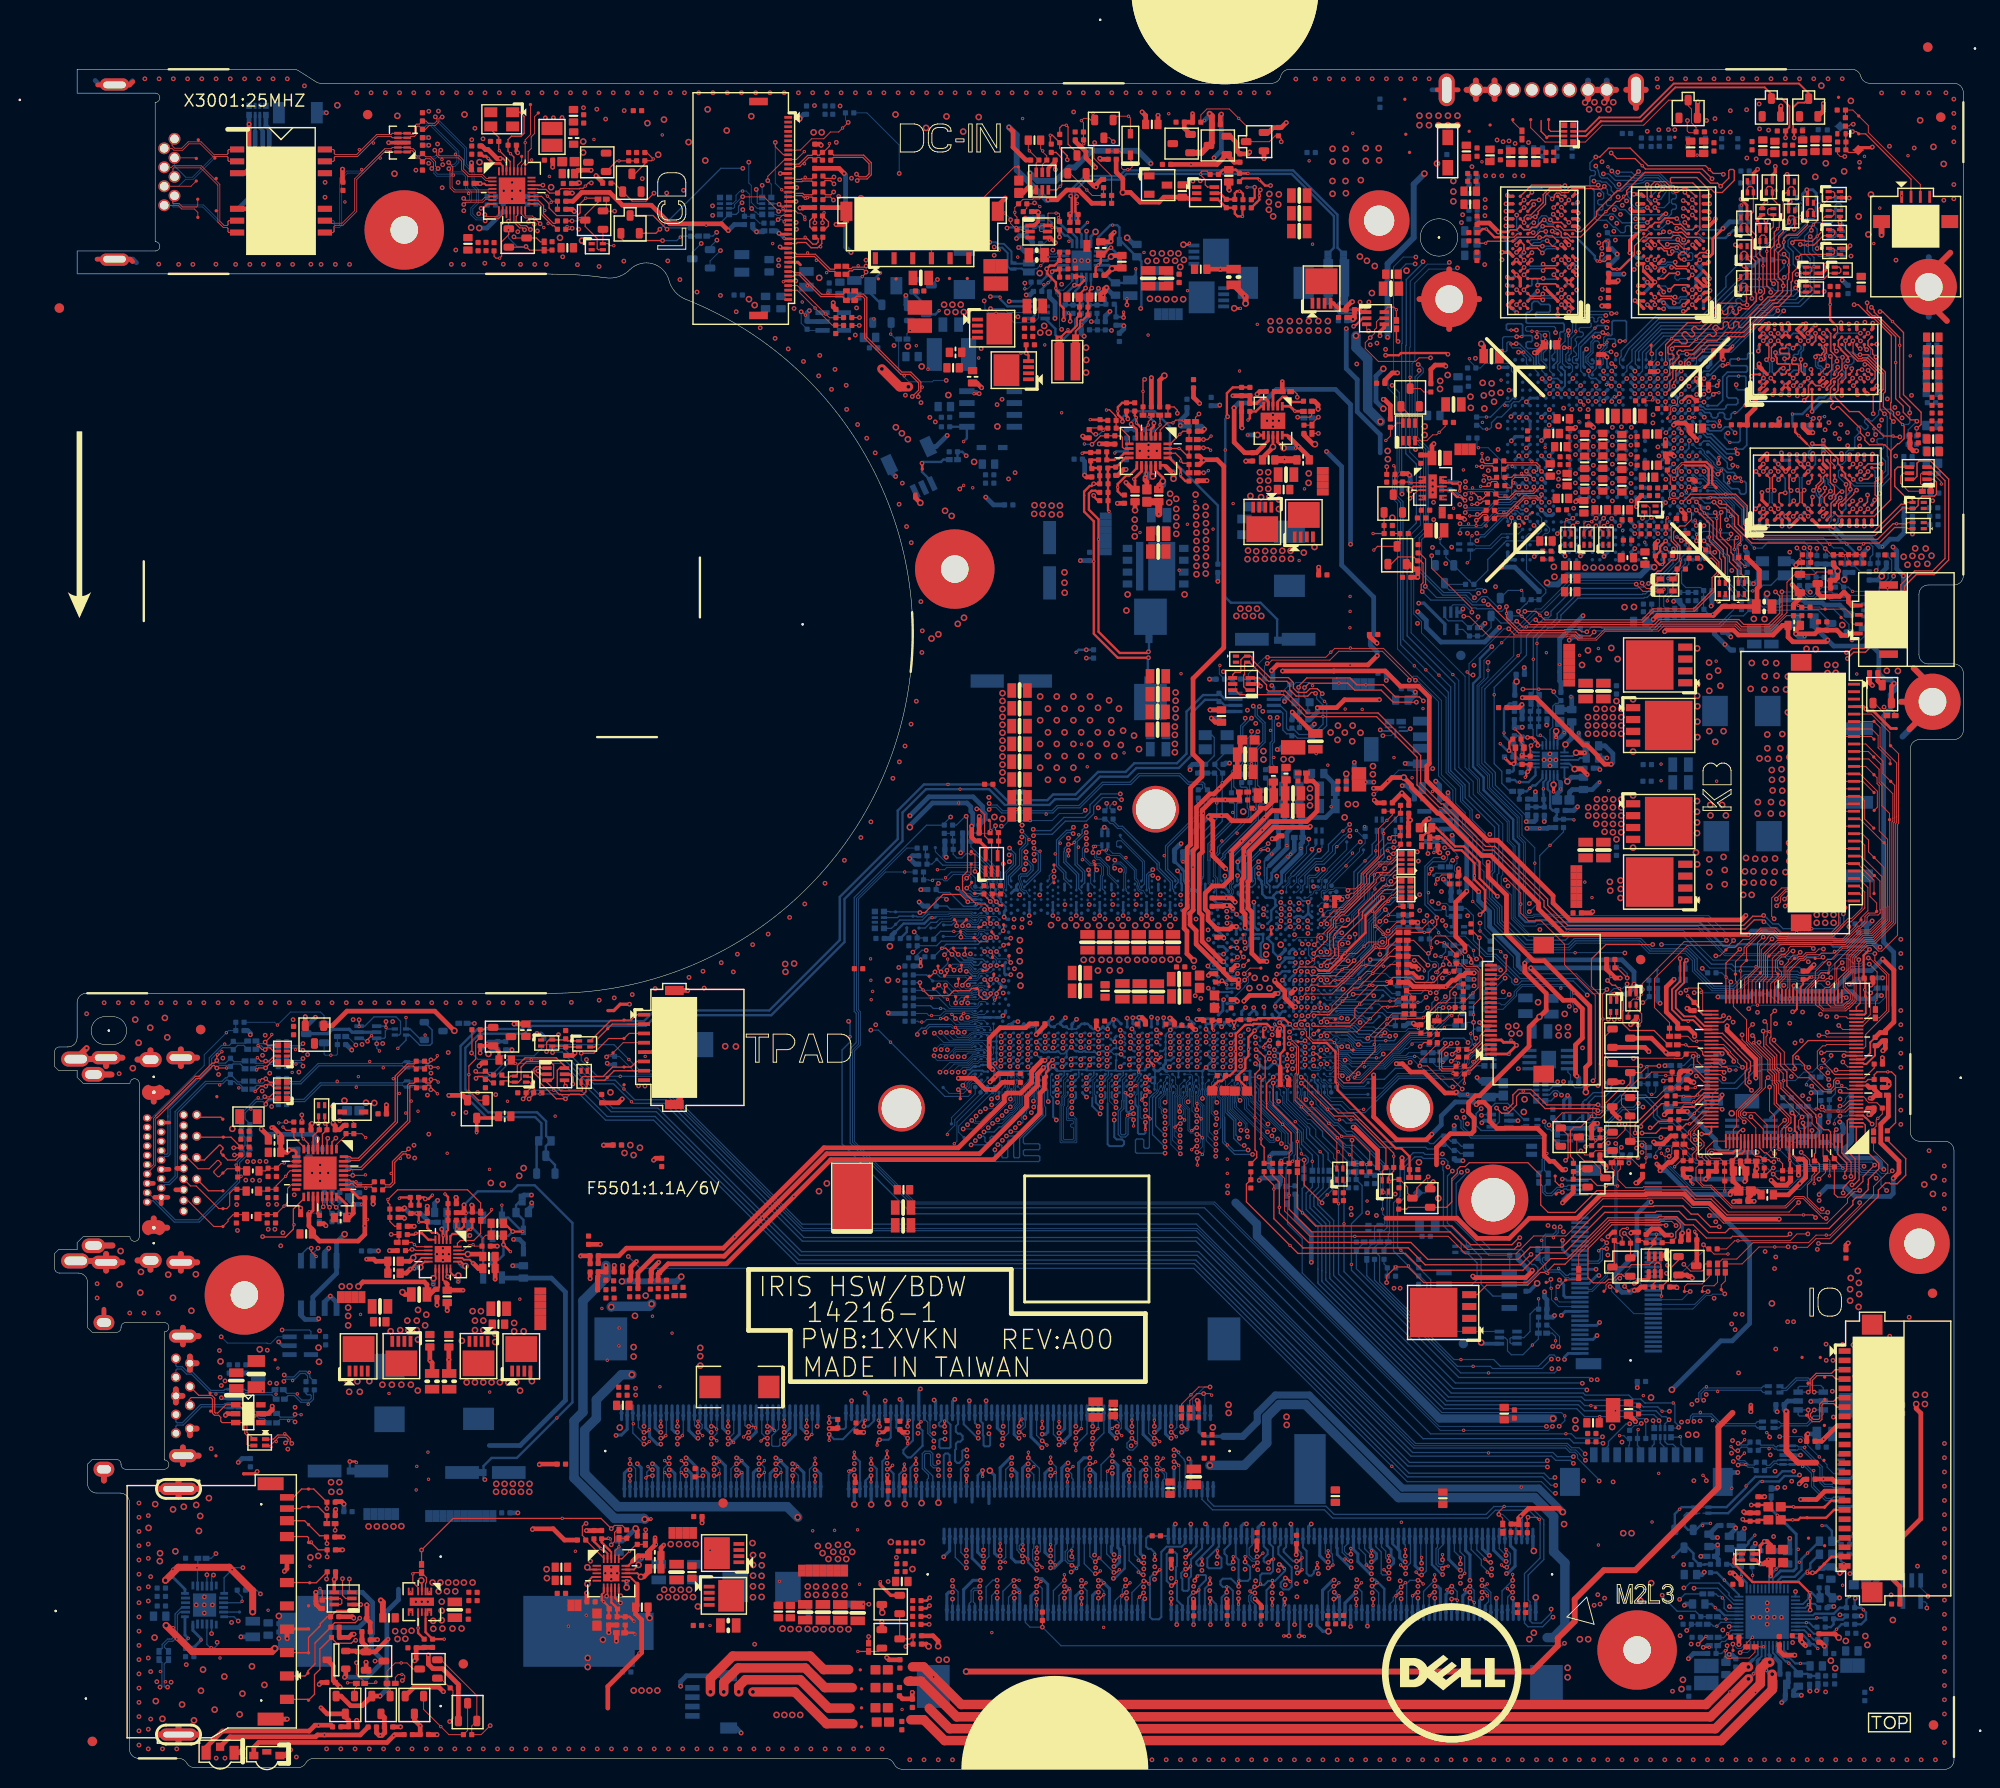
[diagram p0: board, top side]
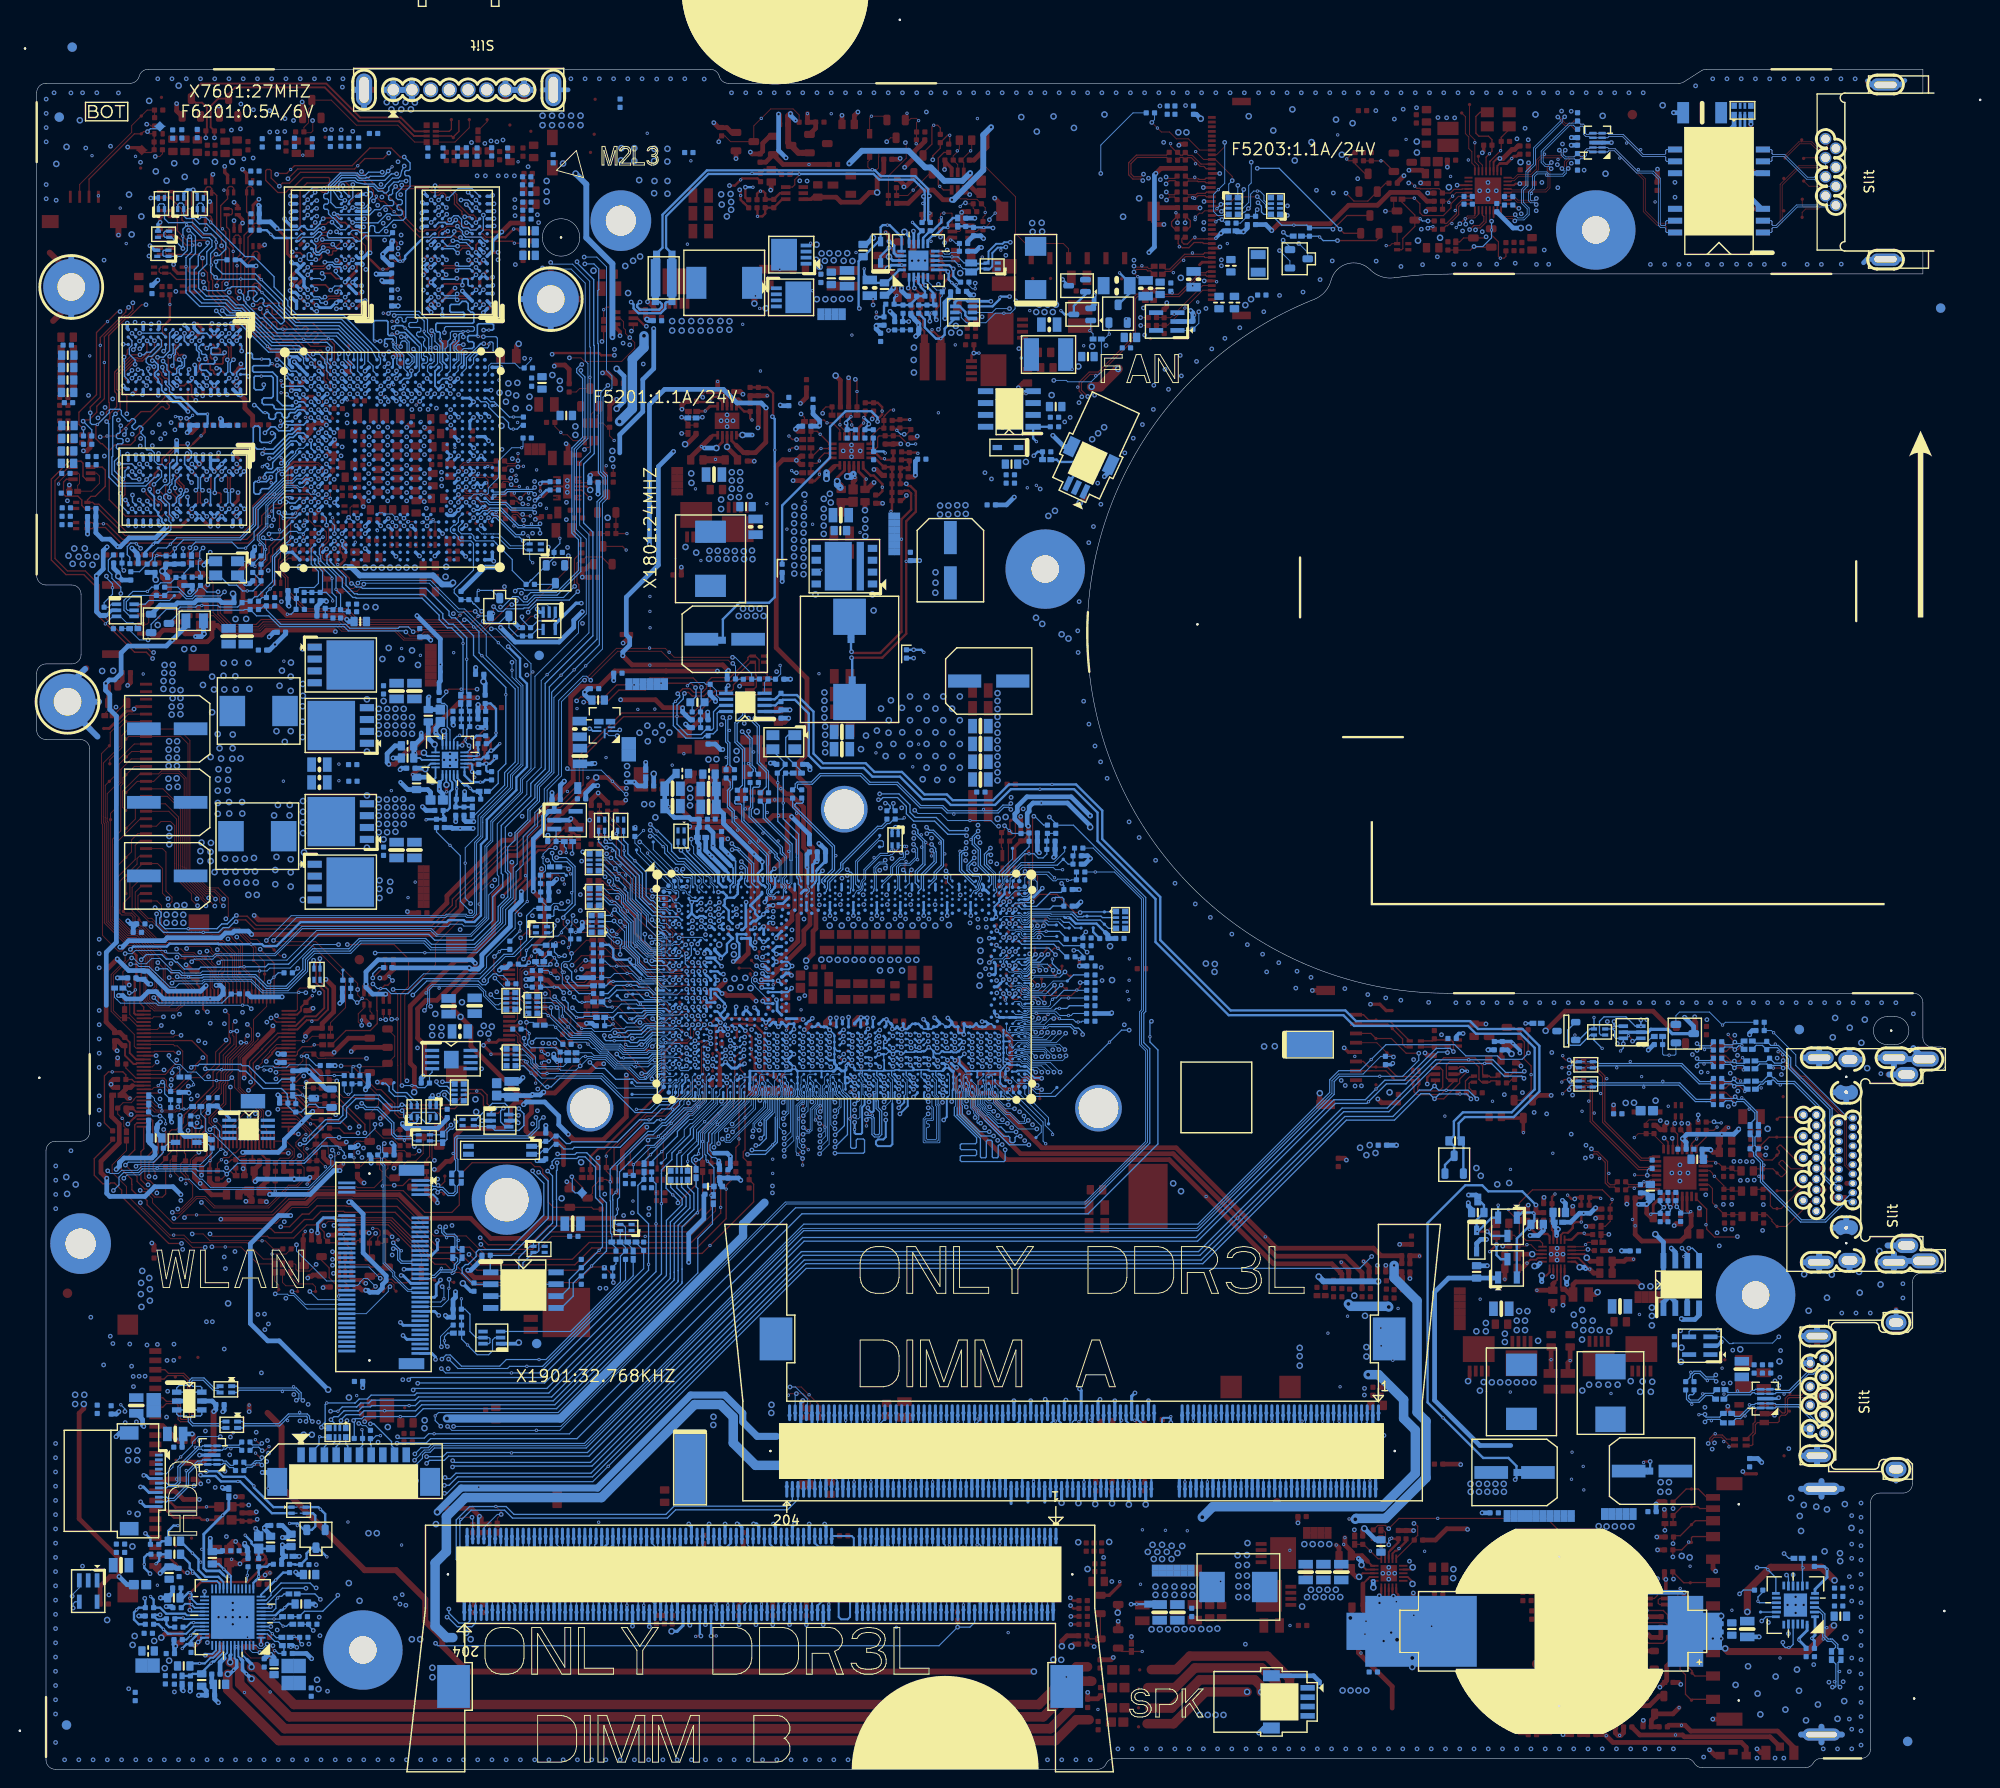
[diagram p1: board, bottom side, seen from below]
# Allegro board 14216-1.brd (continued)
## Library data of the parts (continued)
PR4205 PR4206 R1806 R2419 R2420 R2422 R2423 R5205 R5207 R5215 = R402H16: tolerance: 63.33034.1DL
PR4207 = R603H22: tolerance: 63.24434.15L
PR4208 = R603H22: tolerance: 63.47333.15L
PR4209 PR4403 PR4417 PR4419 PR4428 PR4430 PR4434 PR4438 PR4469 PR4474 PR4534 PR8203 PR8310 PR8311 PR8313 PR8314 R1509 R1715 R1727 R2007 R2412 R2413 R2421 R2426 R2442 R2447 R2711 R2722 R3023 R3607 R5202 R5218 R5219 R5413 R5510 R5607 R6207 R6208 R7605 R7610 R8301 = R402H16: tolerance: 63.10434.1DL
PR4210 PR4418 PR4426 PR4504 PR4506 PR4507 PR4532 PR4621 PR4624 PR4628 PR4819 PR4821 PR4906 PR4907 PR4909 PR5110 PR8207 PR8220 PR8221 PR8257 R404 R1201 R1202 R1205 R1301 R1704 R1706-R1709 R1713 R1728 R1801 R1807-R1812 R1904 R2001 R2002 R2004 R2009 R2016 R2017 R2020 R2022 R2028 R2029 R2101 R2103 R2105 R2112 R2117 R2118 R2401 R2408-R2410 R2416 R2417 R2427 R2428 R2430 R2435 R2440 R2441 R2444 R2606 R2611 R2612 R2701 R2705 R2708 R2712 R2714 R2716 R3005 R3016 R3609-R3611 R3705 R4301 R5201 R5206 R5419 R5605 R5803-R5805 R5807 R6104 R6105 R6202 R6216 R7624 R7652 R7653 = 0R0402-PAD: tolerance: ZZ.R0402.ZZZ
PR4214 = R1206H28: tolerance: 63.33232.11L
PR4217 PR4701 PR4911 PR8210 PR8211 R711 R1102-R1104 R2102 R2108 R2402 R2703 R2901-R2904 R2906 R2907 R2909 R2911 R2923 R3006 R5409 = 0R0603-PAD-U: tolerance: ZZ.R0603.001
PR4401 PR4435 PR4439 PR4473 PR4523 PR4822 PR4903 R2404 R7302 R7508-R7512 R7614 R7618 R7620 = R402H16: tolerance: 64.10025.6DL
PR4402 PR4416 = R3720H40: tolerance: 64.R0105.7FL
PR4404 = R805H24: tolerance: 63.30231.16L
PR4405 = R402H16: tolerance: 63.47434.1DL
PR4406 PR4422 PR4448 PR4452 PR4465 PR4466 PR4468 PR4471 PR4475 PR4476 PR4501 PR4525 PR4530 PR4535 PR4606 PR4706 PR4910 PR8208 R411 R1705 R1710 R1718 R1729 R1813 R2019 R2021 R2027 R2030 R2031 R2123 R2405 R2411 R2424 R2434 R2437 R2438 R2448 R2450 R2451 R2601 R2602 R2605 R2710 R3501 R3704 R3710 R3712 R3802 R5209 R5222 R5418 R5517 R5602 R5806 R5810 R6106 R6204 R6210 R6215 R6217 R6301 R6302 R6501 R6502 R7304 R7305 R7308 R7313 R7519 R7623 R7629 R7630 R7636 R8303 R8312 R8313 R8315 R9602-R9605 = R402H16: tolerance: 63.R0034.1DL
PR4407 PR4429 = R402H16: tolerance: 64.30935.6DL
PR4408 = R805H24: tolerance: 63.10031.16L
PR4410 = R402H16: tolerance: 64.6R805.6DL
PR4411 = R402H16: tolerance: 64.10235.6DL
PR4413 = R402H16: tolerance: 64.16935.6DL
PR4414 = R402H16: tolerance: 63.33534.1DL
PR4420 = R402H16: tolerance: 64.7R505.6DL
PR4421 PR4454 PR4604 R2908 R2910 = R402H14: tolerance: 64.10R05.6DL
PR4423 = R402H16: tolerance: 64.59025.6DL
PR4424 = R402H16: tolerance: 64.84515.6DL
PR4425 PR4529 PR4533 PR4837 PR4912 PR8215 PR8216 = R805H24: tolerance: 64.2R205.16L
PR4427 = R402H16: tolerance: 64.78725.6DL
PR4431 R709 R712 = R402H16: tolerance: 64.47025.6DL
PR4432 PR4436 = R402H16: tolerance: 64.12035.6DL
PR4437 = R402H16: tolerance: 64.16035.6DL
PR4446 PR4904 R2433 R2707 R6214 R7616 = R402H16: tolerance: 64.20025.6DL
PR4464 = R402H16: tolerance: 63.68434.1DL
PR4467 PR8312 R1802 R1901 R7603 R8305 = R402H16: tolerance: 63.10534.1DL
PR4470 PR4472 PR4610 R707 R713 R1725 R2406 R2407 R7306 = R402H16: tolerance: 64.10035.6DL
PR4512 = R402H16: tolerance: 64.68015.6DL
PR4517 = R402H16: tolerance: 64.88725.6DL
PR4524 PR4528 = R603H22: tolerance: 63.1R534.15L
PR4526 = R402H16: tolerance: 64.97615.6DL
PR4527 = R402H16: tolerance: 64.15425.6DL
PR4531 = R402H16: tolerance: 64.11535.6DL
PR4601 R703 R5501 R5513 R5514 = R402H16: tolerance: 64.75R05.6DL
PR4602 = R402H16: tolerance: 64.49905.6DL
PR4603 = R402H16: tolerance: 64.12715.6DL; signal model: R402H16_1K27R2F-L-GP
PR4607 = R402H16: tolerance: 64.12435.6DL
PR4613 = R402H16: tolerance: 64.51015.6DL
PR4614 = R402H16: tolerance: 64.90925.6DL
PR4615 = R402H16: tolerance: 64.38315.6DL
PR4616 PR4618 PR4619 R1908 R1911 R2718-R2720 R3202 R3204 R3205 R3301 R3408-R3411 R5203 R5204 R5216 R5217 R5401-R5408 R5801 R5802 R5808 R5811 = 0R0402-PAD: tolerance: ZZ.R0402.ZZZ; signal model: R402H16_0R2J-2-GP
PR4620 = R402H16: tolerance: 64.54R95.6DL
PR4622 = NTC-402H22-U: tolerance: 69.60037.001
PR4630 R704 = R402H16: tolerance: 64.13005.6DL
PR4702 = R402H16: tolerance: 64.36515.6DL
PR4703 = R402H16: tolerance: 64.44215.6DL
PR4704 = NTC-402H22-U: tolerance: 69.60037.011
PR4705 = R402H16: tolerance: 64.34005.6DL
PR4707 = R402H16: tolerance: 64.10055.6DL
PR4708 = R402H16: tolerance: 64.11025.6DL
PR4817 PR4902 = R402H16: tolerance: 64.13335.6DL
PR4820 PR4905 R2403 = R603H22: tolerance: 64.2R205.55L
PR4823 = R402H16: tolerance: 64.21025.6DL
PR4824 = R402H16: tolerance: 64.47035.6DL
PR4901 = R402H16: tolerance: 64.31625.6DL
PR4908 = R402H16: tolerance: 64.10015.6DL
PR8201 = R402H16: tolerance: 64.49935.6DL
PR8202 = R402H16: tolerance: 64.2R205.6DL
PR8206 = R402H16: tolerance: 64.75015.6DL
PR8209 = R402H16: tolerance: 64.78715.6DL
PR8212 PR8213 R409 R702 R901 = R402H14: tolerance: 64.10005.6DL
PR8222 = R402H16: tolerance: 64.27025.6DL
PR8223 = R603H22: tolerance: 63.2R233.15L
PR8224 = R402H16: tolerance: 64.10725.6DL
PR8256 PR8301 R604 R605 R1702 R1703 R1814 R1815 R1909 R1919 R2006 R2011 R2012 R2014 R2018 R2432 R2449 R2452 R2453 R2502 R2717 R2921 R2922 R3014 R3601 R3603 R3608 R6201 R9601 = R402H16: tolerance: 63.10234.1DL
PR8260 = R402H16: tolerance: 64.13025.6DL
PR8315-PR8317 = R402H14: tolerance: 63.10034.1DL
PT4501 PT4502 = SE361414H178: tolerance: 79.22710.3KL
PT4701 = SE361416H178: tolerance: 77.53371.18L
PT4702 = SE361413H182: tolerance: 79.33612.6CL
PT4803 PT8206-PT8208 = SE361414H178: tolerance: 79.3371V.6CL
PU4201 PU4402 PU4403 = PPAK-8P-2H45: tolerance: 84.07121.037
PU4401 = QFN20G3D5-G2D15H40: tolerance: 74.02224.073
PU4405 PU4406 PU4501 PU4504 PU4505 PU4805 PU4808 PU4902 = PPAK-8P-2H45: tolerance: 84.00412.037
PU4407 = SC70-6H44: tolerance: 74.00199.07P
PU4502 PU4903 = PPAK-8P-2H45: tolerance: 84.00780.037
PU4503 = QFN20-G1D75H32: tolerance: 74.51225.073
PU4601 = QFN20G4030-G275175H40: tolerance: 74.95813.B73
PU4701 = PPAK-8P-G5324H44-COLAY: tolerance: ZZ.00215.037
PU4806 = DFN10G3-G265175H32: tolerance: 74.08237.B73
PU4901 = QFN20-G1D75H32: tolerance: 74.51716.073
PU5101 = SOT-23-5H52: tolerance: 74.01339.B3F
PU8201 = QFN20-G1D75H32: tolerance: 74.08812.073
PU8202 PU8204 PU8206 PU8208 = PPAK-5PH45: tolerance: 84.A14DP.037
PU8203 PU8205 PU8207 PU8209 = PPAK-5PH45: tolerance: 84.SRA12.037
PWR1 = 6916K-Q04M-00L: tolerance: 20.K0465.004
Q2402 Q3004 Q6203 Q8302 = SOT23DGS2D4H48: tolerance: 84.02130.031
Q3602 = SOT23CBE2D4H44: tolerance: 84.02222.V11
Q5402 = SOT-363H44: tolerance: 84.2N702.A3F; signal model: SOT-363H44_2N7002KDW-GP
Q6101 Q6102 Q6104 Q6201 = SOT23CBE2D4H44: tolerance: 84.00144.N11
Q6202 = SOT23DGS2D4H48: tolerance: 84.03404.C31
R401 = R402H16: tolerance: 63.62034.1DL
R402 R406 R1916-R1918 R1920 = R402H16: tolerance: 63.51034.1DL
R403 = R402H16: tolerance: 63.56034.1DL
R407 R7307 = R402H16: tolerance: 64.20005.6DL
R408 = R402H16: tolerance: 64.12105.6DL
R410 R6103 = R402H16: tolerance: 63.47134.1DL
R601 R602 R606 R2003 = R402H16: tolerance: 64.49R95.6DL
R603 R1714 = R402H16: tolerance: 64.82015.6DL
R701 = R402H16: tolerance: 63.43034.1DL; signal model: R402H16_43R2J-GP
R705 R5414-R5417 = R402H16: tolerance: 63.15134.1DL
R801 R3707 R3711 R3715 = R402H16: tolerance: 64.24R95.6DL
R1204 = R402H16: tolerance: 63.20534.1DL
R1206 R1207 R1209 R1210 = R402H16: tolerance: 64.66R55.6DL
R1208 R8314 = R402H16: tolerance: 63.22434.1DL
R1601 R1803 R1906 = R402H16: tolerance: 64.30015.6DL
R1602 = R402H16: tolerance: 64.22R65.6DL
R1720 R1721 R1903 R1913 R2425 R2431 = R402H16: tolerance: 63.33434.1DL
R1804 R1805 R1907 R1912 R3201 R5507 R5511 = R402H16: tolerance: 63.33034.1DL; signal model: R402H16_33R2J-2-GP
R1915 R2504 = R402H16: tolerance: 63.10634.1DL
R2110 = R402H16: tolerance: 64.5R105.6DL
R2114 R5211 R5214 R5229 R5603 R8304 = R805H24: tolerance: 63.R0031.16L
R2429 = R402H16: tolerance: 63.43034.1DL
R2446 = R402H16: tolerance: 64.64925.6DL
R2501 R2912 R2913 R3606 R5502 R5508 R5509 R5512 R5515 R5516 R6209 = R402H16: tolerance: 63.47234.1DL
R2603 = R402H16: tolerance: 64.18725.6DL
R2604 R2607 R4622 = R402H16: tolerance: 64.20015.6DL
R2608 R2609 R7639 = R402H16: tolerance: 64.24925.6DL
R2610 = NTC-603H38: tolerance: 69.60035.041
R2709 R3602 R5410 = R402H16: tolerance: 64.20035.6DL
R3015 = R402H16: tolerance: 63.15334.1DL
R3022 = R402H16: tolerance: 63.20334.1DL
R3032 R7301 = R402H16: tolerance: 64.24915.6DL
R3203 = R402H16: tolerance: 64.62015.6DL
R3701 R3703 R3706 R3709 R3714 R3716 = R402H16: tolerance: 64.18015.6DL
R3702 R3708 R3713 = R402H16: tolerance: 64.2R005.6DL
R5210 R5212 R5213 R6102 R6109 = R402H14: tolerance: 63.10134.1DL
R5411 = R402H16: tolerance: 64.15035.6DL
R5505 = R402H16: tolerance: 64.12025.6DL
R6107 R6108 = R402H16: tolerance: 63.33134.1DL
R6206 = R402H16: tolerance: 63.51334.1DL
R6211 = R603H22: tolerance: 63.10133.15L
R7501 R7503 = R402H16: tolerance: 64.60R45.6DL
R7505 = R402H16: tolerance: 64.40R25.6DL
R7506 = R402H16: tolerance: 64.51R15.6DL
R7507 = R402H16: tolerance: 64.42R25.6DL
R7604 = R402H16: tolerance: 63.13234.1DL
R7607 = R402H16: tolerance: 64.40225.6DL
R7608 R7611 R7640 R7650 = R402H16: tolerance: 64.49915.6DL
R7619 R7647 = R402H16: tolerance: 64.34825.6DL
R7638 R7642 = R402H16: tolerance: 64.30125.6DL
R7646 R7654 R7655 = R402H16: tolerance: 64.45325.6DL
R7806 R7807 R7903 R7904 = R402H16: tolerance: 64.13315.6DL
R7808 R7809 R7912 R7913 R8001 R8002 R8101 R8102 = R402H16: tolerance: 64.24305.6DL
R7810 R7914 = R402H16: tolerance: 64.16205.6DL
RJ45 = C100PF-10809-L: tolerance: 022.10001.0C41
RN401 = ARES8-CN24H22: tolerance: 66.51036.A8L
RN1501 RN1811 RN2008 RN2602 RN2901 RN5401 RN5501 RN6204 RN7603-RN7605 = ARES2H16: tolerance: 66.22236.04L
RN1503 RN1701 RN1703 RN1803 RN1804 RN1810 RN2006 RN2007 RN3001 RN6201 RN7401-RN7404 RN7602 = ARES2H18: tolerance: 66.10336.04L
RN1505 RN1601 RN1801 RN1809 RN1902 RN2002 RN2011 RN2012 = ARES8-CN24-MUH20: tolerance: 66.10336.08L
RN1702 RN9601 = SMD-ARES4H20: tolerance: 66.R0036.04L
RN1806 RN6501 = ARES8-CN24H22: tolerance: 66.R0036.A8L
RN1807 = ARES8-CN24-UH20: tolerance: 66.22236.A8L
RN1901 = SMD-ARES4H20: tolerance: 66.20336.04L
RN2401 RN2501 RN4401 RN7601 = SMD-ARES4H18: tolerance: 66.47236.04L
RN2701 = 0R4P2R-PAD: tolerance: ZZ.0R04P.ZZZ
RN3101 = ARES8-CN24H22: tolerance: 66.75036.08L
RN4301 RN5201 = ARES8-CN24H20: tolerance: 66.10136.A8L
RN5203 = ARES8-CN24H20: tolerance: 66.10436.A8L
RN5402 RN5403 = ARES8-CN24H20: tolerance: 66.47136.08L
RN5404 RN5405 = 0R4P2R-PAD: tolerance: ZZ.0R04P.ZZZ; signal model: SMD-ARES4H20_SRN0J-6-GP
RN6202 RN6203 = SMD-ARES4H18: tolerance: 66.33036.04L
RN7501-RN7522 = SMD-ARES4H18: tolerance: 66.10136.04L
RTC1 = 060003HA002M213ZL-U2: tolerance: 62.70014.001
SPI25 = SOIC8-1H86: tolerance: 72.25Q64.K01
SPK1 = 50224-0040N-001: tolerance: 20.F1639.004
SPR1 = SPR7345H154: tolerance: 34.49U24.001
SPR2 = SPR5230H134: tolerance: 34.45T31.001
SPR3 = SPR7837H229: tolerance: 34.43E24.001
TC1201 = CT7343H83: tolerance: 79.33719.20L
TC3501 = C1206H71: tolerance: 78.10710.52L
THM26 = MSOP8-1H44: tolerance: 74.07718.0B9
TP402 TP403 TP501 TP503 TP601-TP608 TP619 TP620 TP701-TP705 TP801 TP1501 TP1601 TP1602 TP1702-TP1707 TP1801-TP1803 TP1901 TP1902 TP2002 TP2003 TP2101-TP2109 TP2201-TP2208 TP2702 TP3001-TP3003 TP3201 TP5801-TP5804 TP7503 TP7504 TP7601-TP7606 TP9601 TP9602 TP9611-TP9624 TP9626-TP9654 = TPAD14-OP: tolerance: ZZ.PAD14.001
TPAD1 = 50505-0084N-002: tolerance: 20.K0667.008
TR3404-TR3406 = L125100-4P-1H28: tolerance: 68.01012.20B
U701 = SC70-5H44: tolerance: 73.01G07.0HG
U2101 = DFN9J2015H32: tolerance: 74.59147.093
U3201 = QFN24-G2D5H40-U: tolerance: 71.05170.003
U3504 U3505 = SOT-23-5H58: tolerance: 074.22802.0A9F
U3601 U8301 = SON14J3020-G2610H32: tolerance: 074.22966.0093
U3801 = MSOP8-1H44: tolerance: 074.06288.0079
U5201 = SOT-23-5H51: tolerance: 74.09724.09F
U5502 = QFN32-G3D6H40: tolerance: 071.02168.0003
U5504 = SOIC8H69: tolerance: 72.24128.J01
U5601 = MSOP8-1G189157H43: tolerance: 74.02001.079
U7301 = SC70-5-1H44: tolerance: 73.01G08.EHG
USB1 = SKT-USB13-160166-2: tolerance: 22.10339.S21
VRAM1-VRAM8 = BGA96D0914H48: tolerance: 72.41K26.00U
WLAN1 = 2199230-7: tolerance: 62.10043.K51
X1801 = OSC-3225-4P-4H36: tolerance: 82.30004.841
X1901 = SMD49-6914-0403H56: tolerance: 82.30001.841
X3001 = OSC-3225-4P-4H36: tolerance: 82.30020.G71
X7601 = OSC-3225-4P-4H30: tolerance: 82.30034.641
XF3101 XF3102 = XFORM12A127097H91: tolerance: 68.68167.30D; signal model: XFORM12A127097H91_XFORM-12P-48-GP

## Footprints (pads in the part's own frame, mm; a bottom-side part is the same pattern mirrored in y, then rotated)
0R4P2R-PAD
  custom 0.089x0.089 smd: 1(-0.325,-0.599) 2(0.325,-0.599) 3(0.325,0.599) 4(-0.325,0.599)
0R0402-PAD
  custom 0.14x0.14 smd: 1(0,0.445) 2(0,-0.445)
0R0603-PAD-U
  custom 0.254x0.254 smd: 1(0,0.66) 2(0,-0.66)
0R0805-PAD-U
  rect 1.549x1.333 smd: 1(0,0.838) 2(0,-0.838)
132F12-010000-A2-R
  rect 0.305x0.838 smd: 1(-2.75,3.175) 2(-2.25,3.175) 3(-1.75,3.175) 4(-1.25,3.175) 5(-0.75,3.175) 6(-0.25,3.175) 7(0.25,3.175) 8(0.75,3.175) 9(1.25,3.175) 10(1.75,3.175) 11(2.25,3.175) 12(2.75,3.175)
  rect 1.448x2.007 smd: 13(-5.125,0) 14(5.125,0)
3703K-Q03N-11L
  rect 0.61x1.549 smd: 1(-1,3.775) 2(0,3.775) 3(1,3.775)
  rect 1.194x2.007 smd: 4(-2.3,0) 5(2.3,0)
6916K-Q04M-00L
  rect 0.305x1.295 smd: 1(-1.5,2.65) 2(-0.5,2.65) 3(0.5,2.65) 4(1.5,2.65)
  rect 1.803x1.397 smd: 5(-3.65,0) 6(3.65,0)
50224-0040N-001
  rect 0.61x1.549 smd: 1(-1.5,3.875) 2(-0.5,3.875) 3(0.5,3.875) 4(1.5,3.875)
  rect 1.194x1.803 smd: 5(-2.797,0) 6(2.797,0)
50458-00601-W01
  rect 0.559x1.295 smd: 1(5,5.025) 2(3,5.025) 3(1,5.025) 4(-1,5.025) 5(-3,5.025) 6(-5,5.025)
  rect 1.295x2.057 smd: 7(8.1,0) 8(-8.1,0)
50505-0084N-002
  rect 0.406x1.295 smd: 1(3.5,3.25) 2(2.5,3.25) 3(1.5,3.25) 4(0.5,3.25) 5(-0.5,3.25) 6(-1.5,3.25) 7(-2.5,3.25) 8(-3.5,3.25)
  rect 0.991x2.007 smd: 9(6.1,0) 10(-6.1,0)
51519-02001-W03
  rect 0.305x1.295 smd: 1(-4.75,5.65) 2(-4.25,5.65) 3(-3.75,5.65) 4(-3.25,5.65) 5(-2.75,5.65) 6(-2.25,5.65) 7(-1.75,5.65) 8(-1.25,5.65) 9(-0.75,5.65) 10(-0.25,5.65) 11(0.25,5.65) 12(0.75,5.65) 13(1.25,5.65) 14(1.75,5.65) 15(2.25,5.65) 16(2.75,5.65) 17(3.25,5.65) 18(3.75,5.65) 19(4.25,5.65) 20(4.75,5.65)
  rect 1.803x2.21 smd: 21(-6.9,0) 22(6.9,0)
51540-04001-W01
  rect 0.305x0.838 smd: 1(-9.75,3.175) 2(-9.25,3.175) 3(-8.75,3.175) 4(-8.25,3.175) 5(-7.75,3.175) 6(-7.25,3.175) 7(-6.75,3.175) 8(-6.25,3.175) 9(-5.75,3.175) 10(-5.25,3.175) 11(-4.75,3.175) 12(-4.25,3.175) 13(-3.75,3.175) 14(-3.25,3.175) 15(-2.75,3.175) 16(-2.25,3.175) 17(-1.75,3.175) 18(-1.25,3.175) 19(-0.75,3.175) 20(-0.25,3.175) 21(0.25,3.175) 22(0.75,3.175) 23(1.25,3.175) 24(1.75,3.175) 25(2.25,3.175) 26(2.75,3.175) 27(3.25,3.175) 28(3.75,3.175) 29(4.25,3.175) 30(4.75,3.175) 31(5.25,3.175) 32(5.75,3.175) 33(6.25,3.175) 34(6.75,3.175) 35(7.25,3.175) 36(7.75,3.175) 37(8.25,3.175) 38(8.75,3.175) 39(9.25,3.175) 40(9.75,3.175)
  rect 0.813x2.007 smd: 41(-11.45,0) 42(11.45,0)
51575-00401-W01
  rect 0.406x0.838 smd: 1(-1.5,3.175) 2(-0.5,3.175) 3(0.5,3.175) 4(1.5,3.175)
  rect 0.813x2.007 smd: 5(-3.7,0) 6(3.7,0)
060003HA002M213ZL-U2
  round 0.254 hole 1.219 unplated: (0,-8)
  round 0.254 hole 1.321 unplated: (0,8)
  custom 1.454x1.454 smd: 1(14.5,0)
  custom 1.899x1.899 smd: 2(-15.8,0)
80001-1921
  round 0.254 hole 1.118 unplated: (-33.4,0)
  round 0.254 hole 1.6 unplated: (33.4,0)
  custom 0.114x0.114 smd: 1(31.65,4.1) 2(31.35,-4.1) 3(31.05,4.1) 4(30.751,-4.1) 5(30.45,4.1) 6(30.15,-4.1) 7(29.85,4.1) 8(29.55,-4.1) 9(29.251,4.1) 10(28.95,-4.1) 11(28.65,4.1) 12(28.35,-4.1) 13(28.051,4.1) 14(27.751,-4.1) 15(27.45,4.1) 16(27.15,-4.1) 17(26.851,4.1) 18(26.551,-4.1) 19(26.25,4.1) 20(25.95,-4.1) 21(25.65,4.1) 22(25.35,-4.1) 23(25.051,4.1) 24(24.75,-4.1) 25(24.45,4.1) 26(24.15,-4.1) 27(23.851,4.1) 28(23.55,-4.1) 29(23.25,4.1) 30(22.95,-4.1) 31(22.651,4.1) 32(22.351,-4.1) 33(22.05,4.1) 34(21.75,-4.1) 35(21.451,4.1) 36(21.151,-4.1) 37(20.85,4.1) 38(20.55,-4.1) 39(20.25,4.1) 40(19.95,-4.1) 41(19.65,4.1) 42(19.35,-4.1) 43(19.049,4.1) 44(18.749,-4.1) 45(18.45,4.1) 46(18.15,-4.1) 47(17.85,4.1) 48(17.549,-4.1) 49(17.25,4.1) 50(16.95,-4.1) 51(16.65,4.1) 52(16.349,-4.1) 53(16.049,4.1) 54(15.75,-4.1) 55(15.45,4.1) 56(15.15,-4.1) 57(14.849,4.1) 58(14.549,-4.1) 59(14.25,4.1) 60(13.95,-4.1) 61(13.649,4.1) 62(13.349,-4.1) 63(13.05,4.1) 64(12.75,-4.1) 65(12.45,4.1) 66(12.149,-4.1) 67(11.85,4.1) 68(11.55,-4.1) 69(11.25,4.1) 70(10.95,-4.1) 71(10.649,4.1) 72(10.349,-4.1) 73(7.65,4.1) 74(7.35,-4.1) 75(7.049,4.1) 76(6.749,-4.1) 77(6.45,4.1) 78(6.15,-4.1) 79(5.85,4.1) 80(5.549,-4.1) 81(5.25,4.1) 82(4.95,-4.1) 83(4.65,4.1) 84(4.349,-4.1) 85(4.05,4.1) 86(3.75,-4.1) 87(3.45,4.1) 88(3.15,-4.1) 89(2.849,4.1) 90(2.549,-4.1) 91(2.25,4.1) 92(1.95,-4.1) 93(1.649,4.1) 94(1.349,-4.1) 95(1.05,4.1) 96(0.75,-4.1) 97(0.45,4.1) 98(0.149,-4.1) 99(-0.15,4.1) 100(-0.45,-4.1) 101(-0.75,4.1) 102(-1.051,-4.1) 103(-1.351,4.1) 104(-1.65,-4.1) 105(-1.95,4.1) 106(-2.25,-4.1) 107(-2.551,4.1) 108(-2.851,-4.1) 109(-3.15,4.1) 110(-3.45,-4.1) 111(-3.751,4.1) 112(-4.051,-4.1) 113(-4.35,4.1) 114(-4.65,-4.1) 115(-4.95,4.1) 116(-5.251,-4.1) 117(-5.55,4.1) 118(-5.85,-4.1) 119(-6.15,4.1) 120(-6.451,-4.1) 121(-6.751,4.1) 122(-7.051,-4.1) 123(-7.35,4.1) 124(-7.65,-4.1) 125(-7.951,4.1) 126(-8.251,-4.1) 127(-8.55,4.1) 128(-8.85,-4.1) 129(-9.15,4.1) 130(-9.451,-4.1) 131(-9.75,4.1) 132(-10.05,-4.1) 133(-10.35,4.1) 134(-10.651,-4.1) 135(-10.95,4.1) 136(-11.25,-4.1) 137(-11.55,4.1) 138(-11.85,-4.1) 139(-12.151,4.1) 140(-12.451,-4.1) 141(-12.75,4.1) 142(-13.05,-4.1) 143(-13.351,4.1) 144(-13.651,-4.1) 145(-13.95,4.1) 146(-14.25,-4.1) 147(-14.55,4.1) 148(-14.851,-4.1) 149(-15.15,4.1) 150(-15.45,-4.1) 151(-15.75,4.1) 152(-16.051,-4.1) 153(-16.35,4.1) 154(-16.65,-4.1) 155(-16.95,4.1) 156(-17.25,-4.1) 157(-17.551,4.1) 158(-17.851,-4.1) 159(-18.15,4.1) 160(-18.45,-4.1) 161(-18.751,4.1) 162(-19.051,-4.1) 163(-19.35,4.1) 164(-19.65,-4.1) 165(-19.95,4.1) 166(-20.251,-4.1) 167(-20.55,4.1) 168(-20.85,-4.1) 169(-21.15,4.1) 170(-21.451,-4.1) 171(-21.751,4.1) 172(-22.051,-4.1) 173(-22.35,4.1) 174(-22.65,-4.1) 175(-22.951,4.1) 176(-23.251,-4.1) 177(-23.55,4.1) 178(-23.85,-4.1) 179(-24.151,4.1) 180(-24.451,-4.1) 181(-24.75,4.1) 182(-25.05,-4.1) 183(-25.35,4.1) 184(-25.651,-4.1) 185(-25.95,4.1) 186(-26.25,-4.1) 187(-26.55,4.1) 188(-26.851,-4.1) 189(-27.151,4.1) 190(-27.451,-4.1) 191(-27.75,4.1) 192(-28.05,-4.1) 193(-28.351,4.1) 194(-28.651,-4.1) 195(-28.95,4.1) 196(-29.25,-4.1) 197(-29.55,4.1) 198(-29.851,-4.1) 199(-30.15,4.1) 200(-30.45,-4.1) 201(-30.75,4.1) 202(-31.05,-4.1) 203(-31.349,4.1) 204(-31.649,-4.1)
  rect 3.505x4.597 smd: 205(32.8,12) 206(-32.8,12)
196547-24031-3
  rect 0.61x1.295 smd: 1(11.5,2.95) 2(10.5,2.95) 3(9.5,2.95) 4(8.5,2.95) 5(7.5,2.95) 6(6.5,2.95) 7(5.5,2.95) 8(4.5,2.95) 9(3.5,2.95) 10(2.5,2.95) 11(1.5,2.95) 12(0.5,2.95) 13(-0.5,2.95) 14(-1.5,2.95) 15(-2.5,2.95) 16(-3.5,2.95) 17(-4.5,2.95) 18(-5.5,2.95) 19(-6.5,2.95) 20(-7.5,2.95) 21(-8.5,2.95) 22(-9.5,2.95) 23(-10.5,2.95) 24(-11.5,2.95)
  rect 2.159x2.21 smd: 25(14.325,0) 26(-14.325,0)
200277MR008G121ZR-U
  round 1.626 hole 1.219: 1(7,0) 2(5,0) 3(3,0) 4(1,0) 5(-1,0) 6(-3,0) 7(-5,0) 8(-7,0)
  oval 1.727x3.505 hole 1.016x2.794: 9(10.125,0) 10(-10.125,0)
2199230-7
  round 0.254 hole 1.6 unplated: (-10,0)
  round 0.254 hole 1.118 unplated: (10,0)
  rect 0.305x1.854 smd: 1(9.25,-5.423) 2(9,2.423) 3(8.75,-5.423) 4(8.5,2.423) 5(8.25,-5.423) 6(8,2.423) 7(7.75,-5.423) 16(5.5,2.423) 17(5.25,-5.423) 18(5,2.423) 19(4.75,-5.423) 20(4.5,2.423) 21(4.25,-5.423) 22(4,2.423) 23(3.75,-5.423) 24(3.5,2.423) 25(3.25,-5.423) 26(3,2.423) 27(2.75,-5.423) 28(2.5,2.423) 29(2.25,-5.423) 30(2,2.423) 31(1.75,-5.423) 32(1.5,2.423) 33(1.25,-5.423) 34(1,2.423) 35(0.75,-5.423) 36(0.5,2.423) 37(0.25,-5.423) 38(0,2.423) 39(-0.25,-5.423) 40(-0.5,2.423) 41(-0.75,-5.423) 42(-1,2.423) 43(-1.25,-5.423) 44(-1.5,2.423) 45(-1.75,-5.423) 46(-2,2.423) 47(-2.25,-5.423) 48(-2.5,2.423) 49(-2.75,-5.423) 50(-3,2.423) 51(-3.25,-5.423) 52(-3.5,2.423) 53(-3.75,-5.423) 54(-4,2.423) 55(-4.25,-5.423) 56(-4.5,2.423) 57(-4.75,-5.423) 58(-5,2.423) 59(-5.25,-5.423) 60(-5.5,2.423) 61(-5.75,-5.423) 62(-6,2.423) 63(-6.25,-5.423) 64(-6.5,2.423) 65(-6.75,-5.423) 66(-7,2.423) 67(-7.25,-5.423) 68(-7.5,2.423) 69(-7.75,-5.423) 70(-8,2.423) 71(-8.25,-5.423) 72(-8.5,2.423) 73(-8.75,-5.423) 74(-9,2.423) 75(-9.25,-5.423)
  rect 1.194x2.743 smd: 76(10.35,-4.5) 77(-10.35,-4.5)
AFTE14P-75
  round 0.356 smd: 1(0,0)
ARES2H16
  rect 0.356x0.66 smd: 1(-0.325,-0.599) 2(0.325,-0.599) 3(0.325,0.599) 4(-0.325,0.599)
ARES2H18
  rect 0.356x0.66 smd: 1(-0.325,-0.599) 2(0.325,-0.599) 3(0.325,0.599) 4(-0.325,0.599)
ARES8-CN24-MUH20
  rect 0.61x0.66 smd: 1(-0.9,-0.486) 4(0.9,-0.486) 5(0.9,0.486) 8(-0.9,0.486)
  rect 0.305x0.66 smd: 2(-0.25,-0.486) 3(0.25,-0.486) 6(0.25,0.486) 7(-0.25,0.486)
ARES8-CN24-UH20
  rect 0.61x0.66 smd: 1(-0.9,-0.486) 4(0.9,-0.486) 5(0.9,0.486) 8(-0.9,0.486)
  rect 0.305x0.66 smd: 2(-0.25,-0.486) 3(0.25,-0.486) 6(0.25,0.486) 7(-0.25,0.486)
ARES8-CN24H20
  rect 0.61x0.66 smd: 1(-0.9,-0.486) 4(0.9,-0.486) 5(0.9,0.486) 8(-0.9,0.486)
  rect 0.305x0.66 smd: 2(-0.25,-0.486) 3(0.25,-0.486) 6(0.25,0.486) 7(-0.25,0.486)
ARES8-CN24H22
  rect 0.61x0.66 smd: 1(-0.9,-0.486) 4(0.9,-0.486) 5(0.9,0.486) 8(-0.9,0.486)
  rect 0.305x0.66 smd: 2(-0.25,-0.486) 3(0.25,-0.486) 6(0.25,0.486) 7(-0.25,0.486)
AS0A621-J4SB-7H
  round 0.254 hole 1.6 unplated: (-33.4,0)
  round 0.254 hole 1.118 unplated: (33.4,0)
  custom 0.114x0.114 smd: 1(-31.65,-4.1) 2(-31.35,4.1) 3(-31.05,-4.1) 4(-30.75,4.1) 5(-30.45,-4.1) 6(-30.15,4.1) 7(-29.85,-4.1) 8(-29.55,4.1) 9(-29.25,-4.1) 10(-28.95,4.1) 11(-28.65,-4.1) 12(-28.35,4.1) 13(-28.05,-4.1) 14(-27.75,4.1) 15(-27.45,-4.1) 16(-27.15,4.1) 17(-26.85,-4.1) 18(-26.55,4.1) 19(-26.25,-4.1) 20(-25.95,4.1) 21(-25.65,-4.1) 22(-25.35,4.1) 23(-25.05,-4.1) 24(-24.75,4.1) 25(-24.45,-4.1) 26(-24.15,4.1) 27(-23.85,-4.1) 28(-23.55,4.1) 29(-23.25,-4.1) 30(-22.95,4.1) 31(-22.65,-4.1) 32(-22.35,4.1) 33(-22.05,-4.1) 34(-21.75,4.1) 35(-21.45,-4.1) 36(-21.15,4.1) 37(-20.85,-4.1) 38(-20.55,4.1) 39(-20.25,-4.1) 40(-19.95,4.1) 41(-19.65,-4.1) 42(-19.35,4.1) 43(-19.05,-4.1) 44(-18.75,4.1) 45(-18.45,-4.1) 46(-18.15,4.1) 47(-17.85,-4.1) 48(-17.55,4.1) 49(-17.25,-4.1) 50(-16.95,4.1) 51(-16.65,-4.1) 52(-16.35,4.1) 53(-16.05,-4.1) 54(-15.75,4.1) 55(-15.45,-4.1) 56(-15.15,4.1) 57(-14.85,-4.1) 58(-14.55,4.1) 59(-14.25,-4.1) 60(-13.95,4.1) 61(-13.65,-4.1) 62(-13.35,4.1) 63(-13.05,-4.1) 64(-12.75,4.1) 65(-12.45,-4.1) 66(-12.15,4.1) 67(-11.85,-4.1) 68(-11.55,4.1) 69(-11.25,-4.1) 70(-10.95,4.1) 71(-10.65,-4.1) 72(-10.35,4.1) 73(-7.65,-4.1) 74(-7.35,4.1) 75(-7.05,-4.1) 76(-6.75,4.1) 77(-6.45,-4.1) 78(-6.15,4.1) 79(-5.85,-4.1) 80(-5.55,4.1) 81(-5.25,-4.1) 82(-4.95,4.1) 83(-4.65,-4.1) 84(-4.35,4.1) 85(-4.05,-4.1) 86(-3.75,4.1) 87(-3.45,-4.1) 88(-3.15,4.1) 89(-2.85,-4.1) 90(-2.55,4.1) 91(-2.25,-4.1) 92(-1.95,4.1) 93(-1.65,-4.1) 94(-1.35,4.1) 95(-1.05,-4.1) 96(-0.75,4.1) 97(-0.45,-4.1) 98(-0.15,4.1) 99(0.15,-4.1) 100(0.45,4.1) 101(0.75,-4.1) 102(1.05,4.1) 103(1.35,-4.1) 104(1.65,4.1) 105(1.95,-4.1) 106(2.25,4.1) 107(2.55,-4.1) 108(2.85,4.1) 109(3.15,-4.1) 110(3.45,4.1) 111(3.75,-4.1) 112(4.05,4.1) 113(4.35,-4.1) 114(4.65,4.1) 115(4.95,-4.1) 116(5.25,4.1) 117(5.55,-4.1) 118(5.85,4.1) 119(6.15,-4.1) 120(6.45,4.1) 121(6.75,-4.1) 122(7.05,4.1) 123(7.35,-4.1) 124(7.65,4.1) 125(7.95,-4.1) 126(8.25,4.1) 127(8.55,-4.1) 128(8.85,4.1) 129(9.15,-4.1) 130(9.45,4.1) 131(9.75,-4.1) 132(10.05,4.1) 133(10.35,-4.1) 134(10.65,4.1) 135(10.95,-4.1) 136(11.25,4.1) 137(11.55,-4.1) 138(11.85,4.1) 139(12.15,-4.1) 140(12.45,4.1) 141(12.75,-4.1) 142(13.05,4.1) 143(13.35,-4.1) 144(13.65,4.1) 145(13.95,-4.1) 146(14.25,4.1) 147(14.55,-4.1) 148(14.85,4.1) 149(15.15,-4.1) 150(15.45,4.1) 151(15.75,-4.1) 152(16.05,4.1) 153(16.35,-4.1) 154(16.65,4.1) 155(16.95,-4.1) 156(17.25,4.1) 157(17.55,-4.1) 158(17.85,4.1) 159(18.15,-4.1) 160(18.45,4.1) 161(18.75,-4.1) 162(19.05,4.1) 163(19.35,-4.1) 164(19.65,4.1) 165(19.95,-4.1) 166(20.25,4.1) 167(20.55,-4.1) 168(20.85,4.1) 169(21.15,-4.1) 170(21.45,4.1) 171(21.75,-4.1) 172(22.05,4.1) 173(22.35,-4.1) 174(22.65,4.1) 175(22.95,-4.1) 176(23.25,4.1) 177(23.55,-4.1) 178(23.85,4.1) 179(24.15,-4.1) 180(24.45,4.1) 181(24.75,-4.1) 182(25.05,4.1) 183(25.35,-4.1) 184(25.65,4.1) 185(25.95,-4.1) 186(26.25,4.1) 187(26.55,-4.1) 188(26.85,4.1) 189(27.15,-4.1) 190(27.45,4.1) 191(27.75,-4.1) 192(28.05,4.1) 193(28.35,-4.1) 194(28.65,4.1) 195(28.95,-4.1) 196(29.25,4.1) 197(29.55,-4.1) 198(29.85,4.1) 199(30.15,-4.1) 200(30.45,4.1) 201(30.75,-4.1) 202(31.05,4.1) 203(31.35,-4.1) 204(31.65,4.1)
  rect 3.505x4.597 smd: 205(-32.8,12) 206(32.8,12)
BGA96D0914H48
  round 0.356 smd: A1(-3.2,6) A2(-2.4,6) A3(-1.6,6) A7(1.6,6) A8(2.4,6) A9(3.2,6) B1(-3.2,5.2) B2(-2.4,5.2) B3(-1.6,5.2) B7(1.6,5.2) B8(2.4,5.2) B9(3.2,5.2) C1(-3.2,4.4) C2(-2.4,4.4) C3(-1.6,4.4) C7(1.6,4.4) C8(2.4,4.4) C9(3.2,4.4) D1(-3.2,3.6) D2(-2.4,3.6) D3(-1.6,3.6) D7(1.6,3.6) D8(2.4,3.6) D9(3.2,3.6) E1(-3.2,2.8) E2(-2.4,2.8) E3(-1.6,2.8) E7(1.6,2.8) E8(2.4,2.8) E9(3.2,2.8) F1(-3.2,2) F2(-2.4,2) F3(-1.6,2) F7(1.6,2) F8(2.4,2) F9(3.2,2) G1(-3.2,1.2) G2(-2.4,1.2) G3(-1.6,1.2) G7(1.6,1.2) G8(2.4,1.2) G9(3.2,1.2) H1(-3.2,0.4) H2(-2.4,0.4) H3(-1.6,0.4) H7(1.6,0.4) H8(2.4,0.4) H9(3.2,0.4) J1(-3.2,-0.4) J2(-2.4,-0.4) J3(-1.6,-0.4) J7(1.6,-0.4) J8(2.4,-0.4) J9(3.2,-0.4) K1(-3.2,-1.2) K2(-2.4,-1.2) K3(-1.6,-1.2) K7(1.6,-1.2) K8(2.4,-1.2) K9(3.2,-1.2) L1(-3.2,-2) L2(-2.4,-2) L3(-1.6,-2) L7(1.6,-2) L8(2.4,-2) L9(3.2,-2) M1(-3.2,-2.8) M2(-2.4,-2.8) M3(-1.6,-2.8) M7(1.6,-2.8) M8(2.4,-2.8) M9(3.2,-2.8) N1(-3.2,-3.6) N2(-2.4,-3.6) N3(-1.6,-3.6) N7(1.6,-3.6) N8(2.4,-3.6) N9(3.2,-3.6) P1(-3.2,-4.4) P2(-2.4,-4.4) P3(-1.6,-4.4) P7(1.6,-4.4) P8(2.4,-4.4) P9(3.2,-4.4) R1(-3.2,-5.2) R2(-2.4,-5.2) R3(-1.6,-5.2) R7(1.6,-5.2) R8(2.4,-5.2) R9(3.2,-5.2) T1(-3.2,-6) T2(-2.4,-6) T3(-1.6,-6) T7(1.6,-6) T8(2.4,-6) T9(3.2,-6)
BGA595M23H83
  round 0.432 smd: A2(-9.9,10.7) A3(-9.1,10.7) A25(9.1,10.7) A26(9.9,10.7) AE1(-10.7,-9.1) AE2(-9.9,-9.1) AE3(-9.1,-9.1) AE25(9.1,-9.1) AE26(9.9,-9.1) AE27(10.7,-9.1) AF1(-10.7,-9.9) AF2(-9.9,-9.9) AF3(-9.1,-9.9) AF25(9.1,-9.9) AF26(9.9,-9.9) AF27(10.7,-9.9) AG2(-9.9,-10.7) AG3(-9.1,-10.7) AG25(9.1,-10.7) AG26(9.9,-10.7) B1(-10.7,9.9) B2(-9.9,9.9) B3(-9.1,9.9) B25(9.1,9.9) B26(9.9,9.9) B27(10.7,9.9) C1(-10.7,9.1) C2(-9.9,9.1) C3(-9.1,9.1) C25(9.1,9.1) C26(9.9,9.1) C27(10.7,9.1)
  round 0.381 smd: A4(-8.3,10.7) A6(-6.6,10.7) A7(-5.8,10.7) A9(-4.12,10.7) A10(-3.32,10.7) A12(-1.64,10.7) A13(-0.84,10.7) A15(0.84,10.7) A16(1.64,10.7) A18(3.32,10.7) A19(4.12,10.7) A21(5.8,10.7) A22(6.6,10.7) A24(8.3,10.7) AA1(-10.7,-5.8) AA2(-9.9,-5.8) AA3(-9.1,-5.8) AA4(-8.3,-5.8) AA5(-7.5,-5.8) AA6(-6.66,-5.8) AA7(-5.8,-5.8) AA8(-4.96,-5.8) AA9(-4.12,-5.86) AA10(-3.32,-5.86) AA12(-1.64,-5.86) AA13(-0.84,-5.86) AA14(0,-5.86) AA15(0.84,-5.86) AA16(1.64,-5.86) AA18(3.32,-5.86) AA19(4.12,-5.86) AA20(4.96,-5.8) AA21(5.8,-5.8) AA22(6.66,-5.8) AA23(7.5,-5.8) AA24(8.3,-5.8) AA25(9.1,-5.8) AA26(9.9,-5.8) AA27(10.7,-5.8) AB1(-10.7,-6.6) AB2(-9.9,-6.6) AB3(-9.1,-6.6) AB4(-8.3,-6.6) AB5(-7.5,-6.6) AB6(-6.6,-6.6) AB7(-5.8,-6.66) AB8(-4.96,-6.66) AB9(-4.12,-6.66) AB10(-3.32,-6.66) AB11(-2.48,-6.66) AB12(-1.64,-6.66) AB13(-0.84,-6.66) AB14(0,-6.66) AB15(0.84,-6.66) AB16(1.64,-6.66) AB17(2.48,-6.66) AB18(3.32,-6.66) AB19(4.12,-6.66) AB20(4.96,-6.66) AB21(5.8,-6.66) AB22(6.6,-6.6) AB23(7.5,-6.6) AB24(8.3,-6.6) AB25(9.1,-6.6) AB26(9.9,-6.6) AB27(10.7,-6.6) AC2(-9.9,-7.45) AC3(-9.1,-7.45) AC4(-8.3,-7.45) AC5(-7.45,-7.45) AC6(-6.6,-7.5) AC7(-5.8,-7.5) AC8(-4.96,-7.5) AC9(-4.12,-7.5) AC10(-3.32,-7.5) AC11(-2.48,-7.5) AC12(-1.64,-7.5) AC13(-0.84,-7.5) AC14(0,-7.5) AC15(0.84,-7.5) AC16(1.64,-7.5) AC17(2.48,-7.5) AC18(3.32,-7.5) AC19(4.12,-7.5) AC20(4.96,-7.5) AC21(5.8,-7.5) AC22(6.6,-7.5) AC23(7.45,-7.45) AC24(8.3,-7.45) AC25(9.1,-7.45) AC26(9.9,-7.45) AD1(-10.7,-8.3) AD2(-9.9,-8.3) AD3(-9.1,-8.3) AD4(-8.3,-8.3) AD5(-7.45,-8.3) AD6(-6.6,-8.3) AD7(-5.8,-8.3) AD8(-4.96,-8.3) AD9(-4.12,-8.3) AD10(-3.32,-8.3) AD11(-2.48,-8.3) AD12(-1.64,-8.3) AD13(-0.84,-8.3) AD14(0,-8.3) AD15(0.84,-8.3) AD16(1.64,-8.3) AD17(2.48,-8.3) AD18(3.32,-8.3) AD19(4.12,-8.3) AD20(4.96,-8.3) AD21(5.8,-8.3) AD22(6.6,-8.3) AD23(7.45,-8.3) AD24(8.3,-8.3) AD25(9.1,-8.3) AD26(9.9,-8.3) AD27(10.7,-8.3) AE4(-8.3,-9.1) AE5(-7.45,-9.1) AE6(-6.6,-9.1) AE7(-5.8,-9.1) AE8(-4.96,-9.1) AE9(-4.12,-9.1) AE10(-3.32,-9.1) AE11(-2.48,-9.1) AE12(-1.64,-9.1) AE13(-0.84,-9.1) AE14(0,-9.1) AE15(0.84,-9.1) AE16(1.64,-9.1) AE17(2.48,-9.1) AE18(3.32,-9.1) AE19(4.12,-9.1) AE20(4.96,-9.1) AE21(5.8,-9.1) AE22(6.6,-9.1) AE23(7.45,-9.1) AE24(8.3,-9.1) AF4(-8.3,-9.9) AF5(-7.45,-9.9) AF6(-6.6,-9.9) AF7(-5.8,-9.9) AF8(-4.96,-9.9) AF9(-4.12,-9.9) AF10(-3.32,-9.9) AF11(-2.48,-9.9) AF12(-1.64,-9.9) AF13(-0.84,-9.9) AF14(0,-9.9) AF15(0.84,-9.9) AF16(1.64,-9.9) AF17(2.48,-9.9) AF18(3.32,-9.9) AF19(4.12,-9.9) AF20(4.96,-9.9) AF21(5.8,-9.9) AF22(6.6,-9.9) AF23(7.45,-9.9) AF24(8.3,-9.9) AG4(-8.3,-10.7) AG6(-6.6,-10.7) AG7(-5.8,-10.7) AG9(-4.12,-10.7) AG10(-3.32,-10.7) AG12(-1.64,-10.7) AG13(-0.84,-10.7) AG15(0.84,-10.7) AG16(1.64,-10.7) AG18(3.32,-10.7) AG19(4.12,-10.7) AG21(5.8,-10.7) AG22(6.6,-10.7) AG24(8.3,-10.7) B4(-8.3,9.9) B5(-7.45,9.9) B6(-6.6,9.9) B7(-5.8,9.9) B8(-4.96,9.9) B9(-4.12,9.9) B10(-3.32,9.9) B11(-2.48,9.9) B12(-1.64,9.9) B13(-0.84,9.9) B14(0,9.9) B15(0.84,9.9) B16(1.64,9.9) B17(2.48,9.9) B18(3.32,9.9) B19(4.12,9.9) B20(4.96,9.9) B21(5.8,9.9) B22(6.6,9.9) B23(7.45,9.9) B24(8.3,9.9) C4(-8.3,9.1) C5(-7.45,9.1) C6(-6.6,9.1) C7(-5.8,9.1) C8(-4.96,9.1) C9(-4.12,9.1) C10(-3.32,9.1) C11(-2.48,9.1) C12(-1.64,9.1) C13(-0.84,9.1) C14(0,9.1) C15(0.84,9.1) C16(1.64,9.1) C17(2.48,9.1) C18(3.32,9.1) C19(4.12,9.1) C20(4.96,9.1) C21(5.8,9.1) C22(6.6,9.1) C23(7.45,9.1) C24(8.3,9.1) D1(-10.7,8.3) D2(-9.9,8.3) D3(-9.1,8.3) D4(-8.3,8.3) D5(-7.45,8.3) D6(-6.6,8.3) D7(-5.8,8.3) D8(-4.96,8.3) D9(-4.12,8.3) D10(-3.32,8.3) D11(-2.48,8.3) D12(-1.64,8.3) D13(-0.84,8.3) D14(0,8.3) D15(0.84,8.3) D16(1.64,8.3) D17(2.48,8.3) D18(3.32,8.3) D19(4.12,8.3) D20(4.96,8.3) D21(5.8,8.3) D22(6.6,8.3) D23(7.45,8.3) D24(8.3,8.3) D25(9.1,8.3) D26(9.9,8.3) D27(10.7,8.3) E2(-9.9,7.45) E3(-9.1,7.45) E4(-8.3,7.45) E5(-7.45,7.45) E6(-6.6,7.5) E7(-5.8,7.5) E8(-4.96,7.5) E9(-4.12,7.5) E10(-3.32,7.5) E11(-2.48,7.5) E12(-1.64,7.5) E13(-0.84,7.5) E14(0,7.5) E15(0.84,7.5) E16(1.64,7.5) E17(2.48,7.5) E18(3.32,7.5) E19(4.12,7.5) E20(4.96,7.5) E21(5.8,7.5) E22(6.6,7.5) E23(7.45,7.45) E24(8.3,7.45) E25(9.1,7.45) E26(9.9,7.45) F1(-10.7,6.6) F2(-9.9,6.6) F3(-9.1,6.6) F4(-8.3,6.6) F5(-7.5,6.6) F6(-6.6,6.6) F7(-5.8,6.66) F8(-4.96,6.66) F9(-4.12,6.66) F10(-3.32,6.66) F11(-2.48,6.66) F12(-1.64,6.66) F13(-0.84,6.66) F14(0,6.66) F15(0.84,6.66) F16(1.64,6.66) F17(2.48,6.66) F18(3.32,6.66) F19(4.12,6.66) F20(4.96,6.66) F21(5.8,6.66) F22(6.6,6.6) F23(7.5,6.6) F24(8.3,6.6) F25(9.1,6.6) F26(9.9,6.6) F27(10.7,6.6) G1(-10.7,5.8) G2(-9.9,5.8) G3(-9.1,5.8) G4(-8.3,5.8) G5(-7.5,5.8) G6(-6.66,5.8) G7(-5.8,5.8) G8(-4.96,5.8) G9(-4.12,5.86) G10(-3.32,5.86) G12(-1.64,5.86) G13(-0.84,5.86) G14(0,5.86) G15(0.84,5.86) G16(1.64,5.86) G18(3.32,5.86) G19(4.12,5.86) G20(4.96,5.8) G21(5.8,5.8) G22(6.66,5.8) G23(7.5,5.8) G24(8.3,5.8) G25(9.1,5.8) G26(9.9,5.8) G27(10.7,5.8) H2(-9.9,4.96) H3(-9.1,4.96) H4(-8.3,4.96) H5(-7.5,4.96) H6(-6.66,4.96) H22(6.66,4.96) H23(7.5,4.96) H24(8.3,4.96) H25(9.1,4.96) H26(9.9,4.96) J1(-10.7,4.12) J2(-9.9,4.12) J3(-9.1,4.12) J4(-8.3,4.12) J5(-7.5,4.12) J6(-6.66,4.12) J7(-5.86,4.12) J21(5.86,4.12) J22(6.66,4.12) J23(7.5,4.12) J24(8.3,4.12) J25(9.1,4.12) J26(9.9,4.12) J27(10.7,4.12) K1(-10.7,3.32) K2(-9.9,3.32) K3(-9.1,3.32) K4(-8.3,3.32) K5(-7.5,3.32) K6(-6.66,3.32) K7(-5.86,3.32) K21(5.86,3.32) K22(6.66,3.32) K23(7.5,3.32) K24(8.3,3.32) K25(9.1,3.32) K26(9.9,3.32) K27(10.7,3.32) L2(-9.9,2.48) L3(-9.1,2.48) L4(-8.3,2.48) L5(-7.5,2.48) L6(-6.66,2.48) L22(6.66,2.48) L23(7.5,2.48) L24(8.3,2.48) L25(9.1,2.48) L26(9.9,2.48) M1(-10.7,1.64) M2(-9.9,1.64) M3(-9.1,1.64) M4(-8.3,1.64) M5(-7.5,1.64) M6(-6.66,1.64) M7(-5.86,1.64) M21(5.86,1.64) M22(6.66,1.64) M23(7.5,1.64) M24(8.3,1.64) M25(9.1,1.64) M26(9.9,1.64) M27(10.7,1.64) N1(-10.7,0.84) N2(-9.9,0.84) N3(-9.1,0.84) N4(-8.3,0.84) N5(-7.5,0.84) N6(-6.66,0.84) N7(-5.86,0.84) N21(5.86,0.84) N22(6.66,0.84) N23(7.5,0.84) N24(8.3,0.84) N25(9.1,0.84) N26(9.9,0.84) N27(10.7,0.84) P2(-9.9,0) P3(-9.1,0) P4(-8.3,0) P5(-7.5,0) P6(-6.66,0) P22(6.66,0) P23(7.5,0) P24(8.3,0) P25(9.1,0) P26(9.9,0) R1(-10.7,-0.84) R2(-9.9,-0.84) R3(-9.1,-0.84) R4(-8.3,-0.84) R5(-7.5,-0.84) R6(-6.66,-0.84) R7(-5.86,-0.84) R21(5.86,-0.84) R22(6.66,-0.84) R23(7.5,-0.84) R24(8.3,-0.84) R25(9.1,-0.84) R26(9.9,-0.84) R27(10.7,-0.84) T1(-10.7,-1.64) T2(-9.9,-1.64) T3(-9.1,-1.64) T4(-8.3,-1.64) T5(-7.5,-1.64) T6(-6.66,-1.64) T7(-5.86,-1.64) T21(5.86,-1.64) T22(6.66,-1.64) T23(7.5,-1.64) T24(8.3,-1.64) T25(9.1,-1.64) T26(9.9,-1.64) T27(10.7,-1.64) U2(-9.9,-2.48) U3(-9.1,-2.48) U4(-8.3,-2.48) U5(-7.5,-2.48) U6(-6.66,-2.48) U22(6.66,-2.48) U23(7.5,-2.48) U24(8.3,-2.48) U25(9.1,-2.48) U26(9.9,-2.48) V1(-10.7,-3.32) V2(-9.9,-3.32) V3(-9.1,-3.32) V4(-8.3,-3.32) V5(-7.5,-3.32) V6(-6.66,-3.32) V7(-5.86,-3.32) V21(5.86,-3.32) V22(6.66,-3.32) V23(7.5,-3.32) V24(8.3,-3.32) V25(9.1,-3.32) V26(9.9,-3.32) V27(10.7,-3.32) W1(-10.7,-4.12) W2(-9.9,-4.12) W3(-9.1,-4.12) W4(-8.3,-4.12) W5(-7.5,-4.12) W6(-6.66,-4.12) W7(-5.86,-4.12) W21(5.86,-4.12) W22(6.66,-4.12) W23(7.5,-4.12) W24(8.3,-4.12) W25(9.1,-4.12) W26(9.9,-4.12) W27(10.7,-4.12) Y2(-9.9,-4.96) Y3(-9.1,-4.96) Y4(-8.3,-4.96) Y5(-7.5,-4.96) Y6(-6.66,-4.96) Y22(6.66,-4.96) Y23(7.5,-4.96) Y24(8.3,-4.96) Y25(9.1,-4.96) Y26(9.9,-4.96)
  round 0.457 smd: K10(-4,4) K11(-3,4) K12(-2,4) K13(-1,4) K14(0,4) K15(1,4) K16(2,4) K17(3,4) K18(4,4) L10(-4,3) L11(-3,3) L12(-2,3) L13(-1,3) L14(0,3) L15(1,3) L16(2,3) L17(3,3) L18(4,3) M10(-4,2) M11(-3,2) M12(-2,2) M13(-1,2) M14(0,2) M15(1,2) M16(2,2) M17(3,2) M18(4,2) N10(-4,1) N11(-3,1) N12(-2,1) N13(-1,1) N14(0,1) N15(1,1) N16(2,1) N17(3,1) N18(4,1) P10(-4,0) P11(-3,0) P12(-2,0) P13(-1,0) P14(0,0) P15(1,0) P16(2,0) P17(3,0) P18(4,0) R10(-4,-1) R11(-3,-1) R12(-2,-1) R13(-1,-1) R14(0,-1) R15(1,-1) R16(2,-1) R17(3,-1) R18(4,-1) T10(-4,-2) T11(-3,-2) T12(-2,-2) T13(-1,-2) T14(0,-2) T15(1,-2) T16(2,-2) T17(3,-2) T18(4,-2) U10(-4,-3) U11(-3,-3) U12(-2,-3) U13(-1,-3) U14(0,-3) U15(1,-3) U16(2,-3) U17(3,-3) U18(4,-3) V10(-4,-4) V11(-3,-4) V12(-2,-4) V13(-1,-4) V14(0,-4) V15(1,-4) V16(2,-4) V17(3,-4) V18(4,-4)
BGA1168M4024H64
  round 0.508 smd: A3(18.177,-11.314) A62(-18.722,-11.314) AW1(19.314,10.727) AW63(-19.314,10.743) AY2(18.771,11.314) AY62(-18.748,11.314) B2(18.806,-10.806) B63(-19.314,-10.722) C1(19.314,-10.177)
  custom 0.089x0.089 smd: A4(17.421,-11.314) A5(16.76,-11.314) A6(15.564,-11.314) A59(-16.586,-11.314) A60(-17.412,-11.314) A61(-18.072,-11.314) AT1(19.314,8.683) AT63(-19.314,8.533) AU1(19.314,9.343) AU63(-19.314,9.359) AV1(19.314,10.004) AV2(18.654,9.993) AV62(-18.664,10.004) AV63(-19.314,10.019) AW3(17.993,10.654) AY3(18.047,11.314) AY4(17.387,11.314) AY5(16.726,11.314) AY59(-16.774,11.314) AY60(-17.434,11.314) AY61(-18.095,11.314) B61(-18.001,-10.654) C62(-18.664,-9.93) C63(-19.314,-9.998) D1(19.314,-9.453) D63(-19.314,-9.338) E1(19.314,-8.792) E63(-19.314,-8.667) F1(19.314,-7.878)
  custom 0.07x0.07 smd: A8(14.776,-11.314) A11(12.948,-11.314) A12(12.198,-11.314) A14(11.284,-11.314) A17(9.62,-11.314) A18(8.706,-11.314) A23(6.128,-11.314) A24(5.291,-10.989) A25(4.6,-11.314) A27(3.474,-11.314) A28(2.783,-10.989) A29(2.093,-11.314) A31(0.966,-11.314) A32(0.276,-10.989) A33(-0.415,-11.314) A35(-1.541,-11.314) A36(-2.232,-10.989) A37(-2.922,-11.314) A39(-4.049,-11.314) A40(-4.739,-10.989) A41(-5.43,-11.314) A43(-6.556,-11.314) A44(-7.247,-10.989) A45(-7.937,-11.314) A47(-9.064,-11.314) A48(-9.754,-10.989) A49(-10.444,-11.314) A51(-11.571,-11.314) A52(-12.262,-10.989) A53(-12.952,-11.314) A55(-14.079,-11.314) A56(-14.769,-10.989) A57(-15.459,-11.314) AA1(19.314,0.402) AA2(18.664,0.402) AA3(18.014,0.364) AA61(-18.014,0.324) AA62(-18.664,0.362) AA63(-19.314,0.362) AC1(19.314,1.152) AC2(18.664,1.152) AC3(18.014,1.19) AC61(-18.014,1.15) AC62(-18.664,1.112) AC63(-19.314,1.112) AD1(19.314,1.901) AD2(18.664,1.901) AD3(18.014,1.863) AD61(-18.014,1.823) AD62(-18.664,1.861) AD63(-19.314,1.861) AE61(-18.014,2.648) AE62(-18.664,2.61) AE63(-19.314,2.61) AF1(19.314,2.65) AF2(18.664,2.65) AF3(18.014,2.688) AG1(19.314,3.4) AG2(18.664,3.4) AG3(18.014,3.361) AG62(-18.339,3.288) AG63(-18.989,3.288) AH1(19.314,4.149) AH2(18.664,4.149) AH3(18.014,4.187) AH61(-18.014,3.964) AH62(-18.664,3.964) AH63(-19.314,3.964) AJ62(-18.339,4.64) AJ63(-18.989,4.64) AK1(19.314,4.898) AK2(18.664,4.898) AK3(18.014,4.86) AK61(-18.014,5.209) AK62(-18.664,5.315) AL1(19.314,5.647) AL2(18.664,5.647) AL3(18.014,5.686) AM1(19.314,6.397) AM2(18.664,6.397) AM3(18.014,6.359) AM61(-18.014,6.501) AM62(-18.664,6.395) AN1(19.314,7.146) AN2(18.664,7.146) AN3(18.014,7.184) AN62(-18.339,7.07) AN63(-18.989,7.07) AP1(19.314,7.895) AP2(18.664,7.895) AP3(18.014,7.857) AP61(-18.014,7.746) AP62(-18.664,7.746) AP63(-19.314,7.746) AV6(15.977,10.014) AV7(15.151,10.014) AV8(14.478,10.014) AV10(13.653,10.014) AV11(12.98,10.014) AV12(12.154,10.014) AV14(11.481,10.014) AV15(10.656,10.014) AV17(9.454,10.014) AV19(8.21,10.014) AV21(6.917,10.014) AV23(5.672,10.014) AV25(4.321,10.014) AV27(3.076,10.014) AV29(1.783,10.014) AV31(0.539,10.014) AV34(-0.71,10.014) AV35(-1.535,10.014) AV36(-2.284,10.014) AV37(-3.11,10.014) AV39(-3.859,10.014) AV40(-4.685,10.014) AV41(-5.434,10.014) AV42(-6.26,10.014) AV43(-7.009,10.014) AV44(-7.834,10.014) AV46(-8.584,10.014) AV47(-9.409,10.014) AV49(-10.158,10.014) AV50(-10.984,10.014) AV52(-12.342,10.014) AV54(-13.586,10.014) AV56(-14.879,10.014) AV58(-16.124,10.014) AW5(16.688,10.664) AW6(15.939,10.664) AW7(15.189,10.664) AW8(14.44,10.664) AW10(13.691,10.664) AW11(12.942,10.664) AW12(12.192,10.664) AW14(11.443,10.664) AW15(10.694,10.664) AW16(10.092,10.339) AW17(9.454,10.664) AW18(8.778,10.339) AW19(8.103,10.664) AW21(7.023,10.664) AW22(6.348,10.339) AW23(5.672,10.664) AW24(4.996,10.339) AW25(4.321,10.664) AW26(3.645,10.339) AW27(2.97,10.664) AW29(1.89,10.664) AW30(1.214,10.339) AW31(0.539,10.664) AW33(-0.137,10.339) AW34(-0.71,10.664) AW35(-1.535,10.664) AW36(-2.284,10.664) AW37(-3.11,10.664) AW39(-3.859,10.664) AW40(-4.685,10.664) AW41(-5.434,10.664) AW42(-6.26,10.664) AW43(-7.009,10.664) AW44(-7.834,10.664) AW46(-8.584,10.664) AW47(-9.409,10.664) AW49(-10.158,10.664) AW50(-10.984,10.664) AW51(-11.666,10.339) AW52(-12.342,10.664) AW53(-13.017,10.339) AW54(-13.693,10.664) AW56(-14.772,10.664) AW57(-15.448,10.339) AW58(-16.124,10.664) AY6(15.939,11.314) AY7(15.189,11.314) AY8(14.44,11.314) AY10(13.691,11.314) AY11(12.942,11.314) AY12(12.192,11.314) AY14(11.443,11.314) AY15(10.694,11.314) AY16(10.13,10.989) AY17(9.454,11.314) AY18(8.778,10.989) AY22(6.348,10.989) AY23(5.672,11.314) AY24(4.996,10.989) AY25(4.321,11.314) AY26(3.645,10.989) AY30(1.214,10.989) AY31(0.539,11.314) AY33(-0.137,10.989) AY34(-0.71,11.314) AY35(-1.535,11.314) AY36(-2.284,11.314) AY37(-3.11,11.314) AY39(-3.859,11.314) AY40(-4.685,11.314) AY41(-5.434,11.314) AY42(-6.26,11.314) AY43(-7.009,11.314) AY44(-7.834,11.314) AY46(-8.584,11.314) AY47(-9.409,11.314) AY49(-10.158,11.314) AY50(-10.984,11.314) AY51(-11.666,10.989) AY52(-12.342,11.314) AY53(-13.017,10.989) AY57(-15.448,10.989) AY58(-16.124,11.314) B6(15.196,-10.672) B8(14.423,-10.672) B9(13.598,-10.672) B11(12.617,-10.672) B12(11.845,-10.672) B14(11.02,-10.672) B15(10.039,-10.672) B17(9.267,-10.672) B18(8.442,-10.672) B21(7.042,-10.118) B22(6.689,-10.672) B23(5.864,-10.672) B24(5.291,-10.339) B25(4.6,-10.664) B26(4.037,-10.339) B27(3.474,-10.664) B28(2.783,-10.339) B29(2.093,-10.664) B30(1.53,-10.339) B31(0.966,-10.664) B32(0.276,-10.339) B33(-0.415,-10.664) B34(-0.978,-10.339) B35(-1.541,-10.664) B36(-2.232,-10.339) B37(-2.922,-10.664) B38(-3.485,-10.339) B39(-4.049,-10.664) B40(-4.739,-10.339) B41(-5.43,-10.664) B42(-5.993,-10.339) B43(-6.556,-10.664) B44(-7.247,-10.339) B45(-7.937,-10.664) B46(-8.5,-10.339) B47(-9.064,-10.664) B48(-9.754,-10.339) B49(-10.444,-10.664) B50(-11.008,-10.339) B51(-11.571,-10.664) B52(-12.262,-10.339) B53(-12.952,-10.664) B54(-13.515,-10.339) B55(-14.079,-10.664) B56(-14.769,-10.339) B57(-15.459,-10.664) C8(14.776,-10.118) C9(13.964,-10.118) C11(12.96,-10.118) C12(12.198,-10.118) C14(11.386,-10.118) C15(10.382,-10.118) C17(9.62,-10.118) C18(8.807,-10.118) C23(6.229,-10.118) D20(8.306,-9.529) F61(-18.014,-7.842) F62(-18.664,-7.88) F63(-19.314,-7.88) G1(19.314,-7.091) G2(18.664,-7.091) G3(18.014,-7.129) H61(-18.014,-7.169) H62(-18.664,-7.131) H63(-19.314,-7.131) J1(19.314,-6.341) J2(18.664,-6.341) J3(18.014,-6.303) J61(-18.014,-6.343) J62(-18.664,-6.381) J63(-19.314,-6.381) K1(19.314,-5.592) K2(18.664,-5.592) K3(18.014,-5.63) K61(-18.014,-5.67) K62(-18.664,-5.632) K63(-19.314,-5.632) L1(19.314,-4.843) L2(18.664,-4.843) L3(18.014,-4.805) L61(-18.014,-4.845) L62(-18.664,-4.883) L63(-19.314,-4.883) N1(19.314,-4.093) N2(18.664,-4.093) N3(18.014,-4.132) N61(-18.014,-4.172) N62(-18.664,-4.134) N63(-19.314,-4.134) P1(19.314,-3.344) P2(18.664,-3.344) P3(18.014,-3.306) P61(-18.014,-3.346) P62(-18.664,-3.384) P63(-19.314,-3.384) T1(19.314,-2.595) T2(18.664,-2.595) T3(18.014,-2.633) T61(-18.014,-2.673) T62(-18.664,-2.635) T63(-19.314,-2.635) U1(19.314,-1.846) U2(18.664,-1.846) U3(18.014,-1.807) U61(-18.014,-1.848) U62(-18.664,-1.886) U63(-19.314,-1.886) V1(19.314,-1.096) V2(18.664,-1.096) V3(18.014,-1.134) V61(-18.014,-1.174) V62(-18.664,-1.136) V63(-19.314,-1.136) Y1(19.314,-0.347) Y2(18.664,-0.347) Y3(18.014,-0.309) Y61(-18.014,-0.349) Y62(-18.664,-0.387) Y63(-19.314,-0.387)
  custom 0.064x0.064 smd: A9(13.862,-11.314) A15(10.37,-11.314) A21(7.042,-11.314) AK63(-19.314,5.315) AM63(-19.314,6.395) AY19(8.103,11.314) AY21(7.023,11.314) AY27(2.97,11.314) AY29(1.89,11.314) AY54(-13.693,11.314) AY56(-14.772,11.314)
  round 0.305 smd: A20(7.791,-11.314) AA4(17.363,0.364) AA59(-16.713,0.324) AA60(-17.363,0.324) AB5(16.678,0.738) AB6(16.027,0.738) AB7(15.377,0.738) AB8(14.727,0.738) AC4(17.363,1.19) AC59(-16.713,1.15) AC60(-17.363,1.15) AD4(17.363,1.863) AD5(16.678,1.691) AD6(16.027,1.691) AD7(15.377,1.691) AD8(14.727,1.691) AD59(-16.713,1.823) AD60(-17.363,1.823) AE5(16.678,2.643) AE6(16.027,2.643) AE7(15.377,2.643) AE8(14.727,2.643) AE59(-16.713,2.648) AE60(-17.363,2.648) AF4(17.363,2.688) AG4(17.363,3.361) AG5(16.678,3.596) AG6(16.027,3.596) AG7(15.377,3.596) AG8(14.727,3.596) AG21(7.359,3.807) AG60(-17.038,3.288) AG61(-17.689,3.288) AH4(17.363,4.187) AH10(13.662,4.162) AH11(12.849,4.162) AH13(12.036,4.162) AH14(11.223,4.162) AH16(10.41,4.162) AH17(9.598,4.162) AH19(8.785,4.162) AH20(7.972,4.162) AH60(-17.363,3.964) AJ5(16.678,4.548) AJ6(16.027,4.548) AJ7(15.377,4.548) AJ8(14.727,4.548) AJ10(13.662,4.812) AJ11(12.849,4.812) AJ13(12.036,4.812) AJ14(11.223,4.812) AJ60(-17.038,4.64) AJ61(-17.689,4.64) AK4(17.363,4.86) AK8(15.011,5.137) AK18(9.466,4.952) AK20(8.513,4.952) AK21(7.561,4.952) AK60(-17.363,5.209) AL4(17.363,5.686) AL5(16.413,5.462) AL7(15.575,5.462) AL8(15.011,5.787) AL10(13.657,5.462) AL11(13.093,5.787) AL13(11.738,5.462) AL15(11.174,5.787) AL17(10.092,5.268) AL18(9.466,5.602) AL20(8.513,5.602) AL21(7.561,5.602) AL22(6.608,5.602) AL23(5.786,5.602) AL25(4.81,5.602) AL26(3.858,5.602) AL28(2.905,5.602) AL29(1.953,5.602) AL31(1.054,5.277) AL32(0.49,5.602) AL33(-0.412,5.602) AL35(-1.415,5.602) AL36(-2.266,5.602) AL38(-3.32,5.602) AL39(-4.228,5.277) AL40(-4.817,5.602) AL42(-5.63,5.602) AL43(-6.582,5.602) AL45(-7.56,5.602) AL46(-8.487,5.602) AL48(-9.542,5.602) AL49(-10.443,5.602) AL51(-11.447,5.602) AL52(-12.269,5.602) AL54(-13.295,5.602) AL55(-14.248,5.602) AL57(-15.195,5.602) AL58(-16.094,5.602) AL60(-17.038,5.855) AL61(-17.689,5.855) AM4(17.363,6.359) AM5(16.413,6.112) AM7(15.575,6.112) AM8(15.011,6.437) AM10(13.657,6.112) AM11(13.093,6.437) AM13(11.738,6.112) AM15(11.174,6.437) AM17(10.092,5.919) AM18(9.466,6.252) AM20(8.513,6.252) AM21(7.561,6.252) AM22(6.608,6.252) AM23(5.786,6.252) AM25(4.81,6.252) AM26(3.858,6.252) AM28(2.905,6.252) AM29(1.953,6.252) AM31(1.054,5.927) AM32(0.49,6.252) AM33(-0.412,6.252) AM35(-1.415,6.252) AM36(-2.266,6.252) AM38(-3.32,6.252) AM40(-4.817,6.252) AM42(-5.63,6.252) AM43(-6.582,6.252) AM45(-7.56,6.252) AM46(-8.487,6.252) AM48(-9.542,6.252) AM49(-10.443,6.252) AM51(-11.447,6.252) AM52(-12.269,6.252) AM54(-13.295,6.252) AM55(-14.248,6.252) AM57(-15.195,6.252) AM58(-16.094,6.252) AM60(-17.363,6.501) AN4(17.363,7.184) AN5(16.413,6.762) AN7(15.575,6.762) AN8(15.011,7.088) AN10(13.657,6.762) AN11(13.093,7.088) AN13(11.738,6.762) AN15(11.174,7.088) AN17(10.092,6.569) AN18(9.466,6.903) AN20(8.513,6.903) AN21(7.561,6.903) AN22(6.608,6.903) AN23(5.786,6.903) AN25(4.81,6.903) AN26(3.858,6.903) AN28(2.905,6.903) AN29(1.953,6.903) AN31(1.054,6.578) AN32(0.49,6.903) AN33(-0.412,6.903) AN35(-1.415,6.903) AN36(-2.266,6.903) AN38(-3.32,6.903) AN39(-4.228,6.578) AN40(-4.817,6.903) AN42(-5.63,6.903) AN43(-6.582,6.903) AN45(-7.56,6.903) AN46(-8.487,6.903) AN48(-9.542,6.903) AN49(-10.443,6.903) AN51(-11.447,6.903) AN52(-12.269,6.903) AN54(-13.295,6.903) AN55(-14.248,6.903) AN57(-15.195,6.903) AN58(-16.094,6.903) AN60(-17.038,7.07) AN61(-17.689,7.07) AP4(17.363,7.857) AP5(16.413,7.413) AP7(15.575,7.413) AP8(15.011,7.738) AP10(13.657,7.413) AP11(13.093,7.738) AP13(11.738,7.413) AP15(11.174,7.738) AP17(10.092,7.219) AP18(9.466,7.553) AP20(8.513,7.553) AP21(7.561,7.553) AP22(6.608,7.553) AP23(5.786,7.553) AP25(4.81,7.553) AP26(3.858,7.553) AP28(2.905,7.553) AP29(1.953,7.553) AP31(1.054,7.228) AP32(0.49,7.553) AP33(-0.412,7.553) AP35(-1.415,7.553) AP36(-2.266,7.553) AP38(-3.32,7.553) AP39(-4.228,7.228) AP40(-4.817,7.553) AP42(-5.63,7.553) AP43(-6.582,7.553) AP45(-7.56,7.553) AP46(-8.487,7.553) AP48(-9.542,7.553) AP49(-10.443,7.553) AP51(-11.447,7.553) AP52(-12.269,7.553) AP54(-13.295,7.553) AP55(-14.248,7.553) AP57(-15.195,7.553) AP58(-16.094,7.553) AP60(-17.363,7.746) AR5(16.413,8.063) AR7(15.575,8.063) AR8(15.011,8.388) AR10(13.657,8.063) AR11(13.093,8.388) AR13(11.738,8.063) AR15(11.174,8.388) AR17(10.092,7.869) AR18(9.466,8.203) AR20(8.513,8.203) AR21(7.561,8.203) AR22(6.608,8.203) AR23(5.786,8.203) AR25(4.81,8.203) AR26(3.858,8.203) AR28(2.905,8.203) AR29(1.953,8.203) AR31(1.054,7.878) AR32(0.49,8.203) AR33(-0.412,8.203) AR35(-1.415,8.203) AR36(-2.266,8.203) AR38(-3.32,8.203) AR39(-4.228,7.878) AR40(-4.817,8.203) AR42(-5.63,8.203) AR43(-6.582,8.203) AR45(-7.56,8.203) AR46(-8.487,8.203) AR48(-9.542,8.203) AR49(-10.443,8.203) AR51(-11.447,8.203) AR52(-12.269,8.203) AR54(-13.295,8.203) AR55(-14.248,8.203) AR57(-15.195,8.203) AR58(-16.094,8.203) AT2(18.664,8.645) AT3(18.014,8.683) AT4(17.363,8.683) AT5(16.413,8.713) AT7(15.575,8.713) AT10(13.657,8.713) AT13(11.738,8.713) AT35(-1.122,8.905) AT37(-2.697,8.905) AT40(-4.272,8.905) AT42(-5.847,8.905) AT43(-7.422,8.905) AT46(-8.996,8.905) AT49(-10.597,8.933) AT61(-17.689,8.32) AT62(-18.498,8.376) AU2(18.659,9.333) AU3(17.999,9.333) AU4(17.338,9.333) AU6(15.977,9.363) AU7(15.151,9.363) AU8(14.478,9.363) AU10(13.653,9.363) AU11(12.98,9.363) AU12(12.154,9.363) AU14(11.481,9.363) AU15(10.656,9.363) AU16(10.092,9.038) AU17(9.454,9.363) AU18(8.778,9.038) AU19(8.21,9.363) AU20(7.563,9.038) AU21(6.917,9.363) AU22(6.348,9.038) AU23(5.672,9.363) AU24(4.996,9.038) AU25(4.321,9.363) AU26(3.645,9.038) AU27(3.076,9.363) AU28(2.43,9.038) AU29(1.783,9.363) AU30(1.214,9.038) AU31(0.539,9.363) AU33(-0.058,9.016) AU34(-0.66,9.363) AU35(-1.585,9.363) AU36(-2.235,9.363) AU37(-3.16,9.363) AU39(-3.81,9.363) AU40(-4.734,9.363) AU41(-5.385,9.363) AU42(-6.309,9.363) AU43(-6.959,9.363) AU44(-7.884,9.363) AU46(-8.534,9.363) AU47(-9.459,9.363) AU49(-10.109,9.363) AU50(-11.086,9.363) AU51(-11.666,9.038) AU52(-12.342,9.363) AU53(-13.017,9.038) AU54(-13.586,9.363) AU55(-14.233,9.038) AU56(-14.879,9.363) AU57(-15.448,9.038) AU58(-16.124,9.363) AU59(-16.688,9.038) AU60(-17.251,9.363) AU61(-17.963,9.087) AU62(-18.664,9.349) AV3(17.993,9.993) AV4(17.338,9.993) AV5(16.65,10.014) AV16(10.092,9.689) AV18(8.778,9.689) AV20(7.563,9.689) AV22(6.348,9.689) AV24(4.996,9.689) AV26(3.645,9.689) AV28(2.43,9.689) AV30(1.214,9.689) AV33(-0.086,9.689) AV51(-11.666,9.689) AV53(-13.017,9.689) AV55(-14.233,9.689) AV57(-15.448,9.689) AV59(-16.688,9.689) AV60(-17.251,10.014) AV61(-17.988,9.737) AW4(17.338,10.654) AW59(-16.688,10.339) AW60(-17.251,10.664) B4(17.393,-10.664) B5(16.176,-10.672) B20(7.461,-10.672) B58(-16.023,-10.339) B59(-16.586,-10.664) B60(-17.351,-10.654) C3(18.012,-10.012) C4(17.196,-10.042) C5(16.542,-10.118) C6(15.538,-10.118) C20(7.804,-10.118) C21(7.423,-9.529) C22(6.636,-9.529) C24(5.263,-9.282) C25(4.6,-10.014) C26(4.037,-9.689) C27(3.474,-10.014) C28(2.756,-9.282) C29(2.093,-10.014) C30(1.53,-9.689) C31(0.966,-10.014) C32(0.248,-9.282) C33(-0.415,-10.014) C34(-0.978,-9.689) C35(-1.541,-10.014) C36(-2.259,-9.282) C37(-2.922,-10.014) C38(-3.485,-9.689) C39(-4.049,-10.014) C40(-4.767,-9.282) C41(-5.43,-10.014) C42(-5.993,-9.689) C43(-6.556,-10.014) C44(-7.274,-9.282) C45(-7.937,-10.014) C46(-8.5,-9.689) C47(-9.064,-10.014) C48(-9.756,-9.282) C49(-10.444,-10.014) C50(-11.008,-9.689) C51(-11.571,-10.014) C52(-12.264,-9.323) C53(-12.952,-10.014) C54(-13.515,-9.689) C55(-14.079,-10.014) C56(-14.771,-9.323) C57(-15.459,-10.014) C58(-16.023,-9.689) C59(-16.586,-10.014) C61(-17.689,-10.077) D2(18.664,-9.24) D3(18.014,-9.278) D5(16.636,-9.472) D6(15.945,-9.529) D8(15.157,-9.529) D9(14.37,-9.529) D11(13.462,-9.529) D12(12.579,-9.529) D14(11.792,-9.529) D15(10.884,-9.529) D17(10.001,-9.529) D18(9.214,-9.529) D21(7.079,-8.891) D23(5.937,-9.529) D25(4.6,-9.363) D26(4.037,-9.038) D27(3.474,-9.363) D29(2.093,-9.363) D30(1.53,-9.038) D31(0.966,-9.363) D33(-0.415,-9.363) D34(-0.978,-9.038) D35(-1.541,-9.363) D37(-2.922,-9.363) D38(-3.485,-9.038) D39(-4.049,-9.363) D41(-5.43,-9.363) D42(-5.993,-9.038) D43(-6.556,-9.363) D45(-7.937,-9.363) D46(-8.5,-9.038) D47(-9.064,-9.363) D49(-10.444,-9.363) D50(-11.008,-9.038) D51(-11.571,-9.363) D53(-12.952,-9.363) D54(-13.515,-9.038) D55(-14.079,-9.363) D57(-15.459,-9.363) D58(-16.023,-9.038) D59(-16.586,-9.363) D60(-17.363,-9.513) D61(-18.014,-9.513) D62(-18.664,-9.28) E2(18.664,-8.589) E3(18.014,-8.627) E4(17.363,-8.627) E5(16.712,-8.695) E6(15.76,-8.695) E8(14.807,-8.695) E10(13.855,-8.695) E11(12.902,-8.695) E13(11.95,-8.695) E15(10.997,-8.695) E17(10.045,-8.695) E18(9.092,-8.695) E20(8.14,-8.695) E59(-16.713,-8.667) E60(-17.363,-8.667) E61(-18.014,-8.667) E62(-18.664,-8.629) F2(18.664,-7.84) F3(18.014,-7.802) F4(17.363,-7.802) F5(16.712,-8.045) F6(15.76,-8.045) F8(14.807,-8.045) F10(13.855,-8.045) F11(12.902,-8.045) F13(11.95,-8.045) F15(10.997,-8.045) F17(10.045,-8.045) F18(9.092,-8.045) F20(8.14,-8.045) F59(-16.713,-7.842) F60(-17.363,-7.842) G4(17.363,-7.129) G5(16.712,-7.395) G6(15.76,-7.395) G8(14.807,-7.395) G10(13.855,-7.395) G11(12.902,-7.395) G13(11.95,-7.395) G15(10.997,-7.395) G17(10.045,-7.395) G18(9.092,-7.395) G20(8.14,-7.395) H5(16.712,-6.745) H6(15.76,-6.745) H8(14.807,-6.745) H10(13.855,-6.745) H11(12.902,-6.745) H13(11.95,-6.745) H15(10.997,-6.745) H17(10.045,-6.745) H18(9.092,-6.745) H20(8.14,-6.745) H59(-16.713,-7.169) H60(-17.363,-7.169) J4(17.363,-6.303) J5(16.687,-6.094) J6(15.747,-6.094) J8(14.807,-6.094) J10(13.855,-6.094) J11(12.902,-6.094) J13(11.95,-6.094) J15(10.997,-6.094) J17(10.045,-6.094) J18(9.092,-6.094) J20(8.14,-6.094) J21(7.219,-6.328) J59(-16.713,-6.343) J60(-17.363,-6.343) K4(17.363,-5.63) K59(-16.713,-5.67) K60(-17.363,-5.67) L4(17.363,-4.805) L5(16.678,-4.977) L6(16.027,-4.977) L7(15.377,-4.977) L8(14.727,-4.977) L59(-16.713,-4.845) L60(-17.363,-4.845) N4(17.363,-4.132) N5(16.678,-4.024) N6(16.027,-4.024) N7(15.377,-4.024) N8(14.727,-4.024) N59(-16.713,-4.172) N60(-17.363,-4.172) P4(17.363,-3.306) P59(-16.713,-3.346) P60(-17.363,-3.346) R5(16.678,-3.072) R6(16.027,-3.072) R7(15.377,-3.072) R8(14.727,-3.072) T4(17.363,-2.633) T59(-16.713,-2.673) T60(-17.363,-2.673) U4(17.363,-1.807) U5(16.678,-2.119) U6(16.027,-2.119) U7(15.377,-2.119) U8(14.727,-2.119) U59(-16.713,-1.848) U60(-17.363,-1.848) V4(17.363,-1.134) V5(16.678,-1.167) V6(16.027,-1.167) V7(15.377,-1.167) V8(14.727,-1.167) V59(-16.713,-1.174) V60(-17.363,-1.174) Y4(17.363,-0.309) Y5(16.678,-0.214) Y6(16.027,-0.214) Y7(15.377,-0.214) Y8(14.727,-0.214) Y59(-16.713,-0.349) Y60(-17.363,-0.349)
  round 0.381 smd: AA9(14.282,0.262) AA21(7.627,0.175) AA23(6.199,0.175) AA58(-16.063,0.015) AB10(13.838,0.738) AB20(8.135,0.582) AB21(7.627,0.988) AB22(6.707,0.582) AB23(6.199,0.988) AB57(-15.743,0.666) AC9(14.282,1.215) AC20(8.135,1.394) AC22(6.707,1.394) AC58(-16.063,1.316) AD10(13.838,1.691) AD21(7.627,1.801) AD23(6.199,1.801) AD57(-15.743,1.966) AE9(14.282,2.167) AE10(13.838,2.643) AE20(8.135,2.207) AE21(7.627,2.614) AE22(6.707,2.207) AE23(6.199,2.614) AE58(-16.063,2.616) AF9(14.282,3.12) AF11(13.255,2.968) AF12(12.442,2.968) AF14(11.63,2.968) AF15(10.817,2.968) AF17(10.004,2.968) AF18(9.191,2.968) AF20(8.378,2.968) AF22(6.707,3.02) AG10(13.662,3.476) AG11(12.849,3.476) AG13(12.036,3.476) AG14(11.223,3.476) AG16(10.41,3.476) AG17(9.598,3.476) AG19(8.785,3.476) AG20(7.972,3.476) AG23(6.199,3.426) AG57(-15.743,3.267) AG58(-16.377,3.695) AH22(6.707,3.833) AH24(5.394,3.975) AH26(4.094,3.975) AH28(2.793,3.975) AH30(1.493,3.975) AH32(0.192,3.975) AH34(-1.108,3.975) AH36(-2.409,3.975) AH38(-3.709,3.975) AH40(-5.01,3.975) AH42(-6.31,3.975) AH44(-7.611,3.975) AH46(-8.911,3.975) AH49(-10.212,3.975) AH51(-11.512,3.975) AH53(-12.813,3.975) AH55(-14.113,3.975) AH57(-15.413,3.975) AJ23(6.199,4.239) AJ25(4.744,4.3) AJ27(3.443,4.3) AJ29(2.143,4.3) AJ31(0.843,4.3) AJ33(-0.458,4.3) AJ35(-1.758,4.3) AJ37(-3.059,4.3) AJ39(-4.359,4.3) AJ41(-5.66,4.3) AJ43(-6.96,4.3) AJ45(-8.261,4.3) AJ47(-9.561,4.3) AJ50(-10.862,4.3) AJ52(-12.162,4.3) AJ54(-13.463,4.3) AJ56(-14.763,4.3) AJ58(-16.064,4.3) AW2(18.654,10.654) AW61(-18.014,10.664) AW62(-18.664,10.664) B3(18.056,-10.664) B62(-18.664,-10.59) C2(18.664,-10.056) E23(5.981,-8.713) E25(4.6,-8.713) E27(3.474,-8.713) E29(2.093,-8.713) E31(0.966,-8.713) E33(-0.415,-8.713) E35(-1.541,-8.713) E37(-2.922,-8.713) E39(-4.049,-8.713) E41(-5.43,-8.713) E43(-6.556,-8.713) E45(-7.937,-8.713) E47(-9.064,-8.713) E49(-10.444,-8.713) E51(-11.571,-8.713) E53(-12.952,-8.713) E55(-14.079,-8.713) E57(-15.459,-8.713) F22(6.597,-8.256) F24(5.291,-8.188) F26(4.037,-8.188) F28(2.783,-8.188) F30(1.53,-8.188) F32(0.276,-8.188) F34(-0.978,-8.188) F36(-2.232,-8.188) F38(-3.485,-8.188) F40(-4.739,-8.188) F42(-5.993,-8.188) F44(-7.247,-8.188) F46(-8.5,-8.188) F48(-9.754,-8.188) F50(-11.008,-8.188) F52(-12.262,-8.188) F54(-13.515,-8.188) F56(-14.769,-8.188) F58(-16.063,-8.188) G22(6.707,-7.546) G23(5.981,-7.863) G25(4.6,-7.863) G27(3.474,-7.863) G29(2.093,-7.863) G31(0.966,-7.863) G33(-0.415,-7.863) G35(-1.541,-7.863) G37(-2.922,-7.863) G39(-4.049,-7.863) G41(-5.43,-7.863) G43(-6.556,-7.863) G45(-7.937,-7.863) G47(-9.064,-7.863) G49(-10.444,-7.863) G51(-11.571,-7.863) G53(-12.952,-7.863) G55(-14.079,-7.863) G57(-15.459,-7.863) H22(6.707,-6.734) H23(6.199,-7.14) H57(-15.743,-7.213) J22(6.707,-5.921) J23(6.199,-6.327) J58(-16.063,-6.487) K9(14.282,-5.453) K10(13.379,-5.614) K12(12.426,-5.614) K14(11.474,-5.614) K16(10.521,-5.614) K18(9.569,-5.614) K19(8.616,-5.614) K21(7.664,-5.614) K23(6.199,-5.514) K57(-15.743,-5.837) L10(13.838,-4.977) L11(12.902,-5.17) L13(11.95,-5.17) L15(10.997,-5.17) L17(10.045,-5.17) L18(9.092,-5.17) L20(8.135,-5.108) L22(6.707,-5.108) L58(-16.063,-5.186) M9(14.282,-4.5) M20(8.135,-4.295) M21(7.627,-4.702) M22(6.707,-4.295) M23(6.199,-4.702) M57(-15.743,-4.536) N10(13.838,-4.024) N21(7.627,-3.889) N23(6.199,-3.889) N58(-16.063,-3.886) P9(14.282,-3.548) P20(8.135,-3.482) P22(6.707,-3.482) P57(-15.743,-3.236) R10(13.838,-3.072) R20(8.135,-2.67) R21(7.627,-3.076) R22(6.707,-2.67) R23(6.199,-3.076) T9(14.282,-2.595) T21(7.627,-2.263) T23(6.199,-2.263) T58(-16.063,-2.585) U9(14.282,-1.643) U10(13.838,-2.119) U20(8.135,-1.857) U22(6.707,-1.857) U57(-15.743,-1.935) V10(13.838,-1.167) V21(7.627,-1.45) V23(6.199,-1.45) V58(-16.063,-1.285) W9(14.282,-0.69) W20(8.135,-1.044) W21(7.627,-0.638) W22(6.707,-1.044) W23(6.199,-0.638) W57(-15.743,-0.635) Y10(13.838,-0.214) Y20(8.135,-0.231) Y22(6.707,-0.231)
  round 0.33 smd: AK22(6.659,4.952) AK23(5.786,4.952) AK25(4.81,4.952) AK26(3.858,4.952) AK28(2.905,4.952) AK29(2.004,4.952) AK32(0.49,4.952) AK33(-0.412,4.952) AK35(-1.415,4.952) AK36(-2.266,4.952) AK38(-3.295,4.952) AK40(-4.792,4.952) AK42(-5.63,4.952) AK43(-6.582,4.952) AK45(-7.56,4.952) AK46(-8.462,4.952) AK48(-9.516,4.952) AK49(-10.418,4.952) AK51(-11.421,4.952) AK52(-12.269,4.952) AK54(-13.295,4.952) AK55(-14.248,4.952) AK57(-15.195,4.952) AK58(-16.094,4.952)
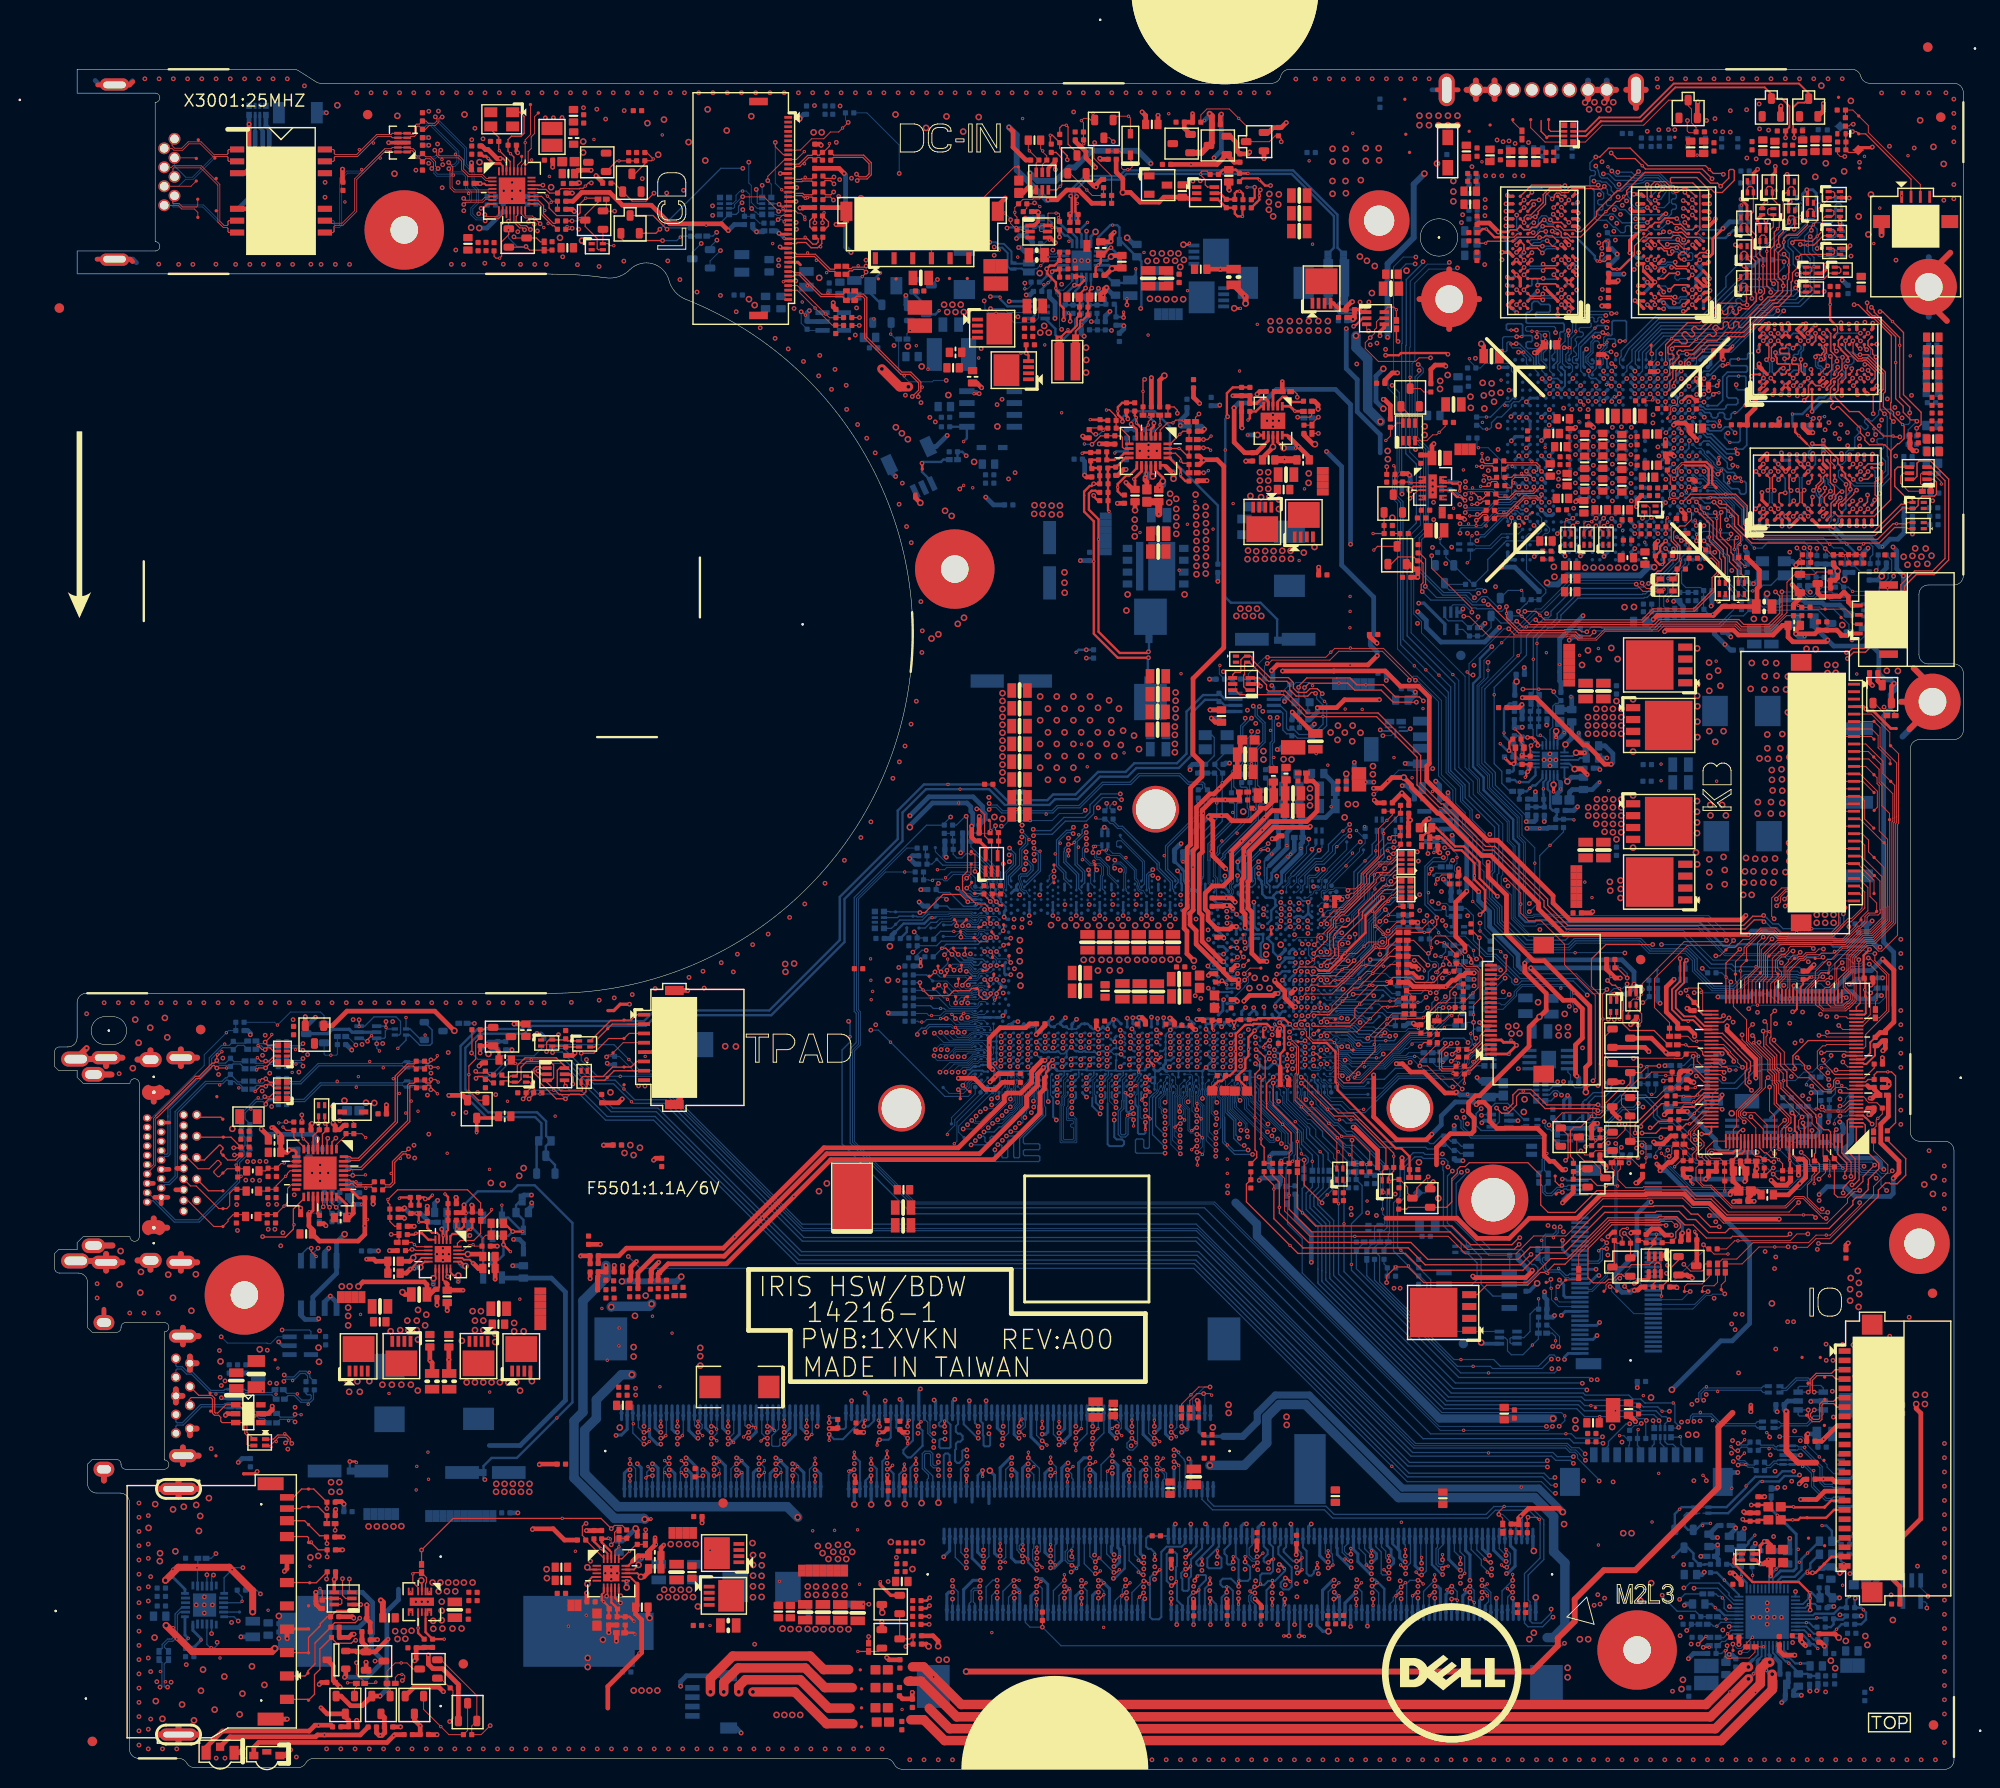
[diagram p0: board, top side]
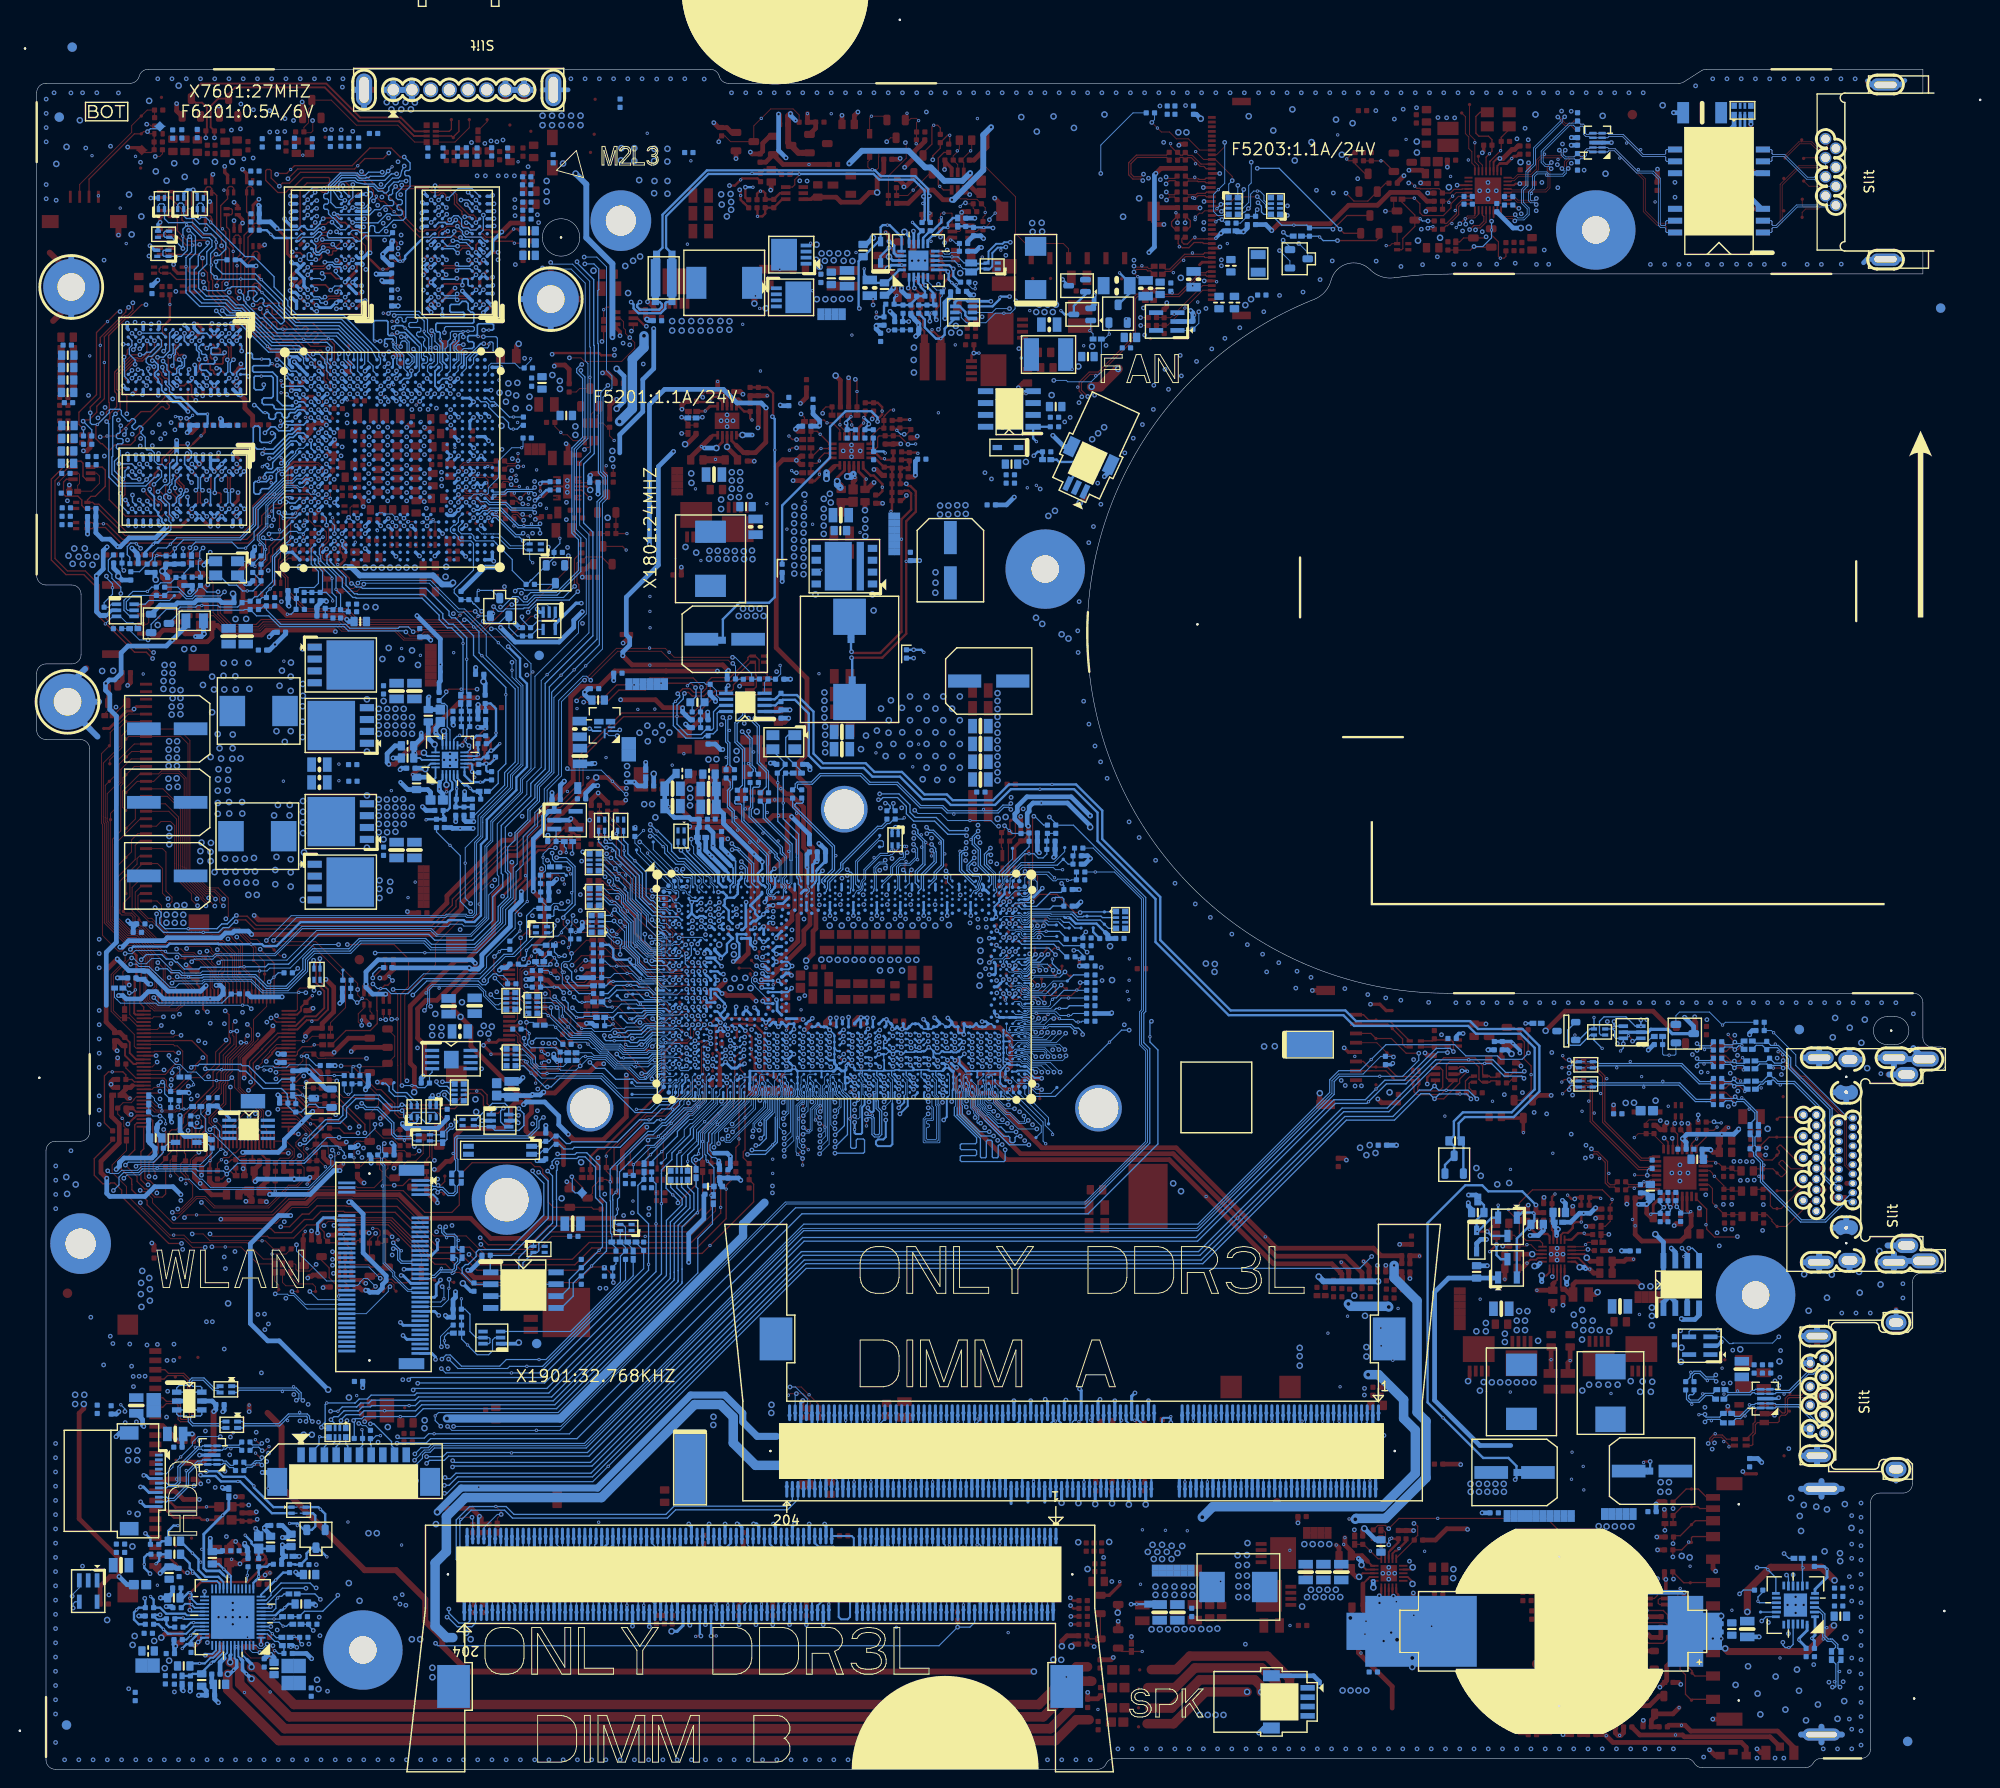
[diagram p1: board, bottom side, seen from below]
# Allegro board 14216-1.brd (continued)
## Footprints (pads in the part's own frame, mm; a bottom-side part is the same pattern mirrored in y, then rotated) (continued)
C100PF-10809-L
  round 1.27 hole 0.914: 1(-3.556,5.32) 2(-2.54,6.42) 3(-1.524,5.32) 4(-0.508,6.42) 5(0.508,5.32) 6(1.524,6.42) 7(2.54,5.32) 8(3.556,6.42)
  oval 1.321x3.124 hole 0.711x2.413: 9(-9.325,0) 10(9.325,0)
C402-TO0D2H23
  custom 0.152x0.152 smd: 1(0,0.457) 2(0,-0.457)
C402H22
  custom 0.14x0.14 smd: 1(0,0.445) 2(0,-0.445)
C603
  custom 0.197x0.197 smd: 1(0,0.66) 2(0,-0.66)
C603H36
  custom 0.197x0.197 smd: 1(0,0.66) 2(0,-0.66)
C603H38
  custom 0.197x0.197 smd: 1(0,0.66) 2(0,-0.66)
C603H40
  custom 0.197x0.197 smd: 1(0,0.66) 2(0,-0.66)
C805H54
  rect 1.549x0.94 smd: 1(0,0.838) 2(0,-0.838)
C805H56
  rect 1.549x0.94 smd: 1(0,0.838) 2(0,-0.838)
C805H58
  rect 1.549x0.94 smd: 1(0,0.838) 2(0,-0.838)
C1206H71
  rect 1.854x1.27 smd: 1(0,1.397) 2(0,-1.397)
C1808H56
  rect 2.286x1.27 smd: 1(0,2.032) 2(0,-2.032)
CON2O-U
  custom 0.159x0.159 smd: 1(0,0.254) 2(0,-0.254)
CS1S-461HN
  round 0.254 hole 1.168 unplated: (-11.5,0)
  round 0.254 hole 1.651 unplated: (9.5,0)
  rect 0.991x1.499 smd: 1(6.88,2.75) 2(4.38,2.75) 3(1.88,2.75) 4(-0.62,2.75) 5(-3.12,2.75) 6(-5.62,2.75) 7(-8.04,2.75) 8(-9.74,2.75) 9(9.38,2.75)
  rect 0.711x1.499 smd: 10(-11.04,2.75) 11(-12.24,2.75)
  rect 1.397x2.794 smd: 12(11.5,1) 13(-13.7,1)
  oval 1.321x4.013 hole 0.61x3.302: 14(13.15,-8.85) 15(-13.15,-8.85)
CT7343H83
  rect 2.413x2.286 smd: 1(0,3.15) 2(0,-3.15)
D5436AKH97
  rect 2.286x2.032 smd: A(0,2.438) K(0,-2.438)
DFN9J2015H32
  rect 0.203x0.787 smd: 1(0.6,0.737) 2(0.2,0.737) 7(0.2,-0.737) 8(0.6,-0.737)
  rect 0.61x1.016 smd: 3(-0.4,0.623) 6(-0.4,-0.623)
  rect 0.025x0.025 smd: 4(-0.6,0.737) 5(-0.6,-0.737)
  rect 1.041x0.203 smd: 9(0.86,0)
DFN10G3-G265175H32
  rect 0.305x0.914 smd: 1(1,1.549) 2(0.5,1.549) 3(0,1.549) 4(-0.5,1.549) 5(-1,1.549) 6(-1,-1.549) 7(-0.5,-1.549) 8(0,-1.549) 9(0.5,-1.549) 10(1,-1.549)
  rect 2.642x1.753 smd: 11(0,0)
DFN10G2510H26
  rect 0.305x0.787 smd: 1(1,0.494) 5(-1,0.494) 6(-1,-0.494) 10(1,-0.494)
  rect 0.254x0.787 smd: 2(0.521,0.494) 4(-0.521,0.494) 7(-0.521,-0.494) 9(0.521,-0.494)
  rect 0.025x0.025 smd: 3(0,0.494)
  rect 0.406x1.753 smd: 8(0,-0.494)
FL4S030HT6R300-DT
  rect 0.305x1.295 smd: 1(-11.6,5.65) 2(-10.8,5.65) 3(-10,5.65) 4(-9.2,5.65) 5(-8.4,5.65) 6(-7.6,5.65) 7(-6.8,5.65) 8(-6,5.65) 9(-5.2,5.65) 10(-4.4,5.65) 11(-3.6,5.65) 12(-2.8,5.65) 13(-2,5.65) 14(-1.2,5.65) 15(-0.4,5.65) 16(0.4,5.65) 17(1.2,5.65) 18(2,5.65) 19(2.8,5.65) 20(3.6,5.65) 21(4.4,5.65) 22(5.2,5.65) 23(6,5.65) 24(6.8,5.65) 25(7.6,5.65) 26(8.4,5.65) 27(9.2,5.65) 28(10,5.65) 29(10.8,5.65) 30(11.6,5.65)
  rect 1.803x2.21 smd: 31(-13.94,0) 32(13.94,0)
GAP-CLOSE-PWR
  rect 0.66x0.762 smd: 1(-0.305,0) 2(0.305,0)
GAP-CLOSE-PWR-3
  rect 0.66x0.762 smd: 1(-0.305,0) 2(0.305,0)
HOLE197R166
  round 5.004 hole 4.216: 1(0,0)
HOLE256R126
  round 6.502 hole 3.2: 1(0,0)
HOLE296R182
  round 7.518 hole 4.623: 1(0,0)
HOLE335R115
  round 8.509 hole 2.921: 1(0,0)
L603H38
  custom 0.197x0.197 smd: 1(0,0.66) 2(0,-0.66)
L603H40
  custom 0.197x0.197 smd: 1(0,0.66) 2(0,-0.66)
L1608-UH38
  custom 0.197x0.197 smd: 1(0,0.66) 2(0,-0.66)
L2520-D820H41
  rect 2.261x1.422 smd: 1(0,0.907) 2(0,-0.907)
L115100-275300H158
  rect 3.505x3.886 smd: 1(0,4.562) 2(0,-4.562)
L125100-4P-1H28
  rect 0.762x0.432 smd: 1(0.625,0.341) 2(-0.625,0.341) 3(-0.625,-0.341) 4(0.625,-0.341)
L686647H119
  rect 2.159x3.429 smd: 1(-3.111,0) 2(3.111,0)
L736630-MH119
  rect 3.302x2.388 smd: 1(0,2.894) 2(0,-2.894)
L736630H119
  rect 3.251x2.743 smd: 1(0,2.819) 2(0,-2.819)
LED3015-1A2K-3PH44
  rect 0.813x0.991 smd: 1A(0,1.4) 2K(0,-1.4)
  rect 0.61x0.991 smd: 3(0.4,0)
LED3020-3P-6H44
  rect 0.991x1.499 smd: 1(1.495,0) 3(-1.495,0)
  rect 0.889x0.889 smd: 2(0,-0.65)
LQFP128H63
  rect 0.203x1.524 smd: 1(6.2,7.747) 2(5.8,7.747) 3(5.4,7.747) 4(5,7.747) 5(4.6,7.747) 6(4.2,7.747) 7(3.8,7.747) 8(3.4,7.747) 9(3,7.747) 10(2.6,7.747) 11(2.2,7.747) 12(1.8,7.747) 13(1.4,7.747) 14(0.999,7.747) 15(0.599,7.747) 16(0.199,7.747) 17(-0.199,7.747) 18(-0.599,7.747) 19(-0.999,7.747) 20(-1.4,7.747) 21(-1.8,7.747) 22(-2.2,7.747) 23(-2.6,7.747) 24(-3,7.747) 25(-3.4,7.747) 26(-3.8,7.747) 27(-4.2,7.747) 28(-4.6,7.747) 29(-5,7.747) 30(-5.4,7.747) 31(-5.8,7.747) 32(-6.2,7.747) 65(-6.2,-7.747) 66(-5.8,-7.747) 67(-5.4,-7.747) 68(-5,-7.747) 69(-4.6,-7.747) 70(-4.2,-7.747) 71(-3.8,-7.747) 72(-3.4,-7.747) 73(-3,-7.747) 74(-2.6,-7.747) 75(-2.2,-7.747) 76(-1.8,-7.747) 77(-1.4,-7.747) 78(-0.999,-7.747) 79(-0.599,-7.747) 80(-0.199,-7.747) 81(0.199,-7.747) 82(0.599,-7.747) 83(0.999,-7.747) 84(1.4,-7.747) 85(1.8,-7.747) 86(2.2,-7.747) 87(2.6,-7.747) 88(3,-7.747) 89(3.4,-7.747) 90(3.8,-7.747) 91(4.2,-7.747) 92(4.6,-7.747) 93(5,-7.747) 94(5.4,-7.747) 95(5.8,-7.747) 96(6.2,-7.747)
  rect 1.524x0.203 smd: 33(-7.747,6.2) 34(-7.747,5.8) 35(-7.747,5.4) 36(-7.747,5) 37(-7.747,4.6) 38(-7.747,4.2) 39(-7.747,3.8) 40(-7.747,3.4) 41(-7.747,3) 42(-7.747,2.6) 43(-7.747,2.2) 44(-7.747,1.8) 45(-7.747,1.4) 46(-7.747,0.999) 47(-7.747,0.599) 48(-7.747,0.199) 49(-7.747,-0.199) 50(-7.747,-0.599) 51(-7.747,-0.999) 52(-7.747,-1.4) 53(-7.747,-1.8) 54(-7.747,-2.2) 55(-7.747,-2.6) 56(-7.747,-3) 57(-7.747,-3.4) 58(-7.747,-3.8) 59(-7.747,-4.2) 60(-7.747,-4.6) 61(-7.747,-5) 62(-7.747,-5.4) 63(-7.747,-5.8) 64(-7.747,-6.2) 97(7.747,-6.2) 98(7.747,-5.8) 99(7.747,-5.4) 100(7.747,-5) 101(7.747,-4.6) 102(7.747,-4.2) 103(7.747,-3.8) 104(7.747,-3.4) 105(7.747,-3) 106(7.747,-2.6) 107(7.747,-2.2) 108(7.747,-1.8) 109(7.747,-1.4) 110(7.747,-0.999) 111(7.747,-0.599) 112(7.747,-0.199) 113(7.747,0.199) 114(7.747,0.599) 115(7.747,0.999) 116(7.747,1.4) 117(7.747,1.8) 118(7.747,2.2) 119(7.747,2.6) 120(7.747,3) 121(7.747,3.4) 122(7.747,3.8) 123(7.747,4.2) 124(7.747,4.6) 125(7.747,5) 126(7.747,5.4) 127(7.747,5.8) 128(7.747,6.2)
MSOP8-1G189157H43
  rect 0.356x1.524 smd: 1(-0.975,-2.059) 2(-0.325,-2.059) 3(0.325,-2.059) 4(0.975,-2.059) 5(0.975,2.059) 6(0.325,2.059) 7(-0.325,2.059) 8(-0.975,2.059)
  rect 1.88x1.575 smd: 9(0,0)
MSOP8-1H44
  rect 0.356x1.524 smd: 1(-0.975,-2.055) 2(-0.325,-2.055) 3(0.325,-2.055) 4(0.975,-2.055) 5(0.975,2.055) 6(0.325,2.055) 7(-0.325,2.055) 8(-0.975,2.055)
NTC-402H22-U
  custom 0.14x0.14 smd: 1(0,0.445) 2(0,-0.445)
NTC-603H38
  custom 0.216x0.216 smd: 1(0,0.762) 2(0,-0.762)
OSC-3225-4P-4H30
  rect 1.397x1.067 smd: 1(-1.171,-0.756) 2(1.171,-0.756) 3(1.171,0.756) 4(-1.171,0.756)
OSC-3225-4P-4H36
  rect 1.397x1.067 smd: 1(-1.171,-0.756) 2(1.171,-0.756) 3(1.171,0.756) 4(-1.171,0.756)
PAD-10P-177042
  rect 0.813x1.6 smd: 1(-5.625,2.899) 2(-4.375,2.899) 3(-3.125,2.899) 4(-1.875,2.899) 5(-0.625,2.899) 6(0.625,2.899) 7(1.875,2.899) 8(3.125,2.899) 9(4.375,2.899) 10(5.625,2.899)
  rect 2.134x2.997 smd: 11(-8.175,0) 12(8.175,0)
PAD-D-SUB-HDMI-COLAY-U
  round 0.254 hole 1.422 unplated: (-8.9,6.45) (8.9,6.45)
  round 0.914 hole 0.61: 1(-4.33,9.65) 2(-2.04,9.65) 3(0.25,9.65) 4(2.54,9.65) 5(4.83,9.65) 6(-5.475,9.65) 7(-3.185,9.65) 8(-0.895,9.65) 9(1.395,9.65) 10(3.685,9.65)
  round 0.965 hole 0.61: 11(-4.33,11.05) 12(-2.04,11.05) 13(0.25,11.05) 14(2.54,11.05) 15(4.83,11.05)
  oval 0.762x0.914 hole 0.508: HP1(-4.5,5.75) HP2(-4,7.25) HP3(-3.5,5.75) HP4(-3,7.25) HP5(-2.5,5.75) HP6(-2,7.25) HP7(-1.5,5.75) HP8(-1,7.25) HP9(-0.5,5.75) HP10(0,7.25) HP11(0.5,5.75) HP12(1,7.25) HP13(1.5,5.75) HP14(2,7.25) HP15(2.5,5.75) HP16(3,7.25) HP17(3.5,5.75) HP18(4,7.25) HP19(4.5,5.75)
  oval 1.422x3.124 hole 0.711x2.413: PTH1(10.95,9.35) PTH4(10.95,1.35) PTH7(-10.95,9.35) PTH10(-10.95,1.35)
  oval 1.626x2.413 hole 0.914x1.702: PTH2(10.75,6.1) PTH9(-10.75,6.1)
  custom 0.404x0.404 hole 0.914x1.803: PTH3(7.25,6.45) PTH8(-7.25,6.45)
  oval 1.575x2.515 hole 0.914x1.803: PTH5(9.15,0) PTH11(-9.15,0)
  oval 1.626x2.997 hole 0.914x2.413: PTH6(10.8,-1.9) PTH12(-10.8,-1.9)
POLYSW-2114H30
  rect 1.6x0.965 smd: 1(0,0.94) 2(0,-0.94)
POLYSW-2114H50
  rect 1.6x0.965 smd: 1(0,0.94) 2(0,-0.94)
POLYSW-4633-UH63
  rect 3.505x1.626 smd: 1(0,1.834) 2(0,-1.834)
PPAK-5PH45
  rect 0.762x1.524 smd: 1(-1.905,-3.81) 2(-0.635,-3.81) 3(0.635,-3.81) 4(1.905,-3.81)
  rect 5.283x5.08 smd: 5(0,0)
  rect 0.025x0.025 smd: 6(0.635,2.032) 7(-0.635,2.032) 8(-1.905,2.032)
PPAK-8P-2H45
  rect 0.406x1.168 smd: 1(-0.975,-2.351) 2(-0.325,-2.351) 3(0.325,-2.351) 4(0.975,-2.351)
  rect 3.404x2.769 smd: 5(0,0)
  rect 0.025x0.025 smd: 6(1.029,0.902) 7(0.013,0.902) 8(-0.991,0.902)
PPAK-8P-G5324H44-COLAY
  rect 0.762x1.016 smd: 1(-1.905,-3.01) 2(-0.635,-3.01) 3(0.635,-3.01) 4(1.905,-3.01) 5(1.905,3.01) 6(0.635,3.01) 7(-0.635,3.01) 8(-1.905,3.01)
  rect 5.207x2.896 smd: 9(0,0.65)
  rect 5.207x0.787 smd: 10(0,-1.7)
QFN20-G1D75H32
  rect 0.203x0.914 smd: 1(0.8,1.551) 2(0.4,1.551) 3(0,1.551) 4(-0.4,1.551) 5(-0.8,1.551) 11(-0.8,-1.551) 12(-0.4,-1.551) 13(0,-1.551) 14(0.4,-1.551) 15(0.8,-1.551)
  rect 0.914x0.203 smd: 6(-1.551,0.8) 7(-1.551,0.4) 8(-1.551,0) 9(-1.551,-0.4) 10(-1.551,-0.8) 16(1.551,-0.8) 17(1.551,-0.4) 18(1.551,0) 19(1.551,0.4) 20(1.551,0.8)
  rect 1.753x1.753 smd: 21(0,0)
QFN20G3D5-G2D15H40
  rect 0.305x0.914 smd: 1(1,1.801) 5(-1,1.801) 11(-1,-1.801) 15(1,-1.801)
  rect 0.305x0.965 smd: 2(0.5,1.775) 3(0,1.775) 4(-0.5,1.775) 12(-0.5,-1.775) 13(0,-1.775) 14(0.5,-1.775)
  rect 0.914x0.305 smd: 6(-1.801,1) 10(-1.801,-1) 16(1.801,-1) 20(1.801,1)
  rect 0.965x0.305 smd: 7(-1.775,0.5) 8(-1.775,0) 9(-1.775,-0.5) 17(1.775,-0.5) 18(1.775,0) 19(1.775,0.5)
  rect 2.159x2.159 smd: 21(0,0)
QFN20G4030-G275175H40
  rect 0.305x0.914 smd: 1(1.25,1.551) 2(0.75,1.551) 3(0.25,1.551) 4(-0.25,1.551) 5(-0.75,1.551) 6(-1.25,1.551) 11(-1.25,-1.551) 12(-0.75,-1.551) 13(-0.25,-1.551) 14(0.25,-1.551) 15(0.75,-1.551) 16(1.25,-1.551)
  rect 0.914x0.305 smd: 7(-2.051,0.75) 8(-2.051,0.25) 9(-2.051,-0.25) 10(-2.051,-0.75) 17(2.051,-0.75) 18(2.051,-0.25) 19(2.051,0.25) 20(2.051,0.75)
  rect 2.743x1.753 smd: 21(0,0)
QFN24-G2D5H40-U
  rect 0.305x0.838 smd: 1(1.25,2.095) 6(-1.25,2.095) 13(-1.25,-2.095) 18(1.25,-2.095)
  rect 0.305x0.965 smd: 2(0.751,2.032) 3(0.25,2.032) 4(-0.25,2.032) 5(-0.751,2.032) 14(-0.751,-2.032) 15(-0.25,-2.032) 16(0.25,-2.032) 17(0.751,-2.032)
  rect 0.838x0.305 smd: 7(-2.095,1.25) 12(-2.095,-1.25) 19(2.095,-1.25) 24(2.095,1.25)
  rect 0.965x0.305 smd: 8(-2.032,0.751) 9(-2.032,0.25) 10(-2.032,-0.25) 11(-2.032,-0.751) 20(2.032,-0.751) 21(2.032,-0.25) 22(2.032,0.25) 23(2.032,0.751)
  rect 2.489x2.489 smd: 25(0,0)
QFN32-G3D6H40
  rect 0.305x0.914 smd: 1(1.75,2.559) 8(-1.75,2.559) 17(-1.75,-2.559) 24(1.75,-2.559)
  rect 0.305x1.016 smd: 2(1.25,2.508) 3(0.75,2.508) 4(0.25,2.508) 5(-0.25,2.508) 6(-0.75,2.508) 7(-1.25,2.508) 18(-1.25,-2.508) 19(-0.75,-2.508) 20(-0.25,-2.508) 21(0.25,-2.508) 22(0.75,-2.508) 23(1.25,-2.508)
  rect 0.914x0.305 smd: 9(-2.559,1.75) 16(-2.559,-1.75) 25(2.559,-1.75) 32(2.559,1.75)
  rect 1.016x0.305 smd: 10(-2.508,1.25) 11(-2.508,0.75) 12(-2.508,0.25) 13(-2.508,-0.25) 14(-2.508,-0.75) 15(-2.508,-1.25) 26(2.508,-1.25) 27(2.508,-0.75) 28(2.508,-0.25) 29(2.508,0.25) 30(2.508,0.75) 31(2.508,1.25)
  rect 3.556x3.556 smd: 33(0,0)
QFN32J4-G2D85H36
  rect 0.203x0.864 smd: 1(1.4,2.085) 2(1,2.085) 3(0.6,2.085) 4(0.2,2.085) 5(-0.2,2.085) 6(-0.6,2.085) 7(-1,2.085) 8(-1.4,2.085) 17(-1.4,-2.085) 18(-1,-2.085) 19(-0.6,-2.085) 20(-0.2,-2.085) 21(0.2,-2.085) 22(0.6,-2.085) 23(1,-2.085) 24(1.4,-2.085)
  rect 0.864x0.203 smd: 9(-2.085,1.4) 10(-2.085,1) 11(-2.085,0.6) 12(-2.085,0.2) 13(-2.085,-0.2) 14(-2.085,-0.6) 15(-2.085,-1) 16(-2.085,-1.4) 25(2.085,-1.4) 26(2.085,-1) 27(2.085,-0.6) 28(2.085,-0.2) 29(2.085,0.2) 30(2.085,0.6) 31(2.085,1) 32(2.085,1.4)
  rect 2.845x2.845 smd: 33(0,0)
QFN48J6-G465H40
  rect 0.203x0.965 smd: 1(2.2,3.025) 2(1.8,3.025) 3(1.4,3.025) 4(1,3.025) 5(0.6,3.025) 6(0.2,3.025) 7(-0.2,3.025) 8(-0.6,3.025) 9(-1,3.025) 10(-1.4,3.025) 11(-1.8,3.025) 12(-2.2,3.025) 25(-2.2,-3.025) 26(-1.8,-3.025) 27(-1.4,-3.025) 28(-1,-3.025) 29(-0.6,-3.025) 30(-0.2,-3.025) 31(0.2,-3.025) 32(0.6,-3.025) 33(1,-3.025) 34(1.4,-3.025) 35(1.8,-3.025) 36(2.2,-3.025)
  rect 0.965x0.203 smd: 13(-3.025,2.2) 14(-3.025,1.8) 15(-3.025,1.4) 16(-3.025,1) 17(-3.025,0.6) 18(-3.025,0.2) 19(-3.025,-0.2) 20(-3.025,-0.6) 21(-3.025,-1) 22(-3.025,-1.4) 23(-3.025,-1.8) 24(-3.025,-2.2) 37(3.025,-2.2) 38(3.025,-1.8) 39(3.025,-1.4) 40(3.025,-1) 41(3.025,-0.6) 42(3.025,-0.2) 43(3.025,0.2) 44(3.025,0.6) 45(3.025,1) 46(3.025,1.4) 47(3.025,1.8) 48(3.025,2.2)
  rect 4.648x4.648 smd: 49(0,0)
R402H14
  custom 0.14x0.14 smd: 1(0,0.445) 2(0,-0.445)
R402H16
  custom 0.14x0.14 smd: 1(0,0.445) 2(0,-0.445)
R603H22
  custom 0.197x0.197 smd: 1(0,0.66) 2(0,-0.66)
R805H24
  rect 1.549x0.94 smd: 1(0,0.838) 2(0,-0.838)
R1206H28
  rect 1.854x1.27 smd: 1(0,1.397) 2(0,-1.397)
R3720H40
  rect 4.013x1.041 smd: 1(0,0.867) 2(0,-0.867)
SC70-5-1H44
  rect 0.356x1.219 smd: 1(-0.65,-0.922) 2(0,-0.922) 3(0.65,-0.922) 4(0.65,0.921) 5(-0.65,0.921)
SC70-5H44
  rect 0.406x1.219 smd: 1(0.65,0.826) 2(0,0.826) 3(-0.65,0.826) 4(-0.65,-0.826) 5(0.65,-0.826)
SC70-6H44
  rect 0.406x1.016 smd: 1(-0.65,-0.94) 2(0,-0.94) 3(0.65,-0.94) 4(0.65,0.94) 5(0,0.94) 6(-0.65,0.94)
SE361413H182
  rect 1.372x3.556 smd: 1(0,2.424) 2(0,-2.424)
SE361414H178
  rect 1.372x3.607 smd: 1(0,2.499) 2(0,-2.499)
SE361416H178
  rect 1.422x3.556 smd: 1(0,2.574) 2(0,-2.574)
SKT-USB13-160166-2
  round 1.067 hole 0.711: 1(3.5,9.2) 2(1,9.2) 3(-1,9.2) 4(-3.5,9.2) 5(-4,7.7) 6(-2,7.7) 7(0,7.7) 8(2,7.7) 9(4,7.7)
  oval 1.422x2.997 hole 0.711x2.286: 10(6.4,8.45) 11(-6.4,8.45)
  oval 1.626x2.235 hole 0.914x1.524: 12(7.85,0) 13(-7.85,0)
SMD49-6914-0403H56
  rect 1.168x0.559 smd: 1(-3.38,-0.427) 2(3.38,-0.427) 3(3.38,0.427) 4(-3.38,0.427)
SMD-ARES4H18
  rect 0.356x0.66 smd: 1(-0.325,-0.599) 2(0.325,-0.599) 3(0.325,0.599) 4(-0.325,0.599)
SMD-ARES4H20
  rect 0.356x0.66 smd: 1(-0.325,-0.599) 2(0.325,-0.599) 3(0.325,0.599) 4(-0.325,0.599)
SOD123FLAKH40
  rect 1.143x1.651 smd: A(0,1.622) K(0,-1.622)
SOD323AKH38
  rect 0.559x1.016 smd: A(0,1.143) K(0,-1.143)
SOD323AKH40
  rect 0.559x1.016 smd: A(0,1.143) K(0,-1.143)
SOD323AKH42
  rect 0.559x1.016 smd: A(0,1.143) K(0,-1.143)
SOD723AKH27
  rect 0.559x0.813 smd: A(0,0.686) K(0,-0.686)
SOD882-10D6-1H20
  custom 0.114x0.114 smd: 1(0,0.445) 2(0,-0.445)
SOIC8-1H86
  rect 0.635x1.651 smd: 1(-1.905,-3.493) 2(-0.635,-3.493) 3(0.635,-3.493) 4(1.905,-3.493) 5(1.905,3.493) 6(0.635,3.493) 7(-0.635,3.493) 8(-1.905,3.493)
SOIC8H69
  rect 0.635x1.651 smd: 1(-1.905,-2.54) 2(-0.635,-2.54) 3(0.635,-2.54) 4(1.905,-2.54) 5(1.905,2.54) 6(0.635,2.54) 7(-0.635,2.54) 8(-1.905,2.54)
SON14J3020-G2610H32
  rect 0.025x0.025 smd: 1(1.2,1.105) 6(-0.8,1.105) 9(-0.8,-1.105) 14(1.2,-1.105)
  custom 0.151x0.151 smd: 2(0.8,1.105) 7(-1.2,1.105) 8(-1.2,-1.105) 13(0.8,-1.105)
  rect 0.203x0.813 smd: 3(0.4,1.105) 4(0,1.105) 5(-0.4,1.105) 10(-0.4,-1.105) 11(0,-1.105) 12(0.4,-1.105)
  rect 2.591x0.889 smd: 15(0,0)
SOT23-2D4-312H44
  custom 0.191x0.191 smd: 1(-0.984,-0.953) 2(0.984,-0.953) 3(0,0.953)
SOT23-2D4-312H48
  custom 0.191x0.191 smd: 1(-0.984,-0.953) 2(0.984,-0.953) 3(0,0.953)
SOT23CBE2D4H44
  custom 0.191x0.191 smd: B(-0.984,-0.953) C(0,0.953) E(0.984,-0.953)
SOT23DGS2D4H44
  custom 0.191x0.191 smd: D(0,0.953) G(-0.984,-0.953) S(0.984,-0.953)
SOT23DGS2D4H48
  custom 0.191x0.191 smd: D(0,0.953) G(-0.984,-0.953) S(0.984,-0.953)
SOT323CBE2D2H44
  custom 0.152x0.152 smd: B(-0.65,-0.902) C(0,0.902) E(0.65,-0.902)
SOT-6H58
  rect 0.584x1.016 smd: 1(-0.953,-1.346) 2(0,-1.346) 3(0.953,-1.346) 4(0.953,1.346) 5(0,1.346) 6(-0.953,1.346)
SOT-23-5H51
  rect 0.508x1.524 smd: 1(-0.95,-1.143) 2(0,-1.143) 3(0.95,-1.143) 4(0.95,1.143) 5(-0.95,1.143)
SOT-23-5H52
  rect 0.508x1.524 smd: 1(-0.95,-1.143) 2(0,-1.143) 3(0.95,-1.143) 4(0.95,1.143) 5(-0.95,1.143)
SOT-23-5H58
  rect 0.508x1.524 smd: 1(-0.95,-1.143) 2(0,-1.143) 3(0.95,-1.143) 4(0.95,1.143) 5(-0.95,1.143)
SOT-23-9H44
  custom 0.178x0.178 smd: 1(-0.95,-0.999) 2(0.95,-0.999) 3(0,0.999)
SOT-23-10H44
  rect 0.762x1.143 smd: 1(-0.984,-0.953) 2(0.984,-0.953) 3(0,0.953)
SOT-23-13H51
  rect 0.66x1.321 smd: 1(-0.999,-0.978) 2(0.999,-0.978) 3(0,0.978)
SOT-363H44
  rect 0.406x1.016 smd: 1(-0.65,-0.94) 2(0,-0.94) 3(0.65,-0.94) 4(0.65,0.94) 5(0,0.94) 6(-0.65,0.94)
SPR5230H134
  rect 4.902x2.692 smd: 1(-1.499,0)
SPR7345H154
  rect 6.985x4.191 smd: 1(-1.6,0)
SPR7837H229
  rect 7.493x3.353 smd: 1(-2.095,0)
STF237R117H81
  round 6.02 hole 2.972: 1(0,0)
TPAD14-OP
  round 0.356 smd: 1(0,0)
TVS10D6-D3D5-1H13
  custom 0.152x0.152 smd: 1(0,0.445) 2(0,-0.445)
unnamed
  round 0.254 hole 4.013 unplated: (0,0)
XFORM12A127097H91
  rect 0.635x1.524 smd: 1(-4.445,-4.699) 2(-3.175,-4.699) 3(-1.905,-4.699) 4(1.905,-4.699) 5(3.175,-4.699) 6(4.445,-4.699) 7(4.445,4.699) 8(3.175,4.699) 9(1.905,4.699) 10(-1.905,4.699) 11(-3.175,4.699) 12(-4.445,4.699)

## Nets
3V3_AON_S0: C7315.1 C7316.1 C7324.1 C7704.1 C7735.1 C7736.1 C8307.1 C8308.1 GPU1.AA8 GPU1.AA9 GPU1.AB8 GPU1.G10 GPU1.G12 PG8312.2 PR8203.1 PR8258.1 Q7301.G Q7602.2 Q7606.G R7303.2 R7312.1 R7605.1 R7606.1 R7612.2 R7615.1 R7617.1 R7624.2 R7625.1 R7631.1 R7633.1 R7634.1 R7635.1 R7643.2 R7645.1 R7646.1 R7649.2 R8304.1 R8315.1 RN7601.3(B) RN7601.4(B) RN7603.1(A) RN7603.2(A) RN7604.1(A) RN7604.2(A) RN7605.1(A) RN7605.2(A) U7301.5
3V5V_CT1: C3602.1 U3601.12
3V5V_CT2: C3601.1 U3601.10
3V5V_S0_ON: R3609.2 U3601.3 U3601.5
3V_5V_EN: D3602.1 PR4506.1 PR4507.1 R3602.1 R3603.1
3V_5V_POK: PR4534.2 PU4503.7 R1728.2
3V_5V_POK#: Q1701.5 Q1701.6 R1726.1
3V_5V_POK_C: Q1701.2 R1727.2 R1728.1 R1729.1
3V_FEEDBACK: PG4535.2 PR4512.1 PR4535.1
5V_HDD_S0: AFTP5601.1 C5605.1 C5606.1 HDD1.1 HDD1.2 HDD1.3 R5601.2
5V_HDMI_CRT_S0: D5501.K F5501.2 R5409.2 RN5501.3(B) RN5501.4(B)
5V_HDMI_CRT_S0_R: AFTP5504.1 C5401.1 C5519.1 F5501.1 HDMI1.9 HDMI1.HP18
5V_PWR: PC4515.1 PC4518.1 PD4503.1 PG4519.2 PG4523.2 PG4527.2 PG4532.1 PG4533.2 PG4537.2 PG4538.2 PG4540.2 PG4541.2 PG4544.2 PG4545.2 PL4501.2 PT4501.1
5V_PWR_2: PC4524.1 PU4503.13
5V_S0: C2605.1 C2611.1 C3603.1 C5601.1 C5604.1 C5609.1 D5401.3 D5501.A EC9718.1 EC9719.1 EC9720.1 EC9721.1 EC9722.1 EC9723.1 EC9724.1 F6201.1 FAN261.2 PC4604.1 PR8223.1 PU4601.12 Q5403.G Q6104.E Q6201.E R2702.1 R2703.2 R2704.1 R5230.1 R5409.1 R5413.1 R5601.1 R5603.1 R6205.1 R6216.1 U3601.13 U3601.14 U5601.2 U5601.3 U8301.4
5V_S5: C3504.1 C3510.1 EC9732.1 EC9733.1 EC9734.1 PC4815.1 PC4901.1 PG4519.1 PG4523.1 PG4527.1 PG4533.1 PG4537.1 PG4538.1 PG4540.1 PG4541.1 PG4544.1 PG4545.1 PR4203.1 PU4806.7 PU4901.12 Q6101.E Q6102.E R1208.1 U2101.1 U3504.5 U3505.5 U3601.1 U3601.2 U3601.4
15V_PWR: PC4533.1 PD4501.K PD4502.2 PG4530.2
15V_S5: PG4530.1 PR4471.2 PR8310.2
+3V_1D5V_AVDD: C2715.1 HDA27.40 R2705.2 R2710.2
+3V_AVDD: C2701.1 C2716.1 C2717.1 C2719.1 HDA27.1 HDA27.9 HDA27.36 R2701.2 R2722.1
+5V_AVDD: C2710.1 C2711.1 HDA27.26 R2703.1
+5V_KB_BL: AFTP6248.1 C6202.1 EC6208.1 F6201.2 KB_BL1.1 R6205.2
+5V_PVDD: C2706.1 C2707.1 C2708.1 C2709.1 HDA27.41 HDA27.46 R2702.2 R2704.2
+V1.05A_AOSCSUS: CPU1.AB8 TP2109.1
+V1.05A_SUS_PCH: CPU1.AD8 CPU1.AD10 TP2106.1
+V1.05A_USB2SUS: CPU1.AH13 TP2108.1
+V1.05A_VCCUSB3SUS: CPU1.J13 TP2107.1
+V1.05DX_MODPHY_PCH: C1101.1 C1102.1 CPU1.K9 CPU1.L10 CPU1.M9 R1101.2
+V1.05S_AIDLE: C2105.1 CPU1.N8 CPU1.P9 R2105.2
+V1.05S_APLLOPI: C1109.1 C1110.1 C1124.1 CPU1.AA21 CPU1.W21 R1102.2
+V1.05S_ASATA3PLL: C1105.1 C1106.1 C1107.1 CPU1.B11 L1102.2 R1904.2 R1906.2
+V1.05S_AUSB3PLL: C1103.1 C1104.1 C1123.1 CPU1.B18 CPU1.B27 L1101.2 R1601.1
+V1.05S_AXCK_DCB: C1111.1 C1112.1 C1125.1 CPU1.J18 CPU1.K19 L1103.2
+V1.05S_AXCK_LCPLL: C1113.1 C1114.1 CPU1.A20 L1104.2 R1803.2
+V1.05S_CORE_PCH: C1117.1 C1118.1 C1119.1 CPU1.AE8 CPU1.AF22 CPU1.H11 CPU1.H15 CPU1.J11 R1105.2
+V1.05S_SSCF100: C2137.1 CPU1.J17 R2117.2
+V1.05S_SSCFF: C2138.1 CPU1.R21 CPU1.T21 R2118.2
+V3.3A_1.5A_HDA: C2116.1 CPU1.AH14 R2108.2
+V3.3A_DSW_P: C2101.1 C2136.1 CPU1.AH10 R2101.2
+V3.3A_PSUS: C1108.1 CPU1.AA9 CPU1.AC9 CPU1.AE20 CPU1.AE21 R1103.2
+V3.3S_1.8S_LPSS_SDIO: C2104.1 CPU1.T9 CPU1.U8 R2103.1
+V3.3S_PCORE: C2123.1 CPU1.V8 CPU1.W9 R2112.2
+VCCIOA_OUT: CPU1.E20 R801.1
+VCCRTCEXT: C2110.1 CPU1.AE7
AVCC33: C5517.1 C5523.2 R5504.2 U5502.24
GND: AFTP2501.1 AFTP2803.1 AFTP3301.1 AFTP3906.1 AFTP3909.1 AFTP3910.1 AFTP6102.1 AFTP6201.1 AFTP6217.1 AFTP6235.1 AFTP6245.1 AFTP6314.1 BATT1.7 BATT1.8 BATT1.9 BATT1.10 C701.2 C702.2 C703.2 C1001.2 C1002.2 C1003.2 C1004.2 C1005.2 C1006.2 C1017.2 C1018.2 C1019.2 C1020.2 C1101.2 C1102.2 C1103.2 C1104.2 C1105.2 C1106.2 C1107.2 C1108.2 C1109.2 C1110.2 C1111.2 C1112.2 C1113.2 C1114.2 C1115.2 C1116.2 C1117.2 C1118.2 C1119.2 C1120.2 C1121.2 C1122.2 C1123.2 C1124.2 C1125.2 C1201.2 C1202.2 C1203.2 C1204.2 C1205.2 C1206.2 C1207.2 C1208.2 C1209.2 C1210.2 C1211.2 C1212.2 C1213.2 C1214.2 C1215.2 C1216.2 C1217.2 C1218.2 C1220.2 C1221.2 C1222.2 C1301.2 C1302.2 C1303.2 C1304.2 C1305.2 C1306.2 C1307.2 C1308.2 C1309.2 C1310.2 C1311.2 C1312.2 C1313.2 C1314.2 C1315.2 C1316.2 C1317.2 C1318.2 C1319.2 C1320.2 C1321.2 C1701.2 C1801.1 C1802.1 C1901.2 C1902.2 C1903.1 C1904.1 C2104.2 C2105.2 C2109.2 C2110.2 C2114.2 C2116.2 C2123.2 C2128.2 C2135.2 C2136.2 C2137.2 C2138.2 C2141.2 C2142.2 C2147.2 C2401.2 C2406.2 C2407.2 C2408.2 C2409.2 C2410.2 C2411.2 C2412.2 C2413.2 C2415.1 C2416.2 C2418.2 C2421.2 C2422.2 C2501.2 C2502.2 C2503.2 C2601.2 C2602.2 C2603.2 C2604.2 C2605.2 C2608.2 C2609.2 C2610.2 C2611.2 C2701.2 C2704.1 C2706.2 C2707.2 C2708.2 C2709.2 C2716.2 C2717.2 C2718.2 C2719.2 C2723.1 C3001.2 C3002.2 C3003.2 C3004.2 C3005.2 C3007.2 C3008.2 C3009.2 C3010.2 C3011.2 C3012.2 C3013.2 C3017.2 C3018.2 C3019.2 C3021.2 C3022.2 C3023.2 C3024.2 C3025.2 C3101.2 C3106.2 C3201.1 C3202.2 C3203.2 C3204.2 C3205.2 C3206.2 C3301.2 C3302.2 C3303.2 C3405.2 C3406.2 C3504.2 C3507.2 C3508.2 C3510.2 C3512.2 C3513.2 C3515.2 C3517.2 C3518.2 C3601.2 C3602.2 C3603.2 C3604.2 C3605.2 C3801.2 C3802.2 C5201.2 C5202.2 C5204.2 C5205.1 C5206.1 C5207.2 C5208.2 C5214.2 C5401.2 C5501.2 C5502.2 C5503.2 C5504.2 C5506.2 C5507.2 C5509.2 C5510.2 C5511.2 C5512.2 C5513.2 C5514.2 C5516.2 C5517.2 C5518.2 C5519.2 C5520.2 C5521.1 C5522.2 C5523.1 C5524.2 C5601.2 C5604.2 C5605.2 C5606.2 C5609.2 C5610.2 C5801.2 C5802.2 C5803.2 C5804.2 C5805.2 C5806.2 C6201.2 C6202.2 C6203.2 C7310.2 C7312.2 C7315.2 C7316.2 C7317.2 C7318.2 C7319.2 C7323.2 C7324.2 C7326.2 C7501.2 C7502.2 C7505.2 C7506.2 C7507.2 C7508.2 C7509.2 C7510.2 C7512.2 C7513.2 C7514.2 C7517.1 C7518.2 C7520.2 C7522.2 C7523.2 C7524.2 C7525.2 C7529.2 C7532.2 C7533.2 C7534.2 C7601.2 C7602.2 C7603.2 C7604.2 C7605.2 C7606.2 C7607.1 C7608.1 C7609.2 C7610.2 C7701.2 C7702.2 C7703.2 C7704.2 C7708.2 C7709.2 C7710.2 C7711.2 C7712.2 C7713.2 C7714.2 C7717.2 C7719.2 C7720.2 C7721.2 C7722.2 C7723.2 C7724.2 C7725.2 C7726.2 C7728.2 C7729.2 C7730.2 C7731.2 C7732.2 C7734.2 C7735.2 C7736.2 C7803.2 C7804.2 C7805.2 C7810.2 C7811.2 C7812.2 C7814.2 C7816.2 C7817.2 C7820.2 C7821.2 C7822.2 C7827.2 C7829.2 C7830.2 C7831.2 C7832.2 C7833.2 C7834.2 C7835.2 C7836.2 C7902.2 C7906.2 C7909.2 C7910.2 C7911.2 C7912.2 C7913.2 C7915.2 C7916.2 C7917.2 C7919.2 C7921.2 C7922.2 C7923.2 C7924.2 C7925.2 C7926.2 C7927.2 C7928.2 C7929.2 C7930.2 C8001.2 C8002.2 C8003.2 C8004.2 C8005.2 C8006.2 C8007.2 C8008.2 C8009.2 C8010.2 C8011.2 C8012.2 C8013.2 C8014.2 C8015.2 C8016.2 C8017.2 C8018.2 C8019.2 C8020.2 C8101.2 C8102.2 C8103.2 C8104.2 C8105.2 C8106.2 C8107.2 C8108.2 C8109.2 C8110.2 C8111.2 C8112.2 C8113.2 C8114.2 C8115.2 C8116.2 C8117.2 C8118.2 C8119.2 C8120.2 C8302.2 C8303.2 C8304.2 C8305.2 C8306.1 C8307.2 C8308.2 C8309.1 C8310.2 C8311.2 C8316.2 C9602.2 CARD1.3 CARD1.6 CARD1.12 CARD1.13 CARD1.14 CARD1.15 CN6301.1 CN6301.2 CN6301.5 CN6301.8 CN6301.25 CN6301.26 CPU1.A11 CPU1.A14 CPU1.A18 CPU1.A24 CPU1.A28 CPU1.A32 CPU1.A36 CPU1.A40 CPU1.A44 CPU1.A48 CPU1.A52 CPU1.A56 CPU1.AA1 CPU1.AA58 CPU1.AB7 CPU1.AB10 CPU1.AB20 CPU1.AB22 CPU1.AC61 CPU1.AD3 CPU1.AD21 CPU1.AD63 CPU1.AE5 CPU1.AE10 CPU1.AE58 CPU1.AF11 CPU1.AF12 CPU1.AF14 CPU1.AF15 CPU1.AF17 CPU1.AF18 CPU1.AG1 CPU1.AG11 CPU1.AG21 CPU1.AG23 CPU1.AG60 CPU1.AG61 CPU1.AG62 CPU1.AG63 CPU1.AH16 CPU1.AH17 CPU1.AH19 CPU1.AH20 CPU1.AH22 CPU1.AH24 CPU1.AH28 CPU1.AH30 CPU1.AH32 CPU1.AH34 CPU1.AH36 CPU1.AH38 CPU1.AH40 CPU1.AH42 CPU1.AH44 CPU1.AH46 CPU1.AH49 CPU1.AH51 CPU1.AH53 CPU1.AH55 CPU1.AH57 CPU1.AJ13 CPU1.AJ14 CPU1.AJ23 CPU1.AJ25 CPU1.AJ27 CPU1.AJ29 CPU1.AJ35 CPU1.AJ39 CPU1.AJ41 CPU1.AJ43 CPU1.AJ45 CPU1.AJ47 CPU1.AJ50 CPU1.AJ52 CPU1.AJ54 CPU1.AJ56 CPU1.AJ58 CPU1.AJ60 CPU1.AJ63 CPU1.AK3 CPU1.AK23 CPU1.AK52 CPU1.AL10 CPU1.AL13 CPU1.AL17 CPU1.AL20 CPU1.AL22 CPU1.AL23 CPU1.AL26 CPU1.AL29 CPU1.AL31 CPU1.AL33 CPU1.AL36 CPU1.AL39 CPU1.AL40 CPU1.AL45 CPU1.AL46 CPU1.AL51 CPU1.AL52 CPU1.AL54 CPU1.AL57 CPU1.AL60 CPU1.AL61 CPU1.AM1 CPU1.AM17 CPU1.AM23 CPU1.AM31 CPU1.AM52 CPU1.AN7 CPU1.AN17 CPU1.AN23 CPU1.AN31 CPU1.AN32 CPU1.AN35 CPU1.AN36 CPU1.AN39 CPU1.AN40 CPU1.AN42 CPU1.AN43 CPU1.AN45 CPU1.AN46 CPU1.AN48 CPU1.AN49 CPU1.AN51 CPU1.AN52 CPU1.AN60 CPU1.AN63 CPU1.AP3 CPU1.AP10 CPU1.AP17 CPU1.AP20 CPU1.AP22 CPU1.AP23 CPU1.AP26 CPU1.AP29 CPU1.AP31 CPU1.AP38 CPU1.AP39 CPU1.AP48 CPU1.AP52 CPU1.AP54 CPU1.AP57 CPU1.AR5 CPU1.AR11 CPU1.AR15 CPU1.AR17 CPU1.AR23 CPU1.AR31 CPU1.AR33 CPU1.AR39 CPU1.AR43 CPU1.AR49 CPU1.AR52 CPU1.AT13 CPU1.AT35 CPU1.AT37 CPU1.AT40 CPU1.AT42 CPU1.AT43 CPU1.AT46 CPU1.AT49 CPU1.AT61 CPU1.AT62 CPU1.AT63 CPU1.AU1 CPU1.AU16 CPU1.AU18 CPU1.AU20 CPU1.AU22 CPU1.AU24 CPU1.AU26 CPU1.AU28 CPU1.AU30 CPU1.AU33 CPU1.AU51 CPU1.AU53 CPU1.AU55 CPU1.AU57 CPU1.AU59 CPU1.AV8 CPU1.AV14 CPU1.AV16 CPU1.AV20 CPU1.AV24 CPU1.AV28 CPU1.AV33 CPU1.AV34 CPU1.AV36 CPU1.AV39 CPU1.AV41 CPU1.AV43 CPU1.AV46 CPU1.AV49 CPU1.AV51 CPU1.AV55 CPU1.AV59 CPU1.AW4 CPU1.AW16 CPU1.AW24 CPU1.AW33 CPU1.AW35 CPU1.AW37 CPU1.AW40 CPU1.AW42 CPU1.AW44 CPU1.AW47 CPU1.AW50 CPU1.AW51 CPU1.AW59 CPU1.AW60 CPU1.AY4 CPU1.AY6 CPU1.AY11 CPU1.AY16 CPU1.AY18 CPU1.AY22 CPU1.AY24 CPU1.AY26 CPU1.AY30 CPU1.AY33 CPU1.AY51 CPU1.AY53 CPU1.AY57 CPU1.AY59 CPU1.B4 CPU1.B20 CPU1.B24 CPU1.B26 CPU1.B28 CPU1.B32 CPU1.B36 CPU1.B40 CPU1.B44 CPU1.B48 CPU1.B52 CPU1.B56 CPU1.B60 CPU1.C11 CPU1.C14 CPU1.C18 CPU1.C20 CPU1.C25 CPU1.C27 CPU1.C38 CPU1.C39 CPU1.C57 CPU1.D2 CPU1.D5 CPU1.D8 CPU1.D12 CPU1.D14 CPU1.D18 CPU1.D21 CPU1.D23 CPU1.D25 CPU1.D26 CPU1.D27 CPU1.D29 CPU1.D30 CPU1.D31 CPU1.D33 CPU1.D34 CPU1.D35 CPU1.D37 CPU1.D38 CPU1.D39 CPU1.D41 CPU1.D42 CPU1.D43 CPU1.D45 CPU1.D46 CPU1.D47 CPU1.D49 CPU1.D50 CPU1.D51 CPU1.D53 CPU1.D54 CPU1.D55 CPU1.D57 CPU1.D59 CPU1.D62 CPU1.D63 CPU1.E11 CPU1.E17 CPU1.F20 CPU1.F26 CPU1.F30 CPU1.F34 CPU1.F38 CPU1.F42 CPU1.F46 CPU1.F50 CPU1.F54 CPU1.F58 CPU1.F61 CPU1.G3 CPU1.G5 CPU1.G6 CPU1.G8 CPU1.G18 CPU1.G22 CPU1.H13 CPU1.H17 CPU1.H57 CPU1.J10 CPU1.J22 CPU1.J59 CPU1.J63 CPU1.K1 CPU1.K12 CPU1.L7 CPU1.L13 CPU1.L15 CPU1.L17 CPU1.L18 CPU1.L20 CPU1.L58 CPU1.L61 CPU1.M22 CPU1.N3 CPU1.N10 CPU1.N21 CPU1.P22 CPU1.P59 CPU1.P62 CPU1.P63 CPU1.R8 CPU1.R10 CPU1.R22 CPU1.T1 CPU1.T58 CPU1.U9 CPU1.U20 CPU1.U22 CPU1.U61 CPU1.V3 CPU1.V7 CPU1.V10 CPU1.V23 CPU1.V58 CPU1.W20 CPU1.W22 CPU1.Y10 CPU1.Y59 CPU1.Y63 D2601.A D4301.1 D4302.1 D4303.1 DB1.8 DB1.10 DB1.11 DB1.12 DCIN1.7 DCIN1.8 DM1.2 DM1.3 DM1.8 DM1.9 DM1.11 DM1.13 DM1.14 DM1.19 DM1.20 DM1.25 DM1.26 DM1.28 DM1.31 DM1.32 DM1.37 DM1.38 DM1.43 DM1.44 DM1.46 DM1.48 DM1.49 DM1.54 DM1.55 DM1.60 DM1.61 DM1.63 DM1.65 DM1.66 DM1.71 DM1.72 DM1.127 DM1.128 DM1.133 DM1.134 DM1.136 DM1.138 DM1.139 DM1.144 DM1.145 DM1.150 DM1.151 DM1.153 DM1.155 DM1.156 DM1.161 DM1.162 DM1.167 DM1.168 DM1.170 DM1.172 DM1.173 DM1.178 DM1.179 DM1.184 DM1.185 DM1.187 DM1.189 DM1.190 DM1.195 DM1.196 DM1.205 DM1.206 DM2.2 DM2.3 DM2.8 DM2.9 DM2.11 DM2.13 DM2.14 DM2.19 DM2.20 DM2.25 DM2.26 DM2.28 DM2.31 DM2.32 DM2.37 DM2.38 DM2.43 DM2.44 DM2.46 DM2.48 DM2.49 DM2.54 DM2.55 DM2.60 DM2.61 DM2.63 DM2.65 DM2.66 DM2.71 DM2.72 DM2.127 DM2.128 DM2.133 DM2.134 DM2.136 DM2.138 DM2.139 DM2.144 DM2.145 DM2.150 DM2.151 DM2.153 DM2.155 DM2.156 DM2.161 DM2.162 DM2.167 DM2.168 DM2.170 DM2.172 DM2.173 DM2.178 DM2.179 DM2.184 DM2.185 DM2.187 DM2.189 DM2.190 DM2.195 DM2.196 DM2.205 DM2.206 EC401.2 EC402.2 EC701.2 EC702.2 EC1501.2 EC1502.2 EC1701.1 EC1702.2 EC1703.2 EC1704.2 EC1705.2 EC1706.2 EC1707.2 EC1801.2 EC1901.1 EC1902.2 EC1903.2 EC2501.2 EC2502.2 EC2503.2 EC2601.2 EC2602.2 EC2701.2 EC2703.2 EC2704.2 EC2705.2 EC2706.2 EC2707.2 EC2708.2 EC2709.2 EC2901.2 EC2902.2 EC2903.2 EC2904.2 EC3101.1 EC3102.1 EC3103.1 EC3104.1 EC3105.1 EC3106.1 EC3107.1 EC3108.1 EC3201.2 EC3301.2 EC3302.2 EC3303.2 EC3304.2 EC3305.2 EC3306.2 EC3307.2 EC4301.2 EC4302.2 EC4303.2 EC4304.2 EC4305.1 EC4401.2 EC4402.2 EC4601.2 EC4701.2 EC5205.2 EC5206.2 EC5210.2 EC5801.2 EC5802.2 EC6101.2 EC6102.2 EC6103.2 EC6104.2 EC6105.2 EC6201.2 EC6202.2 EC6203.2 EC6204.2 EC6205.2 EC6206.2 EC6207.2 EC6208.2 EC9701.2 EC9702.2 EC9703.2 EC9704.2 EC9705.2 EC9706.2 EC9707.2 EC9708.2 EC9709.2 EC9710.2 EC9711.2 EC9712.2 EC9713.2 EC9714.2 EC9715.2 EC9716.2 EC9717.2 EC9718.2 EC9719.2 EC9720.2 EC9721.2 EC9722.2 EC9723.2 EC9724.2 EC9725.2 EC9726.2 EC9727.2 EC9728.2 EC9729.2 EC9730.2 EC9731.2 EC9732.2 EC9733.2 EC9734.2 EC9735.2 EC9736.2 EC9737.2 EC9738.2 EC9739.2 EC9740.2 EC9741.2 EC9742.2 EC9743.2 EC9744.2 EC9745.2 EC9746.2 EC9747.2 EC9748.2 EC9749.1 EC9750.2 EC9751.2 EC9752.2 EC9753.2 EC9754.2 EC9755.2 EC9756.2 EC9757.2 EC9758.2 EC9759.2 EC9760.2 EC9761.2 ED6101.2 EL4203.2 EL4204.2 EU401.2 EU3101.3 EU3101.8 EU3102.3 EU3102.8 EU3403.2 EU3404.2 EU5602.3 EU5602.8 FAN1.2 FAN1.4 FAN1.5 FAN261.5 FAN261.6 FAN261.7 FAN261.8 G1901.1 G6101.1 G6102.1 GPU1.A2 GPU1.A26 GPU1.AA7 GPU1.AB7 GPU1.AB11 GPU1.AB14 GPU1.AB17 GPU1.AB20 GPU1.AB24 GPU1.AC2 GPU1.AC5 GPU1.AC8 GPU1.AC22 GPU1.AC26 GPU1.AD12 GPU1.AD13 GPU1.AD15 GPU1.AD16 GPU1.AD18 GPU1.AD19 GPU1.AD21 GPU1.AD22 GPU1.AE11 GPU1.AE14 GPU1.AE17 GPU1.AE20 GPU1.AF1 GPU1.AF5 GPU1.AF8 GPU1.AF11 GPU1.AF14 GPU1.AF17 GPU1.AF20 GPU1.AF23 GPU1.AG2 GPU1.AG26 GPU1.B1 GPU1.B5 GPU1.B8 GPU1.B11 GPU1.B14 GPU1.B17 GPU1.B20 GPU1.B23 GPU1.B27 GPU1.E2 GPU1.E5 GPU1.E8 GPU1.E11 GPU1.E14 GPU1.E17 GPU1.E20 GPU1.E22 GPU1.E25 GPU1.H2 GPU1.H5 GPU1.H23 GPU1.H25 GPU1.K11 GPU1.K13 GPU1.K15 GPU1.K17 GPU1.L2 GPU1.L5 GPU1.L10 GPU1.L12 GPU1.L14 GPU1.L16 GPU1.L18 GPU1.L23 GPU1.L25 GPU1.M11 GPU1.M13 GPU1.M15 GPU1.M17 GPU1.N10 GPU1.N12 GPU1.N14 GPU1.N16 GPU1.N18 GPU1.P2 GPU1.P5 GPU1.P11 GPU1.P13 GPU1.P15 GPU1.P17 GPU1.P23 GPU1.P26 GPU1.R10 GPU1.R12 GPU1.R14 GPU1.R16 GPU1.R18 GPU1.T11 GPU1.T13 GPU1.T15 GPU1.T17 GPU1.U2 GPU1.U5 GPU1.U10 GPU1.U12 GPU1.U14 GPU1.U16 GPU1.U18 GPU1.U23 GPU1.U26 GPU1.V11 GPU1.V13 GPU1.V15 GPU1.V17 GPU1.Y2 GPU1.Y5 GPU1.Y23 GPU1.Y26 H1.1 H2.1 H3.1 H4.1 H5.1 H6.1 H7.1 HCPU1.1 HCPU2.1 HCPU3.1 HDA27.4 HDA27.49 HDD1.6 HDD1.9 HDD1.12 HDD1.13 HDD1.14 HDLED1.2K HDMI1.5 HDMI1.6 HDMI1.7 HDMI1.8 HDMI1.10 HDMI1.HP2 HDMI1.HP5 HDMI1.HP8 HDMI1.HP11 HDMI1.HP17 HDMI1.PTH1 HDMI1.PTH2 HDMI1.PTH3 HDMI1.PTH4 HDMI1.PTH5 HDMI1.PTH6 HDMI1.PTH7 HDMI1.PTH8 HDMI1.PTH9 HDMI1.PTH10 HDMI1.PTH11 HDMI1.PTH12 HGPU1.1 HGPU2.1 HGPU3.1 KB1.1 KB1.31 KB1.32 KB_BL1.5 KB_BL1.6 KBC24.5 KBC24.18 KBC24.45 KBC24.78 KBC24.89 KBC24.116 LCD1.13 LCD1.16 LCD1.19 LCD1.23 LCD1.24 LCD1.25 LCD1.29 LCD1.36 LCD1.41 LCD1.42 LED1.3 LOM30.33 ODD1.1 ODD1.4 ODD1.7 ODD1.18 ODD1.19 ODD1.20 ODD1.21 ODD1.22 PC4202.2 PC4203.2 PC4204.2 PC4205.2 PC4206.2 PC4401.2 PC4406.2 PC4407.2 PC4408.2 PC4409.2 PC4415.2 PC4416.2 PC4417.2 PC4418.2 PC4419.2 PC4425.2 PC4426.2 PC4427.2 PC4431.2 PC4509.2 PC4515.2 PC4517.2 PC4518.2 PC4519.2 PC4520.2 PC4521.2 PC4524.2 PC4525.2 PC4526.2 PC4527.2 PC4528.2 PC4529.2 PC4530.2 PC4531.2 PC4533.2 PC4534.2 PC4536.2 PC4604.2 PC4606.2 PC4609.1 PC4610.2 PC4611.2 PC4612.2 PC4613.1 PC4701.2 PC4702.2 PC4703.2 PC4704.2 PC4710.2 PC4717.2 PC4718.2 PC4719.2 PC4720.2 PC4721.2 PC4722.2 PC4723.2 PC4724.2 PC4725.2 PC4726.2 PC4727.2 PC4728.2 PC4729.2 PC4730.2 PC4731.2 PC4732.2 PC4733.2 PC4734.2 PC4735.2 PC4736.2 PC4737.2 PC4739.2 PC4740.2 PC4741.2 PC4742.2 PC4744.2 PC4814.2 PC4815.2 PC4821.2 PC4824.2 PC4825.2 PC4826.2 PC4838.2 PC4901.2 PC4902.2 PC4903.2 PC4904.2 PC4906.2 PC4909.2 PC4911.2 PC4912.2 PC4913.1 PC4914.2 PC4915.2 PC4916.2 PC4917.2 PC4918.2 PC4920.2 PC4921.2 PC4922.2 PC4923.2 PC4924.2 PC4925.2 PC4926.2 PC4927.2 PC4928.2 PC5102.2 PC5119.2 PC5120.2 PC8202.1 PC8203.1 PC8205.2 PC8206.2 PC8207.2 PC8208.2 PC8209.2 PC8210.2 PC8212.2 PC8213.2 PC8214.2 PC8215.2 PC8217.2 PC8218.2 PC8220.1 PC8221.1 PC8222.2 PC8224.2 PC8225.1 PC8226.1 PC8302.2 PC8303.2 PC8307.2 PD4201.A PD4203.1 PD4204.3 PD4302.A PD4501.A PG4411.2 PQ4202.E PQ4204.E PQ4206.S PQ4402.1 PQ4402.4 PQ4408.1 PQ4408.4 PQ4410.1 PQ4410.4 PQ4414.S PQ8304.1 PQ8304.4 PQ8305.1 PQ8305.4 PQ8306.S PQ8307.S PR4202.2 PR4208.2 PR4405.2 PR4432.2 PR4436.2 PR4464.2 PR4467.2 PR4470.1 PR4474.2 PR4517.2 PR4523.2 PR4526.2 PR4530.2 PR4531.2 PR4604.2 PR4607.1 PR4610.1 PR4614.1 PR4617.2 PR4622.2 PR4707.2 PR4817.1 PR4823.2 PR4824.2 PR4902.2 PR4906.2 PR4908.1 PR8213.2 PR8224.2 PR8259.2 PT4501.2 PT4502.2 PT4701.2 PT4702.2 PT4803.2 PT8206.2 PT8207.2 PT8208.2 PU4401.14 PU4406.1 PU4406.2 PU4406.3 PU4407.1 PU4407.2 PU4502.1 PU4502.2 PU4502.3 PU4503.21 PU4505.1 PU4505.2 PU4505.3 PU4601.21 PU4701.5 PU4701.6 PU4701.7 PU4805.1 PU4805.2 PU4805.3 PU4806.11 PU4901.4 PU4901.7 PU4901.10 PU4901.21 PU4903.1 PU4903.2 PU4903.3 PU5101.2 PU8201.21 PU8203.1 PU8203.2 PU8203.3 PU8205.1 PU8205.2 PU8205.3 PU8207.1 PU8207.2 PU8207.3 PU8209.1 PU8209.2 PU8209.3 PWR1.4 PWR1.5 PWR1.6 Q1701.1 Q1701.4 Q1901.S Q2401.S Q2403.S Q2404.C Q2505.S Q3001.S Q3601.1 Q3601.4 Q5403.S Q6202.S Q6205.S Q8301.S R402.2 R405.2 R406.2 R407.1 R408.1 R409.1 R601.1 R602.2 R603.1 R604.2 R605.2 R606.2 R709.2 R712.2 R901.2 R1201.2 R1202.2 R1204.2 R1301.2 R1509.1 R1511.2 R1514.2 R1515.2 R1602.2 R1715.2 R1717.2 R1721.2 R1725.1 R1902.2 R1913.1 R1920.1 R2003.2 R2008.2 R2024.2 R2026.2 R2034.2 R2035.1 R2435.1 R2442.2 R2447.2 R2449.1 R2504.2 R2605.1 R2611.2 R2706.2 R2717.2 R3015.2 R3023.2 R3032.1 R3203.2 R3602.2 R3605.2 R3703.2 R3707.2 R3709.2 R3711.2 R3714.2 R3715.2 R4301.1 R5201.2 R5202.1 R5209.2 R5218.2 R5410.2 R5412.2 R5413.2 R5418.1 R5501.2 R5505.2 R5508.1 R5510.2 R5512.1 R5513.2 R5514.2 R5516.1 R5604.2 R6207.2 R6208.2 R6209.2 R6301.1 R6302.1 R6305.2 R7301.2 R7302.2 R7306.2 R7506.2 R7507.1 R7508.2 R7509.2 R7510.2 R7511.2 R7512.2 R7518.2 R7601.2 R7602.2 R7607.1 R7609.2 R7610.2 R7614.2 R7618.2 R7620.2 R7621.2 R7622.2 R7627.2 R7628.1 R7632.2 R7637.2 R7642.2 R7647.2 R7650.2 R7654.2 R7655.2 R7807.2 R7808.1 R7809.1 R7904.2 R7912.1 R7913.1 R8001.1 R8002.1 R8101.1 R8102.1 R8301.2 R8305.2 RJ45.9 RJ45.10 RN1503.1(A) RN1503.2(A) RN1703.1(A) RN1703.2(A) RN1803.1(A) RN1803.2(A) RN1804.1(A) RN1804.2(A) RN5203.1(A) RN5203.2(A) RN5203.3(A) RN7401.1(A) RN7401.2(A) RN7402.1(A) RN7402.2(A) RN7403.1(A) RN7403.2(A) RN7404.1(A) RN7404.2(A) RN7501.4(B) RN7502.3(B) RN7503.3(B) RN7504.3(B) RN7505.4(B) RN7506.3(B) RN7507.4(B) RN7508.3(B) RN7509.3(B) RN7510.3(B) RN7511.4(B) RN7512.3(B) RN7513.4(B) RN7514.3(B) RN7515.4(B) RN7516.3(B) RN7517.4(B) RN7518.4(B) RN7519.3(B) RN7520.4(B) RN7521.4(B) RN7522.4(B) RN7602.1(A) RN7602.2(A) RTC1.2 SPI25.4 SPK1.5 SPK1.6 SPR1.1 SPR2.1 SPR3.1 TC1201.2 TC3501.2 THM26.5 TPAD1.5 TPAD1.9 TPAD1.10 U701.3 U2101.8 U3201.25 U3402.3 U3402.8 U3504.2 U3505.2 U3601.11 U3601.15 U3801.1 U5201.2 U5502.11 U5502.13 U5502.14 U5502.16 U5502.33 U5504.1 U5504.2 U5504.4 U5504.7 U5601.1 U5601.9 U7301.3 U8301.11 U8301.15 USB1.4 USB1.7 USB1.10 USB1.11 USB1.12 USB1.13 VRAM1.A9 VRAM1.B1 VRAM1.B3 VRAM1.B9 VRAM1.D1 VRAM1.D8 VRAM1.E1 VRAM1.E2 VRAM1.E8 VRAM1.F9 VRAM1.G1 VRAM1.G8 VRAM1.G9 VRAM1.J2 VRAM1.J8 VRAM1.M1 VRAM1.M9 VRAM1.P1 VRAM1.P9 VRAM1.T1 VRAM1.T9 VRAM2.A9 VRAM2.B1 VRAM2.B3 VRAM2.B9 VRAM2.D1 VRAM2.D8 VRAM2.E1 VRAM2.E2 VRAM2.E8 VRAM2.F9 VRAM2.G1 VRAM2.G8 VRAM2.G9 VRAM2.J2 VRAM2.J8 VRAM2.M1 VRAM2.M9 VRAM2.P1 VRAM2.P9 VRAM2.T1 VRAM2.T9 VRAM3.A9 VRAM3.B1 VRAM3.B3 VRAM3.B9 VRAM3.D1 VRAM3.D8 VRAM3.E1 VRAM3.E2 VRAM3.E8 VRAM3.F9 VRAM3.G1 VRAM3.G8 VRAM3.G9 VRAM3.J2 VRAM3.J8 VRAM3.M1 VRAM3.M9 VRAM3.P1 VRAM3.P9 VRAM3.T1 VRAM3.T9 VRAM4.A9 VRAM4.B1 VRAM4.B3 VRAM4.B9 VRAM4.D1 VRAM4.D8 VRAM4.E1 VRAM4.E2 VRAM4.E8 VRAM4.F9 VRAM4.G1 VRAM4.G8 VRAM4.G9 VRAM4.J2 VRAM4.J8 VRAM4.M1 VRAM4.M9 VRAM4.P1 VRAM4.P9 VRAM4.T1 VRAM4.T9 VRAM5.A9 VRAM5.B1 VRAM5.B3 VRAM5.B9 VRAM5.D1 VRAM5.D8 VRAM5.E1 VRAM5.E2 VRAM5.E8 VRAM5.F9 VRAM5.G1 VRAM5.G8 VRAM5.G9 VRAM5.J2 VRAM5.J8 VRAM5.M1 VRAM5.M9 VRAM5.P1 VRAM5.P9 VRAM5.T1 VRAM5.T9 VRAM6.A9 VRAM6.B1 VRAM6.B3 VRAM6.B9 VRAM6.D1 VRAM6.D8 VRAM6.E1 VRAM6.E2 VRAM6.E8 VRAM6.F9 VRAM6.G1 VRAM6.G8 VRAM6.G9 VRAM6.J2 VRAM6.J8 VRAM6.M1 VRAM6.M9 VRAM6.P1 VRAM6.P9 VRAM6.T1 VRAM6.T9 VRAM7.A9 VRAM7.B1 VRAM7.B3 VRAM7.B9 VRAM7.D1 VRAM7.D8 VRAM7.E1 VRAM7.E2 VRAM7.E8 VRAM7.F9 VRAM7.G1 VRAM7.G8 VRAM7.G9 VRAM7.J2 VRAM7.J8 VRAM7.M1 VRAM7.M9 VRAM7.P1 VRAM7.P9 VRAM7.T1 VRAM7.T9 VRAM8.A9 VRAM8.B1 VRAM8.B3 VRAM8.B9 VRAM8.D1 VRAM8.D8 VRAM8.E1 VRAM8.E2 VRAM8.E8 VRAM8.F9 VRAM8.G1 VRAM8.G8 VRAM8.G9 VRAM8.J2 VRAM8.J8 VRAM8.M1 VRAM8.M9 VRAM8.P1 VRAM8.P9 VRAM8.T1 VRAM8.T9 WLAN1.1 WLAN1.7 WLAN1.18 WLAN1.33 WLAN1.39 WLAN1.45 WLAN1.51 WLAN1.57 WLAN1.63 WLAN1.69 WLAN1.75 X7601.2 X7601.4
GND_R1: CN6301.9 R6301.2
GND_R2: CN6301.15 R6302.2
V3D3_STB: HDA27.20 R2712.1
V18: C3201.2 U3201.24
VBAT: C2404.1 C2405.1 KBC24.102 R2402.1 R2404.1 R2446.1
VCC1R05VIDEO_PEX_PLLVDD: C7317.1 C7318.1 C7319.1 GPU1.AA14 GPU1.AA15 L7301.1
VCC_CORE: CPU1.AB57 CPU1.AD57 CPU1.AG57 CPU1.C24 CPU1.C28 CPU1.C32 CPU1.C36 CPU1.C40 CPU1.C44 CPU1.C48 CPU1.C52 CPU1.C56 CPU1.E23 CPU1.E25 CPU1.E27 CPU1.E29 CPU1.E31 CPU1.E33 CPU1.E35 CPU1.E37 CPU1.E39 CPU1.E41 CPU1.E43 CPU1.E45 CPU1.E47 CPU1.E49 CPU1.E51 CPU1.E53 CPU1.E55 CPU1.E57 CPU1.F24 CPU1.F28 CPU1.F32 CPU1.F36 CPU1.F40 CPU1.F44 CPU1.F48 CPU1.F52 CPU1.F56 CPU1.F59 CPU1.G23 CPU1.G25 CPU1.G27 CPU1.G29 CPU1.G31 CPU1.G33 CPU1.G35 CPU1.G37 CPU1.G39 CPU1.G41 CPU1.G43 CPU1.G45 CPU1.G47 CPU1.G49 CPU1.G51 CPU1.G53 CPU1.G55 CPU1.G57 CPU1.H23 CPU1.J23 CPU1.K23 CPU1.K57 CPU1.L22 CPU1.M23 CPU1.M57 CPU1.P57 CPU1.U57 CPU1.W57 EC4701.1 PC4717.1 PC4718.1 PC4719.1 PC4720.1 PC4721.1 PC4722.1 PC4723.1 PC4724.1 PC4725.1 PC4726.1 PC4727.1 PC4728.1 PC4729.1 PC4730.1 PC4731.1 PC4732.1 PC4733.1 PC4734.1 PC4735.1 PC4736.1 PC4737.1 PC4739.1 PC4740.1 PC4741.1 PC4742.1 PC4744.1 PG4702.2 PL4701.2 PT4701.1 R702.1
VCC_SENSE: CPU1.E63 PC4601.2 PC4613.2 PR4603.2 R702.2
VCCK_12: C5501.1 C5503.1 C5504.1 U5502.19 U5502.25
VCCST_PWRGD_XDP: R9601.2 TP9648.1
VDD10: C3012.1 C3018.1 C3019.1 C3021.1 C3022.1 C3023.1 C3024.1 C3025.1 L3001.2 LOM30.3 LOM30.8 LOM30.22 LOM30.30 R3001.2
VDD_DAC_33: C5502.1 C5521.2 C5524.1 R5503.2 U5502.9
VDDREG: C3009.1 C3010.1 LOM30.23 R3006.2
VSS_SENSE: CPU1.E62 PC4612.1 PR4604.1 PU4601.8 R901.1
0D675V_S0: C1214.1 C1215.1 C1216.1 C1303.1 C1304.1 C1307.1 DM1.203 DM1.204 DM2.203 DM2.204 PG4901.1 PG4902.1
1D05S_VCCST: C701.1 C703.1 CPU1.AC22 CPU1.AE22 CPU1.AE23 PC4606.1 PR4601.1 PR4620.2 PR4630.2 R401.1 R703.1 R704.1 R705.1 R706.1 R711.2 R1916.2 R1917.2 R1918.2 R1919.2 R2018.1 RN401.5(B) RN401.7(B) RN401.8(B)
1D05V_HSIO: C2142.1 L1101.1 L1102.1 R1101.1 R2114.2 R2122.2
1D05V_PWR: PC4824.1 PG4824.2 PG4825.2 PG4826.2 PG4828.2 PG4830.2 PG4831.2 PG4832.2 PL4801.2 PT4803.1
1D5V_PWR: PC5120.1 PG5105.1 PU5101.5
1D05V_S0: C2135.1 C2141.1 C8302.1 CPU1.AG13 CPU1.AG14 CPU1.AG16 CPU1.AG17 L1103.1 L1104.1 PG4824.1 PG4825.1 PG4826.1 PG4828.1 PG4830.1 PG4831.1 PR4602.1 R711.1 R1102.1 R1104.1 R1105.1 R2105.1 R2117.1 R2118.1 R2122.1 R2401.1 R3608.1 U2101.2 U2101.3 U2101.4 U8301.1 U8301.2
1D5V_S0: CPU1.J15 PG5105.2 R2705.1
1D05V_VGA_EN: C8309.2 PR8301.2 R8313.2 U8301.3
1D05V_VGA_OUT2: C8310.1 PG8313.1 PG8314.1 PG8315.1 U8301.13 U8301.14
1D05V_VGA_S0: C7310.1 C7312.1 C7323.1 C7326.1 C8306.2 GPU1.AA10 GPU1.AA12 GPU1.AA13 GPU1.AA16 GPU1.AA18 GPU1.AA19 GPU1.AA20 GPU1.AA21 GPU1.AA22 GPU1.AB22 GPU1.AB23 GPU1.AC23 GPU1.AC24 GPU1.AD24 GPU1.AD25 GPU1.AE25 GPU1.AE26 GPU1.AE27 GPU1.AF26 GPU1.AF27 L7301.2 L7501.2 L7601.1 L7602.1 PG8313.2 PG8314.2 PG8315.2 PR8316.1
1D05V_VGA_S0_DISCHG: PQ8305.3 PR8316.2
1D05V_VTT_PWRGD: PR4821.2 R707.1 R3611.1 U701.2
1D35V_ENABLE: PQ8304.3 PR8310.1 PR8312.1 R8314.2
1D35V_ENABLE_RC: PC8302.1 PQ8308.4 R8314.1
1D35V_PWR: EC4601.1 PC4904.1 PC4920.1 PC4921.1 PC4923.1 PC4924.1 PC4925.1 PC4926.1 PC4927.1 PC4928.1 PG4907.2 PG4908.2 PG4909.2 PG4910.2 PG4911.2 PG4912.2 PG4913.2 PG4914.2 PG4915.2 PG4916.2 PG4917.2 PG4918.2 PG4919.2 PG4920.2 PL4902.2 PU4901.2
1D35V_S3: C1001.1 C1002.1 C1003.1 C1004.1 C1005.1 C1006.1 C1017.1 C1018.1 C1019.1 C1020.1 C1207.1 C1208.1 C1209.1 C1210.1 C1211.1 C1212.1 C1213.1 C1220.1 C1221.1 C1222.1 C1312.1 C1313.1 C1314.1 C1315.1 C1316.1 C1317.1 C1318.1 C1319.1 C1320.1 C1321.1 CPU1.AH26 CPU1.AJ31 CPU1.AJ33 CPU1.AJ37 CPU1.AN33 CPU1.AP43 CPU1.AR48 CPU1.AY35 CPU1.AY40 CPU1.AY44 CPU1.AY50 DM1.75 DM1.76 DM1.81 DM1.82 DM1.87 DM1.88 DM1.93 DM1.94 DM1.99 DM1.100 DM1.105 DM1.106 DM1.111 DM1.112 DM1.117 DM1.118 DM1.123 DM1.124 DM2.75 DM2.76 DM2.81 DM2.82 DM2.87 DM2.88 DM2.93 DM2.94 DM2.99 DM2.100 DM2.105 DM2.106 DM2.111 DM2.112 DM2.117 DM2.118 DM2.123 DM2.124 PC8303.1 PG4908.1 PG4909.1 PG4910.1 PG4911.1 PG4912.1 PG4913.1 PG4914.1 PG4915.1 PG4916.1 PG4917.1 PG4918.1 PG4919.1 PG4920.1 PQ8308.5 PQ8308.6 PQ8308.7 PQ8308.8 Q1201.G Q1202.D R410.1 R3701.1 R3706.1 R3716.1 TC1201.1
1D35V_VGA_EN: D8301.3 PQ8304.2 R8305.1 R8312.2
1D35V_VGA_EN#: PQ8304.5 PQ8304.6 PQ8306.G PR8311.2 PR8314.2
1D35V_VGA_S0: C7501.1 C7502.1 C7507.1 C7508.1 C7509.1 C7510.1 C7512.1 C7513.1 C7514.1 C7517.2 C7520.1 C7522.1 C7523.1 C7524.1 C7525.1 C7529.1 C7532.1 C7533.1 C7534.1 C7804.1 C7805.1 C7810.1 C7811.1 C7812.1 C7814.1 C7816.1 C7817.1 C7820.1 C7821.1 C7822.1 C7827.1 C7829.1 C7830.1 C7831.1 C7832.1 C7833.1 C7834.1 C7835.1 C7836.1 C7906.1 C7909.1 C7910.1 C7911.1 C7912.1 C7913.1 C7915.1 C7916.1 C7917.1 C7919.1 C7921.1 C7922.1 C7923.1 C7924.1 C7925.1 C7926.1 C7927.1 C7928.1 C7929.1 C7930.1 C8001.1 C8002.1 C8003.1 C8004.1 C8005.1 C8006.1 C8007.1 C8008.1 C8009.1 C8010.1 C8011.1 C8012.1 C8013.1 C8014.1 C8015.1 C8016.1 C8017.1 C8018.1 C8019.1 C8020.1 C8101.1 C8102.1 C8103.1 C8104.1 C8105.1 C8106.1 C8107.1 C8108.1 C8109.1 C8110.1 C8111.1 C8112.1 C8113.1 C8114.1 C8115.1 C8116.1 C8117.1 C8118.1 C8119.1 C8120.1 EC9725.1 EC9726.1 EC9727.1 EC9728.1 EC9729.1 EC9730.1 EC9731.1 EC9746.1 EC9750.1 EC9751.1 EC9752.1 EC9753.1 EC9754.1 GPU1.B26 GPU1.C25 GPU1.E23 GPU1.E26 GPU1.F14 GPU1.F21 GPU1.G13 GPU1.G14 GPU1.G15 GPU1.G16 GPU1.G18 GPU1.G19 GPU1.G20 GPU1.G21 GPU1.H24 GPU1.H26 GPU1.J21 GPU1.K21 GPU1.L22 GPU1.L24 GPU1.L26 GPU1.M21 GPU1.N21 GPU1.R21 GPU1.T21 GPU1.V21 GPU1.W21 PC8307.1 PQ8308.1 PQ8308.2 PQ8308.3 PR8315.1 R7501.2 R7503.2 R7505.2 R7806.1 R7903.1 RN7501.3(B) RN7502.4(B) RN7503.4(B) RN7504.4(B) RN7505.3(B) RN7506.4(B) RN7507.3(B) RN7508.4(B) RN7509.4(B) RN7510.4(B) RN7511.3(B) RN7512.4(B) RN7513.3(B) RN7514.4(B) RN7515.3(B) RN7516.4(B) RN7517.3(B) RN7518.3(B) RN7519.4(B) RN7520.3(B) RN7521.3(B) RN7522.3(B) VRAM1.A1 VRAM1.A8 VRAM1.B2 VRAM1.C1 VRAM1.C9 VRAM1.D2 VRAM1.D9 VRAM1.E9 VRAM1.F1 VRAM1.G7 VRAM1.H2 VRAM1.H9 VRAM1.K2 VRAM1.K8 VRAM1.N1 VRAM1.N9 VRAM1.R1 VRAM1.R9 VRAM2.A1 VRAM2.A8 VRAM2.B2 VRAM2.C1 VRAM2.C9 VRAM2.D2 VRAM2.D9 VRAM2.E9 VRAM2.F1 VRAM2.G7 VRAM2.H2 VRAM2.H9 VRAM2.K2 VRAM2.K8 VRAM2.N1 VRAM2.N9 VRAM2.R1 VRAM2.R9 VRAM3.A1 VRAM3.A8 VRAM3.B2 VRAM3.C1 VRAM3.C9 VRAM3.D2 VRAM3.D9 VRAM3.E9 VRAM3.F1 VRAM3.G7 VRAM3.H2 VRAM3.H9 VRAM3.K2 VRAM3.K8 VRAM3.N1 VRAM3.N9 VRAM3.R1 VRAM3.R9 VRAM4.A1 VRAM4.A8 VRAM4.B2 VRAM4.C1 VRAM4.C9 VRAM4.D2 VRAM4.D9 VRAM4.E9 VRAM4.F1 VRAM4.G7 VRAM4.H2 VRAM4.H9 VRAM4.K2 VRAM4.K8 VRAM4.N1 VRAM4.N9 VRAM4.R1 VRAM4.R9 VRAM5.A1 VRAM5.A8 VRAM5.B2 VRAM5.C1 VRAM5.C9 VRAM5.D2 VRAM5.D9 VRAM5.E9 VRAM5.F1 VRAM5.G7 VRAM5.H2 VRAM5.H9 VRAM5.K2 VRAM5.K8 VRAM5.N1 VRAM5.N9 VRAM5.R1 VRAM5.R9 VRAM6.A1 VRAM6.A8 VRAM6.B2 VRAM6.C1 VRAM6.C9 VRAM6.D2 VRAM6.D9 VRAM6.E9 VRAM6.F1 VRAM6.G7 VRAM6.H2 VRAM6.H9 VRAM6.K2 VRAM6.K8 VRAM6.N1 VRAM6.N9 VRAM6.R1 VRAM6.R9 VRAM7.A1 VRAM7.A8 VRAM7.B2 VRAM7.C1 VRAM7.C9 VRAM7.D2 VRAM7.D9 VRAM7.E9 VRAM7.F1 VRAM7.G7 VRAM7.H2 VRAM7.H9 VRAM7.K2 VRAM7.K8 VRAM7.N1 VRAM7.N9 VRAM7.R1 VRAM7.R9 VRAM8.A1 VRAM8.A8 VRAM8.B2 VRAM8.C1 VRAM8.C9 VRAM8.D2 VRAM8.D9 VRAM8.E9 VRAM8.F1 VRAM8.G7 VRAM8.H2 VRAM8.H9 VRAM8.K2 VRAM8.K8 VRAM8.N1 VRAM8.N9 VRAM8.R1 VRAM8.R9
1D35V_VTT_PWRGD: PR4904.2 PU4901.20 R3610.1
3D3V_AUX_KBC: D4301.2 D4302.2 D4303.2 PR4439.1 PR8314.1 Q2402.D R2402.2 R2403.2 R2413.2 R2414.2 R2418.2 R2434.1 R2436.1 R2453.2 R2607.1 R2608.1 RN2401.1(A) RN2401.2(A) RN4401.1(A) RN4401.2(A)
3D3V_AUX_KBC_VCC: C2406.1 C2407.1 C2408.1 C2409.1 C2410.1 C2411.1 KBC24.19 KBC24.46 KBC24.76 KBC24.88 KBC24.115 R2403.1
3D3V_AUX_S5: C2417.2 D2501.1 KBC24.75 PR4417.1 PR4419.1 PR4434.1 PR4435.1 PR4438.2 PR4501.1 PR4532.2 PR8311.1 PR8313.1 Q2402.S R1726.2 R1727.1 R2425.2 R2431.2 R2434.2 R2439.1 R2609.1 R3607.1
3D3V_CAMERA_S0: C5207.1 EC5210.1 LCD1.32 R5229.2
3D3V_CARD_S0: AFTP3310.1 C3202.1 C3204.1 C3301.1 C3302.1 C3303.1 CARD1.4 U3201.5
3D3V_LAN_S5: C3003.1 C3004.1 C3005.1 C3007.1 C3008.1 C3017.1 LOM30.11 LOM30.32 Q3004.D R3003.1 R3004.1 R3006.1 RN3001.1(A) RN3001.2(A)
3D3V_PWR: PC4517.1 PG4517.1 PG4522.1 PG4526.1 PG4528.1 PG4529.1 PG4535.1 PL4502.1 PT4502.1
3D3V_PWR_2: PC4526.1 PR4532.1 PU4503.3
3D3V_S0: C1203.1 C1311.1 C2128.1 C2412.1 C2413.1 C2601.1 C2602.1 C3203.1 C3205.1 C3605.1 C5204.1 C5520.1 C5522.1 C5801.1 C5802.1 C5805.1 C8301.1 C8304.1 C8311.1 CPU1.K14 CPU1.K16 DB1.1 DM1.199 DM2.199 EC9735.1 EC9736.1 EC9737.1 EC9738.1 KBC24.4 PR4904.1 Q1801.2 Q1801.5 Q2601.2 Q2601.5 Q5401.C Q5402.2 Q5402.5 Q6103.G Q8302.S R1302.1 R1510.1 R1512.1 R1513.1 R1701.1 R1714.2 R1905.1 R2005.1 R2006.1 R2007.2 R2011.1 R2012.1 R2023.1 R2025.1 R2033.1 R2103.2 R2112.1 R2415.2 R2443.2 R2603.1 R2604.1 R2701.1 R2710.1 R3014.1 R3601.1 R4622.1 R5208.1 R5219.2 R5229.1 R5231.1 R5502.2 R5503.1 R5504.1 R5509.2 R5515.2 R5607.1 R5809.1 R6110.1 R6212.1 R6217.1 R7648.2 R8302.1 RN1501.1(A) RN1501.2(A) RN1505.1(A) RN1505.2(A) RN1505.3(A) RN1505.4(A) RN1801.1(A) RN1801.2(A) RN1801.3(A) RN1801.4(A) RN1810.1(A) RN1810.2(A) RN1902.5(B) RN1902.6(B) RN1902.7(B) RN1902.8(B) RN2002.1(A) RN2002.2(A) RN2002.3(A) RN2002.4(A) RN2007.3(B) RN2007.4(B) RN2008.3(B) RN2008.4(B) RN2011.1(A) RN2011.2(A) RN2011.3(A) RN2011.4(A) RN2602.1(A) RN2602.2(A) THM26.1 U3201.4 U3601.8 U3601.9 U5201.4 U5201.5 U5502.5 U5502.20 U5504.3 U5504.8 U8301.6 U8301.7
3D3V_S5: AFTP6103.1 C702.1 C2147.1 C2501.1 C2502.1 C3013.1 C3015.1 C3801.1 CPU1.Y8 PC5119.1 PD4203.2 PG4517.2 PG4522.2 PG4526.2 PG4528.2 PG4529.2 PR4204.1 PR4472.1 PR4473.2 PR4534.1 PU5101.1 PWR1.1 Q3004.S R1703.1 R1814.2 R1815.2 R2101.1 R2412.2 R2421.2 R2452.2 R2501.2 R2712.2 R3021.1 R3033.2 R3801.1 R5810.1 R6215.1 RN1701.1(A) RN1701.2(A) RN2006.1(A) RN2006.2(A) RN2501.3(B) RN2501.4(B) SPI25.8 U701.5 U3601.6 U3601.7 U3801.2 U3801.3
3D3V_S5_PCH: C3802.1 R1103.1 R1724.1 R2010.1 R2013.2 R2014.1 R2015.1 R2032.2 R2102.2 R2108.1 R3801.2 RN1601.1(A) RN1601.2(A) RN1601.3(A) RN1601.4(A) RN1807.1(A) RN1807.2(A) RN1807.3(A) RN1807.4(A) RN1809.1(A) RN1809.2(A) RN1809.3(A) RN1809.4(A) RN1811.1(A) RN1811.2(A) RN2012.1(A) RN2012.2(A) RN2012.3(A) RN2012.4(A) U3801.6 U3801.7 U3801.8
3D3V_VGA_OUT1: PG8312.1 U8301.8 U8301.9
3D3V_VGA_S0: C7703.1 C7728.1 C7729.1 C7734.1 C8303.1 GPU1.G8 GPU1.G9 PR8256.1 PR8301.1 Q8302.D R7608.1 R7611.1 R7616.1 R7619.1 R7626.2 R7638.1 R7639.1 R7640.1 R8304.2
3D3V_WLAN_S0: AFTP5801.1 C5803.1 C5804.1 C5806.1 R5809.2 R5810.2 WLAN1.2 WLAN1.4 WLAN1.72 WLAN1.74
27MHZ_IN: C7607.2 GPU1.C11 R7603.1 X7601.1
27MHZ_OUT: GPU1.B10 R7603.2 R7604.2
27MHZ_OUT_R: C7608.2 R7604.1 X7601.3
28W_DET: R2022.1 R2032.1 R2035.2
+0D675V_DDR_P: PC4915.1 PC4916.1 PC4917.1 PG4901.2 PG4902.2 PU4901.1 PU4901.3
+1.05M_ASW: C1115.1 C1116.1 CPU1.AE9 CPU1.AF9 CPU1.AG8 R1104.2
+3.3A_DSW_PRTCSUS: C2109.1 CPU1.AH11 R2102.1
+DC_IN: EL4201.2 EL4202.2 PC4201.1 PC4202.1 PD4201.K PQ4205.E PR4207.1 PR4214.1 PU4201.1 PU4201.2 PU4201.3
+DC_IN_C: AFTP3801.1 AFTP3805.1 DCIN1.1 DCIN1.2 EC4201.1 EC4202.1 EL4201.1 EL4202.1
+PCH_VCCDSW: C2101.2 CPU1.AG19 CPU1.AG20 R2110.1
+PWR_SRC_1D35V: PC4909.1 PC4911.1 PC4912.1 PC4913.2 PC4914.1 PG4903.1 PG4904.1 PG4905.1 PG4906.1 PU4902.5 PU4902.6 PU4902.7 PU4902.8
+RTC_VCC: AFTP2502.1 R2502.2 RTC1.1
+V_SM_VREF_CNT: C3701.1 CPU1.AP49 R3708.2
+V_VREF_PATH1: C3702.2 R3711.1
+V_VREF_PATH2: C3703.2 R3715.1
+V_VREF_PATH3: C3701.2 R3707.1
+VCHGR_R: PG4405.1 PR4454.1
AC_IN#: PQ4408.5 PR4434.2 PU4401.5 R2413.1 R2430.1
AC_PRESENT: CPU1.AJ8 D7601.K EC1707.1 KBC24.112 RN1701.3(B)
AD+: PC4203.1 PC4204.1 PC4205.1 PC4206.1 PR4404.1 PR4405.1 PR4407.1 PR4408.1 PR4469.1 PU4201.5 PU4201.6 PU4201.7 PU4201.8 PU4402.5 PU4402.6 PU4402.7 PU4402.8 PU4403.4
AD+_G_1: PQ4402.5 PQ4402.6 PR4401.1
AD+_G_2: PR4401.2 PR4403.2 PU4402.4
AD+_TO_SYS: PG4402.1 PR4402.1 PR4403.1 PU4402.1 PU4402.2 PU4402.3
AD_IA: C2414.2 KBC24.97 PR4422.2
AD_IA_HW: KBC24.105 PQ4401.2
AD_IA_HW2: KBC24.25 PQ4401.5
AD_OFF_L: PQ4204.C PQ4205.B
AD_OFF_R: PC4201.2 PQ4205.C PR4207.2 PR4208.1 PU4201.4
ALERT#: R2603.2 THM26.6
ALL_SYS_PWRGD: KBC24.10 R3601.2 R3610.2 R3611.2
AMBER_LED_BAT: EC6102.1 Q6101.C R6103.2
AMP_MUTE#: KBC24.30 R2708.1
AUD_AGND: AFTP6313.1 C2702.1 C2705.1 C2710.2 C2711.2 C2712.1 C2713.2 C2715.2 C2901.2 CN6301.16 CN6301.24 EC2703.1 EC2704.1 EC2705.1 EC2706.1 EC2707.1 EC2905.2 EC2906.2 EC2907.2 EC2908.2 EC9739.1 EC9743.1 EC9744.1 EC9745.1 HDA27.25 HDA27.38 R2706.1 R2707.2 R2711.1 R2919.2 R2920.2 R6305.1
AUD_HP1_JACK_L: HDA27.32 R2908.1
AUD_HP1_JACK_L1: EC2907.1 R2907.2 R2908.2 R2912.2 R2919.1 R2922.2
AUD_HP1_JACK_R: HDA27.33 R2910.1
AUD_HP1_JACK_R1: EC2908.1 R2909.2 R2910.2 R2913.2 R2920.1 R2921.2
AUD_PC_BEEP: C2720.2 HDA27.12
AUD_PC_BEEP_C: C2720.1 D2701.3 R2717.1
AUD_PORTA_L_R_B: AFTP6306.1 CN6301.17 R2907.1
AUD_PORTA_R_R_B: AFTP6309.1 CN6301.18 R2909.1
AUD_SENSE: C2901.1 R2709.2 R2923.2
AUD_SENSE_A: HDA27.13 R2709.1 R2722.2
AUD_SPK_L+: EC2902.1 HDA27.42 R2902.2
AUD_SPK_L+_C: AFTP2902.1 R2902.1 SPK1.3
AUD_SPK_L-: EC2901.1 HDA27.43 R2901.2
AUD_SPK_L-_C: AFTP2901.1 R2901.1 SPK1.4
AUD_SPK_R+: EC2904.1 HDA27.45 R2904.2
AUD_SPK_R+_C: AFTP2904.1 R2904.1 SPK1.1
AUD_SPK_R-: EC2903.1 HDA27.44 R2903.2
AUD_SPK_R-_C: AFTP2903.1 R2903.1 SPK1.2
AUD_VREF: C2705.2 HDA27.28
BAT_AMBER: LED1.1 R6103.1
BAT_IN#: D4302.3 EC4305.2 KBC24.80 PC4433.1 PR4472.2 R2414.1 RN4301.1(A)
BAT_SCL: D4301.3 EC4301.1 KBC24.70 PG4407.2 RN2401.3(B) RN4301.3(A) RN4401.3(B)
BAT_SDA: D4303.3 EC4302.1 KBC24.69 PG4408.2 RN2401.4(B) RN4301.2(A) RN4401.4(B)
BAT_WHITE: LED1.2 R6107.1
BATLOW#: CPU1.AN4 RN2006.4(B)
BATT_WHITE_LED#: KBC24.62 R6104.1
BATT_WHITE_LED_R#: Q6102.B Q6105.D R6104.2
BKLT_CTRL: D5202.3 R5222.1 RN5201.7(B) RN5203.8(B)
BLON_OUT: KBC24.27 RN5201.6(B)
BLON_OUT_C: LCD1.21 RN5201.3(A) RN5203.7(B)
BLUETOOTH_EN: CPU1.J4 R5804.1 RN2011.5(B)
BLUETOOTH_EN_NGFF: AFTP5804.1 R5804.2 WLAN1.54
BMON: KBC24.96 PR4452.1
BOARD_ID2: CPU1.Y3 R2005.2 R2008.1
BOARD_ID3: CPU1.P3 R2025.2 R2026.1
BOOST_10V: PC4534.1 PD4502.1 PD4503.2
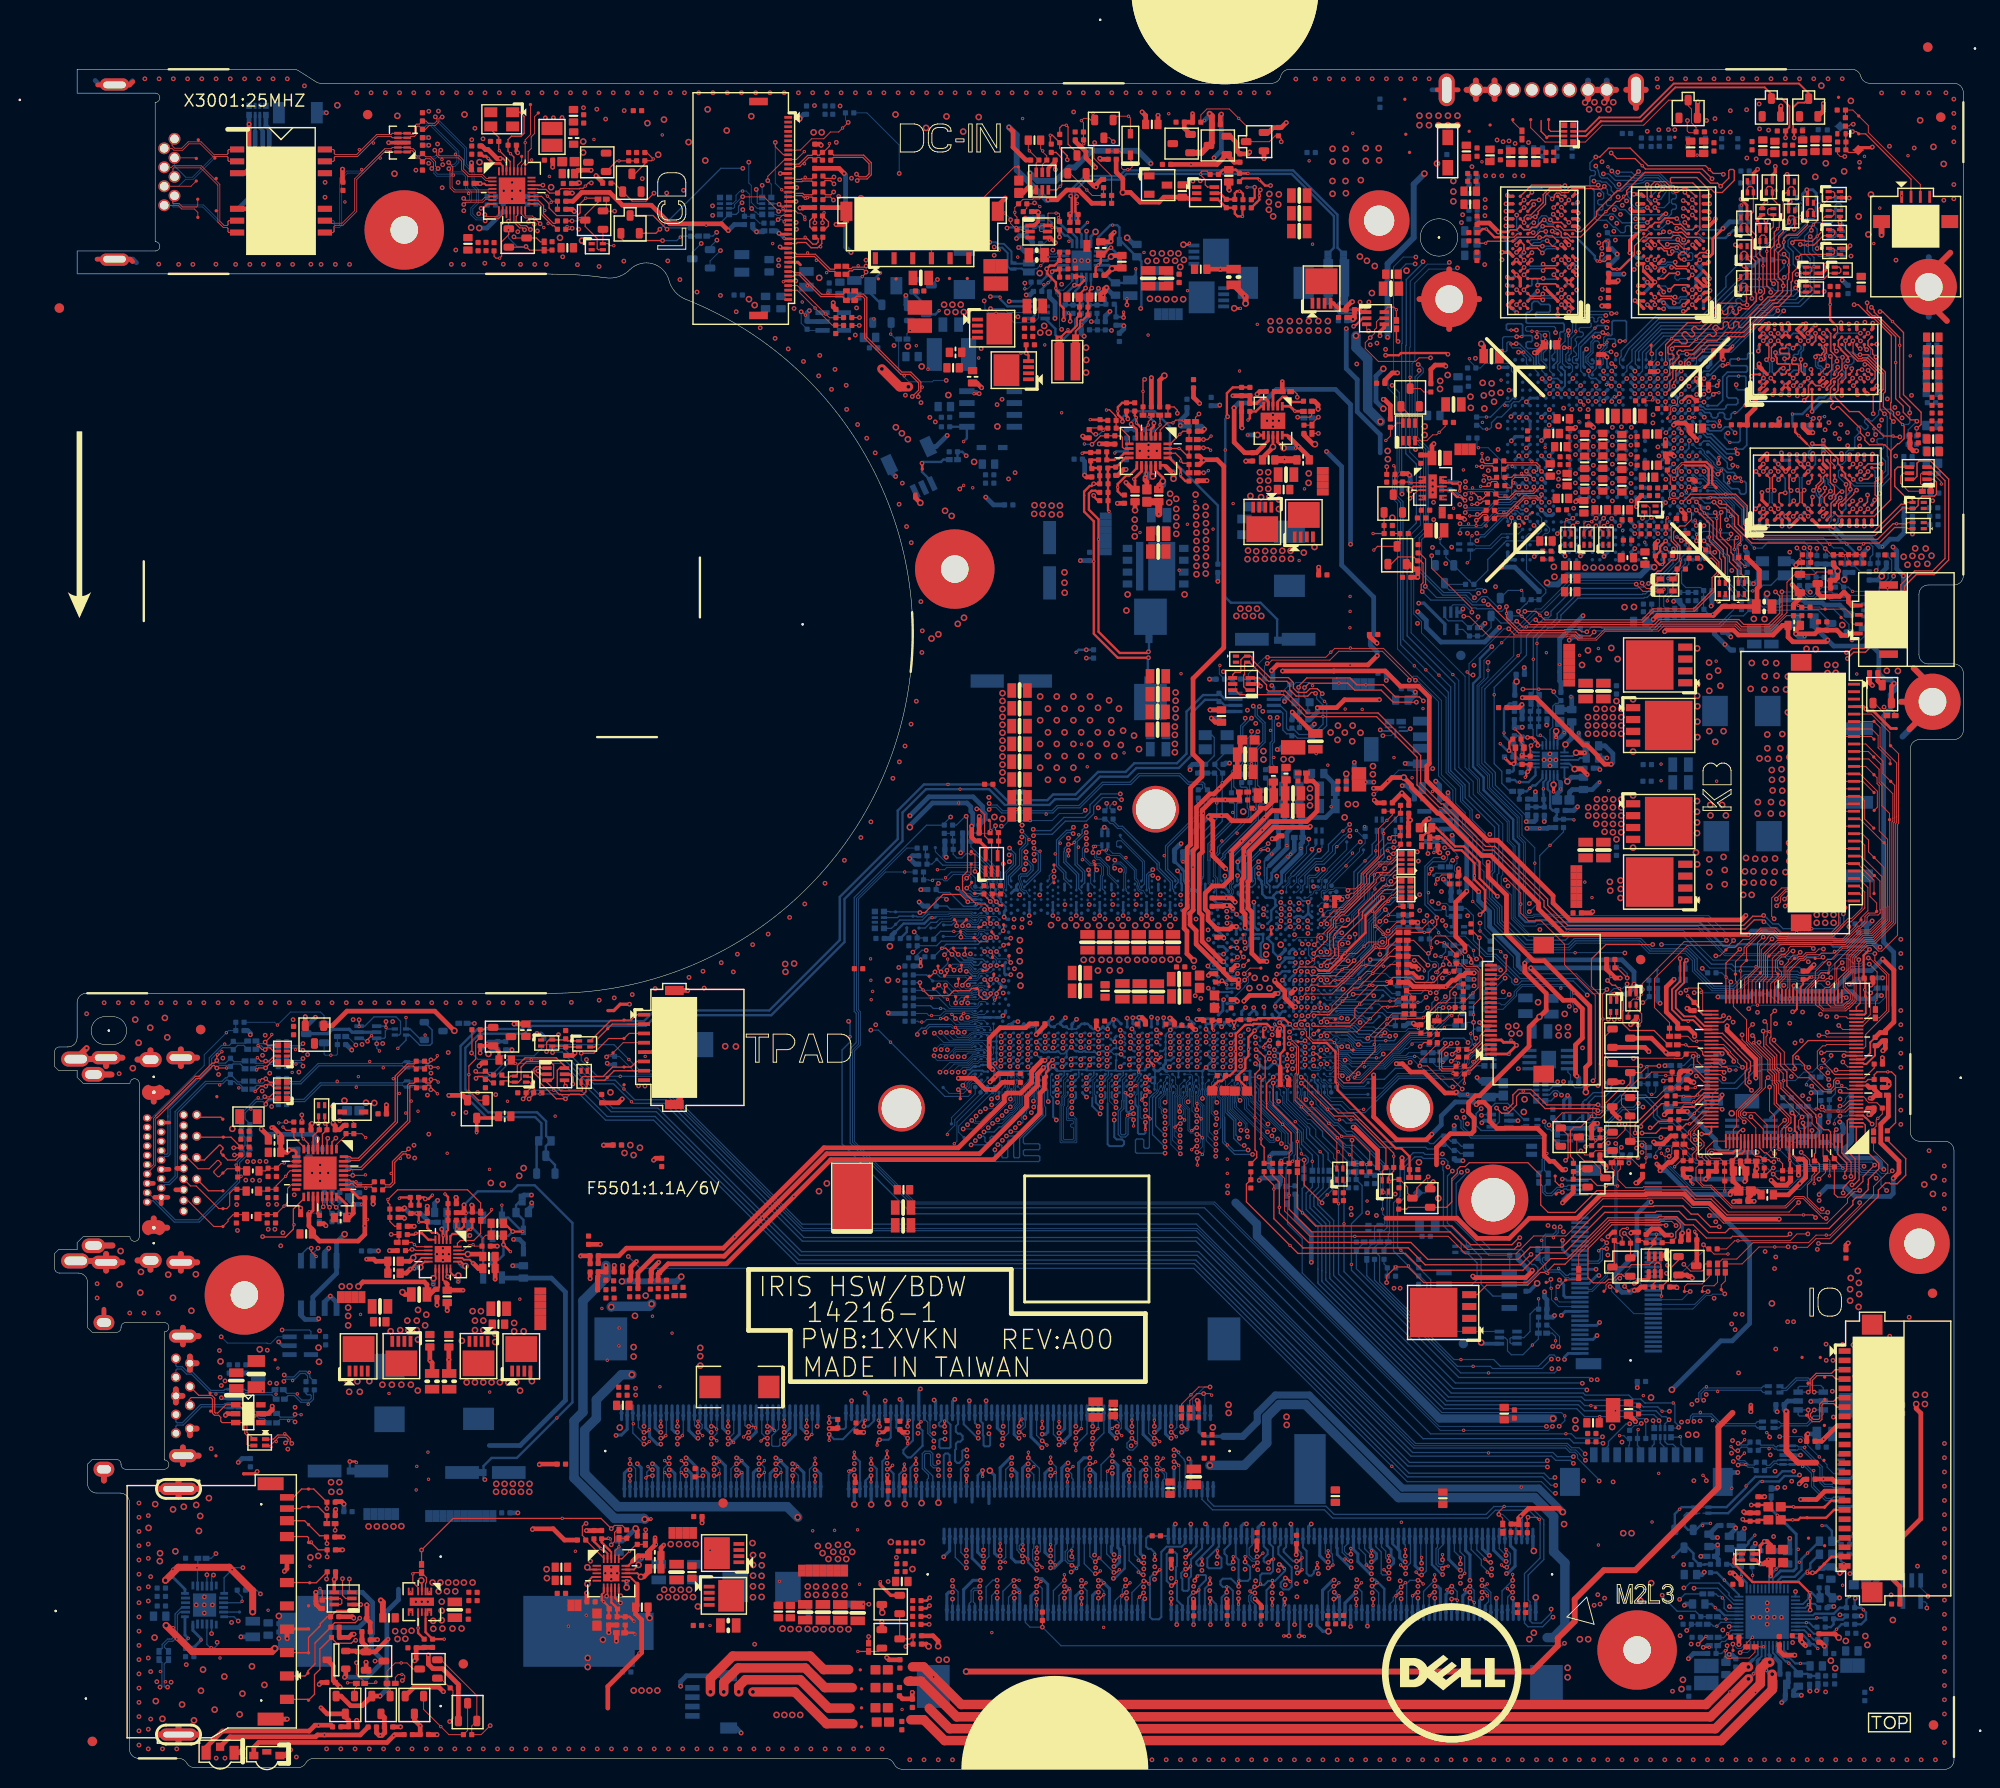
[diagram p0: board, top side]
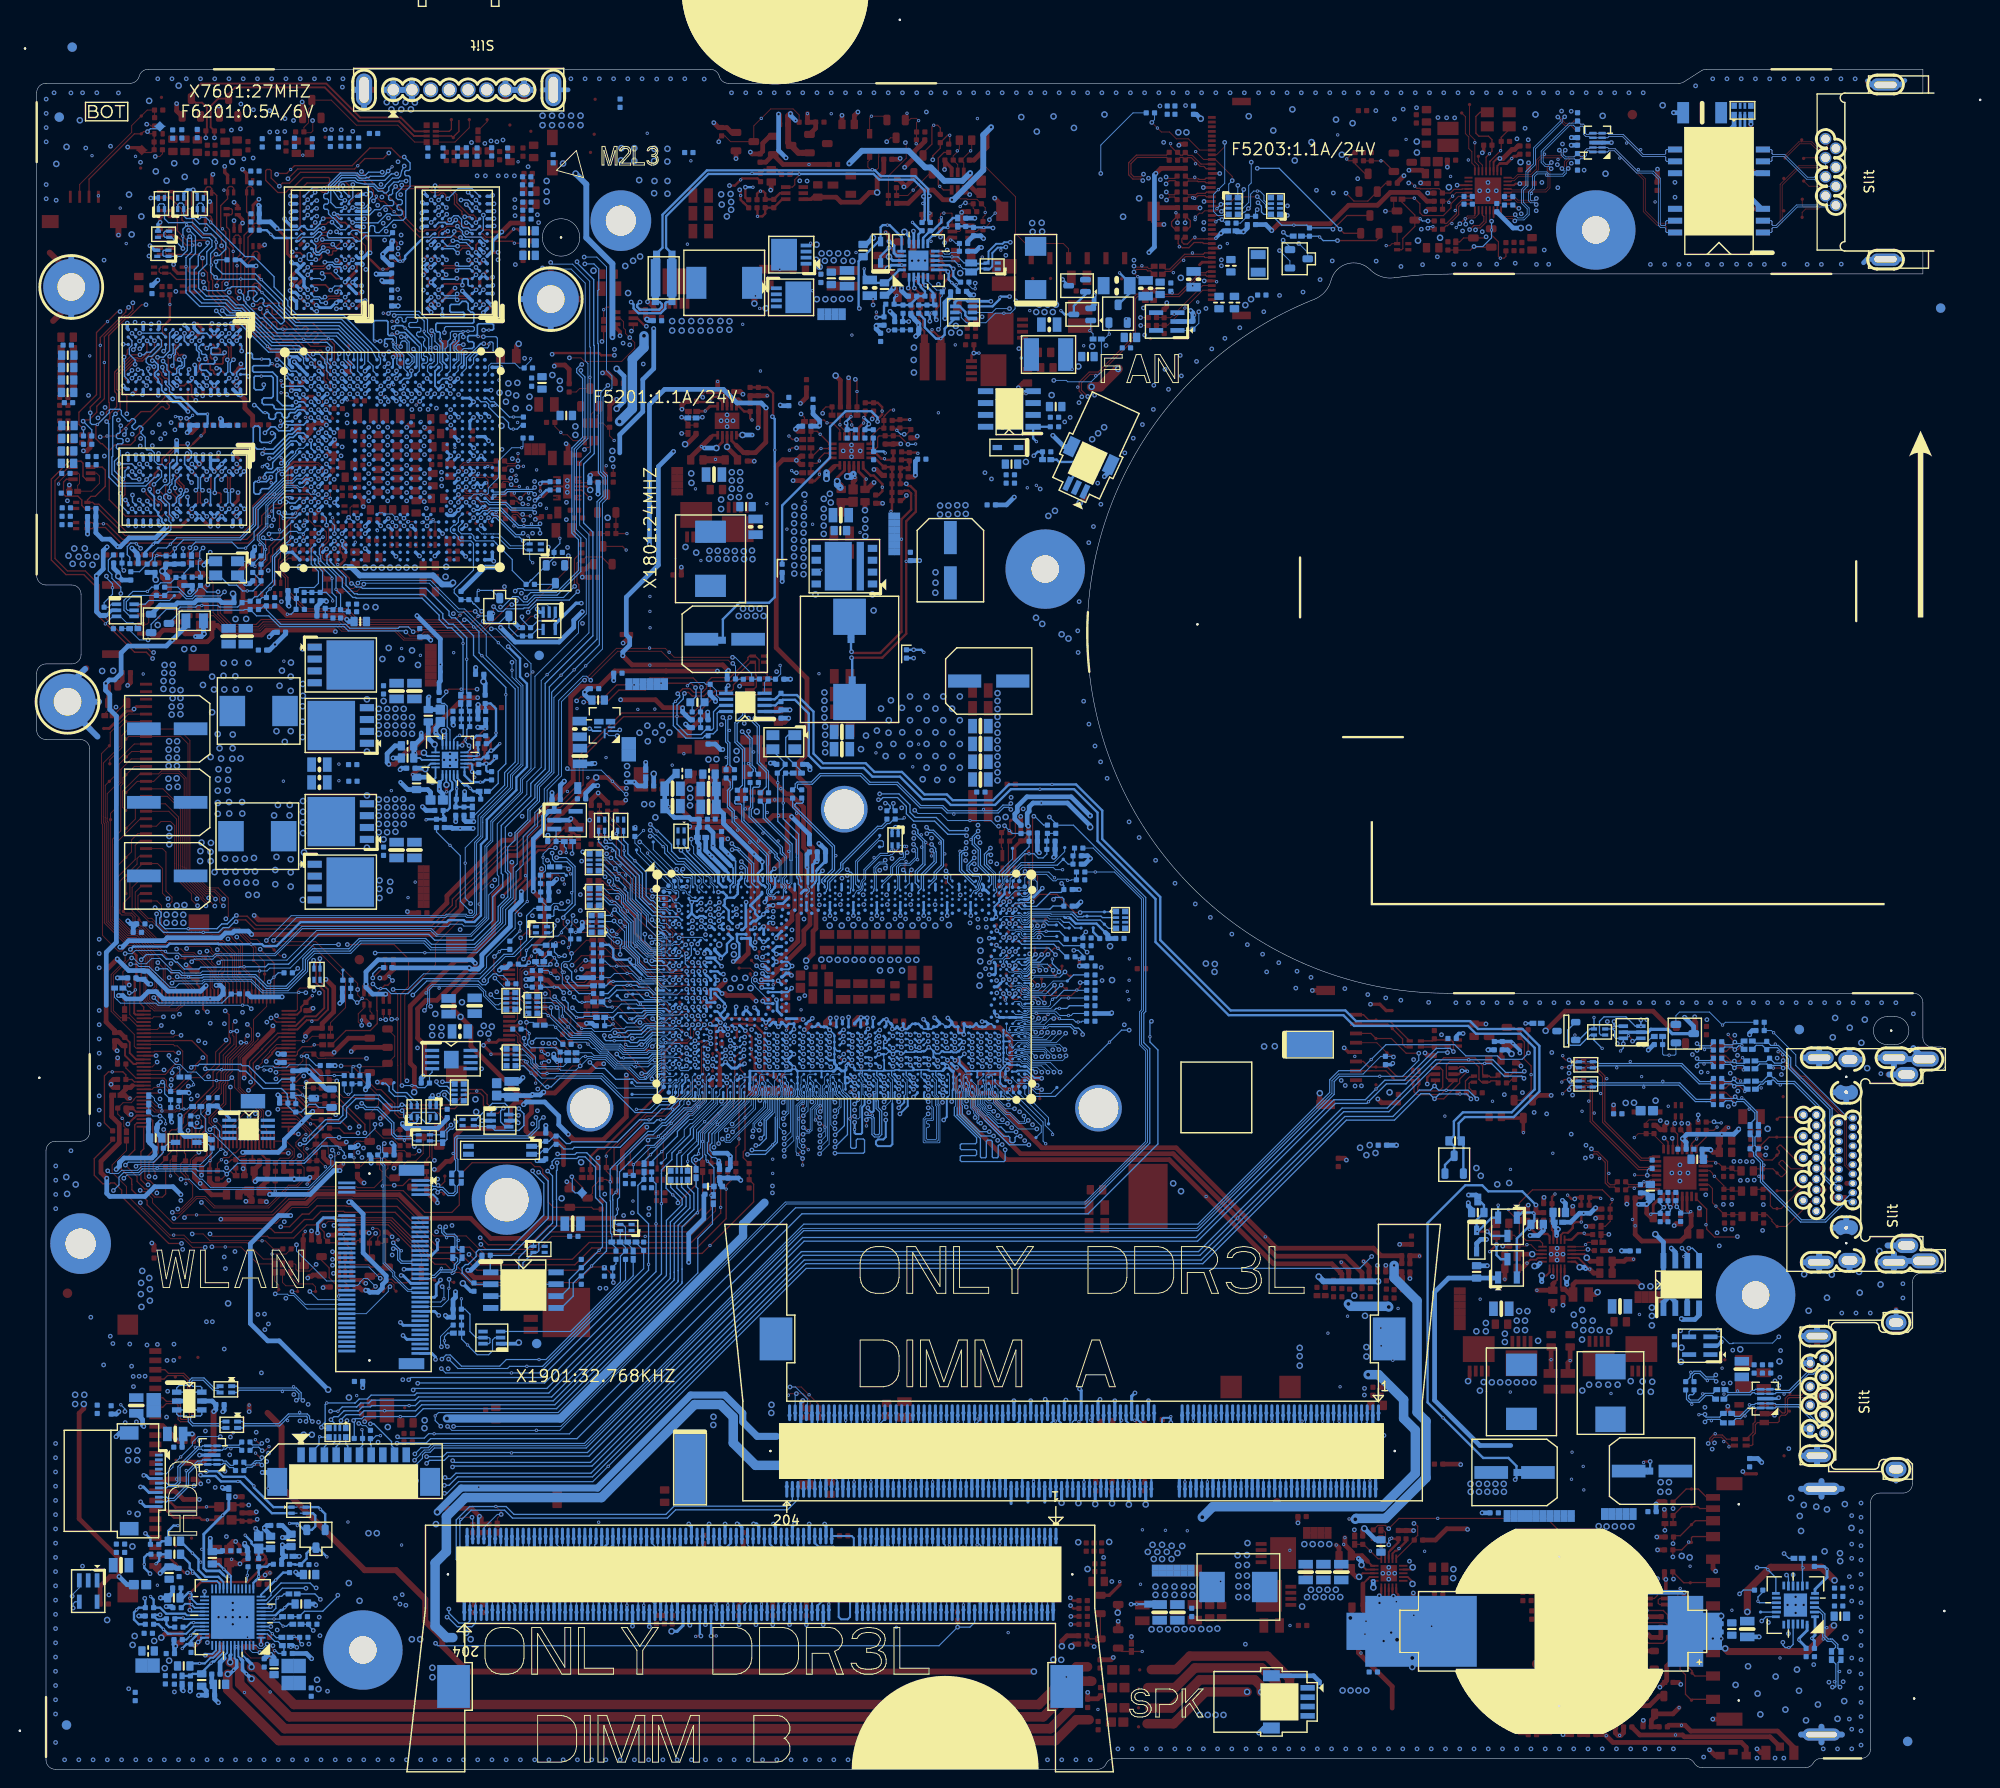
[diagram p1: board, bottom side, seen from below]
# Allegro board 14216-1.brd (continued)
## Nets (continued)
BOOST_MODE#: KBC24.20 PR4418.1 PR4435.2 PR4439.2
BOOST_MON_1: PC4427.1 PR4446.1 PR4452.2
BP_PWRGD_RST#: R9603.2 TP9645.1
BST15V_1: PC4514.2 PD4503.3
BST15V_2: PC4532.2 PD4502.3
BT+: AFTP3905.1 AFTP3907.1 AFTP3908.1 BATT1.1 BATT1.2 EC4303.1 EC4304.1 EC9758.1 EC9759.1 EC9760.1 EC9761.1 PC4415.1 PC4416.1 PC4417.1 PC4418.1 PC4419.1 PD4302.K PG4405.2 PG4410.2 PR4416.2 PU4403.5 PU4403.6 PU4403.7 PU4403.8
BT+_R: PG4404.2 PG4409.2 PL4401.2 PR4416.1
BUFRST#: GPU1.D11 R7628.2
CAMERA_PWR_EN: CPU1.AM4 TP2002.1
CAP_LED: AFTP6243.1 KB1.4 R6201.2
CAP_LED#: KBC24.109 R6202.1
CAP_LED_Q: Q6201.C R6201.1
CAP_LED_R#: Q6201.B R6202.2
CARD_PWR_EN: CPU1.AL2 RN1809.8(B)
CBN: C2703.1 HDA27.35
CBP: C2703.2 HDA27.37
CFG0: CPU1.AC60 TP9626.1
CFG1: CPU1.AC62 TP9627.1
CFG2: CPU1.AC63 TP9620.1
CFG3: CPU1.AA63 R604.1 TP9622.1
CFG4: CPU1.AA60 R605.1 TP9630.1
CFG5: CPU1.Y62 TP9631.1
CFG6: CPU1.Y61 TP9629.1
CFG7: CPU1.Y60 TP9628.1
CFG8: CPU1.V62 TP9633.1
CFG9: CPU1.V61 TP9632.1
CFG10: CPU1.V60 TP9637.1
CFG11: CPU1.U60 TP9639.1
CFG12: CPU1.T63 TP9640.1
CFG13: CPU1.T62 TP9643.1
CFG14: CPU1.T61 TP9642.1
CFG15: CPU1.T60 TP9641.1
CFG16: CPU1.AA62 TP9635.1
CFG17: CPU1.AA61 TP9634.1
CFG18: CPU1.U63 TP9636.1
CFG19: CPU1.U62 TP9638.1
CFG_RCOMP: CPU1.V63 R601.2
CHARGER_SRC: EC4401.1 EC4402.1 PC4406.1 PC4408.1 PC4409.1 PC4426.1 PG4412.2 PG4413.2 PG4414.2 PG4415.2 PU4405.5 PU4405.6 PU4405.7 PU4405.8
CHG_AGND: PC4010.2 PC4403.2 PC4404.2 PC4412.2 PC4420.2 PC4422.2 PC4423.2 PG4411.1 PQ4401.1 PQ4401.4 PR4413.2 PR4423.2 PR4424.2 PR4431.2 PU4401.21
CHG_AMBER_LED#: KBC24.16 R6105.1
CHG_AMBER_LED_R#: Q6101.B R6105.2
CLK_DP2VGA: R1813.2 U5502.17
CLK_LAN_REQ4#_R: LOM30.12 Q3002.E R3004.2 R3005.2
CLK_LAN_REQ#_EN: Q3002.B R3003.2
CLK_PCI_KBC: EC1801.1 KBC24.2 R1805.2
CLK_PCI_KBC_R: CPU1.AP15 R1805.1
CLK_PCI_LPC: DB1.9 R1804.2
CLK_PCI_LPC_R: CPU1.AN15 R1804.1 R1813.1
CLK_PCIE_LAN_N4: CPU1.B38 LOM30.16
CLK_PCIE_LAN_P4: CPU1.C37 LOM30.15
CLK_PCIE_LAN_REQ4#: CPU1.N1 Q3002.C R3005.1 RN1505.6(B)
CLK_PCIE_REQ#: CPU1.T2 CPU1.U2 CPU1.Y5 RN1801.6(B)
CLK_PCIE_VGA: CPU1.B39 GPU1.AE8
CLK_PCIE_VGA#: CPU1.A39 GPU1.AD8
CLK_PCIE_WLAN_N3: CPU1.C41 EC5801.1 WLAN1.49
CLK_PCIE_WLAN_P3: CPU1.B42 EC5802.1 WLAN1.47
CLK_PCIE_WLAN_REQ3#: CPU1.AD1 R5803.2 RN2002.8(B)
CLK_PCIE_WLAN_REQ#: AFTP5802.1 R5803.1 WLAN1.53
CODEC_BITCLK_R: HDA27.6 R2720.2
CODEC_SDOUT_R: HDA27.5 R2719.2
COLOR_ENGINE: CPU1.E3 TP2003.1
COMBO-GPI: HDA27.48 TP2702.1
CPU_ID: CPU1.L4 R1512.2 R1515.1
CPU_RXN_C_DGPU_TXN0: C7302.1 CPU1.F10
CPU_RXN_C_DGPU_TXN1: C7304.1 CPU1.F8
CPU_RXN_C_DGPU_TXN2: C7306.1 CPU1.H10
CPU_RXN_C_DGPU_TXN3: C7308.1 CPU1.E6
CPU_RXP_C_DGPU_TXP0: C7301.1 CPU1.E10
CPU_RXP_C_DGPU_TXP1: C7303.1 CPU1.E8
CPU_RXP_C_DGPU_TXP2: C7305.1 CPU1.G10
CPU_RXP_C_DGPU_TXP3: C7307.1 CPU1.F6
CPVEE: C2704.2 HDA27.34
CR_GPIO0: TP3201.1 U3201.17
CRT_B: AFTP5503.1 C5518.1 HDMI1.3 L5502.2
CRT_DDCCLK_CON: AFTP5506.1 C5511.1 HDMI1.15 RN5501.2(A) U5502.4
CRT_DDCDATA_CON: AFTP5505.1 C5516.1 HDMI1.12 RN5501.1(A) U5502.6
CRT_G: AFTP5502.1 C5510.1 HDMI1.2 L5501.2
CRT_HSYNC_CON: AFTP5508.1 C5513.1 HDMI1.13 R5511.2
CRT_PCH_HPD: R5510.1 R5517.1 U5502.1
CRT_R: AFTP5501.1 C5514.1 HDMI1.1 L5503.2
CRT_VSYNC_CON: AFTP5507.1 C5507.1 HDMI1.14 R5507.2
DBC_EN: CPU1.K3 R5213.2 RN1505.7(B)
DBC_EN_R: LCD1.8 R5213.1
DC_IN_D: PQ4402.3 PR4404.2
DC_TEST_A3_B3: CPU1.A3 CPU1.B3
DC_TEST_A61_B61: CPU1.A61 CPU1.B61
DC_TEST_AY2_AW2: CPU1.AW2 CPU1.AY2
DC_TEST_AY3_AW3: CPU1.AW3 CPU1.AY3
DC_TEST_AY61_AW61: CPU1.AW61 CPU1.AY61
DC_TEST_AY62_AW62: CPU1.AW62 CPU1.AY62
DC_TEST_B62_B63: CPU1.B62 CPU1.B63
DC_TEST_C1_C2: CPU1.C1 CPU1.C2
DCBATOUT: EC9701.1 EC9702.1 EC9703.1 EC9704.1 EC9705.1 EC9706.1 EC9707.1 EC9708.1 EC9709.1 EC9710.1 EC9711.1 EC9712.1 EC9713.1 EC9714.1 EC9715.1 EC9716.1 EC9717.1 EC9740.1 EC9741.1 EC9742.1 EC9747.1 EC9748.1 EC9749.2 F5201.1 PC4431.1 PC4519.1 PC4531.1 PG4403.1 PG4412.1 PG4413.1 PG4414.1 PG4415.1 PG4518.2 PG4520.2 PG4521.2 PG4524.2 PG4525.2 PG4531.2 PG4534.2 PG4536.2 PG4542.2 PG4543.2 PG4703.1 PG4704.1 PG4705.1 PG4706.1 PG4707.1 PG4708.1 PG4827.2 PG4834.2 PG4837.2 PG4838.2 PG4903.2 PG4904.2 PG4905.2 PG4906.2 PG8201.1 PG8202.1 PG8203.1 PG8204.1 PG8205.1 PG8206.1 PG8207.1 PG8208.1 PG8209.1 PG8210.1 PG8211.1 PG8212.1 PR4402.2 PR4468.1 PR8202.1 PR8312.2 PT4702.1 PU4403.1 PU4403.2 PU4403.3 PU4407.3 PU4503.12 R5214.1
DCBATOUT_LCD: C5202.1 C5205.2 F5201.2 LCD1.1 LCD1.2 R5214.2
DCBATOUT_R: PG4404.1 PR4448.1
DDC_CLK_HDMI: HDMI1.HP15 Q5402.3 RN5401.1(A)
DDC_CLK_PH1: D5401.2 RN5401.4(B)
DDC_DATA_HDMI: HDMI1.HP16 Q5402.6 RN5401.2(A)
DDC_DATA_PH2: D5401.1 RN5401.3(B)
DDR3_DRAMRST#: C1217.1 C1301.1 DM1.30 DM2.30 R404.2
DDR_PG_CTRL: CPU1.AV61 R1205.1
DDR_PG_CTRL_R: Q1201.S R1205.2
DDR_VREF_S3: PR4911.2 R3704.1 R3710.1 R3712.1
DDR_VTT_PG_CTRL: PR4909.2 Q1201.D Q1202.G R1204.1 R1208.2
DDR_VTT_PG_CTRL_R: PR4909.1 PR4910.1 PU4901.17
DDR_WR_VREF01: C3702.1 CPU1.AR51 R3702.1
DDR_WR_VREF02: C3703.1 CPU1.AP51 R3713.1
DGPU_HOLD_RST#: CPU1.L3 EC1502.1 R7304.1 RN1503.4(B) U7301.1
DGPU_PWR_EN: CPU1.L1 PQ8305.2 PR8260.1 RN1503.3(B) U8301.5
DGPU_PWR_EN#: PQ8305.5 PQ8305.6 PQ8307.G PR8313.2
DGPU_PWROK: CPU1.R5 D8301.2 EC1501.1 PR8203.2 PU8201.13 R1509.2 R2437.1 R8312.1 R8313.1
DGPU_PWROK_KBC: KBC24.63 R2437.2
DGPU_RXN_C_CPU_TXN0: C1606.1 GPU1.AG7
DGPU_RXN_C_CPU_TXN1: C1608.1 GPU1.AE7
DGPU_RXN_C_CPU_TXN2: C1610.1 GPU1.AF9
DGPU_RXN_C_CPU_TXN3: C1612.1 GPU1.AG10
DGPU_RXN_CPU_TXN0: C1606.2 CPU1.C23
DGPU_RXN_CPU_TXN1: C1608.2 CPU1.B23
DGPU_RXN_CPU_TXN2: C1610.2 CPU1.B21
DGPU_RXN_CPU_TXN3: C1612.2 CPU1.B22
DGPU_RXP_C_CPU_TXP0: C1605.1 GPU1.AG6
DGPU_RXP_C_CPU_TXP1: C1607.1 GPU1.AF7
DGPU_RXP_C_CPU_TXP2: C1609.1 GPU1.AE9
DGPU_RXP_C_CPU_TXP3: C1611.1 GPU1.AG9
DGPU_RXP_CPU_TXP0: C1605.2 CPU1.C22
DGPU_RXP_CPU_TXP1: C1607.2 CPU1.A23
DGPU_RXP_CPU_TXP2: C1609.2 CPU1.C21
DGPU_RXP_CPU_TXP3: C1611.2 CPU1.A21
DGPU_TXN_CPU_RXN0: C7302.2 GPU1.AB9
DGPU_TXN_CPU_RXN1: C7304.2 GPU1.AC10
DGPU_TXN_CPU_RXN2: C7306.2 GPU1.AC11
DGPU_TXN_CPU_RXN3: C7308.2 GPU1.AB12
DGPU_TXP_CPU_RXP0: C7301.2 GPU1.AC9
DGPU_TXP_CPU_RXP1: C7303.2 GPU1.AB10
DGPU_TXP_CPU_RXP2: C7305.2 GPU1.AD11
DGPU_TXP_CPU_RXP3: C7307.2 GPU1.AC12
DIS_1D35V_VGA_S0: PQ8306.D PR8315.2
DMIC_CLK: C2723.2 EC5206.1 R2716.1 R5207.2
DMIC_CLK_EDP: LCD1.27 R5207.1
DMIC_CLK_R: HDA27.3 R2716.2
DMIC_DATA: EC5205.1 R2714.1 R5215.2
DMIC_DATA_EDP: LCD1.28 R5215.1
DMIC_DATA_R: EC2701.1 HDA27.2 R2714.2
DP_CRT_B: C5509.1 L5502.1 R5501.1 U5502.10
DP_CRT_G: C5512.1 L5501.1 R5513.1 U5502.12
DP_CRT_HSYNC_CON: R5511.1 U5502.8
DP_CRT_R: C5506.1 L5503.1 R5514.1 U5502.15
DP_CRT_VSYNC_CON: R5507.1 U5502.7
DS3_PWRCTL: R3802.2 U3801.4
DSWODVREN: CPU1.AW7 R1720.1 R1721.1
E51_RX1: TP5802.1 WLAN1.46
E51_RX2: TP5803.1 WLAN1.58
E51_TX1: R5806.2 WLAN1.44
E51_TX2: TP5804.1 WLAN1.38
E51_TXD: KBC24.111 R5806.1
EAPD#: HDA27.47 R2708.2
EC_AGND: C2402.1 C2403.1 C2404.2 C2405.2 C2414.1 KBC24.103 R2406.2 R2407.2 R2435.2
EC_BRIGHTNESS: D5202.2 KBC24.32
EC_SCI#: CPU1.AM2 R2408.2 RN1809.6(B)
EC_SMI#: CPU1.V1 R2409.2 RN1902.3(A)
EC_SPI_CLK_C: KBC24.92 R2420.2
EC_SPI_CS#_C: KBC24.90 R2419.2
EC_SPI_DI_C: KBC24.87 R2422.2
EC_SPI_DO_C: KBC24.86 R2423.2
EC_SWI#: CPU1.AM3 R2410.2 RN2012.8(B)
EC_VBKUP: KBC24.114 R2428.1
EC_VTT: C2401.1 KBC24.12 R2401.2
ECRST#: C2418.1 KBC24.85 Q2404.E R2418.1 R2424.2
ECSCI#_KBC: KBC24.29 R2408.1
ECSMI#_KBC: KBC24.6 R2409.1
ECSWI#_KBC: KBC24.123 R2410.1
EDP_AUX: C5212.2 LCD1.11 R5218.1
EDP_AUX#: C5209.2 LCD1.12 R5219.1
EDP_AUX_DN: C5209.1 CPU1.A45
EDP_AUX_DP: C5212.1 CPU1.B45
EDP_BKLT_CTRL: D5202.1 R5206.2 R5222.2
EDP_BRIGHTNESS: CPU1.A43 TP801.1
EDP_COMP: CPU1.D20 R801.2
EDP_HPD: CPU1.D6 RN5201.5(B) RN5203.6(B)
EDP_HPD_CONN: LCD1.9 RN5201.4(A)
EDP_SPARE: CPU1.B43 TP605.1
EDP_TX0: C5210.2 LCD1.15
EDP_TX0#: C5203.2 LCD1.14
EDP_TX0_DN: C5203.1 CPU1.C45
EDP_TX0_DP: C5210.1 CPU1.B46
EDP_TX1: C5213.2 LCD1.18
EDP_TX1#: C5211.2 LCD1.17
EDP_TX1_DN: C5211.1 CPU1.A47
EDP_TX1_DP: C5213.1 CPU1.B47
EDP_VDD_EN: CPU1.C6 D5201.1
FAN1_DAC_1: FAN261.4 KBC24.101
FAN_TACH1: EC2602.1 KBC24.31 R2415.1 R2606.1
FAN_TACH1_C: AFTP2802.1 FAN1.3 R2606.2
FAN_VCC1: AFTP2801.1 C2603.1 C2604.1 D2601.K EC2601.1 FAN1.1 FAN261.3
FB_CAL_PD_VDDQ: GPU1.D22 R7505.1
FB_CAL_PU_GND: GPU1.C24 R7507.2
FB_CAL_TERM_GND: GPU1.B25 R7506.1
FB_CLAM: GPU1.F3 R7518.1 R7519.1
FB_VREF: GPU1.D23 TP7503.1
FBA_CLK0N: GPU1.D25 R7810.1 VRAM1.K7 VRAM2.K7 VRAM5.K7 VRAM6.K7
FBA_CLK0P: GPU1.D24 R7810.2 VRAM1.J7 VRAM2.J7 VRAM5.J7 VRAM6.J7
FBA_CLK1N: GPU1.M22 R7914.1 VRAM3.K7 VRAM4.K7 VRAM7.K7 VRAM8.K7
FBA_CLK1P: GPU1.N22 R7914.2 VRAM3.J7 VRAM4.J7 VRAM7.J7 VRAM8.J7
FBA_CMD0: GPU1.C27 R7512.1 VRAM1.K1 VRAM2.K1 VRAM5.K1 VRAM6.K1
FBA_CMD1: GPU1.C26 VRAM5.L2 VRAM6.L2
FBA_CMD2: GPU1.E24 VRAM1.L2 VRAM2.L2
FBA_CMD3: GPU1.F24 R7510.1 VRAM1.K9 VRAM2.K9 VRAM5.K9 VRAM6.K9
FBA_CMD4: GPU1.D27 RN7510.1(A) RN7510.2(A) VRAM1.R3 VRAM2.R3 VRAM3.R3 VRAM4.R3 VRAM5.R7 VRAM6.R7 VRAM7.R7 VRAM8.R7
FBA_CMD5: GPU1.D26 RN7519.1(A) RN7519.2(A) VRAM1.R8 VRAM2.R8 VRAM3.R8 VRAM4.R8 VRAM5.R2 VRAM6.R2 VRAM7.R2 VRAM8.R2
FBA_CMD6: GPU1.F25 RN7506.1(A) RN7506.2(A) VRAM1.N2 VRAM2.N2 VRAM3.N2 VRAM4.N2 VRAM5.N8 VRAM6.N8 VRAM7.N8 VRAM8.N8
FBA_CMD7: GPU1.F26 RN7517.1(A) RN7517.2(A) VRAM1.N3 VRAM2.N3 VRAM3.N3 VRAM4.N3 VRAM5.N7 VRAM6.N7 VRAM7.N7 VRAM8.N7
FBA_CMD8: GPU1.F23 RN7518.1(A) RN7518.2(A) VRAM1.T8 VRAM2.T8 VRAM3.T8 VRAM4.T8 VRAM5.T8 VRAM6.T8 VRAM7.T8 VRAM8.T8
FBA_CMD9: GPU1.G22 RN7522.1(A) RN7522.2(A) VRAM1.N7 VRAM2.N7 VRAM3.N7 VRAM4.N7 VRAM5.N3 VRAM6.N3 VRAM7.N3 VRAM8.N3
FBA_CMD10: GPU1.G23 RN7507.1(A) RN7507.2(A) VRAM1.P7 VRAM2.P7 VRAM3.P7 VRAM4.P7 VRAM5.P3 VRAM6.P3 VRAM7.P3 VRAM8.P3
FBA_CMD11: GPU1.G24 RN7503.1(A) RN7503.2(A) VRAM1.J3 VRAM2.J3 VRAM3.J3 VRAM4.J3 VRAM5.J3 VRAM6.J3 VRAM7.J3 VRAM8.J3
FBA_CMD12: GPU1.F27 RN7509.1(A) RN7509.2(A) VRAM1.T3 VRAM2.T3 VRAM3.T3 VRAM4.T3 VRAM5.T7 VRAM6.T7 VRAM7.T7 VRAM8.T7
FBA_CMD13: GPU1.G25 RN7512.1(A) RN7512.2(A) VRAM1.N8 VRAM2.N8 VRAM3.N8 VRAM4.N8 VRAM5.N2 VRAM6.N2 VRAM7.N2 VRAM8.N2
FBA_CMD14: GPU1.G27 RN7514.1(A) RN7514.2(A) VRAM1.T7 VRAM2.T7 VRAM3.T7 VRAM4.T7 VRAM5.T3 VRAM6.T3 VRAM7.T3 VRAM8.T3
FBA_CMD15: GPU1.G26 RN7504.1(A) RN7504.2(A) VRAM1.K3 VRAM2.K3 VRAM3.K3 VRAM4.K3 VRAM5.K3 VRAM6.K3 VRAM7.K3 VRAM8.K3
FBA_CMD16: GPU1.M24 R7511.1 VRAM3.K1 VRAM4.K1 VRAM7.K1 VRAM8.K1
FBA_CMD17: GPU1.M23 VRAM7.L2 VRAM8.L2
FBA_CMD18: GPU1.K24 VRAM3.L2 VRAM4.L2
FBA_CMD19: GPU1.K23 R7509.1 VRAM3.K9 VRAM4.K9 VRAM7.K9 VRAM8.K9
FBA_CMD20: GPU1.M27 R7508.1 VRAM1.T2 VRAM2.T2 VRAM3.T2 VRAM4.T2 VRAM5.T2 VRAM6.T2 VRAM7.T2 VRAM8.T2
FBA_CMD21: GPU1.M26 RN7520.1(A) RN7520.2(A) VRAM1.R2 VRAM2.R2 VRAM3.R2 VRAM4.R2 VRAM5.R8 VRAM6.R8 VRAM7.R8 VRAM8.R8
FBA_CMD22: GPU1.M25 RN7501.1(A) RN7501.2(A) VRAM1.P8 VRAM2.P8 VRAM3.P8 VRAM4.P8 VRAM5.P2 VRAM6.P2 VRAM7.P2 VRAM8.P2
FBA_CMD23: GPU1.K26 RN7513.1(A) RN7513.2(A) VRAM1.R7 VRAM2.R7 VRAM3.R7 VRAM4.R7 VRAM5.R3 VRAM6.R3 VRAM7.R3 VRAM8.R3
FBA_CMD24: GPU1.K22 RN7505.1(A) RN7505.2(A) VRAM1.P3 VRAM2.P3 VRAM3.P3 VRAM4.P3 VRAM5.P7 VRAM6.P7 VRAM7.P7 VRAM8.P7
FBA_CMD25: GPU1.J23 RN7511.1(A) RN7511.2(A) VRAM1.L7 VRAM2.L7 VRAM3.L7 VRAM4.L7 VRAM5.L3 VRAM6.L3 VRAM7.L3 VRAM8.L3
FBA_CMD26: GPU1.J25 RN7508.1(A) RN7508.2(A) VRAM1.P2 VRAM2.P2 VRAM3.P2 VRAM4.P2 VRAM5.P8 VRAM6.P8 VRAM7.P8 VRAM8.P8
FBA_CMD27: GPU1.J24 RN7521.1(A) RN7521.2(A) VRAM1.M3 VRAM2.M3 VRAM3.M3 VRAM4.M3
FBA_CMD28: GPU1.K27 RN7515.1(A) RN7515.2(A) VRAM1.L3 VRAM2.L3 VRAM3.L3 VRAM4.L3 VRAM5.L7 VRAM6.L7 VRAM7.L7 VRAM8.L7
FBA_CMD29: GPU1.K25 RN7516.1(A) RN7516.2(A) VRAM1.M2 VRAM2.M2 VRAM3.M2 VRAM4.M2 VRAM5.M2 VRAM6.M2 VRAM7.M2 VRAM8.M2
FBA_CMD30: GPU1.J27 RN7502.1(A) RN7502.2(A) VRAM5.M3 VRAM6.M3 VRAM7.M3 VRAM8.M3
FBA_CMD31: GPU1.J26 TP7504.1
FBA_D0: GPU1.E18 VRAM2.F8 VRAM6.F2
FBA_D1: GPU1.F18 VRAM2.F7 VRAM6.E3
FBA_D2: GPU1.E16 VRAM2.H7 VRAM6.H3
FBA_D3: GPU1.F17 VRAM2.H8 VRAM6.G2
FBA_D4: GPU1.D20 VRAM2.H3 VRAM6.H7
FBA_D5: GPU1.D21 VRAM2.E3 VRAM6.F7
FBA_D6: GPU1.F20 VRAM2.G2 VRAM6.H8
FBA_D7: GPU1.E21 VRAM2.F2 VRAM6.F8
FBA_D8: GPU1.E15 VRAM1.F2 VRAM5.F8
FBA_D9: GPU1.D15 VRAM1.G2 VRAM5.H8
FBA_D10: GPU1.F15 VRAM1.H3 VRAM5.H7
FBA_D11: GPU1.F13 VRAM1.E3 VRAM5.F7
FBA_D12: GPU1.C13 VRAM1.H7 VRAM5.H3
FBA_D13: GPU1.B13 VRAM1.F7 VRAM5.E3
FBA_D14: GPU1.E13 VRAM1.H8 VRAM5.G2
FBA_D15: GPU1.D13 VRAM1.F8 VRAM5.F2
FBA_D16: GPU1.B15 VRAM1.C8 VRAM5.C2
FBA_D17: GPU1.C16 VRAM1.D7 VRAM5.C3
FBA_D18: GPU1.A13 VRAM1.B8 VRAM5.A2
FBA_D19: GPU1.A15 VRAM1.A7 VRAM5.A3
FBA_D20: GPU1.B18 VRAM1.A3 VRAM5.A7
FBA_D21: GPU1.A18 VRAM1.A2 VRAM5.B8
FBA_D22: GPU1.A19 VRAM1.C3 VRAM5.D7
FBA_D23: GPU1.C19 VRAM1.C2 VRAM5.C8
FBA_D24: GPU1.B24 VRAM2.C2 VRAM6.C8
FBA_D25: GPU1.C23 VRAM2.C3 VRAM6.D7
FBA_D26: GPU1.A25 VRAM2.A3 VRAM6.A7
FBA_D27: GPU1.A24 VRAM2.A2 VRAM6.B8
FBA_D28: GPU1.A21 VRAM2.B8 VRAM6.A2
FBA_D29: GPU1.B21 VRAM2.A7 VRAM6.A3
FBA_D30: GPU1.C20 VRAM2.C8 VRAM6.C2
FBA_D31: GPU1.C21 VRAM2.D7 VRAM6.C3
FBA_D32: GPU1.R22 VRAM3.H3 VRAM7.H7
FBA_D33: GPU1.R24 VRAM3.G2 VRAM7.H8
FBA_D34: GPU1.T22 VRAM3.E3 VRAM7.F7
FBA_D35: GPU1.R23 VRAM3.F2 VRAM7.F8
FBA_D36: GPU1.N25 VRAM3.H8 VRAM7.G2
FBA_D37: GPU1.N26 VRAM3.H7 VRAM7.H3
FBA_D38: GPU1.N23 VRAM3.F7 VRAM7.E3
FBA_D39: GPU1.N24 VRAM3.F8 VRAM7.F2
FBA_D40: GPU1.V23 VRAM4.F8 VRAM8.F2
FBA_D41: GPU1.V22 VRAM4.H7 VRAM8.H3
FBA_D42: GPU1.T23 VRAM4.H8 VRAM8.G2
FBA_D43: GPU1.U22 VRAM4.F7 VRAM8.E3
FBA_D44: GPU1.Y24 VRAM4.E3 VRAM8.F7
FBA_D45: GPU1.AA24 VRAM4.F2 VRAM8.F8
FBA_D46: GPU1.Y22 VRAM4.G2 VRAM8.H8
FBA_D47: GPU1.AA23 VRAM4.H3 VRAM8.H7
FBA_D48: GPU1.AD27 VRAM4.A2 VRAM8.B8
FBA_D49: GPU1.AB25 VRAM4.A3 VRAM8.A7
FBA_D50: GPU1.AD26 VRAM4.C3 VRAM8.D7
FBA_D51: GPU1.AC25 VRAM4.C2 VRAM8.C8
FBA_D52: GPU1.AA27 VRAM4.D7 VRAM8.C3
FBA_D53: GPU1.AA26 VRAM4.A7 VRAM8.A3
FBA_D54: GPU1.W26 VRAM4.B8 VRAM8.A2
FBA_D55: GPU1.Y25 VRAM4.C8 VRAM8.C2
FBA_D56: GPU1.R26 VRAM3.B8 VRAM7.A2
FBA_D57: GPU1.T25 VRAM3.A7 VRAM7.A3
FBA_D58: GPU1.N27 VRAM3.C8 VRAM7.C2
FBA_D59: GPU1.R27 VRAM3.D7 VRAM7.C3
FBA_D60: GPU1.V26 VRAM3.A2 VRAM7.B8
FBA_D61: GPU1.V27 VRAM3.A3 VRAM7.A7
FBA_D62: GPU1.W27 VRAM3.C3 VRAM7.D7
FBA_D63: GPU1.W25 VRAM3.C2 VRAM7.C8
FBA_DEBUG0: GPU1.F22 R7501.1
FBA_DEBUG1: GPU1.J22 R7503.1
FBA_DQM0: GPU1.D19 VRAM2.E7 VRAM6.E7
FBA_DQM1: GPU1.D14 VRAM1.E7 VRAM5.E7
FBA_DQM2: GPU1.C17 VRAM1.D3 VRAM5.D3
FBA_DQM3: GPU1.C22 VRAM2.D3 VRAM6.D3
FBA_DQM4: GPU1.P24 VRAM3.E7 VRAM7.E7
FBA_DQM5: GPU1.W24 VRAM4.E7 VRAM8.E7
FBA_DQM6: GPU1.AA25 VRAM4.D3 VRAM8.D3
FBA_DQM7: GPU1.U25 VRAM3.D3 VRAM7.D3
FBA_DQS_RN0: GPU1.F19 VRAM2.G3 VRAM6.G3
FBA_DQS_RN1: GPU1.C14 VRAM1.G3 VRAM5.G3
FBA_DQS_RN2: GPU1.A16 VRAM1.B7 VRAM5.B7
FBA_DQS_RN3: GPU1.A22 VRAM2.B7 VRAM6.B7
FBA_DQS_RN4: GPU1.P25 VRAM3.G3 VRAM7.G3
FBA_DQS_RN5: GPU1.W22 VRAM4.G3 VRAM8.G3
FBA_DQS_RN6: GPU1.AB27 VRAM4.B7 VRAM8.B7
FBA_DQS_RN7: GPU1.T27 VRAM3.B7 VRAM7.B7
FBA_EDC0: GPU1.E19 VRAM2.F3 VRAM6.F3
FBA_EDC1: GPU1.C15 VRAM1.F3 VRAM5.F3
FBA_EDC2: GPU1.B16 VRAM1.C7 VRAM5.C7
FBA_EDC3: GPU1.B22 VRAM2.C7 VRAM6.C7
FBA_EDC4: GPU1.R25 VRAM3.F3 VRAM7.F3
FBA_EDC5: GPU1.W23 VRAM4.F3 VRAM8.F3
FBA_EDC6: GPU1.AB26 VRAM4.C7 VRAM8.C7
FBA_EDC7: GPU1.T26 VRAM3.C7 VRAM7.C7
FBA_PLL_AVDD: C7505.1 C7506.1 C7518.1 GPU1.F16 GPU1.H22 GPU1.P22 L7501.1
FBA_VREF_0: C7803.1 R7806.2 R7807.1 VRAM1.H1 VRAM1.M8 VRAM2.H1 VRAM2.M8 VRAM5.H1 VRAM5.M8 VRAM6.H1 VRAM6.M8
FBA_VREF_1: C7902.1 R7903.2 R7904.1 VRAM3.H1 VRAM3.M8 VRAM4.H1 VRAM4.M8 VRAM7.H1 VRAM7.M8 VRAM8.H1 VRAM8.M8
FBA_ZQ0: R7808.2 VRAM1.L8
FBA_ZQ1: R7809.2 VRAM2.L8
FBA_ZQ2: R7912.2 VRAM3.L8
FBA_ZQ3: R7913.2 VRAM4.L8
FBA_ZQ5: R8002.2 VRAM5.L8
FBA_ZQ6: R8001.2 VRAM6.L8
FBA_ZQ7: R8102.2 VRAM7.L8
FBA_ZQ8: R8101.2 VRAM8.L8
FON#: FAN261.1 R2605.2
GC6_FB_EN: D8301.1 R2028.1 R2451.1 R7519.2 R7623.1
GC6_FB_EN_GPU: GPU1.C6 R7623.2 R7627.1
GC6_FB_EN_KBC: KBC24.106 R2451.2
GC6_FB_EN_MCP: CPU1.AG5 R2028.2
GPIO5_GC6_PWR_EN: Q8301.G R7636.2 R8301.1 R8315.2
GPIO5_GC6_PWR_EN#: Q8301.D R8302.2 R8303.1
GPIO5_GC6_PWR_EN_GPU: GPU1.A3 R7633.2 R7636.1
GPIO5_GC6_PWR_EN_R#: C8301.2 Q8302.G R8303.2
GPIO9_ALERT: GPU1.F8 Q7602.1 R7612.1
GPIO10_FBVREF: GPU1.C5 R7610.1
GPU_CLKREQ#: GPU1.AC6 Q7301.S R7303.1 R7305.2
GPU_EVENT#: Q7606.D R2029.1 R7644.1 R7648.1
GPU_EVENT_GPU#: GPU1.A4 Q7606.S R7644.2 R7649.1
GPU_EVENT_MCP#: CPU1.AB6 R2029.2
GPU_PEX_RST#: GPU1.AC7 Q7602.5 R7308.1 R7312.2 R7313.2 R7613.1
GPU_PEX_RST_D#: D7301.3 R7308.2
GPU_PEX_RST_HOLD: D7301.1 R7630.2 R7631.2
GPU_PEX_RST_HOLD_GPU#: GPU1.C4 R7630.1
GPU_PLL_VDD: C7605.1 C7606.1 GPU1.L6 L7601.2
H_CATERR#: CPU1.K61 TP402.1
H_CPU_SVIDALRT#: CPU1.L62 R701.2
H_CPU_SVIDCLK: CPU1.N63 PR4616.2
H_CPU_SVIDDAT: CPU1.L63 PR4619.2 R704.2
H_CPUPWRGD: CPU1.C61 EC401.1 R405.1 R411.2 TP403.1
H_PECI: CPU1.N62 R2429.2
H_PROCHOT#: C2421.1 PR4426.2 PR4465.1 PR4466.2 PR4602.2 PR4624.2 R401.2 R403.1 R2440.2
H_PROCHOT#_EC: Q2401.D R2438.2 R2440.1
H_PROCHOT#_R: CPU1.K63 R403.2
H_RCIN#: CPU1.V4 KBC24.122 RN2002.7(B)
H_THERMTRIP#: Q3602.E R2027.2 R3608.2
H_THERMTRIP_EN: C3604.1 Q3602.B R411.1 R3605.1 R3606.2
H_VCCST_PWRGD: CPU1.B59 EC701.1 R706.2 R707.2 R709.1 R9601.1 U701.4
H_VR_ENABLE: CPU1.F60 PR4621.2 R710.1
HDA_BITCLK: CPU1.AW8 R1907.2
HDA_CODEC_BITCLK: EC1901.2 EC2709.1 R1907.1 R2720.1
HDA_CODEC_RST#: EC1902.1 HDA27.11 R1911.1
HDA_CODEC_SDIN0: HDA27.8 R2718.2
HDA_CODEC_SDOUT: EC2708.1 R1912.1 R2719.1
HDA_CODEC_SYNC: HDA27.10 R1908.1
HDA_RST#: CPU1.AU8 R1911.2
HDA_SDIN0: CPU1.AY10 R2718.1
HDA_SDOUT: CPU1.AU11 R1909.2 R1912.2
HDA_SPKR: CPU1.V2 R2006.2 RN2701.2
HDA_SPKR_R: D2701.2 RN2701.3
HDA_SYNC: CPU1.AV11 R1908.2
HDD_DEVSLP: CPU1.P2 R5605.1
HDD_DEVSLP_R: HDD1.5 R5605.2
HDMI_CLK: C5403.1 CPU1.B57
HDMI_CLK#: C5402.1 CPU1.A57
HDMI_CLK#_R: C5402.2 R5401.1 RN5403.5(B)
HDMI_CLK#_R_C: HDMI1.HP12 R5401.2 R5414.1
HDMI_CLK_R: C5403.2 R5402.1 RN5403.6(B)
HDMI_CLK_R_C: HDMI1.HP10 R5402.2 R5414.2
HDMI_CRT_DET: CPU1.C8 R5419.1 R5517.2
HDMI_CRT_N0: C5526.1 CPU1.C54 RN5405.1
HDMI_CRT_N1: C5525.1 CPU1.B58 RN5404.1
HDMI_CRT_P0: C5529.1 CPU1.C55 RN5405.2
HDMI_CRT_P1: C5530.1 CPU1.C58 RN5404.2
HDMI_DATA0: C5405.1 CPU1.A55
HDMI_DATA0#: C5404.1 CPU1.B55
HDMI_DATA0#_R: C5404.2 R5403.1 RN5403.7(B)
HDMI_DATA0#_R_C: HDMI1.HP9 R5403.2 R5416.1
HDMI_DATA0_R: C5405.2 R5404.1 RN5403.8(B)
HDMI_DATA0_R_C: HDMI1.HP7 R5404.2 R5416.2
HDMI_DATA1: C5406.1 RN5404.3
HDMI_DATA1#: C5409.1 RN5404.4
HDMI_DATA1#_R: C5409.2 R5407.1 RN5402.5(B)
HDMI_DATA1#_R_C: HDMI1.HP6 R5407.2 R5417.1
HDMI_DATA1_R: C5406.2 R5408.1 RN5402.6(B)
HDMI_DATA1_R_C: HDMI1.HP4 R5408.2 R5417.2
HDMI_DATA2: C5408.1 RN5405.3
HDMI_DATA2#: C5407.1 RN5405.4
HDMI_DATA2#_R: C5407.2 R5405.1 RN5402.7(B)
HDMI_DATA2#_R_C: HDMI1.HP3 R5405.2 R5415.1
HDMI_DATA2_R: C5408.2 R5406.1 RN5402.8(B)
HDMI_DATA2_R_C: HDMI1.HP1 R5406.2 R5415.2
HDMI_HPD_B: Q5401.B R5411.2
HDMI_HPD_E: Q5401.E R5412.1 R5419.2
HDMI_PLL_GND: Q5403.D R5418.2 RN5402.1(A) RN5402.2(A) RN5402.3(A) RN5402.4(A) RN5403.1(A) RN5403.2(A) RN5403.3(A) RN5403.4(A)
HPD_HDMI_CON: HDMI1.HP19 R5410.1 R5411.1
HSIO_OUT: R2114.1 U2101.5 U2101.6 U2101.7
HSIOPC: CPU1.Y2 R2007.1 R2123.1
HSIOPC_R: R2123.2 U2101.9
HVM_CLK: CPU1.R20 TP620.1
HVM_CLK#: CPU1.P20 TP619.1
I2C0_SCL: CPU1.F3 RN2007.2(A)
I2C0_SDA: CPU1.F2 RN2007.1(A)
I2C1_SCL: CPU1.F1 EC6203.1 Q6204.1 RN2008.2(A) RN6203.2(A)
I2C1_SCL_R: AFTP6237.1 Q6204.6 R6204.2 RN6203.3(B) RN6204.3(B) TPAD1.6
I2C1_SDA: CPU1.G4 EC6204.1 Q6204.4 RN2008.1(A) RN6203.1(A)
I2C1_SDA_R: AFTP6240.1 Q6204.3 R6210.2 RN6203.4(B) RN6204.4(B) TPAD1.7
I2CA_SCL: GPU1.B7 RN7603.3(B)
I2CA_SDA: GPU1.A7 RN7603.4(B)
I2CB_SCL: GPU1.C9 RN7605.3(B)
I2CB_SDA: GPU1.C8 RN7605.4(B)
I2CC_SCL: GPU1.A9 RN7604.3(B)
I2CC_SDA: GPU1.B9 RN7604.4(B)
IFPAB_IOVDD: GPU1.W6 GPU1.Y6 RN7402.3(B)
IFPAB_PLLVDD: GPU1.V7 GPU1.W7 RN7402.4(B)
IFPC_IOVDD: GPU1.R6 RN7401.3(B)
IFPC_PLLVDD: GPU1.R7 GPU1.T7 RN7401.4(B)
IFPD_IOVDD: GPU1.P6 RN7404.3(B)
IFPD_PLLVDD: GPU1.M7 GPU1.N7 RN7404.4(B)
IFPEF_IOVDD: GPU1.H6 GPU1.J6 RN7403.3(B)
IFPEF_PLLVDD: GPU1.J7 GPU1.K7 RN7403.4(B)
IMVP_PWRGD: KBC24.107 PR4628.2 R713.1 R4622.2
IMVP_PWRGD_R: CPU1.C59 EC702.1 R710.2 R712.1 R713.2
INT_SERIRQ: CPU1.T4 KBC24.125 RN2002.5(B)
INT_TP#: AFTP6241.1 D2001.K R2021.1 R2448.1 R6203.1 TPAD1.4
INT_TP#_C: D2001.A R2019.2 R2021.2 R2030.2 R2031.2
ISOLATE#: LOM30.20 R3014.2 R3015.1
ISUM_R_C: PC4707.2 PC4708.2 PC4709.1 PC4710.1 PG4702.1 PR4704.2 PR4705.1 PR4708.2
ISUM_R_R: PC4709.2 PR4706.1
JACK_PLUG: AFTP6307.1 CN6301.23 R2923.1
JDREF: HDA27.15 R2707.1
JGND: AFTP3803.1 AFTP3806.1 DCIN1.5 DCIN1.6 EC4201.2 EC4202.2 EL4203.1 EL4204.1
KB_BL_CTRL: KBC24.22 Q6202.G R6208.1
KB_BL_CTRL#: AFTP6247.1 EC6207.1 KB_BL1.4 Q6202.D
KB_DET#: AFTP6202.1 CPU1.K2 KB1.30 RN1505.8(B)
KB_LED_BL_DET: CPU1.J1 R6206.1 R6207.1
KB_LED_DET_C: AFTP6246.1 C6203.1 KB_BL1.2 R6206.2
KBC_BEEP: KBC24.118 RN2701.1
KBC_BEEP_R: D2701.1 RN2701.4
KBC_DPWROK: EC1705.1 KBC24.81 R1718.2 R1725.2
KBC_ON#_GATE: C2417.1 Q2402.G Q2403.G R2433.2
KBC_ON#_GATE_L: R2431.1 R2432.2 R2433.1
KBC_PWRBTN#: R2427.1 R6102.1
KBC_PWRBTN#_C: AFTP6101.1 EC6101.1 ED6101.1 G6101.2 G6102.2 PWR1.2 R6102.2
KBC_VCORF: C2416.1 KBC24.44
KCOL0: AFTP6207.1 KB1.13 KBC24.53
KCOL1: AFTP6206.1 KB1.15 KBC24.52
KCOL2: AFTP6226.1 KB1.14 KBC24.51
KCOL3: AFTP6208.1 KB1.16 KBC24.50
KCOL4: AFTP6224.1 KB1.20 KBC24.49
KCOL5: AFTP6215.1 KB1.21 KBC24.48
KCOL6: AFTP6223.1 KB1.18 KBC24.47
KCOL7: AFTP6213.1 KB1.19 KBC24.43
KCOL8: AFTP6231.1 KB1.17 KBC24.42
KCOL9: AFTP6219.1 KB1.7 KBC24.41
KCOL10: AFTP6232.1 KB1.5 KBC24.40
KCOL11: AFTP6220.1 KB1.6 KBC24.39
KCOL12: AFTP6233.1 KB1.12 KBC24.38
KCOL13: AFTP6203.1 KB1.9 KBC24.37
KCOL14: AFTP6216.1 KB1.8 KBC24.36
KCOL15: AFTP6229.1 KB1.10 KBC24.35
KCOL16: AFTP6225.1 KB1.11 KBC24.34
KROW0: AFTP6228.1 KB1.22 KBC24.54
KROW1: AFTP6227.1 KB1.24 KBC24.55
KROW2: AFTP6218.1 KB1.26 KBC24.56
KROW3: AFTP6234.1 KB1.23 KBC24.57
KROW4: AFTP6230.1 KB1.27 KBC24.58
KROW5: AFTP6214.1 KB1.25 KBC24.59
KROW6: AFTP6222.1 KB1.28 KBC24.60
KROW7: AFTP6221.1 KB1.29 KBC24.61
L_BKLT_CTRL: CPU1.B8 R5206.1
L_BKLT_EN: CPU1.A9 R2444.1
L_BKLT_EN_EC: KBC24.9 R2444.2 R2447.1
LAN_ENABLE_R_C: Q3001.D R3021.2 R3022.1
LAN_MDI0N: EC3102.2 EU3101.2 EU3101.9 LOM30.2 XF3101.11
LAN_MDI0P: EC3101.2 EU3101.1 EU3101.10 LOM30.1 XF3101.12
LAN_MDI1N: EC3104.2 EU3101.5 EU3101.6 LOM30.5 XF3101.7
LAN_MDI1P: EC3103.2 EU3101.4 EU3101.7 LOM30.4 XF3101.8
LAN_MDI2N: EC3106.2 EU3102.2 EU3102.9 LOM30.7 XF3102.8
LAN_MDI2P: EC3105.2 EU3102.1 EU3102.10 LOM30.6 XF3102.7
LAN_MDI3N: EC3108.2 EU3102.5 EU3102.6 LOM30.10 XF3102.12
LAN_MDI3P: EC3107.2 EU3102.4 EU3102.7 LOM30.9 XF3102.11
LAN_TXN_C_PCH_RXN4: C3016.1 LOM30.18
LAN_TXP_C_PCH_RXP4: C3014.1 LOM30.17
LANXIN: C3001.1 LOM30.28 X3001.1
LANXOUT: C3011.1 LOM30.29 X3001.3
LCD_BRIGHTNESS: LCD1.20 RN5201.2(A)
LCD_TST: R2417.1 RN5201.8(B)
LCD_TST_C: LCD1.10 RN5201.1(A)
LCD_TST_EN: D5201.2 KBC24.28 R2417.2
LCDVDD: R5211.2 U5201.3
LCDVDD_EN: D5201.3 R5202.2 U5201.1
LCDVDD_LCD: C5201.1 C5206.2 LCD1.4 LCD1.5 LCD1.6 LCD1.7 R5211.1
LDO1_CAP: C2702.2 HDA27.27 R2711.2
LDO2_CAP: C2712.2 HDA27.39
LDO3_CAP: C2718.1 HDA27.7
LDO_EN: R5502.1 R5512.2 U5502.21
LED0: LOM30.27 TP3003.1
LED1: LOM30.26 TP3002.1
LED2: LOM30.25 TP3001.1
LID_CLOSE#: D2401.K KBC24.17 R2421.1 R6109.1
LID_CLOSE#_C: AFTP6104.1 EC6105.1 PWR1.3 R6109.2
LINE1-L_C: C2907.2 R2922.1
LINE1-L_R: C2908.2 R2921.1
LINE1_L: C2907.1 HDA27.22
LINE1_R: C2908.1 HDA27.21
LINE1_VREFO_L: HDA27.31 R2912.1
LINE1_VREFO_R: HDA27.30 R2913.1
LOM_TCT: C3106.1 XF3101.9 XF3101.10 XF3102.9 XF3102.10
LPC_AD0: KBC24.126 RN1806.5(B) RN6501.4(A)
LPC_AD1: KBC24.127 RN1806.7(B) RN6501.3(A)
LPC_AD2: KBC24.128 RN1806.8(B) RN6501.2(A)
LPC_AD3: KBC24.1 RN1806.6(B) RN6501.1(A)
LPC_FRAME#: KBC24.3 R1801.1 R6501.1
LPC_FRAME#_DEBUG: DB1.6 R6501.2
LPC_LAD0_PCH: CPU1.AU14 RN1806.4(A)
LPC_LAD0_R: DB1.2 RN6501.5(B)
LPC_LAD1_PCH: CPU1.AW12 RN1806.2(A)
LPC_LAD1_R: DB1.3 RN6501.6(B)
LPC_LAD2_PCH: CPU1.AY12 RN1806.1(A)
LPC_LAD2_R: DB1.4 RN6501.7(B)
LPC_LAD3_PCH: CPU1.AW11 RN1806.3(A)
LPC_LAD3_R: DB1.5 RN6501.8(B)
LPC_LFRAME#_PCH: CPU1.AV12 R1801.2
LPSS_GSPI0_MOSI_BBS0_R: CPU1.L8 R2012.2
LPSS_SDIO_D0_CMNHDR: CPU1.D3 R2011.2
M_A_A0: CPU1.AU36 DM1.98
M_A_A1: CPU1.AY37 DM1.97
M_A_A2: CPU1.AR38 DM1.96
M_A_A3: CPU1.AP36 DM1.95
M_A_A4: CPU1.AU39 DM1.92
M_A_A5: CPU1.AR36 DM1.91
M_A_A6: CPU1.AV40 DM1.90
M_A_A7: CPU1.AW39 DM1.86
M_A_A8: CPU1.AY39 DM1.89
M_A_A9: CPU1.AU40 DM1.85
M_A_A10: CPU1.AP35 DM1.107
M_A_A11: CPU1.AW41 DM1.84
M_A_A12: CPU1.AU41 DM1.83
M_A_A13: CPU1.AR35 DM1.119
M_A_A14: CPU1.AV42 DM1.80
M_A_A15: CPU1.AU42 DM1.78
M_A_B_DIMM_ODT: Q1202.S R1206.1 R1207.1 R1209.1 R1210.1
M_A_BS0: CPU1.AU35 DM1.109
M_A_BS1: CPU1.AV35 DM1.108
M_A_BS2: CPU1.AY41 DM1.79
M_A_CAS#: CPU1.AU34 DM1.115
M_A_DIMA_CKE0: CPU1.AU43 DM1.73
M_A_DIMA_CKE1: CPU1.AW43 DM1.74
M_A_DIMA_CLK_DDR0: CPU1.AV37 DM1.101
M_A_DIMA_CLK_DDR1: CPU1.AY36 DM1.102
M_A_DIMA_CLK_DDR#0: CPU1.AU37 DM1.103
M_A_DIMA_CLK_DDR#1: CPU1.AW36 DM1.104
M_A_DIMA_CS#0: CPU1.AP33 DM1.114
M_A_DIMA_CS#1: CPU1.AR32 DM1.121
M_A_DIMA_ODT0: DM1.116 R1206.2
M_A_DIMA_ODT1: DM1.120 R1207.2
M_A_DQ0: CPU1.AH63 DM1.129
M_A_DQ1: CPU1.AH62 DM1.131
M_A_DQ2: CPU1.AK63 DM1.141
M_A_DQ3: CPU1.AK62 DM1.140
M_A_DQ4: CPU1.AH61 DM1.132
M_A_DQ5: CPU1.AH60 DM1.130
M_A_DQ6: CPU1.AK61 DM1.143
M_A_DQ7: CPU1.AK60 DM1.142
M_A_DQ8: CPU1.AM63 DM1.7
M_A_DQ9: CPU1.AM62 DM1.4
M_A_DQ10: CPU1.AP63 DM1.17
M_A_DQ11: CPU1.AP62 DM1.18
M_A_DQ12: CPU1.AM61 DM1.6
M_A_DQ13: CPU1.AM60 DM1.5
M_A_DQ14: CPU1.AP61 DM1.15
M_A_DQ15: CPU1.AP60 DM1.16
M_A_DQ16: CPU1.AP58 DM1.159
M_A_DQ17: CPU1.AR58 DM1.157
M_A_DQ18: CPU1.AM57 DM1.146
M_A_DQ19: CPU1.AK57 DM1.148
M_A_DQ20: CPU1.AL58 DM1.149
M_A_DQ21: CPU1.AK58 DM1.147
M_A_DQ22: CPU1.AR57 DM1.158
M_A_DQ23: CPU1.AN57 DM1.160
M_A_DQ24: CPU1.AP55 DM1.24
M_A_DQ25: CPU1.AR55 DM1.22
M_A_DQ26: CPU1.AM54 DM1.36
M_A_DQ27: CPU1.AK54 DM1.34
M_A_DQ28: CPU1.AL55 DM1.23
M_A_DQ29: CPU1.AK55 DM1.21
M_A_DQ30: CPU1.AR54 DM1.33
M_A_DQ31: CPU1.AN54 DM1.35
M_A_DQ32: CPU1.AY58 DM1.166
M_A_DQ33: CPU1.AW58 DM1.165
M_A_DQ34: CPU1.AY56 DM1.175
M_A_DQ35: CPU1.AW56 DM1.174
M_A_DQ36: CPU1.AV58 DM1.163
M_A_DQ37: CPU1.AU58 DM1.164
M_A_DQ38: CPU1.AV56 DM1.177
M_A_DQ39: CPU1.AU56 DM1.176
M_A_DQ40: CPU1.AY54 DM1.42
M_A_DQ41: CPU1.AW54 DM1.41
M_A_DQ42: CPU1.AY52 DM1.50
M_A_DQ43: CPU1.AW52 DM1.51
M_A_DQ44: CPU1.AV54 DM1.39
M_A_DQ45: CPU1.AU54 DM1.40
M_A_DQ46: CPU1.AV52 DM1.52
M_A_DQ47: CPU1.AU52 DM1.53
M_A_DQ48: CPU1.AK40 DM1.69
M_A_DQ49: CPU1.AK42 DM1.67
M_A_DQ50: CPU1.AM43 DM1.59
M_A_DQ51: CPU1.AM45 DM1.57
M_A_DQ52: CPU1.AK45 DM1.56
M_A_DQ53: CPU1.AK43 DM1.58
M_A_DQ54: CPU1.AM40 DM1.68
M_A_DQ55: CPU1.AM42 DM1.70
M_A_DQ56: CPU1.AM46 DM1.192
M_A_DQ57: CPU1.AK46 DM1.194
M_A_DQ58: CPU1.AM49 DM1.183
M_A_DQ59: CPU1.AK49 DM1.182
M_A_DQ60: CPU1.AM48 DM1.191
M_A_DQ61: CPU1.AK48 DM1.193
M_A_DQ62: CPU1.AM51 DM1.181
M_A_DQ63: CPU1.AK51 DM1.180
M_A_DQS0: CPU1.AJ62 DM1.137
M_A_DQS1: CPU1.AN61 DM1.12
M_A_DQS2: CPU1.AN58 DM1.154
M_A_DQS3: CPU1.AN55 DM1.29
M_A_DQS4: CPU1.AW57 DM1.171
M_A_DQS5: CPU1.AW53 DM1.47
M_A_DQS6: CPU1.AL42 DM1.64
M_A_DQS7: CPU1.AL49 DM1.188
M_A_DQS#0: CPU1.AJ61 DM1.135
M_A_DQS#1: CPU1.AN62 DM1.10
M_A_DQS#2: CPU1.AM58 DM1.152
M_A_DQS#3: CPU1.AM55 DM1.27
M_A_DQS#4: CPU1.AV57 DM1.169
M_A_DQS#5: CPU1.AV53 DM1.45
M_A_DQS#6: CPU1.AL43 DM1.62
M_A_DQS#7: CPU1.AL48 DM1.186
M_A_RAS#: CPU1.AY34 DM1.110
M_A_WE#: CPU1.AW34 DM1.113
M_B_A0: CPU1.AP40 DM2.98
M_B_A1: CPU1.AR40 DM2.97
M_B_A2: CPU1.AP42 DM2.96
M_B_A3: CPU1.AR42 DM2.95
M_B_A4: CPU1.AR45 DM2.92
M_B_A5: CPU1.AP45 DM2.91
M_B_A6: CPU1.AW46 DM2.90
M_B_A7: CPU1.AY46 DM2.86
M_B_A8: CPU1.AY47 DM2.89
M_B_A9: CPU1.AU46 DM2.85
M_B_A10: CPU1.AK36 DM2.107
M_B_A11: CPU1.AV47 DM2.84
M_B_A12: CPU1.AU47 DM2.83
M_B_A13: CPU1.AK33 DM2.119
M_B_A14: CPU1.AR46 DM2.80
M_B_A15: CPU1.AP46 DM2.78
M_B_BS0: CPU1.AL35 DM2.109
M_B_BS1: CPU1.AM36 DM2.108
M_B_BS2: CPU1.AU49 DM2.79
M_B_CAS#: CPU1.AM33 DM2.115
M_B_DIMB_CKE0: CPU1.AY49 DM2.73
M_B_DIMB_CKE1: CPU1.AU50 DM2.74
M_B_DIMB_CLK_DDR0: CPU1.AN38 DM2.101
M_B_DIMB_CLK_DDR1: CPU1.AL38 DM2.102
M_B_DIMB_CLK_DDR#0: CPU1.AM38 DM2.103
M_B_DIMB_CLK_DDR#1: CPU1.AK38 DM2.104
M_B_DIMB_CS#0: CPU1.AM32 DM2.114
M_B_DIMB_CS#1: CPU1.AK32 DM2.121
M_B_DIMB_ODT0: DM2.116 R1209.2
M_B_DIMB_ODT1: DM2.120 R1210.2
M_B_DQ0: CPU1.AY31 DM2.132
M_B_DQ1: CPU1.AW31 DM2.131
M_B_DQ2: CPU1.AY29 DM2.140
M_B_DQ3: CPU1.AW29 DM2.141
M_B_DQ4: CPU1.AV31 DM2.129
M_B_DQ5: CPU1.AU31 DM2.130
M_B_DQ6: CPU1.AV29 DM2.142
M_B_DQ7: CPU1.AU29 DM2.143
M_B_DQ8: CPU1.AY27 DM2.5
M_B_DQ9: CPU1.AW27 DM2.6
M_B_DQ10: CPU1.AY25 DM2.15
M_B_DQ11: CPU1.AW25 DM2.17
M_B_DQ12: CPU1.AV27 DM2.4
M_B_DQ13: CPU1.AU27 DM2.16
M_B_DQ14: CPU1.AV25 DM2.7
M_B_DQ15: CPU1.AU25 DM2.18
M_B_DQ16: CPU1.AM29 DM2.165
M_B_DQ17: CPU1.AK29 DM2.163
M_B_DQ18: CPU1.AL28 DM2.175
M_B_DQ19: CPU1.AK28 DM2.177
M_B_DQ20: CPU1.AR29 DM2.164
M_B_DQ21: CPU1.AN29 DM2.166
M_B_DQ22: CPU1.AR28 DM2.176
M_B_DQ23: CPU1.AP28 DM2.174
M_B_DQ24: CPU1.AN26 DM2.24
M_B_DQ25: CPU1.AR26 DM2.22
M_B_DQ26: CPU1.AR25 DM2.33
M_B_DQ27: CPU1.AP25 DM2.35
M_B_DQ28: CPU1.AK26 DM2.21
M_B_DQ29: CPU1.AM26 DM2.23
M_B_DQ30: CPU1.AK25 DM2.34
M_B_DQ31: CPU1.AL25 DM2.36
M_B_DQ32: CPU1.AY23 DM2.147
M_B_DQ33: CPU1.AW23 DM2.146
M_B_DQ34: CPU1.AY21 DM2.159
M_B_DQ35: CPU1.AW21 DM2.160
M_B_DQ36: CPU1.AV23 DM2.148
M_B_DQ37: CPU1.AU23 DM2.149
M_B_DQ38: CPU1.AV21 DM2.157
M_B_DQ39: CPU1.AU21 DM2.158
M_B_DQ40: CPU1.AY19 DM2.39
M_B_DQ41: CPU1.AW19 DM2.41
M_B_DQ42: CPU1.AY17 DM2.53
M_B_DQ43: CPU1.AW17 DM2.52
M_B_DQ44: CPU1.AV19 DM2.42
M_B_DQ45: CPU1.AU19 DM2.40
M_B_DQ46: CPU1.AV17 DM2.51
M_B_DQ47: CPU1.AU17 DM2.50
M_B_DQ48: CPU1.AR21 DM2.191
M_B_DQ49: CPU1.AR22 DM2.183
M_B_DQ50: CPU1.AL21 DM2.194
M_B_DQ51: CPU1.AM22 DM2.180
M_B_DQ52: CPU1.AN22 DM2.181
M_B_DQ53: CPU1.AP21 DM2.193
M_B_DQ54: CPU1.AK21 DM2.192
M_B_DQ55: CPU1.AK22 DM2.182
M_B_DQ56: CPU1.AN20 DM2.57
M_B_DQ57: CPU1.AR20 DM2.59
M_B_DQ58: CPU1.AK18 DM2.69
M_B_DQ59: CPU1.AL18 DM2.67
M_B_DQ60: CPU1.AK20 DM2.58
M_B_DQ61: CPU1.AM20 DM2.56
M_B_DQ62: CPU1.AR18 DM2.70
M_B_DQ63: CPU1.AP18 DM2.68
M_B_DQS0: CPU1.AV30 DM2.137
M_B_DQS1: CPU1.AW26 DM2.12
M_B_DQS2: CPU1.AM28 DM2.171
M_B_DQS3: CPU1.AM25 DM2.29
M_B_DQS4: CPU1.AV22 DM2.154
M_B_DQS5: CPU1.AW18 DM2.47
M_B_DQS6: CPU1.AM21 DM2.188
M_B_DQS7: CPU1.AM18 DM2.64
M_B_DQS#0: CPU1.AW30 DM2.135
M_B_DQS#1: CPU1.AV26 DM2.10
M_B_DQS#2: CPU1.AN28 DM2.169
M_B_DQS#3: CPU1.AN25 DM2.27
M_B_DQS#4: CPU1.AW22 DM2.152
M_B_DQS#5: CPU1.AV18 DM2.45
M_B_DQS#6: CPU1.AN21 DM2.186
M_B_DQS#7: CPU1.AN18 DM2.62
M_B_RAS#: CPU1.AM35 DM2.110
M_B_WE#: CPU1.AK35 DM2.113
M_VREF_CA_DIMMA: C1201.1 C1202.1 C1218.1 DM1.126 R3703.1 R3704.2 R3705.1 R3706.2 R3708.1
M_VREF_CA_DIMMB: C1306.1 C1308.1 C1309.1 DM2.126 R3705.2
M_VREF_DQ_DIMMA: C1204.1 C1205.1 C1206.1 DM1.1 R3701.2 R3702.2 R3709.1 R3710.2
M_VREF_DQ_DIMMB: C1302.1 C1305.1 C1310.1 DM2.1 R3712.2 R3713.2 R3714.1 R3716.2
MCP_GPIO8: CPU1.AU2 R2015.2 R2031.1
MCP_GPIO11: CPU1.AN2 RN1809.5(B)
MCP_GPIO12: CPU1.AM7 RN1701.4(B)
MCP_GPIO13: CPU1.AT3 R2020.2
MCP_GPIO14: CPU1.AH4 R2016.2
MCP_GPIO15: CPU1.AD6 R2014.2
MCP_GPIO26: CPU1.AN3 R2009.2
MCP_GPIO27: CPU1.AN5 RN2006.3(B)
MCP_GPIO28: CPU1.AD7 R2017.2
MCP_GPIO36: CPU1.V6 RN1902.1(A)
MCP_GPIO44: CPU1.AK4 R2002.2
MCP_GPIO46: CPU1.AG3 R2010.2 R2030.1
MCP_GPIO55: CPU1.U7 R2019.1 RN1902.2(A)
MCP_GPIO56: CPU1.AG6 R2004.2
MCP_GPIO57: CPU1.AP1 R2022.2
MCP_GPIO58: CPU1.AL4 R2001.2
MCP_GPIO73: CPU1.AU4 RN1601.6(B)
MCP_GPIO76: CPU1.P1 RN1801.8(B)
MCP_R: R2001.1 R2002.1 R2004.1 R2009.1 R2013.1 R2016.1 R2017.1 R2020.1
MCP_TESTLOW1: CPU1.C35 RN1803.4(B)
MCP_TESTLOW2: CPU1.C34 RN1803.3(B)
MCP_TESTLOW3: CPU1.AK8 RN1804.3(B)
MCP_TESTLOW4: CPU1.AL8 RN1804.4(B)
MCT: C3101.1 RN3101.5(B) RN3101.6(B) RN3101.7(B) RN3101.8(B)
MCT0: RN3101.4(A) XF3102.3
MCT1: RN3101.1(A) XF3102.4
MCT2: RN3101.3(A) XF3101.4
MCT3: RN3101.2(A) XF3101.3
MDO0+: AFTP3107.1 RJ45.1 XF3101.1
MDO0-: AFTP3102.1 RJ45.2 XF3101.2
MDO1+: AFTP3101.1 RJ45.3 XF3101.5
MDO1-: AFTP3106.1 RJ45.6 XF3101.6
MDO2+: AFTP3103.1 RJ45.4 XF3102.6
MDO2-: AFTP3104.1 RJ45.5 XF3102.5
MDO3+: AFTP3105.1 RJ45.7 XF3102.2
MDO3-: AFTP3108.1 RJ45.8 XF3102.1
ME_UNLOCK: KBC24.23 R1909.1
MIC2_VREFO: HDA27.29 RN2901.1(A) RN2901.2(A)
MIC_CAP: C2713.1 HDA27.19
MIC_GND: LCD1.26 R5201.1
MODEL_ID_DET: C2403.2 KBC24.94 R2407.1 R2446.2
MPWROK: CPU1.AB5 R1707.2
N12P_JTAG_TCK: GPU1.AE5 RN7602.3(B)
N12P_JTAG_TDI: GPU1.AE6 TP7605.1
N12P_JTAG_TDO: GPU1.AF6 TP7601.1
N12P_JTAG_TMS: GPU1.AD6 TP7602.1
N12P_JTAG_TRST: GPU1.AG4 RN7602.4(B)
N12P_XTAL_OUTBUFF: GPU1.C10 R7602.1 R7617.2
NCT7718_DXN: C2606.2 C2607.2 Q2603.E THM26.3
NCT7718_DXP: C2606.1 C2607.1 Q2603.B Q2603.C THM26.2
ODD_PWR_5V: C5610.1 ODD1.10 ODD1.11 ODD1.12 ODD1.13 ODD1.14 ODD1.15 R5603.2 U5601.6 U5601.7 U5601.8
OVER_CURRENT_P8#: D7602.K KBC24.65
OVERT#: C7609.1 Q7602.4 R7613.2 R7645.2 R7652.1
OVERT_GPU#: GPU1.A6 R7652.2
P2800_VGA_DXN: GPU1.E12 TP7603.1
P2800_VGA_DXP: GPU1.F12 TP7604.1
P_H_S#: Q7602.3 R7653.1
PANEL_SIZE_ID: CPU1.J2 R5208.2 R5209.1 R5210.2
PANEL_SIZE_ID_CONN: LCD1.22 R5210.1
PBAT_PRES1#: AFTP3902.1 BATT1.5 RN4301.8(B)
PBAT_SMBCLK1: AFTP3904.1 BATT1.3 RN4301.6(B)
PBAT_SMBDAT1: AFTP3903.1 BATT1.4 RN4301.7(B)
PCB_VER_AD: C2402.2 KBC24.98 R2404.2 R2406.1
PCH_DPB_AUXN: C5528.1 CPU1.C5
PCH_DPB_AUXP: C5527.1 CPU1.B5
PCH_DPC_AUXN_U: C5528.2 U5502.27
PCH_DPC_AUXP_U: C5527.2 U5502.26
PCH_DPC_N0_U: C5526.2 U5502.30
PCH_DPC_N1_U: C5525.2 U5502.32
PCH_DPC_P0_U: C5529.2 U5502.29
PCH_DPC_P1_U: C5530.2 U5502.31
PCH_DPWROK: CPU1.AV5 R1704.1 R1718.1
PCH_HDMI_CLK: CPU1.B9 Q5402.4 RN1501.4(B)
PCH_HDMI_DATA: CPU1.C9 Q5402.1 RN1501.3(B)
PCH_INTVRMEN: CPU1.AV7 R1903.2 R1913.2
PCH_JTAG_TCK: CPU1.AE62 R1920.2
PCH_JTAG_TDI: CPU1.AD61 R1916.1
PCH_JTAG_TDO: CPU1.AE61 R1917.1
PCH_JTAG_TMS: CPU1.AD62 R1918.1
PCH_JTAG_TRST#: CPU1.AU62 TP1901.1
PCH_OPIRCOMP: CPU1.AW15 R2003.1
PCH_PWROK: EC1704.1 KBC24.100 Q2602.G Q3601.3 R1706.1
PCH_SLP_S0#: CPU1.AF3 TP1706.1
PCH_SLP_WLAN#: CPU1.AM5 TP1705.1
PCH_SMBCLK: DM1.202 DM2.202 EC6206.1 Q1801.4 R6204.1 RN1810.3(B) RN9601.2(A) U5502.2
PCH_SMBDATA: DM1.200 DM2.200 EC6205.1 Q1801.1 R6210.1 RN1810.4(B) RN9601.1(A) U5502.3
PCH_SPI_CLK: CPU1.AA3 R1806.2
PCH_SPI_CS0#: CPU1.Y7 R1807.2
PCH_SPI_DQ2: CPU1.Y6 R1811.2 R1815.1
PCH_SPI_DQ3: CPU1.AF1 R1812.2 R1814.1
PCH_SPI_SI: CPU1.AA2 R1808.2
PCH_SPI_SO: CPU1.AA4 R1809.2
PCH_THERMTRIP: CPU1.D60 R2018.2 R2027.1
PCH_VCCDSW_R: C2114.1 R2110.2
PCH_WAKE#: CPU1.AJ5 R1703.2 R1705.1
PCI_PLTRST#: CPU1.AG7 R1713.2
PCI_PME#: CPU1.AD4 TP1501.1
PCIE_CLK_XDP_N: CPU1.B35 TP9651.1
PCIE_CLK_XDP_P: CPU1.A35 TP9652.1
PCIE_PRX_LANTX_N4: C3016.2 CPU1.F13
PCIE_PRX_LANTX_P4: C3014.2 CPU1.G13
PCIE_PRX_WLANTX_N3: CPU1.G11 R5808.2
PCIE_PRX_WLANTX_N3_R: R5808.1 WLAN1.43
PCIE_PRX_WLANTX_P3: CPU1.F11 R5811.2
PCIE_PRX_WLANTX_P3_R: R5811.1 WLAN1.41
PCIE_PTX_LANRX_N4: C1603.2 CPU1.B29
PCIE_PTX_LANRX_N4_C: C1603.1 LOM30.14
PCIE_PTX_LANRX_P4: C1604.2 CPU1.A29
PCIE_PTX_LANRX_P4_C: C1604.1 LOM30.13
PCIE_PTX_WLANRX_N3: C1601.2 CPU1.C29
PCIE_PTX_WLANRX_N3_C: C1601.1 WLAN1.37
PCIE_PTX_WLANRX_P3: C1602.2 CPU1.B30
PCIE_PTX_WLANRX_P3_C: C1602.1 WLAN1.35
PCIE_RCOMP: CPU1.A27 R1601.2
PCIE_WAKE#: KBC24.113 LOM30.21 R1705.2 R3033.1
PD4403_A: PD4404.A PQ4409.B
PD4403_K: PD4404.K PR4468.2 PR4471.1
PECI: C2422.1 KBC24.13 R2429.1
PEG_CLKREQ#: CPU1.U5 Q7301.D R7305.1 RN2011.7(B)
PEX_TERMP: GPU1.AF25 R7301.1
PEXTSTCLK_OUT: GPU1.AF22 R7307.1
PEXTSTCLK_OUT#: GPU1.AE22 R7307.2
PHASE1G: PG4701.1 PR4702.1
PHASE_R_R: PR4703.2 PR4704.1
PIRQA#: CPU1.U6 RN2011.8(B)
PIRQB#: CPU1.P4 RN1801.7(B)
PIRQC#: CPU1.N4 RN2011.6(B)
PIRQD#: CPU1.N2 RN1505.5(B)
PLT_RST#: C1701.1 EC1703.1 Q3003.E R1713.1 R1715.1 R2416.2 R3016.1 R3606.1 R5212.2 R5807.1 R6502.1 R9602.2 U7301.2
PLT_RST#_DEBUG: DB1.7 R6502.2
PLT_RST#_EC: C2415.2 KBC24.7 R2416.1
PLT_RST#_LAN: LOM30.19 Q3003.C R3016.2 RN3001.3(B)
PLT_RST_NGFF#: AFTP5805.1 R5807.2 WLAN1.52
PM_CLKRUN#: CPU1.V5 R1709.1 R1714.1
PM_CLKRUN#_EC: KBC24.8 R1709.2
PM_LAN_ENABLE: KBC24.119 Q3001.G R3023.1
PM_LAN_ENABLE_R: C3015.2 Q3004.G R3022.2
PM_PCH_PWROK: CPU1.AY7 R1706.2 R1707.1 RN1703.3(B)
PM_PWRBTN#: CPU1.AL7 KBC24.117 R9603.1
PM_RSMRST#: CPU1.AW6 Q1701.3 R1702.1 R1704.2 RN1703.4(B)
PM_SLP_A#: CPU1.AL5 TP1704.1
PM_SLP_LAN#: CPU1.AJ7 TP1707.1
PM_SLP_S3#: CPU1.AT4 KBC24.64 PR4819.1 PR4910.2 PR5110.1 Q3601.2 R3609.1
PM_SLP_S4#: CPU1.AJ6 KBC24.21 PR4907.1
PM_SLP_S5#: CPU1.AP5 TP1703.1
PM_SLP_SUS#: CPU1.AP4 KBC24.108 R1729.2 R3802.1
PM_SUS_STAT#: CPU1.AG4 R1724.2 TP1702.1
PM_SUSACK#: KBC24.91 RN1702.2(A)
PM_SUSACK#_R: CPU1.AK2 R1708.2 RN1702.3(B)
PM_SUSWARN#: KBC24.79 RN1702.1(A)
PM_SUSWARN#_R: CPU1.AV4 R1708.1 RN1601.5(B) RN1702.4(B)
POL1_SDA: R5508.2 R5509.1 U5502.22 U5504.5
POL2_SCL: R5515.1 R5516.2 U5502.23 U5504.6
PQ3802_1: PQ4202.B PR4202.1 PR4209.2
PQ3809_D: PQ4206.D PR4214.2
PQ4008_2: PC4425.1 PQ4408.2 PR4437.2
PQ4008_6: PQ4408.6 PR4426.1
PQ4405_2: PQ4410.2 PR4475.2 PR4476.2
PQ4405_3: PQ4410.3 PR4466.1
PQ4405_5: PC4434.1 PQ4410.5 PR4470.2
PQ4405_6: PC4434.2 PQ4410.6 PR4473.1
PQ4406_D: PQ4414.D PR4465.2
PQ4406_G: PC4433.2 PQ4414.G PR4474.1
PQ4408_C: PQ4409.C PR4464.1 PR4475.1
PQ4408_E: PQ4409.E PR4467.1 PR4469.2
PR4601_1: PR4901.2 PR4906.1
PR4605_2: PC4919.1 PR4905.2
PROC_OPI_COMP: CPU1.AY15 R602.1
PROC_OPI_COMP3: CPU1.Y22 R606.1
PROCHOT_EC: KBC24.24 Q2401.G R2438.1 R2442.1
PROJECT_ID1: CPU1.AC1 R1510.2 R1511.1
PROJECT_ID2: CPU1.L2 R1513.2 R1514.1
PS_ID: PQ4201.S PR4205.1 PR4206.2
PS_ID_R: AFTP3802.1 DCIN1.4 PR4217.1
PS_ID_R2: PD4204.1 PD4204.2 PQ4201.D PR4206.1 PR4209.1 PR4217.2
PS_S3CNTRL: Q3601.5 Q3601.6 R3607.2
PSID_DISABLE#_R_C: PQ4201.G PQ4202.C PR4203.2
PSID_EC: KBC24.99 PD4203.3 PR4204.2 PR4205.2
PSL_IN1#: KBC24.73 R2430.2
PSL_IN2#: KBC24.93 R2425.1 R2427.2
PSL_OUT#: KBC24.74 R2432.1
PU4401_4: PC4424.2 PR4410.2 PR4454.2 PU4407.4
PU4401_5: PC4424.1 PR4410.1 PR4448.2 PU4407.5
PU4401_6: PR4446.2 PU4407.6
PURE_HW_SHUTDOWN#: C2610.1 C7610.1 D3602.3 Q2404.B Q2602.D Q3602.C R2424.1 R2439.2 R2612.1 R7653.2
PWR_1D05V_BOOT: PR4820.1 PU4806.10
PWR_1D05V_BOOT_R: PC4822.2 PR4820.2
PWR_1D05V_CCM: PR4824.1 PU4806.5
PWR_1D05V_EN: PC4821.1 PR4819.2 PU4806.3
PWR_1D5V_EN: PC5102.1 PR5110.2 PU5101.3
PWR_1D05V_FB: PC4823.2 PR4822.2 PR4823.1 PU4806.4
PWR_1D05V_LGATE: PU4805.4 PU4806.6
PWR_1D05V_PHASE: PC4822.1 PL4801.1 PR4837.1 PU4805.5 PU4805.6 PU4805.7 PU4805.8 PU4806.8 PU4808.1 PU4808.2 PU4808.3
PWR_1D05V_PWR: PC4823.1 PG4832.1 PR4822.1
PWR_1D05V_PWRGD: PR4821.1 PU4806.1
PWR_1D05V_SNUB: PC4838.1 PR4837.2
PWR_1D05V_TRIP: PR4817.2 PU4806.2
PWR_1D05V_UGATE: PU4806.9 PU4808.4
PWR_1D35V_DRVH: PU4901.14 PU4902.4
PWR_1D35V_DRVL: PU4901.11 PU4903.4
PWR_1D35V_EN: PC4906.1 PR4907.2 PU4901.16
PWR_1D35V_MODE: PR4908.2 PU4901.19
PWR_1D35V_REFIN: PC4902.1 PR4901.1 PR4903.2 PU4901.8
PWR_1D35V_SW: PC4919.2 PL4902.1 PR4912.1 PU4901.13 PU4902.1 PU4902.2 PU4902.3 PU4903.5 PU4903.6 PU4903.7 PU4903.8
PWR_1D35V_TRIP: PR4902.1 PU4901.18
PWR_1D35V_VBST: PR4905.1 PU4901.15
PWR_1D35V_VDDQS: PG4907.1 PU4901.9
PWR_1D35V_VREF: PC4903.1 PR4903.1 PU4901.6
PWR_1D35V_VTTREF: PC4918.1 PR4911.1 PU4901.5
PWR_3D3V_CS2: PR4517.1 PU4503.5
PWR_3D3V_DRVH2: PU4503.10 PU4504.4
PWR_3D3V_DRVL2: PU4503.11 PU4505.4
PWR_3D3V_EN2: PR4506.2 PU4503.6
PWR_3D3V_FB2: PC4523.2 PR4512.2 PR4523.1 PU4503.4
PWR_3D3V_FB2_R: PC4523.1 PR4535.2
PWR_3D3V_LL2: PC4535.2 PL4502.2 PR4533.1 PU4503.8 PU4504.1 PU4504.2 PU4504.3 PU4505.5 PU4505.6 PU4505.7 PU4505.8
PWR_3D3V_SNUB: PC4520.1 PR4533.2
PWR_3D3V_VBST2: PR4528.2 PU4503.9
PWR_3D3V_VBST2_1: PC4535.1 PR4528.1
PWR_5V_CS1: PR4531.1 PU4503.1
PWR_5V_DRVH1: PU4501.4 PU4503.16
PWR_5V_DRVL1: PU4502.4 PU4503.15
PWR_5V_EN1: PR4504.2 PU4503.20
PWR_5V_EN1_R: PR4501.2 PR4504.1 PR4507.2 PR4530.1
PWR_5V_FB1: PC4522.2 PR4526.1 PR4527.2 PU4503.2
PWR_5V_FB1_R: PC4522.1 PR4525.2
PWR_5V_LL1: PC4516.2 PL4501.1 PR4529.1 PU4501.1 PU4501.2 PU4501.3 PU4502.5 PU4502.6 PU4502.7 PU4502.8 PU4503.18
PWR_5V_SNUB: PC4536.1 PR4529.2
PWR_5V_VBST1: PR4524.1 PU4503.17
PWR_5V_VBST1_1: PC4516.1 PR4524.2
PWR_5V_VCLK: PC4514.1 PC4521.1 PC4532.1 PU4503.19
PWR_5V_VO1: PG4532.2 PR4525.1 PR4527.1 PU4503.14
PWR_CHG_ACDET: PC4412.1 PR4407.2 PR4431.1 PU4401.6
PWR_CHG_ACN: PC4402.2 PC4403.1 PG4403.2 PR4406.1 PU4401.1
PWR_CHG_ACOK: PQ4402.2 PQ4408.3 PR4419.2 PR4428.2 PR4436.1 PR4476.1
PWR_CHG_ACP: PC4402.1 PC4404.1 PG4402.2 PR4406.2 PU4401.2
PWR_CHG_AD_OFF: KBC24.11 PQ4206.G PR4210.1
PWR_CHG_AD_OFF_R: PQ4204.B PR4210.2
PWR_CHG_BAT_SCL: PG4407.1 PU4401.9
PWR_CHG_BAT_SDA: PG4408.1 PU4401.8
PWR_CHG_BTST: PR4409.1 PU4401.17
PWR_CHG_BTST_R: PC4411.1 PD4401.K PR4409.2
PWR_CHG_CMPIN: PR4411.2 PR4413.1 PR4414.2 PR4427.2 PR4429.1 PU4401.4
PWR_CHG_CMPIN_R: PQ4401.6 PR4429.2
PWR_CHG_CMPIN_RR: PQ4401.3 PR4427.1
PWR_CHG_CMPOUT: PR4414.1 PR4430.2 PR4432.1 PR4437.1 PR4438.1 PU4401.3
PWR_CHG_CSON_1: PC4421.2 PC4423.1 PG4410.1 PR4420.2
PWR_CHG_CSOP_1: PC4420.1 PC4421.1 PG4409.1 PR4421.2
PWR_CHG_HIDRV: PC4413.2 PU4401.18 PU4405.4
PWR_CHG_IFAULT: PR4418.2 PU4401.11
PWR_CHG_ILIM: PR4417.2 PR4423.1 PU4401.10
PWR_CHG_IOUT: PC4422.1 PR4411.1 PR4422.1 PR4424.1 PU4401.7
PWR_CHG_LODRV: PU4401.15 PU4406.4
PWR_CHG_PHASE: PC4411.2 PC4413.1 PL4401.1 PR4425.1 PU4401.19 PU4405.1 PU4405.2 PU4405.3 PU4406.5 PU4406.6 PU4406.7 PU4406.8
PWR_CHG_REGN: PC4407.1 PD4401.A PR4428.1 PR4430.1 PU4401.16
PWR_CHG_SNUB: PC4401.1 PR4425.2
PWR_CHG_SRN: PR4420.1 PU4401.12
PWR_CHG_SRP: PR4421.1 PU4401.13
PWR_CHG_VCC: PC4010.1 PR4408.2 PU4401.20
PWR_DCBATOUT_1D05V: PC4814.1 PC4825.1 PC4826.1 PG4827.1 PG4834.1 PG4837.1 PG4838.1 PU4808.5 PU4808.6 PU4808.7 PU4808.8
PWR_DCBATOUT_3D3V: PC4509.1 PC4525.1 PC4528.1 PG4521.1 PG4524.1 PG4525.1 PG4531.1 PU4504.5 PU4504.6 PU4504.7 PU4504.8
PWR_DCBATOUT_5V: PC4527.1 PC4529.1 PC4530.1 PG4518.1 PG4520.1 PG4534.1 PG4536.1 PG4542.1 PG4543.1 PU4501.5 PU4501.6 PU4501.7 PU4501.8
PWR_DCBATOUT_VCCCORE: PC4701.1 PC4702.1 PC4703.1 PC4704.1 PG4703.2 PG4704.2 PG4705.2 PG4706.2 PG4707.2 PG4708.2 PU4701.2 PU4701.3 PU4701.4 PU4701.10
PWR_DCBATOUT_VGA_CORE1: PC8208.1 PC8209.1 PC8210.1 PC8214.1 PC8220.2 PG8207.2 PG8208.2 PG8209.2 PG8210.2 PG8211.2 PG8212.2 PU8202.5 PU8202.6 PU8202.7 PU8202.8 PU8204.5 PU8204.6 PU8204.7 PU8204.8
PWR_DCBATOUT_VGA_CORE2: PC8212.1 PC8213.1 PC8215.1 PC8221.2 PC8224.1 PG8201.2 PG8202.2 PG8203.2 PG8204.2 PG8205.2 PG8206.2 PU8206.5 PU8206.6 PU8206.7 PU8206.8 PU8208.5 PU8208.6 PU8208.7 PU8208.8
PWR_DEBUG: CPU1.H59 R705.2 R9604.1
PWR_LEVEL: D7601.A D7602.A GPU1.D7 R7605.2
PWR_VCC_ALERT#: PR4601.2 PR4618.1 PU4601.19
PWR_VCC_BOOT: PR4701.1 PU4601.13
PWR_VCC_BOOT_RC: PC4706.1 PR4701.2
PWR_VCC_COMP: PC4610.1 PR4613.1 PU4601.6
PWR_VCC_COMP_RC: PC4611.1 PR4613.2
PWR_VCC_EN: PR4621.1 PU4601.1
PWR_VCC_FB: PR4603.1 PR4606.1 PU4601.7
PWR_VCC_FB_RC: PC4601.1 PR4606.2
PWR_VCC_IMON: PC4609.2 PR4610.2 PU4601.3
PWR_VCC_ISUMN: PR4705.2 PR4706.2 PU4601.9
PWR_VCC_ISUMP: PC4707.1 PC4708.1 PR4702.2 PR4703.1 PR4707.1 PR4708.1 PU4601.10
PWR_VCC_LG: PU4601.16 PU4701.8
PWR_VCC_NTC: PR4615.2 PU4601.5
PWR_VCC_NTC_R: PR4615.1 PR4617.1 PR4622.1
PWR_VCC_PHASE: PC4706.2 PG4701.2 PL4701.1 PU4601.15 PU4701.9
PWR_VCC_POK: PR4628.1 PU4601.2
PWR_VCC_PRGM1: PR4614.2 PU4601.17
PWR_VCC_PRGM2: PR4607.2 PU4601.11
PWR_VCC_SCLK: PR4616.1 PR4620.1 PU4601.20
PWR_VCC_SDA: PR4619.1 PR4630.1 PU4601.18
PWR_VCC_UG: PU4601.14 PU4701.1
PWR_VCC_VRHOT#: PR4624.1 PU4601.4
PWR_VGA_CORE_BOOT1: PR8210.1 PU8201.1
PWR_VGA_CORE_BOOT1_1: PC8211.1 PR8210.2
PWR_VGA_CORE_BOOT2: PR8211.1 PU8201.15
PWR_VGA_CORE_BOOT2_1: PC8216.1 PR8211.2
PWR_VGA_CORE_EN: PC8225.2 PR8256.2 PR8260.2 PU8201.3
PWR_VGA_CORE_LGATE1: PR8224.1 PU8201.19 PU8203.4 PU8205.4
PWR_VGA_CORE_LGATE2: PU8201.17 PU8207.4 PU8209.4
PWR_VGA_CORE_PHASE1: PC8211.2 PL8201.1 PR8216.1 PU8201.20 PU8202.1 PU8202.2 PU8202.3 PU8203.5 PU8203.6 PU8203.7 PU8203.8 PU8204.1 PU8204.2 PU8204.3 PU8205.5 PU8205.6 PU8205.7 PU8205.8
PWR_VGA_CORE_PHASE2: PC8216.2 PL8202.1 PR8215.1 PU8201.16 PU8206.1 PU8206.2 PU8206.3 PU8207.5 PU8207.6 PU8207.7 PU8207.8 PU8208.1 PU8208.2 PU8208.3 PU8209.5 PU8209.6 PU8209.7 PU8209.8
PWR_VGA_CORE_PSI: PC8226.2 PR8257.2 PR8258.2 PR8259.1 PU8201.4
PWR_VGA_CORE_REFADJ: PR8222.1 PU8201.6
PWR_VGA_CORE_REFIN: PC8204.1 PR8208.1 PR8209.1 PU8201.7
PWR_VGA_CORE_RGND: PC8201.1 PC8204.2 PC8217.1 PC8219.2 PC8223.2 PR8209.2 PR8213.1 PR8220.1 PU8201.10
PWR_VGA_CORE_SS: PC8205.1 PU8201.11
PWR_VGA_CORE_TON: PR8201.2 PU8201.9
PWR_VGA_CORE_TON_1: PC8202.2 PR8201.1 PR8202.2
PWR_VGA_CORE_UGATE1: PU8201.2 PU8202.4 PU8204.4
PWR_VGA_CORE_UGATE2: PU8201.14 PU8206.4 PU8208.4
PWR_VGA_CORE_VID: PC8203.2 PR8207.2 PU8201.5
PWR_VGA_CORE_VREF: PC8201.2 PR8206.1 PU8201.8
PWR_VGA_CORE_VSNS: PC8219.1 PC8222.1 PR8212.2 PR8221.1 PU8201.12
PWR_VGA_SNUB1: PC8206.1 PR8216.2
PWR_VGA_SNUB2: PC8218.1 PR8215.2
Q402_1: Q3003.B RN3001.4(B)
Q6204_G: Q6204.2 Q6204.5 R6216.2
Q6205_Q: Q6205.D R6211.2
Q7601_G: Q7601.2 Q7601.5 R7624.1
REFIN_VREF: PC8223.1 PR8206.2 PR8208.2 PR8222.2
REGOUT: C3002.1 L3001.1 LOM30.24 R3001.1
RING2: EC2905.1 HDA27.17 R2906.2 RN2901.3(B)
RING2_R: AFTP6305.1 CN6301.21 CN6301.22 R2906.1
ROM_CS#: GPU1.D12 R7626.1
ROM_SCLK: GPU1.C12 R7608.2 R7614.1
ROM_SI: GPU1.B12 R7616.2 R7618.1 R7619.2 R7638.2 R7639.2 R7640.2 R7642.1 R7655.1
ROM_SO: GPU1.A12 R7611.2 R7620.1
RREF: R3203.1 U3201.1
RRX: R5505.1 U5502.28
RSET: LOM30.31 R3032.2
RSMRST#_KBC: KBC24.15 R1702.2
RSVDA51: CPU1.A51 TP606.1
RSVDAU63: CPU1.AU63 TP602.1
RSVDAV63: CPU1.AV63 TP601.1
RSVDB51: CPU1.B51 TP607.1
RSVDC62: CPU1.C62 TP604.1
RSVDC63: CPU1.C63 TP603.1
RSVDL60: CPU1.L60 TP608.1
RSVDN59: CPU1.N59 TP704.1
RSVDN61: CPU1.N61 TP705.1
RSVDP60: CPU1.P60 TP702.1
RSVDP61: CPU1.P61 TP703.1
RT8812_PVCC: PC8207.1 PR8223.2 PU8201.18
RTC_AUX_S5: C1120.1 C1121.1 C1122.1 C2503.1 CPU1.AG10 D2501.3 R1720.2 R1901.1 R1903.1 R2428.2 RN1901.1(A) RN1901.2(A)
RTC_DET#: CPU1.AD5 Q2505.D RN2012.5(B)
RTC_PWR: D2501.2 Q2505.G R2502.1 R2504.1
RTC_RST#: C1901.1 CPU1.AU7 EC1903.1 G1901.2 Q1901.D RN1901.3(B)
RTC_X1: C1903.2 CPU1.AW5 R1915.1 X1901.1
RTC_X2: C1904.2 CPU1.AY5 R1915.2 X1901.4
RTCRST_ON: KBC24.120 Q1901.G R1902.1
S5_ENABLE: KBC24.14 Q2403.D R2436.2 R3603.2
SA0_DIMA: DM1.197 R1201.1
SA0_DIMB: DM2.197 R1301.1
SA1_DIMA: DM1.201 R1202.1
SA1_DIMB: DM2.201 R1302.2
SATA3_PRX_HDDTX_N0: C5616.1 CPU1.J5
SATA3_PRX_HDDTX_P0: C5615.1 CPU1.H5
SATA3_PTX_HDDRX_N0: C5603.2 CPU1.B15
SATA3_PTX_HDDRX_P0: C5602.2 CPU1.A15
SATA_IREF: CPU1.A12 R1904.1
SATA_LED: EC6104.1 Q6104.C R6108.1
SATA_LED#: CPU1.U3 Q6103.S Q6105.S R1905.2 R2405.1 R6106.1
SATA_LED#_B: Q6103.D Q6104.B R6106.2
SATA_LED#_R: KBC24.95 Q6105.G R2405.2 R6110.2
SATA_LED_R: HDLED1.1A R6108.2
SATA_ODD_DA#: CPU1.T3 R5602.2 RN2002.6(B)
SATA_ODD_DA#_C: ODD1.17 R5602.1
SATA_ODD_PRSNT#: CPU1.U1 ODD1.8 R5604.1 RN1902.4(A)
SATA_ODD_PWRGT: CPU1.N6 R5607.2 U5601.4
SATA_PRX_ODDTX_N1: C5607.2 CPU1.J8
SATA_PRX_ODDTX_P1: C5608.2 CPU1.H8
SATA_PTX_ODDRX_N1: C5611.2 CPU1.A17
SATA_PTX_ODDRX_P1: C5612.2 CPU1.B17
SATA_RCOMP: CPU1.C12 R1906.1
SATA_RXN0_R: C5616.2 EU5602.4 EU5602.7 HDD1.8
SATA_RXN2_R: C5607.1 ODD1.5
SATA_RXP0_R: C5615.2 EU5602.5 EU5602.6 HDD1.7
SATA_RXP2_R: C5608.1 ODD1.6
SATA_TXN0_R: C5603.1 EU5602.2 EU5602.9 HDD1.10
SATA_TXN2_R: C5611.1 ODD1.3
SATA_TXP0_R: C5602.1 EU5602.1 EU5602.10 HDD1.11
SATA_TXP2_R: C5612.1 ODD1.2
SD_CD#: R3301.1 U3201.13
SD_CD_R#: AFTP3304.1 CARD1.10 EC3305.1 R3301.2
SD_CLK: AFTP3303.1 CARD1.5 EC3201.1 R3201.2
SD_CLK_5170: R3201.1 U3201.15
SD_CMD: AFTP3302.1 CARD1.2 EC3304.1 U3201.18
SD_D0: AFTP3306.1 CARD1.7 EC3306.1 U3201.11
SD_D1: AFTP3307.1 CARD1.8 EC3301.1 U3201.10
SD_D2: AFTP3308.1 CARD1.9 EC3302.1 U3201.21
SD_D3: AFTP3309.1 CARD1.1 EC3303.1 U3201.20
SD_WP: AFTP3305.1 CARD1.11 EC3307.1 R3202.1
SD_WP_5170: R3202.2 U3201.8
SDREFG: C3206.1 U3201.6
SLEEVE: EC2906.1 HDA27.18 R2911.2 RN2901.4(B)
SLEEVE_R: AFTP6310.1 CN6301.19 CN6301.20 R2911.1
SM_DRAMRST#: CPU1.AV15 EU401.1 R404.1 R410.2
SM_INTRUDER#: CPU1.AU6 R1901.2
SM_RCOMP_0: CPU1.AU60 R407.2
SM_RCOMP_1: CPU1.AV60 R408.2
SM_RCOMP_2: CPU1.AU61 R409.2
SMB_CLK: CPU1.AP2 Q1801.3 RN1811.3(B)
SMB_DATA: CPU1.AH1 Q1801.6 RN1811.4(B)
SMBC_THERM_NV: GPU1.D9 Q7601.1 RN7601.2(A)
SMBD_THERM_NV: GPU1.D8 Q7601.4 RN7601.1(A)
SML0_CLK: CPU1.AN1 RN1807.5(B)
SML0_DATA: CPU1.AK1 RN1807.6(B)
SML1_CLK: CPU1.AU3 KBC24.67 Q2601.3 Q7601.6 RN1807.8(B)
SML1_DATA: CPU1.AH3 KBC24.68 Q2601.6 Q7601.3 RN1807.7(B)
SP_PLLVDD: C7601.1 C7602.1 C7603.1 C7604.1 GPU1.M6 GPU1.N6 L7602.2
SPI_CLK_R: EC2503.1 R1806.1 R2420.1 SPI25.6
SPI_CS0#_R: R1807.1 R2419.1 R2501.1 SPI25.1
SPI_HOLD#: R1812.1 RN2501.2(A) SPI25.7
SPI_SI_R: EC2501.1 R1808.1 R2422.1 SPI25.5
SPI_SO_R: EC2502.1 R1809.1 R2423.1 SPI25.2
SPI_WP#: R1811.1 RN2501.1(A) SPI25.3
SRTC_RST#: C1902.1 CPU1.AV6 RN1901.4(B)
STRAP0: GPU1.D1 R7621.1 R7625.2 R7646.2
STRAP1: GPU1.D2 R7622.1 R7635.2 R7647.1
STRAP2: GPU1.E4 R7606.2 R7637.1
STRAP3: GPU1.E3 R7609.1 R7615.2 R7650.1
STRAP4: GPU1.D3 R7632.1 R7634.2 R7654.1
STRAP_REF0_GND_N9: GPU1.F6 R7607.2
SUS_CLK: R1710.2 R2441.2
SUS_CLK_PCH: CPU1.AE6 EC1701.2 R1710.1
SUSCLK_KBC: KBC24.77 R2441.1
SYS_PEX_RST_MON#: D7301.2 R7304.2 R7306.1 R7313.1 R7629.2 U7301.4
SYS_PEX_RST_MON_GPU#: GPU1.E9 R7629.1 R7643.1
SYS_PRES1#: AFTP3901.1 BATT1.6 R4301.2
SYS_PWROK: CPU1.AG2 EC1702.1 KBC24.84 R1717.1 R9605.1
T_CRIT#: R2601.1 R2604.2 THM26.4
TD_IREF: CPU1.B12 R603.2
TESTMODE: GPU1.AD9 R7302.1
THERM_SYS_SHDN#: Q2602.S R2601.2 R2602.1
THM_SML1_CLK: C2608.1 Q2601.4 RN2602.4(B) THM26.8
THM_SML1_DATA: C2609.1 Q2601.1 RN2602.3(B) THM26.7
TOUCH_PANEL_INTR#: D2401.A R2411.1 R2443.1 R5205.2
TOUCH_PANEL_INTR_KBC#: KBC24.124 R2411.2
TP_CL_CLK: CPU1.AF2 TP1801.1
TP_CL_DATA: CPU1.AD2 TP1802.1
TP_CL_RST#: CPU1.AF4 TP1803.1
TP_DC_TEST_A4: CPU1.A4 TP2202.1
TP_DC_TEST_A60: CPU1.A60 TP2203.1
TP_DC_TEST_A62: CPU1.A62 TP2205.1
TP_DC_TEST_AV1: CPU1.AV1 TP2206.1
TP_DC_TEST_AW1: CPU1.AW1 TP2207.1
TP_DC_TEST_AW63: CPU1.AW63 TP2208.1
TP_DC_TEST_AY60: CPU1.AY60 TP2201.1
TP_DC_TEST_B2: CPU1.B2 TP2204.1
TP_HDA_DOCK_EN#: CPU1.AW10 TP1902.1
TP_LOCK#: AFTP6242.1 R2450.1 TPAD1.3
TP_LOCK#_C: KBC24.26 R2426.1 R2450.2
TP_M_A_DIMA_ODT0: CPU1.AP32 TP501.1
TP_M_B_DIMB_ODT0: CPU1.AL32 TP503.1
TP_ON#: KBC24.33 R2452.1 R2453.1 R6214.1
TP_ON#_GATE: C6204.2 Q6203.G Q6205.G R6214.2
TP_ON#_S: C6204.1 Q6203.S R6213.1 R6215.2 R6217.2
TP_RESET: C5214.1 LCD1.38 R5212.1
TP_RS: C5208.1 LCD1.37 R5205.1
TP_V1.05S_APLLOPI: CPU1.AC20 TP2105.1
TP_V1.05S_AXCK_DCB: CPU1.M20 TP2104.1
TP_V1.05S_SSCF100: CPU1.K18 TP2103.1
TP_V1.05S_SSCFF: CPU1.V21 TP2101.1
TP_VCCAPLLOPI_VAL: CPU1.Y20 TP2102.1
TP_VCCIO_OUT: CPU1.A59 TP701.1
TP_VDD: AFTP6239.1 C6201.1 Q6203.D R2426.2 R6203.2 R6209.1 R6211.1 R6212.2 R6213.2 RN6201.1(A) RN6201.2(A) RN6204.1(A) RN6204.2(A) TPAD1.8
TP_WAKE_KBC#: KBC24.121 R2448.2
TPAN_VDD: F5203.2 LCD1.40 R5232.1
TPAN_VDD_F: F5203.1 R5230.2 R5231.2 R5232.2
TPCLK: EC6201.1 KBC24.72 RN6201.4(B) RN6202.1(A)
TPCLK_C: AFTP6238.1 RN6202.4(B) TPAD1.1
TPDATA: EC6202.1 KBC24.71 RN6201.3(B) RN6202.2(A)
TPDATA_C: AFTP6236.1 RN6202.3(B) TPAD1.2
TPS51216_PHS_SET: PC4922.1 PR4912.2
USB3_PRX_CTX_N0: CPU1.G20 R3411.2
USB3_PRX_CTX_N0_C: R3411.1 U3402.1 U3402.10 USB1.5
USB3_PRX_CTX_P0: CPU1.H20 R3410.2
USB3_PRX_CTX_P0_C: R3410.1 U3402.2 U3402.9 USB1.6
USB3_PTX_CRX_N0: C3403.1 CPU1.C33
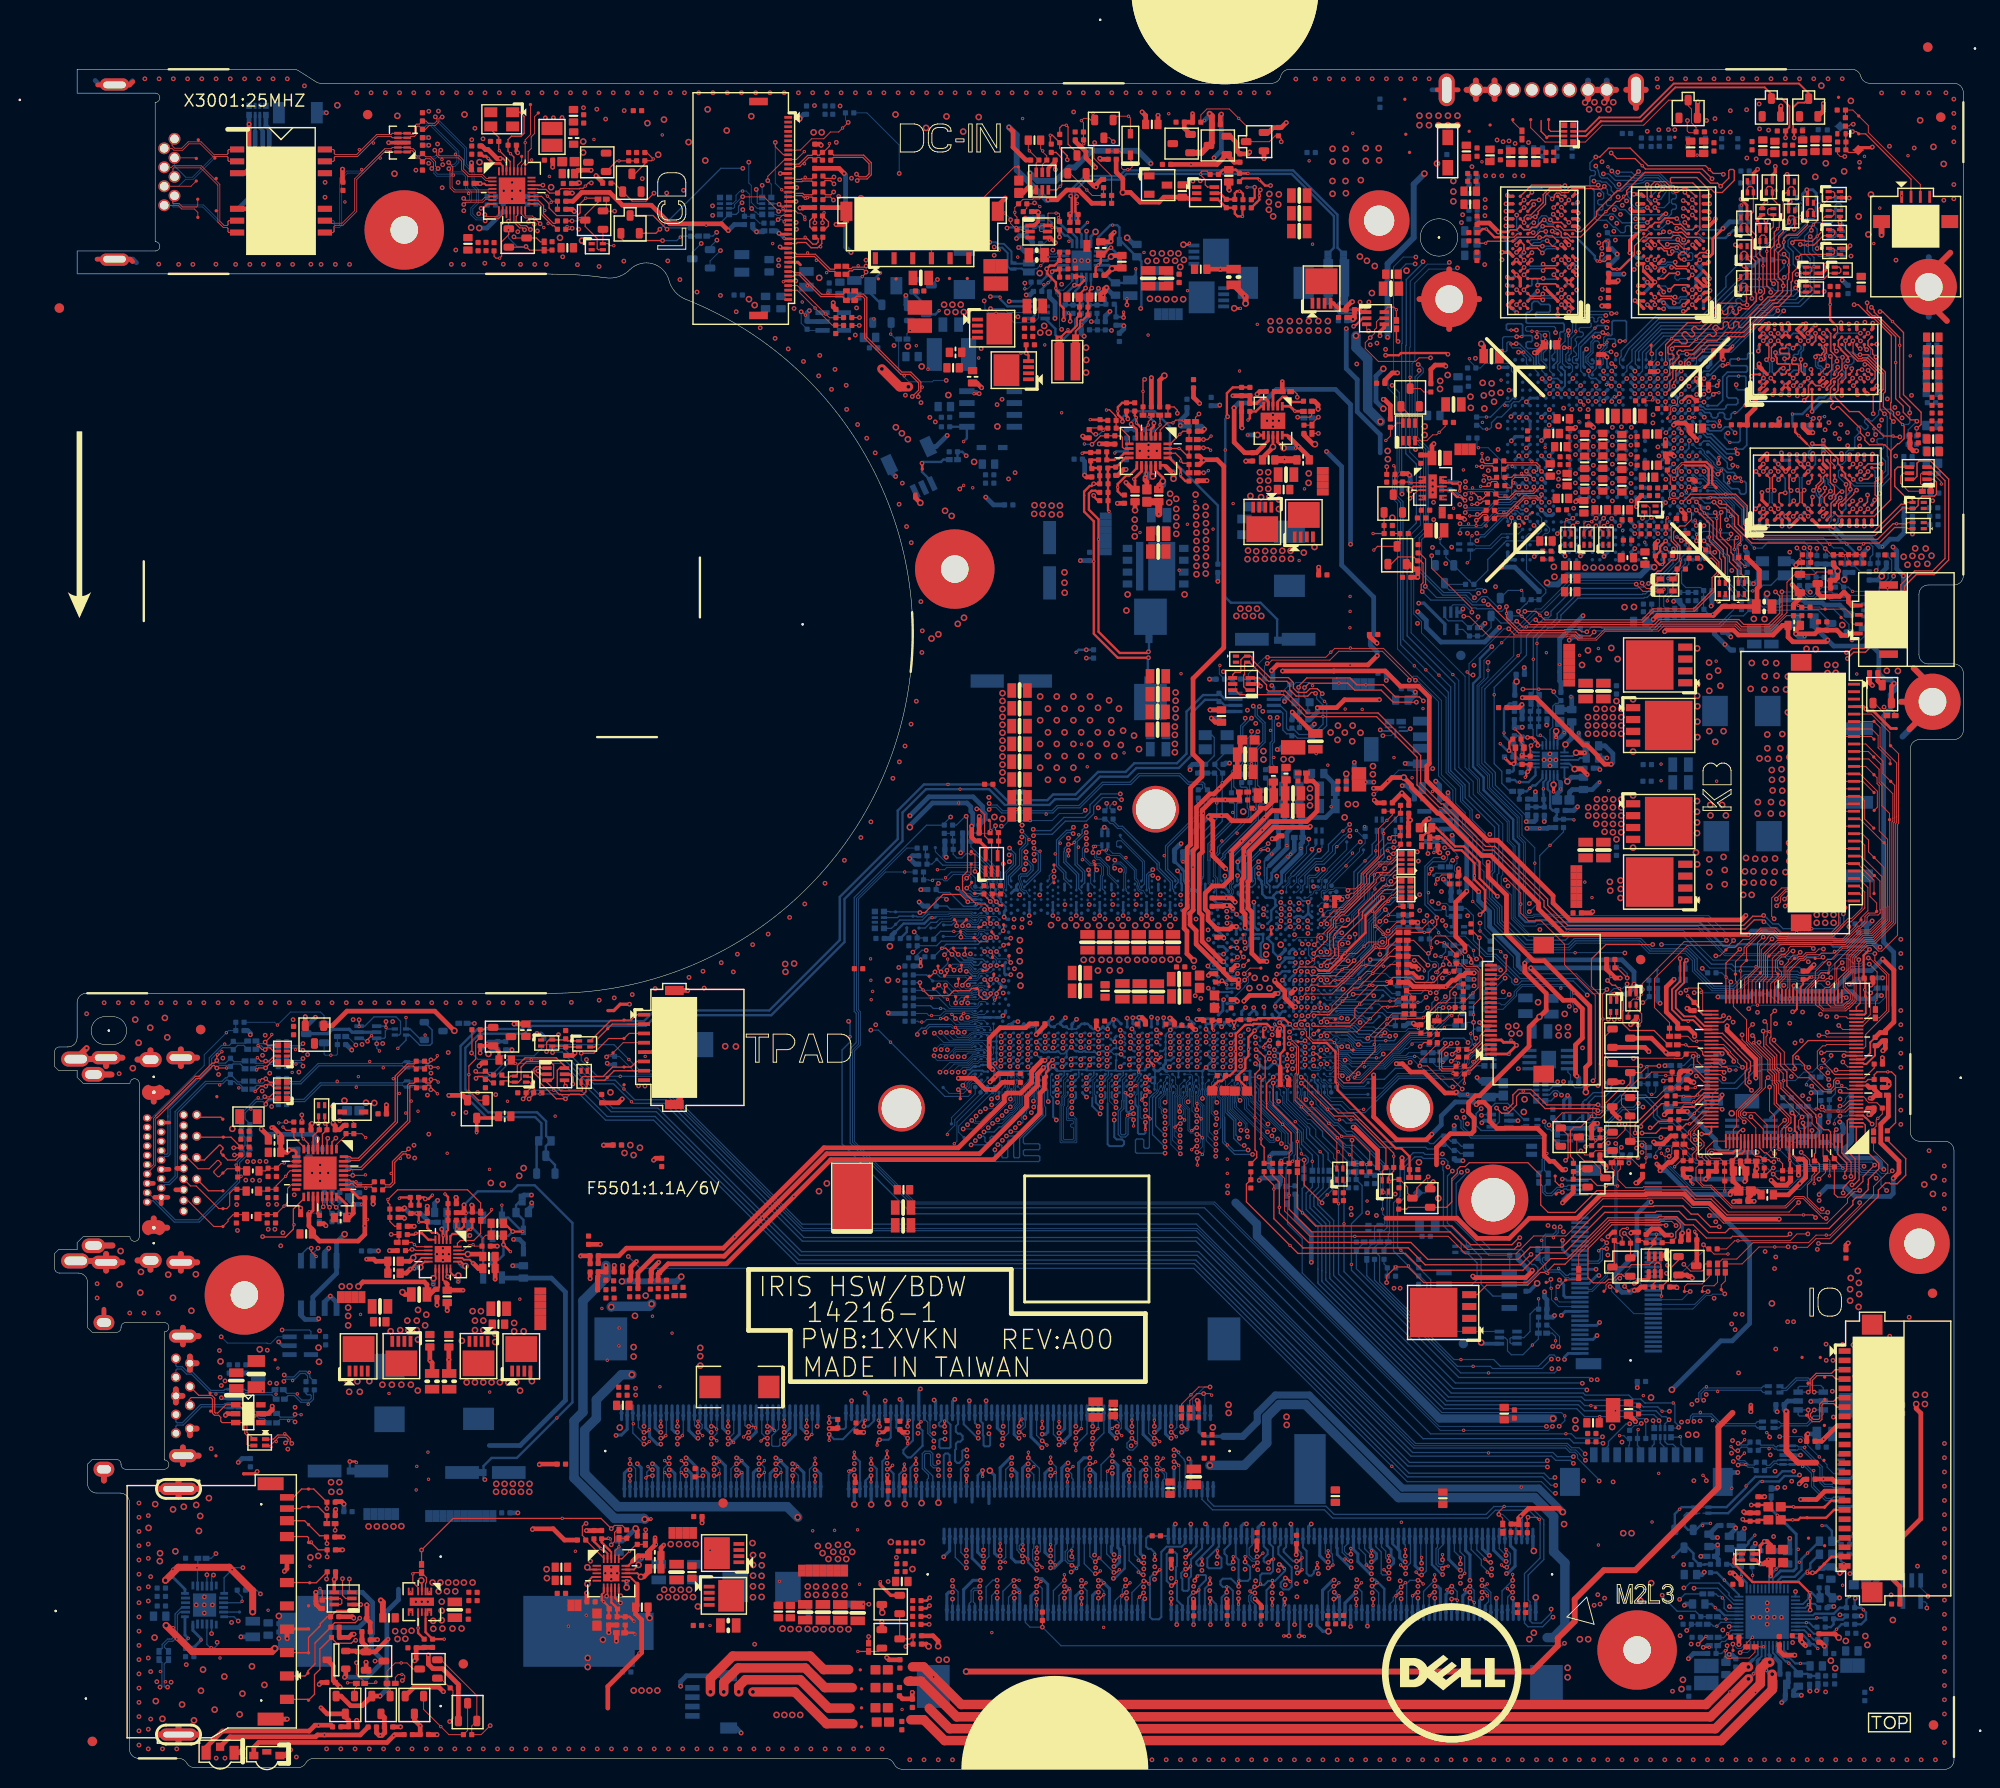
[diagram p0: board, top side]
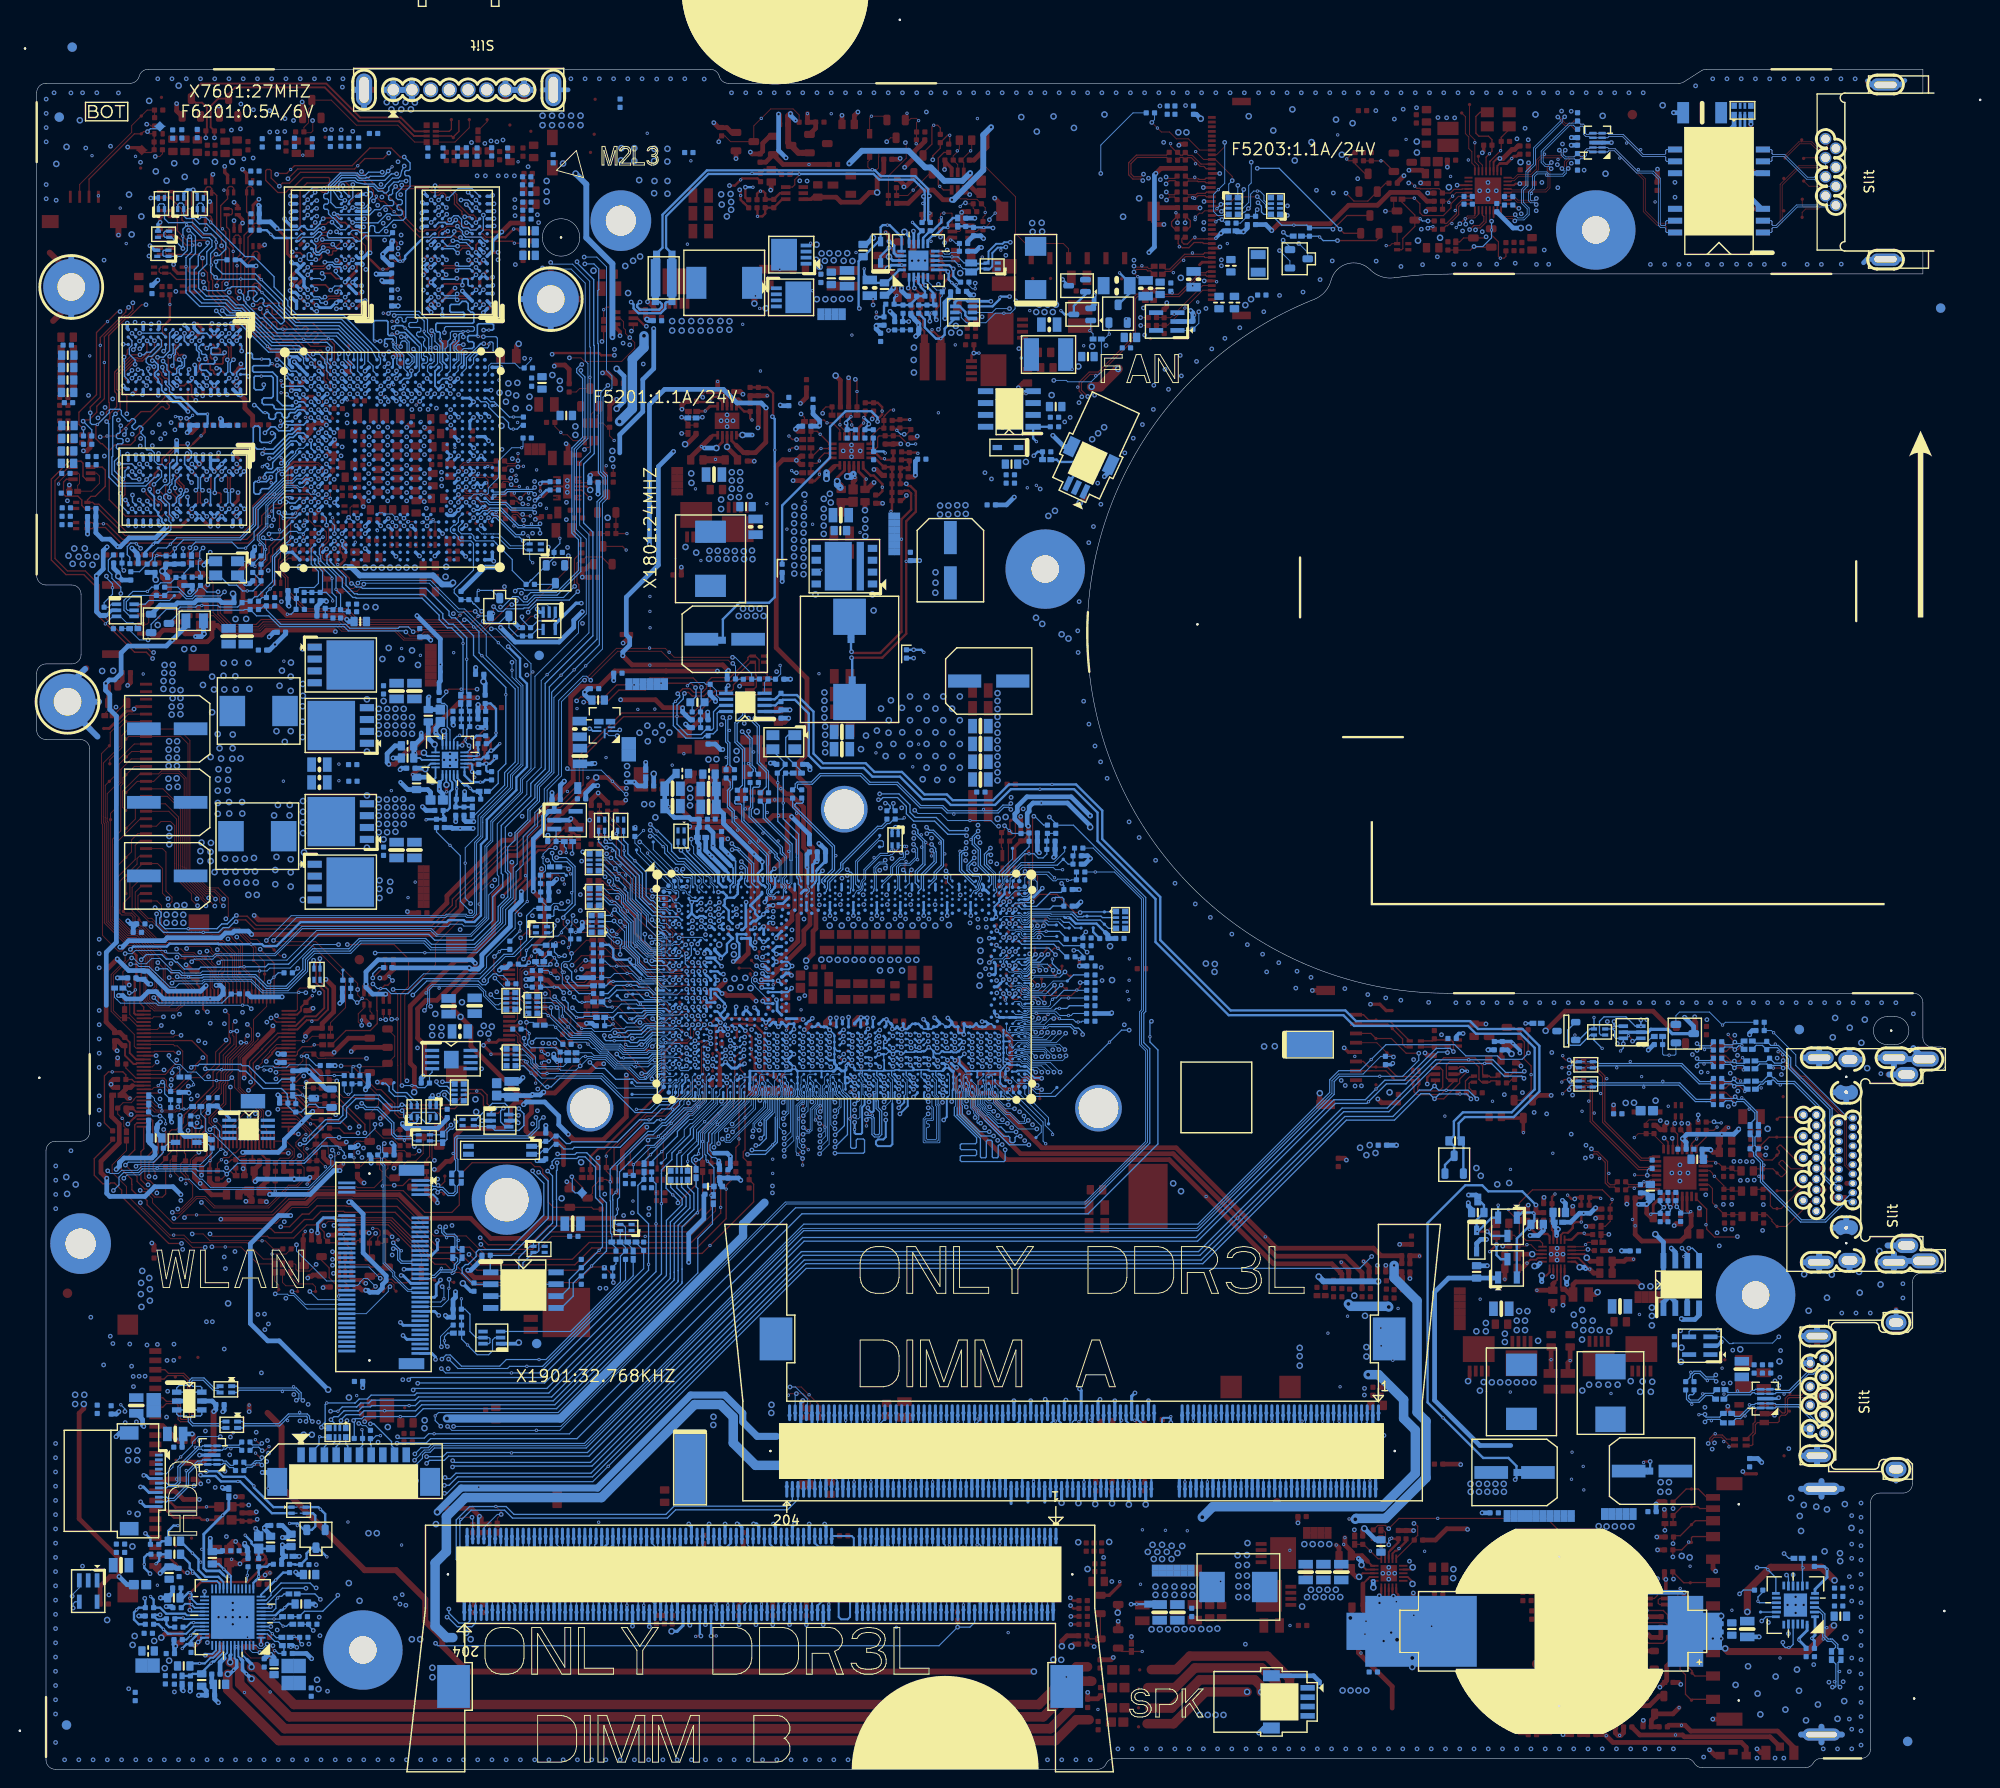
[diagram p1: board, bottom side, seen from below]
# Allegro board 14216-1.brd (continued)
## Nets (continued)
USB3_PTX_CRX_N0_C: R3409.1 U3402.4 U3402.7 USB1.8
USB3_PTX_CRX_N0_R: C3403.2 R3409.2
USB3_PTX_CRX_P0: C3404.1 CPU1.B34
USB3_PTX_CRX_P0_C: R3408.1 U3402.5 U3402.6 USB1.9
USB3_PTX_CRX_P0_R: C3404.2 R3408.2
USB20_VCCA: AFTP6311.1 C3406.1 C3515.1 C3517.1 C3518.1 CN6301.10 CN6301.11 CN6301.12 CN6301.13 CN6301.14 EU3404.5 U3505.1
USB30_VCCC: AFTP3401.1 C3405.1 C3507.1 C3508.1 C3512.1 C3513.1 EU3403.5 TC3501.1 U3504.1 USB1.1
USB_CAMERA_EDP: LCD1.31 R5217.1
USB_CAMERA_EDP#: LCD1.30 R5216.1
USB_COMP: CPU1.AJ10 CPU1.AJ11 R1602.1
USB_OC#0_1: CPU1.AL3 R3501.2 RN1809.7(B) U3504.3
USB_OC#2_3: CPU1.AT1 R3501.1 RN1601.8(B) U3505.3
USB_OC#4_5: CPU1.AH2 RN2012.6(B)
USB_OC#6_7: CPU1.AV3 RN1601.7(B)
USB_PN0: CPU1.AN8 TR3404.1
USB_PN0_C: AFTP3402.1 EU3403.1 TR3404.2 USB1.2
USB_PN1: CPU1.AR7 TR3405.4
USB_PN1_C: AFTP6301.1 CN6301.3 EU3404.6 TR3405.3
USB_PN2: CPU1.AR8 TR3406.1
USB_PN2_C: AFTP6303.1 CN6301.7 EU3404.4 TR3406.2
USB_PN3: CPU1.AR10 TP1601.1
USB_PN4: CPU1.AM15 R5216.2
USB_PN5: CPU1.AM13 R5801.2
USB_PN5_R: AFTP5806.1 R5801.1 WLAN1.5
USB_PN6: CPU1.AP11 R5203.2
USB_PN6_TPNL: LCD1.34 R5203.1
USB_PN7: CPU1.AR13 R3204.1
USB_PN7_R: R3204.2 U3201.2
USB_PP0: CPU1.AM8 TR3404.4
USB_PP0_C: AFTP3403.1 EU3403.3 TR3404.3 USB1.3
USB_PP1: CPU1.AT7 TR3405.1
USB_PP1_C: AFTP6302.1 CN6301.4 EU3404.1 TR3405.2
USB_PP2: CPU1.AP8 TR3406.4
USB_PP2_C: AFTP6304.1 CN6301.6 EU3404.3 TR3406.3
USB_PP3: CPU1.AT10 TP1602.1
USB_PP4: CPU1.AL15 R5217.2
USB_PP5: CPU1.AN13 R5802.2
USB_PP5_R: AFTP5807.1 R5802.1 WLAN1.3
USB_PP6: CPU1.AN11 R5204.2
USB_PP6_TPNL: LCD1.35 R5204.1
USB_PP7: CPU1.AP13 R3205.1
USB_PP7_R: R3205.2 U3201.3
USB_PWR_EN#: KBC24.83 R2412.1 U3504.4 U3505.4
VD1_EN#: KBC24.66 R2449.2
VD_IN1: C2612.1 C2613.1 KBC24.104 R2608.2 R2609.2 R2610.1
VD_IN1_C: C2612.2 C2613.2 R2610.2 R2611.1
VD_OUT1#: KBC24.110 R2602.2 R2607.2 R2612.2
VGA_CORE: C7701.1 C7702.1 C7708.1 C7709.1 C7710.1 C7711.1 C7712.1 C7713.1 C7714.1 C7717.1 C7719.1 C7720.1 C7721.1 C7722.1 C7723.1 C7724.1 C7725.1 C7726.1 C7730.1 C7731.1 C7732.1 EC9755.1 EC9756.1 EC9757.1 GPU1.K10 GPU1.K12 GPU1.K14 GPU1.K16 GPU1.K18 GPU1.L11 GPU1.L13 GPU1.L15 GPU1.L17 GPU1.M10 GPU1.M12 GPU1.M14 GPU1.M16 GPU1.M18 GPU1.N11 GPU1.N13 GPU1.N15 GPU1.N17 GPU1.P10 GPU1.P12 GPU1.P14 GPU1.P16 GPU1.P18 GPU1.R11 GPU1.R13 GPU1.R15 GPU1.R17 GPU1.T10 GPU1.T12 GPU1.T14 GPU1.T16 GPU1.T18 GPU1.U11 GPU1.U13 GPU1.U15 GPU1.U17 GPU1.V10 GPU1.V12 GPU1.V14 GPU1.V16 GPU1.V18 PL8201.2 PL8202.2 PR8212.1 PR8317.1 PT8206.1 PT8207.1 PT8208.1
VGA_CORE_DISCHG: PQ8307.D PR8317.2
VGA_CORE_PSI: GPU1.B4 PR8257.1
VGA_CORE_VID: GPU1.E7 PR8207.1
VGACORE_GND_SENSE_1: GPU1.F1 PR8220.2
VGACORE_VDD_SENSE_1: GPU1.F2 PR8221.2
VIDEO_CLK_XTAL_SS: GPU1.A10 R7601.1
VIDEO_THERM_OVERT#: Q7602.6 TP7606.1
VR_SVID_ALERT#: PR4618.2 R701.1 R703.2
VRAM_ID1: CPU1.E4 R2023.2 R2024.1
VRAM_ID2: CPU1.C3 R2033.2 R2034.1
VTT_CT_3VC_1: C8305.1 U8301.10
VTT_CT_105VC_2: C8316.1 U8301.12
WHITE_LED_BAT: EC6103.1 Q6102.C R6107.2
WIFI_RF_EN: KBC24.82 R5805.1
WLAN_DISABLE#1: AFTP5803.1 R5805.2 WLAN1.56
WLAN_PLT_RST#: CPU1.AT5 RN2012.7(B)
WLAN_WAKE: TP5801.1 WLAN1.55
XCLK_BIASREF: CPU1.C26 R1803.1
XDP_BPM0: CPU1.J60 TP9612.1
XDP_BPM1: CPU1.H60 TP9613.1
XDP_BPM2: CPU1.H61 TP9614.1
XDP_BPM3: CPU1.H62 TP9615.1
XDP_BPM4: CPU1.K59 TP9616.1
XDP_BPM5: CPU1.H63 TP9617.1
XDP_BPM6: CPU1.K60 TP9618.1
XDP_BPM7: CPU1.J61 TP9619.1
XDP_DBRESET#: C9602.1 CPU1.AC3 EC1706.1 R1701.2 TP9653.1
XDP_PRDY#: CPU1.J62 TP9602.1
XDP_PREQ#: CPU1.K62 TP9601.1
XDP_PWR_DEBUG: R9604.2 TP9647.1
XDP_RST: R9602.1 TP9654.1
XDP_SMBCLK: RN9601.3(B) TP9649.1
XDP_SMBDAT: RN9601.4(B) TP9646.1
XDP_SYS_PWROK: R9605.2 TP9644.1
XDP_TCK_JTAGX: CPU1.AE63 R1919.1
XDP_TCLK: CPU1.E60 R406.1 TP9650.1
XDP_TDI: CPU1.F63 RN401.2(A) TP9623.1
XDP_TDO: CPU1.F62 RN401.4(A) TP9624.1
XDP_TMS: CPU1.E61 RN401.1(A) TP9611.1
XDP_TRST#: CPU1.E59 EC402.1 R402.1 TP9621.1
XTAL24_IN: CPU1.A25 R1802.1 R1810.1
XTAL24_IN_R: C1801.2 R1810.2 X1801.1
XTAL24_OUT: C1802.2 CPU1.B25 R1802.2 X1801.3

Pads without a net: CPU1 A5 A6 A8 A31 A33 A37 A41 A49 A53 AA23 AA59 AB21 AB23 AC2 AC4 AC58 AC59 AD23 AD59 AD60 AE59 AE60 AF20 AG58 AL1 AL11 AM10 AM11 AN10 AP7 AT2 AU10 AU12 AU15 AU44 AV2 AV10 AV44 AV50 AV62 AW14 AW49 AY8 AY14 AY42 AY43 B6 B14 B31 B33 B37 B41 B49 B50 B53 B54 C4 C15 C17 C30 C31 C42 C43 C46 C47 C49 C50 C51 C53 D1 D9 D11 D15 D17 D58 D61 E1 E2 E5 E13 E15 E18 F4 F5 F15 F17 F18 F22 G1 G2 G15 G17 H6 H18 H22 J3 J6 J20 J21 J58 K4 K10 K21 L5 L6 L11 L59 M21 N5 N7 N23 N58 N60 R6 R7 R23 T23 T59 U4 U10 U59 V59 W23 Y1 Y4; D3602 2; DCIN1 3; DM1 77 122 125 198; DM2 77 122 125 198; EU3403 4 6; GPU1 AA1 AA2 AA3 AA4 AA5 AA6 AB1 AB2 AB3 AB4 AB5 AB6 AB13 AB15 AB16 AB18 AB19 AB21 AC3 AC4 AC13 AC14 AC15 AC16 AC17 AC18 AC19 AC20 AC21 AD1 AD2 AD3 AD4 AD5 AD7 AD10 AD14 AD17 AD20 AD23 AE1 AE2 AE3 AE4 AE10 AE12 AE13 AE15 AE16 AE18 AE19 AE21 AE23 AE24 AF2 AF3 AF4 AF10 AF12 AF13 AF15 AF16 AF18 AF19 AF21 AF24 AG3 AG12 AG13 AG15 AG16 AG18 AG19 AG21 AG22 AG24 AG25 B2 B3 B6 B19 C1 C2 C3 C7 C18 D4 D5 D6 D10 D16 D17 D18 E6 E10 F4 F5 F7 F9 F10 F11 G1 G2 G3 G4 G5 G6 G7 H3 H4 J1 J2 J3 J4 J5 K1 K2 K3 K4 K5 K6 L3 L4 M1 M2 M3 M4 M5 N1 N2 N3 N4 N5 P3 P4 R1 R2 R3 R4 R5 T1 T2 T3 T4 T5 T6 T24 U3 U4 U6 U24 V1 V2 V3 V4 V5 V6 V24 V25 W1 W2 W3 W4 W5 Y3 Y4; HDA27 14 16 23 24; HDD1 4; HDLED1 3; HDMI1 4 11 HP13 HP14; KB1 2 3; KB_BL1 3; LCD1 3 33 39; ODD1 9 16; PU5101 4; RN401 3 6; RN1801 5; RN4301 4 5; RN5203 4 5; U701 1; U3201 7 9 12 14 16 19 22 23; U3801 5; U5502 18; U5601 5; VRAM1 J1 J9 L1 L9 M7; VRAM2 J1 J9 L1 L9 M7; VRAM3 J1 J9 L1 L9 M7; VRAM4 J1 J9 L1 L9 M7; VRAM5 J1 J9 L1 L9 M7; VRAM6 J1 J9 L1 L9 M7; VRAM7 J1 J9 L1 L9 M7; VRAM8 J1 J9 L1 L9 M7; WLAN1 6 16 17 19 20 21 22 23 24 25 26 27 28 29 30 31 32 34 36 40 42 48 50 59 60 61 62 64 65 66 67 68 70 71 73 76 77; X1801 2 4; X1901 2 3; X3001 2 4

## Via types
v1: diameter 0.356, hole 0.178, TOP to BOTTOM, 1329 vias
v2: diameter 0.508, hole 0.254, TOP to BOTTOM, 3964 vias
v3: diameter 0.711, hole 0.406, TOP to BOTTOM, 982 vias

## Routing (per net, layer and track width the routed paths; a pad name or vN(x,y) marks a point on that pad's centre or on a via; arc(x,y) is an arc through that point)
3V3_AON_S0: length 113.3
  TOP w0.508: R7624.2 v2(200.71,137.47)
  L3 w0.508: v2(148.83,129.06) 148.75,129.06 147.78,128.09 147.2,128.09 145.68,126.56 145.68,125.07 v2(145.93,124.82) ; v2(157.44,101.45) 154.73,104.15 154.73,110.32 155.63,111.23 155.63,117.22 155.86,117.45 155.86,121.42 157.06,122.61 157.06,122.7 158.21,123.85 159.47,123.85 v2(159.62,123.7)
  L4 w0.508: v2(197.79,127.74) 196.84,126.78 192.52,126.78 191.74,125.99 187.82,125.99 v2(187.82,126) 185.8,126 185.11,126.68 183.85,126.68 183.2,126.03 v3(183.2,125.84) 181.91,125.84 v2(179.43,128.32) 178.18,129.57 177.4,129.57 176.13,130.84 173.84,130.84 173.07,131.62 173.07,132.43 171.74,133.76 171.74,137.44 v2(172.37,138.08) ; v2(200.91,135.78) 200.74,135.96 200.74,137.44 v2(200.71,137.47)
  BOTTOM w0.356: v2(145.93,124.82) 146.49,124.82 148.72,122.59 U7301.5 ; Q7602.2 196.17,124.06 196.72,123.5 R7612.2
  BOTTOM w0.508: R7612.2 197.38,123.5 197.79,123.92 v2(197.79,127.74) 197.82,127.74 197.08,128.48 197.08,130.43 v2(196.67,130.84) ; PR8203.1 161.14,116.36 161.01,116.5 161.01,117.48 161.01,117.48 v1(161.01,118.27) 161.01,120.98 v2(163.51,123.48) ; v2(157.44,101.45) 158.29,101.45 158.48,101.63 PR8258.1 ; v2(187.82,126) 187.56,126.26 R7643.2 R7645.1 ; Q7606.G 190.98,124.62 189.36,124.62 189.13,124.85 187.35,124.85 187.05,125.16 184.66,125.16 184.39,124.88 R7649.2 183.1,124.89 183.1,125.74 v3(183.2,125.84) ; R7312.1 156.2,128.68 v2(154.79,128.68)
  vias: v2(147.41,130.79) v2(159.9,135.62) v2(159.93,134.74) v2(178.02,124.99) v3(176.04,128.69)
3V5V_CT1: length 4.5
  TOP w0.203: U3601.12 39.68,16.11
  TOP w0.254: 39.68,16.11 39.68,14.68 C3602.1 v1(41.68,13.94)
3V5V_CT2: length 3.2
  TOP w0.203: U3601.10 38.88,16.03
  TOP w0.254: 38.88,16.03 v1(38.88,15.12) 38.88,14.59 C3601.1
3V5V_S0_ON: length 5.4
  TOP w0.127: U3601.5 38.88,19.45 38.32,20.02 v1(38.32,20.92) 38.44,21.05 R3609.2 39.77,20.53 39.77,20 39.68,19.91 U3601.3
3V_5V_EN: length 264.6
  TOP w0.127: D3602.1 163.34,64.29 163.02,63.97 R3603.1 162.49,63.63 162.47,63.61 R3602.1 164.36,63.16 165.03,62.49 165.92,62.49 v2(165.95,62.51) 167.14,62.51 v1(167.22,62.44) ; v2(36,57.26) 36.02,57.24 PR4507.1 36.84,56.6 PR4506.1
  L3 w0.127: v2(160.18,42.88) 159.68,43.37 159.68,48.6 160.64,49.55 163.21,49.55 169.82,49.55 172.45,52.18 v2(172.45,53.09) ; v2(165.33,17.68) 165.33,17.56 163.45,15.68 161.04,15.68 154.22,8.86 100.06,8.86 100.06,8.85 93.34,8.85 93.32,8.87 93.31,8.86 91.93,10.23 64.29,10.23 63.94,9.89 55.17,9.89 55.02,10.03 49.83,15.23 49.83,17.5 45.87,21.45 40.02,21.45 39.82,21.66 34.45,21.66 32.42,19.63 28.1,19.63 25.41,22.32 25.41,28.7 23.6,30.51 23.6,36.77 24.64,37.8 24.64,39.34 25.64,40.34 25.64,47.78 35.11,57.26 v2(36,57.26)
  L4 w0.127: v2(165.33,17.68) 164.01,19.01 164.01,31.08 162.93,32.15 162.93,34.86 161.88,35.91 161.88,39.46 160.18,41.17 v2(160.18,42.88) ; v2(172.45,53.09) 172.42,53.12 171.57,53.12 165.45,59.23 165.45,62.02 v2(165.95,62.51)
3V_5V_POK: length 228.7
  TOP w0.127: PR4534.2 37.85,55.52 37.98,55.65 v2(38.23,55.65) 38.49,55.65 38.6,55.54 PU4503.7
  L3 w0.127: v2(164.7,17.56) 163.13,15.98 160.98,15.98 154.11,9.11 99.95,9.11 99.95,9.11 93.44,9.11 92.06,10.49 64.14,10.49 63.79,10.14 55.27,10.14 50.08,15.33 50.08,17.65 46.02,21.71 40.14,21.71 39.94,21.91 34.31,21.91 32.28,19.88 28.21,19.88 25.66,22.43 25.66,28.81 23.86,30.61 23.86,36.66 24.89,37.7 24.89,39.23 25.89,40.24 25.89,47.67 33.08,54.87 36.08,54.87 36.85,55.65 v2(38.23,55.65)
  L4 w0.127: v2(164.7,17.56) 163.2,19.06 163.2,30.61 162.94,30.87 162.94,31.07 161.47,32.53 161.47,39.09 159.69,40.88 159.69,44.68 v2(160.26,45.26)
  BOTTOM w0.127: v2(160.26,45.26) 160.57,45.57 160.57,45.87 ; 160.57,45.87 160.57,45.87 160.57,46.33 160.21,46.69 R1728.2 ; 160.57,45.87 v1(160.57,45.87)
3V_5V_POK#: length 7.8
  BOTTOM w0.127: Q1701.6 155.82,45.56 155.7,45.68 155.7,46.09 155.81,46.21 Q1701.5 157.19,46.21 157.84,46.86 157.84,48.72 158.38,49.25 R1726.1 158.76,50.35 v1(158.75,50.36)
3V_5V_POK_C: length 8.7
  BOTTOM w0.127: R1727.2 R1729.1 158.75,46.7 R1728.1 158.73,46.05 v1(158.1,45.42) 158.09,45.42 157.89,45.22 157.89,45.19 157.08,44.38 155.84,44.38 155.43,44.78 155.43,45.95 155.18,46.21 Q1701.2
3V_FEEDBACK: length 38.6
  TOP w0.254: PR4512.1 38.93,60.45 PR4535.1 39.49,61.21 v2(39.65,61.05) 40.01,61.05 v1(40.41,61.46) ; v1(32.29,32.84) 32.18,32.95 v2(31.58,32.95)
  L4 w0.254: v2(39.65,61.05) 38.85,60.25 38.85,59.69 37.63,58.48 36.5,58.48 28.99,50.96 28.99,35.54 v2(31.58,32.95)
  BOTTOM w0.254: PG4535.2 v2(31.58,32.95)
5V_HDD_S0:
  vias: v2(190.3,37.71)
5V_HDMI_CRT_S0:
  vias: v1(29.64,70.97) v3(31,71.57)
5V_HDMI_CRT_S0_R: length 6.9
  TOP w0.381: HDMI1.HP18 12.27,69.22
  L3 w0.762: HDMI1.9 17.06,66.62 v3(19.01,68.56)
  vias: v1(19.7,72.94)
5V_PWR: length 29.2
  BOTTOM w0.508: PD4503.1 47.91,52.58 PC4515.1 53.14,52.58 54.64,51.08 54.64,39.5 49.8,34.66 46.5,34.66
  vias: v1(39.94,33.95) v1(40,31.05)
5V_PWR_2: length 4.2
  TOP w0.203: PU4503.13 41.54,52.4 41.84,52.09
  TOP w0.508: 41.84,52.09 41.99,51.94 PC4524.1 v1(43.69,51.28)
5V_S0: length 231.4
  TOP w0.203: v3(144.98,136.95) 145.35,137.32 U8301.4
  TOP w0.305: PU4601.12 116.28,138.93 v1(115.45,138.11) 115.58,137.98 PC4604.1
  TOP w0.508: v2(172.24,121.78) 172.4,121.94 179.61,121.94 180.13,121.42 183.82,121.42 184.84,122.44 185.33,122.44 185.34,122.44 R6205.1 185.45,121.19 185.95,120.69 189.5,120.69 v2(189.69,120.88) ; EC9719.1 197.41,19.58 196.34,20.65 195.4,20.65 ; PC4604.1 115.35,137 v2(114.62,137.74) ; Q6201.E 196.51,115.93 v2(196.81,116.24) ; 195.4,20.65 v2(195.38,20.63) ; 195.4,20.65 195.4,22.57 199.66,26.82 199.66,38.11 199.16,38.61 v3(199.16,39.1) ; v2(157.02,114.71) 158.48,114.71 163.56,109.63 163.94,109.63 165.12,108.46 165.12,108.3 165.84,107.58 v2(166.52,107.58) ; v3(42.76,79.05) 40.66,81.15 31.27,81.15 29.71,79.6 Q5403.G ; Q6104.E 38.45,8.79 41.11,8.79 v2(41.59,8.31)
  TOP w1.016: v3(88.5,149.9) 90.41,147.98 v3(91.34,147.98)
  L3 w0.508: v2(172.24,121.78) 171.94,122.08 165.96,122.08 163.93,124.12 163.25,124.12 158.34,119.21 158.34,115.98 157.07,114.71 v2(157.02,114.71) ; v3(142.15,149.92) 140.75,148.52 121.94,148.52 121.15,147.73 112.68,147.73 111.11,146.16 105.04,146.16 102.62,143.74 v3(100.86,143.74) ; v3(142.15,145.64) 142.77,145.02 142.77,143.32 141.19,141.74 141.19,138.7 142.69,137.2 143.16,137.2 144.73,137.2 v3(144.98,136.95)
  L3 w1.016: v3(91.34,147.98) 93.52,147.98 94.41,147.1 v3(95.61,147.1)
  BOTTOM w0.508: v3(142.15,149.92) 141.36,149.13 141.36,146.42 v3(142.15,145.64) ; R2703.2 194.52,19.77 v2(195.38,20.63) ; PR8223.1 165.87,109.55 166.71,108.72 166.71,107.76 v2(166.52,107.58) ; 196.75,81.77 196.75,87.45 195.67,88.53 195.67,112.74 196.37,113.44 196.37,115.04 196.83,115.5 196.83,116.21 v2(196.81,116.24) 196.44,116.61 195.86,116.61 195.16,117.3 195.16,119.5 194.43,120.24 190.33,120.24 v2(189.69,120.88) 188.24,122.33 F6201.1 ; v2(19.64,32.85) 20.06,33.27 EC9718.1
  vias: v3(33.31,71.35) v3(34.2,71.33) v3(40.49,15.89) v3(40.51,15.05) v3(41.4,16.98) v3(41.41,15.96) v3(41.48,15.07) v3(42.56,15.07) v3(43.53,15.08) v3(74.28,157.36) v3(74.89,156.73) v3(93.81,121.04) v3(94.55,121.49) v3(160.89,79.4) v3(160.91,78.56) v3(161.55,80.86) v3(161.9,79.45) v3(161.89,78.58) v3(174.05,8.59) v3(174.2,9.58) v3(199.11,40.09) v3(200.02,62.6) v3(200.09,40.09) v3(200.09,39.1) v3(200.95,61.59) v3(201.03,63.39)
5V_S5: length 408.4
  TOP w0.203: v3(39.22,20.22) 39.28,20.17 U3601.4 ; 62.31,19.84 61.78,20.37 61.78,20.38 61.58,20.58 PU4901.12
  TOP w0.305: PU4806.7 129.84,142.21 129.36,141.73
  TOP w0.508: 59.18,6.55 59.18,8.87 62.8,12.48 62.8,15.99 62.16,16.63 PC4901.1 62.31,17.51 62.31,19.84 ; Q6101.E 30.63,7.84 31.66,6.81 32.89,6.81 Q6102.E v2(34.81,7.84) ; v2(126.17,145.72) 126.19,145.72 126.19,142.05 127.31,140.93 PC4815.1 128.56,140.93 129.36,141.73 ; PR4203.1 124.71,177.06 v2(124.82,177.17) ; v3(94.52,13.17) 94.52,13.75 93.97,14.29 R1208.1
  L3 w0.508: v2(124.04,172.5) 125.28,173.74 129.12,173.74 133.74,169.13 133.74,161.11 136.03,158.82 141.17,158.82 144.36,155.63 144.36,151.08 141.13,147.86 128.3,147.86 v2(126.17,145.72)
  L4 w0.508: v3(196.66,15.98) 195.74,16.9 195.74,19.12 196.98,20.36 196.98,39.73 196.25,40.47 196.25,43.79 197.7,45.23 197.7,47.05 197.11,47.64 197.11,54.57 196.81,54.87 196.81,60.25 198.1,61.54 198.1,65.32 196.87,66.55 196.87,73.06 196.88,73.06 196.88,73.59 196.87,73.6 196.87,114.65 194.9,116.61 194.9,119.92 195.34,120.36 195.34,124.34 199.18,128.18 202.12,128.18 202.85,128.92 202.85,165.58 200.37,168.07 198.27,168.07 186.62,179.72 174.66,179.72 173.2,178.26 170.34,178.26 169.7,177.63 168.33,177.63 167.46,176.76 154.17,176.76 152.28,174.86 145.11,174.86 142.8,177.17 v2(124.82,177.17) ; v2(141.82,111.26) 141.82,112.1 138.02,115.89 138.02,123.35 138.65,123.98 138.65,131.11 v2(138.64,131.13)
  BOTTOM w0.203: v2(141.82,111.26) 141.93,111.14 U2101.1
  BOTTOM w0.508: v2(138.64,131.13) 138.64,146.08 137.02,147.71 130.72,147.71 129.27,146.25 126.68,146.25 126.17,145.74 v2(126.17,145.72) ; 36.78,19.28 36.78,18.15 35.54,16.91 35.54,8.57 v2(34.81,7.84) ; v2(124.82,177.17) 124.82,173.28 v2(124.04,172.5)
  vias: v1(27.31,21.74) v1(27.46,24.33) v1(62.52,12.45) v3(27.35,22.68) v3(28.23,45.14) v3(28.2,22.84) v3(28.28,43.62) v3(40.43,19.99) v3(41.08,19.05) v3(41.27,20) v3(41.97,19.05) v3(42.11,19.99) v3(42.94,19.99) v3(42.86,19.05) v3(43.78,19.99) v3(44.71,19.99) v3(61.95,8.44) v3(62.78,8.44) v3(63.63,8.44) v3(64.48,8.44) v3(77.23,5.82) v3(78.07,5.82) v3(78.91,5.82) v3(79.76,5.82)
15V_PWR: length 8
  BOTTOM w0.254: PG4530.2 49.65,60.69 49.36,60.39 PC4533.1 50.15,58.81 PD4501.K 49.89,57.69 48.53,59.05 PD4502.2 47.84,60.38 v1(47.84,60.38)
15V_S5: length 435.4
  TOP w0.508: v2(178.92,79.58) 178.92,79.1 180.67,77.35 180.67,77.32 182,75.99 v2(182,74) ; PR4471.2 111.92,172.34 v2(111.82,172.43) ; v2(172.98,57.18) 172.27,57.18 171.61,57.84 170.86,57.84 PR8310.2 ; v2(180.93,91.39) 180.45,90.92 162.12,90.92 160.31,92.73 160.31,93.5 154.36,99.44 153.28,99.44 148.82,103.9 148.73,103.9 146.79,105.84 146.79,107.38 147.07,107.65 147.07,114.78 145.91,115.94 143.98,115.94 142.35,117.57 136.86,117.57 136.85,117.56 v2(131.37,117.56) ; v2(181.47,38.29) v1(181.47,38.99)
  L3 w0.508: v2(111.82,172.43) 112.7,172.43 114.41,174.15 123.63,174.15 124.49,175.01 131.33,175.01 135.01,171.33 135.01,162.15 137.07,160.09 142.09,160.09 147.84,154.34 147.84,149.8 143.4,145.36 143.4,143.06 141.82,141.48 141.82,139.07 143.07,137.83 145.14,137.83 145.72,137.25 145.72,135.08 140.95,130.31 140.95,124.95 135.22,119.23 133.04,119.23 v2(131.37,117.56) ; v2(172.98,57.18) 173.51,56.65 175.1,56.65 175.87,57.42 177.09,57.42 177.69,56.82 178.77,56.82 180.57,58.63 180.57,62.12 180.15,62.54 180.15,66.12 182.74,68.72 182.74,72.37 182,73.11 v2(182,74) ; v2(51.01,61.47) 51.21,61.27 51.3,61.27 51.67,60.9 51.67,60.81 56.42,56.06 56.42,29.6 54.75,27.93 54.75,16.46 59.24,11.97 88.12,11.97 88.76,12.61 89.28,12.61 89.92,11.97 92.69,11.97 93.99,10.67 96.48,10.67 97.17,11.36 98.9,11.36 100.34,9.93 151.98,9.93 159.46,17.41 159.47,17.41 161.61,19.56 164.93,19.56 176,30.63 176,31.49 177.31,32.79 177.31,36.23 179.1,38.03 181.21,38.03 v2(181.47,38.29)
  L4 w0.508: v2(172.98,57.18) 173.01,57.15 173.01,56.7 176.01,53.69 176.01,50.72 178.43,48.31 178.43,47.37 180.8,44.99 180.8,43.61 181.02,43.39 181.02,38.74 v2(181.47,38.29) ; v2(178.92,79.58) 178.75,79.58 178.3,80.04 178.28,80.04 177.91,80.41 177.91,81.22 181.01,84.33 181.01,88.26 180.37,88.9 180.37,89.54 180.93,90.1 v2(180.93,91.39)
  BOTTOM w0.508: v2(51.01,61.47) 50.2,61.47 PG4530.1
+3V_1D5V_AVDD: length 6.3
  BOTTOM w0.203: 185.2,11.54 184.22,12.52 HDA27.40
  BOTTOM w0.254: R2705.2 187.76,10 R2710.2 187.53,10.22 C2715.1 186.54,10.35 v1(185.53,11.36) 185.36,11.54 185.2,11.54
+3V_AVDD: length 30.9
  TOP w0.508: C2719.1 v2(180.19,13.36) ; v1(187.32,13.22) 187.14,13.4 187.14,13.4 v2(186.93,13.62) 186.79,13.76 C2717.1
  L3 w0.508: v2(177.91,24.02) 177.9,24.01 176.4,24.01 175.47,23.08 175.47,22.11 v2(176.49,21.1) 179.18,18.41 v2(179.18,17.43) 179.18,16.31 180.19,15.3 v2(180.19,13.36) 182.84,13.36 183.85,14.38 186.16,14.38 v2(186.93,13.62)
  BOTTOM w0.203: HDA27.1 180.19,13.37 v2(180.19,13.36) ; v2(186.93,13.62) 186.46,14.09 HDA27.36 ; v2(179.18,17.43) 179.32,17.29 HDA27.9
  BOTTOM w0.508: R2722.1 177.99,22.48 R2701.2 177.91,23.04 v2(177.91,24.02) 177.74,23.85 C2716.1 ; v2(176.49,21.1) 176.23,20.84 C2701.1
+5V_AVDD:
  vias: v1(191.28,19.7)
+5V_KB_BL: length 10.9
  TOP w0.406: KB_BL1.1 192.03,121.57
  TOP w0.508: 192.03,121.57 191.83,121.37 AFTP6248.1 191.12,121.48 190.66,121.94 C6202.1 EC6208.1 188.31,121.54 v2(186.28,121.54) 186.28,121.95 R6205.2
  BOTTOM w0.508: F6201.2 186.36,121.62 v2(186.28,121.54) 186.57,121.25 v1(187.21,121.25)
+5V_PVDD: length 3.4
  BOTTOM w0.203: 184.12,11.9 184.12,12.17 183.82,12.48 HDA27.41
  BOTTOM w0.508: C2709.1 184.58,11.45 184.12,11.9
  vias: v1(179.22,8.28) v1(181.97,8.22)
+V1.05A_AOSCSUS: length 1.2
  TOP w0.508: v2(132.71,83.51) 132.29,83.09 TP2109.1
  BOTTOM w0.254: CPU1.AB8 132.53,83.33 v2(132.71,83.51)
+V1.05A_SUS_PCH: length 2
  TOP w0.254: v2(132.72,82.55) 132.72,82.43 TP2106.1
  BOTTOM w0.254: v2(132.72,82.55) 132.72,82.55 132.53,82.36 CPU1.AD8 CPU1.AD10
+V1.05A_USB2SUS: length 1.5
  TOP w0.254: TP2108.1 129.3,79.14 v2(129.44,79.28)
  BOTTOM w0.254: v2(129.44,79.28) 129.77,79.61 CPU1.AH13
+V1.05A_VCCUSB3SUS: length 1.3
  TOP w0.254: TP2107.1 130.15,90.05 v2(130.2,90.11)
  BOTTOM w0.254: CPU1.J13 129.96,89.86 v2(130.2,90.11)
+V1.05DX_MODPHY_PCH:
  vias: v1(138.17,96.71) v1(140.14,100.91) v2(132.65,89.34) v2(134.08,89.47) v3(131.17,88.27) v3(138.36,103.31) v3(139.2,103.31)
+V1.05S_AIDLE: length 33.5
  L3 w0.508: v2(132.77,87.32) 132.63,87.46 130.94,87.46 130.36,88.04 130.36,88.41 129.59,89.18 129.14,89.18 129.14,89.21 127.62,90.74 127.62,93.75 129.45,95.58 129.45,96.94 137.97,105.47 137.98,105.47 138.23,105.72 141.08,105.72 v2(141.13,105.67)
  BOTTOM w0.305: v2(132.77,87.32) 132.77,87.55 CPU1.N8 132.4,87.79 132.08,87.48 CPU1.P9
  BOTTOM w0.508: R2105.2 139.04,105.31 C2105.1 139.87,105.27 v1(140.27,105.67) v2(141.13,105.67)
+V1.05S_APLLOPI: length 34.4
  TOP w0.508: R1102.2 126.84,109.97 126.84,108.93 C1110.1 C1124.1 126.38,106.76 v1(124.58,104.96) 124.02,104.4 123.58,104.4 122.16,102.98 122.16,98.71 121.8,98.35 121.8,91.96 121.47,91.63 121.47,90.42 122.12,89.77 122.12,88.33 124.87,85.59 C1109.1 125.02,85.38 125.89,84.51 v2(126.68,84.51) 126.63,84.46 v2(126.63,83.7)
  BOTTOM w0.203: v2(126.68,84.51) 126.57,84.41 CPU1.W21 ; CPU1.AA21 126.52,83.59 v2(126.63,83.7)
+V1.05S_ASATA3PLL: length 17.2
  BOTTOM w0.305: CPU1.B11 130.78,94.44 131.27,94.93 131.27,96 131.29,96.02
  BOTTOM w0.508: L1102.2 137.01,105.36 C1106.1 C1107.1 137.01,102.92 135.97,101.88 134.39,101.88 134.2,101.69 C1105.1 R1906.2 133.51,100.66 R1904.2 133.51,99.24 133.33,99.06 v1(133.33,98.58) 133.33,98.06 131.29,96.02
+V1.05S_AUSB3PLL: length 27.3
  L4 w0.508: v2(120.51,99.09) 120.52,99.08 124.63,99.08 v2(126.57,97.13)
  BOTTOM w0.203: CPU1.B27 121.27,94.5 120.93,94.85 120.93,94.95 120.85,95.02 120.85,95.09 120.78,95.15 120.78,96.18
  BOTTOM w0.254: CPU1.B18 126.44,94.64 126.6,94.64 127.03,95.07 127.03,95.91 126.57,96.37 v2(126.57,97.13)
  BOTTOM w0.305: 120.78,96.18 120.63,96.34 120.63,96.38 119.96,97.05 119.92,97.05 119.81,97.16
  BOTTOM w0.508: v2(120.51,99.09) 120.34,98.92 120.29,98.92 119.81,98.43 R1601.1 119.81,97.16 ; L1101.2 131.61,105.06 C1104.1 C1123.1 130.71,102.26 C1103.1 130.71,101.24 130.08,100.6 v1(127.45,97.97) 126.89,97.41 126.85,97.41 v2(126.57,97.13)
+V1.05S_AXCK_DCB: length 25.2
  TOP w0.508: v2(126.42,90.2) 126.42,90.19 125.94,90.19 125.68,89.94 124.36,89.94 C1111.1 123.4,90.9 123.4,91.75 123.1,92.05 123.1,93.78 123.87,94.56 125.02,94.56 125.92,95.45 125.92,98.3 v1(126.98,99.36) 130.24,102.62 C1125.1 131.65,102.64 C1112.1 131.65,105.82 L1103.2
  BOTTOM w0.305: CPU1.K19 126.42,90.19 v2(126.42,90.2) 126.56,90.2 CPU1.J18
+V1.05S_AXCK_LCPLL: length 21.8
  TOP w0.508: v2(125.28,96.4) 123.91,97.77 123.91,101.48 v2(123.43,101.96) 123.55,102.09 v1(124.83,102.09) 125.41,102.09 125.95,101.54 127.88,101.54 129,102.66 C1113.1 129.59,102.87 130.42,103.7 C1114.1 130.42,105.64 L1104.2
  BOTTOM w0.229: v2(125.28,96.4) 125.66,96.02 125.66,95.43 125.59,95.36 CPU1.A20
  BOTTOM w0.508: R1803.2 121.52,100.06 v2(123.43,101.96)
+V1.05S_CORE_PCH: length 9
  TOP w0.508: v2(130.54,84.48) 130.54,84.33 130.94,83.93 130.97,83.93 131.61,83.28 131.61,82.56 132.56,81.61 v2(132.75,81.61)
  L4 w0.254: 130.53,89.36 131.1,89.93 v2(131.1,90.18)
  BOTTOM w0.254: CPU1.H15 128.92,90.51 v2(129.23,90.21)
  BOTTOM w0.305: v2(125.06,82.38) 124.98,82.3 124.98,81.22 CPU1.AF22 ; CPU1.H11 130.77,90.51 v2(131.1,90.18) 130.78,89.86 CPU1.J11 ; CPU1.AE8 132.53,81.39 v2(132.75,81.61)
  vias: v1(132.23,97.94) v1(136.21,107.48) v1(136.56,103.03) v3(129.62,88.11) v3(129.61,87.23)
+V1.05S_SSCF100: length 23.7
  TOP w0.508: v2(127.36,90.07) 127.36,91.53 127.02,91.87 127.02,95.24 127.21,95.42 127.21,98.56 v1(129.19,100.54) 130.11,101.45 133.94,101.45 135.06,102.57 135.06,105.29 135.05,105.3 135.05,105.35 134.61,105.79 C2137.1 133.91,106.61 R2117.2
  BOTTOM w0.305: v2(127.36,90.07) 127.57,89.86 CPU1.J17
+V1.05S_SSCFF: length 23.9
  TOP w0.508: R2118.2 C2138.1 v1(125.23,103.76) 123.86,103.76 122.79,102.7 122.79,98.22 122.46,97.89 122.46,91.71 122.76,91.41 122.76,88.62 124.94,86.44 v2(125.06,86.44)
  BOTTOM w0.254: CPU1.R21 125.43,86.81 v2(125.06,86.44) 125.07,86.44 125.43,86.08 CPU1.T21
+V3.3A_1.5A_HDA: length 8.5
  TOP w0.254: v2(128.38,79.06) 128.38,79.03 127.72,78.37 v1(127.72,77.07) 127.72,76.35 127.38,76.01 127.38,75.03 127.09,74.73 127.05,74.73 126.54,74.22 C2116.1 127.58,72.93 R2108.2
  BOTTOM w0.254: CPU1.AH14 128.93,79.61 v2(128.38,79.06)
+V3.3A_DSW_P: length 28.9
  TOP w0.102: v2(132.13,79.76) 132.13,79.71 132.6,79.24 133.67,79.24 133.92,78.98 133.92,78.46 134.62,77.75
  TOP w0.254: C2101.1 128.58,80.24 128.74,80.4 131.5,80.4 v2(132.13,79.76) ; 134.62,77.75 136.08,77.75 137.03,76.8 137.03,73.58 v1(137.25,73.36) 137.25,72.71 143.49,66.47 144.07,66.47 144.95,65.59 C2136.1 R2101.2
  BOTTOM w0.254: v2(132.13,79.76) 131.98,79.61 CPU1.AH10
+V3.3A_PSUS: length 19.4
  TOP w0.508: v2(143.54,75.52) 144.2,75.52 145.09,74.64 146.52,74.64 148.76,72.39 149.87,72.39 v2(149.95,72.48) ; v2(130.87,83.04) 130.56,83.04 130.36,82.83 127.83,82.83 v2(127.23,82.23)
  BOTTOM w0.254: CPU1.AC9 CPU1.AA9
  BOTTOM w0.305: CPU1.AA9 131.34,83.51 v2(130.87,83.04)
  BOTTOM w0.508: v2(149.95,72.48) 150.03,72.48 150.33,72.18 151.11,72.18 v1(151.16,72.24) 151.29,72.12 153.23,72.12 C1108.1 153.96,71.96 154.13,72.12 R1103.2
+V3.3S_1.8S_LPSS_SDIO: length 35.9
  TOP w0.254: R2103.1 147.98,99.74 C2104.1 148.34,99.73 149.69,98.38 150.52,98.38 151.9,97 v1(151.9,95.66) 151.9,95.24 153.04,94.1 153.04,92.03 v2(152.48,91.48)
  L3 w0.102: v2(132.74,86.35) 133.18,86.79 134.26,86.79 134.37,86.68 136.36,86.68 137.49,87.81
  L3 w0.254: 137.49,87.81 138.39,87.81 138.52,87.94 139.61,87.94 140.72,89.05 142.26,89.05 142.33,88.98 143,88.98 143.83,89.81 149.04,89.81 149.33,90.1 149.33,90.37 150.84,91.88 152.08,91.88 v2(152.48,91.48)
  BOTTOM w0.254: CPU1.U8 132.73,86.09 132.73,86.34 v2(132.74,86.35) 132.71,86.35 132.69,86.37 132.09,86.37 CPU1.T9
+V3.3S_PCORE: length 41.8
  TOP w0.127: 135.21,85.55 134.88,85.88 133.17,85.88 v2(132.7,85.41)
  TOP w0.254: 135.21,85.55 135.22,85.55 135.28,85.49 135.88,85.49 135.88,85.48 136.32,85.48 137.65,86.81 137.65,86.81 137.68,86.84 137.68,86.99 v1(138.06,87.37) 140.24,89.55 140.24,91.39 142.07,93.22 v2(142.07,93.3) ; R2112.2 146.76,100.26 147.01,100.26 147.33,100.57 C2123.1 147.79,100.79 148.47,100.11 148.5,100.11 149.82,98.79 150.78,98.79 152.44,97.12 152.44,95.36 v2(154.35,93.45)
  L3 w0.254: v2(142.07,93.3) 142.88,94.11 145.86,94.11 146.21,94.46 148.62,94.46 149.13,94.98 152.83,94.98 v2(154.35,93.45)
  BOTTOM w0.254: CPU1.W9 132.08,84.57 132.45,84.94 CPU1.V8 132.7,85.11 v2(132.7,85.41)
+VCCIOA_OUT: length 3
  TOP w0.508: v1(126.06,92.12) 125.7,92.49 v2(125.42,92.49) 125.41,92.48 125.13,92.48 125.02,92.38 R801.1
  BOTTOM w0.305: v2(125.42,92.49) 125.5,92.49 125.52,92.47 CPU1.E20
+VCCRTCEXT: length 23
  TOP w0.254: v2(151.55,86.36) 151.55,86.77 v1(151.26,87.05)
  L3 w0.102: 140.09,83.16 139.43,82.5 135.27,82.5 134.92,82.15 133.94,82.15 v2(133.39,81.59)
  L3 w0.254: 140.09,83.16 140.91,83.98 145.52,83.98 145.52,83.98 145.7,83.8 148.7,83.8 151.26,86.36 v2(151.55,86.36)
  BOTTOM w0.254: v2(151.55,86.36) 151.89,86.02 152.5,86.02 C2110.1 ; v2(133.39,81.59) 133.39,81.58 133.36,81.55 133.36,81.31 CPU1.AE7
AVCC33: length 7.7
  TOP w0.305: R5504.2 31.25,60.44 30.42,61.27 U5502.24
  TOP w0.508: v2(31.95,60.5) 31.95,59.54 31.47,59.06 R5504.2
  BOTTOM w0.508: v1(32.82,60.47) 31.98,60.47 v2(31.95,60.5) 31.57,60.88 C5523.2 31.99,61.7 C5517.1
GND: length 1812.3
  TOP w0.178: U8301.11 148.51,137.32
  TOP w0.2: 169.94,161.11 VRAM7.G9 169.94,161.11 ; 169.94,161.11 169.94,160.43 VRAM7.F9
  TOP w0.203: PU4901.10 60.35,18.79 v2(60.56,18.57) ; PU4901.4 57.51,20.58 57,20.08 v3(57,19.84) ; v2(178.39,72.18) 178.39,71.92 178.06,71.59 KBC24.89 ; 148.51,137.32 v2(147.43,137.32) ; v2(185.88,70.26) 186.17,69.97 186.17,68.36 186.4,68.14 KBC24.116 ; KBC24.5 193.58,70.39 193.97,70.78 ; KBC24.78 178.32,75.98 178.55,75.76 178.55,75.76 v2(178.58,75.74) ; C2406.2 194.75,77.43 194.75,76.41 193.83,75.49 193.58,75.49 193.49,75.58 KBC24.18 ; PU4901.7 59.14,18.63 v2(59.05,18.54) ; KBC24.45 186.4,81.37 186.1,81.08 v2(185.94,81.08)
  TOP w0.305: v2(180.42,168.06) 181.05,167.43 RN7503.3 ; CARD1.3 24.9,15.04 AFTP2501.1 ; v2(77.61,162.95) 77.74,162.82 LCD1.29 ; v2(152.44,79.94) 152.81,79.57 ODD1.7 ; VRAM8.T1 162.8,168.77 v2(162.82,168.77) ; ODD1.4 154.75,78.07 155,77.82 156.08,77.82 v2(156.4,77.5) 155.47,76.57 ODD1.1 ; LCD1.16 v2(79.38,169.32) ; U5502.11 25,64.58 ; LCD1.13 v2(77.63,170.82) ; v2(114.81,144.54) 114.81,144.73 114.66,144.87 PR4617.2 ; LCD1.36 v2(79.29,159.32) ; LCD1.19 v2(79.31,167.82) ; VRAM5.T9 194.4,140.7 v2(194.48,140.78)
  TOP w0.356: VRAM8.G1 162.04,160.81 v2(162.04,160.77) ; v2(174.3,156.73) 174.36,156.73 VRAM7.B3 ; v2(187.45,169.07) 187.52,169.01 RN7507.4 ; VRAM6.P9 v2(192.8,154.79) ; VRAM6.D8 v2(185.2,153.71) VRAM6.E8 ; v2(191.16,140.85) 191.16,140.78 191.2,140.74 VRAM5.M9 ; 169.14,157.21 169.16,157.21 VRAM7.A9 ; 169.14,157.21 v2(169.06,157.21) ; 169.14,157.21 169.18,157.17 VRAM7.B9 ; v2(187.06,147.17) 187.06,147.2 187.2,147.35 VRAM6.G1 ; v2(182.39,147.11) 182.6,147.11 VRAM6.B1 ; v2(187.19,140.73) 187.2,140.72 VRAM5.G9 ; v2(194.95,148.08) 194.58,147.71 VRAM6.T1 ; VRAM5.G1 v2(186.8,134.12) ; v2(189.19,138.92) 189.19,138.93 VRAM5.J8 ; v2(170.4,163.17) 170.8,162.78 VRAM7.J8 ; v2(169.23,165.1) 169.3,165.17 VRAM7.M9 ; RN7511.4 182.43,165.24 v2(182.17,165.51) 182.17,165.89 RN7522.4 ; 171.2,159.17 171.2,159.17 170.8,158.77 v2(170.4,159.18) ; 171.2,159.17 v2(171.2,159.19) ; 171.2,159.17 VRAM7.E8 VRAM7.F9 ; v2(162,157.57) 162,157.57 VRAM8.B1 ; v2(191.06,133.16) 191.2,133.3 VRAM5.M1 ; v2(191.11,154.84) 191.14,154.82 191.14,154.17 VRAM6.M9 ; VRAM5.P9 192.8,140.6 v2(192.93,140.73) ; v2(162.99,166.59) 162.81,166.77 VRAM8.P1 ; RN7518.4 191.8,162.8 v2(192.08,163.08) ; RN7514.3 189.11,160.14 189.55,160.58 v2(189.55,161.07) ; VRAM6.M1 191.2,147.08 v2(191.19,147.07) ; VRAM8.G9 156.01,161.17 v2(156.39,161.56) 156.78,161.17 VRAM8.G8 ; G6101.1 194.4,173.58 v2(194.46,173.65) ; RN7509.3 191.95,168.23 v2(191.99,168.19) ; VRAM5.E1 v2(185.2,134.12) VRAM5.E2 ; v2(156.4,162.37) 156.8,162.77 VRAM8.J8 ; AFTP3301.1 21.42,31.63 v2(21.66,31.88) ; RN7516.3 181.74,170.82 v2(182.19,171.27) ; VRAM5.T1 v2(194.4,133.16) ; v2(161.2,163.17) 161.22,163.15 VRAM8.J2 ; v2(185.34,170.73) 185.48,170.59 RN7517.4 ; v2(162,159.17) VRAM8.D1 ; v2(162,159.17) VRAM8.E2 ; v2(162,159.17) VRAM8.E1 ; VRAM5.G8 v2(186.8,139.72) VRAM5.F9 ; VRAM6.B9 183.38,154.29 v2(183.38,154.74) 183.03,154.74 VRAM6.A9 ; v2(171.21,160.76) 170.81,161.17 VRAM7.G8 ; VRAM7.G1 176.78,161.17 v2(176.94,161.33) ; VRAM7.E2 VRAM7.D1 176.79,158.77 v2(176.94,158.91) 176.82,159.03 176.81,159.03 176.45,159.4 176.45,159.52 VRAM7.E1 ; v2(155.25,165.2) 155.29,165.17 VRAM8.M9 ; v2(183.27,133.09) 183.2,133.15 VRAM5.B1 ; VRAM5.J2 v2(189.2,134.92) ; VRAM5.D8 v2(185.2,138.92) 185.44,139.16 185.44,139.16 VRAM5.E8 ; v2(182.66,136.67) 182.66,135.86 VRAM5.B3 ; v2(175.23,163.17) 175.23,163.14 VRAM7.J2 ; VRAM7.P9 168.84,166.77 v2(168.62,166.99) ; v2(155.43,168.49) 155.55,168.37 VRAM8.T9 ; RN7512.3 183.77,170.63 183.78,170.63 184.08,170.93 v2(184.08,171.58) ; VRAM5.P1 v2(192.8,133.12) ; VRAM8.B9 155.92,157.17 v2(155.5,156.76) 155.89,156.37 VRAM8.A9 ; v2(189.2,148.91) 189.2,148.91 VRAM6.J2 ; v2(61.5,81.89) 60.5,81.89 59.82,81.22 AFTP6235.1 ; v2(185.69,167.81) 185.5,167.62 RN7505.4 ; VRAM5.D1 v2(184.8,133.09) ; v2(185.2,148.11) VRAM6.E1 ; v2(185.2,148.11) VRAM6.E2 ; v2(185.2,148.11) VRAM6.D1 ; VRAM6.T9 194.51,154.22 v2(194.51,154.8) ; VRAM8.P9 155.28,166.77 v2(155.27,166.77) ; VRAM8.D8 VRAM8.E8 v2(156.4,159.97) VRAM8.F9 ; RN7521.4 191.02,165.56 v2(191,165.59) 191,165.59 191,166.2 RN7508.3 ; VRAM7.T9 169.78,168.59 v2(168.96,168.59) ; v2(192.88,147.15) 192.88,147.16 192.8,147.24 VRAM6.P1 ; VRAM8.B3 160.8,157.19 v2(159.44,158.55) ; v2(180.73,160.92) 181.03,160.62 RN7504.3 ; RN7515.4 179.96,163.03 v2(179.81,163.18) ; v2(64.32,77.22) 63.86,76.77 TPAD1.5 ; v2(183.19,140.8) 183.08,140.8 VRAM5.A9 ; v2(189.21,152.91) 189.18,152.94 189.17,152.94 VRAM6.J8 ; VRAM7.B1 176.5,157.17 176.8,157.46 v2(176.99,157.46) ; 182.62,149.89 VRAM6.B3 ; VRAM6.G9 187.35,154.26 v2(187.35,154.73) 187.02,154.73 VRAM6.F9 VRAM6.G8 ; v2(169.38,161.07) 169.47,161.17 VRAM7.G9
  TOP w0.381: v2(35.73,174.12) EU3102.8 EU3102.3 ; 107.03,172.12 106.31,171.4 PQ4410.4 ; 107.03,172.12 107.03,171.28 v2(107.07,171.24) ; 107.03,172.12 PR4470.1 ; v2(49.54,173.03) 49.39,173.18 C3001.2 ; v2(104.38,168.56) 104.43,168.56 104.93,169.07 104.93,169.06 PQ4410.1 ; v2(166.17,57) 166.67,57.5 R8305.2 ; v2(146.29,84.74) 145.83,84.74 145.63,84.94 145.63,84.94 145.32,85.25 144.91,85.25 144.86,85.3 R1511.2 ; v2(29.9,20.32) 29.9,18.96 Q3601.4 ; Q3601.1 v2(32.74,17.64)
  TOP w0.4: 170.8,158.77 VRAM7.D8 ; v2(177.01,166.66) 176.91,166.77 VRAM7.P1 ; v2(177.03,168.43) 177.02,168.43 176.96,168.37 VRAM7.T1 ; VRAM5.B9 183.2,140.78 v2(183.19,140.8) ; v2(177.67,165.96) 177.67,165.86 176.98,165.17 VRAM7.M1 ; VRAM8.M1 162.86,165.17 163,165.03 v2(163,165.03)
  TOP w0.406: C8308.2 150.33,133.94 150.69,133.94 v2(150.85,133.79) ; v2(89.08,31.49) 89.08,30.8 C1220.2 ; PQ4408.1 139.84,155.98 139.58,156.24 PR4405.2 ; PQ4402.1 104.8,165.25 105.23,165.68 105.23,166.64 ; PQ4408.4 142.25,154.33 141.79,153.88 v2(141.79,153.45) ; v2(172.55,55.4) 172.32,55.17 172.31,55.17 172.05,54.92 PQ8304.1 ; v2(85.56,31.45) 85.65,31.37 C1210.2 ; v2(88.23,36.07) 88.71,36.07 C1213.2 ; v2(132.82,22.97) 132.85,22.99 C1313.2 ; v2(168.99,52.02) 169.04,52.07 169.15,52.07 169.46,52.38 170.32,52.38 170.53,52.58 170.53,53.19 PQ8304.4 ; v2(128.43,18.24) 129.1,17.58 C1316.2 ; v2(107.07,163.4) 106.52,163.95 PQ4402.4
  TOP w0.508: v2(60.09,13.73) 60.1,13.73 PR4906.2 ; R2504.2 33.79,13.87 v2(34.53,13.87) ; R6302.1 187.13,31.04 v2(186.65,30.56) ; v2(165.05,69.14) 164.73,69.14 164.38,68.8 C3604.2 R3605.2 ; PR4817.1 134.78,146.45 135.16,146.06 135.16,145.6 v2(135.17,145.59) ; C7501.2 171.48,149.6 v2(171.53,149.66) ; v2(58.73,66.81) 58.74,66.81 59.71,66.81 EC9735.2 ; v2(137.73,93.12) 137.65,93.12 137.48,93.3 C1101.2 136.93,92.46 C1102.2 ; Q5403.S v2(26.81,80.55) ; EC6104.2 40.01,3.71 v2(40.9,3.71) ; v2(122.49,146.21) 121.84,146.85 EC9708.2 ; EC2903.2 90.38,7.85 90.69,7.55 91.72,7.55 EC2902.2 91.76,8.23 v2(91.75,8.23) ; C2418.2 173.74,73.86 173.8,73.92 173.8,74.49 C2610.2 174.06,74.75 174.91,74.75 v2(175.03,74.63) ; v2(174.15,57.41) 174.02,57.28 174.02,56.58 PC8302.2 ; 182.62,149.89 182.35,150.16 v2(182.35,150.43) ; v2(125.67,169.04) 125.61,169.1 PC4427.2 ; R7614.2 186.57,129.19 v2(186.29,128.91) ; 150.15,179.77 BATT1.10 147.91,179.77 ; R7518.2 171.25,131.2 v2(171.52,131.46) ; C9602.2 EC1706.2 166.03,85.63 166.97,84.7 v2(167.49,84.7) ; PR4531.2 44.69,60.32 v2(44.62,60.39) ; PC4918.2 56.94,18.85 v2(56.92,18.88) ; C2104.2 147.98,98.28 148.14,98.12 v2(148.19,98.12) ; EC2904.2 89.26,11.73 v2(89.02,11.97) ; R6209.2 60.31,71.35 v2(60.72,71.75) ; PR4405.2 139.06,155.34 138.95,155.22 v2(138.89,155.22) 138.72,155.4 EC9704.2 ; v3(152.63,152.58) 152.88,152.33 C7517.1 ; R7628.1 175.31,138.08 v2(174.84,138.08) ; C1017.2 119.78,80 119.38,80.4 v2(119.29,80.4) ; EC9712.2 142.32,148.68 143.1,149.47 v2(143.66,149.47) ; EC3305.2 30.02,27.75 30.06,27.8 v2(30.06,27.82) ; C2416.2 187.54,85.44 v2(188.22,86.11) ; R3023.2 58.63,169.87 v2(57.92,170.58) ; v3(63.65,16.2) 63.48,16.37 PC4901.2 ; EC6103.2 v2(37,4.54) ; v2(131.85,74.09) 132.01,73.93 C1121.2 ; PC4613.1 110.18,142.51 v2(109.99,142.7) ; v2(57.39,171.16) 55.98,171.16 C3010.2 ; DCIN1.8 100.9,167.37 v2(101.71,168.18) ; v2(147.48,62.89) 147.1,62.51 147.1,62.32 147.11,62.32 Q1901.S ; R1514.2 145.81,90.68 v2(145.84,90.65) ; R6207.2 186.01,124.67 186.72,125.37 Q6202.S 186.72,125.97 v2(185.89,126.8) ; v2(161.32,60.63) 162.47,61.78 R3602.2 ; v3(66.92,72.38) 66.96,72.34 66.96,71.83 TPAD1.10 ; C3602.2 C3601.2 39.5,13.01 EC9737.2 38.68,11.78 v2(38.51,11.61) ; 8.36,180.64 8.02,180.3 RJ45.10 4.6,180.3 ; R407.1 105.95,79.59 v2(105.01,78.65) ; Q8301.S 144.93,129 145.47,128.45 145.83,128.45 ; v2(28.3,9.09) 28.51,9.3 C2503.2 ; v2(175.66,142.24) 175.66,142.34 174.96,143.05 C7507.2 174.43,144.09 173.41,144.09 v2(173.21,143.9) ; v2(121.83,18.23) 121.86,18.2 C1319.2 ; R6301.1 187.45,35.78 v2(187.56,35.89) ; R2449.1 174.98,81.21 174.78,81.41 174.69,81.41 v2(174.64,81.46) ; v2(164.62,143.64) 164.35,143.91 C7505.2 ; C8104.2 166.22,156.64 v2(165.52,156.64) ; EC9724.2 35.49,71.11 v2(35.49,71.11) ; PR4707.2 113.74,138.5 114.37,139.13 v2(114.62,139.13) ; 145.83,128.45 R8301.2 ; 145.83,128.45 v2(145.83,127.61) 145.8,127.59 EC9749.1 ; v2(29.79,69.23) 29.79,69.11 30.02,68.88 C5511.2 30.48,68.46 30.95,68.93 R5510.2 ; v2(169.11,37.22) 169.11,37.27 168.76,37.62 168.67,37.62 C5806.2 ; v2(195.59,76.92) 195.86,77.18 C2411.2 195.53,77.98 195.01,77.45 C2406.2 ; HDMI1.7 12.96,62.03 ; EC6207.2 189.97,126.47 R6208.2 190.48,127.27 190.76,127.55 v3(190.76,128.26) 190.76,128.41 190.3,128.86 R7618.2 ; v2(127.43,140.02) 127.45,140.04 PC4815.2 ; v2(167.75,73.56) 166.71,73.56 Q2403.S ; R3711.2 v2(60.75,53.94) ; C1222.2 90.89,31.38 v2(90.94,31.43) ; EC9741.2 164.41,91.68 v2(164.54,91.81) ; v2(33.31,11.46) 33.32,11.45 Q2505.S ; C2422.2 195.98,73.84 196.24,73.58 v2(196.24,73.33) 196.24,73.23 196.01,72.99 C2401.2 ; R2034.2 141.47,103.45 v2(141.18,103.74) ; v2(188.09,143.08) 187.64,143.08 187.1,143.62 R8002.1 ; C1116.2 126.37,82.39 126.52,82.24 v2(126.52,82.22) ; C2407.2 172.56,70.41 172.22,70.07 v2(172.2,70.07) ; HDMI1.HP5 10.56,62.72 ; Q2404.C 166.64,70.39 167.25,69.79 167.33,69.79 v2(167.44,69.67) ; v2(177.14,151.11) 177.5,151.47 R7506.2 ; EC9705.2 v2(58.38,56.19) ; PR4517.2 v2(38.46,58.12) ; v2(55.66,76.68) 55.39,76.41 EC6202.2 ; EC3301.2 v2(30.87,24.87) ; v2(128.64,147.19) 128.93,147.47 PC4821.2 ; v2(166.06,151.15) 165.78,151.44 C7502.2 ; EC9706.2 51.9,32.67 v2(51.85,32.62) ; PR4523.2 39.86,60.27 v2(39.86,60.27) ; PC4902.2 PC4903.2 59.27,14.66 v2(59.29,14.63) ; C1109.2 126.38,86.06 v2(126.55,86.06) ; v2(91.24,36.07) 90.71,36.07 C1211.2 ; 111.42,169.48 111.17,169.48 110.35,170.29 PQ4414.S ; 111.42,169.48 v2(111.42,169.38) ; 111.42,169.48 111.42,169.61 111.99,170.18 PR4474.2 ; v2(56.14,169.81) 56.13,169.8 55.98,169.8 55.92,169.75 C3009.2 ; R2435.1 182.04,64.37 v2(182.11,64.3) 181.97,64.16 R2611.2 ; v2(82.86,36.48) 83.7,36.48 C1221.2 ; Q6205.S 43.64,72.14 v2(42.17,72.14) ; v2(127.04,143.59) 126.97,143.65 PR4824.2 PR4823.2 ; EC9717.2 156.66,113.64 v2(156.97,113.96) ; v3(37.21,51.08) 37.46,50.82 PC4519.2 ; CARD1.3 24.85,14.02 v2(24.87,14) ; v2(83.6,165.36) 84.39,165.36 84.7,165.67 DCIN1.7 84.31,167.16 EC5205.2 ; v2(173.26,140.58) 173.06,140.78 C7506.2 172.32,140.49 172.53,140.28 R7602.2 ; 10.7,61.22 HDMI1.HP2 ; HDMI1.HP2 11.4,60.54 ; HDMI1.HP2 12.11,61.22 ; v2(123.74,112.51) 124.17,112.08 C2601.2 ; PQ8306.S 174.65,52.91 174.78,52.78 175.02,52.78 v2(175.2,52.6) ; C7804.2 184.5,143.9 C7820.2 184.5,144.53 v2(184.54,144.57) ; v2(25.23,2.09) 24.61,1.47 HDLED1.2K ; PC4906.2 62.33,25.61 v3(62.16,25.78) ; v2(191.88,56.33) 191.64,56.09 EC9726.2 ; C2128.2 130.96,99.92 130.64,99.6 v2(130.26,99.6) ; v3(93.5,13.16) 93.25,13.4 R1204.2 ; PC4521.2 v2(47.35,56) ; PD4203.1 v2(129.38,172.41) ; C5503.2 v2(26.31,60.07) ; v2(123.44,84.98) 123.62,85.16 R606.2 ; 138.17,106.46 138.18,106.47 v3(138.18,106.56) ; C3106.2 30.79,169.94 v2(30.79,171.28) ; v2(67.72,83.37) 67.72,83.37 TPAD1.9 ; EC5206.2 80.1,167.17 80.06,167.13 v2(79.74,167.13) ; EU3403.2 18.44,38.07 v2(18.27,37.9) ; v2(174.02,134.8) 174.02,134.73 174.42,134.34 C7728.2 ; PC4524.2 41.99,49.12 v2(41.99,49.12) ; R3715.2 v2(57.28,52.53) ; PR4526.2 42.97,61.17 42.93,61.2 v2(42.93,61.22) ; C1111.2 124.99,89.07 v2(125.08,88.98) ; PQ4202.E 125.77,174.8 126.52,174.05 126.52,173.19 PR4202.2 127.66,172.92 v2(127.85,173.11) ; C5516.2 27.42,69.04 27.44,69.04 v2(27.54,69.14) ; R3015.2 55.35,166.98 v2(55.58,166.76) ; v2(167.27,159.36) 167.1,159.2 C8111.2 166.26,159.24 R8102.1 ; v2(24.88,5.37) 24.69,5.37 24.69,5.37 CARD1.12 ; C5208.2 83.57,156.27 83.29,156.55 v2(83.29,156.98) ; PR4464.2 105.15,166.73 105.23,166.65 105.23,166.64 v2(105.24,166.65) ; LED1.3 19.73,1.77 v2(20.15,2.19) ; v2(147.05,101.76) 146.97,101.68 146.84,101.68 146.55,101.4 146.55,101.34 C2123.2 ; EC3201.2 30.05,20.47 v2(29.9,20.32) ; C1119.2 134.69,110.88 v2(132.41,113.16) ; v2(86.55,36.07) 85.85,36.07 C1212.2 ; C8309.1 144.79,138.68 v2(144.96,138.51) ; v2(30.95,28.39) 30.68,28.66 30.08,28.66 EC3307.2 ; v2(32.02,14.46) 31.82,14.46 31.48,14.12 EC3302.2 30.44,14.18 EC3303.2 ; v2(162.71,143.64) 162.58,143.52 C7713.2 ; PC4202.2 v2(118.04,177.04) ; PC4710.2 110.38,138.33 v2(110.19,138.52) ; v2(199.19,141.13) 198.83,141.13 198.49,141.47 C7830.2 198.47,142.01 C7833.2 ; v2(45.41,75.29) 45.74,75.62 EC6206.2 ; v2(182.39,147.11) 181.92,146.63 181.92,145.69 181.09,144.86 C7829.2 181.07,143.91 C7827.2 ; v2(125.38,18.23) 125.44,18.17 C1320.2 ; v2(34.07,60.5) 34.07,60.55 34.07,60.55 C5501.2 ; v2(186.56,63.6) C2408.2 ; EC9715.2 140.66,121.25 v2(141.46,120.55) ; PR4607.1 v2(113.7,135.51) ; v2(29.01,58.2) 28.81,58.4 C5522.2 ; R2026.2 150.2,95.68 v2(150.2,96.4) ; C1018.2 111.44,79.4 v2(111.61,79.24) ; R7507.1 176.93,147.6 v2(176.96,147.58) ; C7525.2 159.16,152.26 159.16,152.25 158.54,151.63 v2(158.32,151.63) ; C1902.2 141.54,66.22 139.02,68.74 v2(138.92,68.74) ; v2(32.32,5.24) 32.32,4.93 32.34,4.91 EC6102.2 ; C8302.2 147.04,140.68 C8310.2 147.35,141.69 v2(147.56,141.89) ; C1019.2 116.7,80.11 116.34,80.47 v2(116.01,80.47) ; v2(128.58,23.45) 128.62,23.49 C1317.2 ; v2(99.17,147.88) 98.66,148.39 PR4208.2 ; EC9739.2 188.94,13.61 189.34,13.21 v2(189.34,13.19) ; EC3306.2 v2(30.79,23.49) ; CARD1.6 24.85,21.48 v2(24.57,21.2) ; C702.2 v2(98.92,102) ; PR4902.2 58.51,25.56 PR4908.1 v2(56.9,25.56) ; v2(64.08,65.21) 64.28,65.41 EC9703.2 ; v2(119.47,21.51) 119.46,21.52 C1314.2 ; v2(82,173.84) 81.88,173.96 R5218.2 ; C2114.2 122.8,80.27 v2(122.21,80.27) ; v2(168.6,79.7) 168.79,79.88 168.79,79.9 169.22,80.33 EC1707.2 ; PC4531.2 v2(40.9,49.68) ; v2(111.75,141.88) 112.53,141.88 PR4604.2 113.42,141.85 PC4612.2 ; v2(194.09,70.09) 194.28,70.09 194.64,70.45 R2447.2 193.97,70.78 ; PC4604.2 v3(115.58,134.78) ; C1901.2 v2(144.15,65.45) ; C1020.2 121.95,79.17 v2(122.08,79.17) ; PR4614.1 122.3,137.94 v2(123.27,137.94) ; C3002.2 v2(53.28,171.5) ; R7637.2 v2(174.02,132.3) ; EC3304.2 31.85,16.34 v2(31.99,16.19) ; USB1.12 5.27,49.24 ; PR4530.2 37.33,59.08 v2(37.42,58.98) ; 12.23,64.22 HDMI1.HP8 ; HDMI1.8 13.06,64.32 ; C3008.2 v2(44.59,171.96) ; R1509.1 EC1501.2 144.84,101.4 v2(145.04,101.61) 144.87,101.78 R2024.2 ; R3714.2 v2(59.86,53.94) ; EC9716.2 v2(135.23,128.67) ; EC9713.2 v2(69.26,26.38) ; 8.34,161.39 8.08,161.64 RJ45.9 4.54,161.64
  TOP w0.635: v2(34.89,18.09) 35.11,17.87 C3605.2 ; 11.07,3.72 CARD1.14 ; CARD1.14 15.43,3.72 ; CARD1.14 13.25,4.56 ; CARD1.14 13.25,2.88 ; 168.13,179.77 BATT1.9 ; BATT1.9 169.17,177.84 ; BATT1.9 170.22,179.77 ; HDMI1.PTH7 13.5,55.16 ; HDMI1.PTH7 15.24,54.27 ; HDMI1.PTH7 13.5,53.38 ; 5.5,53.38 HDMI1.PTH10 ; HDMI1.PTH10 5.35,54.42 HDMI1.PTH12 ; HDMI1.PTH10 5.5,55.16 ; HDMI1.PTH10 7.24,54.27 ; 13.72,32.68 USB1.11 ; USB1.11 15.4,33.57 ; USB1.11 13.72,34.46 ; 6.09,74.37 HDMI1.PTH5 ; 13.72,45.48 USB1.10 ; USB1.10 13.72,47.26 ; USB1.10 15.4,46.37 ; 146.01,157.37 HGPU1.1 ; HGPU1.1 149.2,154.18 ; HGPU1.1 149.2,160.56 ; HGPU1.1 152.39,157.37 ; 13.25,29.18 CARD1.15 ; CARD1.15 15.43,30.02 ; CARD1.15 13.25,30.86 ; CARD1.15 11.07,30.02 ; 153.06,179.77 BATT1.7 ; BATT1.7 154.05,178.78 ; BATT1.7 154.05,180.76 ; v2(3.42,77.2) 2.25,76.03 HDMI1.PTH6 5.35,76.02 HDMI1.PTH4 ; HDMI1.PTH11 6.18,56.07 ; PWR1.5 v2(195.45,164.23) ; 14.47,35.76 USB1.4 15.18,36.47 ; 198.43,111.33 200.9,113.8 HGPU2.1 ; USB1.13 5.27,30.91 ; 10.25,76.96 HDMI1.PTH2 8.87,75.97 ; HDMI1.PTH1 15.24,76.17 ; HDMI1.PTH1 13.5,77.06 ; HDMI1.PTH1 13.5,75.28 ; HDMI1.PTH4 7.24,76.17 ; HDMI1.PTH4 5.5,75.28 ; 12.04,57.97 HDMI1.PTH8 10.6,58.96 ; 12.97,39.26 USB1.7 ; USB1.7 13.68,39.97 ; USB1.7 12.97,40.68 ; 202.44,155.04 200.5,156.98 HGPU3.1 200.5,160.03 202.8,162.34 ; 151.06,179.77 BATT1.8 ; BATT1.8 152.05,180.76 ; BATT1.8 152.05,178.78 ; BATT1.8 153.04,179.77 ; HGPU2.1 197.53,114.27 ; HGPU2.1 200.9,115.85 198.89,117.86 ; 12.04,72.47 HDMI1.PTH3 10.6,71.48 ; 10.25,53.48 HDMI1.PTH9 8.87,54.47
  L3 w0.102: v2(115.98,76.54) 116.42,76.98 116.42,77.38 v2(116.95,77.91)
  L3 w0.508: 12.32,64.22 HDMI1.HP8 10.63,64.22 ; HDMI1.7 12.94,62.03 ; HDMI1.8 12.92,64.32 ; 5.27,49.09 USB1.12 ; 8.24,161.64 RJ45.9 4.53,161.64 ; 8.26,180.73 7.83,180.3 RJ45.10 4.92,180.3 4.49,180.73 ; USB1.13 5.27,30.91 5.26,30.9 ; 10.59,65.72 HDMI1.HP11 ; 12.31,61.22 HDMI1.HP2 ; HDMI1.HP2 11.4,60.34 ; HDMI1.HP2 10.64,61.22 ; HDMI1.10 12.8,68.9 ; 10.56,62.72 HDMI1.HP5
  L3 w0.635: 13.5,53.38 HDMI1.PTH7 ; HDMI1.PTH7 15.24,54.27 ; HDMI1.PTH7 13.5,55.16 ; 8.87,75.97 HDMI1.PTH2 10.25,76.96 ; 12.97,39.26 USB1.7 ; USB1.7 13.68,39.97 ; USB1.7 12.97,40.68 ; 11.07,3.72 CARD1.14 ; CARD1.14 13.25,2.88 ; CARD1.14 13.25,4.56 ; CARD1.14 15.43,3.72 ; BATT1.8 152.05,180.76 ; BATT1.8 151.06,179.77 ; BATT1.8 153.04,179.77 ; 10.6,71.48 HDMI1.PTH3 12.04,72.47 ; 5.5,53.38 HDMI1.PTH10 ; HDMI1.PTH10 5.35,54.42 HDMI1.PTH12 ; HDMI1.PTH10 7.24,54.27 ; HDMI1.PTH10 5.5,55.16 ; 169.17,177.84 BATT1.9 170.22,179.77 ; v2(3.42,77.2) 2.25,76.03 HDMI1.PTH6 5.35,76.02 HDMI1.PTH4 ; 10.25,53.48 HDMI1.PTH9 8.87,54.47 ; 10.6,58.96 HDMI1.PTH8 12.04,57.97 ; 5.5,75.28 HDMI1.PTH4 ; HDMI1.PTH4 7.24,76.17 ; 153.06,179.77 BATT1.7 154.05,180.76 ; HDMI1.PTH1 15.24,76.17 ; HDMI1.PTH1 13.5,75.28 ; HDMI1.PTH1 13.5,77.06 ; CARD1.15 13.25,30.86 ; CARD1.15 15.43,30.02 ; CARD1.15 11.07,30.02 ; CARD1.15 13.25,29.18 ; 14.47,35.76 USB1.4 ; USB1.4 14.47,37.18 ; USB1.4 15.18,36.47 ; HDMI1.PTH5 6.16,74.37 ; 13.8,57.76 HDMI1.6 12.35,59.74 ; USB1.11 13.72,34.46 ; USB1.11 13.72,32.68 ; USB1.11 15.4,33.57 ; USB1.10 15.4,46.37 ; USB1.10 13.72,45.48 ; USB1.10 13.72,47.26 ; 149.97,179.77 BATT1.10 147.88,179.77 ; HDMI1.5 13.8,70.67 ; HDMI1.PTH11 6.22,56.07
  L4 w0.102: v2(171.53,149.66) 171.94,149.25 171.94,148.65 171.51,148.22 v2(171.51,148.06) ; 172.85,145.11 172.85,145.11 172.85,144.25 v2(173.21,143.9) ; 172.85,145.11 172.77,145.2 172.77,146.8 173.12,147.16 v2(173.12,147.22) ; 172.85,145.11 173.63,145.11 v2(174.05,145.53) ; v2(125.85,75.86) 125.4,76.3 125.4,77.32 v2(125.85,77.76)
  L4 w0.33: v2(108.76,77.29) 109.07,77.29 109.68,77.9 v2(109.77,77.9)
  L4 w0.508: 10.69,61.22 HDMI1.HP2 ; HDMI1.HP2 11.4,60.38 ; HDMI1.HP2 12.25,61.22 ; 10.69,64.22 HDMI1.HP8 12.2,64.22 ; HDMI1.5 12.99,70.05 ; HDMI1.HP5 10.56,62.72 ; 8.24,161.64 RJ45.9 4.51,161.64 ; HDMI1.7 12.95,62.03 ; 5.27,30.78 USB1.13 ; 4.38,180.3 RJ45.10 8,180.3 8.53,180.82 ; 5.27,49.2 USB1.12 ; HDMI1.HP11 10.55,65.72 ; HDMI1.8 12.91,64.32 ; HDMI1.10 12.99,68.9
  L4 w0.635: USB1.4 14.47,37.18 ; USB1.4 14.47,35.76 ; USB1.4 15.18,36.47 ; 11.07,30.02 CARD1.15 ; CARD1.15 13.25,30.86 ; CARD1.15 13.25,29.18 ; CARD1.15 15.43,30.02 ; 12.97,39.26 USB1.7 ; USB1.7 13.68,39.97 ; USB1.7 12.97,40.68 ; HDMI1.PTH3 12.04,72.47 ; 147.88,179.77 BATT1.10 149.97,179.77 ; HDMI1.PTH5 6.06,74.37 ; HDMI1.PTH1 13.5,77.06 ; HDMI1.PTH1 13.5,75.28 ; HDMI1.PTH1 15.24,76.17 ; 12.04,57.97 HDMI1.PTH8 10.6,58.96 ; 8.87,75.97 HDMI1.PTH2 10.25,76.96 ; HDMI1.PTH11 6.08,56.07 ; HDMI1.PTH10 5.35,54.42 HDMI1.PTH12 ; HDMI1.PTH10 5.5,53.38 ; HDMI1.PTH10 7.24,54.27 ; HDMI1.PTH10 5.5,55.16 ; CARD1.14 15.43,3.72 ; CARD1.14 11.07,3.72 ; CARD1.14 13.25,2.88 ; CARD1.14 13.25,4.56 ; USB1.11 15.4,33.57 ; USB1.11 13.72,34.46 ; USB1.11 13.72,32.68 ; 13.5,53.38 HDMI1.PTH7 ; HDMI1.PTH7 13.5,55.16 ; HDMI1.PTH7 15.24,54.27 ; USB1.10 15.4,46.37 ; USB1.10 13.72,45.48 ; USB1.10 13.72,47.26 ; BATT1.8 152.05,180.76 ; BATT1.8 151.06,179.77 ; BATT1.8 153.04,179.77 ; 13.8,57.98 HDMI1.6 12.39,59.74 ; v2(3.42,77.2) 2.25,76.03 HDMI1.PTH6 5.35,76.02 HDMI1.PTH4 ; 5.5,75.28 HDMI1.PTH4 ; HDMI1.PTH4 7.24,76.17 ; BATT1.9 170.78,179.77 ; 10.25,53.48 HDMI1.PTH9 8.87,54.47 ; 154.05,180.76 BATT1.7 153.06,179.77 ; HGPU2.1 200.9,111.97 ; HGPU2.1 198.3,114.27 ; HGPU2.1 200.9,116.57
  BOTTOM w0.102: CPU1.D2 136.58,92.89 137.5,92.89 v2(137.73,93.12) ; v2(97.31,76.27) 97.71,76.67 98.78,76.67 CPU1.AN63 ; v2(97.32,78.9) 97.55,79.13 CPU1.AJ63
  BOTTOM w0.127: 112.76,74.79 112.73,74.76 112.73,74.26 112.42,73.95 112.42,73.81 CPU1.AV41 ; CPU1.AV49 107.64,73.91 108.01,74.27 108.01,74.72 107.98,74.75 ; CPU1.AN40 113.3,76.55 113.57,76.55 CPU1.AP39 CPU1.AR39 ; 111.18,74.8 111.18,74.55 111.17,74.54 111.17,74.29 110.79,73.91 CPU1.AV43 ; 109.57,74.87 109.57,74.56 109.58,74.54 109.58,74.12 CPU1.AV46 ; 114.33,74.78 114.33,74.55 114.32,74.54 114.32,74.29 113.94,73.91 CPU1.AV39 ; CPU1.AH49 107.26,79.8 CPU1.AJ50 ; v2(102.25,71.74) 102.35,71.84 CPU1.AY57 ; CPU1.AV36 115.64,73.88 115.64,73.99 115.88,74.24 115.88,74.8 115.88,74.8 ; v2(122.8,71.81) CPU1.AY24 ; CPU1.AY26 121.45,71.63 v2(121.26,71.44) ; CPU1.AY18 126.58,71.84 v2(126.82,71.6) ; v2(128.87,74.11) 128.85,74.09 127.9,74.09 CPU1.AV16 ; v2(118.79,71.4) 119.01,71.62 CPU1.AY30 ; CPU1.AY22 124.15,72.78 124.15,71.57 v2(124.34,71.38)
  BOTTOM w0.152: CPU1.AY53 104.78,71.6 v2(104.71,71.53) ; CPU1.AG63 97.68,80.48 v2(97.67,80.5)
  BOTTOM w0.178: CPU1.AU28 119.74,74.73 119.73,74.75 119.44,74.75 119.42,74.73 CPU1.AU30 ; CPU1.AU28 120.25,74.75 121.43,74.75 CPU1.AU26 121.46,74.75 122.78,74.75 CPU1.AU24 CPU1.AV24 CPU1.AW24 CPU1.AY24 ; CPU1.AU28 CPU1.AV28 ; v2(105.01,78.65) 105.17,78.82 CPU1.AK52 105.64,78.92 CPU1.AJ52 ; CPU1.AU20 125.37,74.74 125.85,74.74 125.86,74.75 126.56,74.75 CPU1.AU18 126.6,74.75 127.87,74.75 CPU1.AU16 ; CPU1.AU20 CPU1.AV20 ; CPU1.AU20 124.88,74.73 124.86,74.75 124.57,74.75 124.56,74.73 CPU1.AU22 ; v2(104.95,76.58) 105.32,76.22 CPU1.AP52 105.45,76.14 105.45,75.66 105.53,75.59 CPU1.AR52 ; CPU1.AN49 107.62,76.61 108,76.61 CPU1.AN48 108.68,77.29 v2(108.76,77.29) ; v2(119.36,79.14) 118.85,78.64 CPU1.AL31 CPU1.AM31 CPU1.AN31 ; CPU1.AP48 108.15,76.22 v2(107.81,75.87) ; v2(97.31,74.62) 97.59,74.9 97.94,74.9 98.28,75.24 CPU1.AT63 98.94,75.24 99.09,75.39 CPU1.AT62 100.06,75.39 CPU1.AT61 ; CPU1.AN31 118.53,76.87 CPU1.AN32 ; CPU1.AN31 CPU1.AP31 CPU1.AR31 ; v2(115.06,77.19) 115.08,77.19 115.39,76.87 CPU1.AN36 ; CPU1.AU59 101.13,74.75 102.33,74.75 CPU1.AU57 102.37,74.75 103.55,74.75 CPU1.AU55 ; CPU1.AU59 100.78,75.06 100.78,75.1 100.62,75.27 v2(100.62,75.55) 100.78,75.71 100.78,76.17 100.76,76.18 CPU1.AN60 100.76,77.11 100.78,77.13 100.78,77.41 100.76,77.43 CPU1.AL60 ; CPU1.AU59 CPU1.AV59 CPU1.AW59 100.79,73.11 100.79,73.11 ; CPU1.AL61 CPU1.AL60 ; CPU1.AL60 100.76,78.4 100.78,78.42 100.78,78.7 100.76,78.72 CPU1.AJ60 ; v2(97.74,83.94) 97.96,84.16 98.48,84.16 CPU1.Y63 ; v2(106.3,71.48) 106.22,71.56 106.22,72.69 CPU1.AY51 CPU1.AW51 CPU1.AV51 CPU1.AU51 ; CPU1.P59 101.09,87.23 v2(100.76,87.55) ; CPU1.AU55 CPU1.AV55 ; CPU1.AU55 104.05,74.73 104.07,74.75 104.36,74.75 104.37,74.73 CPU1.AU53 ; v2(112.57,76.55) 112.26,76.87 CPU1.AN42 111.97,76.87 v2(111.72,76.62) 111.47,76.62 CPU1.AN43 111.12,76.77 110.34,76.77 CPU1.AN45 ; v2(105.01,77.84) 105.34,78.17 CPU1.AL52 ; v2(97.68,82.03) 97.74,81.97 98.42,81.97 CPU1.AD63 ; CPU1.AJ58 101.74,79.47 102.06,79.8 CPU1.AH57 ; CPU1.AW47 108.4,73.11 108.46,73.11 v2(108.81,73.45) ; CPU1.AV36 115.2,73.44 v2(115.12,73.44) ; CPU1.AT49 107.29,74.75 108.69,74.75 CPU1.AT46 108.81,74.87 109.97,74.87 109.97,74.86 CPU1.AT43 110.44,74.8 111.89,74.8 CPU1.AT42 112.34,74.86 112.42,74.79 113.45,74.79 CPU1.AT40 ; CPU1.AT40 113.53,75.85 CPU1.AR39 ; CPU1.AT40 113.64,74.75 114.3,74.75 114.33,74.78 115.02,74.78 CPU1.AT37 115.17,74.8 116.61,74.8 CPU1.AT35 ; v2(134.68,74.21) 134.79,74.1 134.79,73.57 135.14,73.22 CPU1.AW4 ; v2(111.96,73.45) 111.61,73.11 CPU1.AW42 ; v2(113.52,73.46) 113.53,73.46 113.64,73.46 CPU1.AV39 ; CPU1.AV34 117.42,73.43 CPU1.AW33 CPU1.AY33 ; 108.24,79.47 108.48,79.24 109.31,79.24 CPU1.AJ45 ; 108.24,79.47 CPU1.AJ47 ; 108.24,79.47 108.24,79.47 ; v2(115.06,78.56) 115.45,78.17 CPU1.AL36 ; v2(116.95,77.91) 117.21,78.17 CPU1.AL33 ; CPU1.AV33 117.71,74.73 CPU1.AU33 ; 113.39,77.85 v2(113.42,77.88) 113.57,77.72 CPU1.AN39
  BOTTOM w0.18: 186.89,153.79 186.81,153.71 186,153.71 VRAM6.E8
  BOTTOM w0.203: v2(171.52,131.46) 171.5,131.45 171.5,130.91 171.11,130.51 GPU1.H2 ; CPU1.AN45 110.04,76.87 109.96,76.79 109.58,76.79 109.51,76.87 CPU1.AN46 109.19,76.87 v2(108.76,77.29) ; v2(105.12,77.21) 105.16,77.16 105.24,77.16 CPU1.AN52 105.64,76.87 105.77,76.74 106.15,76.74 106.28,76.87 CPU1.AN51 106.37,76.87 106.47,76.76 107.11,76.76 107.21,76.87 CPU1.AN49 ; v2(137.77,74.24) 137.58,74.43 CPU1.AU1 ; v2(145.04,111.38) 144.95,111.38 144.7,111.14 U2101.8 ; CPU1.AR43 110.91,75.57 v2(110.72,75.38) 110.38,75.03 CPU1.AT43 ; WLAN1.1 161.81,63.02 161.65,63.17 v2(161.3,63.17) ; CPU1.AL46 109.58,77.9 v2(109.77,77.9) 109.97,77.9 CPU1.AL45 ; CPU1.V3 135.81,84.79 v2(136.12,84.49) ; CPU1.U22 123.73,85.63 v2(123.38,85.98) 123.83,86.44 CPU1.R22 ; CPU1.AW60 100.55,73.11 100.79,73.11 ; v2(104.11,77.84) 104.44,78.17 CPU1.AL54 ; v2(114.08,76.54) 114.09,76.54 114.41,76.22 CPU1.AP38 ; v2(102.14,75.89) 102.14,75.89 102.21,75.89 102.53,76.22 CPU1.AP57 ; CPU1.AY59 101.03,72.03 v2(100.87,71.88) ; CPU1.AP3 136.12,75.61 v2(136.12,75.5) ; CPU1.AK3 135.81,78.8 v2(136.11,78.5) ; 101.21,93.14 CPU1.D59 101.21,92.87 101.74,92.35 CPU1.F58 ; CPU1.J63 97.93,90.15 97.77,90.31 v2(97.76,90.31) ; CPU1.AW4 135.14,72.5 CPU1.AY4 ; CPU1.T1 137.29,86.54 v2(138.39,86.54) ; v2(105.01,77.84) 105.21,77.84 CPU1.AM52 ; CPU1.D5 134.44,93.13 v2(134.12,92.81) 134,92.93 133.56,92.93 133.19,93.3 CPU1.D8 ; CPU1.AN48 CPU1.AP48 ; v2(112.57,76.55) 112.6,76.55 112.92,76.87 CPU1.AN40 113.31,77.19 CPU1.AN39 ; CPU1.D62 99.08,93.11 CPU1.D63 ; v2(163.89,152.02) 163.55,151.68 163.55,150.19 GPU1.U26 ; v2(126.52,82.22) 126.27,81.97 125.53,81.97 125.53,81.97 CPU1.AD21 ; v2(105.96,77.84) 106.29,78.17 CPU1.AL51 ; GPU1.B11 175.81,137.69 175.41,138.08 175.09,138.08 175.09,138.08 v2(174.84,138.08) ; HDA27.4 v2(179.14,15.29) ; v2(161.32,60.63) 161.32,61.07 161.78,61.52 WLAN1.7 ; CPU1.AL57 102.53,78.17 v2(102.21,77.84) ; GPU1.AF8 156.49,135.21 156.91,134.79 v2(157.45,134.79) ; GPU1.Y23 161.58,148.06 161.58,149.65 161.19,150.05 GPU1.Y26 ; CPU1.AL40 113.3,77.85 113.39,77.85 ; v2(134.78,81.53) 134.48,81.23 CPU1.AE5 ; v2(158.32,151.63) 158.5,151.44 158.5,150.27 GPU1.AC26 ; CPU1.AP54 104.44,76.22 104.13,75.91 v2(104.09,75.91) ; v2(166.06,151.15) 166.07,151.15 166.07,150.15 GPU1.P26
  BOTTOM w0.229: CPU1.AB20 CPU1.AB22 123.83,83.19 123.59,83.43 123.59,83.45 v2(123.42,83.62) ; CPU1.A28 120.48,94.86 120.48,95.81 v2(120.12,96.17)
  BOTTOM w0.254: CPU1.AH22 124.41,79.94 CPU1.AJ23 123.73,79.8 CPU1.AH24 123.17,79.77 v2(123.17,79.21) 123.19,79.21 CPU1.AK23 ; CPU1.A40 CPU1.B40 ; CPU1.AF11 130.58,81.28 v2(130.58,81.66) 130.58,81.97 CPU1.AB10 ; CPU1.AF11 131.06,80.7 CPU1.AG11 130.24,80.7 CPU1.AF12 ; CPU1.AF11 131.38,81.13 CPU1.AE10 ; CPU1.AU22 124.12,74.76 123.79,74.76 123.76,74.79 123.53,74.79 v2(123.19,75.13) ; v2(113.27,20.44) 113.41,20.44 114.48,21.51 114.48,23.88 114.35,24.01 DM2.65 ; CPU1.N21 125.43,87.63 v2(125.05,87.26) 125.05,87.25 CPU1.P22 ; v2(109.33,80.28) 108.89,79.84 CPU1.AH46 ; v2(109.29,91.38) 109.3,91.38 CPU1.F46 CPU1.D46 109.3,92.81 ; 121.84,92.81 CPU1.D26 CPU1.F26 ; v2(108.81,73.45) 108.81,73.46 108.92,73.46 CPU1.AV46 ; CPU1.E17 127.34,91.96 127.34,91.61 CPU1.G18 126.8,91.16 v2(126.45,91.52) 126.45,91.55 126.18,91.82 CPU1.F20 ; v2(113.29,80.27) 113.29,79.62 CPU1.AJ39 ; v2(113.29,80.27) 113.62,80.27 CPU1.AH38 ; v2(113.29,80.27) 113.26,80.27 CPU1.AH40 112.65,79.66 v2(112.65,79.25) 112.36,79.25 CPU1.AJ41 111.91,79.24 v2(111.61,79.24) ; CPU1.AN35 116.35,76.87 116.03,76.54 v2(115.98,76.54) ; 105.53,94.76 CPU1.A52 105.49,94.71 105.49,94.15 CPU1.B52 ; CPU1.AP20 125.96,75.86 v2(125.85,75.86) ; 119.33,92.81 CPU1.D30 CPU1.F30 119.33,91.38 v2(119.32,91.38) ; CPU1.AW37 115.02,73.44 v2(115.12,73.44) ; CPU1.AP29 119.72,76.22 119.39,75.89 CPU1.AR31 ; CPU1.AL20 125.91,77.76 v2(125.85,77.76) ; v2(140.94,20.29) 141.29,20.29 142.25,19.33 DM2.150 ; CPU1.AM1 137.67,77.37 v2(137.7,77.35) ; v2(137.83,83.51) 137.69,83.37 CPU1.AA1 ; v2(123.19,75.13) 122.8,74.74 CPU1.AU24 ; v2(123.19,75.13) 123.19,75.17 CPU1.AR23 123.91,75.89 v2(123.98,75.89) ; CPU1.G8 132.7,91.16 132.87,91.34 133.27,91.34 133.45,91.16 CPU1.G6 133.65,91.16 134.12,91.63 v2(134.12,92.81) ; CPU1.AG60 CPU1.AG61 ; v2(103.05,80.04) 102.63,80.04 CPU1.AH57 102.71,79.47 CPU1.AJ56 103.04,79.47 103.37,79.47 CPU1.AH55 104.01,79.47 104.33,79.47 ; DM2.49 109.55,21.84 108.83,21.12 v2(108.75,21.12) ; CPU1.AL29 119.43,77.84 v2(119.36,77.84) ; CPU1.AH30 v2(119.29,80.4) ; DM2.153 143.15,24.11 143.75,23.51 ; CPU1.AY6 133.74,71.82 133.87,71.69 v2(133.87,71.68) ; CPU1.AH42 111.49,79.35 v2(111.61,79.24) ; CPU1.AJ50 106.93,79.47 106.61,79.47 CPU1.AH51 105.97,79.47 105.64,79.47 CPU1.AJ52 ; DM2.167 147.35,21.91 148.41,20.85 v2(148.49,20.85) ; 106.79,92.81 CPU1.D50 CPU1.F50 106.79,91.38 v2(106.79,91.38) ; CPU1.AH49 107.91,79.47 108.24,79.47 108.24,79.47 ; DM2.168 147.65,18.32 v2(147.65,18.32) ; v2(111.61,79.24) 111.07,79.24 CPU1.AJ43 110.51,79.8 CPU1.AH44 109.86,79.8 CPU1.AJ45 ; v2(121.19,75.89) 121.33,75.89 CPU1.AP26 ; v2(130.94,71.5) 130.74,71.71 CPU1.AY11 ; v2(121.27,77.84) 121.59,78.17 CPU1.AL26 ; CPU1.L61 99.49,88.91 v2(99.49,89.03) ; v2(105.01,78.65) 104.99,78.67 CPU1.AH53 104.67,79.47 104.33,79.47 ; CPU1.AR52 104.78,74.82 CPU1.AU53 ; v2(130.92,85.96) 131.64,86.68 CPU1.R10 ; CPU1.A18 126.51,95.62 v2(126.55,95.66) ; 114.31,92.81 CPU1.D38 CPU1.F38 114.31,91.38 v2(114.31,91.38) ; v2(125.19,95.63) 125.2,95.62 125.2,94.51 CPU1.B20 125.26,94.34 125.6,93.99 CPU1.C20 ; CPU1.AG63 CPU1.AG62 ; CPU1.AP22 124.08,75.89 v2(123.98,75.89) ; v2(131.02,86.82) 130.35,87.48 130.35,88.34 CPU1.L13 ; CPU1.V10 131.64,84.76 v2(131.35,84.46) 131.64,84.17 CPU1.Y10 ; CPU1.AR33 117.38,75.57 117.1,75.29 v2(116.96,75.29) 116.68,75 CPU1.AT35 ; DM2.156 v2(144.05,18.26) ; v2(123.98,75.89) 123.78,76.09 123.72,76.09 CPU1.AP23 123.25,76.55 v2(123.19,76.55) 123.2,76.56 123.2,76.57 123.5,76.87 CPU1.AN23 ; v2(129.37,81.61) 129.43,81.55 CPU1.AF14 ; 111.81,92.81 CPU1.D42 CPU1.F42 111.81,91.38 v2(111.8,91.38) ; CPU1.B60 100.65,94.22 100.65,93.7 101.21,93.14 ; CPU1.J59 101.09,90.23 v2(100.78,90.53) ; DM2.162 v2(145.85,18.32) ; v2(133.48,88.33) 133.48,88.45 CPU1.L7 ; CPU1.AV49 107.57,73.76 107.44,73.63 107.41,73.63 v2(107.23,73.45) 106.89,73.11 CPU1.AW50 ; CPU1.W20 126.19,84.81 v2(126.56,85.18) ; CPU1.B28 CPU1.A28 ; v2(137.67,80.42) 137.62,80.37 CPU1.AG1 ; CPU1.AV41 112.07,73.46 111.97,73.46 v2(111.96,73.45) ; v2(116.82,91.38) 116.82,91.38 CPU1.F34 CPU1.D34 116.82,92.81 ; CPU1.L20 126.25,88.57 v2(126.43,88.57) 126.52,88.57 CPU1.L18 ; v2(133.36,83.51) 133.18,83.33 CPU1.AB7 ; v2(131.26,93.9) 131.25,93.89 CPU1.C11 130.38,93.51 CPU1.D12 ; CPU1.AP39 114.08,76.54 v2(114.08,76.54) ; 104.33,79.47 CPU1.AJ54 ; CPU1.AR5 134.37,75.71 134.64,75.97 v2(134.65,75.97) ; v2(136.12,90.49) 136.11,90.49 136.11,90.6 CPU1.G3 ; v2(104.26,91.38) 104.28,91.41 CPU1.F54 CPU1.D54 104.28,92.81 ; v2(100.79,84.53) 100.79,84.42 CPU1.Y59 ; DM2.31 104.15,24.97 104.15,22.16 105,21.31 v2(105.08,21.31) ; CPU1.A11 v2(130.75,95.61) ; CPU1.L58 101.74,88.96 v2(102.28,88.96) ; CPU1.D12 130.6,93.08 130.6,92.57 CPU1.E11 130.16,91.92 130.16,90.93 CPU1.H13 ; CPU1.D12 CPU1.D14 129.19,93.7 CPU1.C14 129.19,94.18 129.19,94.18 129.19,94.7 129.11,94.78 129.11,95.06 CPU1.A14 ; v2(102.28,85.06) 101.74,85.06 CPU1.V58 101.61,85.19 101.61,86.22 CPU1.T58 ; v2(119.36,79.14) 119.69,79.47 CPU1.AJ29 120.27,79.47 CPU1.AH28 120.92,79.47 CPU1.AJ27 ; CPU1.K1 137.28,89.53 137.41,89.53 137.42,89.54 v2(137.7,89.54) ; v2(130.5,75.71) 130.83,75.38 CPU1.AR11 ; v2(130.73,85.12) 131.04,85.12 131.34,85.41 CPU1.U9 ; v2(113.52,73.46) 113.46,73.46 CPU1.AW40 ; CPU1.AW44 110.02,73.11 110.19,73.27 110.23,73.27 v2(110.38,73.43) 110.46,73.43 CPU1.AV43 ; GPU1.B23 176.1,147.67 176.87,147.67 v2(176.96,147.58) ; v2(113.42,77.88) 113.42,78.31 113.57,78.47 CPU1.AL39 ; CPU1.AW35 116.61,73.46 v2(116.68,73.46) 116.7,73.48 116.81,73.48 CPU1.AV34 117.42,74.08 CPU1.AV33 117.71,73.48 CPU1.AW33 ; v2(133.37,85.41) 133.35,85.39 133.35,85.11 CPU1.V7
  BOTTOM w0.279: CPU1.A44 CPU1.B44 ; CPU1.A32 CPU1.B32 ; CPU1.B48 CPU1.A48 ; CPU1.B24 CPU1.A24 ; CPU1.B56 102.88,94.26 102.88,94.6 CPU1.A56
  BOTTOM w0.3: v2(191.06,133.16) 191.2,133.3 VRAM5.M1
  BOTTOM w0.305: GPU1.AE20 157.05,145.1 v2(156.67,144.73) ; CPU1.F61 99.79,91.63 99.48,91.93 v2(99.48,92.03) ; GPU1.AC8 v2(159.07,134.79) GPU1.AB7 ; v2(131.85,74.09) 132.18,73.76 CPU1.AV8 ; CPU1.AG62 CPU1.AG61 ; v2(155.8,144.79) 156.14,145.13 GPU1.AF20 ; v2(165.21,52.86) 165.01,52.86 164.16,52.02 WLAN1.45 ; 118.62,75.01 118.62,75.33 118.85,75.56 CPU1.AR31 ; 118.62,75.01 118.9,74.73 CPU1.AU30 ; 118.62,75.01 118.37,75.01 118.11,74.75 CPU1.AU33 117.61,74.89 117.61,75.35 CPU1.AR33 ; v2(192.74,31.46) 192.5,31.46 192.16,31.13 HDD1.6 ; 127.84,88.91 127.84,88.73 127.85,88.73 127.85,88.31 127.4,87.86 v2(127.36,87.86) ; v2(106.8,75.27) 106.26,74.73 CPU1.AU51 ; v2(106.8,75.27) 106.93,75.4 106.97,75.4 107.13,75.57 CPU1.AR49 ; v2(106.8,75.27) 107.2,74.86 CPU1.AT49 ; CPU1.C25 122.08,94.11 CPU1.B26 ; WLAN1.18 172.11,58.77 172.37,59.03 173.53,59.03 174.15,58.42 v2(174.15,57.41) ; v2(157.46,144.71) 157.85,144.32 GPU1.AD19 GPU1.AD18 ; CPU1.H17 127.56,90.8 127.26,90.8 CPU1.G18 ; 157.48,138.95 157.48,138.96 GPU1.AD13 ; 157.48,138.95 v2(157.46,138.95) ; 157.48,138.95 157.48,138.9 GPU1.AD12 ; v2(99.37,21.56) 99.19,21.56 98.15,22.6 DM2.11 ; GPU1.AC22 GPU1.AD22 v2(157.45,146.37) GPU1.AD21 ; U3801.1 183.58,69.7 C2147.2 ; v2(123.44,84.98) 123.49,84.98 123.73,85.22 CPU1.V23 124.41,84.81 CPU1.W22 ; v2(132.21,90.19) 131.98,90.19 CPU1.J10 ; v2(157.45,141.43) 157.82,141.81 GPU1.AD16 ; CPU1.K12 130.19,89.38 CPU1.L13 ; CPU1.AC61 99.49,82.92 v2(99.49,83.04) ; DM2.38 106.25,19.8 105.64,20.41 v2(105.01,20.41) ; U3402.8 U3402.3 17.93,39.68 v2(17.83,39.78) ; GPU1.L5 168.65,132.67 v2(169.05,132.27) ; CPU1.AD3 135.81,81.9 136.13,81.58 v2(136.13,81.49) ; CPU1.AE58 101.74,80.96 v2(101.45,80.67) 101.39,80.67 101.2,80.48 CPU1.AG60 ; v2(127.41,81.54) 126.99,81.12 CPU1.AF18 ; GPU1.H5 171.13,132.67 v2(171.53,132.27) ; v2(142.75,21.66) 142.85,21.66 143.26,22.08 143.26,22.52 142.98,22.8 142.98,23.53 142.55,23.96 DM2.151 ; CPU1.AH34 116.69,79.85 116.07,80.47 v2(116.01,80.47) ; CPU1.AV14 129.22,73.76 v2(128.87,74.11) ; GPU1.AC5 158.69,132.72 v2(158.26,133.14) ; v2(154.25,18.32) 154.25,18.31 DM2.190 ; v2(194.48,140.78) 194.4,140.7 VRAM5.T9 ; v2(161.19,48.59) 161.62,49.02 WLAN1.57 ; CPU1.L15 CPU1.L17 ; CPU1.AH32 v2(117.99,80.37) ; v2(157.45,140.59) 157.85,140.99 GPU1.AD15 ; v2(161.53,43.87) 161.53,44.13 161.92,44.52 WLAN1.75 ; v2(103.17,35.44) 103.05,35.44 102.64,35.85 102.64,38.16 DM1.133 ; CPU1.AH22 124.51,79.82 v2(124.85,79.48) 125.16,79.79 CPU1.AG21 125.42,79.96 CPU1.AH20 ; CPU1.F58 101.59,91.81 101.59,91.23 ; v2(130.21,116.01) 130.43,115.79 THM26.5 ; CPU1.D63 98.16,93.11 97.9,93.37 97.53,93.37 96.61,94.28 v2(96.61,94.31) ; GPU1.AE11 157.05,137.67 ; 157.05,137.67 v2(157.45,137.27) ; 157.05,137.67 v2(156.65,137.27) 156.25,137.67 GPU1.AF11 ; RN1803.2 112.68,100.6 112.44,100.84 v2(112.3,100.84) 112.25,100.84 112.03,100.63 RN1803.1 ; v2(164.9,53.52) 164.9,53.52 WLAN1.39 ; v2(176.45,133.12) 176.05,132.73 GPU1.B5 ; CPU1.J22 125.08,89.12 v2(125.08,88.98) ; v2(174.02,132.3) 173.6,132.72 GPU1.E5 ; CPU1.U61 99.78,85.62 99.49,85.9 v2(99.49,86.03) ; v2(165.29,47.83) 164.97,47.52 WLAN1.63 ; CPU1.AH46 108.82,79.73 108.82,79.24 ; HDD1.12 192.59,28.13 193.07,28.61 v2(193.07,28.63) ; v2(173.19,130.63) 173.24,130.63 GPU1.E2 ; GPU1.AF23 156.25,147.62 v2(155.59,147.62) ; 101.59,91.23 v2(101.57,91.23) ; 101.59,91.23 101.6,91.23 101.85,90.98 CPU1.H57 ; CPU1.N3 135.97,87.74 135.97,87.64 v2(136.11,87.49) ; DM2.133 137.15,23.74 137.21,23.67 137.21,23 138.61,21.6 138.69,21.6 v2(138.71,21.57) ; WLAN1.69 164.59,46.02 v2(165.01,46.44) ; CPU1.M22 125.02,88.07 CPU1.N21 ; PU4401.14 110.36,164.44 110.4,164.47 v2(110.4,164.65) ; v2(160.77,132.27) 161.17,132.67 GPU1.Y5 ; v2(134.69,94.49) 135.13,94.49 CPU1.B4 ; v2(116.01,80.47) 116.04,80.44 CPU1.AJ35 ; v2(116.01,80.47) 115.98,80.45 v2(115.35,80.45) 115.35,79.84 CPU1.AH36 ; 134.12,91.63 134.51,91.24 CPU1.G5 ; v2(166.56,133.06) 166.37,132.87 166.35,132.87 GPU1.P5 ; v2(128.81,95.86) 128.81,95.36 CPU1.A14 ; v2(100.62,75.55) 100.21,75.55 CPU1.AT61 ; GPU1.B1 GPU1.A2 v2(177.61,130.27) ; v2(165.76,129.83) 165.76,129.85 166.15,130.24 GPU1.P2 ; v2(156.65,133.14) 156.25,132.74 GPU1.AF5 ; v2(133.78,76.68) 133.7,76.68 CPU1.AN7 ; v2(159.07,144.73) 159.47,145.13 GPU1.AB20 ; v2(193.1,30.22) 192.78,30.22 192.18,29.63 HDD1.9 ; CPU1.B56 102.67,94.11 CPU1.C57 ; v2(128.28,81.51) 128.28,81.31 ; 128.28,81.31 128.62,80.97 CPU1.AF15 ; 128.28,81.31 128.28,81.28 CPU1.AF17 ; GPU1.AE14 157.05,140.19 v2(156.65,140.59) 156.25,140.19 GPU1.AF14 ; CPU1.AG23 122.85,80.34 ; v2(169.05,130.67) 168.65,130.27 GPU1.L2 ; v2(159.07,140.59) GPU1.AB14 ; v2(126.55,86.06) 126.4,85.91 126.22,85.91 125.94,85.63 CPU1.U20 ; CPU1.AA58 101.45,83.75 CPU1.Y59 ; v2(172.13,156.97) 172.22,156.97 172.74,156.45 173.91,156.45 174.18,156.73 v2(174.3,156.73) ; GPU1.L23 v2(169.05,147.25) ; RN7506.3 188.46,168.7 188.09,169.07 v2(187.45,169.07) 187.02,168.64 RN7520.4 ; DM2.9 97.55,23.48 v2(97.54,23.47) ; CPU1.AU16 CPU1.AV16 CPU1.AW16 127.93,73.39 CPU1.AY16 ; v2(99.04,18.32) 99.05,18.31 DM2.14 ; CPU1.D23 124.37,92.66 CPU1.D21 ; v2(114.69,18.3) 114.65,18.26 DM2.66 ; CPU1.C18 126.61,93.7 CPU1.D18 127.01,93.3 CPU1.E17 ; v2(128.47,75.53) 128.61,75.38 CPU1.AR15 129.3,75.06 129.53,75.06 CPU1.AT13 129.84,75.06 v2(130.5,75.71) ; v2(160.99,52.38) 160.99,52.33 161.45,51.87 161.45,50.71 161.64,50.52 WLAN1.51 ; v2(123.99,77.85) 124.09,77.85 CPU1.AL22 ; v2(161.32,56.62) 161.32,55.63 161.93,55.02 WLAN1.33 ; DM2.196 156.05,18.26 ; v2(189.2,148.91) 188.8,148.51
  BOTTOM w0.33: DM2.46 108.65,19.15 108.2,19.59 v2(108.03,19.59) ; DM2.54 111.05,18.62 111.39,18.96 v2(111.66,18.96) ; DM1.173 114.65,36.54 115.02,36.16 115.16,36.16 v2(115.25,36.07) ; v2(99.04,20.23) 98.24,20.23 97.25,19.23 DM2.8 ; v2(136.9,18.96) 137.45,18.41 DM2.134 ; DM1.138 v2(104.15,31.43) ; DM1.63 79.25,35.87 78.19,34.8 v2(78.05,34.8) ; DM2.178 150.65,18.57 151.04,18.96 v2(151.41,18.96) ; v2(155.29,22.26) 155.14,22.26 153.95,23.45 DM2.189 ; v2(67.55,32.07) 67.69,32.07 68.15,31.6 DM1.26 ; DM1.19 66.05,36.4 66.38,36.07 v2(66.63,36.07) ; v2(139.2,18.94) 139.18,18.94 138.05,17.8 DM2.136 ; v2(105.65,35.87) 106.02,35.87 106.25,36.1 DM1.145 ; DM2.3 95.75,23.39 v2(95.11,22.75) ; v2(74.25,35.44) 74.38,35.44 75.05,36.11 DM1.49 ; DM1.179 116.45,35.86 117.5,34.8 v2(117.65,34.8) ; v2(106.55,21.56) 106.95,21.56 107.75,22.36 DM2.43 ; DM1.20 66.35,31.66 65.94,32.07 v2(65.75,32.07) ; v2(117.65,36.07) 117.79,36.07 118.25,36.54 DM1.185 ; v2(120.57,36.07) 120.71,36.07 121.25,36.61 DM1.195 ; v2(140.87,22.2) 140.96,22.28 141.1,22.28 141.42,22.6 141.42,23.06 140.75,23.72 DM2.145 ; DM1.3 61.25,36.4 60.63,35.79 60.1,35.79 v2(60.06,35.74) ; v2(105.05,18.96) 104.86,18.96 104.45,18.54 DM2.32 ; v2(63.95,32.7) 64.09,32.7 64.55,32.24 DM1.14 ; v2(72.95,33.34) 73.13,33.34 74.15,32.31 DM1.46 ; v2(67.55,33.34) 67.69,33.34 68.75,32.27 DM1.28 ; v2(107.45,36) 107.59,36 108.05,36.46 DM1.151 ; DM1.44 73.55,31.65 73.14,32.07 v2(72.95,32.07) ; DM1.55 76.85,36.54 76.39,36.07 v2(76.25,36.07) ; v2(81.57,36.71) 81.65,36.79 DM1.71 ; v2(107.45,34.73) 107.59,34.73 108.65,35.79 DM1.153 ; DM1.178 116.15,31.8 116.41,32.07 v2(116.75,32.07) ; v2(116.52,22.72) 116.15,23.09 DM2.71 ; DM1.150 107.75,32.26 108.2,32.7 108.32,32.7 v2(108.41,32.8) ; v2(152.71,18.32) 152.45,18.07 DM2.184 ; v2(102.4,33.36) 102.38,33.34 102.21,33.34 101.15,32.27 DM1.128 ; DM1.162 111.35,31.6 110.89,32.07 v2(110.75,32.07) ; DM1.172 114.35,31.63 114.79,32.07 v2(114.95,32.07) ; v2(105.62,34.42) 105.55,34.5 105.54,34.5 104.45,35.59 DM1.139 ; DM2.20 100.85,18.31 v2(100.84,18.32) ; CPU1.AH49 107.59,79.9 v2(108.14,80.45) ; v2(75.35,32.07) 75.07,32.07 74.75,31.75 DM1.48 ; DM2.37 105.95,23.22 106.34,22.83 v2(106.55,22.83) ; DM1.167 112.85,36.13 113.45,35.53 113.5,35.53 v2(113.58,35.45) ; DM1.161 v2(111.05,36.71) ; DM1.156 109.55,32.78 110.1,33.34 v2(110.75,33.34) ; v2(70.55,33.34) 70.9,33.34 71.75,32.49 DM1.38 ; DM1.190 v2(119.75,32.29) ; DM1.60 78.35,32.28 77.29,33.34 v2(77.15,33.34) ; v2(108.03,18.32) 108.05,18.3 DM2.44 ; DM1.8 62.75,32.28 62.34,32.69 v2(62.34,32.71) ; v2(72.05,34.8) 72.14,34.89 72.29,34.89 73.25,35.86 DM1.43 ; v2(70.25,36.07) 70.11,36.07 69.65,36.54 DM1.31 ; DM1.184 117.95,31.42 v2(117.94,31.43) ; v2(109.85,18.96) 109.66,18.96 109.25,18.55 DM2.48 ; v2(144.5,22.2) 144.41,22.28 144.27,22.28 143.9,22.65 143.9,23.36 143.75,23.51 DM2.155 ; DM2.195 155.75,23.93 156.24,23.44 156.24,21.75 155.44,20.95 v2(155.32,20.95) ; v2(146.24,21.43) 146.22,21.45 145.89,21.45 145.55,21.79 DM2.161 ; DM2.139 138.95,23.52 139.42,23.05 139.42,22.24 140.73,20.93 v2(140.87,20.93) ; v2(102.67,19.59) 102.77,19.59 103.25,19.12 103.25,17.72 103.25,17.71 DM2.28 ; DM2.170 148.25,19.31 147.97,19.6 v2(147.65,19.6) ; v2(78.05,36.07) 78.19,36.07 78.65,36.54 DM1.61 ; DM1.72 81.95,31.6 81.58,31.98 81.44,31.98 v2(81.35,32.07) ; v2(111.25,22.93) 111.35,23.03 DM2.55 ; DM1.196 121.55,33.04 v2(121.34,33.24) ; DM1.37 71.45,36.54 71.91,36.07 v2(72.05,36.07) ; DM2.187 153.35,23.05 v2(153.5,22.9) 153.45,22.9 152.75,23.6 DM2.185 ; v2(103.58,22.2) 102.81,22.2 102.35,22.66 DM2.25 ; v2(80.45,36.07) 80.31,36.07 79.85,36.54 DM1.65 ; v2(151.41,20.23) 151.41,22.94 150.95,23.41 DM2.179 ; DM2.19 100.55,23.14 100.86,22.83 v2(101.15,22.83) ; v2(61.55,32.07) 61.32,32.07 60.95,31.7 DM1.2 ; v2(119.45,35.44) 119.31,35.44 118.85,35.9 DM1.187 ; DM1.66 80.15,29.97 80.15,31.76 79.21,32.7 v2(78.95,32.7) ; v2(116.63,18.27) 116.45,18.09 DM2.72 ; DM1.9 v2(63.05,36.71) ; v2(150.4,21.32) 150.29,21.32 149.15,22.46 DM2.173 ; DM2.26 102.65,17.94 102.67,17.96 v2(102.67,18.32) ; DM1.155 v2(109.25,36.71) ; DM1.13 64.25,36.54 64.71,36.07 v2(64.85,36.07) ; DM2.63 113.75,23.71 113.93,23.53 113.93,22.16 113.48,21.7 v2(113.32,21.7) ; DM2.2 95.45,18.75 95.66,18.96 v2(96.05,18.96) ; DM2.60 112.85,19.35 111.97,20.23 v2(111.66,20.23) ; v2(102.4,32.09) 102.56,32.09 102.95,31.7 DM1.134 ; v2(113.15,32.95) 113.33,32.95 113.75,32.53 DM1.170 ; v2(136.89,20.26) 136.74,20.26 135.64,19.16 135.64,16.77 DM2.128 ; v2(149.47,18.96) 149.08,18.96 148.85,18.73 DM2.172 ; DM2.61 113.15,23.96 113.05,23.86 113.05,23.27 v2(113.34,22.98) ; DM1.168 v2(113.15,31.68) ; DM1.144 105.95,31.69 106.33,32.07 106.52,32.07 v2(106.56,32.11) ; v2(136.25,22.2) 136.02,22.2 135.35,22.87 DM2.127 ; v2(64.85,34.8) 64.47,34.8 63.65,35.63 DM1.11 ; DM2.13 98.75,23.24 99.15,22.83 v2(99.37,22.83) ; v2(69.35,32.07) 69.49,32.07 69.95,31.61 DM1.32 ; DM1.54 76.55,31.66 76.95,32.07 v2(77.15,32.07) ; CPU1.AH51 106.3,79.8 106.3,79.99 v2(106.72,80.41) ; 156.05,18.26 v2(155.98,18.32) ; DM1.127 100.85,36.53 101.36,36.02 v2(101.42,36.02) ; DM1.25 67.85,36.28 68.69,35.44 v2(68.82,35.44) ; DM1.136 103.55,32.24 104.01,32.7 v2(104.15,32.7) ; DM1.189 v2(119.45,36.71)
  BOTTOM w0.356: v2(187.19,140.73) 187.2,140.72 VRAM5.G9 v2(186.8,139.72) ; VRAM3.A9 VRAM7.B1 176.54,157.17 176.83,157.46 v2(176.99,157.46) ; VRAM1.B3 183.2,138.53 v2(183.6,138.93) ; VRAM3.B3 171.93,157.17 v2(172.13,156.97) ; VRAM5.E2 v2(185.2,134.12) VRAM1.D8 ; VRAM6.M1 191.2,147.08 v2(191.19,147.07) ; VRAM5.J2 v2(189.2,134.92) ; VRAM4.G8 162,160.77 v2(162.04,160.77) ; VRAM6.P9 v2(192.8,154.79) ; GPU1.E8 174.02,134.84 v2(174.02,134.8) ; VRAM5.T1 v2(194.4,133.16) ; VRAM7.J8 170.8,162.78 v2(170.4,163.17) ; GPU1.AA7 160.19,134.21 159.65,134.21 GPU1.AB7 ; v2(168.96,168.59) 169.48,168.59 169.7,168.37 VRAM7.T9 ; v2(191,165.59) 191.22,165.36 RN7502.3 ; v2(169.06,157.21) 169.09,157.21 169.13,157.17 VRAM7.B9 ; v2(169.03,148.87) 169.03,148.87 GPU1.L25 ; v2(191.99,168.19) 191.98,168.2 RN7501.4 ; VRAM3.D1 170,158.78 v2(170.4,159.18) 170,159.57 VRAM3.E1 ; GPU1.AE17 GPU1.AF17 156.25,142.6 v2(155.84,142.2) ; v2(176.94,161.33) 176.78,161.17 VRAM7.G1 176.01,160.78 176.01,160.76 ; v2(176.89,135.03) 176.28,135.03 176.1,135.21 GPU1.B8 ; VRAM6.P1 192.8,147.24 192.88,147.16 v2(192.88,147.15) ; v2(183.38,154.74) 183.2,154.56 VRAM6.B9 ; VRAM8.B9 155.59,156.76 v2(155.5,156.76) ; VRAM1.E1 v2(185.6,140.73) ; VRAM1.E1 VRAM5.E8 185.6,139.32 v2(185.2,138.92) ; VRAM1.E1 VRAM1.D1 ; v2(176.49,144.73) 176.45,144.73 GPU1.B20 ; VRAM1.G8 v2(186.8,134.12) ; v2(186.8,134.12) VRAM5.G1 ; v2(186.8,134.12) VRAM1.F9 ; v2(164.1,133.07) 163.7,132.67 GPU1.U5 ; VRAM7.M1 176.95,165.17 177.67,165.9 v2(177.67,165.96) ; v2(131.02,86.82) 131.02,87.03 131.64,87.65 CPU1.N10 ; VRAM3.G8 176.01,160.76 176.01,160.76 ; v2(163.24,129.87) 163.35,129.98 163.38,129.98 GPU1.U2 ; v2(174.01,149.68) 174.01,149.68 GPU1.E25 ; v2(191.11,154.84) 191.11,154.2 VRAM6.M9 ; VRAM2.E1 v2(185.2,153.71) VRAM2.D1 ; VRAM6.E2 v2(185.2,148.11) VRAM2.D8 ; v2(171.2,159.19) 171.18,159.19 170.81,159.57 VRAM7.E8 ; v2(175.2,158.37) 175.21,158.38 175.21,158.38 VRAM3.D8 VRAM7.E2 VRAM3.F9 176.4,160.37 176.01,160.76 ; VRAM6.T9 194.51,154.22 v2(194.51,154.8) ; v2(155.27,166.77) 155.28,166.77 VRAM8.P9 ; VRAM7.J2 175.23,163.14 v2(175.23,163.17) ; v2(159.08,138.11) 159.49,137.7 GPU1.AB11 ; v2(158.3,129.82) 158.3,129.83 158.7,130.23 GPU1.AC2 ; VRAM6.T1 194.58,147.71 v2(194.95,148.08) ; GPU1.AF1 155.45,129.47 ; 155.45,129.47 GPU1.AG2 ; 155.45,129.47 v2(155.3,129.32) ; EU5602.8 v2(186.78,33.63) ; GPU1.E17 173.62,142.65 v2(173.24,142.27) ; VRAM8.T1 162.8,168.77 v2(162.82,168.77) ; 169.43,161.17 VRAM7.G9 ; VRAM5.J8 188.8,139.32 v2(189.19,138.92) ; v2(162.99,166.59) 162.81,166.77 VRAM8.P1 ; v2(183.19,140.8) 183.2,140.78 VRAM5.B9 ; VRAM7.M9 169.73,165.17 169.66,165.1 v2(169.23,165.1) ; v2(175.66,142.24) 176.05,142.63 GPU1.B17 ; VRAM4.D8 v2(162,159.17) VRAM8.E2 ; v2(174.05,145.53) 173.86,145.34 173.86,145.34 GPU1.E20 ; CPU1.R8 CPU1.R10 ; VRAM5.P9 192.8,140.6 v2(192.93,140.73) ; v2(161.59,129.87) GPU1.Y2 ; v2(192.08,163.08) 191.59,162.6 RN7510.3 ; v2(171.53,149.66) 171.5,149.66 GPU1.H25 ; GPU1.E22 173.2,147.22 v2(173.12,147.22) ; VRAM8.G9 156.01,161.17 v2(156.39,161.56) ; 188.8,148.51 VRAM6.J2 ; DM2.144 140.45,15.33 v2(140.45,15.33) ; v2(159.14,148.85) 159.52,148.47 GPU1.AB24 ; v2(174.05,137.29) GPU1.E11 ; v2(163.25,147.25) GPU1.U23 ; v2(165.74,147.26) GPU1.P23 ; GPU1.A26 177.17,150.39 177.17,151.07 v2(177.14,151.11) 177.06,151.19 176.37,151.19 GPU1.B27 ; v2(156.4,162.37) 156.8,162.77 VRAM8.J8 ; v2(154.52,150.07) 154.57,150.07 154.57,150.07 GPU1.AG26 ; v2(160.76,148.06) 160.8,148.06 GPU1.Y23 ; v2(155.4,158.85) 155.48,158.77 VRAM4.D1 ; v2(162,157.57) 162.4,157.17 VRAM8.B1 ; VRAM8.E8 v2(156.4,159.97) VRAM4.E1 ; VRAM7.P9 169.99,166.76 168.85,166.76 v2(168.62,166.99) ; v2(187.35,154.73) 187.35,154.26 VRAM6.G9 187.2,154.1 186.89,153.79 ; VRAM8.G1 162.45,161.17 v2(162.83,160.79) 162.41,160.37 VRAM4.F9 ; 127.84,88.91 CPU1.L17 ; v2(183.6,152.91) 183.2,152.51 VRAM2.B3 ; DM2.138 v2(138.65,15.28) ; VRAM4.A9 162.4,156.37 v2(162,155.97) ; v2(180.73,160.92) 181.73,160.92 182.38,161.58 R7508.2 ; v2(187.06,147.17) 187.06,147.2 187.2,147.35 VRAM6.G1 ; VRAM2.G8 v2(186.8,148.11) VRAM2.F9 ; v2(159.07,142.23) GPU1.AB17 ; v2(182.27,133.06) 182.4,133.19 VRAM1.A9 ; VRAM5.M9 191.2,140.74 191.16,140.78 v2(191.16,140.85) ; v2(171.51,148.06) 171.5,148.06 171.11,147.67 GPU1.H23 ; VRAM8.M9 155.29,165.17 v2(155.25,165.2) ; VRAM8.T9 155.55,168.37 v2(155.43,168.49) ; v2(163,165.03) 163,165.03 162.86,165.17 VRAM8.M1 ; v2(183.27,133.09) 183.2,133.15 VRAM5.B1 ; v2(161.2,163.17) VRAM8.J2 ; U7301.3 150.4,123.86 150.65,124.11 v2(150.65,124.21) ; U3504.2 24.37,45.34 v2(23.97,45.75) ; VRAM5.P1 v2(192.8,133.12)
  BOTTOM w0.381: v2(35.73,174.12) EU3102.8 EU3102.3
  BOTTOM w0.4: v2(158.65,158.23) 158.65,158.22 VRAM4.B3 ; VRAM7.T1 176.96,168.37 177.02,168.43 v2(177.03,168.43) ; VRAM2.A9 182.4,147.11 v2(182.39,147.11) 182.6,147.11 VRAM6.B1 ; v2(189.21,152.91) 189.18,152.94 189.17,152.94 VRAM6.J8 ; VRAM7.P1 176.91,166.77 v2(177.01,166.66)
  BOTTOM w0.406: EC2502.2 157.75,51.17 v3(158.6,52.02) ; v3(152.61,45.68) 152.74,45.56 Q1701.1
  BOTTOM w0.508: v2(169.32,40.85) C5803.2 ; PC5102.2 149.52,99.96 v2(149.5,99.98) ; v2(166.22,67.04) 165.96,66.77 EC5802.2 ; EC702.2 R712.2 95.24,97.78 v2(95.39,97.63) ; v2(165.05,69.14) 165.05,69 164.66,68.61 161.3,68.61 160.28,69.63 C3802.2 ; v2(186.29,128.91) 185.9,129.31 X7601.2 ; EC9711.2 100.44,135.34 v2(99.61,136.17) ; v2(184.28,38.28) 184.14,38.42 C3406.2 ; R7647.2 174.21,124.27 R7622.2 174.22,124.47 173.86,124.83 R7621.2 173.27,125.09 v2(173.2,125.02) ; C1802.1 125.15,107.57 125.29,107.71 v2(125.7,107.71) ; C2147.2 185.78,71.01 C3801.2 185.8,70.35 v2(185.88,70.26) ; C5604.2 195.66,38.03 v2(195.41,38.28) ; v2(144.96,138.51) 145.02,138.45 C8303.2 ; v2(40.01,174.66) 39.99,174.66 39.99,174.65 EC3107.1 ; v2(20.93,78.63) 20.93,78.79 20.65,79.07 R5410.2 ; v2(152.18,74.05) 152.59,73.63 C1108.2 ; EC9742.2 157.25,117.9 v2(157.22,117.93) ; v2(158.41,104.64) PC8226.1 158.4,103.85 PC8203.1 ; PU5101.2 147.21,101.59 v2(147.05,101.76) ; v2(44.42,57.14) 43.55,57.14 43.01,57.68 PC4534.2 ; v2(184.77,7.14) 185.15,7.52 185.15,7.94 EC2703.2 185.16,8.96 C2706.2 185.47,9.26 C2709.2 ; PC8202.1 PC8205.2 156.98,111.52 v2(157.01,111.55) ; C1903.1 149.73,68.9 v2(149.72,68.91) ; EC9747.2 121.14,145.08 120.43,144.37 v2(120.43,143.84) 120.51,143.77 PC4606.2 ; R7601.2 193.34,129.85 R7808.1 193.47,130.17 v2(194.01,130.71) ; v2(187.56,35.89) C5605.2 188.64,35.79 C5606.2 ; R7627.2 195.96,128.58 195.48,128.09 v3(195.48,127.72) 195.06,127.3 R7620.2 ; PC5119.2 148.18,105.33 147.76,105.74 v2(147.76,105.77) ; v2(130.8,109.16) 131.02,109.16 131.6,109.74 C2608.2 ; EC9755.2 177.57,121.52 v2(178.7,120.4) 179.3,119.8 EC9756.2 ; v2(168.42,64.89) 168.42,65.58 EC5801.2 ; PR4622.2 v2(124.44,127.16) ; v2(156.97,113.96) 156.99,113.94 PR8213.2 PC8217.2 ; v2(92.49,92.84) 92.94,92.39 R901.2 ; v2(150.66,65.15) 149.94,65.15 C1904.1 ; FAN1.5 94.29,141.59 v2(95.49,142.78) ; C7609.2 190.19,127.69 v3(190.76,128.26) 190.4,128.62 190.4,129 R7642.2 R7655.2 189.44,129.02 R7610.2 ; PC4904.2 60.94,24.57 v3(62.16,25.78) ; v2(112.9,156.05) 112.4,155.56 PR4436.2 ; v2(51.04,60.63) 51.04,60.3 50.68,59.95 PC4533.2 ; v2(59.29,14.63) 59.16,14.77 RTC1.2 ; EU3404.2 187.93,39.42 v2(187.88,39.37) ; C2409.2 178.49,75.65 v2(178.58,75.74) ; R7809.1 187.81,143.86 C8019.2 187.82,143.36 v2(188.09,143.08) ; C7607.1 181.08,130.24 180.88,130.45 v2(180.88,130.84) ; v2(138.89,155.22) 138.95,155.22 138.95,155.21 138.86,155.12 138.72,155.12 138.65,155.06 EC9714.2 ; C7803.2 R7807.2 198.76,132.23 v2(198.75,132.23) ; C2105.2 138.19,106.45 138.18,106.46 v3(138.18,106.56) ; EC2704.2 189.45,13.07 v2(189.34,13.19) 189.51,13.35 C2704.1 ; R1920.1 89.25,80.9 v2(89.19,80.97) ; C2415.1 187.97,72.47 v2(187.91,72.4) ; R7306.2 152.56,122.2 v2(153.02,122.66) ; v2(28.24,48.23) 28.22,48.21 28.15,48.21 28.09,48.15 26.79,48.15 26.35,48.59 U5504.4 ; C2602.2 v2(123.74,112.51) ; v2(195.7,35.6) 195.3,36.01 HDD1.13 ; v2(111.67,158.53) 111.67,158.25 111.11,157.69 PR4432.2 ; EC1702.2 R1717.2 171.49,82.27 v2(171.76,82) ; R1515.2 145.82,90.1 145.82,90.63 v2(145.84,90.65) ; C7524.2 166.24,161.04 166.39,161.04 167.16,161.81 v2(167.16,162.18) 166.57,162.78 R7913.1 166.22,163.49 R7511.2 ; v2(148.87,76.56) 148.87,76.19 148.57,75.89 R2035.1 ; v2(80.74,156.13) 80.5,155.89 R5202.1 80.56,154.97 U5201.2 ; v2(191.99,84.05) 192.22,84.05 C2410.2 193.41,84.56 EC9751.2 ; v2(132.41,113.16) 132.41,112.38 C2609.2 ; U5504.1 30.16,49.99 v2(29.5,50.65) 28.89,50.04 U5504.2 ; EC701.2 R709.2 97.13,98.31 v2(96.93,98.11) ; v2(144.48,107.67) 144.76,107.67 144.81,107.62 C2142.2 ; v2(169.38,161.07) 169.38,161.12 169.43,161.17 ; EC1701.1 151.24,84.55 v2(151.86,84.55) ; PR8224.2 165.16,107.16 v2(165.31,107.01) ; C2135.2 145.2,115.67 v2(145.57,115.3) 145.57,115.03 144.99,114.45 C2141.2 ; PC4824.2 v2(142.46,116.55) ; EC1703.2 R1715.2 149.42,93.93 C1701.2 149.03,94.82 v2(148.57,95.28) ; v2(146.29,84.74) 146.28,84.74 R2008.2 ; v2(162.04,120.86) 162.38,121.21 EC9757.2 ; v2(121.47,106.99) 121.47,107.29 121.75,107.57 C1801.1 ; C2707.2 179.71,11.98 179.71,11.99 179.46,12.25 179.2,12.25 v2(179.15,12.3) 178.8,11.95 C2708.2 ; v2(91.07,157.76) 91.07,156.75 PQ4204.E ; FAN1.4 89.29,139.07 v2(89.97,138.39) ; v2(154.69,85.55) 154.44,85.81 153.93,85.81 153.55,86.19 C2110.2 ; PC4517.2 30.95,27.6 v2(30.95,28.39) ; v2(159.61,111.77) 159.66,111.82 PC8222.2 ; v2(128.87,63.05) 129.11,63.29 R602.2 131.11,63.29 R2003.2 131.14,62.91 131.07,62.85 131.07,62.6 EU401.2 ; v3(114.74,163.94) 115.45,163.22 PC4407.2 ; v2(174.78,11.84) 175.34,12.4 EC2701.2 ; PC4526.2 40.65,60.57 v2(40.97,60.9) ; v2(162.92,103.03) 162.53,102.63 PC8225.1 ; 5.27,49.11 USB1.12 ; PC5120.2 145.46,104.48 144.65,105.29 v2(144.17,105.29) ; EC9709.2 34.62,55.49 v2(34.64,55.5) ; PC4425.2 114.32,154.58 v2(114.38,154.51) 114.38,154.18 113.92,153.72 EC9702.2 ; v2(73.44,3.89) 72.91,4.42 SPK1.6 ; EC9710.2 124.58,145.96 v2(124.65,146.03) ; EC401.2 92.44,97.79 91.78,97.79 v2(91.47,97.49) 92.07,96.89 R405.2 ; v2(167.27,159.36) 167.13,159.22 C7929.2 ; v2(66.96,8.89) 66.96,9.39 67.59,10.02 SPK1.5 ; R5209.2 74.68,164.98 v2(75.09,164.57) 75.79,164.57 R5201.2 ; PD4501.A 50.15,56.29 49.71,56.72 v2(49.09,56.72) ; U5504.7 28.89,55.35 v2(29.32,55.78) ; 8.32,180.74 7.88,180.3 RJ45.10 4.81,180.3 4.33,180.77 ; R7654.2 177.31,125.34 R7632.2 177.3,124.61 v2(177.21,124.52) ; v2(31.78,76.99) 31.2,77.58 R5412.2 ; C2718.2 174.49,17.7 v2(174.35,17.56) ; PC8207.2 v2(166.07,108.25) ; EC9736.2 58.72,66.8 v2(58.73,66.81) ; v2(190.97,69.29) 191.28,68.99 191.28,68.71 C2412.2 191.35,68.12 C2413.2 ; C2421.2 175.97,74.77 175.89,74.85 175.26,74.85 v2(175.03,74.63) 173.22,72.82 Q2401.S ; v2(169.81,66.81) 169.81,66.81 169.95,66.66 170.08,66.66 170.17,66.58 C5804.2 ; v2(177.9,24.81) 177.35,24.81 C2716.2 177.92,26.1 EC9743.2 ; C8017.2 184.37,143.86 C8001.2 184.41,143.89 184.41,144.44 v2(184.54,144.57) ; C7608.1 181.4,126.9 v2(181.75,126.9) 181.85,126.9 182.71,127.76 X7601.4 ; PR8259.2 v2(159.37,101.45) ; 147.35,179.77 BATT1.10 150.07,179.77 ; v2(29.06,177.32) 29.06,177.32 29.06,177.32 C3101.2 ; EC9740.2 110.19,140 v2(110.19,138.52) ; PC4518.2 v2(49.55,27.45) ; 4.57,161.64 RJ45.9 8.37,161.64 8.75,161.26 ; DB1.11 179.48,31.78 v2(180.07,31.78) ; R2442.2 178.21,72 v2(178.39,72.18) ; C3303.2 v2(19.92,14.18) ; v2(191.24,159.41) 191.8,158.85 C7831.2 ; EC9707.2 v2(109.74,129.38) ; EC3106.1 v2(40.03,173.84) ; C5601.2 192.87,37.43 192.87,36.83 v2(192.74,36.71) ; v2(165.52,156.64) 165.53,156.63 C8104.2 ; 5.27,30.85 USB1.13 ; PC4515.2 v2(49,53.9)
  BOTTOM w0.635: 10.25,76.96 HDMI1.PTH2 8.87,75.97 ; 5.5,75.28 HDMI1.PTH4 ; HDMI1.PTH4 5.35,76.02 HDMI1.PTH6 2.25,76.03 v2(3.42,77.2) ; HDMI1.PTH4 7.24,76.17 ; 13.25,2.88 CARD1.14 ; CARD1.14 13.25,4.56 ; CARD1.14 11.07,3.72 ; CARD1.14 15.43,3.72 ; 152.39,157.37 HGPU1.1 149.2,154.18 ; CARD1.15 15.43,30.02 ; CARD1.15 13.25,30.86 ; CARD1.15 11.07,30.02 ; CARD1.15 13.25,29.18 ; BATT1.8 152.05,180.76 ; BATT1.8 153.04,179.77 ; BATT1.8 151.06,179.77 ; HDMI1.PTH1 13.5,77.06 ; HDMI1.PTH1 13.5,75.28 ; HDMI1.PTH1 15.24,76.17 ; 199.02,117.78 200.9,115.9 HGPU2.1 ; HDMI1.PTH7 15.24,54.27 ; HDMI1.PTH7 13.5,53.38 ; HDMI1.PTH7 13.5,55.16 ; 200.5,161.86 HGPU3.1 200.5,155.48 ; HDMI1.PTH12 5.35,54.42 HDMI1.PTH10 ; 13.72,47.26 USB1.10 15.4,46.37 ; 154.05,180.76 BATT1.7 153.06,179.77 ; 10.6,71.48 HDMI1.PTH3 12.04,72.47 ; 10.6,58.96 HDMI1.PTH8 12.04,57.97 ; 13.72,32.68 USB1.11 ; USB1.11 13.72,34.46 ; USB1.11 15.4,33.57 ; HDMI1.PTH10 7.24,54.27 ; HDMI1.PTH10 5.5,53.38 ; HDMI1.PTH10 5.5,55.16 ; HDMI1.PTH5 6,74.37 ; HDMI1.PTH11 6.18,56.07 ; 8.87,54.47 HDMI1.PTH9 10.25,53.48 ; HGPU2.1 200.9,113.75 197.7,110.55 ; HGPU2.1 197.53,114.27 ; 169.17,177.84 BATT1.9 170.22,179.77 ; 14.47,35.76 USB1.4 15.18,36.47
  vias: v1(17.69,11.92) v1(23.15,34.52) v1(23.68,40.16) v1(32.49,74.15) v1(38.87,70.44) v1(39.63,78.59) v1(41.99,65.94) v1(48.45,71.51) v1(61.91,36.99) v1(63.18,76.31) v1(64.75,40.95) v1(87.51,83.27) v1(100.26,14.63) v1(103.55,176.7) v1(105.82,158.91) v1(110.1,174) v1(111.09,177.26) v1(112.22,15.19) v1(116.54,162.36) v1(120.3,128.35) v1(120.5,117.28) v1(121.19,133.27) v1(121.99,135.69) v1(123.93,132.74) v1(144.08,26.45) v1(153.4,33.86) v1(156.9,30.21) v1(165.16,24.01) v1(166.25,104.76) v1(170.9,26.47) v1(171.61,31.68) v1(176.31,26.09) v1(179.43,30.08) v1(192.8,117.24) v1(198.28,172.72) v2(3.42,80.87) v2(4.54,51.98) v2(4.54,50.45) v2(5.29,82.05) v2(6.82,82.05) v2(6.9,74.46) v2(8.03,48.84) v2(8.34,82.05) v2(9.02,28.5) v2(9.02,26.98) v2(9.02,25.45) v2(9.02,23.93) v2(9.02,22.41) v2(9.02,20.88) v2(9.02,19.36) v2(9.02,17.83) v2(9.02,16.31) v2(9.02,14.79) v2(9.02,13.26) v2(9.02,11.74) v2(9.02,10.21) v2(9.02,8.69) v2(9.02,7.17) v2(9.02,5.64) v2(9.02,4.12) v2(9.02,2.59) v2(9.65,180.95) v2(9.55,48.84) v2(9.86,82.05) v2(10.02,27.16) v2(10.02,24.11) v2(10.02,22.58) v2(10.02,19.54) v2(10.02,18.01) v2(10.02,11.92) v2(10.02,4.3) v2(10.01,2.19) v2(10.27,20.62) v2(10.27,10.46) v2(10.27,5.38) v2(10.93,9.38) v2(11.13,161.11) v2(11.08,48.84) v2(11.17,180.95) v2(11.39,82.05) v2(11.53,2.19) v2(12.45,9.33) v2(12.7,180.95) v2(12.91,82.05) v2(13.06,2.19) v2(13.26,161.09) v2(14.08,11.21) v2(14.22,180.95) v2(14.44,82.05) v2(14.79,161.09) v2(15.15,17.6) v2(15.74,180.95) v2(15.96,82.05) v2(16.01,18.46) v2(16.01,17.6) v2(16.01,16.74) v2(16.75,34.32) v2(16.88,17.6) v2(17.25,161.1) v2(17.27,180.95) v2(17.28,1.2) v2(17.48,82.05) v2(17.53,74.38) v2(17.7,41.96) v2(17.82,41.08) v2(17.99,76.13) v2(18.23,41.58) v2(18.22,1.2) v2(18.79,180.95) v2(18.92,15.72) v2(19.01,82.05) v2(19.36,161.09) v2(19.47,60.45) v2(19.55,57.68) v2(20.15,1.2) v2(20.32,180.95) v2(20.44,63.07) v2(20.53,82.05) v2(20.63,65.05) v2(20.88,161.09) v2(21.17,63.06) v2(21.27,65.06) v2(21.84,180.95) v2(21.95,65.08) v2(21.92,63.04) v2(22.06,82.05) v2(22.24,76.43) v2(22.2,72.6) v2(22.33,161.1) v2(22.52,78.58) v2(22.62,65.07) v2(22.84,57.81) v2(22.86,60.47) v2(23.01,74.52) v2(23.02,41.36) v2(23.22,70.94) v2(23.36,180.95) v2(23.58,82.05) v2(23.56,57.81) v2(23.74,60.47) v2(23.74,41.3) v2(23.93,161.09) v2(23.98,14) v2(24.18,56.03) v2(24.89,180.95) v2(24.94,34.28) v2(25.1,82.05) v2(25.45,161.09) v2(25.51,80.24) v2(25.64,61.5) v2(25.72,38.75) v2(25.86,1.31) v2(26.12,74.63) v2(26.63,82.05) v2(26.72,180.19) v2(27.06,76.51) v2(27.41,161.1) v2(27.53,63.84) v2(28.15,82.05) v2(28.33,46.94) v2(28.4,64.7) v2(28.4,63.84) v2(28.4,62.97) v2(28.5,161.09) v2(29.09,2.19) v2(29.26,63.84) v2(29.68,82.05) v2(30.03,161.09) v2(30.61,2.19) v2(31.2,82.05) v2(31.55,161.09) v2(31.93,80.25) v2(32.14,2.19) v2(32.33,179.45) v2(32.72,82.05) v2(32.89,77.59) v2(33.66,2.19) v2(33.85,179.45) v2(34.25,82.05) v2(35.09,77.69) v2(35.19,2.19) v2(35.37,179.45) v2(35.77,82.05) v2(36.16,80.04) v2(36.71,2.19) v2(36.9,179.45) v2(37.3,82.05) v2(38.23,2.19) v2(38.42,179.45) v2(38.44,66.8) v2(38.51,65.43) v2(38.64,171.17) v2(38.65,17.94) v2(38.82,82.05) v2(39.28,17.94) v2(39.76,2.19) v2(39.95,179.45) v2(39.88,72.17) v2(39.92,17.94) v2(40.02,177.48) v2(40.01,171.91) v2(40.03,67.99) v2(40.34,82.05) v2(40.26,74.52) v2(40.9,55.14) v2(40.96,173.97) v2(41.06,177.5) v2(41.28,2.19) v2(41.47,179.45) v2(41.51,171.76) v2(41.46,169.3) v2(41.54,55.78) v2(41.54,55.14) v2(41.54,54.51) v2(41.87,82.05) v2(42.1,76.73) v2(42.17,55.14) v2(42.43,161.1) v2(42.65,70.16) v2(42.81,2.19) v2(42.91,162.63) v2(42.99,179.45) v2(43.16,169.85) v2(43.39,82.05) v2(43.74,161.09) v2(43.77,166.83) v2(43.99,70.31) v2(44.33,2.19) v2(44.52,179.45) v2(44.62,174.43) v2(44.92,82.05) v2(44.96,175.66) v2(45.24,72.44) v2(45.37,166.5) v2(45.83,174.53) v2(45.85,2.19) v2(46.04,179.45) v2(46.02,161.21) v2(46.44,82.05) v2(47.18,72.22) v2(47.38,2.19) v2(47.57,179.45) v2(48.04,168.97) v2(48,161.11) v2(47.96,82.05) v2(48.93,169.86) v2(48.93,168.97) v2(48.93,168.08) v2(48.9,2.19) v2(49.09,179.45) v2(49.54,164.58) v2(49.49,82.05) v2(49.82,168.97) v2(49.84,161.09) v2(50.43,2.19) v2(50.61,179.45) v2(50.68,165.63) v2(51.01,82.05) v2(51.36,161.09) v2(51.64,164.67) v2(51.95,2.19) v2(52.14,179.45) v2(52.36,82.05) v2(52.59,161.1) v2(53.47,2.19) v2(53.66,179.45) v2(53.9,78.63) v2(54.35,161.9) v2(55,2.19) v2(55.19,179.45) v2(55.28,82.09) v2(55.93,161.05) v2(56.06,164.85) v2(56.52,2.19) v2(56.57,177.85) v2(56.71,179.45) v2(58,177.7) v2(58.05,2.19) v2(58.23,179.45) v2(58.24,160.86) v2(58.25,82.33) v2(58.95,176.64) v2(58.91,20.98) v2(59.54,21.62) v2(59.54,20.98) v2(59.54,20.35) v2(59.57,2.19) v2(59.76,179.45) v2(59.87,82.57) v2(60.18,20.98) v2(60.93,177.54) v2(60.89,161.44) v2(61.09,2.19) v2(61.28,179.45) v2(61.79,82.93) v2(62.14,40.78) v2(62.15,40.06) v2(62.47,73.16) v2(62.62,2.19) v2(62.81,179.45) v2(62.87,170.26) v2(63.05,35.44) v2(64.14,2.19) v2(64.24,83.57) v2(64.33,179.45) v2(64.63,73.73) v2(65.48,168.73) v2(65.59,161.46) v2(65.75,33.34) v2(65.67,2.19) v2(65.85,179.45) v2(66.63,34.8) v2(66.89,159.46) v2(67.19,2.19) v2(67.28,169.02) v2(67.38,179.45) v2(67.86,84.77) v2(68.72,158.12) v2(68.71,2.19) v2(68.9,179.45) v2(69.36,85.43) v2(69.49,83.62) v2(70.24,2.19) v2(70.25,34.8) v2(70.43,179.45) v2(70.38,167.35) v2(70.39,166.33) v2(70.55,32.07) v2(71.23,157.76) v2(71.31,86.34) v2(71.76,2.19) v2(71.95,179.45) v2(72.61,85.35) v2(72.92,156.02) v2(73.05,87.25) v2(73.29,2.19) v2(73.47,179.45) v2(74.67,88.27) v2(74.81,2.19) v2(75,179.45) v2(75.35,33.34) v2(75.48,154.3) v2(76.33,89.4) v2(76.25,34.8) v2(76.33,2.19) v2(76.52,179.45) v2(77.08,153.17) v2(77.86,2.19) v2(78.05,179.45) v2(78.48,152.04) v2(78.63,91.19) v2(79.33,165.58) v2(79.36,164.85) v2(79.38,2.19) v2(79.57,179.45) v2(80.11,150.7) v2(80.25,92.63) v2(80.91,2.19) v2(81.09,179.45) v2(81.29,178.08) v2(81.74,149.15) v2(81.86,151.34) v2(82.42,94.84) v2(82.43,2.19) v2(82.62,179.45) v2(83.11,147.71) v2(83.48,149.85) v2(83.88,168.36) v2(84.03,178.04) v2(83.98,170.16) v2(83.95,2.19) v2(84.14,179.45) v2(84.49,97.3) v2(84.68,148.14) v2(84.73,145.56) v2(85.25,170.31) v2(85.48,2.19) v2(85.55,32.72) v2(85.67,179.45) v2(85.66,153.52) v2(85.9,143.94) v2(86.25,99.74) v2(86.81,161.54) v2(86.88,142.48) v2(87,2.19) v2(87.19,179.45) v2(87.33,101.41) v2(87.33,32.08) v2(87.78,140.91) v2(87.84,79.69) v2(88.53,2.19) v2(88.71,179.45) v2(89.06,32.76) v2(89.17,20.1) v2(89.68,106.07) v2(89.8,152.4) v2(90.05,22.68) v2(90.24,179.45) v2(90.22,84.43) v2(90.35,135.41) v2(90.31,85.83) v2(90.37,107.83) v2(90.69,137.67) v2(91.02,147.09) v2(90.97,109.53) v2(91.14,133.02) v2(91.48,1.02) v2(91.64,131.3) v2(91.62,111.87) v2(91.76,179.45) v2(92.19,114.33) v2(92.16,32.07) v2(92.36,35.97) v2(92.68,146.29) v2(92.67,124.99) v2(92.82,121.86) v2(92.78,119.54) v2(93.01,1.02) v2(93.29,179.45) v2(93.63,144.71) v2(94.04,34.45) v2(94.1,36.71) v2(94.22,144.23) v2(94.55,33.56) v2(94.53,1.02) v2(94.57,31.43) v2(94.72,76.33) v2(94.81,179.45) v2(95.26,36.08) v2(95.5,77.02) v2(95.77,32.07) v2(96.05,20.23) v2(96.06,1.02) v2(96.33,179.45) v2(97.54,22.2) v2(97.59,33.51) v2(97.57,32.08) v2(97.58,1.02) v2(97.66,69) v2(97.86,179.45) v2(97.97,87.28) v2(98.5,67.3) v2(98.81,36.07) v2(99.04,70.38) v2(99.1,1.02) v2(99.38,179.45) v2(99.95,104.04) v2(99.88,68.68) v2(99.98,36.66) v2(100.63,1.02) v2(100.83,146.08) v2(100.84,19.59) v2(100.91,179.45) v2(101.15,21.56) v2(101.36,146.65) v2(101.36,69.98) v2(101.39,67.33) v2(101.35,34.7) v2(101.48,96.92) v2(102.05,138.12) v2(102.13,97.15) v2(102.15,1.02) v2(102.43,179.45) v2(102.75,138.79) v2(102.77,68.68) v2(103.24,93.61) v2(103.28,99.19) v2(103.5,101.06) v2(103.73,96.3) v2(103.68,1.02) v2(103.92,98.19) v2(103.95,179.45) v2(104.49,70.3) v2(104.75,99.22) v2(104.81,97.28) v2(105.08,22.58) v2(105.2,1.02) v2(105.39,93.59) v2(105.48,179.45) v2(106.72,1.02) v2(107,179.45) v2(107.29,71.4) v2(107.73,158.96) v2(108.25,1.02) v2(108.53,179.45) v2(108.47,99.67) v2(109.01,177.4) v2(109.25,35.44) v2(109.85,20.23) v2(109.77,1.02) v2(110.05,179.45) v2(110.36,99.64) v2(110.76,93.61) v2(111.05,35.44) v2(111.3,1.02) v2(111.37,21.58) v2(111.57,179.45) v2(111.66,102.92) v2(111.94,72.11) v2(112.69,97.49) v2(112.82,1.02) v2(113.1,179.45) v2(113.26,93.61) v2(113.37,70.13) v2(113.93,102.89) v2(114,96.23) v2(114.34,1.02) v2(114.62,179.45) v2(114.56,20.31) v2(114.95,33.34) v2(115.15,71.43) v2(115.17,34.63) v2(115.77,93.61) v2(115.87,1.02) v2(116.15,179.45) v2(116.09,141.13) v2(116.52,21.45) v2(116.49,19.52) v2(116.69,70.56) v2(116.75,33.34) v2(117.03,141.76) v2(117.03,141.13) v2(117.03,140.49) v2(117.39,1.02) v2(117.67,179.45) v2(117.69,21.68) v2(117.67,20.33) v2(117.91,141.13) v2(117.94,33.34) v2(118.05,95.39) v2(118.28,93.61) v2(118.79,69.2) v2(118.78,67.24) v2(118.92,1.02) v2(119.19,179.45) v2(119.44,18.93) v2(119.46,20.45) v2(119.76,33.56) v2(120.42,68.48) v2(120.44,1.02) v2(120.47,93.59) v2(120.72,179.45) v2(121.01,23.45) v2(120.99,22.07) v2(121.01,20.8) v2(121.77,170.01) v2(121.85,19.59) v2(121.96,1.02) v2(122.24,179.45) v2(122.18,69.32) v2(122.2,67.34) v2(122.56,170.03) v2(122.74,21.29) v2(123.17,78.49) v2(123.18,77.84) v2(123.49,1.02) v2(123.58,19.13) v2(123.77,179.45) v2(124.21,68.99) v2(124.21,65.62) v2(124.34,22.03) v2(125.01,1.02) v2(125.29,179.45) v2(125.39,91.85) v2(126.09,21.47) v2(126.54,1.02) v2(126.65,18.93) v2(126.81,179.45) v2(127.36,21.42) v2(127.61,113.37) v2(127.62,67.71) v2(127.71,79.18) v2(128.06,1.02) v2(128.34,179.45) v2(128.5,111.96) v2(128.49,20.17) v2(128.71,21.37) v2(129.25,113.24) v2(129.58,1.02) v2(129.7,144.35) v2(129.86,179.45) v2(129.85,21.47) v2(130.34,144.98) v2(130.34,144.35) v2(130.34,143.71) v2(130.26,78.62) v2(130.26,18.9) v2(130.94,111.83) v2(130.92,21.28) v2(130.97,144.35) v2(131.11,1.02) v2(131.23,18.81) v2(131.66,19.74) v2(132.63,1.02) v2(132.78,180.93) v2(132.85,21.64) v2(132.87,19.87) v2(132.9,18.47) v2(133.87,20.1) v2(134.16,1.02) v2(134.86,180.95) v2(135.2,20.94) v2(135.68,1.02) v2(136.38,180.95) v2(137.2,1.02) v2(137.86,180.93) v2(138.69,60.05) v2(138.72,59.36) v2(138.73,1.02) v2(139.31,20.28) v2(139.43,180.95) v2(140.25,1.02) v2(140.95,180.95) v2(140.95,18.91) v2(141.41,59.28) v2(141.78,1.02) v2(142.48,180.95) v2(142.75,20.39) v2(143.29,51.49) v2(143.3,1.02) v2(143.42,61.57) v2(143.95,51.5) v2(143.95,20.17) v2(144,180.95) v2(144.53,20.93) v2(144.82,1.02) v2(145.53,180.95) v2(145.85,19.59) v2(146.35,1.02) v2(147.05,180.95) v2(147.43,137.95) v2(147.43,136.68) v2(147.52,135.62) v2(147.53,133.77) v2(147.87,1.02) v2(149.4,1.02) v2(149.46,130.82) v2(150.05,77.74) v2(150.33,135.38) v2(150.4,19.92) v2(150.5,165.56) v2(150.63,166.4) v2(150.93,137.85) v2(150.92,1.02) v2(151.15,132.31) v2(151.14,69.09) v2(151.16,91.37) v2(151.52,136.02) v2(152.44,1.02) v2(152.71,20.28) v2(152.89,137.94) v2(153.31,140.29) v2(153.37,139.02) v2(153.74,21.45) v2(153.97,1.02) v2(154.31,174.4) v2(154.84,161.58) v2(154.97,83.23) v2(155.49,1.02) v2(155.98,19.59) v2(156.25,174.03) v2(156.6,74.99) v2(157.02,1.02) v2(157.68,174.13) v2(158.54,1.02) v2(158.9,89.88) v2(159.34,108.05) v2(159.77,58.21) v2(159.98,108.68) v2(159.98,108.05) v2(159.98,107.41) v2(160.06,1.02) v2(160.61,108.05) v2(161.41,57.54) v2(161.59,1.02) v2(162.51,134.98) v2(162.7,137.69) v2(162.76,141.66) v2(163.11,1.02) v2(163.46,77.22) v2(163.56,30.89) v2(164.62,141.61) v2(164.62,139.58) v2(164.62,137.68) v2(164.62,135.77) v2(164.64,1.02) v2(165.03,41.71) v2(166.17,55.05) v2(166.16,1.02) v2(166.65,143.64) v2(166.65,141.74) v2(166.65,139.71) v2(166.65,137.68) v2(166.65,135.77) v2(166.73,30.76) v2(167.68,35.02) v2(167.68,1.02) v2(168.63,141.74) v2(168.63,139.71) v2(168.64,137.65) v2(168.68,143.64) v2(168.68,135.77) v2(169.21,1.02) v2(170.38,175.33) v2(170.73,1.02) v2(171.43,180.95) v2(171.49,180.06) v2(171.62,175.49) v2(172.26,1.02) v2(172.65,175.51) v2(172.96,180.95) v2(173.08,8.36) v2(173.33,175.51) v2(173.78,1.02) v2(173.9,14.3) v2(174.05,37.16) v2(173.97,16.29) v2(174.28,21.91) v2(174.48,180.95) v2(175.08,13.41) v2(175.16,39.06) v2(175.3,1.02) v2(176.01,180.95) v2(176.03,37.29) v2(176.72,176.49) v2(176.69,40.12) v2(176.83,1.02) v2(177.53,180.95) v2(177.63,176.69) v2(177.66,175.31) v2(177.71,58.61) v2(178.35,1.02) v2(178.46,175.27) v2(178.47,14.91) v2(179.05,180.95) v2(179.27,177.54) v2(179.26,175.25) v2(179.39,33.84) v2(179.51,35.19) v2(179.59,32.95) v2(179.88,1.02) v2(180.58,180.95) v2(181.01,177.64) v2(181.4,1.02) v2(181.69,16.29) v2(182.1,180.95) v2(182.36,178.26) v2(182.4,175.59) v2(182.46,16.29) v2(182.92,1.02) v2(183.22,17.81) v2(183.22,17.05) v2(183.22,16.29) v2(183.22,15.52) v2(183.36,175.46) v2(183.63,180.95) v2(183.98,16.29) v2(184.45,1.02) v2(184.74,16.29) v2(185.15,180.95) v2(185.94,13.57) v2(185.97,1.02) v2(186.67,180.95) v2(187.5,1.02) v2(188.2,180.95) v2(189.02,1.02) v2(189.31,158.2) v2(189.53,43.78) v2(189.47,8.28) v2(189.72,180.95) v2(190.19,40.47) v2(190.25,43.77) v2(190.54,1.02) v2(191.25,180.95) v2(191.96,90.2) v2(192.07,1.02) v2(193.59,1.02) v2(194.24,45.52) v2(194.29,27.46) v2(194.35,8.62) v2(195.12,1.02) v2(195.46,179.44) v2(196.3,173.73) v2(196.47,18.67) v2(196.64,1.02) v2(196.99,161.54) v2(196.96,140.57) v2(197.04,43.29) v2(197.51,88.85) v2(197.51,87.32) v2(197.51,85.8) v2(197.51,81.23) v2(197.51,79.7) v2(197.51,78.18) v2(197.51,76.65) v2(197.51,75.13) v2(197.51,72.08) v2(197.51,70.56) v2(197.51,69.03) v2(197.77,179.45) v2(198.16,1.02) v2(198.95,173.54) v2(199.29,179.45) v2(199.3,21.75) v2(199.69,1.02) v2(200.54,179.44) v2(200.53,66.21) v2(201.21,1.02) v2(202.11,167.95) v2(202.16,64.58) v2(202.16,63.06) v2(202.16,61.54) v2(202.16,60.01) v2(202.18,34.88) v2(202.18,33.35) v2(202.18,31.83) v2(202.18,30.3) v2(202.18,28.78) v2(202.18,27.26) v2(202.18,25.73) v2(202.18,24.21) v2(202.18,22.68) v2(202.18,21.16) v2(202.18,19.64) v2(202.18,18.11) v2(202.18,16.59) v2(202.18,15.06) v2(202.18,13.54) v2(202.18,12.02) v2(202.18,10.49) v2(202.18,8.97) v2(202.18,7.44) v2(202.18,5.92) v2(202.18,2.87) v2(202.34,179.45) v2(203.18,178.78) v2(203.18,177.25) v2(203.18,175.73) v2(203.18,174.2) v2(203.18,169.63) v2(203.18,168.11) v3(6.93,51.89) v3(7.05,55.48) v3(8.36,75.05) v3(8.62,80.25) v3(8.98,77.77) v3(9.23,53.24) v3(9.16,51.02) v3(10.04,25.84) v3(10.23,79.38) v3(10.69,14.1) v3(10.75,28.39) v3(10.82,7.3) v3(11.25,22.28) v3(11.27,23.13) v3(11.53,5.4) v3(11.79,80.43) v3(12.04,78.35) v3(12.15,52.95) v3(12.66,50.47) v3(12.66,27.82) v3(12.92,23.33) v3(13.63,6.94) v3(13.81,28.11) v3(14.63,49.09) v3(14.9,5.24) v3(15.1,52.99) v3(15.14,28.3) v3(15.44,25.51) v3(15.57,27.12) v3(15.65,8.41) v3(15.87,10.68) v3(16.5,29.03) v3(17.11,6.39) v3(18.15,9.93) v3(19.79,5.88) v3(20.09,8.1) v3(21.11,11.02) v3(22.44,9.03) v3(29.57,30.73) v3(29.6,29.7) v3(30.24,178.12) v3(30.46,30.73) v3(30.49,29.7) v3(36.35,170.79) v3(36.66,176.98) v3(36.96,47.01) v3(37.73,48.03) v3(37.85,47.01) v3(38.74,48.03) v3(38.74,47.01) v3(38.87,49.17) v3(38.87,46) v3(39.63,47.52) v3(39.76,48.66) v3(41.41,17.95) v3(43.85,177.13) v3(44.71,49.04) v3(44.97,48.03) v3(44.97,47.01) v3(45.6,49.04) v3(45.85,48.03) v3(45.85,47.01) v3(47.12,46.63) v3(47.12,45.74) v3(47.24,30.55) v3(47.22,29.7) v3(48.13,30.55) v3(48.11,29.7) v3(49.02,30.55) v3(49,29.7) v3(49.91,30.55) v3(49.89,29.7) v3(50.8,30.55) v3(50.78,29.7) v3(52.63,21.42) v3(52.66,20.46) v3(61.94,45.2) v3(61.94,44.18) v3(63.23,50.7) v3(64.57,172.83) v3(64.73,18.43) v3(65.19,176.58) v3(65.21,19.22) v3(65.62,18.43) v3(66.1,19.22) v3(66.51,18.43) v3(66.99,19.22) v3(67.4,18.43) v3(67.82,174.18) v3(67.88,19.22) v3(68.29,18.43) v3(69.07,45.11) v3(69.07,44.23) v3(69.07,43.21) v3(69.6,172.21) v3(69.86,177.68) v3(71.74,77.4) v3(71.9,175.42) v3(72.88,77.37) v3(74.53,176.95) v3(77.88,15.06) v3(78.72,15.02) v3(79.61,15.02) v3(80.55,15.02) v3(81.39,15) v3(81.77,61.88) v3(82.26,14.99) v3(82.61,62.72) v3(83.15,14.99) v3(84.03,14.99) v3(84.92,14.99) v3(86.26,168.16) v3(87.97,166.19) v3(89.96,177.13) v3(91.28,152.31) v3(93.23,175.7) v3(94.59,11.72) v3(95.41,176.93) v3(95.43,11.74) v3(96.63,164.6) v3(96.68,165.54) v3(97.2,175.3) v3(97.64,164.57) v3(97.7,165.51) v3(98.86,176.86) v3(100.53,101.94) v3(101.4,115.19) v3(101.4,114.36) v3(101.4,113.49) v3(101.4,112.65) v3(101.4,111.82) v3(101.4,110.95) v3(101.4,110.11) v3(101.4,109.28) v3(101.4,108.41) v3(101.4,107.55) v3(101.4,106.71) v3(101.4,105.85) v3(101.39,101.74) v3(105.39,160.15) v3(105.44,153.78) v3(105.87,154.5) v3(106.36,153.78) v3(108.04,128.13) v3(108.04,127.01) v3(108.06,125.94) v3(110.09,86.64) v3(110.98,86.64) v3(111.61,85.5) v3(112,86.64) v3(112.88,86.64) v3(112.87,85.53) v3(113.9,86.64) v3(113.97,85.51) v3(114.79,86.64) v3(115.81,86.64) v3(116.69,86.64) v3(116.92,161.45) v3(117.48,162.29) v3(117.61,86.64) v3(117.86,161.47) v3(118.45,162.26) v3(118.5,86.64) v3(118.93,161.52) v3(119.24,135.59) v3(119.34,136.53) v3(119.39,162.29) v3(119.39,86.69) v3(119.84,111.61) v3(119.84,110.72) v3(119.84,109.76) v3(119.84,108.87) v3(119.87,161.47) v3(119.92,115.27) v3(119.92,114.38) v3(119.92,113.49) v3(119.92,112.6) v3(119.99,135.99) v3(120,134.9) v3(120,134.01) v3(120,133.13) v3(120,132.24) v3(120.23,162.26) v3(120.25,86.67) v3(120.43,160.81) v3(120.81,161.57) v3(122.06,136.45) v3(122.12,135.02) v3(122.12,134.13) v3(122.12,133.24) v3(122.16,132.36) v3(122.16,131.47) v3(122.16,130.59) v3(122.16,129.7) v3(122.16,128.81) v3(122.16,127.92) v3(123.13,135.16) v3(123.13,134.27) v3(123.15,128.88) v3(123.15,128) v3(123.17,133.38) v3(123.17,132.49) v3(123.17,131.6) v3(123.17,130.71) v3(123.17,129.82) v3(125.58,39.02) v3(125.6,38.15) v3(126.43,123.45) v3(126.85,124.24) v3(127.16,102.51) v3(127.32,123.45) v3(127.74,124.24) v3(128.2,123.45) v3(128.63,124.24) v3(128.94,138.84) v3(128.94,137.95) v3(128.94,137.06) v3(129.07,136.17) v3(129.09,123.45) v3(129.32,108.99) v3(129.32,108.08) v3(129.83,138.84) v3(129.83,137.95) v3(129.83,137.06) v3(129.9,167.77) v3(129.9,166.93) v3(129.96,168.62) v3(129.96,136.17) v3(130.36,166.22) v3(130.91,167.49) v3(130.97,168.58) v3(130.97,135.92) v3(130.97,134.9) v3(131.79,37.73) v3(131.81,36.86) v3(134.3,104.98) v3(134.28,104.02) v3(134.3,103.17) v3(144.63,160.41) v3(145.96,64.98) v3(146.57,143.74) v3(146.56,142.83) v3(147.89,171.89) v3(148.23,148.61) v3(148.21,147.75) v3(149.03,149.24) v3(149.64,170.01) v3(149.64,168.88) v3(149.64,167.83) v3(157.18,70.37) v3(158.7,82.11) v3(160.39,128.72) v3(160.45,127.65) v3(161.86,10.87) v3(161.86,9.85) v3(162.69,37.36) v3(162.71,36.52) v3(164.04,112.62) v3(164.04,111.73) v3(164.04,110.84) v3(164.07,102.97) v3(164.07,102.08) v3(164.93,113.51) v3(164.93,112.62) v3(164.93,111.73) v3(164.93,110.84) v3(164.93,102.97) v3(164.93,102.08) v3(164.93,101.19) v3(165.01,103.83) v3(165.82,113.51) v3(165.82,112.62) v3(165.82,111.73) v3(165.82,110.84) v3(165.84,103.83) v3(165.82,102.97) v3(165.82,102.08) v3(165.82,101.19) v3(165.82,100.35) v3(166.71,113.51) v3(166.71,112.62) v3(166.71,111.73) v3(166.71,110.84) v3(166.73,103.81) v3(166.71,102.97) v3(166.71,102.08) v3(166.71,101.19) v3(166.71,100.3) v3(167.09,114.35) v3(167.09,99.54) v3(167.6,113.51) v3(167.6,112.62) v3(167.6,111.73) v3(167.6,110.84) v3(167.6,103.81) v3(167.6,102.97) v3(167.6,102.08) v3(167.6,101.19) v3(167.6,100.3) v3(167.81,25.28) v3(168.7,25.28) v3(168.96,124.42) v3(169.65,18.04) v3(170.8,19.93) v3(181.79,123.14) v3(182.93,123.12) v3(187.42,119.93) v3(188.4,119.9) v3(188.39,92.52) v3(188.52,91.47) v3(188.51,90.61) v3(188.81,115.52) v3(188.82,114.67) v3(188.82,113.79) v3(188.82,112.93) v3(189.01,180.22) v3(189.12,105.17) v3(189.17,110.04) v3(189.2,109.15) v3(189.2,108.29) v3(189.2,107.4) v3(189.22,106.07) v3(189.22,92.46) v3(189.4,91.49) v3(189.42,90.61) v3(189.64,118.22) v3(189.66,117.34) v3(189.69,116.47) v3(189.67,115.53) v3(189.66,114.66) v3(189.76,113.75) v3(189.75,112.9) v3(190.03,110.04) v3(190.05,105.13) v3(190.01,100.76) v3(190.01,99.9) v3(190.01,99.01) v3(190.08,109.15) v3(190.08,108.29) v3(190.08,107.4) v3(190.11,106.03) v3(190.31,91.47) v3(190.32,90.61) v3(190.51,118.21) v3(190.55,117.37) v3(190.63,116.5) v3(190.64,115.64) v3(191.25,122.49) v3(192.17,178.59) v3(193.4,27.32) v3(193.72,14.27) v3(193.94,13.31) v3(193.96,23.86) v3(196.02,117.59) v3(197.2,117.56) v3(199.58,176.51) v3(201,173.66) v3(202.1,171.84)
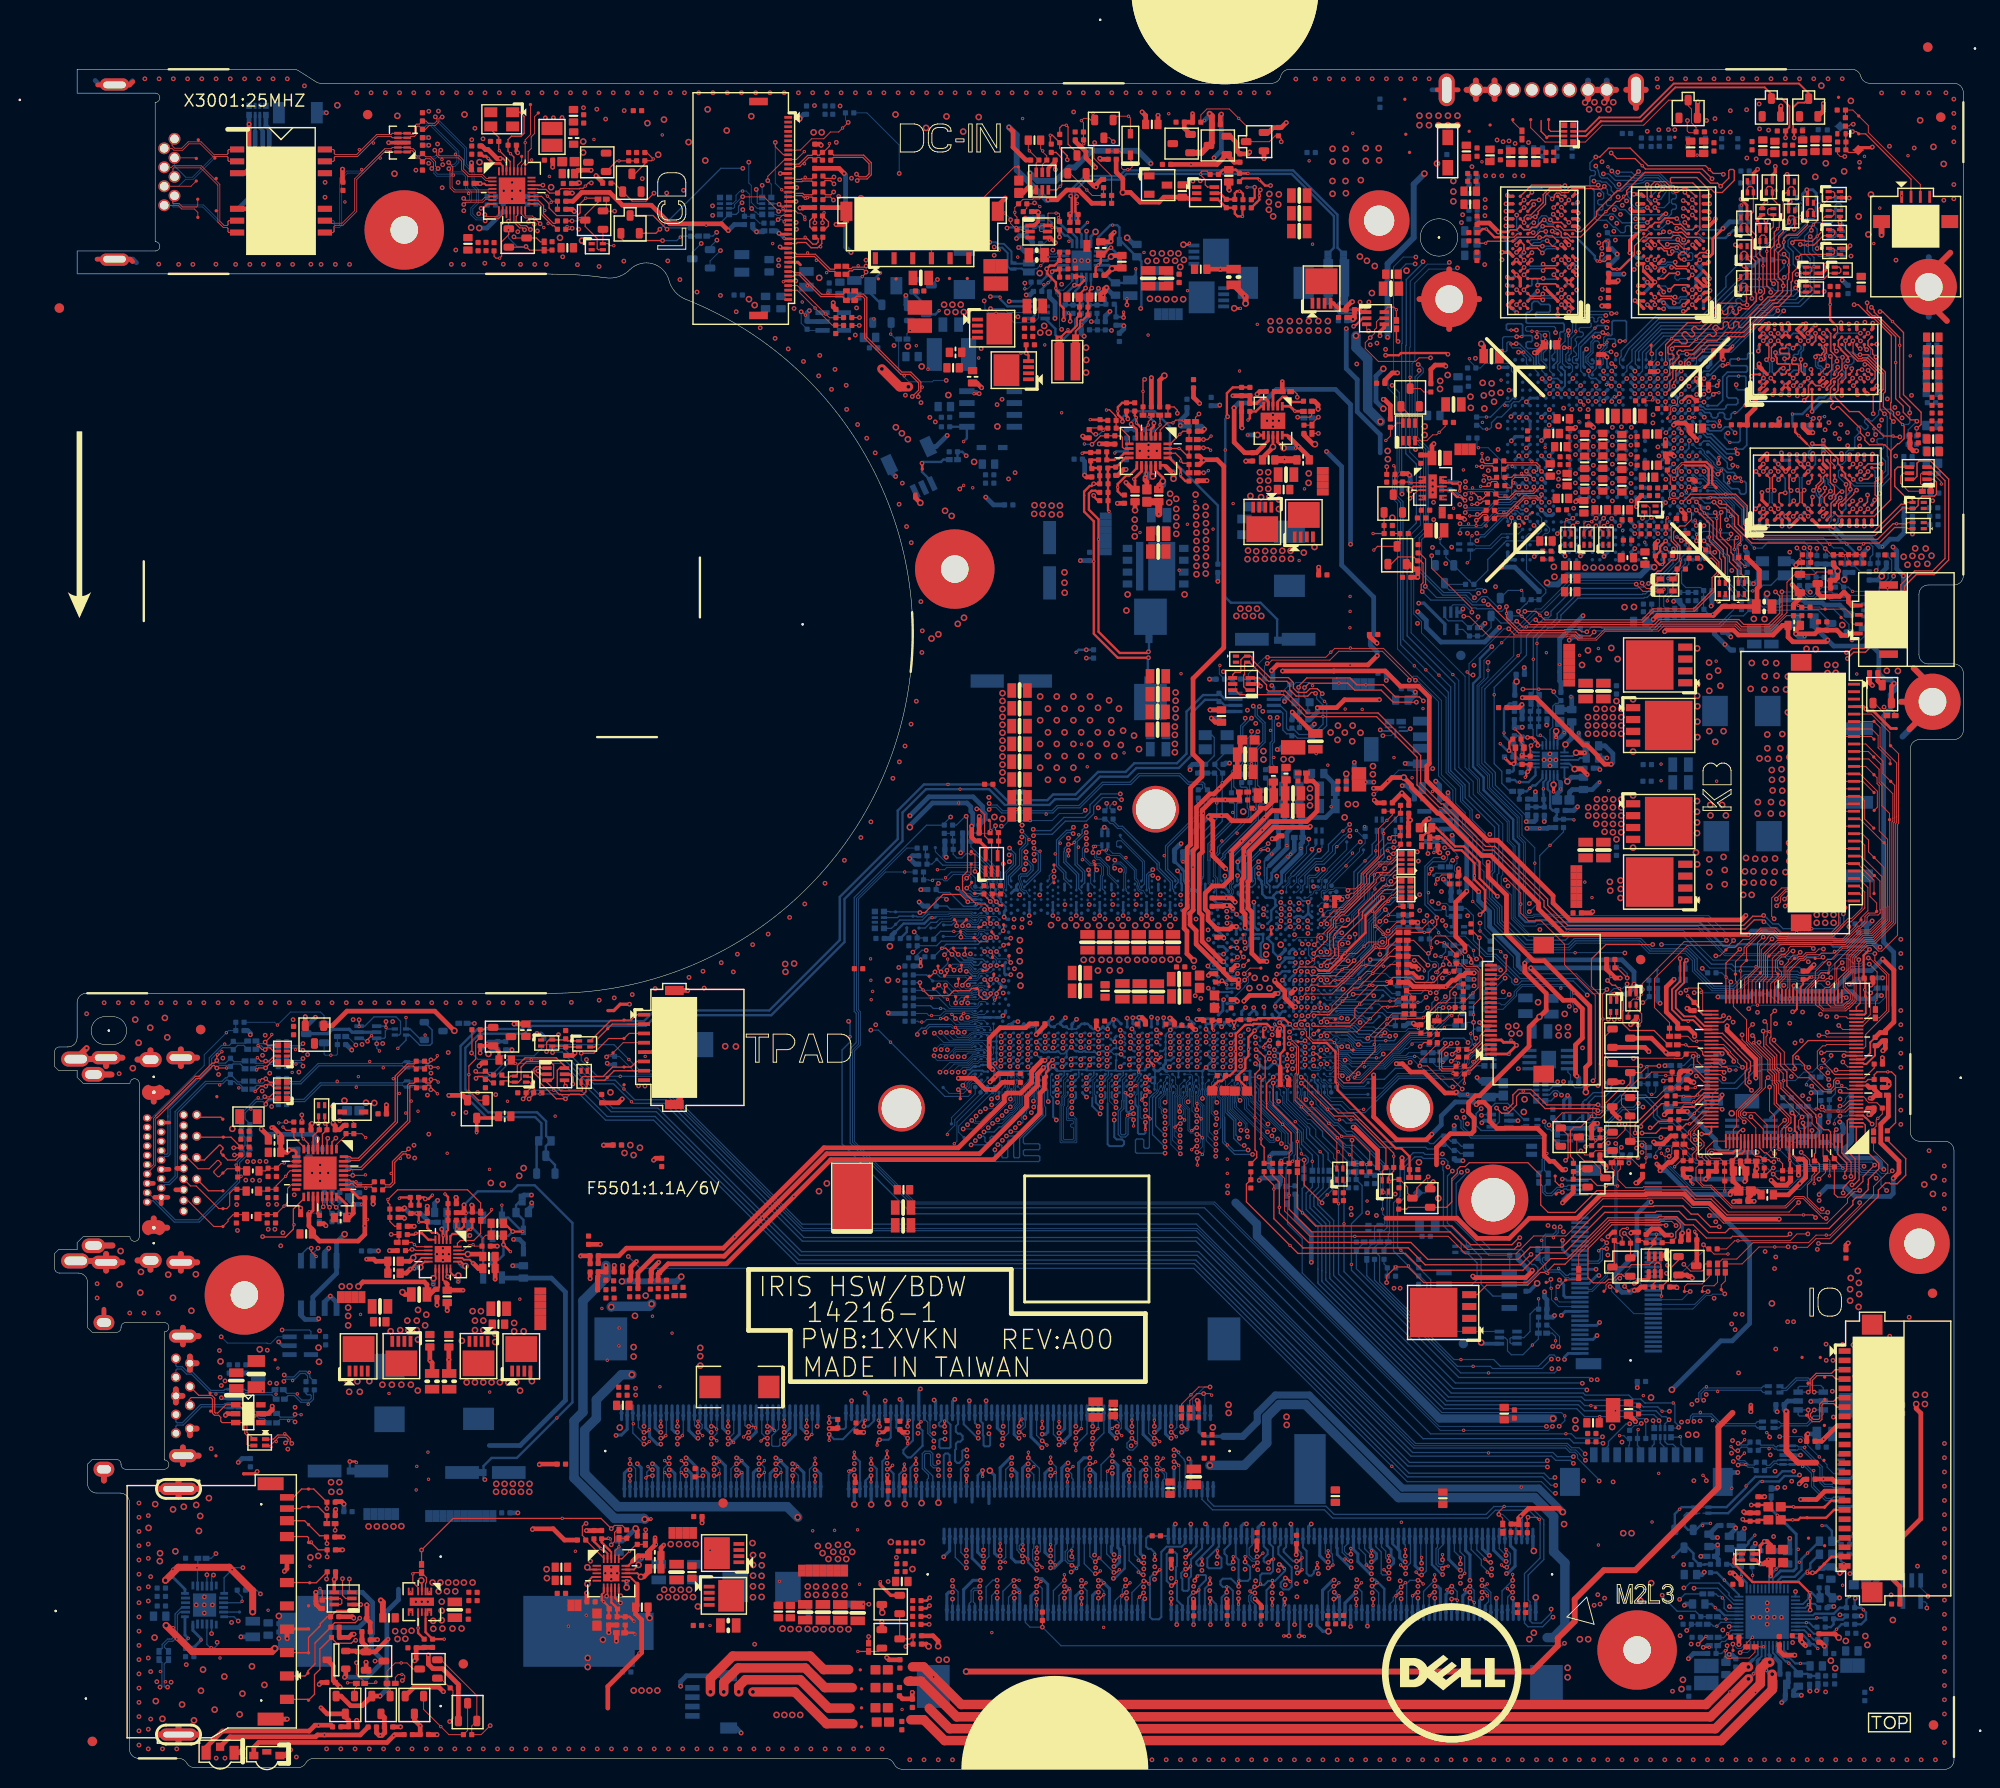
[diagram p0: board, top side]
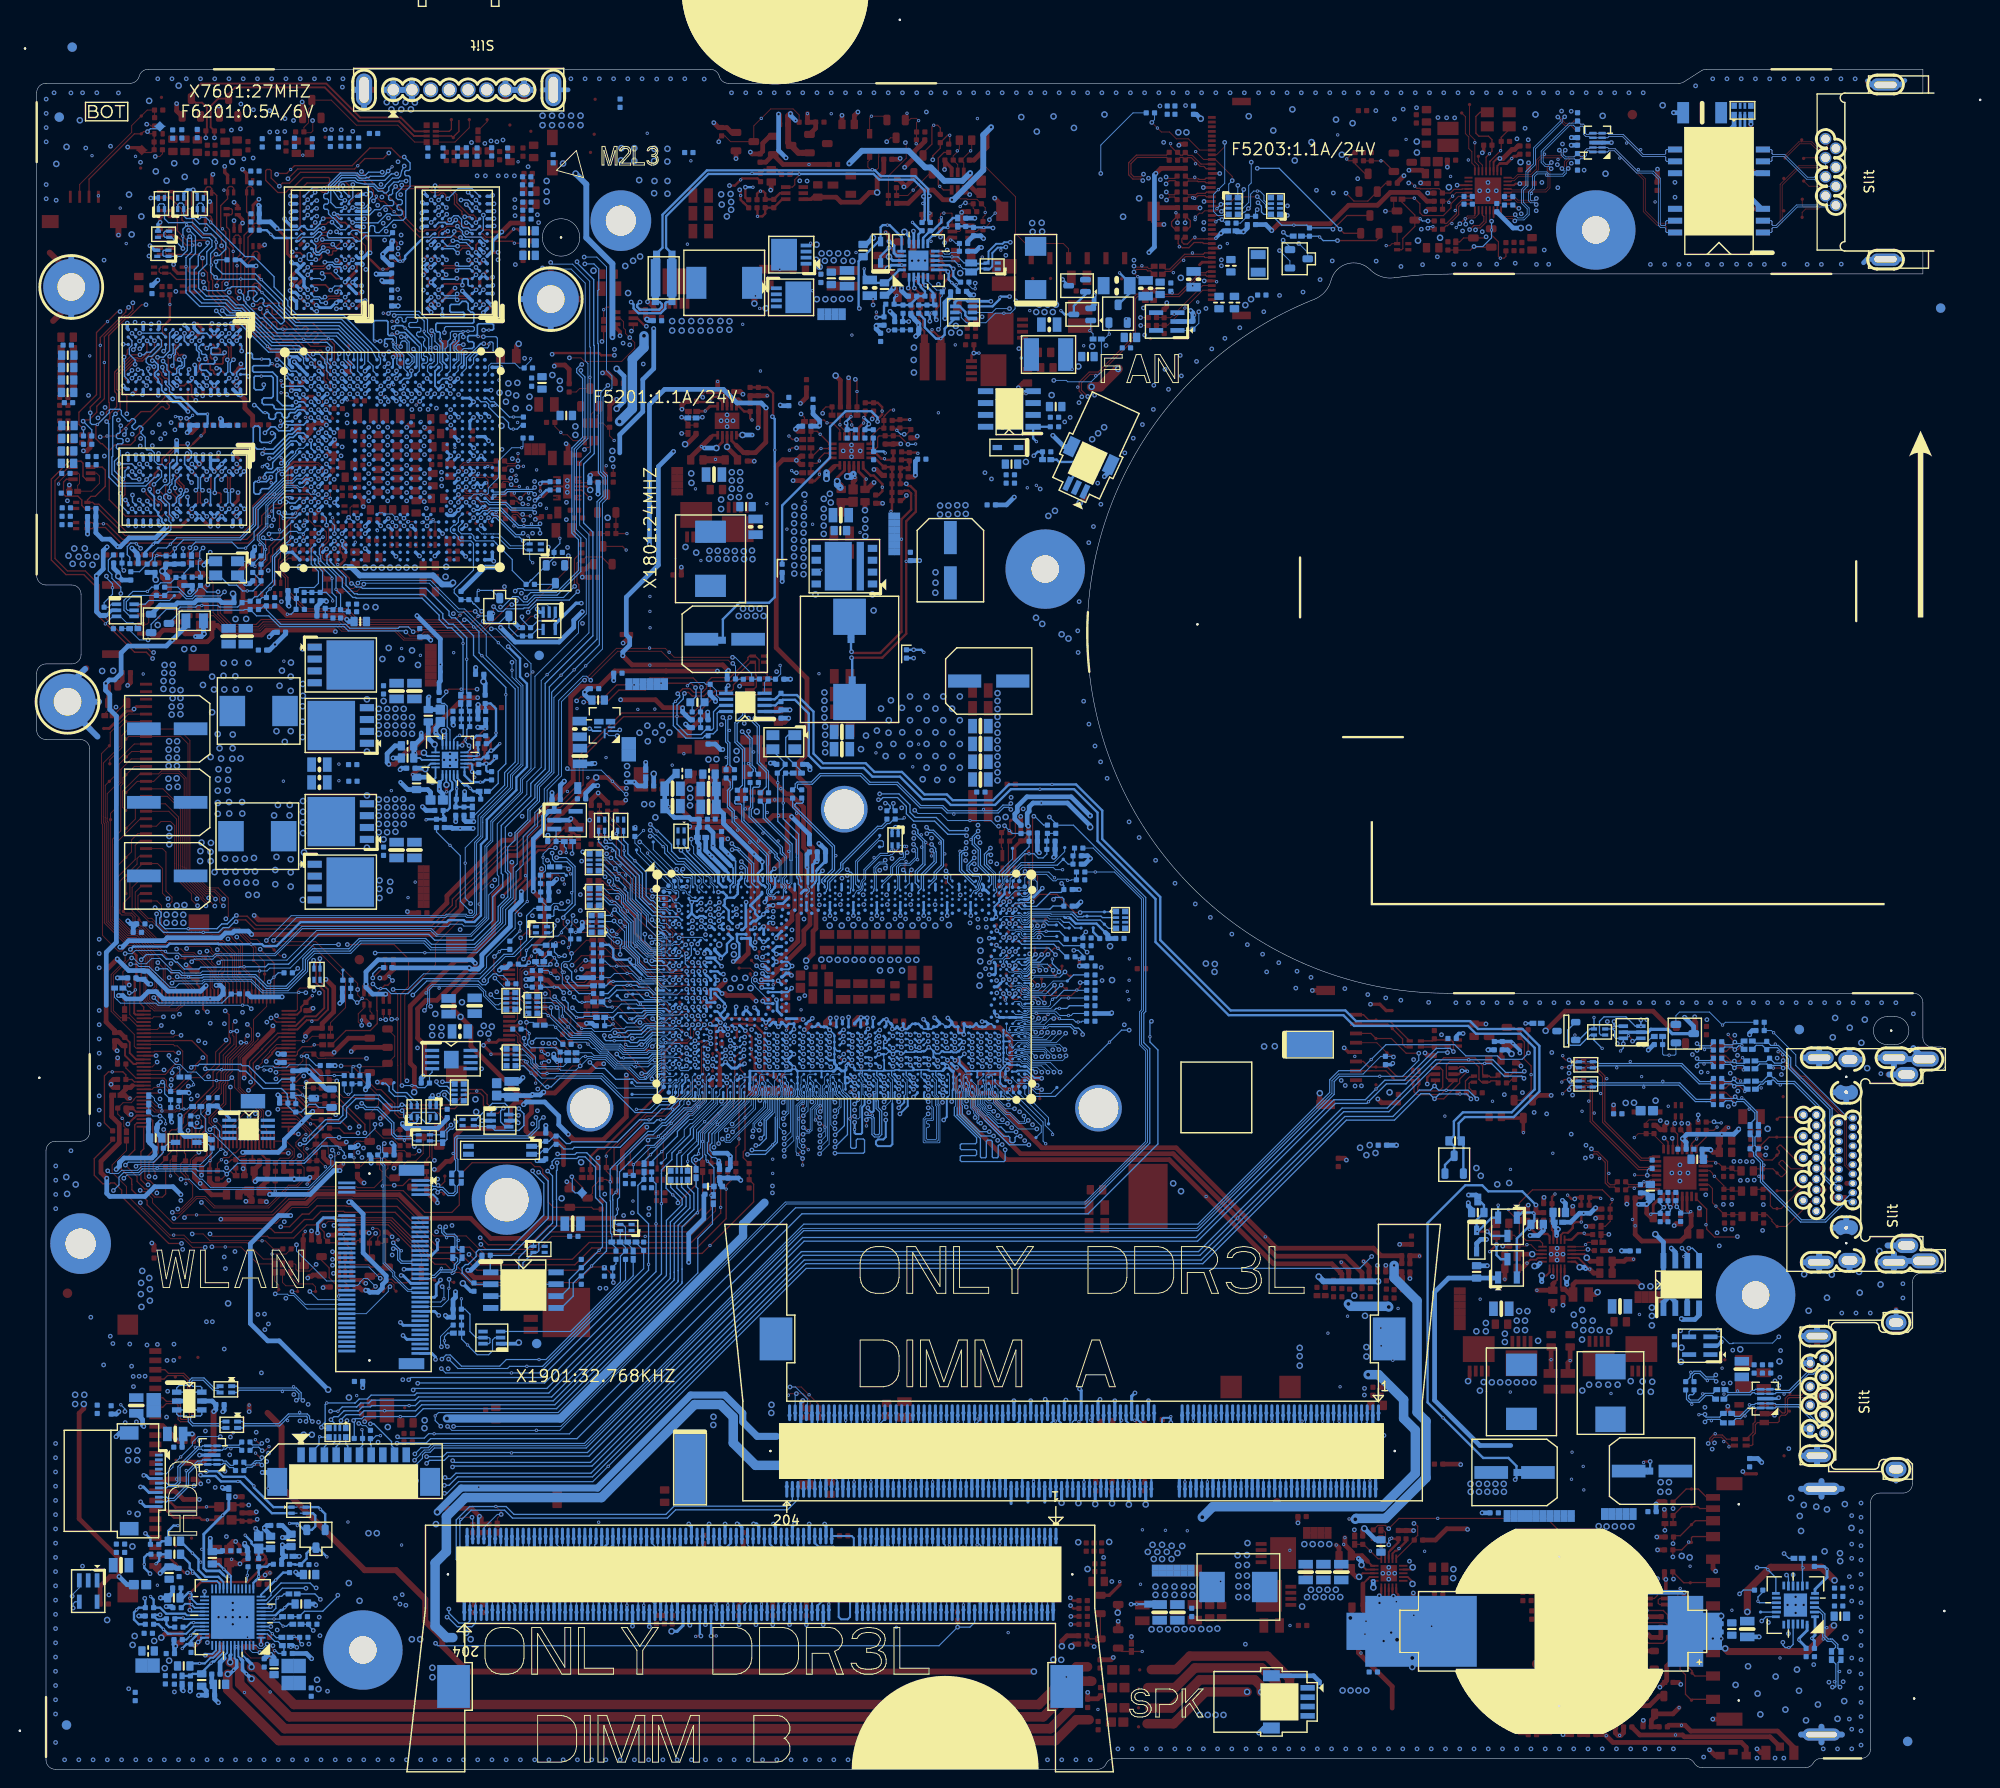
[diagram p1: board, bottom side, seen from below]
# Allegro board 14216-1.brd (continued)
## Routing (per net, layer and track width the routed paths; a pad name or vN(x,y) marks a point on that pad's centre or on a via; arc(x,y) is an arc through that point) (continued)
GND_R1: length 3.9
  TOP w0.508: R6301.2 189.03,35.11 v1(189.26,35.34) 190.7,36.77 CN6301.9
GND_R2: length 3.3
  TOP w0.508: CN6301.15 190.48,30.77 190.18,31.07 v1(189.24,31.07) 188.36,31.07 R6302.2
V3D3_STB: length 12.8
  BOTTOM w0.203: HDA27.20 183.82,20.42 184.19,20.79
  BOTTOM w0.305: 184.19,20.79 184.64,21.24 186.04,21.24 186.32,21.52 186.32,25.17 v1(184.3,27.19) 183.64,27.85 R2712.1
V18: length 3.2
  BOTTOM w0.305: C3201.2 14.89,13.06 15.65,13.82 v1(15.65,13.85) 15.65,14 14.79,14.87 U3201.24
VBAT: length 19.8
  TOP w0.203: C2404.1 179.46,65.14 179.92,65.6 180.22,65.9 180.53,65.9 180.8,66.16 KBC24.102
  TOP w0.508: v1(171.4,64.8) 171.76,64.44 v2(171.76,64.09) 172.65,64.98 172.99,64.98 173.5,65.49 R2446.1 ; C2404.1 179.46,64.19 C2405.1 179.56,64 R2404.1 180.14,62.4 R2402.1 179.46,61.9 179.27,61.71 v2(179.27,61.53)
  BOTTOM w0.508: v2(171.76,64.09) 172.4,64.09 174.96,61.53 v2(179.27,61.53)
VCC1R05VIDEO_PEX_PLLVDD: length 1.2
  BOTTOM w0.305: GPU1.AA14 159.89,140.57 v2(159.89,140.59) 159.89,140.61 GPU1.AA15
  vias: v1(159.46,141.48)
VCC_CORE: length 1.3
  BOTTOM w0.254: CPU1.F59 101.09,91.73 100.79,92.03 v2(100.79,92.03)
  BOTTOM w0.508: v2(92.67,94.16) 92.68,94.17 R702.1
  vias: v1(109.85,109.73) v1(110.47,107.31) v1(114.41,108.8) v2(101.5,84.43) v2(101.48,83.1) v2(102.64,91) v2(102.6,90.13) v2(102.68,85.69) v2(103.51,91) v2(103.47,90.12) v2(104.34,90.6) v2(107.36,91.03) v2(108.08,92.55) v2(108.74,91.03) v2(109.86,91.03) v2(110.69,92.56) v2(111.24,91.03) v2(112.37,91.03) v2(113.2,92.56) v2(113.75,91.03) v2(114.88,91.03) v2(115.7,92.56) v2(116.26,91.03) v2(117.39,91.03) v2(118.21,92.56) v2(118.77,91.03) v2(119.89,91.03) v2(120.45,92.54) v2(122.11,91.01) v2(123.39,89.85) v2(123.45,88.83) v3(103.22,87.62) v3(103.27,88.75) v3(103.25,86.49) v3(103.27,84.98) v3(103.33,83.88) v3(105.43,114.83) v3(105.43,112.29) v3(105.43,109.75) v3(105.43,107.21) v3(106.26,113.54) v3(106.26,111) v3(106.26,108.46) v3(106.26,105.92) v3(106.6,90.36) v3(107.21,114.83) v3(107.21,112.29) v3(107.21,109.75) v3(107.21,107.21) v3(107.86,105.9) v3(108.04,113.54) v3(108.04,111) v3(108.04,108.46) v3(108.06,90.3) v3(108.99,114.83) v3(108.99,112.29) v3(108.99,109.75) v3(108.99,107.21) v3(109.29,90.33) v3(109.41,105.97) v3(109.82,113.54) v3(109.82,111) v3(109.82,108.46) v3(110.5,90.31) v3(110.77,114.83) v3(110.77,112.29) v3(110.77,109.75) v3(111.62,113.62) v3(111.6,111) v3(111.6,108.46) v3(111.74,90.31) v3(112.55,109.75) v3(112.81,114.42) v3(113.03,112.29) v3(113.05,90.31) v3(113.06,110.95) v3(113.38,108.46) v3(113.86,113.54) v3(114.07,109.64) v3(114.31,111.18) v3(114.27,90.31) v3(115.48,110.65) v3(115.6,90.32) v3(116.01,109.2) v3(116.82,90.35) v3(118.07,90.31) v3(119.36,90.31)
VCC_SENSE: length 68.3
  TOP w0.14: PR4603.2 111.87,143.55 PC4601.2 110.85,143.58 PC4613.2 110.68,143.36 111.13,142.9 v2(111.39,142.9)
  L3 w0.127: v2(111.39,142.9) 110.68,142.19 108.63,142.19 102.59,136.15 102.59,133.67 103.07,133.18 103.07,121.54 102.64,121.12 100.96,119.43 96.91,115.38 96.91,106.01 94.43,103.53 94.43,97.09 94.86,96.66 94.86,96.33 94.73,96.2 94.01,96.2 93.89,96.08 93.89,95.7 94.01,95.57 94.73,95.57 94.86,95.44 94.86,95.14 v2(94.55,94.83)
  BOTTOM w0.14: v1(112.18,143.32) 111.77,142.9 v2(111.39,142.9) ; CPU1.E63 98.42,92.38 97.22,92.38 95.74,93.86 94.61,93.86 R702.2 94.3,94.59 v2(94.55,94.83)
VCCK_12: length 17.1
  TOP w0.305: C5503.1 27.64,59.82 U5502.19 ; C5501.1 32.54,61.16 31.62,62.08 U5502.25
  TOP w0.508: C5503.1 27.2,58.17 27.57,57.8 C5504.1 28.33,56.54 32.47,56.54 33.18,57.26 v1(33.18,58.17) C5501.1
VCCST_PWRGD_XDP: length 1.4
  TOP w0.14: R9601.2 100.08,101.48 TP9648.1
VDD10: length 9.2
  TOP w0.203: v2(45.52,169.73) 45.98,169.73 46.14,169.57 LOM30.3 ; LOM30.8 46.31,167.57 45.83,167.09 v2(45.63,167.09) ; v2(47.66,172.42) 47.96,172.42 48.33,172.05 LOM30.30 ; v2(52.23,169.57) LOM30.22
  TOP w0.508: v2(47.66,172.42) 47.32,172.42 46.36,173.38 46.08,173.38 45.7,173.77 C3022.1 ; C3021.1 45.49,169.76 v2(45.52,169.73)
  vias: v1(53.12,167.73) v2(52.49,176.77) v2(53.36,176.78) v2(54.28,176.8) v3(53.11,169.35)
VDD_DAC_33: length 7.6
  TOP w0.305: U5502.9 25.84,66.07 25.64,66.27 25.1,66.27 v2(25.1,66.28)
  TOP w0.508: v2(25.1,66.28) 24.86,66.05 C5521.2 R5503.2 24.18,67.9 23.39,68.68 v1(23.21,68.68)
  BOTTOM w0.508: v2(25.1,66.28) 25.18,66.37 C5524.1 26.02,65.44 C5502.1
VDDREG:
  vias: v1(52.93,170.5)
VSS_SENSE: length 70.8
  TOP w0.14: v2(110.98,141.82) 111.88,142.73 112.54,142.73 PR4604.1 112.56,142.74 PC4612.1 113.44,142.73 114.07,142.73 114.23,142.57 114.23,141.53 114.38,141.38 PU4601.8
  L3 w0.127: v2(110.98,141.82) 108.87,141.82 103.02,135.97 103.02,133.84 103.5,133.36 103.5,121.36 102.82,120.69 101.13,119 97.34,115.2 97.34,105.83 94.86,103.35 94.86,97.08 95.15,96.78 95.15,93.38 v2(95.41,93.12)
  BOTTOM w0.14: v1(110.17,141.86) 110.17,141.85 110.19,141.82 v2(110.98,141.82) ; v2(95.41,93.12) 95.2,93.33 94.49,93.33 94.3,93.15 R901.1 94.59,92.39 94.59,92.41 95.46,92.41 95.79,92.08 98.82,92.08 CPU1.E62
0D675V_S0: length 64
  BOTTOM w0.356: v3(158.45,18.39) 158.45,18.39 DM2.204 ; v3(158.25,23.37) 158.15,23.47 DM2.203
  BOTTOM w1.016: 159.67,14.1 160.36,14.1 161.57,15.31 161.57,22.09 160.37,23.29 160.37,27.06 158.33,29.09 143.77,29.09 133.81,39.04 131.02,39.04 129.67,37.7 129.67,34.93 127.28,32.54 v3(123.6,32.54)
  vias: v1(54.96,15.32) v3(57.03,11.92) v3(57.03,10.95) v3(123.91,36.61) v3(157.77,13.92) v3(158.25,14.61)
1D05S_VCCST: length 126.8
  TOP w0.508: PR4601.1 122.47,140.56 v2(122.92,140.11) ; PR4630.2 122.48,139.67 v2(122.92,140.11) ; PR4620.2 122.77,143.23 v2(123,143.45) ; v2(122.92,140.11) 122.99,140.18 124.37,140.18 125.08,139.47 125.08,120.05 121.79,116.76 121.79,108.66 122.75,107.7 122.75,106.28 121.52,105.05 121.52,98.97 121.17,98.62 121.17,92.23 120.84,91.9 120.84,90.01 121.14,89.7 121.14,87.3 v3(121.88,86.57)
  L3 w0.508: v2(91.5,102.08) 90.57,101.15 90.57,99.29 89.04,97.76 89.04,88.42 v3(89.36,88.11) ; 121.75,84.95 119.76,82.96 102.98,82.96 102.19,83.75 99.37,83.75 98.5,84.62 93.65,84.62 93.21,85.07 89.74,85.07 v3(89.15,84.48)
  L4 w0.508: v2(123,143.45) 123.54,142.92 123.54,140.73 v2(122.92,140.11)
  BOTTOM w0.508: R706.1 99.55,101.72 99.55,102.26 99.29,102.52 99.29,103.07 98.26,104.09 93.52,104.09 91.47,102.04 91.47,102.08 v2(91.5,102.08) ; PC4606.1 122.69,143.77 v2(123,143.45)
  vias: v1(87.29,86.75) v1(87.32,84.46) v1(87.36,82.38) v2(121.87,85.83)
1D05V_HSIO:
  vias: v1(134.96,108.71) v1(143.29,108.29) v3(141.04,107.38) v3(141.03,106.51)
1D5V_PWR:
  vias: v1(147.42,104.67)
1D05V_PWR:
  vias: v1(138.59,125.54) v1(138.59,123.94) v1(138.57,122.2) v1(138.63,120.02) v1(138.59,118.19)
1D05V_S0: length 132.3
  TOP w0.508: v2(152.1,71.15) 152.36,71.4 152.92,71.4 153.52,70.79 153.52,69.37 154.29,68.61 158.63,68.61 159.37,67.87 159.37,65.66 159.95,65.08 160.38,65.08 161.3,64.16 161.6,64.16 v2(161.65,64.22) ; v2(141.12,74.32) 141.12,69.85 143.58,67.39 146.74,67.39 v2(147.33,67.97) ; v2(117.34,148.95) 117.33,148.93 PR4602.1 ; R3608.1 165.32,65.22 165.97,64.57 v2(165.97,64.34) ; v2(196.7,63.26) 196.82,63.38 196.83,63.38 197.32,63.87 197.32,65.09 195.37,67.04 195.37,69.07 196.18,69.89 196.18,72.05 R2401.1
  L3 w0.508: v2(161.65,64.22) 161.83,64.04 164.09,64.04 164.4,64.34 v2(165.97,64.34) 165.97,64.27 166.76,63.48 166.76,62.38 167.52,61.62 167.52,61.27 172.4,56.39 172.85,56.39 173.24,56.01 175.36,56.01 176.14,56.78 176.83,56.78 177.43,56.19 182.22,56.19 182.81,56.78 183.61,56.78 188.35,61.52 v2(188.77,61.52)
  L4 w0.508: v2(138.18,154.21) 138.18,154.22 135.08,151.11 119.39,151.11 117.34,149.05 v2(117.34,148.95)
  BOTTOM w0.508: v2(188.77,61.52) 189.61,62.36 191.57,62.36 192.62,61.32 196.37,61.32 196.7,61.65 v2(196.7,63.26) ; 141.82,140.91 141.82,142.86 139.35,145.32 139.35,148.76 138.18,149.93 v2(138.18,154.21) ; v2(152.1,71.15) 151.82,71.43 149.84,71.43 148.34,69.93 148.34,68.99 v2(147.33,67.97) ; R2105.1 v2(139.04,107.78)
  vias: v1(138.07,113.49) v1(139.89,113.45) v3(127.82,83.62) v3(128.38,84.72) v3(128.91,83.72) v3(129.54,84.64) v3(129.97,83.6) v3(131.47,108.12) v3(132.33,108.09) v3(136.51,110.98) v3(137.24,110.19) v3(137.29,111.71) v3(138.03,110.98) v3(138.82,110.04) v3(138.87,111.71) v3(139.71,110.95) v3(142.61,141.12) v3(142.63,140.24)
1D5V_S0: length 174.4
  TOP w0.508: v2(181.21,89.37) 181.21,89.37 181.12,89.37 181.11,89.36 161.48,89.36 158.76,92.09 158.76,92.71 153.66,97.81 152.67,97.81 148.14,102.34 147.96,102.34 145.14,105.15 145.14,105.36 v3(144.34,106.16) 143.08,106.16 141.92,105.01 v2(141.1,105.01)
  L3 w0.508: v2(141.1,105.01) 138.49,105.01 134.98,101.5 134.98,100.68 134.59,100.28 133.69,100.28 130.08,96.68 130.08,95.31 128.3,93.53 v2(128.3,92.82)
  L4 w0.508: v2(188.52,8.41) 189.07,8.95 192.04,8.95 195.1,12.02 195.1,19.38 196.35,20.63 196.35,39.45 195.61,40.19 195.61,44.07 195.97,44.43 195.99,44.43 197.06,45.5 197.06,46.79 196.48,47.38 196.48,54.31 196.14,54.65 196.14,60.61 197.47,61.94 197.47,65.06 196.11,66.41 196.11,72.31 195.61,72.81 195.61,73.64 196.23,74.25 196.23,87.07 v2(195.29,88.01)
  BOTTOM w0.305: v2(128.3,92.82) 128.33,92.78 128.33,90.2 128.66,89.86 CPU1.J15
  BOTTOM w0.508: R2705.1 188.64,8.53 v2(188.52,8.41) ; v2(195.29,88.01) 195.04,88.01 194.35,88.7 190.54,88.7 190.24,89.01 184.51,89.01 184,89.52 183.25,89.52 183.05,89.72 181.56,89.72 v2(181.21,89.37)
  vias: v1(145.23,106.14)
1D05V_VGA_EN: length 4.8
  TOP w0.127: U8301.3 145.03,137.72 144.95,137.79 C8309.2 144.21,137.78 PR8301.2 143.4,137.78 R8313.2 143.4,139.4 v1(143.26,139.53)
1D05V_VGA_OUT2:
  vias: v1(150.71,139.09)
1D05V_VGA_S0: length 12.3
  BOTTOM w0.635: v3(171.13,128.68) 170.52,128.68 169.63,127.79 161.78,127.79 160.82,126.83 159.84,126.83 v3(159.66,127.01)
  vias: v1(152.75,144.17) v1(154.75,148.7) v1(155.14,146.01) v2(159.06,147.16) v2(159.91,145.54) v2(159.92,144.73) v2(159.89,143.89) v2(160.89,138.84) v2(160.89,138.1) v2(160.87,137.37) v3(151.47,146.93) v3(151.51,145.73) v3(152.77,148.4) v3(152.89,147.06) v3(152.96,145.66) v3(153.73,148.35) v3(153.74,147.3) v3(153.99,146.39) v3(154.47,143.8) v3(154.68,147.36)
1D05V_VGA_S0_DISCHG: length 4.3
  TOP w0.102: PR8316.2 148.76,143.75 v1(148.12,143.1) 147.86,142.84 147.43,142.84 146.81,142.22 PQ8305.3
1D05V_VTT_PWRGD: length 90.8
  TOP w0.127: v2(96.84,137.05) 97.22,137.43 v1(97.25,137.43) ; v2(98.65,102.8) 98.91,102.8 99.49,102.22 99.49,99.9 100.04,99.36 R707.1 100.24,99.22 U701.2 ; PR4821.2 134.48,144.92 134.29,144.73 v2(132.98,144.73)
  L3 w0.127: v2(96.84,137.05) 97.64,137.05 105.72,145.12 111.24,145.12 113.29,147.17 121.22,147.17 121.68,147.63 123.67,147.63 125.09,146.21 125.09,145.99 125.92,145.17 129.88,145.17 130.16,145.44 132.27,145.44 v2(132.98,144.73)
  L4 w0.127: v2(98.65,102.8) 97.44,104.02 97.44,115.38 99.24,117.18 99.25,117.18 100.95,118.87 100.95,129.76 96.83,133.88 96.83,137.04 v2(96.84,137.05)
  BOTTOM w0.127: v2(132.98,144.73) 133.06,144.65 R3611.1
1D35V_ENABLE: length 4.5
  TOP w0.127: R8314.2 171.09,56.22 170.54,55.67 PQ8304.3 ; R8314.2 171.09,56.71 171.36,56.97 v1(171.36,57.28) ; R8314.2 170.7,56.37 170.68,56.35 PR8310.1 170.14,56.35 169.88,56.61 PR8312.1
1D35V_ENABLE_RC: length 29.5
  TOP w0.127: PQ8308.4 152.18,50.8 153.19,51.82 157.59,51.82 158.96,53.19 v1(159.57,53.19) 160.45,54.07 161.59,54.07 166.3,58.78 171.64,58.78 171.75,58.89 173.39,58.89 173.92,58.37 173.92,57.99 173.44,57.51 173.44,56.89 PC8302.1 172.92,56.37 R8314.1
1D35V_PWR: length 1.1
  TOP w0.203: v3(56.99,21.62) 57.22,21.39 PU4901.2
  vias: v1(77.54,20.11) v1(86.11,19.81) v2(57.33,22.28) v3(80.57,19.56) v3(80.57,18.67) v3(81.45,19.56) v3(81.45,18.67) v3(82.47,19.56) v3(82.47,18.67) v3(83.49,19.56) v3(83.49,18.67) v3(84.5,19.56) v3(84.5,18.67)
1D35V_S3: length 78.3
  TOP w0.508: Q1201.G v2(88.49,15.85) ; v3(88.54,16.77) 88.49,16.82 Q1202.D
  BOTTOM w0.203: v2(110.75,76.01) 110.95,76.22 CPU1.AP43 ; v2(116.69,71.2) 116.23,71.66 116.23,72.3 116.26,72.33 CPU1.AY35 ; CPU1.AN33 117.26,76.87 v2(116.96,76.57) ; CPU1.AY40 113.08,72.42 113.08,71.92 v2(113.54,71.45)
  BOTTOM w0.254: CPU1.AH26 121.59,80.1 121.5,80.1 v2(121.22,80.38) ; CPU1.AR48 107.93,75.24 107.81,75.24 v2(107.78,75.21) ; CPU1.AY44 109.97,72.38 110.38,71.96 v2(110.39,71.96) ; v2(114.69,80.42) 114.74,80.37 CPU1.AJ37 ; v2(107.24,72.77) 107.2,72.77 106.88,72.46 CPU1.AY50 ; CPU1.AJ33 v2(117.34,80.51) ; v2(118.64,80.45) CPU1.AJ31
  BOTTOM w0.305: v2(134.31,15.42) 134.45,15.56 DM2.124
  BOTTOM w0.33: v2(125.38,26.25) 125.15,26.02 DM2.93 ; v2(127.25,15.49) 127.25,15.49 DM2.100 ; v2(119.9,26.25) 119.75,26.11 DM2.75 ; v2(129.05,15.49) 129.05,15.49 DM2.106 ; v2(132.65,15.49) 132.65,15.49 DM2.118 ; v2(134.44,26.26) 134.15,25.98 DM2.123 ; DM2.81 121.55,26.25 v2(121.55,26.25) ; v3(94.55,28.53) DM1.106 ; v2(132.26,26.26) 132.35,26.17 DM2.117 ; v2(130.55,26.25) 130.55,26.25 DM2.111 ; v2(121.85,15.49) 121.85,15.49 DM2.82 ; DM1.93 90.65,39.38 v2(90.43,39.6) ; DM1.123 99.65,39.45 v2(99.65,39.45) ; v2(120.05,15.49) 120.05,15.49 DM2.76 ; v3(89.15,28.47) DM1.88 ; DM1.105 94.25,39.37 v2(94.09,39.53) ; v2(86.7,40.29) 87.05,39.94 DM1.81 ; v2(96.3,39.6) 96.05,39.36 DM1.111 ; v3(92.75,28.5) DM1.100 ; v2(97.85,39.45) 97.85,39.45 DM1.117 ; DM2.94 125.45,15.49 v2(125.45,15.49) ; DM1.99 92.45,40.54 v2(92.62,40.72) ; DM2.105 128.75,25.9 129.12,26.28 v2(129.26,26.28) ; DM2.99 126.95,26.03 127.19,26.27 v2(127.51,26.27) ; v2(123.65,15.49) 123.65,15.49 DM2.88 ; v3(90.95,28.39) DM1.94 ; v2(123.11,26.27) 123.35,26.03 DM2.87 ; 99.95,28.45 DM1.124 ; v2(85.25,39.45) 85.25,39.45 DM1.75 ; v3(87.35,28.34) DM1.82 ; 98.15,28.61 DM1.118 ; 96.35,28.6 DM1.112 ; v3(85.55,28.35) DM1.76 ; v2(130.85,15.49) 130.85,15.49 DM2.112 ; v2(88.85,39.45) 88.85,38.17 DM1.87
  BOTTOM w0.508: R410.1 132.82,61.44 132.82,58.94 134.44,57.32 v2(134.44,54.27)
  BOTTOM w0.635: v3(60.69,52.23) 66.53,52.23 v3(67.04,52.73)
  vias: v1(81.1,25.53) v1(83.44,25.58) v1(85.9,25.64) v3(81.64,23.91) v3(82.15,23.14) v3(82.77,23.93) v3(82.79,22.51) v3(83.29,23.27) v3(83.8,24.03) v3(83.8,22.51) v3(84.31,23.27) v3(84.69,22.51) v3(84.82,24.03) v3(85.33,23.27)
1D35V_VGA_EN: length 11.4
  TOP w0.127: PQ8304.2 171.19,54.59 170.61,54.01 168.68,54.01 168.43,53.76 D8301.3 166.86,53.97 R8305.1 167.15,56.32 R8312.2 167.7,56.94 167.45,57.19 167.45,57.63 167.72,57.89 v1(168.24,57.89)
1D35V_VGA_EN#: length 10.6
  TOP w0.127: PQ8304.5 171.19,54.03 171.39,54.22 171.62,54.22 171.84,54 PQ8304.6 171.84,52.39 171.67,52.22 171.29,52.22 171.02,51.94 PR8311.2 PR8314.2 ; v1(171.9,50.65) 171.91,50.65 PR8314.2 ; PR8314.2 172.91,52.62 172.91,53.68 173.72,54.49 PQ8306.G
1D35V_VGA_S0: length 99
  TOP w0.178: VRAM8.K8 157.2,163.17 v2(157.2,162.37) ; v2(187.17,146.54) 187.63,147 187.63,148.14 VRAM6.H2 188.4,148.11 v2(189.2,148.11) ; v2(176.86,162.42) 176.79,162.35 176.02,162.35 175.64,161.97 VRAM7.H2
  TOP w0.18: v2(189.22,140.84) 189.2,140.82 189.2,139.72
  TOP w0.305: RN7511.3 v2(183.08,165.77)
  TOP w0.356: v2(172.11,161.53) 171.96,161.53 VRAM7.G7 ; v2(155.42,159.72) 155.58,159.57 VRAM8.E9 ; VRAM7.C1 176.52,158.09 176.89,158.09 v2(177.09,158.29) ; VRAM5.K2 v2(189.2,134.12) ; VRAM8.H2 162,161.57 v2(162,161.57) ; VRAM8.B2 v2(162,156.77) VRAM8.A1 ; VRAM7.C9 169.57,157.97 v2(169.4,158.14) ; v2(156.4,163.18) 156.79,163.57 VRAM8.K8 ; VRAM8.F1 162.43,160.37 v2(162.83,159.97) ; v2(185.6,133.07) 185.75,133.07 VRAM5.F1 ; VRAM5.D9 184.8,140.85 v2(184.74,140.91) ; VRAM6.D9 184.8,154.58 v2(184.71,154.67) ; VRAM6.H9 187.97,154.11 v2(187.57,153.71) ; VRAM6.E9 185.6,154.6 v2(185.44,154.76) ; VRAM7.D9 169.96,158.81 v2(169.44,158.81) ; 176,163.17 176,163.17 VRAM7.K2 ; VRAM5.H2 v2(187.6,134.92) ; v2(192.05,140.71) 192,140.66 VRAM5.N9 ; v2(155.28,165.99) 155.3,165.97 VRAM8.N9 ; v2(182.8,153.67) 182.76,153.67 VRAM6.A8 ; v2(193.93,147.22) 193.93,147.24 193.6,147.57 VRAM6.R1 ; VRAM8.C9 v2(155.44,157.97) ; v2(187.6,138.92) 187.6,138.92 VRAM5.G7 ; VRAM7.K8 171.2,163.17 v2(171.2,163.17) ; VRAM5.B2 v2(182.8,134.12) VRAM5.A1 ; v2(177.04,159.57) 176.93,159.67 176.93,159.84 VRAM7.F1 ; VRAM5.C1 v2(184.4,134.12) VRAM5.D2 ; RN7522.3 182.68,167.34 v2(183.08,167.74) ; VRAM6.F1 186.4,147.06 v2(186.44,147.02) ; VRAM8.N1 162.88,165.97 v2(162.97,165.87) ; VRAM5.A8 182.4,139.32 v2(182.8,139.72) ; VRAM5.R1 v2(193.6,133.08) ; VRAM8.R9 v2(155.28,167.57) ; VRAM7.R9 169.36,167.57 v2(169.33,167.53) ; v2(189.2,148.11) 189.6,148.51 VRAM6.K2 ; VRAM7.B2 175.61,157.17 v2(176,157.57) ; v2(154.84,162.38) 155.59,162.38 VRAM8.H9 ; v2(188.09,140.84) 188,140.75 VRAM5.H9 ; VRAM8.G7 157.61,161.17 v2(157.99,161.56) ; VRAM7.D2 175.61,158.77 v2(176,158.38) ; v2(170.4,156.77) 170.8,156.37 VRAM7.A8 ; VRAM6.C1 184,147.33 v2(183.81,147.15) ; VRAM8.K2 161.98,163.19 161.99,163.19 v2(162,163.17) ; VRAM6.A1 182.4,147.71 v2(182.8,148.11) 182.8,148.11 VRAM6.B2 ; VRAM5.N1 v2(192,133.13)
  TOP w0.4: VRAM7.R1 v2(177.04,167.57) ; VRAM5.K8 189.2,139.72 ; VRAM7.N1 v2(176.99,165.97)
  TOP w0.508: PR8315.1 v2(174.8,57.62)
  L4 w0.254: v2(187.17,146.54) 187.54,146.9 187.54,148.23 187.12,148.65 187.12,149.75 187.3,149.93 v2(187.3,150.32)
  L4 w0.508: v2(177.54,50.42) 177.53,53.58 174.8,56.31 v2(174.8,57.62)
  BOTTOM w0.18: v2(189.22,140.84) 189.2,140.82 189.2,139.77 ; VRAM1.H2 188.37,139.69 188.37,140.56 v2(188.09,140.84)
  BOTTOM w0.305: v2(187.6,134.92) VRAM1.G7
  BOTTOM w0.356: v2(192.05,140.71) 192,140.66 VRAM5.N9 ; v2(171.53,148.87) 171.51,148.85 171.49,148.85 GPU1.H24 ; v2(177.09,158.29) 176.89,158.09 176.52,158.09 VRAM7.C1 176.4,157.96 v2(176,157.57) ; VRAM6.C1 184,147.33 v2(183.81,147.15) ; v2(162.97,165.87) 162.88,165.97 VRAM8.N1 ; VRAM3.D9 176.39,158.77 v2(176,158.38) ; VRAM8.R1 162.79,167.57 v2(162.94,167.72) ; VRAM2.B2 182.84,153.67 v2(182.8,153.67) 182.8,153.71 VRAM2.A1 ; v2(187.3,150.32) 187.2,150.22 VRAM2.G7 ; GPU1.C25 GPU1.B26 176.63,150.65 v2(176.64,150.65) ; v2(156.42,155.92) 156,156.33 VRAM4.A1 ; VRAM3.E9 177.03,159.57 v2(177.04,159.57) ; v2(189.2,148.11) 189.45,148.36 189.45,148.36 VRAM6.K2 ; VRAM3.D2 VRAM7.C9 ; VRAM2.H2 187.96,153.31 v2(187.57,153.71) ; VRAM8.K2 161.6,163.57 v2(162,163.17) ; GPU1.L24 169.01,148.09 169.04,148.09 v2(169.07,148.06) ; v2(185.56,147.12) 185.56,147.67 VRAM2.E9 ; VRAM2.D2 184.79,153.31 184.4,153.7 v2(184.38,153.7) ; 189.2,139.77 189.6,139.37 VRAM5.K8 ; VRAM2.A8 182.41,148.51 v2(182.8,148.11) ; v2(171.51,150.47) 171.11,150.08 GPU1.H26 ; VRAM2.D9 184.8,147.27 v2(184.68,147.15) ; VRAM6.K8 189.6,153.35 v2(189.23,153.72) ; VRAM4.A8 v2(162,156.77) ; VRAM1.H2 187.6,138.92 v2(187.6,138.92) ; GPU1.E23 v2(174.03,148.04) ; VRAM8.K8 156.79,163.57 v2(156.4,163.18) ; v2(155.28,165.99) 155.3,165.97 VRAM8.N9 ; VRAM1.D9 v2(184.4,134.12) VRAM5.C1 ; v2(184.4,139.72) 184,140.12 VRAM5.C9 ; v2(169.33,167.53) 169.47,167.53 169.51,167.57 VRAM7.R9 ; VRAM5.R9 193.6,140.69 v2(193.6,140.69) ; v2(157.2,162.37) 156.8,161.97 VRAM4.H2 ; v2(155.44,157.97) VRAM8.C9 ; v2(173.95,150.55) 173.95,150.42 GPU1.E26 ; VRAM5.N1 v2(192,133.13) ; VRAM5.K2 v2(189.2,134.12) ; GPU1.L26 168.66,150.07 v2(169.07,149.66) ; VRAM1.E9 v2(185.6,133.07) ; VRAM7.N9 169.14,165.97 v2(169.14,165.97) ; VRAM8.R9 v2(155.28,167.57) ; v2(193.6,133.08) VRAM5.R1 ; VRAM1.A8 v2(182.8,134.12) ; v2(186.4,140.73) VRAM1.F1
  BOTTOM w0.4: v2(184.4,139.72) 184.8,139.32 VRAM1.D2 ; VRAM7.N1 v2(176.99,165.97) ; VRAM7.R1 v2(177.04,167.57)
  BOTTOM w0.508: EC9751.1 v2(195.56,84.71) ; C7524.1 166.35,160.04 167.86,160.04 v2(167.88,160.06) ; v2(194.44,90.81) 194.13,90.5 EC9752.1 193.87,90.12 EC9753.1 ; v2(189.22,140.84) v2(189.22,142.24)
  vias: v1(152.7,172.07) v1(175.72,172.77) v1(184.17,169.03) v1(193.62,172.65) v1(194.62,163.32) v1(195.26,167.11) v1(197.59,168.43) v1(198.52,151.29) v2(153.04,168.03) v2(153.04,167.16) v2(153.02,166.3) v2(152.99,161.07) v2(153.09,170.57) v2(153.96,170.57) v2(154.82,170.57) v2(156.19,170.57) v2(157.08,170.57) v2(161.44,145.7) v2(162.32,145.57) v2(162.83,158.34) v2(163.19,145.58) v2(164.06,145.55) v2(165.39,157.46) v2(165.58,158.4) v2(168.99,160.54) v2(169.46,162.35) v2(171.01,144.99) v2(170.99,144.12) v2(171.52,141.55) v2(171.64,140.59) v2(181.04,172.47) v2(182.04,172.38) v2(184.02,154.66) v2(191.95,154.7) v2(192.18,161.98) v2(193.67,154.89) v3(183.27,172.07) v3(185.12,172.06) v3(187.15,172.1) v3(188.36,170.45) v3(189.49,171.91) v3(190.3,170.04) v3(191.45,171.04) v3(192.08,51.39) v3(192.08,50.17) v3(192.15,52.59) v3(192.91,53.35) v3(193,166.22) v3(193.03,52.06) v3(192.99,49.5) v3(193.05,50.87) v3(194.04,164.29) v3(194.32,168.56) v3(197.81,129.79) v3(198.22,128.93) v3(198.75,129.88) v3(199.05,130.69) v3(199.26,129.01) v3(199.71,129.8) v3(200.17,130.68) v3(200.35,129.04) v3(200.8,129.91)
1D35V_VTT_PWRGD: length 346.3
  TOP w0.127: R3610.1 v2(135.19,142.99) ; v2(56.85,26.32) 56.75,26.32 56.45,26.02 56.45,25.04 56.81,24.68 PR4904.2 56.81,24.53 58.74,22.6 PU4901.20
  L3 w0.127: v2(135.19,142.99) 138.64,146.44 141.07,146.44 141.28,146.44 142.3,147.46 142.3,147.46 142.52,147.68 143.92,147.68 v2(145.98,149.74) ; v2(193.84,40.97) 193.31,41.5 183.51,41.5 181.98,39.97 179.34,39.97 175.75,36.39 174.15,36.39 173.67,35.91 172.53,35.91 166.17,29.54 v2(160.56,29.54) ; v2(188.92,80.82) 188.29,81.46 188.29,83.66 186.12,85.83 184.44,85.83 183.11,87.16 182.78,87.16 179.07,90.87 164.85,90.87 153.65,102.07 153.65,110.77 154.53,111.65 154.53,117.65 154.78,117.9 154.78,120.45 154.12,121.12 154.12,123.95 v2(154.58,124.4) ; v2(56.85,26.32) 56.85,27.43 57.39,27.96 57.39,50.07 60.81,53.5 60.94,53.5 61.37,53.94 v2(61.37,54.89)
  L4 w0.127: v2(193.84,40.97) 193.05,40.97 191.5,42.52 191.5,44.61 190.81,45.29 190.81,45.6 190.81,45.6 190.81,46.39 188.72,48.49 188.72,53.61 190.8,55.7 190.8,56.78 191.31,57.29 191.31,58.73 190.5,59.54 190.5,60.91 190.24,61.16 190.24,62.16 190.44,62.37 190.44,64.32 189.77,65 189.77,68.66 190.28,69.17 190.28,70.31 190.02,70.56 190.02,72.38 187.85,74.55 187.62,74.55 187.22,74.95 187.22,77.28 188.31,78.38 188.31,79.67 188.81,80.17 188.81,80.62 188.92,80.74 v2(188.92,80.82)
  BOTTOM w0.127: v2(154.58,124.4) 154.57,124.41 154.36,124.41 153.25,125.52 152.68,125.52 152.12,124.96 151.72,124.96 150.99,125.68 148.52,125.68 145.99,128.22 145.99,131.8 146.69,132.51 146.69,141.32 145.54,142.47 145.54,149.04 145.98,149.48 v2(145.98,149.74) ; v2(61.37,54.89) 62.64,53.62 121.87,53.62 125.63,49.86 125.64,49.86 v1(143.05,32.44) 144.7,30.79 159.06,30.79 160.31,29.54 v2(160.56,29.54)
3D3V_AUX_KBC: length 376.5
  TOP w0.508: R2403.2 182.15,61.9 181.46,61.9 181.46,61.42 181.16,61.11 R2434.1 v2(181.82,60.8) ; D4303.2 184.65,177.88 184.68,177.91 v2(184.68,178.04) ; D4302.2 175.74,178.43 v2(175.79,178.48) ; v2(141.49,119.2) 140.5,118.22 130.8,118.22 v2(130.19,117.61) ; v2(175.44,78.45) 175.44,78.69 174.8,79.33 R2413.2 173.65,79.84 172.42,81.07 172.42,83.73 v2(173.25,84.56) ; v2(189.23,178.3) 189.23,177.52 D4301.2 ; Q2402.D 170.85,78.26 v2(172.37,76.74) 172.55,76.56 R2414.2 ; v2(195.54,76.15) 195.55,76.14 R2436.1 ; R2418.2 174.82,73.81 175.05,73.58 175.31,73.58 v2(175.37,73.52) ; v2(173.56,51.56) 173.49,51.62 PR8314.1
  L3 w0.508: v2(172.37,76.74) 174.08,78.45 v2(175.44,78.45) 179.69,78.45 181.22,76.92 185.35,76.92 v2(186.19,77.75) 187.05,76.89 187.05,75.9 187,75.85 187,74.35 183.38,70.73 183.38,68.32 181.48,66.42 181.48,61.14 v2(181.82,60.8) ; v2(100.52,162.06) 100.59,162.06 101.15,162.62 101.15,163.05 103.41,165.31 103.42,165.31 103.83,165.71 v2(103.83,166.03) 102.32,167.54 101.45,167.54 101.07,167.91 101.07,170.57 104.57,174.07 108.49,174.07 109.89,175.47 121.85,175.47 122.49,176.1 125.1,176.1 126.5,177.5 141.69,177.5 146.29,172.9 156.11,172.9 157.01,173.8 157.01,175.01 158.93,176.93 168.39,176.93 173.94,176.93 175.49,178.48 v2(175.79,178.48) 180.78,178.48 181.46,179.16 183.4,179.16 184.53,178.04 v2(184.68,178.04) 188.97,178.04 v2(189.23,178.3) ; v2(182.99,55.43) 182.65,55.09 174.36,55.09 173.56,54.29 173.56,51.56 v2(173.56,51.56)
  L4 w0.508: v2(130.19,117.61) 130.41,117.61 131.48,116.53 131.48,116.48 133.3,114.67 133.3,113.35 v2(134.77,111.88) ; v2(173.25,84.56) 173.21,84.56 169.23,88.55 163.43,88.55 152.19,99.78 152.19,100.35 148.43,104.11 148.43,105.22 148.62,105.41 148.62,114.43 143.85,119.2 v2(141.49,119.2) ; v2(181.82,60.8) 181.82,59.27 183.01,58.08 183.01,55.45 v2(182.99,55.43) ; v2(185,83.93) 184.97,83.93 184.97,83.89 187.17,81.69 187.27,81.69 187.64,81.32 187.64,80.55 187.23,80.14 187.23,79.25 186.24,78.26 186.24,77.8 v2(186.19,77.75) ; v2(172.37,76.74) 172.4,76.74 173.21,75.92 173.21,75.87 174.4,74.69 174.4,74.05 174.93,73.52 v2(175.37,73.52) ; v2(195.44,82.82) 195.44,81.55 194.96,81.07 194.96,76.48 195.23,76.2 195.49,76.2 v2(195.54,76.15) ; v2(100.52,162.06) 100.52,162.06 100.52,160.44 97.92,157.84 97.92,156.37 97.95,156.34 98,156.29 98,152.29 104.21,146.08 120.34,146.08 120.51,146.08 121.37,146.08 122.13,146.84 127.47,146.84 128.09,146.22 135.43,146.22 136.11,145.54 136.11,141.1 v2(136.07,141.06)
  BOTTOM w0.508: v2(134.77,111.88) 134.39,111.5 R2608.1 ; PR4439.1 v2(103.83,166.03) ; v2(185,83.93) 184.55,83.93 184.26,83.64 R2453.2 184.77,82.48 v1(185.65,82.48) 186.19,82.48 186.19,82.47 190.64,82.47 191.42,83.24 192.26,83.24 193.04,82.46 194.62,82.46 194.98,82.82 v2(195.44,82.82) ; R2607.1 130.32,117.48 v2(130.19,117.61) ; v2(141.49,119.2) 141.49,119.6 140.76,120.33 140.76,121.07 141.12,121.43 141.12,125.47 137.68,128.9 137.68,139.44 v2(136.07,141.06)
3D3V_AUX_KBC_VCC: length 89.6
  TOP w0.203: C2406.1 194.24,77.81 194.24,76.67 193.56,75.98 KBC24.19 ; v2(178.4,76.62) 178.35,76.62 178.19,76.78 KBC24.76 ; C2407.1 174.24,70.9 175.39,70.9 176.48,71.99 KBC24.88 ; KBC24.46 186,83.79 v2(186.08,83.88) ; KBC24.115 186,65.74 186.32,65.42 186.46,65.42 C2408.1
  TOP w0.508: C2406.1 195.3,78.87 C2411.1 195.86,79.08 196.77,80 196.77,85.53 v2(195.57,86.74) ; C2408.1 187.06,65.32 187.33,65.05 187.33,63.34 v2(186.71,62.72) 185.48,61.49 R2403.1 ; v2(174.67,70.41) C2407.1
  L3 w0.508: v2(174.67,70.41) 177.52,73.26 177.52,75.75 v2(178.4,76.62) ; v2(186.88,77.98) 187.89,76.96 187.89,75.8 188.3,75.4 188.3,74.73 184.01,70.45 184.01,67.91 v2(182.15,66.04) 182.15,65.16 182.75,64.56 182.75,63.05 183.38,62.42 186.41,62.42 v2(186.71,62.72)
  L4 w0.508: v2(186.08,83.88) 188.27,81.68 188.27,80.27 187.87,79.86 187.87,78.97 v2(186.88,77.98)
  BOTTOM w0.508: C2409.1 178.32,76.54 v2(178.4,76.62) ; v2(195.57,86.74) 195.57,86.72 194.35,85.5 192.78,85.5 C2410.1 192.31,85.45 190.16,83.29 186.66,83.29 v2(186.08,83.88) ; v2(182.15,66.04) 178.35,66.04 177.7,66.7 177.7,67.39 176.83,68.26 176.83,68.26 176.46,68.63 176.45,68.63 v1(175.86,69.22) 175.86,69.23 v2(174.67,70.41)
3D3V_AUX_S5: length 555.7
  TOP w0.203: KBC24.75 178.54,77.19 179,76.72 179,76.6 179.64,75.96 v2(179.64,75.77)
  TOP w0.508: v2(37.42,60.09) 37.3,59.97 PR4501.1 ; PR8313.1 142.9,145.98 142.24,146.64 v2(142.15,146.64) ; R3607.1 28.41,17.21 27.97,17.65 27.97,17.95 27.94,17.98 v2(27.94,18.95) ; v2(168.99,51.27) 169.02,51.31 169.39,51.31 169.71,51.62 PR8311.1 ; v2(179.62,60.75) 179.67,60.8 R2434.2 ; v2(135.09,113.61) 135.09,113.64 137.16,113.64 138,114.49 v2(141.73,114.49) ; v2(169.17,62.77) 169.32,62.77 169.88,63.33 R2439.1 ; R2425.2 172.9,67.8 172.48,67.37 172.48,67.37 172.1,67 172.1,67 172.06,66.95 171.26,66.95 v2(171.07,67.14) ; D2501.1 31.14,9.98 v2(31.02,9.86) ; v2(170.55,76.82) 170.55,76.85 170.12,77.28 Q2402.S
  L3 w0.508: v2(142.15,146.64) 143.78,146.64 146.62,149.47 146.62,150.68 144.99,152.31 144.99,156.29 141.83,159.45 136.29,159.45 134.37,161.37 134.37,169.8 129.79,174.38 124.9,174.38 124.04,173.51 114.82,173.51 111.72,170.41 109.38,170.41 107.07,168.1 107.07,167.31 105.65,165.9 104.94,165.9 v2(102.9,163.86) 101.94,162.89 101.94,158.48 101.35,157.89 101.35,155.86 102.64,154.57 104.23,154.57 105.02,155.36 106.97,155.36 107.02,155.31 v2(107.02,155.3) ; v2(165.82,18.32) 165.97,18.17 165.97,16.9 164.3,15.23 161.62,15.23 154.78,8.4 93.13,8.4 91.74,9.79 65.85,9.79 65.5,9.44 54.98,9.44 49.38,15.04 49.38,17.21 45.6,20.99 45.51,20.99 45.15,20.99 45.15,20.99 39.86,20.99 39.64,21.21 34.63,21.21 32.37,18.95 v2(27.94,18.95) 27.94,18.95 24.96,21.92 24.96,28.52 23.16,30.32 23.16,36.95 24.19,37.99 24.19,39.52 25.19,40.53 25.19,47.96 35.52,58.29 35.62,58.29 v2(37.42,60.09) ; v2(169.17,62.77) 169.17,62.34 v2(170.8,60.71) 179.58,60.71 v2(179.62,60.75) ; v2(169.01,72.73) 170.57,74.28 170.57,76.8 v2(170.55,76.82) ; v2(159.39,51.11) 159.49,51.01 168.73,51.01 v2(168.99,51.27) ; v2(171.07,67.14) 171.22,67 173.74,67 175.7,65.04 178.13,65.04 182.11,69.01 182.11,70.99 179.9,73.2 179.9,75.51 v2(179.64,75.77)
  L4 w0.508: v2(110.14,153.4) 107.55,153.4 107.14,152.99 105.19,152.99 104.71,153.47 104.71,154.97 105.14,155.4 106.92,155.4 v2(107.02,155.3) ; v2(160.47,48.57) 160.47,47.04 162.62,44.89 162.62,41.59 162.59,41.55 162.59,38.51 163.81,37.28 163.81,34.58 164.38,34.02 164.38,33.56 166,31.94 166,18.5 v2(165.82,18.32) ; v2(142.15,146.64) 141.99,146.64 140.34,145 140.34,123.37 139.64,122.67 139.64,116.57 v2(141.73,114.49) 143.72,112.49 143.72,107.06 143.49,106.83 143.49,102.26 146.3,99.45 146.39,99.45 147.56,98.29 147.56,97.71 148.31,96.96 148.33,96.96 149.88,95.41 150.68,95.41 151.71,94.38 151.71,93.68 152.09,93.3 152.19,93.3 153.73,91.76 153.73,91.23 157.16,87.8 157.93,87.8 161.45,84.28 164.53,84.28 165.38,83.43 165.38,82.69 167.6,80.47 167.6,79 168.84,77.75 169.55,77.75 170.48,76.82 v2(170.55,76.82) ; v2(169.01,72.73) 169.01,72.69 171.04,70.67 171.04,69.64 171.33,69.35 171.33,68.4 170.95,68.02 170.95,67.26 v2(171.07,67.14) 171.07,66.98 170.87,66.78 170.87,66.42 170.65,66.2 170.65,64.92 170.8,64.77 v2(170.8,60.71)
  BOTTOM w0.508: R2609.1 134.26,112.34 134.76,112.84 134.76,112.84 135.09,113.17 v2(135.09,113.61) ; v2(31.02,9.86) 33.44,9.86 34.91,11.32 34.91,11.85 33.89,12.87 33.89,14.45 34.02,14.57 34.02,17.85 32.92,18.95 v2(27.94,18.95) ; v2(37.42,60.09) 37.99,59.52 v1(38.69,59.52) 39.13,59.52 40.1,58.56 PR4532.2 ; v2(107.02,155.3) 107.03,155.31 107.03,156.99 106.42,157.6 PR4434.1 ; v2(110.14,153.4) 110.13,153.4 109.82,153.7 PR4419.1 109.81,154.08 109.81,154.72 110.27,155.17 110.27,155.23 110.64,155.6 110.68,155.6 PR4438.2 ; C2417.2 168.72,74.25 R2431.2 168.72,73.15 169.01,72.86 v2(169.01,72.73) ; v2(168.99,51.27) 168.78,51.27 168.56,51.06 167.69,51.06 167.22,51.53 167.22,51.89 166.81,52.29 166.81,52.82 169.27,55.28 169.27,59.44 170.56,60.73 170.8,60.73 v2(170.8,60.71) ; v2(159.39,51.11) 159.39,50.53 159.65,50.27 R1726.2 159.64,49.24 R1727.1 160.29,48.4 v2(160.47,48.57) ; v2(102.9,163.86) 103.19,164.15 PR4435.1 104.59,163.53 PR4417.1
3D3V_CAMERA_S0: length 1.4
  TOP w0.305: 79.79,161.04 79.51,161.32 LCD1.32
  vias: v1(82.59,160.2) v3(81.8,159.64)
3D3V_CARD_S0: length 13.2
  TOP w0.762: v3(21.18,16.85) 21.18,19.11 18.67,21.62 13.25,21.62 v3(11.85,20.23)
  vias: v1(22.84,17.03) v3(23.98,16.41)
3D3V_LAN_S5: length 4
  TOP w0.203: 48.33,166.13 LOM30.11
  BOTTOM w0.508: v3(45.42,164.98) 46.25,164.98 C3017.1
  vias: v1(57.69,174.46) v3(44.56,165.02) v3(45.45,172.03) v3(54.06,163.94) v3(56.42,163.63) v3(56.54,174.23) v3(56.54,173.06)
3D3V_PWR:
  vias: v1(38.74,32.43) v1(38.68,29.91)
3D3V_PWR_2: length 4.1
  TOP w0.203: PU4503.3 41.54,57.74 41.41,57.86 v2(41.41,57.81)
  BOTTOM w0.508: v1(41.59,57.14) 41.59,57.63 v2(41.41,57.81) 41.46,57.81 41.54,57.9 41.57,57.9 41.84,58.16 PR4532.1 41.97,58.69 PC4526.1
3D3V_S0: length 653.7
  TOP w0.203: KBC24.4 193.49,69.99 193.76,69.72 193.79,69.72 v2(194.44,69.07)
  TOP w0.305: U5502.20 28.14,59.47 C5522.1 ; v2(28.12,67.51) 28.14,67.48 U5502.5
  TOP w0.406: Q2601.2 128.78,116.17 v2(129,115.94)
  TOP w0.508: C2601.1 123.62,113.4 v2(123.61,113.4) ; v3(134.83,141.84) 134.64,141.84 133.66,142.82 133.66,142.99 R3601.1 ; R2033.1 143.11,103.49 v2(144.13,104.51) 144.87,103.76 R2023.1 ; v2(162.85,74.2) 162.71,74.33 162.71,77.54 163.44,78.27 163.44,81.41 162.53,82.32 161.38,82.32 v2(157.92,85.78) ; C1203.1 122.33,39.38 v2(122.23,39.48) ; R3014.1 55.46,167.85 56.4,168.79 59.38,168.79 60.75,167.42 63.84,167.42 65.82,165.43 71.34,165.43 v2(72.07,164.71) ; v2(134.32,100.92) 134.22,100.82 131.31,100.82 C2128.1 131.29,100.82 130.4,100.82 127.85,98.26 127.85,95.16 127.66,94.98 127.66,92.18 128.07,91.77 128.07,87.35 128.93,86.49 129.65,86.49 v2(129.68,86.47) ; R5503.1 22.86,67.78 v2(22.11,68.53) ; v3(161.35,27.54) 160.95,27.93 157.68,27.93 v2(156.83,27.08) 156.64,26.89 R1302.1 156.57,26.26 C1311.1 ; R1510.1 144.99,86.16 145.19,85.96 145.6,85.96 v2(145.9,85.65) ; v2(194.29,83.95) 194.55,84.2 194.55,84.61 R2415.2 ; R4622.1 118.22,148.68 v3(118.72,149.18) ; R6212.1 v2(49.15,79.78) ; R5219.2 83.92,171.37 v2(84.46,170.82) ; 150.94,95.35 v2(152.35,93.94) ; PR4904.1 54.55,24.54 53.34,25.75 51.19,25.75 v2(51.12,25.68) ; Q6103.G 43.19,8.7 R6110.1 43.2,9.08 41.5,10.77 40.46,10.77 39.98,11.26 v2(39.98,12.24)
  TOP w0.762: v3(11.92,15.4) 14.71,12.61 23.23,12.61 v3(23.55,12.93)
  L3 w0.508: v2(85.79,156.43) 85.79,157.94 85.17,158.55 85.17,160.91 85.18,160.92 85.18,162.34 v2(85.2,162.36) ; v2(129,115.94) 124.3,115.94 v2(123.55,116.69) 123.55,117.21 126,119.66 131.96,119.66 132.29,119.99 135.09,119.99 140.27,125.18 140.27,131.13 v3(143.11,133.96) ; v3(141.84,144.26) 139.21,144.26 136.8,141.84 v3(134.83,141.84) ; v2(196.32,46.36) 196.27,46.41 187.44,46.41 186.65,45.62 182.73,45.62 181.98,44.87 174.38,44.87 169.72,40.22 169.21,40.22 166.63,37.64 v3(166.63,36.64) ; v2(152.68,69.2) 156.32,69.2 v2(156.55,69.43) 156.37,69.61 156.37,72.09 156.89,72.61 158.23,72.61 159.67,71.17 161.11,71.17 161.84,71.9 161.84,72.11 v2(161.86,72.13) 162.25,72.13 162.85,72.72 v2(162.85,74.2)
  L3 w0.762: 36.35,12.93 v3(23.55,12.93) 23.06,13.43 23.06,16.5 19.19,20.37 19.19,25.53 18.79,25.92 18.79,36.1 17.51,37.38 17.51,38.22 18.99,39.7 18.99,46.42 17.96,47.45 17.96,51.74 21.58,55.36 22.34,55.36 v2(24.42,57.43) 24.87,57.89 24.87,63.27 28.12,66.52 v2(28.12,67.51) ; v2(27.9,80.5) 27.9,74.32 v2(22.11,68.53)
  L3 w1.016: v3(143.11,133.96) 143.11,135.46 140.3,138.27 140.3,142.11 140.71,142.52 140.71,142.52 141.84,143.66 v3(141.84,144.26)
  L4 w0.508: v2(187.79,8.37) 187.59,8.56 179.74,8.56 177.22,11.09 174.64,11.09 174.15,11.58 174.15,13.45 176.54,15.85 176.54,19.62 175.85,20.31 175.85,22.54 v2(176.11,22.8) 176.11,27.58 174.73,28.96 174.73,31.47 175.63,32.37 v3(175.63,35.82) ; v2(79.1,156.37) 72.07,163.4 v2(72.07,164.71) ; v2(196.32,46.36) 195.84,46.84 195.84,54.05 195.34,54.55 195.34,62.48 195.76,62.9 195.76,63.64 195.69,63.72 195.69,64.21 v2(195.69,64.21) 195.69,65.01 194.44,66.26 v2(194.44,69.07) 194.72,69.35 194.72,71.5 194.07,72.15 194.07,75.61 193.83,75.85 193.83,81.96 193.34,82.45 193.34,83.06 194.02,83.74 194.08,83.74 v2(194.29,83.95) ; v2(125.03,117.49) 125.73,116.8 130.32,116.8 130.85,116.27 130.85,115.03 v2(131.58,114.3) 131.65,114.23 131.65,112.25 136.61,107.29 136.61,103.29 v3(138.01,101.9)
  L4 w1.016: v3(118.72,149.18) 119.76,150.22 136,150.22 v3(139.22,153.45)
  L4 w3.048: 45.17,24.06 49.5,24.06 v2(51.12,25.68) 53.98,28.55 53.98,36.25 57.39,39.65 57.39,49.74 55.38,51.74 55.38,56.06 60.81,61.5 60.81,63.02
  BOTTOM w0.254: v2(129.68,86.47) 129.54,86.47 129.02,86.99 129.02,88.38 129.27,88.63 CPU1.K14 CPU1.K16
  BOTTOM w0.305: v2(156.83,27.08) 156.95,26.96 DM2.199
  BOTTOM w0.33: v2(122.23,39.48) 122.45,39.26 122.45,38.72
  BOTTOM w0.356: RN1810.2 162.1,71.89 v2(161.86,72.13) 161.86,72.03 161.45,71.61 RN1810.1 ; Q5401.C 29.22,78.74 29.68,79.21 31.51,79.21 31.82,78.9 Q5402.2 Q5402.5 ; C2602.1 124.74,113.23 THM26.1 ; 122.45,38.72 DM1.199 122.45,36.13 122.94,35.64 125.05,35.64
  BOTTOM w0.406: Q1801.2 155.58,69.43 v2(156.55,69.43) ; Q1801.5 152.91,69.43 v2(152.68,69.2)
  BOTTOM w0.508: v2(27.9,80.5) 26.92,79.52 Q5401.C ; v2(187.79,8.37) 187.75,8.41 R2710.1 ; R1701.1 166.16,85.78 v2(157.92,85.78) 157.8,85.66 156.95,85.66 156.57,86.04 156.57,87.17 153.52,90.22 153.52,91.8 152.35,92.98 v2(152.35,93.94) ; v2(48.93,77.01) 48.85,77.01 48.85,77.01 R6217.1 ; v2(162.85,74.2) 163.06,73.98 R5607.1 ; R2604.1 124.26,116.68 123.56,116.68 v2(123.55,116.69) ; R5208.1 72.7,165.35 v2(72.07,164.71) ; C2602.1 v2(123.61,113.4) ; U5504.3 27.62,50.55 30.16,53.09 U5504.8 30.16,56.42 v3(31.02,57.28) 31.1,57.21 ; v2(195.69,64.21) 195.34,64.57 195.34,64.94 195.25,65.03 194.85,65.43 191.87,65.43 191.54,65.76 R2443.2 192.12,67.06 C2413.1 192.24,67.69 C2412.1 192.22,68.65 R1714.2 ; v2(85.2,162.36) 84.61,162.95 84.61,170.67 v2(84.46,170.82) ; R2701.1 v2(176.11,22.8) ; v2(131.58,114.3) 131.58,114.46 132.15,115.03 R2603.1 ; v2(22.11,68.53) 22.11,68.48 22.61,67.97 v1(23.92,67.97) 27.65,67.97 v2(28.12,67.51) 27.73,67.11 C5520.1
  BOTTOM w0.762: v3(161.35,27.54) 158.78,30.1 144.19,30.1 134.24,40.06 130.6,40.06 128.66,38.12 128.66,37.19 127.11,35.64 125.05,35.64
  BOTTOM w1.016: v3(139.22,153.45) 139.22,152.18 140.47,150.93 140.47,145.63 v3(141.84,144.26)
  vias: v1(25.61,58.3) v2(145.78,98.21) v2(145.9,97.21) v2(146.03,93.63) v2(146.04,91.92) v3(36.43,14.79) v3(36.68,13.95) v3(37.35,14.79) v3(37.52,13.96) v3(38.18,14.84) v3(60.96,65.97) v3(61.59,66.82) v3(61.94,65.75) v3(62.62,66.54) v3(78.16,86.2) v3(78.19,85.36) v3(79.11,86.25) v3(90,143.65) v3(90.64,143.01) v3(91.28,142.37) v3(98.37,139.95) v3(161.48,26.25) v3(163.17,13.92) v3(164.06,13.92) v3(174.76,35.82)
3D3V_S5: length 661.9
  TOP w0.356: RN1701.1 169.19,83.83 v2(168.97,84.05) 168.97,84.02 168.54,83.59 RN1701.2 ; U701.5 99.59,98.7 C702.1 ; RN2006.1 167.11,82.8 166.93,82.98 v2(166.86,82.98) 166.63,82.98 166.46,82.8 RN2006.2
  TOP w0.508: PR4472.1 110.96,167.62 109.54,169.04 108.27,169.04 107.23,168 v2(106.28,168) ; v2(150.88,87.56) 150.88,88.16 149.89,89.15 149.89,92.81 v2(151.07,93.99) ; PR4534.1 v2(35.82,55.52) ; v2(145.37,79.86) 145.54,79.7 R1703.1 ; v2(102.09,175.77) 102.53,175.33 102.53,173.63 103.91,172.25 PR4473.2 ; v2(157.28,86.29) 157.28,85.33 159.57,83.04 159.57,81.26 v3(158.86,80.54) 157.74,79.43 157.74,77.4 152.43,72.09 152,72.09 151.26,71.35 151.26,70.29 151.85,69.7 151.85,68.34 151.54,68.03 149.32,68.03 147.84,66.55 147.84,64.7 ; v2(158.07,53.42) 158.07,53.32 157.39,52.63 151.87,52.63 v2(151.72,52.79) ; PD4203.2 129.85,175.21 130.36,175.72 130.91,175.72 PR4204.1 131.24,175.73 v2(131.76,176.26) ; C702.1 98.5,99.37 98.11,99.76 v2(98.11,100.96) ; R3033.2 v2(55.38,168.72)
  TOP w0.635: v3(97.51,10.47) 158.05,10.47 160.81,13.23 160.81,14.03 162.62,15.84 162.62,18.2 165.74,21.31 169.1,21.31 178,30.21 178,36.65 179.5,38.15
  L3 w0.508: v3(158.86,80.54) 158.66,80.34 153.23,80.34 152.95,80.62 151.28,80.62 150.04,79.38 145.83,79.38 145.37,79.84 ; v2(172.27,75.32) 174.02,77.07 177.35,77.07 177.54,77.26 179.62,77.26 181.1,75.78 184.17,75.78 v2(185.8,74.15) ; v2(168.97,84.05) 169.35,84.43 171.18,84.43 173.15,82.46 175.65,82.46 175.89,82.69 177.93,82.69 v2(177.94,82.68) ; 145.37,79.84 v2(145.37,79.86) ; 145.37,79.84 144.48,80.73 141.16,80.73 140.38,79.94 v2(139.66,79.94) ; v2(150.88,87.56) 151.4,87.56 151.76,87.92 153.38,87.92 155,86.29 v2(157.28,86.29) ; v2(55.38,168.72) 55.38,170.51 61.07,176.2 v3(63.42,176.2) ; v3(46.41,76.58) 46.41,76.01 48.24,74.18 48.24,62.92 v3(47.94,62.62) ; v2(35.82,55.52) 35.82,56.16 37.45,57.79 37.45,58.07 38.21,58.83 38.21,61.12 38.95,61.85 45.75,61.85 v3(46.66,62.76)
  L3 w0.635: v3(97.51,10.47) 97.01,9.96 93.69,9.96 92.4,11.25 58.93,11.25 48.98,21.21 48.98,25.2
  L3 w1.524: 48.6,26 49.63,26 49.94,26.31 50.03,26.31 50.61,26.89 50.64,26.89 55.23,31.48 55.23,54.89 50.63,59.49 50.56,59.49 49.89,60.16 49.89,60.23 48.65,61.47
  L4 w0.508: v2(166.86,82.98) 166.86,82.35 168.92,80.29 169.66,80.29 170.93,79.03 170.93,77.37 171.2,77.09 171.2,76.64 172.27,75.57 v2(172.27,75.32) 172.5,75.32 173.54,74.28 173.54,74.01 173.54,73.66 176.27,70.92 176.27,69.76 176.33,69.7 176.33,69.57 177.47,68.43 177.47,66.66 177.91,66.22 177.91,65.69 177.27,65.05 177.27,62.91 177.22,62.86 177.22,59.46 v2(177.03,59.27) ; v2(142.6,153.29) 142.6,152.68 143.02,152.26 143.02,149.19 143.97,148.24 143.97,139.67 142.37,138.07 142.37,121.7 149.26,114.82 149.26,104.73 v2(149.07,104.54) ; v3(146.54,170.8) 146.3,171.05 146.3,172.65 142.69,176.26 v2(131.76,176.26) 131.6,176.41 122.38,176.41 120.76,178.03 104.35,178.03 v2(102.09,175.77) ; v2(188.87,69.99) 188.87,70.24 188.6,70.51 188.6,70.51 187.67,71.45 v2(187.67,71.74) ; v2(187.01,72.1) 187.01,72.51 185.8,73.72 v2(185.8,74.15)
  L4 w0.635: v3(146.54,170.8) 147.97,170.8 151.33,174.16 152.66,174.16 154.55,176.05 167.61,176.05 167.62,176.06 167.75,176.06 168.61,176.92 169.98,176.92 170.46,177.39 176.27,177.39 177.91,179.02 186.26,179.02 193.09,172.19 v2(193.09,172.02)
  BOTTOM w0.305: CPU1.Y8 132.53,84.28 v2(132.71,84.46)
  BOTTOM w0.508: v2(188.87,69.99) 188.86,69.97 188.86,68.25 188.35,67.75 187.74,67.75 187.72,67.77 186.18,67.77 185.95,67.54 185.86,67.54 185.71,67.39 R2421.2 ; R2501.2 156.56,54.61 157.75,53.42 v2(158.07,53.42) ; v2(149.07,104.54) PC5119.1 149.07,103.44 148.82,103.2 PU5101.1 149.43,102.54 149.97,102.01 149.97,100.67 151.07,99.56 v2(151.07,93.99) ; v2(150.88,87.56) 150.83,87.61 150.49,87.61 R1815.2 ; R2412.2 172.29,75.33 v2(172.27,75.32) ; v3(173.02,40.63) 178.25,45.86 179.48,45.86 181.34,47.72 181.34,56.25 178.32,59.27 v2(177.03,59.27) ; R6215.1 46.84,77.01 v3(46.41,76.58) ; R1814.2 144.52,79.59 144.79,79.86 v2(145.37,79.86) ; v3(91.49,100.84) 91.53,100.84 91.53,101.05 93.92,103.43 v1(96.72,103.43) 97.6,103.43 98.02,103.02 98.02,102.54 98.22,102.33 98.22,101.08 v2(98.11,100.96) ; v2(184.34,30.18) 184.22,30.06 R2712.2 ; R2452.2 181.29,82.68 v2(177.94,82.68) ; v2(166.86,82.98) 168.25,82.98 168.97,83.7 v2(168.97,84.05) 168.97,85.36 167.68,86.64 157.63,86.64 v2(157.28,86.29)
  BOTTOM w0.635: v2(142.6,153.29) 142.6,161.16 145.4,163.95 145.4,169.66 v3(146.54,170.8) ; v2(102.09,175.77) 102.93,174.93 102.93,171.18 106.11,168 v2(106.28,168)
  vias: v1(65.01,174.95) v3(33.58,26) v3(34.47,26) v3(35.36,26) v3(36.25,26) v3(37.09,26.03) v3(95.26,134.71) v3(95.96,134.16) v3(96.62,122.61) v3(97.29,123.26) v3(148.04,61.12)
3D3V_S5_PCH: length 131.1
  TOP w0.508: v2(151.86,85.24) 150.97,85.24 R2015.1 150.33,84.96 149.85,84.47 149.53,84.47 148.84,83.79 145.33,83.79 144.88,84.24 R2013.2 144.63,84.24 R2010.1
  L3 w0.889: v3(183.72,49.87) 183.65,49.94 179.32,49.94 179.31,49.93 179.25,49.93 178.34,49.03 172.16,49.03 170.61,47.48 167.56,47.48 167.53,47.44 167.48,47.44 163.6,43.56 163.23,43.56 160.31,40.65 v3(160.31,37.55)
  L3 w1.016: v3(179.42,70.22) 178.22,69.02 172.4,69.02 172.23,69.18 171.83,69.18 171.06,69.95 169.91,69.95 169.87,70 169.21,70 167.18,72.02 164.75,72.02 164.22,71.49 162.92,71.49 161.7,70.28 159.2,70.28 157.77,71.72 v3(157.26,71.72)
  L4 w1.016: v3(183.72,49.87) 183.72,52.55 182.03,54.24 182.03,57.51 180.59,58.95 180.59,61.89 179.93,62.55 179.93,64.48 180.17,64.72 180.17,67.16 179.74,67.59 179.74,69.9 v3(179.42,70.22)
  BOTTOM w0.889: 126.33,60.65 128.61,58.37 128.62,58.37 128.62,57.08 148.15,37.55 v3(160.31,37.55)
  vias: v1(125.46,66.83) v1(125.46,65.31) v1(125.46,63.78) v1(157.11,72.6) v2(125.48,62.44) v2(125.48,61.7)
3D3V_VGA_OUT1:
  vias: v1(149.66,134.98)
3D3V_VGA_S0: length 117
  TOP w0.508: R7626.2 182.38,128.33 182.38,126.64 182.13,126.38 182.13,124.55 R8304.2 178.41,124.47 177.46,123.52 171.46,123.52 v2(171.02,123.09)
  L3 w0.508: v2(171.02,123.09) 170.71,122.78 166.38,122.78 164.19,124.97 156.71,124.97 155.96,124.22 155.96,123.63 v2(154.57,122.23) 154.57,121.3 155.23,120.64 155.23,117.72 154.97,117.46 154.97,111.47 154.09,110.59 154.09,103.89 157.27,100.72 v2(157.51,100.72)
  L4 w0.508: v2(145.83,123.91) 145.19,124.54 145.19,134.94 144.15,135.98 v2(144.15,136.5) ; v2(172.35,135.59) 172.35,135.09 173.55,133.9 174,133.9 175.47,132.42 176.87,132.42 179.65,129.65 181.39,129.65 182.02,130.28 v2(185.63,130.28) 185.63,130.23 186.24,129.62 190.44,129.62 191.49,128.57 191.49,127.36 v3(191.46,127.33)
  BOTTOM w0.305: GPU1.G9 172.01,135.93 v2(172.35,135.59) 171.97,135.21 GPU1.G8
  BOTTOM w0.508: C8303.1 144.12,136.54 v2(144.15,136.5) ; v3(191.46,127.33) 191.46,127.41 191.55,127.49 R7619.1 R7611.1 ; PR8256.1 159.81,100.8 159.72,100.72 v1(158.89,100.72) v2(157.51,100.72) ; v2(154.57,122.23) 153,120.66 148.31,120.66 146.74,122.23 146.74,122.99 v2(145.83,123.91) ; C7703.1 170.8,122.86 v2(171.02,123.09)
3D3V_WLAN_S0:
  vias: v1(169.96,40) v3(170.79,39.8)
27MHZ_IN: length 15
  BOTTOM w0.102: 180.21,131.2 179.94,130.93 179.94,129.99 180.04,129.89 R7603.1 C7607.2 181.4,129 181.71,129.31 X7601.1 ; 180.21,131.2 v1(180.32,131.09) ; 180.21,131.2 180.6,131.59 180.6,132.12 179.67,133.04 179.67,133.27 179.67,133.35 179.67,135.34 177.58,137.43 176.32,137.43 176.1,137.22 175.72,137.22 GPU1.C11
27MHZ_OUT: length 12.6
  BOTTOM w0.102: v1(179.31,134.12) 179.47,134.12 ; 179.47,134.12 179.47,133.35 179.47,132.96 180.4,132.03 180.4,131.68 179.74,131.02 179.74,129.52 180.19,129.06 R7603.2 R7604.2 ; 179.47,134.12 179.47,135.25 177.49,137.23 176.4,137.23 176.05,136.88 GPU1.B10
27MHZ_OUT_R: length 7.4
  BOTTOM w0.14: X7601.3 184.67,127.8 183.62,126.75 182.79,126.75 182.17,126.13 v1(181.67,126.13) 181.05,126.13 180.19,126.99 R7604.1 C7608.2
28W_DET: length 7
  BOTTOM w0.127: R2022.1 148.11,76.7 R2035.2 148.65,77.24 151.31,77.24 151.66,77.58 151.66,78.03 151.51,78.18 v1(151.51,78.74) 151.51,78.87 151.87,79.24 R2032.1
+0D675V_DDR_P:
  vias: v1(55.71,23.34)
+1.05M_ASW:
  vias: v1(122.42,81.3) v2(122.02,82.81) v2(122.62,82.51) v2(131.22,81.66) v2(132.8,80.67)
+3.3A_DSW_PRTCSUS: length 12.7
  TOP w0.254: v2(130.24,79.26) 130.22,79.26 129.69,79.79 128.29,79.79 128.18,79.68 127.92,79.68 127.92,79.69 127.35,79.69 126.36,78.69 v1(126.36,76.83) 126.36,74.89 125.74,74.26 C2109.1 125.27,74.08 124.86,73.66 124.49,73.66 123.85,73.02 R2102.1
  BOTTOM w0.254: CPU1.AH11 130.32,79.28 130.25,79.28 v2(130.24,79.26)
+DC_IN: length 39.1
  TOP w0.508: v2(116.34,177.4) 116.72,177.01 PC4202.1
  L3 w0.508: v2(116.34,177.4) 115.44,178.29 103.24,178.29 101.96,177.02 101.96,176.99 98.56,173.59 98.56,163.48 96.93,161.85 v3(96.93,156.77)
  vias: v1(93.42,149.86) v1(97.95,156.14) v3(95.16,156.77) v3(95.49,155.99) v3(96.04,156.77) v3(96.37,155.99) v3(97.26,155.99)
+DC_IN_C:
  vias: v1(87.64,155.25)
+PCH_VCCDSW: length 3.4
  TOP w0.254: v2(126.18,79.93) 126.49,80.24 C2101.2 ; v2(126.18,79.93) 125.97,80.14 R2110.1 ; v2(126.18,79.93) v1(126.18,79.29)
  BOTTOM w0.254: CPU1.AG19 126.54,80.29 v2(126.18,79.93) 126.14,79.93 CPU1.AG20
+PWR_SRC_1D35V:
  vias: v1(64.37,24.07) v3(65.91,24.1) v3(66.8,24.1) v3(67.69,24.1) v3(68.58,24.1)
+RTC_VCC: length 11.8
  TOP w0.508: v2(33.38,17.59) 33.43,17.59 33.43,16.28 33.31,16.16 AFTP2502.1 33.76,15.7 R2502.2
  BOTTOM w0.508: v2(33.38,17.59) 33.38,16.03 32.52,15.17 28.52,15.17 28.12,14.77 RTC1.1
+V_SM_VREF_CNT: length 55.7
  TOP w0.229: v2(106.76,75.91) 106.73,75.91 106.29,75.48 106.29,74.81 106.05,74.58 106.05,74.15
  TOP w0.508: 106.05,74.15 105.89,73.98 105.89,72.82 105.43,72.36 105.43,70.23 100.45,65.26 83.03,65.26 v1(79.08,61.31) 71.88,54.11 65.63,54.11 C3701.1 64.56,53.04 R3708.2
  BOTTOM w0.127: v2(106.76,75.91) 106.76,75.91 106.76,75.94 107.03,76.22 CPU1.AP49
+V_VREF_PATH1: length 2.3
  TOP w0.508: C3702.2 61.64,52.48 R3711.1 61.64,53.77 v1(62.25,54.38)
+V_VREF_PATH2: length 1.9
  TOP w0.508: R3715.1 57.28,54.96 C3703.2 56.29,54.97 v1(56.25,54.93)
+V_VREF_PATH3: length 2.4
  TOP w0.508: R3707.1 63.82,52.38 C3701.2 63.82,53.48 v1(64.63,54.28)
+VCHGR_R: length 28.8
  TOP w0.254: v2(128.99,169.07) 128.89,168.97 v1(128.89,168.46) 128.89,168 128.55,167.67 128.54,167.67 PR4454.1
  L3 w0.254: v2(128.99,169.07) 128.99,169.5 129.78,170.29 131.3,170.29 132.72,168.86 132.72,160.86 135.9,157.69 139.48,157.69 139.65,157.51 v2(139.65,157.06)
  BOTTOM w0.254: PG4405.1 137.52,157.05 137.32,156.85 137.32,156.52 137.6,156.24 139.65,156.24 139.96,156.55 139.96,156.75 v2(139.65,157.06)
AC_IN#: length 158.3
  TOP w0.102: PQ4408.5 141.79,155.33 141.41,154.94 141.41,154.28 141.21,154.08 141.21,153.7 v2(140.75,153.24) 140.22,152.71 140.22,152.1 141.61,150.7 145.6,150.7 145.98,151.08 v2(147.2,151.08) ; R2430.1 R2413.1 172.77,79.92 171.15,81.53 171.15,84.64 174.72,88.21 179.12,88.21 v2(179.63,88.72)
  L3 w0.102: v2(107.73,154.13) 108.41,154.13 109.04,154.76 110.49,154.76 112.64,152.61 139.76,152.61 140.39,153.24 v2(140.75,153.24)
  L4 w0.102: v2(153.35,118.5) 148.98,122.86 148.98,128.3 148.39,128.88 148.39,131.42 148.47,131.5 148.47,143.69 147.21,144.95 147.21,151.07 v2(147.2,151.08)
  BOTTOM w0.102: v2(107.73,154.13) 107.78,154.13 107.49,154.42 107.49,157.53 107.31,157.71 PR4434.2 107.49,158.33 107.91,158.33 108.86,159.28 PU4401.5 ; v2(179.63,88.72) 176.97,91.37 160.54,91.37 160.38,91.53 158.25,91.53 158.09,91.37 157.59,91.37 157.34,91.63 157.34,99.22 156.68,99.88 156.68,101.92 153.51,105.08 153.51,106.43 152.38,107.56 152.38,115.95 153.35,116.91 v1(153.35,117.64) v2(153.35,118.5)
AC_PRESENT: length 163.1
  TOP w0.102: EC1707.1 168.33,80.94 168.54,81.15 RN1701.3 168.54,82.11 168.88,82.45 169.41,82.45 169.86,82.9 v2(169.86,83.47) 169.86,84.11 174.33,88.59 178.74,88.59 v2(178.86,88.72) ; v2(181.66,79.74) 181.21,79.29 181.21,78.01 181.52,77.7 181.52,77.66 183.28,75.9 183.28,74.69 183.75,74.22 183.75,73.36 183.96,73.15 183.96,71.21 185.51,69.66 185.51,69.3 184.8,68.58 KBC24.112 ; v2(169.84,126.98) 169.84,126.85 170.3,126.39 170.74,126.39 D7601.K
  L3 w0.102: v2(132.11,78.93) 132.6,78.93 132.88,79.21 135.91,79.21 137.24,80.55 137.24,80.6 137.49,80.86 140.3,80.86 140.99,81.55 144.78,81.55 146.26,80.07 149.76,80.07 151,81.31 153.23,81.31 153.51,81.03 158.23,81.03 158.53,81.33 159.55,81.33 161.41,83.19 162.92,83.19 164.53,81.58 167.97,81.58 v2(169.86,83.47) 171,83.47 173.57,80.9 175.07,80.9 175.98,81.81 179.41,81.81 181.48,79.74 v2(181.66,79.74)
  BOTTOM w0.102: v2(178.86,88.72) 176.41,91.17 160.46,91.17 160.3,91.33 158.33,91.33 158.18,91.17 157.51,91.17 157.13,91.54 157.13,99.14 156.47,99.8 156.47,101.38 156.47,101.83 153.31,105 153.31,106.35 152.18,107.48 152.18,116.03 152.92,116.77 152.92,118.7 v1(154.81,120.59) 158.42,124.2 159.02,124.2 162.08,127.27 169.54,127.27 v2(169.84,126.98) ; CPU1.AJ8 132.4,79.22 v2(132.11,78.93)
AD+: length 78.9
  TOP w0.254: v1(114.71,157.41) 114.71,157.41 v2(114.71,156.75)
  TOP w0.406: PR4405.1 138.12,156.19 137.55,156.19 137.15,156.58 137.13,156.58 136.79,156.92 PU4403.4
  TOP w0.508: v2(138.84,157.08) 138.74,157.08 138.17,156.51 PR4405.1 ; v2(111.34,171.47) 110.32,172.5 110.32,173.16 109.73,173.75 109.69,173.75 109.19,174.25 PR4469.1
  L3 w0.762: v2(114.71,156.75) 114.65,156.81 112.58,156.81 112.01,156.25 104.59,156.25 104.15,155.81 103.39,155.81 v2(103.06,155.48)
  L4 w0.635: v2(103.06,155.48) 103.95,156.37 103.95,157.81 v2(103.94,157.81) 103.94,157.83 104.05,157.93 104.13,157.93 104.85,158.65 104.85,159.52 104.59,159.78 104.59,160.48 105.07,160.96 105.14,160.96 v2(106.79,162.62) 106.34,163.06 106.34,165.86 107.04,166.55 107.04,169.37 108.41,170.74 109.46,170.74 110.19,171.47 v2(111.34,171.47) 116.69,171.47 116.97,171.19 122.39,171.19 123.35,170.24 131.2,170.24 132.32,169.12 132.32,165.64 136.06,161.9 136.06,159.86 v2(138.84,157.08)
  BOTTOM w0.508: v2(103.94,157.81) 104.34,157.81 PR4407.1
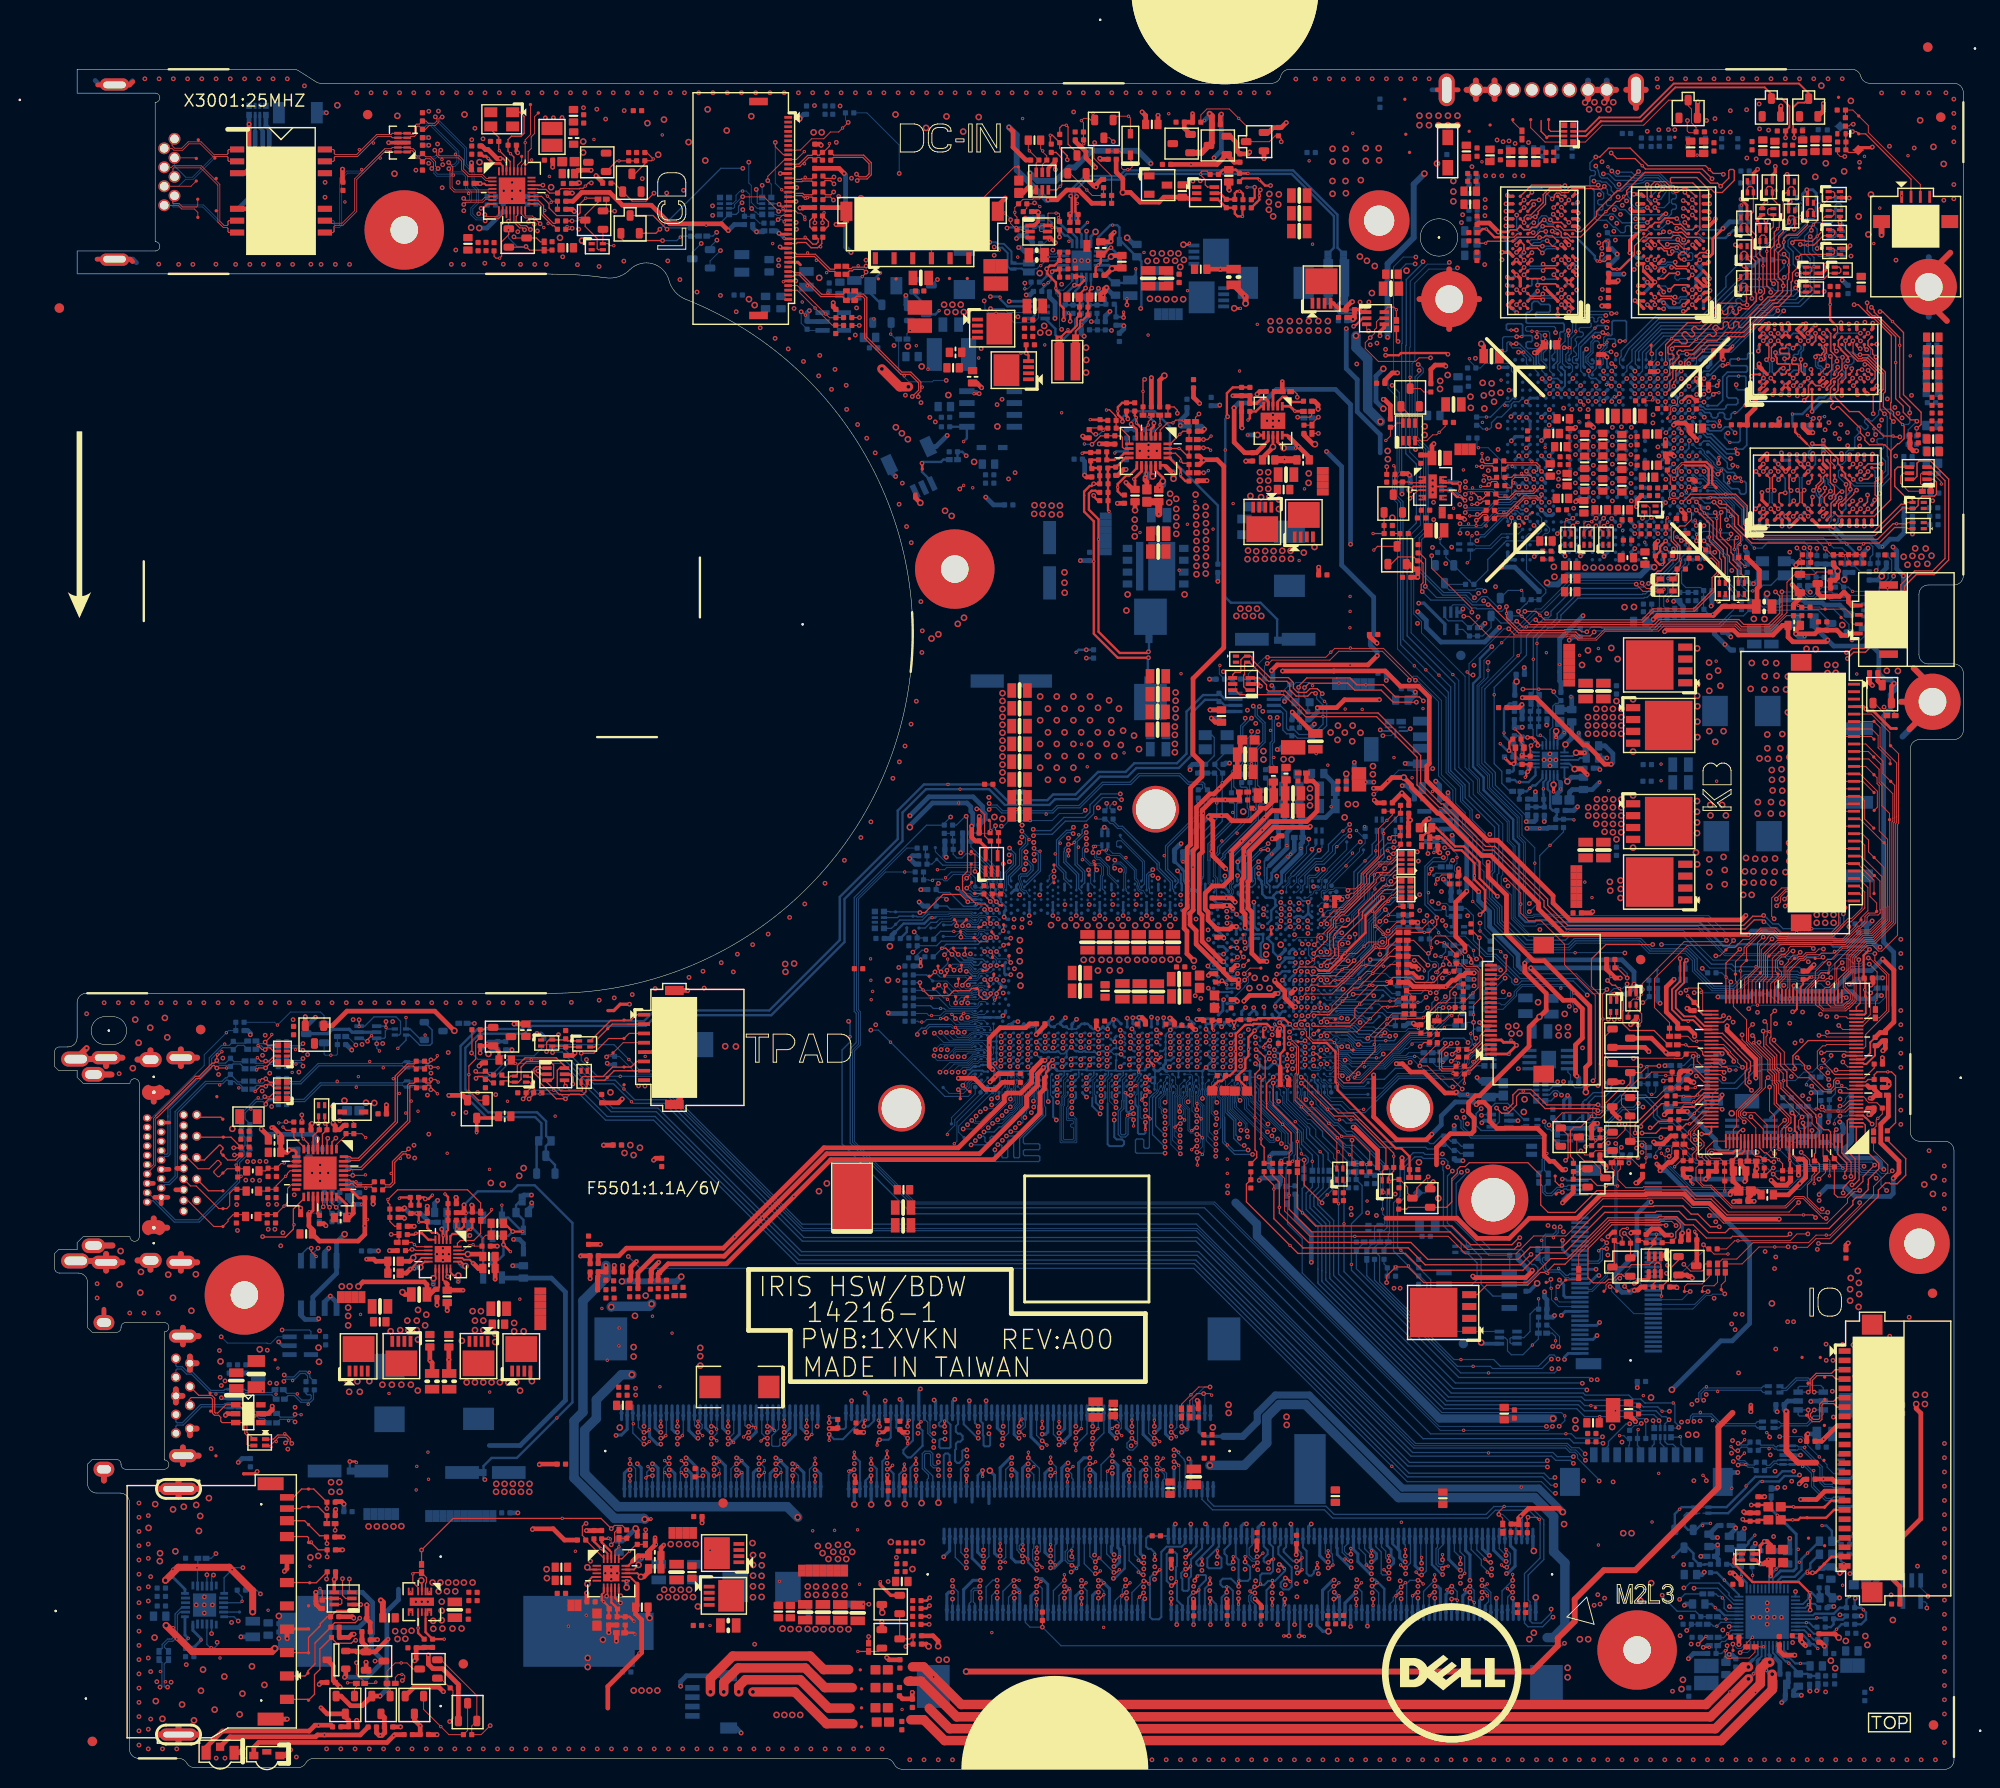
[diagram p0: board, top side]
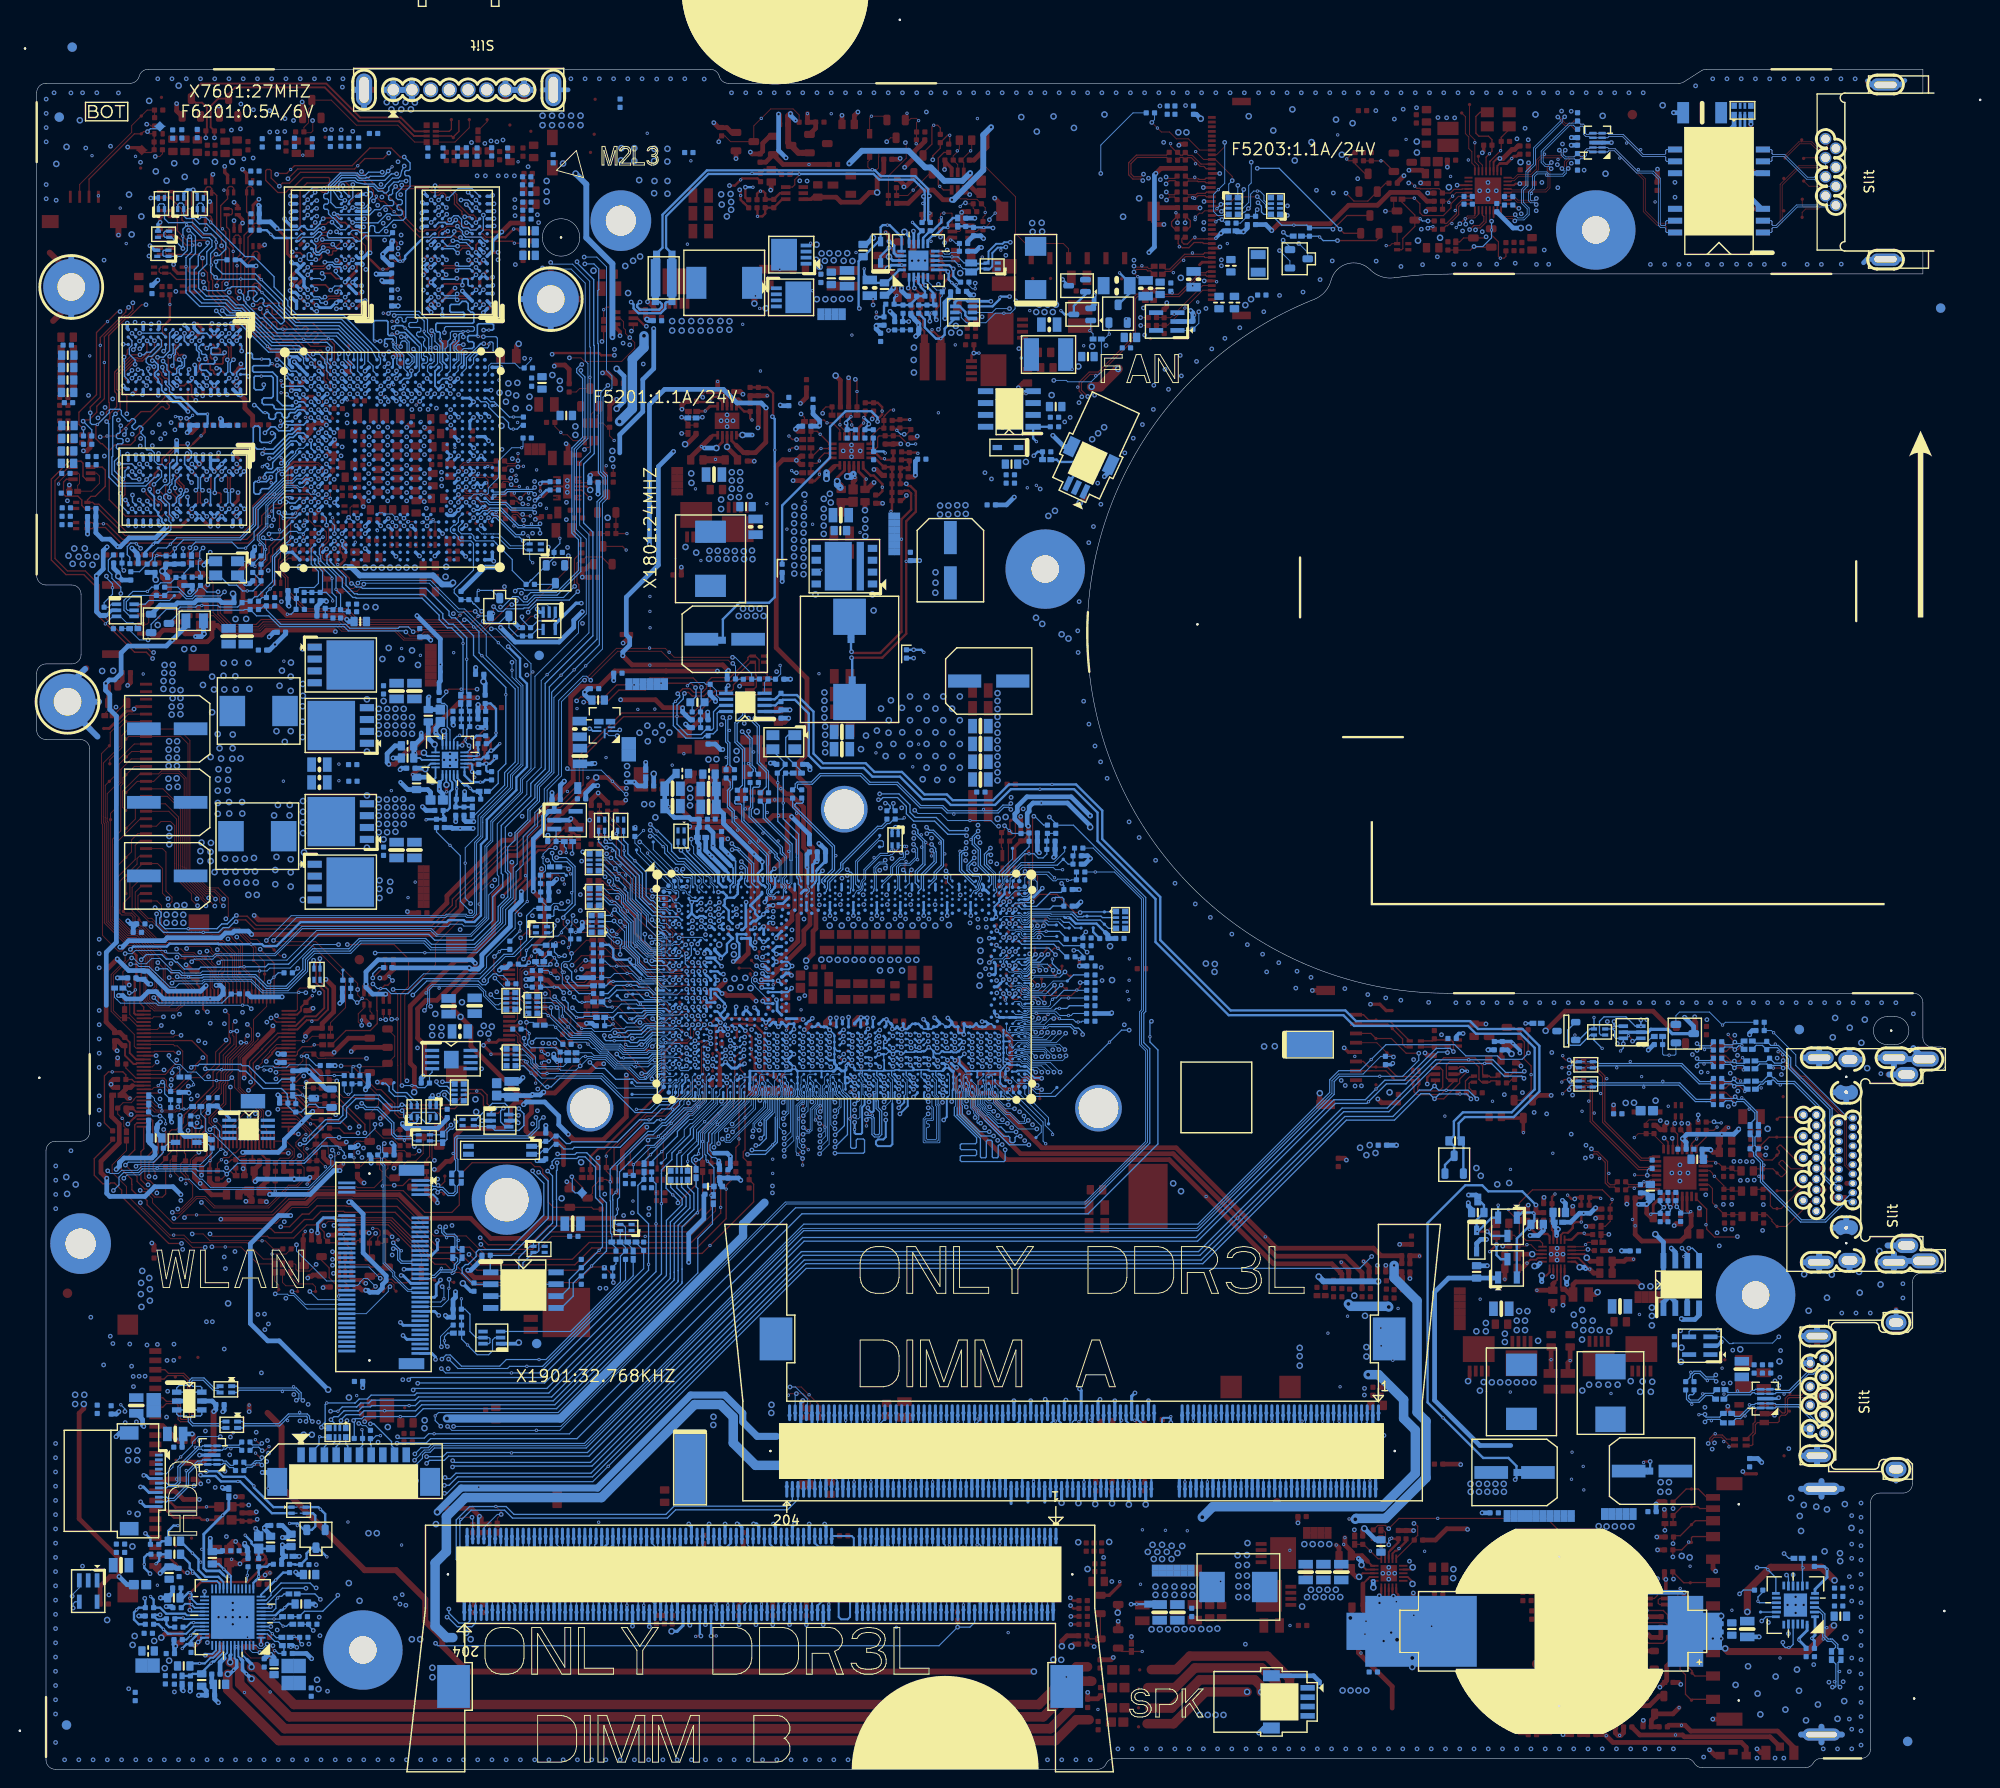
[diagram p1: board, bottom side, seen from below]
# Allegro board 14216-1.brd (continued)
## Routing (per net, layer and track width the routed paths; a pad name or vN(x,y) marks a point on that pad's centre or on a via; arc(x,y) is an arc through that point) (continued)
AD+_G_1: length 5.6
  TOP w0.102: PR4401.1 107.5,166.48 107.4,166.57 v1(107.14,166.57) 106.33,166.57 106.27,166.51 106.27,165.29 PQ4402.6 105.56,165.25 105.35,165.04 105.35,164.72 105.46,164.6 PQ4402.5
AD+_G_2: length 17.2
  TOP w0.254: PR4403.2 103.93,151.6 v2(103.94,151.59) 104.19,151.35 PU4402.4 ; PR4401.2 v2(107.5,164.01)
  L4 w0.254: v2(103.94,151.59) 104.2,151.85 104.2,155.56 107.22,158.58 107.22,159.17 107.6,159.55 107.6,163.91 v2(107.5,164.01)
  BOTTOM w0.254: v1(103.39,151.59) v2(103.94,151.59)
AD+_TO_SYS:
  vias: v1(105.92,152.47)
AD_IA: length 155.5
  TOP w0.102: v2(176.08,65.69) 176.08,65.66 176.85,64.89 C2414.2 176.94,65.25 176.64,65.55 176.64,66.4 177.48,67.24 KBC24.97
  L4 w0.102: v2(103.79,159.08) 103.79,158.94 102.86,158.01 102.86,157.74 102.86,156.7 102.05,155.9 102.05,152.54 106.25,148.34 120.43,148.34 121.39,149.31 135.41,149.31 135.57,149.31 139.09,145.79 139.09,123.8 138.45,123.17 138.45,116.07 142.53,111.99 142.53,107.55 142.3,107.32 142.3,101.45 144.93,98.82 144.93,97.03 147.5,94.45 148.69,94.45 151.67,91.47 151.67,89.81 152.05,89.44 153.44,89.44 155.95,86.93 155.95,86.61 157.78,84.78 158.37,84.78 160.26,82.88 163.12,82.88 164.16,81.84 164.16,80.65 168.26,76.56 169.06,76.56 170.19,75.43 170.19,74.98 174.2,70.97 174.2,69.34 176.45,67.09 176.45,66.17 176.08,65.79 v2(176.08,65.69)
  BOTTOM w0.102: v2(103.79,159.08) v1(103.79,158.48) 104.1,158.48 104.46,158.84 PR4422.2
AD_IA_HW: length 178.6
  TOP w0.102: v2(183.32,74.05) 183.02,73.75 183.02,72.98 181.09,71.05 181.07,71.05 180.36,70.35 180.36,69.99 180.62,69.73 180.93,69.73 182,68.66 KBC24.105
  L3 w0.102: v2(148.47,90.86) 148.8,90.86 150.45,92.51 153.12,92.51 153.71,91.93 156.57,91.93 156.88,92.24 158.72,92.24 163.15,87.81 169.46,87.81 170.26,87 172.32,87 172.97,86.35 173.95,86.35 174.12,86.17 175.56,86.17 175.93,86.54 176.61,86.54 177.41,85.74 179.7,85.74 180.85,84.58 181.88,84.58 184.69,81.76 184.69,79.9 185.46,79.14 187.56,79.14 188.56,78.13 188.79,78.13 189.89,77.04 189.89,76.57 v2(190.05,76.41)
  L4 w0.102: v2(100.12,156.35) 100.13,156.34 100.13,153.29 105.9,147.53 120.77,147.53 121.73,148.49 135.24,148.49 137.57,146.16 137.57,124.43 136.96,123.82 136.96,115.3 140.44,111.82 140.44,108.16 140.11,107.83 140.11,106.08 140.29,105.9 140.29,103.48 140.5,103.27 140.5,100.36 141.08,99.78 141.08,95.66 142.01,94.72 142.67,94.72 143.17,94.23 144.35,94.23 146.75,91.83 147.82,91.83 148.47,91.17 v2(148.47,90.86)
  BOTTOM w0.102: v2(183.32,74.05) 183.64,73.72 v1(184.96,73.72) 186.22,73.72 187.13,74.63 188.04,74.63 188.87,75.46 189.35,75.46 190.05,76.15 v2(190.05,76.41) ; PQ4401.2 101.98,155.94 101.57,156.35 v2(100.12,156.35)
AD_IA_HW2: length 169.7
  TOP w0.102: KBC24.25 189.58,78.39 189.4,78.57 v2(188.75,78.57)
  L3 w0.102: v2(188.75,78.57) 188.5,78.82 188.2,78.82 187.66,79.35 185.53,79.35 184.9,79.98 184.9,81.85 181.96,84.78 180.94,84.78 179.78,85.94 177.5,85.94 176.21,87.23 170.34,87.23 169.55,88.02 163.38,88.02 158.28,93.11 157.46,93.11 156.48,92.13 153.79,92.13 153.21,92.71 150.3,92.71 148.97,91.39 148.28,91.39 148.08,91.59 147.63,91.59 146.83,90.8 v2(146.5,90.8)
  L4 w0.102: v2(99.45,157.18) 99.45,153.67 105.79,147.33 120.85,147.33 121.82,148.29 135.15,148.29 137.37,146.07 137.37,124.51 136.76,123.9 136.76,115.2 140.24,111.72 140.24,108.26 139.91,107.93 139.91,105.99 140.09,105.82 140.09,103.39 140.3,103.18 140.3,100.27 140.88,99.7 140.88,95.58 141.93,94.52 142.59,94.52 143.08,94.03 143.86,94.03 145.61,92.28 145.61,91.69 v2(146.5,90.8)
  BOTTOM w0.102: v2(99.45,157.18) 99.52,157.1 99.52,156.34 100,155.86 v1(100.72,155.86) 101.63,155.86 102.65,154.84 104.73,154.84 105.28,155.39 105.28,155.82 105.4,155.94 PQ4401.5
AD_OFF_L: length 4.5
  BOTTOM w0.254: v1(94.62,156.14) 94.22,155.73 PQ4204.C 93.24,156.63 91.99,157.88 PQ4205.B
AD_OFF_R: length 10.7
  L3 w0.254: v2(94.44,159.47) 94.44,155.96 98.33,152.07 v2(99.12,152.07)
  BOTTOM w0.254: v2(94.44,159.47) 93.8,158.82 PQ4205.C
  vias: v1(98.86,151.07)
ALERT#: length 5.3
  BOTTOM w0.102: v1(134.58,115.99) 134.23,116.34 132.8,116.34 132.6,116.14 R2603.2 131.47,115.46 131.47,114.97 131.03,114.53 THM26.6
ALL_SYS_PWRGD: length 131.1
  TOP w0.127: KBC24.10 191.21,72.39 v2(191.01,72.59) ; R3601.2 R3610.2 134.51,144.05 v2(135.2,144.73)
  L3 w0.127: v2(143.09,148.14) 142.62,148.14 141.17,146.69 137.16,146.69 v2(135.2,144.73)
  L4 w0.127: v2(189.17,84.83) 189.17,81.62 190.09,80.71 190.09,78.4 188.54,76.85 188.54,75.47 189.01,74.99 189.89,74.99 190.15,74.73 190.15,74.66 190.53,74.28 190.65,74.28 191.19,73.75 191.19,72.76 v2(191.01,72.59)
  BOTTOM w0.127: v2(143.09,148.14) 143.85,147.37 143.85,138.86 143.36,138.37 143.36,136.21 144,135.57 144,120.39 v1(146.7,117.69) 149.1,115.28 149.1,106.78 150.64,105.24 150.64,103.72 151.66,102.71 151.66,101.63 153.03,100.26 153.03,99.47 153.81,98.69 153.81,96.2 153.49,95.88 153.49,93.33 154.57,92.24 154.57,90.71 154.67,90.62 157.34,87.95 161.96,87.95 162.68,88.68 169.59,88.68 170.69,87.58 174.54,87.58 175.45,86.68 175.45,85.54 177.41,83.58 179.64,83.58 180.88,84.82 186.39,84.82 186.49,84.71 189.05,84.71 v2(189.17,84.83) ; v2(135.2,144.73) 135.12,144.65 R3611.2
AMBER_LED_BAT: length 5.2
  TOP w0.508: R6103.2 30.64,4.56 EC6102.1 31.45,5.26 31.1,5.62 Q6101.C 29.15,5.94 v1(28.48,6.6)
AMP_MUTE#: length 94.7
  TOP w0.102: v1(182.83,13.11) R2708.1 181.91,12.54 181.29,11.92 179.41,11.92 179.36,11.87 178.95,11.87 178.72,12.09 178.72,12.5 178.95,12.73 178.95,13.21 v2(178.92,13.24) ; v2(190.63,80.55) 191.67,80.55 191.83,80.39 KBC24.30
  L3 w0.102: v2(185.1,30.17) 184.62,30.65 182.01,30.65 173.85,22.49 173.85,19.17 174.39,18.63 175.32,18.63 177.66,16.29 177.66,14.25 178.67,13.24 v2(178.92,13.24)
  L4 w0.102: v2(190.63,80.55) 190.44,80.35 190.44,79.43 190.56,79.3 190.56,75.85 191.26,75.15 191.26,75.14 192.42,73.98 192.42,65.09 193.79,63.72 193.79,62.93 194.66,62.06 194.66,54.26 195.16,53.76 195.16,39.96 195.87,39.25 195.87,38.05 195.31,37.49 195.31,36.96 193.76,35.41 193.07,35.41 187.59,29.93 185.35,29.93 v2(185.1,30.17)
AUD_AGND: length 31.7
  TOP w0.508: v2(182.93,29.18) 182.93,29.18 R2919.2 ; EC9739.1 190.46,14.5 v3(190.87,14.09) ; CN6301.24 191.5,21.5 v2(190.99,20.98) ; v2(180.7,27.56) 180.82,27.45 EC2908.2 R2920.2 ; v1(179.25,21.02) 179.25,21.02 179.54,21.02 v2(179.76,20.8) 180.43,20.12 EC9744.1 ; v2(186.8,28.88) AFTP6313.1 188.49,28.88 189.38,29.77 CN6301.16 ; v2(186.16,12.22) 185,12.22 184.51,12.71 EC9745.1
  BOTTOM w0.203: HDA27.38 185.02,12.73 185.4,12.35 186.04,12.35 v2(186.16,12.22) ; HDA27.25 v2(186.24,19.03)
  BOTTOM w0.508: v2(186.87,7.92) 186.85,7.94 EC2703.1 186.05,8.4 C2715.2 ; v2(190.96,18.35) 190.9,18.35 C2702.1 189.65,18.88 R2711.1 ; v2(185.63,24.72) 185.63,23.52 C2713.2 184.42,23.3 EC2906.2 ; C2901.2 179.18,25.08 179.84,25.74 v2(179.84,25.84) 179.58,26.1 EC9743.1 ; v2(181.94,24.19) 181.94,24 181.66,23.71 EC2905.2 181.59,23.33 R2707.2 ; v2(190.99,20.98) 190.3,21.67 C2711.2 189.44,21.67 189.29,21.52 C2710.2 ; v2(190.35,17.43) 189.76,17.43 C2705.1 ; EC2907.2 v2(193.28,16.41)
  vias: v2(183.9,24.91) v3(190.03,11.63) v3(190.49,10.83) v3(191.63,13.74)
AUD_HP1_JACK_L: length 2.5
  BOTTOM w0.203: HDA27.32 187.39,15.69 v1(187.41,15.7) 187.7,15.7 188.19,15.22 R2908.1
AUD_HP1_JACK_L1: length 27.9
  TOP w0.254: R2907.2 183.15,28.29 R2919.1 v2(181.51,28.29)
  L3 w0.254: v2(192.07,20.94) 192.07,22.25 186.06,28.26 181.54,28.26 v2(181.51,28.29)
  L4 w0.254: v2(192.07,20.94) 191.53,20.4 191.53,17.08 v2(190.99,16.54)
  BOTTOM w0.254: v2(190.99,16.54) 191.56,16.54 EC2907.1 191.31,16.03 190.74,16.03 190.66,16.11 R2912.2 190.32,15.51 190.02,15.22 R2908.2 ; R2922.2 192.35,23.03 192.69,22.68 v1(192.69,21.94) 192.69,21.57 v2(192.07,20.94)
AUD_HP1_JACK_R: length 6.2
  BOTTOM w0.203: 189.85,14.51 188.2,14.51 187.42,15.29 HDA27.33
  BOTTOM w0.254: R2910.1 191.17,15.52 v1(190.63,14.99) 190.15,14.51 189.85,14.51
AUD_HP1_JACK_R1: length 28.6
  TOP w0.254: R2909.2 182.37,26.7 R2920.1 EC2908.1 180.81,26.56 v2(180.6,26.76)
  L4 w0.254: v2(192.64,18.3) 192.74,18.4 192.74,21.37 192.51,21.6 192.51,25.2 v2(192.56,25.25) 192.45,25.25 190.94,26.76 v2(180.6,26.76)
  BOTTOM w0.254: R2910.2 193.28,15.52 193.78,16.03 193.78,16.79 v1(193.5,17.07) 193.28,17.3 R2913.2 192.58,18.24 v2(192.64,18.3) ; R2921.2 192.03,24.7 192.56,25.24 v2(192.56,25.25)
AUD_PC_BEEP: length 4.2
  BOTTOM w0.203: 179.67,19.22 180.19,18.69 HDA27.12
  BOTTOM w0.254: C2720.2 177.83,21.06 v1(178.63,20.25) 179.67,19.22
AUD_PC_BEEP_C: length 5.5
  BOTTOM w0.254: v1(173.15,22.74) 174.13,23.72 D2701.3 174.72,23.72 175.33,23.11 175.33,22.54 R2717.1 176.53,21.91 176.56,21.94 C2720.1
AUD_PORTA_L_R_B: length 7.2
  TOP w0.254: R2907.1 v1(186.03,28.1) 186.08,28.04 189.33,28.04 AFTP6306.1 190.06,28.77 CN6301.17
AUD_PORTA_R_R_B: length 7.3
  TOP w0.254: CN6301.18 190.36,27.77 189.52,26.93 AFTP6309.1 186.76,26.93 186.54,26.7 v1(185.94,26.7) R2909.1
AUD_SENSE: length 4.5
  BOTTOM w0.254: C2901.1 R2923.2 ; R2923.2 R2709.2 ; R2923.2 180.67,23.63 181.21,24.17 181.21,24.36 181.89,25.04 v1(181.89,25.06)
AUD_SENSE_A: length 4.3
  BOTTOM w0.203: HDA27.13 181.02,19.96
  BOTTOM w0.254: 181.02,19.96 180.74,20.24 180.74,20.24 180.44,20.54 v1(180.44,20.65) 180.44,21.05 180.45,21.06 R2709.1 179.56,21.68 179.3,21.95 R2722.2
AUD_SPK_L+: length 96.5
  TOP w1.016: v3(183.5,11.46) 183.22,11.46 182.48,10.72 182.48,9.16 177.67,4.35 95.75,4.35 93.57,6.53
  BOTTOM w0.203: 183.42,12.26 HDA27.42
  BOTTOM w0.381: v3(183.5,11.46) 183.5,12.18 183.42,12.26
  vias: v1(90.66,6.41)
AUD_SPK_L+_C: length 14
  TOP w1.016: v3(73.19,8.28) 73.19,8.88 73.89,9.58 79.76,9.58 82.79,6.56 85.1,6.56
AUD_SPK_L-: length 100.7
  TOP w1.016: v3(183.75,10.19) 183.75,8.53 178.3,3.07 95.21,3.07 92.98,5.3 91.59,5.3
  BOTTOM w0.203: 182.8,11.65 183.02,11.87 HDA27.43
  BOTTOM w0.381: 182.8,11.65 182.8,10.94 v1(183.13,10.6) 183.55,10.19 v3(183.75,10.19)
AUD_SPK_L-_C: length 12.1
  TOP w1.016: v3(74.7,8.28) 79.18,8.28 82.58,4.88 85.4,4.88
AUD_SPK_R+: length 95.5
  TOP w1.016: 91.77,10.97 92.95,10.97 v1(94.04,9.89) 96.99,6.94 176.67,6.94 180.68,10.95 v3(181.21,10.95)
  BOTTOM w0.203: 181.69,11.74 182.22,12.26 HDA27.45
  BOTTOM w0.381: v3(181.21,10.95) 181.21,11.26 181.69,11.74
AUD_SPK_R+_C: length 17.8
  TOP w1.016: 84.94,10.67 82.27,10.67 80.82,12.12 72.54,12.12 70.16,9.74 v3(70.16,8.28)
AUD_SPK_R-: length 97.3
  TOP w1.016: v3(181.21,9.68) 177.15,5.62 96.51,5.62 92.69,9.44 91.54,9.44 91.53,9.43 91.31,9.43
  BOTTOM w0.203: HDA27.44 182.62,12.08 182.33,11.79
  BOTTOM w0.381: 182.33,11.79 182.18,11.64 182.18,10.64 v1(181.76,10.23) 181.53,9.99 181.52,9.99 v3(181.21,9.68)
AUD_SPK_R-_C: length 16.3
  TOP w1.016: v3(71.58,8.28) 71.58,9.31 73.13,10.85 80.3,10.85 82.4,8.74 85.33,8.74
AUD_VREF: length 2.8
  BOTTOM w0.203: C2705.2 188.31,17.72 187.72,17.72 v1(187.63,17.63) 187.29,17.29 HDA27.28
BAT_AMBER: length 15.2
  TOP w0.508: LED1.1 16.2,2.35 17.95,4.09 27.23,4.09 27.85,4.72 v1(28.23,4.72) 29.56,4.72 R6103.1
BAT_IN#: length 220.2
  TOP w0.102: KBC24.80 176.36,75.18 175.72,75.82 175.72,76.59 175.55,76.76 174.75,76.76 R2414.1 174.08,76.1 173.31,76.1 173.29,76.12 168.94,76.12 v2(168.91,76.09) ; PR4472.2 PC4433.1 113.08,170.54 111.17,172.45 111.17,174.03 v2(111.26,174.12) ; v2(164.58,73.7) 164.82,73.93 164.82,82.84 161.54,86.12 161.54,88.32 159.03,90.83 157.66,90.83 156.85,91.64 v1(156.85,92.61) 156.85,93.8 155.44,95.2 v2(155.19,95.2) ; RN4301.1 163.76,174.18 165.56,175.98 170,175.98 172.68,178.67 D4302.3 174.76,178.07 175.11,177.71 175.11,176.24 175.61,175.75 EC4305.2 175.51,175.18 174.85,175.18 174.66,175.37 174.66,176.46 v2(174.68,176.48)
  L3 w0.102: v2(111.26,174.12) 112.1,174.96 122.16,174.96 122.84,175.65 125.38,175.65 126.8,177.07 141.51,177.07 146.11,172.47 149.62,172.47 150.55,171.54 v2(151.63,171.54) 152.56,172.47 156.63,172.47 160.66,176.5 174.34,176.5 174.36,176.48 v2(174.68,176.48) ; v2(152.88,125.08) 152.9,125.1 153.55,125.1 153.81,124.85 153.81,124.41 153.63,124.23 153.63,120.91 154.29,120.25 154.29,118.11 154.03,117.85 154.03,111.86 152.85,110.67 152.85,100.54 152.73,100.42 152.63,100.32 152.63,98.81 155.19,96.25 v2(155.19,95.2) ; v2(164.58,73.7) 166.98,76.09 v2(168.91,76.09)
  L4 w0.102: v2(152.88,125.08) 152.88,125.2 153.74,126.06 153.74,130.69 154.85,131.8 154.85,142.14 152.12,144.86 152.12,146.59 152.01,146.71 152.01,150.24 151.57,150.68 151.57,152.7 152.52,153.65 152.52,169.54 151.63,170.43 v2(151.63,171.54)
BAT_SCL: length 264.6
  TOP w0.203: RN4301.3 163.76,175.33 165.22,176.8 165.25,176.8 165.27,176.81 169.59,176.81 173.21,180.44 186.62,180.44 187.65,179.41 D4301.3 187.22,178.4 186.5,178.4 185.99,177.89 185.99,175.49 EC4301.1 v2(186.1,174.62) ; v2(173.9,86.78) 173.92,86.76 173.92,84.37 173.03,83.48 173.03,81.32 174.16,80.19 174.76,80.19 ; 174.76,80.19 175.3,80.19 176.31,79.19 KBC24.70 ; 174.76,80.19 v1(174.76,80.07)
  L3 w0.203: v2(154.96,174.22) 154.96,174.03 154.85,173.92 146.71,173.92 142.11,178.52 123.25,178.52 121.22,176.48 103.9,176.48 99.78,172.36 99.78,164.28 100.03,164.02 v2(100.03,163.45)
  L4 w0.203: v2(186.1,174.62) 185.57,175.15 184.73,175.15 184.42,174.84 181.77,174.84 180.41,176.2 177.12,176.2 176.92,176 174.18,176 173.46,176.72 170.78,176.72 170.31,176.24 168.89,176.24 167.69,175.04 155.6,175.04 154.96,174.4 v2(154.96,174.22) 155.1,174.09 155.1,173.84 154.74,173.49 151.64,173.49 150.53,172.37 150.53,170.18 151.71,169 151.71,153.99 150.15,152.43 150.15,148.57 149.39,147.81 149.39,144.95 153.96,140.37 153.96,132.42 151.01,129.47 151.01,125.03 151.53,124.52 151.85,124.52 153.5,122.86 153.5,122.03 155.16,120.37 155.16,116.84 154.11,115.79 154.11,103.97 155.65,102.43 155.65,99.67 160.64,94.69 160.64,93.86 164.17,90.32 171.77,90.32 174.05,88.04 174.05,86.93 v2(173.9,86.78)
  BOTTOM w0.203: v2(100.03,163.45) 100.69,163.45 100.85,163.29 101.55,163.29 102.37,162.47 102.37,161.44 RN4401.3 102.64,161.17 103.85,161.17 PG4407.2 ; v2(173.9,86.78) 173.88,86.77 RN2401.3
BAT_SDA: length 259
  TOP w0.203: v2(174.57,86.6) 174.33,86.35 174.33,84.2 173.44,83.31 173.44,81.49 174.33,80.6 175.47,80.6 176.48,79.59 KBC24.69 ; RN4301.2 163.83,174.83 165.39,176.39 165.42,176.39 165.44,176.41 169.75,176.41 173.38,180.03 182.95,180.03 183.66,179.32 D4303.3 184.78,178.83 185.59,178.03 185.59,175.77 EC4302.1 v2(185.18,174.63)
  L3 w0.203: v2(100.52,162.95) 100.52,164.11 100.18,164.44 100.18,172.19 104.07,176.08 121.38,176.08 123.42,178.11 141.95,178.11 146.54,173.51 155.02,173.51 155.59,174.08 v2(155.59,174.3)
  L4 w0.203: v2(185.18,174.63) 185.13,174.68 184.83,174.68 184.58,174.44 181.6,174.44 180.24,175.8 177.29,175.8 177.09,175.59 173.97,175.59 173.26,176.31 170.95,176.31 170.47,175.84 169.06,175.84 167.85,174.63 155.8,174.63 155.59,174.42 v2(155.59,174.3) 155.5,174.21 155.5,173.67 154.91,173.08 151.81,173.08 150.94,172.2 150.94,170.34 152.11,169.17 152.11,168.83 152.11,153.82 150.56,152.26 150.56,148.4 149.8,147.64 149.8,145.11 154.37,140.54 154.37,132.25 151.42,129.3 151.42,125.2 151.7,124.92 152.01,124.92 153.91,123.03 153.91,122.2 155.57,120.54 155.57,117.01 155.57,116.67 154.52,115.62 154.52,104.14 156.06,102.6 156.06,99.84 161.04,94.85 161.04,94.03 164.34,90.73 171.93,90.73 174.45,88.21 174.45,86.72 v2(174.57,86.6)
  BOTTOM w0.203: RN2401.4 174.53,86.56 v2(174.57,86.6) ; PG4408.2 103.83,160.28 103.47,160.64 102.63,160.64 RN4401.4 102.25,160.58 101.96,160.87 101.96,162.3 101.38,162.88 101.05,162.88 ; v1(101.05,162.61) 101.05,162.88 ; 101.05,162.88 100.58,162.88 v2(100.52,162.95)
BAT_WHITE: length 16.7
  TOP w0.508: R6107.1 32.69,3.68 v1(28.86,3.68) 28.12,3.68 27.92,3.48 18.76,3.48 LED1.2
BATLOW#: length 41.1
  TOP w0.102: v2(166.85,80.24) 167.11,80.5 RN2006.4
  L3 w0.102: v2(135.47,77) 135.54,77 135.95,77.4 136.54,77.4 138.03,78.9 140.81,78.9 141.6,79.68 143.7,79.68 145.15,78.23 147.05,78.23 147.05,78.24 150.37,78.24 151.03,78.9 152.74,78.9 155.15,76.48 158.4,76.48 160.17,78.25 160.17,80.39 161.87,82.09 162.47,82.09 164.71,79.85 166.4,79.85 166.79,80.24 v2(166.85,80.24)
  BOTTOM w0.102: v2(166.85,80.24) 167.39,80.24 v1(167.42,80.27) ; v2(135.47,77) 135.47,76.89 CPU1.AN4
BATT_WHITE_LED#: length 230.3
  TOP w0.102: v2(180.76,69.29) 180.76,69.31 180.16,69.9 180.16,70.43 180.98,71.25 181,71.25 182.64,72.89 182.64,76.25 181.31,77.59 181.31,77.62 181.01,77.92 181.01,80.24 179.6,81.65 KBC24.62 ; R6104.1 36.44,9.84 36.76,10.15 v1(37.15,10.15) 37.3,10.15 37.46,10 37.46,9.77 v2(37.19,9.5)
  L3 w0.102: v2(37.19,9.5) 37.54,9.85 45.85,9.85 51.12,4.58 71.42,4.58 71.74,4.9 76.34,4.9 76.67,4.58 162.79,4.58 165.97,7.76 165.97,15 167.27,16.3 167.27,19.53 178.83,31.1 178.83,35.38 179.22,35.77 180.1,35.77 181.47,34.4 185.99,34.4 v2(186.76,35.17)
  L4 w0.102: v2(180.76,69.29) 181.11,68.94 181.11,63.79 182.53,62.37 182.53,59.53 183.7,58.36 183.7,54.66 184.44,53.93 184.44,49.36 183.62,48.54 183.62,45.11 183.7,45.04 183.7,44.51 183.91,44.3 183.91,40.82 186.39,38.34 186.39,36.58 186.58,36.39 186.58,35.36 v2(186.76,35.17)
BATT_WHITE_LED_R#: length 6.9
  TOP w0.102: Q6102.B 35.89,8.49 35.55,8.83 R6104.2 35.55,10.51 36.43,11.39 v1(37.07,11.39) 37.68,11.39 38.33,10.74 Q6105.D
BKLT_CTRL: length 18.4
  TOP w0.14: v2(65.51,164.85) 65.51,164.83 64.02,166.32 D5202.3
  L4 w0.127: v2(75.06,169.11) 75.06,169 73.75,167.69 v2(73.54,167.69)
  BOTTOM w0.14: RN5201.7 75.25,167.59 75.17,167.68 75.17,169 75.06,169.11 v2(75.06,169.11) ; v2(73.54,167.69) 73.17,167.32 73.17,166.69 72.92,166.44 RN5203.8 70.99,165.28 v1(69.7,165.28) 68.32,165.28 R5222.1 65.65,164.99 v2(65.51,164.85)
BLON_OUT: length 217.9
  TOP w0.102: KBC24.27 191.3,79.19 v2(190.87,79.62)
  L4 w0.102: v2(145.63,161.87) 145.25,162.24 145.25,172.22 142.32,175.15 141.91,175.15 128.78,175.15 128.59,175.34 115.67,175.34 114.26,176.75 109.59,176.75 109.37,176.53 108.66,176.53 108.44,176.75 106.2,176.75 103.77,174.32 84.07,174.32 83.8,174.58 76.81,174.58 v2(74.26,172.03) ; v2(189.72,84.16) 189.72,81.72 190.46,80.98 190.84,80.98 191.07,80.75 191.07,79.82 v2(190.87,79.62)
  BOTTOM w0.102: v2(145.63,161.87) 144.28,161.87 143.24,160.83 143.24,149.73 142.65,149.15 142.65,147.83 143.61,146.87 143.61,138.96 143.12,138.47 143.12,136.05 143.67,135.5 143.67,119.91 v1(145.47,118.12) 148.86,114.72 148.86,106.68 150.4,105.14 150.4,103.62 151.41,102.61 151.41,101.53 152.79,100.16 152.79,96.92 153.22,96.49 153.22,93.26 154.33,92.14 154.33,90.61 154.47,90.47 157.24,87.71 162.06,87.71 162.78,88.43 169.49,88.43 170.59,87.34 174.44,87.34 175.21,86.58 175.21,85.44 177.31,83.34 180.01,83.34 181.23,84.56 186.3,84.56 186.48,84.38 189.49,84.38 v2(189.72,84.16) ; v2(74.26,172.03) 74.26,169.8 74.53,169.53 74.53,167.72 75.15,167.09 RN5201.6
BLON_OUT_C: length 10.7
  TOP w0.102: v1(80.24,166.15) 79.82,166.57 79.51,166.57 79.26,166.82 LCD1.21 77.52,166.82 v2(77.45,166.76) 75.9,168.31 73.63,168.31 v2(73.61,168.33)
  BOTTOM w0.102: v2(73.61,168.33) 73.57,168.33 72.74,167.5 72.74,167.2 72.63,167.09 RN5203.7 ; RN5201.3 77.12,167.09 v2(77.45,166.76)
BLUETOOTH_EN: length 117.5
  TOP w0.102: RN2011.5 143.86,98.02 142.97,97.13 142.56,97.13 142.55,97.13 141.64,97.13 140.36,95.85 140.36,94.86 137.73,92.23 137.5,92.23 137.14,91.88 136.89,91.88 v2(135.48,90.47) ; R5804.1 178.43,54.62 179.96,54.62 181.71,56.37 187.64,56.37 188.45,57.18 v1(189.54,57.18) 189.95,57.18 193.11,60.34 v2(193.11,60.66)
  L3 w0.102: v2(191,71.75) 190.58,72.18 190.58,72.79 191.17,73.38 191.17,75.1 190.88,75.39 190.88,75.92 190.96,76 190.96,77.65 190.15,78.47 190.15,79 189.82,79.33 188.28,79.33 187.57,80.04 186.37,80.04 185.51,80.9 185.51,82.1 182.21,85.39 181.38,85.39 179.23,87.54 177.2,87.54 175.63,89.11 163.88,89.11 158.79,94.2 156.91,94.2 156.11,93.4 155.04,93.4 153.16,95.28 149.65,95.28 149.22,95.71 146.74,95.71 145.65,94.62 142.42,94.62 141.41,93.61 141.41,93.37 138.46,90.43 136.78,90.43 136.41,90.05 135.9,90.05 v2(135.48,90.47)
  L4 w0.102: v2(191,71.75) 191.73,71.02 191.73,64.81 193.11,63.43 193.11,62.64 193.97,61.78 193.97,61.43 193.2,60.66 v2(193.11,60.66)
  BOTTOM w0.102: CPU1.J4 135.16,90.15 v2(135.48,90.47)
BLUETOOTH_EN_NGFF: length 10.4
  TOP w0.102: v2(176.89,51.14) AFTP5804.1 176.28,51.57 176.46,51.76 177.54,51.76 177.9,52.12 R5804.2
  BOTTOM w0.102: WLAN1.54 175.47,49.77 176.62,50.92 176.66,50.92 v2(176.89,51.14)
BMON: length 133.3
  TOP w0.203: v2(176.2,68) 177,68 177.25,68.25 KBC24.96
  TOP w0.254: v2(130.08,169.52) 129.5,169.52 v1(128.89,170.13) 128.73,170.29 127.08,170.29 126.75,169.96 PR4452.1
  L4 w0.254: v2(176.2,68) 176.2,68.32 175.33,69.18 175.33,70.48 172.65,73.16 172.65,73.85 172.23,74.27 171.4,74.27 170.49,75.18 170.49,75.56 169.18,76.86 168.39,76.86 164.47,80.78 164.47,83.09 164.17,83.39 161.04,83.39 157.63,86.8 156.86,86.8 153.92,89.74 152.24,89.74 151.98,90.01 151.98,91.6 148.81,94.76 147.63,94.76 145.24,97.15 145.24,98.94 142.6,101.58 142.6,107.19 142.83,107.43 142.83,112.12 138.75,116.2 138.75,123.04 139.39,123.68 139.39,149.55 138.73,150.21 138.73,151.86 139.99,153.12 139.99,154.85 135.36,159.47 135.36,161.61 131.6,165.36 131.6,168.84 130.92,169.52 v2(130.08,169.52)
BOARD_ID2: length 9.7
  BOTTOM w0.089: CPU1.Y3 136.06,83.83 137.3,83.83 137.57,84.1
  BOTTOM w0.102: 137.57,84.1 137.75,84.28 139.62,84.28 140.54,85.19 v1(141.03,85.19) 142.38,85.19 142.83,84.74 R2008.1 R2005.2
BOARD_ID3: length 20
  TOP w0.102: R2025.2 149.24,94.78 R2026.1 149.11,95.74 148.39,95.74 v2(147.94,95.28) 147.75,95.09 v1(147.75,94.75)
  L3 w0.102: v2(147.94,95.28) 146.6,95.28 145.74,94.42 142.5,94.42 141.61,93.53 141.61,93.21 140.22,91.83 140.19,91.83 139.89,91.52 139.89,91.5 138.62,90.23 137.23,90.23 136.57,89.57 136.57,88.59 v2(135.47,87.49)
  BOTTOM w0.102: v2(135.47,87.49) 135.81,87.15 CPU1.P3
BOOST_10V: length 9.8
  BOTTOM w0.254: PD4502.1 45.3,59.59 44.1,59.59 v1(44.02,59.52) 43.97,59.46 43.97,58.69 PC4534.1 45.85,56.81 PD4503.2
BOOST_MODE#: length 172
  TOP w0.203: KBC24.20 v2(191.42,76.38)
  L3 w0.254: v2(191.42,76.38) 191.42,77.63 190.53,78.52 190.53,79.07 189.97,79.63 188.41,79.63 187.64,80.4 186.94,80.4 186.49,80.85 186.49,81.65 184.49,83.65 184.49,83.72 182.51,85.7 181.65,85.7 179.48,87.86 177.35,87.86 175.8,89.41 164.01,89.41 158.91,94.51 156.78,94.51 155.98,93.71 155.16,93.71 153.28,95.58 149.79,95.58 148.71,96.67 147.7,96.67 147.5,96.87 146.55,96.87 145.31,95.62 143.48,95.62 v2(143.39,95.53)
  L4 w0.254: v2(143.39,95.53) 143.11,95.81 142.19,95.81 141.43,96.57 141.43,99.93 140.81,100.56 140.81,103.39 140.6,103.6 140.6,106.03 140.42,106.2 140.42,107.7 140.75,108.03 140.75,111.97 137.27,115.45 137.27,123.64 137.88,124.25 137.88,146.28 135.36,148.8 121.6,148.8 120.64,147.84 106.04,147.84 103.43,150.45 103.41,150.45 102.8,151.06 102.8,151.08 101.28,152.6 101.28,152.85 101.28,152.85 101.28,157.66 101.45,157.84 101.47,157.84 102.45,158.81 102.45,163.46 102.34,163.56 102.34,163.94 101.89,164.4 v2(101.89,164.98)
  BOTTOM w0.254: v2(101.89,164.98) 101.95,165.04 v1(102.87,165.04) PR4435.2 104.07,165.14 PR4439.2 104.83,165.16 PR4418.1
BOOST_MON_1: length 3.5
  TOP w0.254: v1(127.67,170.83) 127.53,170.83 127.53,170.83 PR4452.2 126.36,171.23 PC4427.1 125,171.23 124.69,170.91 124.69,170.9 PR4446.1
BP_PWRGD_RST#: length 1.5
  BOTTOM w0.14: TP9645.1 186.69,68.61 187.27,68.61 R9603.2
BST15V_1: length 4.5
  TOP w0.254: v1(48.76,55.41) v2(48.01,56.16) PC4514.2
  BOTTOM w0.254: PD4503.3 47.57,54.6 48.01,55.05 v2(48.01,56.16)
BST15V_2: length 4.8
  TOP w0.254: PC4532.2 48.12,58.44 v2(49,57.56) v1(50.08,57.56)
  BOTTOM w0.254: PD4502.3 48.53,57.09 v2(49,57.56)
BT+: length 18.8
  TOP w0.635: 164.05,178.78 BATT1.2 165.04,179.77 ; BATT1.1 167.04,179.77 ; BATT1.1 165.06,179.77 ; BATT1.1 166.05,178.78
  L4 w0.635: 164.05,178.78 BATT1.2 ; BATT1.2 164.05,180.76 ; BATT1.2 165.04,179.77 ; 165.06,179.77 BATT1.1 ; BATT1.1 167.04,179.77 ; BATT1.1 166.05,178.78 ; BATT1.1 166.05,180.76
  BOTTOM w0.635: BATT1.2 164.05,180.76 ; BATT1.2 164.05,178.78 ; BATT1.2 165.04,179.77 ; BATT1.1 166.05,180.76 ; BATT1.1 167.04,179.77 ; BATT1.1 166.05,178.78 ; BATT1.1 165.06,179.77
  vias: v1(134.21,172.17) v1(138.88,175.12) v3(136.72,173.46) v3(136.73,172.09) v3(136.71,170.01) v3(136.72,168.65) v3(138.11,173.46) v3(138.15,172.15) v3(138.1,170.01) v3(138.14,168.7) v3(139.64,161.93) v3(139.74,170.11) v3(140.25,173.53) v3(140.26,172.16) v3(140.39,161.47) v3(140.93,158.02) v3(141.23,160.91) v3(141.65,173.53) v3(141.69,172.22) v3(146.01,177) v3(146.01,175.99) v3(147.03,177) v3(147.03,175.99) v3(148.05,177) v3(148.05,175.99) v3(149.06,177) v3(149.06,175.99) v3(150.08,177) v3(150.08,175.99) v3(163.74,178.41) v3(164.16,177.68) v3(164.74,178.45) v3(165.19,177.67) v3(165.79,178.44) v3(166.25,177.67) v3(166.75,178.44)
BT+_R:
  vias: v1(134.58,163.25)
BUFRST#: length 2
  TOP w0.102: v1(174.58,136.71) 174.58,137.01 v2(174.84,137.27) 175.11,137.01 R7628.2
  BOTTOM w0.102: GPU1.D11 174.45,137.66 v2(174.84,137.27)
CAMERA_PWR_EN: length 4.2
  TOP w0.102: v2(138.33,77.38) 138.72,76.99 TP2002.1
  BOTTOM w0.089: CPU1.AM4 135.45,77.7 135.94,77.7 135.98,77.66 137.42,77.66 137.51,77.75 137.96,77.75 v2(138.33,77.38)
CAP_LED: length 9.8
  TOP w0.305: KB1.4 193.52,113.75 v2(193.78,113.49) 193.99,113.28 194.56,113.28 196.43,111.41 AFTP6243.1
  TOP w0.508: v2(194.47,116.02) 194.17,116.32 R6201.2
  L4 w0.305: v2(194.47,116.02) 193.84,115.39 193.84,113.55 v2(193.78,113.49)
CAP_LED#: length 69.3
  TOP w0.102: v2(184,65.9) 183.6,66.3 KBC24.109 ; v2(195.72,113.7) 196.06,113.36 196.56,113.36 196.91,113 R6202.1
  L4 w0.102: v2(196.6,64.06) 196.6,65.07 195.43,66.24 195.43,71.78 194.77,72.45 194.77,75.88 194.52,76.13 194.52,81.26 194.53,81.26 194.53,82.07 195,82.54 195,86.87 195.16,87.04 195.16,87.53 194.01,88.68 194.01,112 v2(195.72,113.7)
  BOTTOM w0.102: v2(196.6,64.06) 196.6,64.05 196.33,63.78 195.44,63.78 195.11,64.11 193.4,64.11 192.99,64.52 186.34,64.52 v1(184.49,66.37) 184.23,66.37 184,66.14 v2(184,65.9)
CAP_LED_Q: length 1.5
  TOP w0.508: Q6201.C 195.06,116.5 R6201.1
CAP_LED_R#: length 2
  TOP w0.102: Q6201.B 194.68,114.13 195.28,113.53 195.28,113.52 195.54,113.27 195.54,113.27 R6202.2
CARD_PWR_EN: length 17.8
  BOTTOM w0.089: CPU1.AL2 136.6,78.12 136.89,78.41 137.29,78.41 137.52,78.18 138.08,78.18
  BOTTOM w0.102: 138.08,78.18 138.41,78.18 138.93,77.66 138.93,77.5 139.29,77.14 141.24,77.14 141.72,77.62 143.48,77.62 144.81,78.94 146.27,78.94 v1(147.95,80.62) 147.95,81.57 148.66,82.28 148.96,82.28 149.24,82.56 150.47,82.56 RN1809.8
CBN: length 3.2
  BOTTOM w0.203: 187.13,14.3 186.95,14.49 HDA27.35
  BOTTOM w0.254: v1(188.63,12.93) 188.16,13.4 C2703.1 187.69,13.75 187.13,14.3
CFG0: length 2.2
  TOP w0.14: v1(100.57,82.34) 100.77,82.54 v2(100.77,83.02) 100.77,83.19 101.22,83.64 TP9626.1
  BOTTOM w0.14: v2(100.77,83.02) 100.77,82.96 CPU1.AC60
CFG1: length 3.5
  TOP w0.14: TP9627.1 97.44,82.69 97.3,82.55 97.3,82.32 v2(97.03,82.04)
  BOTTOM w0.089: v2(97.03,82.04) 97.42,82.43 98.18,82.43 98.24,82.37 98.71,82.37 99,82.66 CPU1.AC62
CFG2: length 3
  TOP w0.14: TP9620.1 96.4,82.08 96.38,82.07 v2(96.38,82.03)
  BOTTOM w0.102: v2(96.38,82.03) 97,82.64 98.27,82.64 98.28,82.64 98.3,82.66 CPU1.AC63
CFG3: length 7.5
  BOTTOM w0.089: CPU1.AA63 98.28,83.41 98.06,83.18 98.05,83.18 96.64,83.18 95.44,84.38 93.93,84.38 TP9622.1
  BOTTOM w0.14: R604.1 91.86,85.03 93.28,85.03 TP9622.1
CFG4: length 11.1
  TOP w0.14: v2(92.56,84.21) 92.56,83.77 v1(92.91,83.42) 93.51,82.82 95.66,82.82 96.18,83.33 97.88,83.33 98.12,83.58 TP9630.1 98.88,83.38 98.88,82.86 99.32,82.41 99.72,82.41 100.14,82.83 v2(100.14,83.04)
  BOTTOM w0.14: v2(100.14,83.04) 100.44,83.34 CPU1.AA60 ; R605.1 v2(92.56,84.21)
CFG5: length 3.7
  TOP w0.14: TP9631.1 97.88,84.73 97.11,83.96 v2(97.11,83.92)
  BOTTOM w0.089: CPU1.Y62 98.91,84.16 98.62,83.87 98.24,83.87 97.91,83.54 97.9,83.54 97.49,83.54 v2(97.11,83.92)
CFG6: length 1.5
  TOP w0.14: TP9629.1 99.95,84.07 v2(99.49,84.53)
  BOTTOM w0.102: v2(99.49,84.53) 99.49,84.53 99.79,84.24 CPU1.Y61
CFG7: length 5.3
  TOP w0.14: TP9628.1 96.69,84.15 v2(96.47,83.94)
  BOTTOM w0.089: CPU1.Y60 100.15,83.83 99.49,83.83 99.45,83.87 98.87,83.87 98.69,83.69 98.32,83.69 97.98,83.36 97.97,83.36 97.05,83.36 v2(96.47,83.94)
CFG8: length 6.3
  TOP w0.14: TP9633.1 93.73,84.9 v2(94.18,85.36)
  BOTTOM w0.089: 94.67,84.87 94.74,84.8 97.46,84.8 97.82,84.44 98.55,84.44 98.69,84.44 98.98,84.73 98.98,84.75 CPU1.V62
  BOTTOM w0.14: v2(94.18,85.36) 94.18,85.35 94.67,84.87
CFG9: length 8.1
  TOP w0.14: v2(94.83,85.36) 94.51,85.68 TP9632.1
  BOTTOM w0.089: v2(94.83,85.36) 95.2,84.98 97.71,84.98 98.07,84.62 98.62,84.62 98.8,84.8 98.8,84.99 99,85.19 99.54,85.19 CPU1.V61
  BOTTOM w0.14: v2(94.83,85.36) 94.83,85.55 95.54,86.26 v1(95.54,86.73)
CFG10: length 1.3
  TOP w0.14: TP9637.1 100.47,84.87 v2(100.14,84.53)
  BOTTOM w0.102: CPU1.V60 100.44,84.84 v2(100.14,84.53)
CFG11: length 4.8
  TOP w0.14: TP9639.1 97.01,85.65 v2(96.88,85.53)
  BOTTOM w0.089: v2(96.88,85.53) 97.16,85.81 97.74,85.81 97.94,85.61 97.94,85.53 98.28,85.19 98.7,85.19 98.88,85.37 99.62,85.37 99.66,85.33 100.15,85.33 CPU1.U60
CFG12: length 3
  TOP w0.14: v2(96.67,87.22) 96.14,87.75 TP9640.1
  BOTTOM w0.14: v2(96.67,87.22) 97.28,86.62 98.15,86.62 98.36,86.4 CPU1.T63
CFG13: length 5.2
  TOP w0.14: TP9643.1 95.34,87.89 v2(96,87.23)
  BOTTOM w0.14: v2(96,87.23) 96.84,86.39 98.03,86.39 98.35,86.07 98.8,86.07 CPU1.T62
CFG14: length 3.5
  TOP w0.14: TP9642.1 97.41,87.31 v2(97.33,87.23)
  BOTTOM w0.14: v2(97.33,87.23) 97.71,86.85 98.24,86.85 98.36,86.73 99.29,86.73 99.58,86.44 CPU1.T61
CFG15: length 1.7
  TOP w0.14: v2(100.13,86.03) 100.13,85.89 99.73,85.49 TP9641.1
  BOTTOM w0.14: v2(100.13,86.03) 100.44,86.34 CPU1.T60
CFG16: length 6
  TOP w0.14: v2(94.59,83.95) 94.2,83.56 TP9635.1
  BOTTOM w0.089: CPU1.AA62 99.14,83.29 98.79,82.94 98.32,82.94 98.2,82.83 98.2,82.83 95.72,82.83 95.6,82.94
  BOTTOM w0.14: v2(94.59,83.95) 95.6,82.94
CFG17: length 6.2
  TOP w0.14: TP9634.1 95.21,83.8 95.31,83.89 v2(95.31,83.94)
  BOTTOM w0.089: CPU1.AA61 99.51,83.45 99.51,83.45 99.27,83.69 99,83.69 98.8,83.49 98.8,83.3 98.62,83.12 98.25,83.12 98.13,83.01 98.12,83 96.23,83 96.04,83.2
  BOTTOM w0.14: v2(95.31,83.94) 95.31,83.93 96.04,83.2
CFG18: length 4.2
  TOP w0.14: TP9636.1 95.46,85.18 v2(95.46,85.53)
  BOTTOM w0.114: CPU1.U63 98.41,85.66 97.89,86.18 96.07,86.18 95.46,85.56 v2(95.46,85.53)
CFG19: length 4.2
  TOP w0.14: TP9638.1 95.76,86 v2(96.22,85.54)
  BOTTOM w0.089: v2(96.22,85.54) 96.66,85.99 97.81,85.99 98.11,85.69 98.11,85.61 98.35,85.37 98.62,85.37 98.91,85.66 CPU1.U62
CFG_RCOMP: length 8.2
  TOP w0.356: v2(92.64,85.99) v1(92.64,86.69)
  L4 w0.508: v2(92.64,85.99) 92.64,85.99 93.94,85.99 94.24,86.28 97.02,86.28 97.54,85.77 v2(97.54,85.41)
  BOTTOM w0.178: CPU1.V63 98.23,84.91 97.73,85.41 v2(97.54,85.41)
  BOTTOM w0.508: R601.2 v2(92.64,85.99)
CHARGER_SRC:
  vias: v1(121.2,158.28) v3(117.18,157.41) v3(118.04,157.38) v3(118.93,157.36) v3(119.82,157.36) v3(120.73,157.36)
CHG_AGND: length 11.3
  TOP w0.635: PC4403.2 112.03,157.9 112.36,158.24 112.36,158.42 v2(112.53,158.59)
  BOTTOM w0.254: PQ4401.1 104.51,155.29 104.85,155.63 104.85,156 105.44,156.59 PQ4401.4
  BOTTOM w0.305: PQ4401.4 105.96,157.04 105.72,157.28 104.74,157.28 104.59,157.13 v2(102.11,157.13)
  BOTTOM w0.508: PC4010.2 113.27,157.79 112.53,158.52 v2(112.53,158.59) ; PR4423.2 103.74,162.49 103.33,162.89 v2(103.13,162.89)
  vias: v1(108.51,163.56) v2(109.15,161.5) v2(109.86,161.5) v2(110.55,161.47)
CHG_AMBER_LED#: length 235.4
  TOP w0.102: KBC24.16 190.66,74.79 190.58,74.86 v2(190.58,74.86) ; v2(32.29,11.41) 32.28,11.39 32.28,10.23 33.17,9.34 R6105.1 34.22,9.2 v1(34.36,9.33)
  L3 w0.102: v2(194.72,37.11) 194.72,36.63 193.56,35.46 187.38,35.46 187.03,35.81 186.38,35.81 185.71,35.13 182.57,35.13 181.19,36.51 179.39,36.51 178.42,35.54 178.42,31.27 166.86,19.7 166.86,16.47 165.57,15.17 165.57,7.93 162.62,4.99 76.84,4.99 76.51,5.31 71.57,5.31 71.25,4.99 51.31,4.99 45.9,10.4 37.76,10.4 37.14,11.03 32.67,11.03 v2(32.29,11.41)
  L4 w0.102: v2(190.58,74.86) 191.94,73.5 191.94,65.29 191.94,64.89 193.31,63.52 193.31,62.73 194.17,61.86 194.17,53.99 194.67,53.49 194.67,41.18 193.58,40.09 193.58,38.26 v2(194.72,37.11)
CHG_AMBER_LED_R#: length 2.4
  TOP w0.102: Q6101.B 32.08,8.64 32.28,8.84 R6105.2 32.22,9.26 v1(31.34,9.26)
CLK_DP2VGA: length 325.5
  TOP w0.14: v2(178.09,58.07) 177.15,58.07 175.79,59.43 175.07,59.43 174.19,60.31 171.11,60.31 171.05,60.25 165.64,60.25 161.27,55.88 157.87,55.88 156.57,54.59 146.9,54.59 145.09,56.39 134.15,56.39 131.02,59.53 v1(131.02,60.15) 131.02,62.83 130.28,63.57 R1813.2 ; v2(22.25,57.02) 22.29,56.98 24.69,56.98 25.54,57.82 25.54,59.97 26.64,61.08 U5502.17
  L3 w0.127: v2(22.25,57.02) 21.61,57.02 16.23,51.64 16.23,36.43 17.44,35.22 17.44,24.77 17.91,24.3 17.91,19.74 20.06,17.6 20.06,16.26 21.32,14.99 21.32,12.7 23.05,10.98 30.62,10.98 32.65,8.95 45.82,8.95 50.75,4.02 71.65,4.02 71.97,4.35 76.11,4.35 76.44,4.02 163.19,4.02 166.55,7.38 166.55,14.74 167.8,15.99 167.8,16.04 167.82,16.07 167.82,18.81 182.81,33.8 183.4,33.8 183.55,33.65 v2(183.55,33.66)
  L4 w0.127: v2(183.55,33.66) 183.99,34.11 183.99,35.84 182.53,37.3 182.53,38.62 181.98,39.17 181.98,43.5 181.56,43.92 181.56,48.27 181.31,48.52 181.31,51.58 179.64,53.25 179.64,56.52 v2(178.09,58.07)
CLK_LAN_REQ4#_R: length 10.1
  TOP w0.127: Q3002.E 50.36,162.93 v2(50.43,163) 50.82,162.61 R3005.2 52.38,162.62 R3004.2 ; v2(48.55,165.71) 48.73,165.9 LOM30.12
  BOTTOM w0.127: v2(48.55,165.71) v1(48.55,164.77) 48.55,163.93 49.48,163 v2(50.43,163)
CLK_LAN_REQ#_EN: length 4.8
  TOP w0.127: Q3002.B 48.59,164.28 47.81,163.5 47.81,161.95 v1(47.61,161.75) 47.21,161.75 47.01,161.95 R3003.2
CLK_PCI_KBC: length 87.7
  TOP w0.14: R1805.2 EC1801.1 127.5,62.63 127.5,60.74 v1(132.17,56.07) 133.01,55.22 144.51,55.22 146.31,53.42 157.08,53.42 158.94,55.27 161.5,55.27 165.84,59.62 171.25,59.62 171.36,59.73 173.79,59.73 174.67,58.85 175.55,58.85 176.95,57.45 178.73,57.45 179.17,57.89 189.85,57.89 192.39,60.43 192.39,60.86 192.77,61.24 193.23,61.24 194.01,62.03 194.01,62.62 194.04,62.64 194.04,63.15 195.16,64.27 195.16,64.86 193.71,66.31 193.71,68.97 193.49,69.19 KBC24.2
CLK_PCI_KBC_R: length 12.8
  TOP w0.14: v2(128.54,76.34) 128.54,76.11 128.92,75.73 128.92,74.91 128.42,74.41 v1(128.42,69.75) 128.42,66.29 128.6,66.1 128.6,65.47 R1805.1
  BOTTOM w0.14: v2(128.54,76.34) 128.84,76.03 CPU1.AP15
CLK_PCI_LPC: length 63.2
  TOP w0.14: v2(157.94,55.12) 156.83,54 146.64,54 146.62,54.03 146.59,54.03 144.81,55.81 133.57,55.81 130.44,58.94 v1(130.44,62.11) 130.44,62.51 129.39,63.55 R1804.2
  L4 w0.127: v2(168.5,36.98) 168.49,36.99 168.49,37.35 167.09,38.75 167.09,46.86 161.45,52.5 161.45,52.56 161.17,52.84 161.12,52.84 161.12,52.86 158.86,55.12 v2(157.94,55.12)
  BOTTOM w0.14: DB1.9 165.91,34.34 166.23,34.66 166.23,35.09 168.12,36.98 v2(168.5,36.98)
CLK_PCI_LPC_R: length 14.5
  TOP w0.14: v2(128.53,77.04) 128.67,77.04 129.5,76.21 129.5,75.84 129.51,75.83 129.51,74.11 129.06,73.67 v1(129.06,67.48) 129.06,66.9 129.39,66.57 R1804.1 R1813.1
  BOTTOM w0.14: v2(128.53,77.04) 128.88,76.68 CPU1.AN15
CLK_PCIE_LAN_N4: length 119.3
  TOP w0.102: v2(51.94,165.44) 51.11,166.26 50.42,166.26 50.33,166.35 LOM30.16
  L4 w0.102: v2(51.94,165.44) 51.8,165.44 51.73,165.51 51.73,165.85 51.89,166.02 52.97,166.02 54.8,164.19 65.93,164.19 69.8,160.31 72.21,160.31 78.09,154.43 81.61,154.43 98.15,137.89 98.15,134.37 102.46,130.06 102.46,118.04 100.43,116.01 100.43,105.64 106.25,99.82 106.25,98.81 106.25,97.95 107.49,96.71 112.82,96.71 113,96.88 113.36,96.88 113.47,96.77 113.47,96.52 v2(113.4,96.45)
  BOTTOM w0.102: v2(113.4,96.45) 113.34,96.45 113.22,96.57 113.22,96.83 113.3,96.91 113.98,96.91 114.43,96.46 114.43,96.04 114.37,95.99 114.37,94.17 CPU1.B38 ; v2(51.94,165.44) 52.33,165.04 v1(52.33,165.03)
CLK_PCIE_LAN_P4: length 119.4
  TOP w0.102: LOM30.15 49.93,166.46 50.33,166.06 51.03,166.06 51.31,165.78 v2(51.31,165.39)
  L4 w0.102: v2(51.31,165.39) 51.5,165.58 51.5,165.95 51.8,166.25 53.06,166.25 54.89,164.42 66.02,164.42 69.9,160.54 72.3,160.54 78.19,154.66 81.7,154.66 98.38,137.99 98.38,134.47 102.68,130.16 102.68,117.94 100.66,115.91 100.66,105.73 106.48,99.91 106.48,98.71 106.47,98.71 106.47,98.05 107.59,96.94 112.72,96.94 112.9,97.11 113.22,97.11 v2(113.42,97.32)
  BOTTOM w0.102: v2(113.42,97.32) 113.62,97.11 114.06,97.11 114.63,96.55 114.63,95.96 114.58,95.91 114.58,94.27 114.63,94.22 114.63,94.03 114.88,93.78 CPU1.C37 ; v2(51.31,165.39) 51.37,165.45 v1(51.37,165.97)
CLK_PCIE_LAN_REQ4#: length 197.8
  TOP w0.127: R3005.1 51.96,163.5 51.54,163.91 Q3002.C 49.25,163.91 v2(49.13,164.04)
  L3 w0.127: v2(151.85,118.17) 152.19,117.83 152.19,112.59 150.29,110.68 150.29,103.34 144.98,98.03 144.98,97.89 143.39,96.3 143.18,96.3 143.1,96.22 143.09,96.22 142.7,95.84 142.7,95.83 142.38,95.51 142.3,95.51 v2(142.07,95.28)
  L4 w0.127: v2(151.85,118.17) 151.85,118.75 148.48,122.12 148.48,128.08 146.73,129.83 146.73,131.08 146.81,131.16 146.81,138.11 147.11,138.42 147.11,141.7 147.11,141.7 147.11,142.07 147.11,142.08 147.11,143.97 146.44,144.65 146.44,150.45 145.69,151.2 145.69,155.65 141.83,159.51 140.49,159.51 139.89,159.51 138.35,161.05 138.35,162.84 134.71,166.48 134.71,170.3 132.22,172.79 130.66,172.79 129.7,173.74 128.45,173.74 128.21,173.98 114.83,173.98 113.67,175.14 110.52,175.14 109.25,173.87 105.06,173.87 104.01,172.81 77.11,172.81 74.35,170.06 72.12,170.06 68.34,166.28 53.85,166.28 53.36,166.77 51.1,166.77 49.1,164.77 49.1,164.07 v2(49.13,164.04)
  BOTTOM w0.127: CPU1.N1 137.2,87.78 137.41,87.78 137.47,87.72 138.5,87.72 139.55,88.77 139.55,91.57 140.95,92.97 140.95,93.83 141.25,94.13 v1(141.25,94.24) 141.25,94.46 v2(142.07,95.28) 142.31,95.52 142.31,95.63 142.88,96.2 142.88,96.2 143.51,96.83 RN1505.6
CLK_PCIE_REQ#: length 18.6
  TOP w0.127: v2(139.02,86.57) 138.83,86.38 138.83,86.36 138.3,85.82 137.95,85.82 v1(137.74,85.61) 137.07,84.94 135.65,84.94 135.65,84.94 135.28,84.94 134.8,84.46 v2(134.66,84.46)
  BOTTOM w0.127: v2(134.66,84.46) 134.48,84.28 CPU1.Y5 ; 136.79,86.04 CPU1.T2 ; 136.79,86.04 136.46,85.71 CPU1.U2 ; 136.79,86.04 138.49,86.04 v2(139.02,86.57) 140.62,88.16 140.62,90.64 141.84,91.86 141.84,92.12 142.27,92.54 142.9,92.54 143.51,93.15 RN1801.6
CLK_PCIE_VGA: length 83.4
  TOP w0.102: v1(111.35,98.79) 111.07,98.51 v2(111.07,98.13)
  L3 w0.102: v2(157.45,135.63) 157.25,135.42 157.03,135.42 156.18,136.27 156.18,138.37 153.62,140.92 149.35,140.92 146.6,138.17 146.6,134.96 141.66,130.02 141.66,124.66 135.52,118.52 133.33,118.52 130.03,115.21 127.87,115.21 126.51,113.85 126.51,106.8 118.75,99.04 111.64,99.04 111.26,98.67 111.26,98.32 v2(111.07,98.13)
  BOTTOM w0.102: CPU1.B39 113.75,94.64 112.63,95.77 112.63,96.53 111.79,97.37 111.75,97.37 111.48,97.37 111.27,97.59 111.27,97.94 v2(111.07,98.13) ; v2(157.45,135.63) 157.45,135.61 GPU1.AE8
CLK_PCIE_VGA#: length 83.5
  TOP w0.102: v1(112.51,98.39) 111.97,98.39 v2(111.71,98.13)
  L3 w0.102: v2(158.25,135.63) 157.82,135.2 156.93,135.2 155.95,136.18 155.95,138.27 153.53,140.7 149.45,140.7 146.83,138.07 146.83,134.86 141.89,129.92 141.89,124.56 136.16,118.84 135.61,118.29 133.43,118.29 130.12,114.98 127.97,114.98 126.74,113.76 126.74,106.71 118.85,98.81 111.73,98.81 111.49,98.57 111.49,98.35 v2(111.71,98.13)
  BOTTOM w0.102: GPU1.AD8 158.25,135.61 v2(158.25,135.63) ; CPU1.A39 113.75,95.08 113.6,95.08 112.83,95.85 112.83,96.62 111.87,97.57 111.57,97.57 111.47,97.67 111.47,98.02 111.58,98.13 v2(111.71,98.13)
CLK_PCIE_WLAN_N3: length 114.3
  L4 w0.102: v2(110.39,98.37) 110.74,98.72 111.12,99.11 111.12,103.75 114.82,107.45 124.04,107.45 124.99,106.5 129.43,106.5 133.52,102.41 134.64,102.41 139.73,97.32 139.73,95.64 141.59,93.78 142.22,93.78 142.73,93.28 143.02,93.28 144.69,91.6 144.69,85.4 145.83,84.26 145.83,82.49 146.38,81.94 147.15,81.94 148.7,80.39 150.43,80.39 151.8,79.02 152.76,79.02 153.17,78.61 153.17,77.78 155.4,75.54 157.5,75.54 158.93,74.11 161.64,74.11 163.04,72.71 163.04,70.92 163.46,70.5 163.46,69.71 165.14,68.02 165.14,66.82 165.82,66.15 166.97,66.15 167.41,66.58 v2(167.61,66.58)
  BOTTOM w0.102: 111.19,96.98 110.82,96.98 110.15,97.64 110.15,98.14 v2(110.39,98.37) ; 111.19,96.98 111.85,96.98 112.2,96.63 112.2,95.7 112.08,95.57 112.08,94.26 112.37,93.97 CPU1.C41 ; 111.19,96.98 v1(111.19,97.18) ; WLAN1.49 163.95,51.02 164.1,51.17 164.52,51.17 166.1,52.74 166.1,53.11 167.14,54.16 167.14,64.57 167.39,64.83 167.39,65.45 EC5801.1 167.65,65.77 167.39,66.02 167.39,66.34 167.61,66.56 v2(167.61,66.58)
CLK_PCIE_WLAN_P3: length 114.3
  L4 w0.102: v2(110.39,99.01) 110.7,99.01 110.89,99.21 110.89,103.85 114.72,107.68 124.14,107.68 125.08,106.73 129.53,106.73 133.62,102.64 134.73,102.64 139.96,97.41 139.96,95.74 141.68,94.01 142.31,94.01 142.82,93.5 143.11,93.5 144.92,91.7 144.92,85.49 146.06,84.36 146.06,82.59 146.47,82.17 147.24,82.17 148.79,80.62 150.52,80.62 151.9,79.25 152.86,79.25 153.4,78.71 153.4,77.87 155.49,75.77 157.59,75.77 159.03,74.34 161.73,74.34 163.27,72.8 163.27,71.01 163.68,70.6 163.68,69.8 165.37,68.12 165.37,66.92 165.91,66.37 166.88,66.37 167.18,66.68 167.18,66.82 v2(167.01,66.99)
  BOTTOM w0.102: WLAN1.47 163.95,51.52 164.1,51.37 164.44,51.37 165.89,52.83 165.89,53.2 166.94,54.24 166.94,64.66 167.19,64.91 167.19,65.42 EC5802.1 167.18,66.09 167.18,66.82 v2(167.01,66.99) ; v2(110.39,99.01) 109.95,98.57 109.95,97.56 110.05,97.46 ; CPU1.B42 111.87,94.17 111.87,95.66 112,95.78 112,96.54 111.77,96.77 110.73,96.77 110.05,97.46 ; 110.05,97.46 v1(109.95,97.37)
CLK_PCIE_WLAN_REQ3#: length 95.4
  TOP w0.102: R5803.2 163.05,55.15 166.43,58.53 171.74,58.53 171.86,58.65 173.01,58.65 v2(173.46,58.2) ; v2(147.38,90.73) 147.05,90.73 146.36,90.04 143.54,90.04 143.15,89.66 143.15,89.62 142.84,89.31 142.48,89.31 141.34,90.45 141.34,91.6 143.04,93.3 RN2002.8
  L3 w0.102: v2(156.34,84.43) 156.15,84.24 153.88,84.24 152.44,85.68 151.67,85.68 149.85,83.86 149.32,83.86 148.35,82.89 148.35,82.42 147.45,81.51 v2(146.88,81.51)
  L4 w0.102: v2(173.46,58.2) 173.46,64.27 172.14,65.59 172.14,66.49 172.84,67.18 172.84,70.45 169.47,73.82 169.1,73.82 162.87,80.05 161.51,80.05 157.92,83.65 157.13,83.65 v2(156.34,84.43)
  BOTTOM w0.102: v2(147.38,90.73) 147.38,90.43 148.06,89.75 v1(148.06,89.55) 148.43,89.18 150.89,89.18 153.07,87 154.06,87 154.67,86.39 156.34,84.71 v2(156.34,84.43) ; CPU1.AD1 137.54,81.87 137.67,81.75 139.85,81.75 140.02,81.92 141.66,81.92 142.57,81.01 146.37,81.01 v2(146.88,81.51)
CLK_PCIE_WLAN_REQ#: length 6.7
  TOP w0.102: R5803.1 162.81,52.38 AFTP5802.1 160.94,51.67 v2(160.81,51.67)
  BOTTOM w0.102: v2(160.81,51.67) 160.63,51.48 v1(160.63,50.38) 160.99,50.02 WLAN1.53
CODEC_BITCLK_R: length 2.4
  BOTTOM w0.14: R2720.2 178.15,16.09 v1(178.8,16.09) HDA27.6
CODEC_SDOUT_R: length 3.7
  BOTTOM w0.14: HDA27.5 179.38,15.69 179.33,15.74 178.25,15.74 v1(177.83,15.32) 177.45,15.32 177.25,15.52 R2719.2
COLOR_ENGINE: length 1.2
  TOP w0.102: v2(135.49,91.96) 135.7,91.75 TP2003.1
  BOTTOM w0.102: CPU1.E3 135.81,92.29 v2(135.49,91.96)
COMBO-GPI: length 2.5
  TOP w0.102: TP2702.1 179.54,12.74 v2(179.54,13.41)
  BOTTOM w0.102: HDA27.48 180.73,13.26 180.4,12.93 180.02,12.93 179.54,13.4 v2(179.54,13.41)
CPU_ID: length 17.4
  L3 w0.102: v2(139.13,89.4) 139.9,90.17 142.7,90.17 143.1,90.58 143.8,90.58 144.5,91.28 146.71,91.28 v2(146.82,91.39)
  BOTTOM w0.089: 138.11,87.92 137.59,87.92 137.54,87.97 137.54,87.97 137.36,88.15 136.16,88.15 136.02,88.29 135.45,88.29 CPU1.L4
  BOTTOM w0.102: v1(147.3,87.96) 147.07,88.2 R1512.2 147.07,89.73 R1515.1 147.03,90.3 146.94,90.4 146.94,91.28 v2(146.82,91.39) ; 138.11,87.92 138.41,87.92 139.13,88.64 v2(139.13,89.4)
CPU_RXN_C_DGPU_TXN0: length 55.8
  TOP w0.127: v1(151.39,134.17) 152.05,134.17 v2(152.21,134.33) 152.5,134.33 152.73,134.56 152.95,134.56 C7302.1
  L3 w0.114: v2(131.22,92.13) 131.64,92.55 131.64,93.24 134.08,95.68 136.03,95.68 138.88,98.53 138.88,99.12 139.81,100.05 139.81,100.63 143.18,104.01 143.18,107.04 145.8,109.67 145.8,112.46 147.15,113.81 147.15,125.65 152.22,130.73 152.43,130.73 153.03,131.32 153.16,131.46 153.16,133.9 152.9,134.16 152.37,134.16 v2(152.21,134.33)
  BOTTOM w0.127: v2(131.22,92.13) 131.53,91.82 CPU1.F10
CPU_RXN_C_DGPU_TXN1: length 58.2
  TOP w0.127: C7304.1 152.78,135.99 152.49,135.99 v2(152.43,136.05) 152.03,136.45 151.87,136.61 v1(151.57,136.61)
  L3 w0.114: v2(132.13,92.11) 132.6,92.58 132.6,93.11 134.42,94.93 136.34,94.93 140.56,99.16 140.56,100.33 144.08,103.84 144.4,103.84 145.27,104.71 145.27,107.69 146.55,108.98 146.55,111.96 147.9,113.3 147.9,125.34 152.38,129.82 152.71,129.82 153.91,131.03 153.91,135.05 153.17,135.8 152.68,135.8 v2(152.43,136.05)
  BOTTOM w0.127: v2(132.13,92.11) 132.32,92.11 CPU1.F8
CPU_RXN_C_DGPU_TXN2: length 62.1
  TOP w0.127: C7306.1 154.06,138.09 153.59,138.09 v2(153.49,138.2) 153.17,138.51 v1(152.92,138.51)
  L3 w0.114: v2(132.13,90.82) 132.36,91.05 132.65,91.05 132.89,91.3 134.2,91.3 136.06,93.15 136.75,93.15 142.19,98.58 142.19,99.83 144.7,102.34 145.02,102.34 147.3,104.62 147.3,104.81 147.3,106.04 148.03,106.77 148.16,106.9 148.16,111.07 149.4,112.31 149.4,124.72 152.98,128.3 153.49,128.3 155.37,130.17 155.37,136.74 154.11,138 153.68,138 v2(153.49,138.2)
  BOTTOM w0.127: CPU1.H10 131.82,90.51 v2(132.13,90.82)
CPU_RXN_C_DGPU_TXN3: length 62
  TOP w0.127: v1(152.71,140.84) v2(152.71,140.08) 153.03,139.76 153.85,139.76 C7308.1
  L3 w0.114: v2(152.71,140.08) 152.19,139.56 152.19,137.47 154.43,135.23 154.43,130.5 153.21,129.28 152.57,129.28 148.42,125.12 148.42,112.71 147.18,111.47 147.18,108.49 146.14,107.46 146.14,104.85 144.62,103.32 144.29,103.32 141.15,100.18 141.15,99.01 136.29,94.15 135.19,94.15 134.74,93.7 133.94,93.7 133.34,93.1 133.34,92.94 v2(133.12,92.72)
  BOTTOM w0.127: CPU1.E6 133.3,92.72 v2(133.12,92.72)
CPU_RXP_C_DGPU_TXP0: length 55.5
  TOP w0.127: v1(152.08,133.13) 152.08,133.68 v2(152.1,133.7) 152.28,133.88 152.39,133.88 152.48,133.97 152.48,133.97 152.83,134.31 153.19,134.31 153.32,134.19 153.32,134 153.19,133.87 C7301.1
  L3 w0.114: v2(131.17,92.79) 131.32,92.79 131.41,92.89 131.41,93.34 133.98,95.91 135.93,95.91 138.65,98.62 138.65,99.21 139.58,100.15 139.58,100.43 139.58,100.43 139.58,100.73 142.95,104.1 142.95,107.14 145.58,109.76 145.58,112.56 145.71,112.69 146.92,113.9 146.92,125.75 147.05,125.88 152.13,130.95 152.34,130.95 152.94,131.55 152.94,133.81 152.81,133.93 152.44,133.93 152.2,133.7 v2(152.1,133.7)
  BOTTOM w0.127: v2(131.17,92.79) 131.5,92.47 CPU1.E10
CPU_RXP_C_DGPU_TXP1: length 56.8
  TOP w0.127: C7303.1 153.17,135.75 152.82,135.75 152.58,135.51 152.25,135.51 152.2,135.46 v2(152.19,135.46) 152.12,135.39 v1(151.62,135.39)
  L3 w0.114: v2(132.16,92.79) 132.16,92.99 134.33,95.16 136.24,95.16 140.34,99.25 140.34,100.42 143.98,104.07 144.31,104.07 145.04,104.8 145.04,107.79 146.33,109.07 146.33,112.05 147.67,113.4 147.67,125.44 152.29,130.05 152.61,130.05 153.68,131.13 153.68,134.96 153.08,135.57 152.3,135.57 v2(152.19,135.46)
  BOTTOM w0.127: CPU1.E8 132.28,92.79 v2(132.16,92.79)
CPU_RXP_C_DGPU_TXP2: length 62.3
  TOP w0.127: C7305.1 154.36,137.51 154.36,137.75 154.26,137.85 153.77,137.85 v2(153.43,137.51) 153.24,137.32 v1(152.56,137.32)
  L3 w0.114: v2(153.43,137.51) 153.43,137.64 153.56,137.77 154.02,137.77 155.14,136.65 155.14,130.27 153.4,128.53 152.88,128.53 149.17,124.81 149.17,112.4 147.93,111.17 147.93,106.99 147.07,106.13 147.07,105.94 147.07,104.72 144.93,102.57 144.61,102.57 141.96,99.93 141.96,98.68 136.66,93.38 135.96,93.38 134.11,91.52 132.8,91.52 132.56,91.28 132.32,91.28 v2(132.13,91.47)
  BOTTOM w0.127: v2(132.13,91.47) 131.83,91.16 CPU1.G10
CPU_RXP_C_DGPU_TXP3: length 61.8
  TOP w0.127: v1(152.13,139.48) 152.65,139.48 v2(152.71,139.42) 152.81,139.52 153.79,139.52 C7307.1
  L3 w0.114: v2(152.71,139.42) 152.42,139.13 152.42,137.56 154.66,135.32 154.66,130.41 153.3,129.05 152.67,129.05 148.65,125.03 148.65,112.62 147.41,111.38 147.41,108.4 146.37,107.36 146.37,104.75 144.71,103.09 144.39,103.09 141.38,100.09 141.38,98.91 141.25,98.78 136.39,93.92 135.28,93.92 134.83,93.47 134.03,93.47 133.57,93 133.57,92.52 v2(133.08,92.03)
  BOTTOM w0.127: CPU1.F6 133.34,92.03 v2(133.08,92.03)
CPVEE: length 2.8
  BOTTOM w0.203: HDA27.34 187.18,14.89 v1(187.73,14.34) 188.18,13.89 C2704.2
CR_GPIO0: length 1.7
  BOTTOM w0.14: TP3201.1 19.77,16.83 U3201.17
CRT_B: length 10.5
  TOP w0.114: L5502.2 20.31,64.28 C5518.1 18.45,64.28 AFTP5503.1 17.61,63.43 17.46,63.43 17.03,63.87 17.03,64.01 17.8,64.78 17.8,64.92 17.55,65.17 17.4,65.17 16.51,64.28 15.35,64.28 14.16,65.47 HDMI1.3
CRT_DDCCLK_CON: length 28.4
  TOP w0.14: U5502.4 28.64,67.97 C5511.1 29.13,68.95 v2(28.94,69.14) 28.88,69.2 RN5501.2 ; AFTP5506.1 17.78,69.8 15.45,69.8 HDMI1.15
  L4 w0.127: HDMI1.15 15.45,70.05 16.72,68.78 16.72,66.7 17.06,66.36 18,66.36 19.95,64.41 23.19,64.41 24.16,65.37 24.16,67.07 27.33,70.24 28.54,70.24 28.9,69.88 28.9,69.18 v2(28.94,69.14)
CRT_DDCDATA_CON: length 28.2
  TOP w0.14: AFTP5505.1 16.45,61.93 HDMI1.12 ; RN5501.1 28.23,69.17 v2(28.2,69.14) 28.31,69.03 C5516.1 27.64,67.78 U5502.6
  L4 w0.127: v2(28.2,69.14) 28.35,69.14 28.52,69.31 28.52,69.72 28.38,69.86 27.49,69.86 24.54,66.91 24.54,65.22 23.35,64.03 19.79,64.03 17.84,65.98 16.87,65.98 16.73,65.84 16.73,63.42 16.5,63.18 HDMI1.12
CRT_G: length 9.7
  TOP w0.114: HDMI1.2 14.54,62.44 15.14,62.44 17.57,60.02 AFTP5502.1 18.41,60.02 18.72,60.32 18.72,61.66 19.15,62.09 C5510.1 20.3,62.09 L5501.2
CRT_HSYNC_CON: length 16.4
  TOP w0.14: R5511.2 24.79,69.28 v2(24.75,69.32) ; HDMI1.13 15.45,65.22 16.01,65.22 17.59,66.8 17.73,66.8 18,66.53 18,66.39 17.77,66.16 17.77,65.96 17.99,65.74 AFTP5508.1 18.09,65.66 18.09,65.64 18.51,65.22 19.36,65.22 C5513.1 19.25,65.77 v2(19.23,65.76)
  L4 w0.127: v2(24.75,69.32) 24.51,69.32 21.08,65.89 19.36,65.89 v2(19.23,65.76)
  BOTTOM w0.14: v2(24.75,69.32) 24.63,69.19 v1(23.98,69.19)
CRT_PCH_HPD: length 4.4
  TOP w0.102: v1(33.28,67.62) 32.86,68.04 R5517.1 32,68.05 R5510.1 31.17,67.89 30.14,66.87 U5502.1
CRT_R: length 8.5
  TOP w0.114: HDMI1.1 14.24,60.89 17.02,58.1 AFTP5501.1 18.55,58.66 18.55,58.83 19.09,59.37 C5514.1 20.24,59.37 L5503.2
CRT_VSYNC_CON: length 16.1
  TOP w0.14: R5507.2 26.45,70.04 v2(26.44,70.04) ; HDMI1.14 15.3,67.66 AFTP5507.1 18.86,67.66 19.91,66.61 C5507.1 19.83,66.52 v2(19.15,66.52)
  L4 w0.127: v2(19.15,66.52) 19.21,66.46 20.84,66.46 24.43,70.04 v2(26.44,70.04)
  BOTTOM w0.14: v1(26.44,69.48) 26.44,69.48 26.44,69.51 26.44,69.51 v2(26.44,70.04)
DBC_EN: length 143.1
  L4 w0.102: v2(142.3,96.42) 142.3,97.03 141.89,97.44 141.89,108.27 141.38,108.77 141.38,111.89 137.57,115.7 137.57,123.51 138.18,124.12 138.18,146.41 135.49,149.1 121.48,149.1 120.52,148.14 106.17,148.14 101.58,152.73 101.58,157.52 101.6,157.54 101.61,157.54 103.56,159.49 103.56,163.91 101.46,166.02 100.12,166.02 97.98,168.17 93.01,168.17 v2(90.36,170.82)
  BOTTOM w0.089: 137.58,89.13 137.31,89.13 137.25,89.08 136.15,89.08 136.14,89.07 CPU1.K3
  BOTTOM w0.102: v2(90.36,170.82) 90.36,173.85 86.9,177.31 R5213.2 ; 137.58,89.13 137.87,89.13 138.97,90.23 138.97,91.34 140.7,93.07 140.7,94.7 v1(141.89,95.9) 142.12,96.12 142.12,96.24 v2(142.3,96.42) 143.21,97.33 RN1505.7
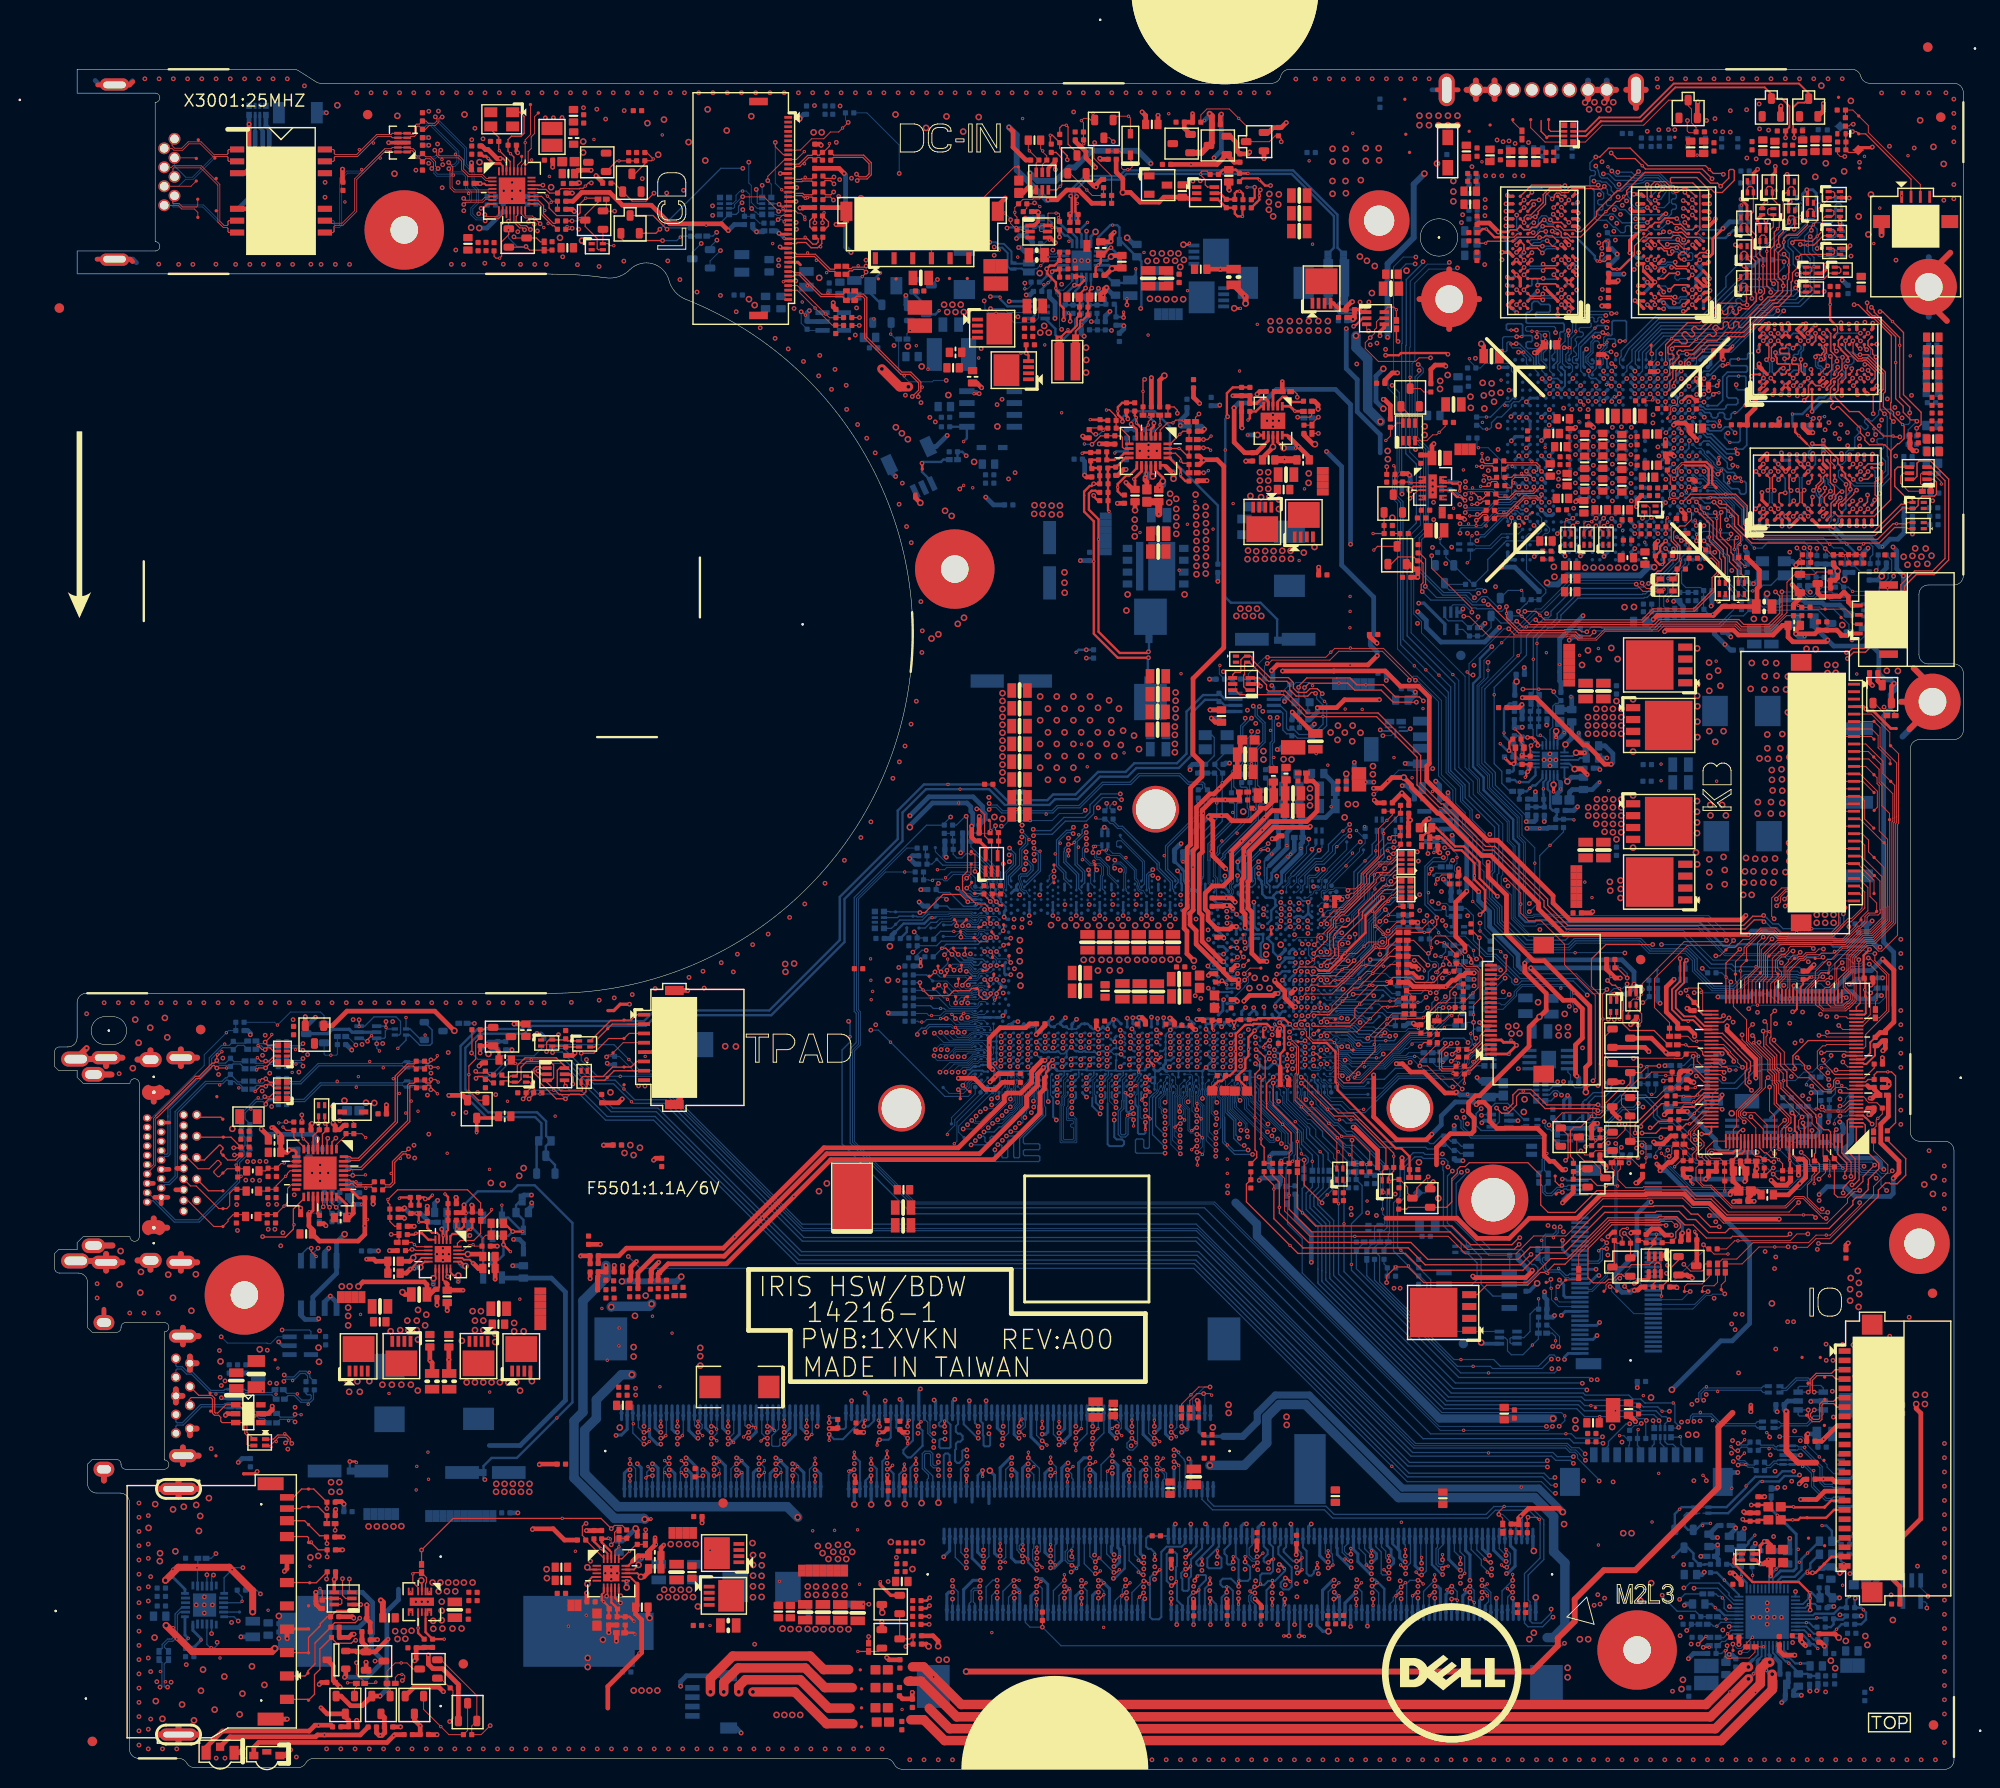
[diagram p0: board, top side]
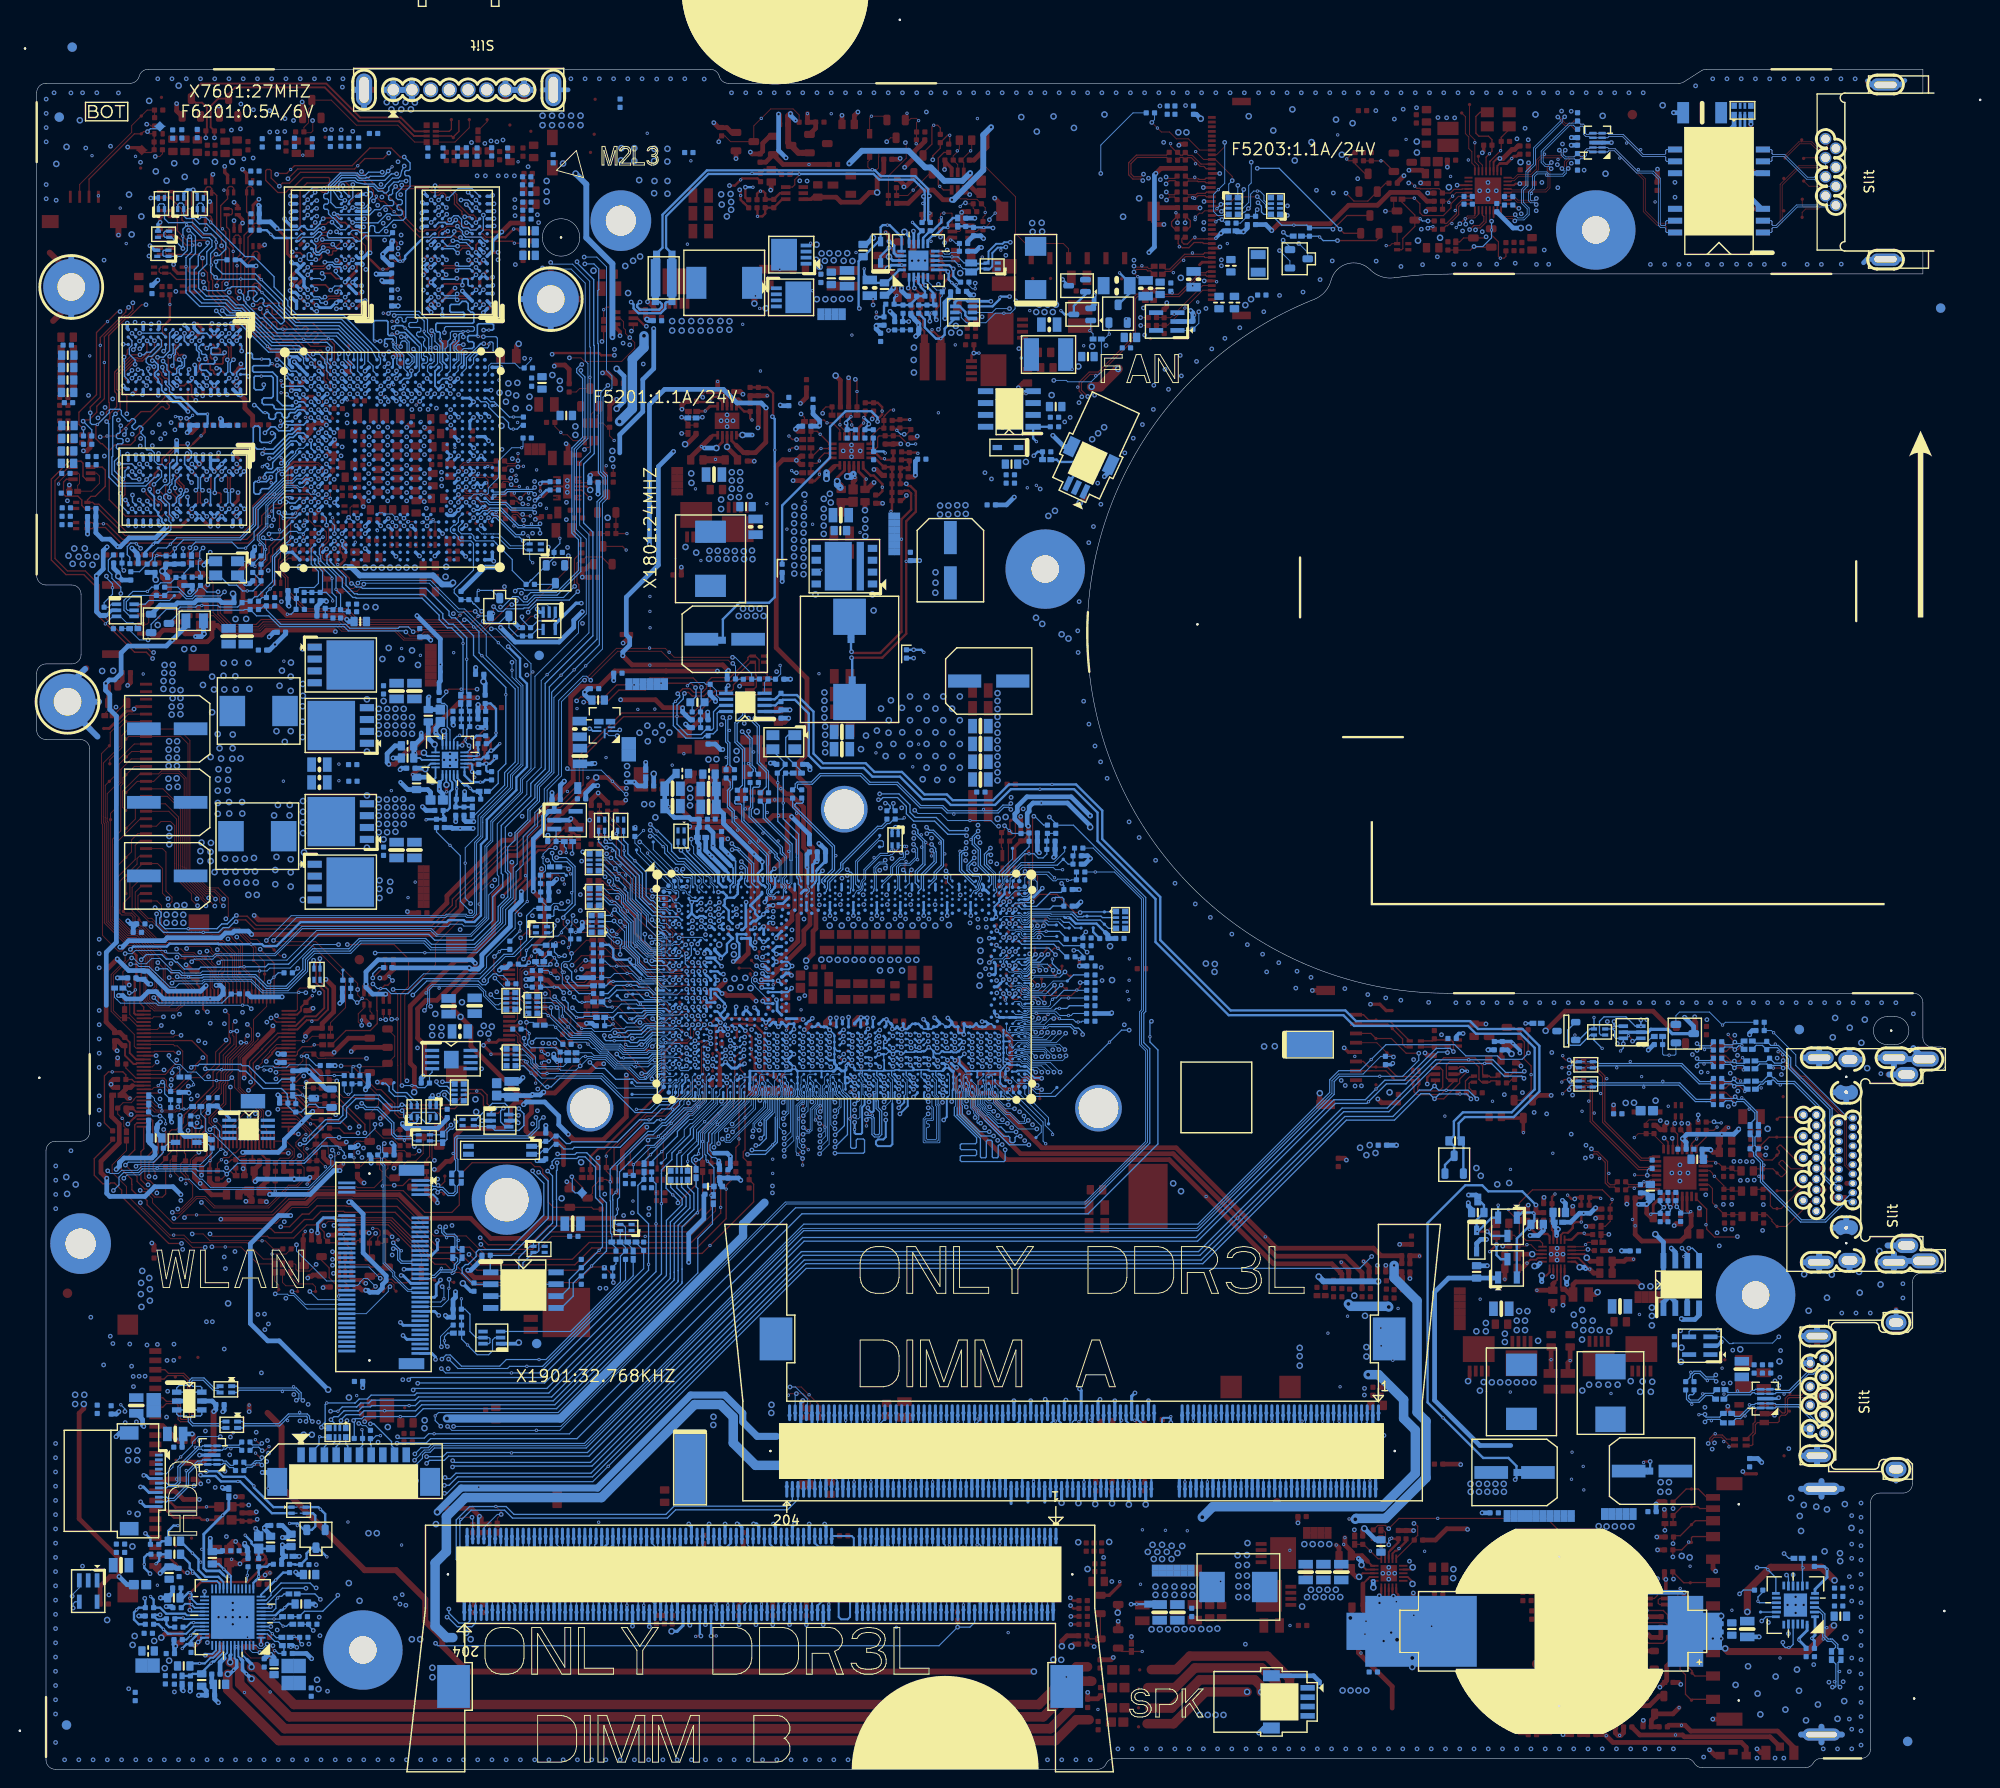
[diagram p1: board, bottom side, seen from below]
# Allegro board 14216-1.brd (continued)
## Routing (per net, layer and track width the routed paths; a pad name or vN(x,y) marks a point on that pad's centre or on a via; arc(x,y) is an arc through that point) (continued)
DBC_EN_R: length 8.8
  TOP w0.102: v2(84.89,176.28) v1(84.3,175.68) 83.87,175.26 83,175.26 82.27,174.53 80.98,174.53 79.77,173.32 LCD1.8
  BOTTOM w0.102: R5213.1 84.6,176.57 v2(84.89,176.28)
DC_IN_D:
  vias: v1(103.04,161.87)
DC_TEST_A3_B3: length 4.9
  BOTTOM w0.102: v1(138.84,98.07) 138.84,97.97 135.98,95.11 CPU1.A3 135.98,94.56 CPU1.B3
DC_TEST_A61_B61: length 6.9
  BOTTOM w0.102: CPU1.B61 99.8,95.01 CPU1.A61 99.73,95.15 99.45,95.43 99.45,95.81 98.74,96.52 95.44,96.52 95.21,96.3 v1(94.44,96.3)
DC_TEST_AY2_AW2: length 0.7
  BOTTOM w0.102: CPU1.AW2 136.57,73 CPU1.AY2
DC_TEST_AY3_AW3: length 5.8
  BOTTOM w0.089: CPU1.AW3 135.85,73.06 CPU1.AY3
  BOTTOM w0.102: CPU1.AY3 135.85,72.22 136.58,71.48 137.78,71.48 138.62,70.64 v1(140.04,70.64)
DC_TEST_AY61_AW61: length 7.6
  BOTTOM w0.102: v1(96.25,66.96) 96.53,67.24 96.53,69.27 99.71,72.45 CPU1.AY61 99.79,72.54 CPU1.AW61
DC_TEST_AY62_AW62: length 6.7
  BOTTOM w0.102: v1(95.51,67.95) 95.51,68.15 96.3,68.94 96.3,69.55 99.05,72.3 CPU1.AY62 99.14,72.54 CPU1.AW62
DC_TEST_B62_B63: length 5.3
  BOTTOM w0.102: CPU1.B62 98.62,94.36 CPU1.B63 98.49,95.43 97.87,96.04 95.92,96.04 v1(95.31,95.43)
DC_TEST_C1_C2: length 0.7
  BOTTOM w0.102: CPU1.C2 136.58,93.95 CPU1.C1
DCBATOUT: length 112
  TOP w0.203: PC4531.1 41.14,51.63 PU4503.12
  TOP w0.381: PC4431.1 121.11,168.28 121.33,168.06 PU4407.3
  TOP w0.508: v2(153.36,97.1) 153.36,95.54 155.32,93.58 155.32,89.45 158.22,86.55 159.38,86.55 164.24,81.69 164.24,75.58 163.8,75.14 163.8,72.68 163.81,72.66 v3(163.81,72.48) ; PC4431.1 118.68,168.28 118.14,167.75 116.13,167.75 115.09,168.78 v3(114.28,168.78) 114.28,170.25 113.57,170.96 PR4468.1 ; v2(168.64,57.41) 168.71,57.48 169.43,57.48 PR8312.2 ; v3(32.49,51.69) 32.97,52.17 39.55,52.17 39.83,51.89 PC4519.1 40.13,50.82 40.71,51.39 PC4531.1
  L3 w0.508: v2(152.25,102.01) 152.25,101.27 152.07,101.09 152.07,98.39 v2(153.36,97.1)
  L4 w0.508: v2(168.64,57.41) 168.64,60.69 167.18,62.14 167.18,65.25 168.25,66.31 168.25,66.84 167.42,67.67 166.96,67.67 165.8,68.84 165.8,69.3 165.27,69.82 164.89,69.82 164.46,70.25 164.46,71.84 v3(163.81,72.48)
  L4 w0.762: v3(114.28,168.78) 114.31,168.81 124.8,168.81 125.28,168.33 125.3,168.33 125.35,168.28 127.01,168.28 129.05,166.24 129.05,166.22 129.55,165.71 129.57,165.71 134.6,160.68 134.6,159.01 136.2,157.41 136.2,155.03 v3(136.21,155.02)
  BOTTOM w0.508: EC9742.1 156.36,116.48 v3(156.4,116.43) 156.22,116.25 PR8202.1
  vias: v1(33.47,58.85) v1(46.52,64.22) v1(107.73,145.2) v1(116.98,153.52) v1(126.77,149.67) v1(128.66,154.67) v3(30.72,51.69) v3(31.55,51.69) v3(49.7,63.53) v3(50.17,64.36) v3(104.83,135.31) v3(104.79,134.38) v3(105.72,135.31) v3(105.68,134.38) v3(106.66,135.27) v3(106.67,134.32) v3(107.55,135.27) v3(107.56,134.32) v3(110.34,152.18) v3(110.34,149.51) v3(110.37,150.86) v3(130.08,155.01) v3(130.1,154.09) v3(131.05,155.03) v3(131.12,154.09) v3(132.14,155.02) v3(132.14,154) v3(133.16,155.02) v3(133.16,154) v3(134.17,155.02) v3(134.17,154) v3(135.19,155.02) v3(135.19,154) v3(136.21,154)
DCBATOUT_LCD: length 34.8
  L3 w1.016: v3(79.66,176.68) 82.89,176.68 92.76,166.82 v3(92.76,150.16)
  BOTTOM w0.508: C5202.1 80.13,177.15 v3(79.66,176.68)
  vias: v1(92.18,152.38)
DCBATOUT_R: length 31.5
  TOP w0.254: v2(128.38,169.35) 128.38,168.23 128.16,168.01 PR4448.1
  L3 w0.254: v2(140.6,157.06) 140.6,157.18 139.71,158.07 136.06,158.07 133.13,161 133.13,169.02 131.48,170.67 129.62,170.67 128.38,169.43 v2(128.38,169.35)
  BOTTOM w0.254: PG4404.1 136.81,157.05 136.94,156.93 136.94,156.36 137.44,155.86 139.81,155.86 140.34,156.39 140.34,156.8 v2(140.6,157.06) ; v2(128.38,169.35) v1(127.57,169.35)
DDC_CLK_HDMI: length 38.8
  TOP w0.14: v2(32.57,80.23) v1(32.57,79.51)
  L4 w0.102: 10.56,70.34 10.55,70.33 10.55,69.54 10.55,69.54 10.55,67.81 10.46,67.72 HDMI1.HP15
  L4 w0.127: v2(32.57,80.23) 32.57,80.07 32.09,79.6 19.82,79.6 16.29,76.07 16.29,74.41 13.23,71.35 12.05,71.35 11.58,71.35 10.56,70.34
  BOTTOM w0.14: RN5401.1 36.85,78.6 37,78.75 37,80.06 36.52,80.54 34.17,80.54 33.17,79.55 Q5402.3 32.57,80.14 32.57,80.14 v2(32.57,80.23)
DDC_CLK_PH1: length 7.7
  BOTTOM w0.14: v1(36.71,77.17) 37.59,78.04 RN5401.4 37.98,78.6 39.08,77.5 40.14,77.5 40.38,77.74 40.38,79.14 D5401.2
DDC_DATA_HDMI: length 35.7
  L4 w0.102: HDMI1.HP16 10.91,68.22 10.75,68.38 10.75,69.46 10.75,69.46 10.75,69.99 10.93,70.17
  L4 w0.127: v2(34.45,77.66) 33.2,78.91 32.56,78.91 32.25,79.21 19.98,79.21 16.67,75.91 16.67,74.26 13.39,70.97 11.89,70.97 11.73,70.97 10.93,70.17
  BOTTOM w0.14: RN5401.2 35.59,79.25 35.38,79.03 35.38,78.36 35.26,78.25 Q5402.6 34.45,77.76 v2(34.45,77.66) 34.45,77.19 v1(34.75,76.89)
DDC_DATA_PH2: length 3.7
  BOTTOM w0.14: v1(37.59,80.48) RN5401.3 38.02,79.25 39.19,78.07 D5401.1
DDR3_DRAMRST#: length 176.3
  TOP w0.127: C1217.1 69.22,31.3 v2(69.35,31.43) ; C1301.1 v2(105.67,15.22)
  L3 w0.127: v2(105.67,15.22) 105.6,15.15 96.82,15.15 94.89,17.08 91.91,17.08 89.88,19.11 89.88,21.3 89,22.18 89,23.01 82.01,30 70.78,30 v2(69.35,31.43)
  L4 w0.127: v2(161.53,13.49) 162.95,14.91 162.95,30.5 162.55,30.9 162.55,31.09 160.98,32.66 160.98,36.7 v2(160.96,36.72)
  BOTTOM w0.127: v2(160.96,36.72) 161.56,37.32 v1(161.56,37.83) 161.21,38.19 148.42,38.19 133.47,53.13 133.47,56.81 131.9,58.38 131.9,60.46 R404.2 ; DM1.30 v2(69.35,31.43) ; DM2.30 103.85,15.72 104.35,15.22 v2(105.67,15.22) 107.67,13.23 161.26,13.23 v2(161.53,13.49)
DDR_PG_CTRL: length 120.3
  TOP w0.127: R1205.1 87.08,13.98 87.08,13.98 v2(87.08,14.21)
  L3 w0.127: v2(87.08,14.21) 87.57,14.69 87.57,18.11 87.4,18.28 87.4,22.48 83.79,26.09 79.29,26.09 76.03,29.35 58.9,29.35 57.64,30.61 57.64,49.97 60.91,53.24 61.44,53.24 v2(87.32,79.12)
  BOTTOM w0.089: CPU1.AV61 99.81,73.96 99.3,73.44 99,73.44 98.98,73.43 98.22,73.43 98.05,73.26
  BOTTOM w0.102: 97.75,72.03 98.05,72.33 98.05,73.26
  BOTTOM w0.127: 97.75,72.03 95.23,72.03 v1(89.42,77.83) 88.14,79.12 v2(87.32,79.12)
DDR_PG_CTRL_R: length 2.7
  TOP w0.127: Q1201.S 88.13,12.62 R1205.2 v1(85.93,12.62)
DDR_VREF_S3: length 44.5
  L4 w1.016: v3(58.66,13.87) 57.31,15.22 57.31,16.9 55.68,18.52 55.68,22.08 58.02,24.41 58.02,27.54 56.14,29.41 56.14,35.36 59.54,38.76 v3(59.54,49.48)
  BOTTOM w1.016: v3(63.86,49.81) 63.61,49.56 59.62,49.56 v3(59.54,49.48)
  vias: v1(58.55,49.33)
DDR_VTT_PG_CTRL: length 52.2
  TOP w0.127: PR4909.2 60.16,25.61 59.9,25.36 59.9,24.39 v2(59.54,24.03) ; v2(91.07,13.14) 91.33,13.4 R1204.1 R1208.2 91.5,13.96 Q1201.D Q1202.G
  L3 w0.127: v2(91.07,13.14) 90.51,13.7 88,13.7 87.56,13.26 86.69,13.26 86.49,13.45 77.21,13.45 76.82,13.85 74.58,13.85 73.69,12.96 62.69,12.96 57.72,17.93 57.72,21.55 59.54,23.37 v2(59.54,24.03)
  BOTTOM w0.127: v1(59.24,24.74) 59.54,24.44 v2(59.54,24.03)
DDR_VTT_PG_CTRL_R: length 3.2
  TOP w0.127: PR4910.1 61.19,24.72 PR4909.1 60.38,23.82 v1(60.37,23.81) 59.95,23.39 PU4901.17
DDR_WR_VREF01: length 56.3
  TOP w0.508: R3702.1 C3702.1 62.4,53.15 64.17,54.92 71.63,54.92 v1(75.71,59.01) 82.6,65.89 98.95,65.89 103.98,70.93 103.98,72.02 105.15,73.19 105.15,74.42 105.79,75.06 v2(105.79,75.13)
  BOTTOM w0.305: CPU1.AR51 105.95,75.16 105.82,75.16 v2(105.79,75.13)
DDR_WR_VREF02: length 58.9
  TOP w0.508: R3713.1 58.15,54.96 C3703.1 60.36,54.97 61.17,55.78 71.55,55.78 v1(72.76,56.99) 82.29,66.53 96.66,66.53 101.6,71.47 101.6,72.07 101.92,72.39 103.35,72.39 104.52,73.55 104.52,74.69 104.76,74.93 104.76,75 105.65,75.89 v2(105.95,75.89)
  BOTTOM w0.254: CPU1.AP51 106.27,76.22 v2(105.95,75.89)
DGPU_HOLD_RST#: length 60.3
  L3 w0.127: v2(149.05,98.07) 150.04,99.06 150.04,101.16 151.28,102.39 151.28,110.08 153.35,112.15 153.35,117.87 153.79,118.31 153.79,118.68 152.28,120.19 v2(152.28,123.37) ; v2(148.63,92.23) 148.61,92.24 147.22,92.24 146.86,92.6 144.87,92.6 143.58,91.31 140.41,91.31 140.1,91 140.1,91 138.84,89.74 138.56,89.74 137.76,88.94 v2(137.76,88.32)
  BOTTOM w0.089: CPU1.L3 135.99,88.57 136.24,88.33 137.75,88.33 v2(137.76,88.32)
  BOTTOM w0.127: RN1503.4 149.59,91.13 EC1502.1 148.95,91.3 148.87,91.39 148.87,91.96 148.65,92.18 148.65,92.21 v2(148.63,92.23) 148.59,92.23 148.33,91.97 147.77,91.97 147.76,91.98 147.64,91.98 146.91,92.71 146.91,93.77 v1(146.97,93.83) 146.85,93.96 146.85,96.54 147.45,97.15 148.76,97.15 149.02,97.41 149.02,98.04 v2(149.05,98.07) ; v2(152.28,123.37) 152.28,123.07 151.41,122.2 R7304.1 151.31,122.2 150.58,122.93 149.09,122.93 148.72,123.31 U7301.1
DGPU_PWR_EN: length 107.4
  TOP w0.127: v2(145.59,141.27) 145.37,141.49 145.11,141.49 144.89,141.71 PQ8305.2 ; v2(145.01,136.06) 145.87,136.92 U8301.5
  L3 w0.127: v2(157.77,91.81) 156.81,91.81 156.68,91.67 153.62,91.67 153.02,92.27 150.78,92.27 v2(148.83,90.32) 147.59,90.32 147.45,90.17 143.75,90.17 142.87,89.29 142.47,89.29 142.39,89.37 140.59,89.37 139.69,88.47 v2(138.37,88.47) ; v2(145.59,141.27) 145.76,141.44 154.26,141.44 v2(154.42,141.28) ; v2(155.48,94.55) 155.64,94.71 155.64,96.15 152.87,98.91 152.87,100.22 152.97,100.32 153.27,100.62 153.27,110.75 154.28,111.76 154.28,117.75 154.53,118.01 154.53,120.35 153.87,121.01 153.87,124.13 154.05,124.31 154.05,124.95 153.33,125.67 152.56,125.67 v2(152.34,125.89)
  L4 w0.127: v2(154.42,141.28) 154.64,141.06 154.64,131.89 152.34,129.6 v2(152.34,125.89) ; v2(157.77,91.81) 157.63,91.81 156.68,92.76 156.68,93.52 155.65,94.55 v2(155.48,94.55) ; v2(145.01,136.06) 145.64,136.69 145.64,138.69 145.97,139.02 145.97,140.89 v2(145.59,141.27)
  BOTTOM w0.127: v2(138.37,88.47) 138.1,88.74 137.45,88.74 137.32,88.61 CPU1.L1 ; RN1503.3 149.19,89.54 148.83,89.91 v2(148.83,90.32) ; v2(157.77,91.81) 158.88,92.91 158.88,97.8 v1(159.98,98.9) 161.42,100.34 PR8260.1
DGPU_PWR_EN#: length 7.2
  TOP w0.102: v1(142.42,142.24) 142.9,142.72 PR8313.2 143.16,143.65 143.61,144.1 PQ8305.6 144.24,144.94 144.03,145.14 PQ8307.G 144.89,145.03 PQ8305.5
DGPU_PWROK: length 227.8
  TOP w0.127: v2(142.51,139.43) 142.51,139.43 R8313.1 ; EC1501.1 R1509.2 143.09,99.94 v2(142.8,99.65) ; v2(157.08,115.62) v1(158.78,115.62) 160.11,115.62 v2(160.38,115.34) ; v2(167.94,57.37) 168.59,56.72 R8312.1 168.59,54.78 D8301.2
  L3 w0.127: v2(134.13,88.33) 134.13,88.54 134.55,88.96 134.55,90.88 135.17,91.5 136.74,91.5 138.2,92.97 138.49,92.97 138.82,93.3 138.82,94.39 142.07,97.64 142.07,97.69 142.73,98.35 142.73,99.58 v2(142.8,99.65) 142.93,99.78 143.85,99.78 148.3,104.23 148.3,105.6 149.31,106.61 149.31,110.81 149.96,111.46 149.96,124.5 152.05,126.59 v2(154.15,126.59) ; v2(152,151.03) 151.99,151.02 148.86,151.02 148.34,150.5 148.34,149.67 143.86,145.19 143.86,140.65 142.64,139.43 v2(142.51,139.43) ; v2(188.77,60.89) 188.77,60.88 188.34,60.88 183.8,56.34 183.8,56.32 183.14,56.32 182.38,55.55 173.06,55.55 172.68,55.94 169.37,55.94 v2(167.94,57.37)
  L4 w0.127: v2(188.77,60.89) 189.22,61.33 189.22,62.62 189.45,62.86 189.45,63.8 188.78,64.47 188.78,67.58 188.45,67.9 188.45,68.56 188,69.01 188,70.13 186.72,71.41 186.72,71.41 186.31,71.81 186.31,72.08 184.89,73.49 184.89,79.66 184.3,80.25 183.77,80.25 183.14,79.62 182.77,79.62 182.2,80.18 181.12,80.18 180.22,79.29 179.61,79.29 179.46,79.14 178.55,79.14 177.1,80.59 177.1,84.91 v2(176.27,85.73) 176.26,85.73 175.6,86.39 175.6,87.68 172.12,91.15 164.53,91.15 161.51,94.17 161.51,94.98 156.47,100.02 156.47,102.78 155.14,104.11 155.14,108.86 155.14,113.67 v2(157.08,115.62) 157.66,116.2 157.66,120.61 154.13,124.14 154.13,124.84 154.15,124.87 v2(154.15,126.59) 154.15,130.8 155.07,131.71 155.07,142.31 152.37,145.02 152.37,146.69 152.25,146.81 152.25,150.78 v2(152,151.03)
  BOTTOM w0.127: PU8201.13 159.98,111.27 160.28,111.57 160.28,113.8 160.57,114.1 160.85,114.1 PR8203.2 160.38,115.15 v2(160.38,115.34) ; v2(176.27,85.73) 176.75,85.26 R2437.1 ; v2(134.13,88.33) 134.16,88.3 134.16,87.16 CPU1.R5
DGPU_PWROK_KBC: length 3.6
  TOP w0.127: v2(179.33,84.28) 179.2,84.14 KBC24.63
  BOTTOM w0.127: v2(179.33,84.28) v1(178.82,84.79) 178.35,85.26 R2437.2
DGPU_RXN_C_CPU_TXN0: length 48.1
  L3 w0.114: v2(128.05,111.1) 128.46,111.52 129.29,111.52 130.28,110.53 132.07,110.53 134.7,113.16 138.13,113.16 144.69,119.72 144.69,127.62 146.1,129.04 146.29,129.04 147.23,129.04 147.79,129.59 147.79,130.09 149.56,131.87 151.34,131.87 151.58,132.12 151.96,132.12 v2(152.15,132.31)
  BOTTOM w0.127: 127.66,108.89 127.66,110.35 128.05,110.74 v2(128.05,111.1) ; 127.66,108.89 127.66,107.49 127.3,107.13 127.3,106.82 C1606.1 ; 127.66,108.89 v1(127.49,108.89) ; v2(152.15,132.31) 152.31,132.15 152.9,132.15 154.96,134.21 155.29,134.21 GPU1.AG7
DGPU_RXN_C_CPU_TXN1: length 54.4
  L3 w0.114: v2(127.37,112.51) 127.82,112.96 128.91,112.96 130.59,111.28 131.71,111.28 134.89,114.46 138.36,114.46 143.94,120.04 143.94,128.28 148.77,133.12 150.14,133.12 v2(150.35,133.33)
  BOTTOM w0.127: v2(150.35,133.33) 150.54,133.14 151.26,133.14 ; GPU1.AE7 156.8,134.37 156.44,134.73 155.98,134.73 155.71,135 154.47,135 152.61,133.14 151.26,133.14 ; v1(151.26,133.3) 151.26,133.14 ; v2(127.37,112.51) 127.37,112.18 126.87,111.68 126.87,107.8 125.9,106.83 C1608.1
DGPU_RXN_C_CPU_TXN2: length 45.1
  L3 w0.114: v2(150.93,135.17) 150.51,134.75 149.34,134.75 143.15,128.57 143.15,123.66 135.42,115.93 134.48,115.93 132.58,114.03 132.23,114.03 131.74,113.54 131.09,113.54 130.15,112.6 v2(130.03,112.6)
  BOTTOM w0.127: v2(150.93,135.17) 151.08,135.02 153.36,135.02 153.96,135.61 155.69,135.61 156.13,136.05 GPU1.AF9 ; v2(130.03,112.6) 130.25,112.38 130.25,111.21 ; 130.25,111.21 130.25,110.08 130.03,109.86 130.03,107.49 C1610.1 ; 130.25,111.21 v1(130.08,111.21)
DGPU_RXN_C_CPU_TXN3: length 50.4
  L3 w0.114: v2(128.23,113.81) 128.89,114.47 130.68,114.47 132.89,116.68 134.91,116.68 142.4,124.17 142.4,129.7 149.66,136.96 150.67,136.96 v2(150.92,137.21)
  BOTTOM w0.127: v2(150.92,137.21) 151.13,137 151.7,137 ; 151.7,137 v1(151.7,137.16) ; 151.7,137 153.91,137 154.2,136.72 155.32,136.72 GPU1.AG10 ; v2(128.23,113.81) 128.42,113.61 128.42,112.75 128.98,112.19 128.99,112.19 129.26,111.93 129.26,110.04 128.45,109.24 128.45,104.9 C1612.1
DGPU_RXN_CPU_TXN0: length 14.5
  BOTTOM w0.089: CPU1.C23 124.14,94 124.14,94.11 123.97,94.29 123.97,94.61 124.21,94.86 124.21,95.31 123.96,95.56 123.96,97.69 124.27,98 124.27,98.04 124.29,98.05
  BOTTOM w0.127: 124.98,99.27 127.74,102.03 127.74,102.75 127.59,102.9 127.59,105.01 127.48,105.12 126.95,105.12 126.84,105.23 126.84,105.48 C1606.2 ; 124.98,99.27 124.41,98.7 124.41,98.18 124.29,98.05 ; 124.98,99.27 v1(124.87,99.37)
DGPU_RXN_CPU_TXN1: length 10.8
  BOTTOM w0.089: CPU1.B23 123.66,94.57 123.4,94.83 123.4,97.28 123.37,97.31 123.37,97.33
  BOTTOM w0.127: 126.23,102.42 126.23,101.89 123.37,99.04 123.37,97.33 ; 126.23,102.42 126.23,103.31 C1608.2 ; 126.23,102.42 v1(126.04,102.42)
DGPU_RXN_CPU_TXN2: length 15.9
  BOTTOM w0.089: CPU1.B21 125.05,93.89 125.35,93.59 125.68,93.59 125.7,93.6 125.79,93.65 125.86,93.72 125.91,93.83 125.91,94.06 125.7,94.27 125.7,94.7 125.93,94.92 125.93,96.76 125.89,96.79 125.89,96.81
  BOTTOM w0.127: 129.56,101.88 129.56,101.49 125.89,97.82 125.89,96.81 ; 129.56,101.88 v1(129.39,101.88) ; 129.56,101.88 129.56,102.59 130.06,103.09 130.06,104.69 129.75,104.99 129.75,105.91 C1610.2
DGPU_RXN_CPU_TXN3: length 11.4
  BOTTOM w0.089: 124.79,97.5 124.77,97.49 124.77,97.45 124.57,97.25 124.57,94.52 CPU1.B22
  BOTTOM w0.127: 124.79,97.5 124.98,97.7 124.98,98.01 128.53,101.56 128.53,102.8 ; C1612.2 128.53,103.76 128.53,102.8 ; 128.53,102.8 v1(128.38,102.8)
DGPU_RXP_C_CPU_TXP0: length 48.1
  L3 w0.114: v2(128.73,111.08) 128.94,111.29 129.2,111.29 130.18,110.3 132.16,110.3 134.79,112.93 138.22,112.93 144.92,119.63 144.92,127.53 146.2,128.81 147.33,128.81 148.01,129.49 148.01,130 149.66,131.64 151.43,131.64 151.68,131.89 152.03,131.89 152.16,131.77 v2(152.16,131.51)
  BOTTOM w0.127: v2(152.16,131.51) 152.56,131.91 153,131.91 155.06,133.97 155.32,133.97 155.45,133.84 GPU1.AG6 ; C1605.1 127.54,106.86 127.54,107.03 127.9,107.39 127.9,107.65 ; v2(128.73,111.08) 127.9,110.25 127.9,107.65 ; v1(128.05,107.65) 127.9,107.65
DGPU_RXP_C_CPU_TXP1: length 54.4
  L3 w0.114: v2(128.05,112.51) 128.27,112.73 128.81,112.73 130.49,111.05 131.8,111.05 134.98,114.23 138.46,114.23 144.17,119.94 144.17,128.19 148.87,132.89 150.51,132.89 150.6,132.8 150.6,132.56 v2(150.35,132.31)
  BOTTOM w0.127: v2(150.35,132.31) 150.35,132.78 150.47,132.9 152.71,132.9 153.03,133.21 ; 153.03,133.21 154.57,134.75 155.6,134.75 155.99,134.37 GPU1.AF7 ; 153.03,133.21 v1(153.14,133.1) ; C1607.1 126.14,105.17 126.14,106.73 127.12,107.7 127.12,111.58 v2(128.05,112.51)
DGPU_RXP_C_CPU_TXP2: length 45.1
  L3 w0.114: v2(150.91,134.52) 149.43,134.52 143.38,128.47 143.38,123.56 135.52,115.7 134.58,115.7 132.67,113.8 132.32,113.8 131.84,113.31 131.19,113.31 130.79,112.92 v2(130.79,112.6)
  BOTTOM w0.127: 130.27,108.31 130.27,109.76 130.49,109.98 130.49,112.3 v2(130.79,112.6) ; 130.27,108.31 130.27,107.57 130.44,107.41 C1609.1 ; 130.27,108.31 v1(130.44,108.31) ; v2(150.91,134.52) 151.16,134.77 153.46,134.77 154.06,135.37 155.79,135.37 156.11,135.69 156.69,135.69 GPU1.AE9
DGPU_RXP_C_CPU_TXP3: length 50.4
  L3 w0.114: v2(128.89,113.77) 128.89,114.15 128.99,114.24 130.77,114.24 132.98,116.45 135,116.45 142.63,124.07 142.63,129.6 149.76,136.73 150.67,136.73 v2(150.92,136.48)
  BOTTOM w0.127: 153.09,136.76 153.81,136.76 154.1,136.48 155.34,136.48 155.45,136.38 GPU1.AG9 ; 153.09,136.76 v1(153.09,136.61) ; 153.09,136.76 151.21,136.76 v2(150.92,136.48) ; v2(128.89,113.77) 128.67,113.54 128.67,112.85 129.08,112.43 129.09,112.43 129.5,112.03 129.5,109.94 128.7,109.14 128.7,105.34 C1611.1
DGPU_RXP_CPU_TXP0: length 14.5
  BOTTOM w0.089: 124.46,97.88 124.44,97.87 124.4,97.87 124.15,97.61 124.15,95.64 124.39,95.4 124.39,94.78 124.15,94.54 124.15,94.36 124.32,94.19 124.32,93.41 CPU1.C22
  BOTTOM w0.127: 124.46,97.88 124.65,98.08 124.65,98.6 126.38,100.33 ; C1605.2 127.83,105.58 127.83,103 127.99,102.85 127.99,101.93 126.38,100.33 ; 126.38,100.33 v1(126.5,100.21)
DGPU_RXP_CPU_TXP1: length 10.7
  BOTTOM w0.089: 123.62,97.33 123.62,97.31 123.59,97.28 123.59,94.91 123.67,94.83 123.83,94.83 123.93,94.92 CPU1.A23
  BOTTOM w0.127: 123.62,98.26 v1(123.74,98.26) ; 123.62,98.26 123.62,98.94 126.47,101.79 126.47,103.31 C1607.2 ; 123.62,98.26 123.62,97.33
DGPU_RXP_CPU_TXP2: length 15.8
  BOTTOM w0.089: 126.14,96.81 126.14,96.79 126.1,96.76 126.1,94.85 125.88,94.63 125.88,94.34 126.09,94.14 126.09,93.79 126.02,93.64 126.01,93.61 125.95,93.56 125.9,93.51 125.78,93.44 125.72,93.41 125.3,93.41 125.22,93.33 CPU1.C21
  BOTTOM w0.127: v1(127.9,99.24) 127.77,99.36 ; 127.77,99.36 126.14,97.72 126.14,96.81 ; 127.77,99.36 129.8,101.39 129.8,102.49 130.3,102.99 130.3,104.79 129.99,105.09 129.99,105.67 C1609.2
DGPU_RXP_CPU_TXP3: length 11.5
  BOTTOM w0.089: 124.96,97.33 124.94,97.32 124.91,97.32 124.76,97.17 124.76,95.17 CPU1.A21
  BOTTOM w0.127: 125.61,98.3 128.77,101.46 128.77,103.22 128.89,103.33 129.41,103.33 129.51,103.43 129.51,103.64 C1611.2 ; 125.61,98.3 125.22,97.91 125.22,97.6 124.96,97.33 ; 125.61,98.3 v1(125.74,98.18)
DGPU_TXN_CPU_RXN0: length 7.1
  TOP w0.127: 155.05,134.4 155.26,134.4 157.18,136.32 158.55,136.32 158.77,136.1 159,136.1 159.07,136.16 v2(159.07,136.45) ; 155.05,134.4 v1(155.05,134.55) ; 155.05,134.4 154.4,134.4 C7302.2
  BOTTOM w0.127: v2(159.07,136.45) 159.47,136.05 GPU1.AB9
DGPU_TXN_CPU_RXN1: length 5.6
  TOP w0.127: 155.18,136.16 155.62,136.16 156.27,136.82 158.14,136.82 158.25,136.93 v2(158.25,137.27) ; 155.18,136.16 154.53,136.16 C7304.2 ; 155.18,136.16 v1(155.18,136.3)
  BOTTOM w0.127: GPU1.AC10 158.25,137.25 v2(158.25,137.27)
DGPU_TXN_CPU_RXN2: length 4.1
  TOP w0.127: v2(158.24,138.11) 157.82,138.53 156.93,138.53 ; 156.93,138.53 156.11,138.53 155.87,138.29 C7306.2 ; 156.93,138.53 v1(156.93,138.71)
  BOTTOM w0.127: GPU1.AC11 158.24,138.1 v2(158.24,138.11)
DGPU_TXN_CPU_RXN3: length 5.5
  TOP w0.127: 158.05,139.85 155.23,139.85 C7308.2 ; 158.05,139.85 v1(158.05,140.01) ; 158.05,139.85 158.56,139.85 158.9,139.51 158.9,139.1 v2(159.07,138.93)
  BOTTOM w0.127: GPU1.AB12 159.09,138.93 v2(159.07,138.93)
DGPU_TXP_CPU_RXP0: length 7.1
  TOP w0.127: 156.37,135.16 157.28,136.08 158.45,136.08 158.67,135.86 159,135.86 159.08,135.78 v2(159.08,135.62) ; 156.37,135.16 v1(156.47,135.06) ; 156.37,135.16 155.36,134.15 154.32,134.15 C7301.2
  BOTTOM w0.127: v2(159.08,135.62) 159.08,135.81 158.84,136.05 GPU1.AC9
DGPU_TXP_CPU_RXP1: length 6.3
  TOP w0.127: 156.65,136.58 156.37,136.58 155.72,135.92 154.49,135.92 C7303.2 ; 156.65,136.58 v1(156.65,136.43) ; 156.65,136.58 158.24,136.58 158.93,137.27 v2(159.08,137.27)
  BOTTOM w0.127: v2(159.08,137.27) 159.08,137.26 GPU1.AB10
DGPU_TXP_CPU_RXP2: length 4.1
  TOP w0.127: C7305.2 155.39,137.16 155.81,137.16 155.91,137.27 155.91,137.7 ; 155.91,137.7 v1(156.06,137.7) ; 155.91,137.7 155.91,137.99 156.21,138.29 157.27,138.29 v2(157.45,138.11)
  BOTTOM w0.127: GPU1.AD11 157.45,138.09 v2(157.45,138.11)
DGPU_TXP_CPU_RXP3: length 5.5
  TOP w0.127: v2(158.25,138.93) 158.56,138.93 158.66,139.03 158.66,139.41 158.46,139.61 155.94,139.61 ; 155.94,139.61 155.48,139.61 C7307.2 ; 155.94,139.61 v1(155.94,139.45)
  BOTTOM w0.127: v2(158.25,138.93) GPU1.AC12
DIS_1D35V_VGA_S0: length 3.8
  TOP w0.254: v1(175.47,57.59) 175.47,57.44 175.69,57.22 PR8315.2
  TOP w0.508: PR8315.2 175.69,53.95 PQ8306.D
DMIC_CLK: length 254.3
  TOP w0.14: v1(176.66,14.23) 175.83,13.39 v2(175.83,13.39) ; v2(81.33,165.54) 81.29,165.58 EC5206.1 80.78,165.77 80.78,165.12 81.02,164.88 R5207.2
  L3 w0.127: v2(81.33,165.54) 81.52,165.73 81.52,166.15 81.85,166.48 81.85,167.11 82.2,167.47 85.83,167.47 90.58,162.71 90.58,152.81 90.63,152.76 90.63,150.66 91.96,149.33 94.03,149.33 95.81,151.11 106.38,151.11 109.58,154.31 110.42,154.31 112.5,152.23 140.49,152.23 v2(140.75,152.48)
  L4 w0.127: v2(140.75,152.48) 140.93,152.3 140.93,151.65 140.75,151.47 140.75,148.77 142.76,146.76 142.76,143.72 141.04,142 141.04,123.26 140.21,122.44 140.21,117.49 145.69,112.01 145.69,109.25 145.1,108.67 145.1,102.53 147.38,100.25 147.71,100.25 153.37,94.59 153.37,93.25 154.67,91.96 154.67,91.57 157.57,88.67 157.58,88.67 157.61,88.64 158.29,88.64 161.78,85.15 166.14,85.15 166.66,84.63 166.66,84.35 167.16,83.85 167.16,83.85 168.49,82.53 170.09,82.53 170.37,82.25 170.37,81.36 172.17,79.56 172.17,78.74 174.04,76.87 174.04,76.42 175,75.45 175.38,75.45 176.16,74.67 176.16,72.98 177.07,72.06 177.07,70.1 178.28,68.89 178.28,66.99 178.71,66.55 178.71,65.36 178.07,64.72 178.07,62.58 178.02,62.53 178.02,59.45 180.57,56.91 180.57,53.64 182.24,51.97 182.24,48.9 182.49,48.66 182.49,44.31 182.91,43.88 182.91,39.56 183.46,39.01 183.46,37.93 185,36.4 185,34.11 184.08,33.2 182.49,33.2 177.06,27.77 177.06,22.24 177.49,21.81 177.49,15.05 v2(175.83,13.39)
  BOTTOM w0.14: v2(175.83,13.39) 176.07,13.63 C2723.2 R2716.1
DMIC_CLK_EDP: length 4.5
  TOP w0.14: R5207.1 81.5,163.99 81.68,163.81 81.68,163.47 81.47,163.26 81.09,163.26 80.53,163.82 80.29,163.82 ; 80.29,163.82 v1(80.29,163.99) ; 80.29,163.82 79.3,163.82 79.3,163.82 LCD1.27
DMIC_CLK_R: length 2.6
  BOTTOM w0.14: R2716.2 178.01,14.09 178.56,14.09 v1(178.99,14.52) 179.35,14.88 179.42,14.88 179.43,14.89 HDA27.3
DMIC_DATA: length 253.6
  TOP w0.14: R5215.2 82.44,164.88 82.78,165.22 82.78,165.64 EC5205.1 v2(82.15,165.54) ; v2(176.37,13.06) v1(177.01,13.06)
  L3 w0.127: v2(82.15,165.54) 81.9,165.79 81.9,165.99 82.23,166.32 82.23,166.95 82.36,167.09 85.67,167.09 90.2,162.55 90.2,152.63 90.25,152.58 90.25,150.5 91.8,148.95 94.19,148.95 95.97,150.73 106.54,150.73 109.74,153.93 110.26,153.93 112.34,151.85 140.75,151.85 141.46,152.56 v2(141.46,152.66)
  L4 w0.127: v2(176.37,13.06) 176.37,13.39 177.87,14.89 177.87,21.97 177.44,22.4 177.44,27.61 182.65,32.82 184.24,32.82 185.38,33.96 185.38,36.55 183.84,38.09 183.84,39.17 183.29,39.71 183.29,44.04 182.87,44.46 182.87,48.81 182.62,49.06 182.62,52.12 180.95,53.79 180.95,57.06 178.4,59.61 178.4,62.37 178.46,62.42 178.46,64.56 179.09,65.2 179.09,66.71 178.66,67.14 178.66,69.05 177.45,70.25 177.45,72.22 176.54,73.14 176.54,74.83 175.53,75.84 175.16,75.84 174.42,76.58 174.42,77.03 172.55,78.9 172.55,79.72 170.75,81.52 170.75,82.41 170.24,82.91 168.64,82.91 167.32,84.23 167.32,84.23 167.04,84.51 167.04,84.79 166.3,85.53 161.94,85.53 158.45,89.02 157.77,89.02 157.74,89.05 157.73,89.05 155.05,91.73 155.05,92.11 153.75,93.41 153.75,94.75 147.87,100.63 147.54,100.63 145.49,102.69 145.49,108.51 146.07,109.09 146.07,112.17 140.59,117.64 140.59,122.28 141.42,123.11 141.42,141.84 143.15,143.57 143.15,146.92 141.14,148.93 141.14,151.31 141.31,151.49 141.31,152.51 v2(141.46,152.66)
  BOTTOM w0.14: R2714.1 176.92,13.35 176.67,13.35 v2(176.37,13.06)
DMIC_DATA_EDP: length 4.9
  TOP w0.14: R5215.1 82.07,163.88 82.07,163.31 81.84,163.08 ; 81.84,163.08 v1(81.95,162.97) ; 81.84,163.08 81.63,162.87 80.93,162.87 80.37,163.43 79.69,163.43 79.69,163.43 79.46,163.43 79.36,163.32 LCD1.28
DMIC_DATA_R: length 4.8
  BOTTOM w0.14: v1(178.75,12.7) 178.65,12.7 178.34,12.4 EC2701.1 177.74,13.06 R2714.2 178.37,13.69 178.72,13.69 179.51,14.49 HDA27.2
DP_CRT_B: length 4.5
  TOP w0.114: U5502.10 24.74,65.08 v1(24.56,64.9) 24.51,64.84 24.22,64.84 R5501.1 C5509.1 22.54,64.05 L5502.1
DP_CRT_G: length 5.3
  TOP w0.114: U5502.12 25.19,64.08 24.9,63.79 24.9,63.67 v1(24.71,63.47) 23.69,62.46 R5513.1 C5512.1 22.61,61.9 L5501.1
DP_CRT_HSYNC_CON: length 3.8
  TOP w0.14: v1(24.42,68.75) 24.78,68.39 R5511.1 25.59,67.67 26.64,66.61 U5502.8
DP_CRT_R: length 6.4
  TOP w0.114: U5502.15 25.32,62.58 24.91,62.17 24.91,60.65 v1(24.54,60.28) R5514.1 C5506.1 21.94,59.37 L5503.1
DP_CRT_VSYNC_CON: length 2.4
  TOP w0.14: U5502.7 27.14,66.97 26.63,67.48 v1(26.61,67.48) 26.61,67.51 26.45,67.67 R5507.1
DS3_PWRCTL: length 61.6
  L3 w0.127: v2(151.21,77.8) 151.21,76.62 152,75.82 161.22,75.82 164.45,79.05 170.7,79.05 172.1,80.46 175.25,80.46 176.16,81.37 179.18,81.37 180.99,79.56 180.99,79.46 181.4,79.05 181.77,79.05 182.1,78.72 182.1,78.36 181.87,78.13 181.87,77.6 182.11,77.36 183.87,77.36 184.94,78.43 187.06,78.43 188.34,77.15 188.34,75.99 188.74,75.59 188.74,74.52 186.51,72.29 186.51,69.32 v2(185.67,68.48)
  BOTTOM w0.127: U3801.4 184.42,67.52 184.63,67.73 184.63,68.3 v1(185.13,68.8) 185.35,68.8 v2(185.67,68.48) ; R3802.2 148.57,78.27 150.77,78.27 151.21,77.83 v2(151.21,77.8)
DSWODVREN: length 12.5
  TOP w0.102: R1720.1 R1721.1 138.79,65.01 v2(138.79,67.34)
  BOTTOM w0.089: CPU1.AW7 133.28,72.82 133.28,72.23 133.21,72.16 133.21,71.53 133.63,71.1 133.65,71.1 134.15,70.6 134.18,70.6
  BOTTOM w0.102: 134.18,70.6 134.2,70.58 134.81,70.58 137.4,68 137.44,68 v1(137.68,67.75) 137.88,67.56 138.57,67.56 v2(138.79,67.34)
E51_RX1: length 4.5
  TOP w0.102: TP5802.1 168.41,51.24 v2(167.95,51.69)
  BOTTOM w0.102: WLAN1.46 171.02,51.8 169.87,51.8 169.62,52.04 169.62,52.14 169.22,52.53 168.79,52.53 v2(167.95,51.69)
E51_RX2: length 7
  TOP w0.102: TP5803.1 166.64,51.67 v2(166.4,51.67)
  BOTTOM w0.102: WLAN1.58 168.95,48.77 166.58,51.14 166.58,51.49 v2(166.4,51.67)
E51_TX1: length 10.4
  TOP w0.102: v1(179.02,55.16) 177.52,55.16 R5806.2 176.84,55.7 v2(176.4,56.15)
  BOTTOM w0.102: WLAN1.44 173.18,52.27 176.4,55.49 v2(176.4,56.15)
E51_TX2: length 6.6
  TOP w0.102: TP5804.1 165.97,51.39 165.97,51.85 166.22,52.1 166.76,52.1 167.21,52.56 v2(167.44,52.56)
  BOTTOM w0.102: WLAN1.38 168.66,53.77 167.6,52.71 167.6,52.71 v2(167.44,52.56)
E51_TXD: length 26.1
  TOP w0.102: R5806.1 178.87,55.7 179.73,56.57 v1(180.08,56.57) 180.09,56.58 185.66,56.58 186.39,57.31 v2(187.56,57.31) ; KBC24.111 184.4,68.79 v2(185.08,69.48)
  L4 w0.102: v2(185.08,69.48) 185.08,67.69 185.38,67.39 185.63,67.14 185.63,67.14 186.06,66.71 186.06,60.33 186.94,59.45 186.94,58.29 187.56,57.66 v2(187.56,57.31)
EAPD#: length 3.9
  TOP w0.102: v1(181.65,14.13) 181.64,14.13 181.02,13.51 R2708.2 180.93,13.11 v2(180.32,12.5)
  BOTTOM w0.102: v2(180.32,12.5) 181.11,12.5 181.42,12.81 HDA27.47
EC_AGND: length 16.5
  TOP w0.203: KBC24.103 181.2,66.24 181.11,66.16 181.11,65.14 R2435.2
  TOP w0.254: v2(174.98,63.35) 174.98,62.93 v1(175.27,62.64)
  TOP w0.508: v2(174.98,63.35) 174.48,63.35 174.23,63.61 R2407.2 C2403.1 ; C2404.2 180.35,64.75 180.93,64.17 C2405.2 180.93,63.04 v2(180.82,62.93) ; R2406.2 C2402.1 176.93,64.01 C2414.1 176.94,63.48 v2(176.64,63.17)
  BOTTOM w0.508: v2(174.98,63.35) 175.15,63.18 176.63,63.18 v2(176.64,63.17) 176.64,63.18 180.56,63.18 180.81,62.93 v2(180.82,62.93)
EC_BRIGHTNESS: length 226.7
  TOP w0.14: v2(193.01,86.66) 193.02,86.65 193.02,84.5 193.12,84.41 193.12,84.33 193.16,84.29 193.16,82.01 192.74,81.59 KBC24.32 ; v2(64.75,164.85) 64.32,164.42 D5202.2
  L4 w0.127: v2(146.39,161.37) 146.07,161.69 146.07,162.2 145.67,162.59 145.67,172.39 145.47,172.6 142.47,175.59 128.94,175.59 128.76,175.77 115.83,175.77 114.43,177.17 109.41,177.17 109.2,176.95 108.83,176.95 108.61,177.17 106.03,177.17 103.59,174.74 84.84,174.74 83.81,175.77 80.97,175.77 80.34,175.14 76.74,175.14 73.62,172.02 v2(73.62,171.37)
  BOTTOM w0.14: v2(64.75,164.85) 71.27,171.37 v2(73.62,171.37) ; v2(146.39,161.37) 146.39,161.25 144.6,159.46 144.6,152.44 144.54,152.38 144.54,140.84 145.68,139.7 145.68,133.42 144.69,132.42 144.69,121.33 149.79,116.23 149.79,107.07 151.33,105.53 151.33,104.18 154.5,101.02 154.5,95.92 154.34,95.75 154.34,94.45 155.41,93.38 155.41,90.87 157.53,88.75 161.62,88.75 162.24,89.37 174.07,89.37 177.25,86.19 179.42,86.19 179.71,85.9 v1(182.01,85.9) 182.46,85.9 182.51,85.86 186.65,85.86 186.84,85.66 188.4,85.66 189.14,86.4 189.35,86.4 189.67,86.73 190.34,86.73 190.82,87.21 192.46,87.21 v2(193.01,86.66)
EC_SCI#: length 72.1
  L3 w0.102: v2(149.18,81.54) 149.35,81.71 149.35,83.2 149.6,83.45 149.96,83.45 150.67,82.75 153.81,82.75 154.09,82.47 156.62,82.47 157.99,83.83 160.05,83.83 160.82,84.61 164.17,84.61 165.74,83.04 166.25,83.04 166.76,83.56 166.76,84.86 167.23,85.34 169.2,85.34 169.46,85.07 171.44,85.07 172.87,83.64 174.18,83.64 174.35,83.81 177.5,83.81 178.66,82.65 180,82.65 v2(181.24,81.41)
  BOTTOM w0.089: CPU1.AM2 136.75,77.09 137.39,77.09 137.53,76.95 138.72,76.95
  BOTTOM w0.102: 138.72,76.95 138.94,76.73 141.41,76.73 141.89,77.21 143.65,77.21 144.98,78.54 146.91,78.54 149.12,80.75 149.12,81.48 v2(149.18,81.54) 149.21,81.57 RN1809.6 ; v2(181.24,81.41) 181.62,81.79 v1(182.17,81.79) 182.18,81.78 191.21,81.78 191.43,82.01 195.23,82.01 195.61,82.39 195.62,82.39 195.87,82.64 195.87,83.62 R2408.2
EC_SMI#: length 73.5
  L3 w0.102: v2(142.43,90.81) 142.69,91.06 143.7,91.06 144.99,92.35 146.76,92.35 147.12,92 148.24,92 148.45,91.8 148.81,91.8 150.13,93.12 153.37,93.12 153.96,92.54 156.31,92.54 157.29,93.52 158.5,93.52 163.6,88.42 169.83,88.42 170.61,87.65 176.37,87.65 177.67,86.35 179.95,86.35 181.11,85.19 182.13,85.19 185.3,82.02 185.3,80.82 186.34,79.79 187.53,79.79 188.21,79.11 188.82,79.11 189.19,78.75 189.19,78.31 190.48,77.02 190.48,76.2 189.89,75.61 189.89,74.73 v2(189.71,74.55)
  BOTTOM w0.102: CPU1.V1 138.82,84.87 140.12,86.17 140.12,86.68 141.32,87.87 141.32,89.69 v2(142.43,90.81) 142.5,90.74 RN1902.3 ; R2409.2 188.88,74.96 v1(189.02,75.1) 189.54,75.1 189.71,74.94 v2(189.71,74.55)
EC_SPI_CLK_C: length 4.2
  TOP w0.14: KBC24.92 177.25,70.39 176.31,70.39 175.01,69.09 v1(174.9,69.09) 174.55,69.09 174.09,68.64 R2420.2
EC_SPI_CS#_C: length 4.2
  TOP w0.14: KBC24.90 176.34,71.19 175.42,70.26 v1(175.42,70.21) 174.73,69.52 R2419.2
EC_SPI_DI_C: length 4.3
  TOP w0.14: R2422.2 173.47,71.35 175.26,71.35 v1(175.37,71.45) 175.52,71.45 176.45,72.39 KBC24.87
EC_SPI_DO_C: length 4.2
  TOP w0.14: R2423.2 174.16,72.08 174.23,72.01 v1(174.28,72.01) 175.46,72.01 176.23,72.79 KBC24.86
EC_SWI#: length 88.3
  TOP w0.102: R2410.2 189.46,63.88 v2(188.75,63.17)
  L3 w0.102: v2(162.04,81.66) 162.25,81.46 162.25,80.99 162.43,80.81 162.43,78.37 160.34,76.28 154.8,76.28 152.39,78.7 151.12,78.7 150.57,78.15 150.57,77.46 150.38,77.27 148.6,77.27 147.84,78.02 145.07,78.02 143.61,79.48 141.68,79.48 140.89,78.69 138.15,78.69 136.45,77 v2(136.12,77)
  L4 w0.102: v2(162.04,81.66) 162.04,81.17 169.19,74.03 169.55,74.03 173.04,70.54 173.04,66.74 v2(172.57,66.27)
  BOTTOM w0.102: v2(136.12,77) 135.81,77.3 CPU1.AM3 ; v2(162.04,81.66) 162.16,81.78 162.16,83.46 161.8,83.81 161.14,83.81 ; v1(161.14,83.61) 161.14,83.81 ; 161.14,83.81 157.01,83.81 156.39,83.19 156.39,82.8 155.22,81.63 155.22,81.63 154.94,81.35 RN2012.8 ; v2(188.75,63.17) 187.87,63.17 186.76,62.06 175.04,62.06 172.58,64.52 172.58,64.52 172.3,64.8 172.3,65.99 v2(172.57,66.27)
EC_VBKUP: length 3.2
  TOP w0.203: 185.6,65.88 KBC24.114
  TOP w0.254: 185.6,65.88 185.6,65.21 v1(185.65,65.15) 185.65,64.12 R2428.1
EC_VTT: length 4.1
  TOP w0.203: 193.95,73.19 KBC24.12
  TOP w0.508: v1(194.22,71.83) 194.44,71.83 194.77,72.16 R2401.2 195.18,72.28 194.66,72.8 C2401.1 194.15,72.99 193.95,73.19
ECRST#: length 9.2
  TOP w0.102: KBC24.85 175.73,73.19 v1(175.52,72.98) 175.46,72.92 R2418.1 C2418.1 R2424.2 172.39,72.92 171.38,71.91 Q2404.E
ECSCI#_KBC: length 5.9
  TOP w0.102: v2(194.28,83.1) 194.24,83.06 194.24,80.78 193.45,79.99 KBC24.29
  BOTTOM w0.102: v1(193.64,83.43) 193.97,83.1 v2(194.28,83.1) 194.81,83.62 R2408.1
ECSMI#_KBC: length 8.8
  TOP w0.102: KBC24.6 192.02,70.79 191.6,70.36 191.19,70.36 189.36,70.36 189.25,70.46 188.93,70.46 188.59,70.8 188.59,72.5 v2(187.97,73.12)
  BOTTOM w0.102: R2409.1 187.42,73.53 v1(187.42,73.28) 187.57,73.12 v2(187.97,73.12)
ECSWI#_KBC: length 4.2
  TOP w0.102: v1(189.88,63.52) 189.92,63.56 189.92,64.13 189.92,64.14 189.92,65.16 189.69,65.38 189.46,65.38 R2410.1 189.2,65.63 KBC24.123
EDP_AUX: length 5.7
  TOP w0.127: v1(82.89,174.02) 82.89,173.74 82.25,173.11 82.16,173.11 C5212.2 81.83,172.78 81.6,172.78 R5218.1 81,172.75 80.56,172.75 79.63,171.82 LCD1.11
EDP_AUX#: length 4.7
  TOP w0.127: 80.11,171.97 v1(80.22,171.86) ; 80.11,171.97 79.73,171.58 79.34,171.58 79.08,171.32 LCD1.12 ; 80.11,171.97 80.66,172.51 81.06,172.51 R5219.1 81.59,172.53 81.85,172.53 C5209.2
EDP_AUX_DN: length 96.1
  TOP w0.127: v2(85.78,170.74) 86.06,170.46 86.82,170.46 87.13,170.77 87.13,171.86 86.45,172.54 83.32,172.54 C5209.1
  L4 w0.114: v2(110.34,100.97) 110.1,100.73 109.84,100.73 109.73,100.83 109.73,101.49 108.95,102.27 108.4,102.27 104.48,106.2 104.48,115.32 105.87,116.72 105.87,131.2 101.78,135.3 101.78,137.29 101.49,137.58 101.49,140.03 94.89,146.62 94.89,150.91 89.69,156.11 89.69,166.55 86.3,169.94 86.3,170.24 86.04,170.5 86.03,170.5 v2(85.78,170.74)
  BOTTOM w0.127: 109.66,99.92 109.16,99.42 109.16,96.83 109.97,96.02 109.97,95.19 CPU1.A45 ; 109.66,99.92 v1(109.56,100.03) ; 109.66,99.92 109.92,100.18 109.92,100.55 v2(110.34,100.97)
EDP_AUX_DP: length 96.4
  TOP w0.127: C5212.1 83.33,172.78 86.55,172.78 87.37,171.96 87.37,170.67 86.92,170.22 86.02,170.22 v2(85.86,170.06)
  L4 w0.114: v2(85.86,170.06) 89.47,166.45 89.47,156.02 94.67,150.82 94.67,146.72 94.67,146.72 94.67,146.53 101.26,139.94 101.26,137.48 101.55,137.19 101.55,135.2 101.68,135.07 105.65,131.11 105.65,116.81 104.25,115.42 104.25,106.1 108.31,102.05 108.85,102.05 109.5,101.4 109.5,100.93 109.5,100.93 109.5,100.74 109.74,100.5 110.14,100.5 v2(110.36,100.28)
  BOTTOM w0.127: 109.4,98.71 109.4,99.32 v2(110.36,100.28) ; 109.4,98.71 v1(109.53,98.71) ; 109.4,98.71 109.4,96.93 110.21,96.12 110.21,94.89 109.86,94.54 CPU1.B45
EDP_BKLT_CTRL: length 9.1
  TOP w0.14: v2(65.03,163.63) 60.87,163.63 60.58,163.92 D5202.1
  BOTTOM w0.14: v2(65.03,163.63) 66.56,163.63 v1(66.93,164.01) 67.03,164.1 R5222.2 68.04,164.11 R5206.2
EDP_BRIGHTNESS: length 1.9
  TOP w0.14: TP801.1 111.31,96.45 v2(111.49,96.27)
  BOTTOM w0.14: CPU1.A43 111.24,96.03 v2(111.49,96.27)
EDP_COMP: length 3.2
  TOP w0.508: v2(126.3,92.83) 125.86,93.27 v1(125.35,93.27) R801.2
  BOTTOM w0.305: v2(126.3,92.83) 126.11,93.02 CPU1.D20
EDP_HPD: length 150
  L4 w0.102: v2(139.68,99.27) 139.89,99.47 139.89,103.39 137.65,105.63 137.65,107.73 135.97,109.4 135.97,111.2 136.21,111.43 136.23,111.43 136.51,111.71 136.51,123.94 137.17,124.6 137.17,145.99 135.07,148.09 121.9,148.09 120.94,147.12 120.77,147.12 120.77,147.13 105.69,147.13 99.25,153.57 99.24,153.59 99.24,153.76 99.25,153.76 99.25,156.54 99.02,156.77 99.02,157.38 102.14,160.51 102.14,162.69 101.25,163.57 101.25,164.05 97.34,167.96 91.54,167.96 87.82,171.68 79.19,171.68 v2(74.57,167.06)
  BOTTOM w0.089: 135.49,94.59 135.49,94.31 135.29,94.11 134.87,94.11 134.7,93.94 134.7,93.82 134.47,93.59 134.35,93.59 134.06,93.3 CPU1.D6
  BOTTOM w0.102: 135.49,94.59 135.57,94.67 135.57,95.27 139.57,99.27 v2(139.68,99.27) ; RN5203.6 72.54,167.59 72.9,167.94 72.9,168.49 73.34,168.93 v1(73.6,168.93) 73.99,168.93 74.32,168.6 74.32,167.31 v2(74.57,167.06) 74.95,166.68 75.04,166.68 75.28,166.44 RN5201.5
EDP_HPD_CONN: length 11.9
  TOP w0.102: LCD1.9 77.97,172.82 77.1,173.69 v2(77.1,174.15)
  BOTTOM w0.102: RN5201.4 77.16,166.44 77.27,166.32 77.87,166.32 78.29,166.74 78.29,168.58 v1(77.78,169.08) 77.1,169.77 v2(77.1,174.15)
EDP_SPARE: length 2.7
  TOP w0.102: TP605.1 110.65,96.25 110.61,96.29 v2(110.61,96.28)
  BOTTOM w0.102: v2(110.61,96.28) 110.61,96.29 110.84,96.06 110.84,94.84 CPU1.B43
EDP_TX0: length 3
  TOP w0.127: C5210.2 81,170 80,170 79.94,169.94 79.22,169.94 79.1,169.82 LCD1.15
EDP_TX0#: length 3.2
  TOP w0.127: LCD1.14 79.1,170.32 79.23,170.18 79.84,170.18 79.9,170.24 80.3,170.24 ; 80.3,170.24 81,170.24 C5203.2 ; 80.3,170.24 v1(80.3,170.41)
EDP_TX0_DN: length 93.6
  TOP w0.127: C5203.1 82.44,170.29 83.22,170.29 v2(83.37,170.44) ; v1(108.47,97.77) 108.47,98.36 v2(108.46,98.37)
  L4 w0.114: v2(108.46,98.37) 108.3,98.52 107.99,98.52 107.74,98.77 107.74,100.49 102.75,105.48 102.75,116.1 104.12,117.47 104.12,130.51 100.05,134.58 100.05,136.57 99.71,136.91 99.71,139.37 93.16,145.92 93.16,147.04 87.86,152.34 87.86,161.76 83.8,165.82 82.98,165.82 81.62,167.18 81.62,169.57 82.45,170.4 83.34,170.4 v2(83.37,170.44)
  BOTTOM w0.127: v2(108.46,98.37) 108.2,98.1 108.2,97.18 109.56,95.81 109.56,94.29 109.86,93.98 CPU1.C45
EDP_TX0_DP: length 93.7
  TOP w0.127: v2(83.37,169.7) 83.02,170.05 82.43,170.05 82.19,169.81 C5210.1 ; v2(108.46,99) 108.86,99 v1(109.07,99.22)
  L4 w0.114: v2(83.37,169.7) 83.37,169.81 83.01,170.18 82.55,170.18 81.85,169.47 81.85,167.28 83.08,166.05 83.89,166.05 88.09,161.85 88.09,152.43 93.38,147.13 93.38,146.01 99.94,139.46 99.94,137.01 100.28,136.66 100.28,134.68 104.35,130.61 104.35,117.37 102.98,116.01 102.98,105.57 107.97,100.59 107.97,98.87 108.08,98.75 108.21,98.75 v2(108.46,99)
  BOTTOM w0.127: CPU1.B46 109.32,94.13 109.32,95.71 107.95,97.08 107.95,98.2 108.01,98.26 108.01,98.56 v2(108.46,99)
EDP_TX1: length 3.2
  TOP w0.127: LCD1.18 79.05,168.32 79.18,168.45 79.94,168.45 80.09,168.29 80.32,168.29 ; C5213.2 81.02,168.29 80.32,168.29 ; 80.32,168.29 v1(80.32,168.15)
EDP_TX1#: length 3.1
  TOP w0.127: C5211.2 81,168.54 80.19,168.54 80.04,168.69 79.18,168.69 79.05,168.82 LCD1.17
EDP_TX1_DN: length 90.5
  TOP w0.127: v2(83.34,168.84) 83.04,168.53 82.49,168.53 C5211.1
  L4 w0.114: v2(108.97,100.16) 108.56,100.57 108.56,100.73 108.49,100.8 103.5,105.79 103.5,115.75 104.9,117.15 104.9,130.8 101.37,134.32 100.8,134.89 100.8,136.88 100.51,137.17 100.51,139.63 93.91,146.23 93.91,150.51 88.63,155.79 88.63,162.11 84.17,166.57 83.29,166.57 82.37,167.49 82.37,168.27 82.6,168.5 83.01,168.5 v2(83.34,168.84)
  BOTTOM w0.127: 107.42,99.14 107.42,96.78 108.19,96.01 108.19,95.41 108.54,95.07 108.72,95.07 CPU1.A47 ; 107.42,99.14 107.42,99.35 108.35,100.28 108.84,100.28 v2(108.97,100.16) ; 107.42,99.14 v1(107.58,99.14)
EDP_TX1_DP: length 90.5
  TOP w0.127: v2(83.32,167.97) 83,168.29 82.47,168.29 C5213.1
  L4 w0.114: v2(109,100.84) 108.78,100.84 108.72,100.9 103.73,105.89 103.73,115.66 105.12,117.05 105.12,130.89 101.47,134.55 101.03,134.99 101.03,136.97 100.74,137.27 100.74,137.28 100.74,139.72 94.13,146.32 94.13,150.61 88.86,155.88 88.86,162.2 84.26,166.8 83.39,166.8 82.6,167.59 82.6,168.17 82.69,168.27 83.02,168.27 v2(83.32,167.97)
  BOTTOM w0.127: 107.18,97.99 107.18,99.45 108.25,100.52 108.68,100.52 v2(109,100.84) ; 107.18,97.99 v1(107.04,97.99) ; 107.18,97.99 107.18,96.68 107.95,95.91 107.95,95.31 108.74,94.52 CPU1.B47
EDP_VDD_EN: length 161
  L3 w0.127: v2(138.56,99.88) 139.05,100.36 139.05,100.94 142.13,104.03 142.13,109.1 143.34,110.31 143.34,117.17 145.8,119.64 v2(145.8,122.66)
  L4 w0.127: v2(145.8,122.66) 147.09,123.94 147.09,128.16 145.84,129.41 145.84,131.51 145.89,131.56 145.89,138.59 146.23,138.92 146.23,141.35 145.3,142.27 145.3,148.82 144.8,149.32 144.8,155.28 141.51,158.56 140.11,158.56 139.58,158.56 137.46,160.68 137.46,162.47 133.78,166.16 133.78,169.81 131.85,171.73 127.74,171.73 126.5,172.98 112.71,172.98 112.24,173.45 110.19,173.45 109.6,172.86 105.43,172.86 104.5,171.92 78.11,171.92 76.89,170.71 76.89,170.02 74.06,167.19 74.06,166.77 73.8,166.51 72.07,166.51 70.38,164.81 70.38,164.15 v2(70.85,163.68)
  BOTTOM w0.127: CPU1.C6 133.54,94.08 133.54,94.57 133.76,94.8 133.76,95.67 134.98,96.88 135.82,96.88 137.01,98.08 137.01,98.6 v1(137.18,98.76) 138.28,99.87 138.28,99.88 v2(138.56,99.88) ; D5201.1 70.12,162.95 v2(70.85,163.68)
FAN1_DAC_1: length 153.5
  TOP w0.203: KBC24.101 180.4,66.42 180.21,66.23 179.81,66.23
  TOP w0.254: 179.81,66.23 179.54,65.96 v2(177.28,65.96) ; v1(98.36,147.25) v2(98.91,147.25)
  L3 w0.254: v2(98.91,147.25) 99.59,147.25 101.8,149.46 108.11,149.46 110.12,151.46 110.8,151.46 111.23,151.03 138.77,151.03 139.3,150.51 v2(139.3,150.42)
  L4 w0.254: v2(139.3,150.42) 139.77,149.95 139.77,123.52 139.13,122.88 139.13,116.36 143.21,112.28 143.21,107.27 142.98,107.04 142.98,101.81 146.29,98.51 146.29,97.94 146.76,97.46 147.08,97.46 148.1,96.45 148.12,96.45 149.99,94.58 149.99,94.12 151.46,92.65 152.12,92.65 153.19,91.58 153.19,91 157.02,87.18 157.81,87.18 161.22,83.77 164.32,83.77 164.87,83.22 164.87,80.91 168.54,77.24 169.34,77.24 170.87,75.71 170.87,75.33 171.51,74.7 172.34,74.7 173.03,74.01 173.03,73.4 175.72,70.71 175.72,69.34 176.76,68.3 176.76,66.51 177.28,65.99 v2(177.28,65.96)
  BOTTOM w0.254: FAN261.4 98.62,147.51 98.91,147.22 v2(98.91,147.25)
FAN_TACH1: length 174
  TOP w0.203: KBC24.31 193.63,80.79 193.76,80.92 193.76,82.71
  TOP w0.254: v2(142.39,151.36) 143.79,151.36 144.03,151.59 148.93,151.59 v2(149.05,151.46) ; 193.76,82.71 193.71,82.77 193.71,84.56 R2415.1 193.58,84.68 193.53,84.73 193.53,87.12 v2(194.17,87.76)
  L3 w0.254: v2(142.39,151.36) 141.58,151.36 140.14,149.92 138.72,149.92 138.17,150.47 111.65,150.47 111.31,150.12 110.09,150.12 108.85,148.87 102.5,148.87 97.52,143.9 v2(97.52,140.6)
  L4 w0.254: v2(149.05,151.46) 149.64,150.88 149.64,148.74 148.85,147.95 148.85,144.77 149.64,143.98 149.64,131.68 150.2,131.12 150.2,124.47 150.15,124.42 150.15,123.31 153.29,120.17 v2(153.75,120.17)
  BOTTOM w0.254: R2606.1 EC2602.1 97.1,141.03 v2(97.52,140.6) ; v2(194.17,87.76) 193.86,88.07 190.28,88.07 189.97,88.37 184.78,88.37 184.73,88.32 v1(181.26,88.32) 180.1,88.32 179.9,88.12 178.53,88.12 175.97,90.68 160.33,90.68 160.12,90.9 158.51,90.9 158.31,90.69 157.37,90.69 156.67,91.39 156.67,98.99 156.04,99.62 156.04,101.66 152.88,104.82 152.88,106.17 151.75,107.3 151.75,116.21 152.48,116.95 152.48,118.9 v2(153.75,120.17)
FAN_TACH1_C: length 6.3
  TOP w0.254: v2(92.79,139.81) 92.82,139.78 AFTP2802.1
  BOTTOM w0.254: FAN1.3 93.87,137.8 92.79,138.87 v2(92.79,139.81) 92.93,139.94 94.83,139.94 95.07,140.19 R2606.2
FAN_VCC1: length 1.1
  TOP w0.508: v3(92.62,135.56) 92.08,136.1 AFTP2801.1
  vias: v1(98.22,137.17)
FB_CAL_PD_VDDQ: length 2.6
  TOP w0.305: v2(174.04,146.37) 174.65,146.98 175.07,146.98 175.55,146.5 R7505.1
  BOTTOM w0.356: v2(174.04,146.37) 174.44,146.77 GPU1.D22
FB_CAL_PU_GND: length 1.3
  TOP w0.508: v2(175.65,148.86) 175.65,148.63 R7507.2
  BOTTOM w0.356: v2(175.65,148.86) 175.26,148.47 GPU1.C24
FB_CAL_TERM_GND: length 5.4
  TOP w0.356: R7506.1 179.03,151.84 v1(179.51,152.32)
  TOP w0.508: R7506.1 178.39,151.02 v2(178.5,150.9)
  BOTTOM w0.152: v2(178.5,150.9) 178.25,150.9 177.01,149.66 176.44,149.66 GPU1.B25
FB_CLAM: length 5.1
  TOP w0.254: R7519.1 172.19,129.17 v1(171.99,128.97) 171.71,128.97 171.25,129.42 R7518.1 171.76,130.39 171.76,130.89 v2(172.35,131.48)
  BOTTOM w0.254: v2(172.35,131.48) 172.39,131.43 172.39,131.43 GPU1.F3
FB_VREF: length 4
  TOP w0.102: v2(174.03,147.2) 174.03,147.15 173.62,146.74 173.62,146.18 173.41,145.98 173.11,145.98 172.85,145.72 172.85,145.06 172.55,144.76 TP7503.1
  BOTTOM w0.102: v2(174.03,147.2) 174.45,147.62 GPU1.D23
FBA_CLK0N: length 71.4
  TOP w0.152: VRAM6.K7 189.4,152.51 189.32,152.43 189.32,152.25 189.54,152.03 189.54,151.63 189.32,151.41 189.32,151.2 189.41,151.11 189.41,150.93 189.29,150.8 189.06,150.8 v2(188.95,150.9) ; VRAM5.K7 189.41,138.52 189.23,138.34 189.23,137.8 188.71,137.28 188.71,137 v2(188.8,136.92) ; v2(188.79,144.62) 188.81,144.6 R7810.1
  L3 w0.127: v2(174.85,148.86) 174.85,148.85 175.09,148.62 175.28,148.62 175.61,148.29 175.61,147.73 175.24,147.36 175.24,146.92 177.53,144.63 180.73,144.63 182.27,143.1 184.76,143.1 185.02,142.84 185.02,141.6 185.18,141.44 185.4,141.44 185.55,141.6 185.55,142.84 185.81,143.1 186.28,143.1 186.54,142.84 186.54,141.63 186.7,141.47 186.92,141.47 187.08,141.63 187.08,142.34 187.38,142.64 188.37,142.64 188.58,142.85 188.58,143.37 188.33,143.63 183,143.63 182.74,143.89 182.74,144.62 183,144.88 183.89,144.88 184.1,145.1 184.1,146.35 184.37,146.61 184.83,146.61 185.1,146.35 185.1,144.93 185.22,144.8 185.5,144.8 185.63,144.93 185.63,146.32 185.89,146.58 186.36,146.58 186.62,146.32 186.62,144.92 186.75,144.79 187.24,144.79 187.37,144.92 187.37,145.82 187.6,146.05 188.33,146.05 188.79,145.59 v2(188.79,144.62)
  L4 w0.127: v2(188.95,150.9) 188.75,150.9 188.59,150.74 188.59,150.6 189.63,149.55 189.63,149.46 189.85,149.23 189.85,147.84 189.33,147.32 189.33,145.66 188.55,144.88 188.55,144.75 188.69,144.62 v2(188.79,144.62) 188.62,144.44 188.62,143.98 188.75,143.85 188.75,138.33 188.49,138.07 188.49,137.22 v2(188.8,136.92)
  BOTTOM w0.152: v1(189.35,144.8) 188.97,144.8 v2(188.79,144.62) ; v2(174.85,148.86) 174.45,149.26 GPU1.D25 ; v2(188.8,136.92) 188.75,136.87 188.75,136.5 188.87,136.38 188.96,136.38 189.23,136.1 189.23,135.65 189.57,135.32 VRAM1.K7 ; v2(188.95,150.9) 188.65,150.6 188.65,150.3 188.74,150.22 188.95,150.22 189.22,149.95 189.22,149.46 189.33,149.34 189.57,149.34 VRAM2.K7
FBA_CLK0P: length 71.1
  TOP w0.152: VRAM5.J7 188.97,138.35 188.97,137.91 188.44,137.39 188.44,137.18 v2(188.16,136.89) ; R7810.2 187.92,144.37 v2(188.16,144.6) ; VRAM6.J7 188.96,152.51 189.05,152.41 189.05,152.14 189.27,151.92 189.27,151.74 189.05,151.52 189.05,151.43 188.96,151.34 188.83,151.34 188.73,151.44 188.52,151.44 188.39,151.3 v2(188.39,151.19)
  L3 w0.127: v2(174.85,148.04) 174.85,148.29 174.95,148.39 175.19,148.39 175.38,148.19 175.38,147.82 175.01,147.45 175.01,146.83 177.43,144.41 180.64,144.41 182.17,142.87 184.66,142.87 184.79,142.74 184.79,141.5 185.08,141.21 185.49,141.21 185.78,141.5 185.78,142.74 185.91,142.87 186.19,142.87 186.32,142.74 186.32,141.53 186.61,141.24 187.02,141.24 187.31,141.53 187.31,142.25 187.47,142.41 188.47,142.41 188.81,142.75 188.81,143.47 188.42,143.86 183.1,143.86 182.97,143.99 182.97,144.53 183.1,144.66 183.99,144.66 184.33,145 184.33,146.26 184.46,146.38 184.74,146.38 184.87,146.26 184.87,144.84 185.13,144.58 185.6,144.58 185.86,144.84 185.86,146.23 185.98,146.36 186.26,146.36 186.39,146.23 186.39,144.83 186.65,144.57 187.33,144.57 187.59,144.83 187.59,145.72 187.7,145.82 188.24,145.82 188.56,145.49 188.56,145.01 v2(188.16,144.6)
  L4 w0.127: v2(188.39,151.19) 188.36,151.16 188.36,150.5 189.4,149.46 189.4,149.36 189.62,149.14 189.62,147.93 189.1,147.42 189.1,145.75 188.32,144.97 188.32,144.77 v2(188.16,144.6) 188.39,144.37 188.39,143.88 188.52,143.75 188.52,138.42 188.27,138.17 188.27,137 v2(188.16,136.89)
  BOTTOM w0.152: VRAM2.J7 188.95,149.46 188.95,149.84 188.84,149.95 188.63,149.95 188.39,150.19 v2(188.39,151.19) ; VRAM1.J7 188.97,135.49 188.97,135.99 188.85,136.11 188.76,136.11 188.48,136.39 188.48,136.57 v2(188.16,136.89) ; v1(187.52,144.93) 187.84,144.6 v2(188.16,144.6) ; v2(174.85,148.04) 174.45,148.44 GPU1.D24
FBA_CLK1N: length 76.8
  TOP w0.152: v2(159.17,163.04) 159.11,163.09 158.08,163.09 VRAM8.K7 ; R7914.1 166.25,163.53 v1(166.18,163.6) 165.83,163.6 165.64,163.41 165.64,162.94 v2(165.52,162.82) ; v2(173.53,162.89) 173.5,162.93 172.9,162.93 172.77,162.8 172.3,162.8 171.6,163.5 VRAM7.K7
  L3 w0.127: v2(167.38,146.41) 167.19,146.41 167.08,146.53 167.08,146.85 165.05,148.87 163.76,148.87 163.55,149.07 163.55,150.4 163.76,150.6 165.18,150.6 165.47,150.89 165.47,151.3 165.18,151.59 162.55,151.59 162.38,151.76 162.38,152.01 162.55,152.18 163.43,152.18 163.69,152.44 163.69,152.91 163.43,153.17 162.6,153.17 162.47,153.29 162.47,153.57 162.6,153.7 164.91,153.7 165.17,153.96 165.17,154.43 164.91,154.69 163.26,154.69 163.13,154.82 163.13,155.1 163.26,155.23 165.08,155.23 165.37,155.52 165.37,155.93 165.08,156.22 163.29,156.22 163.13,156.37 163.13,156.59 163.29,156.75 164.65,156.75 164.91,157.01 164.91,157.48 164.65,157.74 163.66,157.74 163.53,157.87 163.53,158.15 163.66,158.27 164.9,158.27 165.16,158.54 165.16,159 164.9,159.27 163.66,159.27 163.53,159.39 163.53,159.67 163.66,159.8 166.15,159.8 166.41,160.06 166.41,160.53 166.15,160.79 163.61,160.79 163.49,160.92 163.49,161.21 163.61,161.34 166.44,161.34 166.7,161.6 166.7,162.53 166.44,162.79 165.55,162.79 v2(165.52,162.82)
  L4 w0.127: v2(159.17,163.04) 159.47,162.73 159.95,162.73 160.38,163.17 160.38,163.64 160.68,163.94 163.02,163.94 163.32,163.64 163.32,162.47 163.49,162.31 164.3,162.31 164.61,162.61 165.32,162.61 v2(165.52,162.82) 165.54,162.84 167.75,162.84 167.92,163 169.96,163 170.37,162.6 172.55,162.6 172.9,162.95 173.47,162.95 v2(173.53,162.89)
  BOTTOM w0.152: v2(159.17,163.04) 160.27,163.04 VRAM4.K7 ; VRAM3.K7 174.33,163.1 174.33,162.52 174.18,162.37 174.05,162.37 v2(173.53,162.89) ; v2(167.38,146.41) 167.79,146.82 GPU1.M22
FBA_CLK1P: length 76.5
  TOP w0.152: v2(173.06,162.46) 173.06,162.2 172.94,162.08 172.66,162.08 172.54,162.19 172.54,162.46 172.48,162.53 172.19,162.53 171.84,162.88 171.71,162.88 VRAM7.J7 ; R7914.2 165.85,161.4 v1(165.32,161.4) 165.32,161.95 v2(165.55,162.18) ; VRAM8.J7 157.66,162.83 158.64,162.83 v2(159.16,162.31)
  L3 w0.127: v2(165.55,162.18) 165.59,162.15 165.8,162.15 165.92,162.27 165.92,162.46 166.02,162.56 166.35,162.56 166.47,162.43 166.47,161.7 166.35,161.57 163.52,161.57 163.26,161.31 163.26,160.82 163.52,160.56 166.06,160.56 166.18,160.43 166.18,160.15 166.06,160.03 163.56,160.03 163.3,159.77 163.3,159.3 163.56,159.04 164.8,159.04 164.93,158.91 164.93,158.63 164.8,158.5 163.56,158.5 163.3,158.24 163.3,157.77 163.56,157.51 164.56,157.51 164.68,157.39 164.68,157.11 164.56,156.98 163.19,156.98 162.9,156.69 162.9,156.28 163.19,155.99 164.98,155.99 165.14,155.83 165.14,155.61 164.98,155.45 163.17,155.45 162.9,155.19 162.9,154.72 163.17,154.46 164.81,154.46 164.94,154.34 164.94,154.06 164.81,153.93 162.51,153.93 162.24,153.67 162.24,153.2 162.51,152.94 163.34,152.94 163.46,152.81 163.46,152.53 163.34,152.41 162.45,152.41 162.15,152.1 162.15,151.67 162.45,151.36 165.09,151.36 165.24,151.21 165.24,150.99 165.09,150.83 163.66,150.83 163.33,150.49 163.33,148.98 163.66,148.64 164.96,148.64 166.85,146.75 166.85,146.53 166.73,146.41 v2(166.59,146.41)
  L4 w0.127: v2(159.16,162.31) 159.36,162.51 160.06,162.51 160.61,163.05 160.61,163.54 160.78,163.71 162.9,163.71 163.09,163.52 163.09,162.37 163.39,162.08 164.4,162.08 164.71,162.38 165.35,162.38 v2(165.55,162.18) 165.77,161.96 165.91,161.96 166.04,162.09 166.04,162.53 166.12,162.61 167.85,162.61 168.01,162.78 169.87,162.78 170.27,162.37 172.65,162.37 172.73,162.46 v2(173.06,162.46)
  BOTTOM w0.152: v2(173.06,162.46) 173.35,162.46 173.35,162.46 173.59,162.46 173.94,162.1 174.3,162.1 174.6,162.41 174.6,162.69 174.68,162.77 VRAM3.J7 ; VRAM4.J7 159.62,162.77 v2(159.16,162.31) ; v2(166.59,146.41) 166.53,146.47 166.53,146.68 166.68,146.83 GPU1.N22
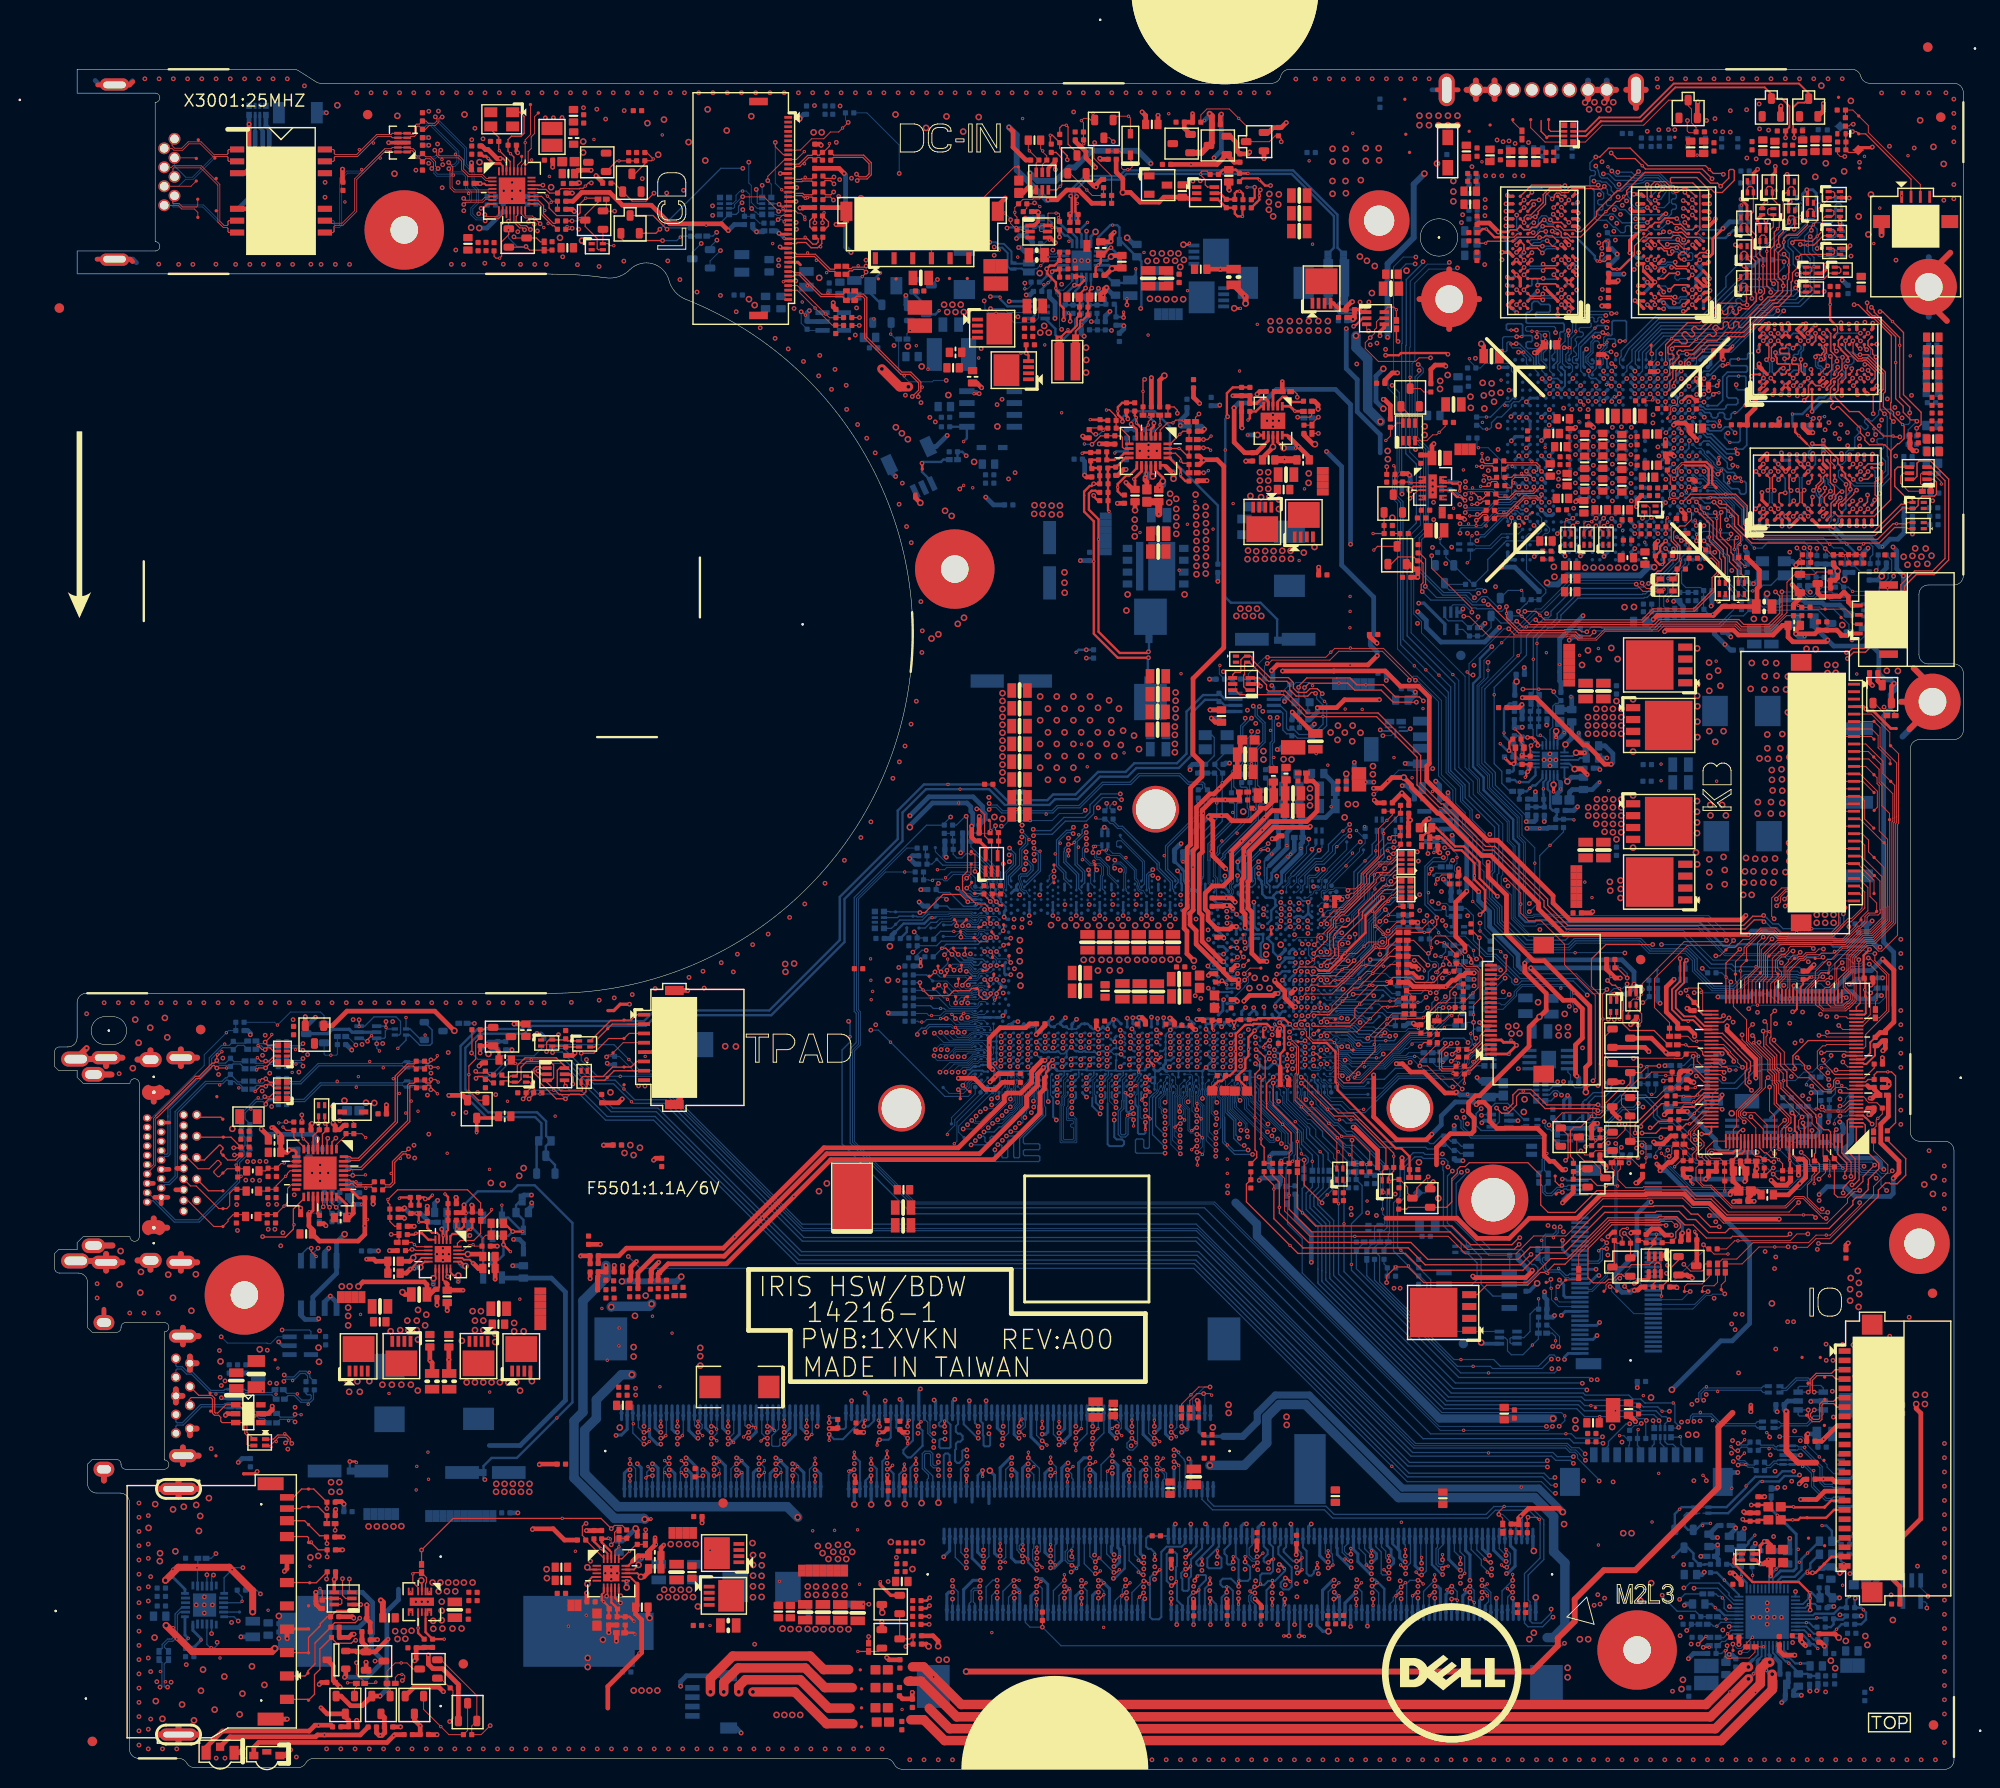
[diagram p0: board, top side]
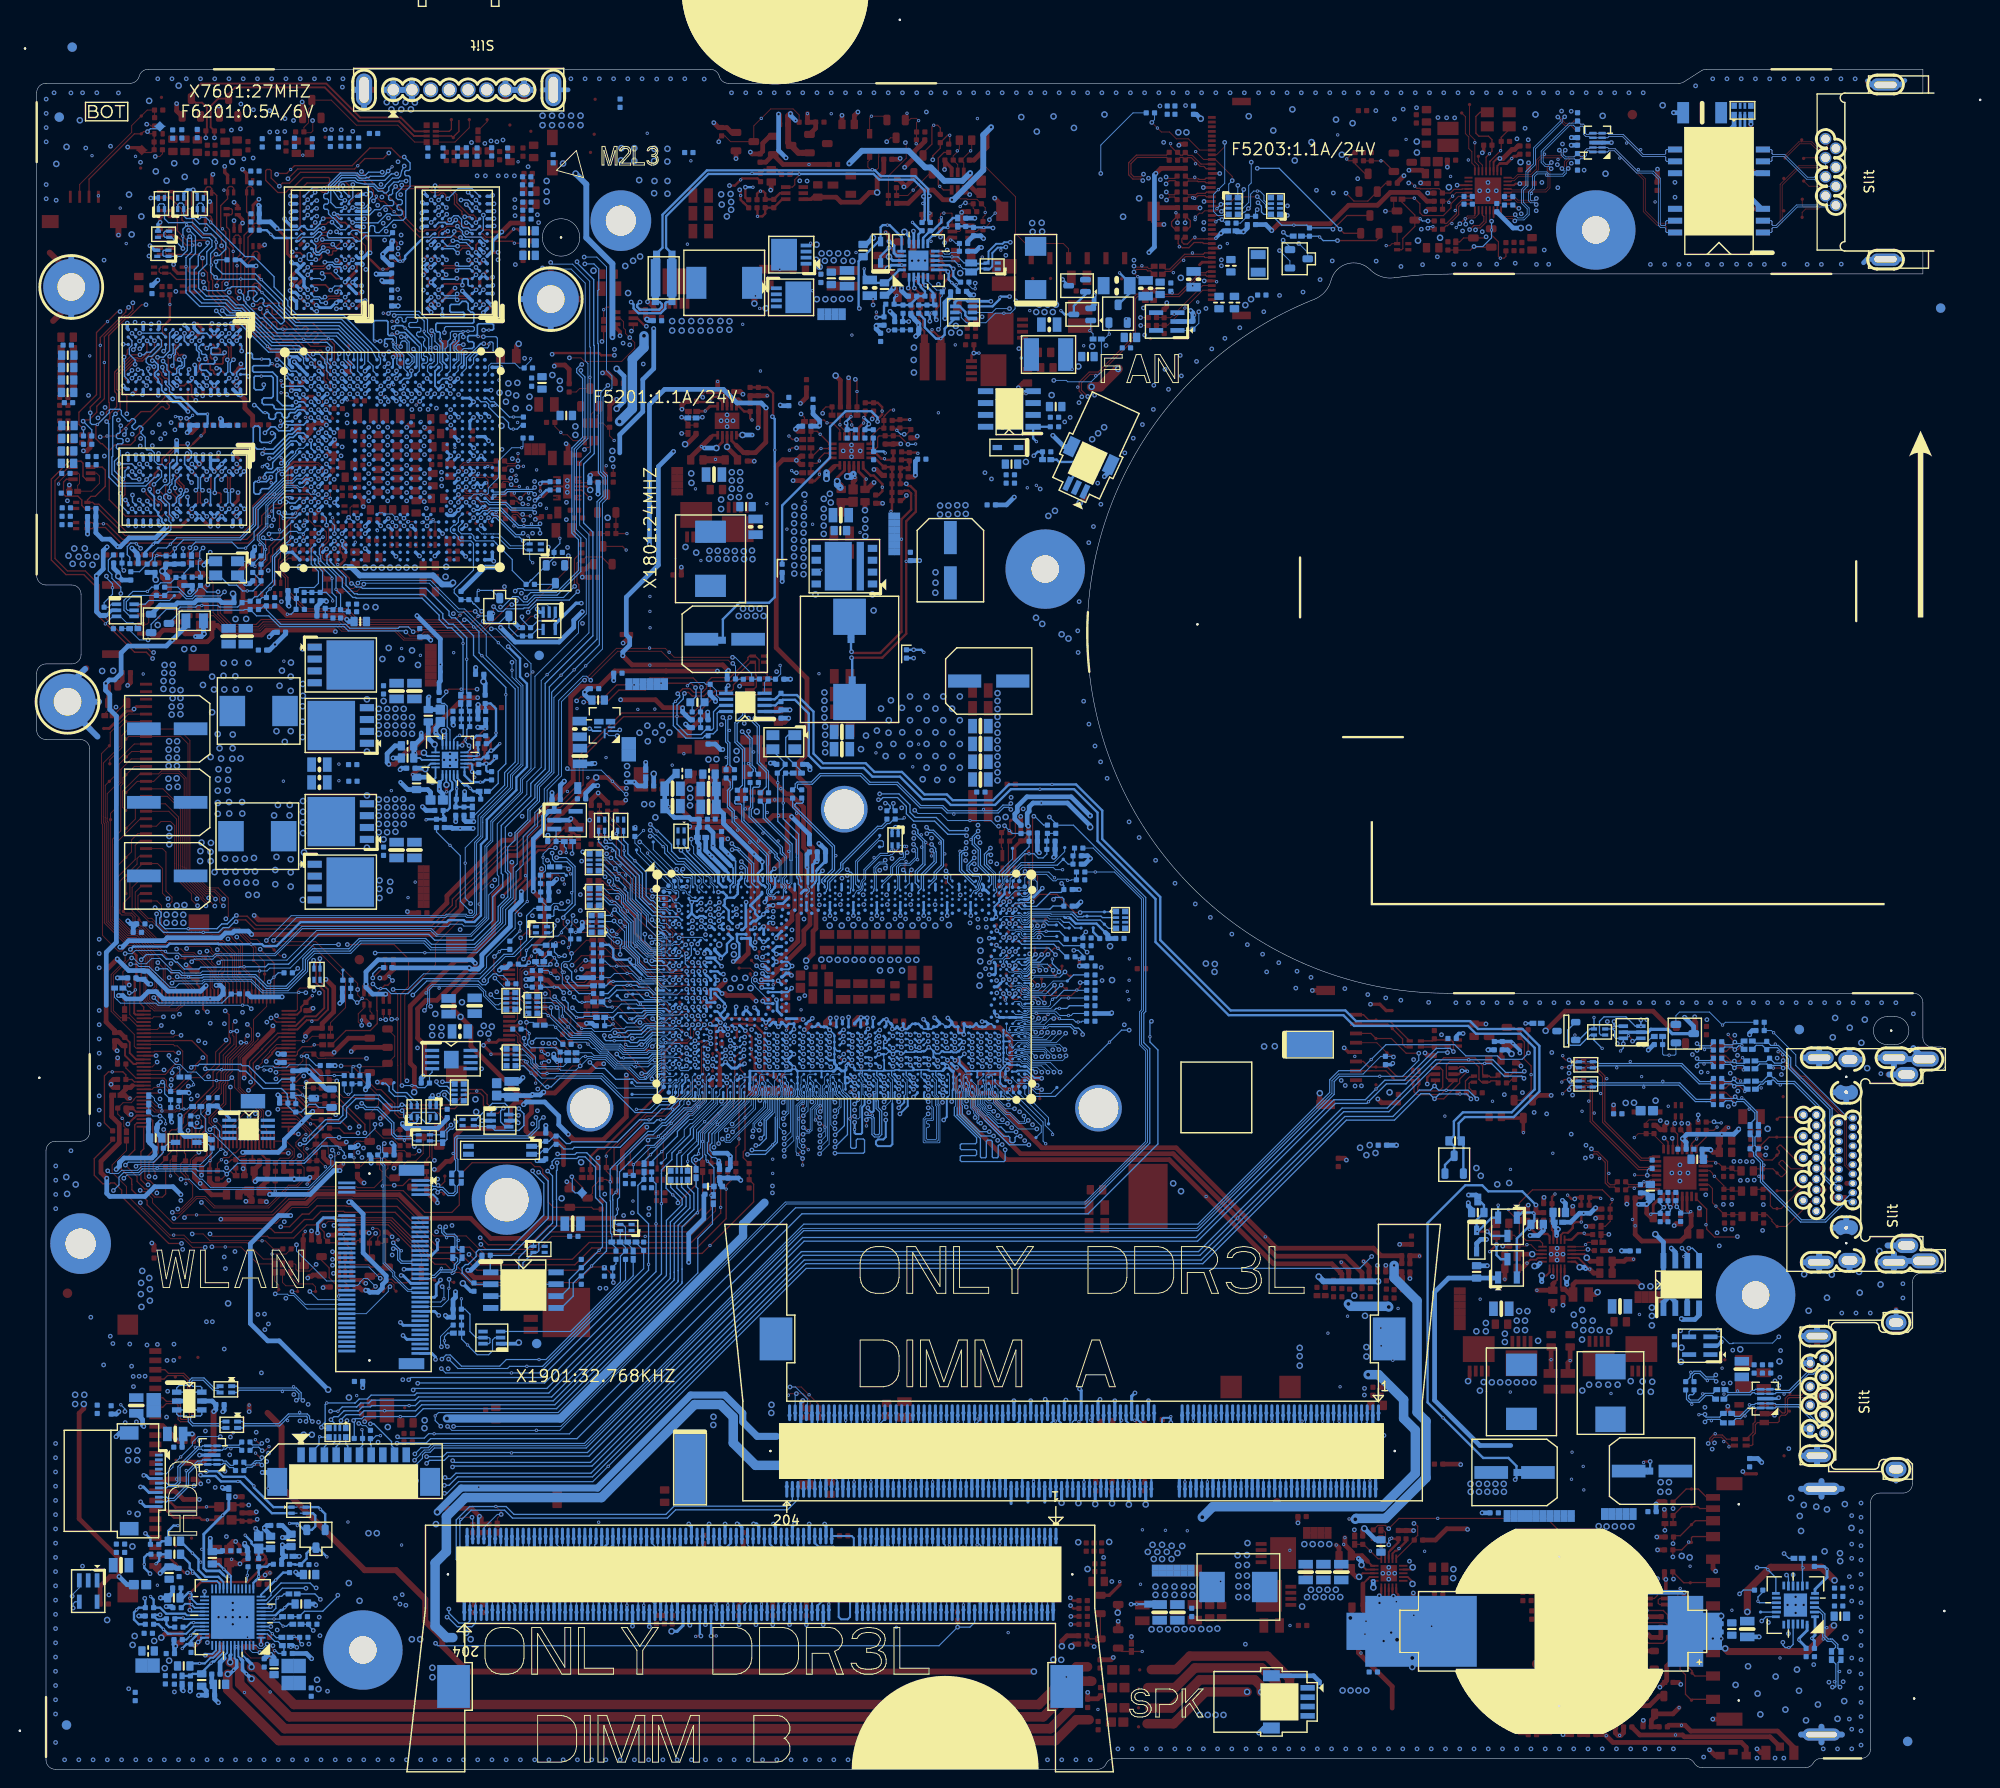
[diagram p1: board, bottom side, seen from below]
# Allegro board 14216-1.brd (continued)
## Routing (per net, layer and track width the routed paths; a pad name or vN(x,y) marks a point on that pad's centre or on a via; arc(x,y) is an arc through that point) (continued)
FBA_CMD0: length 94.7
  TOP w0.14: v2(191.27,151.14) 191.22,151.09 191.22,149.85 190.83,149.45 190.83,149.22 190.49,148.89 190.27,148.89 190.01,148.63 190.01,148.32 189.6,147.92 VRAM6.K1 ; v2(191.23,136.76) 190.98,136.76 190.49,136.27 190.49,135.97 190.05,135.53 190.05,134.17 VRAM5.K1 ; v2(193.91,156.97) 193.91,156.17 194.5,155.58 194.72,155.58 196.96,153.35 v1(196.96,150.59) 196.96,146.71 197.77,145.9 197.77,145.26 198.59,144.44 199.09,144.44 v2(199.23,144.3)
  L4 w0.127: v2(184.35,156.14) 185.4,157.19 192.24,157.19 192.32,157.27 193.01,157.27 193.25,157.02 193.86,157.02 v2(193.91,156.97) ; v2(191.23,136.76) 191.49,136.49 193,136.49 193.62,137.11 195.24,137.11 195.39,137.26 195.68,137.26 196.36,136.58 196.54,136.58 196.72,136.76 196.72,136.94 195.98,137.68 195.98,137.86 196.16,138.04 196.34,138.04 197.08,137.3 197.26,137.3 197.44,137.48 197.44,137.66 196.7,138.39 196.7,138.57 196.88,138.75 197.06,138.75 197.79,138.03 197.97,138.03 198.15,138.21 198.15,138.39 197.42,139.11 197.42,139.29 197.86,139.73 197.86,142.93 v2(199.23,144.3) 199.77,144.84 199.77,151.28 197.04,154.01 194.92,154.01 194.78,154.14 192.85,154.14 192.17,153.46 191.53,153.46 191.15,153.08 191.15,152.27 191.27,152.15 191.27,151.14 v2(191.27,151.14)
  BOTTOM w0.14: v2(199.23,144.3) 198.3,143.37 R7512.1 ; GPU1.C27 175.39,151.01 175.39,151.3 176.12,152.02 179.19,152.02 182.81,155.64 183.86,155.64 v2(184.35,156.14) ; VRAM2.K1 189.97,153.74 189.97,151.85 190.4,151.42 190.4,151.39 190.62,151.16 191.25,151.16 v2(191.27,151.14) ; v2(191.23,136.76) 190.49,137.49 190.21,137.49 189.97,137.73 189.97,139.75 VRAM1.K1
FBA_CMD1: length 75.2
  TOP w0.14: 196.44,141.14 197.2,141.9 197.33,141.9 197.86,142.43 197.86,143.79 v1(197.7,143.95) 196.74,144.91 196.74,145.27 196.43,145.59 196.43,146.26 196.49,146.33 196.49,153.47 194.62,155.34 194.4,155.34 192.97,156.77 v2(192.51,156.77) ; 196.44,141.14 195.8,141.77 194.15,141.77 193.66,142.26 193.66,142.56 193.19,143.03 193.19,143.52 190.86,145.85 190.66,145.85 190.4,145.59 190.21,145.59 190.01,145.78 190.01,145.98 190.27,146.24 190.27,146.44 189.98,146.73 189.98,147.79 190.4,148.21 VRAM6.L2 ; 196.44,141.14 196.44,135.9 194.68,134.14 190.78,134.14 VRAM5.L2
  L4 w0.127: v2(192.51,156.77) 192.46,156.82 192.02,156.82 191.89,156.69 191.89,156.47 191.77,156.34 191.49,156.34 191.36,156.47 191.36,156.69 191.23,156.82 190.96,156.82 190.83,156.69 190.83,155.93 190.7,155.81 185.85,155.81 185.72,155.93 185.72,156.19 185.85,156.31 190.2,156.31 190.32,156.44 190.32,156.69 190.2,156.82 185.7,156.82 v2(184.98,156.11)
  BOTTOM w0.14: v2(184.98,156.11) 184.23,155.36 183.06,155.36 179.39,151.69 176.26,151.69 175.65,151.08 175.65,150.47 GPU1.C26
FBA_CMD2: length 75.4
  TOP w0.14: v2(198.47,145.2) 198.47,145.81 197.39,146.89 v1(197.39,152.42) 197.39,153.25 194.67,155.98 194.67,156.19 v2(194.37,156.49)
  L4 w0.127: v2(193.19,153.72) 193.95,152.96 195.27,152.96 198.05,150.18 198.05,145.62 v2(198.47,145.2) ; v2(174.03,148.86) 174.03,149.06 174.78,149.81 175.56,149.81 175.68,149.94 175.68,150.8 175.81,150.93 176.07,150.93 176.19,150.8 176.19,149.94 176.32,149.81 177.85,149.81 178.01,149.98 178.01,150.51 177.88,150.64 177.71,150.64 177.58,150.76 177.58,151.2 177.71,151.32 178.88,151.32 179.17,151.03 179.35,151.03 179.53,151.21 179.53,151.39 179.24,151.68 179.24,151.86 179.41,152.04 179.59,152.04 179.88,151.75 180.06,151.75 180.24,151.93 180.24,152.11 179.95,152.4 179.95,152.58 180.13,152.76 180.31,152.76 180.6,152.47 180.78,152.47 180.96,152.65 180.96,152.83 180.67,153.12 180.67,153.3 182.94,155.57 191.04,155.57 191.18,155.71 191.18,155.91 191.32,156.04 192.85,156.04 192.98,156.17 192.98,156.47 193.11,156.59 193.36,156.59 193.49,156.47 193.49,156.17 193.62,156.04 194.26,156.04 194.37,156.14 v2(194.37,156.49)
  BOTTOM w0.14: VRAM2.L2 190.81,153.72 v2(193.19,153.72) ; v2(198.47,145.2) 198.47,144.12 198.29,143.95 197.7,143.95 196.43,145.21 196.43,145.47 196.33,145.58 195.3,145.58 195.14,145.42 195.14,145 194.47,144.33 194.27,144.33 194.03,144.57 193.83,144.57 193.63,144.38 193.63,144.18 194,143.81 194,143.63 193.79,143.41 193.61,143.41 193.24,143.78 193.04,143.78 192.84,143.59 192.84,143.39 193.04,143.19 193.04,143.03 192.59,142.57 192.59,141.42 192.4,141.23 191.92,141.23 191.61,140.91 191.61,140.04 191.25,139.68 190.76,139.68 VRAM1.L2 ; GPU1.E24 173.64,148.47 v2(174.03,148.86)
FBA_CMD3: length 103.2
  TOP w0.14: VRAM5.K9 189.6,140.03 189.97,139.66 189.97,137.74 190.41,137.3 190.41,136.56 v2(190,136.14) ; v2(195.28,156.03) 195.55,156.03 v1(196.62,154.97) 197.8,153.79 197.8,147.14 199.68,145.26 199.68,143.95 199.28,143.55 v2(199.2,143.55) ; VRAM6.K9 190.03,153.68 190.03,151.78 190.68,151.14 v2(190.68,150.73)
  L4 w0.102: v2(172.35,148.05) 172.39,148.05 172.79,148.46 174.2,148.46 174.45,148.7 174.45,149.03 174.67,149.25
  L4 w0.127: v2(190,136.14) 190,134.58 190.12,134.46 190.54,134.46 190.66,134.58 190.66,135.54 190.79,135.66 191.04,135.66 191.17,135.54 191.17,134.58 191.3,134.46 194.62,134.46 196.1,135.94 196.43,135.94 198.69,138.2 198.69,138.92 198.57,139.04 198.34,139.04 198.21,139.17 198.21,139.42 198.34,139.55 198.57,139.55 198.69,139.68 198.69,139.93 198.57,140.06 198.34,140.06 198.21,140.19 198.21,140.44 198.34,140.57 198.57,140.57 198.69,140.69 198.69,140.95 198.57,141.07 198.34,141.07 198.21,141.2 198.21,141.46 198.34,141.58 198.57,141.58 198.69,141.71 198.69,141.96 198.57,142.09 198.34,142.09 198.21,142.22 198.21,142.47 198.34,142.6 198.57,142.6 198.69,142.73 198.69,143.04 v2(199.2,143.55) 199.28,143.55 200.16,144.43 200.16,151.4 197.2,154.37 192.5,154.37 192.01,153.89 191.48,153.89 190.78,153.19 190.78,152.24 191.05,151.97 191.05,151.5 190.68,151.14 v2(190.68,150.73) ; 174.67,149.25 174.86,149.44 178.26,149.44 181.57,152.74 181.57,153.84 183.07,155.34 191.14,155.34 191.61,155.81 195.06,155.81 v2(195.28,156.03)
  BOTTOM w0.14: v2(199.2,143.55) 199.19,143.54 R7510.1 ; VRAM2.K9 189.6,147.84 190.04,148.28 190.04,149.58 190.26,149.8 190.26,150.31 190.26,150.31 v2(190.68,150.73) ; v2(190,136.14) 190,136.23 190.27,136.5 190.45,136.5 190.61,136.33 190.61,136.04 189.99,135.42 189.99,134.34 189.6,133.95 VRAM1.K9 ; GPU1.F24 172.35,148.07 v2(172.35,148.05)
FBA_CMD4: length 121.8
  TOP w0.14: v2(193.86,151.96) 193.6,152.21 VRAM6.R7 ; VRAM5.R7 v2(194,138.92) ; VRAM7.R7 171.6,167.57 171.23,167.94 171.23,167.95 v2(171.23,167.95) ; VRAM8.R7 158.01,167.98 v2(158.8,167.98)
  L3 w0.127: v2(165.69,170.78) 165.69,170.85 166.72,171.88 179.13,171.88 180,171.66 186.75,164.91 v2(187.82,164.06) 187.86,164.03 188.45,164.03 192.11,160.37 192.31,160.37 195.01,157.67 196.04,157.67 197.42,156.28 197.42,156.05 197.3,155.93 196.84,155.93 196.71,155.8 196.71,155.55 196.84,155.42 197.3,155.42 197.42,155.29 197.42,145.26 197.3,145.14 v2(197.21,145.14)
  L4 w0.127: v2(194,138.92) 194,139.38 195.3,140.68 195.3,140.94 195.19,141.05 195.19,141.27 195.4,141.48 195.62,141.48 195.76,141.34 195.94,141.34 196.12,141.52 196.12,141.7 195.93,141.89 195.93,142.03 196.25,142.35 196.25,143.1 197.17,144.03 197.17,144.41 196.76,144.81 196.76,145.05 196.85,145.14 v2(197.21,145.14) 197.37,145.3 197.37,146.27 197.29,146.36 197.29,149.96 195.21,152.04 193.94,152.04 v2(193.86,151.96) ; v2(165.69,170.78) 164.96,170.46 163.62,170.46 163.35,170.19 161.24,170.19 159.03,167.98 v2(158.8,167.98)
  BOTTOM w0.14: v2(158.8,167.98) 158.01,167.98 VRAM8.R7 ; v2(193.86,151.96) 193.86,151.99 193.6,152.25 VRAM6.R7 ; v2(165.69,170.78) 166.26,170.78 166.96,170.08 169.81,170.08 170.09,170.36 171.54,170.36 172.49,169.41 172.49,169.01 171.84,168.05 v2(171.23,167.95) 171.6,167.58 VRAM7.R7 ; VRAM5.R7 v2(194,138.92) ; RN7510.2 190.59,162.6 190.69,162.49 190.69,162.07 190.58,161.95 RN7510.1 188.72,161.95 188.08,162.58 188.08,163.8 v2(187.82,164.06) 187.62,163.86 187.62,162.43 188.22,161.83 188.22,161.82 188.22,161.82 v1(188.22,160.86) 188.22,158.31 188.22,158.31 188.22,158.25 188.22,158.04 186.77,156.58 184.2,156.58 183.52,155.91 182.59,155.91 179.08,152.39 176.12,152.39 174.6,150.87 GPU1.D27
FBA_CMD5: length 106.6
  TOP w0.14: RN7519.1 190.91,160.8 191.09,160.61 191.09,160.3 190.93,160.15 RN7519.2 189.9,160.15 189.23,159.48 186.64,159.48 v2(186.35,159.19) ; v2(175.21,168.01) 175.21,167.96 VRAM7.R2 ; v2(161.99,167.97) 161.6,167.58 161.6,167.57 VRAM8.R2 ; v2(193.19,148.91) 193.59,148.51 VRAM6.R2 ; v2(194,134.92) VRAM5.R2
  L3 w0.127: v2(161.99,167.97) 161.99,168.56 162.37,168.93 162.37,168.94 162.61,169.19 163.01,169.19 164.4,167.79 167.52,167.79 167.6,167.88 v2(168.17,167.88) 168.25,167.95 169.5,167.95 169.74,167.71 169.74,167.22 170.24,166.72 171.52,166.72 172.16,167.37 173.87,167.37 174,167.5 174.7,167.5 174.79,167.59 175.37,167.59 176.09,166.87 176.09,166.29 177.07,165.3 177.46,165.3 178.49,164.27 179.45,164.27 182.83,160.9 184.18,160.9 184.56,160.52 185.37,160.52 185.96,159.92 185.96,159.83 186.35,159.43 v2(186.35,159.19) 186.79,158.76 186.79,158.42 188.55,156.66 188.55,156.42 190.93,154.04 192.09,154.04 192.22,153.91 192.22,153.56 192.09,153.43 191.3,153.43 191.15,153.28 191.15,152.76 193.09,150.82 193.88,150.82 194.42,150.27 194.42,148.63 193.99,148.19 193.99,147.87 193.51,147.39 193.51,147.02 193.68,146.85 193.68,144.2 194.4,143.48 194.4,142.37 v2(194.48,142.28) 195.85,140.91 195.85,138.28 194.45,136.88 194.45,136.21 194.29,136.05 194.29,135.7 194.3,135.69 194.3,135.22 v2(194,134.92)
  L4 w0.127: v2(193.19,148.91) 194.58,147.53 194.58,146.8 193.36,145.58 193.36,142.86 193.94,142.28 v2(194.48,142.28) ; v2(168.17,167.88) 168.47,168.18 169.13,168.18 169.41,168.45 170.76,168.45 170.91,168.6 171.5,168.6 171.75,168.35 174.44,168.35 174.79,168.01 v2(175.21,168.01) ; v2(174.82,150.47) 175.99,151.64 178.6,151.64 185.54,158.58 185.54,158.88 185.85,159.19 v2(186.35,159.19)
  BOTTOM w0.14: v2(174.82,150.47) 174.45,150.1 GPU1.D26 ; v2(175.21,168.01) 175.21,167.96 VRAM7.R2 ; v1(167.85,168.38) 167.85,168.2 v2(168.17,167.88) ; v2(161.99,167.97) 161.99,167.96 VRAM8.R2 ; VRAM6.R2 193.59,148.51 v2(193.19,148.91) ; VRAM5.R2 v2(194,134.92)
FBA_CMD6: length 126
  TOP w0.14: v2(165.14,169.57) 165.05,169.49 162.19,169.49 161.74,169.04 161.31,169.04 161.11,169.24 159.93,169.24 159.25,168.55 159.25,167.69 157.93,166.37 157.47,166.37 157.21,166.11 v2(157.21,165.55) 156.8,165.96 VRAM8.N8 ; v2(185.02,162.17) 185.02,162.15 185.52,161.66 v1(185.52,161.02) 185.52,159.51 185.38,159.37 185.38,158.98 185.38,158.04 184.27,156.93 183.82,156.93 180.69,153.8 178.73,153.8 177.84,152.91 176.81,152.91 175.38,151.49 v2(174.62,151.49) ; VRAM6.N8 191.6,152.91 v2(191.59,152.91) 191.59,152.03 192.87,150.75 193.43,150.75 193.52,150.84 193.86,150.84 195.38,149.32 195.38,147.8 194.56,146.98 v2(194.56,145.1) ; VRAM5.N8 v2(192.4,139.72) ; VRAM7.N8 170.41,165.58 170.41,165.58 v2(170.4,165.57)
  L3 w0.127: v2(194.56,145.1) 195.04,145.58 195.04,146.96 195.6,147.52 195.6,153.03 194.23,154.41 193.55,154.41 193.25,154.71 193.25,154.93 192.91,155.27 192.52,155.27 192.38,155.41 191.72,155.41 191.18,155.95 190.46,155.95 189.75,156.65 189.75,157.05 188.69,158.11 188.69,158.29 188.9,158.49 188.9,158.67 188.72,158.85 188.54,158.85 188.33,158.64 188.15,158.64 187.89,158.91 187.89,159.68 185.4,162.17 v2(185.02,162.17) 183.15,162.17 179.16,166.16 179.16,166.81 177.45,168.52 177.45,168.6 177.2,168.85 176.48,168.85 175.67,169.65 173.16,169.65 172.21,168.7 171.86,168.7 171.7,168.86 170.12,168.86 169.5,169.47 167.89,169.47 167.64,169.23 166.66,169.23 166.42,168.99 165.66,168.99 165.14,169.5 v2(165.14,169.57)
  L4 w0.127: v2(194.56,145.1) 194.56,143.81 195.29,143.08 195.29,142.73 195.09,142.53 195.09,142.28 194.63,141.82 194.48,141.82 193.83,141.18 192.66,141.18 192.5,141.01 192.5,140.49 191.8,139.79 191.8,139.26 191.93,139.13 192.27,139.13 192.4,139.26 v2(192.4,139.72)
  BOTTOM w0.14: RN7506.1 189.11,167.47 188.94,167.65 188.64,167.65 188.46,167.47 RN7506.2 188.46,166.28 188.18,166 187.82,166 187.36,166 186.79,165.43 186.02,165.43 183.97,163.38 183.97,162.71 184.65,162.03 184.88,162.03 v2(185.02,162.17) ; VRAM6.N8 191.6,152.91 v2(191.59,152.91) ; v2(174.62,151.49) 173.96,151.49 173.38,150.9 173.38,150.52 173.2,150.34 173.2,149.74 172.75,149.29 GPU1.F25 ; VRAM8.N8 156.8,165.96 v2(157.21,165.55) ; v2(192.4,139.72) VRAM5.N8 ; v2(165.14,169.57) 165.14,169.28 165.72,168.7 165.72,168.2 165.55,168.03 165.22,168.03 165.08,167.89 165.08,167.61 165.22,167.47 165.51,167.47 165.64,167.34 165.64,167.04 165.51,166.91 165.22,166.91 165.08,166.77 165.08,166.49 165.22,166.35 166.23,166.35 166.37,166.5 166.72,166.5 167.69,165.53 169.35,165.53 169.38,165.57 v2(170.4,165.57) 170.41,165.58 170.41,165.58 VRAM7.N8
FBA_CMD7: length 125.8
  TOP w0.14: v2(165.8,169.44) 165.5,169.14 164.68,169.14 164.63,169.19 162.33,169.19 161.91,168.78 161.23,168.78 161.04,168.96 160,168.96 159.5,168.47 159.5,167.54 158.71,166.74 158.71,166.48 v2(158.4,166.18) 158.09,166.18 157.88,165.97 VRAM8.N7 ; VRAM6.N7 192.38,152.89 v2(192.38,152.91) 192.4,152.89 192.4,151.56 192.97,150.99 193.33,150.99 193.42,151.08 193.96,151.08 195.62,149.42 195.62,147.69 195.27,147.34 195.27,145.58 v2(195.76,145.09) ; VRAM7.N7 172.13,166.5 v2(172.37,166.5) ; v2(173.05,152.05) 173.32,152.32 174.87,152.32 v1(175.63,153.07) 177.91,155.35 181.06,155.35 183.3,157.6 183.73,157.6 184.37,158.24 184.37,159.17 183.99,159.55 183.99,162.56 184.37,162.95 184.37,163.04 v2(184.42,163.08) 184.44,163.1 184.44,164.08 184.94,164.58 184.94,168.46 185.23,168.75 RN7517.1 185.48,169.21 185.65,169.38 185.95,169.38 186.13,169.21 RN7517.2 ; VRAM5.N7 192.43,138.08 v2(192.43,138.06)
  L3 w0.127: v2(195.76,145.09) 195.76,146.15 195.65,146.27 195.65,146.88 196.06,147.3 196.06,153.3 195.32,154.04 195.32,154.96 194.72,155.56 193.74,155.56 193.29,156.01 192.14,156.01 191.5,156.65 191.5,157.36 186.6,162.26 186.43,162.26 185.61,163.08 v2(184.42,163.08) 184.3,162.97 183.51,162.97 183.32,163.16 183.32,163.34 183.65,163.68 183.65,163.86 183.43,164.08 183.25,164.08 182.83,163.67 182.66,163.67 182.44,163.88 182.44,164.05 182.81,164.42 182.81,164.6 182.63,164.78 182.45,164.78 182.09,164.42 181.91,164.42 181.28,165.04 181.28,165.8 180.48,166.6 180.48,166.8 178.86,168.43 178.54,168.43 177.48,169.49 176.69,169.49 175.86,170.33 170.01,170.33 169.84,170.15 167.28,170.15 166.76,169.63 165.98,169.63 v2(165.8,169.44)
  BOTTOM w0.14: v2(173.05,152.05) 173.05,151.62 173.11,151.55 173.11,150.62 172.75,150.26 GPU1.F26 ; v2(165.8,169.44) 165.8,169.4 166.13,169.07 166.13,168.68 166.28,168.53 166.42,168.53 166.55,168.4 166.55,168.07 166.42,167.94 166.14,167.94 166.02,167.82 166.02,167.5 166.14,167.37 167.03,167.37 167.46,166.94 168.02,166.94 168.57,166.39 171.84,166.39 171.95,166.5 v2(172.37,166.5) 171.84,165.97 VRAM7.N7 ; v2(195.76,145.09) 196.06,144.79 196.06,140.55 196.15,140.46 196.15,138.63 195.18,137.66 192.84,137.66 v2(192.43,138.06) 192.43,138.08 VRAM5.N7 ; v2(158.4,166.18) 157.81,166.18 VRAM8.N7 ; VRAM6.N7 192.38,152.89 v2(192.38,152.91)
FBA_CMD8: length 129.6
  TOP w0.14: v2(195.25,136.57) 195.25,137.51 195.52,137.77 195.52,138.97 195.17,139.32 VRAM5.T8 ; v2(173.47,169.23) 173.21,169.5 172.79,169.5 172.34,169.94 171.2,169.94 170.8,169.54 VRAM7.T8 ; v2(161.58,169.51) 161.15,169.51 161.09,169.57 158,169.57 VRAM8.T8 ; RN7518.1 190.28,162.8 190.41,162.67 190.41,162.26 190.3,162.15 RN7518.2 186.84,162.15 v2(186.45,161.77) 186.45,160.72 185.92,160.19 185.92,159.34 185.78,159.2 185.78,159.15 185.78,158.44 185.78,158.44 185.78,157.87 185.55,157.63 184.48,156.56 184.17,156.56 184.17,156.56 183.97,156.56 180.76,153.34 179,153.34 178.11,152.45 176.98,152.45 v1(176.4,151.87) 175.59,151.06 174.81,151.06 174.39,150.64 174.39,150.21 174.29,150.11 173.84,150.11 173.45,149.73 173.45,148.72 173.22,148.49 v2(173.22,148.05) ; v2(194.85,151.16) 194.49,151.52 194.49,151.92 194.05,152.37 194.05,152.38 194,152.44 194,152.91 VRAM6.T8
  L3 w0.127: v2(195.25,136.57) 196.49,137.8 196.49,140.66 196.49,140.67 196.49,141.14 196.49,141.42 196.49,141.86 195.66,142.69 195.66,144.22 v2(195.46,144.43) 195.34,144.54 195.34,146.92 195.83,147.41 195.83,153.18 194.98,154.03 194.98,154.97 194.62,155.33 193.42,155.33 193.08,155.67 191.98,155.67 191.12,156.53 190.94,156.53 190.85,156.44 190.67,156.44 190.49,156.62 190.49,156.8 190.58,156.89 190.58,157.07 190.26,157.39 190.26,157.98 186.47,161.77 v2(186.45,161.77) 186.31,161.77 185.45,162.63 183.19,162.63 179.51,166.31 179.51,166.95 177.24,169.23 176.53,169.23 175.71,170.05 170.2,170.05 169.98,169.82 167.64,169.82 167.46,169.65 v2(167.36,169.65)
  L4 w0.127: v2(173.47,169.23) 172.58,169.23 171.87,169.94 170.94,169.94 170.83,169.82 170.83,169.49 170.55,169.21 170.2,169.21 169.77,169.65 v2(167.36,169.65) 167.26,169.65 165.92,168.98 164.53,168.98 164.25,168.71 163.97,168.71 163.85,168.83 163.85,169.47 163.72,169.6 163.47,169.6 163.34,169.47 163.34,169.35 163.21,169.23 162.96,169.23 162.67,169.51 v2(161.58,169.51) ; v2(194.85,151.16) 194.85,150.07 195.83,149.09 195.83,147.21 195.6,146.98 195.6,145.76 195.29,145.46 195.29,144.59 v2(195.46,144.43)
  BOTTOM w0.14: v2(195.25,136.57) 195.25,135.37 VRAM1.T8 ; VRAM3.T8 174.67,169.3 173.68,169.3 173.61,169.23 v2(173.47,169.23) ; v2(194.85,151.16) 194.85,150.74 194.81,150.7 194.81,149.12 194.4,148.71 VRAM2.T8 ; v2(173.22,148.05) 172.85,147.67 GPU1.F23 ; VRAM4.T8 161.58,168.39 v2(161.58,169.51)
FBA_CMD9: length 116.6
  TOP w0.14: VRAM6.N3 192.27,149.58 v2(192.27,149.93) ; RN7522.2 183.4,167.05 183.27,166.92 183.27,166.53 183.39,166.4 RN7522.1 183.88,165.1 183.57,164.8 183.57,164.59 183.56,164.58 183.56,163.44 183.56,163.44 183.56,163.28 183.17,162.89 v1(183.17,162.48) 183.17,158.8 183.59,158.38 v2(183.59,158.1) ; VRAM7.N3 174.53,166.24 v2(174.23,166.24) ; v2(160.33,166.45) 160.8,165.97 VRAM8.N3 ; v2(192.36,135.75) 192.36,135.68 VRAM5.N3
  L3 w0.127: v2(192.36,135.75) 191.94,135.75 191.83,135.64 190.85,135.64 190.62,135.87 190.62,136.31 190.81,136.5 190.81,137.63 190.97,137.8 190.97,138.33 190.31,138.99 190.31,141.2 191.8,142.69 v2(191.8,143.09) 191.54,143.35 191.54,145.42 189.95,147.02 189.95,149.08 188.3,150.72 188.23,150.72 187.91,151.04 187.91,152.37 188.8,153.27 188.8,153.92 188.56,154.17 187.33,154.17 186.93,154.56 186.93,155.71 185.58,157.06 185.56,157.06 184.52,158.1 v2(183.59,158.1) 182.78,158.91 180.68,158.91 177.91,161.68 177.91,162.11 177.18,162.84 176.59,162.84 176.26,162.51 175.53,162.51 175.32,162.71 175.07,162.71 174.94,162.58 174.94,162.41 174.82,162.28 174.56,162.28 174.43,162.41 174.43,162.58 173.7,163.32 173.17,163.32 172.82,163.67 169.8,163.67 169.63,163.84 168.97,163.84 167.46,165.35 167.27,165.35 v2(167.12,165.5) 166.42,165.5 166.15,165.76 165.62,165.76 164.45,164.59 162.18,164.59 v2(160.33,166.45)
  L4 w0.102: 173.06,149.01 172.52,148.48 172.19,148.48 171.93,148.21 171.93,147.65 v2(171.53,147.25)
  L4 w0.127: v2(167.12,165.5) 168.08,165.5 168.9,164.68 169.4,164.68 169.86,165.13 170.86,165.13 171.75,166.02 172.56,166.02 172.96,166.42 173.71,166.42 173.89,166.24 v2(174.23,166.24) ; v2(191.8,143.09) 191.8,143.42 191.55,143.67 191.55,143.95 191.66,144.06 191.77,144.06 191.89,144.19 191.89,144.4 191.77,144.53 191.44,144.53 191.32,144.65 191.32,144.91 191.44,145.04 191.81,145.04 191.94,145.16 191.94,145.42 191.81,145.54 191.44,145.54 191.32,145.67 191.32,145.92 191.44,146.05 191.65,146.05 191.9,146.3 191.9,146.8 192.14,147.04 192.14,147.31 192.01,147.44 191.91,147.44 191.79,147.56 191.79,149.45 v2(192.27,149.93) ; v2(183.59,158.1) 183.75,158.1 184.21,158.56 184.39,158.56 184.61,158.35 184.61,158.17 184.1,157.66 184.1,157.66 179.54,153.1 179.2,153.1 178.82,153.48 178.32,153.48 177.78,152.95 177.78,152.77 178.02,152.53 178.2,152.53 178.51,152.83 178.68,152.83 178.89,152.63 178.89,152.45 178.45,152.01 175.84,152.01 174.86,151.02 173.82,151.02 173.45,150.65 173.45,149.41 173.06,149.01
  BOTTOM w0.14: VRAM7.N3 174.53,166.24 v2(174.23,166.24) ; v2(171.53,147.25) 171.95,146.83 GPU1.G22 ; VRAM5.N3 192.02,135.32 192.36,135.66 v2(192.36,135.75) ; v2(160.33,166.45) 160.8,165.97 VRAM8.N3 ; v2(192.27,149.93) 192.27,149.58 VRAM6.N3
FBA_CMD10: length 115.5
  TOP w0.14: VRAM6.P3 192.8,149.69 192.93,149.82 v2(193.36,149.82) ; VRAM5.P3 192.8,135.4 193.21,135.81 193.21,135.85 v2(193.22,135.87) ; VRAM7.P3 174.74,166.77 174.46,167.06 174.28,167.06 v2(174.26,167.08) ; VRAM8.P3 160.8,166.77 v2(161.2,166.37) ; RN7507.2 188.17,166.88 188.02,167.03 187.69,167.03 187.52,166.86 RN7507.1 187.52,165.31 186.43,164.21 185.3,164.21 184.96,163.87 v1(184.96,163.41) 184.96,162.91 184.39,162.34 184.39,159.72 184.93,159.19 v2(184.93,158.79) 184.87,158.74 184.87,158.17 183.95,157.24 183.51,157.24 180.59,154.33 180.29,154.33 180.19,154.43 180.19,154.82 180.06,154.94 179.76,154.94 179.63,154.82 179.63,154.39 179.5,154.26 179.2,154.26 179.07,154.39 179.07,154.81 178.94,154.94 178.64,154.94 178.51,154.81 178.51,154.35 178.36,154.2 178.17,154.2 177.81,154.57 177.63,154.57 177.41,154.35 177.41,154.17 177.77,153.81 177.77,153.63 177.51,153.37 177.33,153.37 177.11,153.59 176.9,153.59 175.23,151.91 174.42,151.91 174.3,151.79 174.07,151.79 173.97,151.9 173.77,151.9 173.57,151.7 173.57,151.5 173.77,151.3 173.77,151.11 173.12,150.46 173.12,148.9 172.79,148.57 172.79,147.72 v2(172.32,147.25)
  L3 w0.127: v2(161.2,166.37) 161.55,166.01 162.04,166.01 162.13,166.1 162.13,166.66 162.5,167.03 163.31,167.03 163.44,166.9 166.13,166.9 166.53,166.5 167.45,166.5 v2(167.51,166.43) 168.81,165.13 168.81,164.92 169.17,164.56 169.89,164.56 170.31,164.14 173.09,164.14 173.42,164.46 176.76,164.46 179.62,161.6 179.86,161.6 180.21,161.25 180.21,160.62 181.14,159.69 183.66,159.69 183.91,159.45 184.28,159.45 v2(184.93,158.79) 184.93,158.73 188.25,155.41 188.54,155.41 190.11,153.85 190.11,151.7 190.39,151.41 190.39,151.04 190.26,150.91 190.26,150.57 190.33,150.5 190.33,149.71 190.64,149.4 190.64,148.58 190.77,148.45 191.02,148.45 191.15,148.33 191.15,148.07 191.02,147.94 190.77,147.94 190.64,147.82 190.64,147.02 192.27,145.39 192.27,144.03 193.07,143.23 v2(193.07,142.45) 192.77,142.15 192.77,142.02 191.88,141.12 191.83,141.12 191.58,140.88 191.58,140.87 191.58,140.86 191.58,140.41 191.95,140.04 191.95,137.95 192.26,137.65 193.08,137.65 193.21,137.52 193.21,136.3 193.22,136.28 v2(193.22,135.87)
  L4 w0.127: v2(193.36,149.82) 192.78,149.23 192.78,148.74 193.26,148.25 193.5,148.25 194.35,147.39 194.35,146.98 192.99,145.61 192.99,142.53 v2(193.07,142.45) ; v2(174.26,167.08) 173.84,167.08 173.69,167.23 172.18,167.23 171.4,166.44 169.01,166.44 168.71,166.14 168.05,166.14 167.76,166.43 v2(167.51,166.43)
  BOTTOM w0.14: GPU1.G23 171.95,147.62 v2(172.32,147.25) ; VRAM7.P3 174.49,167.08 v2(174.26,167.08) ; v2(193.36,149.82) 192.93,149.82 192.8,149.69 VRAM6.P3 ; v2(193.22,135.87) 193.21,135.85 193.21,135.73 VRAM5.P3 ; v2(161.2,166.37) 161.2,166.37 VRAM8.P3
FBA_CMD11: length 115.9
  TOP w0.14: v2(172.53,163.24) 172.6,163.31 173.71,163.31 174.25,162.77 VRAM7.J3 ; VRAM5.J3 188.8,136.14 189.39,136.72 v2(189.39,137.15) ; v2(189.68,150.23) 189.38,149.93 189.38,149.89 VRAM6.J3 ; RN7503.1 180.4,165.3 180.59,165.48 180.88,165.48 181.05,165.31 RN7503.2 181.05,164.52 181.59,163.99 181.59,161.8 181.95,161.43 181.95,158.15 181.95,158.09 182.04,158 182.04,157.14 181.23,156.32 180.87,156.32 180.85,156.35 v2(180.26,156.35) 180.13,156.21 180.13,155.86 179.99,155.73 179.71,155.73 179.57,155.86 v1(179.57,156.15) 179.57,156.4 179.44,156.53 179.13,156.53 179.01,156.4 179.01,155.86 178.87,155.73 178.59,155.73 178.45,155.86 178.45,156.11 178.34,156.22 178.14,156.22 176.05,154.12 175.85,154.12 175.55,154.42 175.36,154.42 175.16,154.22 175.16,154.02 175.45,153.73 175.45,153.53 175.25,153.33 175.06,153.33 174.93,153.46 174.51,153.88 174.33,153.88 174.12,153.66 174.12,153.48 174.66,152.94 174.66,152.74 174.51,152.59 174.08,152.59 173.71,152.97 173.36,152.97 172.59,152.2 172.59,151.63 172.73,151.49 173.1,151.49 173.24,151.35 173.24,151.07 173.1,150.93 172.93,150.93 172.79,150.79 172.79,149.32 v2(172.35,148.88) ; VRAM8.J3 160.55,163.02 160.27,163.02 v2(159.67,163.62)
  L3 w0.127: v2(159.67,163.62) 159.73,163.56 159.73,162.84 159.91,162.66 160.36,162.66 160.49,162.79 160.49,163.27 160.95,163.73 164.66,163.73 165,163.38 v2(165.2,163.38) 165.27,163.32 166.72,163.32 167.88,162.16 167.88,162.05 168.32,161.62 168.32,160.28 168.71,159.89 171.14,159.89 172.02,159 172.54,159 172.68,158.86 175.66,158.86 176.79,159.99 177.21,159.99 177.46,159.74 177.46,159.16 v2(180.26,156.35) 180.74,155.87 181.59,155.87 181.81,155.66 181.81,155.48 181.63,155.31 181.63,155.13 181.81,154.95 181.99,154.95 182.16,155.12 182.34,155.12 183.33,154.13 185.37,154.13 185.64,153.86 185.64,153.56 184.54,152.45 184.54,150.81 184.83,150.51 185.08,150.51 188.08,147.51 188.08,146.89 189.29,145.69 189.29,144.01 189.41,143.88 v2(189.41,143.38)
  L4 w0.127: v2(189.68,150.23) 189.62,150.16 189.62,149.92 190.47,149.07 190.47,147.99 189.62,147.14 189.62,144.58 189.35,144.32 189.35,143.63 189.41,143.58 v2(189.41,143.38) 189.41,142.77 189.68,142.49 189.68,137.45 v2(189.39,137.15) ; v2(172.53,163.24) 172.17,163.59 170.21,163.59 170.02,163.4 167.65,163.4 167.5,163.25 166.82,163.25 166.69,163.38 v2(165.2,163.38)
  BOTTOM w0.14: VRAM3.J3 172.06,162.77 v2(172.53,163.24) ; VRAM4.J3 158.25,163.42 158.95,163.42 159.15,163.62 v2(159.67,163.62) ; v2(189.39,137.15) 189.39,137.93 VRAM1.J3 ; v2(189.68,150.23) 189.53,150.39 189.53,151.32 189.36,151.48 189.36,151.95 VRAM2.J3 ; v2(172.35,148.88) 171.95,148.48 GPU1.G24
FBA_CMD12: length 125.9
  TOP w0.14: v2(193.23,138.09) 193.97,138.09 VRAM5.T7 ; VRAM6.T7 194.92,152.51 v2(194.95,152.54) ; v2(172.03,169.12) 171.6,168.69 VRAM7.T7 ; VRAM8.T7 157.61,168.37 v2(158.04,168.8) ; RN7509.1 190.28,168.88 190.44,168.72 190.44,168.4 190.27,168.23 RN7509.2 189.8,168.13 188.66,166.99 188.66,165.84 v1(188.16,165.34) 187.94,165.12 v2(187.94,164.73)
  L3 w0.127: v2(164.88,171.61) 165.97,171.61 166.59,172.24 179.18,172.24 179.67,172.11 180.18,171.98 186.96,165.2 v2(187.94,164.73) 188.18,164.49 188.48,164.49 192.21,160.77 192.45,160.77 195.18,158.03 196.28,158.03 197.81,156.51 197.81,146.66 197.93,146.54 198.07,146.54 198.19,146.41 198.19,146.16 198.07,146.03 197.93,146.03 197.81,145.9 197.81,144.82 v2(197.64,144.65)
  L4 w0.127: v2(158.04,168.8) 160.85,171.61 v2(164.88,171.61) ; v2(193.23,138.09) 194.22,138.53 194.41,138.72 195.03,139.96 196.36,141.3 196.64,142.99 197.51,143.86 197.64,144.38 v2(197.64,144.65) 197.64,149.99 195.09,152.54 v2(194.95,152.54)
  BOTTOM w0.14: VRAM8.T7 157.61,168.37 v2(158.04,168.8) ; v2(187.94,164.73) 187.85,164.73 187.21,164.09 187.21,162.26 187.81,161.66 187.81,158.22 186.54,156.95 184.03,156.95 183.23,156.15 183.05,156.15 182.4,156.15 178.99,152.74 173.14,152.74 172.62,152.22 172.62,151 GPU1.F27 ; v2(194.95,152.54) 194.94,152.54 194.9,152.51 VRAM6.T7 ; v2(164.88,171.61) 165.15,171.11 165.27,170.56 165.36,170.47 165.36,170.46 165.5,170.33 166.13,170.33 166.9,169.55 166.9,169.44 167.12,169.22 167.62,169.22 168.08,169.68 169.1,169.68 169.99,169.85 170.2,170.06 170.57,170.06 171.63,169.92 171.85,169.71 v2(172.03,169.12) 171.6,168.69 VRAM7.T7 ; VRAM5.T7 193.97,138.09 v2(193.23,138.09)
FBA_CMD13: length 112.6
  TOP w0.14: v2(162,165.58) 161.61,165.97 VRAM8.N2 ; RN7512.1 183.12,169.24 183.3,169.42 183.6,169.42 183.77,169.24 RN7512.2 183.77,168.11 184.51,167.37 184.51,165.08 v1(184.32,164.89) 183.98,164.55 183.98,164.42 183.97,164.41 183.97,163.27 183.97,163.27 183.97,163.11 183.58,162.72 183.58,159.32 v2(183.9,159) ; VRAM5.N2 192,134.53 v2(192.39,134.92) ; v2(192.36,148.91) 192.36,148.87 VRAM6.N2 ; VRAM7.N2 175.6,165.97 v2(175.2,166.37)
  L3 w0.127: v2(162,165.58) 162.29,165.28 162.45,165.28 162.62,165.45 163.29,165.45 163.53,165.21 164.68,165.21 164.81,165.34 164.81,165.66 164.68,165.79 163.82,165.79 163.51,166.09 163.51,166.37 163.69,166.55 165.9,166.55 166.41,166.04 v2(166.56,166.04) 166.66,165.94 167.34,165.94 168.95,164.33 169.74,164.33 170.16,163.91 173.19,163.91 173.47,164.19 174.77,164.19 174.89,164.06 174.89,163.78 175.02,163.65 175.27,163.65 175.4,163.78 175.4,163.99 175.53,164.12 176.41,164.12 176.62,163.91 176.62,163.73 176.47,163.58 176.47,163.4 176.65,163.22 176.82,163.22 176.98,163.37 177.16,163.37 178.29,162.23 178.29,161.81 180.78,159.32 183.38,159.32 183.7,159 v2(183.9,159) 184.09,159 188.04,155.05 188.58,155.05 189.66,153.98 189.66,152.11 189.53,151.98 189.53,150.98 190.1,150.4 190.1,149.41 190.27,149.25 190.27,147.08 191.91,145.44 191.91,143.84 192.22,143.52 192.22,142.44 191.83,142.04 v2(191.83,141.68) 191.33,141.68 190.67,141.02 190.67,138.97 191.2,138.44 191.2,137.38 191.65,136.93 191.65,136.74 191.89,136.5 192.4,136.5 192.8,136.1 192.8,135.57 v2(192.39,134.92)
  L4 w0.127: v2(183.9,159) 183.84,159.06 183.29,159.06 183.13,158.89 183.13,157.21 179.88,153.95 178.28,153.95 176.71,152.38 175.56,152.38 175.11,151.93 174.31,151.93 173.15,150.77 173.15,150.44 v2(172.36,149.66) ; v2(192.36,148.91) 192.02,148.57 192.02,147.94 192.08,147.88 192.08,147.88 192.42,147.53 192.42,147 192.73,146.7 192.73,146.49 192.27,146.03 192.27,142.13 v2(191.83,141.68) ; v2(175.2,166.37) 174.91,166.66 173.88,166.66 173.61,166.92 172.2,166.92 171.3,166.02 170.08,166.02 169.6,165.54 168.78,165.54 168.47,165.86 167.35,165.86 167.16,166.04 v2(166.56,166.04)
  BOTTOM w0.14: VRAM5.N2 192,134.54 192.38,134.92 v2(192.39,134.92) ; v2(162,165.58) 161.61,165.97 VRAM8.N2 ; GPU1.G25 171.97,149.27 v2(172.36,149.66) ; VRAM6.N2 192,148.51 192.36,148.86 v2(192.36,148.91) ; VRAM7.N2 175.21,166.36 175.21,166.36 v2(175.2,166.37)
FBA_CMD14: length 105.7
  TOP w0.14: v2(161.2,167.97) 160.8,168.37 VRAM8.T3 ; VRAM7.T3 174.45,168.72 174.45,168.77 v2(174.41,168.81) ; RN7514.1 187.88,160.79 187.99,160.68 187.99,160.39 187.75,160.14 RN7514.2 186.54,160.14 v2(186.41,160.01) ; VRAM5.T3 194.71,135.63 v2(194.71,135.87) ; v2(194,149.75) 194,149.71 VRAM6.T3
  L3 w0.127: v2(194.71,135.87) 194.71,136.68 196.15,138.12 196.15,140.81 196.15,141.53 v2(194.81,142.86) 194.77,142.91 194.77,143.69 193.91,144.55 193.91,146.58 194.4,147.07 194.4,148.13 194.65,148.38 194.65,150.66 194.43,150.88 194.43,152.25 194.25,152.42 194.25,152.6 194.55,152.9 194.55,153.08 194.37,153.26 194.19,153.26 193.89,152.96 193.71,152.96 193.37,153.3 193.02,153.3 192.77,153.55 192.77,153.9 192.4,154.27 191.09,154.27 188.9,156.46 188.9,156.83 187.17,158.57 187.17,159.25 v2(186.41,160.01) 185.55,160.87 184.81,160.87 184.38,161.3 182.97,161.3 177.12,167.15 176.87,167.15 175.59,168.43 175.03,168.43 174.94,168.34 174.06,168.34 173.96,168.24 171.67,168.24 171.51,168.4 169.84,168.4 169.22,169.01 168.24,169.01 167.53,168.3 v2(167.27,168.3) 167.09,168.12 164.77,168.12 163.4,169.49 162.52,169.49 161.2,168.17 v2(161.2,167.97)
  L4 w0.127: v2(186.41,160.01) 185.89,160.53 185.56,160.53 185.39,160.37 183.17,160.37 175.92,153.12 175.23,153.12 174.79,152.68 174.14,152.68 173.54,152.08 173.54,151.94 173.12,151.53 v2(171.84,151.53) ; v2(167.27,168.3) 168.07,168.3 168.78,169.01 169.13,169.01 169.43,168.72 170.7,168.72 170.81,168.83 171.62,168.83 171.75,168.7 172.21,168.7 172.31,168.8 173.96,168.8 173.97,168.81 v2(174.41,168.81) ; v2(194,149.75) 195.37,148.38 195.37,147.67 195.04,147.33 195.04,146.32 194.14,145.42 194.14,143.54 v2(194.81,142.86)
  BOTTOM w0.14: VRAM5.T3 194.4,135.56 v2(194.71,135.87) ; v2(161.2,167.97) 161.2,167.97 VRAM8.T3 ; v2(174.41,168.81) 174.45,168.77 174.45,168.72 VRAM7.T3 ; v2(171.84,151.53) 171.95,151.41 GPU1.G27 ; VRAM6.T3 194,149.71 v2(194,149.75) ; v1(194.64,143.49) 194.64,143.03 v2(194.81,142.86)
FBA_CMD15: length 99.5
  TOP w0.14: v2(173.64,163.75) 173.64,163.74 174.1,163.27 174.5,163.27 VRAM7.K3 ; VRAM5.K3 189.35,135.57 189.35,136.18 v2(189.99,136.82) ; v2(158.87,163.96) 159.29,163.96 159.47,164.13 160.24,164.13 VRAM8.K3 ; VRAM6.K3 190.13,149.84 190.13,151.08 v2(189.97,151.24) ; RN7504.1 180.38,158.9 180.54,159.06 180.88,159.06 181.03,158.91 RN7504.2 181,158.5 181,156.8 v2(181.05,156.75) 181.05,156.75 181.05,156.76 180.52,156.76 180.35,156.93 178.07,156.93 175.98,154.84 174.68,154.84 v1(172.98,153.13) 172.35,152.5 172.35,150.48 v2(172.36,150.47)
  L3 w0.127: v2(158.87,163.96) 159.26,163.96 159.34,164.04 164.75,164.04 164.98,163.81 165.47,163.81 165.56,163.71 166.95,163.71 v2(166.97,163.69) 168.11,162.55 168.11,162.15 168.56,161.7 168.56,160.36 168.81,160.12 171.23,160.12 172.07,159.28 172.69,159.28 172.88,159.09 175.56,159.09 176.69,160.22 177.34,160.22 180.47,157.09 180.71,157.09 v2(181.05,156.75) 181.59,156.21 181.87,156.21 182.88,155.2 185.69,155.2 186.02,154.88 186.02,153.6 185.06,152.63 185.06,151.67 185.49,151.24 185.49,150.43 188.31,147.61 188.31,147.16 189.74,145.72 189.74,144.23 v2(189.82,144.15)
  L4 w0.127: v2(189.99,136.82) 189.99,137.28 189.91,137.35 189.91,141.76 190.12,141.97 190.12,142.74 189.86,143 189.86,143.81 189.82,143.85 v2(189.82,144.15) 189.88,144.22 189.88,147.05 190.69,147.86 190.69,149.19 190.11,149.77 190.11,150.39 190.03,150.47 190.03,151.18 v2(189.97,151.24) ; v2(166.97,163.69) 167.11,163.55 167.41,163.55 167.55,163.69 169.95,163.69 170.15,163.88 173.04,163.88 173.17,163.75 v2(173.64,163.75)
  BOTTOM w0.14: v2(189.99,136.82) 189.99,137.34 189.73,137.59 189.73,138.04 189.6,138.17 VRAM1.K3 ; v2(189.97,151.24) 189.94,151.27 189.91,151.27 189.6,151.58 VRAM2.K3 ; VRAM4.K3 157.8,163.57 157.96,163.73 158.64,163.73 158.86,163.96 v2(158.87,163.96) ; VRAM3.K3 171.71,163.68 173.56,163.68 v2(173.64,163.75) ; GPU1.G26 171.96,150.07 v2(172.36,150.47)
FBA_CMD16: length 100.6
  TOP w0.14: v2(159.19,165.17) 160.31,165.17 160.66,164.82 160.87,164.82 161.18,164.52 161.18,164.11 161.37,163.92 161.88,163.92 162.23,163.57 VRAM8.K1 ; VRAM7.K1 175.99,163.98 174.65,163.98 174.12,164.51 173.25,164.51 173.2,164.56 v2(172.78,164.56) ; v2(177.32,170.25) 176.27,171.3 170.19,171.3 v1(169.84,171.64) 169.07,172.41 167.12,172.41 v2(166.52,173.01)
  L4 w0.127: v2(168.19,148.86) 168.19,149.79 169.28,150.87 169.28,152.57 170.28,153.57 170.52,153.81 171.55,153.81 172.59,154.85 173.61,154.85 174.49,155.72 174.86,155.72 175.68,156.54 176.03,156.54 176.52,157.03 176.52,159.71 177.36,160.55 177.36,162.52 177.19,162.69 177.19,164.79 178.12,165.72 178.12,166.23 177.55,166.8 177.55,169.18 177.42,169.3 176.96,169.3 176.84,169.43 176.84,170.13 176.96,170.25 v2(177.32,170.25) ; v2(159.19,165.17) 158.89,165.47 158.89,166.34 158.64,166.6 157.66,166.6 156.92,165.86 156.23,165.86 155.99,166.09 155.99,168.12 160.95,173.08 166.45,173.08 v2(166.52,173.01) 167.06,172.48 169.25,172.48 169.38,172.35 169.38,171.91 169.51,171.78 169.76,171.78 169.89,171.91 169.89,172.35 170.02,172.48 170.27,172.48 170.4,172.35 170.4,171.91 170.52,171.78 170.78,171.78 170.9,171.91 170.9,172.35 171.03,172.48 171.82,172.48 175.98,168.32 175.98,166.19 174.05,164.26 173.07,164.26 v2(172.78,164.56)
  BOTTOM w0.14: v2(168.19,148.86) 167.8,148.47 GPU1.M24 ; v2(172.78,164.56) 172.96,164.56 173.09,164.43 173.09,164.07 172.96,163.95 170.38,163.95 VRAM3.K1 169.58,163.57 169.01,164.14 166.46,164.14 R7511.1 ; v2(159.19,165.17) 158.64,164.62 158.64,164.34 158.51,164.21 158.51,164.2 158.32,164.01 156.65,164.01 156.22,163.57 VRAM4.K1
FBA_CMD17: length 88.1
  TOP w0.14: VRAM7.L2 176.02,164.79 176.02,169.05 175.27,169.8 172.99,169.8 172.86,169.93 172.86,170.28 172.96,170.38 175.68,170.38 176.94,169.13 177.23,169.13 177.57,168.78 178.4,168.78 179.69,170.08 179.69,171.12 179.57,171.25 179.23,171.25 179.11,171.12 179.11,170.33 v2(178.24,169.46) 177.91,169.79 177.14,169.79 175.99,170.94 170.14,170.94 168.18,168.98 168.18,168.6 167.4,167.83 167.06,167.83 v1(165.96,166.73) 163.25,164.02 162.18,164.02 161.83,164.37 VRAM8.L2
  L4 w0.127: v2(178.24,169.46) 178.49,169.21 178.49,168.77 178.36,168.64 178.06,168.64 177.93,168.52 177.93,168.19 178.06,168.06 178.36,168.06 178.49,167.93 178.49,167.58 178.36,167.45 178.06,167.45 177.93,167.32 177.93,167.03 178.06,166.9 178.36,166.9 178.49,166.78 178.49,165.56 177.99,165.05 177.99,164.79 177.85,164.65 177.59,164.65 177.47,164.54 177.47,164.2 177.6,164.07 178.65,164.07 178.75,163.97 178.75,160.78 178.65,160.68 178.37,160.68 178.24,160.81 178.24,163.45 178.12,163.58 177.86,163.58 177.74,163.45 177.74,160.36 177.86,160.24 178.44,160.24 178.56,160.11 178.56,159.83 178.44,159.7 177.65,159.7 177.52,159.57 177.52,159.32 177.65,159.19 178.41,159.19 178.54,159.07 178.54,158.79 178.41,158.66 177.65,158.66 177.52,158.53 177.52,157.38 176.35,156.21 175.82,156.21 174.97,155.37 174.65,155.37 173.76,154.48 172.75,154.48 171.69,153.42 170.65,153.42 169.56,152.33 169.56,150.8 168.58,149.82 168.58,149.29 168.61,149.26 168.61,148.28 168.58,148.25 168.58,146.85 168.68,146.75 169.29,146.75 169.42,146.62 169.42,146.29 169.29,146.16 168.07,146.16 167.95,146.29 167.95,147.91 167.78,148.08 v2(167.38,148.08)
  BOTTOM w0.14: GPU1.M23 167.79,147.67 v2(167.38,148.08)
FBA_CMD18: length 75.3
  TOP w0.14: v2(164.88,172.58) 165.3,172.58 166.26,173.54 168.56,173.54 170.45,171.65 176.62,171.65 v1(177.03,171.25) 177.44,170.83 178.42,170.83 v2(178.52,170.73)
  L4 w0.127: v2(164.88,172.58) 160.96,172.58 156.41,168.04 v2(156.41,166.36) ; v2(178.52,170.73) 179.37,169.87 179.37,167.76 179.5,167.64 179.78,167.64 179.91,167.51 179.91,167.25 179.78,167.13 179.5,167.13 179.37,167 179.37,166.75 179.5,166.62 179.78,166.62 179.91,166.49 179.91,166.24 179.78,166.11 179.5,166.11 179.37,165.98 179.37,158.21 175.85,154.68 175.01,154.68 174.07,153.75 173.05,153.75 171.96,152.65 170.93,152.65 170.02,151.74 170.02,149.78 169.85,149.61 v2(169.85,148.87)
  BOTTOM w0.14: v2(169.85,148.87) 169.47,148.49 GPU1.K24 ; v2(156.41,166.36) 156.41,164.76 VRAM4.L2 ; VRAM3.L2 170.45,164.72 169.86,164.72 169.63,164.49 168.73,164.49 168.59,164.63 168.59,165.11 168.47,165.23 168.16,165.23 168.03,165.11 168.03,164.63 167.89,164.49 167.56,164.49 166.98,165.06 166.77,165.06 166.03,165.81 165,165.81 164.71,166.1 164.71,168.94 164.25,169.41 164.25,170.43 164.39,170.57 164.7,170.57 164.83,170.7 164.83,171.01 164.7,171.13 164.39,171.13 164.25,171.27 164.25,171.95 v2(164.88,172.58)
FBA_CMD19: length 102.9
  TOP w0.14: v2(174.28,163.7) 174.28,163.74 173.84,164.18 173.18,164.18 172.93,163.93 170.57,163.93 170.21,163.57 VRAM7.K9 ; v2(159.53,164.62) 158.92,164.62 158.29,163.98 156.43,163.98 156.21,163.76 156.19,163.76 VRAM8.K9 153.31,163.57 v1(153.09,163.35) 152.44,163.35 R7509.1
  L4 w0.102: v2(169.88,148.07) 169.44,148.51 169.44,149.04 169.53,149.13 169.53,149.66
  L4 w0.127: 167.24,173.09 167.53,173.38 172.4,173.38 173.41,172.37 175.92,172.37 179.05,169.24 179.05,158.4 175.7,155.05 174.85,155.05 173.92,154.11 172.9,154.11 171.81,153.02 170.77,153.02 169.79,152.03 169.79,150.16 169.53,149.91 169.53,149.66 ; 167.24,173.09 167.46,172.86 172,172.86 173.25,171.62 173.56,171.62 173.75,171.81 173.93,171.81 174.11,171.63 174.11,171.45 173.85,171.19 173.85,171.01 174.03,170.83 174.21,170.83 174.49,171.11 174.67,171.11 174.85,170.93 174.85,170.75 174.57,170.47 174.57,170.29 174.75,170.11 174.93,170.11 175.21,170.39 175.39,170.39 175.57,170.21 175.57,170.03 175.29,169.75 175.29,169.57 175.47,169.39 175.65,169.39 176,169.75 176.18,169.75 176.36,169.57 176.36,169.39 176.01,169.03 176.01,168.85 176.34,168.52 176.34,166.18 174.28,164.12 v2(174.28,163.7) ; 167.24,173.09 166.79,173.53 160.86,173.53 155.86,168.53 155.86,168.31 155.77,168.22 155.77,165.92 156.63,165.05 158.72,165.05 159.02,164.75 159.39,164.75 v2(159.53,164.62)
  BOTTOM w0.14: v2(159.53,164.62) 159.53,164.36 159.91,163.98 161.82,163.98 162.23,163.57 VRAM4.K9 ; VRAM3.K9 176.17,163.57 175.75,163.99 174.62,163.99 174.04,164.57 173.86,164.57 173.7,164.42 173.7,164.32 174.28,163.75 v2(174.28,163.7) ; v2(169.88,148.07) 169.48,147.67 GPU1.K23
FBA_CMD20: length 125.7
  TOP w0.14: VRAM7.T2 174.56,169.24 174.28,169.24 173.62,168.81 173.32,168.81 172.27,169.55 171.46,169.55 v2(171.44,169.52) ; VRAM5.T2 195.16,135.28 195.16,136.02 194.76,136.43 194.76,137.82 194.99,138.05 v2(194.99,138.09) ; VRAM6.T2 194.75,148.86 194.75,149.6 193.97,150.38 v2(193.67,150.38) ; v2(160.21,168.1) 160.26,168.1 160.44,168.3 160.44,168.51 160.66,168.72 160.94,168.72 161.19,168.48 161.49,168.48 VRAM8.T2
  L3 w0.127: v2(195.2,143.82) 194.14,144.88 194.14,145.46 194.81,147.09 195.37,147.66 195.37,152.94 194.16,154.16 192.84,154.16 192.37,154.63 192.37,154.87 192.1,155.14 191.49,155.14 190.19,155.68 189.36,156.51 189.36,156.89 187.5,158.76 187.5,159.57 186.58,160.49 186.5,160.49 185.74,161.25 185.14,161.25 v2(185.02,161.36) 184.67,161.71 183.1,161.71 178.56,166.25 178.56,166.43 178.62,166.49 178.62,166.67 178.44,166.85 178.26,166.85 178.2,166.79 178.02,166.79 177.56,167.26 177.56,167.74 177.29,168.01 176.68,168.01 175.38,169.3 174.29,169.3 173.45,168.47 171.77,168.47 171.61,168.63 169.96,168.63 169.35,169.24 168.09,169.24 167.76,168.91 167.13,168.91 166.78,168.55 v2(165.25,168.55)
  L4 w0.127: v2(171.44,169.52) 170.76,169.1 170.65,168.98 170.11,168.98 169.25,169.24 168.22,169.24 166.1,168.65 v2(165.25,168.55) 164.67,167.97 163.85,167.97 163.18,167.3 162.72,167.3 162.47,167.54 162.47,168.09 162.17,168.39 160.8,168.39 160.5,168.1 v2(160.21,168.1) ; v2(195.2,143.82) 195.04,143.98 195.04,145.66 195.3,145.92 195.3,147.09 195.6,147.39 195.6,148.75 193.97,150.38 v2(193.67,150.38)
  BOTTOM w0.14: v2(171.44,169.52) 171.44,169.01 VRAM3.T2 ; v2(195.2,143.82) 195.28,143.74 195.28,143.12 195.41,142.99 195.53,142.99 195.67,142.85 195.67,142.57 195.53,142.43 195.09,142.43 194.96,142.31 194.96,142 195.09,141.88 195.53,141.88 195.67,141.74 195.67,141.46 195.53,141.32 195.41,141.32 195.27,141.18 195.27,140.62 195.88,140.01 195.88,138.98 v2(194.99,138.09) 194.75,138.32 194.75,138.97 VRAM1.T2 ; R7508.1 184.81,161.58 v2(185.02,161.36) 185.02,160.8 184.29,160.07 180.79,160.07 v1(180.17,159.46) 177.83,157.12 177.83,156.69 176.36,155.23 171.58,155.23 168.41,152.06 GPU1.M27 ; v2(193.67,150.38) 193.67,150.86 194.28,151.48 194.28,152.13 194.01,152.41 194.01,152.92 VRAM2.T2 ; VRAM4.T2 157.66,169.23 159.08,169.23 v2(160.21,168.1)
FBA_CMD21: length 127.4
  TOP w0.14: VRAM8.R8 156.8,167.57 v2(157.21,167.97) ; VRAM5.R8 194.02,139.74 v2(195.4,139.74) ; v2(194,153.71) VRAM6.R8 ; VRAM7.R8 170.38,167.99 v2(170.38,169.63)
  L3 w0.127: v2(165.54,172.07) 166.03,172.57 180.24,172.57 185.73,167.07 185.91,167.07 185.97,167.14 186.15,167.14 186.33,166.96 186.33,166.78 186.27,166.71 186.27,166.54 186.67,166.13 v2(186.82,166.13) 188.51,164.97 191.99,161.49 192.24,161.49 195.3,158.42 196.49,158.42 198.16,156.75 198.16,148.35 v2(198.66,147.07)
  L4 w0.127: v2(170.38,169.63) 170.38,170.64 170.25,170.76 169.99,170.76 169.86,170.64 169.86,170.19 169.74,170.06 169.48,170.06 169.35,170.19 169.35,170.42 169.23,170.55 168.4,170.55 168.19,170.76 167.83,170.76 167.7,170.89 167.7,171.17 167.83,171.3 168.11,171.3 168.24,171.42 168.24,171.69 168.11,171.81 166.53,171.81 166.27,172.07 v2(165.54,172.07) 165.54,171.98 165.3,171.45 165.15,171.3 165.1,171.26 164.94,171.17 163.54,171.17 161.01,170.63 158.6,168.72 158.28,168.4 v2(157.21,167.97) ; v2(195.4,139.74) 196.94,141.63 196.94,142.78 198.93,144.76 198.93,145.67 v2(198.66,147.07) 198.41,147.32 198.41,150.32 195.02,153.71 v2(194,153.71)
  BOTTOM w0.14: v2(157.21,167.97) 156.8,167.57 VRAM8.R8 ; v2(194,153.71) VRAM6.R8 ; VRAM7.R8 170.8,167.84 170.38,168.26 v2(170.38,169.63) ; GPU1.M26 167.42,150.44 167.42,151.04 167.6,151.22 167.6,151.85 171.35,155.61 176.28,155.61 177.32,156.66 177.32,157.2 178.8,158.67 178.8,159.77 180.95,161.92 181.89,161.92 v1(185.59,165.61) 186.11,166.13 v2(186.82,166.13) 186.87,166.18 186.87,166.19 186.96,166.29 186.96,166.95 RN7520.1 187.02,167.46 186.84,167.64 186.54,167.64 186.37,167.46 RN7520.2 ; v2(195.4,139.74) 194.02,139.74 VRAM5.R8
FBA_CMD22: length 120.1
  TOP w0.14: VRAM5.P2 193.2,134.92 v2(193.2,134.93) ; VRAM8.P2 161.58,166.77 161.2,167.15 v2(161.2,167.21) ; v2(192.43,148.11) 192.8,148.48 VRAM6.P2 ; v2(175.19,167.17) 175.59,166.77 VRAM7.P2
  L3 w0.127: v2(193.2,134.93) 193.66,135.39 193.66,136.02 193.51,136.16 193.51,136.68 193.73,136.9 193.73,137.87 194.43,138.57 194.43,139.61 194.04,140 194.04,140.92 193.3,141.66 v2(193.12,141.66) 193.49,142.03 193.49,143.34 192.63,144.2 192.63,145.36 192.42,145.57 192.42,145.9 191.74,146.58 191.74,148.88 192.37,149.51 192.44,149.51 192.69,149.76 192.69,150.54 190.44,152.78 190.44,153.84 187.73,156.55 187.58,156.55 185.48,158.66 185.48,159.27 v2(185.05,159.7) 184.95,159.8 184.14,159.8 183.83,160.11 182.56,160.11 180.4,162.28 179.45,162.28 177.01,164.72 174.36,164.72 173.71,165.36 173.08,165.36 172.87,165.15 171.21,165.15 171.09,165.02 171.09,164.74 170.96,164.62 170.71,164.62 170.58,164.74 170.58,165.02 170.45,165.15 170.22,165.15 169.86,165.51 169.86,165.87 169.18,166.56 168.34,166.56 168.03,166.87 166.93,166.87 v2(166.86,166.94)
  L4 w0.127: v2(193.12,141.66) 192.62,142.15 192.62,145.88 193.44,146.69 193.44,146.89 193.33,147 193.33,147.64 192.85,148.11 v2(192.43,148.11) ; v2(161.2,167.21) 161.62,167.21 161.81,167.02 163.47,167.02 163.57,166.92 164.07,166.92 164.2,166.79 164.2,166.04 164.33,165.91 164.63,165.91 164.76,166.04 164.76,166.79 164.89,166.92 165.14,166.92 165.27,166.79 165.27,166 165.4,165.87 165.66,165.87 165.78,165.99 165.78,166.81 165.9,166.94 v2(166.86,166.94) 167.68,166.94 168.2,166.42 168.64,166.42 168.9,166.67 171.3,166.67 172.13,167.5 174.43,167.5 174.47,167.46 174.9,167.46 v2(175.19,167.17)
  BOTTOM w0.14: GPU1.M25 168.2,149.68 168.2,150.19 168.75,150.74 168.75,151.93 171.69,154.87 176.48,154.87 178.29,156.68 178.29,156.98 180.8,159.5 184.85,159.5 v2(185.05,159.7) 185.59,160.24 185.59,162.24 185.02,162.82 v1(185.02,163.51) 185.02,163.81 185.56,164.36 186.31,164.36 187.54,165.59 188.39,165.59 188.43,165.55 190.1,165.55 190.52,165.98 RN7501.2 190.52,167.45 190.64,167.57 191.03,167.57 191.18,167.43 RN7501.1 ; v2(175.19,167.17) 175.59,166.77 VRAM7.P2 ; v2(161.2,167.21) 161.2,167.17 VRAM8.P2 ; v2(192.43,148.11) 192.43,148.14 VRAM6.P2 ; VRAM5.P2 192.8,134.53 v2(193.2,134.93)
FBA_CMD23: length 107.3
  TOP w0.14: v2(193.95,136.4) 193.95,135.98 193.95,135.97 193.95,135.67 VRAM5.R3 ; v2(160.37,167.17) 160.77,167.57 VRAM8.R3 ; v2(186.25,158.57) 186.69,158.12 RN7513.2 187.81,158.12 188,158.32 188,158.6 187.84,158.77 RN7513.1 ; VRAM7.R3 174.58,167.79 174.36,167.79 v2(174.23,167.92) ; v2(194,148.91) 194,148.91 194,148.91 VRAM6.R3
  L3 w0.127: v2(193.95,136.4) 193.95,136.79 193.96,136.81 193.96,137.76 194.94,138.74 194.94,140.92 193.98,141.88 v2(193.98,142.92) 193.98,143.37 193.03,144.32 193.03,144.74 193.14,144.85 193.32,144.85 193.45,144.97 193.45,145.28 193.32,145.4 193.04,145.4 192.9,145.54 192.9,145.97 193.03,146.09 193.18,146.09 193.31,146.22 193.31,146.5 193.18,146.62 192.6,146.62 192.27,146.95 192.09,146.95 191.96,147.08 191.96,147.51 192.12,147.66 192.7,147.66 192.93,147.89 193.54,147.89 193.67,148.02 193.67,148.31 193.54,148.44 192.99,148.44 192.78,148.66 192.78,149.21 192.92,149.35 192.92,150.63 190.8,152.75 190.8,153.84 186.25,158.39 v2(186.25,158.57) 185.89,158.92 185.89,159.36 185.5,159.76 185.5,159.89 185.22,160.16 184.4,160.16 184.06,160.5 182.72,160.5 180.54,162.68 179.56,162.68 177.17,165.07 176.98,165.07 176.54,165.51 175.22,165.51 174.74,165.99 174.74,166.33 174.4,166.66 172.86,166.66 172.59,166.93 172.21,166.93 171.68,166.4 169.82,166.4 168.8,167.42 v2(167.72,167.42) 167.34,167.42 167.3,167.37 163.55,167.37 163.46,167.28 161.88,167.28 161.39,166.79 160.75,166.79 v2(160.37,167.17)
  L4 w0.127: v2(194,148.91) 194.53,148.38 194.53,147.91 194.81,147.63 194.81,146.6 193.73,145.52 193.73,143.17 v2(193.98,142.92) ; v2(167.72,167.42) 167.76,167.46 168.49,167.46 168.98,167.95 169.22,167.95 169.23,167.95 169.36,167.95 169.58,168.17 169.94,168.17 170.07,168.05 170.07,167.7 170.17,167.6 170.48,167.6 170.65,167.77 170.65,167.97 171.05,168.37 171.4,168.37 171.85,167.92 v2(174.23,167.92)
  BOTTOM w0.14: VRAM5.R3 193.95,135.67 193.95,135.97 193.95,135.98 v2(193.95,136.4) ; v2(160.37,167.17) 160.77,167.57 VRAM8.R3 ; VRAM7.R3 174.45,167.92 v2(174.23,167.92) ; GPU1.K26 169.11,150.43 169.11,151.77 171.86,154.52 176.54,154.52 v1(180.09,158.08) 180.71,158.69 183.36,158.69 183.51,158.55 183.78,158.55 184.05,158.28 185.96,158.28 v2(186.25,158.57) ; VRAM6.R3 194,148.91 194,148.91 v2(194,148.91)
FBA_CMD24: length 122.9
  TOP w0.14: VRAM5.P7 v2(193.2,138.92) ; v2(186.1,164.85) 186.15,164.9 RN7505.2 186.15,166.12 185.98,166.29 185.64,166.29 185.5,166.15 RN7505.1 ; v2(193.17,152.06) 193.07,152.06 192.8,152.33 VRAM6.P7 ; v2(171.2,167.17) 171.21,167.17 171.6,166.78 VRAM7.P7 ; VRAM8.P7 158.24,167.41 v2(158.24,167.5)
  L3 w0.127: v2(196.88,145.77) 197.07,146.42 197.07,153.68 196.48,155.36 196.48,156.59 195.9,157.18 194.83,157.35 193.74,158.43 193.28,158.56 189.15,162.69 189.08,162.89 188.37,163.6 187.55,163.6 186.3,164.85 v2(186.1,164.85) 183.95,167 183.15,167 181.88,168.27 181.88,168.7 181.34,169.24 181.34,169.42 181.41,169.5 181.41,169.68 181.23,169.86 181.06,169.86 180.98,169.78 180.8,169.78 180.62,169.96 180.62,170.14 180.71,170.23 180.71,170.41 180.53,170.59 180.35,170.59 180.26,170.5 180.08,170.5 179.9,170.68 179.9,170.86 180.01,170.97 180.01,171.15 179.83,171.33 179.65,171.33 179.54,171.22 179.36,171.22 179.05,171.53 167.04,171.53 v2(166.59,171.08)
  L4 w0.102: 170.3,149.48 170.27,149.45 170.27,148.71 170.29,148.7 170.29,147.65 v2(169.88,147.23)
  L4 w0.127: 170.3,149.48 170.3,151.57 171.06,152.33 172.13,152.33 173.22,153.42 174.24,153.42 175.18,154.36 176.02,154.36 181.53,159.86 181.53,160.96 184.77,164.2 185.45,164.2 v2(186.1,164.85) ; v2(193.2,138.92) 193.22,138.92 194.94,140.64 194.94,141.38 195.96,142.4 195.96,143.42 196.27,143.74 196.27,144.58 196.46,144.76 196.46,145.35 v2(196.88,145.77) 196.88,150.05 195.12,151.81 194.46,151.81 194.19,151.54 193.67,151.54 193.17,152.04 v2(193.17,152.06) ; v2(158.24,167.5) 158.39,168.18 158.72,168.52 159.25,168.52 161.15,170.42 163.16,170.42 163.55,170.81 165.09,170.81 165.51,171.24 166.28,171.24 v2(166.59,171.08)
  BOTTOM w0.14: v1(166.18,171.54) 166.18,171.5 v2(166.59,171.08) 166.81,170.87 166.81,170.78 167.07,170.52 168.52,170.52 168.66,170.38 168.94,170.38 169,170.32 169.68,170.32 169.99,170.62 171.62,170.62 172.73,169.51 172.73,167.71 172.19,167.17 171.21,167.17 ; VRAM7.P7 171.53,166.85 171.21,167.17 ; VRAM6.P7 192.8,152.33 193.07,152.06 v2(193.17,152.06) ; 171.21,167.17 v2(171.2,167.17) ; VRAM8.P7 157.85,167.02 157.85,167.11 v2(158.24,167.5) ; VRAM5.P7 v2(193.2,138.92) ; v2(169.88,147.23) 169.47,146.83 GPU1.K22
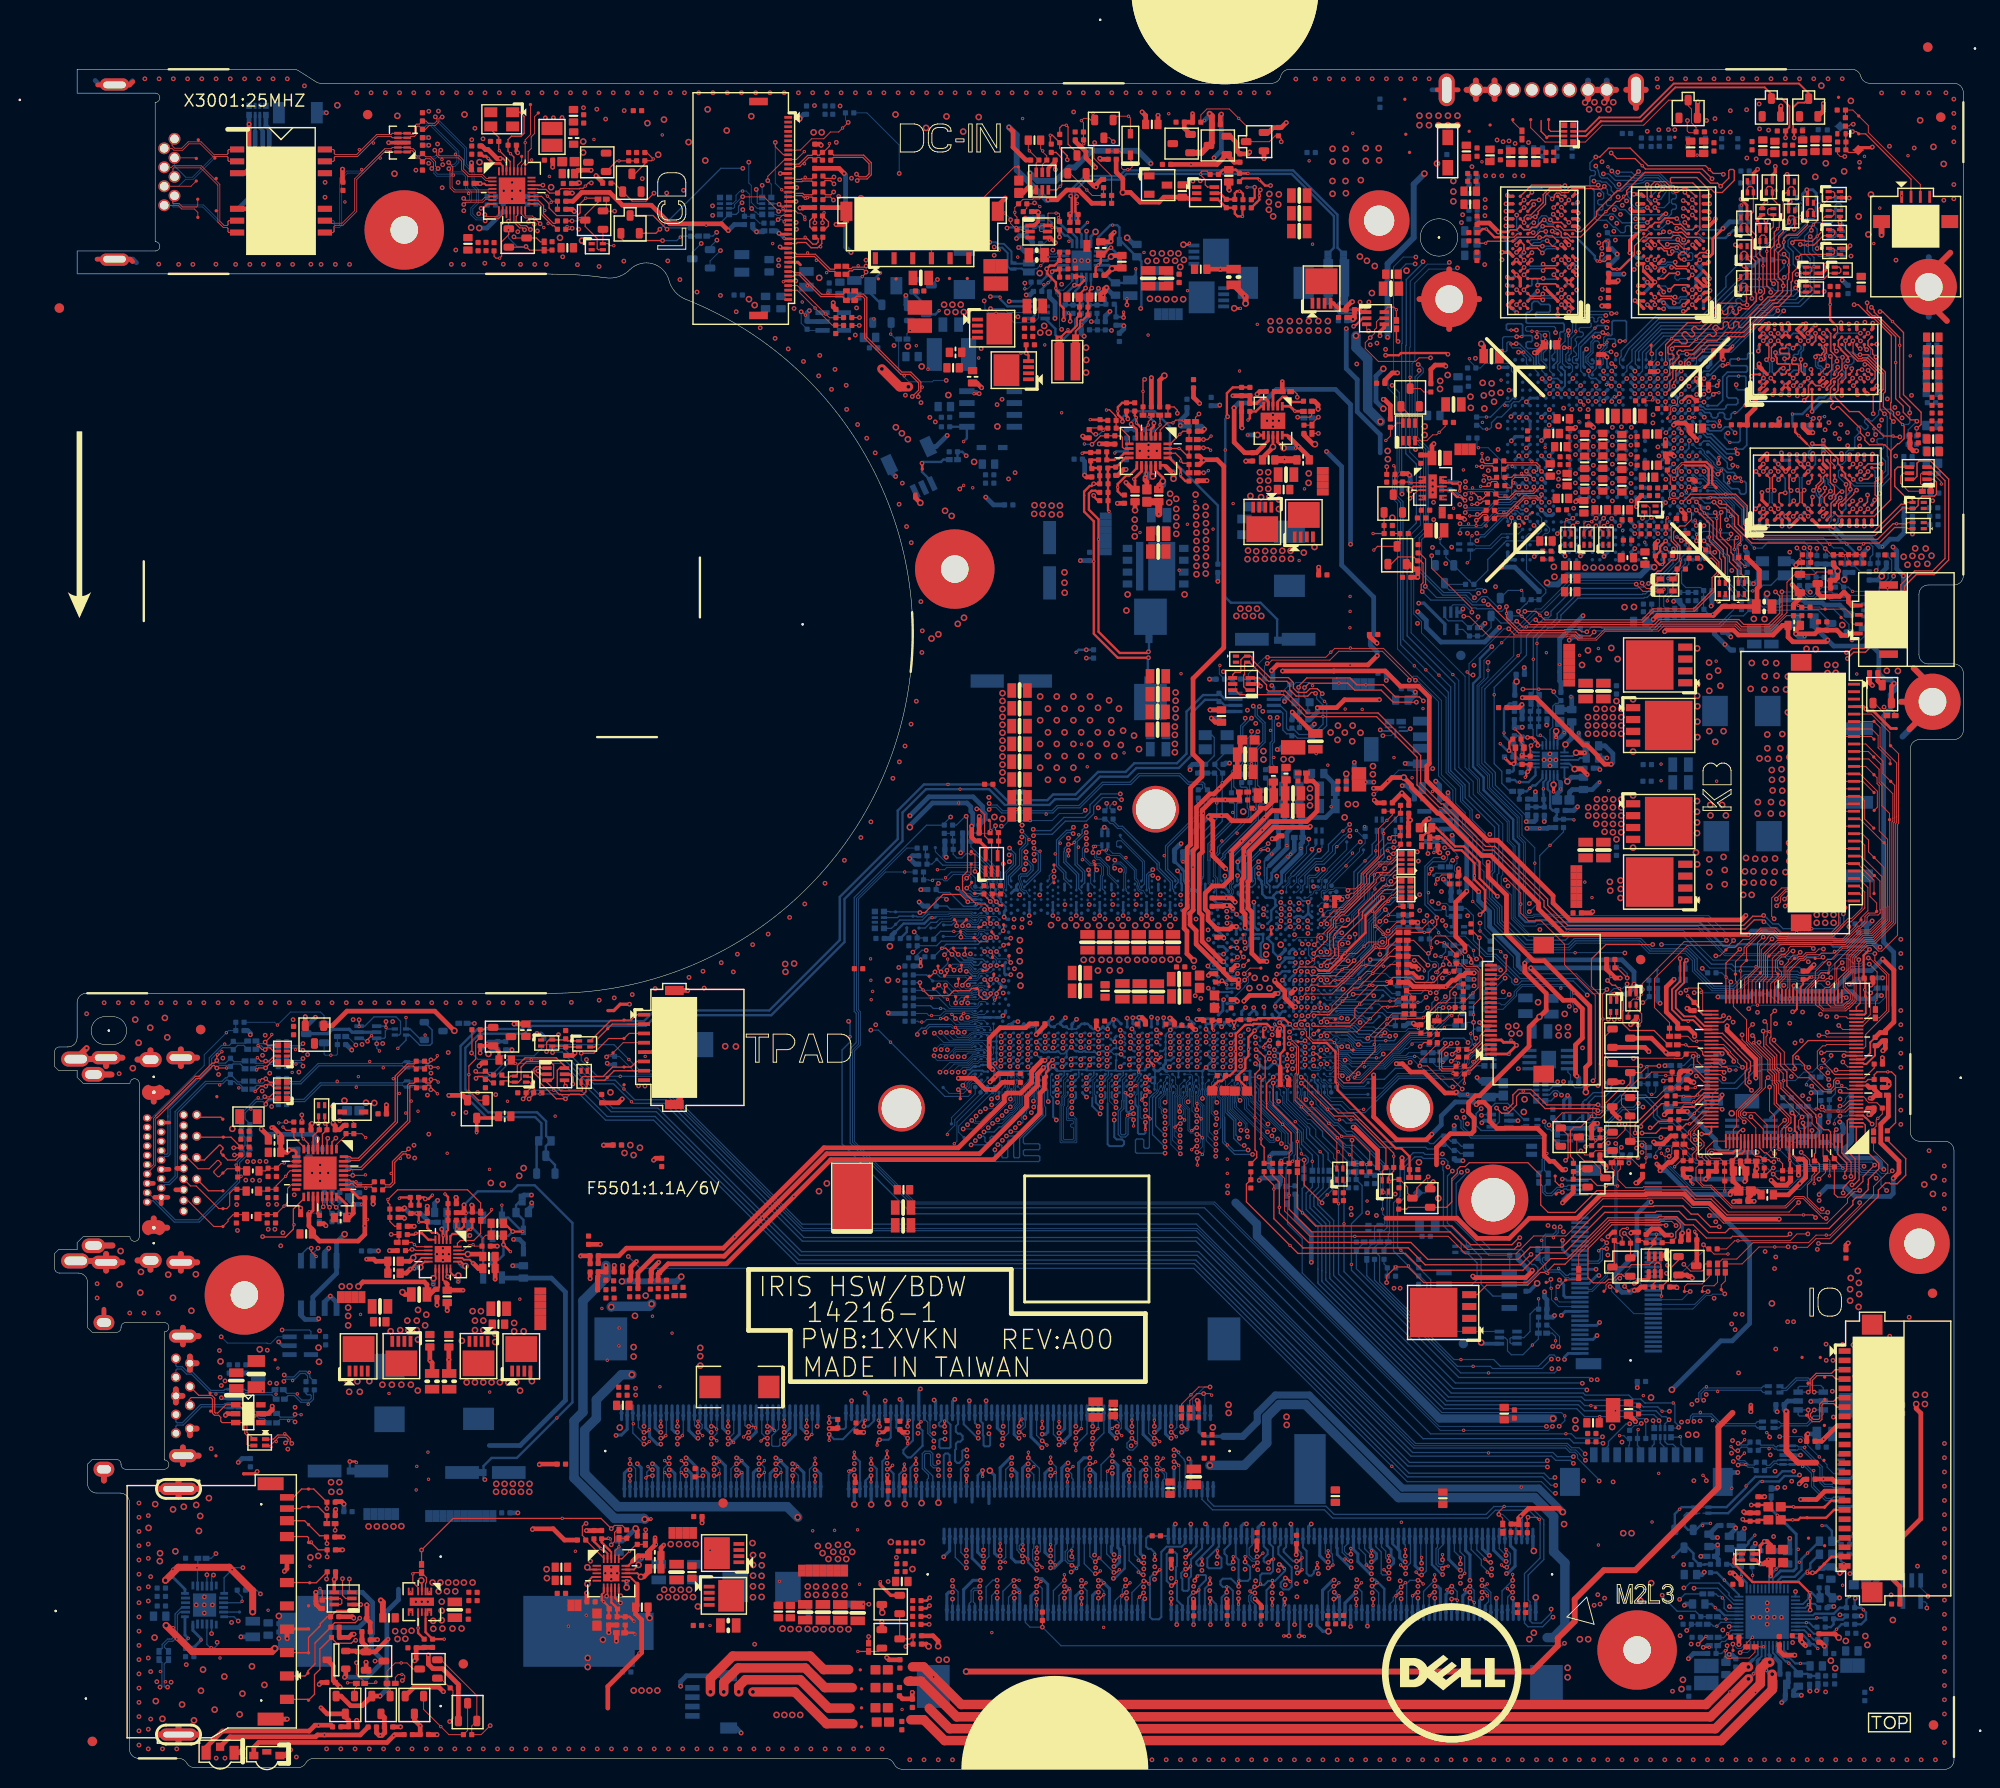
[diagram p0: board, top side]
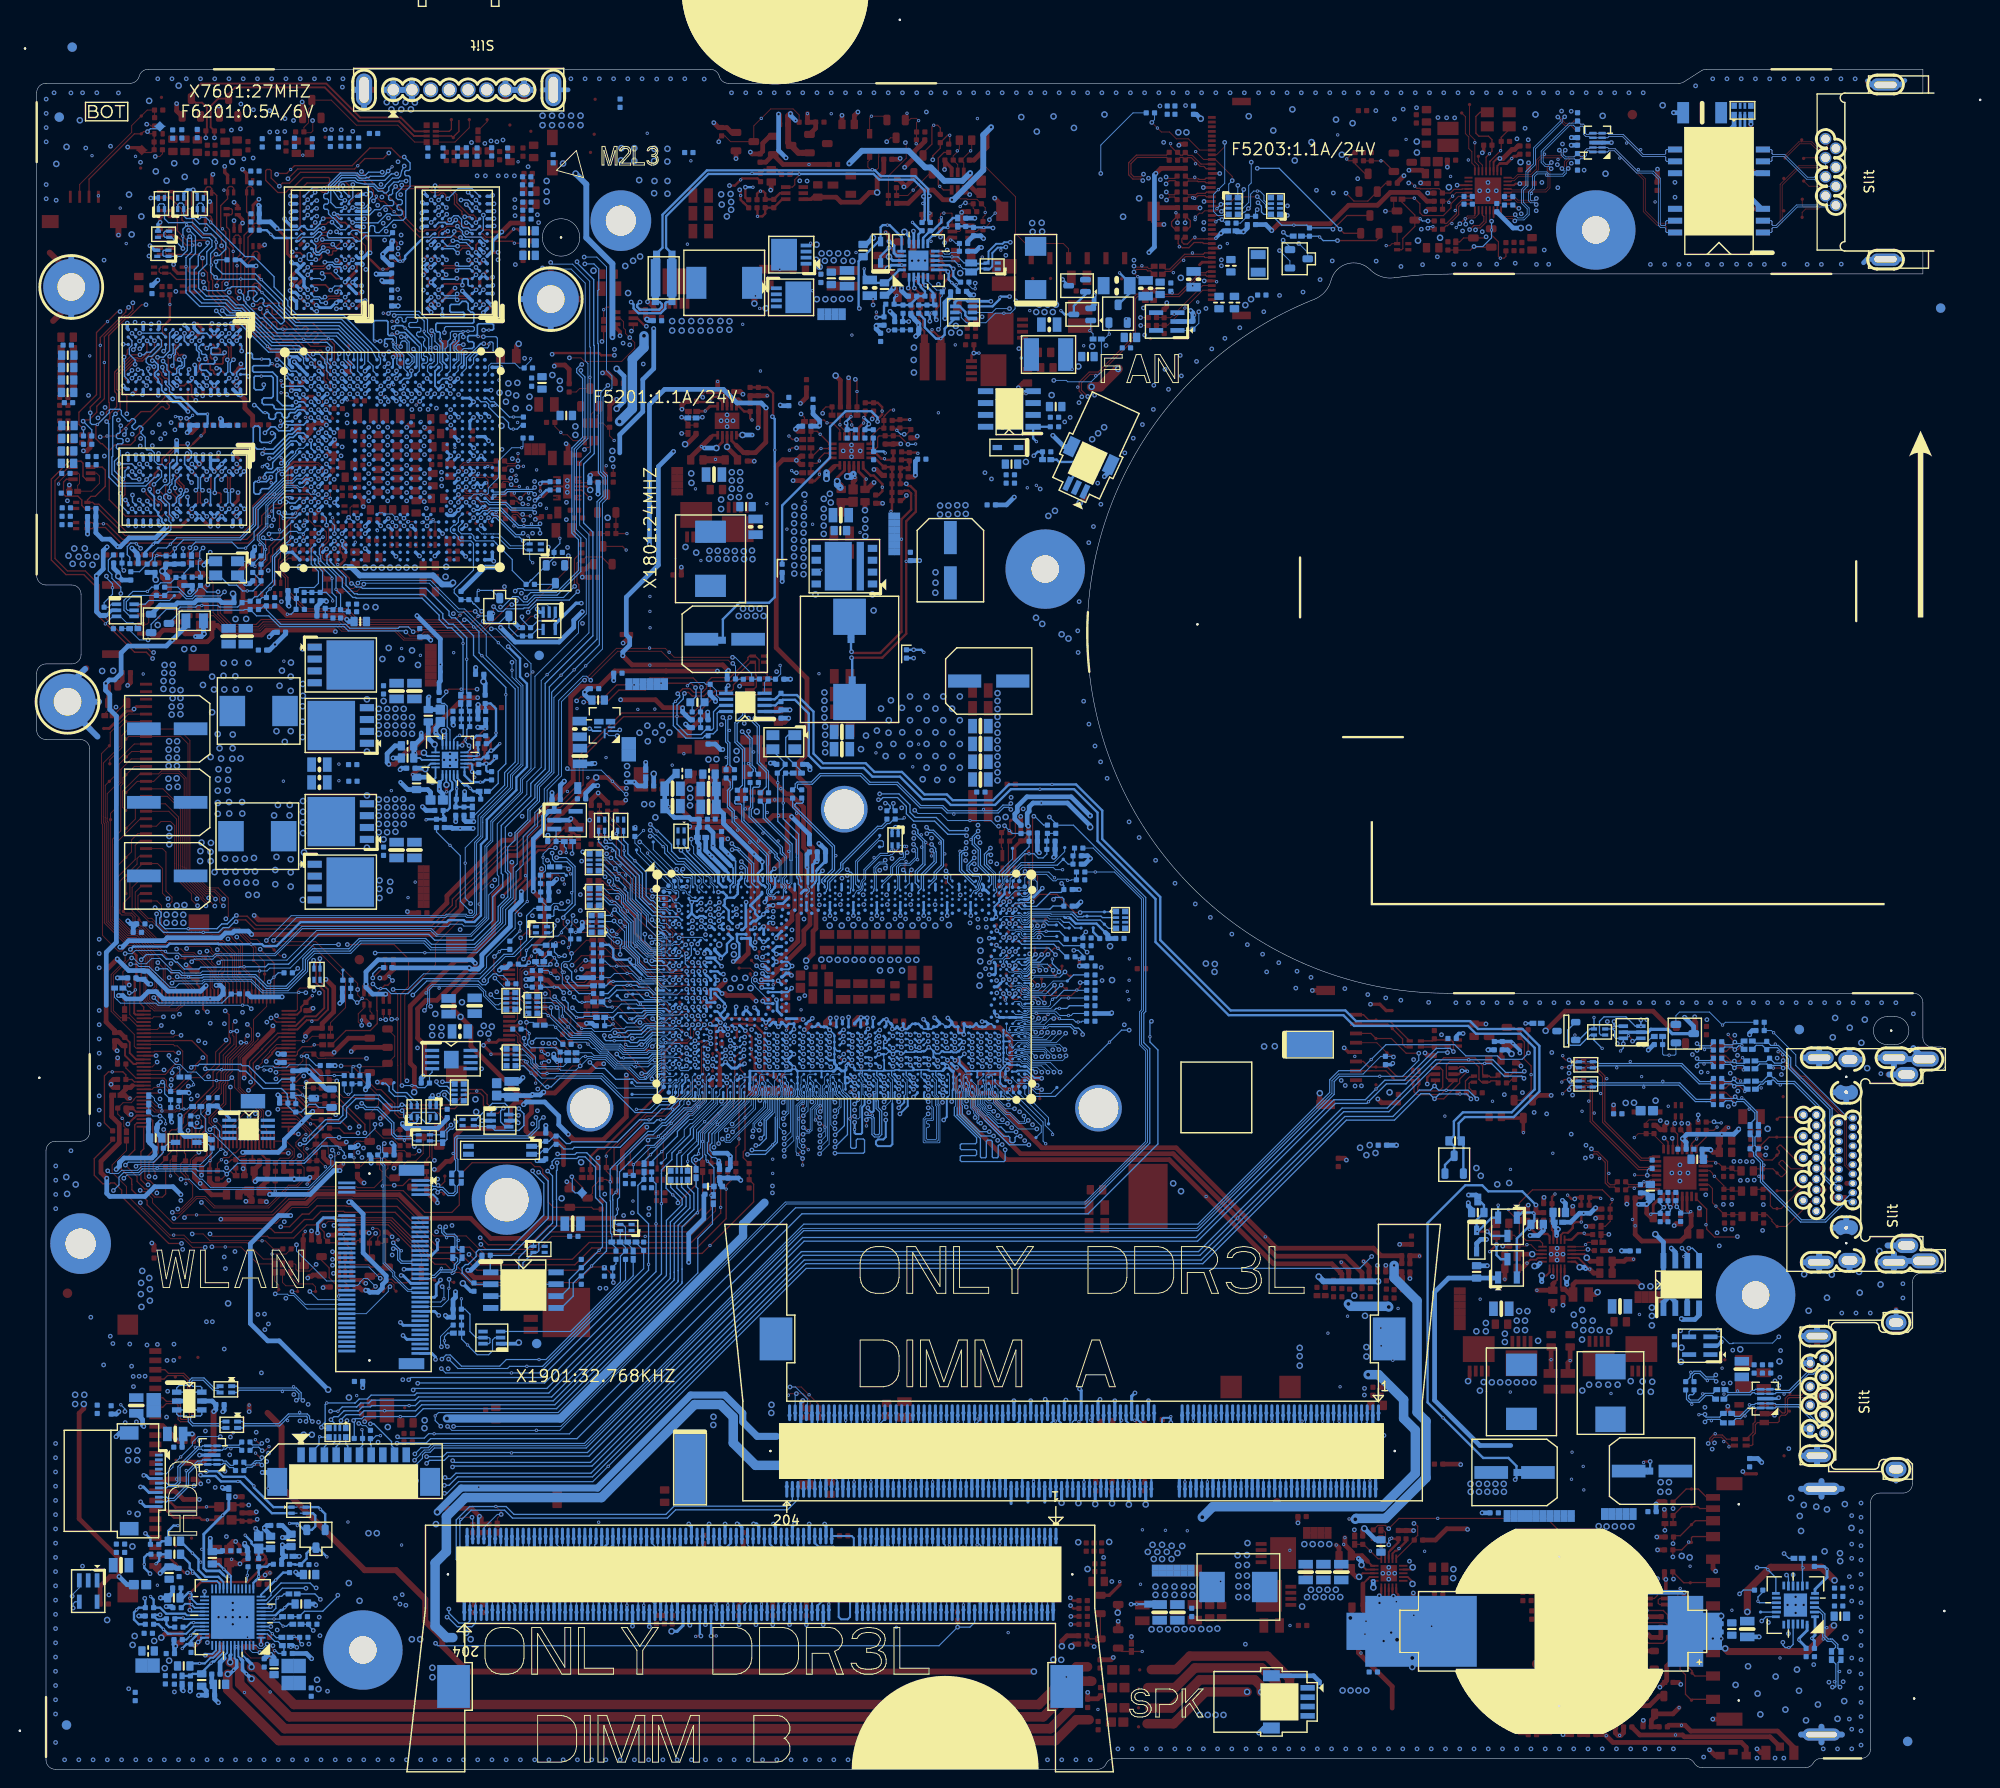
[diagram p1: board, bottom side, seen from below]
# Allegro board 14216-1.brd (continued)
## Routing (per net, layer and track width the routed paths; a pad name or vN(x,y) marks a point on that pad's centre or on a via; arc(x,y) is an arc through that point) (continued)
FBA_CMD25: length 112.4
  TOP w0.14: VRAM8.L3 160.49,164.37 v2(160.21,164.64) ; RN7511.2 183.08,164.04 182.91,164.22 182.61,164.22 182.43,164.04 RN7511.1 182.43,162.1 182.77,161.77 v1(182.77,160.94) 182.77,158.63 182.93,158.47 182.93,158.02 182.55,157.64 v2(182.55,157.47) ; v2(190.76,150.09) 190.76,149.95 190.4,149.6 VRAM6.L3 ; v2(173.54,164.94) 174.03,164.94 174.6,164.37 VRAM7.L3 ; v2(191.04,136.1) 190.61,135.67 190.61,135.53 VRAM5.L3
  L3 w0.127: v2(166.81,164.64) 166.93,164.52 167.24,164.52 168.53,163.23 169.24,163.23 170.47,162 172.23,162 172.55,161.69 172.55,160.6 172.8,160.35 172.8,160.05 173.31,159.55 175.37,159.55 176.71,160.88 177.71,160.88 180.51,158.08 181.94,158.08 v2(182.55,157.47) 182.95,157.06 184.64,157.06 186.48,155.22 186.48,153.41 185.57,152.5 185.57,151.95 186,151.52 186.82,151.52 187.29,151.05 187.29,150.99 188.02,150.27 188.07,150.27 188.76,149.57 188.76,147.46 190.63,145.59 190.63,143.71 190.94,143.41 v2(190.94,142.42)
  L4 w0.127: v2(190.76,150.09) 191.33,149.51 191.33,147.82 190.64,147.13 190.64,143.53 190.97,143.19 190.97,142.46 v2(190.94,142.42) 190.94,142.01 191.01,141.94 191.01,141.42 190.91,141.32 190.53,141.32 190.4,141.19 190.4,140.54 190.53,140.41 191.11,140.41 191.24,140.29 191.24,137.84 190.67,137.26 190.67,136.47 v2(191.04,136.1) ; v2(170.71,148.07) 171.1,148.46 171.1,149.46 171.05,149.51 171.05,150.66 171.31,150.92 172.9,150.92 174.28,152.3 174.93,152.3 175.38,152.75 176.56,152.75 178.13,154.32 179.59,154.32 180.16,154.89 180.16,155.07 179.92,155.31 179.74,155.31 179.28,154.85 179.1,154.85 178.89,155.07 178.89,155.25 179.71,156.07 179.89,156.07 180.59,155.38 180.78,155.38 181.68,156.29 181.68,156.75 181.68,156.75 181.12,157.3 181.12,157.63 181.42,157.93 182.09,157.93 v2(182.55,157.47) ; v2(173.54,164.94) 173.12,164.94 173.04,165.02 171.85,165.02 171.31,164.48 169.98,164.48 169.72,164.22 168.25,164.22 167.83,164.64 v2(166.81,164.64) 166.74,164.7 163.27,164.7 163.18,164.61 161.59,164.61 161.46,164.74 161.46,165.08 161.31,165.23 161.1,165.23 160.95,165.08 160.95,164.74 160.83,164.61 160.25,164.61 v2(160.21,164.64)
  BOTTOM w0.14: v2(170.71,148.07) 170.31,147.67 GPU1.J23 ; v2(160.21,164.64) 160.53,164.64 VRAM8.L3 ; v2(191.04,136.1) 191.04,135.96 VRAM5.L3 ; v2(190.76,150.09) 190.76,149.99 190.67,149.9 190.67,149.58 VRAM6.L3 ; VRAM7.L3 174.58,164.37 174.01,164.94 v2(173.54,164.94)
FBA_CMD26: length 125.6
  TOP w0.14: RN7508.1 190.23,166.86 190.36,166.73 190.36,166.42 190.14,166.21 RN7508.2 189.4,166.21 189.14,165.95 189.14,164.68 v1(188.57,164.11) 188.03,163.57 187.32,163.57 187.21,163.67 186.18,163.67 v2(185.91,163.4) ; VRAM5.P8 v2(193.2,139.72) ; VRAM6.P8 192.8,153.28 v2(193.2,152.88) ; VRAM8.P8 156.8,166.77 v2(157.2,167.17) ; VRAM7.P8 170.79,166.77 v2(170.39,167.17)
  L3 w0.127: v2(164.68,170.01) 164.68,170 166.73,170 167.11,170.38 169.74,170.38 169.94,170.59 176.14,170.59 176.92,169.8 177.38,169.8 177.38,169.8 177.71,169.8 177.81,169.9 178.39,169.9 178.67,169.62 178.67,169.11 180.63,167.16 182.63,165.75 182.71,165.4 v2(185.91,163.4) 186.7,162.61 186.75,162.61 187.04,162.32 187.22,162.32 187.44,162.54 187.62,162.54 187.8,162.36 187.8,162.18 187.58,161.96 187.58,161.78 187.76,161.6 187.94,161.6 188.16,161.82 188.34,161.82 188.52,161.64 188.52,161.46 188.3,161.25 188.3,161.07 191.32,158.04 191.5,158.04 191.61,158.16 191.79,158.16 191.97,157.98 191.97,157.8 191.86,157.68 191.86,157.5 191.97,157.4 191.97,156.69 192.32,156.33 193.54,156.33 194.08,155.79 194.81,155.79 195.67,154.93 195.67,154.01 196.29,153.4 196.29,146.91 v2(196.07,146.69)
  L4 w0.127: v2(164.68,170.01) 164.63,169.96 161.34,169.96 160.7,169.32 160.7,169.19 158.54,167.03 157.77,167.03 157.62,167.17 v2(157.2,167.17) ; v2(193.2,139.72) 193.58,139.72 194.06,140.2 194.06,141.07 194.51,141.52 194.68,141.52 195.58,142.42 195.58,143.57 195.88,143.87 195.88,144.56 196.19,144.87 196.19,145.89 196.55,146.24 196.55,146.56 196.43,146.69 v2(196.07,146.69) 196.07,149.43 195.48,150.01 195.48,151.12 195.02,151.58 194.67,151.58 194.06,150.97 193,150.97 192.7,151.27 192.7,152.39 v2(193.2,152.88)
  BOTTOM w0.14: v2(193.2,152.88) 192.8,153.28 VRAM6.P8 ; GPU1.J25 170.63,149.63 170.63,150.24 171.32,150.92 171.32,151.89 172.51,153.07 178.92,153.07 182.24,156.39 182.65,156.39 182.95,156.39 183.88,157.32 186.26,157.32 187.34,158.4 187.34,160.52 186.91,160.95 186.91,161.99 186.81,162.09 186.81,162.2 185.91,163.1 v2(185.91,163.4) ; VRAM5.P8 v2(193.2,139.72) ; v2(157.2,167.17) 156.8,166.77 VRAM8.P8 ; VRAM7.P8 170.8,166.77 170.42,167.16 170.4,167.16 v2(170.39,167.17) 169.91,167.17 169.84,167.11 169.13,167.11 168.6,167.63 168.6,168.06 168.29,168.37 168.29,168.73 168.41,168.86 168.62,168.86 168.8,169.04 168.8,169.31 168.67,169.44 168.18,169.44 167.66,168.92 167.21,168.92 167.02,168.73 166.8,168.73 166.53,169 166.53,169.34 165.98,169.89 165.5,169.89 165.38,170.01 164.68,170.01 v2(164.68,170.01)
FBA_CMD27: length 128.9
  TOP w0.14: v2(193.15,151.41) 194,151.41 195.86,149.55 195.86,147.47 195.64,147.25 195.64,145.85 196.37,145.12 196.37,144.61 v2(196.72,144.26) ; RN7521.1 190.3,164.82 190.44,164.68 190.44,164.33 190.28,164.17 RN7521.2 189.23,164.17 188.22,163.15 v1(187.52,163.15) 186.82,163.15 v2(186.75,163.22)
  L3 w0.127: v2(158.24,165.55) 158.41,165.55 159.69,166.83 159.69,168.19 159.77,168.26 159.77,168.27 160.01,168.52 160.02,168.52 160.36,168.86 161.53,168.86 162.75,170.08 163.97,170.08 164.37,170.47 165.36,170.47 165.5,170.33 166.61,170.33 v2(167.23,170.96) 168.42,170.96 168.77,170.61 169.63,170.61 169.91,170.89 177.43,170.89 178.04,170.28 179.23,170.28 179.64,169.87 179.64,169.69 179.21,169.26 179.21,169.08 179.39,168.9 179.57,168.9 180,169.33 180.18,169.33 180.99,168.52 180.99,167.96 182.7,166.25 183.43,166.25 185.69,163.98 185.99,163.98 v2(186.75,163.22) 187.04,162.93 187.73,162.93 189.1,161.57 189.1,160.87 191.12,158.85 191.61,158.85 192.79,157.67 192.79,157.48 194.19,156.07 194.63,156.07 195.01,156.45 195.45,156.45 195.9,156.01 195.9,154.15 196.52,153.53 196.52,146.48 196.23,146.19 196.23,144.73 196.7,144.26 v2(196.72,144.26)
  L4 w0.127: v2(186.75,163.22) 186.38,162.84 185.05,162.84 176.19,153.99 175.33,153.99 174.39,153.05 173.45,153.05 172.36,151.96 171.67,151.96 171.29,151.58 171.29,151.35 170.68,150.73 v2(170.68,148.88)
  BOTTOM w0.14: v2(196.72,144.26) 196.48,144.02 196.48,138.33 195.52,137.37 192.53,137.37 191.62,138.27 191.45,138.27 VRAM1.M3 ; VRAM2.M3 192.02,151.69 192.45,151.69 192.72,151.41 v2(193.15,151.41) ; VRAM4.M3 157.98,165.55 v2(158.24,165.55) ; VRAM3.M3 172.05,165.62 172.05,165.65 172.48,166.08 172.55,166.08 172.97,166.5 172.97,166.85 173.11,166.99 173.35,166.99 173.49,167.12 173.49,167.4 173.35,167.54 173.11,167.54 172.97,167.68 172.97,167.96 173.11,168.1 173.35,168.1 173.49,168.24 173.49,168.52 173.35,168.66 173.11,168.66 172.97,168.8 172.97,169.61 171.72,170.87 169.89,170.87 169.63,170.6 169.06,170.6 168.7,170.96 v2(167.23,170.96) ; GPU1.J24 170.27,148.47 v2(170.68,148.88)
FBA_CMD28: length 110.3
  TOP w0.14: v2(181.59,157.44) 181.55,157.48 181.55,161.26 181.06,161.75 RN7515.2 181.06,162.28 180.87,162.47 180.6,162.47 180.41,162.28 RN7515.1 ; VRAM7.L7 171.91,164.37 v2(172.12,164.58) ; VRAM8.L7 157.72,164.49 v2(158.18,164.49) ; VRAM5.L7 190.4,138.02 v2(190.48,137.94) ; v2(190.63,151.8) 190.4,152.03 VRAM6.L7
  L3 w0.127: v2(165.21,164.23) 165.33,164.11 167.17,164.11 168.39,162.89 168.9,162.89 169,162.79 169,162.13 169.86,161.27 169.86,160.71 170.23,160.35 171.03,160.35 171.04,160.34 171.33,160.34 171.85,159.82 172.6,159.82 173.1,159.32 175.47,159.32 176.6,160.45 177.64,160.45 180.65,157.44 v2(181.59,157.44) 181.91,157.44 182.95,156.4 183.13,156.4 183.23,156.5 183.41,156.5 183.59,156.32 183.59,156.14 183.49,156.04 183.49,155.86 183.81,155.53 185.68,155.53 186.25,154.97 186.25,153.5 185.28,152.54 185.28,151.83 185.72,151.4 185.72,150.79 187.17,149.33 187.77,149.33 188.54,148.57 188.54,147.28 190.14,145.68 190.14,144.54 190.29,144.39 190.29,143.58 190.48,143.4 v2(190.48,142.98)
  L4 w0.127: v2(190.63,151.8) 190.39,151.57 190.39,151.04 190.26,150.91 190.26,150.57 190.34,150.49 190.34,149.88 191.1,149.11 191.1,147.93 190.27,147.11 190.27,143.18 v2(190.48,142.98) 190.48,142.2 190.71,141.97 190.71,141.7 190.57,141.56 190.34,141.56 190.14,141.36 190.14,140.21 190.27,140.08 190.89,140.08 191.01,139.96 191.01,139.7 190.89,139.57 190.27,139.57 190.14,139.45 190.14,139.19 190.27,139.07 190.87,139.07 191,138.94 191,138.68 190.87,138.56 190.27,138.56 190.14,138.43 190.14,138.1 190.31,137.94 v2(190.48,137.94) ; v2(172.12,164.58) 171.72,164.18 170.07,164.18 169.88,163.99 168.04,163.99 167.71,164.31 167.08,164.31 166.98,164.21 166.66,164.21 166.64,164.23 v2(165.21,164.23) 164.79,164.23 164.77,164.21 159.71,164.21 159.7,164.2 159.35,164.2 159.04,164.51 158.62,164.51 158.6,164.49 v2(158.18,164.49)
  BOTTOM w0.14: v2(172.12,164.58) 171.91,164.37 VRAM7.L7 ; VRAM8.L7 157.74,164.51 158.16,164.51 v2(158.18,164.49) ; v2(190.63,151.8) 190.4,152.03 VRAM6.L7 ; v2(190.48,137.94) 190.48,138.44 VRAM5.L7 ; v2(181.59,157.44) 181.59,158.16 181.48,158.27 180.86,158.27 180.64,158.04 180.64,157.9 181.04,157.5 181.04,157.32 180.82,157.11 180.64,157.11 180.28,157.47 180.06,157.47 179.86,157.26 179.86,157.1 179.97,156.99 179.97,156.79 179.77,156.59 179.58,156.59 179.45,156.71 179.25,156.71 177.7,155.16 177.7,154.98 177.96,154.73 178.14,154.73 179.42,156.01 179.6,156.01 179.85,155.76 179.85,155.58 178.43,154.15 v1(177.86,154.15) 176.69,154.15 171.89,154.15 169.47,151.74 GPU1.K27
FBA_CMD29: length 122.8
  TOP w0.14: VRAM8.M2 161.18,165.59 160.28,165.59 v2(160.01,165.85) ; v2(172.6,165.6) 173.03,165.6 173.26,165.37 173.98,165.37 174.53,164.82 175.25,164.82 VRAM7.M2 ; VRAM5.M2 190.85,134.87 190.85,135.46 191.06,135.67 191.21,135.67 191.65,136.11 v2(191.65,137.53) ; v2(182.47,158.2) 182.36,158.32 v1(182.36,159.53) 182.36,161.6 182.01,161.95 182.01,164.21 181.55,164.67 181.55,166.54 181.74,166.73 RN7516.2 181.74,169.25 181.56,169.42 181.27,169.42 181.09,169.25 RN7516.1 ; v2(191.65,150.14) 191.63,150.12 191.63,148.94 VRAM6.M2
  L3 w0.127: v2(191.09,143.94) 190.97,144.07 190.97,145.59 189.67,146.89 189.67,149.04 188.21,150.49 188.14,150.49 187.57,151.06 187.57,151.27 186.93,151.91 186.53,151.91 186.41,152.03 186.41,152.34 186.53,152.47 187.06,152.47 187.19,152.59 187.19,153.08 186.7,153.57 186.7,155.4 184.51,157.6 183.35,157.6 182.75,158.2 v2(182.47,158.2) 182.19,158.49 180.61,158.49 177.22,161.87 176.59,161.87 176.42,162.05 173.55,162.05 173.25,161.75 172.84,161.75 172.3,162.28 170.52,162.28 169.26,163.54 168.71,163.54 167.35,164.91 167.13,164.91 166.96,165.08 166.05,165.08 v2(165.94,165.19) 165.43,165.19 164.55,164.31 161.56,164.31 v2(160.01,165.85)
  L4 w0.127: v2(191.65,150.14) 191.56,150.05 191.56,147.29 191.62,147.23 191.62,146.88 191.09,146.35 v2(191.09,143.94) 191.09,143.56 191.36,143.3 191.36,142.67 191.38,142.64 191.38,142.27 191.38,141.36 191.58,141.16 191.58,140.68 191.57,140.67 191.57,137.61 v2(191.65,137.53) ; v2(172.6,165.6) 171.81,165.6 171.01,164.81 169.94,164.81 169.58,164.45 168.6,164.45 167.98,165.07 166.84,165.07 166.72,165.19 v2(165.94,165.19)
  BOTTOM w0.14: v2(182.47,158.2) 182.06,157.79 182.06,157.33 182.06,157.32 182.06,157.3 181.82,157.06 181.82,156.9 180.26,155.34 180.07,155.34 178.48,153.75 171.96,153.75 169.87,151.66 169.87,149.67 GPU1.K25 ; v2(160.01,165.85) 159.58,166.29 159.12,166.29 158.74,165.91 158.74,165.17 158.56,165 158.03,165 157.8,164.77 157.2,164.77 VRAM4.M2 ; v2(191.65,137.53) 190.84,138.34 190.84,138.96 VRAM1.M2 ; VRAM2.M2 190.85,152.96 190.85,152.29 191.91,151.24 192.22,151.24 192.49,150.97 192.49,150.63 192.22,150.36 192.01,150.36 191.79,150.14 v2(191.65,150.14) ; VRAM3.M2 171.18,164.79 171.7,164.79 171.73,164.82 171.74,164.82 171.93,165 172,165 v2(172.6,165.6)
FBA_CMD30: length 129.3
  TOP w0.14: VRAM6.M3 191.2,149.12 190.8,148.71 190.8,147.59 190.49,147.28 190.49,146.85 192.01,145.33 193.03,145.33 195.64,142.72 v1(196.68,142.72) 196.77,142.62 v2(197.4,142.62) ; VRAM5.M3 191.29,135.32 192.48,136.51 192.48,136.62 v2(192.78,136.92) ; v2(174.39,165.58) 174.39,165.58 VRAM7.M3 ; VRAM8.M3 161.06,165.17 161.46,164.77 162.63,164.77 162.79,164.6 163.3,164.6 164.94,166.25 164.94,166.75 166.79,168.59 166.79,168.61 167.19,169 167.42,169 v2(169.45,171.03)
  L3 w0.127: v2(197.4,142.62) 197.4,144.18 196.46,145.12 196.46,145.99 196.75,146.27 196.75,153.63 196.13,154.24 196.13,156.44 195.76,156.81 194.86,156.81 193.67,158 192.92,158 191.72,159.21 191.72,159.62 188.95,162.4 v2(188.55,162.79) 188.07,163.27 187.35,163.27 186.29,164.34 185.94,164.34 183.66,166.62 182.91,166.62 181.52,168.01 181.52,168.55 178.92,171.15 169.57,171.15 v2(169.45,171.03)
  L4 w0.127: v2(169.45,171.03) 169.73,171.31 172.58,171.31 175.65,168.24 175.65,166.19 175.04,165.58 v2(174.39,165.58) ; v2(192.78,136.92) 193.25,137.39 194.99,137.39 197.4,139.81 v2(197.4,142.62)
  BOTTOM w0.14: GPU1.J27 170.27,151.56 172.12,153.42 178.79,153.42 182.13,156.76 182.86,156.76 183.8,157.69 186.04,157.69 186.88,158.53 186.88,160.24 186,161.12 186,162.43 185.45,162.99 185.45,163.66 185.73,163.94 186.47,163.94 187.71,165.18 188.23,165.18 188.55,164.86 v2(188.55,162.79) 189.75,163.99 RN7502.1 190.46,163.99 190.59,164.13 190.59,164.48 190.44,164.64 RN7502.2
FBA_CMD31: length 2.6
  TOP w0.14: TP7504.1 170.8,151.6 v2(170.87,151.52)
  BOTTOM w0.14: GPU1.J26 170.27,150.3 170.87,150.9 v2(170.87,151.52)
FBA_D0: length 23.1
  TOP w0.178: v1(173.79,143.56) 174.06,143.29 v2(174.06,143.06) ; VRAM6.F2 186.4,148.5 v2(186,148.11)
  L4 w0.165: v2(186,148.11) 186.23,148.11 186.36,147.97 186.36,147.68 186,147.32 186,146.83 185.52,146.36 183.86,146.36 183.69,146.19 183.69,145.8 183.82,145.67 184.96,145.67 185.08,145.54 185.08,144.22 184.96,144.09 181.67,144.09 181.51,143.92 181.51,143.58 181.34,143.41 181.01,143.41 180.85,143.58 180.85,143.92 180.68,144.09 179.58,144.09 179.45,144.22 177.21,144.22 177.01,144.02 177.01,143.54 176.88,143.41 176.6,143.41 176.32,143.69 175.84,143.69 175.63,143.48 174.23,143.48 174.06,143.31 v2(174.06,143.06)
  BOTTOM w0.178: v2(186,148.11) 186.4,148.5 VRAM6.F2 ; v2(174.06,143.06) 174.06,143.08 GPU1.E18
FBA_D1: length 22.9
  TOP w0.178: v2(186,148.91) 185.6,149.31 VRAM6.E3
  L4 w0.102: 173.56,143.46 172.77,143.46 v2(172.38,143.07)
  L4 w0.165: v2(186,148.91) 186,149.07 185.86,149.2 185.58,149.2 184.75,148.37 184.75,147.94 184.76,147.94 184.76,147.93 185.02,147.67 185.03,147.67 185.12,147.58 185.12,146.85 184.98,146.71 183.59,146.71 182.71,145.82 182.71,145.37 182.85,145.23 183.93,145.23 184.05,145.1 184.05,144.57 183.93,144.45 179.79,144.45 179.6,144.63 177.08,144.63 176.64,144.19 175.86,144.19 175.42,143.75 173.84,143.75 173.56,143.46
  BOTTOM w0.178: v2(186,148.91) VRAM2.F7 ; v2(172.38,143.07) 172.39,143.07 GPU1.F18
FBA_D2: length 24.4
  TOP w0.178: v2(187.9,149.85) 188,149.74 VRAM6.H3
  L4 w0.165: v2(187.9,149.85) 187.9,149.67 188.38,149.19 188.38,146.34 187.08,145.03 186.13,145.03 185.98,144.88 185.98,143.98 185.29,143.3 185.11,143.3 184.95,143.13 184.95,142.76 184.78,142.6 184.45,142.6 184.29,142.76 184.29,143.13 184.12,143.3 183.79,143.3 183.63,143.13 183.63,142.76 183.46,142.6 183.13,142.6 182.97,142.76 182.97,143.13 182.8,143.3 182.34,143.3 181.54,142.51 178.74,142.51 178.61,142.64 176.48,142.64 176.15,142.97 175.01,142.97 174.27,142.23 v2(174.06,142.23)
  BOTTOM w0.178: v2(174.06,142.23) 174.06,142.22 GPU1.E16 ; VRAM6.H3 188,149.74 v2(187.9,149.85)
FBA_D3: length 23.8
  TOP w0.178: VRAM6.G2 v2(187.6,148.91)
  L4 w0.102: v2(173.24,143.06) 173.64,142.65 174.24,142.65 174.8,143.21 176.4,143.21 176.61,143
  L4 w0.165: 176.61,143 176.66,142.95 177.95,142.95 178.68,143.68 180.09,143.68 180.69,143.09 181.6,143.09 182.18,143.67 185.1,143.67 185.49,144.06 185.49,145.85 185.62,145.97 186.12,145.97 186.24,145.85 186.24,145.65 186.41,145.48 186.74,145.48 186.9,145.65 186.9,145.92 187.07,146.09 187.4,146.09 188.12,146.81 188.12,147.6 187.88,147.84 187.88,148.16 188.12,148.4 188.12,148.79 188,148.91 v2(187.6,148.91)
  BOTTOM w0.178: v2(173.24,143.06) 173.22,143.06 GPU1.F17 ; VRAM2.H8 187.74,148.51 187.6,148.65 v2(187.6,148.91)
FBA_D4: length 22
  TOP w0.178: VRAM6.H7 188.4,152.91 188.4,153.7 v2(188.39,153.71)
  L4 w0.102: 178.04,146.22 177.17,146.22 176.87,145.93 175.43,145.93 175.03,145.52 v2(174.87,145.52)
  L4 w0.165: 178.04,146.22 179.23,146.22 180.37,147.36 180.37,148.76 181.6,149.99 183.53,149.99 184.41,150.87 184.41,150.98 184.9,151.46 185.54,151.46 185.59,151.41 187.5,151.41 188.4,152.31 188.4,153.71 188.4,153.71 v2(188.39,153.71)
  BOTTOM w0.178: v2(188.39,153.71) 188.4,153.7 188.4,152.91 VRAM6.H7 ; GPU1.D20 174.84,145.52 v2(174.87,145.52)
FBA_D5: length 18.6
  TOP w0.178: VRAM6.F7 186.37,152.51 v2(185.99,152.12)
  L4 w0.102: 177.69,147.63 177.55,147.63 177.18,148 175.93,148 175.26,147.33 175.26,146.8 v2(174.84,146.38)
  L4 w0.165: v2(185.99,152.12) 186.01,152.15 186.01,153.1 185.88,153.23 185.47,153.23 185.34,153.1 185.34,152.15 185.21,152.02 184.81,152.02 184.42,152.4 182.18,152.4 181.82,152.04 181.82,151.36 178.09,147.63 177.69,147.63
  BOTTOM w0.178: VRAM2.E3 185.98,152.12 v2(185.99,152.12) ; v2(174.84,146.38) 174.84,146.36 GPU1.D21
FBA_D6: length 22.4
  TOP w0.178: VRAM6.H8 188,153.3 187.61,152.91 v2(187.61,152.88)
  L4 w0.102: 176.81,146.75 175.83,146.75 175.02,145.95 173.38,145.95 173.27,145.85 v2(173.27,145.54)
  L4 w0.165: 176.81,146.75 177.09,146.75 177.14,146.71 177.75,146.71 178.36,147.32 178.59,147.32 179.07,146.84 179.25,146.84 179.54,147.13 179.54,147.31 179.06,147.79 179.06,148.02 182.44,151.41 183.3,151.41 183.49,151.59 183.49,152.01 183.61,152.14 184.31,152.14 184.72,151.73 185.65,151.73 185.7,151.68 187.39,151.68 187.88,152.17 187.88,152.61 v2(187.61,152.88)
  BOTTOM w0.178: GPU1.F20 173.22,145.54 v2(173.27,145.54) ; VRAM2.G2 187.2,153.31 187.61,152.9 v2(187.61,152.88)
FBA_D7: length 21.7
  TOP w0.178: v2(186.77,152.91) 186.77,152.94 VRAM6.F8
  L4 w0.102: v2(173.17,146.41) 173.45,146.41 173.58,146.53 173.58,147.49 173.71,147.62 174.39,147.62
  L4 w0.165: 174.39,147.62 174.44,147.58 175.07,147.58 175.33,147.83 175.33,148 175.72,148.39 177.5,148.39 177.66,148.56 178.44,148.56 181.51,151.62 181.51,152.11 182.21,152.81 182.21,153.76 182.65,154.2 185.48,154.2 185.76,153.93 185.99,153.93 186.25,154.19 186.43,154.19 186.72,153.9 186.72,153.72 186.46,153.46 186.46,153.22 v2(186.77,152.91)
  BOTTOM w0.178: GPU1.E21 173.21,146.41 v2(173.17,146.41) ; VRAM6.F8 186.77,152.94 v2(186.77,152.91)
FBA_D8: length 19.5
  TOP w0.178: v2(186,138.92) 186.4,139.31 VRAM5.F8
  L4 w0.165: v2(174.06,141.41) 174.11,141.45 177.9,141.45 178.06,141.29 180.48,141.29 180.64,141.12 180.64,140.58 180.77,140.45 181.17,140.45 181.3,140.58 181.3,141.12 181.47,141.29 181.8,141.29 181.96,141.12 181.96,140.58 182.09,140.46 182.5,140.46 182.62,140.58 182.62,141.12 182.79,141.29 183.54,141.29 183.66,141.16 183.66,140.31 183.79,140.18 184.72,140.18 184.84,140.06 184.84,139.5 184.97,139.37 185.33,139.37 185.45,139.5 185.45,139.83 185.58,139.96 185.94,139.96 186.06,139.83 186.06,138.98 v2(186,138.92)
  BOTTOM w0.178: GPU1.E15 174.04,141.4 174.05,141.4 v2(174.06,141.41) ; v2(186,138.92) 186.01,138.92 186.01,138.93 186.4,139.32 VRAM5.F8
FBA_D9: length 20.1
  TOP w0.178: v2(187.6,139.72) 187.6,139.7 187.97,139.32 VRAM5.H8
  L4 w0.165: v2(187.6,139.72) 187.65,139.78 187.65,141.02 187.41,141.26 186.93,141.26 186.77,141.43 186.77,142.58 186.64,142.71 186.23,142.71 186.11,142.58 186.11,141.43 185.94,141.26 185.19,141.26 184.35,142.1 178.57,142.1 178.4,142.27 176.33,142.27 175.89,142.71 175.38,142.71 v2(174.89,142.22)
  BOTTOM w0.178: v2(174.89,142.22) 174.84,142.17 174.84,141.4 GPU1.D15 ; VRAM1.G2 187.2,139.33 v2(187.6,139.72)
FBA_D10: length 21.4
  TOP w0.178: VRAM5.H7 188,138.11 v2(187.62,137.73)
  L4 w0.102: 175.04,141.78 174.31,141.78 174.28,141.82 173.63,141.82 v2(173.23,141.42)
  L4 w0.165: 175.04,141.78 176.06,141.78 176.14,141.85 178.27,141.85 178.44,141.69 184.07,141.69 184.2,141.57 184.2,140.61 184.34,140.47 185.07,140.47 185.25,140.29 186.08,140.29 186.33,140.04 186.33,139.4 186.46,139.27 186.99,139.27 187.12,139.14 187.12,138.71 186.99,138.58 186.69,138.58 186.56,138.46 186.56,138 186.69,137.87 187.48,137.87 v2(187.62,137.73)
  BOTTOM w0.178: VRAM5.H7 188,138.11 v2(187.62,137.73) ; v2(173.23,141.42) 172.82,141.01 GPU1.F15
FBA_D11: length 23.8
  TOP w0.178: VRAM5.F7 186.4,138.41 v2(186.02,138.03)
  L4 w0.102: v2(173.2,139.72) 172.84,140.09 172.84,140.75 173.07,140.99 174.46,140.99 174.52,141.05 174.88,141.05
  L4 w0.165: v2(186.02,138.03) 186.02,138.32 185.86,138.48 184.62,138.48 183.65,138.48 183.48,138.31 183.48,138.01 183.32,137.84 182.99,137.84 182.82,138.01 182.82,138.31 182.66,138.48 182.33,138.48 182.16,138.31 182.16,138.01 182,137.84 181.67,137.84 181.5,138.01 181.5,138.31 181.34,138.48 181.05,138.48 180.87,138.66 180.87,139.25 180.99,139.37 182.17,139.37 182.3,139.5 182.3,139.93 182.17,140.05 180.18,140.05 179.48,140.75 178.96,140.75 178.79,140.59 178.79,140.32 178.63,140.16 178.3,140.16 178.13,140.32 178.13,140.59 177.97,140.75 177.49,140.75 177.2,141.05 174.88,141.05
  BOTTOM w0.178: v2(173.2,139.72) 173.2,139.72 GPU1.F13 ; VRAM1.E3 185.6,138.45 v2(186.02,138.03)
FBA_D12: length 20.9
  TOP w0.178: VRAM5.H3 188,136.12 v2(188.07,136.18)
  L4 w0.165: v2(188.07,136.18) 189.36,136.18 189.49,136.06 189.49,135.54 189.36,135.41 187.47,135.41 187.16,135.1 187.16,134.83 186.95,134.62 184.98,134.62 184.85,134.75 184.85,135.24 184.72,135.37 180.71,135.37 179.05,137.03 177.32,137.03 175.67,138.68 v2(175.67,138.92)
  BOTTOM w0.178: v2(188.07,136.18) 188,136.12 VRAM5.H3 ; v2(175.67,138.92) 175.26,139.33 GPU1.C13
FBA_D13: length 19.2
  TOP w0.178: VRAM5.E3 185.63,135.32 186.06,135.75 v2(186.06,135.78)
  L4 w0.165: v2(176.46,138.93) 176.46,138.51 177.57,137.4 179.29,137.4 180.29,136.4 180.48,136.4 180.65,136.24 180.65,135.86 180.81,135.69 181.14,135.69 181.31,135.86 181.31,136.24 181.47,136.4 181.8,136.4 181.97,136.24 181.97,135.86 182.14,135.69 184.3,135.69 184.43,135.82 184.43,136.05 184.57,136.19 185,136.19 185.14,136.05 185.14,135.02 185.27,134.89 186.68,134.89 186.82,135.03 186.82,136.3 186.7,136.42 186.19,136.42 186.06,136.29 v2(186.06,135.78)
  BOTTOM w0.178: VRAM1.F7 186.39,135.32 186.06,135.65 v2(186.06,135.78) ; v2(176.46,138.93) 176.06,139.33 GPU1.B13
FBA_D14: length 21.5
  TOP w0.178: v2(187.6,134.13) 187.21,134.52 VRAM5.G2
  L4 w0.102: v2(174.06,138.93) 174.5,138.49 175.01,138.49 175.25,138.25 175.25,137.79
  L4 w0.165: 175.25,137.79 175.25,137.55 175.67,137.13 175.67,136.88 177.41,135.13 178.52,135.13 181.04,132.62 188.33,132.62 188.46,132.74 188.46,134 188.33,134.13 v2(187.6,134.13)
  BOTTOM w0.178: VRAM1.H8 187.61,134.13 v2(187.6,134.13) ; GPU1.E13 173.66,139.33 v2(174.06,138.93)
FBA_D15: length 21.6
  TOP w0.178: VRAM5.F2 186.4,134.52 v2(186,134.11)
  L4 w0.165: v2(186,134.11) 186,133.89 185.75,133.65 184.52,133.65 184.36,133.5 184.36,133.15 184.26,133.04 183.81,133.04 183.7,133.15 183.7,133.5 183.55,133.65 181.81,133.65 181.59,133.86 181.36,133.86 180.98,133.49 180.75,133.49 180.51,133.72 180.51,133.95 181.07,134.51 181.07,134.69 180.79,134.98 180.61,134.98 180.05,134.42 179.81,134.42 179.58,134.65 179.58,134.89 179.96,135.26 179.96,135.5 179.72,135.73 179.49,135.73 179.11,135.35 178.88,135.35 178.65,135.59 178.65,135.82 179.02,136.2 179.02,136.43 178.86,136.59 177.27,136.59 177,136.87 176.77,136.87 176.58,136.68 176.35,136.68 176.11,136.91 176.11,137.15 176.3,137.33 176.3,137.57 174.95,138.91 v2(174.86,138.91)
  BOTTOM w0.178: VRAM5.F2 186.4,134.52 v2(186,134.11) ; v2(174.86,138.91) 174.45,139.32 GPU1.D13
FBA_D16: length 24.6
  TOP w0.178: v1(179.11,137.72) 179.14,137.75 v2(179.14,138.31) ; VRAM5.C2 v2(183.6,134.92)
  L3 w0.165: v2(179.14,138.31) 178.93,138.31 178.09,137.47 178.09,137.23 178.36,136.95 178.36,136.72 178.13,136.49 177.9,136.49 177.62,136.77 177.39,136.77 177.03,136.41 177.03,135.51 177.48,135.07 178.64,135.07 178.99,134.71 180.83,134.71 181.49,135.37 183.15,135.37 v2(183.6,134.92)
  BOTTOM w0.127: 178.56,138.68 178.18,139.05 177.86,139.05 177.21,139.7 177.21,139.84 176.75,140.3 176.73,140.3 176.05,140.98 GPU1.B15
  BOTTOM w0.178: v2(183.6,134.92) VRAM5.C2 ; v2(179.14,138.31) 179.62,137.83 180.45,137.83 v1(180.46,137.85) 180.8,137.85 180.97,137.69 180.97,136.68 180.79,136.5 180.43,136.5 180.25,136.68 180.25,136.9 180.08,137.08 179.38,137.08 178.56,137.91 178.56,138.68
FBA_D17: length 21.3
  TOP w0.178: v2(184.4,134.91) 184.4,134.92 VRAM5.C3 ; v2(179.8,138.28) 180.28,138.28 v1(180.36,138.21)
  L3 w0.165: v2(179.8,138.28) 180.13,138.28 180.26,138.15 180.26,137.33 179.8,136.87 179.03,136.87 178.75,136.59 178.75,135.46 179.14,135.07 180.81,135.07 181.39,135.65 182.24,135.65 182.41,135.82 182.41,136.04 182.58,136.2 182.91,136.2 183.07,136.04 183.07,135.82 183.24,135.66 183.57,135.66 183.73,135.82 183.73,136.32 183.86,136.45 184.27,136.45 184.39,136.32 184.39,134.92 v2(184.4,134.91)
  BOTTOM w0.127: GPU1.C16 175.66,141.4 176.16,141.4 176.49,141.07 176.49,140.86 176.83,140.53 176.84,140.53 177.49,139.88 177.49,139.74 177.91,139.32 178.43,139.32
  BOTTOM w0.178: v2(179.8,138.28) 179.8,138.64 179.62,138.82 178.93,138.82 178.43,139.32 ; VRAM1.D7 184.41,134.93 v2(184.4,134.91)
FBA_D18: length 22.8
  TOP w0.178: VRAM5.A2 v2(182.8,134.92) ; v2(177.95,138.63) 178.32,139.01 v1(178.32,139.06)
  L3 w0.165: v2(182.8,134.92) 183.35,134.37 183.35,134.13 183.24,134.02 183.24,133.79 183.48,133.55 183.71,133.55 183.82,133.67 184.05,133.67 184.3,133.42 184.3,132.3 184.15,132.15 183.2,132.15 183.04,132.32 183.04,132.5 182.87,132.67 182.54,132.67 182.38,132.5 182.38,132.32 182.21,132.15 180.55,132.15 179.88,132.82 179.39,132.82 179.22,132.65 178.79,132.65 178.17,133.26 177.48,133.26 177.09,133.66 176.56,133.66 176.09,134.12 176.09,138.01 176.49,138.41 177.72,138.41 v2(177.95,138.63)
  BOTTOM w0.178: v2(177.95,138.63) 177.95,138.64 177.8,138.64 177.1,139.33 GPU1.A13 ; v2(182.8,134.92) VRAM1.B8
FBA_D19: length 23.3
  TOP w0.178: v2(178.02,139.8) 178.05,139.83 v1(178.05,140.42) ; VRAM5.A3 181.99,134.91 v2(181.97,134.91)
  L3 w0.165: v2(181.97,134.91) 181.76,134.91 181.56,134.71 181.56,134.42 181.73,134.25 182.14,134.25 182.31,134.09 182.31,133.76 182.14,133.59 181.73,133.59 181.56,133.43 181.56,132.67 181.43,132.55 181.03,132.55 180.9,132.67 180.9,134.08 180.73,134.24 180.4,134.24 180.24,134.08 180.24,133.3 180.11,133.17 179.71,133.17 179.58,133.3 179.58,134.08 179.41,134.24 178.7,134.24 178.42,133.96 176.82,133.96 176.45,134.33 176.45,137.83 176.63,138 178.05,138 178.5,138.46 178.5,139.32 v2(178.02,139.8)
  BOTTOM w0.178: VRAM5.A3 181.99,134.91 v2(181.97,134.91) ; v2(178.02,139.8) 177.82,140.01 177.82,140.17 176.98,141.01 GPU1.A15
FBA_D20: length 23.3
  TOP w0.178: v2(182.02,138.93) 182.02,138.9 VRAM5.A7
  L3 w0.165: v2(179.01,143.03) 179.01,142.91 177.55,141.44 177.55,140.82 178.07,140.3 178.65,140.3 179.63,141.28 180.41,141.28 181.81,139.88 181.81,139.14 v2(182.02,138.93)
  BOTTOM w0.178: GPU1.B18 176.28,143.49 176.85,142.92 177.28,142.92 178.89,141.31 180.61,141.31 181.03,141.73 181.03,143.6 180.85,143.78 180.49,143.78 180.32,143.6 180.32,142.21 180.14,142.03 v1(179.22,142.03) 179.19,142.03 178.67,142.55 178.67,142.94 178.76,143.03 v2(179.01,143.03) ; VRAM5.A7 182.02,138.9 v2(182.02,138.93)
FBA_D21: length 19.4
  TOP w0.178: v2(182.8,138.92) VRAM5.B8
  L3 w0.165: v2(182.8,138.92) 183.26,139.38 183.81,139.38 183.93,139.51 183.93,140.11 183.81,140.24 182.84,140.24 182.64,140.44 182.4,140.44 182.15,140.18 181.97,140.18 181.68,140.47 181.68,140.65 181.94,140.91 181.94,141.14 181.7,141.38 181.47,141.38 181.19,141.1 181.01,141.1 180.72,141.38 180.72,141.56 181,141.84 181,142.08 180.56,142.52 180.3,142.52 178.43,140.65 178.25,140.65 177.9,141 177.9,141.18 v2(179.78,143.05)
  BOTTOM w0.178: v2(182.8,138.92) VRAM1.A2 ; v2(179.78,143.05) 179.14,143.69 178.71,143.69 178.3,143.28 177.06,143.28 GPU1.A18
FBA_D22: length 20.5
  TOP w0.178: v1(178.11,144.34) 178.11,144.34 178.11,144.24 178.11,144.24 178.11,143.8 v2(178.13,143.79) ; v2(184.43,138.04) 184.43,138.15 VRAM5.D7
  L3 w0.165: v2(178.13,143.79) 178.3,143.96 180.29,143.96 182.53,141.72 183.61,141.72 184.25,141.08 184.25,140.77 184.56,140.45 185.08,140.45 185.27,140.26 187.93,140.26 188.06,140.13 188.06,138.59 187.93,138.47 184.86,138.47 v2(184.43,138.04)
  BOTTOM w0.178: v2(178.13,143.79) 177.62,144.29 GPU1.A19 ; v2(184.43,138.04) 184.43,138.09 VRAM1.C3
FBA_D23: length 20.9
  TOP w0.178: VRAM5.C8 v2(184.4,138.92)
  L3 w0.165: v2(184.4,138.92) 184.98,139.5 184.98,139.98 184.8,140.16 184.45,140.16 183.35,141.26 182.39,141.26 180.09,143.56 178.88,143.56 176.4,141.07 175.48,141.07 175.36,141.2 175.36,141.64 175.48,141.77 176.11,141.77 177.48,143.14 v2(177.48,143.78)
  BOTTOM w0.178: VRAM5.C8 v2(184.4,138.92) ; GPU1.C19 175.64,143.9 177.36,143.9 v2(177.48,143.78)
FBA_D24: length 14.4
  TOP w0.178: VRAM6.C8 184,153.31 v2(183.6,153.71)
  L3 w0.165: v2(176.45,148.86) 176.45,149.12 176.62,149.28 176.87,149.28 177,149.41 177,149.82 176.87,149.94 176.35,149.94 176.19,150.1 176.19,150.97 177.17,151.96 177.17,152.85 178.67,154.35 181.89,154.35 182.13,154.11 182.98,154.11 183.39,153.71 v2(183.6,153.71)
  BOTTOM w0.178: v2(176.45,148.86) 176.07,148.47 GPU1.B24 ; VRAM6.C8 184,153.31 v2(183.6,153.71)
FBA_D25: length 16.5
  TOP w0.178: VRAM6.D7 184.79,152.51 v2(184.39,152.91) ; v1(178.05,148.64) 178.05,148.29 v2(177.85,148.09)
  L3 w0.165: v2(184.39,152.91) 183.93,152.45 183.56,152.45 182.47,151.36 181.83,151.36 181.66,151.52 181.66,151.97 181.49,152.14 181.16,152.14 181,151.97 181,151.52 180.83,151.36 180.5,151.36 180.34,151.52 180.34,151.97 180.17,152.14 179.84,152.14 179.68,151.97 179.68,151.52 179.33,151.18 179.33,150.48 178.43,149.58 178.43,148.44 178.08,148.09 v2(177.85,148.09)
  BOTTOM w0.178: v2(177.85,148.09) 177.81,148.05 175.68,148.05 GPU1.C23 ; VRAM2.C3 184.39,152.9 v2(184.39,152.91)
FBA_D26: length 14.3
  TOP w0.178: v2(182.26,151.81) 182.4,151.95 VRAM6.A7 ; v2(178.46,150.27) 178.81,150.27 v1(179.01,150.47)
  L3 w0.165: v2(182.26,151.81) 182.26,152.16 181.91,152.51 181.91,153.33 181.75,153.49 181.42,153.49 181.25,153.33 181.25,152.82 181.09,152.66 180.76,152.66 180.59,152.82 180.59,153.33 180.43,153.49 180.1,153.49 179.93,153.33 179.93,152.65 179.81,152.52 179.44,152.52 179.2,152.28 179.2,151.68 179.07,151.55 178.12,151.55 177.99,151.43 177.99,150.4 178.12,150.27 v2(178.46,150.27)
  BOTTOM w0.178: v2(182.26,151.81) 182.26,152.37 VRAM6.A7 ; v2(178.46,150.27) 178.16,150.27 177.16,149.27 GPU1.A25
FBA_D27: length 14.1
  TOP w0.178: VRAM6.B8 183.2,153.31 v2(182.79,152.91)
  L3 w0.165: v2(182.79,152.91) 181.81,153.89 179.95,153.89 179.67,153.61 179.43,153.61 179.05,153.99 178.82,153.99 178.58,153.76 178.58,153.52 179.02,153.08 179.02,152.85 178.79,152.62 178.55,152.62 178.12,153.06 177.88,153.06 177.65,152.82 177.65,152.59 178.09,152.15 178.09,151.92 177.6,151.43 177.6,149.08 v2(177.52,149)
  BOTTOM w0.178: v2(177.52,149) 177.4,149 176.87,148.47 GPU1.A24 ; v2(182.79,152.91) 182.4,153.3 VRAM2.A2
FBA_D28: length 17.7
  TOP w0.178: VRAM6.A2 182.81,148.92 v2(182.82,148.92)
  BOTTOM w0.178: VRAM2.B8 183.18,148.51 182.82,148.88 v2(182.82,148.92) 182.81,148.93 182.81,149.5 182.39,149.91 181.94,149.91 181.81,150.04 181.81,151.46 181.68,151.59 181.25,151.59 181.12,151.46 181.12,151.08 181,150.95 v1(180.13,150.95) 179.35,150.95 179.22,150.83 179.22,150.37 179.35,150.24 180.97,150.24 181.1,150.12 181.1,149.68 180.97,149.56 178.96,149.56 178.46,149.05 178.46,146.53 177.89,145.97 GPU1.A21
FBA_D29: length 17.9
  TOP w0.178: v2(181.54,149.1) 181.75,149.31 VRAM6.A3
  L3 w0.165: v2(181.54,149.1) 181.83,148.8 181.83,148.38 181.66,148.21 v2(179.9,148.21)
  BOTTOM w0.178: v2(179.9,148.21) 179.9,147.84 180.08,147.66 180.76,147.66 180.94,147.84 180.94,149 180.81,149.13 v1(180.16,149.13) 179.07,149.13 178.9,148.95 178.9,146.96 179.07,146.78 179.9,146.78 180.08,146.61 180.08,146.25 179.9,146.07 178.97,146.07 178.8,145.9 178.8,145.75 178.62,145.58 176.63,145.58 176.36,145.85 176.17,145.85 GPU1.B21 ; VRAM6.A3 181.75,149.31 v2(181.54,149.1)
FBA_D30: length 18.8
  TOP w0.178: v2(183.6,148.9) 183.99,148.51 VRAM6.C2
  L3 w0.165: v2(180.92,146.02) 179.16,146.02 179.03,146.15 179.03,146.73 179.16,146.86 179.98,146.86 180.15,147.02 180.15,147.53 180.31,147.69 180.64,147.69 180.81,147.53 180.81,147.02 180.97,146.86 181.45,146.86 182.26,147.67 183,147.67 183.6,148.27 v2(183.6,148.9)
  BOTTOM w0.178: VRAM6.C2 183.99,148.51 v2(183.6,148.9) ; v2(180.92,146.02) 180.79,146.02 179.99,145.22 v1(179.76,145.22) 179.54,145.22 179.36,145.04 179.36,144.69 179.18,144.51 178.83,144.51 178.65,144.69 178.65,145.04 178.47,145.22 178.12,145.22 177.94,145.04 177.94,144.84 177.76,144.67 177.41,144.67 177.23,144.84 177.23,145.04 177.05,145.22 176.55,145.22 176.24,145.52 175.64,145.52 GPU1.C20
FBA_D31: length 17
  TOP w0.178: v2(184.94,149.97) 184.66,149.97 VRAM6.C3
  L3 w0.165: v2(184.94,149.97) 184.89,150.02 184.5,150.02 184.37,149.9 184.37,149.46 184.5,149.33 185.21,149.33 185.34,149.2 185.34,148.74 185.21,148.62 184.63,148.62 181.57,145.56 178.16,145.56 177.86,145.86 176.94,145.86 v2(176.45,146.35)
  BOTTOM w0.178: VRAM2.D7 184.46,149.65 184.46,149.85 184.59,149.97 v2(184.94,149.97) ; GPU1.C21 175.26,145.97 175.66,146.37 176.43,146.37 v2(176.45,146.35)
FBA_D32: length 25.5
  TOP w0.178: v2(171.2,161.57) 171.2,161.57 VRAM7.H7
  L4 w0.102: v2(164.9,146.43) 164.51,146.81 164.51,147.45 163.9,148.06 163.9,149.31 163.63,149.58 163.63,150.19
  L4 w0.165: 163.63,150.19 163.63,151.02 163.01,151.64 163.01,155.73 163.5,156.22 164.15,156.22 164.27,156.35 164.27,156.79 164.11,156.95 163.56,156.95 163.39,157.12 163.39,157.45 163.56,157.61 164.11,157.61 164.27,157.78 164.27,158.41 165.19,159.32 166.4,159.32 168.98,161.89 169.77,161.89 169.94,162.05 170.72,162.05 v2(171.2,161.57)
  BOTTOM w0.127: v2(171.2,161.57) 171.2,161.57 VRAM7.H7
  BOTTOM w0.178: GPU1.R22 165.27,146.79 165.27,146.53 165.17,146.43 v2(164.9,146.43)
FBA_D33: length 20.5
  TOP w0.178: v2(170.4,161.57) VRAM7.H8
  L4 w0.165: v2(170.4,161.57) 169.19,161.57 168.42,160.8 168.42,159.9 167.41,158.88 165.31,158.88 164.62,158.19 164.62,156.14 164.34,155.86 163.71,155.86 163.41,155.57 163.41,151.83 164,151.25 164,149.81 v2(164.11,149.69)
  BOTTOM w0.127: VRAM3.G2 170.8,161.18 v2(170.4,161.57)
  BOTTOM w0.178: GPU1.R24 164.9,148.88 164.35,148.88 164.11,149.12 v2(164.11,149.69)
FBA_D34: length 20.8
  TOP w0.178: VRAM7.F7 171.6,160.44 171.85,160.69 172.07,160.69 172.2,160.57 v2(172.2,160.37)
  L4 w0.165: v2(164.93,147.25) 165.34,147.66 165.34,148.27 164.84,148.77 164.84,150.34 164.75,150.42 164.75,153.53 165.24,154.02 165.24,154.76 165.19,154.81 165.19,155.28 165.47,155.56 165.47,155.97 166.18,156.68 166.18,156.89 169.11,159.81 169.55,159.81 170.06,160.31 172.13,160.31 v2(172.2,160.37)
  BOTTOM w0.127: VRAM3.E3 172.2,160.17 v2(172.2,160.37)
  BOTTOM w0.178: v2(164.93,147.25) 164.93,147.25 164.51,146.83 GPU1.T22
FBA_D35: length 23.1
  TOP w0.178: VRAM7.F8 v2(170.4,160.77)
  L4 w0.165: v2(164.91,148.09) 164.91,147.88 164.78,147.75 164.54,147.75 164.18,148.11 164.18,148.82 164.56,149.2 164.56,150.09 164.36,150.29 164.36,153.88 164.56,154.08 164.76,154.08 164.89,154.2 164.89,154.71 164.8,154.79 163.99,154.79 163.86,154.92 163.86,155.32 163.99,155.45 164.98,155.45 165.2,155.67 165.2,156.22 164.94,156.48 164.94,157.63 165.21,157.9 165.9,157.9 166.03,158.03 166.03,158.33 166.17,158.47 167.39,158.47 169.01,160.09 169.47,160.09 169.84,160.47 169.84,161.01 169.96,161.14 170.27,161.14 170.4,161.01 v2(170.4,160.77)
  BOTTOM w0.127: VRAM7.F8 170.8,160.61 170.64,160.77 v2(170.4,160.77)
  BOTTOM w0.178: v2(164.91,148.09) 164.91,147.79 165,147.69 165.29,147.69 GPU1.R23
FBA_D36: length 25.6
  TOP w0.178: v2(176.01,161.57) 175.61,161.17 VRAM7.G2
  L4 w0.102: v2(166.58,149.68) 166.8,149.9 166.97,149.9 168.42,151.34 168.42,153.11
  L4 w0.165: v2(176.01,161.57) 176.28,161.57 176.41,161.7 176.41,163.9 176.28,164.03 175.84,164.03 175.72,163.9 175.72,162.89 175.37,162.54 175.37,161.61 174.4,160.64 174.4,159.62 173.63,158.85 172.25,158.85 171.66,158.27 171.66,156.49 171.5,156.33 168.9,156.33 168.66,156.09 168.66,153.63 168.41,153.38 168.41,153.12 168.42,153.11
  BOTTOM w0.127: VRAM3.H8 175.61,161.97 v2(176.01,161.57)
  BOTTOM w0.178: v2(166.58,149.68) 166.58,149.68 GPU1.N25
FBA_D37: length 26.6
  TOP w0.178: v2(174.34,161.6) 173.96,161.6 173.73,161.83 173.73,162.08 174.08,162.44 174.33,162.44 VRAM7.H3 ; v1(167.01,150.13) 166.66,150.47 v2(166.57,150.47)
  L4 w0.102: v2(166.57,150.47) 166.72,150.33 166.92,150.33 167.19,150.61 167.32,150.61 168.21,151.5 168.21,152.74 168.12,152.83 168.12,153.39
  L4 w0.165: 168.12,153.39 168.12,153.63 168.32,153.82 168.32,156.33 168.66,156.67 169.2,156.67 169.91,157.38 170.14,157.38 170.28,157.24 170.46,157.24 170.75,157.53 170.75,157.71 170.61,157.85 170.61,158.08 170.83,158.31 171.33,158.31 172.16,159.15 173.47,159.15 174.12,159.8 174.12,160.38 173.81,160.69 173.81,162.53 173.94,162.65 174.88,162.65 175.01,162.53 175.01,161.72 174.88,161.6 v2(174.34,161.6)
  BOTTOM w0.127: v2(174.34,161.6) 174.42,161.51 175.13,161.51 175.25,161.64 175.25,162.21 175.13,162.34 174.93,162.34 174.8,162.21 VRAM7.H3
  BOTTOM w0.178: v2(166.57,150.47) 166.59,150.47 GPU1.N26
FBA_D38: length 26.5
  TOP w0.178: VRAM7.E3 174.8,159.57 v2(175.2,159.97) ; v1(166.87,146.91) 167.07,146.91 v2(167.39,147.24)
  L4 w0.102: 166.97,148.47 166.97,147.78 167,147.75 167,147.35 167.11,147.24 v2(167.39,147.24)
  L4 w0.165: 166.97,148.47 167.1,148.61 167.57,148.61 167.74,148.77 167.74,149.43 167.92,149.61 167.92,149.92 168.95,150.95 168.95,152.94 169.35,153.35 169.35,154.06 169.54,154.25 171.43,154.25 172.41,155.24 173.53,155.24 173.73,155.44 173.73,157.09 173.84,157.2 174.62,157.2 174.76,157.34 174.76,159.13 174.91,159.29 175.43,159.29 175.56,159.16 175.56,159.01 175.69,158.88 176.11,158.88 176.23,159.01 176.23,159.79 176.92,160.48 176.92,160.66 176.49,161.09 176.33,161.09 v2(175.2,159.97)
  BOTTOM w0.127: VRAM3.F7 174.8,160.37 v2(175.2,159.97)
  BOTTOM w0.178: GPU1.N23 166.99,147.65 v2(167.39,147.24)
FBA_D39: length 25.4
  TOP w0.178: v2(175.2,160.77) VRAM7.F2
  L4 w0.165: v2(175.2,160.77) 174.68,160.26 174.68,159.47 173.8,158.59 173.49,158.59 173.25,158.35 173.25,158.12 173.02,157.88 172.71,157.88 172.58,157.76 172.58,156.6 172.71,156.47 173.25,156.47 173.37,156.34 173.37,155.94 173.25,155.81 171.81,155.81 171.68,155.68 171.68,154.94 171.52,154.77 171.19,154.77 171.02,154.94 171.02,155.82 170.9,155.94 170.49,155.94 170.36,155.82 170.36,154.69 170.24,154.56 169.83,154.56 169.7,154.69 169.7,155.83 169.58,155.96 169.14,155.96 169.01,155.83 169.01,153.49 168.68,153.16 168.68,151.23 167.61,150.15 167.61,149.91 v2(166.56,148.86)
  BOTTOM w0.127: v2(175.2,160.77) VRAM7.F2
  BOTTOM w0.178: GPU1.N24 166.6,148.86 v2(166.56,148.86)
FBA_D40: length 22.2
  TOP w0.178: v2(161.2,159.96) 161.6,160.37 VRAM8.F2
  L4 w0.102: v2(163.25,148.12) 163.25,149.35 163.09,149.51 163.09,149.91
  L4 w0.152: 160.75,156.36 160.75,158.86 160.88,158.98 161.54,158.98 161.67,158.86 161.67,158.65 161.8,158.52 162.3,158.52 162.43,158.65 162.43,159.35 161.82,159.96 v2(161.2,159.96)
  L4 w0.165: 160.75,156.36 160.88,156.24 161.34,156.24 161.46,156.11 161.46,155.57 161.67,155.37 162.11,155.37 162.24,155.24 162.24,154.73 162.11,154.6 161.19,154.6 161.06,154.47 161.06,153.49 161.19,153.36 162.03,153.36 162.15,153.24 162.15,152.82 162.03,152.69 161.15,152.69 160.94,152.48 160.94,151.92 161.28,151.58 161.91,151.58 163.09,150.4 163.09,149.91
  BOTTOM w0.178: VRAM8.F2 161.21,159.98 161.21,159.97 v2(161.2,159.96) ; v2(163.25,148.12) 163.25,148.1 162.83,147.67 GPU1.V23
FBA_D41: length 24.2
  TOP w0.178: v1(163.6,146.03) 163.6,146.04 v2(163.22,146.43) ; VRAM8.H3 160.75,161.97 v2(160.36,161.58)
  L4 w0.102: v2(163.22,146.43) 163.27,146.38 163.27,146.11 163.15,145.98 162.76,145.98 162.63,146.11 162.63,146.76 162.81,146.94 162.81,147.65 162.64,147.82 162.64,148.5 162.84,148.69 162.84,149.05 162.47,149.41 162.47,149.46
  L4 w0.165: 162.47,149.46 162.47,150.07 162.1,150.44 161.47,150.44 160.45,151.46 159.38,151.46 159.14,151.7 159.14,152.22 159.22,152.3 159.62,152.3 159.75,152.42 159.75,152.84 159.62,152.97 159.17,152.97 159,153.13 159,153.92 159.17,154.09 159.58,154.09 159.71,154.22 159.71,156.04 160.18,156.51 160.18,159.09 159.69,159.59 159.69,161.3 159.96,161.58 v2(160.36,161.58)
  BOTTOM w0.178: v2(163.22,146.43) 163.22,146.44 GPU1.V22 ; VRAM8.H3 160.75,161.97 v2(160.36,161.58)
FBA_D42: length 22.9
  TOP w0.178: VRAM8.G2 v2(161.2,161.57)
  L4 w0.102: 163.36,150.24 163.36,149.56 163.7,149.22 163.7,148.97 163.47,148.74 163.47,148.49 163.7,148.26 163.7,147.97 163.7,147.78 163.83,147.65 164.01,147.65 164.14,147.53 164.14,147.28 v2(164.08,147.22)
  L4 w0.165: 163.36,150.24 163.36,150.71 162.6,151.47 162.6,157.36 164.7,159.46 164.7,160.66 164.57,160.78 163.99,160.78 163.86,160.66 163.86,159.89 163.35,159.38 162.78,159.38 161.61,160.55 161.61,161.16 v2(161.2,161.57)
  BOTTOM w0.178: v2(161.2,161.57) 161.59,161.97 VRAM4.H8 ; GPU1.T23 164.51,147.63 164.1,147.22 v2(164.08,147.22)
FBA_D43: length 23.1
  TOP w0.178: v2(160.39,159.98) 160.39,159.98 VRAM8.E3
  L4 w0.102: 162.79,149.43 163.04,149.18 163.04,148.48 162.85,148.29 162.85,147.95 163.13,147.66 163.42,147.66 163.66,147.42 163.66,146.2 163.63,146.16 163.63,145.26 163.75,145.13 164.34,145.13 164.47,145.26 164.47,146.33 164.34,146.46 v2(164.08,146.46)
  L4 w0.165: 162.79,149.43 162.79,150.13 161.78,151.14 161.16,151.14 160.5,151.8 160.21,151.8 160.09,151.92 160.09,152.41 160.25,152.58 160.49,152.58 160.65,152.74 160.65,153.07 160.49,153.24 160.25,153.24 160.09,153.4 160.09,154.33 160.25,154.49 160.57,154.49 160.73,154.66 160.73,154.99 160.57,155.15 160.25,155.15 160.09,155.32 160.09,155.78 160.46,156.15 160.46,159.91 v2(160.39,159.98)
  BOTTOM w0.178: v2(164.08,146.46) 164.04,146.46 GPU1.U22 ; v2(160.39,159.98) 160.77,160.37 VRAM4.F7
FBA_D44: length 22.8
  TOP w0.178: v2(157.19,159.97) 157.2,159.97 VRAM8.F7
  L4 w0.165: v2(157.19,159.97) 156.74,160.42 156.74,160.68 156.61,160.81 156.06,160.81 155.93,160.68 155.93,159.7 156.12,159.51 156.57,159.51 156.74,159.35 156.74,159.02 156.57,158.85 156.12,158.85 155.95,158.69 155.95,158.05 156.12,157.88 156.59,157.88 156.72,157.76 156.72,157.35 156.59,157.22 156.12,157.22 155.95,157.05 155.95,156.44 155.5,155.99 155.5,151.54 157.6,149.44 157.88,149.44 158.01,149.32 158.01,148.95 158.14,148.82 158.44,148.82 158.57,148.95 158.57,149.32 158.69,149.44 159.73,149.44 159.94,149.23 v2(159.94,148.87)
  BOTTOM w0.178: GPU1.Y24 160.79,148.87 v2(159.94,148.87) ; v2(157.19,159.97) 157.59,159.57 VRAM4.E3
FBA_D45: length 20.7
  TOP w0.178: v2(157.2,160.77) 156.8,160.37 VRAM8.F8
  L4 w0.165: v2(157.2,160.77) 157.2,160.88 156.99,161.09 155.55,161.09 154.73,160.27 154.73,152.98 154.89,152.82 155.06,152.82 155.23,152.65 155.23,152.32 155.06,152.15 154.89,152.15 154.73,151.99 154.73,151.62 157.83,148.52 158.52,148.52 158.96,148.08 v2(159.95,148.08)
  BOTTOM w0.178: VRAM8.F8 156.8,160.37 v2(157.2,160.77) ; v2(159.95,148.08) 159.95,148.09 160.33,148.47 GPU1.AA24
FBA_D46: length 20.9
  TOP w0.178: VRAM8.H8 156.8,161.95 v2(157.21,161.54)
  L4 w0.102: 160.54,148.61 160.36,148.42 160.36,147.33 160.48,147.21 160.76,147.21 v2(160.78,147.24)
  L4 w0.165: 160.54,148.61 160.54,149.13 159.83,149.85 157.77,149.85 155.9,151.71 155.9,155.15 156.13,155.38 156.66,155.38 157.68,156.4 157.68,161.07 v2(157.21,161.54)
  BOTTOM w0.178: v2(160.78,147.24) 160.78,147.24 GPU1.Y22 ; VRAM4.G2 156.83,161.17 v2(157.21,161.54)
FBA_D47: length 22.6
  TOP w0.178: VRAM8.H7 157.97,162.34 v2(158.04,162.34)
  L4 w0.102: v2(158.04,162.34) 157.66,161.96 156.22,161.96 156.22,161.96 156.13,161.96 ; v2(159.94,147.25) 159.51,147.67 158.1,147.67 157.4,148.37
  L4 w0.165: 157.4,148.37 154.37,151.4 154.37,160.49 155.84,161.96 156.13,161.96
  BOTTOM w0.178: v2(159.94,147.25) 160.35,147.66 GPU1.AA23 ; VRAM8.H7 157.67,161.97 v2(158.04,162.34)
FBA_D48: length 17.2
  TOP w0.178: v1(156.97,153.36) 156.43,153.36 v2(156.41,153.34) ; v2(156.4,156.78) 156.41,156.78 VRAM8.B8
  L3 w0.165: v2(156.41,153.34) 156.41,153.24 156.28,153.11 155.76,153.11 155.63,153.24 155.63,154.05 155.48,154.2 154.37,154.2 154.14,154.43 154.14,155.88 154.56,156.31 156.09,156.31 156.4,156.62 v2(156.4,156.78)
  BOTTOM w0.127: v2(156.41,153.34) 155.06,153.34 154.91,153.19 154.91,151.89 155.06,151.74 155.24,151.74 155.37,151.87 155.37,152.66 155.49,152.78 155.72,152.78 155.85,152.66 155.85,152.28 155.98,152.15 156.77,152.15 157.85,151.07 GPU1.AD27
  BOTTOM w0.178: v2(156.4,156.78) 156.41,156.77 156.41,156.76 VRAM4.A2
FBA_D49: length 21.8
  TOP w0.178: v2(156.38,154.05) 155.89,154.05 155.89,154.05 v1(155.82,154.05) ; v2(157.2,156.78) 157.6,156.38 VRAM8.A7
  L3 w0.165: v2(157.2,156.78) 157.19,156.77 157.19,154.95 157.07,154.82 156.6,154.82 156.47,154.95 156.47,155.15 156.35,155.28 155.95,155.28 155.79,155.44 155.79,155.81 155.62,155.98 155.29,155.98 155.13,155.81 155.13,155.44 154.96,155.28 154.65,155.28 154.52,155.15 154.52,154.61 154.65,154.49 155.95,154.49 v2(156.38,154.05)
  BOTTOM w0.127: 158.01,152.08 158.53,152.08 158.78,151.83 158.78,151.48 158.77,151.48 158.77,150.5 159.11,150.16 159.11,149.71 GPU1.AB25
  BOTTOM w0.178: v2(156.38,154.05) 155.44,154.05 155.32,154.18 155.32,154.6 155.44,154.73 156.92,154.73 157.05,154.6 157.05,153.6 157.18,153.47 157.97,153.47 158.09,153.34 158.09,152.94 157.97,152.81 157.58,152.81 157.42,152.66 157.42,152.27 157.61,152.08 158.01,152.08 ; v2(157.2,156.78) 157.6,156.38 VRAM8.A7
FBA_D50: length 17.1
  TOP w0.178: v2(157.18,158.36) 157.59,158.77 VRAM8.D7 ; v2(156.61,151.69) 157.17,151.69 v1(157.17,151.7)
  L3 w0.165: v2(156.61,151.69) 156.04,151.69 155.91,151.56 155.91,150.59 156.04,150.46 157.75,150.46 157.88,150.59 157.88,152.05 157.76,152.16 157,152.16 156.87,152.29 156.87,154.09 157.52,154.74 157.52,155.82 157.7,156 157.7,158.16 157.5,158.36 v2(157.18,158.36)
  BOTTOM w0.127: GPU1.AD26 157.46,150.46 157.46,151.04 157.18,151.32
  BOTTOM w0.178: v2(156.61,151.69) 156.81,151.69 157.18,151.32 ; v2(157.18,158.36) 157.43,158.1 157.47,158.1 VRAM4.C3
FBA_D51: length 19.8
  TOP w0.178: VRAM8.C8 156.8,157.98 v2(156.41,158.37) ; v1(155.81,152.56) 156.33,152.56 v2(156.37,152.6)
  L3 w0.165: v2(156.41,158.37) 156.41,157.53 156.28,157.4 154.38,157.4 153.61,156.63 153.61,152.68 153.74,152.55 154.37,152.55 154.5,152.68 154.5,153.62 154.66,153.78 155.22,153.78 155.35,153.66 155.35,152.3 155.47,152.17 156.24,152.17 156.37,152.3 v2(156.37,152.6)
  BOTTOM w0.127: GPU1.AC25 158.7,149.48 158.23,149.96 158.23,151.07 156.92,152.38
  BOTTOM w0.178: v2(156.37,152.6) 156.7,152.6 156.92,152.38 ; v2(156.41,158.37) 156.8,157.98 VRAM8.C8
FBA_D52: length 18.5
  TOP w0.178: v2(161.2,158.36) 160.81,157.97 VRAM8.C3
  L3 w0.165: v2(160.57,153.79) 161,153.79 161.16,153.94 161.16,154.94 161.04,155.07 160.3,155.07 160.17,155.2 160.17,156.47 160.3,156.6 160.52,156.6 160.69,156.77 160.69,157.1 160.52,157.26 160.35,157.26 160.18,157.43 160.18,157.8 160.74,158.36 v2(161.2,158.36)
  BOTTOM w0.127: GPU1.AA27 160.35,150.87 160.19,151.02 160.19,151.34 160.5,151.64 160.5,152.05 160.21,152.33 160.21,152.86 159.94,153.13 159.94,153.77 159.79,153.93 v1(158.05,153.93) 157.5,153.93 157.38,154.05 157.38,154.31 157.5,154.43 160.42,154.43 160.57,154.28 v2(160.57,153.79)
  BOTTOM w0.178: VRAM4.D7 161.2,158.37 v2(161.2,158.36)
FBA_D53: length 20.4
  TOP w0.178: v2(160.82,155.71) 160.8,155.72 VRAM8.A3
  BOTTOM w0.178: VRAM8.A3 160.8,155.72 v2(160.82,155.71) 160.82,155.62 160.65,155.45 158.57,155.45 158.44,155.58 158.44,155.83 158.57,155.96 159.86,155.96 159.99,156.09 159.99,156.67 159.86,156.8 159,156.8 158.67,157.13 158.26,157.13 158.03,156.9 158.03,156.25 157.75,155.96 157.56,155.96 157.43,155.84 157.43,154.92 157.56,154.79 161.36,154.79 161.5,154.66 161.5,154 161.37,153.88 161.15,153.88 161.03,153.75 v1(161.03,153.09) 161.03,152.89 160.77,152.63 160.77,150.7 160.35,150.28 GPU1.AA26
FBA_D54: length 19.5
  TOP w0.178: v1(162.07,152.17) 161.94,152.17 161.94,152.17 v2(161.51,152.17) ; v2(161.2,156.77) VRAM8.A2
  L3 w0.165: v2(161.2,156.77) 161.48,156.49 161.48,155.68 161.64,155.51 161.9,155.51 162.03,155.38 162.03,154.98 161.9,154.85 161.64,154.85 161.48,154.68 161.48,153.16 161.35,153.03 159.81,153.03 159.04,152.26 159.04,149.46 159.17,149.33 159.73,149.33 159.85,149.46 159.85,151.84 160.18,152.17 161.51,152.17 v2(161.51,152.17)
  BOTTOM w0.127: GPU1.W26 162,150.1 161.68,150.1 161.32,150.47 161.32,151.98 v2(161.51,152.17)
  BOTTOM w0.178: v2(161.2,156.77) VRAM4.B8
FBA_D55: length 20.5
  TOP w0.178: v1(161.96,153.44) 161.94,153.46 v2(161.94,154) ; v2(161.21,157.57) 161.24,157.57 161.6,157.92 VRAM8.C2
  L3 w0.165: v2(161.94,154) 162.45,154.51 162.45,157.05 162.56,157.16 162.71,157.16 162.84,157.29 162.84,157.69 162.71,157.81 162.43,157.81 162.28,157.96 162.28,158.7 162.4,158.83 162.76,158.83 162.89,158.96 162.89,159.31 162.76,159.43 162.51,159.43 162.39,159.56 162.39,160.17 162.26,160.3 161.77,160.3 161.64,160.17 161.64,159.72 161.45,159.52 160.68,159.52 160.55,159.4 160.55,158.95 160.68,158.82 161.44,158.82 161.67,158.59 161.67,157.91 161.33,157.57 v2(161.21,157.57)
  BOTTOM w0.127: v2(161.94,154) 161.81,153.87 161.81,153.87 161.59,153.65 161.59,152.86 161.07,152.34 161.07,150.62 160.81,150.36 160.81,149.81 161.19,149.43 GPU1.Y25
  BOTTOM w0.178: v2(161.21,157.57) 161.24,157.57 161.6,157.93 VRAM8.C2
FBA_D56: length 20.2
  TOP w0.178: v2(175.2,156.77) VRAM7.A2
  L3 w0.165: v2(175.2,156.77) 175.2,155.56 175.34,155.41 176.11,155.41 176.24,155.28 176.24,154.8 176.11,154.67 175.34,154.67 175.22,154.55 175.22,154.28 175.38,154.12 176.08,154.12 176.24,153.95 176.24,153.62 176.08,153.46 175.38,153.46 175.22,153.29 175.22,152.87 174.96,152.61 170.26,152.61 169.63,151.97 166.75,151.97 v2(166.51,151.73)
  BOTTOM w0.127: v2(175.2,156.77) 175.59,157.17 VRAM3.B8 ; GPU1.R26 165.31,150.08 165.67,150.44 165.67,151.01 165.63,151.04 165.63,151.42 165.94,151.73 166.12,151.73
  BOTTOM w0.178: v2(166.51,151.73) 166.12,151.73
FBA_D57: length 21.9
  TOP w0.178: VRAM7.A3 174.5,156.07 v2(174.24,156.07) ; v1(168.01,152.88) 167.9,152.88 167.89,152.87 v2(167.45,152.87)
  L3 w0.165: v2(167.45,152.87) 169.37,152.87 169.99,153.49 172.78,153.49 173.68,154.38 173.68,155.51 v2(174.24,156.07)
  BOTTOM w0.127: VRAM7.A3 174.5,156.07 v2(174.24,156.07) ; 166.18,153.47 165.93,153.47 165.72,153.26 165.72,152.16 164.92,151.37 164.92,149.94 164.51,149.53 GPU1.T25
  BOTTOM w0.178: 166.18,153.47 166.49,153.47 166.62,153.6 166.62,154.94 166.75,155.07 168.03,155.07 168.16,154.94 168.16,153 168.03,152.87 v2(167.45,152.87)
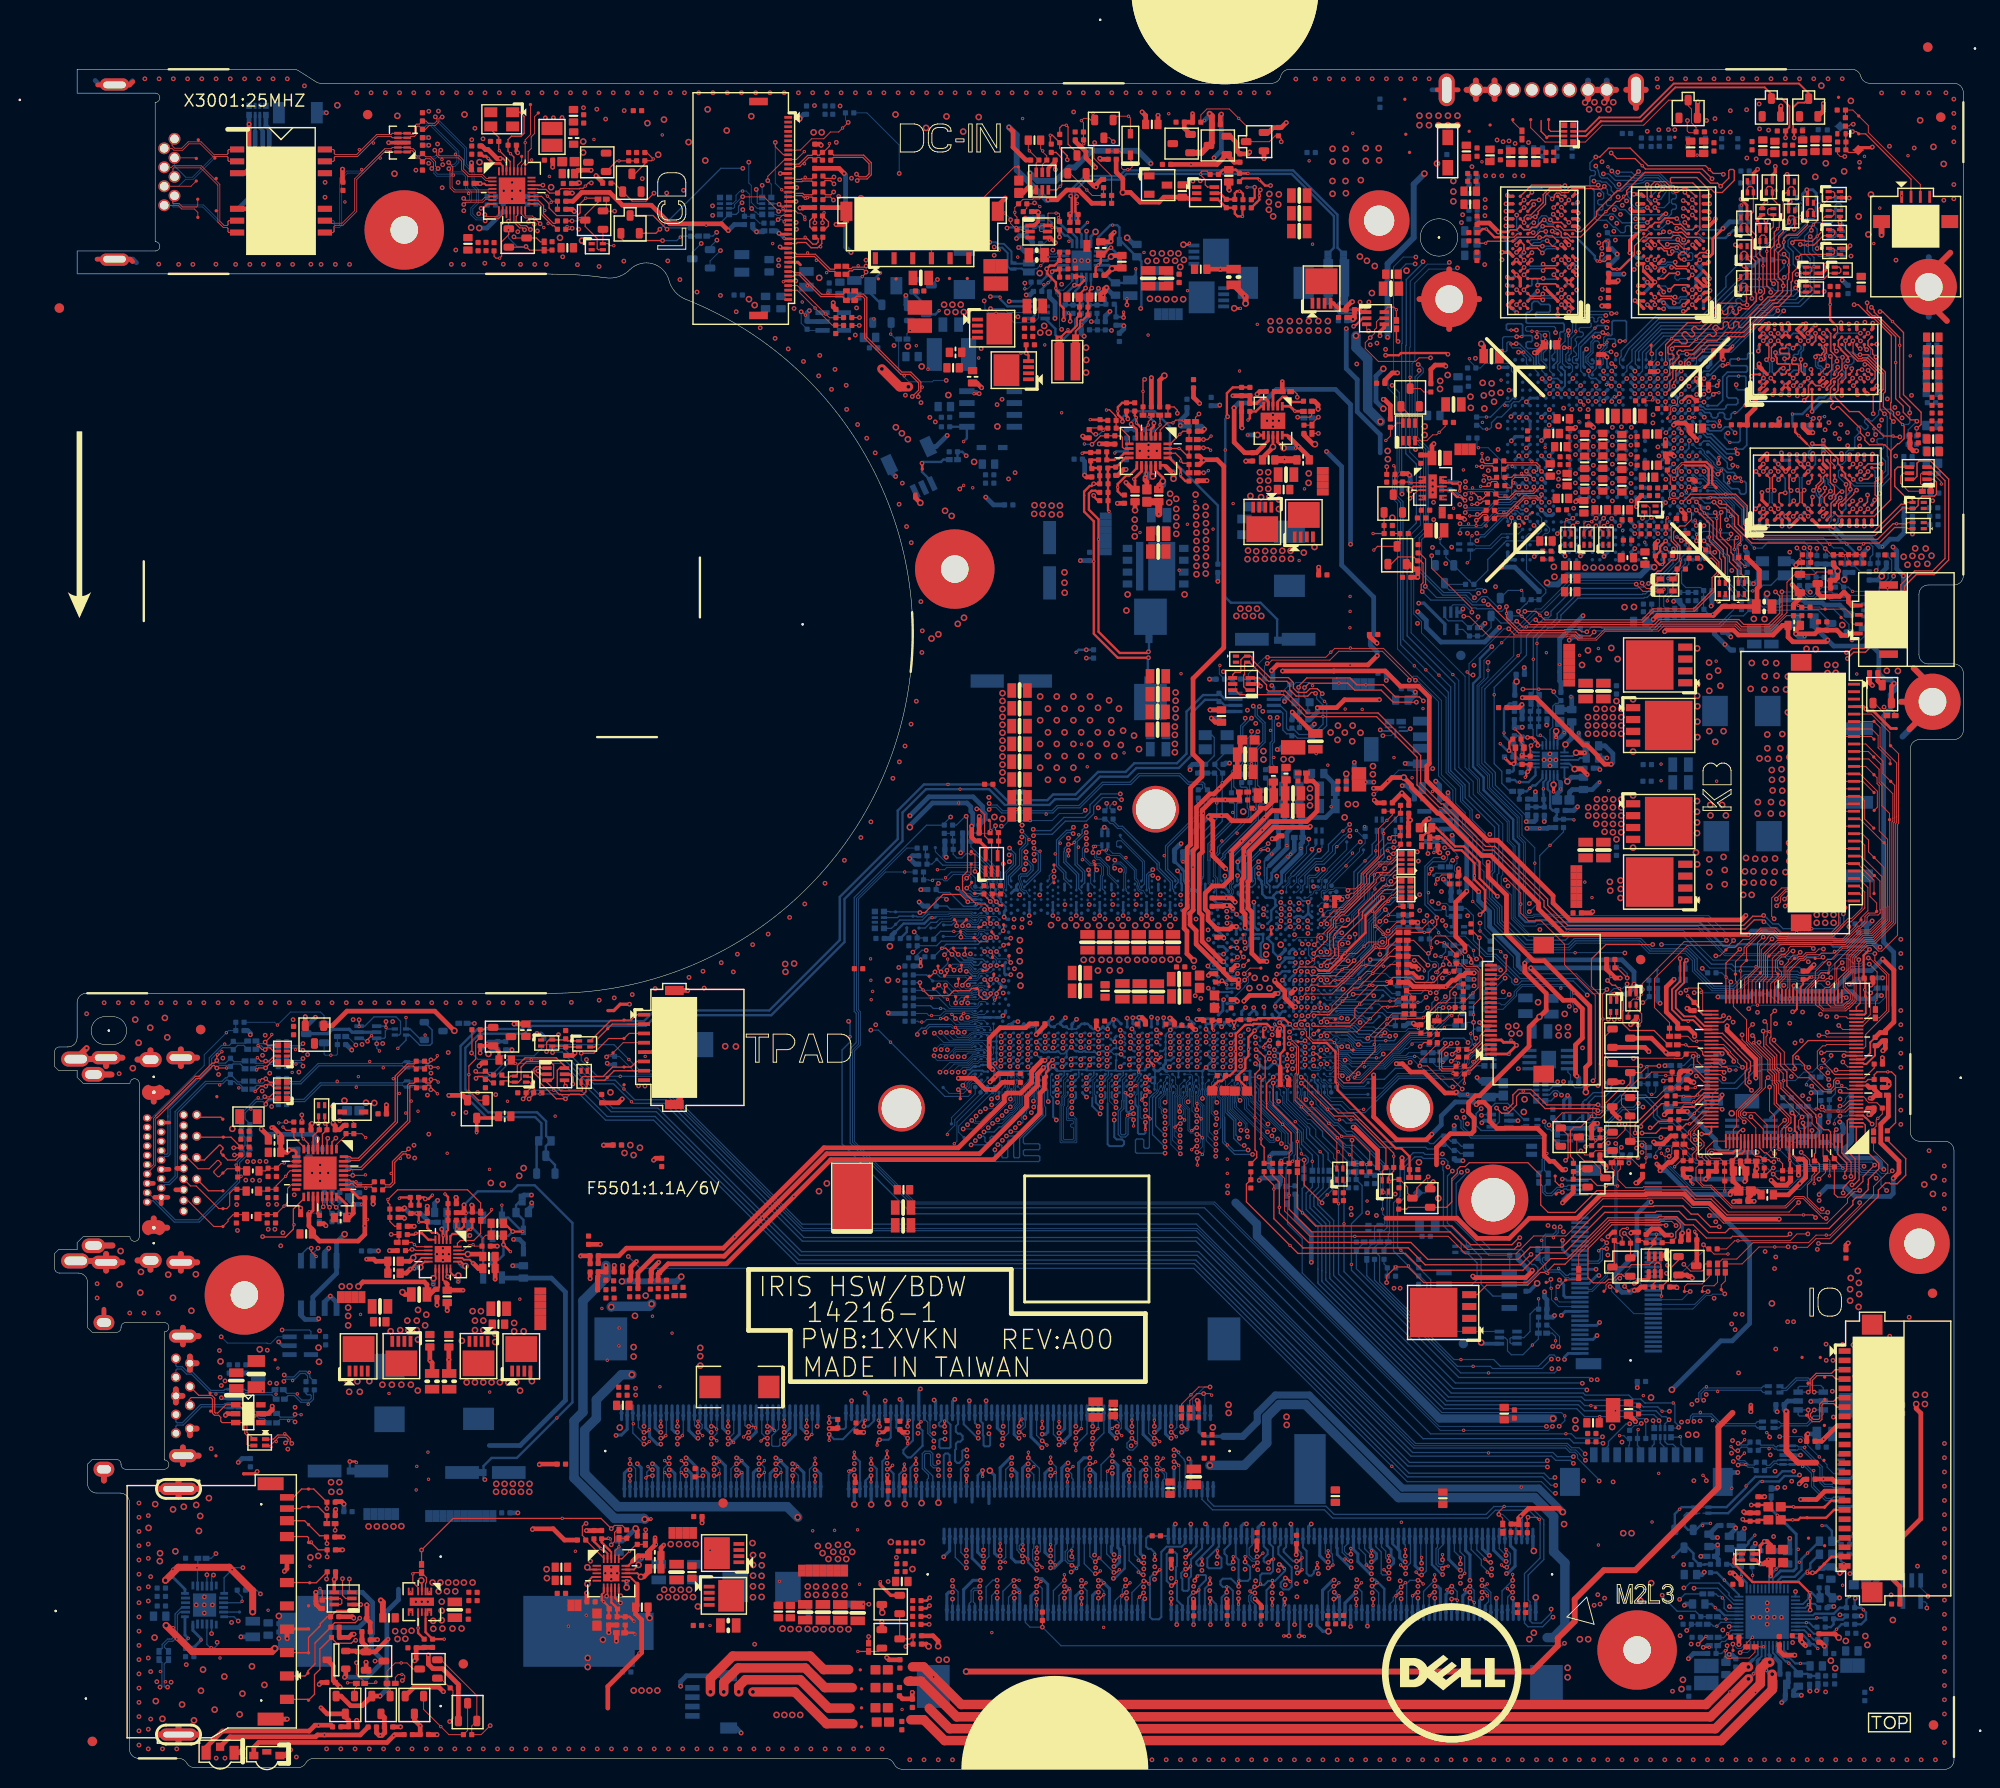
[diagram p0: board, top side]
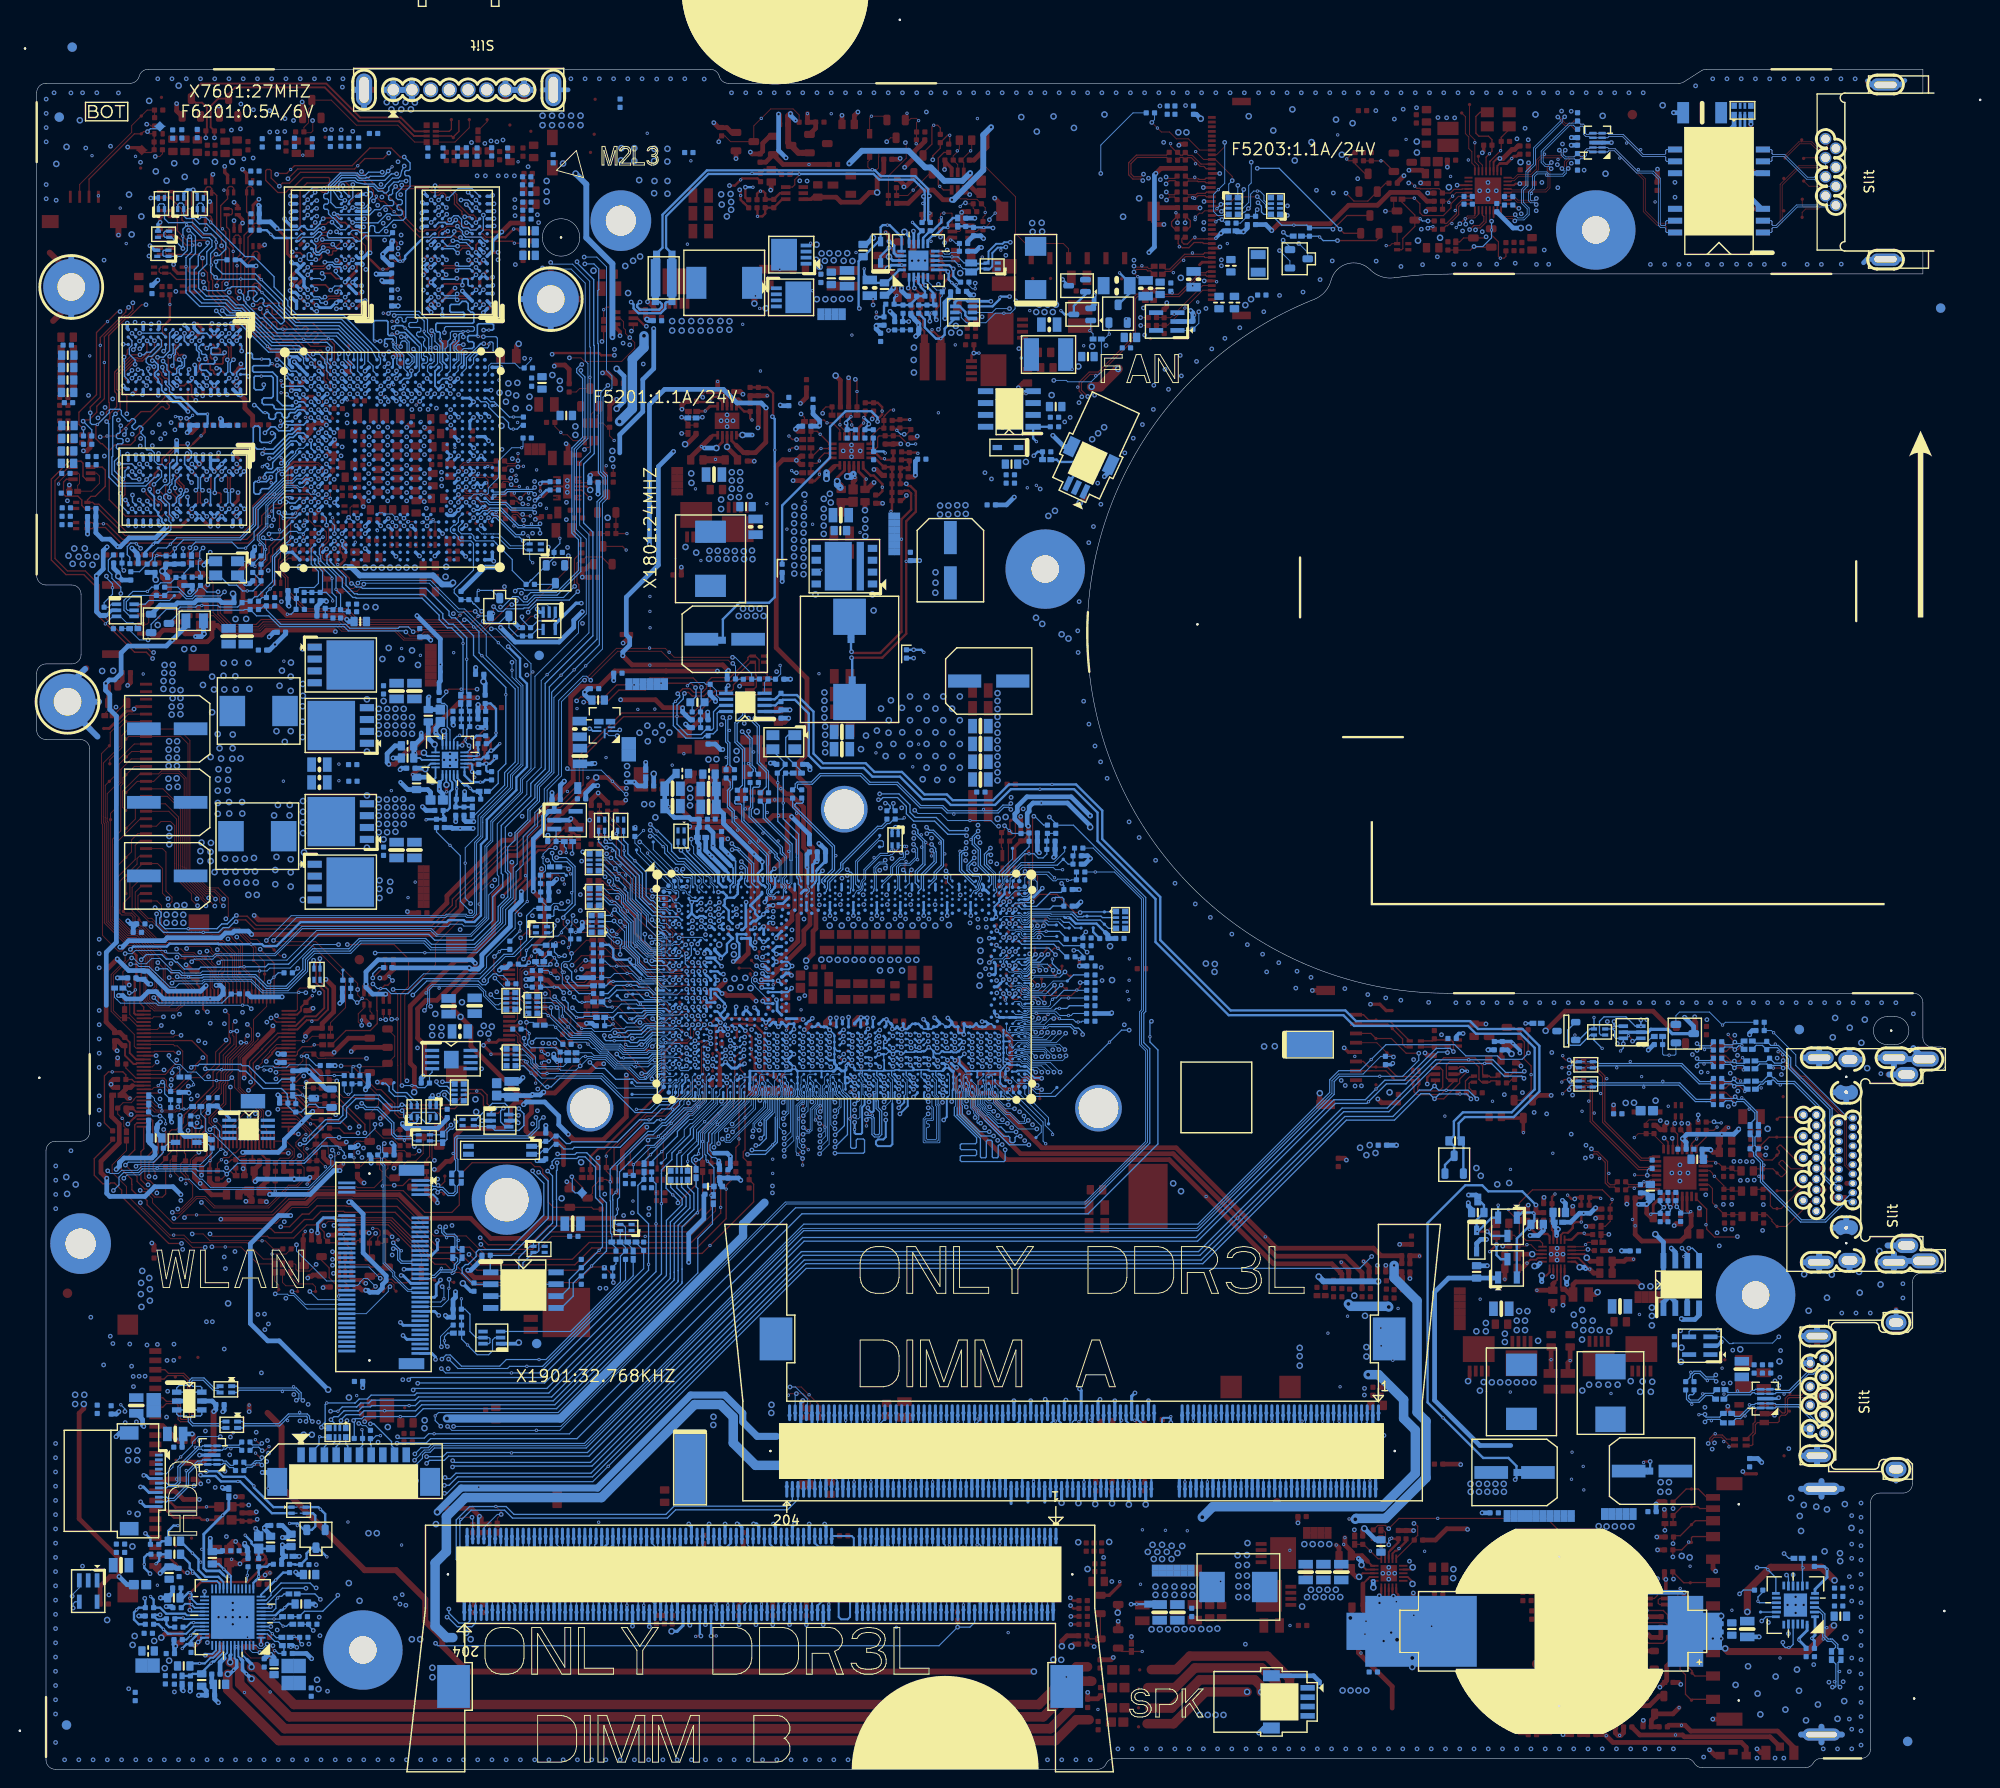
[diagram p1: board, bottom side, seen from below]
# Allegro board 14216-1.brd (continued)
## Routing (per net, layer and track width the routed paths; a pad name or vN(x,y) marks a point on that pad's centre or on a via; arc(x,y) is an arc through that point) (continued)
FBA_D58: length 18.7
  TOP w0.178: v2(175.2,157.58) 175.21,157.58 VRAM7.C2
  L3 w0.165: v2(175.2,157.58) 175.2,157.45 175.57,157.08 176.47,157.08 176.67,156.88 176.67,152.31 176.38,152.01 174.25,152.01 173.76,151.53 172.66,151.53 171.99,152.2 170.43,152.2 169.67,151.44 v2(167.08,151.44)
  BOTTOM w0.127: VRAM7.C2 175.21,157.58 v2(175.2,157.58)
  BOTTOM w0.178: v2(167.08,151.44) 166.99,151.35 GPU1.N27
FBA_D59: length 19.4
  TOP w0.178: VRAM7.C3 174.34,158.43 v2(174.31,158.43)
  L3 w0.165: v2(174.31,158.43) 174.31,157.73 174.75,157.28 174.75,155.87 174.09,155.21 174.09,154.93 174.25,154.77 174.56,154.77 174.72,154.6 174.72,154.27 174.56,154.11 174.25,154.11 174.09,153.94 174.09,153.42 173.75,153.08 170.16,153.08 169.46,152.38 166.9,152.38 v2(166.84,152.43)
  BOTTOM w0.127: VRAM3.D7 174.65,158.77 v2(174.31,158.43) ; GPU1.R27 165.31,151.43 166.07,152.19 166.07,152.47
  BOTTOM w0.178: 166.07,152.47 v1(166.07,152.75) 166.07,153.01 166.17,153.11 166.87,153.11 166.97,153.01 166.97,152.56 v2(166.84,152.43)
FBA_D60: length 21
  TOP w0.178: VRAM7.B8 170.83,157.14 171.09,157.14 171.2,157.03 v2(171.2,156.77) ; v1(166.19,154.99) 166.06,154.99 166.06,154.99 v2(165.63,154.99)
  L3 w0.165: v2(171.2,156.77) 170.76,157.21 170.18,157.21 169.27,156.3 167.86,156.3 166.55,154.99 v2(165.63,154.99)
  BOTTOM w0.127: GPU1.V26 162.84,150.07 162.99,150.22 162.99,150.4 162.87,150.51 162.54,150.51 162.39,150.67 162.39,151.1 162.51,151.23 162.68,151.23 162.81,151.35 162.81,151.54 162.5,151.84 162.5,152.1 162.81,152.4 162.81,152.79 162.68,152.92 162.68,153.11 162.9,153.32 163.34,153.32 163.55,153.54 163.55,153.72 163.42,153.85 163.22,153.85 163.1,153.97 163.1,154.21 163.22,154.33 164.26,154.33 164.38,154.46 164.38,154.74 164.26,154.87 163.57,154.87 163.44,154.99 163.44,155.22 163.65,155.42 164.56,155.42 164.69,155.3 164.69,155.02 164.79,154.92 164.97,154.92 165.1,155.04 165.1,155.3 165.22,155.42 165.48,155.42 165.63,155.27 v2(165.63,154.99) ; v2(171.2,156.77) 170.81,156.37 VRAM3.A2
FBA_D61: length 18.8
  TOP w0.178: v2(172.14,156.33) 171.64,156.33 VRAM7.A7
  L3 w0.165: v2(166.06,154.31) 166.24,154.31 166.43,154.5 167.27,154.5 167.43,154.67 167.43,155.15 167.56,155.28 167.97,155.28 168.09,155.15 168.09,154.67 168.26,154.5 168.52,154.5 168.68,154.65 168.68,155.7 168.83,155.85 169.12,155.85 169.28,155.7 169.28,155.28 169.43,155.13 169.65,155.13 169.76,155.13 169.91,155.28 169.91,156.12 170.04,156.25 170.43,156.25 170.56,156.12 170.56,155.25 170.68,155.13 170.95,155.13 171.27,155.44 171.27,156.23 171.41,156.37 172.1,156.37 v2(172.14,156.33)
  BOTTOM w0.127: GPU1.V27 163.04,151.08 163.04,152.52 163.25,152.73 ; v2(172.14,156.33) 172.1,156.37 VRAM7.A7
  BOTTOM w0.178: v2(166.06,154.31) 165.83,154.54 165.06,154.54 v1(164.78,154.26) 163.25,152.73
FBA_D62: length 18.9
  TOP w0.178: v2(172.14,158.12) 172.11,158.15 172.11,158.26 VRAM7.D7
  L3 w0.165: v2(172.14,158.12) 170.24,158.12 169.95,158.41 169.95,159.13 169.79,159.28 168.83,159.28 166.52,156.97 166.52,156.47 165.95,155.91 v2(165.95,155.62)
  BOTTOM w0.127: v2(172.14,158.12) 172.14,158.21 172.01,158.34 171.73,158.34 171.6,158.21 VRAM3.C3 ; GPU1.W27 162.03,151.34 162.25,151.56 162.25,153.18 162.74,153.67 v1(162.74,153.93) 162.74,155.02 163.43,155.71 165.87,155.71 v2(165.95,155.62)
FBA_D63: length 18.5
  TOP w0.178: v1(167.12,155.86) 167.09,155.83 v2(166.56,155.83) ; VRAM7.C8 170.8,157.97 v2(171.2,157.58)
  L3 w0.165: v2(166.56,155.83) 166.73,155.83 168.56,157.66 171.11,157.66 v2(171.2,157.58)
  BOTTOM w0.127: GPU1.W25 162.39,149.63 162.39,150.22 162.14,150.46 161.94,150.46 161.67,150.72 161.67,151.44 161.93,151.7 161.93,153.36 162.39,153.82 162.39,155.17 163.28,156.06 166.33,156.06 v2(166.56,155.83) ; v2(171.2,157.58) 171.18,157.58 170.8,157.95 VRAM7.C8
FBA_DEBUG0: length 1.3
  TOP w0.102: R7501.1 172.38,146.33 v2(172.33,146.38)
  BOTTOM w0.102: v2(172.33,146.38) 172.36,146.38 GPU1.F22
FBA_DEBUG1: length 2.3
  TOP w0.102: v2(170.7,147.23) 170.97,146.95 v1(170.97,146.59) 170.87,146.49 R7503.1
  BOTTOM w0.102: v2(170.7,147.23) 170.3,146.83 GPU1.J22
FBA_DQM0: length 27.1
  TOP w0.178: VRAM6.E7 185.32,152.51 185.2,152.38 185.2,152.18 185.09,152.08 184.65,152.08 184.55,151.98 184.55,151.66 184.65,151.56 185.5,151.56 185.6,151.46 185.6,151.13 185.46,150.99 v2(185.07,150.99) ; v2(174.87,144.68) 174.9,144.71 v1(175.46,144.71)
  L4 w0.165: v2(174.87,144.68) 174.87,144.88 175.66,145.67 177.1,145.67 177.19,145.58 177.83,145.58 178.11,145.86 180.07,145.86 180.74,146.54 181.38,146.54 181.61,146.76 181.61,147.13 180.74,148 180.74,148.18 181.03,148.46 181.21,148.46 181.82,147.85 182.06,147.85 182.33,148.12 182.33,148.46 182.12,148.67 182.12,149.33 182.29,149.5 183.89,149.5 184.07,149.33 184.25,149.33 184.53,149.62 184.53,149.8 184.36,149.97 184.36,150.21 184.62,150.46 185.34,150.46 185.47,150.59 185.47,150.88 185.36,150.99 v2(185.07,150.99)
  BOTTOM w0.178: VRAM2.E7 186.04,149.75 186.57,149.75 186.75,149.93 186.75,150.26 186.57,150.43 185.28,150.43 185.15,150.57 185.15,150.91 v2(185.07,150.99) ; v2(174.87,144.68) 174.84,144.68 GPU1.D19
FBA_DQM1: length 19.2
  TOP w0.178: VRAM5.E7 185.56,138.48 185.56,137.09 v2(185.77,136.87)
  L4 w0.165: v2(174.03,140.58) 174.32,140.29 174.32,140.06 174.07,139.81 174.07,139.57 174.3,139.34 174.53,139.34 174.79,139.59 175.02,139.59 175.17,139.44 176.57,139.44 177.49,138.52 177.49,138.39 178.11,137.77 179.64,137.77 180.53,136.88 181.79,136.88 182.62,136.05 183.92,136.05 184.96,137.08 185.42,137.08 185.63,136.87 v2(185.77,136.87)
  BOTTOM w0.178: GPU1.D14 174.45,140.18 174.05,140.58 v2(174.03,140.58) ; v2(185.77,136.87) 185.6,136.7 VRAM1.E7
FBA_DQM2: length 28.4
  TOP w0.178: v1(179.85,141.35) 179.85,141 v2(180.03,140.82) ; VRAM5.D3 184.48,135.64 184.48,136.5 184.61,136.63 v2(185.15,136.63)
  L3 w0.165: v2(185.15,136.63) 185.01,136.63 184.86,136.48 184.86,135.03 184.98,134.9 185.49,134.9 185.61,135.03 185.61,136.01 186.03,136.43 186.61,136.43 186.74,136.3 186.74,135.61 186.86,135.49 187.49,135.49 187.62,135.61 187.62,137.12 187.36,137.38 184.46,137.38 183.55,138.29 181.93,138.29 181.42,138.8 181.42,139.8 180.39,140.82 v2(180.03,140.82)
  BOTTOM w0.178: GPU1.C17 175.64,143.04 176.28,143.04 176.76,142.57 177.13,142.57 178.88,140.82 v2(180.03,140.82) ; v2(185.15,136.63) 185.15,138.17 VRAM1.D3
FBA_DQM3: length 23.4
  TOP w0.178: v2(184.1,151.65) 184.1,151.23 184.26,151.07 184.26,150.53 184.36,150.43 185.53,150.43 185.63,150.33 185.63,149.86 185.53,149.76 185.38,149.76 185.26,149.63 185.26,149.46 185.1,149.31 VRAM6.D3
  L3 w0.165: v2(184.1,151.65) 184.1,151.92 183.94,152.08 183.64,152.08 182.56,151.01 181.91,151.01 181.75,150.84 181.75,150.31 181.58,150.14 181.25,150.14 181.09,150.31 181.09,150.84 180.92,151.01 180.31,151.01 179.69,150.38 179.69,150.15 179.86,149.97 179.86,149.74 179.63,149.51 179.4,149.51 179.22,149.68 178.99,149.68 178.77,149.47 178.77,147.98 178.43,147.63 177.52,147.63 177.36,147.79 177.36,148.37 177.26,148.47 176.66,148.47 176.53,148.34 176.53,147.76 176.4,147.63 175.9,147.63 175.67,147.39 v2(175.67,147.16)
  BOTTOM w0.178: VRAM2.D3 184.8,152.3 184.93,152.17 185.42,152.17 185.55,152.05 185.55,151.56 185.42,151.44 184.23,151.44 184.1,151.56 v2(184.1,151.65) ; v2(175.67,147.16) 175.67,147.02 175.42,146.77 GPU1.C22
FBA_DQM4: length 24.8
  TOP w0.178: v2(173.66,160.13) 172.72,160.13 172.16,159.57 VRAM7.E7 ; v1(166.02,148.21) 166.4,148.21 v2(166.55,148.05)
  L4 w0.102: v2(166.55,148.05) 166.19,147.69 166.01,147.69 165.66,148.04 165.66,148.22 166.14,148.7 166.14,150.65 166.15,150.67 166.15,150.67 166.26,150.78 166.27,150.78 166.49,151 166.62,151
  L4 w0.165: v2(173.66,160.13) 173.66,159.86 173.21,159.41 172.05,159.41 171.36,158.72 170.63,158.72 169.6,157.69 168.32,157.69 167.98,157.35 167.98,154.19 167.77,153.98 167.77,153.23 167.89,153.11 167.89,151.61 167.27,151 166.62,151
  BOTTOM w0.127: VRAM3.E7 173.88,159.57 173.73,159.41 173.55,159.41 173.33,159.62 173.33,159.8 v2(173.66,160.13)
  BOTTOM w0.178: v2(166.55,148.05) 166.15,148.46 GPU1.P24
FBA_DQM5: length 23.6
  TOP w0.178: VRAM8.E7 159.23,159.57 v2(159.25,159.58)
  L4 w0.165: v2(162.43,148.88) 162.43,148.62 162.41,148.6 162.41,148.06 162.28,147.93 162,147.93 161.87,148.06 161.87,149.23 162.17,149.53 162.17,149.96 162,150.14 161.29,150.14 160.27,151.16 158.15,151.16 157.79,151.51 157.79,153.67 157.92,153.8 158.39,153.8 158.51,153.93 158.51,154.33 158.39,154.46 157.93,154.46 157.81,154.59 157.81,155.06 157.93,155.18 159.1,155.18 159.23,155.31 159.23,156.6 159.36,156.72 159.75,156.72 159.88,156.85 159.88,158.95 v2(159.25,159.58)
  BOTTOM w0.178: GPU1.W24 162.03,148.48 v2(162.43,148.88) ; VRAM4.E7 160.73,159.5 159.33,159.5 v2(159.25,159.58)
FBA_DQM6: length 21.3
  TOP w0.178: VRAM8.D3 160.57,159 158.78,159 v2(158.65,158.87)
  L3 w0.165: v2(158.65,158.87) 158.65,158.87 158.65,161.46 158.78,161.59 159.05,161.59 159.79,161.59 159.92,161.47 159.92,158.07 159.74,157.88 159.74,153.78 v2(159.44,153.49)
  BOTTOM w0.127: GPU1.AA25 160.35,149.29 159.95,149.69 159.95,151.72
  BOTTOM w0.178: v2(158.65,158.87) 158.65,159.42 158.53,159.55 158.17,159.55 158.04,159.42 158.04,158.9 157.92,158.77 VRAM4.D3 ; 159.95,151.72 159.95,152.49 v1(159.53,152.91) 159.44,152.99 v2(159.44,153.49)
FBA_DQM7: length 20.7
  TOP w0.178: VRAM7.D3 174.68,158.89 173.3,158.89 v2(172.75,158.33) ; v2(165.62,153.79) 165.78,153.64 v1(166.18,153.64)
  L3 w0.165: v2(172.75,158.33) 172.58,158.16 172.58,156.14 171.16,154.72 169.48,154.72 168.86,154.1 166.92,154.1 166.49,153.67 165.74,153.67 v2(165.62,153.79)
  BOTTOM w0.127: v2(172.75,158.33) 172.31,158.77 VRAM3.D3 ; 163.7,152.68 163.27,152.24 163.27,149.67 GPU1.U25
  BOTTOM w0.178: v2(165.62,153.79) 164.82,153.79 163.7,152.68
FBA_DQS_RN0: length 21.6
  TOP w0.152: v2(186.83,150.91) 186.78,150.87 186.78,150.43 186.86,150.36 186.86,149.65 VRAM6.G3
  L4 w0.127: v2(186.83,150.91) 186.83,150.29 186.18,149.63 185.63,149.63 183.22,147.23 183.22,146.96 181.27,145.01 177.02,145.01 176.84,145.18 176.31,145.18 175.12,144 173.97,144 v2(173.26,144.7)
  BOTTOM w0.152: v2(173.26,144.7) 172.85,144.29 GPU1.F19 ; VRAM2.G3 187.1,152.41 187.1,151.93 186.83,151.66 v2(186.83,150.91)
FBA_DQS_RN1: length 18.8
  TOP w0.152: VRAM5.G3 186.96,135.56 186.96,136.71 v2(187.17,136.92)
  L4 w0.127: v2(187.17,136.92) 186.49,137.6 180.85,137.6 180.47,137.98 180.47,138.71 180.11,139.06 178.44,139.06 178.17,139.34 177.61,139.34 177.51,139.44 177.51,140.08 177.01,140.58 176.31,140.58 175.87,140.13 175.61,140.13 175.52,140.23 175.52,140.46 v2(175.65,140.59)
  BOTTOM w0.152: v2(187.17,136.92) 186.94,137.15 186.94,138.26 VRAM1.G3 ; GPU1.C14 175.25,140.19 v2(175.65,140.59)
FBA_DQS_RN2: length 22.2
  TOP w0.152: VRAM5.B7 183.5,138.22 183.5,137.11 v2(183.29,136.9)
  L3 w0.127: v2(179.53,139.6) 179.53,139.82 179.8,140.09 180.36,140.09 180.75,139.69 180.75,137.45 179.83,136.53 179.29,136.53 179.06,136.29 179.06,135.62 179.29,135.38 180.34,135.38 181.05,136.1 181.52,136.1 181.94,136.51 181.94,137.41 182.19,137.67 183.32,137.67 183.54,137.45 183.54,137.15 v2(183.29,136.9)
  BOTTOM w0.152: VRAM1.B7 183.47,135.59 183.47,136.71 v2(183.29,136.9) ; v1(180.06,139.42) 179.88,139.6 v2(179.53,139.6) 179.53,139.32 179.4,139.19 179.08,139.19 178.95,139.32 178.95,139.87 177.02,141.81 GPU1.A16
FBA_DQS_RN3: length 15.2
  TOP w0.152: VRAM6.B7 183.4,152.31 183.4,151.13 v2(183.14,150.88) ; v2(177.45,147.17) 177.63,147.35 v1(178.05,147.35)
  L3 w0.127: v2(177.45,147.17) 177.12,147.17 177.05,147.1 177.05,146.9 177.29,146.67 177.91,146.67 179.18,147.94 179.18,148.71 180.26,149.79 183.25,149.79 183.57,150.11 183.57,150.5 183.19,150.88 v2(183.14,150.88)
  BOTTOM w0.152: v2(183.14,150.88) 183.48,150.54 183.48,149.59 VRAM2.B7 ; v2(177.45,147.17) 177.05,146.77 GPU1.A22
FBA_DQS_RN4: length 23.3
  TOP w0.152: v2(173.37,161.32) 173.37,161.06 173.55,160.89 174.68,160.89 174.8,161.01 VRAM7.G3
  L4 w0.127: v2(165.71,149.68) 165.5,149.68 165.38,149.8 165.38,151.2 166.09,151.91 166.09,153.27 166.31,153.49 166.49,153.49 166.7,153.28 167.07,153.28 167.4,153.61 167.4,153.98 167.19,154.19 167.19,154.37 167.61,154.79 167.61,155.99 167.35,156.25 167.1,156.25 166.98,156.37 166.98,156.65 167.1,156.78 167.35,156.78 167.61,157.04 167.61,157.59 169.31,159.3 169.74,159.3 170.13,159.69 172.61,159.69 173.41,160.49 173.41,161.29 v2(173.37,161.32)
  BOTTOM w0.152: VRAM3.G3 171.68,161.09 172.29,161.09 172.52,161.32 v2(173.37,161.32) ; v2(165.71,149.68) 165.65,149.63 165.65,149.48 165.84,149.29 166.13,149.29 GPU1.P25
FBA_DQS_RN5: length 23.2
  TOP w0.152: VRAM8.G3 160.8,161.04 160.71,160.95 159.41,160.95 v2(159.24,161.11)
  L4 w0.127: v2(161.61,147.24) 161.61,147.46 161.28,147.8 161.28,149.03 159.98,150.33 158.04,150.33 157.15,151.22 157.15,155.24 157.77,155.86 158.23,155.86 158.49,156.12 158.49,156.72 158.39,156.82 158.2,156.82 157.98,157.04 157.98,160.61 158.25,160.88 159.01,160.88 v2(159.24,161.11)
  BOTTOM w0.152: GPU1.W22 161.62,147.24 v2(161.61,147.24) ; v2(159.24,161.11) 159.02,160.89 157.88,160.89 VRAM4.G3
FBA_DQS_RN6: length 18.9
  TOP w0.152: VRAM8.B7 157.6,157.2 157.83,157.43 159.07,157.43 v2(159.21,157.29) ; v2(158.55,153.32) 158.55,153.85 v1(158.58,153.88)
  L3 w0.127: v2(159.21,157.29) 159,157.5 158.49,157.5 158.35,157.36 158.35,156.59 158.48,156.47 159.18,156.47 159.44,156.21 159.44,155.74 159.18,155.48 158.48,155.48 158.35,155.35 158.35,155.07 158.48,154.94 159.18,154.94 159.44,154.68 159.44,154.21 159.18,153.95 157.73,153.95 157.6,153.82 157.6,153.07 157.73,152.95 158.18,152.95 v2(158.55,153.32)
  BOTTOM w0.127: GPU1.AB27 159.32,150.87 159.26,150.93 159.26,151.61 159.55,151.91 159.55,152.38 159.02,152.91 159.02,153.57 158.9,153.7 158.68,153.7 158.55,153.57 v2(158.55,153.32)
  BOTTOM w0.152: VRAM4.B7 160.5,157.47 159.4,157.47 v2(159.21,157.29)
FBA_DQS_RN7: length 20.4
  TOP w0.152: v2(173.27,156.96) 173.27,157.04 172.89,157.42 171.85,157.42 VRAM7.B7 ; v2(165.25,152.29) 165.44,152.48 v1(165.77,152.48)
  L3 w0.127: v2(165.25,152.29) 165.7,152.74 166.47,152.74 167.08,153.35 169.16,153.35 169.84,154.03 172.42,154.03 173.07,154.68 173.07,156.76 v2(173.27,156.96)
  BOTTOM w0.127: GPU1.T27 164.59,150.87 164.69,150.76 164.69,150.53 164.59,150.43 164.33,150.43 164.04,150.72 164.04,151.11 164.58,151.64 164.58,152.67 164.79,152.88 165.1,152.88 165.26,152.72 165.26,152.3 v2(165.25,152.29)
  BOTTOM w0.152: v2(173.27,156.96) 173.79,156.96 173.91,157.09 173.91,157.22 174.04,157.35 174.62,157.35 VRAM3.B7
FBA_EDC0: length 22.4
  TOP w0.152: v2(186.14,150.96) 185.96,150.96 185.86,150.86 185.86,150.5 185.96,150.4 186.44,150.4 186.59,150.25 186.59,149.5 VRAM6.F3
  L4 w0.127: v2(186.14,150.96) 186.19,150.96 186.6,150.54 186.6,150.38 186.08,149.86 185.53,149.86 182.99,147.32 182.99,147.05 181.17,145.24 177.11,145.24 176.94,145.41 176.21,145.41 175.03,144.22 174.06,144.22 173.91,144.38 173.91,144.57 v2(174.06,144.72)
  BOTTOM w0.152: GPU1.E19 174.06,144.7 v2(174.06,144.72) ; v2(186.14,150.96) 186.01,151.08 186.01,151.33 186.14,151.45 186.46,151.45 186.56,151.55 186.56,151.77 186.84,152.04 186.84,152.26 186.59,152.51 VRAM2.F3
FBA_EDC1: length 18.9
  TOP w0.152: v2(186.45,136.91) 186.69,136.67 186.69,135.61 VRAM5.F3
  L4 w0.127: v2(186.45,136.91) 186.57,137.02 186.57,137.2 186.4,137.37 180.76,137.37 180.24,137.89 180.24,138.62 180.02,138.84 178.35,138.84 178.07,139.11 177.52,139.11 177.28,139.35 177.28,139.98 176.92,140.35 176.4,140.35 175.96,139.91 175.52,139.91 175.29,140.13 v2(174.85,140.57)
  BOTTOM w0.152: VRAM1.F3 186.67,138.25 186.67,137.13 v2(186.45,136.91) ; GPU1.C15 174.85,140.61 v2(174.85,140.57)
FBA_EDC2: length 21.6
  TOP w0.152: v2(183.98,136.9) 183.76,137.11 183.76,138.28 VRAM5.C7
  L3 w0.127: v2(183.98,136.9) 183.77,137.1 183.77,137.54 183.41,137.9 182.1,137.9 181.71,137.51 181.71,136.6 181.43,136.32 180.96,136.32 180.25,135.61 179.39,135.61 179.29,135.71 179.29,136.2 179.39,136.3 179.92,136.3 180.98,137.36 180.98,139.79 180.46,140.31 v2(179.29,140.31)
  BOTTOM w0.152: GPU1.B16 176.42,142.18 177.02,142.18 178.89,140.31 v2(179.29,140.31) ; VRAM1.C7 183.74,135.58 183.74,136.66 v2(183.98,136.9)
FBA_EDC3: length 14.6
  TOP w0.152: VRAM6.C7 183.67,152.18 183.67,151.01 v2(183.8,150.88)
  L3 w0.127: v2(176.44,147.19) 177.19,146.44 178,146.44 179.41,147.84 179.41,148.61 180.36,149.56 183.34,149.56 183.8,150.02 v2(183.8,150.88)
  BOTTOM w0.152: v2(183.8,150.88) 183.75,150.83 183.75,149.56 VRAM2.C7 ; v2(176.44,147.19) 176.44,147.15 176.06,146.77 GPU1.B22
FBA_EDC4: length 23.4
  TOP w0.152: VRAM7.F3 174.55,160.62 173.44,160.62 173.29,160.77 172.99,160.77 v2(172.98,160.77)
  L4 w0.127: v2(165.73,148.87) 165.73,149.05 165.15,149.62 165.15,151.3 165.86,152 165.86,153.37 166.21,153.72 166.58,153.72 166.79,153.51 166.97,153.51 167.17,153.71 167.17,153.89 166.96,154.1 166.96,154.47 167.38,154.89 167.38,155.89 167.25,156.02 167.01,156.02 166.75,156.28 166.75,156.75 167.01,157.01 167.25,157.01 167.38,157.14 167.38,157.69 169.22,159.52 169.64,159.52 170.04,159.92 172.52,159.92 172.98,160.39 v2(172.98,160.77)
  BOTTOM w0.152: v2(165.73,148.87) 165.71,148.87 GPU1.R25 ; v2(172.98,160.77) 172.98,160.96 172.89,161.06 172.63,161.06 172.4,160.82 171.76,160.82 171.65,160.71 171.65,160.42 VRAM3.F3
FBA_EDC5: length 23.3
  TOP w0.152: v2(159.24,160.42) 159.5,160.68 160.51,160.68 160.8,160.39 VRAM8.F3
  L4 w0.127: v2(159.24,160.42) 159.01,160.65 158.35,160.65 158.21,160.52 158.21,157.13 158.3,157.05 158.48,157.05 158.72,156.81 158.72,156.03 158.33,155.63 157.87,155.63 157.38,155.14 157.38,151.31 158.13,150.55 160.08,150.55 161.51,149.12 161.51,147.89 161.76,147.64 162.26,147.64 162.4,147.49 v2(162.4,147.25)
  BOTTOM w0.152: GPU1.W23 162.03,147.62 v2(162.4,147.25) ; v2(159.24,160.42) 159.04,160.63 157.86,160.63 VRAM4.F3
FBA_EDC6: length 18.3
  TOP w0.152: VRAM8.C7 157.87,157.7 158.98,157.7 v2(159.21,157.92)
  L3 w0.127: v2(159.21,157.92) 159.01,157.73 158.39,157.73 158.12,157.45 158.12,156.5 158.38,156.24 159.08,156.24 159.21,156.11 159.21,155.83 159.08,155.7 158.38,155.7 158.12,155.44 158.12,154.97 158.38,154.71 159.08,154.71 159.21,154.59 159.21,154.31 159.08,154.18 157.63,154.18 157.37,153.92 157.37,152.98 157.63,152.72 158.33,152.72 v2(158.55,152.5)
  BOTTOM w0.127: GPU1.AB26 159.55,150.32 159.03,150.84 159.03,151.71 159.33,152 159.33,152.29 159.11,152.5 v2(158.55,152.5)
  BOTTOM w0.152: VRAM4.C7 160.57,157.74 159.4,157.74 v2(159.21,157.92)
FBA_EDC7: length 20.3
  TOP w0.152: VRAM7.C7 171.88,157.69 173,157.69 173.1,157.59 v2(173.36,157.59) ; v1(164.63,153.33) v2(165.19,153.33)
  L3 w0.127: v2(173.36,157.59) 173.26,157.59 172.84,157.16 172.84,154.77 172.32,154.26 169.75,154.26 169.07,153.58 166.98,153.58 166.37,152.96 165.55,152.96 v2(165.19,153.33)
  BOTTOM w0.127: GPU1.T26 164.37,150.07 163.81,150.62 163.81,151.2 164.35,151.74 164.35,152.76 164.91,153.33 v2(165.19,153.33)
  BOTTOM w0.152: v2(173.36,157.59) 173.53,157.42 173.73,157.42 173.93,157.62 174.54,157.62 174.8,157.88 VRAM3.C7
FBA_PLL_AVDD: length 13.7
  TOP w0.508: v2(172.33,142.34) 172.32,142.33 C7506.1
  L4 w0.508: v2(172.33,142.34) 172.24,142.34 171.66,142.93 171.66,146.28 v2(171.53,146.41) 170.69,146.41 169.95,145.67 166.16,145.67 165.72,146.12 v2(165.72,146.46)
  BOTTOM w0.356: v2(172.33,142.34) 172.33,142.29 172.81,141.82 GPU1.F16 ; v2(165.72,146.46) 166.09,146.83 GPU1.P22 ; v2(171.53,146.41) 171.11,146.83 GPU1.H22
  vias: v1(163.08,144.28)
FBA_VREF_0: length 58.4
  TOP w0.18: VRAM6.M8 190.83,152.94 190.83,152.32 191.08,152.07 191.08,151.97 191.9,151.15 191.9,150.85 v2(191.83,150.78) ; VRAM5.M8 191.2,139.34 190.78,139.76 190.78,140.26 189.29,141.75 188.19,141.75 v2(188.04,141.9)
  TOP w0.203: v2(192.11,137.02) 192.11,137.72 191.58,138.25 191.58,138.68 191.2,139.06 VRAM5.M8
  TOP w0.254: VRAM6.H1 188.02,147.69 v2(188.02,145.34)
  TOP w0.356: VRAM5.H1 188.08,133.72 188.45,133.35 188.79,133.01 v2(190.28,133.01)
  L4 w0.2: 189.36,152.2 188.81,151.65 188.17,151.65 187.9,151.39 187.9,150.49 188.7,149.69 188.7,146.03 v2(188.02,145.34)
  L4 w0.3: v2(188.04,141.9) 187.5,142.44 187.5,144.83 v2(188.02,145.34) ; 189.36,152.2 189.81,152.65 189.81,154.29 189.5,154.59 v2(188.38,154.59)
  BOTTOM w0.18: v2(191.83,150.78) 191.65,150.78 191.2,150.33 191.2,149.83 191.57,149.46 191.57,149.16 191.2,148.79 VRAM2.M8 190.83,148.14 190.83,147.62 190.38,147.16 190.36,147.16 ; VRAM1.H1 187.96,140.12 187.65,140.43 187.65,141.03 188.04,141.43 v2(188.04,141.9)
  BOTTOM w0.203: v2(190.28,133.01) 190.61,133.34 190.61,133.35 190.82,133.56 190.82,133.88 191.2,134.26 VRAM1.M8 191.62,134.94 191.62,136.24 192.11,136.73 v2(192.11,137.02)
  BOTTOM w0.35: 190.36,147.16 189.61,146.41 189.08,146.41 v2(188.02,145.34)
  BOTTOM w0.356: v2(188.38,154.59) 188,154.21 VRAM2.H1
  BOTTOM w0.508: R7806.2 197.87,134.95 C7803.1 R7807.1 197.87,132.36 197.18,131.68 196.35,131.68 195.54,130.87 v1(195.54,130.86) 195.25,130.86 194.31,131.81 191.48,131.81 v2(190.28,133.01)
FBA_VREF_1: length 55
  TOP w0.18: v2(173.54,165.99) 173.48,166.05 172.28,166.05 171.79,165.57 171.2,165.57 VRAM7.M8 170.67,165.17 170.27,164.77 169.67,164.77 169.35,164.46 169.19,164.29 ; v2(159.36,165.84) 159.23,165.84 158.45,165.07 158.06,165.07 157.79,164.8 157.17,164.8 VRAM8.M8 156.41,164.78 155.75,164.78 155.54,164.56
  TOP w0.3: 155.54,164.56 v2(154.44,164.56) ; VRAM7.H1 176.46,161.91 177.07,161.91 177.39,162.23 177.39,163.83 v2(178.49,164.93)
  TOP w0.356: VRAM8.H1 162.8,161.57 v2(162.8,161.57)
  TOP w0.4: 169.19,164.29 168.53,163.64 v2(168.53,162.32)
  TOP w0.508: R7903.2 152.32,165.51 153.49,165.51 v2(154.44,164.56)
  L4 w0.3: v2(168.53,162.32) 167.27,161.07 164.86,161.07 164.65,161.28 163.1,161.28 v2(162.8,161.57) 162.29,162.08 159.72,162.08 159.44,161.8 158.92,161.8 158.62,162.1 158.62,162.88 157.82,163.68 155.32,163.68 v2(154.44,164.56)
  BOTTOM w0.18: VRAM4.M8 161.2,165.57 160.5,165.57 160.34,165.41 159.8,165.41 v2(159.36,165.84) ; VRAM3.M8 175.23,164.8 174.54,164.8 173.87,165.47 173.87,165.66 v2(173.54,165.99)
  BOTTOM w0.203: v2(178.49,164.93) 178.48,164.93 178.34,164.79 176.24,164.79 175.86,165.17 VRAM3.M8
  BOTTOM w0.356: VRAM4.H1 155.42,162.55 155.42,163.59 v2(154.44,164.56) ; v2(168.53,162.32) 168.73,162.32 169.29,161.76 169.79,161.76 VRAM3.H1
  BOTTOM w0.508: v2(178.49,164.93) 179.2,165.64 R7904.1 C7902.1 180.39,167.34 v1(180.46,167.42)
FBA_ZQ0: length 6.1
  BOTTOM w0.127: VRAM1.L8 190.4,134.29 190.06,133.95 190.06,133.63 189.84,133.42 189.84,132.7 190.09,132.46
  BOTTOM w0.254: 190.09,132.46 191.22,131.32 191.55,131.32 v1(191.73,131.14) 192.58,130.29 R7808.2
FBA_ZQ1: length 7.5
  BOTTOM w0.127: 189.75,147.28 190,147.53 190,147.87 190.4,148.27 VRAM2.L8
  BOTTOM w0.254: R7809.2 185.91,144.05 v1(185.91,145.07) 186.98,145.07 188.76,146.84 189.31,146.84 189.75,147.28
FBA_ZQ2: length 5.3
  BOTTOM w0.127: 176.84,163.91 176.33,163.91 175.88,164.37 VRAM3.L8
  BOTTOM w0.254: R7912.2 179.59,164.75 v1(179.14,164.3) 178.75,163.91 176.84,163.91
FBA_ZQ3: length 6.2
  BOTTOM w0.127: VRAM4.L8 161.79,164.37 162.16,163.99 162.77,163.99 163.1,163.67
  BOTTOM w0.254: R7913.2 165.96,161.89 165.51,161.45 v1(165.03,161.45) 164.78,161.7 164.78,161.99 163.1,163.67
FBA_ZQ5: length 7.1
  TOP w0.127: VRAM5.L8 190.4,139.57 190,139.97 190,140.65 189.19,141.47 187.88,141.47 187.46,141.89
  TOP w0.254: 187.46,141.89 v1(186.61,142.73) 186.21,143.14 R8002.2
FBA_ZQ6: length 5
  TOP w0.127: VRAM6.L8 190.4,153.52 190.74,153.86 190.74,154.37 190.43,154.69
  TOP w0.254: 190.43,154.69 189.95,155.17 v1(189.95,156.79) R8001.2
FBA_ZQ7: length 6.8
  TOP w0.127: VRAM7.L8 170.56,164.37 170.21,164.02 169.96,164.02 169.01,163.07 169.01,162.12 168.48,161.59
  TOP w0.254: R8102.2 166.68,160.57 v1(167.15,160.57) 167.46,160.57 168.48,161.59
FBA_ZQ8: length 5.3
  TOP w0.127: 155.6,163.99 156.11,163.99 156.49,164.37 VRAM8.L8
  TOP w0.254: R8101.2 152.38,164.49 152.76,164.88 v1(153.17,164.88) 154.05,163.99 155.6,163.99
FON#: length 3.6
  BOTTOM w0.254: v1(97.24,142.12) 97.59,142.47 FAN261.1 R2605.2
GC6_FB_EN: length 196.9
  TOP w0.127: v2(183.86,63.71) 184.38,63.19 R2451.1 ; v2(146.92,86.08) 146.92,86.09 145.93,87.09 144.77,87.09 R2028.1 ; D8301.1 167.86,52.78 167.63,53 167.26,53 166.71,52.46 166.23,52.46 165.84,52.07 164.6,52.07 164.04,52.63 164.04,55.73 166.59,58.28 172.33,58.28 v2(172.4,58.22) ; v2(172.35,130.67) 173.08,129.94 R7519.2
  L4 w0.127: v2(195.99,61.96) 196.22,62.18 196.22,63.81 196.15,63.89 196.15,65.18 195.17,66.16 195.17,69.13 195.18,69.14 195.18,71.68 194.52,72.34 194.52,75.79 194.28,76.03 194.28,82.46 194.74,82.91 194.74,84.34 192.86,86.21 192.83,86.21 192.57,86.48 192.57,86.51 192.56,86.51 192.56,89.1 193.33,89.86 193.33,116.51 194.28,117.46 194.28,120.31 194.75,120.78 194.75,124.64 195.21,125.1 195.21,125.85 v2(195.2,125.85) 194.75,125.85 192.57,125.85 192.21,125.49 183.84,125.49 183.64,125.29 181.8,125.29 178.04,129.06 177.15,129.06 175.87,130.34 173.57,130.34 173.42,130.19 172.73,130.19 172.37,130.55 172.37,130.62 172.35,130.64 v2(172.35,130.67) ; 171.28,65.54 171.28,65.2 172.21,64.27 172.21,58.41 v2(172.4,58.22) ; 171.28,65.54 v2(171.29,65.54) ; 171.28,65.54 171.28,66.23 171.48,66.43 171.48,66.76 171.52,66.79 171.52,67.33 171.4,67.45 171.4,67.84 171.77,68.22 171.77,69.53 171.48,69.82 171.48,70.89 169.2,73.17 168.8,73.17 163.93,78.05 162.88,78.05 162.42,77.58 160.5,77.58 159.52,78.56 159.52,80.65 159.08,81.09 157.9,81.09 157.33,81.65 155.85,81.65 153.28,84.23 153.28,86.39 152.33,87.35 151.68,87.35 150.95,86.62 147.46,86.62 v2(146.92,86.08)
  BOTTOM w0.127: v2(195.2,125.85) 195.2,126.54 196.15,127.49 196.15,127.9 196.53,128.28 196.53,129.44 R7623.1 ; v2(171.29,65.54) 171.29,66.03 v1(171.75,66.49) 171.98,66.72 173.7,66.72 175.55,64.87 182.7,64.87 v2(183.86,63.71) 184.2,64.05 186.95,64.05 187.18,64.27 192.89,64.27 193.3,63.87 194.9,63.87 195.39,63.39 195.39,62.56 v2(195.99,61.96)
GC6_FB_EN_GPU: length 25.1
  TOP w0.127: v2(175.63,133.13) 175.63,133.59 v1(175.51,133.71)
  L4 w0.127: v2(175.63,133.13) 176.04,133.54 176.62,133.54 179.05,131.11 179.05,131.02 179.92,130.15 181.21,130.15 181.76,130.7 185.81,130.7 186.08,130.43 186.08,130.41 186.41,130.08 190.61,130.08 191.35,129.34 193.85,129.34 v2(194.87,128.32)
  BOTTOM w0.127: R7623.2 195.09,129.15 R7627.1 195.07,128.52 v2(194.87,128.32) ; GPU1.C6 175.25,133.51 v2(175.63,133.13)
GC6_FB_EN_KBC: length 4.6
  TOP w0.127: R2451.2 184.86,64.82 v1(184.43,65.25) 184.21,65.48 183.64,65.48 183.13,65.99 182.92,65.99 182.4,66.51 KBC24.106
GC6_FB_EN_MCP: length 12.5
  TOP w0.127: v2(134.73,80.67) 134.83,80.77 136.35,80.77 v1(137.81,82.22) 138.32,82.74 138.32,82.99 138.96,83.63 139.44,83.63 142.84,87.02 R2028.2
  BOTTOM w0.127: v2(134.73,80.67) 134.73,80.42 CPU1.AG5
GPIO5_GC6_PWR_EN: length 46.3
  TOP w0.127: Q8301.G 142.97,129 143.75,129.77 145.41,129.77 R8301.1 146.15,129.35 146.4,129.1 146.4,127.01 146.2,126.81 146.2,126.18 v2(146.31,126.06) ; v2(155.32,124.46) v1(155.32,123.72) 155.32,123.3 156.72,121.91 161.48,121.91 161.57,121.99 163.12,121.99 163.36,121.76 v2(163.92,121.76)
  BOTTOM w0.127: v2(163.92,121.76) 164.44,122.28 165.39,122.28 165.53,122.14 170.7,122.14 171.13,122.56 178.06,122.56 179.62,124.12 R8315.2 179.9,124.54 180.3,124.14 R7636.2 ; v2(146.31,126.06) 147.22,125.16 150.7,125.16 151.54,124.31 152.05,124.31 152.14,124.22 154.02,124.22 154.28,123.96 154.82,123.96 v2(155.32,124.46)
GPIO5_GC6_PWR_EN#: length 4.9
  TOP w0.127: v1(141.13,130.51) 141.52,130.9 Q8301.D 143.93,131.21 R8302.2 143.92,132.28 R8303.1
GPIO5_GC6_PWR_EN_GPU: length 8.1
  BOTTOM w0.127: GPU1.A3 177.4,131.07 178.74,129.73 178.74,126.83 v1(179.22,126.35) 179.62,125.95 R7633.2 180.07,125.43 R7636.1
GPIO5_GC6_PWR_EN_R#: length 3.5
  TOP w0.127: Q8302.G 142.22,134.53 C8301.2 142.24,133.12 R8303.2 v1(141.05,132.28)
GPIO9_ALERT: length 33.1
  L4 w0.127: v2(196.74,127.72) 194.33,130.12 191.18,130.12 189.37,131.92 180.66,131.92 179.83,132.76 179.33,132.76 179.25,132.69 178.52,132.69 177.05,134.16 176.42,134.16 176.08,134.5 176.08,134.95 175.81,135.22 173.78,135.22 173.36,135.64 v2(173.24,135.64)
  BOTTOM w0.127: v2(196.74,127.72) 196.74,127.55 196.09,126.9 v1(196.09,126.47) 196.09,125.77 196.99,124.88 R7612.1 196.51,124.39 196.19,124.71 Q7602.1 ; v2(173.24,135.64) 173.21,135.62 173.21,135.61 GPU1.F8
GPIO10_FBVREF: length 16.6
  TOP w0.127: v2(179.97,131.83) 179.7,131.56 v1(179.7,130.58)
  L4 w0.127: v2(188.53,130.69) 187.53,131.68 180.11,131.68 v2(179.97,131.83)
  BOTTOM w0.127: R7610.1 v2(188.53,130.69) ; v2(179.97,131.83) 179.76,131.62 178.02,131.62 177.81,131.83 177.81,131.83 177.13,132.5 176.37,132.5 176.21,132.34 175.65,132.34 175.27,132.72 GPU1.C5
GPU_CLKREQ#: length 18.2
  BOTTOM w0.127: GPU1.AC6 158.65,133.4 159.08,132.97 159.08,132.56 158.77,132.25 157.69,132.25 157.43,131.99 157.43,131.71 157.21,131.49 155.29,131.49 155.04,131.24 155.04,131.22 153.32,129.5 153.32,128.32 R7305.2 151.72,126.84 151.43,127.13 151.43,127.19 151.32,127.31 151.25,127.31 Q7301.S 148.85,129.71 R7303.1 148.85,130.58 148.22,131.21 v1(148.22,131.76)
GPU_EVENT#: length 94.8
  TOP w0.127: v2(146.64,126.62) 146.63,126.62 146.67,126.66 146.67,129.54 146.01,130.2 R7648.1 ; v2(147.86,91.16) 147.86,90.39 147.06,89.59 v1(146.53,89.59) R2029.1 ; v2(153.37,124.67) 153.6,124.67 156.61,121.65 161.59,121.65 161.67,121.74 162.75,121.74 163.17,121.32 164.27,121.32 v2(164.7,121.75)
  L3 w0.127: v2(153.37,124.67) 153.37,123.78 152.57,122.98 152.57,120.26 154.05,118.79 154.05,118.21 153.7,117.86 153.7,111.87 151.62,109.78 151.62,101.91 151.06,101.35 151.06,99.45 149.2,97.59 v2(148.57,97.59)
  BOTTOM w0.127: v2(153.37,124.67) 153.34,124.64 151.65,124.64 150.86,125.43 147.84,125.43 v2(146.64,126.62) ; v2(147.86,91.16) 147.86,91.18 147.71,91.33 147.71,91.43 146.59,92.54 146.59,96.65 147.54,97.59 v2(148.57,97.59) ; v2(164.7,121.75) 164.81,121.86 170.86,121.86 171.3,122.31 178.2,122.31 179.36,123.47 180.68,123.47 R7644.1 181.99,124.14 182.05,124.07 188.67,124.07 190.05,122.7 Q7606.D
GPU_EVENT_GPU#: length 21.6
  BOTTOM w0.127: GPU1.A4 177.42,131.3 177.49,131.3 178.97,129.82 178.97,127.12 180.58,125.52 180.87,125.52 R7644.2 182.07,125.03 R7649.1 182.69,124.41 184.65,124.41 184.82,124.58 186.53,124.58 v1(186.54,124.58) 186.54,124.58 186.99,124.58 187.17,124.41 188.84,124.41 189.07,124.18 190.32,124.18 191.42,123.07 191.44,123.07 191.96,122.55 Q7606.S
GPU_EVENT_MCP#: length 13.4
  TOP w0.127: v2(134.01,83.51) 134.45,83.95 135.07,83.95 135.21,83.82 137.15,83.82 137.74,84.41 137.82,84.41 141.38,87.97 v1(141.38,87.99) 141.54,87.99 141.67,87.87 142.13,87.87 142.33,87.87 142.72,88.26 142.72,88.82 143.49,89.59 R2029.2
  BOTTOM w0.127: v2(134.01,83.51) 133.83,83.33 CPU1.AB6
GPU_PEX_RST#: length 60.9
  TOP w0.127: v2(156.6,123.96) 156.6,123.79 156.98,123.41 v1(156.98,123.4) 157.1,123.28 157.12,123.28 157.86,122.53 171.14,122.53 171.69,123.07 180.18,123.07 180.71,122.55 183.35,122.55 184.56,123.75 184.56,125.58 v2(184.1,126.03)
  BOTTOM w0.127: GPU1.AC7 159.08,133.94 159.08,133.5 159.39,133.19 159.57,133.19 159.93,132.83 159.93,132.51 159.71,132.29 159.43,132.29 159.08,131.94 159.08,131.71 158.86,131.49 157.73,131.49 157.47,131.23 157.47,128.35 159.53,126.3 159.53,125.92 R7312.2 158.8,125.2 R7308.1 157.84,125.2 157.56,124.92 157.56,124.84 157.45,124.73 157.37,124.73 v2(156.6,123.96) ; v2(184.1,126.03) 184.53,125.6 187.23,125.6 187.53,125.3 188.21,125.3 188.94,126.03 190.13,126.03 R7313.2 R7613.1 193.94,125.65 194.61,124.98 194.61,124.21 194.46,124.06 Q7602.5
GPU_PEX_RST_D#: length 3.7
  BOTTOM w0.127: R7308.2 157.08,126.04 v1(156.93,126.19) 155.49,126.19 D7301.3
GPU_PEX_RST_HOLD: length 29.3
  TOP w0.127: v2(157.29,123.95) 158.5,123.95 158.78,123.66 v1(158.91,123.54) 159.41,123.04 169.8,123.04 170.98,124.22 175.34,124.22 177.31,126.2 177.31,127.56 177.83,128.08 177.83,129.08 177.28,129.63 R7630.2 R7631.2
  BOTTOM w0.127: v2(157.29,123.95) 156.8,123.46 D7301.1
GPU_PEX_RST_HOLD_GPU#: length 2.6
  TOP w0.127: v1(175.67,132.18) 175.67,132.18 175.65,132.16 v2(175.65,131.5) 176.62,130.52 R7630.1
  BOTTOM w0.127: GPU1.C4 175.28,131.87 175.64,131.52 175.64,131.5 v2(175.65,131.5)
GPU_PLL_VDD: length 0.6
  BOTTOM w0.356: v2(169.04,133.05) 169.02,133.08 169.02,133.15 168.65,133.51 GPU1.L6
  vias: v1(170.11,131.35)
H_CATERR#: length 5.5
  BOTTOM w0.089: 98.1,89.12 98.11,89.12 98.62,89.12 98.82,89.32 98.82,89.51 99,89.69 99.4,89.69 99.65,89.44 CPU1.K61
  BOTTOM w0.102: TP402.1 96.36,89.15 96.69,89.49 97.14,89.49 97.5,89.12 98.1,89.12
H_CPU_SVIDALRT#: length 5.8
  BOTTOM w0.14: R701.2 94.04,86.97 v1(94.94,87.87) 95.38,88.31 98.79,88.31 CPU1.L62
H_CPU_SVIDCLK: length 91.4
  TOP w0.14: v1(123.72,142.71) 123.34,142.34 v2(122.9,142.34) PR4616.2
  L3 w0.127: v2(122.9,142.34) 123.44,142.88 123.44,144.68 122.4,145.72 113.89,145.72 111.84,143.68 106.32,143.68 101.6,138.96 101.6,133.62 102.34,132.88 102.34,121.84 101.19,120.69 96.18,115.68 96.18,106.31 93.7,103.83 93.7,96.84 93.58,96.72 91.54,94.67 91.54,92.1 93.71,89.93 93.71,87.87 94.39,87.19 v2(95.2,87.19)
  BOTTOM w0.14: CPU1.N63 95.91,87.9 v2(95.2,87.19)
H_CPU_SVIDDAT: length 101.6
  TOP w0.14: PR4619.2 v2(122.92,138.78)
  L3 w0.127: v2(91.82,87.47) 92.4,88.05 92.4,89.87 90.45,91.83 90.45,94.95 92.74,97.24 92.74,104.23 93.73,105.22 95.22,106.71 95.22,115.28 95.22,116.08 100.79,121.65 100.79,121.65 101.38,122.24 101.38,132.48 100.64,133.22 100.64,139.36 105.92,144.64 111.44,144.64 113.49,146.69 121.42,146.69 121.88,147.15 123.2,147.15 123.98,146.36 123.98,145.5 124.41,145.08 124.41,140.27 v2(122.92,138.78)
  BOTTOM w0.14: CPU1.L63 94.85,88.65 94.36,88.16 R704.2 92.28,87.93 v2(91.82,87.47) ; v1(123.43,139.02) 123.19,138.78 v2(122.92,138.78)
H_CPUPWRGD: length 11.3
  BOTTOM w0.102: CPU1.C61 100.13,93.86 100.13,94.69 100.06,94.76 100.06,95.33 99.93,95.45
  BOTTOM w0.127: R411.2 93.16,97.95 EC401.1 R405.1 93.84,96.89 TP403.1 95,96.78 98.86,96.78 99.8,95.85 99.8,95.59 99.93,95.45
H_PECI: length 183.6
  TOP w0.14: R2429.2 196.07,67.34 198.03,65.38 198.03,65.34 198.03,65.33 198.03,63.59 197.12,62.67 196.38,62.67 196.29,62.76 195.87,62.76 195.1,62 195.1,61.32 190.08,56.29 v2(188.7,56.29)
  L3 w0.127: v2(165.65,34.9) 165.56,34.9 165.15,35.31 165.15,37.31 173.41,45.57 181.13,45.57 182.11,46.54 185.94,46.54 189,49.61 189,55.45 189.08,55.53 189.08,55.91 v2(188.7,56.29)
  L4 w0.127: v2(84.94,80.07) 87.79,82.93 90.47,82.93 92.38,84.84 96.76,84.84 97.14,84.46 97.93,84.46 98.49,85.01 98.49,86.54 v2(99.49,87.53)
  BOTTOM w0.14: v2(165.65,34.9) 165.61,34.94 162.52,34.94 162.06,35.39 146.4,35.39 122.33,59.46 91.71,59.46 84.24,66.94 84.24,77 85.1,77.85 v1(85.1,78.42) 85.1,79.91 v2(84.94,80.07) ; CPU1.N62 99.14,87.88 v2(99.49,87.53)
H_PROCHOT#: length 293.5
  TOP w0.14: PR4426.2 143.54,153.01 v2(143.72,152.84) ; PR4624.2 PR4602.2 v1(116.44,147.48) 116.44,148.61 v2(116.61,148.78) ; v2(108.33,172.28) 108.33,172.7 108.32,172.71 108.32,172.71 107.53,173.51 PR4465.1 107.53,174.12 106.74,174.91 v1(106.51,174.91) 106.51,174.07 PR4466.2
  L3 w0.127: v2(153.54,100.08) 158.09,95.53 159.15,95.53 164.38,90.3 178.83,90.3 182.55,86.59 182.88,86.59 184.21,85.26 185.58,85.26 187.72,83.12 187.72,81.22 188.56,80.38 189.4,80.38 v2(189.59,80.57) ; v2(91.96,89.64) 91.83,89.64 89.88,91.59 89.88,97.48 92.17,99.77 92.17,104.47 94.65,106.95 94.65,116.32 100.81,122.48 100.81,132.25 96.39,136.66 96.39,137.23 97.29,138.13 97.91,138.13 99.77,139.99 99.77,143.79 100.52,144.53 101.79,144.53 104.27,147.02 110.83,147.02 112.53,148.72 116.55,148.72 v2(116.61,148.78) 116.9,148.49 120.84,148.49 121.62,149.28 140.42,149.28 141.71,150.57 142.65,150.57 143.48,151.4 143.48,152.6 v2(143.72,152.84)
  L4 w0.127: v2(187.66,75.14) 187.97,75.44 187.97,77.14 189.2,78.38 189.2,79.33 189.38,79.52 189.38,80.36 v2(189.59,80.57) ; v2(108.33,172.28) 108.41,172.21 109.76,172.21 110.43,172.88 112,172.88 112.47,172.41 122.77,172.41 124.1,171.07 131.68,171.07 133.15,169.6 133.15,165.97 136.89,162.24 136.89,160.45 136.89,160.44 136.89,160.43 139.33,157.99 139.35,157.99 140.1,157.24 140.1,156.89 140.14,156.89 143.72,153.31 v2(143.72,152.84) 144.18,152.38 144.18,149.13 144.73,148.58 144.73,139.35 143.39,138.01 143.39,135.66 143.69,135.36 143.69,121.46 150.92,114.24 150.92,104.18 153.54,101.56 v2(153.54,100.08)
  BOTTOM w0.14: R2440.2 176.81,73.86 C2421.1 178,73.88 178.42,73.46 179.71,73.46 181.57,75.32 182.2,75.32 182.35,75.47 186.8,75.47 186.95,75.32 187.48,75.32 v2(187.66,75.14) ; v2(91.96,89.64) 92.27,89.32 R401.2 93.03,88.99 R403.1
H_PROCHOT#_EC: length 3.4
  BOTTOM w0.14: Q2401.D 175.42,71.83 v1(175.77,72.18) 175.8,72.15 R2440.1 176.48,71.82 R2438.2
H_PROCHOT#_R: length 5
  BOTTOM w0.089: CPU1.K63 97.54,89.4 97.27,89.67 96.23,89.67 v1(96.2,89.7)
  BOTTOM w0.14: R403.2 94.05,88.98 94.77,89.7 v1(96.2,89.7)
H_RCIN#: length 87.7
  TOP w0.102: v2(135.47,84.5) 135.9,84.06 136.37,84.06 136.76,84.46 v1(136.98,84.46) 137.44,84.46 137.64,84.65 137.72,84.65 141.02,87.96 141.02,88.14 141.23,88.35 141.53,88.35 141.77,88.11 142.23,88.11 142.48,88.36 142.48,89.02 141.14,90.36 141.14,91.68 143.03,93.58 143.22,93.58 143.59,93.95 RN2002.7 ; v2(182.95,80.06) 183.22,79.8 183.22,78.54 183.09,78.41 183.09,77.6 184.25,76.45 184.25,75.16 184.92,74.48 184.92,72.98 188.02,69.89 188.02,69.12 188.8,68.34 KBC24.122
  L3 w0.102: v2(135.47,84.5) 135.5,84.5 135.94,84.06 136.62,84.06 137.3,84.74 139.58,84.74 140.32,85.48 143.74,85.48 145.28,87.02 145.78,87.02 146.28,86.52 147.87,86.52 148.24,86.9 148.89,86.9 151.25,89.26 151.9,89.26 152.08,89.44 153.07,89.44 153.5,89.01 157.03,89.01 159.8,86.24 166.57,86.24 166.99,85.82 169.4,85.82 169.66,85.55 171.64,85.55 173.07,84.12 173.98,84.12 174.15,84.29 177.7,84.29 178.86,83.13 180.68,83.13 182.61,81.21 182.61,80.64 182.95,80.29 v2(182.95,80.06)
  BOTTOM w0.102: CPU1.V4 135.16,84.8 v2(135.47,84.5)
H_THERMTRIP#: length 171.6
  TOP w0.102: v2(163.28,66.2) 163.71,65.77 R3608.2 164.43,65.8 164.85,66.22 166.66,66.22 Q3602.E
  L3 w0.102: v2(159.6,36.71) 159.24,37.07 159.24,48.62 159.24,48.62 159.24,48.79 160.45,50 169.24,50 171.36,52.12 171.36,53.66 172.19,54.49 172.45,54.49 v2(172.55,54.59) ; v2(163.28,66.2) 163.34,66.13 166.2,66.13 166.67,65.66 168,65.66 168.05,65.71 169.17,65.71 v2(169.39,65.49)
  L4 w0.102: v2(169.39,65.49) 169.45,65.49 170.26,64.67 170.26,61.78 170.27,61.77 170.27,56.87 v2(172.55,54.59)
  BOTTOM w0.102: v2(159.6,36.71) 159.6,36.71 148.12,36.71 124.11,60.72 92.05,60.72 85.56,67.21 85.56,76.89 86.2,77.53 86.2,81.09 85.99,81.31 85.99,93.14 88.9,96.05 v1(90.94,96.05) R2027.2
H_THERMTRIP_EN: length 175.9
  TOP w0.102: Q3602.B 165.95,68.2 165.67,68.48 C3604.1 R3605.1 R3606.2 164.04,66.76 163.94,66.65 v2(163.79,66.65)
  L3 w0.102: v2(172.55,53.95) 172.3,53.95 171.57,53.22 171.57,52.03 169.33,49.8 163.47,49.8 160.54,49.8 159.44,48.7 159.44,37.51 v2(160.24,36.71) ; v2(163.79,66.65) 164.1,66.34 166.28,66.34 166.75,65.87 167.9,65.87 168.71,66.68 169.06,66.68 169.24,66.5 v2(169.24,66.5)
  L4 w0.102: v2(172.55,53.95) 170.06,56.44 170.06,64.21 168.96,65.31 168.96,65.79 169.24,66.06 v2(169.24,66.5)
  BOTTOM w0.102: v2(160.24,36.71) 160.21,36.71 159.78,36.28 150.75,36.28 v1(150.74,36.29) 150.72,36.28 148.24,36.28 124,60.51 91.96,60.51 85.35,67.13 85.35,76.98 86,77.62 86,81.01 85.78,81.22 85.78,93.22 91.17,98.61 R411.1
H_VCCST_PWRGD: length 13.5
  TOP w0.127: U701.4 100.89,98.62 100.99,98.72 R707.2 100.97,99.38 R9601.1 100.65,100.58 v2(100.65,101)
  BOTTOM w0.089: CPU1.B59 101.21,94.5 100.89,94.82 100.89,95.5
  BOTTOM w0.127: v2(100.65,101) v1(100.14,100.49) 99.82,100.17 R706.2 98.83,100.22 EC701.1 R709.1 98.02,98.75 98.47,98.29 98.49,98.29 100.89,95.9 100.89,95.5
H_VR_ENABLE: length 75.3
  TOP w0.127: v2(122.42,145.07) 122.05,144.71 PR4621.2 ; v2(100.12,92.01) 99.93,92.21 99.93,92.21 99.52,92.61 v1(98.65,92.61) 98.59,92.61 97.13,94.08 97.13,95.6 97.66,96.13 97.66,101.88 v2(97.52,102.01)
  L3 w0.127: v2(97.52,102.01) 97.49,102.04 97.49,104.6 98.33,105.44 98.33,114.81 104.48,120.96 104.48,133.77 104.25,134 104.25,135.5 109.42,140.67 111.62,140.67 112.81,141.86 112.81,143.47 114.33,144.99 119.52,144.99 119.87,144.64 121.99,144.64 v2(122.42,145.07)
  BOTTOM w0.102: CPU1.F60 100.44,91.7 v2(100.12,92.01)
  BOTTOM w0.127: R710.1 96.48,101.07 97.42,102.01 v2(97.52,102.01)
HDA_BITCLK: length 11.3
  BOTTOM w0.089: CPU1.AW8 131.95,72.82 131.95,71.64 134.06,69.54 134.38,69.54 134.55,69.37
  BOTTOM w0.14: 134.55,69.37 135.65,68.27 135.65,67.79 v1(137.33,66.11) 138.4,65.04 R1907.2
HDA_CODEC_BITCLK: length 73.7
  L4 w0.127: v2(163.43,41.32) 163.35,41.24 163.35,38.83 164.93,37.25 164.93,34.73 165.65,34.01 165.65,33.84 165.65,33.37 171.97,27.05 171.97,18.95 171.98,18.94 v2(171.98,18.64)
  BOTTOM w0.14: v2(163.43,41.32) 163.4,41.35 149.86,41.35 137.94,53.27 v1(137.94,58.39) 137.94,61.76 137.94,62.66 EC1901.2 138.4,63.15 R1907.1 ; R2720.1 EC2709.1 175.54,16.92 173.59,16.92 171.98,18.53 v2(171.98,18.64)
HDA_CODEC_RST#: length 75.2
  L4 w0.127: v2(174.3,19.42) 174.25,19.42 173.03,20.65 173.03,27.48 166.75,33.76 166.75,34.16 166.75,34.16 166.75,35.75 166.07,36.43 166.07,37.6 164.4,39.26 164.4,41.69 v2(164.4,41.7)
  BOTTOM w0.14: HDA27.11 179.66,18.09 179.13,18.62 179.13,18.86 178.06,19.94 174.93,19.94 174.41,19.42 v2(174.3,19.42) ; v2(164.4,41.7) 164.16,41.94 150.22,41.94 138.73,53.43 v1(138.73,54.05) 138.73,58.39 139.87,59.53 139.87,62.5 EC1902.1 139.22,63.16 R1911.1
HDA_CODEC_SDIN0: length 4.3
  BOTTOM w0.14: R2718.2 177.73,18.77 177.98,18.52 178.24,18.52 v1(178.42,18.34) 178.61,18.15 178.61,17.24 178.96,16.89 HDA27.8
HDA_CODEC_SDOUT: length 82.7
  TOP w0.14: v2(156.67,56.19) 156.14,55.65 151.16,55.65 149.29,57.52 134.5,57.52 132.06,59.96 v1(132.06,61.45) R1912.1
  L4 w0.127: v2(156.67,56.19) 156.88,55.99 156.88,54.69 157.51,54.06 158.27,54.06 159.63,52.7 159.63,51.53 160.21,50.96 160.21,50.2 166.04,44.36 166.04,38.31 167.43,36.92 167.43,35.41 167.23,35.21 167.23,33.96 173.51,27.68 173.51,20.85 174.78,19.57 174.78,18.75 175.87,17.67 175.87,16.12 v2(174.61,14.86)
  BOTTOM w0.14: v2(174.61,14.86) 175.1,15.36 EC2708.1 175.91,15.53 R2719.1
HDA_CODEC_SYNC: length 81.3
  TOP w0.14: R1908.1 132.95,60.11 133.48,59.58 133.48,59.58 v1(133.5,59.56) 133.51,59.55 134.9,58.16 149.47,58.16 151.48,56.15 155.9,56.15 156.65,56.9 v2(156.75,56.9)
  L4 w0.127: v2(175.39,19.38) 175.39,19.69 174.73,20.36 174.73,24.65 173.99,25.39 173.99,27.88 168.17,33.71 168.17,36.28 167.92,36.52 167.92,37.11 166.52,38.51 166.52,45.83 163.66,48.69 163.16,48.69 160.37,51.48 160.37,51.86 160.52,52.01 160.52,52.65 158.63,54.54 157.72,54.54 157.36,54.89 157.36,56.29 v2(156.75,56.9)
  BOTTOM w0.14: HDA27.10 179.61,17.69 177.91,19.38 175.39,19.38 v2(175.39,19.38)
HDA_RST#: length 12.7
  BOTTOM w0.089: CPU1.AU8 132.56,74.12 132.56,73.62 132.53,73.58 132.53,71.46 134.03,69.96 134.36,69.96
  BOTTOM w0.14: R1911.2 139.22,65.1 v1(138.54,65.78) 138.35,65.97 138.35,65.97 134.36,69.96
HDA_SDIN0: length 82.8
  L4 w0.127: v2(163.92,40.61) 163.92,39.06 165.58,37.4 165.58,36.23 166.22,35.59 166.22,33.6 172.54,27.28 172.54,19.49 v2(173.84,18.19)
  BOTTOM w0.089: 134.01,68.83 131.52,71.32 131.52,72.43 CPU1.AY10
  BOTTOM w0.14: R2718.1 174.43,18.77 v2(173.84,18.19) ; v2(163.92,40.61) 163.76,40.77 149.61,40.77 137.36,53.03 v1(137.36,60.55) 137.36,62 137.36,62 137.36,63.77 137.36,63.77 137.36,64.15 136.24,65.27 136.24,65.97 134.27,67.94 134.27,68.57 134.01,68.83
HDA_SDOUT: length 12.1
  TOP w0.14: R1909.2 R1912.2 132.06,65.97 132.28,66.19 132.28,68.13 v1(131.38,69.03) 129.66,70.75 129.66,73.4 v2(130.37,74.11)
  BOTTOM w0.14: CPU1.AU11 130.67,74.41 v2(130.37,74.11)
HDA_SPKR: length 124.3
  L3 w0.254: v2(184.12,79.81) 184.12,80.12 183.39,80.84 183.39,81.32 180.95,83.77 179.12,83.77 177.96,84.93 174.2,84.93 173.59,85.53 173.31,85.53 173.31,85.53 172.63,85.53 171.98,86.19 169.93,86.19 169.66,86.45 167.32,86.45 166.87,86.9 160.46,86.9 157.72,89.64 153.8,89.64 153.37,90.07 151.77,90.07 151.59,89.9 150.98,89.9 149.05,87.96 147.66,87.96 147.4,88.22 144.79,88.22 143.24,86.68 140.75,86.68 v2(140.74,86.66)
  L4 w0.254: v2(184.12,79.81) 184.12,78.68 184.45,78.35 184.45,73.31 185.86,71.9 185.86,71.63 186.53,70.96 186.53,70.96 187.55,69.94 187.55,68.99 187.49,68.93 187.49,67.87 188.08,67.29 188.08,62.08 187.88,61.88 187.88,58.69 188.58,57.99 188.58,56.89 188.28,56.59 187.95,56.26 187.95,55.14 187.05,54.24 187.05,45.54 189.33,43.26 189.33,33.65 187.18,31.5 v2(186.67,31.5)
  BOTTOM w0.089: CPU1.V2 136.75,84.58 137.34,84.58 137.42,84.66 139.02,84.66 139.43,85.07
  BOTTOM w0.254: 139.43,85.07 140.74,86.38 v2(140.74,86.66) 142.25,86.66 142.51,86.93 142.51,87.79 142.98,88.26 R2006.2 ; v2(186.67,31.5) 186.57,31.39 185.07,31.39 184.48,30.81 v1(182.67,30.81) 182.43,30.81 179.03,27.41 RN2701.2
HDA_SPKR_R: length 5.7
  BOTTOM w0.254: v1(177.15,26.32) 176.29,26.32 175.6,25.63 D2701.2 174.76,25.63 174.39,26 174.39,27.17 174.63,27.41 RN2701.3
HDA_SYNC: length 10.2
  TOP w0.14: R1908.2 v1(132.95,67.2) 132.95,68.49 130.37,71.07 v2(130.37,73.46)
  BOTTOM w0.14: CPU1.AV11 130.48,73.46 v2(130.37,73.46)
HDD_DEVSLP: length 18.7
  TOP w0.102: v2(147.29,96.36) 147.29,96.06 v1(147.08,95.84)
  L3 w0.102: v2(147.29,96.36) 146.57,96.36 145.32,95.11 143.6,95.11 143.59,95.1 143.19,95.1 143.18,95.11 143.01,95.11 142.96,95.06 v2(142.96,95.05)
  BOTTOM w0.089: 138.82,87.47 138.69,87.34 137.31,87.34 137.25,87.4 136.75,87.4 CPU1.P2
  BOTTOM w0.102: v2(142.96,95.05) 142.93,95.03 142.93,94.63 142.37,94.06 141.93,94.06 141.43,93.56 141.43,92.83 139.97,91.36 139.97,88.62 138.82,87.47 ; R5605.1 147.53,96.6 v2(147.29,96.36)
HDD_DEVSLP_R: length 90
  L4 w0.102: v2(184.55,35.61) 184.55,36.32 183.09,37.78 183.09,38.86 182.54,39.4 182.54,43.73 182.12,44.15 182.12,48.5 181.87,48.75 181.87,51.81 180.2,53.48 180.2,56.75 177.65,59.3 177.65,62.68 177.71,62.73 177.71,64.87 178.34,65.51 178.34,66.4 177.91,66.83 177.91,68.74 176.7,69.94 176.7,71.11 173.97,73.85 173.97,74.48 172.7,75.75 172.7,75.77 171.64,76.84 171.64,77.3 171.39,77.54 171.39,79.24 169.91,80.73 169.12,80.73 167.32,82.53 167.32,83.16 166.56,83.93 165.87,83.93 165.08,84.71 161.65,84.71 158.1,88.27 157.45,88.27 157.42,88.3 157.42,88.3 154.19,91.53 154.19,91.92 153,93.1 153,93.93 151.07,95.86 150.12,95.86 149.57,96.42 v2(149.57,97.3)
  BOTTOM w0.102: v2(149.57,97.3) 149.43,97.3 149.22,97.09 R5605.2 ; HDD1.5 190.34,31.63 189.62,32.35 189.62,32.61 v1(188.79,33.44) 187.54,34.69 187.54,35 186.94,35.61 v2(184.55,35.61)
HDMI_CLK: length 96
  L4 w0.114: v2(103.47,99.79) 103.21,100.05 101.59,100.05 101.35,99.82 95.49,99.82 95.46,99.79 95.45,99.79 75.16,79.49 50.44,79.49 49.21,78.26 37.35,78.26 35.31,76.22 31.4,76.22 30.63,77 26.6,77 v2(26.56,76.96)
  BOTTOM w0.127: v1(25.76,77.04) 25.76,77.2 ; 25.76,77.2 26.32,77.2 v2(26.56,76.96) ; 25.76,77.2 25.02,77.2 C5403.1 ; v2(103.47,99.79) 103.48,99.79 103.48,99.81 103.57,99.91 103.66,99.91 103.87,99.69 103.87,99.12 103.23,98.48 103.23,96.79 102.02,95.58 102.02,94.75 CPU1.B57
HDMI_CLK#: length 96
  L4 w0.114: v2(26.56,77.68) 27.01,77.23 30.72,77.23 31.5,76.45 35.21,76.45 37.25,78.49 49.11,78.49 50.34,79.72 75.06,79.72 95.36,100.01 95.36,100.01 95.39,100.05 101.26,100.05 101.49,100.28 103.33,100.28 v2(103.48,100.43)
  BOTTOM w0.127: v2(26.56,77.68) 26.33,77.44 25.12,77.44 24.81,77.75 C5402.1 ; 104.11,99.52 104.11,99.02 103.47,98.38 103.47,96.69 102.27,95.49 102.27,95.16 CPU1.A57 ; 104.11,99.52 104.11,99.79 v2(103.48,100.43) ; 104.11,99.52 v1(104.25,99.52)
HDMI_CLK#_R: length 5.5
  TOP w0.127: RN5403.5 23.19,77.51 23.14,77.47 23.14,77.47 22.78,77.47 22.52,77.73 v2(22.52,77.84) 23.23,78.55 v1(23.23,78.66)
  BOTTOM w0.127: R5401.1 21.81,77.68 22.36,77.68 v2(22.52,77.84) 22.8,77.56 23.6,77.56 C5402.2
HDMI_CLK#_R_C: length 18.1
  BOTTOM w0.127: 18.19,77.49 17.87,77.49 16.54,76.16 16.54,75.15 12.11,70.71 12.11,69.93 12.11,69.83 12.11,65.94 12.01,65.84 11.78,65.84 HDMI1.HP12 ; 18.19,77.49 v1(18.19,77.63) ; 18.19,77.49 18.68,77.49 R5414.1 19.3,77.73 20.42,77.73 R5401.2
HDMI_CLK_R: length 5.5
  TOP w0.127: v1(21.76,77.47) 22.2,77.03 v2(22.52,77.03) 22.71,77.23 23.04,77.23 23.41,76.86 RN5403.6
  BOTTOM w0.127: R5402.1 21.9,77.44 22.12,77.44 v2(22.52,77.03) 22.8,77.32 23.6,77.32 C5403.2
HDMI_CLK_R_C: length 18.2
  BOTTOM w0.127: HDMI1.HP10 11.78,65.6 12.11,65.6 12.35,65.84 12.35,70.61 16.78,75.05 16.78,76.06 17.3,76.59 ; R5402.2 20.22,77.49 19.57,77.49 R5414.2 18.89,77.25 17.97,77.25 17.3,76.59 ; 17.3,76.59 v1(17.41,76.48)
HDMI_CRT_DET: length 147.3
  TOP w0.102: R5517.2 32.01,69.21 31.7,69.52 30.56,69.52 v2(30.49,69.44)
  L3 w0.102: v2(32.22,77.53) 32.22,77.53 32.22,74.13 30.46,72.37 30.46,69.46 v2(30.49,69.44)
  L4 w0.102: v2(101.29,100.95) 100.89,100.56 99.7,100.56 98.87,101.39 96.01,101.39 75.27,80.65 38.69,80.65 35,76.97 32.79,76.97 v2(32.22,77.53) ; v2(138.56,100.51) 137.94,100.51 134.96,103.49 134.96,105.07 132.65,107.38 128.81,107.38 128.01,108.18 114.51,108.18 110.26,103.94 v2(110.26,102.66)
  BOTTOM w0.089: CPU1.C8 132.87,93.89 133.33,94.35 133.33,94.59 133.04,94.88 133.04,95.26 133.15,95.37
  BOTTOM w0.102: v2(32.22,77.53) 31.31,78.44 R5419.1 ; v2(110.26,102.66) 109.92,102.31 107.48,102.31 106.72,101.55 v1(104.35,101.55) 102.11,101.55 101.51,100.95 v2(101.29,100.95) ; 133.15,95.37 134.95,97.16 135.61,97.16 136.71,98.27 136.71,98.81 137.9,100 138.06,100 v2(138.56,100.51)
HDMI_CRT_N0: length 83.8
  TOP w0.127: C5526.1 39.59,73.6 39.72,73.47 40.18,73.47 40.25,73.54 v2(40.25,73.83) 40.76,73.83 v1(41.03,73.56)
  L4 w0.114: v2(40.25,73.83) 40.47,73.62 43.52,73.62 43.82,73.32 45.69,73.32 46.47,74.1 58.78,74.1 60.63,75.95 74.57,75.95 92.28,93.67 94.71,93.67 97.9,96.85 99.83,96.85 100.25,96.44 102.41,96.44 103.32,97.34 103.67,97.34 v2(103.89,97.56)
  BOTTOM w0.089: CPU1.C54 103.93,94.04 103.58,94.15 103.48,94.23 103.42,94.39 103.42,94.49 103.5,94.66 103.51,94.7 103.51,94.84 103.32,95.3 103.31,95.34 103.31,95.47 103.35,95.5
  BOTTOM w0.127: v2(40.25,73.83) 40.25,73.56 40.16,73.46 39.74,73.46 39.52,73.68 RN5405.1 ; 103.35,95.5 103.44,95.6 104.06,95.6 104.67,96.22 104.67,96.78 v2(103.89,97.56)
HDMI_CRT_N1: length 81.3
  TOP w0.127: v1(40.93,76.39) 40.93,76.25 40.62,75.93 v2(40.24,75.93) 40.24,75.78 40,75.54 39.82,75.54 C5525.1
  L4 w0.114: v2(40.24,75.93) 40.24,75.77 40.49,75.53 43.81,75.53 44.27,75.98 54,75.98 55.91,77.89 70.2,77.89 71.31,76.78 74.26,76.78 94.29,96.81 95.25,96.81 96.08,97.64 98.55,97.64 99.26,98.35 101.96,98.35 102.15,98.54 v2(102.15,98.61)
  BOTTOM w0.089: 102.3,96.31 102.29,96.3 102.25,96.3 101.81,95.85 101.81,94.14 CPU1.B58
  BOTTOM w0.127: v2(40.24,75.93) 40.24,75.88 39.98,75.62 39.61,75.62 39.49,75.74 RN5404.1 ; v2(102.15,98.61) 102.81,97.95 102.81,96.82 102.3,96.31
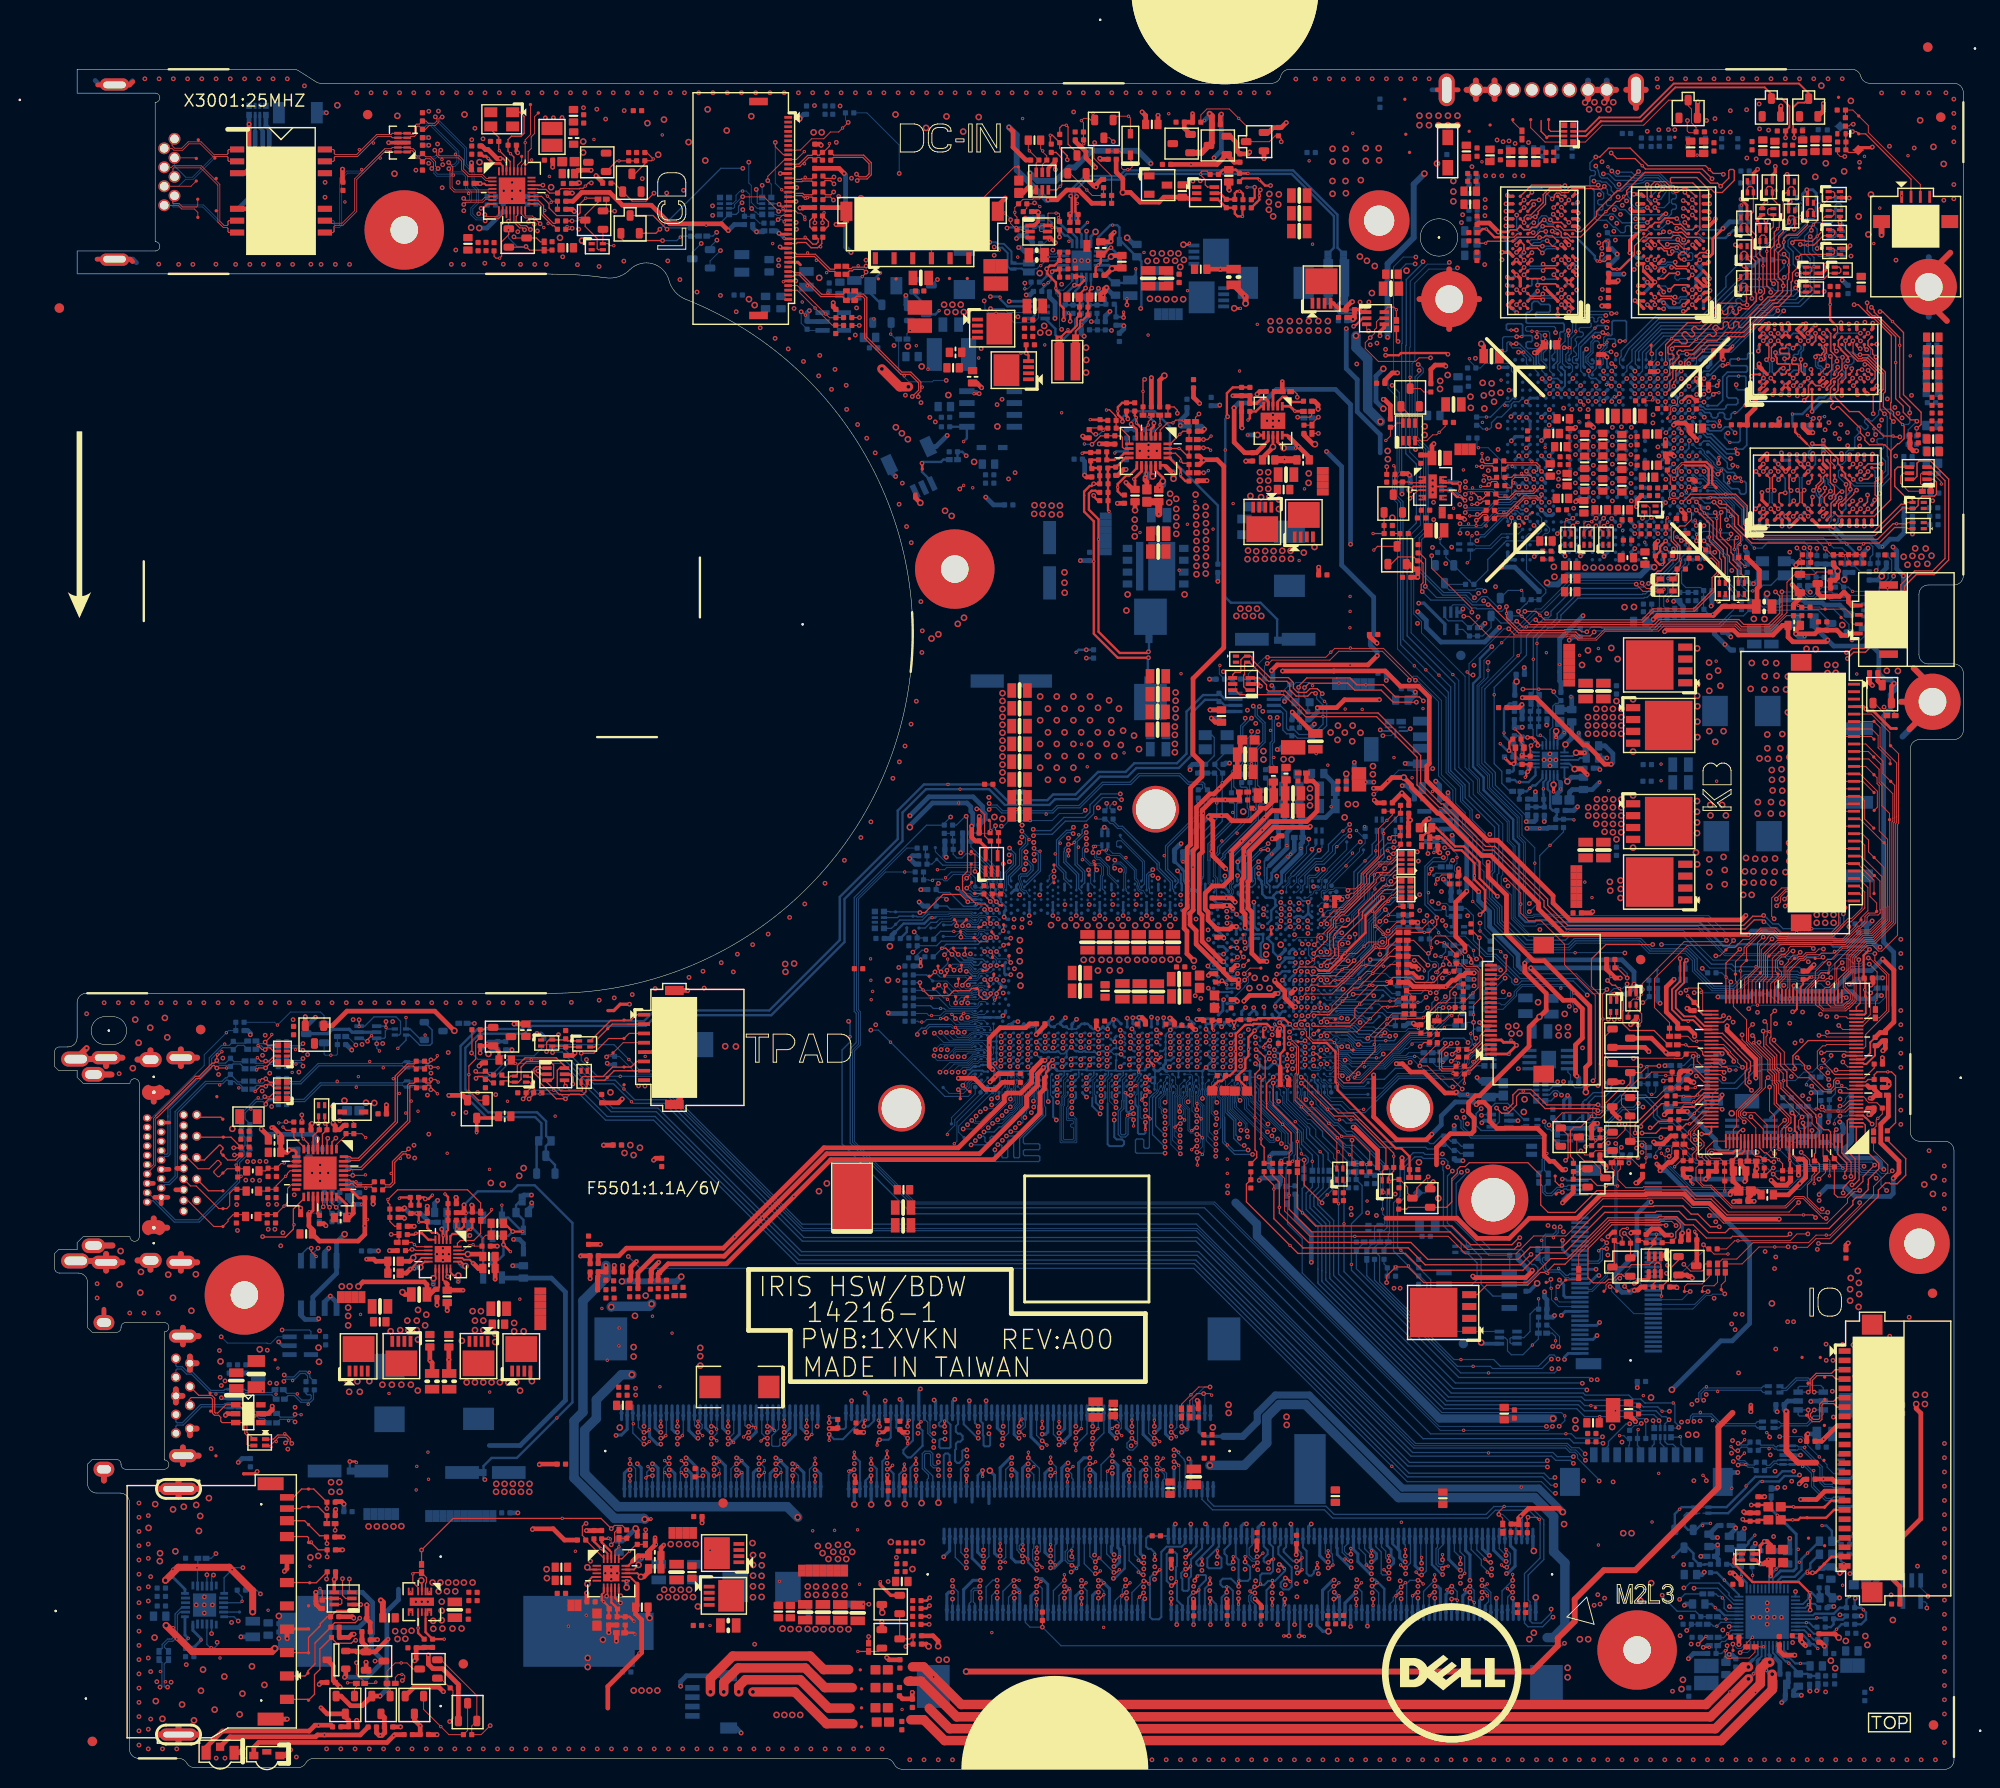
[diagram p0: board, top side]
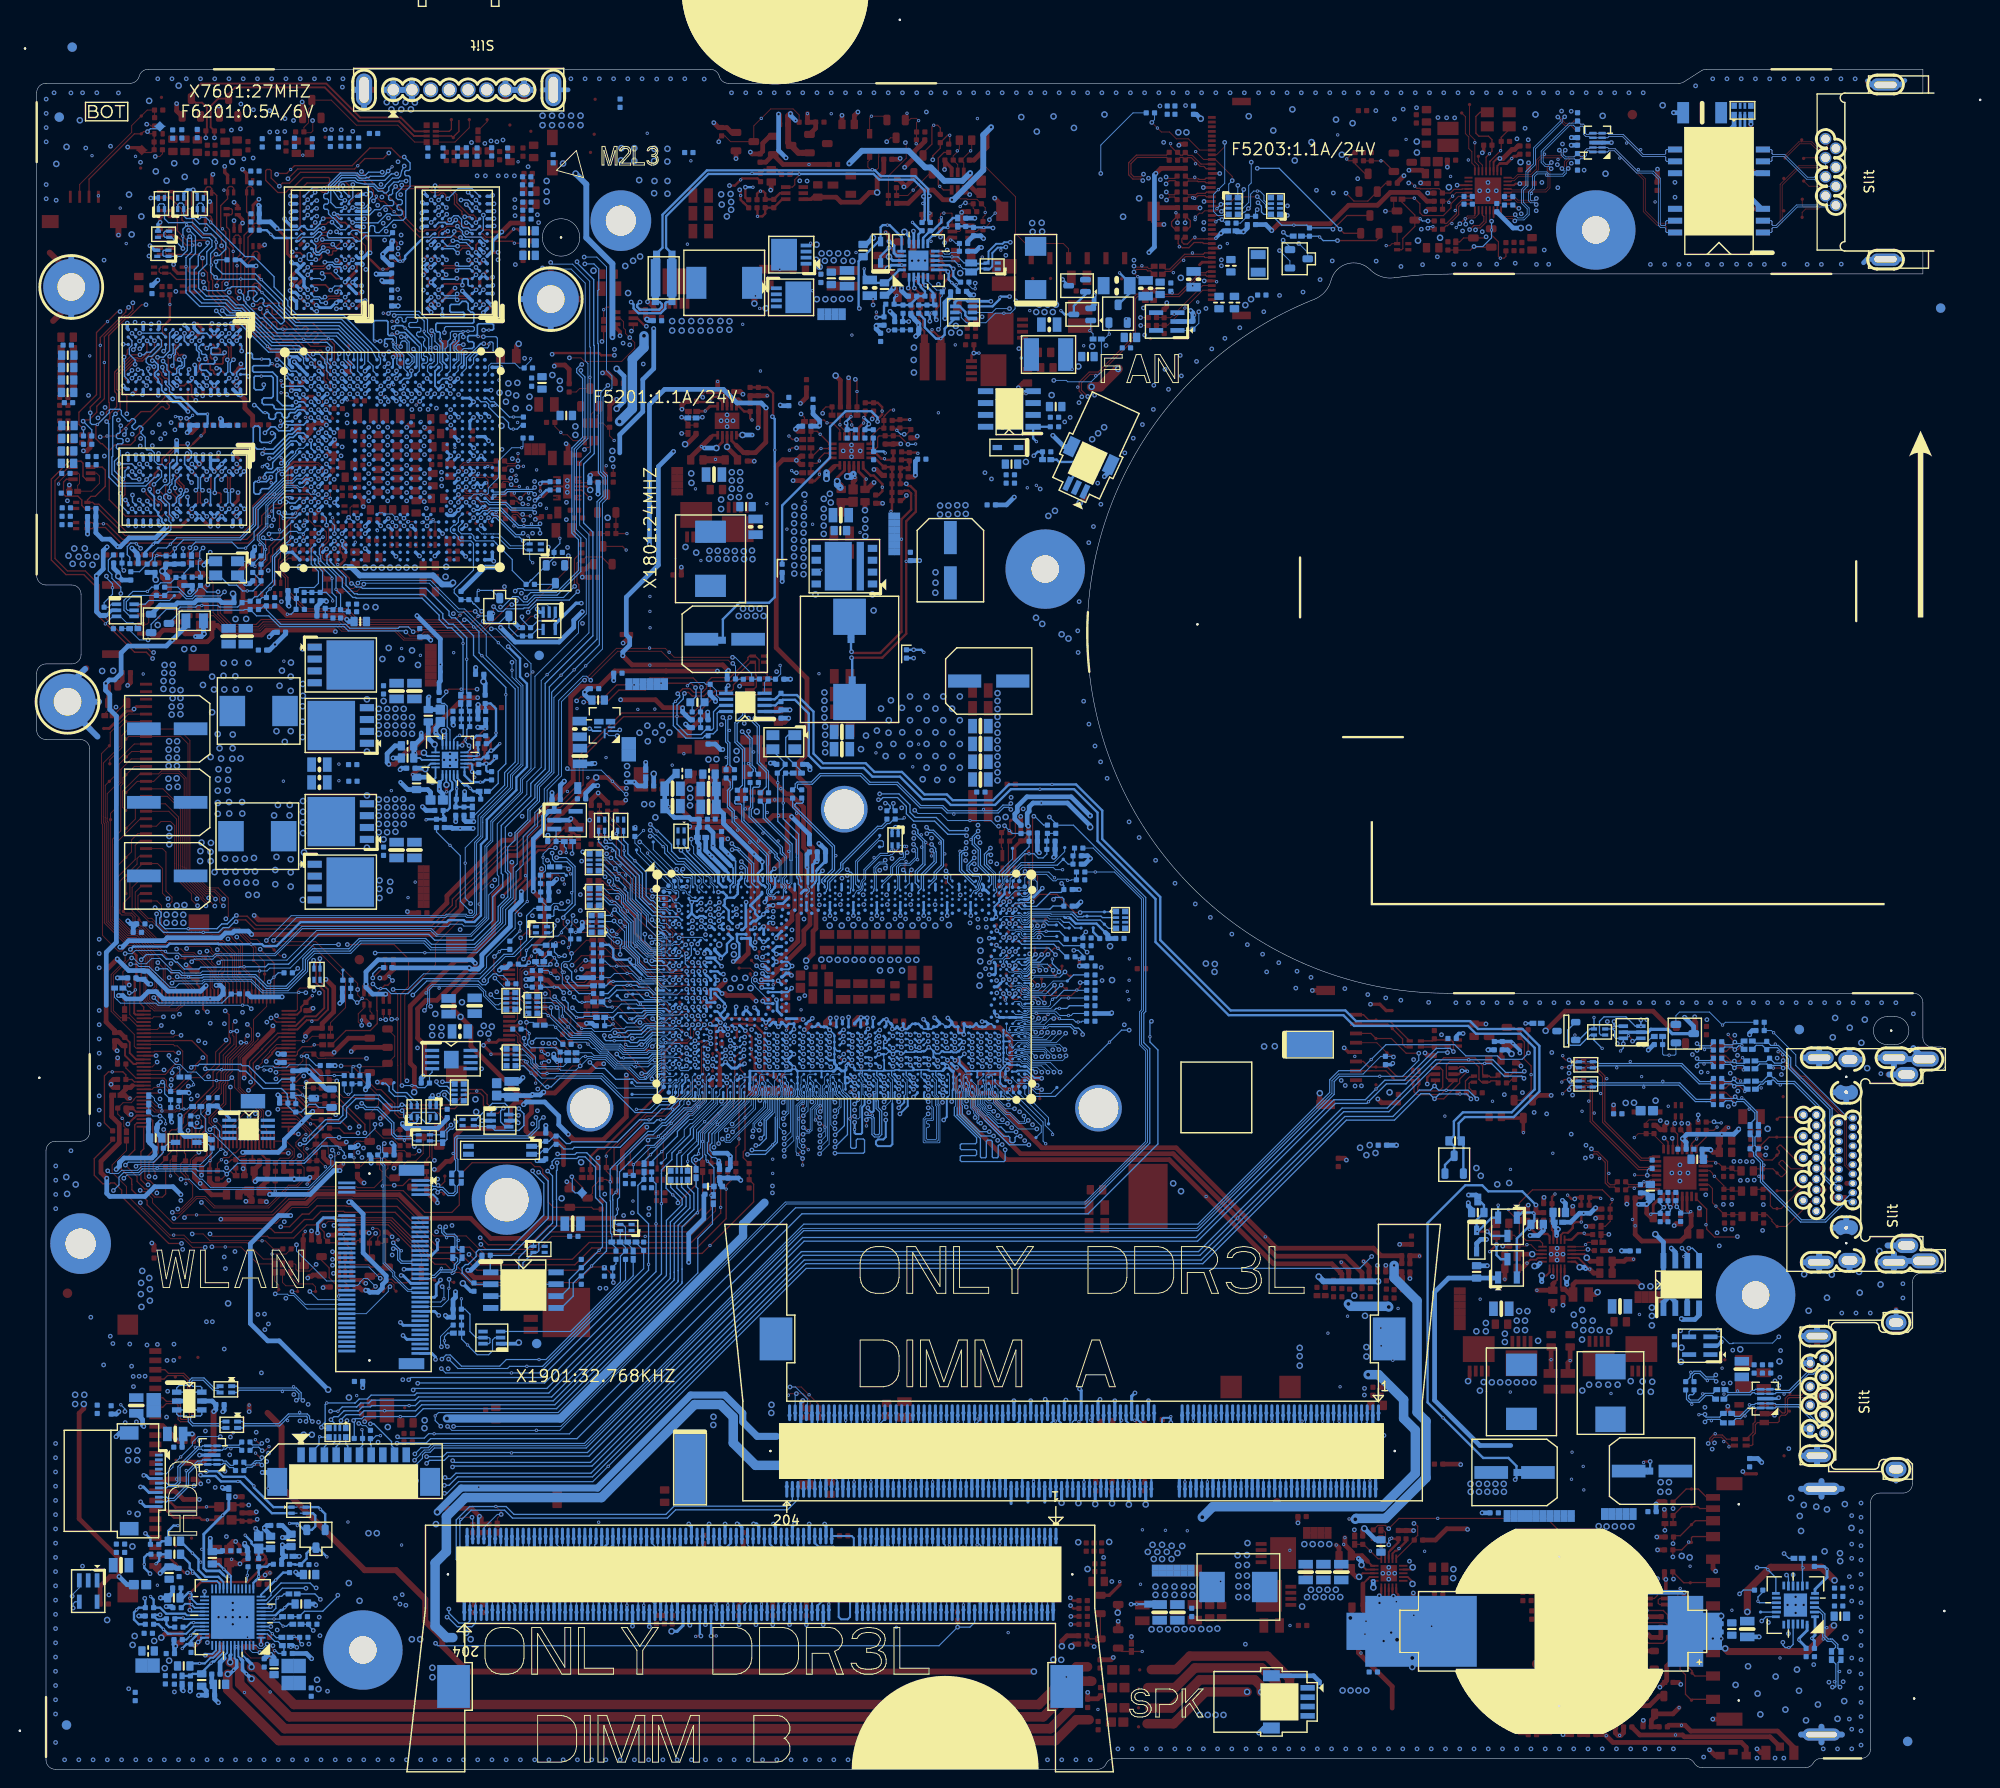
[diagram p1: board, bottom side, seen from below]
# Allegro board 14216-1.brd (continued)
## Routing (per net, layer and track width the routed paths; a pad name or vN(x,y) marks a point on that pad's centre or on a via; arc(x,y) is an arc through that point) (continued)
HDMI_CRT_P0: length 83.8
  TOP w0.127: v1(40.95,72.31) 40.52,72.75 v2(40.24,72.75) 40.24,73.16 40.17,73.23 39.88,73.23 C5529.1
  L4 w0.114: v2(40.24,72.75) 39.98,72.75 39.85,72.87 39.85,73.26 39.98,73.39 43.43,73.39 43.73,73.09 43.92,73.09 45.79,73.09 46.57,73.87 58.88,73.87 60.73,75.72 74.66,75.72 92.38,93.44 94.8,93.44 97.99,96.63 99.73,96.63 100.15,96.21 102.51,96.21 103.41,97.11 103.71,97.11 v2(103.89,96.92)
  BOTTOM w0.089: 103.13,95.63 103.12,95.62 103.12,95.3 103.13,95.27 103.32,94.8 103.32,94.7 103.25,94.53 103.25,94.35 103.34,94.13 103.62,93.88 CPU1.C55
  BOTTOM w0.127: v2(40.24,72.75) 40.24,73 40.03,73.22 39.68,73.22 39.5,73.03 RN5405.2 ; v2(103.89,96.92) 104.19,96.92 104.43,96.68 104.43,96.32 103.96,95.84 103.34,95.84 103.13,95.63
HDMI_CRT_P1: length 81.1
  TOP w0.127: v1(41.02,75.09) 40.96,75.15 v2(40.24,75.15) 40.09,75.3 39.74,75.3 39.57,75.13 C5530.1
  L4 w0.114: v2(102.11,97.88) 101.87,98.12 99.36,98.12 98.65,97.41 96.17,97.41 95.34,96.59 94.38,96.59 74.35,76.56 71.21,76.56 70.11,77.66 56,77.66 54.09,75.75 44.36,75.75 43.91,75.3 40.38,75.3 v2(40.24,75.15)
  BOTTOM w0.089: 102.13,96.48 102.12,96.47 102.12,96.43 101.62,95.93 101.62,94.39 101.48,94.25 101.48,93.93 101.78,93.63 CPU1.C58
  BOTTOM w0.127: v2(40.24,75.15) 40.01,75.38 39.72,75.38 39.54,75.2 39.43,75.09 RN5404.2 ; v2(102.11,97.88) 102.28,98.04 102.38,98.04 102.57,97.85 102.57,96.92 102.22,96.57 102.13,96.48
HDMI_DATA0: length 95.9
  L4 w0.114: v2(26.56,75.27) 26.46,75.37 26.46,75.51 26.59,75.64 30.04,75.64 30.2,75.47 35.62,75.47 37.66,77.51 54.32,77.51 55.33,78.52 75.25,78.52 95.8,99.07 102.46,99.07 103.01,98.52 103.56,98.52 103.67,98.63 104.1,98.63 104.54,98.19 v2(104.78,97.95)
  BOTTOM w0.127: CPU1.A55 103.83,94.98 103.94,94.98 105.23,96.27 105.23,97.93 105.06,98.1 104.92,98.1 v2(104.78,97.95) ; C5405.1 24.81,75.49 24.95,75.62 25.81,75.62 ; 25.81,75.62 26.4,75.62 26.56,75.47 v2(26.56,75.27) ; 25.81,75.62 v1(25.81,75.49)
HDMI_DATA0#: length 95.9
  L4 w0.114: v2(104.78,98.59) 104.47,98.59 104.19,98.86 103.58,98.86 103.46,98.75 103.1,98.75 102.55,99.3 95.7,99.3 75.15,78.75 55.23,78.75 54.23,77.74 37.56,77.74 35.53,75.7 35.25,75.7 35.24,75.7 30.3,75.7 30.13,75.87 26.77,75.87 v2(26.56,76.08)
  BOTTOM w0.127: C5404.1 25.05,75.87 26.35,75.87 v2(26.56,76.08) ; 105.32,98.18 105.16,98.34 105.02,98.34 v2(104.78,98.59) ; 105.32,98.18 105.47,98.03 105.47,97.83 105.47,97.83 105.47,96.17 104.11,94.8 104.04,94.73 104.02,94.73 CPU1.B55 ; 105.32,98.18 v1(105.42,98.28)
HDMI_DATA0#_R: length 5.7
  TOP w0.127: v1(21.69,76.18) 21.69,76.17 22.05,75.81 v2(22.57,75.81) 22.93,75.81 23.22,76.1 23.23,76.1 23.48,76.36 RN5403.7
  BOTTOM w0.127: C5404.2 23.52,75.7 22.68,75.7 v2(22.57,75.81) 22.33,75.57 21.5,75.57 R5403.1
HDMI_DATA0#_R_C: length 20
  TOP w0.089: HDMI1.HP9 9.9,64.6 10.02,64.48 10.32,64.48 10.57,64.74 10.57,69.66 10.81,69.91 10.81,69.95 10.82,69.96
  TOP w0.127: 10.82,69.96 15.05,74.19 15.45,74.19 16.86,75.59 17.06,75.59 v2(17.35,75.87) 17.35,76.27 v1(17.89,76.81)
  BOTTOM w0.127: v2(17.35,75.87) 17.35,75.76 17.52,75.59 18.28,75.59 R5416.1 19.18,75.74 20.28,75.74 R5403.2
HDMI_DATA0_R: length 5.9
  TOP w0.127: RN5403.8 23.73,75.86 23.32,75.86 22.57,75.11 v2(22.57,75.08) 21.82,75.08 v1(21.61,74.87)
  BOTTOM w0.127: C5405.2 23.68,75.46 22.95,75.46 v2(22.57,75.08) 22.31,75.33 21.6,75.33 R5404.1
HDMI_DATA0_R_C: length 19.9
  TOP w0.089: 10.94,69.74 10.91,69.74 10.76,69.59 10.76,64.66 9.9,63.8 HDMI1.HP7
  TOP w0.127: v1(18.4,75.06) v2(17.35,75.06) 17.06,75.35 16.96,75.35 15.55,73.94 15.15,73.94 10.94,69.74
  BOTTOM w0.127: R5404.2 19.85,75.5 19.07,75.5 R5416.2 18.68,75.35 17.63,75.35 v2(17.35,75.06)
HDMI_DATA1: length 14.3
  BOTTOM w0.127: 35.16,75.31 37.2,75.31 37.42,75.09 RN5404.3 ; 35.16,75.31 28.28,75.31 26.34,73.37 25.13,73.37 C5406.1 ; 35.16,75.31 v1(35.16,75.09)
HDMI_DATA1#: length 14.3
  BOTTOM w0.127: v1(33.71,75.76) 33.71,75.55 ; 33.71,75.55 28.18,75.55 26.24,73.61 25.14,73.61 C5409.1 ; 33.71,75.55 37.17,75.55 37.37,75.74 RN5404.4
HDMI_DATA1#_R: length 5.6
  TOP w0.127: v1(21.9,73.68) 22.14,73.92 v2(22.58,73.92) 23,73.51 23.81,73.51 RN5402.5
  BOTTOM w0.127: R5407.1 21.42,73.45 22.27,73.45 22.58,73.76 v2(22.58,73.92) 22.88,73.62 23.6,73.62 C5409.2
HDMI_DATA1#_R_C: length 18.3
  BOTTOM w0.127: R5407.2 20.23,73.58 19.61,73.58 18.8,74.39 R5417.1 18.43,74.01 18.27,74.01 17.89,73.64 16.13,73.64 12.89,70.39 12.89,63.52 12.2,62.83 11.67,62.83 11.4,63.1 HDMI1.HP6
HDMI_DATA1_R: length 6
  TOP w0.127: RN5402.6 23.48,72.92 23.15,73.25 23.15,73.26 22.73,73.26 v2(22.58,73.11) 22.02,73.11 v1(21.45,72.55)
  BOTTOM w0.127: R5408.1 21.61,73.21 22.49,73.21 v2(22.58,73.11) 22.85,73.38 23.6,73.38 C5406.2
HDMI_DATA1_R_C: length 18.4
  BOTTOM w0.127: HDMI1.HP4 11.77,62.59 12.3,62.59 13.13,63.42 13.13,70.29 16.23,73.4 17.66,73.4 ; 17.66,73.4 17.99,73.4 18.37,73.77 18.53,73.77 R5417.2 18.94,73.63 19.22,73.63 19.51,73.34 19.78,73.34 R5408.2 ; 17.66,73.4 v1(17.66,73.26)
HDMI_DATA2: length 14.2
  BOTTOM w0.127: C5408.1 25.13,71.47 25.59,71.47 26.75,71.47 28.51,73.23 32.27,73.23 ; RN5405.3 37.41,73.03 37.21,73.23 32.27,73.23 ; 32.27,73.23 v1(32.27,73.02)
HDMI_DATA2#: length 14.2
  BOTTOM w0.127: v1(30.22,73.65) 30.22,73.48 ; 30.22,73.48 28.41,73.48 26.65,71.72 25.13,71.72 C5407.1 ; 30.22,73.48 37.24,73.48 37.45,73.68 RN5405.4
HDMI_DATA2#_R: length 7.9
  TOP w0.127: RN5402.7 23.45,72.42 23,71.97 22.5,71.97 v2(22.48,72)
  BOTTOM w0.127: C5407.2 23.69,71.81 22.67,71.81 v2(22.48,72) 22.2,71.72 21.78,71.72 ; v1(21.78,71.89) 21.78,71.72 ; 21.78,71.72 21.49,71.72 20.14,70.37 20.14,69.06 R5405.1
HDMI_DATA2#_R_C: length 18.4
  BOTTOM w0.127: 19.54,64.67 19.54,62.98 15.38,58.82 12.9,58.82 10,61.72 HDMI1.HP3 ; 19.54,64.67 v1(19.41,64.67) ; 19.54,64.67 19.54,65.04 20.26,65.76 20.26,66.16 R5415.1 20.37,66.77 20.37,67.66 R5405.2
HDMI_DATA2_R: length 7.9
  TOP w0.127: RN5402.8 23.84,71.73 22.88,71.73 22.59,71.44 v2(22.59,71.19)
  BOTTOM w0.127: C5408.2 23.5,71.57 22.88,71.57 22.59,71.27 v2(22.59,71.19) 22.3,71.48 21.59,71.48 20.88,70.77 ; 20.88,70.77 20.38,70.27 20.38,69.6 20.89,69.1 R5406.1 ; 20.88,70.77 v1(20.99,70.67)
HDMI_DATA2_R_C: length 18.7
  BOTTOM w0.127: R5406.2 20.61,67.75 20.61,66.71 R5415.2 20.51,66.02 20.51,65.66 19.78,64.94 19.78,63.48 ; 19.78,63.48 19.78,62.88 15.48,58.58 12.8,58.58 10.52,60.85 10.03,60.85 HDMI1.HP1 ; 19.78,63.48 v1(19.95,63.48)
HDMI_HPD_B: length 10.4
  BOTTOM w0.102: Q5401.B 28.82,80.67 28.44,81.06 25.23,81.06 v1(23.84,79.66) 23.53,79.96 R5411.2
HDMI_HPD_E: length 4.6
  BOTTOM w0.102: Q5401.E 28.82,76.57 28.95,76.44 v1(29.55,76.44) 30.12,76.44 30.25,76.57 R5412.1 R5419.2
HDMI_PLL_GND:
  vias: v1(25.41,74.59)
HPD_HDMI_CON: length 14.9
  BOTTOM w0.102: R5411.1 R5410.1 18.6,79.07 v1(18.37,78.85) 16,76.47 16,75.34 10.38,69.72 HDMI1.HP19
HSIO_OUT:
  vias: v1(146.39,113.54)
HSIOPC: length 9.2
  BOTTOM w0.089: 137.44,84.4 136.75,84.4 CPU1.Y2
  BOTTOM w0.102: 137.44,84.4 137.51,84.47 139.47,84.47 140.96,85.97 v1(142.15,85.97) 142.83,85.97 143.38,86.52 R2123.1 R2007.1
HSIOPC_R: length 33.9
  TOP w0.102: v1(146.53,85.46) 146.53,85.67 145.61,86.59 v2(145.46,86.59)
  L4 w0.102: v2(142.1,110.64) 142.09,110.64 142.09,97.54 144.15,95.48 144.15,94.9 147.02,92.03 147.9,92.03 148.64,91.29 148.65,91.29 149.3,90.65 149.3,89.89 148.98,89.58 147.64,89.58 147.02,88.96 147.02,88.16 v2(145.46,86.59)
  BOTTOM w0.102: v2(145.46,86.59) 145.39,86.52 R2123.2 ; U2101.9 143.22,110.88 142.98,110.64 v2(142.1,110.64)
HVM_CLK: length 2.1
  TOP w0.102: v2(127.19,86.95) 126.91,87.23 TP620.1
  BOTTOM w0.102: CPU1.R20 125.99,86.49 126.73,86.49 v2(127.19,86.95)
HVM_CLK#: length 1.5
  TOP w0.102: v2(126.54,86.94) 126.22,86.62 TP619.1
  BOTTOM w0.102: v2(126.54,86.94) 126.23,87.25 CPU1.P20
I2C0_SCL: length 11.9
  BOTTOM w0.102: 137.65,92.38 137.49,92.22 136.79,92.22 136.52,91.95 136.19,91.95 CPU1.F3
  BOTTOM w0.14: RN2007.2 141.4,99.45 140.95,99 140.95,98 v1(140.19,97.24) 139,96.05 139,93.51 138.49,92.99 138.26,92.99 137.65,92.38
I2C0_SDA: length 11.9
  BOTTOM w0.102: CPU1.F2 136.87,92.02 137.84,92.02 137.93,92.11
  BOTTOM w0.14: RN2007.1 142.05,99.54 141.35,98.84 v1(141.35,98.32) 141.35,97.84 139.39,95.88 139.39,93.34 138.65,92.6 138.42,92.6 137.93,92.11
I2C1_SCL: length 252
  TOP w0.14: v2(54.65,71.77) 53.66,71.77 51.97,73.47 51.97,73.86 51.26,74.57 51.26,74.94 51.53,75.21 51.9,75.21 51.93,75.21 52.09,75.06 Q6204.1 ; v2(50.75,71.76) 51.24,72.24 EC6203.1 51.24,72.66 51.34,72.77 51.34,73.67 50.91,74.1 50.53,74.1 RN6203.2
  L3 w0.127: v2(160.58,30.4) 160.84,30.66 161.26,30.66 161.96,31.36 161.96,34.38 163.66,36.08 163.66,38.68 165.87,40.88 165.87,43.09 168.35,45.57 171.46,45.57 172.97,47.08 179.77,47.08 v2(179.78,47.07)
  L4 w0.127: v2(179.78,47.07) 179.85,47.13 179.85,47.95 179.38,48.43 179.38,50.41 179.52,50.55 179.52,51.76 178.5,52.78 178.5,55.91 174.37,60.04 174.37,66.29 173.82,66.85 173.82,70.83 169.87,74.77 169.5,74.77 163.79,80.48 163.79,81.69 163,82.49 160.13,82.49 158.22,84.41 157.62,84.41 156.7,85.32 156.09,85.32 152.88,88.54 152.06,88.54 150.25,90.36 150.25,91.77 148.51,93.51 147.93,93.51 147.35,94.09 147.33,94.09 144.56,96.85 144.56,97.9 143.67,98.78 143.67,99.1 143.47,99.29 v2(143.32,99.29)
  BOTTOM w0.14: v2(160.58,30.4) 160.09,30.4 159.18,31.3 144.74,31.3 121.92,54.12 79.45,54.12 64.08,69.49 58.94,69.49 56.11,72.31 55.19,72.31 v2(54.65,71.77) 54.13,72.29 v1(51.92,72.29) 51.2,72.29 50.75,71.84 v2(50.75,71.76) ; RN2008.2 143.43,99.81 143.43,99.4 v2(143.32,99.29) 143.29,99.26 143.28,99.26 143.15,99.13 142.61,99.13 141.86,98.39 141.86,97.8 139.72,95.65 139.72,93.29 138.19,91.76 137.23,91.76 CPU1.F1
I2C1_SCL_R: length 23.1
  TOP w0.14: R6204.2 48.07,74.08 48.66,74.08 48.78,74.21 RN6203.3 49.3,74.21 49.5,74.41 49.5,75.33 50.32,76.15 53.66,76.15 54.55,75.27 Q6204.6 54.01,75.06 53.77,74.82 53.77,73 54.15,72.62 56.37,72.62 56.45,72.7 56.45,73.07 56.32,73.2 RN6204.3 56.32,73.95 56.53,74.15 58.67,74.15 59.68,75.16 60.9,75.16 AFTP6237.1 61.67,75.18 62.26,75.77 TPAD1.6
I2C1_SDA: length 246.9
  TOP w0.14: Q6204.4 54.55,73.24 v2(54.65,73.14) ; RN6203.1 50.79,73.56 50.95,73.4 50.95,72.93 EC6204.1 50.43,72.08 50.3,71.95 50.3,71.94 v2(50.12,71.76)
  L3 w0.127: v2(160.51,31.24) 160.71,31.04 161.1,31.04 161.58,31.52 161.58,34.54 163.28,36.24 163.28,38.84 165.49,41.04 165.49,43.25 168.19,45.95 171.31,45.95 172.81,47.46 179.2,47.46 v2(179.41,47.67)
  L4 w0.127: v2(179.41,47.67) 179.41,47.86 179,48.27 179,50.57 179.13,50.71 179.13,51.61 178.12,52.62 178.12,55.75 173.99,59.88 173.99,66.14 173.44,66.69 173.44,70.67 169.71,74.39 169.34,74.39 163.41,80.32 163.41,81.53 162.84,82.11 159.98,82.11 158.06,84.03 157.46,84.03 156.55,84.94 155.94,84.94 152.72,88.16 151.9,88.16 149.87,90.2 149.87,91.62 148.35,93.13 147.77,93.13 147.19,93.71 147.17,93.71 144.18,96.7 144.18,97.74 143.29,98.62 143.29,98.62 143.28,98.62 v2(143.24,98.67)
  BOTTOM w0.14: v2(50.12,71.76) 50.3,71.94 50.3,71.95 51.04,72.68 v1(53.4,72.68) 54.19,72.68 v2(54.65,73.14) 55.08,72.71 56.27,72.71 59.1,69.88 64.24,69.88 79.61,54.51 122.08,54.51 144.9,31.7 159.34,31.7 159.93,31.11 160.38,31.11 v2(160.51,31.24) ; RN2008.1 144.08,99.28 143.47,98.67 v2(143.24,98.67) 142.7,98.67 142.26,98.22 142.26,97.63 140.11,95.49 140.11,93.13 138.36,91.37 137.46,91.37 137.34,91.25 135.51,91.25 CPU1.G4
I2C1_SDA_R: length 22.5
  TOP w0.14: R6210.2 48.06,73.69 48.61,73.69 48.74,73.56 RN6203.4 49.6,73.56 49.9,73.85 49.9,75.17 50.48,75.76 53.02,75.76 53.38,75.4 53.38,74.01 53.13,73.76 Q6204.3 52.67,73.54 53.99,72.22 56.53,72.22 56.84,72.53 56.84,73.01 56.97,73.14 RN6204.4 57.16,73.76 58.84,73.76 AFTP6240.1 59.85,74.77 TPAD1.7
I2CA_SCL: length 11.3
  TOP w0.14: RN7603.3 180.77,127.62 180.42,127.97 180.42,128.58 179.57,129.44 179.57,130.01 179.34,130.24 179.34,130.86 178.21,131.98 178.21,132.67 v1(178.22,132.67) 178.21,132.67 178.21,134.47 v2(178.29,134.55)
  BOTTOM w0.14: v2(178.29,134.55) 178.29,134.52 177.73,133.96 176.53,133.96 176.11,134.37 GPU1.B7
I2CA_SDA: length 9.4
  TOP w0.14: RN7603.4 180.12,127.71 180.03,127.81 180.03,128.42 179.17,129.27 179.17,129.85 178.95,130.07 178.95,130.69 177.82,131.82 v1(177.82,133.88) 177.82,134.36 v2(177.65,134.52)
  BOTTOM w0.14: v2(177.65,134.52) 177.48,134.35 176.87,134.35 GPU1.A7
I2CB_SCL: length 10.5
  TOP w0.14: RN7605.3 178.74,127.66 178.71,127.7 178.71,129.63 178.52,129.82 178.52,130.54 177.43,131.63 177.43,133.54 v1(176.5,134.47) 176.08,134.89 176.08,135.23 v2(175.64,135.67)
  BOTTOM w0.14: v2(175.64,135.67) 175.26,136.05 GPU1.C9
I2CB_SDA: length 9.6
  TOP w0.14: RN7605.4 178.09,127.59 178.32,127.82 178.32,129.47 178.13,129.66 178.13,130.37 177.03,131.46 v1(177.03,131.9) 177.03,133.38 v2(175.63,134.78)
  BOTTOM w0.14: GPU1.C8 175.62,134.84 175.62,134.79 v2(175.63,134.78)
I2CC_SCL: length 25.3
  TOP w0.14: v2(178.16,135.64) 178.16,135.56 178.31,135.41 178.87,135.41 180.12,134.16 180.12,133.25 181.72,131.65 195.02,131.65 196.69,133.32 v1(197.06,133.32) 198.12,133.32 198.25,133.45 RN7604.3
  BOTTOM w0.14: v2(178.16,135.64) 178.16,135.74 177.7,136.2 177,136.2 GPU1.A9
I2CC_SDA: length 26.1
  TOP w0.14: RN7604.4 198.25,132.8 198.13,132.93 196.85,132.93 195.18,131.26 181.56,131.26 179.73,133.09 179.73,134 v1(179.04,134.68) 178.71,135.02 178.15,135.02 v2(177.53,135.64)
  BOTTOM w0.14: GPU1.B9 176.56,135.54 177.13,135.54 177.23,135.64 v2(177.53,135.64)
IFPAB_IOVDD: length 3
  TOP w0.102: v1(162.97,133.46) 162.8,133.46 v2(162.43,133.09) 162.22,132.88 162.22,132.87 RN7402.3
  BOTTOM w0.102: v2(162.43,133.09) 162.03,133.49 GPU1.W6 GPU1.Y6
IFPAB_PLLVDD: length 3.4
  TOP w0.102: RN7402.4 161.57,133.57 v1(161.78,133.77) 162.3,133.77 162.43,133.91 v2(162.43,133.91)
  BOTTOM w0.102: GPU1.V7 v2(162.43,133.91) GPU1.W7
IFPC_IOVDD: length 1.7
  TOP w0.102: RN7401.3 164.26,132.46 v2(164.89,133.1)
  BOTTOM w0.102: v2(164.89,133.1) 165.3,133.51 GPU1.R6
IFPC_PLLVDD: length 3.7
  TOP w0.102: v2(164.91,133.91) 164.77,133.91 v1(164.42,133.56) 163.82,133.56 163.61,133.34 RN7401.4
  BOTTOM w0.102: GPU1.R7 v2(164.91,133.91) GPU1.T7
IFPD_IOVDD: length 2.3
  TOP w0.102: RN7404.3 166.29,132.67 165.89,133.07 v2(165.76,133.07) 165.76,133.09 v1(166.15,133.48)
  BOTTOM w0.102: v2(165.76,133.07) 165.75,133.07 165.75,133.06 165.74,133.06 165.73,133.07 165.76,133.1 165.76,133.11 GPU1.P6
IFPD_PLLVDD: length 4.4
  TOP w0.102: v2(165.72,133.91) 165.32,133.52 165.32,132.78 165.64,132.47 RN7404.4
  BOTTOM w0.102: GPU1.M7 167.6,134.5 167.18,134.5 GPU1.N7 166.93,134.37 166.18,134.37 v2(165.72,133.91)
IFPEF_IOVDD: length 3.1
  TOP w0.102: v2(170.82,134.01) 170.67,134.15 170.67,135.03 170.47,135.23 RN7403.3
  BOTTOM w0.102: GPU1.J6 170.39,133.63 170.42,133.63 170.5,133.72 170.53,133.72 v2(170.82,134.01) 171.11,133.71 GPU1.H6
IFPEF_PLLVDD: length 1.9
  TOP w0.102: v2(169.87,133.91) 170.07,134.11 RN7403.4
  BOTTOM w0.102: GPU1.K7 169.47,134.31 v2(169.87,133.91) 170.27,134.31 GPU1.J7
IMVP_PWRGD: length 247.9
  TOP w0.127: KBC24.107 182.8,68.53 v2(181.47,69.85) ; PR4628.2 R4622.2 119.76,145.83 120.11,145.48 v2(120.11,145.15)
  L3 w0.127: v2(184.13,44.99) 182.72,44.99 182.42,44.69 182.16,44.43 181.25,44.43 174.62,44.43 170.75,40.55 170.68,40.55 170.39,40.26 169.9,39.77 169.4,39.77 167.31,37.69 167.31,36.54 166.56,35.79 165.8,35.79 v2(165.6,35.59) ; v2(120.11,145.15) 120.01,145.24 114.22,145.24 112.56,143.58 112.56,141.97 111.52,140.93 109.32,140.93 103.96,135.57 103.96,133.93 104.22,133.66 104.22,121.06 103.8,120.64 103.12,119.96 101.43,118.28 98.08,114.92 98.08,114.71 98.08,105.55 95.85,103.33 v2(95.85,101.93)
  L4 w0.127: v2(184.13,44.99) 183.88,45.24 183.88,48.42 184.68,49.22 184.68,55.07 184.25,55.5 184.25,58.44 182.98,59.71 182.98,62.56 181.58,63.96 181.58,69.47 181.47,69.58 v2(181.47,69.85)
  BOTTOM w0.127: v2(95.85,101.93) 95.18,101.26 R713.1 95.16,101.06 93.28,101.06 85.54,93.32 85.54,81.12 85.76,80.91 85.76,77.78 85.11,77.14 85.11,67.03 92.03,60.1 123.01,60.1 147.21,35.91 161.67,35.91 v1(161.68,35.92) 162.26,35.92 162.73,35.45 165.45,35.45 v2(165.6,35.59)
IMVP_PWRGD_R: length 11.2
  BOTTOM w0.089: 100.67,95.31 100.71,95.27 100.71,94.75 100.92,94.54 100.92,94.21 101.21,93.91 CPU1.C59
  BOTTOM w0.102: 100.67,95.31 100.6,95.38 100.6,95.86
  BOTTOM w0.127: R713.2 R710.2 96.07,99.42 EC702.1 R712.1 96.12,98.46 96.12,97.96 96.53,97.55 97.05,97.55 97.5,98 v1(98.03,98) 98.48,98 99.05,97.43 99.05,97.41 100.6,95.86
INT_SERIRQ: length 86.9
  TOP w0.14: RN2002.5 143.64,95.1 143.14,94.59 142.15,94.59 139.5,91.95 139.5,91.44 138.26,90.2 137.72,90.2 136.91,89.38 v1(136.91,89.11) 136.81,89.01 136.81,87.97 136.95,87.84 136.95,87.39 136.95,87.15 136.46,86.66 136.13,86.66 v2(135.48,86) ; v2(184.03,81.18) 183.62,80.77 183.62,78.37 183.49,78.25 183.49,77.77 184.65,76.61 184.65,75.32 185.32,74.64 185.32,73.15 188.42,70.05 188.42,69.8 188.51,69.71 188.51,69.21 189.26,68.46 189.76,68.46 190,68.22 KBC24.125
  L3 w0.127: v2(184.03,81.18) 184.03,81.31 181.13,84.21 180.7,84.21 179.54,85.37 177.26,85.37 176.45,86.18 176.09,86.18 175.71,85.8 173.97,85.8 173.79,85.98 173.12,85.98 172.82,85.98 172.16,86.63 170.11,86.63 169.84,86.9 167.65,86.9 167.11,87.43 160.66,87.43 158,90.1 153.98,90.1 153.05,91.03 151.54,91.03 151.24,90.73 150.59,90.73 149.22,89.36 144.02,89.36 142.71,88.05 140.36,88.05 139.8,87.49 138.7,87.49 138.58,87.37 137.44,87.37 136.5,86.43 135.9,86.43 v2(135.48,86)
  BOTTOM w0.14: v2(135.48,86) 135.16,86.32 CPU1.T4
INT_TP#: length 241.9
  TOP w0.102: D2001.K 148.62,80.12 149.83,81.33 R2021.1 149.83,82.97 v2(149.78,83.02) ; v2(186.85,66.04) 187.14,65.75 187.24,65.75 187.76,65.23 187.76,64.74 R2448.1 188.27,63.78 187.99,63.5 187.99,63.02 187.51,62.54 187.51,61.23 188.76,59.97 v2(189.11,59.97) ; v2(59.04,76.25) 59.25,76.46 59.51,76.46 AFTP6241.1 60.82,77.77 TPAD1.4
  L3 w0.102: v2(163.77,33.08) 165.05,33.08 167.81,35.84 167.81,37.35 169.47,39.01 171.12,39.01 171.58,39.47 171.58,40.3 175.21,43.93 179.47,43.93 182.37,43.93 182.72,44.29 187.89,44.29 189.11,45.51 v2(189.51,45.51) ; v2(149.78,83.02) 150.26,82.54 153.73,82.54 154,82.26 156.7,82.26 158.07,83.63 160.13,83.63 160.91,84.41 164.09,84.41 165.95,82.55 167.04,82.55 167.3,82.8 167.3,84.07 167.06,84.31 167.06,84.88 167.32,85.13 169.11,85.13 169.38,84.87 171.35,84.87 173.13,83.09 v2(173.96,83.09)
  L4 w0.102: v2(189.11,59.97) 189.08,59.95 189.08,58.46 189.39,58.15 189.39,55.83 187.48,53.93 187.48,47.54 v2(189.51,45.51) ; v2(173.96,83.09) 174.05,83.09 175.43,81.71 175.43,80.54 178.14,77.83 179.28,77.83 181.64,75.47 182.51,75.47 183.5,74.48 183.52,74.48 184,74 184,73.11 185.4,71.71 185.4,71.49 186.42,70.46 186.42,67.51 186.85,67.09 v2(186.85,66.04)
  BOTTOM w0.102: v2(163.77,33.08) 163.17,33.69 163.17,33.75 162.74,34.18 162.2,34.18 161.75,34.64 145.5,34.64 122.24,57.9 80.08,57.9 65.62,72.35 65.62,73.71 64.92,74.42 62.29,74.42 60.39,76.31 59.91,76.31 R6203.1 59.11,76.32 v2(59.04,76.25)
INT_TP#_C: length 10
  TOP w0.102: D2001.A 150.16,80.69 150.72,81.25 R2021.2 150.7,81.57 R2031.2 151.01,82.37 v1(151.74,83.1) 152.29,83.65 152.29,85.42 152.04,85.67 150.93,85.67 150.33,86.27 R2019.2 149.96,85.68 R2030.2
ISOLATE#: length 4
  TOP w0.102: LOM30.20 52.34,168.77 v1(52.72,168.39) 53.26,167.85 R3014.2 R3015.1
ISUM_R_C: length 51.5
  TOP w0.254: v2(117.02,118.99) 113.73,118.99 111.17,121.55 v1(111.17,129.3) 111.17,133.59 110.14,134.62 110.14,136.35 110.14,136.77 110.73,137.37 110.93,137.37 v2(111.16,137.6) PR4708.2 111.81,137.6 PC4707.2 111.81,139.26 PC4708.2 111.03,139.28 PC4710.1 110.84,139.35 PC4709.1 110.94,140.16 PR4705.1
  L4 w0.254: v2(110.37,118.94) 109.72,119.6 109.72,120.21 110.4,120.88 110.4,136.84 v2(111.16,137.6)
  BOTTOM w0.254: v2(110.37,118.94) PR4704.2 ; PG4702.1 116.95,118.92 v2(117.02,118.99)
ISUM_R_R: length 1.8
  TOP w0.254: PR4706.1 111.59,140.95 PC4709.2 110.09,140.95 110.01,140.86 v1(109.93,140.86)
JACK_PLUG: length 16.8
  TOP w0.254: v1(187.51,20.99) 187.84,20.99 187.89,21.04 v2(188.07,21.04) 188.37,21.04 AFTP6307.1 190.11,22.77 CN6301.23
  L3 w0.254: v2(180.78,25.79) 181.43,26.44 184.97,26.44 188.07,23.34 v2(188.07,21.04)
  BOTTOM w0.254: v2(180.78,25.79) 180.45,25.46 R2923.1
JDREF: length 2.5
  BOTTOM w0.102: R2707.1 181.59,21.24 181.66,21.18 v1(181.66,20.76) 181.66,20.2 181.82,20.04 HDA27.15
KB_BL_CTRL: length 128.6
  TOP w0.102: v2(155.56,122.08) 156.22,121.41 161.69,121.41 161.77,121.5 162.65,121.5 163.07,121.07 164.85,121.07 165.81,122.03 171.42,122.03 171.97,122.58 179.87,122.58 180.39,122.05 183.56,122.05 185.33,123.82 185.33,127.06 186.18,127.91 Q6202.G 188.27,127.91 188.52,128.16 R6208.1 ; v2(194.73,87.32) 194.73,86.57 196.23,85.07 196.23,81.14 195.26,80.17 193.76,78.67 193.76,77.39 193.55,77.19 KBC24.22
  BOTTOM w0.102: v2(155.56,122.08) 155.05,122.08 151.31,118.34 151.31,107.12 152.45,105.99 152.45,104.64 155.61,101.48 155.61,99.44 156.24,98.81 156.24,91.22 157.19,90.26 158.49,90.26 158.69,90.46 159.94,90.46 160.18,90.23 175.82,90.23 178.74,87.3 185.08,87.3 185.35,87.02 188.68,87.02 189.01,87.36 190.23,87.36 v1(190.42,87.55) 190.5,87.63 193.66,87.63 193.99,87.3 194.72,87.3 v2(194.73,87.32)
KB_BL_CTRL#: length 6.7
  TOP w0.406: KB_BL1.4 192.44,124.57
  TOP w0.508: 192.44,124.57 192.28,124.57 191.9,124.95 191.9,125.53 AFTP6247.1 190.97,125.54 EC6207.1 188.98,125.54 188.62,125.9 Q6202.D
KB_DET#: length 72.3
  TOP w0.102: v2(177.72,87.07) 178.16,87.07 AFTP6202.1 179.04,87.96 179.74,87.96 180.63,88.84 181.29,88.84 182.38,89.93 182.41,89.93 182.53,90.05 184.11,90.05 184.61,89.54 185.53,89.54 185.55,89.51 190.02,89.51 190.86,90.35 190.86,91.88 190.85,91.89 190.85,92.47 191.33,92.95 KB1.30
  L3 w0.102: v2(177.72,87.07) 177.23,87.07 176.45,87.85 170.74,87.85 169.96,88.63 163.68,88.63 158.59,93.72 157.21,93.72 156.23,92.74 154.04,92.74 153.42,93.36 148.91,93.36 148.67,93.12 147.58,93.12 v2(147.35,92.89)
  L4 w0.102: v2(142.76,97.56) 146.46,93.86 146.46,93.78 v2(147.35,92.89)
  BOTTOM w0.102: RN1505.8 143.82,97.98 143.4,97.56 142.77,97.56 v2(142.76,97.56) 142.75,97.56 140.49,95.31 140.49,93.17 138.78,91.45 138.78,90.78 138.11,90.11 137.57,90.11 137.25,89.79 136.9,89.79 CPU1.K2
KB_LED_BL_DET: length 80
  TOP w0.102: v2(150.76,123.42) 151.32,123.42 v1(152.56,122.18) 153.53,121.21 161.77,121.21 161.86,121.3 162.56,121.3 162.99,120.87 164.94,120.87 165.89,121.83 171.59,121.83 172.13,122.38 179.78,122.38 180.31,121.85 183.64,121.85 185.28,123.49 R6207.1 R6206.1
  L3 w0.102: v2(150.76,123.42) 150.76,120.15 152.43,118.47 152.43,112.49 150.53,110.58 150.53,103.13 147.27,99.87 147.27,99.09 145.96,97.77 145.2,97.77 143.48,96.05 143.27,96.05 142.71,95.49 142.7,95.49 142.5,95.29 142.5,95.08 v2(138.37,90.94)
  BOTTOM w0.102: v2(138.37,90.94) 137.73,90.3 137.31,90.3 CPU1.J1
KB_LED_DET_C: length 7.3
  TOP w0.102: KB_BL1.2 192.4,122.57 192.21,122.76 192.21,123.59 191.61,124.19 AFTP6246.1 188,124.19 C6203.1 R6206.2
KBC_BEEP: length 54.2
  TOP w0.203: KBC24.118 187.2,68.82 187.05,68.97 v2(187.05,69.2)
  L4 w0.254: v2(186.04,31.9) 186.15,32.01 186.95,32.01 188.83,33.89 188.83,42.98 186.54,45.26 186.54,54.45 187.44,55.35 187.44,56.47 188.07,57.1 188.07,57.78 187.37,58.48 187.37,62.09 187.57,62.29 187.57,67.08 186.85,67.79 186.85,69 v2(187.05,69.2)
  BOTTOM w0.254: v2(186.04,31.9) 184.84,31.9 184.26,31.32 181.94,31.32 v1(180.96,30.34) 180.96,30.16 178.87,28.06 RN2701.1
KBC_BEEP_R: length 4.2
  BOTTOM w0.254: D2701.1 173.33,27.33 v1(173.84,27.84) 174.07,28.06 RN2701.4
KBC_DPWROK: length 73.8
  TOP w0.127: v2(185.66,57.31) 185.4,57.05 179.5,57.05 179.32,56.87 176.71,56.87 175.31,58.27 174.41,58.27 173.53,59.15 171.62,59.15 171.51,59.03 166.17,59.03 161.81,54.67 160.05,54.67 157.49,52.1 146.46,52.1 144.79,53.78 v1(143.47,53.78) 142.5,52.81 v2(142.5,52.1) ; v2(178.6,74.61) 178.42,74.79 KBC24.81
  L4 w0.127: v2(178.6,74.61) 178.66,74.61 181.26,72.01 181.75,72.01 181.96,72.01 183.63,70.34 183.63,67.22 184.7,66.15 184.7,59.76 185.58,58.89 185.58,57.38 v2(185.66,57.31)
  BOTTOM w0.127: v2(142.5,52.1) 142.57,52.17 EC1705.1 142.57,53.67 R1725.2 142.57,53.76 142.22,54.11 R1718.2
KBC_ON#_GATE: length 10.3
  TOP w0.102: Q2402.G 165.9,78.47 165.9,76.34 Q2403.G 167.03,75.21 169.6,75.21 v2(169.68,75.29)
  BOTTOM w0.102: C2417.1 169.62,75.22 v2(169.68,75.29) 170.27,75.29 v1(170.35,75.21) 170.47,75.09 R2433.2
KBC_ON#_GATE_L: length 3.6
  BOTTOM w0.102: R2431.1 170.09,73.38 170.11,73.37 R2433.1 170.47,72.5 170.72,72.24 v1(170.85,72.24) 171.01,72.24 171.29,72.52 R2432.2
KBC_PWRBTN#: length 224.6
  TOP w0.102: R2427.1 173.37,66.91 173.01,66.55 173.01,65.89 v2(172.73,65.61) 172.23,65.61 v1(171.9,65.95) ; R6102.1 190.74,172.92 191.02,172.64 v2(191.52,172.64)
  L3 w0.102: v2(150.08,160.71) 150.08,160.73 151.32,161.97 151.32,170.17 153.21,172.06 156.82,172.06 160.85,176.1 174.13,176.1 174.38,175.85 181.62,175.85 182.1,176.32 188.99,176.32 191.52,173.79 v2(191.52,172.64)
  L4 w0.102: v2(194.87,63.27) 194.87,63.5 194.27,64.1 194.27,65.06 193.11,66.23 193.11,74.27 192.64,74.73 192.64,80.16 190.96,81.84 190.96,85.15 190.33,85.78 188.5,85.78 188.4,85.68 188.02,85.68 187.61,86.09 v2(187.61,86.44)
  BOTTOM w0.102: v2(194.87,63.27) 194.51,63.63 193.2,63.63 192.79,64.03 187.61,64.03 186.74,63.17 186.49,63.17 185.58,62.26 175.13,62.26 172.73,64.66 v2(172.73,65.61) ; v2(187.61,86.44) 187.33,86.72 185.35,86.72 184.98,87.1 178.66,87.1 175.76,90 161.98,90 161.36,89.38 157.79,89.38 156.04,91.13 156.04,98.72 155.41,99.35 155.41,101.39 152.24,104.56 152.24,105.91 150.89,107.26 150.89,116.99 146.24,121.65 146.24,122.84 145.4,123.68 145.4,131.68 146.45,132.73 146.45,141.22 145.22,142.45 145.22,150.47 145.51,150.76 145.51,159.08 147.02,160.59 149.96,160.59 v2(150.08,160.71)
KBC_PWRBTN#_C: length 15.7
  TOP w0.127: G6101.2 191.92,173.07 R6102.2 191.63,174.18 EC6101.1 191.63,174.2 191.63,175.05 ED6101.1 192.11,175.07 v2(192.34,175.3) 192.77,175.3 AFTP6101.1 193.75,175.06 198.6,170.21 PWR1.2
  BOTTOM w0.127: G6102.2 192.04,175.6 192.34,175.3 v2(192.34,175.3)
KBC_VCORF: length 2.9
  TOP w0.203: C2416.1 187.06,84.02 186.8,83.76 KBC24.44
  TOP w0.254: v1(187.97,84.8) 187.76,84.8 187.51,84.55 C2416.1
KCOL0: length 36.8
  TOP w0.102: KBC24.53 183.2,84.24 183.76,84.81 183.76,86.79 184.49,87.52 184.73,87.52 184.87,87.65 v2(184.87,87.74) ; AFTP6207.1 195,102.98 195,104.7 193.15,106.55 KB1.13 191.16,106.55 190.84,106.87 188.98,106.87 188.22,106.11 188.22,96.46 188.22,96.13 186.37,94.28 186.37,94.28 186.02,93.94 185.21,93.94 184.63,93.36 184.63,92.83 v2(184.23,92.43)
  L3 w0.102: v2(184.23,92.43) 184.23,92.09 184.87,91.44 184.87,87.74 v2(184.87,87.74)
KCOL1: length 31.3
  TOP w0.102: KBC24.52 183.6,84.1 184.39,84.89 AFTP6206.1 184.09,85.41 184.09,86.6 184.72,87.22 185.05,87.22 185.48,87.65 185.48,87.86 185.72,88.09 187.87,88.09 188.1,87.86 v2(188.15,87.86) ; v2(185.8,93.27) 185.94,93.27 188.62,95.96 188.62,96.63 188.62,102.87 190.7,104.95 KB1.15
  L3 w0.102: v2(185.8,93.27) 185.66,93.13 185.66,90.73 188.15,88.23 v2(188.15,87.86)
KCOL2: length 34.5
  TOP w0.102: v2(185.99,87.58) 185.96,87.56 185.72,87.56 185.12,86.95 184.73,86.95 184.3,86.51 184.3,85.79 184.74,85.34 184.74,84.94 184,84.2 KBC24.51 ; v2(185.07,93.15) 185.37,93.45 185.37,93.45 185.62,93.7 185.63,93.7 185.64,93.72 186.1,93.72 188.42,96.04 188.42,96.04 188.42,96.55 188.42,96.55 188.42,106.02 189,106.61 190.81,106.61 191.67,105.75 KB1.14 193.44,105.75 AFTP6226.1
  L3 w0.102: v2(185.99,87.58) 185.91,87.66 185.91,88.12 185.18,88.85 185.18,91.63 184.71,92.1 184.71,92.79 v2(185.07,93.15)
KCOL3: length 32.7
  TOP w0.102: v2(185.14,92.4) 185.58,92.84 185.98,92.84 186.41,93.27 186.41,93.46 188.83,95.87 188.83,102.76 190.22,104.15 KB1.16 193.16,104.15 193.64,103.67 193.64,101.72 AFTP6208.1 ; KBC24.50 184.4,83.54 184.34,83.6 184.34,84.23 185.02,84.92 185.02,85.98 185.48,86.44 185.48,86.64 185.99,87.15 186.44,87.15 v2(186.75,87.46)
  L3 w0.102: v2(186.75,87.46) 186.75,87.57 185.39,88.93 185.39,91.83 185.14,92.08 v2(185.14,92.4)
KCOL4: length 27
  TOP w0.102: v2(186.99,92.44) 187.62,93.07 187.62,93.72 189.43,95.53 189.43,95.62 189.43,95.62 189.43,96.97 189.43,96.97 189.43,101.01 189.87,101.45 190.89,101.45 191.39,100.95 KB1.20 ; v2(189.23,87.81) 188.75,87.81 188.35,87.41 187.36,87.41 186.95,87 186.6,87 186.44,86.85 186.19,86.85 AFTP6224.1 185.22,85.88 185.22,84.81 184.54,84.13 184.54,83.77 184.8,83.51 KBC24.49
  L3 w0.102: v2(186.99,92.44) 186.89,92.34 186.89,90.37 189.23,88.03 v2(189.23,87.81)
KCOL5: length 26.4
  TOP w0.102: KB1.21 193.38,100.15 194.05,99.48 194.05,98.21 AFTP6215.1 195.69,96.57 195.69,92.21 195.71,92.18 195.71,91.08 194.27,89.64 193.28,89.64 191.73,88.09 191.18,88.09 190.45,87.36 189.01,87.36 188.85,87.2 187.47,87.2 187.07,86.8 186.7,86.8 185.43,85.53 185.43,83.68 185.19,83.45 KBC24.48
KCOL6: length 27.6
  TOP w0.102: v2(189.19,86.93) 189.07,86.81 AFTP6223.1 188.28,86.87 187.43,86.87 187.15,86.59 186.8,86.59 185.64,85.43 185.64,83.59 185.6,83.55 KBC24.47 ; KB1.18 190.07,102.55 189.23,101.71 189.23,96.89 189.23,95.71 189.23,95.7 189.23,95.64 187.03,93.44 187.03,93.18 v2(187.05,93.17)
  L3 w0.102: v2(189.19,86.93) 188.79,87.33 188.79,88.18 186.56,90.42 186.56,92.68 v2(187.05,93.17)
KCOL7: length 25.6
  TOP w0.102: KBC24.43 187.2,83.47 188.36,84.64 188.36,85.38 189.65,86.68 190.05,86.68 190.53,87.15 190.53,87.15 191.27,87.89 191.81,87.89 193.36,89.44 194.36,89.44 195.92,91 195.92,92.28 195.89,92.31 195.89,99.02 AFTP6213.1 195.67,99.19 193.11,101.75 KB1.19
KCOL8: length 27.8
  TOP w0.102: v2(189.83,86.25) 189.83,85.31 AFTP6231.1 189.46,85.23 189.43,85.26 188.99,85.26 188.74,85.01 188.74,84.72 187.6,83.58 KBC24.42 ; KB1.17 190.43,103.35 189.03,101.95 189.03,96.8 189.03,95.76 186.61,93.35 186.61,93.18 186.09,92.66 v2(186.09,92.42)
  L3 w0.102: v2(189.83,86.25) 189.82,86.26 189.25,86.26 188.59,86.92 188.59,88.1 186.09,90.59 v2(186.09,92.42)
KCOL9: length 47.4
  TOP w0.102: v2(190.02,84.74) 190.02,84.73 189.95,84.65 189.6,84.65 189.35,84.4 188.71,84.4 188,83.68 KBC24.41 ; v2(183.96,91.04) 183.7,91.3 183.7,93.27 184.77,94.34 185.86,94.34 187.81,96.3 187.81,110.14 189.02,111.35 KB1.7 194.39,111.35 195.08,110.66 195.08,109.35 196.38,108.06 AFTP6219.1
  L3 w0.102: v2(183.96,91.04) 184.16,90.83 184.16,87.47 184.61,87.02 185.27,87.02 186.81,85.48 189.57,85.48 190.02,85.02 v2(190.02,84.74)
KCOL10: length 43.5
  TOP w0.102: KBC24.40 188.4,81.87 188.65,81.61 188.74,81.61 189.17,81.18 191.62,81.18 191.91,81.46 192.01,81.46 192.72,82.18 192.72,84.1 192.69,84.13 192.69,84.23 192.59,84.33 192.59,86.47 192.58,86.47 192.58,86.84 193.94,88.19 194.5,88.19 195.11,87.58 195.47,87.58 197.16,89.27 197.16,101.15 197.27,101.25 197.27,102.05 197.26,102.06 197.26,108.71 AFTP6232.1 196.33,109.65 196.33,110.99 194.37,112.95 KB1.5
KCOL11: length 40.8
  TOP w0.102: KB1.6 194.62,112.15 AFTP6220.1 195.29,111.53 195.29,109.49 197.06,107.72 197.06,101.97 197.07,101.97 197.07,101.34 196.96,101.23 196.96,90.6 194.78,88.42 193.88,88.42 192.38,86.92 192.38,86.37 192.39,86.36 192.39,84.23 192.49,84.13 192.49,84.03 192.52,84 192.52,82.26 191.93,81.67 191.82,81.67 191.54,81.39 189.26,81.39 188.83,81.82 188.8,81.82 KBC24.39
KCOL12: length 30.6
  TOP w0.102: KBC24.38 189.2,83.45 189.42,83.67 189.84,83.67 189.9,83.72 189.9,83.72 190.46,84.28 190.46,86.26 191.88,87.69 191.9,87.69 193.44,89.23 194.44,89.23 196.12,90.91 196.12,92.38 196.1,92.41 196.1,99.55 195.2,100.44 195.2,105.28 194.97,105.51 194.97,106.13 AFTP6233.1 193.75,107.35 KB1.12
KCOL13: length 36.9
  TOP w0.102: KBC24.37 189.6,82.02 190.02,81.59 191.46,81.59 191.81,81.94 191.91,81.94 192.31,82.34 192.31,83.02 191.56,83.77 191.56,84.69 192.16,85.29 192.16,86.99 193.79,88.62 194.7,88.62 196.76,90.68 196.76,101.31 196.86,101.42 196.86,101.88 196.86,101.89 196.86,105.32 AFTP6203.1 195.59,106.58 195.59,107.91 193.76,109.75 KB1.9
KCOL14: length 43.8
  TOP w0.102: v2(184.19,93.14) 184.19,93.21 185.12,94.14 185.94,94.14 186.28,94.48 188.01,96.21 188.01,109.78 188.81,110.57 190.29,110.57 190.31,110.55 KB1.8 194.36,110.55 AFTP6216.1 ; KBC24.36 190,83.51 190.66,84.17 190.66,85.77 v2(191.24,86.35)
  L3 w0.102: v2(191.24,86.35) 190.95,86.35 190.28,85.68 186.9,85.68 185.35,87.22 184.69,87.22 184.4,87.52 184.4,91.62 183.79,92.23 183.79,92.74 v2(184.19,93.14)
KCOL15: length 35
  TOP w0.102: KB1.10 194.02,108.95 AFTP6229.1 195.39,107.58 195.39,105.69 196.65,104.43 196.65,101.8 196.66,101.8 196.66,101.5 196.55,101.4 196.55,90.77 194.61,88.83 193.71,88.83 191.96,87.07 191.96,85.4 191.36,84.8 191.36,83.69 192.11,82.93 192.11,82.43 191.83,82.15 191.73,82.15 191.37,81.79 190.54,81.79 190.4,81.93 KBC24.35
KCOL16: length 30.8
  TOP w0.102: KBC24.34 190.8,84.02 190.86,84.09 190.86,84.61 191.75,85.5 191.75,87.24 193.55,89.03 194.53,89.03 196.32,90.83 196.32,101.63 AFTP6225.1 196.3,102.32 195.48,103.14 195.48,105.31 195.19,105.61 195.19,107.04 194.08,108.15 KB1.11
KROW0: length 28.2
  TOP w0.102: KBC24.54 182.8,84.34 183.24,84.79 183.24,86.9 AFTP6228.1 184.64,88.29 191.62,88.29 193.17,89.84 194.19,89.84 195.51,91.17 195.51,92.08 195.49,92.1 195.49,95.56 193.66,97.38 193.66,98.9 193.22,99.35 KB1.22
KROW1: length 26.8
  TOP w0.102: KBC24.55 182.4,84.25 183.04,84.89 183.04,87.2 183.77,87.93 183.77,87.93 183.92,88.08 183.94,88.08 184.38,88.51 184.55,88.51 184.56,88.52 185.02,88.52 185.05,88.5 191.49,88.5 193.04,90.05 193.21,90.05 193.9,90.74 193.9,91.2 194.14,91.44 195.09,91.44 195.28,91.63 195.28,91.65 195.31,91.67 195.31,91.98 195.28,92 195.28,95.07 AFTP6227.1 193.46,96.89 193.46,97.5 193.21,97.75 KB1.24
KROW2: length 24.9
  TOP w0.102: KB1.26 193.15,96.15 194.22,95.07 194.22,93.42 194.93,92.72 AFTP6218.1 194.75,91.65 194.04,91.65 193.67,91.28 193.67,90.83 193.09,90.25 192.95,90.25 191.4,88.7 185.15,88.7 185.12,88.73 184.28,88.73 183.85,88.29 183.83,88.29 182.84,87.3 182.84,85.09 182,84.25 KBC24.56
KROW3: length 27.1
  TOP w0.102: v2(183.73,88.89) 182.58,87.73 182.58,85.35 AFTP6234.1 181.6,84.36 KBC24.57 ; v2(190.12,92.47) 189.72,92.87 189.72,93.37 190.37,94.01 190.37,98.18 190.73,98.55 KB1.23
  L3 w0.102: v2(183.73,88.89) 183.53,89.09 183.53,93.08 184.15,93.7 188.89,93.7 v2(190.12,92.47)
KROW4: length 24
  TOP w0.102: KBC24.58 181.2,84.67 182.38,85.85 182.38,88.06 183.22,88.91 183.22,88.98 183.29,89.06 183.29,89.08 183.55,89.34 183.9,89.34 184.31,88.93 185.22,88.93 185.25,88.9 191.32,88.9 192.64,90.23 192.64,90.32 AFTP6230.1 193.25,91.17 193.99,91.9 193.99,94.38 193.02,95.35 KB1.27
KROW5: length 28.7
  TOP w0.102: KBC24.59 180.8,84.56 182.17,85.94 182.17,88.47 v2(182.79,89.09) ; AFTP6214.1 194.64,95.17 192.87,96.95 KB1.25 191.26,96.95 190.73,96.42 190.73,93.77 v2(190.15,93.19)
  L3 w0.102: v2(182.79,89.09) 183.32,89.62 183.32,93.18 184.05,93.91 188.97,93.91 189.69,93.19 v2(190.15,93.19)
KROW6: length 23.4
  TOP w0.102: KB1.28 193,94.55 193.65,93.9 193.65,92.2 192.18,90.72 191.81,90.72 191.27,90.17 191.27,90.15 190.23,89.11 185.35,89.11 185.33,89.13 184.41,89.13 183.93,89.62 182.71,89.62 182.63,89.54 182.61,89.54 182.35,89.29 182.35,89.26 181.01,87.91 AFTP6222.1 180.4,85.98 KBC24.60
KROW7: length 22.8
  TOP w0.102: KBC24.61 180,84.24 179.81,84.42 AFTP6221.1 179.81,86.43 180.74,87.36 180.74,87.94 180.8,88 180.8,88.02 182.15,89.36 182.15,89.39 182.51,89.74 182.53,89.74 182.61,89.82 182.62,89.82 182.65,89.84 184,89.84 184.51,89.34 185.43,89.34 185.45,89.31 190.13,89.31 191.07,90.25 191.07,90.28 191.88,91.09 192.26,91.09 193.36,92.19 193.36,93.5 193.12,93.75 KB1.29
L_BKLT_CTRL: length 147.5
  L4 w0.127: v2(70.82,164.52) 72.38,166.07 74.72,166.07 79.91,171.26 86.99,171.26 90.71,167.54 97.17,167.54 100.83,163.88 100.83,163.4 101.71,162.52 101.71,160.68 98.58,157.56 98.58,156.6 98.64,156.54 98.64,153.57 105.5,146.71 120.6,146.71 120.76,146.71 121.11,146.71 122.06,147.65 134.91,147.65 136.74,145.83 136.74,124.76 136.09,124.11 136.09,111.91 136.05,111.87 136.02,111.87 135.54,111.38 135.54,111.03 135.55,111.02 135.55,109.23 137.23,107.55 137.23,103.66 138.55,102.34 138.55,101.16 v2(138.54,101.15)
  BOTTOM w0.089: 133.02,95.71 132.86,95.55 132.86,94.95 132.37,94.46 132.22,94.46 CPU1.B8
  BOTTOM w0.14: 133.02,95.71 134.8,97.49 135.47,97.49 136.28,98.3 136.28,98.99 137.72,100.43 v1(137.83,100.43) v2(138.54,101.15) ; R5206.1 70.42,164.11 v2(70.82,164.52)
L_BKLT_EN: length 111.9
  TOP w0.102: v2(186.17,55.87) 187.52,55.87 188.45,56.8 189.87,56.8 194.6,61.52 194.6,62.38 196.13,63.91 196.13,64.69 194.6,66.22 R2444.1
  L3 w0.102: v2(141.13,104.37) 138.47,104.37 135.41,101.32 135.41,100.5 134.49,99.57 v2(134.17,99.57)
  L4 w0.102: v2(186.17,55.87) 186.16,55.88 186.16,57.45 185.82,57.79 185.82,58.99 184.94,59.87 184.94,66.25 183.87,67.32 183.87,70.44 182.06,72.25 181.36,72.25 179.75,73.86 179.75,74.89 179.01,75.64 179.01,75.92 178.76,76.17 178.24,76.17 177.2,77.21 177.2,77.37 174.2,80.37 174.2,81.56 168.97,86.8 167.34,86.8 167.01,87.13 163.08,87.13 157.96,92.24 157.54,92.24 157.19,92.59 157.19,93.88 151.15,99.92 151.15,100.49 147.33,104.31 147.33,107.01 v2(147.43,107.12)
  BOTTOM w0.102: v2(147.43,107.12) 147.27,106.95 143.8,106.95 v1(142.61,105.76) 141.22,104.37 v2(141.13,104.37) ; v2(134.17,99.57) 134.17,98.99 133.92,98.73 133.92,98.03 131.66,95.78 CPU1.A9
L_BKLT_EN_EC: length 6.3
  TOP w0.102: KBC24.9 193.53,71.99 193.79,71.73 193.79,71.65 194.08,71.35 194.95,71.35 R2447.1 195.53,70.15 v1(195.05,69.68) 194.88,69.5 194.88,68.84 194.6,68.56 R2444.2
LAN_ENABLE_R_C: length 4.3
  TOP w0.127: Q3001.D 62.07,170.78 63.14,171.85 R3022.1 63.85,172.18 v1(64.04,172.37) 63.35,173.06 R3021.2
LAN_MDI0N: length 28.8
  TOP w0.089: 41.43,172.49 41.12,172.49 41.06,172.56 40.87,172.74 40.87,173.09 v2(40.66,173.31) ; 41.43,172.49 v1(41.43,172.32) ; 41.43,172.49 43.19,172.49 43.54,172.14 43.54,171.2 44.27,170.48 45.68,170.48 46.11,170.05 46.36,170.05 46.44,169.97 LOM30.2
  BOTTOM w0.089: v2(40.66,173.31) 40.89,173.08 40.89,172.88 40.6,172.59 39.71,172.59 EC3102.2 39.01,172.61 38.82,172.61 38.61,172.82 38.61,173.22 38.36,173.47 38.11,173.47 37.98,173.6 EU3101.9 EU3101.2 36.13,173.6 36,173.47 35.32,173.47 32.92,171.07 31.25,171.07 30.49,170.31 30.49,165.36 30.37,165.24 30,165.24 29.91,165.33 29.91,165.68 29.82,165.76 28.91,165.76
LAN_MDI0P: length 28.8
  TOP w0.089: v1(42.88,172.88) 42.88,172.71 ; 42.88,172.71 41.21,172.71 41.09,172.83 41.09,173.11 v2(41.3,173.31) ; 42.88,172.71 43.28,172.71 43.76,172.23 43.76,171.29 44.36,170.69 45.77,170.69 46.2,170.27 46.36,170.27 46.46,170.37 LOM30.1
  BOTTOM w0.089: v2(41.3,173.31) 41.1,173.12 41.1,172.79 40.69,172.38 39.66,172.38 EC3101.2 39.02,172.4 38.73,172.4 38.4,172.73 38.4,173.13 38.27,173.25 38.11,173.25 37.98,173.12 EU3101.10 EU3101.1 36.13,173.12 36,173.25 35.41,173.25 33.01,170.86 31.34,170.86 30.7,170.22 30.7,165.27 30.46,165.02 30,165.02 29.91,164.93 29.91,164.58 29.82,164.49 XF3101.12
LAN_MDI1N: length 27.7
  TOP w0.089: 44.28,168.84 42.73,168.84 42.3,169.27 42.3,171.2 v2(42.17,171.33) ; 44.28,168.84 46.39,168.84 46.46,168.77 LOM30.5 ; 44.28,168.84 v1(44.28,168.68)
  BOTTOM w0.089: 28.91,173.38 29.82,173.38 29.91,173.3 29.91,172.95 30,172.86 32.32,172.86 34.45,174.99 36,174.99 36.13,175.12 EU3101.5 EU3101.6 38.05,175.12 38.17,174.99 38.38,174.99 38.5,175.11 38.5,175.89 38.71,176.1 39.01,176.1 EC3104.2 39.58,176.2 40.24,176.2 43.24,173.21 43.24,171.99 42.83,171.58 42.42,171.58 v2(42.17,171.33)
LAN_MDI1P: length 27.6
  TOP w0.089: 42.51,170.64 42.51,171.07 42.6,171.15 42.6,171.53 42.15,171.98 v2(42.15,171.99) ; 42.51,170.64 42.51,169.36 42.82,169.06 46.38,169.06 46.49,169.17 LOM30.4 ; 42.51,170.64 v1(42.65,170.64)
  BOTTOM w0.089: v2(42.15,171.99) 42.33,171.81 42.33,171.81 42.34,171.8 42.74,171.8 43.02,172.08 43.02,173.12 40.15,175.99 39.79,175.99 EC3103.2 39.01,175.88 38.8,175.88 38.72,175.8 38.72,175.03 38.47,174.78 38.14,174.78 38,174.64 EU3101.7 EU3101.4 36.13,174.64 36,174.77 34.54,174.77 32.41,172.64 30,172.64 29.91,172.55 29.91,172.2 29.82,172.11 XF3101.8
LAN_MDI2N: length 30.9
  TOP w0.089: LOM30.7 46.47,167.97 46.38,168.06 46.13,168.06 45.81,167.74 44.01,167.74 v2(43.77,167.5) ; 28.91,165.76 29.4,165.76 29.67,165.49 30.75,165.49 32.1,166.84 32.1,170.25 32.97,171.12 ; 32.97,171.12 35.31,173.47 36,173.47 36.13,173.6 EU3102.9 EU3102.2 37.98,173.6 38.11,173.47 38.36,173.47 38.61,173.21 38.61,172.82 38.73,172.7 39.1,172.7 EC3106.2 39.69,172.62 40.22,172.62 40.76,172.08 40.76,171.61 v2(41.02,171.35) ; 32.97,171.12 v1(32.84,171.24)
  BOTTOM w0.089: v2(43.77,167.5) 43.95,167.68 44.38,167.68 44.59,167.89 44.59,168.84 44.16,169.27 44.16,170.58 43.75,170.99 42.64,170.99 42.4,170.74 40.96,170.74 40.78,170.92 40.78,171.11 v2(41.02,171.35)
LAN_MDI2P: length 30.8
  TOP w0.089: XF3102.7 29.75,164.49 29.88,164.62 29.88,165.13 30.02,165.27 30.84,165.27 32.31,166.75 32.31,170.16 34.73,172.57 ; v1(34.83,172.47) 34.73,172.57 ; 34.73,172.57 35.4,173.25 36,173.25 36.13,173.12 EU3102.10 EU3102.1 37.98,173.12 38.11,173.25 38.27,173.25 38.39,173.13 38.39,172.73 38.64,172.48 39,172.48 39.35,172.14 EC3105.2 39.69,172.4 40.13,172.4 40.54,171.99 40.54,171.55 v2(40.34,171.35) ; LOM30.6 46.48,168.37 46.38,168.28 46.04,168.28 45.72,167.96 43.95,167.96 v2(43.76,168.15)
  BOTTOM w0.089: v2(40.34,171.35) 40.39,171.35 40.57,171.17 40.57,170.83 40.87,170.53 42.49,170.53 42.73,170.77 43.66,170.77 43.94,170.49 43.94,169.18 44.38,168.75 44.38,167.98 44.29,167.89 43.95,167.89 43.76,168.08 v2(43.76,168.15)
LAN_MDI3N: length 32.3
  TOP w0.089: LOM30.10 47.93,166.45 47.47,165.99 46.32,165.99 46.21,165.89 46.21,165.89 v2(46.06,165.74) ; v2(40.72,176.88) 40.89,176.72 40.89,176.43 40.64,176.19 39.98,176.19 39.73,176.43 EC3108.2 39.01,176.1 38.69,176.1 38.5,175.9 38.5,175.11 38.38,174.99 38.17,174.99 38.04,175.12 EU3102.5 EU3102.6 36.13,175.12 36,174.99 34.45,174.99 32.72,173.25 ; 32.72,173.25 32.32,172.86 30,172.86 29.91,172.95 29.91,173.3 29.82,173.38 28.91,173.38 ; 32.72,173.25 v1(32.59,173.37)
  BOTTOM w0.089: v2(46.06,165.74) 45.96,165.84 45.08,165.84 44.52,166.4 44.52,167.12 45.13,167.73 45.13,169 44.65,169.48 44.65,170.95 43.85,171.76 43.85,173.46 40.99,176.32 40.99,176.62 v2(40.72,176.88)
LAN_MDI3P: length 32.2
  TOP w0.089: 33.97,174.2 32.41,172.64 30,172.64 29.91,172.55 29.91,172.2 29.82,172.11 XF3102.11 ; 33.97,174.2 v1(34.1,174.07) ; 33.97,174.2 34.54,174.77 36,174.77 36.13,174.64 EU3102.7 EU3102.4 38,174.64 38.13,174.77 38.47,174.77 38.72,175.02 38.72,175.81 38.78,175.88 39.01,175.88 EC3107.2 39.66,175.54 40.09,175.97 40.73,175.97 41.1,176.34 41.1,176.69 41.28,176.86 v2(41.46,176.86) ; v2(46.01,166.41) 46.22,166.21 47.38,166.21 47.53,166.36 LOM30.9
  BOTTOM w0.089: v2(46.01,166.41) 46.01,166.34 45.73,166.06 45.17,166.06 44.74,166.49 44.74,167.03 45.35,167.64 45.35,169.09 44.87,169.57 44.87,171.04 44.06,171.85 44.06,173.55 41.2,176.41 41.2,176.6 v2(41.46,176.86)
LAN_TXN_C_PCH_RXN4: length 4.5
  TOP w0.127: 52.3,166.86 52.3,167.37 51.71,167.97 LOM30.18 ; 52.3,166.86 52.3,166.53 53.36,165.47 53.52,165.47 C3016.1 ; 52.3,166.86 v1(52.43,166.86)
LAN_TXP_C_PCH_RXP4: length 4.6
  TOP w0.127: C3014.1 53.4,165.23 53.26,165.23 52.91,165.58 ; 52.91,165.58 52.06,166.43 52.06,167.27 51.77,167.57 LOM30.17 ; 52.91,165.58 v1(52.79,165.46)
LANXIN: length 8.9
  TOP w0.14: 49.13,171.05 49.13,172.57 v1(48.77,172.93) 48.5,173.2 C3001.1 48.5,174.44 48.87,174.81 49.91,174.81 50.22,175.12 50.22,176.92 49.77,177.37 X3001.1
LANXOUT: length 5.7
  TOP w0.14: LOM30.29 48.73,172.11 48.73,172.11 v1(47.58,173.26) 47.51,173.33 C3011.1 47.51,174.68 46.66,175.54 X3001.3
LCD_BRIGHTNESS: length 2.6
  TOP w0.14: LCD1.20 77.7,167.32 v2(77.5,167.52)
  BOTTOM w0.14: v1(77.93,167.06) 77.5,167.48 v2(77.5,167.52) 77.43,167.59 RN5201.2
LCD_TST: length 198.2
  TOP w0.102: v2(194.14,86.19) 194.98,85.35 194.98,82.33 194.79,82.15 R2417.1
  L4 w0.102: v2(75.69,169.55) 75.69,170.06 77.8,172.17 104.28,172.17 105.21,173.1 109.5,173.1 110.09,173.69 112.34,173.69 112.81,173.22 126.73,173.22 127.97,171.98 132.12,171.98 134.06,170.03 134.06,166.21 137.7,162.57 137.7,160.78 137.7,160.78 139.68,158.81 140.01,158.81 141.61,158.81 145.04,155.38 145.04,149.43 145.56,148.92 145.56,142.41 146.46,141.5 146.46,141.44 146.47,141.43 146.47,138.82 146.13,138.49 146.13,131.45 146.08,131.4 146.08,129.52 147.45,128.15 147.45,120.68 151.47,116.66 151.47,104.42 154.1,101.79 154.1,99.03 159.08,94.05 159.08,93.51 163.61,88.98 169.66,88.98 170.8,87.84 170.97,87.84 173.4,85.42 173.4,85.41 175.41,83.4 v2(175.41,83.13)
  BOTTOM w0.102: v2(75.69,169.55) 75.7,169.54 RN5201.8 ; v2(194.14,86.19) 193.5,86.19 193.25,85.93 192.18,85.93 192.13,85.88 192.13,85.88 191.5,85.25 191.47,85.25 189.95,83.73 189.33,83.73 188.97,84.08 186.49,84.08 186.21,84.36 181.32,84.36 180.07,83.11 176.21,83.11 v1(176.16,83.16) 175.44,83.16 v2(175.41,83.13)
LCD_TST_C: length 7.4
  TOP w0.102: v2(76.29,170.05) 76.29,170.51 78.1,172.32 LCD1.10 79.37,172.32 v1(80.21,173.16)
  BOTTOM w0.102: v2(76.29,170.05) 76.67,169.67 RN5201.1
LCD_TST_EN: length 215.5
  TOP w0.102: KBC24.28 193.46,79.59 194.31,80.44 R2417.2 195.23,80.44 196,81.21 196,85.02 194.17,86.85 v2(194.04,86.85)
  L4 w0.102: v2(71.23,162.56) 69.95,163.84 69.95,167.53 72.21,169.79 74.44,169.79 77.22,172.57 104.11,172.57 105.04,173.5 109.29,173.5 110.64,174.85 112.02,174.85 112.83,174.04 112.83,174.04 113.08,173.79 113.09,173.79 113.23,173.64 128.2,173.64 128.48,173.36 129.64,173.36 130.46,172.54 132.13,172.54 134.47,170.2 134.47,166.38 138.11,162.74 138.11,160.95 138.11,160.95 139.85,159.21 141.78,159.21 145.45,155.55 145.45,153.77 145.45,149.64 145.96,149.12 145.96,142.62 146.87,141.71 146.87,141.6 146.87,141.6 146.87,138.65 146.54,138.32 146.54,131.25 146.49,131.2 146.49,129.72 148.24,127.97 148.24,121.17 151.84,117.57 151.93,117.57 152.18,117.31 152.18,104 154.3,101.88 154.3,99.11 159.28,94.14 159.28,93.59 163.69,89.18 171.01,89.18 v2(171.91,88.28)
  BOTTOM w0.102: v2(171.91,88.28) 174.56,88.28 177.08,85.76 179.25,85.76 179.56,85.45 v1(180.35,85.45) 180.37,85.43 186.47,85.43 186.67,85.23 188.6,85.23 188.89,85.52 189.73,85.52 190.99,86.78 191.9,86.78 192.45,86.23 193.24,86.23 193.86,86.85 v2(194.04,86.85) ; D5201.2 70.12,161.46 v2(71.23,162.56)
LCDVDD:
  vias: v1(79.98,157.06)
LCDVDD_EN: length 20.3
  TOP w0.102: v1(80.32,155.66) 79.96,156.01 v2(79.86,156.01)
  L4 w0.102: v2(69.17,163.33) 70.57,161.93 72.7,161.93 78.7,155.94 79.79,155.94 v2(79.86,156.01)
  BOTTOM w0.102: v2(79.86,156.01) 79.86,154.78 R5202.2 80.62,154.02 U5201.1 ; v2(69.17,163.33) 68.21,162.37 D5201.3
LCDVDD_LCD:
  vias: v1(80.27,165.88) v1(80.54,168.22) v1(82.32,166.61) v3(81.19,175.22) v3(82.06,175.22)
LDO1_CAP: length 4.8
  BOTTOM w0.203: v1(187.79,18.91) 187.61,18.73 187.61,18.24 187.06,17.69 HDA27.27
  BOTTOM w0.254: v1(187.79,18.91) 187.97,18.91 188.54,18.35 C2702.2 188.86,18.89 188.76,18.99 R2711.2
LDO2_CAP: length 4.5
  BOTTOM w0.203: 186.21,11.33 185.6,11.94 185.3,11.94 184.62,12.63 HDA27.39
  BOTTOM w0.254: 186.21,11.33 v1(186.77,11.33) 187.54,11.33 C2712.2
LDO3_CAP: length 4.1
  BOTTOM w0.203: 178.65,16.49 HDA27.7
  BOTTOM w0.254: C2718.1 177.26,17.7 v1(177.65,17.3) 177.91,17.05 178.09,17.05 178.65,16.49
LDO_EN: length 3.8
  TOP w0.102: U5502.21 28.64,60.3 v2(28.73,60.21)
  BOTTOM w0.102: v1(27.24,59.7) 27.4,59.54 R5502.1 28.32,59.8 v2(28.73,60.21) 28.84,60.31 R5512.2
LED0: length 1.8
  TOP w0.102: TP3003.1 49.96,172.14 49.53,171.71 LOM30.27
LED1: length 7.5
  TOP w0.102: TP3002.1 50.9,174.98 50.34,174.41 v1(50.34,174.11) 50.34,172.06 49.93,171.65 LOM30.26
LED2: length 6.8
  TOP w0.102: LOM30.25 50.33,171.61 50.65,171.94 50.65,173.16 50.99,173.49 50.99,174.73 51.34,175.09 51.34,176.9 TP3001.1
LID_CLOSE#: length 206.8
  TOP w0.102: v2(192.43,176.09) 192.15,176.09 191.96,175.9 R6109.1 ; v2(191.31,75.71) 191.83,75.18 KBC24.17
  L3 w0.102: v2(192.43,176.09) 191.71,176.8 181.9,176.8 181.14,176.05 174.46,176.05 174.21,176.3 160.75,176.3 156.72,172.27 153.12,172.27 151.07,170.22 151.07,163.16 v2(149.21,161.3)
  L4 w0.102: v2(184.73,86.33) 186.03,86.33 187.19,85.17 188.6,85.17 188.7,85.27 190.13,85.27 190.46,84.94 190.46,81.67 192.01,80.12 192.01,76.36 191.6,75.95 191.56,75.95 v2(191.31,75.71) 191.31,75.38 191.46,75.23 191.46,75.22 192.62,74.06 192.62,71.59 192.62,71.59 192.62,70.5 192.62,70.49 192.62,65.5 v2(193.58,64.54)
  BOTTOM w0.102: v2(184.73,86.33) 184.45,86.61 177.43,86.61 174.25,89.79 162.06,89.79 161.44,89.18 157.71,89.18 155.83,91.05 155.83,93.59 154.76,94.66 154.76,95.58 154.92,95.74 154.92,101.19 151.76,104.36 151.76,105.71 150.22,107.25 150.22,116.55 v1(149.59,117.18) 145.12,121.65 145.12,132.19 146.11,133.18 146.11,139.87 144.97,141.01 144.97,152.21 145.03,152.26 145.03,159.28 146.86,161.11 149.03,161.11 v2(149.21,161.3) ; D2401.K 186.04,67.11 R2421.1 185.43,65.98 186.69,64.72 193.4,64.72 v2(193.58,64.54)
LID_CLOSE#_C: length 13.9
  TOP w0.102: PWR1.3 199.6,169.65 194.04,175.21 194.04,175.94 AFTP6104.1 192.37,177.61 EC6105.1 191.58,177.59 R6109.2
LINE1-L_C: length 2.1
  BOTTOM w0.254: v1(191.43,22) 191.09,22.33 R2922.1 191.08,23.02 C2907.2
LINE1-L_R: length 3.5
  BOTTOM w0.254: v1(189.08,26.09) 189.55,26.09 190.13,25.52 C2908.2 190.8,24.41 R2921.1
LINE1_L: length 6.3
  BOTTOM w0.203: HDA27.22 184.62,19.86 184.9,20.14 186.44,20.14 186.55,20.25
  BOTTOM w0.254: C2907.1 187.83,22.04 187.83,21.52 v1(187.5,21.2) 186.55,20.25
LINE1_R: length 7.8
  BOTTOM w0.203: HDA27.21 184.22,20.06 184.41,20.26
  BOTTOM w0.254: 184.41,20.26 184.76,20.6 186.16,20.6 186.89,21.34 186.89,22.5 v1(187.54,23.15) C2908.1
LINE1_VREFO_L: length 3.3
  BOTTOM w0.203: HDA27.31 188.4,16.09 v1(188.53,16.21)
  BOTTOM w0.254: R2912.1 189.33,16.21 v1(188.53,16.21)
LINE1_VREFO_R: length 7.1
  BOTTOM w0.203: HDA27.30 188.14,16.49 188.31,16.66
  BOTTOM w0.254: v1(192.02,18.5) 191.69,18.17 R2913.1 190.99,17.3 190.35,16.66 188.31,16.66
LOM_TCT:
  vias: v1(31.05,167.77) v2(28.93,169.87) v2(28.92,168.28)
LPC_AD0: length 109.8
  TOP w0.14: KBC24.126 190.4,68.27 v2(190.61,68.48)
  L3 w0.127: v2(173.74,36.6) 173.54,36.8 173.54,37.29 174,37.75 176.37,37.75 176.92,38.3 176.92,38.3 177.63,39 177.63,39.01 178.97,40.35 181.82,40.35 183.26,41.79 183.56,42.09 192.59,42.09 v2(192.6,42.08)
  L4 w0.127: v2(190.61,68.48) 191.08,68.01 191.08,62.1 190.88,61.9 190.88,61.43 191.13,61.17 191.13,59.8 191.94,58.99 191.94,57.03 191.43,56.52 191.43,55.43 189.35,53.35 189.35,48.75 191.95,46.15 191.95,45.11 192.56,44.5 192.56,42.12 v2(192.6,42.08)
  BOTTOM w0.14: RN1806.5 136.36,62.29 135.14,61.08 135.14,60.44 136.83,58.75 136.83,52.85 149.41,40.28 163.53,40.28 163.75,40.05 168.42,40.05 168.84,39.63 169.7,39.63 170.12,39.22 170.17,39.22 v1(173.17,39.22) 173.34,39.04 173.34,37.18 173.74,36.78 v2(173.74,36.6) 173.66,36.52 RN6501.4
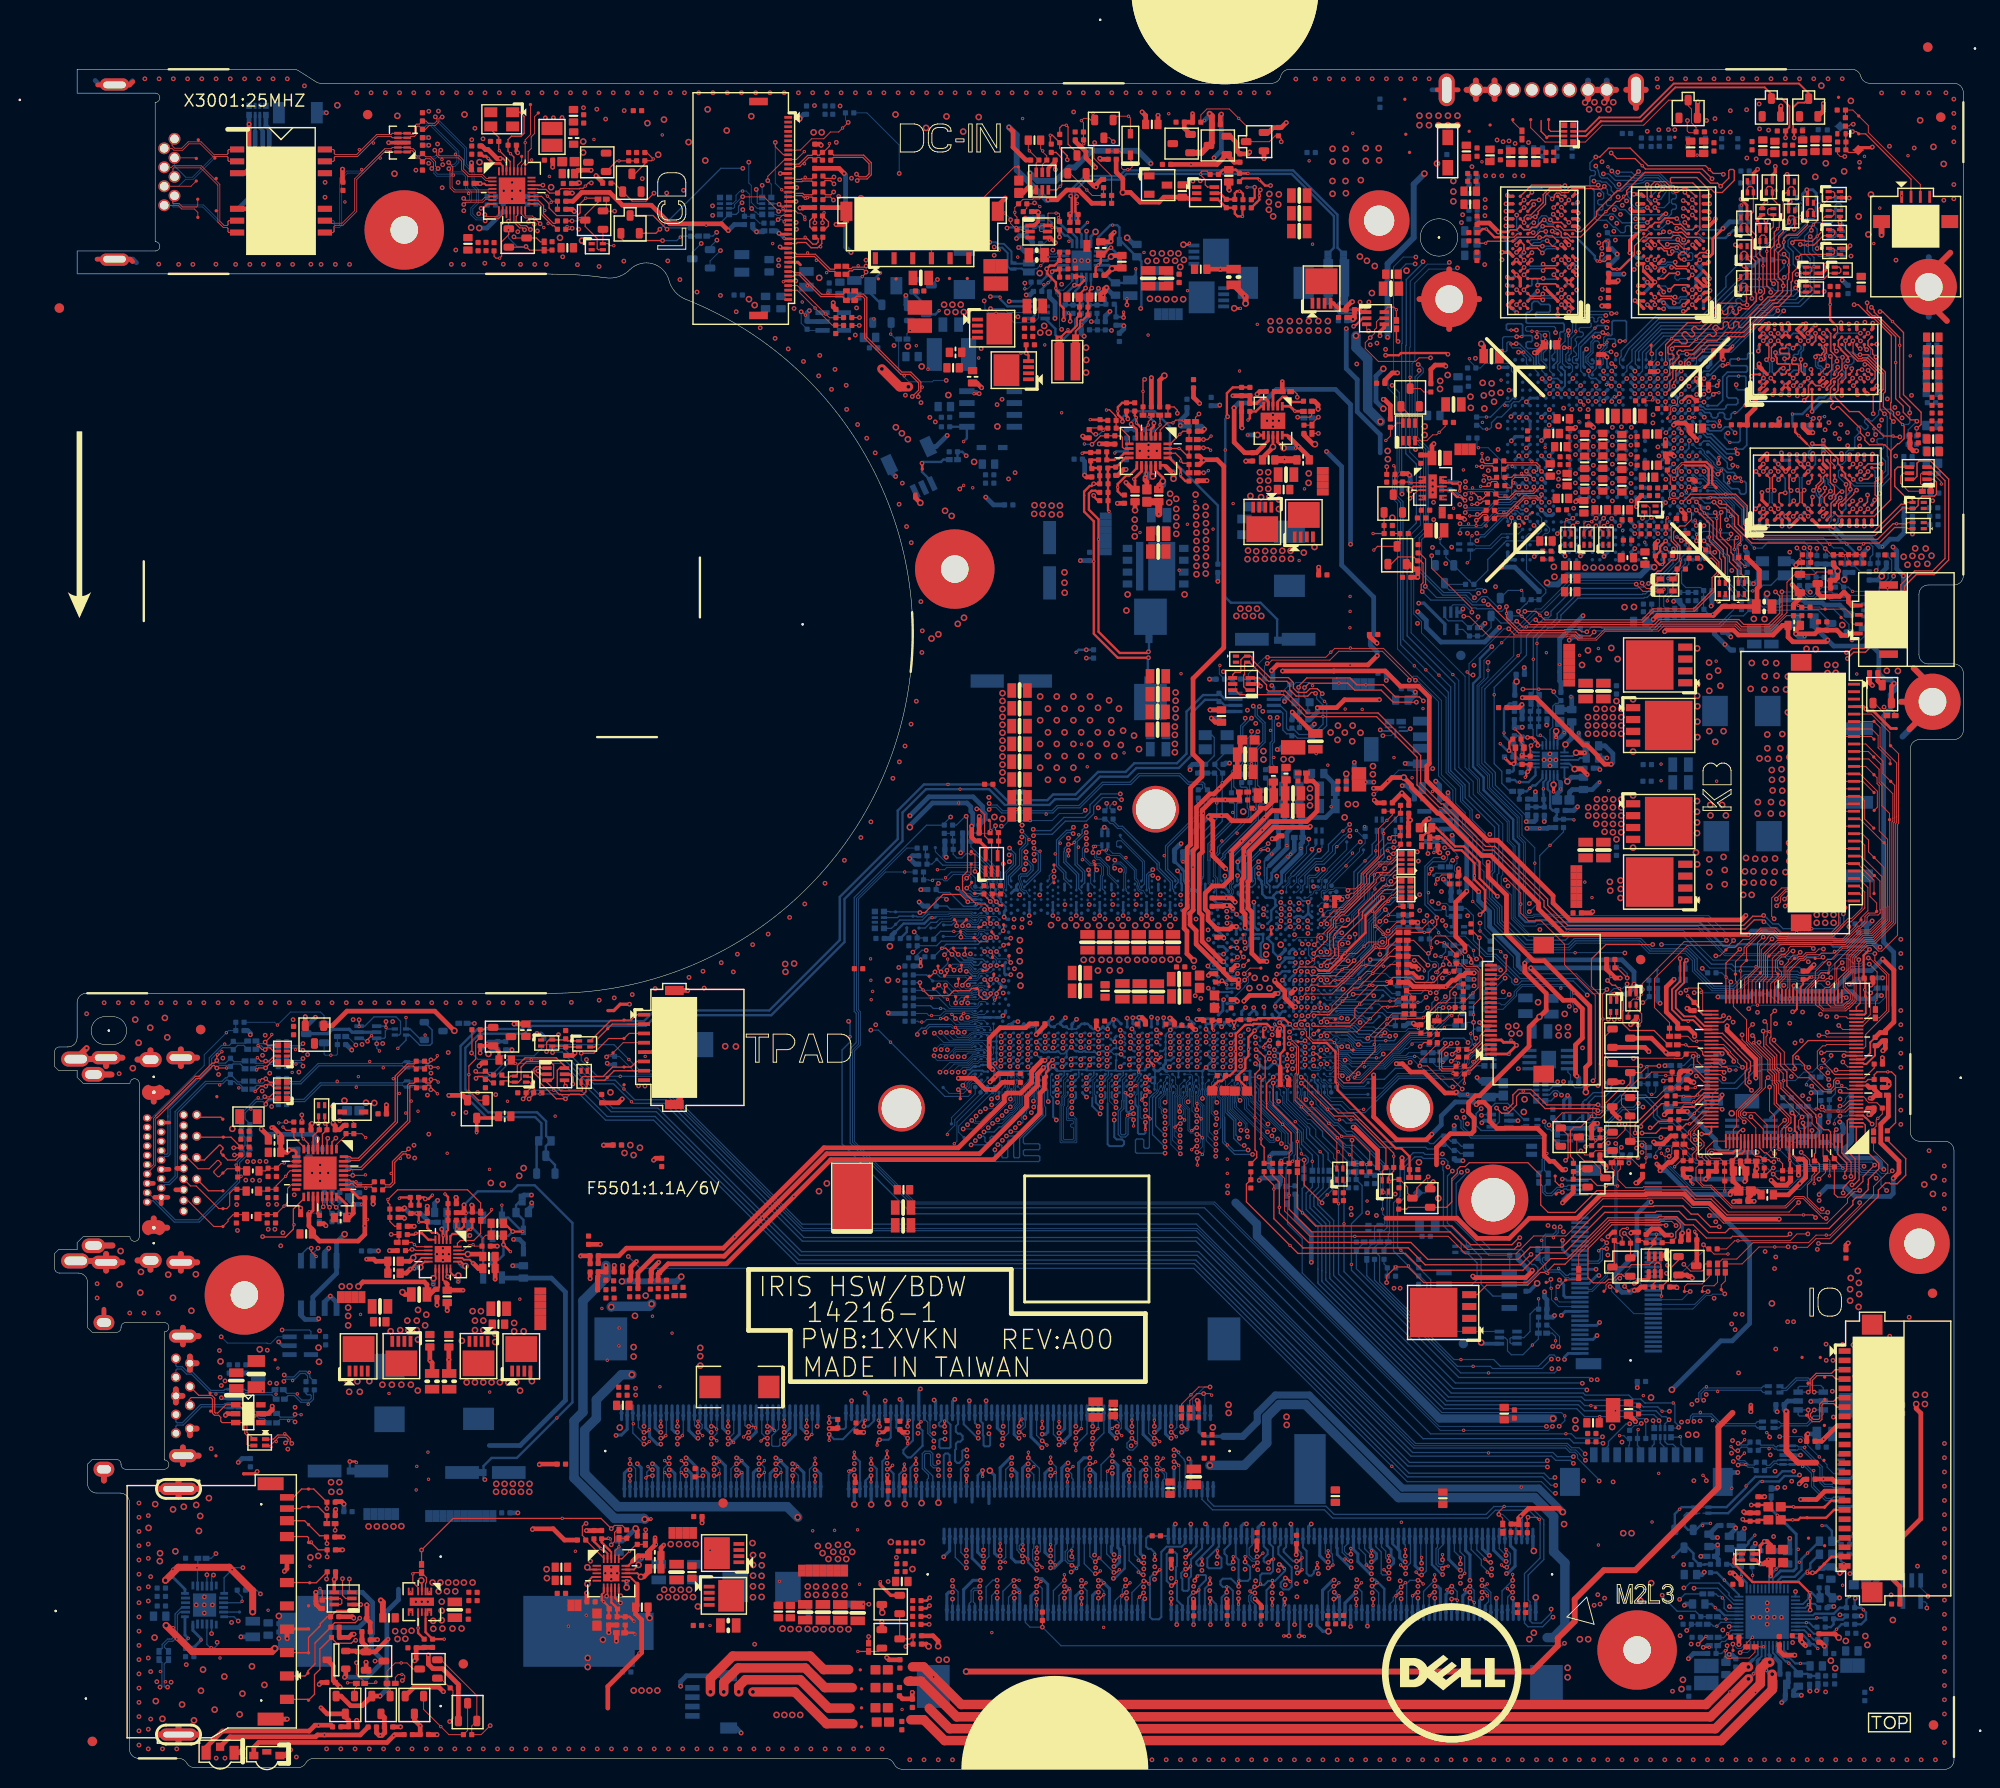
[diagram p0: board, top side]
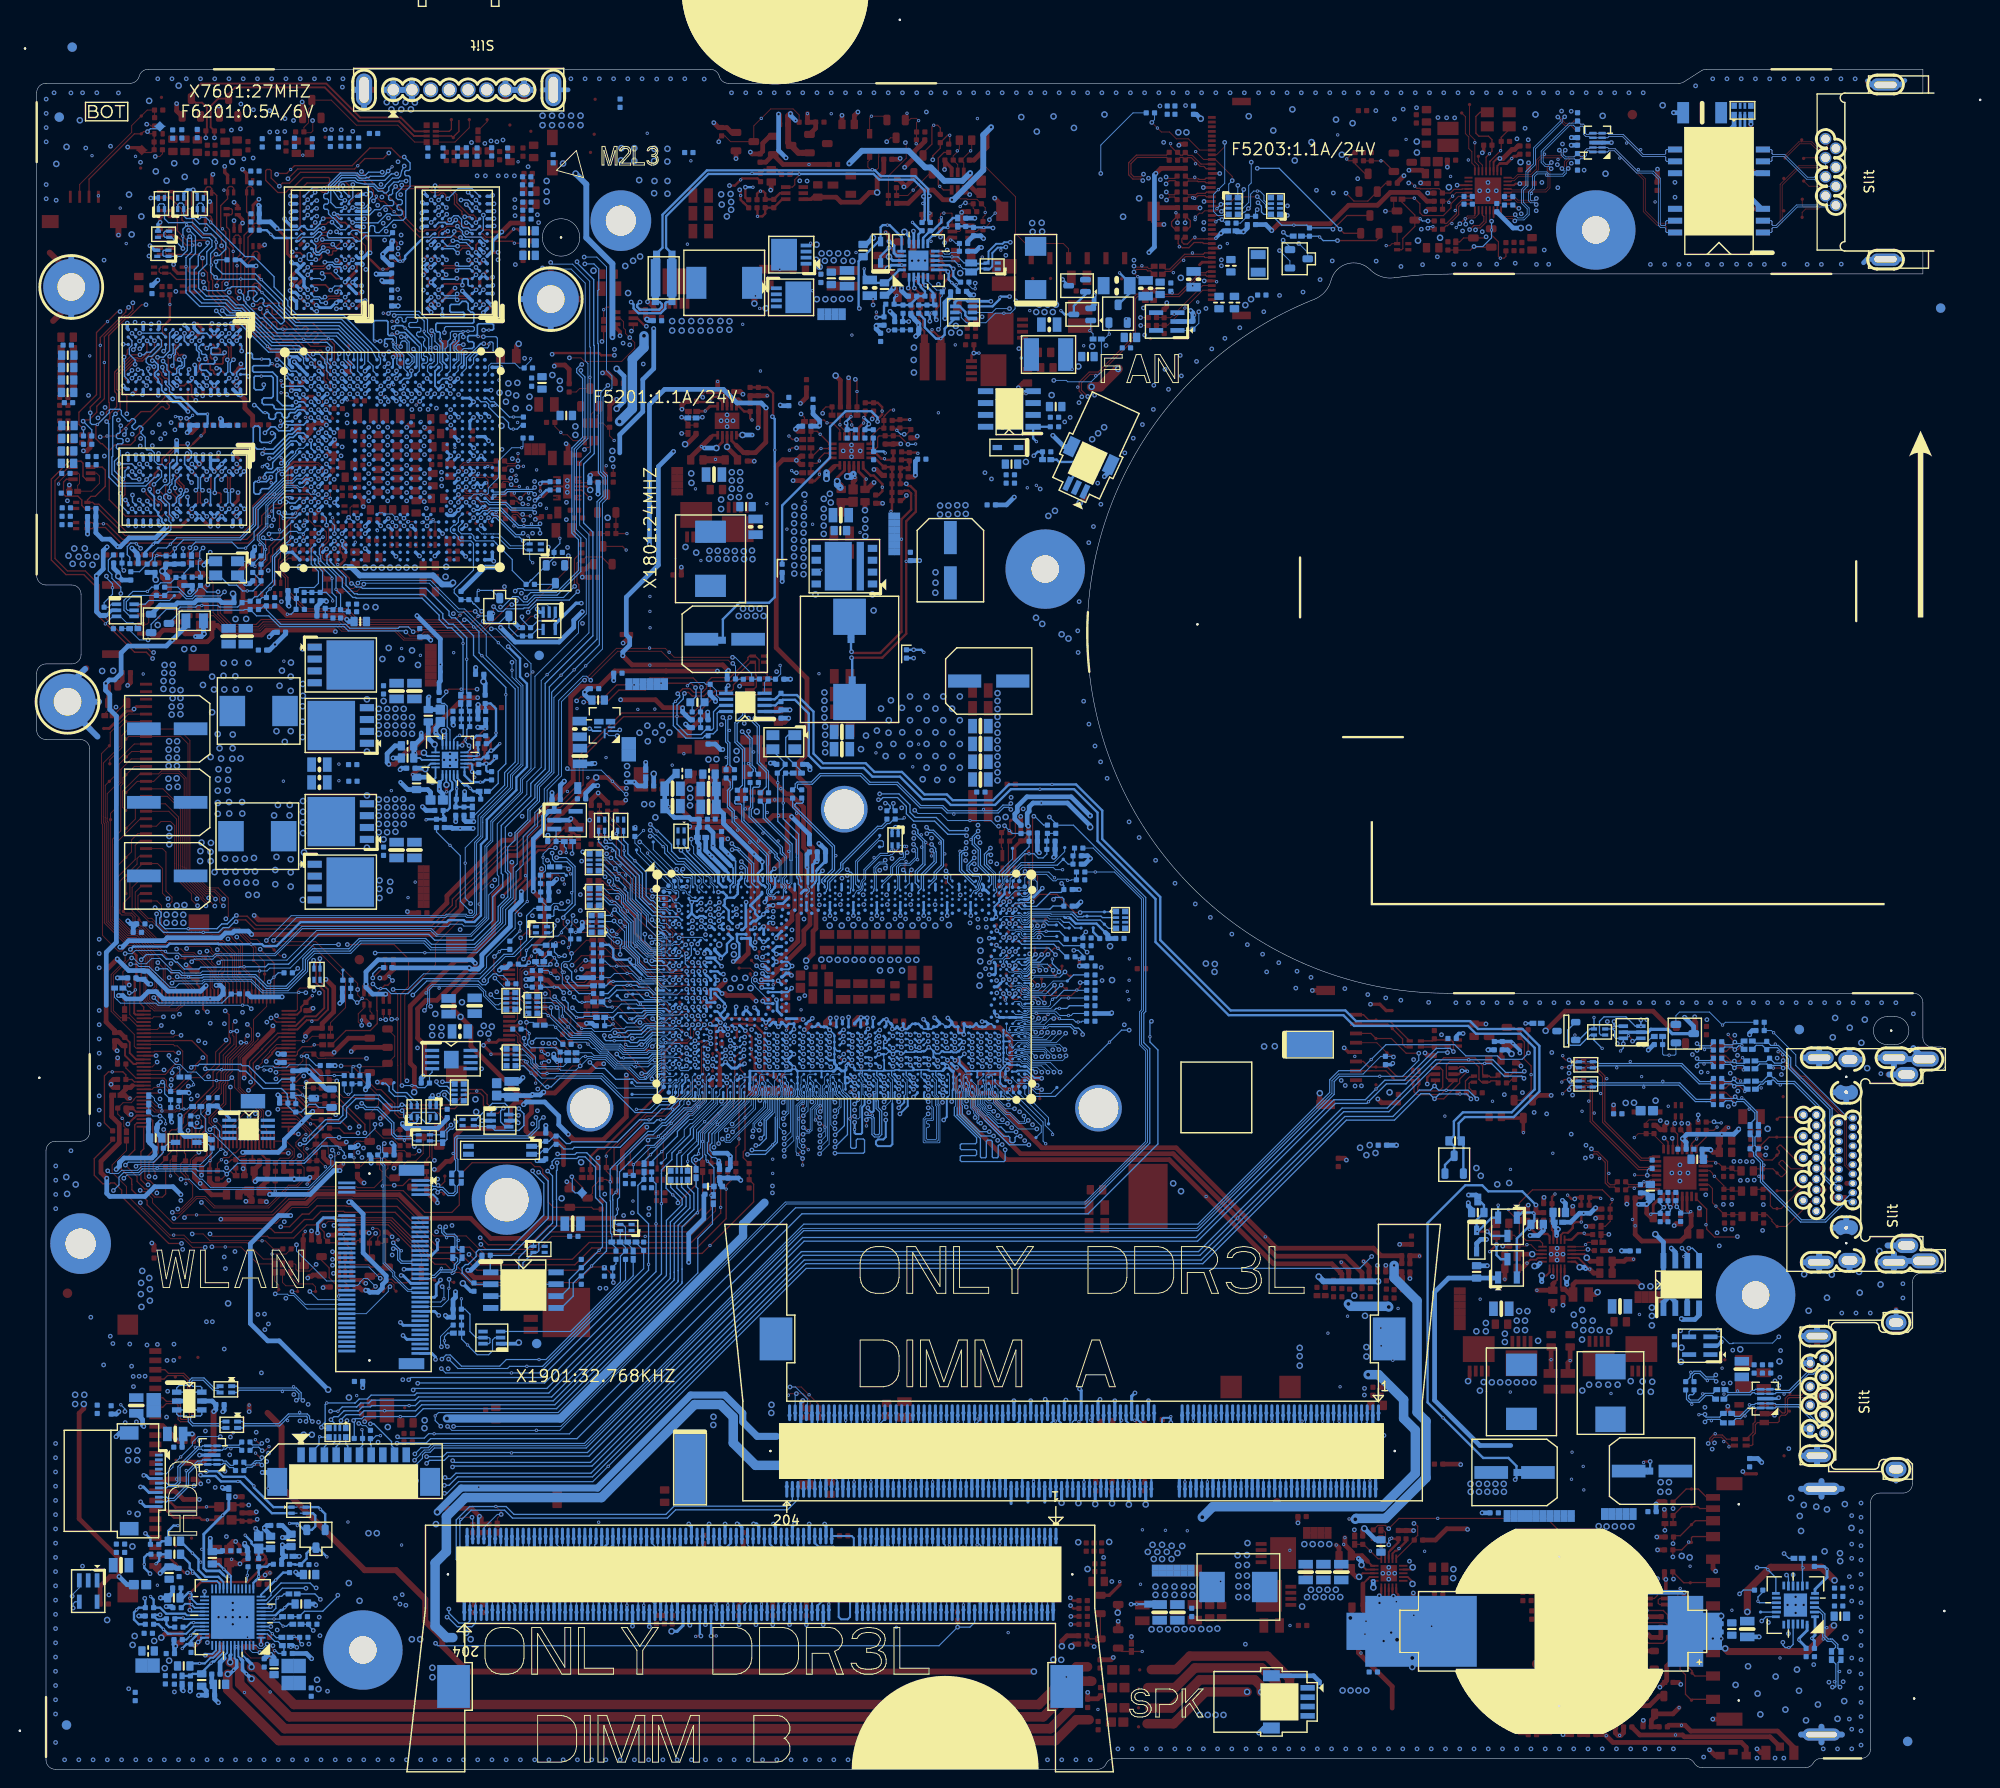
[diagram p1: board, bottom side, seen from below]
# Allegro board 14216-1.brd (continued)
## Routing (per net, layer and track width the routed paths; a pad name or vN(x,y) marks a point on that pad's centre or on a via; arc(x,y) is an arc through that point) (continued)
LPC_AD1: length 107.2
  TOP w0.14: v2(191.53,63.38) 191.53,63.97 191.73,64.17 191.73,64.86 190.78,65.81 190.78,66.93 190.8,66.94 KBC24.127
  L3 w0.127: v2(193.24,42.07) 193.24,42.11 192.82,42.52 183.46,42.52 183.1,42.17 181.66,40.73 178.81,40.73 177.25,39.17 177.25,39.16 176.76,38.68 176.76,38.68 176.21,38.13 173.85,38.13 173.14,37.42 v2(172.72,37.42)
  L4 w0.127: v2(191.53,63.38) 191.46,63.31 191.46,62.2 191.78,61.88 191.78,61.88 191.89,61.77 191.89,60.12 192.74,59.27 192.74,55.66 190.11,53.03 190.11,49.07 192.94,46.24 192.94,45.71 192.94,42.36 v2(193.24,42.07)
  BOTTOM w0.14: RN1806.7 135.21,62.33 134.3,61.42 134.3,60.09 135.99,58.4 135.99,53.2 135.99,52.38 148.93,39.44 163.18,39.44 163.69,38.93 v1(164.35,38.93) 168.35,38.93 168.49,38.8 169.35,38.8 169.77,38.38 169.83,38.38 169.83,38.38 171.31,38.38 171.94,37.75 172.39,37.75 v2(172.72,37.42) 172.27,36.98 RN6501.3
LPC_AD2: length 108.7
  TOP w0.14: KBC24.128 191.2,65.99 192.19,65 192.19,63.48 v2(192.18,63.46)
  L3 w0.127: v2(171.64,37.32) 171.72,37.4 171.78,37.4 172.27,37.88 173.06,37.88 173.69,38.51 176.05,38.51 176.6,39.06 176.6,39.06 176.86,39.32 176.86,39.32 178.65,41.11 181.51,41.11 182.94,42.55 183.3,42.9 193.07,42.9 193.87,42.11 v2(193.87,42.05)
  L4 w0.127: v2(192.18,63.46) 192.18,63.4 191.84,63.06 191.84,62.75 191.84,62.75 191.84,62.36 192.16,62.04 192.28,61.92 192.28,60.28 193.12,59.43 193.12,55.5 190.49,52.87 190.49,49.23 193.33,46.4 193.33,43.33 193.6,43.06 193.6,42.97 193.87,42.7 v2(193.87,42.05)
  BOTTOM w0.14: RN6501.2 171.77,37.19 v2(171.64,37.32) 171.64,37.41 171.1,37.96 169.65,37.96 169.6,37.96 169.18,38.38 v1(166.98,38.38) 163.65,38.38 163.01,39.02 148.76,39.02 135.57,52.21 135.57,52.33 135.57,58.23 133.88,59.91 133.88,61.67 134.56,62.34 RN1806.8
LPC_AD3: length 109.4
  TOP w0.14: v2(192.29,62.56) 192.32,62.59 192.54,62.59 193.05,63.1 193.05,66.11 192.74,66.42 KBC24.1
  L3 w0.127: v2(171.01,37.32) 171.46,37.78 171.63,37.78 172.17,38.33 v2(172.76,38.33) 172.91,38.33 176.08,41.5 181.35,41.5 182.78,42.93 183.14,43.29 193.91,43.29 v2(194.05,43.15)
  L4 w0.127: v2(194.05,43.15) 193.71,43.49 193.71,46.56 190.87,49.39 190.87,52.71 193.51,55.34 193.51,59.59 192.66,60.44 192.66,62.19 v2(192.29,62.56)
  BOTTOM w0.14: v2(171.01,37.32) 171.12,37.21 RN6501.1 ; RN1806.6 135.71,62.24 134.72,61.25 134.72,60.26 136.41,58.58 136.41,53.03 136.41,52.56 149.11,39.86 163.36,39.86 163.71,39.51 168.37,39.51 168.66,39.21 169.53,39.21 169.95,38.8 170,38.8 170,38.8 171.5,38.8 v1(171.97,38.33) v2(172.76,38.33)
LPC_FRAME#: length 109.5
  TOP w0.14: KBC24.3 191.92,69.59 191.78,69.45 191.78,66.18 192.63,65.33 192.63,63.28 192.36,63.01 192.1,63.01 191.34,62.25 v2(191.34,61.69)
  L3 w0.127: v2(170.29,37.34) 170.29,37.64 170.81,38.16 171.47,38.16 172.29,38.99 172.93,38.99 175.82,41.88 181.19,41.88 182.62,43.31 182.98,43.67 188.15,43.67 188.71,44.22 191.2,44.22 v2(192.4,45.42)
  L4 w0.127: v2(192.4,45.42) 192.4,46.25 189.73,48.91 189.73,53.19 191.47,54.93 192.32,55.78 192.32,59.15 191.51,59.96 191.51,61.52 191.34,61.69 v2(191.34,61.69)
  BOTTOM w0.14: R1801.1 133.65,62.36 133.47,62.18 133.47,59.74 135.15,58.05 135.15,53.55 135.15,52.03 148.59,38.6 162.84,38.6 163.68,37.76 v1(165.3,37.76) 169.21,37.76 169.42,37.54 169.48,37.54 170.1,37.54 v2(170.29,37.34) 170.23,37.28 R6501.1
LPC_FRAME#_DEBUG: length 2.9
  BOTTOM w0.14: v1(169.41,36.36) 169.34,36.29 R6501.2 169.34,34.66 169.66,34.33 DB1.6
LPC_LAD0_PCH: length 20.8
  TOP w0.14: v2(135.59,60.63) 133.68,62.55 v2(133.68,65.23)
  BOTTOM w0.089: CPU1.AU14 129.57,74.12 129.57,73.62 129.53,73.58 129.53,71.64 129.53,71.5 131.15,69.88 131.6,69.43 132.95,68.07 132.95,65.69
  BOTTOM w0.14: v2(135.59,60.63) 135.59,60.93 v1(136.14,61.48) 136.86,62.2 136.86,63.57 RN1806.4 ; v2(133.68,65.23) 133.28,65.23 132.95,65.56 132.95,65.69
LPC_LAD0_R: length 3.3
  BOTTOM w0.14: DB1.2 174.66,34.08 173.99,34.75 173.99,35.54 v1(173.92,35.61) 173.76,35.61 173.7,35.55 RN6501.5
LPC_LAD1_PCH: length 11.3
  BOTTOM w0.089: 135.11,65.74 133.61,67.24 133.61,68.45 v1(132.73,69.33) 130.95,71.1 130.78,71.1 130.31,71.57 130.31,72.79 CPU1.AW12
  BOTTOM w0.14: 135.11,65.74 135.21,65.64 RN1806.2
LPC_LAD1_R: length 2.7
  BOTTOM w0.14: RN6501.6 172.27,35.07 172.55,34.79 173.14,34.79 173.41,34.52 DB1.3
LPC_LAD2_PCH: length 10.3
  BOTTOM w0.14: RN1806.1 134.56,65.07 v1(134.55,65.08) 134.55,65.75 133.4,66.9 133.4,67.2 133.4,67.2 133.4,67.39 133.4,68.16 132.34,69.22 129.99,71.57 CPU1.AY12
LPC_LAD2_R: length 2
  BOTTOM w0.14: RN6501.7 171.77,34.92 172.16,34.53 DB1.4
LPC_LAD3_PCH: length 11.1
  BOTTOM w0.089: CPU1.AW11 131.12,72.73 131.12,72.21 131.34,71.99 131.34,71.2 133.74,68.8 133.93,68.61 133.93,68.52
  BOTTOM w0.14: RN1806.3 135.71,65.78 v1(135.38,66.11) 135.38,66.14 133.93,67.59 133.93,68.51 133.93,68.52
LPC_LAD3_R: length 2
  BOTTOM w0.14: DB1.5 170.91,34.6 171.12,34.81 RN6501.8
LPC_LFRAME#_PCH: length 11.8
  BOTTOM w0.089: 133.26,66.48 133.17,66.56 133.17,68.1 132.14,69.14 129.71,71.57 129.71,73.51 CPU1.AV12
  BOTTOM w0.14: 133.26,66.48 133.38,66.35 v1(133.38,65.89) 133.55,65.72 133.82,65.72 134.13,65.41 134.13,65.04 133.65,64.56 R1801.2
LPSS_GSPI0_MOSI_BBS0_R: length 19.8
  TOP w0.102: R2012.2 144,98.82 143.58,98.4 143.58,98.35 143.22,98 v2(143.22,98) 142.95,98 v1(142.62,98.33)
  L3 w0.102: v2(135.47,89) 135.47,89.51 134.79,90.19 134.79,90.78 135.22,91.21 136.9,91.21 138.41,92.71 138.59,92.71 139.06,93.18 139.06,94.26 141.76,96.97 141.76,96.98 141.89,97.11 142.93,97.11 143.21,97.39 143.21,97.4 143.35,97.54 143.35,97.87 v2(143.22,98)
  BOTTOM w0.102: v2(135.47,89) 135.42,89.05 133,89.05 132.69,88.75 CPU1.L8
LPSS_SDIO_D0_CMNHDR: length 10.3
  BOTTOM w0.089: 135.74,94.09 135.99,94.09 136.2,94.3 136.2,94.74 136.46,95 136.46,95.1
  BOTTOM w0.102: 135.74,94.09 135.66,94.09 135.51,93.93 135.51,93.35 CPU1.D3 ; v1(139.28,100.49) 139.28,100.48 139.91,99.85 R2011.2 140.2,99.15 139.61,98.56 139.61,98.25 136.46,95.1
M_A_A0: length 56.4
  TOP w0.216: v1(92.15,30.76) v2(92.15,31.43)
  L3 w0.089: v2(115.12,74.11) 114.66,73.65 114.66,69.6 114.65,69.6 114.65,68.32 114.66,68.31 114.66,67.47 114.63,67.44
  L3 w0.203: v2(92.15,31.43) 92.21,31.43 92.7,31.92 92.7,32.97 91.84,33.83 91.84,37.08 92.07,37.31 92.07,40.84 96.31,45.09 97.62,45.09 111.81,59.28 111.81,64.62 114.63,67.44
  BOTTOM w0.216: CPU1.AU36 115.41,74.41 v2(115.12,74.11) ; v2(92.15,31.43) 92.15,31.43 92.15,29.97 DM1.98
M_A_A1: length 57.6
  TOP w0.216: v1(92.69,37.2) 92.4,36.91 v2(92.4,36.7)
  L3 w0.089: v2(115.27,70.81) 114.96,70.81 114.83,70.68 114.83,69.53 114.83,69.53 114.83,68.39 114.83,68.39 114.83,68.29 114.92,68.2
  L3 w0.203: v2(92.4,36.7) 92.73,37.04 92.73,40.14 97.12,44.53 97.38,44.53 97.39,44.53 97.85,44.53 112.37,59.05 112.37,64.77 114.92,67.32 114.92,68.2
  BOTTOM w0.216: v2(92.4,36.7) 92.85,36.25 92.85,34.63 92.85,34.63 91.6,33.38 91.24,33.38 90.8,33.82 90.8,34.18 91.82,35.2 91.82,38.14 DM1.97 ; CPU1.AY37 114.65,72.42 114.65,70.46 114.78,70.34 114.93,70.34 115.27,70.68 v2(115.27,70.81)
M_A_A2: length 58.5
  TOP w0.216: v1(92.14,33.3) v2(92.14,32.7)
  L3 w0.089: v2(114.01,75.19) 114.12,75.08 114.12,69.82 114.12,69.82 114.12,68.17 114.01,68.06
  L3 w0.203: v2(92.14,32.7) 92.14,32.74 89.95,34.93 89.95,41.1 95.62,46.77 96.92,46.77 110.14,59.98 110.14,64.19 114.01,68.06
  BOTTOM w0.216: v2(92.14,32.7) 91.99,32.7 91.55,32.26 DM1.96 ; CPU1.AR38 114.38,75.57 v2(114.01,75.19)
M_A_A3: length 58
  TOP w0.216: v1(91.42,37.37) 91.25,37.2 v2(91.25,36.71)
  L3 w0.089: v2(114.98,76.03) 114.55,75.59 113.77,75.59 113.65,75.72 113.65,76.01 113.77,76.14 114.25,76.14 114.49,76.37 114.49,76.64 114.61,76.76 115.45,76.76 115.58,76.64 115.58,76.35 115.39,76.17 115.39,74.77 115.16,74.54 114.98,74.54 114.48,74.04 114.48,69.68 114.48,69.67 114.48,68.24 114.48,68.24 114.48,67.86 114.48,67.86 114.48,67.7 114.38,67.6
  L3 w0.203: 114.38,67.6 111.25,64.48 111.25,59.52 97.38,45.65 96.08,45.65 91.49,41.06 91.49,37.55 91.25,37.3 v2(91.25,36.71)
  BOTTOM w0.216: DM1.95 v2(91.25,36.71) ; CPU1.AP36 115.17,76.22 v2(114.98,76.03)
M_A_A4: length 57.2
  TOP w0.216: v1(90.91,32.67) v2(90.91,32.11)
  L3 w0.089: 113.81,68.27 113.94,68.41 113.94,69.9 113.94,73.71 v2(113.54,74.11)
  L3 w0.203: 113.81,68.27 109.58,64.04 109.58,60.21 96.69,47.32 95.39,47.32 89.39,41.33 89.39,40.87 89.39,40.87 89.39,34.69 90.91,33.18 v2(90.91,32.11)
  BOTTOM w0.216: v2(90.91,32.11) 90.35,31.55 DM1.92 ; CPU1.AU39 113.84,74.41 v2(113.54,74.11)
M_A_A5: length 57.5
  TOP w0.216: v1(91.25,34.87) v2(91.25,35.44)
  L3 w0.089: v2(114.99,75.38) 115.04,75.38 115.21,75.22 115.21,74.84 115.08,74.72 114.43,74.72 114.3,74.59 114.3,69.75 114.3,69.75 114.3,68.17 114.3,68.17 114.3,67.94 114.22,67.86
  L3 w0.203: 114.22,67.86 110.69,64.33 110.69,59.75 97.15,46.21 95.85,46.21 90.92,41.28 90.92,39.4 90.51,38.99 90.51,35.16 90.84,34.83 91.03,34.83 91.25,35.04 v2(91.25,35.44)
  BOTTOM w0.216: v2(91.25,35.44) 91.18,35.44 90.05,36.57 DM1.91 ; v2(114.99,75.38) 115.17,75.57 CPU1.AR36
M_A_A6: length 58.7
  TOP w0.216: v1(89.64,32.54) 89.23,32.12 v2(89.08,32.12)
  L3 w0.089: v2(113.54,70.82) 113.77,70.6 113.77,69.97 113.77,68.64 113.63,68.5
  L3 w0.203: v2(89.08,32.12) 90.15,32.12 90.35,32.32 90.35,32.95 88.81,34.49 88.81,38.81 88.37,39.25 88.37,41.1 95.15,47.88 96.46,47.88 109.02,60.44 109.02,63.89 113.63,68.5
  BOTTOM w0.089: CPU1.AV40 112.83,73.47 112.83,71.53 v2(113.54,70.82)
  BOTTOM w0.216: v2(89.08,32.12) 89.27,32.12 89.75,31.65 DM1.90
M_A_A7: length 58.2
  TOP w0.216: v1(89.05,34.07) v2(89.05,33.4)
  L3 w0.089: v2(113.54,72.8) 112.78,72.04 112.78,70.02 112.78,69.37 112.62,69.21
  L3 w0.203: v2(89.05,33.4) 87.88,33.4 87.11,34.17 87.11,37.37 86.51,37.97 86.51,39.7 86.22,39.99 86.22,41.32 94.46,49.56 95.76,49.56 107.34,61.14 107.34,63.46 112.62,68.73 112.62,69.21
  BOTTOM w0.216: v2(113.54,72.8) 113.55,72.8 113.55,72.81 113.73,73 113.74,73 113.84,73.11 CPU1.AW39 ; DM1.86 88.55,32.96 88.99,33.4 v2(89.05,33.4)
M_A_A8: length 56.5
  TOP w0.216: v1(87.99,34.7) 87.99,35.02 v2(88.25,35.27)
  L3 w0.089: 112.96,69.04 112.96,69.65 112.96,70.09 112.96,70.1 112.96,71.86 113.21,72.11 v2(113.54,72.11)
  L3 w0.203: 112.96,69.04 112.96,68.66 107.9,63.6 107.9,60.91 95.99,49 94.69,49 87.25,41.56 87.25,38.01 87.67,37.6 87.67,34.4 87.87,34.19 88.08,34.19 88.25,34.36 v2(88.25,35.27)
  BOTTOM w0.216: DM1.89 89.45,35.53 89.2,35.27 v2(88.25,35.27) ; CPU1.AY39 113.88,72.46 v2(113.54,72.11)
M_A_A9: length 59.4
  TOP w0.216: v2(88.25,36.71) 88.25,37.24 v1(88.12,37.37)
  L3 w0.203: v2(113.36,69.5) 113.36,68.65 108.46,63.75 108.46,60.67 96.23,48.44 94.92,48.44 87.81,41.33 87.81,39.02 88.25,38.58 v2(88.25,36.71)
  BOTTOM w0.089: CPU1.AU40 113.07,74.21 112.65,73.8 112.65,71.28
  BOTTOM w0.216: 112.65,71.28 112.65,66.91 112.86,66.7 114.2,66.7 114.41,66.92 114.41,67.21 114.2,67.42 113.61,67.42 113.36,67.68 v2(113.36,69.5) ; DM1.85 v2(88.25,36.71)
M_A_A10: length 57.5
  TOP w0.216: v2(95.21,36.71) v1(95.21,37.28)
  L3 w0.089: v2(115.98,75.89) 115.98,76.03 115.85,76.15 115.63,76.15 115.57,76.09 115.57,74.7 115.42,74.55 115.42,74.45 115.48,74.4 115.91,74.4 116.06,74.55 116.06,74.75 116.32,75.01 116.43,75.01 116.67,74.76 116.67,74.65 116.06,74.05 115.65,74.05 115.53,73.92 115.53,73.82 115.65,73.69 116.15,73.69 116.28,73.56 116.28,73.46 116.15,73.33 115.58,73.33 115.48,73.23 115.48,73.08 115.58,72.98 116.15,72.98 116.28,72.85 116.28,68.99
  L3 w0.203: 116.28,68.99 116.28,65.48 114.54,63.74 114.54,57.86 98.85,42.17 98.18,42.17 95.48,39.47 95.48,38.94 94.85,38.31 94.85,37.87 95.36,37.35 95.36,36.86 v2(95.21,36.71)
  BOTTOM w0.216: v2(95.21,36.71) 94.72,36.71 94.6,36.84 94.6,37.05 94.85,37.31 DM1.107 ; CPU1.AP35 116.06,75.89 v2(115.98,75.89)
M_A_A11: length 57.9
  TOP w0.216: v2(87.35,32.73) v1(87.35,33.3)
  L3 w0.089: 112.03,69.26 112.03,69.48 112.42,69.87 112.42,72.34 v2(111.96,72.8)
  L3 w0.203: 112.03,69.26 112.03,69.01 108.85,65.83 108.42,65.83 106.22,63.63 106.22,61.6 95.3,50.68 94,50.68 84.77,41.45 84.77,38.44 85.02,38.19 85.02,36.78 86.55,35.26 86.55,33.94 86.67,33.82 86.67,33.41 v2(87.35,32.73)
  BOTTOM w0.216: DM1.84 87.95,29.97 87.95,32.16 87.39,32.73 v2(87.35,32.73) ; v2(111.96,72.8) 112.06,72.8 CPU1.AW41
M_A_A12: length 57.2
  TOP w0.216: v2(86.57,36.71) 86.57,37.22 v1(86.72,37.37)
  L3 w0.089: v2(111.97,74.08) 112.08,74.2 113.03,74.2 113.14,74.09 113.14,73.93 113.03,73.82 112.49,73.82 112.38,73.71 112.38,73.55 112.49,73.44 113,73.44 113.12,73.31 113.12,73.18 113,73.05 112.47,73.05 112.38,72.97 112.38,72.67 112.6,72.45 112.6,69.95 112.6,69.6 112.45,69.45 112.32,69.33
  L3 w0.203: 112.32,69.33 112.32,68.85 106.78,63.31 106.78,61.37 95.53,50.12 94.23,50.12 85.66,41.55 85.66,41.08 85.66,39.76 85.95,39.47 85.95,38.37 85.58,38.01 85.58,37.04 86.06,36.56 86.42,36.56 v2(86.57,36.71)
  BOTTOM w0.216: v2(86.57,36.71) 87.06,36.71 87.65,37.3 DM1.83 ; CPU1.AU41 112.41,74.41 112.09,74.08 v2(111.97,74.08)
M_A_A13: length 57.7
  TOP w0.216: v2(115.98,75.24) v1(115.98,74.63)
  L3 w0.089: 118.2,72.99 118.32,73.11 118.9,73.11 119.01,73.21 119.01,73.36 118.9,73.46 118.15,73.46 118.04,73.57 118.04,73.71 118.15,73.82 118.9,73.82 119.01,73.92 119.01,74.07 118.9,74.17 117.46,74.17 117.36,74.28 117.36,74.42 117.46,74.53 118.4,74.53 118.52,74.66 118.52,74.84 118.03,75.34 117.51,75.34 117.38,75.21 117.38,75.02 117.25,74.89 116.8,74.89 116.56,75.12 116.56,75.6 116.52,75.65 116.3,75.65 115.98,75.33 v2(115.98,75.24)
  L3 w0.203: v2(98.81,36.71) 98.81,37.1 100.69,38.99 100.69,39.27 117.89,56.47 117.89,63.55 118.2,63.87 118.2,72.99
  BOTTOM w0.216: v2(115.98,75.24) 116.06,75.24 CPU1.AR35 ; DM1.119 98.45,37.07 v2(98.81,36.71)
M_A_A14: length 59.2
  TOP w0.216: v1(87.34,30.76) v2(87.34,31.44)
  L3 w0.089: v2(111.97,70.81) 112.24,70.53 112.24,69.99 111.74,69.49
  L3 w0.203: 111.74,69.49 111.74,69.13 108.73,66.12 108.48,66.12 108.3,66.12 105.67,63.48 105.67,61.83 95.07,51.24 93.76,51.24 84.21,41.68 84.21,38.21 84.46,37.96 84.46,36.55 85.99,35.03 85.99,33.71 86.11,33.59 86.11,32.63 87.3,31.44 v2(87.34,31.44)
  BOTTOM w0.089: 111.38,72.11 111.25,72.24 111.25,73.47 CPU1.AV42
  BOTTOM w0.216: v2(87.34,31.44) 87.28,31.44 86.75,30.91 DM1.80 ; v2(111.97,70.81) 111.96,70.81 111.38,71.39 111.38,72.11
M_A_A15: length 59.4
  TOP w0.216: v2(85.55,33.36) v1(85.55,33.94)
  L3 w0.203: v2(111.84,70.16) 111.45,69.76 111.45,69.26 108.61,66.41 108.1,66.41 105.11,63.42 105.11,62.06 94.84,51.8 93.53,51.8 83.65,41.91 83.65,41.45 83.65,37.98 83.9,37.73 83.9,35 v2(85.55,33.36)
  BOTTOM w0.089: CPU1.AU42 111.49,74.22 111.08,73.81 111.08,71.93 111,71.86
  BOTTOM w0.216: v2(85.55,33.36) 85.73,33.36 86.15,32.94 DM1.78 ; 111,71.86 111,71 v2(111.84,70.16)
M_A_B_DIMM_ODT: length 2.9
  TOP w0.356: v1(88.33,20.09) 88.33,19.75 89.45,18.63 Q1202.S
M_A_BS0: length 59.1
  TOP w0.216: v1(116.69,68.48) 116.69,69.25 v2(116.69,69.25)
  L3 w0.203: v2(116.69,69.25) 116.63,69.19 116.63,65.19 115.09,63.65 115.09,57.63 99.08,41.61 98.54,41.61 96.79,39.86 96.79,39.09 95.95,38.25 95.95,36.06 v2(95.25,35.35)
  BOTTOM w0.089: CPU1.AU35 116.22,74.22 115.98,73.98 115.98,73.83 115.8,73.66 115.8,72.26 115.62,72.08 115.62,71.84
  BOTTOM w0.216: v2(95.25,35.35) 94.77,35.35 94.65,35.23 94.65,34.5 94.77,34.37 95.71,34.37 95.84,34.5 95.84,36.88 95.45,37.28 DM1.109 ; v2(116.69,69.25) 116.69,68.13 116.57,68 116.01,68 115.89,68.13 115.89,70.86 115.62,71.13 115.62,71.84
M_A_BS1: length 58.8
  TOP w0.216: v2(116.69,69.9) 116.92,69.9 v1(117.2,69.63)
  L3 w0.089: v2(116.69,69.9) 116.97,69.9 117.09,69.78 117.09,68.99 116.98,68.88
  L3 w0.203: 116.98,68.88 116.98,64.97 115.65,63.64 115.65,57.4 99.31,41.05 98.99,41.05 98.99,41.05 98.85,41.05 98.85,41.05 98.77,41.05 97.36,39.64 97.36,38.85 96.52,38.01 96.52,35.84 96.18,35.5 96.18,35.15 96.53,34.8 96.53,32.52 96.38,32.37 96.15,32.37 95.81,32.7 v2(95.75,32.7)
  BOTTOM w0.089: CPU1.AV35 115.99,73.48 115.99,73.34 115.98,73.33 115.98,71.11 116.13,70.96 116.13,69.79 116.29,69.63 116.53,69.63 116.69,69.79 v2(116.69,69.9)
  BOTTOM w0.216: v2(95.75,32.7) 95.75,33.63 95.58,33.8 95.29,33.8 95.12,33.63 95.12,31.12 95.15,31.09 DM1.108
M_A_BS2: length 56.3
  TOP w0.216: v2(82.86,35.85) v1(82.86,35.21)
  L3 w0.203: v2(111.97,71.46) 111.16,70.65 111.16,69.38 108.48,66.7 107.77,66.7 104.55,63.48 104.55,62.3 94.61,52.35 93.3,52.35 83.09,42.15 83.09,41.68 83.09,37.75 83.35,37.49 83.35,36.29 83.05,35.99 83.01,35.99 v2(82.86,35.85)
  BOTTOM w0.216: DM1.79 86.45,37.47 84.32,35.34 83.37,35.34 v2(82.86,35.85) ; v2(111.97,71.46) 112.41,71.9 112.41,72.41 CPU1.AY41
M_A_CAS#: length 57.9
  TOP w0.216: v1(117.16,73.79) 116.84,74.11 v2(116.69,74.11)
  L3 w0.203: v2(98.81,35.44) 98.96,35.44 99.25,35.15 99.25,33.3 99.05,33.11 98.42,33.11 98.22,33.3 98.22,37.31 100.13,39.22 100.13,39.5 117.33,56.7 117.33,63.41 117.91,63.99 117.91,73.36 117.16,74.11 v2(116.69,74.11)
  BOTTOM w0.216: DM1.115 97.25,36.95 98.76,35.44 v2(98.81,35.44) ; CPU1.AU34 116.84,74.11 v2(116.69,74.11)
M_A_DIMA_CKE0: length 59.3
  TOP w0.216: v1(82.86,37.75) v2(82.86,37.12)
  L3 w0.203: v2(82.86,37.12) 82.38,37.6 82.38,42.45 93.02,53.09 93.83,53.09 93.83,53.09 94.29,53.09 103.99,62.79 103.99,63.93 107.51,67.45 108.82,67.45 110.86,69.5 110.86,71.28 110.99,71.4 111.36,71.4 111.49,71.53 111.49,72.55 111.36,72.67 110.97,72.67 110.85,72.8 110.85,73.31 110.97,73.44 111.36,73.44 111.49,73.56 111.49,74.07 111.31,74.25 110.57,74.25 v2(110.38,74.06)
  BOTTOM w0.216: v2(110.38,74.06) 110.72,74.41 CPU1.AU43 ; DM1.73 84.65,36.61 84.46,36.42 84.06,36.42 83.8,36.67 83.8,37.49 83.67,37.62 82.99,37.62 82.86,37.49 v2(82.86,37.12)
M_A_DIMA_CKE1: length 59.5
  TOP w0.216: v1(84.94,31.91) 85.06,32.02 85.46,32.02 v2(85.52,32.09)
  L3 w0.203: v2(85.52,32.09) 85.51,32.09 82.11,35.48 82.11,37.08 81.82,37.37 81.82,42.68 92.79,53.65 94.06,53.65 103.3,62.89 103.3,63.66 107.39,67.75 108.7,67.75 110.57,69.62 110.57,71.49 110.85,71.77 110.85,72.33 v2(110.39,72.79)
  BOTTOM w0.216: v2(110.39,72.79) 110.48,72.79 CPU1.AW43 ; DM1.74 84.95,31.54 85.49,32.09 v2(85.52,32.09)
M_A_DIMA_CLK_DDR0: length 62.6
  TOP w0.127: v2(115.42,70.17) 114.96,70.17 v1(114.79,70.01)
  L3 w0.089: v2(115.42,70.17) 115.24,70.17 115.02,69.96 115.02,68.47
  L3 w0.114: v2(94.06,35.14) 93.58,34.66 93.58,33.94 93.33,33.68 92.78,33.68 92.44,34.02 92.44,35.43 92.8,35.79 92.8,36.31 93.3,36.81 93.3,39.72 97.44,43.86 98.15,43.86 112.88,58.59 112.88,64.32 115.19,66.62 115.19,68.31 115.02,68.47
  BOTTOM w0.089: 114.39,71.53 114.4,71.54 114.4,73.47 CPU1.AV37
  BOTTOM w0.127: DM1.101 93.05,37.52 93.41,37.16 93.41,35.97 93.67,35.7 94.06,35.31 v2(94.06,35.14) ; v2(115.42,70.17) 115.24,69.99 114.87,69.99 114.6,69.73 114.6,68.05 114.47,67.92 114.15,67.92 114.03,68.05 114.03,70.37 114.39,70.74 114.39,71.53
M_A_DIMA_CLK_DDR1: length 61.1
  TOP w0.127: v2(115.12,72.13) 114.82,72.13 v1(114.54,72.42)
  L3 w0.114: v2(115.12,72.13) 115.12,72.2 115.47,72.56 115.73,72.56 115.84,72.45 115.84,69.35 115.71,69.23 115.71,66.07 115.62,65.98 113.63,64 113.63,58.28 98.46,43.11 98.03,43.11 98.03,43.11 97.75,43.11 94.69,40.04 94.69,39.27 94.05,38.63 94.05,37.54 94.54,37.05 94.54,34.86 94.8,34.6 95.61,34.6 95.73,34.49 95.73,34.1 95.61,33.99 95.26,33.99 95.19,33.92 95.05,33.79 95.05,32.91 94.89,32.75 94.67,32.75 94.54,32.87 v2(94.54,32.88)
  BOTTOM w0.127: v2(115.12,72.13) 115.39,72.13 115.52,72.26 CPU1.AY36 ; v2(94.54,32.88) 94.54,32.74 94.32,32.52 94.1,32.52 93.95,32.67 93.95,33.79 93.68,34.05 93.09,34.05 92.82,33.79 92.82,32.18 93.48,31.51 93.48,31.16 93.35,31.03 DM1.102
M_A_DIMA_CLK_DDR#0: length 62.8
  TOP w0.127: v2(115.42,69.52) v1(115.42,68.87)
  L3 w0.114: v2(115.42,69.52) 115.23,69.33 115.23,68.59 115.41,68.4 115.41,66.52 113.11,64.22 113.11,58.49 98.25,43.63 97.54,43.63 93.53,39.62 93.53,36.71 93.03,36.21 93.03,35.69 92.67,35.34 92.67,34.12 92.88,33.91 93.23,33.91 93.35,34.03 93.35,34.75 93.58,34.98 93.58,36.01 93.75,36.17 93.93,36.17 94.06,36.05 v2(94.06,35.94)
  BOTTOM w0.089: 114.15,71.53 114.15,71.58 114.23,71.66 114.23,73.78 114.64,74.19 CPU1.AU37
  BOTTOM w0.127: DM1.103 93.65,36.07 93.77,35.94 v2(94.06,35.94) ; 114.15,71.53 114.15,70.84 113.79,70.47 113.79,67.95 114.05,67.68 114.57,67.68 114.84,67.95 114.84,69.63 114.97,69.75 115.3,69.75 115.42,69.63 v2(115.42,69.52)
M_A_DIMA_CLK_DDR#1: length 61.2
  TOP w0.127: v1(115.68,73.18) 115.52,73.18 v2(115.12,72.78)
  L3 w0.114: v2(115.12,72.78) 115.83,72.78 116.06,72.55 116.06,69.26 115.94,69.13 115.94,65.98 115.91,65.95 113.86,63.9 113.86,58.18 98.56,42.88 97.85,42.88 94.92,39.95 94.92,39.18 94.28,38.54 94.28,37.63 94.77,37.14 94.77,34.95 94.9,34.83 95.71,34.83 95.95,34.58 95.95,34.01 95.71,33.76 95.35,33.76 95.28,33.69 95.28,32.81 v2(94.54,32.07)
  BOTTOM w0.127: v2(94.54,32.07) 94.34,32.28 94,32.28 93.71,32.57 93.71,33.68 93.58,33.81 93.19,33.81 93.06,33.68 93.06,32.28 93.95,31.39 DM1.104 ; v2(115.12,72.78) 115.44,73.11 CPU1.AW36
M_A_DIMA_CS#0: length 60.9
  TOP w0.216: v2(116.96,75.92) 117.03,75.92 117.56,75.39 v1(117.56,75.34)
  L3 w0.089: 119.19,65.38 119.19,74.42 118.1,75.52 117.37,75.52 v2(116.96,75.92)
  L3 w0.203: v2(97.66,32.77) 98.05,32.38 98.05,31.91 98.18,31.78 98.55,31.78 98.67,31.91 98.67,32.31 98.91,32.55 99.55,32.55 99.8,32.8 99.8,35.39 99.39,35.8 99.39,36.15 99.46,36.22 99.46,36.97 118.6,56.1 118.6,63.18 119.19,63.77 119.19,65.38
  BOTTOM w0.216: v2(97.66,32.77) 97.56,32.77 96.95,32.16 DM1.114 ; v2(116.96,75.92) 117.1,75.92 CPU1.AP33
M_A_DIMA_CS#1: length 62.2
  TOP w0.216: v1(118.37,76.26) 118.03,75.92 v2(117.8,75.92)
  L3 w0.089: v2(117.8,75.92) 118.17,75.92 118.3,76.04 118.3,78.77 118.42,78.9 118.72,78.9 118.85,78.77 118.85,75.02 119.37,74.5 119.37,65.56 119.53,65.4 119.53,65.29
  L3 w0.203: v2(99.95,35.92) 100.46,36.44 100.46,37.18 119.16,55.87 119.16,56.34 119.16,56.34 119.16,63.32 119.53,63.7 119.53,65.29
  BOTTOM w0.216: v2(99.95,35.92) 100.08,35.79 100.08,34.7 99.96,34.57 99.5,34.57 99.38,34.7 99.38,35.68 99.3,35.76 99.3,35.86 99.3,35.87 99.3,36.28 99.3,36.28 99.3,37.03 99.05,37.27 DM1.121 ; CPU1.AR32 118.15,75.57 v2(117.8,75.92)
M_A_DIMA_ODT0: length 22.2
  TOP w0.254: R1206.2 93.31,18.05 v2(93.62,18.36) ; v2(97.55,31.43) v1(97.55,30.8)
  L3 w0.254: v2(93.62,18.36) 91.57,18.36 90.65,19.28 90.65,21.45 90.65,21.87 90.65,21.88 90.65,21.9 91.31,22.55 91.33,22.55 91.71,22.93 92.13,22.93 92.91,22.93 93.83,23.85 93.83,26.44 97.55,30.16 v2(97.55,31.43)
  BOTTOM w0.254: DM1.116 97.55,29.97 v2(97.55,31.43)
M_A_DIMA_ODT1: length 25
  TOP w0.254: R1207.2 93.28,17.22 v2(93.59,17.52) ; v2(99.27,31.98) v1(99.27,31.36)
  L3 w0.254: v2(99.27,31.98) 99.27,31.12 94.33,26.18 94.33,23.64 93.12,22.43 91.92,22.43 91.54,22.05 91.52,22.05 91.16,21.69 91.16,21.67 91.16,21.66 91.16,19.62 91.58,19.19 93.5,19.19 94.12,18.57 94.12,18.06 v2(93.59,17.52)
  BOTTOM w0.254: DM1.120 98.75,31.46 v2(99.27,31.98)
M_A_DQ0: length 72.7
  TOP w0.14: v2(95.39,80.36) v1(94.78,80.36)
  L4 w0.127: v2(101.48,36.71) 101.04,36.71 100.65,36.33 100.65,35.88 99.77,35 98.62,35 96.44,37.18 96.44,37.22 95.38,38.28 95.38,39.42 87.4,47.41 87.4,47.63 87.61,47.85 87.61,48.01 87.38,48.24 87.2,48.24 87.01,48.06 86.83,48.06 86.65,48.24 86.65,48.42 86.84,48.6 86.84,48.78 86.66,48.96 86.48,48.96 86.29,48.78 86.11,48.78 85.93,48.96 85.93,49.14 86.12,49.32 86.12,49.5 85.94,49.68 85.76,49.68 85.57,49.5 85.39,49.5 85.21,49.67 85.21,49.85 85.4,50.04 85.4,50.22 84.64,50.97 84.64,65.88 83.8,66.73 83.8,73.81 90.06,80.07 92.22,80.07 92.56,80.41 94,80.41 94.6,79.82 95.82,79.82 95.94,79.94 95.94,80.23 95.81,80.36 v2(95.39,80.36)
  BOTTOM w0.089: v2(95.39,80.36) 95.76,80.36 96.43,79.7 98.38,79.7 CPU1.AH63
  BOTTOM w0.14: DM1.129 101.45,36.74 v2(101.48,36.71)
M_A_DQ1: length 73.2
  TOP w0.14: v2(96.37,80.36) 96.37,80.43 v1(95.99,80.8)
  L4 w0.127: v2(101.43,35.39) 101.04,35.39 100.9,35.25 100.9,33.83 100.81,33.74 100.52,33.74 100.34,33.92 100.34,34.09 99.83,34.6 98.46,34.6 96.05,37.01 96.05,37.06 94.99,38.11 94.99,39.25 84.25,49.99 84.25,65.62 83.41,66.47 83.41,73.97 89.89,80.46 92.05,80.46 92.4,80.81 95.92,80.81 v2(96.37,80.36)
  BOTTOM w0.089: CPU1.AH62 98.9,79.92 98.75,80.01 98.61,80.06 98.54,80.09 98.4,80.09 98.18,80.01 98.17,80.01 97.87,79.88 96.85,79.88 v2(96.37,80.36)
  BOTTOM w0.14: v2(101.43,35.39) 102.05,36.01 DM1.131
M_A_DQ2: length 71.7
  TOP w0.14: v2(105.65,35.16) 105.69,35.16 v1(106.15,34.7)
  L4 w0.127: v2(95.41,78.87) 94.41,77.87 93.82,77.87 93.35,77.39 91.06,77.39 86.26,72.6 86.26,68.1 87.11,67.26 87.11,52 99.21,39.9 101.85,39.9 105.18,36.57 105.18,32.91 105.31,32.78 105.94,32.78 106.07,32.91 106.07,34.74 v2(105.65,35.16)
  BOTTOM w0.089: CPU1.AK63 98.41,78.37 98.04,78.37 97.8,78.14 96.14,78.14 v2(95.41,78.87)
  BOTTOM w0.14: v2(105.65,35.16) 105.05,35.76 DM1.141
M_A_DQ3: length 72.9
  TOP w0.14: v2(104.15,32.07) 104.41,32.07 v1(104.76,32.41)
  L4 w0.127: v2(94.78,78.88) 94.78,78.84 94.29,78.35 93.75,78.35 93.19,77.79 90.85,77.79 85.87,72.82 85.87,67.83 86.72,66.99 86.72,51.83 98.69,39.86 98.69,39.79 99.63,38.84 102.35,38.84 104.79,36.4 104.79,31.44 104.33,30.99 103.97,30.99 103.71,31.25 103.71,31.87 103.9,32.07 v2(104.15,32.07)
  BOTTOM w0.089: v2(94.78,78.88) 95.7,77.96 97.88,77.96 98.1,78.18 98.86,78.18 CPU1.AK62
  BOTTOM w0.14: DM1.140 104.75,31.54 104.22,32.07 v2(104.15,32.07)
M_A_DQ4: length 73.9
  TOP w0.14: v2(97,80.39) 97,80.66 v1(97.26,80.92)
  L4 w0.127: v2(102.35,31.45) 102.25,31.45 99.49,34.21 98.3,34.21 95.65,36.85 95.65,36.89 83.86,48.69 83.86,65.43 83.01,66.28 83.01,74.14 89.73,80.85 91.89,80.85 92.24,81.2 96.19,81.2 v2(97,80.39)
  BOTTOM w0.089: CPU1.AH61 99.41,80.18 98.8,80.18 98.68,80.23 98.57,80.27 98.37,80.27 98.12,80.18 97.83,80.08 97.31,80.08 v2(97,80.39)
  BOTTOM w0.14: DM1.132 v2(102.35,31.45)
M_A_DQ5: length 75
  TOP w0.14: v1(96.37,79.4) 96.68,79.1 v2(96.68,78.89)
  L4 w0.127: v2(102.38,32.73) 101.92,33.18 101.92,36.89 101.65,37.16 97.09,37.16 95.78,38.47 95.78,39.58 88.01,47.35 88.01,48.17 85.04,51.14 85.04,66.16 84.19,67 84.19,73.64 90.22,79.67 93.33,79.67 93.58,79.42 96.16,79.42 v2(96.68,78.89)
  BOTTOM w0.089: v2(96.68,78.89) 97.08,78.5 97.66,78.5 97.9,78.74 98.09,78.85 98.33,78.92 98.58,78.92 98.7,78.87 98.76,78.84 98.87,78.84 98.99,78.9 99.03,78.92 99.23,78.92 99.36,78.87 99.41,78.84 99.56,78.84 99.56,78.85 100.01,78.85 100.03,78.83 100.24,78.83 100.44,79.03 CPU1.AH60
  BOTTOM w0.14: DM1.130 101.75,32.1 v2(102.38,32.73)
M_A_DQ6: length 72.7
  TOP w0.14: v2(105.65,36.56) 105.65,36.56 v1(105.65,37.24)
  L4 w0.089: 93.99,77.47 94.64,77.47 v2(96.05,78.89)
  L4 w0.127: 93.99,77.47 93.51,77 91.24,77 86.66,72.41 86.66,68.33 87.5,67.49 87.5,67.02 87.63,66.9 88.05,66.9 88.18,66.77 88.18,66.52 88.05,66.39 87.63,66.39 87.5,66.26 87.5,66.01 87.63,65.88 88.05,65.88 88.18,65.75 88.18,65.5 88.05,65.37 87.63,65.37 87.5,65.25 87.5,64.99 87.63,64.87 88.05,64.87 88.18,64.74 88.18,64.48 88.05,64.36 87.63,64.36 87.5,64.23 87.5,63.98 87.63,63.85 88.05,63.85 88.18,63.72 88.18,63.47 88.05,63.34 87.63,63.34 87.5,63.21 87.5,62.96 87.63,62.83 88.05,62.83 88.18,62.71 88.18,62.45 88.05,62.33 87.63,62.33 87.5,62.2 87.5,61.84 87.63,61.71 88.02,61.71 88.15,61.58 88.15,61.33 88.02,61.2 87.63,61.2 87.5,61.07 87.5,60.82 87.63,60.69 88.02,60.69 88.15,60.57 88.15,60.31 88.02,60.18 87.63,60.18 87.5,60.06 87.5,59.8 87.63,59.68 88.02,59.68 88.15,59.55 88.15,59.3 88.02,59.17 87.63,59.17 87.5,59.04 87.5,58.79 87.63,58.66 87.84,58.66 87.99,58.51 87.99,58.3 87.84,58.15 87.63,58.15 87.5,58.03 87.5,52.16 99.37,40.29 102.01,40.29 105.65,36.65 v2(105.65,36.56)
  BOTTOM w0.089: v2(96.05,78.89) 96.61,78.32 97.74,78.32 98.01,78.6 98.09,78.64 arc(98.16,78.68) 98.24,78.7 98.29,78.72 arc(98.32,78.73) 98.35,78.73 98.57,78.73 98.64,78.7 98.7,78.68 arc(98.72,78.67) 98.75,78.67 98.92,78.67 98.98,78.7 arc(98.99,78.7) 99,78.71 99.04,78.73 arc(99.07,78.74) 99.1,78.74 99.17,78.74 arc(99.19,78.74) 99.21,78.73 99.29,78.7 99.35,78.68 arc(99.37,78.67) 99.4,78.67 99.61,78.67 arc(99.68,78.65) 99.73,78.61 CPU1.AK61
  BOTTOM w0.14: DM1.143 v2(105.65,36.56)
M_A_DQ7: length 74.3
  TOP w0.14: v2(104.17,33.34) v1(104.17,33.94)
  L4 w0.127: v2(104.17,33.34) 102.95,33.34 102.85,33.43 102.85,34.87 102.98,35 104.25,35 104.38,35.12 104.38,36.26 102.19,38.45 99.47,38.45 98.3,39.62 98.3,39.69 86.32,51.67 86.32,66.79 85.48,67.64 85.48,72.98 90.69,78.19 93.03,78.19 93.64,78.79 v2(94.11,78.79)
  BOTTOM w0.089: v2(94.11,78.79) 95.12,77.79 97.95,77.79 98.17,78 99.69,78 100.25,78.56 CPU1.AK60
  BOTTOM w0.14: DM1.142 105.35,32.21 104.22,33.34 104.2,33.34 104.17,33.3 104.17,33.34 v2(104.17,33.34)
M_A_DQ8: length 72
  TOP w0.14: v2(63.05,36.07) 63.33,36.07 v1(63.61,36.35)
  L3 w0.127: v2(95.36,76.27) 95,75.91 93.93,75.91 93.53,76.3 93.53,76.42 92.95,77 87.8,77 83.63,72.83 83.63,70.35 72.84,59.55 72.84,59.08 72.96,58.96 73.51,58.96 73.64,58.83 73.64,58.58 73.51,58.45 72.96,58.45 72.84,58.32 72.84,56.53 72.68,56.38 70.72,56.38 69.82,55.48 69.82,55.3 70.18,54.94 70.18,54.76 70,54.58 69.83,54.58 69.47,54.94 69.29,54.94 69.01,54.66 69.01,54.18 69.13,54.06 69.91,54.06 70.04,53.93 70.04,53.73 69.85,53.55 69.13,53.55 69.01,53.42 69.01,52.7 65.6,49.3 65.6,49.11 63.78,47.29 63.78,46.22 63.78,38.07 62.61,36.89 62.61,36.22 62.76,36.07 v2(63.05,36.07)
  BOTTOM w0.089: v2(95.36,76.27) 96.32,77.23 98.15,77.23 98.18,77.25 98.18,77.25 98.3,77.38 CPU1.AM63
  BOTTOM w0.14: DM1.7 62.45,36.6 62.98,36.07 v2(63.05,36.07)
M_A_DQ9: length 72.5
  TOP w0.14: v2(61.55,31.43) v1(61.55,30.87)
  L3 w0.127: v2(94.84,77.03) 93.67,78.21 87.31,78.21 82.38,73.28 82.38,70.79 64.42,52.84 64.42,49.6 62.6,47.78 62.6,47.45 62.6,45.73 62.6,38.56 61.11,37.06 61.11,31.87 v2(61.55,31.43)
  BOTTOM w0.089: v2(94.84,77.03) 95.24,77.43 98.1,77.43 98.32,77.65 98.86,77.65 CPU1.AM62
  BOTTOM w0.14: DM1.4 v2(61.55,31.43)
M_A_DQ10: length 71
  TOP w0.14: v1(65.39,35.72) 65.11,35.44 v2(64.85,35.44)
  L3 w0.127: v2(64.85,35.44) 65.29,35.88 65.29,37.12 65.46,37.28 65.46,46.59 67.28,48.42 67.28,48.6 78.32,59.64 78.38,59.71 78.43,59.75 78.43,60.53 78.55,60.65 79.33,60.65 79.51,60.83 79.51,61.04 79.38,61.16 77.53,61.16 77.4,61.29 77.4,61.54 77.53,61.67 79.36,61.67 79.48,61.8 79.48,62.05 79.36,62.18 78.34,62.18 78.21,62.31 78.21,62.49 78.38,62.66 78.9,62.66 85.63,69.39 85.63,72.36 88.57,75.3 92.26,75.3 93.35,74.2 95.23,74.2 95.36,74.33 v2(95.36,74.62)
  BOTTOM w0.089: v2(95.36,74.62) 96.24,75.5 97.72,75.5 98.25,76.02 CPU1.AP63
  BOTTOM w0.14: DM1.17 65.45,35.96 64.92,35.44 v2(64.85,35.44)
M_A_DQ11: length 72.1
  TOP w0.14: v2(65.75,31.43) 65.61,31.43 v1(65.26,31.78)
  L3 w0.127: v2(96.01,74.62) 96.01,74.42 95.38,73.79 93.18,73.79 92.06,74.9 88.8,74.9 86.06,72.17 86.06,69.03 80.54,63.52 80.54,61.31 67.67,48.44 67.67,48.25 65.85,46.43 65.85,37.12 65.73,37 65.73,34.45 65.6,34.32 64.38,34.32 64.04,33.98 64.04,33.24 64.39,32.88 64.39,32.59 64.52,32.47 65.16,32.47 65.29,32.34 65.29,32.08 65.16,31.96 64.6,31.96 64.47,31.83 64.47,31.02 64.6,30.89 65.62,30.89 65.75,31.02 v2(65.75,31.43)
  BOTTOM w0.089: CPU1.AP62 99,76.02 98.71,75.74 98.21,75.74 97.77,75.3 96.69,75.3 v2(96.01,74.62)
  BOTTOM w0.14: DM1.18 v2(65.75,31.43)
M_A_DQ12: length 73.6
  TOP w0.14: v2(61.55,32.7) v1(61.55,33.26)
  L3 w0.127: v2(61.55,32.7) 61.55,36.95 62.99,38.39 62.99,45.9 62.99,47.61 64.82,49.44 64.82,51.59 65.27,52.04 65.45,52.04 65.63,51.86 65.81,51.86 65.99,52.04 65.99,52.22 65.81,52.4 65.81,52.58 71.31,58.08 71.73,58.08 72.02,58.37 72.02,59.87 82.82,70.67 82.82,73.14 87.48,77.8 93.43,77.8 v2(94.2,77.03)
  BOTTOM w0.089: CPU1.AM61 99.23,77.83 98.24,77.83 98.03,77.61 94.77,77.61 v2(94.2,77.03)
  BOTTOM w0.14: v2(61.55,32.7) 61.62,32.7 62.15,32.18 DM1.6
M_A_DQ13: length 74.2
  TOP w0.14: v2(63.05,34.8) 63.33,34.8 v1(63.61,35.08)
  L3 w0.127: v2(94.08,76.38) 93.97,76.49 93.97,76.57 93.15,77.39 87.64,77.39 83.23,72.98 83.23,70.52 72.42,59.72 72.42,58.22 71.89,57.69 71.47,57.69 67.83,54.04 67.83,53.65 67.95,53.52 68.49,53.52 68.61,53.39 68.61,53.14 68.49,53.01 67.95,53.01 67.83,52.89 67.83,52.08 65.21,49.46 65.21,49.27 63.39,47.45 63.39,46.06 63.39,38.23 62.21,37.06 62.21,35.64 v2(63.05,34.8)
  BOTTOM w0.089: CPU1.AM60 100.44,76.6 100.24,76.4 99.99,76.4 99.97,76.41 99.41,76.41 99.36,76.43 99.23,76.49 99.03,76.49 98.99,76.47 98.87,76.41 98.76,76.41 98.7,76.43 98.58,76.49 98.21,76.49 97.57,75.85 94.45,75.85 94.08,76.22 v2(94.08,76.38)
  BOTTOM w0.14: DM1.5 61.85,36 62.86,34.99 62.87,34.99 v2(63.05,34.8)
M_A_DQ14: length 72
  TOP w0.14: v2(64.85,36.71) v1(64.85,37.27)
  L3 w0.127: v2(94.71,74.62) 93.5,74.62 92.43,75.69 88.39,75.69 85.23,72.53 85.23,70.06 77.51,62.33 76.74,61.57 76.74,61.39 78.03,60.1 78.03,59.92 77.85,59.74 77.67,59.74 76.38,61.03 76.2,61.03 76.02,60.85 76.02,60.67 77.32,59.38 77.32,59.2 77.14,59.02 76.96,59.02 75.7,60.28 75.52,60.28 75.29,60.05 75.29,59.87 76.39,58.78 76.39,58.27 75.12,57 75.12,57 66.89,48.77 66.89,48.58 65.06,46.76 65.06,37.44 64.85,37.23 v2(64.85,36.71)
  BOTTOM w0.089: v2(94.71,74.62) 95.77,75.68 97.65,75.68 98.28,76.31 98.52,76.31 arc(98.54,76.31) 98.56,76.3 98.64,76.27 98.7,76.25 arc(98.72,76.24) 98.75,76.24 98.92,76.24 98.98,76.27 arc(98.99,76.27) 99,76.28 99.04,76.3 arc(99.07,76.31) 99.1,76.31 99.17,76.31 arc(99.19,76.31) 99.21,76.3 99.29,76.27 99.35,76.25 arc(99.37,76.24) 99.4,76.24 99.42,76.24 arc(99.56,76.21) 99.68,76.13 CPU1.AP61
  BOTTOM w0.14: DM1.15 v2(64.85,36.71)
M_A_DQ15: length 72.8
  TOP w0.14: v2(65.75,32.7) 65.61,32.7 v1(65.26,33.05)
  L3 w0.127: v2(96.66,74.62) 96.25,74.21 96.25,74.2 95.44,73.39 93.01,73.39 91.9,74.5 88.96,74.5 86.48,72.02 86.48,68.89 80.93,63.34 80.93,61.14 68.07,48.28 68.07,48.09 66.24,46.27 66.24,36.95 66.12,36.83 66.12,34.45 66.25,34.32 66.58,34.32 66.71,34.19 66.71,30.89 66.58,30.76 66.32,30.76 66.19,30.89 66.19,32.26 v2(65.75,32.7)
  BOTTOM w0.089: v2(96.66,74.62) 97.16,75.12 97.85,75.12 98.29,75.56 98.79,75.56 98.96,75.73 99.98,75.73 100.27,76.02 CPU1.AP60
  BOTTOM w0.14: v2(65.75,32.7) 65.65,32.7 65.15,32.2 DM1.16
M_A_DQ16: length 69.3
  TOP w0.14: v2(109.25,34.8) v1(109.25,34.11)
  L4 w0.089: v2(101.22,75.89) 101.22,75.81 101.63,75.41 101.63,75.08 101.39,74.85
  L4 w0.127: 101.39,74.85 100.83,74.28 99.88,74.28 99.44,73.84 99.44,72.9 95.47,68.93 95.47,68.61 92.95,66.09 92.95,54.54 92.82,54.42 92.08,54.42 91.96,54.29 91.96,54.03 92.08,53.91 92.82,53.91 92.95,53.78 92.95,53.53 92.82,53.4 92.41,53.4 92.26,53.25 92.26,53.04 92.41,52.89 92.82,52.89 92.95,52.76 92.95,51.7 100.84,43.81 103.17,43.81 109.69,37.29 109.69,31.3 109.54,31.14 109.33,31.14 109.18,31.3 109.18,34.73 v2(109.25,34.8)
  BOTTOM w0.14: DM1.159 110.45,35.92 109.33,34.8 v2(109.25,34.8) ; v2(101.22,75.89) 101.55,76.22 CPU1.AP58
M_A_DQ17: length 68.7
  TOP w0.14: v1(109.84,36.48) 109.43,36.07 v2(109.25,36.07)
  L4 w0.127: v2(109.25,36.07) 108.77,36.55 108.77,37.65 103.01,43.41 100.67,43.41 91.35,52.74 91.35,54.85 91.47,54.98 92.47,54.98 92.55,55.07 92.55,55.48 92.47,55.57 91.46,55.57 91.35,55.68 91.35,55.99 91.46,56.11 92.4,56.11 92.55,56.26 92.55,56.6 92.45,56.7 91.45,56.7 91.35,56.81 91.35,57.1 91.45,57.21 92.45,57.21 92.55,57.31 92.55,57.62 92.45,57.72 91.44,57.72 91.35,57.81 91.35,58.14 91.44,58.23 92.44,58.23 92.55,58.34 92.55,58.62 92.44,58.73 91.43,58.73 91.35,58.82 91.35,59.16 91.43,59.24 92.43,59.24 92.55,59.37 92.55,66.25 95.25,68.95 95.25,69.02 98.17,71.94 98.17,72.71 98.28,72.82 99.05,72.82 99.22,72.99 99.22,73.22 99.1,73.35 98.28,73.35 98.15,73.48 98.15,73.73 98.28,73.86 99.1,73.86 99.22,73.98 99.22,74.72 99.4,74.9 99.66,74.9 100.06,74.5 100.74,74.5 101.23,74.99 v2(101.23,75.25)
  BOTTOM w0.14: v2(101.23,75.25) 101.55,75.57 CPU1.AR58 ; DM1.157 109.85,36.6 109.32,36.07 v2(109.25,36.07)
M_A_DQ18: length 71.2
  TOP w0.14: v1(107.04,31.78) 106.69,31.43 v2(106.55,31.43)
  L4 w0.127: v2(102.14,77.2) 101.74,77.59 101.74,78.6 101.43,78.91 101.08,78.91 97.63,75.46 91.27,75.46 87.85,72.04 87.85,68.98 89.28,67.56 89.28,51.88 99.81,41.34 102.15,41.34 106.61,36.88 106.61,35.64 107,35.25 107,31.89 v2(106.55,31.43)
  BOTTOM w0.14: v2(102.14,77.2) 102.28,77.2 CPU1.AM57 ; DM1.146 v2(106.55,31.43)
M_A_DQ19: length 72.8
  TOP w0.14: v2(106.55,32.82) v1(106.55,33.42)
  L4 w0.127: v2(102.16,78.49) 101.52,79.13 100.96,79.13 97.68,75.85 91.02,75.85 87.3,72.13 87.3,68.98 88.88,67.4 88.88,57.87 88.75,57.74 88.44,57.74 88.31,57.61 88.31,57.36 88.44,57.23 88.75,57.23 88.88,57.1 88.88,56.85 88.75,56.72 88.38,56.72 88.25,56.6 88.25,56.34 88.38,56.22 88.75,56.22 88.88,56.09 88.88,51.72 99.65,40.95 101.99,40.95 106.22,36.72 106.22,35.48 106.55,35.15 v2(106.55,32.82)
  BOTTOM w0.14: v2(102.16,78.49) 102.48,78.82 CPU1.AK57 ; DM1.148 107.15,32.36 106.69,32.82 v2(106.55,32.82)
M_A_DQ20: length 71.2
  TOP w0.14: v2(107.45,36.63) v1(107.45,37.21)
  L4 w0.127: v2(101.27,77.84) 101.18,77.84 96.84,73.5 96.28,73.5 96.15,73.63 96.15,73.95 96,74.11 95.11,74.11 94.96,73.95 94.96,73.01 95.09,72.89 95.85,72.89 96,72.74 96,72.53 95.85,72.38 95.09,72.38 94.96,72.25 94.96,70.92 94.81,70.77 94.6,70.77 94.45,70.92 94.45,74.11 94.3,74.26 94.09,74.26 93.94,74.11 93.94,69.46 91.97,67.49 90.26,67.49 90.13,67.37 90.13,67.05 90.26,66.92 91.16,66.92 91.25,66.83 91.25,66.51 91.16,66.42 90.17,66.42 90.06,66.31 90.06,52.21 100.14,42.13 102.48,42.13 107.45,37.16 v2(107.45,36.63)
  BOTTOM w0.14: DM1.149 v2(107.45,36.63) ; CPU1.AL58 101.59,78.17 v2(101.27,77.84)
M_A_DQ21: length 72.2
  TOP w0.14: v2(107.45,35.36) 107.65,35.36 v1(108.06,34.95)
  L4 w0.127: v2(101.26,78.49) 97.83,75.07 91.51,75.07 91.38,74.94 91.38,74.53 91.51,74.4 93.34,74.4 93.49,74.25 93.49,73.99 93.36,73.87 91.77,73.87 91.64,73.74 91.64,73.48 91.77,73.36 93.36,73.36 93.48,73.24 93.48,69.64 91.85,68.01 89.82,68.01 89.67,67.86 89.67,52.05 99.98,41.74 102.32,41.74 107.01,37.05 107.01,35.81 v2(107.45,35.36)
  BOTTOM w0.14: v2(101.26,78.49) 101.58,78.82 CPU1.AK58 ; DM1.147 106.85,35.87 107.36,35.36 v2(107.45,35.36)
M_A_DQ22: length 69.6
  TOP w0.14: v2(110.75,32.7) 111.14,32.7 v1(111.36,32.92)
  L4 w0.127: v2(110.75,32.7) 111.19,32.26 111.19,29.25 111.35,29.1 111.62,29.1 111.77,29.25 111.77,30.54 111.9,30.66 112.86,30.66 113.01,30.81 113.01,31.02 112.86,31.17 111.9,31.17 111.72,31.35 111.72,33.04 110.48,34.28 110.48,37.61 103.47,44.62 101.14,44.62 93.73,52.02 93.73,65.76 96.04,68.08 96.04,68.9 99.11,71.97 99.12,71.97 100.9,73.74 101.85,73.74 102.2,74.1 v2(102.2,75.23)
  BOTTOM w0.14: CPU1.AR57 102.54,75.57 v2(102.2,75.23) ; DM1.158 110.15,32.18 110.68,32.7 v2(110.75,32.7)
M_A_DQ23: length 70.9
  TOP w0.14: v2(110.75,31.43) v1(110.75,30.76)
  L4 w0.089: 101.49,74.64 101.8,74.95 101.8,75.49 101.74,75.56 101.74,76.1 v2(102.16,76.53)
  L4 w0.127: 101.49,74.64 100.92,74.07 99.97,74.07 99.65,73.75 99.65,72.81 95.68,68.84 95.68,68.27 93.34,65.93 93.34,51.86 101,44.2 103.34,44.2 110.09,37.45 110.09,30.68 109.96,30.55 108.74,30.55 108.61,30.43 108.61,30.17 108.74,30.05 109.96,30.05 110.09,29.92 110.09,29.67 109.96,29.54 108.83,29.54 108.7,29.41 108.7,29.16 108.83,29.03 110.51,29.03 110.75,29.28 v2(110.75,31.43)
  BOTTOM w0.14: CPU1.AN57 102.5,76.87 v2(102.16,76.53) ; DM1.160 v2(110.75,31.43)
M_A_DQ24: length 68.2
  TOP w0.14: v2(67.55,31.43) 67.39,31.43 v1(67.04,31.78)
  L3 w0.089: v2(103.01,75.87) 102.62,75.48 102.62,75.08 102.36,74.82
  L3 w0.127: v2(67.55,31.43) 67.1,31.87 67.1,33.52 67.47,33.88 67.47,37.57 67.67,37.77 67.67,45.85 84.17,62.35 84.17,64.49 87.55,67.87 87.95,67.87 88.08,68 88.08,68.54 88.21,68.67 88.46,68.67 88.59,68.54 88.59,68 88.72,67.87 91.77,67.87 95.92,72.02 97.1,72.02 99.58,74.5 102.04,74.5 102.36,74.82
  BOTTOM w0.14: CPU1.AP55 103.21,75.87 v2(103.01,75.87) ; DM1.24 67.55,31.37 67.55,31.37 v2(67.55,31.43)
M_A_DQ25: length 67.7
  TOP w0.14: v2(67.55,32.7) 67.39,32.7 v1(67.04,33.05)
  L3 w0.127: v2(67.55,32.7) 67.89,32.7 68.02,32.57 68.02,32.48 68.14,32.35 68.44,32.35 68.57,32.48 68.57,33.02 67.86,33.73 67.86,37.4 68.07,37.61 68.07,45.69 84.56,62.19 84.56,64.33 87.71,67.48 91.94,67.48 96.18,71.72 97.24,71.72 99.81,74.28 102.18,74.28 103.03,75.14 v2(103.03,75.21)
  BOTTOM w0.14: v2(103.03,75.21) 103.39,75.57 CPU1.AR55 ; v2(67.55,32.7) 67.43,32.7 66.95,32.22 DM1.22
M_A_DQ26: length 70.2
  TOP w0.14: v2(70.55,32.7) 70.88,32.7 v1(71.1,32.92)
  L3 w0.127: v2(70.55,32.7) 70.76,32.49 71.16,32.49 71.29,32.62 71.29,33.65 71.16,33.78 70.14,33.78 70.01,33.91 70.01,34.22 70.15,34.36 70.96,34.36 71.09,34.49 71.09,37.7 71.28,37.89 71.28,45.97 90.72,65.41 92.82,65.41 96.4,68.99 96.87,68.99 100.05,72.17 100.57,72.17 100.78,72.37 103.68,72.37 104.06,72.75 104.06,72.93 103.86,73.12 103.86,73.3 104.04,73.48 104.22,73.48 104.42,73.29 104.6,73.29 104.73,73.42 104.73,74.9 104.76,74.93 104.76,76.16 104.53,76.39 104.53,76.77 v2(104.11,77.19)
  BOTTOM w0.14: v2(104.11,77.19) 104.44,77.52 CPU1.AM54 ; DM1.36 71.15,32.16 70.61,32.7 v2(70.55,32.7)
M_A_DQ27: length 71.2
  TOP w0.14: v2(70.55,31.43) 70.88,31.43 v1(71.1,31.65)
  L3 w0.089: 104.95,74.29 104.95,74.84 104.96,74.85 104.96,76.02 105.52,76.58 105.52,78.71 105.41,78.82 105.17,79.05 104.62,79.05 v2(104.06,78.49)
  L3 w0.127: 104.95,74.29 104.95,73.24 103.86,72.16 101.88,72.16 100.01,70.29 99.55,70.29 97.39,68.12 96.09,68.12 92.98,65.02 90.88,65.02 71.67,45.81 71.67,37.73 71.48,37.54 71.48,34.42 71.98,33.92 71.98,31.32 71.85,31.2 71.43,31.2 71.2,31.43 v2(70.55,31.43)
  BOTTOM w0.14: CPU1.AK54 104.39,78.82 v2(104.06,78.49) ; DM1.34 v2(70.55,31.43)
M_A_DQ28: length 70.6
  TOP w0.14: v1(67.16,35.72) 66.89,35.44 v2(66.63,35.44)
  L3 w0.127: v2(66.63,35.44) 67.07,35.88 67.07,37.73 67.28,37.94 67.28,46.02 83.74,62.48 83.74,64.63 87.54,68.42 87.54,71.6 89.46,73.52 91.75,73.52 92.93,72.34 96.51,72.34 96.51,72.34 96.86,72.34 96.86,72.34 96.89,72.34 97.6,73.05 97.6,73.72 100.82,76.94 100.82,78.65 101.08,78.91 102.33,78.91 102.58,78.67 102.58,78.43 v2(103.16,77.84)
  BOTTOM w0.14: v2(66.63,35.44) 66.7,35.44 67.25,35.99 DM1.23 ; v2(103.16,77.84) 103.49,78.17 CPU1.AL55
M_A_DQ29: length 71.2
  TOP w0.14: v2(66.63,36.71) v1(66.63,37.27)
  L3 w0.127: v2(103.11,78.49) 102.48,79.13 100.99,79.13 100.44,78.57 100.44,77.13 100.04,76.73 99.86,76.73 99.2,77.38 99.03,77.38 98.85,77.2 98.85,77.02 99.5,76.37 99.5,76.19 99.32,76.01 99.14,76.01 98.54,76.61 98.36,76.61 98.18,76.43 98.18,76.25 98.78,75.65 98.78,75.47 96.86,73.55 96.36,73.55 95.56,72.75 93.08,72.75 91.91,73.92 89.28,73.92 87.15,71.78 87.15,68.63 83.33,64.81 83.33,62.62 66.89,46.18 66.89,38.1 66.64,37.85 66.64,36.79 66.63,36.78 v2(66.63,36.71)
  BOTTOM w0.14: CPU1.AK55 103.44,78.82 v2(103.11,78.49) ; v2(66.63,36.71) 66.65,36.73 DM1.21
M_A_DQ30: length 68.7
  TOP w0.14: v2(70.25,36.71) 70.52,36.71 v1(70.81,36.41)
  L3 w0.127: v2(104.13,75.19) 104.13,75.1 102.55,73.53 101.23,73.53 100.43,72.73 100,72.73 97.86,70.59 96.89,70.59 92.49,66.2 89.54,66.2 89.13,65.79 88.95,65.79 88.63,66.11 88.45,66.11 88.27,65.93 88.27,65.75 88.59,65.43 88.59,65.25 88.42,65.07 88.24,65.07 87.91,65.39 87.73,65.39 87.55,65.21 87.55,65.03 87.88,64.71 87.88,64.53 86.67,63.33 86.5,63.33 86.34,63.48 86.16,63.48 85.98,63.3 85.98,63.12 86.14,62.97 86.14,62.79 85.9,62.55 85.9,61.71 70.49,46.3 70.49,38.85 70.37,38.72 69.43,38.72 69.35,38.64 69.35,36.49 69.27,36.41 69.27,35.08 69.15,34.95 68.71,34.95 68.59,34.83 68.59,34.57 68.71,34.45 69.68,34.45 69.81,34.57 69.81,34.62 69.81,34.99 69.81,34.99 69.81,35.25 69.81,35.26 69.81,35.62 69.81,36.27 v2(70.25,36.71)
  BOTTOM w0.14: CPU1.AR54 104.5,75.57 v2(104.13,75.19) ; v2(70.25,36.71) DM1.33
M_A_DQ31: length 70.3
  TOP w0.14: v1(70.84,35.17) 70.56,35.44 v2(70.25,35.44)
  L3 w0.127: v2(70.25,35.44) 70.6,35.44 70.69,35.53 70.69,37.67 70.57,37.8 70.34,37.8 70.22,37.67 70.22,37.28 70.09,37.15 69.87,37.15 69.75,37.28 69.75,38.26 69.82,38.33 70.76,38.33 70.89,38.45 70.89,46.14 86.38,61.63 86.38,62.3 86.59,62.52 86.77,62.52 86.89,62.4 87.07,62.4 87.25,62.58 87.25,62.76 87.13,62.88 87.13,63.06 87.31,63.24 87.49,63.24 87.6,63.13 87.78,63.13 87.96,63.31 87.96,63.49 87.88,63.57 87.88,63.75 88.43,64.3 88.61,64.3 88.72,64.19 88.9,64.19 89.08,64.37 89.08,64.55 88.96,64.67 88.96,64.85 89.14,65.03 89.32,65.03 89.43,64.92 89.61,64.92 89.79,65.1 89.79,65.28 89.66,65.41 89.66,65.59 89.88,65.8 92.66,65.8 97.23,70.38 97.95,70.38 99.96,72.39 100.48,72.39 100.72,72.62 101.07,72.62 101.2,72.75 101.2,73.12 101.33,73.25 101.58,73.25 101.71,73.12 101.71,72.77 101.84,72.64 102.09,72.64 102.22,72.77 102.22,73.18 102.34,73.31 102.84,73.31 102.93,73.4 103.11,73.4 103.22,73.29 103.4,73.29 103.58,73.47 103.58,73.65 103.47,73.76 103.47,73.94 103.65,74.12 103.83,74.12 103.92,74.03 104.1,74.03 104.28,74.21 104.28,74.39 104.19,74.48 104.19,74.66 104.55,75.02 104.55,76.07 104.11,76.5 v2(104.11,76.54)
  BOTTOM w0.14: v2(104.11,76.54) 104.44,76.87 CPU1.AN54 ; DM1.35 70.85,35.96 70.32,35.44 v2(70.25,35.44)
M_A_DQ32: length 55.9
  TOP w0.14: v2(113.15,32.32) 113.04,32.32 v1(112.63,31.91)
  L4 w0.127: v2(99.58,70.71) 99.49,70.8 98.86,70.8 96.76,68.7 96.76,67.37 95.16,65.77 95.16,52.68 101.68,46.16 103.69,46.16 112.3,37.54 112.3,33.17 v2(113.15,32.32)
  BOTTOM w0.089: CPU1.AY58 101.53,72.31 101.53,72.1 101.46,72.03 101.46,71.61 100.56,70.71 v2(99.58,70.71)
  BOTTOM w0.14: v2(113.15,32.32) 113.08,32.32 112.55,31.79 DM1.166
M_A_DQ33: length 57
  TOP w0.14: v2(111,34.81) v1(111,34.21)
  L4 w0.127: v2(111,34.81) 111,34.32 111.12,34.19 111.76,34.19 111.89,34.32 111.89,37.4 103.52,45.76 101.52,45.76 94.77,52.51 94.77,65.69 96.54,67.46 96.54,68.79 98.88,71.13 100.23,71.13 v2(100.24,71.12)
  BOTTOM w0.089: v2(100.24,71.12) 100.72,71.12 101.28,71.68 101.28,72.12 101.35,72.19 101.35,72.78 CPU1.AW58
  BOTTOM w0.14: DM1.165 112.25,36 111.24,34.99 111.23,34.99 111.06,34.81 111.06,34.82 111,34.82 111,34.81 v2(111,34.81)
M_A_DQ34: length 56.2
  TOP w0.14: v2(115.25,36.71) v1(115.25,37.37)
  L4 w0.127: v2(115.25,36.71) 115.25,38.08 104.71,48.62 103.74,48.62 103.61,48.75 103.61,48.87 103.8,49.06 103.8,49.21 103.59,49.42 103.42,49.42 102.76,48.76 102.58,48.76 102.4,48.94 102.4,49.12 103.06,49.77 103.06,49.95 102.88,50.13 102.7,50.13 102.04,49.48 101.87,49.48 101.69,49.66 101.69,49.84 102.34,50.49 102.34,50.67 102.16,50.85 101.98,50.85 101.33,50.2 101.15,50.2 100.97,50.38 100.97,50.56 101.62,51.21 101.62,51.39 101.44,51.57 101.26,51.57 100.87,51.18 100.69,51.18 100.6,51.28 100.6,51.63 100.9,51.93 100.9,52.11 97.62,55.39 97.62,65.4 101.1,68.88 101.1,69.14 101.35,69.4 101.62,69.4 102.03,69.81 102.03,70.22 v2(101.81,70.44)
  BOTTOM w0.089: CPU1.AY56 103.04,72.44 103.04,71.31 102.66,70.94 102.66,70.77 102.41,70.51 101.88,70.51 v2(101.81,70.44)
  BOTTOM w0.14: DM1.175 v2(115.25,36.71)
M_A_DQ35: length 57.4
  TOP w0.14: v1(114.95,30.76) v2(114.95,31.43)
  L4 w0.127: v2(114.95,31.43) 115.76,32.24 115.76,33.66 115.63,33.79 114.13,33.79 114.02,33.9 114.02,34.69 114.6,35.27 114.6,38.18 104.54,48.23 102.56,48.23 100.21,50.58 100.21,52.25 97.23,55.22 97.23,65.31 100.88,68.97 v2(100.88,69.53)
  BOTTOM w0.089: v2(100.88,69.53) 101.49,69.53 102.26,70.3 102.44,70.3 102.84,70.69 102.84,70.86 103.22,71.24 103.22,72.22 103.3,72.3 103.3,72.83 CPU1.AW56
  BOTTOM w0.14: v2(114.95,31.43) DM1.174
M_A_DQ36: length 56.8
  TOP w0.14: v1(111.61,36.48) 111.21,36.07 v2(111.05,36.07)
  L4 w0.127: v2(100.23,71.75) 100.23,71.82 101.42,73.01 101.42,73.19 101.2,73.41 101.02,73.41 98.96,71.34 98.8,71.34 96.33,68.88 96.33,67.55 94.37,65.6 94.37,52.35 101.35,45.37 103.36,45.37 111.49,37.23 111.49,36.53 111.49,36.52 111.49,36.52 v2(111.05,36.07)
  BOTTOM w0.089: v2(100.23,71.75) 100.23,71.83 100.69,72.29 100.69,72.62 101.2,73.13 101.24,73.13 101.68,73.57 CPU1.AV58
  BOTTOM w0.14: DM1.163 111.65,36.6 111.12,36.07 v2(111.05,36.07)
M_A_DQ37: length 59.4
  TOP w0.14: v2(113.15,33.59) v1(113.15,34.18)
  L4 w0.127: v2(97.2,68.54) 96.98,68.32 96.98,67.29 95.55,65.86 95.55,52.84 101.84,46.55 103.85,46.55 112.69,37.71 112.69,34.04 v2(113.15,33.59)
  BOTTOM w0.089: v2(97.2,68.54) 99.18,68.54 100.18,69.54 100.2,69.54 101.98,71.33 102.41,71.33 102.65,71.57 102.65,71.91 102.58,72.38 102.58,72.56 102.61,72.65 102.64,72.74 102.64,72.84 102.56,73.01 102.56,73.19 102.62,73.34 102.64,73.39 102.64,73.45 102.64,73.73 102.64,73.77 102.65,74.07 102.65,74.21 102.45,74.41 CPU1.AU58
  BOTTOM w0.14: DM1.164 111.95,32.6 112.94,33.59 v2(113.15,33.59)
M_A_DQ38: length 58.7
  TOP w0.14: v2(115.25,35.44) 115.68,35.01 v1(115.68,34.95)
  L4 w0.127: v2(102.24,70.91) 102.24,69.72 98.02,65.49 98.02,55.55 104.55,49.01 104.87,49.01 115.75,38.14 115.75,34.58 115.35,34.18 114.6,34.18 114.47,34.31 114.47,34.59 115.25,35.37 v2(115.25,35.44)
  BOTTOM w0.089: CPU1.AV56 102.92,73.45 102.82,73.34 102.76,73.2 102.74,73.15 102.74,73.05 102.78,72.97 102.82,72.88 102.82,72.69 102.77,72.58 102.75,72.53 102.75,72.39 102.83,72.11 102.83,71.36 102.39,70.91 v2(102.24,70.91)
  BOTTOM w0.14: DM1.177 115.85,34.67 115.35,34.18 114.98,34.18 114.72,34.44 114.72,34.91 v2(115.25,35.44)
M_A_DQ39: length 59.3
  TOP w0.14: v1(114.41,33.05) 114.76,32.7 v2(114.95,32.7)
  L4 w0.127: v2(100.34,69.14) 99.73,69.14 97.62,67.04 97.62,66.01 96.84,65.23 96.84,55.06 99.81,52.08 99.81,50.39 100.16,50.05 102.37,47.83 104.38,47.83 114.2,38.01 114.2,35.44 113.62,34.86 113.62,32.83 113.75,32.7 v2(114.95,32.7)
  BOTTOM w0.089: v2(100.34,69.14) 100.36,69.13 101.35,69.13 102.34,70.12 102.52,70.12 103.02,70.62 103.02,70.79 103.39,71.16 103.39,72.15 103.48,72.23 103.48,73.65 102.92,74.21 CPU1.AU56
  BOTTOM w0.14: v2(114.95,32.7) 115.02,32.7 115.55,32.17 DM1.176
M_A_DQ40: length 60.3
  TOP w0.14: v2(72.95,31.43) 73.17,31.43 v1(73.51,31.78)
  L3 w0.127: v2(72.95,31.43) 72.8,31.28 72.5,31.28 72.37,31.41 72.37,33.39 73,34.01 73,36.02 72.89,36.13 72.89,37.27 73.2,37.58 73.2,45.28 73.75,45.84 91.65,63.73 93.3,63.73 93.48,63.92 96.41,66.84 v2(98.04,66.84)
  BOTTOM w0.089: 102.75,69.45 102.89,69.59 102.89,69.68 103.57,70.36 103.57,70.59 103.93,70.94 103.93,71.43 103.93,71.44 103.93,71.93 104.01,72.01 104.01,72.36 CPU1.AY54
  BOTTOM w0.14: DM1.42 v2(72.95,31.43) ; 102.75,69.45 100.14,66.84 v2(98.04,66.84)
M_A_DQ41: length 61.5
  TOP w0.14: v2(72.05,35.44) 72.18,35.44 v1(72.63,34.99)
  L3 w0.127: v2(98.96,67.76) 98.96,68.48 98.83,68.61 98.71,68.61 98.32,68.22 98.32,67.72 97.83,67.23 97.64,67.23 97.4,67.47 97.14,67.47 96.9,67.23 96.44,67.23 93.41,64.2 93.28,64.2 93.21,64.13 91.48,64.13 73.59,46.23 72.8,45.45 72.8,45.12 72.8,45.12 72.8,37.75 72.49,37.44 72.49,35.97 72.61,35.85 72.61,35.19 72.54,35.13 72.36,35.13 v2(72.05,35.44)
  BOTTOM w0.089: 102.67,69.71 103.37,70.42 103.37,70.64 103.75,71.02 103.75,72 103.83,72.08 103.83,72.83 CPU1.AW54
  BOTTOM w0.14: v2(72.05,35.44) 72.18,35.57 72.26,35.57 72.65,35.97 DM1.41 ; 102.67,69.71 100.72,67.76 100.23,67.76 100.09,67.62 100.09,67.21 99.96,67.09 99.65,67.09 99.53,67.21 99.53,67.62 99.39,67.76 v2(98.96,67.76)
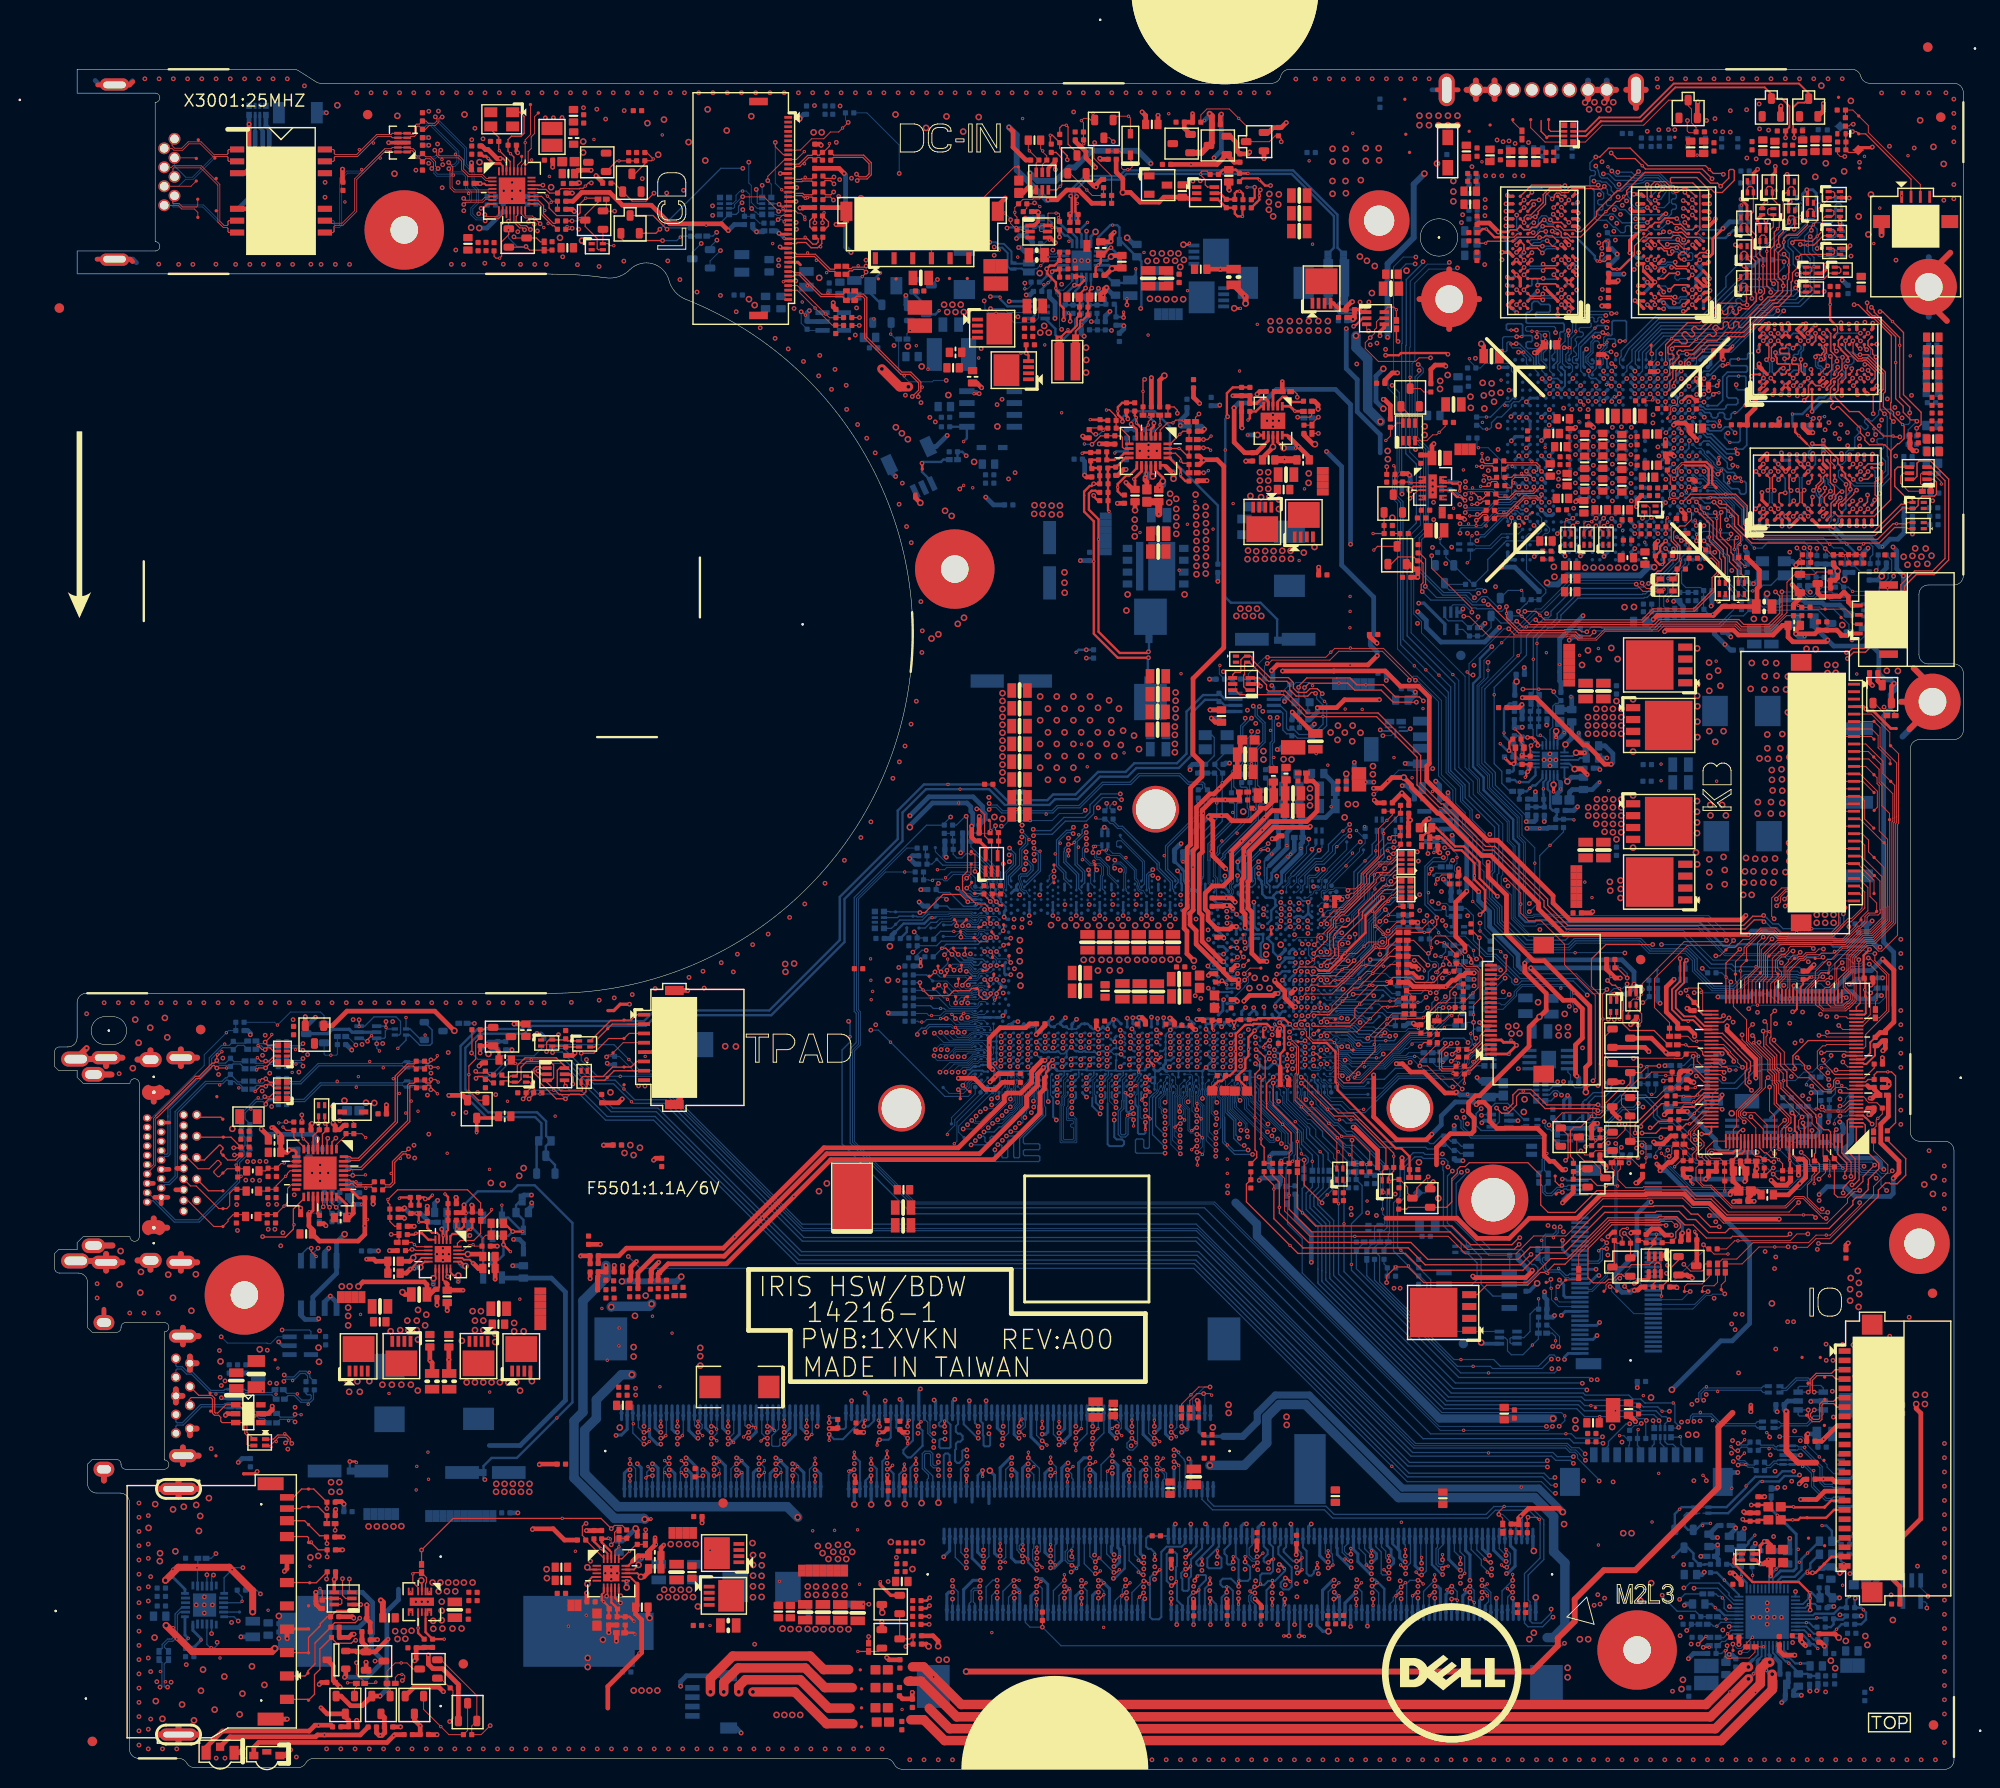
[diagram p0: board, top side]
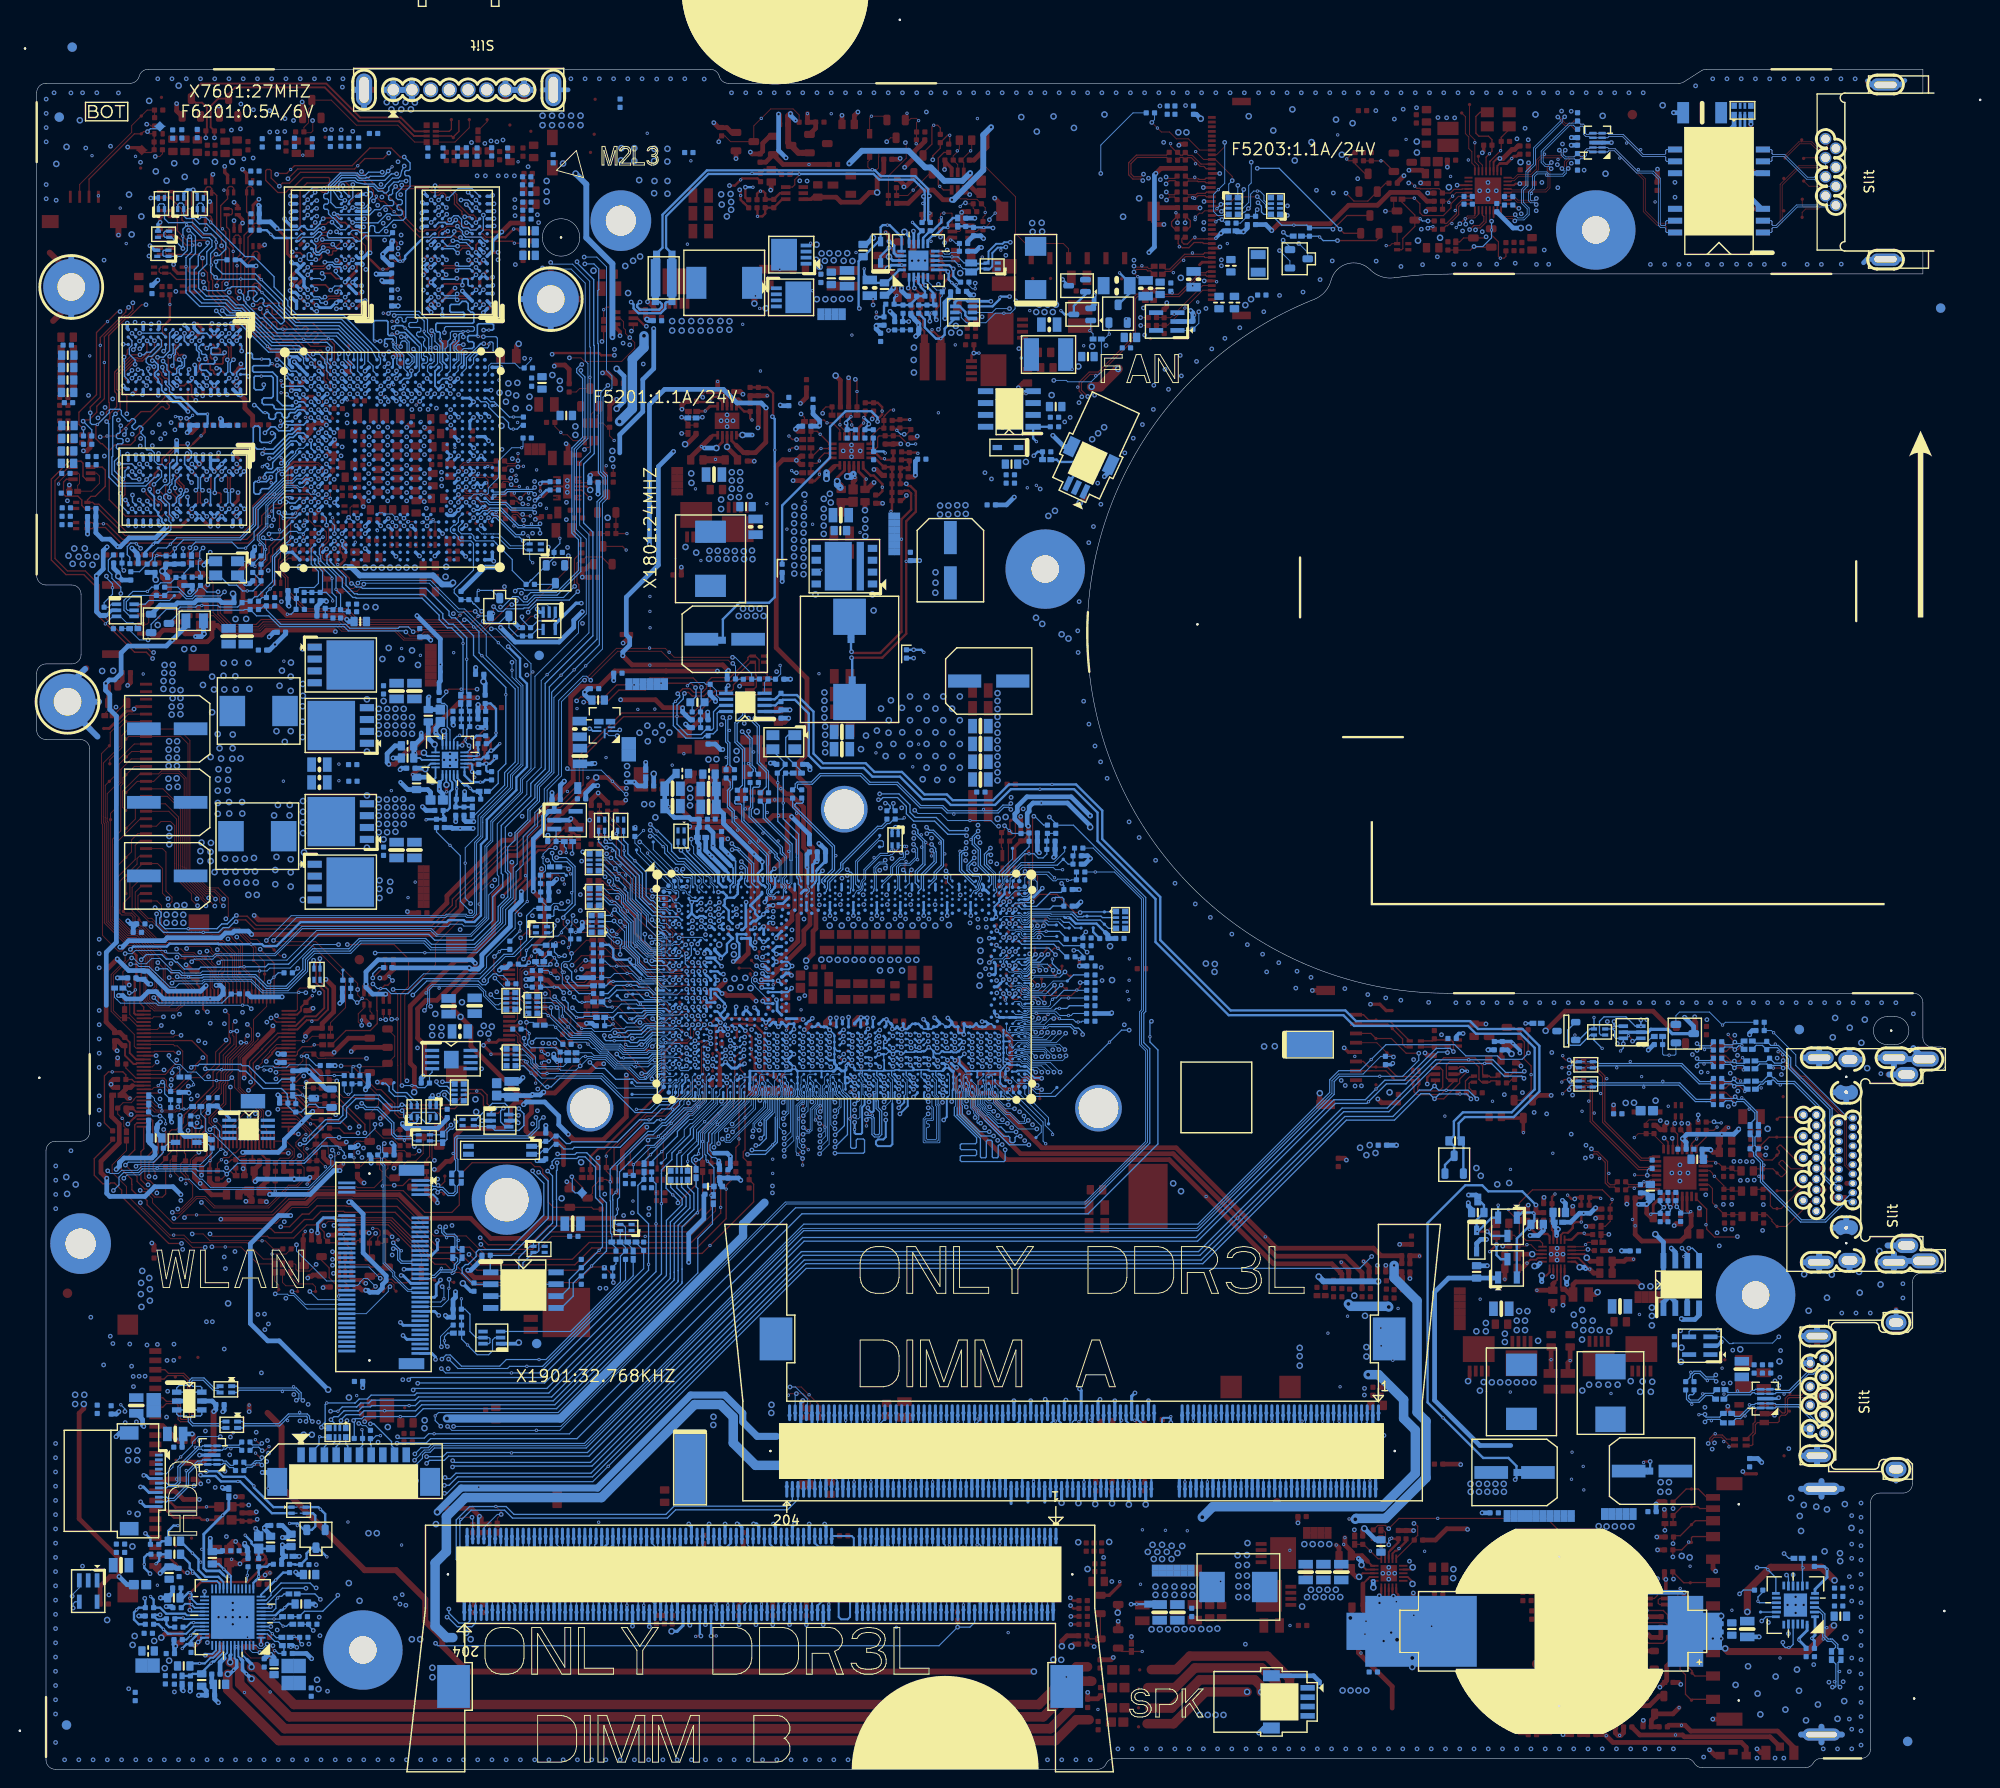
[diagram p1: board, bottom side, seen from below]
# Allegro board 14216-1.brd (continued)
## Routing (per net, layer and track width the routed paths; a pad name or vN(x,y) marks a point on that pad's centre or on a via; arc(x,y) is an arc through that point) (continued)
M_A_DQ42: length 60.8
  TOP w0.14: v1(75.93,31.78) 75.58,31.43 v2(75.35,31.43)
  L3 w0.127: v2(75.35,31.43) 75.35,30.76 75.48,30.64 75.93,30.64 76.05,30.76 76.05,33.26 75.27,34.05 75.27,44.43 90.94,60.1 92.59,60.1 96.17,63.68 96.68,63.68 98.22,65.23 98.57,65.23 101.13,67.79 v2(101.83,67.79)
  BOTTOM w0.089: 105.47,70.96 105.47,72.45 CPU1.AY52
  BOTTOM w0.14: DM1.50 v2(75.35,31.43) ; v2(101.83,67.79) 103.17,67.79 105.47,70.09 105.47,70.96
M_A_DQ43: length 63.3
  TOP w0.14: v1(75.57,35.14) 75.57,35.14 75.87,35.44 v2(76.25,35.44)
  L3 w0.127: v2(100.91,66.87) 100.52,66.87 98.66,65.01 98.31,65.01 96.77,63.46 96.51,63.46 92.76,59.71 91.11,59.71 75.66,44.26 75.66,36.03 v2(76.25,35.44)
  BOTTOM w0.089: CPU1.AW52 105.72,72.58 105.74,72.5 105.74,72.43 105.74,72.39 105.72,72.32 105.72,70.79
  BOTTOM w0.14: v2(100.91,66.87) 101.2,66.87 101.33,66.74 101.33,65.56 101.43,65.46 101.86,65.46 101.96,65.56 101.96,67.21 102.09,67.34 102.47,67.34 102.6,67.21 102.6,65.56 102.7,65.46 103.13,65.46 103.23,65.56 103.23,67.53 105.7,69.99 105.7,70.02 105.72,70.02 105.72,70.79 ; v2(76.25,35.44) 76.18,35.44 75.65,35.96 DM1.51
M_A_DQ44: length 61.7
  TOP w0.14: v2(72.05,36.71) v1(72.05,37.27)
  L3 w0.127: v2(72.05,36.71) 72.05,37.55 72.41,37.91 72.41,44.96 72.41,45.61 73.42,46.63 73.43,46.63 91.32,64.52 93.43,64.52 96.76,67.85 97.64,67.85 99.87,70.07 99.92,70.07 100.1,70.07 100.72,70.69 100.9,70.69 101.09,70.5 101.09,70.32 100.33,69.56 100.17,69.56 100.03,69.42 99.42,68.81 v2(99.42,68.22)
  BOTTOM w0.089: 102.37,69.83 102.48,69.94 102.65,69.94 103.2,70.49 103.2,70.72 103.57,71.09 103.57,72.07 103.66,72.16 103.66,73.2 CPU1.AV54
  BOTTOM w0.14: v2(99.42,68.22) 100.5,68.22 101.04,68.76 101.3,68.76 102.37,69.83 ; DM1.39 72.05,36.71 v2(72.05,36.71)
M_A_DQ45: length 62.9
  TOP w0.14: v2(72.95,32.7) 73.17,32.7 v1(73.51,33.05)
  L3 w0.127: v2(104.74,70.89) 102.94,70.89 98.45,66.4 96.52,66.4 93.46,63.34 91.81,63.34 73.92,45.45 73.91,45.45 73.59,45.12 73.59,37.42 73.28,37.11 73.28,36.29 73.39,36.18 73.39,33.14 v2(72.95,32.7)
  BOTTOM w0.089: CPU1.AU54 104.88,74.41 105.08,74.21 105.08,73.96 105.07,73.94 105.07,73.38 105.05,73.33 104.99,73.2 104.99,73 105.02,72.96 105.07,72.84 105.07,72.73 105.05,72.67 104.99,72.55 104.99,71.88 105.11,71.76 105.11,71.26 v2(104.74,70.89)
  BOTTOM w0.14: DM1.40 72.35,32.16 72.89,32.7 v2(72.95,32.7)
M_A_DQ46: length 62.6
  TOP w0.14: v1(75.93,33.05) 75.58,32.7 v2(75.35,32.7)
  L3 w0.127: v2(102.29,68.25) 101.29,68.25 98.48,65.44 98.14,65.44 96.59,63.9 95.83,63.9 92.43,60.49 90.78,60.49 74.87,44.59 74.87,33.43 74.28,32.83 74.28,32.29 74.4,32.16 74.66,32.16 74.78,32.29 74.78,32.57 74.91,32.7 v2(75.35,32.7)
  BOTTOM w0.089: CPU1.AV52 105.25,73.54 105.25,73.34 105.19,73.2 105.17,73.15 105.17,73.05 105.21,72.97 105.25,72.88 105.25,72.69 105.21,72.61 105.17,72.51 105.17,71.95 105.29,71.83 105.29,71.14 105.17,71.02
  BOTTOM w0.14: v2(102.29,68.25) 103.31,68.25 105.17,70.11 105.17,71.02 ; v2(75.35,32.7) 75.56,32.7 75.95,32.31 DM1.52
M_A_DQ47: length 64.9
  TOP w0.14: v2(76.25,36.71) 76.55,36.71 v1(76.99,36.27)
  L3 w0.127: v2(76.25,36.71) 76.05,36.9 76.05,44.1 91.27,59.31 92.92,59.31 98.4,64.8 98.75,64.8 100.28,66.32 v2(100.59,66.32)
  BOTTOM w0.089: 106.02,70.87 105.9,70.99 105.9,72.3 105.91,72.35 105.92,72.41 105.92,72.53 105.88,72.65 105.85,72.72 105.85,73.95 105.84,73.96 105.84,74.03 CPU1.AU52
  BOTTOM w0.14: DM1.53 v2(76.25,36.71) ; v2(100.59,66.32) 100.59,65.18 100.72,65.05 105.26,65.05 105.39,65.18 105.39,65.56 105.26,65.69 103.77,65.69 103.64,65.82 103.64,66.2 103.77,66.32 105.26,66.32 105.39,66.45 105.39,66.83 105.26,66.96 103.77,66.96 103.64,67.09 103.64,67.61 106.02,70 106.02,70.87
M_A_DQ48: length 69.6
  TOP w0.14: v1(81.01,35.84) 80.6,35.44 v2(80.45,35.44)
  L3 w0.089: 109.68,73.46 109.68,73.93 110.24,74.49 112.91,74.49 113.35,74.93 113.35,77.26 112.59,78.01 v2(112.59,78.5)
  L3 w0.127: 109.68,73.46 109.68,69.82 108.3,68.44 107,68.44 102.36,63.8 102.36,62.91 95.64,56.19 94.64,55.19 93.23,55.19 81.13,43.09 81.13,35.73 82.76,34.09 82.76,33.91 82.42,33.57 82.32,33.57 v2(80.45,35.44)
  BOTTOM w0.14: v2(112.59,78.5) 112.91,78.82 CPU1.AK40 ; v2(80.45,35.44) 80.53,35.44 81.05,35.96 DM1.69
M_A_DQ49: length 68.9
  TOP w0.14: v2(80.45,36.71) v1(80.45,37.37)
  L3 w0.089: v2(111.69,78.59) 111.23,78.59 111.12,78.7 111.12,79.53 111.25,79.66 112.06,79.66 112.19,79.53 112.19,78.16 113.17,77.18 113.17,75 112.83,74.66 110.16,74.66 109.47,73.97 109.47,73.42
  L3 w0.127: v2(80.45,36.71) 80.24,36.92 80.24,37.54 80.37,37.66 80.61,37.66 80.74,37.79 80.74,38.05 80.61,38.17 80.37,38.17 80.24,38.3 80.24,38.55 80.37,38.68 80.61,38.68 80.74,38.81 80.74,39.06 80.61,39.19 80.37,39.19 80.24,39.32 80.24,39.57 80.37,39.7 80.61,39.7 80.74,39.82 80.74,40.08 80.61,40.2 80.37,40.2 80.24,40.33 80.24,40.59 80.37,40.71 80.61,40.71 80.74,40.84 80.74,41.09 80.61,41.22 80.37,41.22 80.24,41.35 80.24,41.6 80.37,41.73 80.61,41.73 80.74,41.86 80.74,42.11 80.61,42.24 80.37,42.24 80.24,42.36 80.24,42.76 93.06,55.58 94.48,55.58 95.24,56.35 95.24,56.35 101.96,63.07 101.96,63.71 106.91,68.65 108.21,68.65 109.47,69.91 109.47,73.42
  BOTTOM w0.14: CPU1.AK42 111.91,78.82 v2(111.69,78.59) ; DM1.67 v2(80.45,36.71)
M_A_DQ50: length 66.8
  TOP w0.14: v2(78.05,36.71) v1(78.05,37.37)
  L3 w0.089: v2(110.64,77.21) 110.64,77.31 110.4,77.55 110.3,77.55 110.17,77.42 110.17,77.08 109.94,76.85 109.53,76.85 109.1,76.42 108.53,76.42 108.52,76.4
  L3 w0.127: 108.52,76.4 107.45,76.4 107.36,76.31 107.36,74.82 106.99,74.45 106.41,74.45 106.28,74.32 106.28,74.07 106.41,73.94 106.69,73.94 106.81,73.82 106.81,73.56 106.69,73.44 105.95,73.44 105.82,73.31 105.82,73.05 105.95,72.93 106.69,72.93 106.81,72.8 106.81,72.55 106.69,72.42 105.95,72.42 105.82,72.29 105.82,72.04 105.95,71.91 106.69,71.91 106.81,71.78 106.81,71.18 106.69,71.05 106,71.05 105.87,70.92 105.87,70.67 106,70.54 106.28,70.54 106.41,70.41 106.41,70.15 106.26,70.01 105.78,70.01 99.78,64 99.78,63.81 93.62,57.65 92.21,57.65 77.89,43.33 77.89,42.97 78.17,42.68 78.17,42.43 77.89,42.14 77.89,41.95 78.17,41.67 78.17,41.41 77.89,41.13 77.89,40.94 78.17,40.65 78.17,40.4 77.89,40.11 77.89,39.92 78.17,39.63 78.17,39.38 77.89,39.1 77.89,38.9 78.17,38.62 78.17,38.36 77.89,38.08 77.89,37.95 78.17,37.66 78.17,37.45 77.89,37.17 77.89,36.87 v2(78.05,36.71)
  BOTTOM w0.14: v2(78.05,36.71) DM1.59 ; v2(110.64,77.21) 110.95,77.52 CPU1.AM43
M_A_DQ51: length 66.4
  TOP w0.14: v2(78.05,35.44) 78.19,35.44 v1(78.59,35.84)
  L3 w0.089: v2(109.77,77.25) 109.54,77.25 108.9,76.61 106.45,76.61 106.36,76.52 106.36,75.71
  L3 w0.127: v2(78.05,35.44) 77.62,35.44 77.49,35.57 77.49,43.49 92.04,58.04 93.45,58.04 99.56,64.15 99.62,64.15 105.6,70.13 105.6,73.54 105.73,73.66 105.93,73.66 106.05,73.79 106.05,74.05 105.93,74.17 105.7,74.17 105.6,74.27 105.6,74.62 105.7,74.71 106.23,74.71 106.36,74.84 106.36,75.71
  BOTTOM w0.14: CPU1.AM45 110.22,77.5 110.22,77.28 110.11,77.17 109.85,77.17 v2(109.77,77.25) ; DM1.57 77.45,36.43 76.72,35.69 76.72,34.7 76.84,34.57 77.45,34.57 77.58,34.7 77.58,35.31 77.71,35.44 v2(78.05,35.44)
M_A_DQ52: length 66.5
  TOP w0.14: v1(77.71,31.78) 77.36,31.43 v2(77.15,31.43)
  L3 w0.089: v2(109.79,78.55) 109.35,78.55 109.22,78.42 109.22,77.18 108.83,76.79 106.38,76.79 106.2,76.61 106.1,76.61 105.39,75.9 105.39,74.71
  L3 w0.127: v2(77.15,31.43) 77.59,31.87 77.59,33.52 77.1,34.01 77.1,43.66 91.88,58.44 93.29,58.44 99.22,64.36 99.53,64.36 105.39,70.22 105.39,74.71
  BOTTOM w0.14: v2(109.79,78.55) 110.05,78.82 CPU1.AK45 ; DM1.56 v2(77.15,31.43)
M_A_DQ53: length 68.5
  TOP w0.14: v2(77.15,32.7) 77.36,32.7 v1(77.71,33.05)
  L3 w0.089: v2(110.72,78.62) 110.39,78.96 106.79,78.96 106.4,78.57 106.4,77.06 106.13,76.79 106.03,76.79 105.16,75.92 105.16,75.69
  L3 w0.127: 105.16,75.69 105.16,75.69 105.16,70.3 99.44,64.58 98.88,64.58 93.13,58.83 91.72,58.83 76.71,43.82 76.71,33.14 v2(77.15,32.7)
  BOTTOM w0.14: v2(110.72,78.62) 110.92,78.82 CPU1.AK43 ; v2(77.15,32.7) 77.22,32.7 77.75,32.17 DM1.58
M_A_DQ54: length 68.3
  TOP w0.14: v2(81.35,32.7) v1(81.35,33.3)
  L3 w0.089: 109.25,73.99 109.25,74.01 110.09,74.84 112.76,74.84 112.99,75.08 112.99,76.79 v2(112.58,77.2)
  L3 w0.127: 109.25,73.99 109.25,73.99 109.25,70 108.91,69.66 108.3,69.66 107.51,68.87 106.82,68.87 101.58,63.63 101.58,63.25 101.57,63.23 101.57,63.23 94.85,56.51 94.31,55.97 92.9,55.97 79.85,42.92 79.85,35.41 82.08,33.18 82.4,33.18 82.53,33.05 82.53,32.67 82.4,32.54 81.51,32.54 v2(81.35,32.7)
  BOTTOM w0.14: v2(81.35,32.7) 81.17,32.52 81.16,32.52 80.75,32.1 DM1.68 ; CPU1.AM40 112.9,77.52 v2(112.58,77.2)
M_A_DQ55: length 67.5
  TOP w0.14: v2(81.35,31.43) v1(81.35,30.76)
  L3 w0.089: v2(111.69,77.31) 111.69,77.17 110.93,76.41 110.58,76.41 110.24,76.07 110.24,75.26 109.94,74.96 109.61,74.96 109.61,74.96
  L3 w0.127: v2(81.35,31.43) 79.61,31.43 79.48,31.56 79.48,32.04 79.61,32.17 80.75,32.17 80.91,32.32 80.91,33.8 79.45,35.25 79.45,43.08 92.74,56.37 94.15,56.37 94.46,56.68 101.3,63.52 101.3,63.66 106.73,69.08 107.42,69.08 108.34,70 108.34,74.21 108.64,74.51 109.15,74.51 109.61,74.96
  BOTTOM w0.14: v2(111.69,77.31) 111.9,77.52 CPU1.AM42 ; DM1.70 v2(81.35,31.43)
M_A_DQ56: length 67.4
  TOP w0.14: v1(120.25,32.54) 119.86,32.93 v2(119.76,32.93)
  L4 w0.089: 106.66,71.25 106.7,71.3 106.7,71.64 106.64,71.71 106.64,74.32 107,74.69 107.04,74.69 107.38,75.03 107.38,76.01 107.98,76.61 108.11,76.61 108.34,76.85 109.94,76.85 110.19,77.1 110.19,79.23 110.08,79.33 109.49,79.33 109.4,79.24 109.4,78.88 109.39,78.87 109.39,78.03 109.27,77.92 v2(108.82,77.92)
  L4 w0.127: v2(119.76,32.93) 119.28,32.93 119.14,33.08 119.14,33.9 118.98,34.05 118.98,34.85 119.11,34.98 120.11,34.98 121.02,35.89 121.02,37.67 120.26,38.42 120.26,38.86 102.66,56.46 102.66,65.59 106.03,68.95 106.03,69.48 106.66,70.11 106.66,71.25
  BOTTOM w0.14: v2(108.82,77.92) 108.91,77.92 CPU1.AM46 ; DM1.192 120.35,32.45 119.87,32.93 v2(119.76,32.93)
M_A_DQ57: length 67.6
  TOP w0.14: v1(120.25,33.94) 119.99,34.2 v2(119.76,34.2)
  L4 w0.089: v2(108.82,78.56) 109.22,78.96 109.22,79.4 109.35,79.53 111,79.53 111.12,79.4 111.12,76.8 111,76.67 108.81,76.67 108.21,76.07 108.21,75.71 108.18,75.68 108.18,75.04 107.94,74.81 107.4,74.81 107.11,74.51 107.08,74.51 106.82,74.25 106.82,73.63 106.81,73.63 106.81,71.78 106.89,71.71 106.89,71.14
  L4 w0.127: 106.89,71.14 106.89,70.04 106.24,69.39 106.24,68.86 103.06,65.67 103.06,56.62 120.66,39.02 120.66,38.59 121.41,37.83 121.41,35.73 119.88,34.2 v2(119.76,34.2)
  BOTTOM w0.14: v2(108.82,78.56) 109.08,78.82 CPU1.AK46 ; DM1.194 120.95,32.93 120.84,33.04 120.84,33.18 119.82,34.2 v2(119.76,34.2)
M_A_DQ58: length 64.7
  TOP w0.14: v2(117.65,36.71) v1(117.65,37.37)
  L4 w0.089: v2(106.8,77.22) 106.8,77.4 106.67,77.53 106.49,77.53 106.36,77.4 106.36,77.03 106.13,76.79 105.76,76.79 104.96,76
  L4 w0.127: v2(117.65,36.71) 117.65,38.54 99.84,56.35 99.84,64.98 100.03,65.16 100.03,65.34 99.66,65.7 99.66,65.92 99.84,66.09 100,66.09 100.5,65.58 101.13,65.58 101.31,65.76 101.31,65.94 101.04,66.21 101.04,66.39 101.22,66.57 101.4,66.57 101.67,66.3 101.85,66.3 102.03,66.48 102.03,66.66 101.77,66.92 101.77,67.1 101.95,67.28 102.13,67.28 102.39,67.02 102.57,67.02 102.75,67.2 102.75,67.38 102.45,67.68 102.45,67.83 102.46,67.83 102.67,68.04 102.81,68.04 103.11,67.74 103.29,67.74 103.47,67.92 103.47,68.1 103.19,68.38 103.19,68.56 103.37,68.74 103.55,68.74 103.83,68.46 104.01,68.46 104.19,68.64 104.19,68.82 104.02,68.98 104.02,69.23 104.15,69.36 104.82,69.36 104.95,69.48 104.95,69.82 104.89,69.88 104.32,69.88 104.07,70.12 104.07,71.67 103.32,72.42 103.32,73.41 103.45,73.54 104.22,73.54 104.35,73.66 104.35,73.92 104.22,74.05 103.46,74.05 103.33,74.17 103.33,74.31 103.59,74.56 104.39,74.56 104.76,74.93 104.76,75.79 104.96,76
  BOTTOM w0.14: v2(106.8,77.22) 107.06,77.22 CPU1.AM49 ; DM1.183 v2(117.65,36.71)
M_A_DQ59: length 64.3
  TOP w0.14: v1(116.19,33.05) 116.54,32.7 v2(116.75,32.7)
  L4 w0.089: 102.61,74.96 102.61,78.56 103.32,79.27 106.16,79.27 v2(106.91,78.52)
  L4 w0.127: v2(116.75,32.7) 116.31,33.14 116.31,34.61 116.14,34.78 116.14,38.38 98.66,55.86 98.66,65.83 102.67,69.84 102.67,74.9 102.61,74.96
  BOTTOM w0.14: v2(116.75,32.7) 116.82,32.7 117.35,32.18 DM1.182 ; CPU1.AK49 107.21,78.82 v2(106.91,78.52)
M_A_DQ60: length 66.5
  TOP w0.14: v2(119.45,36.07) 119.51,36.07 v1(120,35.59)
  L4 w0.089: 106.36,75.65 106.36,76.25 106.55,76.44 107.31,76.44 107.87,77 v2(107.87,77.19)
  L4 w0.127: v2(119.45,36.07) 119.07,36.07 118.94,36.2 118.94,39.06 101.12,56.88 101.12,57.27 101.25,57.4 101.75,57.4 101.87,57.53 101.87,57.78 101.75,57.91 101.25,57.91 101.12,58.04 101.12,58.29 101.25,58.42 101.75,58.42 101.87,58.54 101.87,58.8 101.75,58.93 101.25,58.93 101.12,59.05 101.12,59.31 101.25,59.43 101.75,59.43 101.87,59.56 101.87,59.81 101.75,59.94 101.25,59.94 101.12,60.07 101.12,60.32 101.25,60.45 101.75,60.45 101.87,60.58 101.87,60.83 101.75,60.96 101.25,60.96 101.12,61.08 101.12,61.34 101.25,61.47 101.75,61.47 101.87,61.59 101.87,61.85 101.75,61.97 101.25,61.97 101.12,62.1 101.12,62.35 101.25,62.48 101.75,62.48 101.87,62.61 101.87,62.86 101.75,62.99 101.25,62.99 101.12,63.12 101.12,63.37 101.25,63.5 101.75,63.5 101.87,63.62 101.87,63.88 101.75,64.01 101.25,64.01 101.12,64.13 101.12,64.39 101.25,64.52 101.71,64.52 101.84,64.65 101.84,65.37 105.59,69.13 105.59,69.97 105.72,70.09 106.03,70.09 106.15,70.22 106.15,70.47 106.03,70.6 105.72,70.6 105.59,70.73 105.59,71.76 106.22,72.39 106.22,73.82 106.1,73.94 105.65,73.94 105.52,74.07 105.52,74.43 105.65,74.55 106.23,74.55 106.36,74.68 106.36,75.65
  BOTTOM w0.14: v2(107.87,77.19) 108.19,77.52 CPU1.AM48 ; v2(119.45,36.07) 119.52,36.07 120.05,36.6 DM1.191
M_A_DQ61: length 65.4
  TOP w0.14: v1(121.14,36.35) 120.78,36.71 v2(120.57,36.71)
  L4 w0.089: 106.69,74.65 106.9,74.87 106.96,74.87 107.2,75.1 107.2,76.08 107.91,76.79 108.03,76.79 108.27,77.03 108.27,79.86 108.14,79.99 105.76,79.99 105.65,79.88 105.65,79.72 105.76,79.61 107.17,79.61 107.3,79.48 107.3,78.7 107.31,78.68 107.31,78.6 107.42,78.49 v2(107.87,78.49)
  L4 w0.127: 106.69,74.65 106.44,74.4 106.44,72.3 105.88,71.74 105.88,71.31 106.38,70.81 106.38,70.14 105.81,69.57 105.81,69.04 102.27,65.5 102.27,56.29 119.87,38.69 119.87,38.43 119.77,38.33 119.44,38.33 119.34,38.23 119.34,37.8 119.44,37.7 120.43,37.7 120.62,37.51 120.62,37.32 120.5,37.19 120.02,37.19 119.89,37.06 119.89,36.61 120.02,36.48 120.34,36.48 v2(120.57,36.71)
  BOTTOM w0.14: CPU1.AK48 108.19,78.82 v2(107.87,78.49) ; v2(120.57,36.71) 120.65,36.79 DM1.193
M_A_DQ62: length 63.5
  TOP w0.14: v2(117.65,35.44) 117.86,35.44 v1(118.22,35.08)
  L4 w0.089: v2(105.96,77.19) 105.59,77.19 105.52,77.27 105.52,78.12 105.39,78.24 104.67,78.24 104.55,78.12 104.55,77.8
  L4 w0.127: 104.55,77.8 104.55,76.77 104.53,76.76 104.53,76.41 104.55,76.4 104.55,75.02 104.3,74.77 103.5,74.77 103.1,74.38 103.1,71.88 103.23,71.75 103.69,71.75 103.84,71.6 103.84,71.37 103.72,71.24 103.23,71.24 103.1,71.11 103.1,70.86 103.23,70.73 103.72,70.73 103.84,70.61 103.84,70.35 103.72,70.22 103.23,70.22 103.1,70.1 103.1,69.66 99.45,66.01 99.45,56.19 116.93,38.71 116.93,38.38 117.06,38.25 117.15,38.25 117.26,38.15 117.26,37.85 117.15,37.74 117,37.74 116.93,37.67 116.93,37.17 117,37.1 117.08,37.1 117.2,36.97 117.2,36.71 117.08,36.59 117.03,36.59 116.93,36.49 116.93,35.1 117.03,35.01 117.22,35.01 v2(117.65,35.44)
  BOTTOM w0.14: DM1.181 117.05,35.96 117.58,35.44 v2(117.65,35.44) ; CPU1.AM51 106.29,77.52 v2(105.96,77.19)
M_A_DQ63: length 62.7
  TOP w0.14: v2(116.75,31.43) v1(116.75,30.76)
  L4 w0.127: v2(116.75,31.43) 117.07,31.43 117.19,31.56 117.19,34.28 116.53,34.94 116.53,38.54 99.05,56.02 99.05,65.92 102.89,69.75 102.89,74.47 103.64,75.23 103.64,78.67 104.05,79.07 105.84,79.07 105.96,78.95 v2(105.96,78.49)
  BOTTOM w0.14: CPU1.AK51 106.29,78.82 v2(105.96,78.49) ; DM1.180 v2(116.75,31.43)
M_A_DQS0: length 73.7
  TOP w0.127: v1(103.74,35.72) 103.38,36.07 v2(103.17,36.07)
  L4 w0.114: v2(103.17,36.07) 102.97,36.28 102.71,36.28 102.45,36.54 102.45,37.11 101.87,37.69 97.32,37.69 96.74,38.27 96.74,40.18 96.37,40.55 96.21,40.55 96.05,40.4 95.7,40.4 95.33,40.78 95.33,41.13 95.48,41.28 95.48,41.44 95.24,41.69 95.07,41.69 94.92,41.53 94.57,41.53 94.19,41.91 94.19,42.26 94.35,42.41 94.35,42.57 94.1,42.82 93.94,42.82 93.79,42.67 93.44,42.67 93.06,43.04 93.06,43.39 93.21,43.55 93.21,43.71 92.97,43.95 92.81,43.95 92.66,43.8 92.31,43.8 91.93,44.17 91.93,44.53 92.08,44.68 92.08,44.84 91.84,45.08 91.68,45.08 91.53,44.93 91.18,44.93 90.8,45.31 90.8,45.66 90.95,45.81 90.95,45.97 90.71,46.21 90.55,46.21 90.39,46.06 90.04,46.06 89.67,46.44 89.67,46.79 89.82,46.94 89.82,47.1 89.58,47.35 89.41,47.35 89.26,47.19 88.91,47.19 88.53,47.57 88.53,47.92 88.69,48.07 88.69,48.24 85.57,51.36 85.57,66.41 84.72,67.26 84.72,73.29 90.54,79.11 92.87,79.11 v2(93.09,78.9)
  BOTTOM w0.089: 95.66,79.49 95.67,79.49 95.71,79.52 95.87,79.52 96.07,79.33 98.56,79.33 98.62,79.36 98.75,79.42 98.87,79.42 98.96,79.38 99.05,79.34 99.25,79.34 99.29,79.3 CPU1.AJ62
  BOTTOM w0.127: v2(93.09,78.9) 93.09,78.97 93.62,79.49 95.66,79.49 ; DM1.137 103.85,36.67 v2(103.17,36.07)
M_A_DQS1: length 72.5
  TOP w0.127: v1(63.25,31.2) 63.49,31.43 v2(63.95,31.43)
  L3 w0.114: v2(96.01,76.27) 96.01,75.94 95.44,75.37 93.83,75.37 92.74,76.45 88.04,76.45 84.36,72.77 84.36,70.31 74.35,60.3 74.35,57.3 72.9,55.85 71.59,55.85 70.71,54.98 70.71,53.67 66.13,49.08 66.13,48.89 64.31,47.07 64.31,37.76 63.8,37.25 63.8,34.81 63.28,34.29 63.28,31.88 63.52,31.64 63.74,31.64 v2(63.95,31.43)
  BOTTOM w0.089: v2(96.01,76.27) 96.13,76.39 96.13,76.79 96.39,77.05 98.37,77.05 98.55,77.09 98.58,77.1 98.7,77.16 98.9,77.16 99.03,77.11 99.08,77.09 99.51,77.09 99.76,76.85 99.97,76.85 CPU1.AN61
  BOTTOM w0.127: DM1.12 v2(63.95,31.43)
M_A_DQS2: length 70
  TOP w0.127: v1(108.95,32.41) 108.6,32.07 v2(108.35,32.07)
  L4 w0.114: v2(108.35,32.07) 107.76,32.66 107.76,33.98 107.86,34.08 108.39,34.08 108.64,34.33 108.64,35.94 108.25,36.33 108.25,37.43 102.79,42.89 100.45,42.89 90.82,52.52 90.82,59.67 90.95,59.8 91.79,59.8 92.03,60.03 92.03,60.66 91.79,60.89 91.06,60.89 90.94,61.02 90.94,61.33 91.06,61.46 91.75,61.46 92.01,61.72 92.01,62.23 91.75,62.49 91.04,62.49 90.91,62.62 90.91,62.93 91.04,63.06 91.76,63.06 92.02,63.32 92.02,64.26 91.76,64.52 90.92,64.52 90.82,64.62 90.82,64.99 90.92,65.09 91.78,65.09 92.03,65.34 92.03,66.47 96.07,70.51 96.07,70.86 95.72,71.2 95.72,71.38 95.94,71.61 96.12,71.61 96.46,71.27 96.82,71.27 97.8,72.25 97.8,73.76 100.83,76.79 101.01,76.79 v2(101.26,76.54)
  BOTTOM w0.127: v2(108.35,32.07) 108.81,31.6 108.81,31.19 108.95,31.05 DM1.154 ; CPU1.AN58 101.58,76.87 v2(101.26,76.54)
M_A_DQS3: length 69.1
  TOP w0.127: v1(69.32,35.72) 68.97,36.07 v2(68.82,36.07)
  L3 w0.114: v2(103.16,76.54) 103.44,76.26 103.44,75.03 102.37,73.96 101.04,73.96 100.24,73.16 99.17,73.16 98.31,72.3 98.31,71.88 97.78,71.35 96.58,71.35 92.18,66.95 87.97,66.95 86.41,65.4 86.41,65.05 86.77,64.69 86.77,64.51 86.51,64.25 86.33,64.25 85.97,64.61 85.62,64.61 85.14,64.13 85.14,62.02 69.74,46.61 69.74,42.8 69.46,42.52 68.8,42.52 68.59,42.32 68.59,41.74 68.8,41.53 69.67,41.53 69.74,41.47 69.74,41.06 69.67,41 68.79,41 68.59,40.8 68.59,40.21 68.79,40.01 69.69,40.01 69.74,39.97 69.74,39.52 69.69,39.48 68.85,39.48 68.59,39.22 68.59,37.39 68.39,37.18 68.39,36.53 68.39,36.52 68.39,36.51 v2(68.82,36.07)
  BOTTOM w0.127: v2(68.82,36.07) 69.02,36.27 69.02,36.28 69.27,36.53 69.27,36.89 69.05,37.11 DM1.29 ; CPU1.AN55 103.49,76.87 v2(103.16,76.54)
M_A_DQS4: length 57.4
  TOP w0.127: v1(114.15,35.72) 113.8,36.07 v2(113.67,36.07)
  L4 w0.114: v2(113.67,36.07) 113.22,36.53 113.22,37.92 104.07,47.08 102.06,47.08 98.47,50.67 98.47,51.02 99.06,51.61 99.06,51.77 98.82,52.01 98.65,52.01 98.07,51.42 97.71,51.42 97.34,51.8 97.34,52.15 97.93,52.74 97.93,52.9 97.68,53.14 97.52,53.14 96.93,52.56 96.58,52.56 96.08,53.06 96.08,66.09 96.29,66.3 97.12,66.3 97.18,66.37 97.18,67.74 97.39,67.95 97.91,67.95 98.12,68.15 v2(98.12,69.46)
  BOTTOM w0.089: CPU1.AW57 102.14,73.22 102.14,73.02 102.11,72.93 102.07,72.84 102.07,72.72 102.13,72.59 102.14,72.56 102.14,72.19 101.92,71.97 101.92,71.97 101.83,71.88 101.83,71.43 100.5,70.1 100.1,70.1 99.12,69.12 98.46,69.12 v2(98.12,69.46)
  BOTTOM w0.127: v2(113.67,36.07) 114.12,36.52 114.12,36.53 114.12,37.19 114.05,37.25 114.05,37.47 DM1.171
M_A_DQS5: length 61.6
  TOP w0.127: v1(73.7,35.57) 74.2,36.07 v2(74.25,36.07)
  L3 w0.114: v2(103.8,69.77) 103.54,69.77 103.42,69.89 103.42,70.3 103.18,70.54 102.89,70.54 102.16,69.81 102.16,69.46 102.3,69.32 102.3,69.14 102.08,68.91 101.9,68.91 101.76,69.05 101.41,69.05 98.41,66.06 96.48,66.06 96.12,65.7 96.12,65.29 96.37,65.04 96.53,64.88 96.53,64.61 96.45,64.53 95.4,64.53 93.38,62.51 92.99,62.51 92.69,62.81 92.03,62.81 91.55,62.33 91.55,62.04 91.81,61.78 92.31,61.78 92.44,61.65 92.44,61.57 92.12,61.25 91.59,61.25 91.29,61.55 90.76,61.55 74.12,44.9 74.12,37.2 73.81,36.89 73.81,36.51 v2(74.25,36.07)
  BOTTOM w0.089: CPU1.AW53 104.57,73.22 104.57,73.02 104.54,72.93 104.5,72.84 104.5,72.72 104.56,72.59 104.57,72.56 104.57,72.04 104.31,71.78 104.31,70.81 103.98,70.48 103.98,70.25 103.8,70.07 v2(103.8,69.77)
  BOTTOM w0.127: DM1.47 74.45,37.13 74.69,36.89 74.69,36.52 v2(74.25,36.07)
M_A_DQS6: length 67.7
  TOP w0.127: v1(79.48,32.41) 79.13,32.07 v2(78.95,32.07)
  L3 w0.089: v2(111.67,77.94) 111.29,77.56 111.29,77.02 110.87,76.6 110.38,76.6 110.21,76.43 109.63,76.43 109.37,76.16 109.37,75.12 108.99,74.74 108.82,74.74
  L3 w0.114: 108.82,74.74 108.57,74.74 107.93,74.1 107.93,71.06 100.66,63.78 100.66,63.62 93.93,56.89 92.52,56.89 78.93,43.3 78.93,35.03 80.38,33.58 80.38,32.96 80.12,32.69 79.58,32.69 79.13,33.14 78.77,33.14 78.51,32.88 78.51,32.5 v2(78.95,32.07)
  BOTTOM w0.127: v2(111.67,77.94) 111.9,78.17 CPU1.AL42 ; DM1.64 79.55,31.47 v2(78.95,32.07)
M_A_DQS7: length 65.2
  TOP w0.127: v1(118.6,33.3) 118,32.7 v2(117.94,32.7)
  L4 w0.089: v2(106.91,77.87) 107.2,77.58 107.2,76.86 107.16,76.82 106.41,76.82 106.2,76.61 105.83,76.61 105.2,75.98 105.2,75.06 105.16,75.02 105.16,74.84
  L4 w0.114: v2(117.94,32.7) 118.38,33.14 118.38,33.52 118.19,33.71 118.19,35.13 118.46,35.4 118.46,35.62 118.19,35.89 118.19,38.75 100.37,56.57 100.37,64.52 105.16,69.31 105.16,71.84 105.03,71.96 104.08,71.96 103.82,72.22 103.82,72.69 104.08,72.95 105.52,72.95 105.65,73.08 105.65,73.36 105.52,73.49 104.81,73.49 104.58,73.73 104.58,74.12 105.16,74.7 105.16,74.84
  BOTTOM w0.127: v2(117.94,32.7) 118.96,31.68 118.96,31.15 119.15,30.96 DM1.188 ; v2(106.91,77.87) 107.21,78.17 CPU1.AL49
M_A_DQS#0: length 73.9
  TOP w0.127: v1(103.49,37.49) 103.17,37.18 v2(103.17,36.71)
  L4 w0.114: v2(103.17,36.71) 102.97,36.5 102.81,36.5 102.68,36.63 102.68,37.21 101.97,37.92 97.41,37.92 96.97,38.37 96.97,40.28 96.46,40.78 96.11,40.78 95.96,40.63 95.8,40.63 95.56,40.87 95.56,41.03 95.71,41.19 95.71,41.54 95.33,41.91 94.98,41.91 94.83,41.76 94.67,41.76 94.42,42 94.42,42.17 94.58,42.32 94.58,42.67 94.2,43.05 93.85,43.05 93.7,42.89 93.53,42.89 93.29,43.14 93.29,43.3 93.44,43.45 93.44,43.8 93.07,44.18 92.72,44.18 92.56,44.03 92.4,44.03 92.16,44.27 92.16,44.43 92.31,44.58 92.31,44.93 91.93,45.31 91.58,45.31 91.43,45.16 91.27,45.16 91.03,45.4 91.03,45.56 91.18,45.71 91.18,46.07 90.8,46.44 90.45,46.44 90.3,46.29 90.14,46.29 89.89,46.53 89.89,46.69 90.05,46.85 90.05,47.2 89.67,47.57 89.32,47.57 89.17,47.42 89.01,47.42 88.76,47.67 88.76,47.83 88.91,47.98 88.91,48.33 85.79,51.45 85.79,66.51 84.95,67.35 84.95,73.2 90.64,78.89 92.18,78.89 92.29,78.77 v2(92.29,78.66)
  BOTTOM w0.089: 95.66,79.73 95.93,79.73 96.14,79.52 98.55,79.52 98.58,79.53 98.7,79.59 98.9,79.59 99.03,79.54 99.08,79.52 99.99,79.52 100.11,79.4 CPU1.AJ61
  BOTTOM w0.127: DM1.135 103.25,37.42 103.61,37.06 103.61,36.87 103.45,36.71 v2(103.17,36.71) ; 95.66,79.73 93.51,79.73 93.12,79.34 92.73,79.34 92.29,78.9 v2(92.29,78.66)
M_A_DQS#1: length 72.4
  TOP w0.127: v2(63.95,32.07) 63.82,32.07 v1(63.47,32.41)
  L3 w0.114: v2(63.95,32.07) 63.75,31.87 63.62,31.87 63.51,31.97 63.51,34.2 64.03,34.71 64.03,37.16 64.54,37.66 64.54,46.97 66.36,48.8 66.36,48.99 70.94,53.57 70.94,54.89 71.68,55.62 73,55.62 74.58,57.21 74.58,60.21 84.59,70.21 84.59,72.67 88.14,76.23 92.65,76.23 93.73,75.14 95.54,75.14 96.66,76.26 v2(96.66,76.27)
  BOTTOM w0.089: CPU1.AN62 99.46,76.79 99.34,76.91 99.05,76.91 98.96,76.95 98.87,76.99 98.75,76.99 98.62,76.92 98.59,76.91 98.44,76.86 96.47,76.86 96.32,76.71 96.32,76.53 96.58,76.27 v2(96.66,76.27)
  BOTTOM w0.127: DM1.10 63.35,31.81 63.6,32.07 v2(63.95,32.07)
M_A_DQS#2: length 70.1
  TOP w0.127: v2(108.35,31.43) v1(108.35,30.76)
  L4 w0.114: v2(101.26,77.19) 101.08,77.02 100.74,77.02 97.57,73.85 97.57,72.35 96.73,71.5 96.56,71.5 96.22,71.84 95.85,71.84 95.49,71.48 95.49,71.11 95.84,70.76 95.84,70.61 91.8,66.57 91.8,65.43 91.68,65.32 90.82,65.32 90.59,65.09 90.59,64.52 90.82,64.29 91.67,64.29 91.79,64.16 91.79,63.42 91.67,63.29 90.94,63.29 90.68,63.03 90.68,62.52 90.94,62.26 91.66,62.26 91.78,62.13 91.78,61.82 91.66,61.69 90.97,61.69 90.71,61.43 90.71,60.92 90.97,60.66 91.7,60.66 91.8,60.56 91.8,60.12 91.7,60.02 90.85,60.02 90.59,59.76 90.59,52.43 100.36,42.66 102.7,42.66 108.02,37.34 108.02,36.24 108.41,35.85 108.41,34.42 108.3,34.31 107.76,34.31 107.53,34.08 107.53,32.56 107.91,32.18 107.91,31.87 v2(108.35,31.43)
  BOTTOM w0.127: DM1.152 108.35,31.43 v2(108.35,31.43) ; v2(101.26,77.19) 101.58,77.52 CPU1.AM58
M_A_DQS#3: length 69.1
  TOP w0.127: v2(68.82,36.71) v1(68.82,37.27)
  L3 w0.114: v2(103.16,77.19) 103.42,77.45 103.54,77.45 103.67,77.32 103.67,74.94 102.47,73.74 101.14,73.74 100.34,72.94 99.26,72.94 98.53,72.21 98.53,71.78 97.87,71.12 96.68,71.12 92.28,66.72 88.06,66.72 86.64,65.3 86.64,65.14 87,64.78 87,64.42 86.6,64.02 86.24,64.02 85.88,64.38 85.72,64.38 85.37,64.03 85.37,62.11 85.37,61.92 69.97,46.52 69.97,42.71 69.55,42.3 68.9,42.3 68.82,42.22 68.82,41.84 68.9,41.76 69.77,41.76 69.97,41.56 69.97,40.97 69.77,40.77 68.89,40.77 68.82,40.71 68.82,40.3 68.89,40.24 69.79,40.24 69.97,40.06 69.97,39.42 69.79,39.25 68.94,39.25 68.82,39.13 68.82,37.3 68.61,37.09 68.61,36.92 v2(68.82,36.71)
  BOTTOM w0.127: DM1.27 68.45,36.81 68.55,36.71 v2(68.82,36.71) ; v2(103.16,77.19) 103.42,77.19 103.55,77.32 CPU1.AM55
M_A_DQS#4: length 57.6
  TOP w0.127: v2(113.67,36.71) 113.37,36.71 v1(113.14,36.48)
  L4 w0.114: v2(113.67,36.71) 113.45,36.93 113.45,38.02 104.16,47.31 102.16,47.31 98.7,50.76 98.7,50.92 99.29,51.51 99.29,51.86 98.91,52.24 98.56,52.24 97.97,51.65 97.81,51.65 97.57,51.9 97.57,52.06 98.16,52.64 98.16,53 97.78,53.37 97.43,53.37 96.84,52.78 96.68,52.78 96.31,53.15 96.31,66 96.38,66.07 97.21,66.07 97.41,66.27 97.41,67.65 97.49,67.72 98.01,67.72 98.35,68.06 98.35,69.11 98.58,69.34 v2(98.58,69.92)
  BOTTOM w0.089: CPU1.AV57 102.2,74.23 102.02,74.23 101.96,74.17 101.96,73.05 101.94,73 101.89,72.87 101.89,72.67 101.95,72.55 101.96,72.52 101.96,72.28 101.64,71.96 101.64,71.51 100.42,70.29 100.02,70.29 99.04,69.31 98.56,69.31 98.52,69.35 98.52,69.86 v2(98.58,69.92)
  BOTTOM w0.127: DM1.169 113.45,37.51 113.88,37.09 113.88,36.79 113.8,36.71 v2(113.67,36.71)
M_A_DQS#5: length 62
  TOP w0.127: v2(74.25,36.71) 74.81,36.71 v1(74.97,36.55)
  L3 w0.114: v2(74.25,36.71) 74.35,36.81 74.35,44.81 90.86,61.32 91.2,61.32 91.5,61.02 92.21,61.02 92.67,61.48 92.67,61.75 92.41,62.01 91.9,62.01 91.78,62.13 91.78,62.24 92.12,62.58 92.6,62.58 92.9,62.29 93.48,62.29 95.5,64.3 96.55,64.3 96.76,64.51 96.76,64.98 96.53,65.21 96.35,65.38 96.35,65.61 96.57,65.83 98.51,65.83 101.5,68.83 101.66,68.83 101.8,68.68 102.17,68.68 102.53,69.04 102.53,69.41 102.39,69.55 102.39,69.71 102.99,70.31 103.08,70.31 103.19,70.2 103.19,69.79 103.51,69.47 103.51,69.27 103.41,69.17 v2(103.21,69.17)
  BOTTOM w0.089: CPU1.AV53 104.64,73.94 104.64,73.73 104.39,73.48 104.39,73.05 104.37,73 104.32,72.87 104.32,72.67 104.38,72.55 104.39,72.52 104.39,72.13 104.12,71.86 104.12,70.89 103.79,70.56 103.79,70.33 103.4,69.94 103.4,69.6 103.6,69.41 103.6,69.23 103.54,69.17 v2(103.21,69.17)
  BOTTOM w0.127: v2(74.25,36.71) 73.94,36.71 73.85,36.8 DM1.45
M_A_DQS#6: length 67.8
  TOP w0.127: v2(78.95,31.43) v1(78.95,30.76)
  L3 w0.089: 108.82,74.97 108.95,74.97 109.18,75.2 109.18,76.24 109.55,76.62 110.13,76.62 110.3,76.79 110.79,76.79 111.1,77.1 111.1,77.72 110.97,77.85 v2(110.67,77.85)
  L3 w0.114: 108.82,74.97 108.48,74.97 107.7,74.2 107.7,71.15 100.43,63.88 100.43,63.72 93.84,57.12 92.42,57.12 78.7,43.4 78.7,34.94 80.15,33.49 80.15,33.05 80.02,32.92 79.67,32.92 79.23,33.37 78.67,33.37 78.28,32.98 78.28,32.41 78.51,32.18 78.51,31.87 v2(78.95,31.43)
  BOTTOM w0.127: CPU1.AL43 110.99,78.17 v2(110.67,77.85) ; DM1.62 v2(78.95,31.43)
M_A_DQS#7: length 65.1
  TOP w0.127: v2(117.94,32.07) v1(118.6,32.07)
  L4 w0.089: 105.39,74.81 105.39,74.81 105.39,75.9 105.91,76.42 106.28,76.42 106.49,76.63 107.24,76.63 107.39,76.78 107.39,77.37 107.4,77.37 v2(107.87,77.84)
  L4 w0.114: v2(117.94,32.07) 117.99,32.07 118.38,32.46 118.38,32.82 118.61,33.04 118.61,33.61 118.42,33.8 118.42,35.03 118.68,35.3 118.68,35.71 118.42,35.98 118.42,38.84 100.6,56.66 100.6,64.43 105.39,69.22 105.39,71.93 105.12,72.19 104.17,72.19 104.05,72.32 104.05,72.6 104.17,72.72 105.61,72.72 105.87,72.99 105.87,73.45 105.61,73.72 104.91,73.72 104.8,73.82 104.8,74.02 105.39,74.6 105.39,74.81
  BOTTOM w0.127: v2(107.87,77.84) 108.19,78.17 CPU1.AL48 ; v2(117.94,32.07) 118.23,32.07 118.72,31.58 118.72,31.1 118.55,30.94 DM1.186
M_A_RAS#: length 56.7
  TOP w0.216: v2(116.69,72.11) 116.31,71.73 v1(116.31,71.63)
  L3 w0.203: v2(116.69,72.11) 116.9,72.32 117.2,72.32 117.33,72.19 117.33,64.64 116.21,63.53 116.21,57.16 99.54,40.49 99.22,40.49 98.57,39.84 98.57,39.25 97.09,37.78 97.09,32.29 96.97,32.16 96.97,30.76 96.71,30.51 95.36,30.51 95.1,30.76 95.1,31.18 95.36,31.43 v2(95.75,31.43)
  BOTTOM w0.216: v2(116.69,72.11) 117.04,72.46 CPU1.AY34 ; DM1.110 v2(95.75,31.43)
M_A_WE#: length 58.6
  TOP w0.216: v1(117.18,72.5) 116.9,72.78 v2(116.69,72.78)
  L3 w0.203: v2(116.69,72.78) 116.69,72.82 117.25,73.38 117.48,73.38 117.62,73.24 117.62,64.3 116.77,63.45 116.77,56.93 99.77,39.94 99.45,39.94 99.14,39.62 99.14,39.02 97.66,37.54 97.66,34.28 v2(97.58,34.19)
  BOTTOM w0.216: v2(116.69,72.78) 117.02,73.11 CPU1.AW34 ; v2(97.58,34.19) 97.23,34.19 97.11,34.07 97.11,33.12 96.78,32.8 96.55,32.8 96.32,33.03 96.32,34.17 96.41,34.26 96.41,34.85 96.63,35.07 96.88,35.07 97.14,35.32 97.14,35.68 96.88,35.93 96.63,35.93 96.41,36.15 96.41,36.72 96.65,36.96 DM1.113
M_B_A0: length 73.3
  TOP w0.216: v2(126.65,18.26) v1(126.65,17.68)
  L4 w0.089: 111.85,69.17 111.85,69.59 111.44,69.99 111.44,70.32 111.54,70.42 111.54,74.23 112.17,74.86 112.17,75.51 v2(112.57,75.9)
  L4 w0.203: v2(126.65,18.26) 126.67,18.26 127.24,18.83 127.24,20.86 126.64,21.46 126.64,25.25 126.99,25.6 126.99,26.85 131.69,31.55 131.69,35.92 132.42,36.64 132.42,41.49 126.35,47.55 124.72,47.55 112.12,60.15 112.12,60.45 112.12,63.34 111.85,63.61 111.85,69.17
  BOTTOM w0.216: v2(126.65,18.26) 126.65,18.25 DM2.98 ; v2(112.57,75.9) 112.67,75.9 CPU1.AP40
M_B_A1: length 74.5
  TOP w0.216: v1(127.36,22.76) v2(127.36,22.2)
  L4 w0.203: v2(112.59,75.24) 112.56,75.21 112.56,70.59 112.3,70.33 112.3,69.97 112.14,69.81 112.14,63.88 112.68,63.34 112.68,62.43 112.68,60.38 124.95,48.11 126.12,48.11 126.58,48.11 132.98,41.72 132.98,36.41 132.25,35.69 132.25,31.32 128,27.07 128,25.82 127.2,25.01 127.2,22.36 v2(127.36,22.2)
  BOTTOM w0.216: CPU1.AR40 112.66,75.24 v2(112.59,75.24) ; DM2.97 126.35,22.74 126.66,22.43 126.66,20.43 126.91,20.17 127.64,20.17 127.9,20.43 127.9,21.66 v2(127.36,22.2)
M_B_A2: length 77
  TOP w0.216: v2(126.68,19.59) v1(126.68,20.15)
  L4 w0.089: v2(111.71,75.98) 111.54,75.98 111.31,75.76 111.31,75.15 110.97,74.81 110.97,69.33 111.19,69.11
  L4 w0.203: 111.19,69.11 111.19,67.43 111,67.24 111,63.12 111,59.69 124.25,46.44 125.89,46.44 130.58,41.75 130.58,32.02 125.87,27.31 125.87,26.06 125.52,25.71 125.52,19.84 125.77,19.59 v2(126.68,19.59)
  BOTTOM w0.216: CPU1.AP42 111.94,75.98 v2(111.71,75.98) ; DM2.96 126.05,19.11 125.63,19.53 124.98,19.53 124.72,19.78 124.72,20.15 124.98,20.41 125.86,20.41 v2(126.68,19.59)
M_B_A3: length 75.2
  TOP w0.216: v1(126.09,22.76) v2(126.09,22.2)
  L4 w0.089: 111.56,69.45 111.15,69.86 111.15,71.03 111.24,71.12 111.28,71.12 111.37,71.21 111.37,71.39 111.28,71.48 111.24,71.48 111.15,71.57 111.15,71.74 111.24,71.83 111.28,71.83 111.37,71.92 111.37,72.1 111.28,72.19 111.24,72.19 111.15,72.28 111.15,72.46 111.24,72.54 111.28,72.54 111.37,72.63 111.37,72.81 111.28,72.9 111.24,72.9 111.15,72.99 111.15,73.17 111.24,73.26 111.28,73.26 111.37,73.34 111.37,73.52 111.28,73.61 111.24,73.61 111.15,73.7 111.15,73.88 111.24,73.97 111.28,73.97 111.37,74.06 111.37,74.23 111.28,74.32 111.24,74.32 111.15,74.41 111.15,74.7 111.26,74.81 111.87,74.81 112,74.93 112,75.26 111.93,75.33 v2(111.72,75.33)
  L4 w0.203: v2(126.09,22.2) 126.08,22.21 126.08,25.48 126.43,25.83 126.43,27.08 131.14,31.79 131.14,38.12 131.35,38.33 131.73,38.33 131.86,38.46 131.86,38.84 131.73,38.97 131.26,38.97 131.14,39.1 131.14,39.45 131.26,39.58 131.73,39.58 131.86,39.7 131.86,40.06 131.73,40.19 131.26,40.19 131.14,40.31 131.14,40.67 131.26,40.8 131.73,40.8 131.86,40.92 131.86,41.26 131.71,41.41 131.26,41.41 131.14,41.53 131.14,41.98 126.12,46.99 124.48,46.99 111.56,59.92 111.56,60.22 111.56,62.89 111.56,62.89 111.56,69.45
  BOTTOM w0.216: CPU1.AR42 111.94,75.33 v2(111.72,75.33) ; v2(126.09,22.2) 125.82,21.92 125.53,21.92 125.4,22.05 125.4,22.84 125.15,23.09 125.15,23.51 125.75,24.11 DM2.95
M_B_A4: length 81
  TOP w0.216: v2(125.4,18.96) v1(125.4,19.53)
  L4 w0.089: v2(109.78,75.36) 110.79,74.34 110.79,68.79
  L4 w0.203: v2(125.4,18.96) 125.78,18.96 125.93,18.8 125.93,15.24 125.68,14.99 125.08,14.99 124.82,15.24 124.82,19.77 124.95,19.89 124.96,19.89 124.96,25.99 124.9,26.05 124.9,27.13 130.02,32.25 130.02,41.52 125.66,45.88 124.02,45.88 110.44,59.46 110.44,59.75 110.44,67.1 110.79,67.45 110.79,68.79
  BOTTOM w0.216: v2(125.4,18.96) 124.85,18.41 DM2.92 ; v2(109.78,75.36) 109.99,75.57 CPU1.AR45
M_B_A5: length 79.2
  TOP w0.216: v1(124.4,23.4) v2(124.4,22.76)
  L4 w0.089: v2(109.77,76) 110.23,76 110.32,75.92 110.32,75.53 110.32,75.53 110.32,75.21 110.55,74.98 110.89,74.98 111.12,75.21 111.12,75.82 111.15,75.85 111.15,76.37 111.02,76.5 109.31,76.5 109.15,76.33 109.15,75.41 109.95,74.62 109.95,71.84 110.47,71.32 110.47,70.68
  L4 w0.203: 110.47,70.68 110.47,67.54 109.88,66.95 109.88,59.52 109.88,59.23 123.79,45.32 125.43,45.32 129.46,41.28 129.46,32.48 124.34,27.36 124.34,25.82 124.4,25.76 124.4,22.85 v2(124.4,22.76)
  BOTTOM w0.216: v2(109.77,76) 109.99,76.22 CPU1.AP45 ; DM2.91 124.55,23.83 123.32,22.6 123.32,21.68 123.48,21.52 124.7,21.52 124.83,21.65 124.83,22.6 124.67,22.76 v2(124.4,22.76)
M_B_A6: length 84.7
  TOP w0.216: v1(123.62,17.68) v2(123.62,18.3)
  L4 w0.203: v2(123.62,18.3) 123.62,17.39 122.33,16.1 122.33,14.57 122.2,14.45 120.73,14.45 120.61,14.32 120.61,13.75 120.73,13.62 124.14,13.62 124.26,13.75 124.26,20.69 123.84,21.11 123.84,22.53 123.84,23.08 123.84,23.08 123.84,24.49 123.78,24.55 123.78,27.59 128.9,32.71 128.9,41.05 125.19,44.76 123.56,44.76 109.32,58.99 109.32,59.29 109.32,66.81 110.05,67.53 110.05,68.87 110.15,68.98 110.15,70.94 110.15,70.94 110.15,71.19 109.27,72.07 109.27,72.33 v2(108.81,72.79)
  BOTTOM w0.216: CPU1.AW46 109.12,73.11 v2(108.81,72.79) ; DM2.90 124.25,17.67 v2(123.62,18.3)
M_B_A7: length 84.4
  TOP w0.216: v2(123.6,19.89) v1(123.6,20.48)
  L4 w0.203: v2(123.6,19.89) 123.02,19.31 123.02,17.58 120.44,15 119.79,15 119.54,15.26 119.54,16.06 119.79,16.31 120.59,16.31 122.31,18.03 122.31,19.36 122.33,19.39 122.33,19.77 122.54,19.98 122.54,20.44 122.16,20.82 122.16,25.57 122.08,25.66 121.14,25.66 120.94,25.86 120.94,26.33 127.78,33.18 127.78,40.59 124.73,43.64 123.1,43.64 108.21,58.53 108.21,58.83 108.21,66.52 109.46,67.77 109.46,69.11 109.57,69.22 109.57,70.94 109.05,71.46 v2(108.82,71.46)
  BOTTOM w0.216: DM2.86 123.05,19.34 v2(123.6,19.89) ; CPU1.AY46 109.27,72.4 109.27,71.92 109.22,71.86 109.22,71.86 v2(108.82,71.46)
M_B_A8: length 82.7
  TOP w0.216: v1(122.74,22.51) v2(122.74,21.94)
  L4 w0.203: v2(122.74,21.94) 123.16,21.94 123.28,22.06 123.28,22.29 123.28,22.3 123.28,22.64 123.16,22.76 122.85,22.76 122.72,22.89 122.72,23.45 122.85,23.58 123.16,23.58 123.28,23.7 123.28,24.26 123.16,24.39 122.85,24.39 122.72,24.52 122.72,24.98 122.84,25.1 123.05,25.1 123.22,25.28 123.22,25.61 123.04,25.79 122.74,25.79 122.03,26.49 122.03,26.64 128.34,32.94 128.34,40.82 124.96,44.2 123.33,44.2 108.76,58.76 108.76,59.06 108.76,59.06 108.76,63.34 108.76,66.66 109.75,67.65 109.75,68.99 109.86,69.1 109.86,71.06 109.01,71.92 109,71.92 v2(108.81,72.11)
  BOTTOM w0.089: CPU1.AY47 108.39,72.19 108.05,71.85 108.05,71.08 107.92,70.95 107.92,67.51 108.01,67.42 108.91,67.42 109,67.51 109,68.64 108.91,68.72 108.78,68.72 108.69,68.81 108.69,68.99 108.78,69.08 108.91,69.08 109,69.17 109,69.36 108.91,69.45 108.33,69.45 108.24,69.54 108.24,70.82 108.42,71 108.42,71.72 v2(108.81,72.11)
  BOTTOM w0.216: DM2.89 123.95,24.04 122.14,22.23 122.14,22 122.36,21.79 122.59,21.79 v2(122.74,21.94)
M_B_A9: length 85
  TOP w0.216: v2(121,21.43) 121.21,21.43 v1(121.52,21.75)
  L4 w0.089: 108.41,68.38 108.41,68.39 108.41,74.52 108.71,74.82 108.75,74.82 109.07,75.14 109.18,75.14 109.76,74.56 109.76,72.53 109.67,72.45 109.49,72.45 109.21,72.73 109.21,72.96 109.38,73.13 109.38,73.37 109.21,73.54 109.21,73.67 109.41,73.87 109.41,74.39 109.32,74.48 108.9,74.48 108.81,74.39 v2(108.81,74.09)
  L4 w0.203: v2(121,21.43) 120.94,21.43 120.5,21.87 120.5,21.94 119.96,22.49 119.96,24.25 118.85,25.35 118.85,27.3 119.65,28.1 120.19,28.1 124.27,32.18 124.27,33.9 124.8,34.43 124.8,35.09 125.61,35.9 125.61,37.31 124.73,38.19 124.73,41.27 124.04,41.97 122.4,41.97 106.53,57.84 106.53,58.13 106.53,66.5 108.41,68.38
  BOTTOM w0.216: v2(121,21.43) 120.96,21.43 120.52,21 120.52,20.52 120.64,20.4 120.64,19.23 120.77,19.11 121.2,19.11 121.33,19.24 121.33,20.41 121.57,20.65 121.57,22.47 122.75,23.65 DM2.85 ; v2(108.81,74.09) 109.13,74.41 CPU1.AU46
M_B_A10: length 89
  TOP w0.216: v1(130.41,22.51) 130.22,22.51 v2(129.86,22.15)
  L4 w0.089: v2(115.25,79.26) 115.25,79.87 115.12,79.99 114.51,79.99 113.81,80.69 112.73,80.69 112.64,80.6 112.64,80.21 112.55,80.12 112.29,80.12 112.2,80.21 112.2,80.6 112.11,80.69 111.84,80.69 111.75,80.6 111.75,80.21 111.67,80.12 111.4,80.12 111.31,80.21 111.31,80.6 111.22,80.69 110.95,80.69 110.87,80.6 110.87,80.21 110.78,80.12 110.51,80.12 110.42,80.21 110.42,80.6 110.33,80.69 109.89,80.69 109.76,80.57 109.76,79.84 109.89,79.71 112.76,79.71 112.94,79.52 114.36,79.52 114.49,79.4 114.49,78.32 114.48,78.32 114.48,77.05 114.48,77.05 114.48,76.37 114.41,76.29 114.41,75.36 114.41,75.36 114.41,75.14 114.47,75.09 114.47,74.83
  L4 w0.203: v2(129.86,22.15) 129.86,24.29 131.22,25.65 131.22,26.93 135.21,30.92 135.21,42.86 124.57,53.5 122.84,53.5 114.78,61.55 114.78,67.33 114.47,67.64 114.47,74.83
  BOTTOM w0.216: v2(115.25,79.26) 115.53,78.97 CPU1.AK36 ; DM2.107 129.35,23.87 129.77,23.45 129.77,23.01 129.35,22.59 129.35,22.27 129.48,22.15 v2(129.86,22.15)
M_B_A11: length 85.4
  TOP w0.216: v1(122.28,20.68) 121.98,20.38 v2(121.98,20.21)
  L4 w0.203: v2(121.98,20.21) 121.84,20.07 121.48,20.07 121.39,20.16 121.39,20.5 121.61,20.71 121.61,25.01 121.52,25.1 120.69,25.1 120.38,25.41 120.38,26.56 127.22,33.41 127.22,34.81 126.73,35.3 126.73,35.54 127.02,35.83 127.02,36.11 126.73,36.4 126.73,36.65 127.22,37.15 127.22,40.36 124.5,43.08 122.86,43.08 107.65,58.3 107.65,58.6 107.65,66.37 109.17,67.89 109.17,69.86 109.28,69.97 109.28,70.82 109.13,70.97 108.98,70.97 v2(108.82,70.81)
  BOTTOM w0.089: v2(108.82,70.81) 108.55,70.81 108.42,70.68 108.42,69.71 108.51,69.63 109.09,69.63 109.18,69.54 109.18,67.34 109.07,67.24 107.84,67.24 107.74,67.34 107.74,71.03 107.87,71.16 107.87,71.92 108.1,72.16 108.1,73.47 CPU1.AV47
  BOTTOM w0.216: DM2.84 122.45,19.54 123.17,20.27 123.17,20.72 123.09,20.8 122.26,20.8 122.14,20.68 122.14,20.37 v2(121.98,20.21)
M_B_A12: length 81.3
  TOP w0.216: v2(121,22.7) 121.08,22.7 v1(121.52,23.14)
  L4 w0.203: v2(108.82,70.16) 108.82,68.38 107.09,66.65 107.09,63.34 107.09,58.07 122.63,42.52 124.27,42.52 125.29,41.51 125.29,40.91 125.37,40.82 125.97,40.82 126.28,40.51 126.28,40.34 126.16,40.21 125.41,40.21 125.29,40.09 125.29,39.73 125.41,39.6 126.54,39.6 126.66,39.48 126.66,38.85 126.25,38.43 126.25,38.07 126.66,37.65 126.66,37.38 126.17,36.89 126.17,35.07 126.66,34.57 126.66,33.64 120.56,27.54 119.89,27.54 119.41,27.07 119.41,25.58 120.46,24.54 120.92,24.54 121.05,24.41 121.05,24.04 120.94,23.93 120.64,23.93 120.51,23.8 120.51,23.19 v2(121,22.7)
  BOTTOM w0.089: CPU1.AU47 108.34,74.17 107.93,73.76 107.93,72.23 107.69,71.99 107.69,71.23 107.56,71.1 107.56,67.15 107.65,67.06 109.27,67.06 109.35,67.15 109.35,69.62 v2(108.82,70.16)
  BOTTOM w0.216: DM2.83 122.15,23.86 v2(121,22.7)
M_B_A13: length 90
  TOP w0.216: v2(132.94,21.02) 133.11,21.02 v1(133.46,21.37)
  L4 w0.089: 117.61,75.11 117.36,75.35 117.36,79.42 117.49,79.55 118.51,79.55 118.6,79.46 118.6,78.71 118.69,78.62 118.87,78.62 118.96,78.71 118.96,79.42 119.08,79.55 121.74,79.55 121.85,79.66 121.85,79.83 121.74,79.94 116.97,79.94 116.9,79.87 v2(116.9,78.54)
  L4 w0.203: v2(132.94,21.02) 134.61,22.69 134.61,23.71 135.54,24.64 135.54,26.19 135.54,26.4 139.99,30.85 139.99,42.82 125.96,56.85 124.23,56.85 118.14,62.94 118.14,63.34 117.61,63.87 117.61,75.11
  BOTTOM w0.216: v2(116.9,78.54) 117.17,78.82 CPU1.AK33 ; v2(132.94,21.02) 133.35,21.43 133.35,21.43 133.37,21.44 133.37,23.14 132.95,23.55 DM2.119
M_B_A14: length 86.4
  TOP w0.216: v2(121.83,18.93) 122.13,18.93 v1(122.41,19.21)
  L4 w0.089: v2(108.75,75.38) 108.53,75.16 108.53,74.89 108.23,74.59 108.23,68.62 108.06,68.44
  L4 w0.203: v2(121.83,18.93) 121.11,18.93 120.86,18.67 120.86,17.66 120.07,16.87 116.53,16.87 116.29,17.11 116.29,17.45 116.53,17.69 119.7,17.69 120.04,18.03 120.04,21.54 119.95,21.64 119.95,21.71 119.4,22.26 119.4,24.02 118.3,25.12 118.3,27.53 119.42,28.66 119.96,28.66 122.94,31.64 122.94,33.36 124.24,34.66 124.24,35.32 125.05,36.13 125.05,37.08 124.17,37.96 124.17,41.04 123.8,41.41 122.17,41.41 105.97,57.6 105.97,57.9 105.97,66.36 108.06,68.44
  BOTTOM w0.216: DM2.80 121.25,18.35 v2(121.83,18.93) ; CPU1.AR46 108.94,75.57 v2(108.75,75.38)
M_B_A15: length 86.8
  TOP w0.216: v1(120,20.1) 119.56,19.65 v2(119.48,19.65)
  L4 w0.089: v2(108.73,76.02) 108.61,76.02 108.38,75.8 108.38,75.64 108.35,75.6 108.35,74.97 108.05,74.66 108.05,69.03 107.76,68.75
  L4 w0.203: v2(119.48,19.65) 119.48,19.65 118.64,18.81 117.75,18.81 117.56,19 117.56,19.68 117.74,19.85 118.68,19.85 118.83,20 118.83,23.79 117.74,24.89 117.74,27.76 119.19,29.21 119.72,29.21 122.39,31.88 122.39,33.59 123.69,34.89 123.69,35.56 124.49,36.36 124.49,36.85 123.61,37.73 123.61,40.2 123.12,40.7 122.09,40.7 105.41,57.37 105.41,57.67 105.41,57.67 105.41,63.34 105.41,66.39 107.76,68.75
  BOTTOM w0.216: DM2.78 120.65,17.51 120.07,18.09 120.07,20.16 120.04,20.2 119.95,20.28 119.95,21.3 119.96,21.3 119.96,21.63 120.07,21.75 120.07,23.02 119.83,23.26 119.21,23.26 118.97,23.02 118.97,20.17 v2(119.48,19.65) ; CPU1.AP46 108.92,76.22 v2(108.73,76.02)
M_B_BS0: length 89
  TOP w0.216: v2(131.01,21.93) 131.12,21.93 v1(131.55,21.49)
  L4 w0.089: v2(115.99,77.84) 115.71,77.84 115.46,77.59 115.46,76.88 115.37,76.79 114.94,76.79 114.85,76.7 114.85,76.52 114.94,76.43 115.31,76.43 115.4,76.34 115.4,75.07 115.31,74.98 114.98,74.98 114.89,74.89 114.89,74.62 114.98,74.53 115.84,74.53 115.92,74.45 115.92,74.26 115.84,74.17 115.62,74.17 115.53,74.08 115.53,73.9 115.62,73.81 115.84,73.81 115.92,73.72 115.92,73.55 115.84,73.46 115.62,73.46 115.53,73.37 115.53,73.19 115.62,73.1 115.84,73.1 115.92,73.01 115.92,72.83 115.84,72.75 115.59,72.75 115.5,72.66 115.5,72.48 115.59,72.39 115.84,72.39 115.92,72.3 115.92,72.12 115.84,72.03 115.56,72.03 115.48,71.95 115.48,71.77 115.56,71.68 115.84,71.68 115.92,71.59 115.92,71.4 115.84,71.31 115.69,71.31 115.6,71.22 115.6,71.04 115.69,70.95 115.84,70.95 115.92,70.87 115.92,69.21 115.84,69.12 115.11,69.12 115.05,69.06 115.05,68.82 115.11,68.76 116.12,68.76 116.21,68.67 116.21,68.5 116.12,68.41 115.11,68.41 115.05,68.35 115.05,68.11 115.11,68.05 115.7,68.05
  L4 w0.203: v2(131.01,21.93) 131.01,23.48 132.81,25.28 132.81,26.94 136.43,30.56 136.43,43.22 125.03,54.61 123.31,54.61 115.9,62.02 115.9,67.85 115.7,68.05
  BOTTOM w0.216: DM2.109 129.95,24.19 130.34,23.79 130.34,21.21 130.09,20.96 129.17,20.96 128.98,20.77 128.98,19.88 129.14,19.71 129.39,19.71 129.84,20.17 130.55,20.17 131.64,21.26 131.64,21.51 131.22,21.93 v2(131.01,21.93) ; v2(115.99,77.84) 116.06,77.84 CPU1.AL35
M_B_BS1: length 88.7
  TOP w0.216: v2(130.28,19.59) 130.28,19.71 v1(130.28,20.22)
  L4 w0.089: v2(115.11,77.85) 114.66,77.39 114.66,77.13 114.66,77.12 114.66,76.3 114.58,76.22 114.58,75.44 114.59,75.43 114.59,75.22 114.71,75.09 114.71,71.31 114.83,71.19 114.83,70.88 114.81,70.87
  L4 w0.203: v2(130.28,19.59) 130.27,19.59 129.7,19.03 129.7,16.24 129.45,15.98 126.74,15.98 126.49,16.24 126.49,17.5 126.69,17.7 128.73,17.7 128.99,17.95 128.99,20.71 129.24,20.96 130.08,20.96 130.33,21.21 130.33,21.84 130.45,21.95 130.45,23.71 131.78,25.04 131.78,26.7 135.87,30.79 135.87,42.98 124.8,54.06 123.07,54.06 115.34,61.79 115.34,67.18 114.81,67.71 114.81,70.87
  BOTTOM w0.216: DM2.108 129.65,19.17 130.08,19.59 v2(130.28,19.59) ; v2(115.11,77.85) 115.44,77.52 CPU1.AM36
M_B_BS2: length 85.4
  TOP w0.216: v2(117.69,20.97) 117.82,20.97 v1(118.22,21.37)
  L4 w0.089: v2(107.24,74.11) 107.24,74.39 107.43,74.58 107.68,74.58 107.87,74.39 107.87,69.27 107.2,68.6
  L4 w0.203: v2(117.69,20.97) 117.99,20.97 118.25,21.23 118.25,23.58 117.18,24.66 117.18,27.99 118.96,29.77 119.49,29.77 121.83,32.11 121.83,33.82 123.05,35.05 123.05,39.34 122.43,39.96 122.04,39.96 104.85,57.14 104.85,57.44 104.85,66.25 107.2,68.6
  BOTTOM w0.216: CPU1.AU49 107.54,74.41 v2(107.24,74.11) ; DM2.79 120.95,24.22 120.56,23.83 118.96,23.83 118.4,23.27 118.4,16.31 118.14,16.06 117.43,16.06 117.18,16.31 117.18,20.54 117.61,20.97 v2(117.69,20.97)
M_B_CAS#: length 89.6
  TOP w0.216: v2(132.86,22.28) 133.1,22.28 v1(133.46,22.64)
  L4 w0.089: v2(116.95,77.26) 116.65,77.26 116.56,77.16 116.56,75.12 116.93,74.76
  L4 w0.203: v2(132.86,22.28) 133.42,22.28 134.05,22.92 134.05,23.96 134.98,24.89 134.98,26.43 134.98,26.63 139.19,30.84 139.19,31.4 139.06,31.53 138.23,31.53 138.11,31.65 138.11,32.12 138.31,32.32 139.3,32.32 139.43,32.45 139.43,33.01 139.3,33.13 138.31,33.13 138.11,33.34 138.11,33.74 138.31,33.95 139.3,33.95 139.43,34.07 139.43,34.63 139.3,34.76 138.31,34.76 138.11,34.96 138.11,35.37 138.31,35.57 139.3,35.57 139.43,35.7 139.43,36.26 139.3,36.38 138.31,36.38 138.11,36.59 138.11,36.99 138.31,37.2 139.3,37.2 139.43,37.32 139.43,37.88 139.3,38.01 138.31,38.01 138.11,38.21 138.11,38.62 138.31,38.82 139.3,38.82 139.43,38.95 139.43,39.51 139.3,39.64 138.31,39.64 138.11,39.84 138.11,40.25 138.31,40.45 139.3,40.45 139.43,40.58 139.43,41.13 139.3,41.26 138.31,41.26 138.11,41.46 138.11,41.87 138.31,42.07 139.22,42.07 139.35,42.2 139.35,42.67 139.13,42.89 138.31,42.89 138.11,43.09 138.11,43.91 125.73,56.29 124,56.29 117.58,62.71 117.58,63.34 117.25,63.67 117.23,63.67 117.23,74.45 116.93,74.76
  BOTTOM w0.216: v2(116.95,77.26) 117.21,77.52 CPU1.AM33 ; v2(132.86,22.28) 132.48,22.28 131.49,23.28 131.49,23.54 131.75,23.8 DM2.115
M_B_DIMB_CKE0: length 71.2
  TOP w0.216: v2(117.69,22.43) v1(117.69,23)
  L4 w0.089: v2(107.25,72.12) 107.25,72.28 107.34,72.37 107.6,72.37 107.69,72.28 107.69,71.1 107.56,70.97 107.16,70.97 107.09,70.9 107.09,70.69 107.16,70.62 107.64,70.62 107.69,70.56 107.69,70.31 107.64,70.26 107.16,70.26 107.09,70.19 107.09,69.98 107.16,69.91 107.56,69.91 107.69,69.78 107.69,69.38 107.41,69.1 107.29,69.1 107,68.81
  L4 w0.203: v2(117.69,22.43) 117.69,23.02 116.62,24.1 116.62,28.22 118.73,30.33 119.26,30.33 120.8,31.87 120.8,33.58 122.49,35.28 122.49,38.3 121.74,39.06 121.74,39.21 121.74,39.47 104.29,56.91 104.29,57.21 104.29,66.1 107,68.81
  BOTTOM w0.216: v2(107.25,72.12) 107.59,72.46 CPU1.AY49 ; DM2.73 117,24.97 116.78,24.75 116.78,23.82 117,23.6 117.28,23.6 117.69,23.19 v2(117.69,22.43)
M_B_DIMB_CKE1: length 72.8
  TOP w0.216: v2(119.45,18.25) v1(119.45,17.68)
  L4 w0.203: v2(119.45,18.25) 117.52,18.25 117.01,18.77 117.01,22.92 116.06,23.86 116.06,28.46 118.5,30.89 119.03,30.89 120.24,32.1 120.24,33.82 121.93,35.51 121.93,38.07 121.18,38.83 121.18,39.23 103.74,56.68 103.74,65.99 107.16,69.42 v2(107.16,69.51)
  BOTTOM w0.089: CPU1.AU50 106.53,74.22 106.53,72.18 106.7,72
  BOTTOM w0.216: 106.7,72 106.83,71.88 106.83,69.84 v2(107.16,69.51) ; DM2.74 v2(119.45,18.25)
M_B_DIMB_CLK_DDR0: length 80
  TOP w0.127: v1(128.25,21.75) 128.31,21.75 v2(128.69,22.12)
  L4 w0.089: 113.69,74.93 113.61,75.01 113.61,76.72 v2(114.08,77.19)
  L4 w0.114: 113.69,74.93 114.22,74.4 114.22,68.32 113.96,68.06 113.49,68.06 113.38,67.94 113.38,67.6 113.49,67.49 114.28,67.49 114.54,67.22 114.54,66.72 114.28,66.46 113.49,66.46 113.38,66.34 113.38,66 113.49,65.88 114.25,65.88 114.51,65.62 114.51,65.12 114.25,64.86 113.49,64.86 113.38,64.74 113.38,64.4 113.49,64.28 113.97,64.28 114.22,64.04 114.22,61.17 122.46,52.93 124.1,52.93 124.3,52.73 124.3,52.37 123.81,51.88 123.81,51.69 123.88,51.62 125.47,51.62 134.64,42.45 134.64,34.92 134.39,34.68 134.09,34.68 133.97,34.55 133.97,34.23 134.09,34.1 134.39,34.1 134.64,33.86 134.64,33.15 134.39,32.9 134.22,32.9 134.09,32.77 134.09,32.45 134.22,32.33 134.39,32.33 134.64,32.08 134.64,31.37 130,26.73 130,25.43 129.28,24.71 129.28,22.72 v2(128.69,22.12)
  BOTTOM w0.127: DM2.101 127.55,22.83 128.11,22.27 128.53,22.27 v2(128.69,22.12) ; v2(114.08,77.19) 114.4,76.87 CPU1.AN38
M_B_DIMB_CLK_DDR1: length 79.7
  TOP w0.127: v2(128.38,19.54) 128.71,19.54 v1(129.01,19.84)
  L4 w0.089: 113.04,74.82 113.04,74.83 113.18,74.97 113.18,77.53 113,77.71 113,78.07 113.18,78.25 113.18,78.79 113.32,78.93 113.63,78.93 113.78,78.78 114.07,78.49 v2(114.09,78.49)
  L4 w0.114: v2(128.38,19.54) 128.15,19.54 128.05,19.64 128.05,24.54 128.8,25.29 128.8,26.58 133.34,31.13 133.34,31.67 133.13,31.89 133.13,32.66 133.34,32.88 133.34,33.79 133.15,33.98 133.15,35.32 133.89,36.05 133.89,42.14 127,49.03 125.31,49.03 124.94,49.4 124.94,49.56 125.51,50.13 125.51,50.5 125.15,50.85 124.78,50.85 124.21,50.28 124.05,50.28 113.47,60.86 113.47,63.67 112.94,64.2 112.94,70.29 113.04,70.39 113.04,74.82
  BOTTOM w0.127: v2(114.09,78.49) 114.35,78.49 114.48,78.36 CPU1.AL38 ; DM2.102 127.85,17.85 127.74,17.96 127.74,18.56 127.96,18.77 127.96,19.12 v2(128.38,19.54)
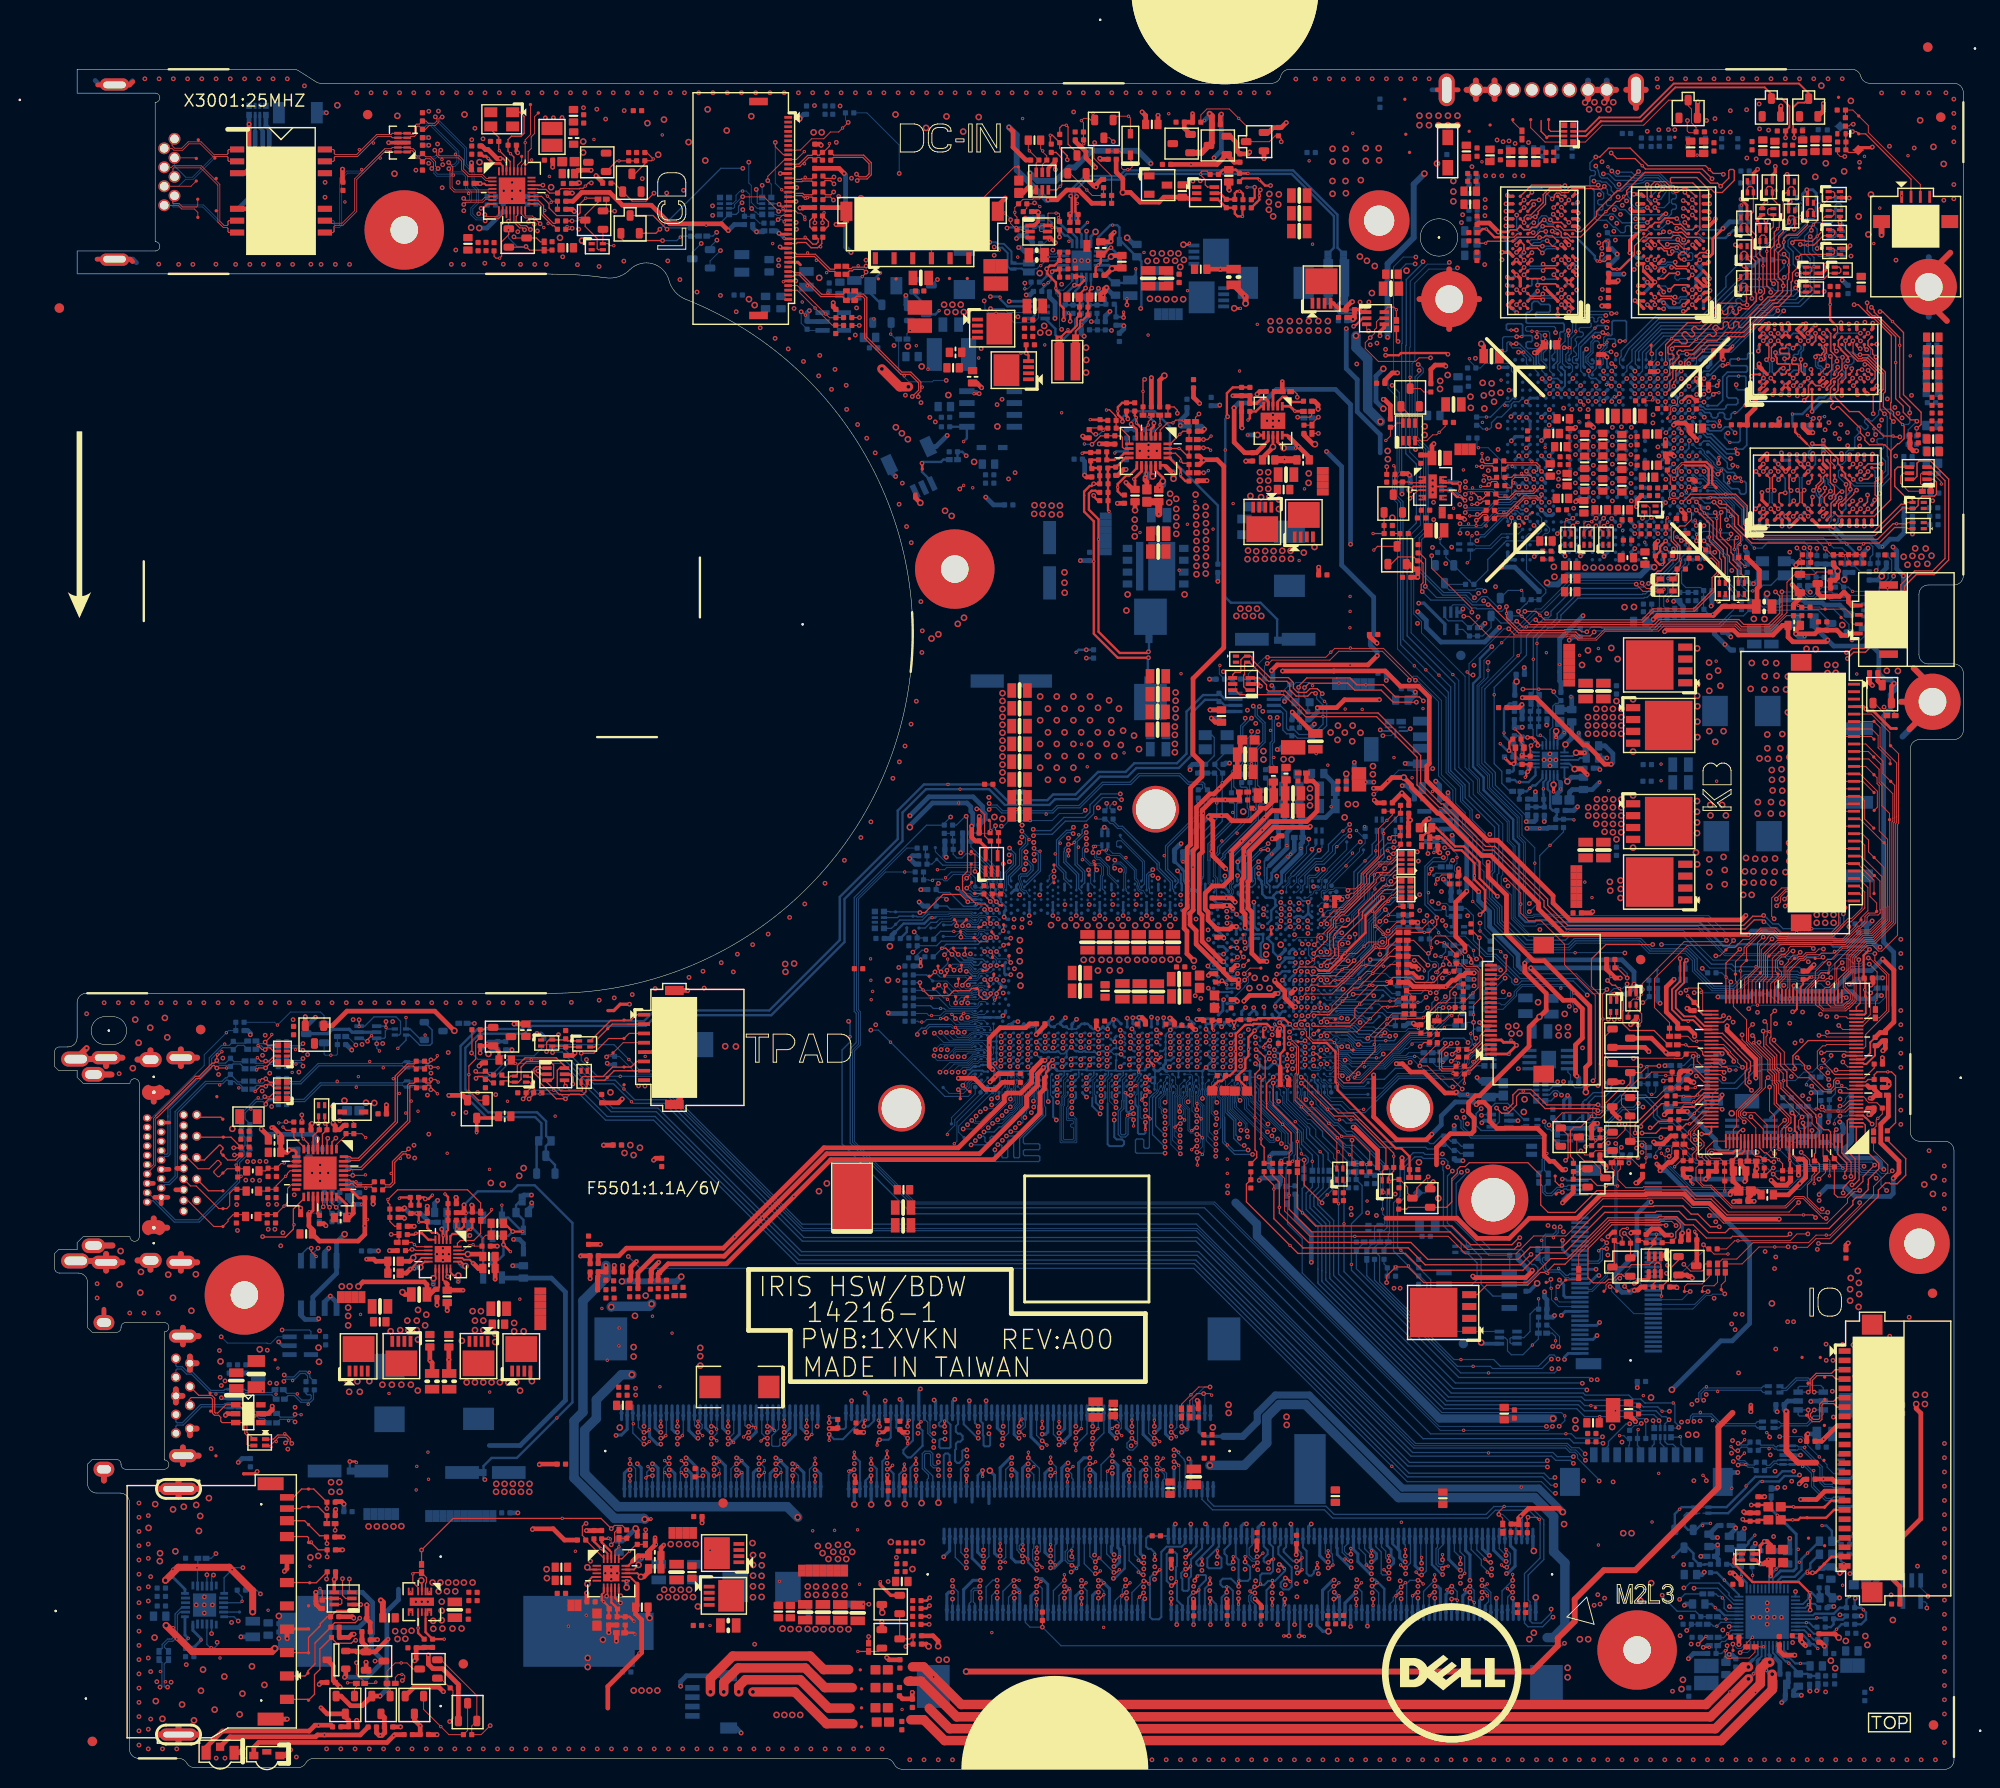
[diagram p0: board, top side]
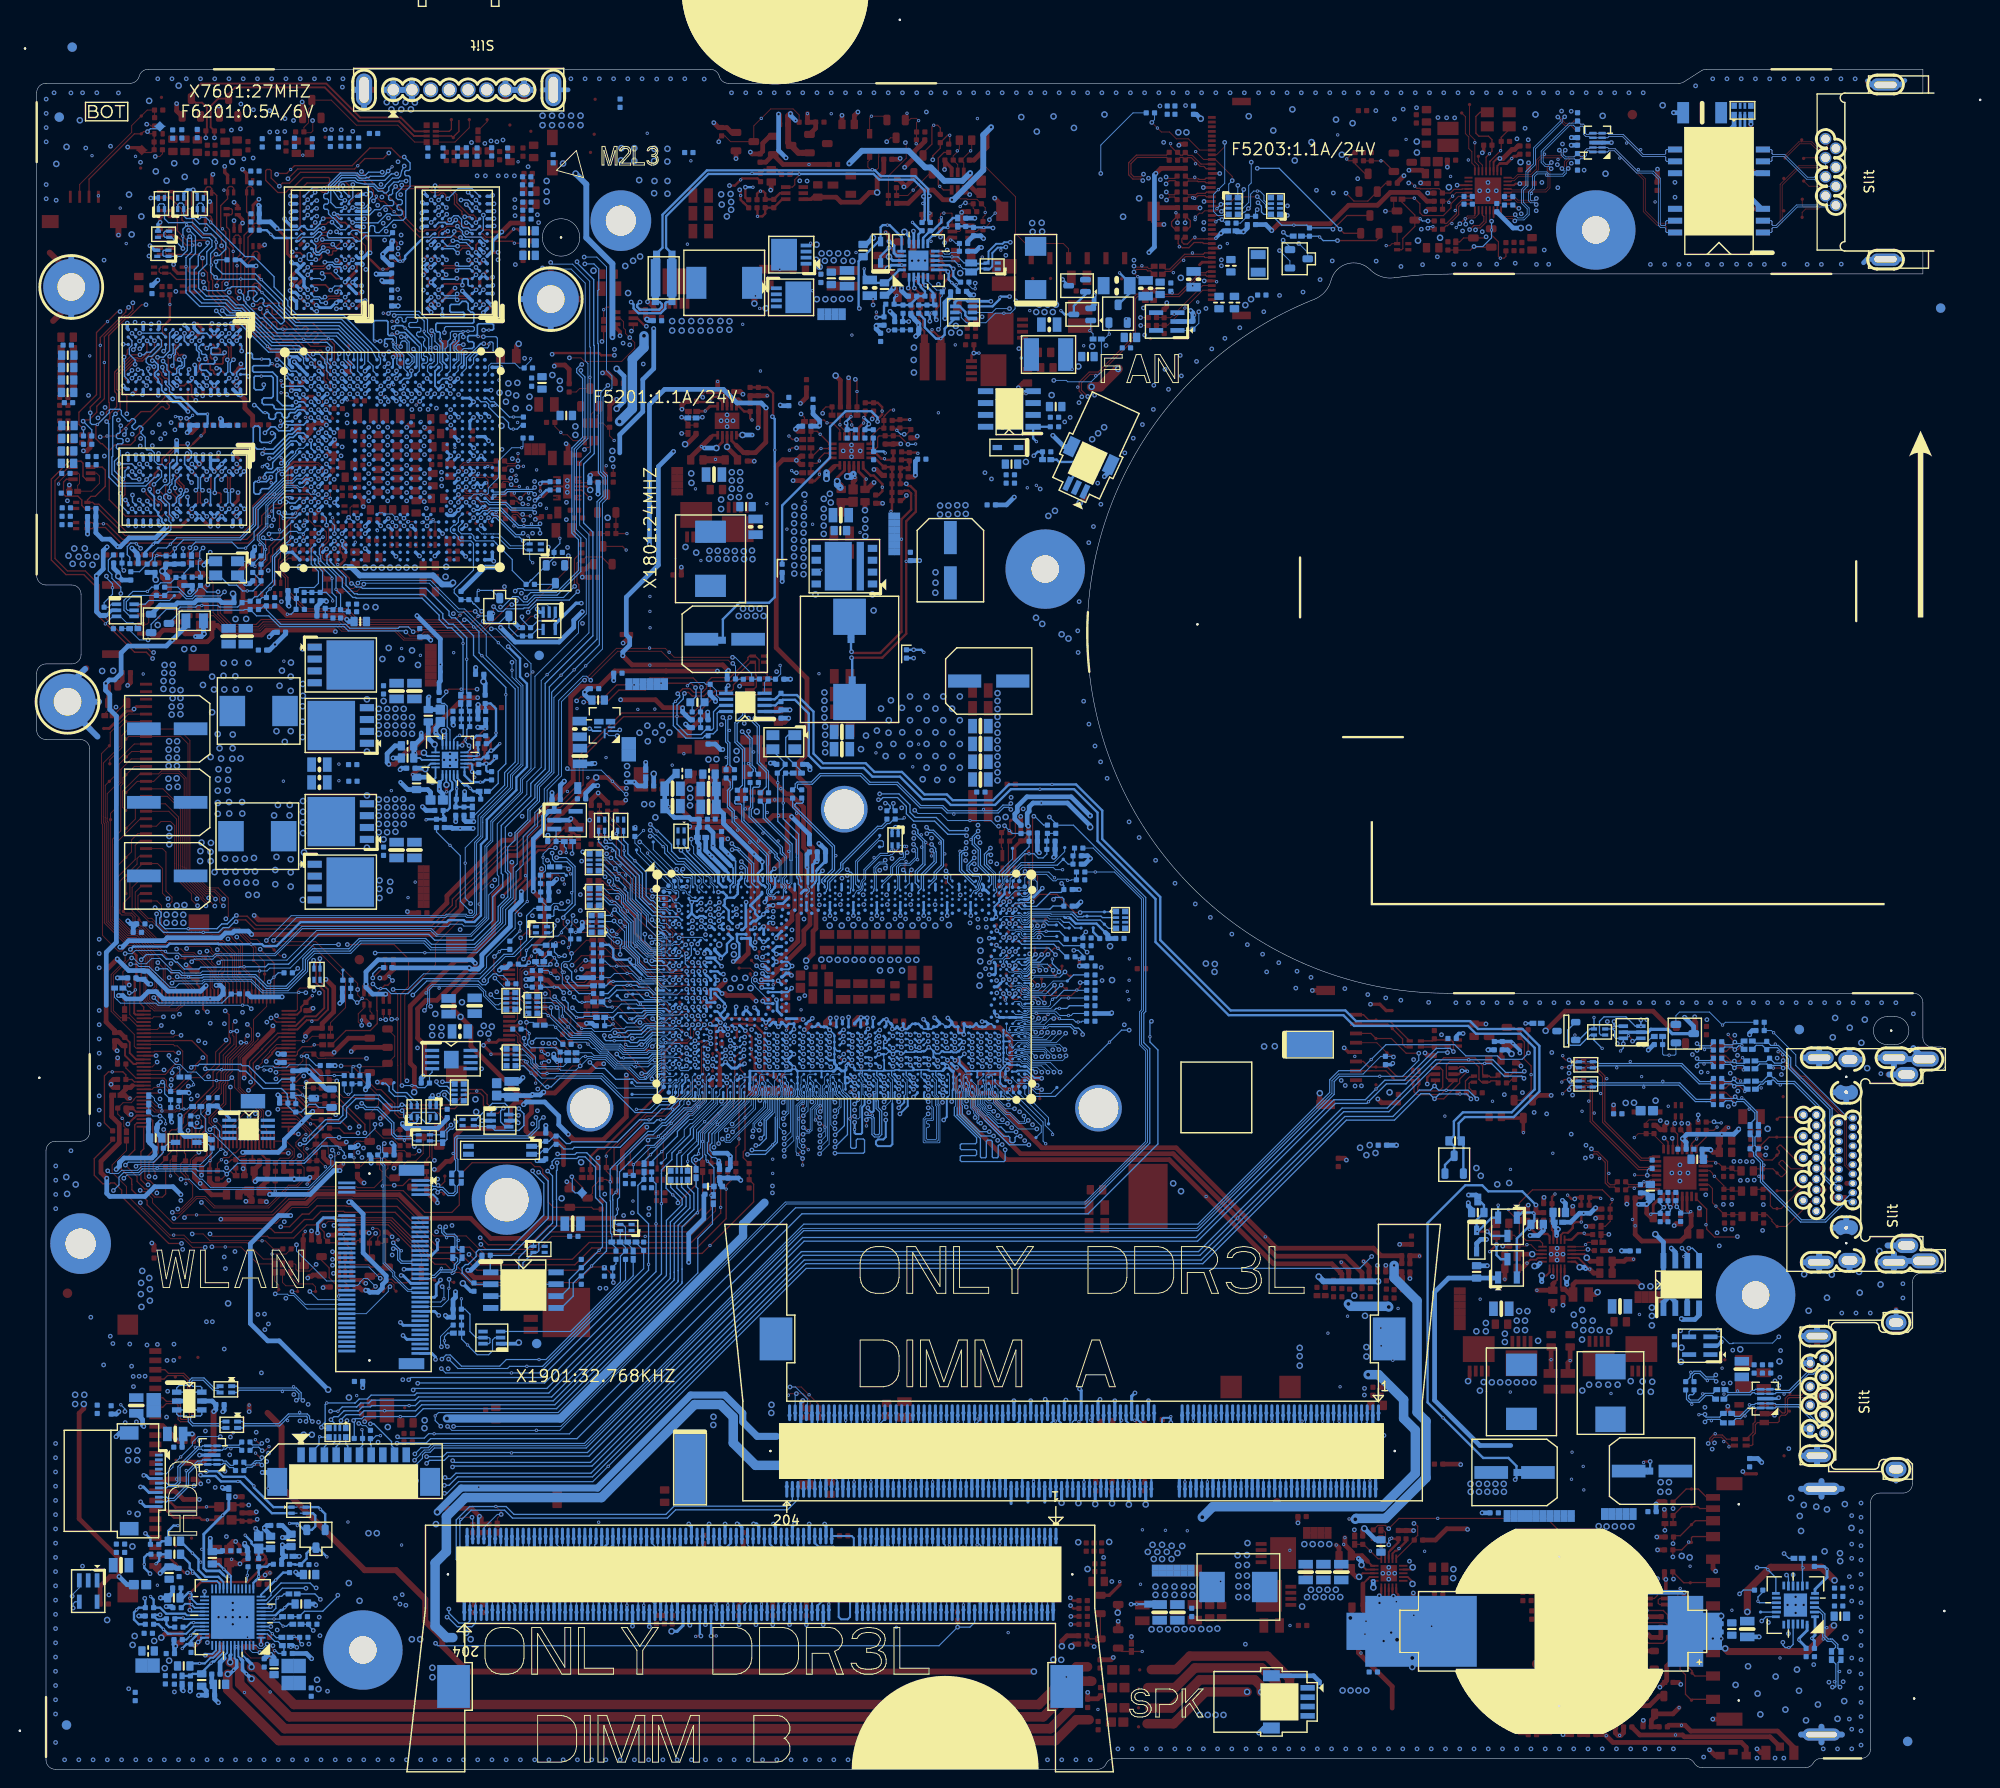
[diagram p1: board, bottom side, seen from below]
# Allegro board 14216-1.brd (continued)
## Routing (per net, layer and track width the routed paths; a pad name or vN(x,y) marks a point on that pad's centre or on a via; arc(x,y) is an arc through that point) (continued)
M_B_DIMB_CLK_DDR#0: length 80.3
  TOP w0.127: v1(129.27,23.14) 128.88,22.76 v2(128.65,22.76)
  L4 w0.089: 113.53,74.77 113.52,74.78 113.52,74.79 113.53,74.8 113.49,74.84 113.49,74.86 113.42,74.93 113.42,76.8 113.68,77.06 113.68,77.47 v2(114.05,77.85)
  L4 w0.114: v2(128.65,22.76) 128.91,22.76 129.05,22.9 129.05,24.81 129.77,25.53 129.77,26.82 134.41,31.46 134.41,31.98 134.3,32.1 134.13,32.1 133.87,32.36 133.87,32.87 134.13,33.13 134.3,33.13 134.41,33.24 134.41,33.76 134.3,33.88 134,33.88 133.74,34.14 133.74,34.64 134,34.9 134.3,34.9 134.41,35.02 134.41,42.35 125.37,51.39 123.79,51.39 123.58,51.6 123.58,51.97 124.07,52.47 124.07,52.64 124.01,52.7 122.37,52.7 113.99,61.08 113.99,63.94 113.88,64.06 113.4,64.06 113.15,64.3 113.15,64.84 113.4,65.08 114.15,65.08 114.28,65.21 114.28,65.53 114.15,65.66 113.4,65.66 113.15,65.9 113.15,66.44 113.4,66.68 114.18,66.68 114.31,66.81 114.31,67.13 114.18,67.26 113.4,67.26 113.15,67.5 113.15,68.04 113.4,68.29 113.86,68.29 113.99,68.41 113.99,74.31 113.53,74.77
  BOTTOM w0.127: DM2.103 128.15,24.04 127.79,23.68 127.79,22.93 128.21,22.51 128.4,22.51 v2(128.65,22.76) ; v2(114.05,77.85) 114.46,77.85 114.59,77.72 114.59,77.62 CPU1.AM38
M_B_DIMB_CLK_DDR#1: length 79.7
  TOP w0.127: v1(127.87,19.08) 128.07,18.88 v2(128.4,18.88)
  L4 w0.089: 112.81,74.82 112.81,74.89 112.99,75.08 112.99,77.45 112.81,77.63 112.81,78.15 112.99,78.33 112.99,78.87 113.25,79.12 v2(114,79.12)
  L4 w0.114: 112.81,74.82 112.81,70.48 112.72,70.39 112.72,64.11 113.24,63.58 113.24,60.77 123.95,50.06 124.3,50.06 124.87,50.63 125.05,50.63 125.28,50.4 125.28,50.22 124.71,49.65 124.71,49.3 125.21,48.8 126.91,48.8 133.66,42.04 133.66,36.15 132.93,35.41 132.93,33.89 133.12,33.7 133.12,32.97 132.9,32.76 132.9,31.79 133.12,31.58 133.12,31.23 128.57,26.68 128.57,25.38 127.82,24.64 127.82,19.46 v2(128.4,18.88)
  BOTTOM w0.127: v2(114,79.12) 114.2,79.12 CPU1.AK38 ; v2(128.4,18.88) 127.99,18.46 127.99,18.06 128.45,17.59 DM2.104
M_B_DIMB_CS#0: length 78.1
  TOP w0.216: v2(131.6,18.23) v1(131.6,17.61)
  L4 w0.089: 117.97,74.37 117.97,75.52 118.3,75.85 118.3,77.44 v2(117.89,77.84)
  L4 w0.203: v2(131.6,18.23) 131.88,18.5 132.18,18.5 132.7,17.99 133.1,17.99 133.38,18.27 133.38,18.29 133.38,18.29 133.38,19.89 133.38,19.9 133.38,20.3 133.38,20.3 133.38,20.67 133.38,20.67 135.17,22.45 135.17,23.48 136.1,24.41 136.1,26.17 140.55,30.62 140.55,43.05 126.19,57.41 124.46,57.41 118.7,63.18 118.7,63.34 117.97,64.07 117.97,74.37
  BOTTOM w0.216: v2(131.6,18.23) 131.45,18.08 DM2.114 ; CPU1.AM32 117.96,77.84 v2(117.89,77.84)
M_B_DIMB_CS#1: length 78.1
  TOP w0.216: v2(135.08,21.56) v1(135.08,22.13)
  L4 w0.089: v2(117.88,79.15) 118.48,78.55 118.48,75.78 118.26,75.56 118.26,74.33
  L4 w0.203: 118.26,74.33 118.26,64.4 124.69,57.97 126.42,57.97 141.1,43.29 141.1,30.39 136.65,25.94 136.65,24.18 135.73,23.25 135.73,21.81 135.47,21.56 v2(135.08,21.56)
  BOTTOM w0.216: CPU1.AK32 117.96,79.15 v2(117.88,79.15) ; DM2.121 133.55,23.76 133.94,23.38 133.94,20.98 134.19,20.73 134.46,20.73 134.71,20.98 134.71,21.19 v2(135.08,21.56)
M_B_DIMB_ODT0: length 44.3
  TOP w0.254: v2(132.05,14.28) 131.63,14.28 131.63,14.27 v1(131.49,14.27) ; R1209.2 v2(93.55,16.37)
  L3 w0.254: v2(93.55,16.37) 93.67,16.25 95.09,16.25 96.64,14.71 101.05,14.71 102.46,13.29 131.38,13.29 132.05,13.96 v2(132.05,14.28)
  BOTTOM w0.254: DM2.116 v2(132.05,14.28)
M_B_DIMB_ODT1: length 45.5
  TOP w0.254: v1(133.69,14.22) 133.65,14.27 v2(133.14,14.27) ; R1210.2 v2(93.56,15.52)
  L3 w0.254: v2(93.56,15.52) 93.79,15.74 94.88,15.74 96.43,14.2 100.84,14.2 102.25,12.78 131.65,12.78 v2(133.14,14.27)
  BOTTOM w0.254: DM2.120 133.25,14.39 v2(133.14,14.27)
M_B_DQ0: length 71.5
  TOP w0.14: v2(136.85,18.23) 137.06,18.23 v1(137.4,18.57)
  L4 w0.089: v2(118.78,67.91) 119.37,67.31 119.37,65.37 119.92,64.81
  L4 w0.127: v2(136.85,18.23) 136.05,18.23 135.92,18.36 135.92,19.92 136.24,20.24 137.13,21.13 137.13,22.8 137.96,23.64 137.96,25.39 142.6,30.03 142.6,30.69 142.6,43.84 126.99,59.46 125.31,59.46 121.56,63.21 121.53,63.21 119.92,64.81
  BOTTOM w0.14: v2(118.78,67.91) 117.79,68.9 117.79,71.86 118.34,72.41 CPU1.AY31 ; DM2.132 v2(136.85,18.23)
M_B_DQ1: length 72.4
  TOP w0.14: v2(136.25,21.56) 136.45,21.56 v1(136.76,21.87)
  L4 w0.089: v2(118.79,66.6) 119.19,66.2 119.19,65.64 119.19,65.02 119.45,64.76
  L4 w0.127: 119.45,64.76 125.15,59.06 126.83,59.06 142.21,43.68 142.21,30.52 142.21,30.2 137.57,25.56 137.57,23.8 136.73,22.96 136.73,21.29 136.08,20.63 135.9,20.63 135.7,20.83 135.7,21.01 v2(136.25,21.56)
  BOTTOM w0.089: 117.67,72.1 117.93,72.37 117.96,72.38 117.98,72.41 118,72.43 118.07,72.56 118.1,72.63 118.18,72.83 CPU1.AW31
  BOTTOM w0.14: 117.67,72.1 117.46,71.89 117.46,67.94 v2(118.79,66.6) ; v2(136.25,21.56) 136.32,21.56 136.75,21.99 136.75,22.4 136.7,22.45 136.7,23.02 136.55,23.17 DM2.131
M_B_DQ2: length 71.8
  TOP w0.14: v2(139.25,18.23) v1(139.25,17.56)
  L4 w0.127: v2(139.25,18.23) 139.91,18.23 140.03,18.36 140.03,24.53 144.67,29.18 144.67,31.54 144.67,31.55 144.67,45.23 142.26,47.65 141.73,47.65 139.17,50.2 139.17,50.76 134.82,55.11 134.27,55.11 124.85,64.52 121.9,64.52 120.85,65.57 120.85,66.09 v2(120.41,66.54)
  BOTTOM w0.089: v2(120.41,66.54) 119.6,67.35 119.6,72.36 CPU1.AY29
  BOTTOM w0.14: DM2.140 v2(139.25,18.23)
M_B_DQ3: length 72.7
  TOP w0.14: v1(140.32,21.87) 140.63,21.56 v2(140.87,21.56)
  L4 w0.127: v2(120.4,67.18) 120.81,67.59 121.41,67.59 121.53,67.47 121.53,65.2 121.99,64.74 125.19,64.74 134.43,55.5 134.99,55.5 139.57,50.92 139.57,50.37 141.89,48.04 142.42,48.04 145.07,45.4 145.07,31.71 145.07,31.71 145.07,29.01 140.43,24.37 140.43,22.01 v2(140.87,21.56)
  BOTTOM w0.089: v2(120.4,67.18) 119.77,67.8 119.77,72.11 119.96,72.3 119.96,72.83 CPU1.AW29
  BOTTOM w0.14: DM2.141 139.55,23.64 140.24,22.95 140.24,22.19 140.71,21.72 140.71,21.72 v2(140.87,21.56)
M_B_DQ4: length 73.4
  TOP w0.14: v2(136.25,22.83) v1(136.25,23.39)
  L4 w0.127: v2(136.25,22.83) 136.25,23.03 137.18,23.96 137.18,25.72 141.82,30.36 141.82,43.52 126.66,58.67 124.99,58.67 118.79,64.86 v2(118.79,65.95)
  BOTTOM w0.089: 117.61,72.37 117.85,72.52 117.91,72.64 117.94,72.7 117.95,72.75 117.95,73.37 CPU1.AV31
  BOTTOM w0.14: v2(136.25,22.83) 135.95,23.13 DM2.129 ; 117.61,72.37 117.12,71.88 117.12,66.6 116.99,66.48 116.64,66.48 116.52,66.6 116.52,67.34 116.39,67.47 115.76,67.47 115.63,67.34 115.63,66.08 115.76,65.95 v2(118.79,65.95)
M_B_DQ5: length 73.7
  TOP w0.14: v1(137.4,19.97) 137.02,19.6 v2(136.85,19.6)
  L4 w0.089: v2(118.79,68.56) 119.55,67.8 119.55,65.5 119.82,65.22
  L4 w0.127: 119.82,65.22 121.54,63.5 121.82,63.5 125.48,59.85 127.15,59.85 143,44.01 143,30.85 143,29.87 138.36,25.23 138.36,23.47 137.55,22.66 137.55,19.72 137.42,19.6 v2(136.85,19.6)
  BOTTOM w0.089: v2(118.79,68.56) 119.23,69 119.23,72.57 119.24,72.58 119.29,72.71 119.3,72.76 119.3,72.83 119.23,73.02 119.23,73.2 119.3,73.38 119.3,73.45 119.3,73.73 119.3,73.77 119.31,73.95 119.31,73.96 119.31,74.21 119.11,74.41 CPU1.AU31
  BOTTOM w0.14: v2(136.85,19.6) 136.25,18.99 DM2.130
M_B_DQ6: length 72.9
  TOP w0.14: v1(139.81,19.97) 139.41,19.57 v2(139.28,19.57)
  L4 w0.127: v2(120.43,65.88) 120.43,65.69 121.81,64.31 124.51,64.31 134.1,54.72 134.66,54.72 138.78,50.6 138.78,50.04 141.56,47.26 142.09,47.26 144.28,45.07 144.28,31.38 144.28,29.34 139.64,24.7 139.64,21.5 138.86,20.73 138.86,19.99 v2(139.28,19.57)
  BOTTOM w0.089: CPU1.AV29 119.58,73.51 119.44,73.24 119.4,73.16 119.4,73.08 119.41,73.05 119.43,72.99 119.46,72.92 119.47,72.9 119.48,72.86 119.48,72.75 119.47,72.67 119.42,72.54 119.42,66.9 v2(120.43,65.88)
  BOTTOM w0.14: DM2.142 139.85,19 v2(139.28,19.57)
M_B_DQ7: length 73.7
  TOP w0.14: v1(140.87,23.4) v2(140.87,22.83)
  L4 w0.127: v2(140.87,22.83) 140.87,24.26 145.46,28.85 145.46,31.87 145.46,45.56 142.58,48.44 142.05,48.44 139.96,50.53 139.96,50.76 139.96,50.76 139.96,51.09 139.96,52.11 139.24,52.84 138.21,52.84 135.15,55.9 134.59,55.9 125.53,64.96 122.08,64.96 121.75,65.29 121.75,69.04 121.62,69.17 120.98,69.17 120.85,69.04 120.85,68.29 v2(120.4,67.83)
  BOTTOM w0.089: v2(120.4,67.83) 119.95,68.28 119.95,72.04 120.14,72.23 120.14,73.13 119.93,73.34 119.93,74.06 CPU1.AU29
  BOTTOM w0.14: v2(140.87,22.83) 140.87,22.89 140.15,23.61 DM2.143
M_B_DQ8: length 69.7
  TOP w0.14: v1(119.87,68.74) 120.25,69.12 v2(120.43,69.12)
  L3 w0.089: v2(120.43,69.12) 120.83,68.72 120.83,65.72 120.82,65.7 120.82,65.67
  L3 w0.127: v2(97.54,21.56) 97.84,21.26 97.84,20.38 97.72,20.25 97.44,20.25 97.31,20.38 97.31,20.81 96.7,21.42 96.7,26.43 101.51,31.24 101.51,33.67 102.34,34.5 102.34,37.06 102.89,37.62 102.97,37.62 120.66,55.3 120.66,65.51 120.82,65.67
  BOTTOM w0.089: v2(120.43,69.12) 120.94,69.63 120.94,70.67 120.49,71.12 120.49,71.82 120.77,72.1 CPU1.AY27
  BOTTOM w0.14: v2(97.54,21.56) 97.48,21.56 96.35,22.69 DM2.5
M_B_DQ9: length 70.4
  TOP w0.14: v2(120.4,69.77) 120.61,69.77 v1(120.89,69.5)
  L3 w0.089: 120.21,65.52 120,65.73 120,69.37 v2(120.4,69.77)
  L3 w0.127: 120.21,65.52 120.26,65.47 120.26,55.47 102.81,38.01 102.73,38.01 101.94,37.22 101.94,34.66 101.12,33.84 101.12,31.4 96.31,26.59 96.31,20.83 97.01,20.12 97.01,19.03 96.88,18.9 96.63,18.9 96.5,19.03 96.5,19.47 96.37,19.59 v2(96.06,19.59)
  BOTTOM w0.089: v2(120.4,69.77) 120.76,70.14 120.76,70.6 120.31,71.05 120.31,71.89 120.5,72.08 120.5,72.83 CPU1.AW27
  BOTTOM w0.14: DM2.6 96.65,19 v2(96.06,19.59)
M_B_DQ10: length 69.7
  TOP w0.14: v1(121.65,66.32) 122.02,66.7 v2(122.2,66.7)
  L3 w0.089: v2(122.2,66.7) 122.2,66.76 121.95,67 121.74,67 121.68,66.94 121.68,64.94 121.68,64.94
  L3 w0.127: v2(99.37,23.47) 99.37,26.68 103.68,30.99 103.68,33.47 104.25,34.04 104.25,34.04 104.43,34.22 104.43,36.7 116.23,48.51 116.41,48.51 116.66,48.25 116.84,48.25 117.02,48.43 117.02,48.61 116.77,48.87 116.77,49.05 117.05,49.33 117.23,49.33 117.48,49.07 117.66,49.07 117.84,49.25 117.84,49.43 117.59,49.68 117.59,49.86 117.77,50.04 117.95,50.04 118.2,49.79 118.38,49.79 118.56,49.97 118.56,50.15 118.31,50.4 118.31,50.58 118.49,50.76 118.67,50.76 118.92,50.51 119.1,50.51 119.28,50.69 119.28,50.87 119.03,51.12 119.03,51.3 119.21,51.48 119.39,51.48 119.64,51.23 119.82,51.23 120,51.41 120,51.59 119.75,51.84 119.75,52.02 119.93,52.2 120.1,52.2 120.36,51.95 120.54,51.95 120.72,52.13 120.72,52.31 120.46,52.56 120.46,52.74 120.64,52.92 120.82,52.92 121.08,52.67 121.26,52.67 121.43,52.85 121.43,53.03 121.18,53.28 121.18,53.46 121.36,53.64 121.54,53.64 121.79,53.39 121.97,53.39 122.15,53.57 122.15,53.75 121.9,54 121.9,54.18 122.33,54.61 122.33,64.23 121.68,64.88 121.68,64.94
  BOTTOM w0.089: CPU1.AY25 122.04,72.38 122.04,71.48 122.61,70.92 122.61,67.11 v2(122.2,66.7)
  BOTTOM w0.14: v2(99.37,23.47) 99.35,23.48 DM2.15
M_B_DQ11: length 70.5
  TOP w0.14: v1(122.79,65.82) 122.55,66.06 v2(122.21,66.06)
  L3 w0.089: v2(122.21,66.06) 121.85,65.7 121.85,65.13 121.88,65.11
  L3 w0.127: v2(99.37,22.2) 99.85,22.67 99.85,26.5 104.68,31.33 104.68,33.92 104.82,34.06 104.82,36.54 112.45,44.17 112.63,44.17 112.84,43.96 113.02,43.96 113.2,44.14 113.2,44.31 112.99,44.53 112.99,44.71 113.17,44.89 113.35,44.89 113.6,44.63 113.78,44.63 113.96,44.81 113.96,44.99 113.71,45.25 113.71,45.43 113.89,45.61 114.07,45.61 114.32,45.35 114.5,45.35 114.68,45.53 114.68,45.71 114.43,45.96 114.43,46.14 114.61,46.32 114.79,46.32 115.04,46.07 115.22,46.07 115.4,46.25 115.4,46.43 115.15,46.68 115.15,46.86 115.32,47.04 115.5,47.04 115.76,46.79 115.94,46.79 116.12,46.97 116.12,47.15 115.86,47.4 115.86,47.58 116.14,47.86 117.01,47.86 117.16,48.01 122.73,53.58 122.73,64.26 121.88,65.11
  BOTTOM w0.089: v2(122.21,66.06) 122.78,66.63 122.78,70.99 122.22,71.56 122.22,72.11 122.41,72.29 122.41,72.52 122.39,72.55 122.33,72.67 122.33,72.89 CPU1.AW25
  BOTTOM w0.14: v2(99.37,22.2) 99.37,22.2 99.95,22.78 DM2.17
M_B_DQ12: length 70.1
  TOP w0.14: v2(120.36,70.41) v1(120.36,71.02)
  L3 w0.127: v2(96.06,18.23) 95.61,18.68 95.61,20.52 95.48,20.65 95.16,20.65 95.03,20.78 95.03,21.03 95.16,21.16 95.41,21.16 95.54,21.29 95.54,21.54 95.41,21.67 95.16,21.67 95.03,21.79 95.03,22.05 95.16,22.18 95.48,22.18 95.61,22.3 95.61,26.45 100.72,31.57 100.72,34.7 100.98,34.96 100.98,36.22 100.99,36.22 100.99,36.84 102.55,38.4 102.64,38.4 119.87,55.63 119.87,65.55 119.8,65.63 119.8,69.85 v2(120.36,70.41)
  BOTTOM w0.089: CPU1.AV27 120.32,73.2 120.32,72.15 120.13,71.96 120.13,71.29 120.13,70.64 v2(120.36,70.41)
  BOTTOM w0.14: v2(96.06,18.23) 96.05,18.22 DM2.4
M_B_DQ13: length 71.5
  TOP w0.14: v2(122.19,69.96) 122.33,69.96 v1(122.66,69.63)
  L3 w0.127: v2(122.19,69.96) 122.76,69.39 122.76,65.03 123.51,64.27 123.51,54.45 123.52,54.45 123.52,53.26 113.43,43.17 112.56,43.17 106.51,37.11 106.51,33.99 105.47,32.95 105.47,31.01 100.71,26.24 100.71,21.71 100.01,21.01 100.01,20.48 100.24,20.24 v2(100.83,20.24)
  BOTTOM w0.089: CPU1.AU27 121.54,74.41 121.74,74.21 121.74,73.96 121.73,73.94 121.73,73.38 121.71,73.33 121.66,73.2 121.66,73 121.68,72.96 121.73,72.84 121.73,72.73 121.71,72.67 121.66,72.55 121.66,72.05 121.67,72.03 121.67,70.47 v2(122.19,69.96)
  BOTTOM w0.14: DM2.16 99.65,19.53 100.36,20.24 v2(100.83,20.24)
M_B_DQ14: length 71
  TOP w0.14: v2(122.2,70.59) v1(122.2,71.28)
  L3 w0.127: v2(97.54,22.83) 97.22,22.83 97.09,22.96 97.09,24.03 97.22,24.16 97.64,24.16 97.77,24.29 97.77,24.54 97.64,24.67 97.22,24.67 97.09,24.79 97.09,25.05 97.22,25.18 97.72,25.18 97.84,25.3 97.84,25.56 97.72,25.68 97.22,25.68 97.09,25.81 97.09,26.01 97.28,26.19 97.72,26.19 97.84,26.32 97.84,27.01 101.91,31.08 101.91,33.51 102.64,34.25 102.73,34.33 102.73,36.89 103.06,37.22 103.13,37.22 121.05,55.14 121.05,64.49 121.03,64.51 121.03,69.12 120.84,69.31 120.84,71.91 120.97,72.04 121.31,72.04 122.2,71.15 v2(122.2,70.59)
  BOTTOM w0.089: v2(122.2,70.59) 121.85,70.94 121.85,72.05 121.83,72.44 121.83,72.51 121.86,72.58 121.91,72.69 121.91,72.88 121.87,72.97 121.83,73.05 121.83,73.15 121.85,73.2 121.91,73.34 121.91,73.54 CPU1.AV25
  BOTTOM w0.14: v2(97.54,22.83) 97.34,22.83 96.95,23.22 DM2.7
M_B_DQ15: length 71.9
  TOP w0.14: v2(122.25,65.38) v1(122.25,64.67)
  L3 w0.127: v2(122.25,65.38) 122.54,65.09 122.54,64.94 123.12,64.36 123.12,53.42 113.26,43.56 112.4,43.56 106.12,37.28 106.12,34.15 105.07,33.11 105.07,31.17 100.31,26.41 100.31,21.88 99.52,21.09 99.52,18.78 99.85,18.44 100.3,18.44 v2(100.82,18.96)
  BOTTOM w0.089: CPU1.AU25 122.42,74.11 122.42,73.32 122.51,73.23 122.51,72.74 122.53,72.67 122.57,72.59 122.58,72.55 122.58,72.22 122.4,72.03 122.4,71.63 122.96,71.06 122.96,66.08 v2(122.25,65.38)
  BOTTOM w0.14: DM2.18 100.25,18.59 100.62,18.96 v2(100.82,18.96)
M_B_DQ16: length 85.7
  TOP w0.14: v2(146.24,20.8) 145.96,20.8 v1(145.65,21.11)
  L4 w0.089: 118.79,74.8 118.67,74.92 118.67,75.43 118.95,75.71 118.95,76.78 v2(119.36,77.19)
  L4 w0.127: v2(146.24,20.8) 146.8,21.36 146.8,23.2 150.71,27.11 150.71,44.65 150.51,44.84 150.51,48.76 147.24,52.03 147.24,52.75 141.98,58.01 141.4,58.01 140.02,59.38 140.02,60.22 140.03,60.22 140.03,60.64 137.97,62.7 135.3,62.7 133.63,64.37 132.41,64.37 129.4,67.38 128.9,67.87 128.9,67.9 127.05,69.75 126.26,69.75 125.04,70.96 123.82,70.96 123.57,70.71 123.57,69.02 123.44,68.89 122.98,68.89 122.85,69.02 122.85,70.83 121.45,72.23 121.36,72.23 118.83,74.76 118.79,74.8
  BOTTOM w0.14: v2(146.24,20.8) 146.32,20.8 146.69,21.17 146.69,21.17 146.74,21.23 146.74,24.96 DM2.165 ; v2(119.36,77.19) 119.43,77.19 CPU1.AM29
M_B_DQ17: length 87.3
  TOP w0.14: v2(146.24,22.07) v1(146.24,22.69)
  L4 w0.089: v2(119.36,78.49) 118.76,77.89 118.76,75.79 118.49,75.52 118.49,74.79 118.65,74.63
  L4 w0.127: 118.65,74.63 121.27,72.02 121.36,72.02 122.64,70.74 122.64,67.16 122.77,67.04 123.65,67.04 123.78,67.16 123.78,70.62 123.91,70.75 124.95,70.75 126.17,69.53 126.97,69.53 128.69,67.81 128.69,67.79 131.88,64.59 132.32,64.15 133.29,64.15 135.14,62.31 137.8,62.31 139.63,60.48 139.63,59.22 141.24,57.61 141.82,57.61 146.84,52.58 146.84,51.87 150.12,48.6 150.12,44.68 150.31,44.48 150.31,27.27 146.24,23.2 v2(146.24,22.07)
  BOTTOM w0.14: CPU1.AK29 119.48,78.49 v2(119.36,78.49) ; v2(146.24,22.07) 146.15,22.16 DM2.163
M_B_DQ18: length 86.3
  TOP w0.14: v1(150.4,22.64) v2(150.4,21.98)
  L4 w0.089: 125.54,72.6 125.18,72.97 123.85,72.97 123.46,73.36 122.54,73.36 122.4,73.5 122.4,73.62 122.59,73.81 122.59,73.94 122.47,74.06 122.34,74.06 122.15,73.87 122.03,73.87 121.9,74 121.9,74.13 122.09,74.32 122.09,74.44 121.96,74.57 121.84,74.57 121.65,74.38 121.52,74.38 120.82,75.09 120.82,75.7 120.78,75.74 120.78,77.38 v2(120.31,77.84)
  L4 w0.127: 125.54,72.6 125.87,72.28 127.04,72.28 127.99,71.33 129.8,71.33 135.04,66.09 135.56,65.57 139.14,65.57 142.43,62.29 143.43,62.29 143.92,61.8 143.92,60.11 150.1,53.93 150.1,53.22 154.03,49.28 154.03,32.06 153.91,31.93 153.69,31.93 153.56,31.81 153.56,31.49 153.69,31.37 153.91,31.37 154.03,31.24 154.03,30.99 153.91,30.86 153.69,30.86 153.56,30.73 153.56,30.48 153.69,30.35 153.91,30.35 154.03,30.22 154.03,29.97 153.91,29.84 153.69,29.84 153.56,29.72 153.56,29.46 153.69,29.34 153.91,29.34 154.03,29.21 154.03,28.95 153.91,28.83 153.69,28.83 153.56,28.7 153.56,28.41 153.68,28.3 153.91,28.3 154.03,28.17 154.03,28 153.56,27.53 153.56,25.92 150.68,23.04 150.68,22.8 151,22.48 151,21.92 150.87,21.8 150.58,21.8 v2(150.4,21.98)
  BOTTOM w0.14: v2(120.31,77.84) 120.64,78.17 CPU1.AL28 ; v2(150.4,21.98) 150.4,22.68 149.75,23.32 DM2.175
M_B_DQ19: length 86.4
  TOP w0.14: v2(150.4,20.62) 150.49,20.62 v1(150.86,20.98)
  L4 w0.127: v2(150.4,20.62) 151.39,21.61 151.39,23.19 153.96,25.76 153.96,27.37 154.43,27.84 154.43,49.45 150.49,53.38 150.49,54.1 144.32,60.27 144.32,61.96 143.6,62.68 142.59,62.68 139.3,65.97 135.47,65.97 133.93,67.51 129.89,71.55 128.08,71.55 127.13,72.5 125.96,72.5 125.27,73.18 123.91,73.18 123.54,73.56 123.25,73.56 121.72,75.09 121.72,78.58 121.39,78.91 120.68,78.91 v2(120.26,78.49)
  BOTTOM w0.14: DM2.177 150.35,23.3 150.85,22.79 150.85,21.08 150.4,20.62 v2(150.4,20.62) ; CPU1.AK28 120.59,78.82 v2(120.26,78.49)
M_B_DQ20: length 83.6
  TOP w0.14: v2(147.64,20.23) v1(147.64,20.81)
  L4 w0.127: v2(119.25,75.19) 119.25,75.13 121.94,72.44 123.06,72.44 123.48,72.02 124.6,72.02 126.44,70.18 127.23,70.18 129.34,68.08 129.34,68.05 129.58,67.81 131.89,65.5 132.07,65.5 132.46,65.9 132.64,65.9 132.82,65.72 132.82,65.54 132.43,65.14 132.43,64.96 132.59,64.8 134.24,64.8 135.54,63.5 138.28,63.5 141.85,59.93 141.85,59.25 148.03,53.07 148.03,52.36 151.3,49.09 151.3,45.17 151.49,44.97 151.49,26.78 147.59,22.88 147.59,20.97 146.69,20.07 146.69,19.44 146.82,19.31 147.08,19.31 147.21,19.44 147.21,19.8 v2(147.64,20.23)
  BOTTOM w0.14: v2(147.64,20.23) 146.45,19.04 DM2.164 ; v2(119.25,75.19) 119.63,75.57 CPU1.AR29
M_B_DQ21: length 85.3
  TOP w0.14: v2(147.63,18.96) 147.43,18.96 v1(147.05,18.57)
  L4 w0.089: v2(119.36,76.54) 119.15,76.33 119.15,75.65 118.85,75.35 118.85,75.02 119.08,74.79 119.11,74.79 119.15,74.75
  L4 w0.127: 119.15,74.75 121.45,72.45 121.54,72.45 121.77,72.23 122.97,72.23 123.39,71.8 124.51,71.8 126.35,69.97 127.14,69.97 129.12,67.99 129.12,67.96 129.49,67.59 132.5,64.58 132.64,64.58 133.72,64.58 133.98,64.58 135.46,63.1 138.13,63.1 140.91,60.31 140.91,59.06 141,58.96 141.57,58.4 142.14,58.4 142.44,58.11 147.63,52.91 147.63,52.2 150.9,48.93 150.9,45.01 151.1,44.81 151.1,26.94 147.19,23.04 147.19,21.13 146.3,20.23 146.3,17.76 146.42,17.63 147.05,17.63 147.17,17.76 147.17,18.83 147.3,18.96 v2(147.63,18.96)
  BOTTOM w0.14: v2(119.36,76.54) 119.69,76.87 CPU1.AN29 ; v2(147.63,18.96) 147.05,18.38 DM2.166
M_B_DQ22: length 83.7
  TOP w0.14: v1(148.95,19.21) 149.35,19.6 v2(149.48,19.6)
  L4 w0.089: 125.18,72.35 124.93,72.61 123.71,72.61 123.31,73.01 122.39,73.01 120.24,75.16 v2(120.24,75.25)
  L4 w0.127: v2(149.48,19.6) 149.13,19.6 149,19.48 149,18.78 148.88,18.65 148.24,18.65 148.11,18.78 148.11,19.85 149.56,21.29 149.56,23.03 152.78,26.25 152.78,32.22 153.25,32.68 153.25,48.96 149.31,52.89 149.31,53.61 143.13,59.78 143.13,60.47 138.81,64.79 135.5,64.79 129.38,70.9 126.63,70.9 125.18,72.35
  BOTTOM w0.14: v2(120.24,75.25) 120.55,75.57 CPU1.AR28 ; DM2.176 150.05,19.03 v2(149.48,19.6)
M_B_DQ23: length 84.6
  TOP w0.14: v1(150.06,18.09) 149.92,18.23 v2(149.45,18.23)
  L4 w0.089: 125.39,72.45 125.05,72.79 123.78,72.79 123.38,73.18 122.47,73.18 120.64,75.01 120.64,75.48 v2(120.21,75.9)
  L4 w0.127: v2(149.45,18.23) 148.5,18.23 148.37,18.1 148.37,17.66 148.5,17.53 149.82,17.53 149.95,17.66 149.95,22.87 153.17,26.09 153.17,32.05 153.64,32.52 153.64,49.12 149.7,53.06 149.7,53.77 143.53,59.95 143.53,60.63 138.97,65.18 135.53,65.18 135.11,65.6 129.59,71.12 127.9,71.12 126.95,72.06 125.78,72.06 125.39,72.45
  BOTTOM w0.14: DM2.174 v2(149.45,18.23) ; v2(120.21,75.9) 120.39,75.9 CPU1.AP28
M_B_DQ24: length 73.7
  TOP w0.14: v1(103.2,18.94) 102.66,18.94 v2(102.64,18.96)
  L3 w0.089: v2(121.19,76.54) 120.79,76.14 120.79,75.72 120.82,75.7 120.82,74.93 120.94,74.81
  L3 w0.127: v2(102.64,18.96) 102.31,18.96 102.04,19.23 102.04,20.28 102.61,20.84 102.61,20.84 102.61,26.18 107.4,30.97 107.4,33.02 108.32,33.94 108.32,37.07 110.09,38.84 111.14,38.84 125.04,52.75 125.04,64.06 123.72,65.38 123.72,71.1 123.7,71.12 123.7,72.04 120.94,74.81
  BOTTOM w0.14: CPU1.AN26 121.52,76.87 v2(121.19,76.54) ; v2(102.64,18.96) 102.59,18.96 102.05,18.41 DM2.24
M_B_DQ25: length 72.5
  TOP w0.14: v2(102.63,20.23) v1(103.18,20.23)
  L3 w0.127: v2(121.22,75.25) 121.22,74.83 123.92,72.13 123.92,71.21 124.28,70.84 124.38,70.84 124.86,70.36 124.86,65.08 125.93,64.01 125.93,61.52 125.43,61.02 125.43,52.58 111.3,38.45 110.25,38.45 108.81,37 108.81,33.87 107.79,32.86 107.79,30.81 103,26.02 103,20.36 102.88,20.23 v2(102.63,20.23)
  BOTTOM w0.14: CPU1.AR26 121.53,75.57 v2(121.22,75.25) ; v2(102.63,20.23) 101.45,19.05 DM2.22
M_B_DQ26: length 72.1
  TOP w0.14: v1(105.65,21.62) 105.32,21.94 v2(105.08,21.94)
  L3 w0.127: v2(105.08,21.94) 104.76,21.94 104.57,21.75 104.57,21.42 104.44,21.29 104.17,21.29 104.05,21.42 104.05,22.56 104.55,23.07 104.55,24.95 110.31,30.71 110.31,33.52 110.49,33.7 110.49,36.78 110.88,37.17 111.83,37.17 126.72,52.05 126.72,56.98 127.21,57.47 127.21,64.5 125.55,66.16 125.55,71.67 122.21,75.01 v2(122.21,75.19)
  BOTTOM w0.14: v2(122.21,75.19) 122.24,75.19 CPU1.AR25 ; DM2.33 104.75,23.63 104.63,23.51 104.63,22.39 105.08,21.94 v2(105.08,21.94)
M_B_DQ27: length 72.8
  TOP w0.14: v2(105.08,23.21) v1(105.08,23.78)
  L3 w0.089: 123.21,74.51 122.99,74.51 122.61,74.89 122.61,75.76 122.48,75.89 v2(122.2,75.89)
  L3 w0.127: 123.21,74.51 125.76,71.96 125.76,66.5 127.6,64.66 127.6,57.31 127.11,56.82 127.11,56.42 127.24,56.3 127.48,56.3 127.6,56.17 127.6,55.91 127.48,55.79 127.24,55.79 127.11,55.66 127.11,51.89 111.92,36.7 111.92,35.97 111.79,35.84 111.64,35.84 111.51,35.71 111.51,35.46 111.64,35.33 111.79,35.33 111.92,35.21 111.92,34.95 111.79,34.83 111.56,34.83 111.44,34.7 111.44,34.44 111.56,34.32 111.79,34.32 111.92,34.19 111.92,33.94 111.79,33.81 111.34,33.81 111.21,33.68 111.21,33.43 111.34,33.3 111.79,33.3 111.92,33.17 111.92,32.92 111.79,32.79 111.34,32.79 111.21,32.67 111.21,32.41 111.34,32.29 111.79,32.29 111.92,32.16 111.92,31.88 111.79,31.75 111.32,31.75 111.19,31.63 111.19,31.04 104.94,24.79 104.94,24.54 105.07,24.41 105.19,24.41 105.32,24.29 105.32,24.03 105.19,23.91 105.07,23.91 104.94,23.78 104.94,23.35 v2(105.08,23.21)
  BOTTOM w0.14: CPU1.AP25 122.61,76.01 122.48,75.89 v2(122.2,75.89) ; DM2.35 105.35,24.3 105.45,24.21 105.45,23.32 105.34,23.21 v2(105.08,23.21)
M_B_DQ28: length 75.1
  TOP w0.14: v2(101.15,23.47) v1(101.15,24.13)
  L3 w0.127: v2(121.22,78.49) 120.8,78.91 120.09,78.91 119.8,78.62 119.8,74.21 120.39,73.62 120.39,73.44 120.15,73.21 120.15,73.03 120.33,72.85 120.51,72.85 120.75,73.08 120.93,73.08 123.01,71 123.01,65.08 124.25,63.84 124.25,53.07 110.81,39.63 109.76,39.63 106.9,36.77 106.9,33.82 106.01,32.93 106.01,30.69 101.82,26.51 101.82,25.76 101.7,25.64 101.23,25.64 101.1,25.51 101.1,25.26 101.23,25.13 101.7,25.13 101.82,25 101.82,24.75 101.7,24.62 101.23,24.62 101.1,24.49 101.1,24.24 101.23,24.11 101.7,24.11 101.82,23.99 101.82,23.59 101.7,23.47 v2(101.15,23.47)
  BOTTOM w0.14: v2(121.22,78.49) 121.54,78.82 CPU1.AK26 ; DM2.21 v2(101.15,23.47)
M_B_DQ29: length 74.5
  TOP w0.14: v1(101.71,22.17) 101.69,22.17 101.69,22.17 101.17,22.17 v2(101.15,22.2)
  L3 w0.089: v2(121.19,77.19) 120.71,76.71 120.71,76.38 120.62,76.28 120.62,75.44 120.64,75.42 120.64,74.8
  L3 w0.127: v2(101.15,22.2) 101.47,22.2 101.59,22.07 101.59,21.01 101.72,20.88 102.09,20.88 102.22,21.01 102.22,26.34 107,31.13 107,33.37 107.91,34.28 107.91,37.22 109.93,39.24 110.97,39.24 124.65,52.91 124.65,63.84 123.36,65.13 123.36,72.08 120.64,74.8 120.64,74.8
  BOTTOM w0.14: DM2.23 101.75,22.68 101.26,22.2 v2(101.15,22.2) ; CPU1.AM26 121.33,77.19 v2(121.19,77.19)
M_B_DQ30: length 75.2
  TOP w0.14: v2(105.05,18.23) v1(105.05,17.59)
  L3 w0.089: v2(122.17,78.49) 122.78,77.88 122.78,77.53 122.8,77.52 122.8,76.74 122.79,76.73 122.79,76.31 123.59,75.5 123.59,74.82 123.7,74.7
  L3 w0.127: v2(105.05,18.23) 106.11,19.29 106.11,24.84 112.71,31.44 112.71,36.37 127.9,51.56 127.9,55.09 128.39,55.59 128.39,64.99 126.31,67.07 126.31,72.1 123.7,74.7
  BOTTOM w0.14: CPU1.AK25 122.49,78.82 v2(122.17,78.49) ; DM2.34 v2(105.05,18.23)
M_B_DQ31: length 75.1
  TOP w0.14: v2(105.05,19.6) 105.05,19.63 v1(105.52,20.1)
  L3 w0.089: v2(122.22,77.84) 122.62,77.44 122.62,77.03 122.61,77.02 122.61,76.23 122.79,76.05 122.79,74.96 123.02,74.73 123.3,74.73 123.37,74.65
  L3 w0.127: 123.37,74.65 126,72.02 126,66.82 128,64.82 128,55.75 127.5,55.26 127.5,51.72 112.31,36.53 112.31,31.6 105.71,25 105.71,19.72 105.58,19.6 v2(105.05,19.6)
  BOTTOM w0.14: v2(105.05,19.6) 105.42,19.6 105.65,19.36 DM2.36 ; v2(122.22,77.84) 122.54,78.17 CPU1.AL25
M_B_DQ32: length 73.3
  TOP w0.14: v2(142.75,21.03) 142.56,21.03 v1(142.22,21.37)
  L4 w0.127: v2(124.23,67.55) 124.89,67.55 127.7,64.73 128.52,64.73 130.14,63.11 130.14,62.63 134.63,58.14 134.81,58.14 135.14,58.47 135.26,58.47 135.5,58.24 135.5,58.11 135.17,57.78 135.17,57.6 135.46,57.31 136.42,57.31 136.81,56.92 136.81,56.76 136.81,56.43 138.08,55.16 138.7,55.16 141.41,52.46 141.41,51.41 146.82,46 146.82,28.46 142.17,23.81 142.17,23.47 142.3,23.35 142.7,23.35 142.82,23.23 142.82,22.95 142.7,22.84 142.3,22.84 142.17,22.71 142.17,21.15 142.3,21.03 v2(142.75,21.03)
  BOTTOM w0.089: v2(124.23,67.55) 123.55,68.23 123.55,72.38 CPU1.AY23
  BOTTOM w0.14: v2(142.75,21.03) 142.53,20.81 142.07,20.81 141.92,20.95 141.92,23.26 141.35,23.83 DM2.147
M_B_DQ33: length 74.3
  TOP w0.14: v2(141.05,18.23) v1(141.05,17.56)
  L4 w0.127: v2(141.05,18.23) 141.05,16.62 141.18,16.49 141.65,16.49 141.78,16.62 141.78,23.97 146.43,28.62 146.43,45.84 141.02,51.25 141.02,52.17 138.42,54.77 137.92,54.77 137.15,55.54 136.54,56.15 136.44,56.25 136.42,56.27 136.36,56.33 135.88,56.33 129.74,62.47 129.74,63.11 128.34,64.51 127.61,64.51 125.21,66.91 v2(124.23,66.91)
  BOTTOM w0.089: v2(124.23,66.91) 123.37,67.77 123.37,72.09 123.19,72.28 123.19,72.51 123.23,72.61 123.26,72.69 123.26,72.89 CPU1.AW23
  BOTTOM w0.14: DM2.146 v2(141.05,18.23)
M_B_DQ34: length 73.2
  TOP w0.14: v2(144.53,21.56) 144.31,21.56 v1(144,21.87)
  L4 w0.127: v2(144.53,21.56) 144.35,21.56 144.03,21.25 144.03,20.79 144.35,20.48 144.88,20.48 145,20.6 145,23.71 148.89,27.6 148.89,48.08 145.53,51.43 145.53,52.16 145,52.7 144.01,53.68 143.11,53.68 137.86,58.94 137.86,59 135.78,61.08 134.62,61.08 132.19,63.5 131.94,63.5 129.16,66.29 v2(127.68,66.29)
  BOTTOM w0.089: 125.18,69.77 125.11,69.85 125.11,71.75 124.92,71.94 124.92,72.36 CPU1.AY21
  BOTTOM w0.14: DM2.159 145.05,24.87 145.05,22.08 v2(144.53,21.56) ; v2(127.68,66.29) 127.62,66.23 126.16,66.23 125.18,67.2 125.18,69.77
M_B_DQ35: length 74.2
  TOP w0.14: v2(145.85,18.96) 145.66,18.96 v1(145.27,18.57)
  L4 w0.127: v2(127.26,66.78) 129.01,66.78 132.06,63.72 132.53,63.72 134.78,61.47 135.94,61.47 143.34,54.08 143.85,54.08 144.17,54.08 145.16,53.09 145.93,52.32 145.93,51.6 149.28,48.24 149.28,47.91 149.28,27.43 145.4,23.55 145.4,23.22 145.4,23.22 145.4,20.83 145.4,20.21 145.27,20.08 144.71,20.08 144.58,19.96 144.58,18.67 144.71,18.55 145.44,18.55 v2(145.85,18.96)
  BOTTOM w0.089: CPU1.AW21 125.1,72.83 125.1,72.01 125.29,71.82 125.29,70.3 125.46,70.13
  BOTTOM w0.14: v2(145.85,18.96) 145.85,18.96 145.25,18.36 DM2.160 ; v2(127.26,66.78) 126.9,66.78 126.14,67.53 126.14,69.45 125.46,70.13
M_B_DQ36: length 74.7
  TOP w0.14: v1(141.46,19.97) 141.1,19.6 v2(140.94,19.6)
  L4 w0.127: v2(124.24,66.25) 125.43,66.25 125.56,66.12 125.56,65.96 125.41,65.81 125.41,65.63 125.59,65.45 125.77,65.45 125.98,65.66 126.16,65.66 126.34,65.48 126.34,65.3 126.13,65.1 126.13,64.92 126.31,64.74 126.49,64.74 126.7,64.94 126.88,64.94 127.06,64.76 127.06,64.58 126.85,64.38 126.85,64.2 127.03,64.02 127.21,64.02 127.42,64.22 127.6,64.22 127.78,64.04 127.78,63.86 127.57,63.66 127.57,63.48 127.75,63.3 127.93,63.3 128.14,63.5 129.01,63.5 129.35,63.16 129.35,62.29 135.7,55.94 136.19,55.94 136.26,55.87 136.87,55.26 137.76,54.37 138.26,54.37 140.62,52.01 140.62,51.08 146.03,45.67 146.03,28.78 141.38,24.13 141.38,19.86 141.13,19.6 v2(140.94,19.6)
  BOTTOM w0.089: v2(124.24,66.25) 123.2,67.29 123.2,72.01 123.01,72.2 123.01,72.55 123.06,72.67 123.08,72.73 123.08,73.37 CPU1.AV23
  BOTTOM w0.14: v2(140.94,19.6) 141.65,18.89 DM2.148
M_B_DQ37: length 75.4
  TOP w0.14: v2(142.73,22.3) v1(142.73,22.89)
  L4 w0.127: v2(124.23,68.18) 124.23,68.42 124.73,68.92 125.03,68.92 125.18,68.76 125.18,68.58 124.76,68.16 124.76,67.98 124.94,67.8 125.12,67.8 125.54,68.22 125.72,68.22 125.88,68.06 125.88,67.84 125.48,67.44 125.48,67.26 127.79,64.95 128.69,64.95 130.53,63.11 130.53,62.8 134.42,58.91 135.05,58.91 135.05,58.91 135.38,58.91 137.2,57.08 137.2,56.6 138.25,55.55 138.82,55.55 138.87,55.55 141.8,52.62 141.8,51.57 142.23,51.15 142.41,51.15 142.6,51.34 142.78,51.34 142.96,51.16 142.96,50.98 142.77,50.79 142.77,50.61 142.95,50.43 143.13,50.43 143.5,50.8 143.68,50.8 143.86,50.62 143.86,50.44 143.49,50.07 143.49,49.89 147.21,46.16 147.21,28.29 143.21,24.29 143.21,22.42 143.09,22.3 v2(142.73,22.3)
  BOTTOM w0.089: v2(124.23,68.18) 124.75,68.7 124.75,71.6 124.37,71.98 124.37,72.58 124.41,72.67 124.43,72.73 124.43,72.84 124.38,72.96 124.36,73 124.36,73.2 124.41,73.33 124.43,73.38 124.43,73.49 124.43,73.5 124.43,73.98 124.45,74 124.45,74.21 124.24,74.41 CPU1.AU23
  BOTTOM w0.14: DM2.149 141.95,23.81 142.4,23.35 142.4,22.62 v2(142.73,22.3)
M_B_DQ38: length 74.6
  TOP w0.14: v2(144.5,22.83) v1(144.5,23.52)
  L4 w0.127: v2(144.5,22.83) 144.5,23.76 148.5,27.76 148.5,46.7 148.13,47.06 148.13,47.24 148.5,47.61 148.5,47.86 148.35,48 148.17,48 147.77,47.6 147.59,47.6 147.41,47.78 147.41,47.96 147.86,48.41 147.86,48.55 147.64,48.77 147.5,48.77 147.05,48.32 146.87,48.32 146.69,48.5 146.69,48.68 147.14,49.13 147.14,49.27 146.92,49.49 146.78,49.49 146.33,49.04 146.15,49.04 145.97,49.22 145.97,49.4 146.41,49.84 146.41,50 146.21,50.2 146.05,50.2 145.61,49.76 145.43,49.76 145.14,50.05 145.14,50.37 145.42,50.65 145.42,50.99 145.14,51.27 145.14,51.99 144.83,52.3 143.85,53.29 143.63,53.29 142.95,53.29 136.05,60.19 134.95,60.19 129.07,66.07 128.41,66.07 v2(128.15,65.82)
  BOTTOM w0.089: 124.96,69.68 124.93,69.7 124.93,71.67 124.55,72.05 124.55,72.54 124.58,72.61 124.61,72.69 124.61,72.88 124.57,72.97 124.54,73.05 124.54,73.15 124.56,73.2 124.61,73.34 CPU1.AV21
  BOTTOM w0.14: v2(144.5,22.83) 144.5,24.01 144.35,24.16 DM2.157 ; v2(128.15,65.82) 126.24,65.82 124.96,67.11 124.96,69.68
M_B_DQ39: length 75.4
  TOP w0.14: v2(145.85,20.23) 146.03,20.23 v1(146.41,19.84)
  L4 w0.127: v2(145.85,20.23) 145.79,20.29 145.79,23.39 149.68,27.27 149.68,47.75 149.68,47.75 149.68,48.4 146.32,51.76 146.32,52.48 145.32,53.48 144.34,54.47 143.68,54.47 143.68,54.47 143.5,54.47 141.77,56.2 141.77,56.9 141.51,57.16 140.81,57.16 139.17,58.8 139.17,60.2 137.51,61.87 134.95,61.87 132.88,63.94 132.23,63.94 128.75,67.42 128,67.42 127.82,67.24 127.04,67.24 v2(126.74,67.53)
  BOTTOM w0.089: CPU1.AU21 124.95,74.18 124.95,74 125.27,73.67 125.27,72.08 125.46,71.89 125.46,70.45 125.56,70.36
  BOTTOM w0.14: 125.56,70.36 126.37,69.54 126.37,67.9 v2(126.74,67.53) ; v2(145.85,20.23) 144.99,20.23 144.65,19.89 DM2.158
M_B_DQ40: length 69
  TOP w0.14: v2(106.55,23.47) v1(106.55,24.03)
  L3 w0.127: v2(127.56,68.34) 127.58,68.34 128.13,67.8 128.13,67.62 127.64,67.14 127.64,66.96 127.82,66.78 128,66.78 128.48,67.26 128.66,67.26 128.84,67.08 128.84,66.9 128.34,66.39 128.34,66.23 128.53,66.04 128.69,66.04 129.01,66.35 129.24,66.35 129.31,66.27 129.31,62.86 129.04,62.59 129.04,54.81 128.65,54.42 128.65,51.38 114.12,36.85 114.12,35.35 113.69,34.92 113.69,31.21 113.08,30.61 112.9,30.61 112.79,30.72 112.61,30.72 112.43,30.54 112.43,30.36 112.54,30.25 112.54,30.07 112.36,29.89 112.18,29.89 112.07,30 111.89,30 111.71,29.82 111.71,29.64 111.82,29.53 111.82,29.35 111.65,29.17 111.47,29.17 111.35,29.28 111.17,29.28 110.99,29.1 110.99,28.92 111.11,28.81 111.11,28.63 110.93,28.45 110.75,28.45 110.63,28.56 110.45,28.56 110.27,28.38 110.27,28.2 110.39,28.09 110.39,27.91 110.21,27.73 110.03,27.73 109.91,27.84 109.73,27.84 109.56,27.66 109.56,27.48 109.67,27.37 109.67,27.19 109.49,27.01 109.31,27.01 109.2,27.12 109.02,27.12 108.84,26.95 108.84,26.77 108.95,26.65 108.95,26.47 108.77,26.29 108.59,26.29 108.48,26.41 108.3,26.41 108.12,26.23 108.12,26.05 108.23,25.93 108.23,25.75 108.05,25.57 107.87,25.57 107.76,25.69 107.58,25.69 107.4,25.51 107.4,25.33 107.51,25.21 107.51,25.03 106.55,24.07 v2(106.55,23.47)
  BOTTOM w0.089: v2(127.56,68.34) 127.56,69.14 126,70.71 126,72.36 CPU1.AY19
  BOTTOM w0.14: DM2.39 v2(106.55,23.47)
M_B_DQ41: length 70.6
  TOP w0.14: v2(106.55,22.2) 106.72,22.2 v1(107.04,21.87)
  L3 w0.127: v2(106.55,22.2) 107.02,21.72 107.25,21.72 107.38,21.85 107.38,22.43 107.25,22.56 107.14,22.56 107.02,22.68 107.02,22.94 107.14,23.06 107.27,23.06 107.4,23.19 107.4,23.44 107.27,23.57 107.07,23.57 106.94,23.7 106.94,23.91 107.11,24.08 107.87,24.08 107.95,24.16 107.95,24.91 114.08,31.04 114.08,34.76 114.51,35.19 114.51,36.69 129.04,51.21 129.04,54.26 129.43,54.65 129.43,62.43 129.71,62.7 129.71,66.79 129.32,67.18 129.05,67.18 128.83,67.41 128.83,67.67 128.6,67.9 128.33,67.9 128.11,68.12 128.11,68.39 127.65,68.85 127.35,68.85 v2(126.9,68.41)
  BOTTOM w0.089: v2(126.9,68.41) 127.06,68.41 127.38,68.73 127.38,69.07 125.82,70.63 125.82,70.63 125.82,72.08 125.63,72.27 125.63,73 125.74,73.11 CPU1.AW19
  BOTTOM w0.14: v2(106.55,22.2) 106.87,22.2 107,22.32 107,23.99 107.15,24.14 DM2.41
M_B_DQ42: length 68.3
  TOP w0.14: v1(111.74,22.62) v2(111.33,22.21)
  L3 w0.127: v2(111.33,22.21) 111.57,22.21 111.69,22.34 111.69,23.29 111.56,23.42 111.56,23.93 116.62,28.98 117.83,30.2 118.45,30.2 119.31,31.05 119.31,31.38 119.31,34.67 119.89,35.26 119.89,36.76 120.29,37.15 120.52,37.15 121,37.64 121,37.82 120.71,38.11 120.71,38.29 120.89,38.47 121.07,38.47 121.36,38.18 121.54,38.18 121.72,38.36 121.72,38.54 121.41,38.85 121.41,38.98 121.69,39.26 121.82,39.26 121.97,39.11 122.06,39.02 122.41,39.02 124.05,40.66 124.05,41.62 132.29,49.87 132.29,50.19 132.29,52.21 132.96,52.88 132.96,64.39 132.83,64.52 132.83,66.63 130.39,69.07 v2(129.8,69.07)
  BOTTOM w0.089: v2(129.8,69.07) 127.75,71.12 127.75,71.75 127.25,72.24 CPU1.AY17
  BOTTOM w0.14: DM2.53 110.75,22.79 111.32,22.21 v2(111.33,22.21)
M_B_DQ43: length 70.1
  TOP w0.14: v2(109.85,19.59) 109.97,19.59 v1(110.34,19.97)
  L3 w0.127: v2(131.24,66.98) 131.24,66.48 131.78,65.95 131.78,54.07 131.11,53.4 131.11,50.35 118.12,37.37 118.12,33.91 118,33.79 117.33,33.79 117.2,33.66 117.2,31.24 116.13,30.16 110.02,24.05 110.02,21.45 109.89,21.33 109.38,21.33 109.25,21.2 109.25,20.95 109.38,20.82 109.89,20.82 110.02,20.69 110.02,20.69 110.29,20.41 110.29,20.04 v2(109.85,19.59)
  BOTTOM w0.089: v2(131.24,66.98) 131.24,68.19 127.99,71.45 127.99,71.84 127.54,72.29 127.54,72.5 127.51,72.58 CPU1.AW17
  BOTTOM w0.14: DM2.52 110.45,19.1 109.96,19.59 v2(109.85,19.59)
M_B_DQ44: length 70.9
  TOP w0.14: v2(108.03,18.96) 108.19,18.96 v1(108.57,19.33)
  L3 w0.127: v2(108.03,18.96) 107.6,18.96 107.47,19.09 107.47,20.43 107.77,20.73 107.77,23.03 108.34,23.6 108.34,24.75 114.47,30.88 114.47,33.77 114.88,34.18 115.35,34.18 115.83,34.66 115.83,37.44 129.43,51.05 129.43,54.09 129.83,54.49 129.83,62.26 130.1,62.54 130.1,66.7 127.74,69.07 v2(126.8,69.07)
  BOTTOM w0.089: v2(126.8,69.07) 126.8,69.4 125.64,70.56 125.64,72 125.45,72.19 125.45,73.2 CPU1.AV19
  BOTTOM w0.14: v2(108.03,18.96) 107.8,18.96 107.45,18.6 DM2.42
M_B_DQ45: length 71.6
  TOP w0.14: v2(108.03,20.23) v1(108.03,20.83)
  L3 w0.127: v2(108.03,20.23) 108.27,19.98 108.45,19.97 108.6,19.97 108.77,20.14 108.77,20.47 108.17,21.07 108.17,22.87 108.73,23.43 108.73,24.59 115.39,31.25 115.39,33.22 115.39,33.67 116.22,34.49 116.22,37.28 129.83,50.89 129.83,53.93 130.22,54.32 130.22,62.1 130.5,62.37 130.5,65.82 130.32,66 130.32,66.79 129.76,67.35 v2(129.76,68.23)
  BOTTOM w0.089: v2(129.76,68.23) 127.29,70.69 127.29,71.7 126.79,72.2 126.79,72.55 126.84,72.67 126.86,72.73 126.86,72.84 126.81,72.96 126.79,73 126.79,73.2 126.84,73.33 126.86,73.38 126.86,73.94 126.88,73.96 126.88,74.21 126.68,74.41 CPU1.AU19
  BOTTOM w0.14: v2(108.03,20.23) 107.95,20.23 106.85,19.12 DM2.40
M_B_DQ46: length 70.5
  TOP w0.14: v1(111.87,21.24) 111.57,20.94 v2(111.34,20.94)
  L3 w0.127: v2(111.34,20.94) 110.8,21.48 110.8,23.73 116.45,29.38 116.45,29.38 117.67,30.59 118.29,30.59 118.91,31.22 118.91,37.04 131.9,50.03 131.9,53.07 132.57,53.74 132.57,63.07 132.57,66.34 130.48,68.43 v2(130.43,68.43)
  BOTTOM w0.089: CPU1.AV17 127.04,73.54 127.04,73.34 126.99,73.2 126.97,73.15 126.97,73.05 127,72.97 127.04,72.88 127.04,72.69 126.99,72.55 126.97,72.5 126.97,72.28 127.52,71.72 127.52,70.78 129.63,68.67 130.2,68.67 v2(130.43,68.43)
  BOTTOM w0.14: DM2.51 110.15,22.01 111.21,20.94 v2(111.34,20.94)
M_B_DQ47: length 71.3
  TOP w0.14: v1(109.85,17.68) v2(109.85,18.32)
  L3 w0.127: v2(131.74,66.58) 132.17,66.14 132.17,53.9 131.5,53.23 131.5,50.19 118.52,37.21 118.52,31.38 118.13,30.99 117.51,30.99 116.29,29.77 110.41,23.89 110.41,20.85 110.69,20.58 110.69,18.06 110.56,17.94 109.98,17.94 109.85,18.06 v2(109.85,18.32)
  BOTTOM w0.089: v2(131.74,66.58) 131.64,66.67 131.64,68.04 128.2,71.48 128.2,72.04 127.72,72.53 127.68,72.65 127.64,72.72 127.64,72.94 127.54,73.04 127.54,74.12 CPU1.AU17
  BOTTOM w0.14: v2(109.85,18.32) DM2.50
M_B_DQ48: length 84.6
  TOP w0.14: v2(155.27,22.9) v1(155.27,23.52)
  L4 w0.089: v2(124.98,75.18) 124.98,75.17 125.55,74.61 126.18,74.61 126.49,74.31 128.5,74.31 128.7,74.51 129.19,74.51 129.32,74.38 129.32,73.64 129.45,73.51 129.7,73.51 129.83,73.64 129.83,74.3 130.04,74.51 130.56,74.51 130.79,74.28
  L4 w0.127: 130.79,74.28 130.79,73.95 134.63,70.1 139.32,70.1 143.41,66.01 144.52,66.01 144.66,65.87 144.66,65.66 144.79,65.54 145.07,65.54 145.19,65.66 145.19,65.88 145.32,66.01 145.7,66.01 146.61,65.1 146.61,64.43 148.16,62.88 148.16,62.71 147.9,62.45 147.9,62.27 148.19,61.98 148.37,61.98 148.62,62.23 148.8,62.23 149.42,61.61 149.42,61.09 149.3,60.96 148.78,60.96 148.65,60.84 148.65,60.38 148.78,60.25 149.3,60.25 149.42,60.13 149.42,59.59 156.79,52.22 156.79,51.23 157.63,50.39 157.63,31.81 158.91,30.54 158.91,26.54 158.55,26.18 158.55,26 158.62,25.93 158.62,25.75 158.44,25.57 158.26,25.57 158.19,25.64 158.01,25.64 157.83,25.46 157.83,25.28 157.9,25.21 157.9,25.03 157.72,24.85 157.54,24.85 157.47,24.92 157.29,24.92 157.11,24.74 157.11,24.56 157.18,24.49 157.18,24.31 157,24.13 156.82,24.13 156.75,24.2 156.57,24.2 156.39,24.02 156.39,23.84 156.46,23.77 156.46,23.59 156.28,23.41 156.1,23.41 156.03,23.48 155.85,23.48 v2(155.27,22.9)
  BOTTOM w0.14: DM2.191 154.55,23.62 v2(155.27,22.9) ; v2(124.98,75.18) 125.36,75.56 CPU1.AR21
M_B_DQ49: length 85.6
  TOP w0.14: v1(153.02,22.51) 153.37,22.15 v2(153.63,22.15)
  L4 w0.127: v2(153.63,22.15) 153.99,22.51 153.99,23.43 156.35,25.79 156.35,27.41 156.48,27.54 157.5,27.54 157.63,27.67 157.63,27.92 157.5,28.05 156.48,28.05 156.35,28.17 156.35,28.43 156.48,28.55 157.51,28.55 157.63,28.67 157.63,28.95 157.51,29.06 156.48,29.06 156.35,29.19 156.35,29.44 156.48,29.57 156.92,29.57 157.04,29.7 157.04,29.95 156.92,30.08 156.48,30.08 156.35,30.21 156.35,49.86 155.51,50.7 155.51,51.69 146.34,60.85 146.34,62.32 144.41,64.25 143.32,64.25 139.39,68.18 138.59,68.18 138.46,68.31 138.46,68.69 138.34,68.82 138.08,68.82 137.95,68.69 137.95,68.31 137.83,68.18 137.57,68.18 137.45,68.31 137.45,68.69 137.32,68.81 137.07,68.81 136.94,68.69 136.94,68.31 136.81,68.18 136.68,68.18 135.96,68.89 134.76,68.89 131.04,72.61 129.17,72.61 128.12,73.66 126.34,73.66 125.95,74.05 125,74.05 123.99,75.06 v2(123.99,75.24)
  BOTTOM w0.14: CPU1.AR22 124.32,75.57 v2(123.99,75.24) ; v2(153.63,22.15) 153.49,22.15 152.15,23.49 DM2.183
M_B_DQ50: length 87.4
  TOP w0.14: v2(155.98,18.96) 155.8,18.96 v1(155.43,19.33)
  L4 w0.089: 131.22,74.46 130.81,74.86 128.54,74.86 128.34,74.66 126.64,74.66 126.25,75.05 126.25,77.93 126.02,78.16 125.29,78.16 v2(124.96,77.84)
  L4 w0.127: v2(155.98,18.96) 155.48,18.96 155.37,19.07 155.37,20.38 157.56,22.57 157.56,23.47 159.7,25.61 159.7,30.86 158.42,32.14 158.42,50.72 157.58,51.56 157.58,52.55 150.32,59.8 150.32,61.83 147.4,64.76 147.4,65.42 146.03,66.79 143.74,66.79 139.64,70.89 135.91,70.89 134.09,72.71 133.16,72.71 132.2,73.67 131.68,73.67 131.22,74.13 131.22,74.46
  BOTTOM w0.14: CPU1.AL21 125.3,78.17 v2(124.96,77.84) ; DM2.194 155.45,18.43 155.98,18.96 v2(155.98,18.96)
M_B_DQ51: length 87.8
  TOP w0.14: v1(151.88,17.84) 151.41,18.3 v2(151.41,18.32)
  L4 w0.089: v2(123.99,77.21) 123.27,77.21 122.79,76.72 122.79,74.96 123.03,74.72 123.62,74.72
  L4 w0.127: v2(151.41,18.32) 151.41,17.81 151.28,17.68 150.6,17.68 150.48,17.56 150.48,17.3 150.6,17.17 151.87,17.17 152,17.3 152,20.89 152.26,21.15 152.26,22.85 155.56,26.15 155.56,49.53 152.69,52.41 152.69,53.34 145.56,60.48 145.56,61.84 143.92,63.47 142.99,63.47 139.56,66.9 136.73,66.9 135.59,68.03 135.01,68.03 130.86,72.18 128.99,72.18 127.94,73.23 126.16,73.23 125.77,73.62 124.72,73.62 124.37,73.96 123.66,74.67 123.62,74.72
  BOTTOM w0.14: v2(123.99,77.21) 124.3,77.52 CPU1.AM22 ; DM2.180 151.25,18.16 v2(151.41,18.32)
M_B_DQ52: length 86.8
  TOP w0.14: v2(153.72,20.77) 153.61,20.77 v1(153.27,21.11)
  L4 w0.089: v2(123.98,76.54) 123.59,76.15 123.3,76.15 123.17,76.02 123.17,75.71 123.59,75.29 123.59,75.05 123.77,74.87
  L4 w0.127: v2(153.72,20.77) 152.78,20.77 152.66,20.9 152.66,21.24 152.78,21.37 153.14,21.37 153.27,21.49 153.27,21.8 153.14,21.93 152.78,21.93 152.66,22.06 152.66,22.68 155.96,25.99 155.96,49.69 154.48,51.17 154.48,51.35 154.74,51.6 154.74,51.78 154.56,51.96 154.38,51.96 154.12,51.71 153.95,51.71 153.77,51.89 153.77,52.07 154.02,52.32 154.02,52.5 153.84,52.68 153.66,52.68 153.41,52.43 153.23,52.43 153.09,52.56 153.09,53.5 145.95,60.64 145.95,62.16 144.25,63.86 143.15,63.86 139.23,67.78 136.51,67.78 135.87,68.43 134.92,68.43 130.95,72.39 129.08,72.39 128.03,73.44 126.25,73.44 125.86,73.83 124.81,73.83 124.46,74.18 123.82,74.82 123.77,74.87
  BOTTOM w0.14: v2(123.98,76.54) 124.3,76.87 CPU1.AN22 ; v2(153.72,20.77) 152.63,21.86 152.63,22.43 151.55,23.52 DM2.181
M_B_DQ53: length 85.6
  TOP w0.14: v2(155.35,21.63) 155.04,21.63 v1(154.79,21.87)
  L4 w0.089: v2(124.97,75.89) 125.19,75.89 125.38,75.7 125.38,75.02 125.62,74.79 126.26,74.79 126.56,74.49 128.41,74.49 128.62,74.69 130.69,74.69 131,74.37
  L4 w0.127: v2(155.35,21.63) 155.35,21.69 155.65,21.99 155.98,21.99 156.08,21.89 156.26,21.89 156.44,22.07 156.44,22.25 156.09,22.6 156.09,22.78 156.27,22.96 156.45,22.96 156.79,22.62 156.97,22.62 157.15,22.8 157.15,22.98 156.92,23.21 156.92,23.39 159.3,25.77 159.3,30.7 158.03,31.98 158.03,50.55 157.18,51.4 157.18,52.39 149.82,59.75 149.82,61.78 147,64.59 147,65.26 145.86,66.4 143.58,66.4 139.48,70.5 134.83,70.5 134.68,70.64 134.68,70.92 134.99,71.23 134.99,71.41 134.03,72.37 133.84,72.37 133.44,71.97 133.08,71.97 131,74.04 131,74.37
  BOTTOM w0.14: v2(155.35,21.63) 155.74,22.02 155.74,23.08 155.15,23.66 DM2.193 ; v2(124.97,75.89) 125.29,76.22 CPU1.AP21
M_B_DQ54: length 88.2
  TOP w0.14: v2(155.98,20.23) v1(155.98,20.86)
  L4 w0.089: 131.69,74.84 131.49,75.04 128.47,75.04 128.27,74.84 126.71,74.84 126.43,75.12 126.43,78.59 126.31,78.71 126,79.02 125.49,79.02 v2(124.97,78.5)
  L4 w0.127: 131.69,74.84 132.94,73.6 132.94,73.29 133.25,72.97 134.2,72.97 135.89,71.28 139.81,71.28 143.9,67.19 146.19,67.19 147.79,65.59 147.79,65 150.76,62.03 150.76,59.93 157.97,52.71 157.97,51.72 158.82,50.88 158.82,32.3 160.09,31.03 160.09,24.41 155.98,20.3 v2(155.98,20.23)
  BOTTOM w0.14: DM2.192 154.85,19.1 155.98,20.23 v2(155.98,20.23) ; v2(124.97,78.5) 125.29,78.82 CPU1.AK21
M_B_DQ55: length 88.5
  TOP w0.14: v1(150.86,19.21) 151.25,19.59 v2(151.41,19.59)
  L4 w0.089: v2(123.99,78.49) 123.59,78.09 123.59,77.68 123.35,77.44 123.26,77.44 122.61,76.79 122.61,74.89 122.99,74.51 123.52,74.51
  L4 w0.127: 123.52,74.51 124.07,73.96 124.29,73.74 124.63,73.4 125.68,73.4 126.07,73.01 127.85,73.01 128.9,71.96 129.89,71.96 130.77,71.09 131.65,71.09 135.35,67.39 135.68,67.39 136.57,66.5 139.4,66.5 142.83,63.07 143.76,63.07 145.16,61.67 145.16,60.26 152.25,53.17 152.25,52.28 155.17,49.37 155.17,26.31 151.87,23.01 151.87,21.32 150.84,20.29 150.84,19.73 150.35,19.24 150.35,18.22 150.47,18.09 150.84,18.09 150.97,18.22 150.97,19.15 v2(151.41,19.59)
  BOTTOM w0.14: DM2.182 151.86,16.78 151.86,19.15 151.41,19.59 v2(151.41,19.59) ; v2(123.99,78.49) 124.32,78.82 CPU1.AK22
M_B_DQ56: length 79
  TOP w0.14: v2(113.32,21.07) 113.6,21.07 v1(113.9,21.37)
  L3 w0.089: 125.62,74.63 125.38,74.86 125.38,76.05 125.81,76.48 v2(125.81,76.49)
  L3 w0.127: 125.62,74.63 130.3,69.94 130.43,69.94 134.16,66.21 134.16,65.48 134.39,65.25 134.39,54.95 134.89,54.46 134.89,52.74 133.71,51.57 133.71,49.26 125.48,41.03 125.48,40.06 121.81,36.39 121.81,35.79 121.93,35.67 122.92,35.67 123.07,35.52 123.07,35.31 122.92,35.16 121.93,35.16 121.81,35.03 121.81,32.92 121.68,32.8 121.11,32.8 120.99,32.67 120.99,32.41 121.11,32.29 121.68,32.29 121.81,32.16 121.81,31.91 121.68,31.78 121.11,31.78 120.99,31.65 120.99,30.72 119.04,28.77 118.45,28.77 112.87,23.19 112.87,21.52 v2(113.32,21.07)
  BOTTOM w0.14: v2(113.32,21.07) 113.32,21.07 111.95,22.44 DM2.57 ; v2(125.81,76.49) 126.18,76.87 CPU1.AN20
M_B_DQ57: length 78
  TOP w0.14: v1(113.9,22.76) 113.48,22.34 v2(113.34,22.34)
  L3 w0.127: v2(125.78,75.19) 125.78,74.77 130.39,70.16 130.39,70.16 130.52,70.16 134.4,66.28 134.4,65.8 134.78,65.41 134.78,64.67 134.91,64.55 135.4,64.55 135.52,64.42 135.52,64.17 135.4,64.04 134.91,64.04 134.78,63.91 134.78,63.66 134.91,63.53 135.4,63.53 135.52,63.4 135.52,63.15 135.4,63.02 134.91,63.02 134.78,62.9 134.78,62.64 134.91,62.51 135.4,62.51 135.52,62.39 135.52,62.13 135.4,62.01 134.91,62.01 134.78,61.88 134.78,55.11 135.28,54.62 135.28,52.58 134.11,51.41 134.11,49.1 126.4,41.39 126.4,37.85 125.46,36.91 125.28,36.91 124.16,38.02 124,38.02 123.8,37.83 123.8,37.66 124.92,36.55 124.92,36.37 122.84,34.29 122.46,34.29 122.3,34.13 122.3,31.47 119.2,28.37 118.61,28.37 113.79,23.55 113.79,22.47 113.66,22.34 v2(113.34,22.34)
  BOTTOM w0.14: CPU1.AR20 126.16,75.57 v2(125.78,75.19) ; v2(113.34,22.34) 113.27,22.34 112.55,23.06 DM2.59
M_B_DQ58: length 80.1
  TOP w0.14: v2(116.52,22.08) 116.23,22.08 v1(115.93,22.38)
  L3 w0.127: v2(126.87,78.49) 127.3,78.07 127.3,77.75 127.92,77.13 127.92,74.46 128.11,74.28 130.25,72.14 132.04,72.14 138.13,66.05 138.13,50.85 137.68,50.4 137.5,50.4 137.12,50.78 136.97,50.78 136.76,50.58 136.76,50.42 137.15,50.04 137.15,49.86 136.57,49.29 136.57,48.07 129.67,41.18 129.67,35 120.73,26.06 120.73,25.91 120.24,25.41 119.85,25.41 119.49,25.06 119.31,25.06 119.14,25.23 118.96,25.23 118.78,25.05 118.78,24.87 119.52,24.14 119.52,23.96 119.34,23.78 119.16,23.78 118.42,24.52 118.24,24.52 118.06,24.34 118.06,24.16 118.24,23.98 118.24,23.8 v2(116.52,22.08)
  BOTTOM w0.14: DM2.69 115.55,22.98 116.45,22.08 v2(116.52,22.08) ; v2(126.87,78.49) 127.2,78.82 CPU1.AK18
M_B_DQ59: length 79.5
  TOP w0.14: v2(116.47,20.82) 116.23,20.82 v1(115.93,21.11)
  L3 w0.127: v2(116.47,20.82) 116.23,20.58 116.01,20.58 115.88,20.71 115.88,22.71 116.52,23.35 116.7,23.35 116.87,23.18 117.05,23.18 117.23,23.36 117.23,23.54 117.06,23.71 117.06,23.89 118.98,25.81 120.08,25.81 120.34,26.07 120.34,26.23 129.19,35.08 129.19,41.25 136.18,48.24 136.18,50.55 137.59,51.96 137.59,66.03 131.7,71.92 130.16,71.92 128.03,74.05 127.82,74.26 127.71,74.37 127.71,77.01 v2(126.87,77.84)
  BOTTOM w0.14: CPU1.AL18 127.2,78.17 v2(126.87,77.84) ; v2(116.47,20.82) 114.95,22.34 DM2.67
M_B_DQ60: length 80.6
  TOP w0.14: v1(112.25,19.97) 111.88,19.59 v2(111.66,19.59)
  L3 w0.089: 124.7,74.59 124.39,74.9 124.39,75.41 124.39,75.41 124.39,78.73 124.73,79.07 125.38,79.07 v2(125.83,78.62)
  L3 w0.127: 124.7,74.59 129.78,69.51 130.25,69.51 133.04,66.72 133.04,64.96 133.22,64.79 133.22,64.54 133.6,64.15 133.6,52.57 132.93,51.9 132.93,49.59 124.7,41.36 124.7,40.39 121.02,36.71 121.02,35.74 120.89,35.62 120.4,35.62 120.29,35.5 120.29,35.22 120.4,35.11 120.91,35.11 121.02,35 121.02,34.73 120.89,34.6 120.33,34.6 120.2,34.47 120.2,31.04 118.71,29.55 118.12,29.55 112.09,23.52 112.09,21.19 112.11,21.17 112.11,19.72 111.98,19.59 v2(111.66,19.59)
  BOTTOM w0.14: v2(125.83,78.62) 126.02,78.82 CPU1.AK20 ; DM2.58 112.25,19.08 111.74,19.59 v2(111.66,19.59)
M_B_DQ61: length 79.8
  TOP w0.14: v1(112.25,18.7) 111.88,18.32 v2(111.66,18.32)
  L3 w0.089: v2(125.82,77.13) 125.38,77.57 125.38,78.65 125.13,78.9 124.8,78.9 124.56,78.66 124.56,75.48 124.57,75.48 124.57,75.03 124.82,74.78
  L3 w0.127: v2(111.66,18.32) 112.5,19.16 112.5,21.34 112.48,21.36 112.48,23.35 118.29,29.16 118.87,29.16 120.59,30.88 120.59,33.74 121.41,34.56 121.41,36.55 125.09,40.23 125.09,41.19 133.32,49.42 133.32,51.73 134,52.41 134,64.32 133.26,65.05 133.26,66.81 130.34,69.73 129.87,69.73 124.82,74.78
  BOTTOM w0.14: v2(111.66,18.32) 111.65,18.31 DM2.56 ; v2(125.82,77.13) 126.02,77.34 126.03,77.34 126.2,77.52 CPU1.AM20
M_B_DQ62: length 76.2
  TOP w0.14: v2(116.5,18.89) 116.06,18.45 v1(116.06,18.44)
  L3 w0.127: v2(116.5,18.89) 116.21,18.6 115.63,18.6 115.09,19.14 115.09,23.04 119.15,27.09 120.09,27.09 128.05,35.05 128.05,41.22 135.39,48.56 135.39,50.88 136.81,52.29 136.81,54.91 136.07,55.65 136.07,56.21 136.19,56.33 136.51,56.33 136.81,56.62 136.81,65.21 135.46,66.55 135.34,66.55 131.08,70.81 130.66,70.81 127.69,73.78 126.87,74.6 v2(126.87,75.24)
  BOTTOM w0.14: DM2.70 115.85,18.24 v2(116.5,18.89) ; v2(126.87,75.24) 127.2,75.57 CPU1.AR18
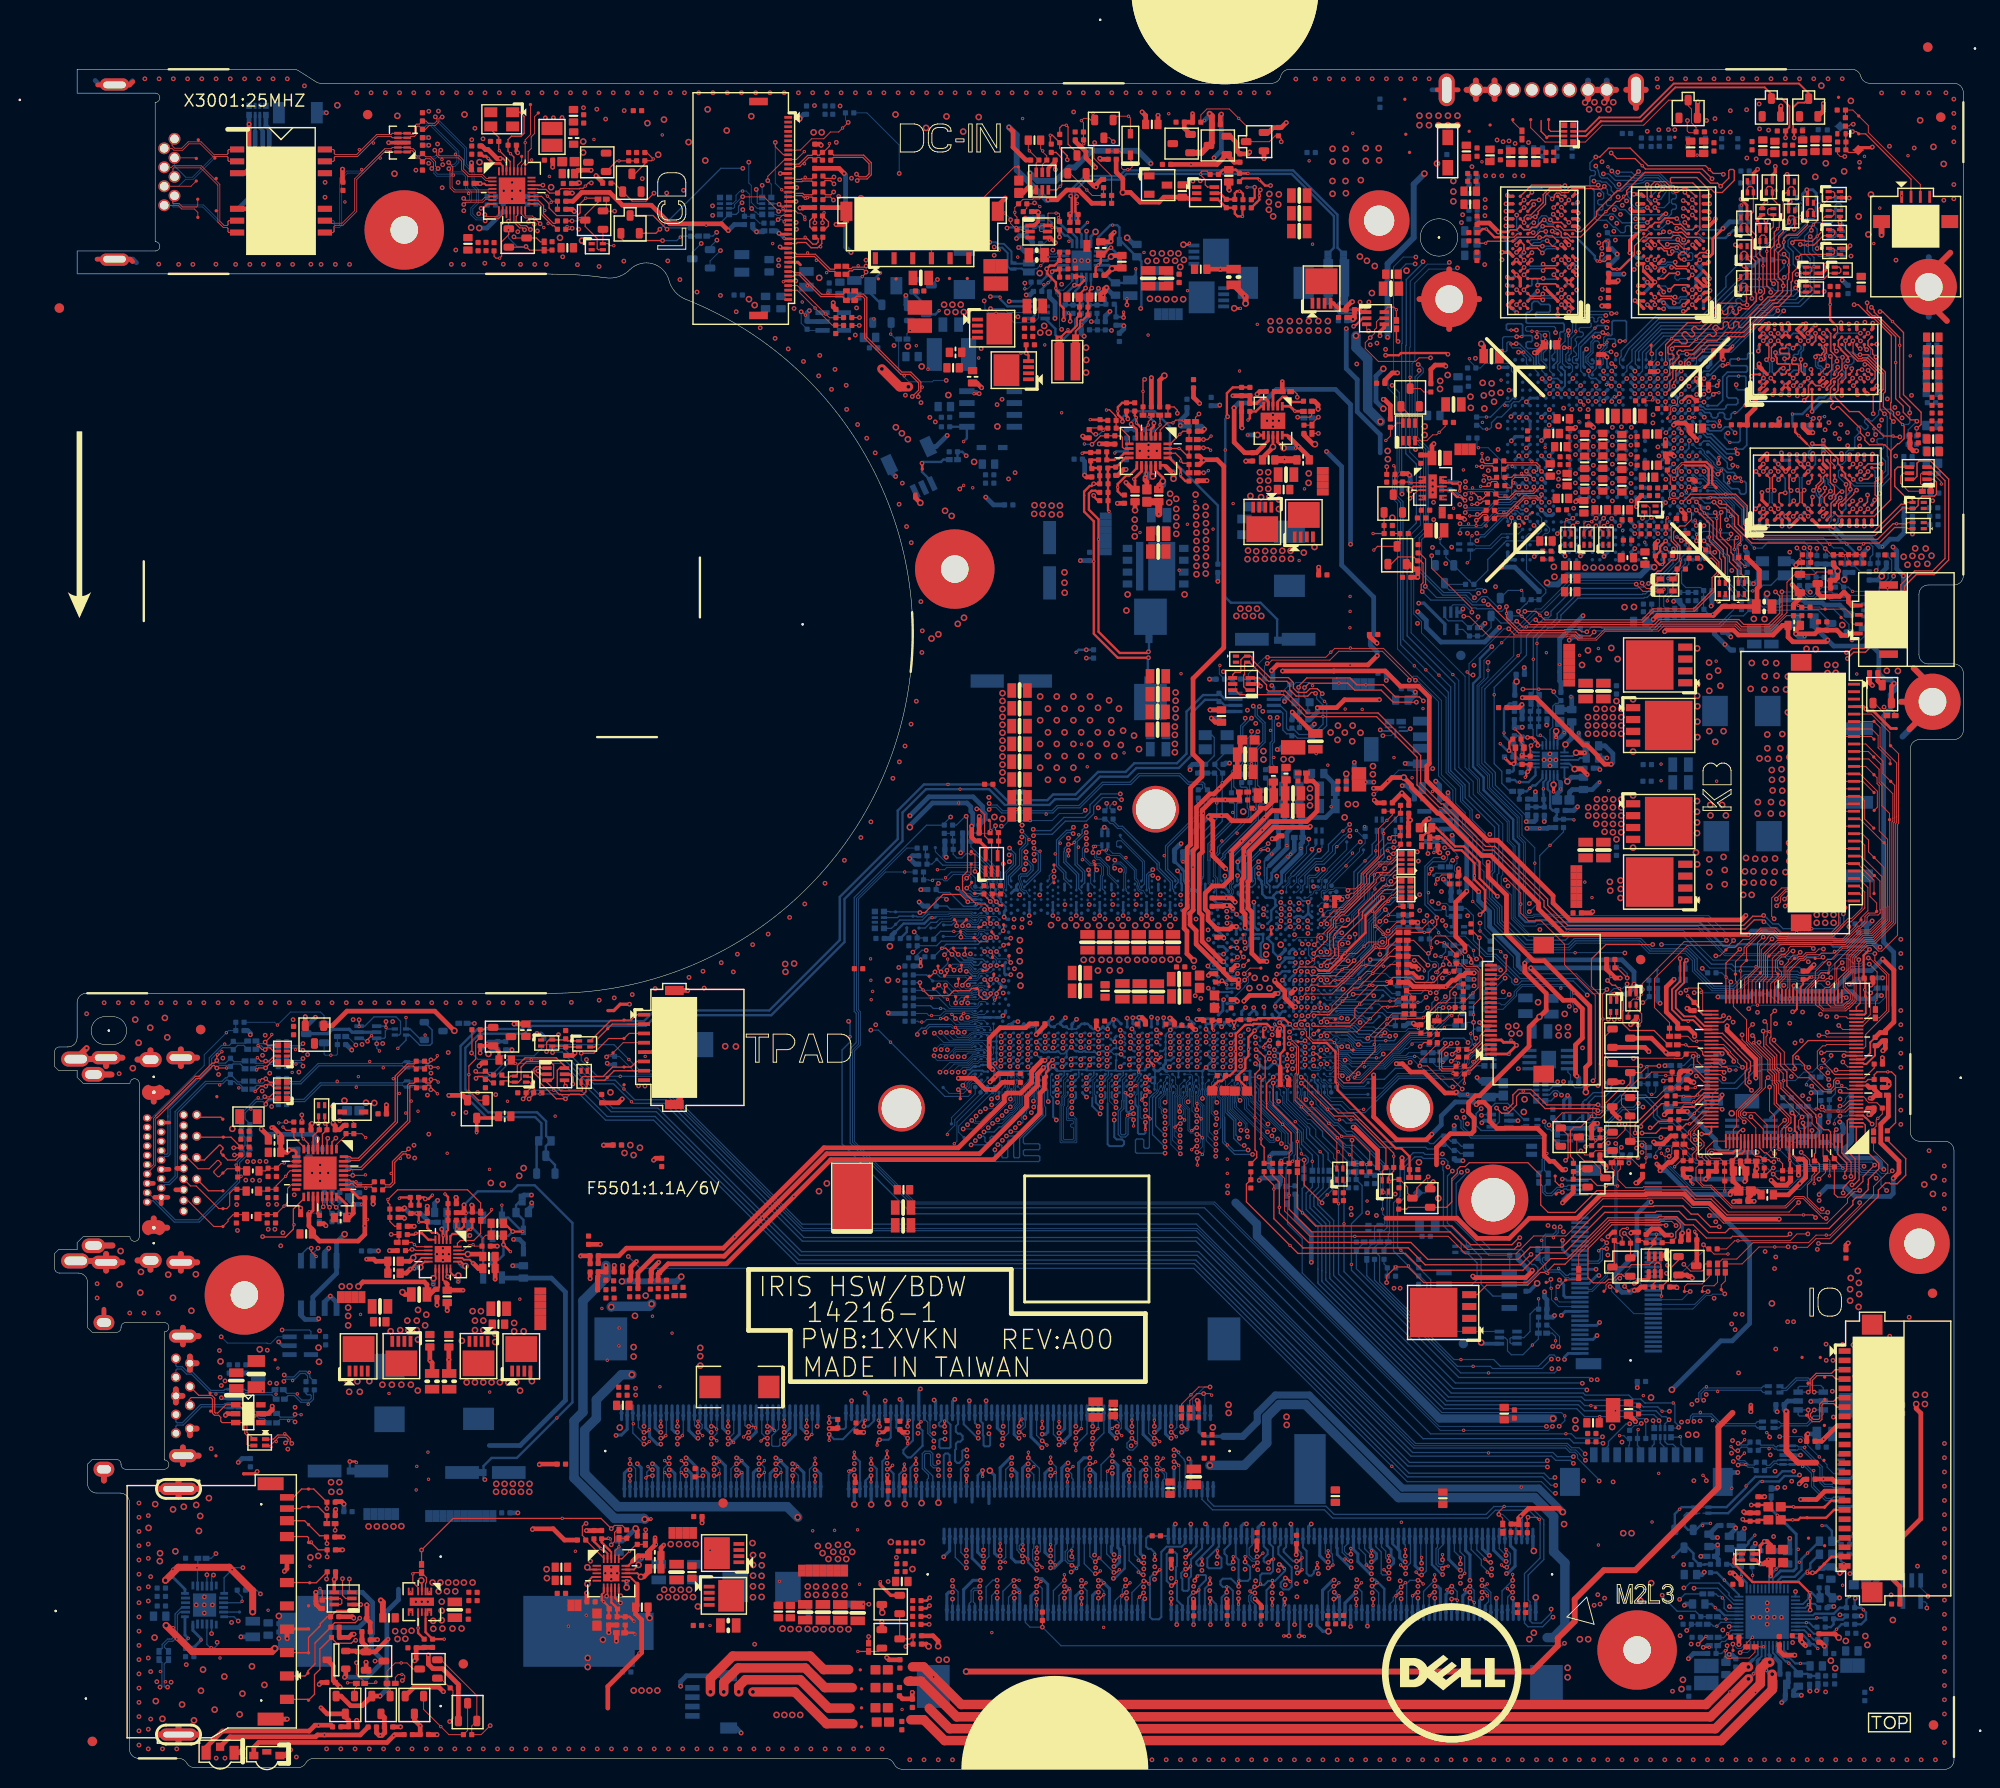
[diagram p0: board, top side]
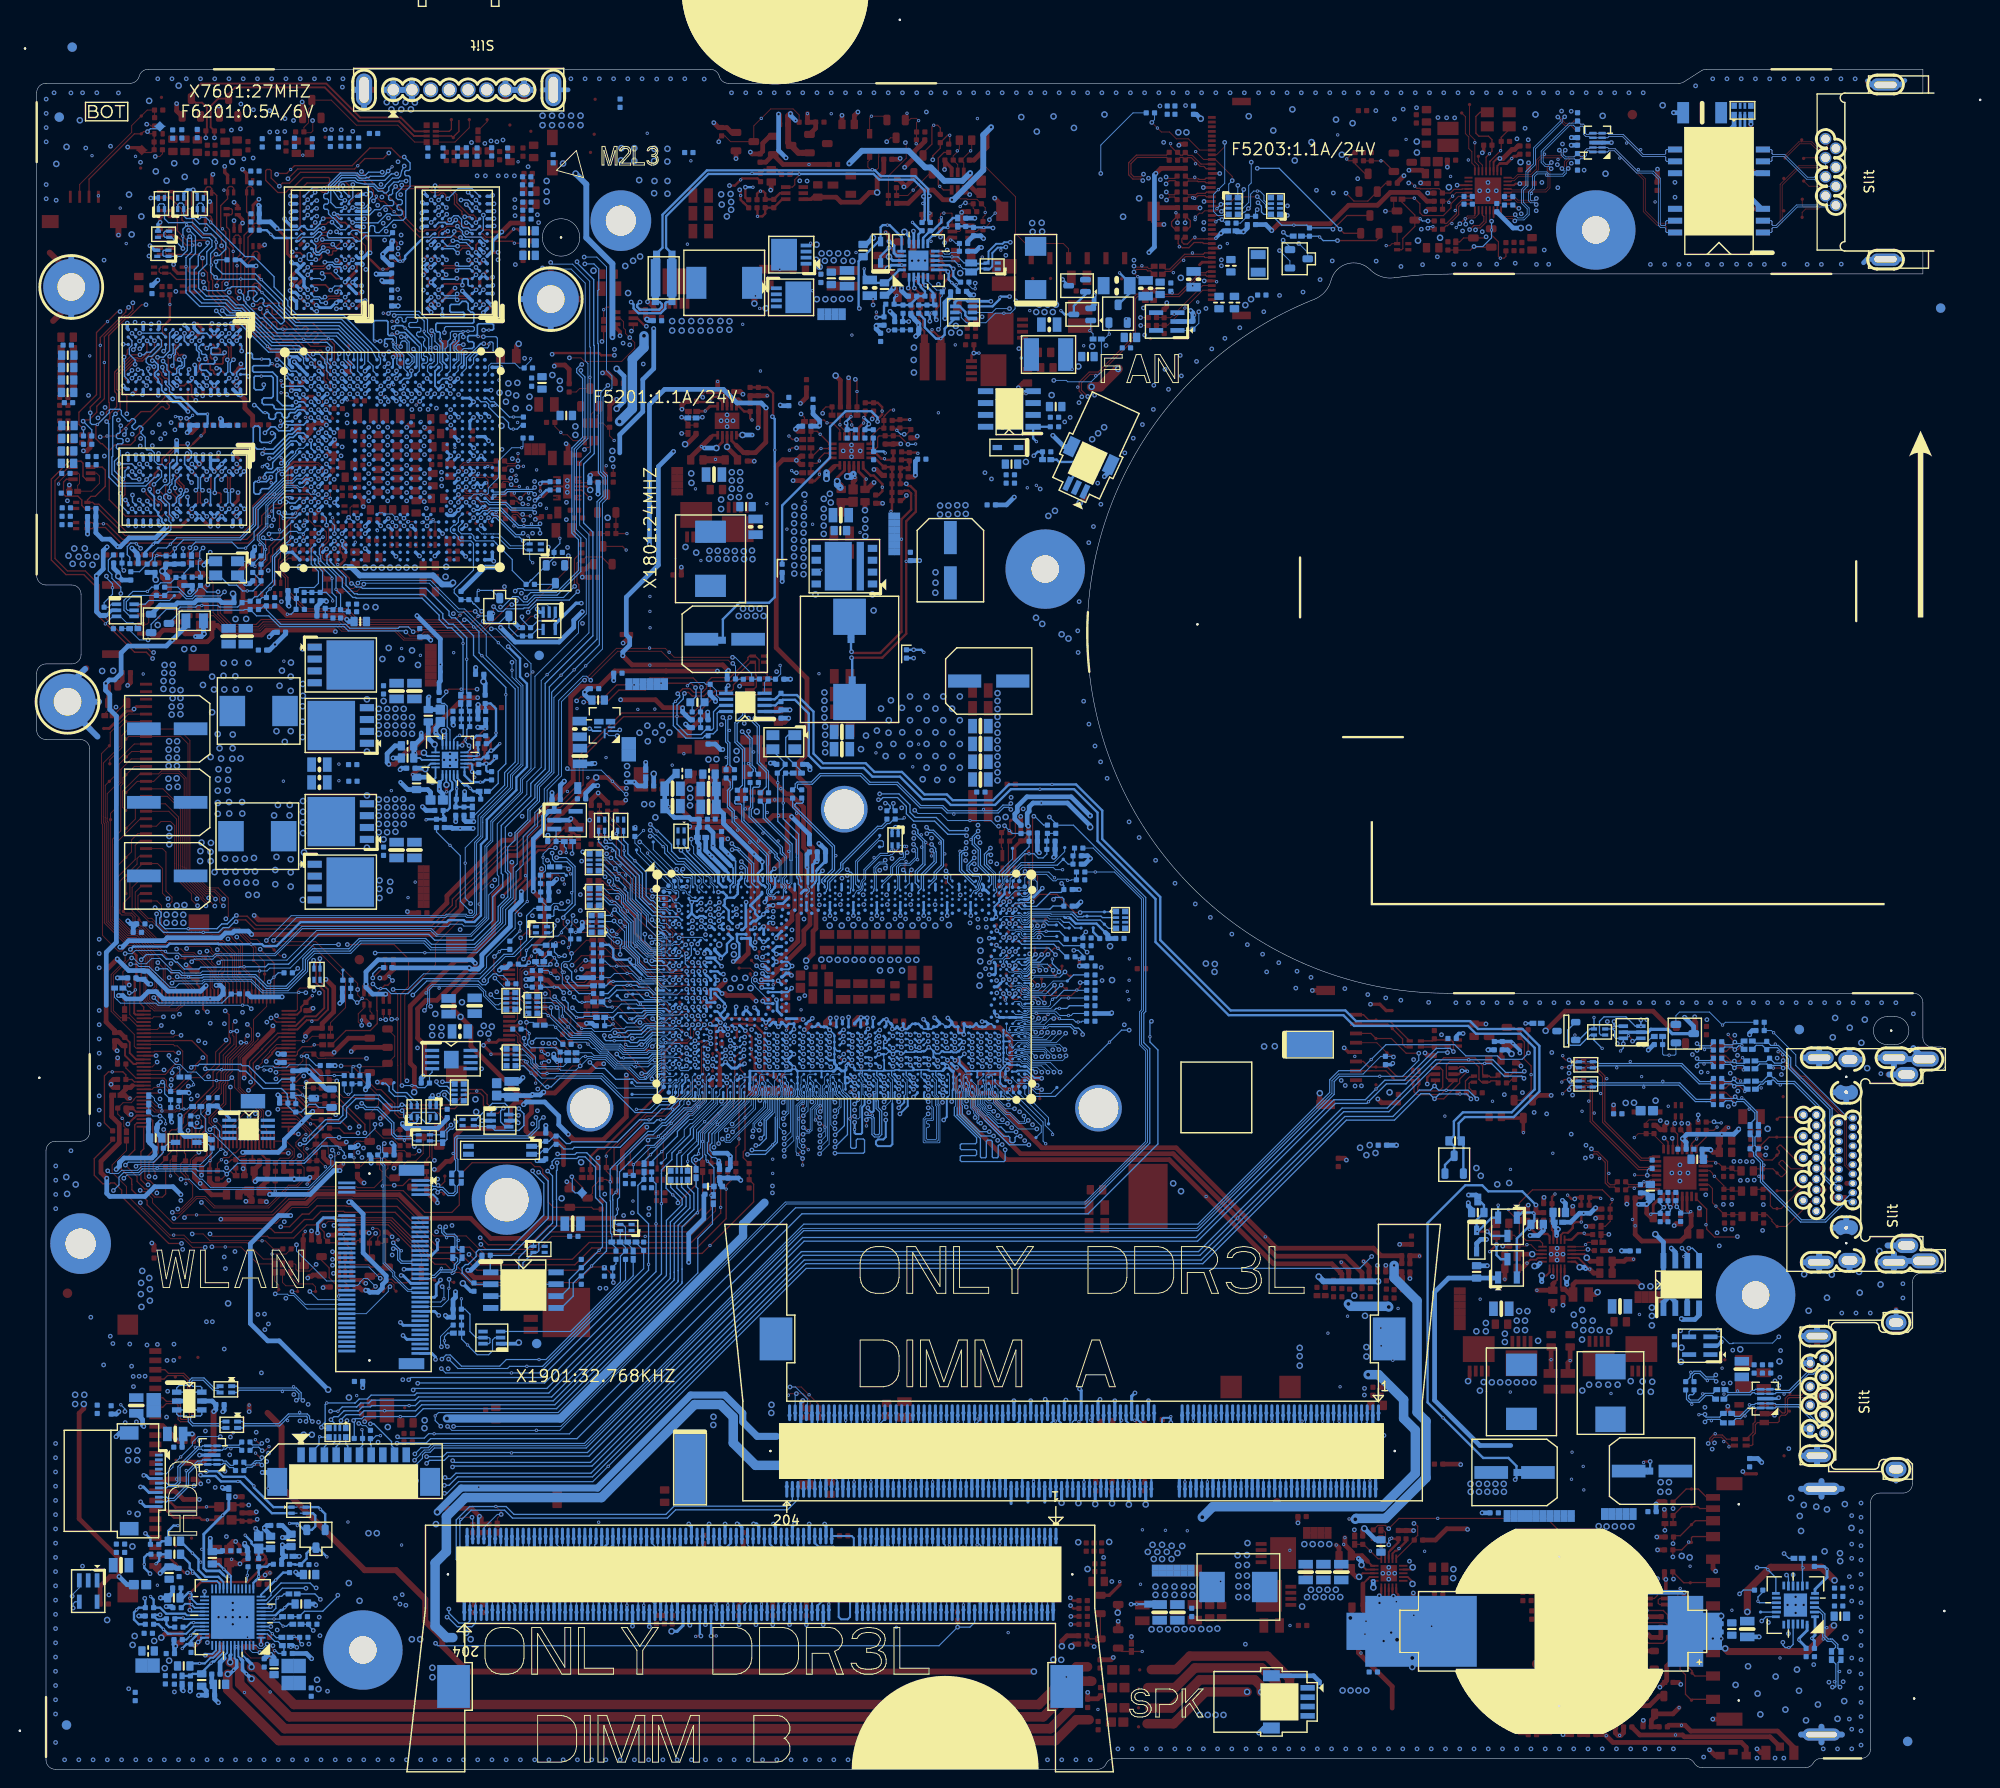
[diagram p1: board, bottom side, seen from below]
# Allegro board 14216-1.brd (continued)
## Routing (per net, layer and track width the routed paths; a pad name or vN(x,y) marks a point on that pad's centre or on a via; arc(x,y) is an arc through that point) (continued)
M_B_DQ63: length 77.3
  TOP w0.14: v2(116.52,20.16) 116.76,20.16 v1(117.08,19.84)
  L3 w0.127: v2(116.52,20.16) 116.5,20.16 115.9,19.56 115.61,19.56 115.48,19.69 115.48,22.87 119.31,26.7 120.25,26.7 128.61,35.05 128.61,41.22 135.78,48.4 135.78,50.71 137.2,52.13 137.2,65.87 132.05,71.02 130.75,71.02 127.82,73.96 127.29,74.48 127.29,75.47 v2(126.87,75.89)
  BOTTOM w0.14: DM2.68 115.25,18.92 116.49,20.16 v2(116.52,20.16) ; v2(126.87,75.89) 127.2,76.22 CPU1.AP18
M_B_DQS0: length 72.3
  TOP w0.127: v1(138.67,23.65) v2(138.67,23.02)
  L4 w0.114: v2(118.79,69.85) 118.79,69.92 119.15,70.27 119.64,70.27 119.74,70.17 119.74,65.67 121.55,63.86 122.21,63.86 123.42,62.65 123.78,62.65 124.36,63.23 124.52,63.23 124.76,62.99 124.76,62.82 124.18,62.24 124.18,61.89 125.69,60.38 127.37,60.38 141.25,46.5 141.78,46.5 142.2,46.08 142.2,45.55 142.84,44.91 143.37,44.91 143.52,44.76 143.52,31.07 143.52,29.65 138.88,25.01 138.88,23.23 v2(138.67,23.02)
  BOTTOM w0.089: v2(118.79,69.85) 118.39,70.25 118.39,70.63 118.14,70.89 118.14,71.79 118.62,72.28 118.62,72.52 118.61,72.55 118.55,72.67 118.55,72.87 118.6,73 118.62,73.05 118.62,73.48 118.87,73.73 118.87,73.94 CPU1.AV30
  BOTTOM w0.127: DM2.137 138.35,24.17 137.99,23.81 137.99,23.32 138.29,23.02 v2(138.67,23.02)
M_B_DQS1: length 70.4
  TOP w0.127: v2(122.18,68.69) 121.98,68.69 v1(121.65,68.36)
  L3 w0.114: v2(122.18,68.69) 121.24,67.75 121.24,64.59 121.34,64.5 121.5,64.34 121.58,64.26 121.58,54.92 103.67,37.02 103.67,34.53 103.32,34.18 103.04,33.9 102.93,33.79 102.93,31.31 98.37,26.75 98.37,19.58 98.99,18.96 v2(99,18.96)
  BOTTOM w0.089: CPU1.AW26 121.23,73.22 121.23,73.02 121.2,72.93 121.16,72.84 121.16,72.72 121.22,72.59 121.23,72.56 121.23,72.04 120.85,71.66 120.85,71.28 121.44,70.69 121.44,68.48 121.63,68.29 121.78,68.29 v2(122.18,68.69)
  BOTTOM w0.127: v2(99,18.96) 98.8,19.16 98.42,19.16 98.28,19.02 98.28,17.91 98.45,17.74 DM2.12
M_B_DQS2: length 85.2
  TOP w0.127: v2(148.48,22.42) v1(148.48,22.98)
  L4 w0.089: 124.82,72.09 124.68,72.24 123.56,72.24 123.16,72.64 122.02,72.64 119.65,75.01 119.65,75.63 119.62,75.65 119.62,76.14 119.91,76.43 119.91,76.79 v2(120.31,77.19)
  L4 w0.114: 124.82,72.09 126.52,70.39 129.1,70.39 130.77,68.72 130.94,68.54 130.94,68.16 132.75,66.35 133.13,66.35 135.46,64.03 138.5,64.03 142.38,60.15 142.38,59.47 142.82,59.03 148.55,53.29 148.55,52.58 151.82,49.31 151.82,47.52 152.07,47.27 152.38,47.27 152.49,47.16 152.49,46.81 152.38,46.7 152.07,46.7 151.82,46.45 151.82,45.39 152.02,45.19 152.02,44.9 152.27,44.66 152.38,44.66 152.49,44.54 152.49,44.2 152.38,44.09 152.27,44.09 152.02,43.84 152.02,43.3 152.27,43.06 152.38,43.06 152.49,42.94 152.49,42.6 152.38,42.49 152.27,42.49 152.02,42.24 152.02,41.7 152.27,41.46 152.38,41.46 152.49,41.34 152.49,41 152.38,40.88 152.27,40.88 152.02,40.64 152.02,40.1 152.27,39.86 152.38,39.86 152.49,39.74 152.49,39.4 152.38,39.28 152.27,39.28 152.02,39.04 152.02,38.5 152.27,38.26 152.38,38.26 152.49,38.14 152.49,37.8 152.38,37.68 152.27,37.68 152.02,37.44 152.02,36.9 152.27,36.66 152.38,36.66 152.49,36.54 152.49,36.2 152.38,36.08 152.27,36.08 152.02,35.84 152.02,35.3 152.27,35.06 152.38,35.06 152.49,34.94 152.49,34.6 152.38,34.48 152.27,34.48 152.02,34.24 152.02,33.7 152.27,33.46 152.38,33.46 152.49,33.34 152.49,33 152.38,32.88 152.27,32.88 152.02,32.64 152.02,26.56 148.8,23.35 148.8,22.53 148.7,22.42 v2(148.48,22.42)
  BOTTOM w0.127: v2(148.48,22.42) 148.6,22.31 148.6,22.06 148.47,21.93 148.16,21.93 148.03,22.06 148.03,23.52 148.55,24.05 DM2.171 ; CPU1.AM28 120.64,77.52 v2(120.31,77.19)
M_B_DQS3: length 73.8
  TOP w0.127: v2(103.58,23.47) v1(103.58,24.03)
  L3 w0.089: 121.67,74.79 121.62,74.85 121.62,75.42 121.6,75.43 121.6,77.2 121.73,77.32 122.09,77.32 v2(122.22,77.19)
  L3 w0.114: 121.67,74.79 125.11,71.36 125.11,65.56 126.45,64.21 126.45,61.3 125.96,60.8 125.96,60.09 126.21,59.84 126.34,59.84 126.45,59.73 126.45,59.39 126.34,59.27 126.21,59.27 125.96,59.03 125.96,58.49 126.21,58.24 126.34,58.24 126.45,58.13 126.45,57.79 126.34,57.67 126.21,57.67 125.96,57.43 125.96,52.36 111.52,37.92 110.47,37.92 109.74,37.18 109.74,34.02 109.55,33.83 109.55,32.8 109.44,32.69 109.12,32.69 108.87,32.44 108.87,31.91 109.12,31.66 109.44,31.66 109.55,31.54 109.55,31.02 108.96,30.44 108.8,30.44 108.66,30.58 108.31,30.58 107.93,30.2 107.93,29.85 108.07,29.71 108.07,29.55 107.83,29.3 107.67,29.3 107.53,29.45 107.18,29.45 106.8,29.07 106.8,28.72 106.94,28.58 106.94,28.41 105.37,26.84 105.21,26.84 105.07,26.98 104.72,26.98 104.34,26.61 104.34,26.25 104.48,26.11 104.48,25.95 103.79,25.27 103.79,23.68 v2(103.58,23.47)
  BOTTOM w0.127: CPU1.AM25 122.49,77.52 122.22,77.25 v2(122.22,77.19) ; v2(103.58,23.47) 103.57,23.45 103.32,23.45 103.19,23.58 103.19,23.93 103.55,24.29 DM2.29
M_B_DQS4: length 74.1
  TOP w0.127: v2(144.04,18.89) 143.81,18.89 v1(143.49,18.57)
  L4 w0.114: v2(124.34,69.64) 124.6,69.64 126.09,68.15 126.09,66.94 127.88,65.16 129.27,65.16 131.27,63.16 131.27,63.08 131.27,62.8 134.64,59.43 134.83,59.43 134.83,59.43 135.6,59.43 137.73,57.3 137.73,56.81 138.47,56.08 139.09,56.08 142.64,52.53 143.53,52.53 144.38,51.68 144.38,49.74 147.74,46.38 147.74,28.07 143.74,24.07 143.74,22.21 143.28,21.74 143.28,20.3 142.67,19.69 142.67,19.11 142.89,18.89 v2(144.04,18.89)
  BOTTOM w0.089: CPU1.AV22 124,73.94 124,73.73 123.76,73.48 123.76,73.05 123.74,73 123.68,72.87 123.68,72.67 123.74,72.55 123.76,72.52 123.76,72.04 123.73,72.01 123.73,70.25 124.33,69.64 v2(124.34,69.64)
  BOTTOM w0.127: DM2.154 143.45,18.31 v2(144.04,18.89)
M_B_DQS5: length 70.4
  TOP w0.127: v1(108.82,23.4) 108.82,22.77 v2(108.82,22.77)
  L3 w0.114: v2(108.82,22.77) 108.69,22.65 108.69,22.4 108.82,22.27 109.13,22.27 109.26,22.4 109.26,24.37 115.92,31.03 115.92,31.82 115.92,33.45 116.75,34.27 116.75,37.06 130.35,50.67 130.35,53.71 131.02,54.38 131.02,54.9 130.75,55.17 130.75,55.68 131.02,55.96 131.02,56.27 130.75,56.55 130.75,57.05 131.02,57.33 131.02,57.64 130.75,57.92 130.75,58.42 131.02,58.7 131.02,59.02 130.75,59.29 130.75,59.8 131.02,60.07 131.02,60.39 130.75,60.66 130.75,61.17 131.02,61.44 131.02,65.59 130.53,66.09 130.53,66.88 130.41,67 130.41,67.62 v2(130.23,67.8)
  BOTTOM w0.089: v2(130.23,67.8) 130.44,67.59 130.44,67.34 130.37,67.28 130.08,67.28 126.43,70.92 126.43,71.38 126.37,71.45 126.37,72.56 126.35,72.59 126.29,72.72 126.29,72.84 126.33,72.93 126.37,73.02 126.37,73.22 CPU1.AW18
  BOTTOM w0.127: DM2.47 108.95,23.8 108.35,23.2 108.35,22.46 108.53,22.28 108.92,22.28 109.05,22.41 109.05,22.54 v2(108.82,22.77)
M_B_DQS6: length 86.1
  TOP w0.127: v2(152.71,19.64) 153.07,19.64 v1(153.27,19.84)
  L4 w0.089: v2(124.97,77.19) 124.97,77.11 124.38,76.52 124.38,75.42 124.39,75.41 124.39,74.93 125.08,74.24 126.03,74.24 126.41,73.87 126.65,73.87
  L4 w0.114: v2(152.71,19.64) 153.31,20.25 153.67,20.25 154.15,19.76 154.34,19.76 154.52,19.95 154.52,23.21 158.15,26.85 158.15,30.22 157.82,30.56 157.24,30.56 156.88,30.92 156.88,50.08 156.03,50.92 156.03,51.91 147.12,60.82 147.12,62.29 144.63,64.78 143.57,64.78 139,69.35 134.77,69.35 131.3,72.82 129.25,72.82 128.2,73.87 126.65,73.87
  BOTTOM w0.127: CPU1.AM21 125.29,77.52 v2(124.97,77.19) ; DM2.188 153.65,18.94 153.19,19.4 152.95,19.4 v2(152.71,19.64)
M_B_DQS7: length 78.3
  TOP w0.127: v1(114.15,18.57) 114.51,18.93 v2(114.67,18.93)
  L3 w0.089: 126.21,75.59 126.21,75.65 126.25,75.68 126.25,76.56 v2(126.87,77.19)
  L3 w0.114: 126.21,75.59 126.21,74.64 127.31,73.53 127.44,73.41 130.41,70.44 130.48,70.37 130.61,70.37 134.71,66.27 134.71,66.24 135.31,65.63 135.31,65.63 136.05,64.89 136.05,60.46 135.31,59.72 135.31,59.01 135.56,58.76 135.94,58.76 136.05,58.64 136.05,58.3 135.94,58.19 135.56,58.19 135.31,57.94 135.31,55.33 136.05,54.59 136.05,52.6 134.63,51.19 134.63,48.88 126.92,41.17 126.92,38.07 126.93,38.07 126.93,37.63 122.82,33.53 122.82,31.25 119.42,27.85 118.83,27.85 114.32,23.33 114.32,21.32 113.72,20.72 113.72,19.26 114.05,18.93 v2(114.67,18.93)
  BOTTOM w0.127: v2(114.67,18.93) 114.05,18.31 DM2.64 ; CPU1.AM18 127.2,77.52 v2(126.87,77.19)
M_B_DQS#0: length 72.4
  TOP w0.127: v1(138.03,22.51) 138.16,22.51 138.39,22.28 v2(138.68,22.28)
  L4 w0.114: v2(138.68,22.28) 139.11,22.71 139.11,24.92 143.75,29.56 143.75,31.16 143.75,44.85 143.46,45.14 142.93,45.14 142.43,45.65 142.43,46.18 141.87,46.73 141.34,46.73 127.47,60.61 125.79,60.61 124.41,61.98 124.41,62.15 124.99,62.73 124.99,63.08 124.62,63.46 124.26,63.46 123.68,62.87 123.52,62.87 122.31,64.09 121.64,64.09 119.97,65.76 119.97,70.26 119.73,70.5 v2(118.79,70.5)
  BOTTOM w0.089: v2(118.79,70.5) 118.33,70.96 118.33,71.72 118.8,72.19 118.8,72.56 118.79,72.59 118.73,72.72 118.73,72.84 118.77,72.93 118.8,73.02 118.8,73.22 CPU1.AW30
  BOTTOM w0.127: v2(138.68,22.28) 138.69,22.28 137.75,23.22 DM2.135
M_B_DQS#1: length 70.6
  TOP w0.127: v1(122.79,67.59) 122.41,67.97 v2(122.21,67.97)
  L3 w0.114: v2(98.97,19.6) 98.76,19.81 98.6,19.97 98.6,26.65 103.16,31.21 103.16,33.69 103.2,33.74 103.48,34.02 103.9,34.44 103.9,36.92 121.81,54.83 121.81,64.35 121.66,64.5 121.5,64.66 121.47,64.69 121.47,67.65 121.87,68.05 122.13,68.05 v2(122.21,67.97)
  BOTTOM w0.089: CPU1.AV26 121.45,73.87 121.06,73.48 121.06,73.05 121.03,73 120.98,72.87 120.98,72.67 121.04,72.55 121.06,72.52 121.06,72.13 120.66,71.74 120.66,71.2 121.25,70.61 121.25,68.4 121.55,68.1 122.08,68.1 v2(122.21,67.97)
  BOTTOM w0.127: v2(98.97,19.6) 98.77,19.4 98.32,19.4 98.04,19.12 98.04,17.94 97.85,17.75 DM2.10
M_B_DQS#2: length 85.4
  TOP w0.127: v1(149.08,21.75) 148.74,21.75 v2(148.48,21.49)
  L4 w0.089: v2(120.31,76.54) 120.29,76.54 119.81,76.07 119.81,75.73 119.84,75.71 119.84,75.09 122.1,72.83 123.24,72.83 123.63,72.43 124.81,72.43 124.97,72.27
  L4 w0.114: 124.97,72.27 126.62,70.62 129.19,70.62 130.86,68.95 131.17,68.64 131.17,68.25 132.84,66.58 133.23,66.58 135.55,64.26 138.59,64.26 142.61,60.25 142.61,59.56 142.91,59.25 148.78,53.39 148.78,52.67 152.05,49.4 152.05,47.61 152.17,47.5 152.48,47.5 152.72,47.26 152.72,46.71 152.48,46.47 152.17,46.47 152.05,46.36 152.05,45.48 152.25,45.28 152.25,45 152.36,44.89 152.47,44.89 152.72,44.64 152.72,44.1 152.47,43.86 152.36,43.86 152.25,43.74 152.25,43.4 152.36,43.29 152.47,43.29 152.72,43.04 152.72,42.5 152.47,42.26 152.36,42.26 152.25,42.14 152.25,41.8 152.36,41.68 152.47,41.68 152.72,41.44 152.72,40.9 152.47,40.66 152.36,40.66 152.25,40.54 152.25,40.2 152.36,40.08 152.47,40.08 152.72,39.84 152.72,39.3 152.47,39.06 152.36,39.06 152.25,38.94 152.25,38.6 152.36,38.48 152.47,38.48 152.72,38.24 152.72,37.7 152.47,37.46 152.36,37.46 152.25,37.34 152.25,37 152.36,36.88 152.47,36.88 152.72,36.64 152.72,36.1 152.47,35.86 152.36,35.86 152.25,35.74 152.25,35.4 152.36,35.28 152.47,35.28 152.72,35.04 152.72,34.5 152.47,34.26 152.36,34.26 152.25,34.14 152.25,33.8 152.36,33.68 152.47,33.68 152.72,33.44 152.72,32.9 152.47,32.66 152.36,32.66 152.25,32.54 152.25,26.47 149.03,23.25 149.03,22.35 148.48,21.81 v2(148.48,21.49)
  BOTTOM w0.127: DM2.169 147.95,24.25 147.95,24.25 147.95,23.78 147.78,23.62 147.78,21.96 148.06,21.69 148.28,21.69 v2(148.48,21.49) ; CPU1.AN28 120.64,76.87 v2(120.31,76.54)
M_B_DQS#3: length 74
  TOP w0.127: v2(103.53,22.83) 103.8,22.83 v1(104.12,22.51)
  L3 w0.089: v2(122.14,76.56) 121.79,76.21 121.79,75.51 121.81,75.5 121.81,74.98 121.83,74.96
  L3 w0.114: 121.83,74.96 125.33,71.45 125.33,65.66 126.68,64.31 126.68,61.2 126.19,60.71 126.19,60.19 126.3,60.07 126.44,60.07 126.68,59.83 126.68,59.29 126.44,59.04 126.3,59.04 126.19,58.93 126.19,58.59 126.3,58.47 126.44,58.47 126.68,58.23 126.68,57.69 126.44,57.44 126.3,57.44 126.19,57.33 126.19,52.27 111.61,37.69 110.57,37.69 109.96,37.09 109.96,33.92 109.78,33.74 109.78,32.71 109.53,32.46 109.21,32.46 109.1,32.34 109.1,32 109.21,31.89 109.53,31.89 109.78,31.64 109.78,30.93 109.06,30.21 108.71,30.21 108.57,30.35 108.4,30.35 108.16,30.11 108.16,29.94 108.3,29.8 108.3,29.45 107.93,29.08 107.58,29.08 107.43,29.22 107.27,29.22 107.03,28.97 107.03,28.81 107.17,28.67 107.17,28.32 105.46,26.61 105.11,26.61 104.97,26.75 104.81,26.75 104.57,26.51 104.57,26.35 104.71,26.21 104.71,25.86 104.02,25.17 104.02,23.28 103.57,22.83 v2(103.53,22.83)
  BOTTOM w0.127: v2(103.53,22.83) 103.14,23.22 103.14,23.29 102.95,23.48 DM2.27 ; CPU1.AN25 122.3,76.56 v2(122.14,76.56)
M_B_DQS#4: length 74.1
  TOP w0.127: v1(144.51,19.98) v2(144.05,19.53)
  L4 w0.114: v2(144.05,19.53) 144.05,19.53 143.64,19.12 142.98,19.12 142.9,19.21 142.9,19.6 143.51,20.2 143.51,21.65 143.97,22.11 143.97,23.98 147.97,27.98 147.97,46.48 144.61,49.83 144.61,51.78 143.63,52.76 142.73,52.76 139.18,56.31 138.56,56.31 137.96,56.91 137.96,57.4 135.69,59.66 134.73,59.66 131.5,62.89 131.5,62.99 131.5,62.99 131.5,63.25 129.37,65.38 127.97,65.38 126.32,67.04 126.32,68.24 124.28,70.29 v2(124.26,70.29)
  BOTTOM w0.089: CPU1.AW22 123.94,73.22 123.94,73.02 123.9,72.93 123.86,72.84 123.86,72.72 123.92,72.59 123.94,72.56 123.95,72.46 123.95,71.96 123.92,71.93 123.92,70.41 124.05,70.29 v2(124.26,70.29)
  BOTTOM w0.127: v2(144.05,19.53) 144.04,19.53 143.59,19.08 143.59,18.79 143.21,18.41 143.21,18.06 142.85,17.7 DM2.152
M_B_DQS#5: length 70.6
  TOP w0.127: v2(108.82,21.83) 108.99,21.83 v1(109.33,21.49)
  L3 w0.114: v2(130.84,67.47) 130.64,67.28 130.64,67.09 130.76,66.97 130.76,66.18 131.25,65.69 131.25,61.35 130.98,61.07 130.98,60.76 131.25,60.48 131.25,59.98 130.98,59.7 130.98,59.38 131.25,59.11 131.25,58.6 130.98,58.33 130.98,58.01 131.25,57.74 131.25,57.23 130.98,56.96 130.98,56.64 131.25,56.37 131.25,55.86 130.98,55.59 130.98,55.27 131.25,55 131.25,54.28 130.58,53.62 130.58,50.57 116.97,36.97 116.97,34.18 116.15,33.36 116.15,31.51 116.15,30.93 109.49,24.27 109.49,22.3 109.23,22.04 109.03,22.04 v2(108.82,21.83)
  BOTTOM w0.089: v2(130.84,67.47) 130.45,67.08 130,67.08 126.24,70.84 126.24,71.28 126.19,71.33 126.19,72.52 126.18,72.55 126.11,72.67 126.11,72.87 126.17,73 126.19,73.05 126.19,73.48 126.43,73.73 126.43,73.94 CPU1.AV18
  BOTTOM w0.127: v2(108.82,21.83) 108.62,22.04 108.43,22.04 108.11,22.36 108.11,23.3 108.35,23.54 DM2.45
M_B_DQS#6: length 86.2
  TOP w0.127: v2(152.71,18.96) 152.88,18.96 v1(153.27,18.57)
  L4 w0.089: v2(124.97,76.54) 124.67,76.54 124.57,76.44 124.57,75.5 124.58,75.49 124.58,75.01 125.16,74.43 126.11,74.43 126.45,74.1 126.68,74.1
  L4 w0.114: v2(152.71,18.96) 153.15,19.4 153.15,19.76 153.4,20.02 153.58,20.02 154.06,19.54 154.43,19.54 154.75,19.85 154.75,23.12 158.38,26.75 158.38,30.32 157.91,30.79 157.33,30.79 157.11,31.02 157.11,50.17 156.26,51.02 156.26,52 147.35,60.91 147.35,62.38 144.72,65.01 143.66,65.01 139.1,69.58 134.87,69.58 131.39,73.05 129.35,73.05 128.3,74.1 126.68,74.1
  BOTTOM w0.127: v2(152.71,18.96) 152.91,19.16 153.09,19.16 153.41,18.84 153.41,17.95 153.05,17.6 DM2.186 ; CPU1.AN21 125.29,76.87 v2(124.97,76.54)
M_B_DQS#7: length 78.2
  TOP w0.127: v2(114.56,19.62) 114.7,19.62 v1(115.04,19.97)
  L3 w0.089: v2(126.87,76.54) 126.44,76.11 126.44,75.59
  L3 w0.114: v2(114.56,19.62) 114.56,19.45 114.28,19.16 114.14,19.16 113.95,19.35 113.95,20.63 114.55,21.22 114.55,23.23 118.93,27.62 119.51,27.62 123.05,31.16 123.05,33.44 127.15,37.54 127.15,38.16 127.15,41.07 134.86,48.78 134.86,51.09 136.28,52.51 136.28,54.69 135.54,55.43 135.54,57.84 135.65,57.96 136.03,57.96 136.28,58.21 136.28,58.74 136.03,58.99 135.65,58.99 135.54,59.1 135.54,59.62 136.28,60.36 136.28,64.99 135.54,65.73 134.93,66.33 134.93,66.37 130.7,70.6 130.57,70.6 127.61,73.56 127.48,73.7 126.44,74.73 126.44,75.59
  BOTTOM w0.127: v2(126.87,76.54) 127.2,76.87 CPU1.AN18 ; v2(114.56,19.62) 114.22,19.28 114.22,18.83 113.45,18.05 DM2.62
M_B_RAS#: length 88.9
  TOP w0.216: v2(130.26,18.23) v1(130.26,17.58)
  L4 w0.089: v2(115.96,77.19) 115.96,77.09 115.58,76.71 115.58,75.08 116.1,74.56 116.1,69.03 116.23,68.9 116.46,68.67 116.46,68.15
  L4 w0.203: 116.46,68.15 116.46,62.25 123.54,55.17 125.26,55.17 136.99,43.45 136.99,30.33 133.37,26.71 133.37,24.98 131.62,23.23 131.62,21.21 130.84,20.43 130.84,19.36 130.74,19.26 130.74,18.62 131.05,18.32 131.05,17.48 131.3,17.23 134.68,17.23 134.93,16.97 134.93,15.65 134.93,15.29 134.48,14.84 130.81,14.84 130.26,15.39 v2(130.26,18.23)
  BOTTOM w0.216: CPU1.AM35 116.06,77.19 v2(115.96,77.19) ; v2(130.26,18.23) 130.25,18.22 DM2.110
M_B_WE#: length 89
  TOP w0.216: v1(132.19,20.1) 131.81,20.47 v2(131.67,20.47)
  L4 w0.089: 116.8,68.21 116.8,68.59 116.28,69.1 116.28,74.61 116.38,74.72 116.38,77.67 116.5,77.78 116.5,78.71 116.72,78.93 116.72,79.86 116.54,80.04 115.69,80.04 115.61,79.96 115.61,79.77 115.7,79.68 116.28,79.68 116.36,79.6 116.36,79.19 116.28,79.1 115.66,79.1 115.46,78.9 115.46,78.33 115.55,78.24 115.88,78.24 115.97,78.33 v2(115.97,78.49)
  L4 w0.203: v2(131.67,20.47) 131.99,20.15 132.36,20.15 132.6,20.39 132.6,20.67 132.34,20.93 132.34,23.17 132.66,23.49 133.35,23.49 133.49,23.63 133.49,24.32 134.42,25.24 134.42,25.56 133.94,26.04 133.94,26.49 138.03,30.58 138.03,30.94 137.55,31.42 137.55,43.68 125.5,55.73 123.77,55.73 117.02,62.48 117.02,63.34 116.8,63.57 116.8,68.21
  BOTTOM w0.216: v2(131.67,20.47) 131.17,19.97 131.17,19.54 131.45,19.25 132.03,19.25 132.34,19.56 132.34,21.61 130.92,23.04 130.92,23.78 131.15,24.01 DM2.113 ; CPU1.AK35 116.3,78.82 v2(115.97,78.49)
M_VREF_CA_DIMMA: length 63.8
  L4 w1.016: 98.28,30.28 94.58,26.57 94.58,26.12 v3(92.76,24.31) ; v3(89.46,24.34) 88.1,24.34 83.29,29.14 61.1,29.14 57.29,32.95 57.29,34.88 60.69,38.28 60.69,47.26 61.59,48.16 61.7,48.16 v3(62.08,48.54)
  BOTTOM w0.33: v3(100.05,31.97) 100.55,31.47 DM1.126
  vias: v1(63.95,48.5)
M_VREF_CA_DIMMB: length 107.8
  L3 w1.016: v3(136.27,14.77) 136.27,13.32 134.85,11.89 101.88,11.89 100.47,13.31 95.78,13.31 94.6,14.49 93.33,14.49 88.12,19.7 88.12,22.74 83.88,26.98 v3(79.49,26.98)
  BOTTOM w0.33: v3(136.27,14.77) 135.68,14.77 135.05,15.4 DM2.126
  BOTTOM w1.016: v3(79.49,26.98) 78.37,28.11 60.26,28.11 56.7,31.67 56.7,36.3 57.96,37.56 57.96,39.56 60.63,42.24 v3(61.75,42.24)
  vias: v1(66.05,46.68)
M_VREF_DQ_DIMMA:
  vias: v1(59.11,43.78) v1(60.39,47.24) v1(60.36,45.33) v3(60.46,36.58)
M_VREF_DQ_DIMMB: length 69.6
  TOP w0.356: v1(63.79,26.8) 63.75,26.76 v3(63.13,26.76)
  TOP w0.508: R3712.2 R3716.2 58.08,52.75 58.15,52.82 R3713.2 58.96,53.26 R3714.1 v2(58.97,53.94)
  L4 w1.016: v3(91.77,21.44) 89.34,21.44 82.81,27.97 64.34,27.97 v3(63.13,26.76)
  BOTTOM w1.016: v2(58.97,53.94) 58.97,52.61 56.51,50.15 56.51,38.23 55.56,37.28 55.56,31.19 59.9,26.86 63.03,26.86 v3(63.13,26.76)
MCP_GPIO8: length 21.3
  TOP w0.127: v2(138.37,73.9) 138.37,74 v1(140.03,75.66) 141.26,76.88 141.26,78.41 143.19,80.34 146.34,80.34 148.04,82.04 148.82,82.04 149.26,82.48 149.26,83.28 150.05,84.07 R2015.2 150.69,83.27 R2031.1
  BOTTOM w0.089: CPU1.AU2 136.54,74.44 136.85,74.75 137.32,74.75 137.36,74.71 137.72,74.71
  BOTTOM w0.102: v2(138.37,73.9) 138.37,74.21 137.87,74.71 137.72,74.71
MCP_GPIO11: length 16.3
  BOTTOM w0.089: CPU1.AN2 136.75,76.91 137.32,76.91 137.46,76.76 137.59,76.76
  BOTTOM w0.102: 137.59,76.76 138.63,76.76 138.86,76.53 141.49,76.53 141.97,77.01 143.74,77.01 145.07,78.33 147.09,78.33 149.43,80.67 v1(149.47,80.67) 149.72,80.92 RN1809.5
MCP_GPIO12: length 47
  TOP w0.102: v2(169.42,79.63) 169.79,80 169.79,80.86 169.19,81.47 RN1701.4
  L3 w0.102: v2(169.42,79.63) 168.31,80.74 164.4,80.74 162.64,82.5 161.7,82.5 159.76,80.56 159.76,78.56 158.09,76.89 155.54,76.89 153.12,79.31 150.87,79.31 150.3,78.74 145.21,78.74 143.87,80.09 141.43,80.09 140.64,79.3 137.86,79.3 136.34,77.78 134.28,77.78 133.83,77.34 v2(133.77,77.34)
  BOTTOM w0.102: CPU1.AM7 133.45,77.66 v2(133.77,77.34) ; v1(169.45,80.19) 169.43,80.17 169.43,80.14 169.42,80.14 v2(169.42,79.63)
MCP_GPIO13: length 12.9
  BOTTOM w0.089: CPU1.AT3 136.07,74.83 136.59,74.83 136.76,75 136.76,75.22 136.95,75.41 137.39,75.41 137.51,75.29
  BOTTOM w0.102: R2020.2 146.21,75.88 145.78,76.31 v1(145.5,76.31) 144.75,76.31 144.62,76.17 143.27,76.17 142.27,75.17 140.75,75.17 139.62,74.03 139.09,74.03 138.03,75.09 137.71,75.09 137.51,75.29
MCP_GPIO14: length 11.6
  TOP w0.102: 142.87,82.23 143.34,82.23 143.66,82.54 R2016.2 ; 142.87,82.23 v1(142.87,82.23) ; 142.87,82.23 142.87,82.23 141.3,82.23 138.6,79.53 134.84,79.53 v2(134.67,79.7)
  BOTTOM w0.102: v2(134.67,79.7) 134.79,79.58 CPU1.AH4
MCP_GPIO15: length 18.2
  L3 w0.102: v2(148.47,84.69) 148,84.69 147.61,84.31 145.94,84.31 145.75,84.49 140.73,84.49 139.89,83.64 138.58,83.64 138,83.07 134.53,83.07 v2(134.02,82.56)
  BOTTOM w0.102: CPU1.AD6 133.83,82.36 v2(134.02,82.56) ; v2(148.47,84.69) 148.63,84.85 148.84,84.85 v1(149.19,85.21) 149.49,85.5 R2014.2
MCP_GPIO26: length 16
  BOTTOM w0.089: 137.75,76.33 137.42,76.33 137.41,76.34 136.06,76.34 CPU1.AN3
  BOTTOM w0.102: 137.75,76.33 138.21,76.33 138.22,76.32 138.46,76.08 138.46,76.08 138.76,75.78 142.01,75.78 143.03,76.79 143.03,76.79 143.83,76.79 145.17,78.13 147.39,78.13 v1(148.67,79.41) 148.92,79.65 R2009.2
MCP_GPIO27: length 40.9
  TOP w0.102: RN2006.3 166.46,80.53 v2(166.22,80.29)
  L3 w0.102: v2(134.68,77.25) 135.02,77.59 136.44,77.59 137.95,79.1 140.72,79.1 141.51,79.89 143.78,79.89 145.21,78.46 150.3,78.46 150.95,79.1 152.86,79.1 155.27,76.69 158.17,76.69 159.96,78.48 159.96,80.48 161.78,82.3 162.55,82.3 164.56,80.29 v2(166.22,80.29)
  BOTTOM w0.102: v2(166.22,80.29) 165.67,80.29 v1(165.64,80.32) ; v2(134.68,77.25) 134.68,77.24 134.45,77.24 CPU1.AN5
MCP_GPIO28: length 13.8
  TOP w0.102: v2(133.38,82.56) 133.81,82.99 136.66,82.99 137.84,84.17 137.92,84.17 139.8,86.06 v1(140.28,86.06) 141.24,86.06 142.66,87.48 142.66,87.86 143.54,88.74 R2017.2
  BOTTOM w0.102: v2(133.38,82.56) 133.18,82.36 CPU1.AD7
MCP_GPIO36: length 12.5
  TOP w0.102: v2(142.05,88.54) 142.04,88.55 140.54,88.55 v1(140.09,88.1) 139.32,87.33 138.57,87.33 137.99,86.75 137.99,86.71 136.45,85.18 135.75,85.18 135.75,85.18 135.18,85.18 134.98,84.98 134.44,84.98 v2(134.01,85.41)
  BOTTOM w0.102: v2(134.01,85.41) 133.83,85.23 CPU1.V6 ; RN1902.1 143.48,89.59 142.43,88.54 v2(142.05,88.54)
MCP_GPIO44: length 11
  TOP w0.102: v2(140.47,78.24) v1(142.56,80.33) 143.11,80.87 R2002.2
  BOTTOM w0.089: 138.4,79.16 136.02,79.16 135.9,79.28 135.53,79.28 CPU1.AK4
  BOTTOM w0.102: 138.4,79.16 138.54,79.16 139.34,78.36 140.01,78.36 140.13,78.24 v2(140.47,78.24)
MCP_GPIO46: length 16.8
  TOP w0.127: R2030.1 148.58,85.43 147.87,84.73 147.87,84.55 147.55,84.23 145.6,84.23 145.09,84.74 144.69,84.74 144.66,84.76 143.19,84.76 142.92,84.49 R2010.2 142.58,83.9 141.59,83.9 v1(139.61,81.92) 139.1,81.41 139.1,80.51 138.49,79.9 136.21,79.9 v2(136.11,79.99)
  BOTTOM w0.102: v2(136.11,79.99) 135.81,80.29 CPU1.AG3
MCP_GPIO55: length 24.1
  TOP w0.127: R2019.1 149.96,87.19 v1(148.67,88.47) 148.62,88.52 v2(147.89,88.52)
  L3 w0.127: v2(133.4,86.35) 133.45,86.35 133.87,85.94 134.91,85.94 135.28,85.57 136.7,85.57 137.23,86.1 139.3,86.1 140.44,87.23 140.8,87.23 140.81,87.23 v2(141.77,87.23) 142.78,87.23 144.28,88.73 147.68,88.73 v2(147.89,88.52)
  BOTTOM w0.127: v2(141.77,87.23) 141.77,88.19 141.6,88.36 141.6,88.73 141.89,89.01 142.28,89.01 142.36,89.09 142.64,89.09 143.1,89.55 143.1,89.89 143.46,90.24 RN1902.2 ; v2(133.4,86.35) 133.18,86.13 CPU1.U7
MCP_GPIO56: length 13.5
  TOP w0.102: R2004.2 143.34,87.87 140.88,85.41 140.36,85.41 v1(139.62,84.67) 136.65,81.7 136.65,81.41 136.3,81.06 135.28,81.06 135.24,81.1 134.55,81.1 134.09,80.65 134.09,80.63 v2(134.09,80.62)
  BOTTOM w0.102: CPU1.AG6 133.83,80.36 v2(134.09,80.62)
MCP_GPIO57: length 10.3
  BOTTOM w0.102: R2022.2 144.86,76.7 144.54,76.38 143.19,76.38 142.19,75.37 140.5,75.37 140.32,75.2 v1(140.11,75.2) 138.81,75.2 138.5,75.51 137.89,75.51 137.52,75.87 CPU1.AP1
MCP_GPIO58: length 10.8
  TOP w0.102: v2(135.46,78.5) 135.91,78.94 139.34,78.94 v1(140.75,80.35) 142.07,81.67 143.59,81.67 143.64,81.72 R2001.2
  BOTTOM w0.102: v2(135.46,78.5) 135.46,78.38 CPU1.AL4
MCP_GPIO73: length 21.7
  BOTTOM w0.089: CPU1.AU4 135.14,74.27 135.49,73.91 135.49,73.65 135.68,73.47 135.92,73.47 136.12,73.28 136.12,72.77 136.17,72.72 136.17,72.22 136.21,72.18
  BOTTOM w0.102: 136.21,72.18 136.51,71.88 141.42,71.88 143.75,74.21 148.55,74.21 148.78,73.98 150.17,73.98 151.72,75.53 v1(151.72,75.72) 151.95,75.95 RN1601.6
MCP_GPIO76: length 12
  BOTTOM w0.102: CPU1.P1 137.14,87.14 138.77,87.14 140.17,88.54 140.17,91.04 v1(141,91.86) 141.4,92.26 141.4,92.4 141.64,92.64 141.64,93.48 141.9,93.74 142.93,93.74 143.49,94.3 RN1801.8
MCP_R: length 39.5
  TOP w0.102: R2004.1 144.71,87.89 R2017.1 145.39,88.74 146.79,87.34 v2(146.97,87.34) 147.26,87.62 147.26,88.7 147.76,89.21 148.76,89.21 150.45,87.52 150.45,87.38 150.73,87.1 150.73,86.25 151.06,85.92 152.2,85.92 152.49,85.62 152.49,82.48 151.8,81.79 v1(151.8,80.78) v2(151.8,79.96) 151.8,78.51 v2(152.05,78.25) ; v2(147.17,83.11) 146.93,83.35 R2013.1 144.63,83.34 145.3,82.67 R2016.1 145.3,81.73 R2001.1 145.33,81.7 R2002.1
  BOTTOM w0.102: R2020.1 147.38,75.7 147.86,75.22 150.44,75.22 150.83,75.61 150.83,76.23 152.05,77.46 v2(152.05,78.25) ; v2(147.17,83.11) 147.17,83.32 147.96,84.11 v1(147.96,85.33) 147.96,85.53 148.06,85.62 148.06,86.2 147.8,86.45 147.26,86.45 146.98,86.74 146.98,87.3 146.97,87.31 v2(146.97,87.34) ; v2(151.8,79.96) 151.08,79.96 R2009.1
MCP_TESTLOW1: length 8.5
  BOTTOM w0.089: 115.51,95.42 115.51,95.42 115.51,95.25 115.79,94.97 115.86,94.8 115.86,94.7 115.8,94.56 115.8,94.56 115.8,94.54 115.78,94.45 115.81,94.29 115.9,94.1 115.98,94.04 CPU1.C35
  BOTTOM w0.102: v1(111.13,98.79) 111.25,98.9 RN1803.4 112.03,98.55 112.68,97.9 112.86,97.9 112.95,97.81 113.91,97.81 115.51,96.21 115.51,95.42
MCP_TESTLOW2: length 7.8
  BOTTOM w0.089: CPU1.C34 116.47,94.04 116.14,94.14 116.09,94.18 116.04,94.22 115.98,94.34 115.97,94.38 115.97,94.52 116.04,94.66 116.04,94.84 115.9,95.17 115.7,95.37
  BOTTOM w0.102: 114.51,97.49 115.7,96.3 115.7,95.37 ; 114.51,97.49 113.96,98.04 113.19,98.04 112.68,98.55 RN1803.3 ; 114.51,97.49 v1(114.61,97.59)
MCP_TESTLOW3: length 17.3
  TOP w0.102: v2(132.11,78.29) 133.08,77.33 133.08,74.47 132.92,74.31 132.92,71.91 v1(137.23,67.61) 137.82,67.01 RN1804.3
  BOTTOM w0.102: v2(132.11,78.29) 132.45,78.63 CPU1.AK8
MCP_TESTLOW4: length 16.7
  TOP w0.102: v2(132.06,77.66) 132.41,77.66 132.87,77.19 132.87,74.59 132.7,74.42 132.7,71.6 v1(133.38,70.92) 137.17,67.13 RN1804.4
  BOTTOM w0.102: CPU1.AL8 132.38,77.98 v2(132.06,77.66)
MCT0: length 7.3
  TOP w0.508: v2(20.8,176.09) 20.8,171.31 20.33,170.84 XF3102.3
  BOTTOM w0.508: RN3101.4 v2(20.8,176.09)
MCT1: length 12.4
  TOP w0.508: XF3102.4 v2(20.69,167.03)
  BOTTOM w0.508: RN3101.1 22.6,175.93 22.96,175.57 22.96,169.21 20.79,167.03 v2(20.69,167.03)
MCT2: length 7.7
  BOTTOM w0.305: RN3101.3 21.45,175.32
  BOTTOM w0.508: 21.45,175.32 21.45,171.62 20.67,170.84 XF3101.4
MCT3: length 11.4
  BOTTOM w0.305: 22.25,175.35 21.95,175.65 RN3101.2
  BOTTOM w0.508: XF3101.3 19.63,167.03 22.25,169.65 22.25,175.35
MDO0+: length 13.7
  TOP w0.089: RJ45.1 11.75,167.38 13.23,167.38 13.59,167.02 14.95,167.02 15.32,166.65 AFTP3107.1
  BOTTOM w0.089: XF3101.1 18.63,164.49 18.54,164.58 18.54,164.93 18.45,165.02 18.04,165.02 15.83,167.23 12.69,167.23 12.5,167.41 RJ45.1
MDO0-: length 13.7
  TOP w0.089: RJ45.2 12.77,168.43 12.64,168.3 12.64,167.69 12.73,167.6 13.32,167.6 13.68,167.23 15.18,167.23 15.31,167.36 AFTP3102.1
  BOTTOM w0.089: 19.51,165.76 18.63,165.76 18.54,165.68 18.54,165.33 18.45,165.24 18.13,165.24 15.92,167.45 12.78,167.45 12.63,167.59 12.63,168.24 RJ45.2
MDO1+: length 13.2
  TOP w0.089: RJ45.3 14.58,169.45 AFTP3101.1
  BOTTOM w0.089: XF3101.5 18.63,172.11 18.54,172.2 18.54,172.55 18.45,172.64 17.27,172.64 14.83,170.2 14.01,170.2 13.26,169.44 11.73,169.44 RJ45.3
MDO1-: length 11.9
  TOP w0.089: AFTP3106.1 15.09,172.49 RJ45.6
  BOTTOM w0.089: 19.51,173.38 18.63,173.38 18.54,173.3 18.54,172.95 18.45,172.86 17.18,172.86 14.74,170.41 14.03,170.41 12.82,171.62 RJ45.6
MDO2+: length 13.4
  TOP w0.089: 17.45,166.82 17.45,165.62 18.05,165.02 18.45,165.02 18.54,164.93 18.54,164.58 18.63,164.49 XF3102.6 ; 17.45,166.82 AFTP3103.1 ; 17.45,166.82 17.45,169.56 15.59,171.43 12.76,171.43 12.66,171.33 12.66,170.62 RJ45.4
MDO2-: length 13.4
  TOP w0.089: 19.51,165.76 18.63,165.76 18.54,165.68 18.54,165.33 18.45,165.24 18.14,165.24 17.67,165.71 17.67,169.65 17.16,170.17 ; RJ45.5 12.5,171.48 12.67,171.64 15.68,171.64 17.16,170.17 ; 17.16,170.17 AFTP3104.1
MDO3+: length 9.3
  TOP w0.089: 17.14,172.64 AFTP3105.1 ; 17.14,172.64 17.14,172.64 16.93,172.64 15.58,173.99 14.37,173.99 13.68,173.3 12.75,173.3 12.54,173.51 RJ45.7 ; 17.14,172.64 18.45,172.64 18.45,172.64 18.54,172.55 18.54,172.2 18.63,172.11 XF3102.2
MDO3-: length 9.4
  TOP w0.089: 15.37,174.21 AFTP3108.1 ; 15.37,174.21 15.67,174.21 17.02,172.86 18.46,172.86 18.54,172.95 18.54,173.3 18.63,173.38 19.51,173.38 ; 15.37,174.21 14.28,174.21 13.59,173.52 12.84,173.52 12.56,173.79 12.56,174.27 RJ45.8
ME_UNLOCK: length 94.6
  TOP w0.102: KBC24.23 189.59,77.59 189.44,77.44 189.15,77.44 188.58,76.87 188.58,75.06 v2(189.8,73.84) ; v2(193.13,61.97) 192.98,61.83 192.55,61.83 191.8,61.08 191.8,60.65 189.61,58.46 178.56,58.46 178.47,58.55 178.47,58.55 176.89,60.13 175.17,60.13 174.16,61.14 170.45,61.14 170.38,61.07 165.64,61.07 161.67,57.09 158.25,57.09 156.34,55.18 150.95,55.18 149.09,57.05 v1(139.1,57.05) 134.3,57.05 131.59,59.76 131.59,63.26 131.17,63.67 R1909.1
  L4 w0.102: v2(193.13,61.97) 193.13,62.33 192.9,62.56 192.9,63.35 191.47,64.78 191.47,70.24 191.27,70.44 190.86,70.44 190.54,70.76 190.54,73.11 189.81,73.84 v2(189.8,73.84)
MIC2_VREFO: length 15.5
  TOP w0.254: 179.73,22.62 179.62,22.52 179.62,22.07 181.64,20.05 186.61,20.05 187.81,18.84 v1(187.81,18.31) v2(187.81,17.05) ; 179.73,22.62 179.73,22.8 179.97,23.05 RN2901.1 ; 179.73,22.62 179.95,22.4 RN2901.2
  BOTTOM w0.203: v2(187.81,17.05) 187.65,16.89 HDA27.29
MIC_CAP: length 3.9
  BOTTOM w0.203: 183.42,20.67 HDA27.19
  BOTTOM w0.254: 183.42,20.67 v1(184.17,21.42) 184.73,21.98 C2713.1
MIC_GND: length 2.6
  TOP w0.305: LCD1.26 77.59,164.32 v2(77.5,164.41)
  BOTTOM w0.356: v2(77.5,164.41) 77.52,164.41 v1(78.04,163.89)
  BOTTOM w0.508: R5201.1 77.23,164.67 v2(77.5,164.41)
MODEL_ID_DET: length 9.4
  TOP w0.102: R2407.1 C2403.2 175.19,65.27 175.19,65.83 175.63,66.27 175.63,66.64 175.03,67.25 175.03,68.24 176.37,69.59 KBC24.94 ; R2407.1 174.23,65.88 R2446.2 ; R2407.1 173.96,65.14 v1(173.31,64.5)
MPWROK: length 146.9
  L3 w0.102: v2(134.66,83.51) 135.4,83.51 135.58,83.32 136.97,83.32 137.62,83.98
  L3 w0.127: v2(160.14,43.91) 160.62,43.43 161.71,43.43 162.3,44.01 162.3,45.89 165.09,48.68 170.33,48.68 171.79,50.13 173.44,50.13 174.49,51.17 174.49,52.93 175.6,54.04 185.66,54.04 187.27,55.66 v2(188.58,55.66) ; v2(182.18,81.03) 182.18,81.11 180.39,82.89 178.76,82.89 177.6,84.05 174.25,84.05 174.08,83.88 172.97,83.88 171.54,85.31 169.56,85.31 169.3,85.58 166.76,85.58 166.45,85.88 159.67,85.88 157.61,87.94 153.98,87.94 153.41,88.51 150.89,88.51 149.77,87.4 149.77,86.08 148.89,85.19 146.11,85.19 145.65,84.73 140.63,84.73 139.88,83.98 137.62,83.98
  L4 w0.127: v2(188.58,55.66) 188.77,55.85 188.89,55.85 189.15,56.11 189.15,58.05 188.84,58.36 188.84,59.35 188.58,59.61 188.58,60.2 188.83,60.44 189.11,60.44 189.48,60.81 189.48,62.45 189.71,62.67 189.71,63.92 189.03,64.6 189.03,67.75 188.7,68.07 188.7,68.67 188.25,69.12 188.25,70.23 186.82,71.66 186.82,71.66 186.56,71.92 186.56,72.31 185.15,73.72 185.15,79.79 184.42,80.52 182.68,80.52 v2(182.18,81.03)
  BOTTOM w0.127: R1707.2 140.38,52.83 150.08,43.14 v1(151.75,43.14) 153.59,43.14 153.83,42.9 159.13,42.9 v2(160.14,43.91) ; v2(134.66,83.51) 134.48,83.33 CPU1.AB5
N12P_JTAG_TCK: length 7.4
  BOTTOM w0.102: GPU1.AE5 157.05,132.69 156.59,132.23 156.41,132.23 156.4,132.24 156.1,132.24 156.09,132.23 155.61,132.23 155.6,132.24 155.3,132.24 155.29,132.23 154.78,132.23 153.51,130.97 152.08,130.97 151.88,131.17 RN7602.3 151.46,131.85 v1(151.65,132.03)
N12P_JTAG_TDI: length 1.4
  TOP w0.102: TP7605.1 157.21,133.41 v2(156.65,133.97)
  BOTTOM w0.102: v2(156.65,133.97) GPU1.AE6
N12P_JTAG_TDO: length 1.5
  TOP w0.102: v2(155.85,133.97) 155.85,133.44 TP7601.1
  BOTTOM w0.102: GPU1.AF6 v2(155.85,133.97)
N12P_JTAG_TMS: length 1.4
  TOP w0.102: TP7602.1 158,134.52 v2(157.45,133.97)
  BOTTOM w0.102: GPU1.AD6 v2(157.45,133.97)
N12P_JTAG_TRST: length 6.1
  BOTTOM w0.102: v1(151.13,129.15) 151.46,129.48 RN7602.4 151.88,130.51 152.05,130.69 153.66,130.69 154.85,131.87 GPU1.AG4
N12P_XTAL_OUTBUFF: length 6.3
  TOP w0.102: R7602.1 172.53,138.72 172.85,138.4 172.85,137.58 R7617.2 173.21,137.12 172.78,136.68 v1(172.78,136.02) 173.08,136.02 173.11,136.05 173.67,136.05 v2(174.07,136.45)
  BOTTOM w0.102: v2(174.07,136.45) 174.1,136.48 174.88,136.48 GPU1.C10
NCT7718_DXN: length 127.8
  BOTTOM w0.254: THM26.3 125.24,114.53 125.1,114.67 125.08,114.67 C2607.2 124.38,114.99 122.86,114.99 121.09,113.22 121.09,108.72 120.06,107.69 115.51,107.69 114.58,106.76 111.63,106.76 109.21,104.35 106.81,104.35 106.2,103.73 101.87,103.73 100.19,105.42 v1(95.57,105.42) 93,105.42 90.2,102.62 90.2,99.58 83.99,93.37 83.99,88.76 76.46,81.23 64.19,81.23 63.04,80.08 50.84,80.08 50,79.24 45.23,79.24 43.43,77.44 43.43,72.56 46.18,69.81 51.41,69.81 52.07,69.15 52.07,67.55 C2606.2 51.56,67.04 Q2603.E
NCT7718_DXP: length 127.5
  BOTTOM w0.254: THM26.2 125.17,113.88 124.88,114.16 124.7,114.16 C2607.1 124.38,114.48 123.07,114.48 121.6,113.01 121.6,108.51 120.27,107.18 115.72,107.18 114.79,106.25 111.84,106.25 109.42,103.84 107.02,103.84 106.41,103.23 101.66,103.23 99.98,104.91 v1(96.87,104.91) 93.21,104.91 90.7,102.41 90.7,99.37 84.5,93.16 84.5,88.55 76.67,80.72 64.4,80.72 63.25,79.57 51.05,79.57 50.21,78.73 45.44,78.73 43.94,77.23 43.94,72.77 46.39,70.32 51.62,70.32 52.58,69.36 52.58,67.79 C2606.1 52.55,66.7 Q2603.C 53.53,64.69 Q2603.B
ODD_PWR_5V:
  vias: v1(155.6,76.54) v1(155.81,78.06) v3(155.51,79.51) v3(155.86,78.74) v3(156.37,79.58) v3(156.73,78.77)
OVER_CURRENT_P8#: length 76.8
  TOP w0.102: v2(174.53,83.38) 174.77,83.62 176.03,83.62 176.31,83.34 176.31,81.31 176.44,81.19 KBC24.65 ; v2(169.2,126.86) 169.2,126.81 169.93,126.09 171.72,126.09 D7602.K
  L4 w0.102: v2(174.53,83.38) 174.13,83.78 172.94,83.78 168.91,87.81 167.51,87.81 167.51,87.81 162.84,87.81 157.98,92.67 v2(157.77,92.67)
  BOTTOM w0.102: v2(157.77,92.67) 158.35,93.25 v1(158.35,96.99) 158.35,98.64 156.98,100.01 156.98,102.05 153.82,105.21 153.82,106.56 152.69,107.69 152.69,115.78 156.1,119.19 156.1,121.45 158.52,123.87 159.11,123.87 162.21,126.96 169.1,126.96 v2(169.2,126.86)
OVERT#: length 11.6
  BOTTOM w0.127: R7652.1 187.64,128.82 188.45,128.01 R7645.2 189.27,127.6 C7609.1 189.87,127 190.93,127 R7613.2 191.89,126.54 v1(192.35,126.08) 193.91,126.08 194.87,125.12 194.87,124.06 194.21,123.41 Q7602.4
OVERT_GPU#: length 13.4
  TOP w0.127: v2(179.35,132.23) 179.35,131.96 v1(179.06,131.66)
  L4 w0.127: v2(187.16,130.73) 186.59,131.3 179.9,131.3 179.53,131.67 179.35,131.85 v2(179.35,132.23)
  BOTTOM w0.127: GPU1.A6 178.08,132.34 179.24,132.34 v2(179.35,132.23) ; R7652.2 187.64,130.25 v2(187.16,130.73)
P2800_VGA_DXN: length 7.7
  TOP w0.102: v2(173.24,138.93) 173.45,139.14 173.45,139.27 174.03,139.85 174.34,139.85 174.42,139.94 174.46,139.94
  TOP w0.254: TP7603.1 177.33,137.63 177.33,139.31 176.71,139.94 174.46,139.94
  BOTTOM w0.254: GPU1.E12 173.64,138.53 v2(173.24,138.93)
P2800_VGA_DXP: length 7.7
  TOP w0.102: v2(173.26,138.13) 173.65,138.52 173.65,139.19 174.11,139.65 174.34,139.65 174.42,139.56 174.46,139.56
  TOP w0.254: 174.46,139.56 176.55,139.56 176.95,139.16 176.95,137.63 TP7604.1
  BOTTOM w0.254: GPU1.F12 172.86,138.53 v2(173.26,138.13)
P_H_S#: length 4.4
  BOTTOM w0.102: R7653.1 193.37,122.21 193.88,122.72 194.56,122.72 195.25,123.41 Q7602.3 196.05,123.41 v1(196.85,122.6)
PANEL_SIZE_ID: length 167.5
  TOP w0.102: v2(151.75,117.13) 151.44,117.13 v1(151.11,117.46)
  L3 w0.102: v2(151.75,117.13) 151.75,112.55 150.05,110.85 150.05,103.44 144.67,98.07 144.67,98.07 143.14,96.54 143.05,96.54 142.43,95.91 141.43,95.91 139.58,94.06 139.58,92.99 138.79,92.21 138.62,92.21 137.73,91.32 v2(137.73,90.88)
  L4 w0.102: v2(73.62,166.95) 73.11,167.46 73.11,168.44 73.6,168.94 73.97,168.94 77.4,172.37 104.19,172.37 105.12,173.3 109.41,173.3 110.76,174.64 111.93,174.64 113.14,173.44 113.21,173.44 113.22,173.42 126.84,173.42 127.59,172.67 129.01,172.67 129.19,172.85 129.76,172.85 130.33,172.28 132.1,172.28 134.27,170.11 134.27,166.29 137.9,162.66 137.9,160.87 137.91,160.86 139.76,159.01 139.93,159.01 141.7,159.01 145.24,155.46 145.24,149.53 145.76,149.02 145.76,142.52 146.67,141.61 146.67,141.52 146.67,141.52 146.67,138.73 146.34,138.4 146.34,131.35 146.29,131.3 146.29,129.62 148.01,127.89 148.01,120.87 v2(151.75,117.13)
  BOTTOM w0.102: R5210.2 75.42,165.5 R5209.1 R5208.2 73.79,166.77 73.62,166.95 v2(73.62,166.95) ; v2(137.73,90.88) 137.39,90.54 136.82,90.54 136.46,90.18 CPU1.J2
PANEL_SIZE_ID_CONN: length 2.8
  TOP w0.102: v2(77.4,165.88) 77.39,165.88 77.83,166.32 LCD1.22
  BOTTOM w0.102: v1(78.04,165.64) 77.8,165.88 v2(77.4,165.88) 77.02,165.5 R5210.1
PBAT_PRES1#: length 5.1
  TOP w0.102: RN4301.8 159.45,174.18 157.92,175.71 AFTP3902.1
PBAT_SMBCLK1: length 2.8
  TOP w0.14: RN4301.6 160.05,175.33 159.83,175.54 AFTP3904.1
PBAT_SMBDAT1: length 4
  TOP w0.14: 159.03,176.49 159.03,175.32 159.63,174.72 AFTP3903.1 159.81,174.83 RN4301.7
PCB_VER_AD: length 8.9
  TOP w0.102: KBC24.98 179.2,66.47 179.03,66.3 177.55,66.3 177.46,66.39 177.1,66.39 176.85,66.14 176.85,65.78 177.21,65.41 178.15,65.41 R2406.1 C2402.2 178.66,63 R2404.2 178.67,61.91 v1(178.68,61.9)
PCH_DPB_AUXN: length 129
  TOP w0.127: v2(37.87,66.41) 37.57,66.11 37.18,66.11 36.14,65.07 36.14,63.78 ; C5528.1 35.41,62.56 35.85,62.56 36.14,62.86 36.14,63.78 ; 36.14,63.78 v1(36,63.78)
  L4 w0.114: v2(37.87,66.41) 37.58,66.12 37.47,66.12 37.24,66.34 37.24,67.4 40.93,71.08 72.42,71.08 88.46,87.12 89.71,87.12 91.32,88.73 92.56,88.73 94.56,90.73 97.16,90.73 100.54,94.11 106.64,94.11 108.09,95.56 114.68,95.56 115.95,96.83 117.76,96.83 119.58,95.01 121.37,95.01 122.32,94.06 125.74,94.06 127.27,92.54 127.27,91.36 127.83,90.8 129.58,90.8 130.52,91.73 130.52,94.02 132.07,95.58 135.23,95.58 135.5,95.85 135.5,96.11 v2(135.74,96.35)
  BOTTOM w0.089: 134.22,95.36 134.2,95.34 134.2,94.64 134.27,94.57 134.27,93.96 CPU1.C5
  BOTTOM w0.127: 134.22,95.36 134.31,95.45 134.98,95.45 135.74,96.21 v2(135.74,96.35)
PCH_DPB_AUXP: length 129
  TOP w0.127: C5527.1 35.39,62.32 35.95,62.32 36.38,62.76 36.38,64.97 36.89,65.48 ; 36.89,65.48 37.28,65.87 37.6,65.87 v2(37.87,65.6) ; 36.89,65.48 v1(36.99,65.38)
  L4 w0.114: v2(135.06,96.36) 135.15,96.36 135.27,96.24 135.27,95.95 135.13,95.8 131.98,95.8 130.29,94.11 130.29,91.82 129.49,91.03 127.92,91.03 127.49,91.45 127.49,92.63 125.83,94.29 122.41,94.29 121.46,95.24 119.67,95.24 118.01,96.9 117.85,97.06 115.85,97.06 114.58,95.79 108,95.79 106.55,94.34 100.45,94.34 100.31,94.2 97.07,90.96 94.46,90.96 92.46,88.96 91.23,88.96 89.62,87.35 88.36,87.35 72.33,71.31 40.84,71.31 37.02,67.49 37.02,66.25 37.37,65.89 37.75,65.89 37.87,65.77 v2(37.87,65.6)
  BOTTOM w0.089: CPU1.B5 134.01,94.47 134.01,95.49 134.05,95.53
  BOTTOM w0.127: v2(135.06,96.36) 135.21,96.36 135.3,96.27 135.3,96.11 134.88,95.69 134.21,95.69 134.05,95.53
PCH_DPC_AUXN_U: length 3.8
  TOP w0.127: v1(32.24,62.89) 32.12,62.78 ; 32.12,62.78 32.32,62.58 33.89,62.58 C5528.2 ; 32.12,62.78 31.95,62.95 31.69,62.95 31.56,63.08 U5502.27
PCH_DPC_AUXP_U: length 3.8
  TOP w0.127: C5527.2 33.89,62.34 33.28,62.34 ; 33.28,62.34 32.22,62.34 31.85,62.71 31.69,62.71 31.56,62.58 U5502.26 ; 33.28,62.34 v1(33.28,62.18)
PCH_DPC_N0_U: length 14.2
  TOP w0.127: 37.76,70.25 37.76,73.23 37.97,73.44 38.42,73.44 38.71,73.73 C5526.2 ; 37.76,70.25 v1(37.56,70.25) ; 37.76,70.25 37.76,69.44 32.75,64.43 31.71,64.43 31.56,64.58 U5502.30
PCH_DPC_N1_U: length 15.2
  TOP w0.127: 36.43,73.92 36.43,69.36 32.5,65.42 31.74,65.42 31.58,65.58 U5502.32 ; 36.43,73.92 v1(36.23,73.92) ; 36.43,73.92 36.43,74.21 37.73,75.52 38.49,75.52 38.68,75.71 C5525.2
PCH_DPC_P0_U: length 14.1
  TOP w0.127: 38,71.52 v1(38.15,71.52) ; 38,71.52 38,73.13 38.07,73.2 38.57,73.2 38.71,73.07 C5529.2 ; 38,71.52 38,69.34 32.85,64.19 31.68,64.19 31.56,64.08 U5502.29
PCH_DPC_P1_U: length 15.2
  TOP w0.127: C5530.2 38.36,75.28 37.83,75.28 36.67,74.11 36.67,72.34 ; 36.67,72.34 v1(36.87,72.34) ; 36.67,72.34 36.67,69.26 32.6,65.18 31.71,65.18 31.6,65.08 U5502.31
PCH_DPWROK: length 22.8
  BOTTOM w0.089: CPU1.AV5 134.2,73.51 134.2,72.27 134.95,71.52 134.95,71.18 135.49,70.64
  BOTTOM w0.127: 135.49,70.64 136.93,69.2 137.27,69.2 138.19,68.29 138.8,68.29 142.84,64.24 v1(142.84,62.88) 142.84,60.85 142.81,60.81 142.81,57.4 142.67,57.26 R1704.1 142.67,56.26 142.22,55.81 R1718.1
PCH_HDMI_CLK: length 134.7
  TOP w0.14: v2(35.45,80.04) v1(35.45,79.42)
  L3 w0.127: v2(35.45,80.04) 35.45,79.66 35.55,79.55 36.37,79.55 37.99,81.18 56.78,81.18 63.81,74.15 63.81,73.58 v2(64.2,73.19)
  L4 w0.127: v2(114.14,103.78) 114.38,104.03 114.67,104.03 116.13,105.48 120.28,105.48 121.22,104.55 127.88,104.55 132.39,100.03 134.37,100.03 134.72,99.68 134.72,98.69 v2(134.51,98.48) ; v2(104.72,99.93) 104.84,99.93 105.32,99.45 105.32,96.21 104.39,95.29 99.32,95.29 97.75,93.72 97.28,93.72 95.44,91.88 93.95,91.88 92.82,90.74 90.45,90.74 73.82,74.12 67.35,74.12 65.67,72.44 64.17,72.44 63.88,72.72 63.88,72.88 v2(64.2,73.19)
  BOTTOM w0.089: CPU1.B9 131.49,94.44 131.96,94.91 131.96,95.43 132.26,95.73 132.26,95.87 132.28,95.89
  BOTTOM w0.14: v2(35.45,80.04) 35.45,79.7 35.3,79.55 Q5402.4 ; v2(104.72,99.93) 104.87,100.09 106.72,100.09 108.13,101.49 110.37,101.49 111.16,102.28 111.16,103.06 112.11,104.02 113.66,104.02 113.89,103.78 v2(114.14,103.78) ; RN1501.4 134.94,98.91 v2(134.51,98.48) 134.61,98.38 134.61,98.22 132.55,96.16 132.28,95.89
PCH_HDMI_DATA: length 139
  TOP w0.14: v1(33.9,78.53) 33.47,78.1 v2(33.47,77.94)
  L3 w0.127: v2(63.15,73.14) 63.43,73.42 63.43,73.99 56.63,80.8 38.15,80.8 36.53,79.17 35.06,79.17 33.82,77.94 v2(33.47,77.94)
  L4 w0.127: v2(135.27,98.37) 135.1,98.54 135.1,99.84 134.52,100.41 132.55,100.41 128.04,104.93 121.38,104.93 120.44,105.86 115.97,105.86 114.51,104.41 v2(114.01,104.41) ; v2(63.15,73.14) 63.5,72.79 63.5,72.56 64.01,72.05 64.33,72.05 64.33,72.05 65.83,72.05 67.51,73.74 73.98,73.74 90.61,90.36 92.97,90.36 94.11,91.5 95.6,91.5 97.44,93.34 97.91,93.34 99.48,94.9 104.55,94.9 105.7,96.06 105.7,99.61 v2(104.69,100.62)
  BOTTOM w0.089: CPU1.C9 131.76,94.45 132.15,94.83 132.15,95.35 132.4,95.6 132.54,95.6 132.56,95.61
  BOTTOM w0.14: v2(33.47,77.94) 33.3,77.94 32.99,78.25 Q5402.1 ; v2(104.69,100.62) 104.83,100.48 106.56,100.48 107.97,101.89 110.2,101.89 110.76,102.44 110.76,103.23 111.94,104.41 v2(114.01,104.41) ; RN1501.3 135.59,98.69 v2(135.27,98.37) 135.27,98.33 132.56,95.61
PCH_INTVRMEN: length 14.8
  BOTTOM w0.089: CPU1.AV7 132.95,73.59 132.7,73.34 132.7,71.53 134.07,70.17 134.46,70.17 134.52,70.1
  BOTTOM w0.102: 134.52,70.1 138.04,66.58 138.51,66.58 v1(140.37,64.72) R1903.2 140.39,63.59 R1913.2
PCH_JTAG_TCK: length 7.7
  BOTTOM w0.089: CPU1.AE62 98.94,81.11 98.65,80.92 98.56,80.88 98.52,80.87 98.46,80.87 98.41,80.88 98.22,80.96 98.18,80.99 98.18,80.99 98.08,81.08 95.13,81.08 94.73,80.69
  BOTTOM w0.114: 94.73,80.69 v1(93.81,80.69) 93.53,80.69 93.31,80.9 R1920.2
PCH_JTAG_TDI: length 9.3
  BOTTOM w0.089: CPU1.AD61 99.54,82.19 99,82.19 98.81,82 98.81,81.81 98.62,81.62 95.95,81.62 95.73,81.85 95.73,82.21 95.57,82.37
  BOTTOM w0.114: R1916.1 94.3,83.38 95.11,82.57 95.36,82.57 v1(95.52,82.42) 95.57,82.37
PCH_JTAG_TDO: length 8.5
  BOTTOM w0.089: 94.69,80.26 95.33,80.91 97.79,80.91 98.17,80.76 98.31,80.72 98.37,80.71 98.4,80.7 98.43,80.7 98.55,80.7 98.61,80.71 98.73,80.76 98.87,80.79 99.45,80.79 CPU1.AE61
  BOTTOM w0.114: 94.69,80.26 93.3,80.26 93.02,79.99 v1(92.77,79.99) 92.44,79.99 92.35,80.08 R1917.1
PCH_JTAG_TMS: length 7.9
  BOTTOM w0.089: CPU1.AD62 99.14,81.89 98.69,81.45 95.7,81.45 95.34,81.81
  BOTTOM w0.114: 95.34,81.81 94.59,82.56 v1(93.81,82.56) R1918.1
PCH_JTAG_TRST#: length 4.4
  TOP w0.114: v2(96.68,72.75) 96.88,72.56 TP1901.1
  BOTTOM w0.089: CPU1.AU62 98.79,74.07 98.28,74.07
  BOTTOM w0.114: 98.28,74.07 98.15,73.95 98.13,73.95 97.62,73.43 97.62,73.08 97.33,72.79 96.99,72.79 96.98,72.8 96.73,72.8 v2(96.68,72.75)
PCH_OPIRCOMP: length 11.3
  BOTTOM w0.089: CPU1.AW15 128.78,72.82 128.78,71.6
  BOTTOM w0.127: v1(131.22,65.14) 131.57,65.49 131.96,65.49 132.44,65.98 132.44,67.08 132.32,67.2 132.32,68.06 128.78,71.6
  BOTTOM w0.508: R2003.1 131.14,64.7 131.22,64.78 v1(131.22,65.14)
PCH_PWROK: length 277.1
  TOP w0.127: Q3601.3 31.53,19.21 v2(31.53,20.38) ; v2(161.65,65.18) 161.91,65.44 161.91,67.88 Q2602.G ; KBC24.100 180,68.08 180.34,68.43 v2(180.63,68.43)
  L3 w0.127: v2(160.91,42.89) 161.65,42.89 162.55,43.79 162.55,45.73 165.16,48.34 170.36,48.34 171.89,49.88 174.98,49.88 175.87,50.77 175.87,51.89 177.58,53.6 v2(184,53.6) ; v2(180.63,68.43) 179.54,68.43 177.58,66.47 175.42,66.47 174.39,67.49 172.61,67.49 172.03,68.08 170.98,68.08 170.16,67.26 169.32,67.26 168.98,66.93 168.61,66.93 167.8,66.12 166.84,66.12 166.38,66.58 165.01,66.58 164.47,67.11 163.54,67.11 161.65,65.22 v2(161.65,65.18) ; v2(165.09,18.69) 162.78,16.38 161.02,16.38 154.08,9.44 93.49,9.44 92.19,10.74 63.96,10.74 63.61,10.39 55.38,10.39 50.33,15.44 50.33,17.78 44.31,23.8 40.57,23.8 38.93,22.17 34.03,22.17 32.24,20.38 v2(31.53,20.38)
  L4 w0.127: v2(184,53.6) 184,53.65 183.46,54.2 183.46,58.26 182.29,59.43 182.29,62.27 180.87,63.69 180.87,68.18 v2(180.63,68.43) ; v2(160.91,42.89) 160.91,40.8 162.14,39.57 162.14,36.01 163.23,34.92 163.23,32.35 164.54,31.05 164.54,19.25 v2(165.09,18.69)
  BOTTOM w0.127: v2(160.91,42.89) 160.45,42.43 v1(153.4,42.43) 150.43,42.43 139.26,53.59 EC1704.1 140.08,56.37 R1706.1
PCH_SLP_S0#: length 5.2
  BOTTOM w0.089: CPU1.AF3 135.99,81.08 136.24,80.83 137.27,80.83 137.43,81 138.97,81 139.05,80.93
  BOTTOM w0.127: 139.05,80.93 139.34,80.64 140.01,80.64 140.23,80.42 140.42,80.42 TP1706.1
PCH_SLP_WLAN#: length 1.4
  TOP w0.127: TP1705.1 133.67,77.89 v2(133.77,77.99)
  BOTTOM w0.127: CPU1.AM5 134.1,77.66 v2(133.77,77.99)
PCH_SMBCLK: length 323.6
  TOP w0.14: v2(45.04,74.72) 45.22,74.54 45.89,74.54 EC6206.1 46.5,74.31 R6204.1 ; v2(30.08,67.57) 29.67,67.15 29.67,66.36 U5502.2 ; v2(154.26,70.78) 154.81,70.23 155.53,70.23 156.4,71.1 156.4,72.02 156.75,72.37 157.82,72.37 159.47,70.72 164.9,70.72 165.09,70.53 165.09,70.51 v2(165.1,70.5)
  L3 w0.127: v2(159.69,33.04) 159.85,32.88 160.52,32.88 160.82,33.18 160.82,35.62 161.51,36.31 161.51,40.77 163.52,42.78 163.9,42.78 167.83,46.71 170.92,46.71 172.48,48.27 178.66,48.27 179.57,49.17 180.06,49.17 v2(180.54,48.7) ; v2(30.08,67.57) 30.34,67.57 31.68,68.91 31.68,72.75 39.21,80.28 43.46,80.28 43.97,79.77 43.97,75.13 44.53,74.58 44.9,74.58 v2(45.04,74.72)
  L4 w0.127: v2(180.54,48.7) 180.43,48.81 180.43,51.93 179.26,53.09 179.26,56.23 176.11,59.38 176.11,64.47 175.51,65.06 175.51,66.51 175.91,66.91 v2(176.02,66.91) ; v2(159.69,33.04) 159.95,32.78 160.13,32.78 162.57,30.35 162.57,20 160.1,17.53 v2(160.1,17.15)
  BOTTOM w0.14: Q1801.4 154.03,68.78 154.57,69.32 154.57,70.47 v2(154.26,70.78) ; v2(45.04,74.72) 45.17,74.59 47.04,74.59 48.4,75.95 v1(50.99,75.95) 54.53,75.95 59.7,70.78 64.53,70.78 79.9,55.41 122.38,55.41 144.95,32.85 159.51,32.85 v2(159.69,33.04) ; RN1810.3 162.1,69.39 162.28,69.21 162.59,69.21 163.18,69.79 RN9601.2 163.48,69.36 163.63,69.21 164.34,69.21 164.94,69.81 164.94,70.34 165.1,70.5 v2(165.1,70.5) 166.39,70.5 167.67,71.78 170.05,71.78 171.05,70.78 171.05,69.84 171.75,69.14 173.14,69.14 175.38,66.91 v2(176.02,66.91) ; v2(160.1,17.15) 160.1,16.73 159.03,15.66 158.08,15.66 157.85,15.88 DM2.202 157.85,17.92 157.64,18.12 157.64,20.79 159.31,22.46 159.31,26.21 159.31,26.7 157.88,28.13 157.55,28.13 157.55,28.13 153.97,28.13 153.13,27.28 136.89,27.28 136.01,28.17 124.03,28.17 123.35,28.85 DM1.202
PCH_SMBDATA: length 322.1
  TOP w0.14: U5502.3 29.14,67.47 v2(29.22,67.54) ; R6210.1 46.76,73.47 46.39,73.84 EC6205.1 45.79,74.14 45.26,74.14 v2(45.08,73.96) ; v2(155.18,70.75) 155.49,70.75 156.01,71.27 156.01,72.19 156.59,72.76 157.98,72.76 159.63,71.12 164.86,71.12 164.88,71.14 v2(165.12,71.14)
  L3 w0.127: v2(45.08,73.96) 44.84,74.2 44.37,74.2 43.59,74.98 43.59,79.61 43.3,79.9 39.37,79.9 32.06,72.59 32.06,68.76 30.37,67.06 29.7,67.06 v2(29.22,67.54) ; v2(179.82,48.73) 179.66,48.73 178.82,47.88 172.63,47.88 171.08,46.33 167.98,46.33 164.05,42.4 163.68,42.4 161.89,40.61 161.89,36.15 161.2,35.46 161.2,33.02 160.68,32.5 159.84,32.5 v2(159.71,32.36)
  L4 w0.127: v2(160.3,16.29) 159.66,16.93 159.66,17.63 162.19,20.15 162.19,30.19 160.01,32.36 v2(159.71,32.36) ; v2(175.52,67.4) 175.56,67.36 175.56,67.1 175.13,66.67 175.13,64.9 175.73,64.31 175.73,59.22 178.88,56.07 178.88,52.94 180.05,51.77 180.05,48.95 v2(179.82,48.73)
  BOTTOM w0.14: Q1801.1 155.57,70.36 v2(155.18,70.75) ; DM1.200 122.75,29.97 122.75,28.9 123.87,27.77 135.84,27.77 136.72,26.89 153.29,26.89 154.14,27.74 157.72,27.74 158.92,26.53 158.92,26.37 158.92,22.62 157.25,20.95 DM2.200 157.25,15.64 157.63,15.26 159.19,15.26 160.22,16.29 v2(160.3,16.29) ; v2(45.08,73.96) 45.31,74.2 47.2,74.2 48.56,75.56 v1(49.29,75.56) 54.37,75.56 59.54,70.39 64.37,70.39 79.74,55.02 122.22,55.02 144.78,32.46 159.61,32.46 v2(159.71,32.36) ; v2(175.52,67.4) 175.44,67.4 173.31,69.54 171.91,69.54 171.44,70.01 171.44,70.94 170.21,72.17 167.51,72.17 166.23,70.89 165.45,70.89 165.21,71.14 v2(165.12,71.14) 164.88,71.14 164.55,70.8 164.55,69.97 164.36,69.79 RN9601.1 164.13,70.12 163.94,70.32 161.61,70.32 161.45,70.16 RN1810.4
PCH_SPI_CLK: length 8.8
  BOTTOM w0.089: CPU1.AA3 136.14,83.08 138.05,83.08 138.69,83.72 139.27,83.72
  BOTTOM w0.14: 139.27,83.72 139.8,83.72 139.99,83.91 v1(141.03,83.91) 142.21,83.91 143.09,83.04 R1806.2
PCH_SPI_CS0#: length 18.5
  L3 w0.127: v2(133.36,84.46) 133.8,84.91 133.84,84.94 136.98,84.94 137.15,85.11 139.43,85.11 140.18,85.86 143.6,85.86 145.13,87.39 145.93,87.39 146.43,86.89 147.51,86.89 v2(147.71,87.09)
  BOTTOM w0.14: v2(133.36,84.46) 133.18,84.28 CPU1.Y7 ; v2(147.71,87.09) 147.81,86.99 v1(148.31,86.99) 148.81,87.49 R1807.2
PCH_SPI_DQ2: length 20.7
  TOP w0.14: v1(147.76,85.32) 148.56,86.12 v2(148.56,86.13)
  L3 w0.102: v2(134.01,84.46) 134.03,84.46 134.47,84.02 135.46,84.02 135.78,83.69
  L3 w0.127: 135.78,83.69 136.79,83.69 137.47,84.37 139.74,84.37 140.48,85.11 144.09,85.11 145.07,86.1 146.09,86.1 146.62,85.57 148,85.57 v2(148.56,86.13)
  BOTTOM w0.14: v2(134.01,84.46) 133.83,84.28 CPU1.Y6 ; R1811.2 149.95,86.72 R1815.1 148.56,86.57 v2(148.56,86.13)
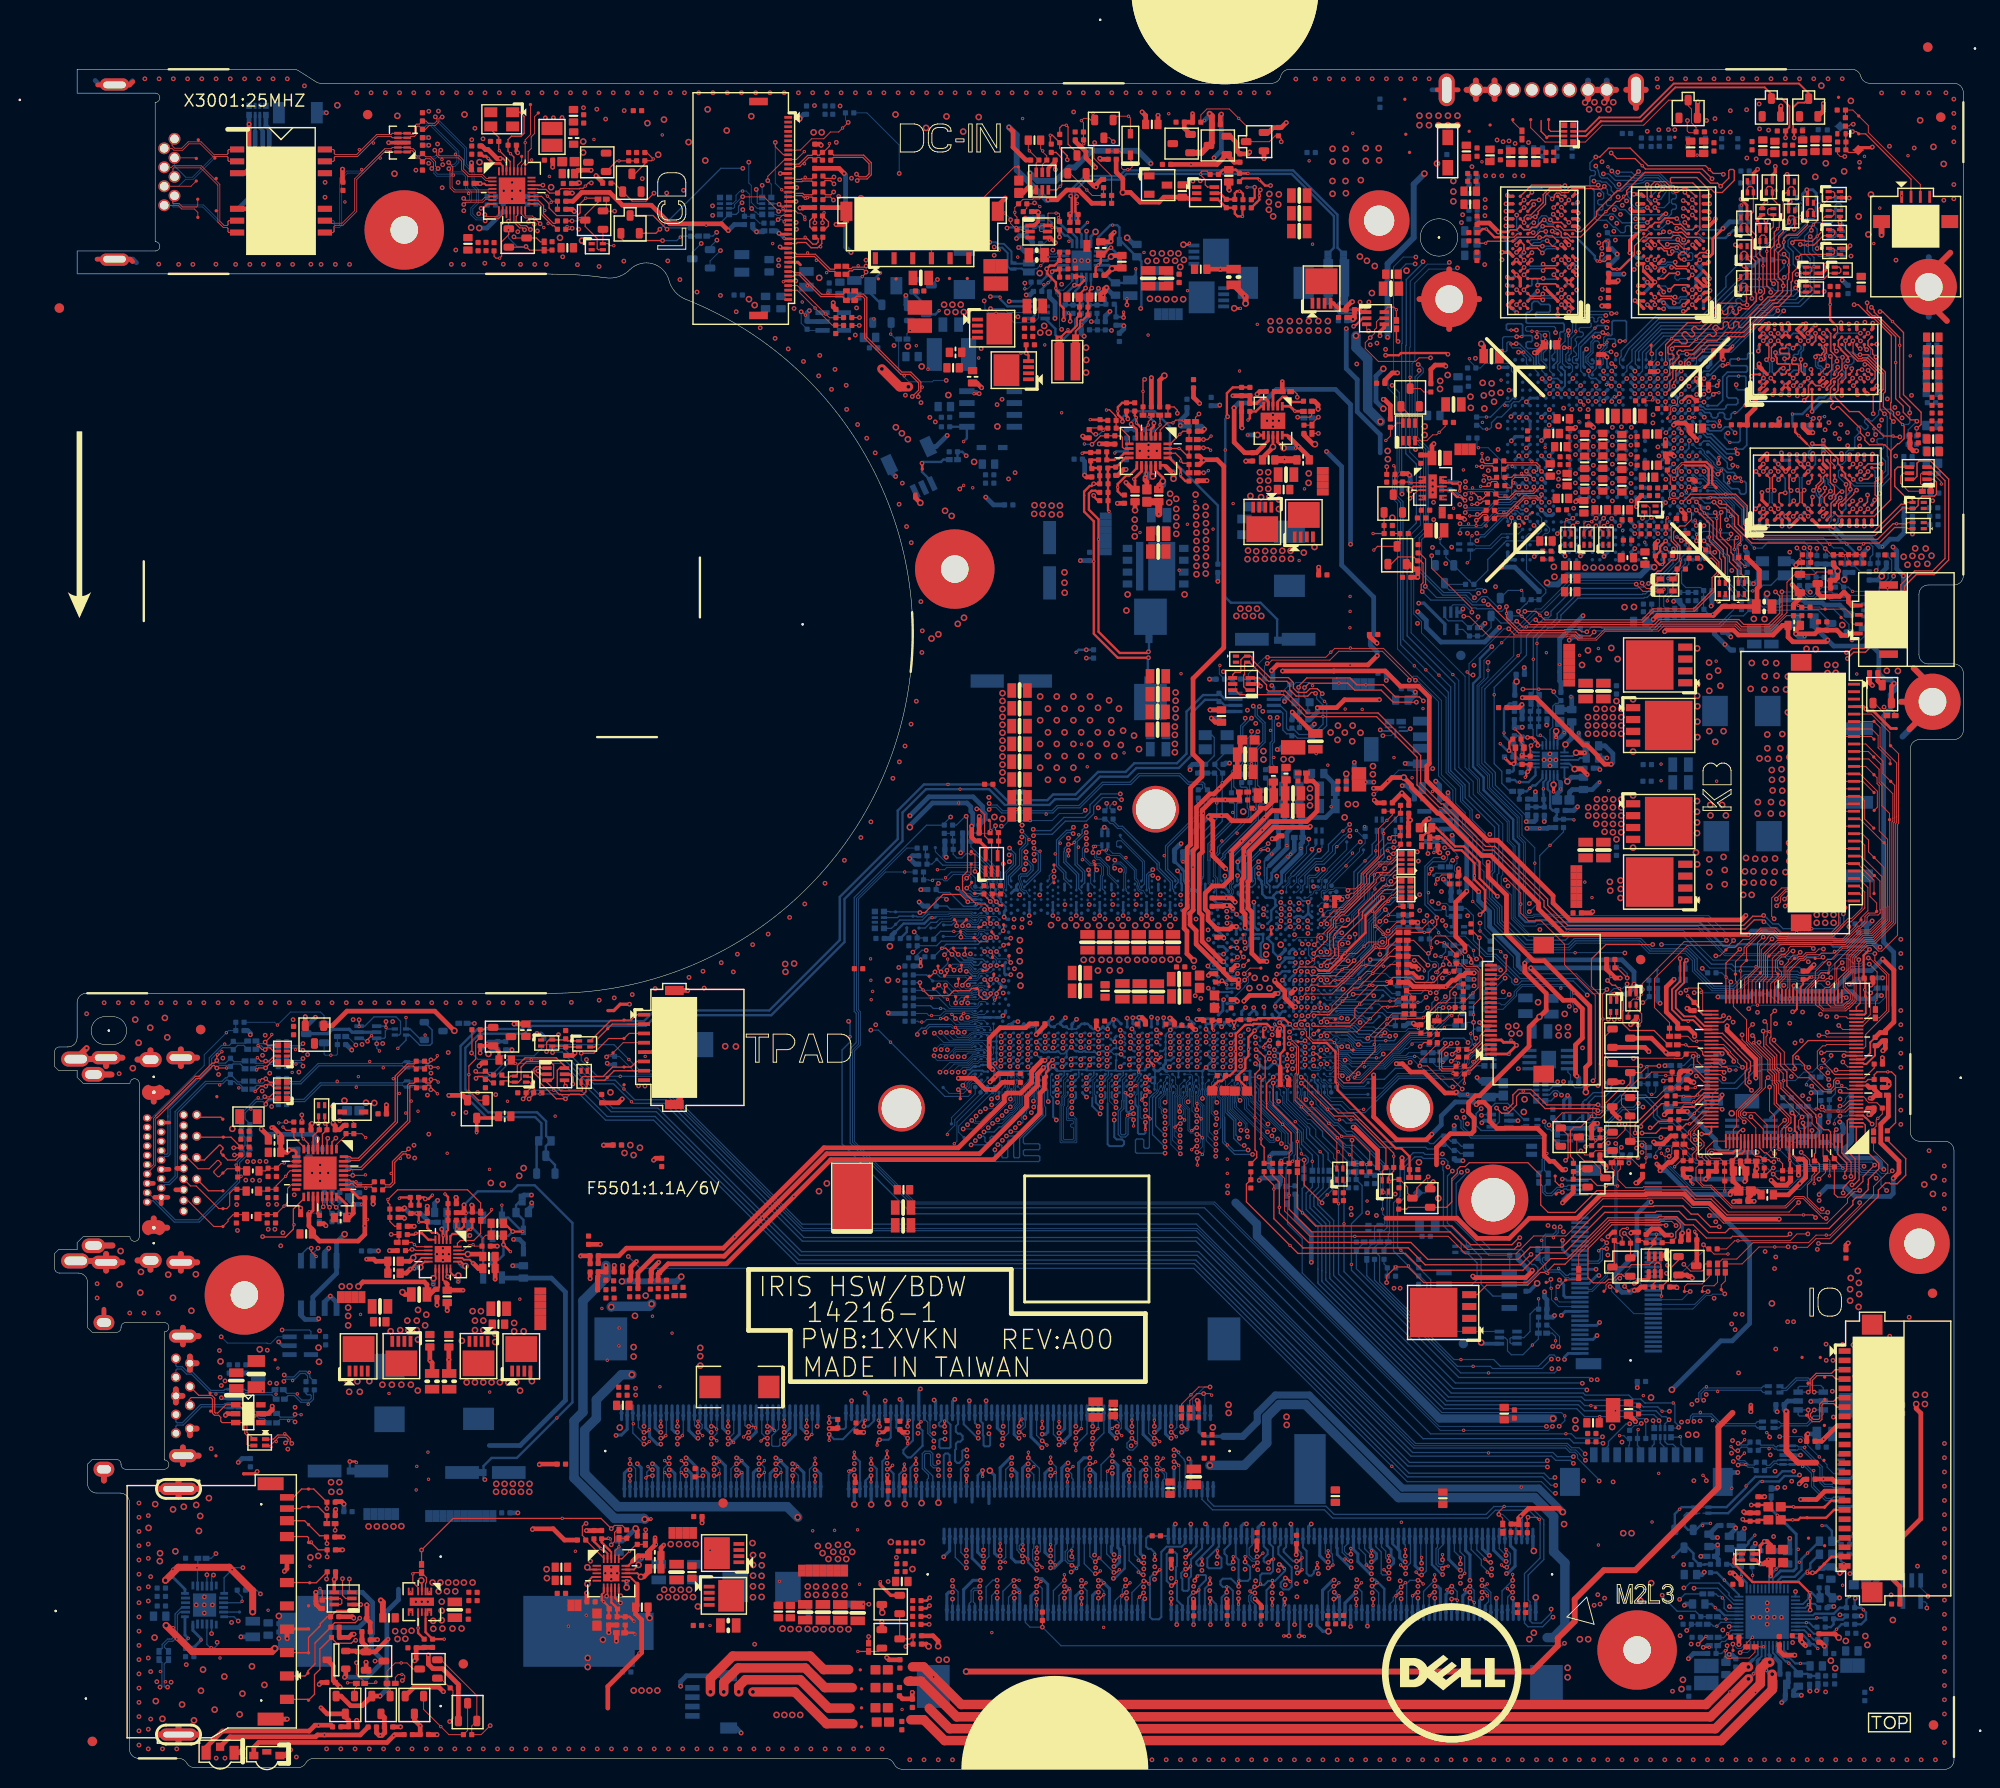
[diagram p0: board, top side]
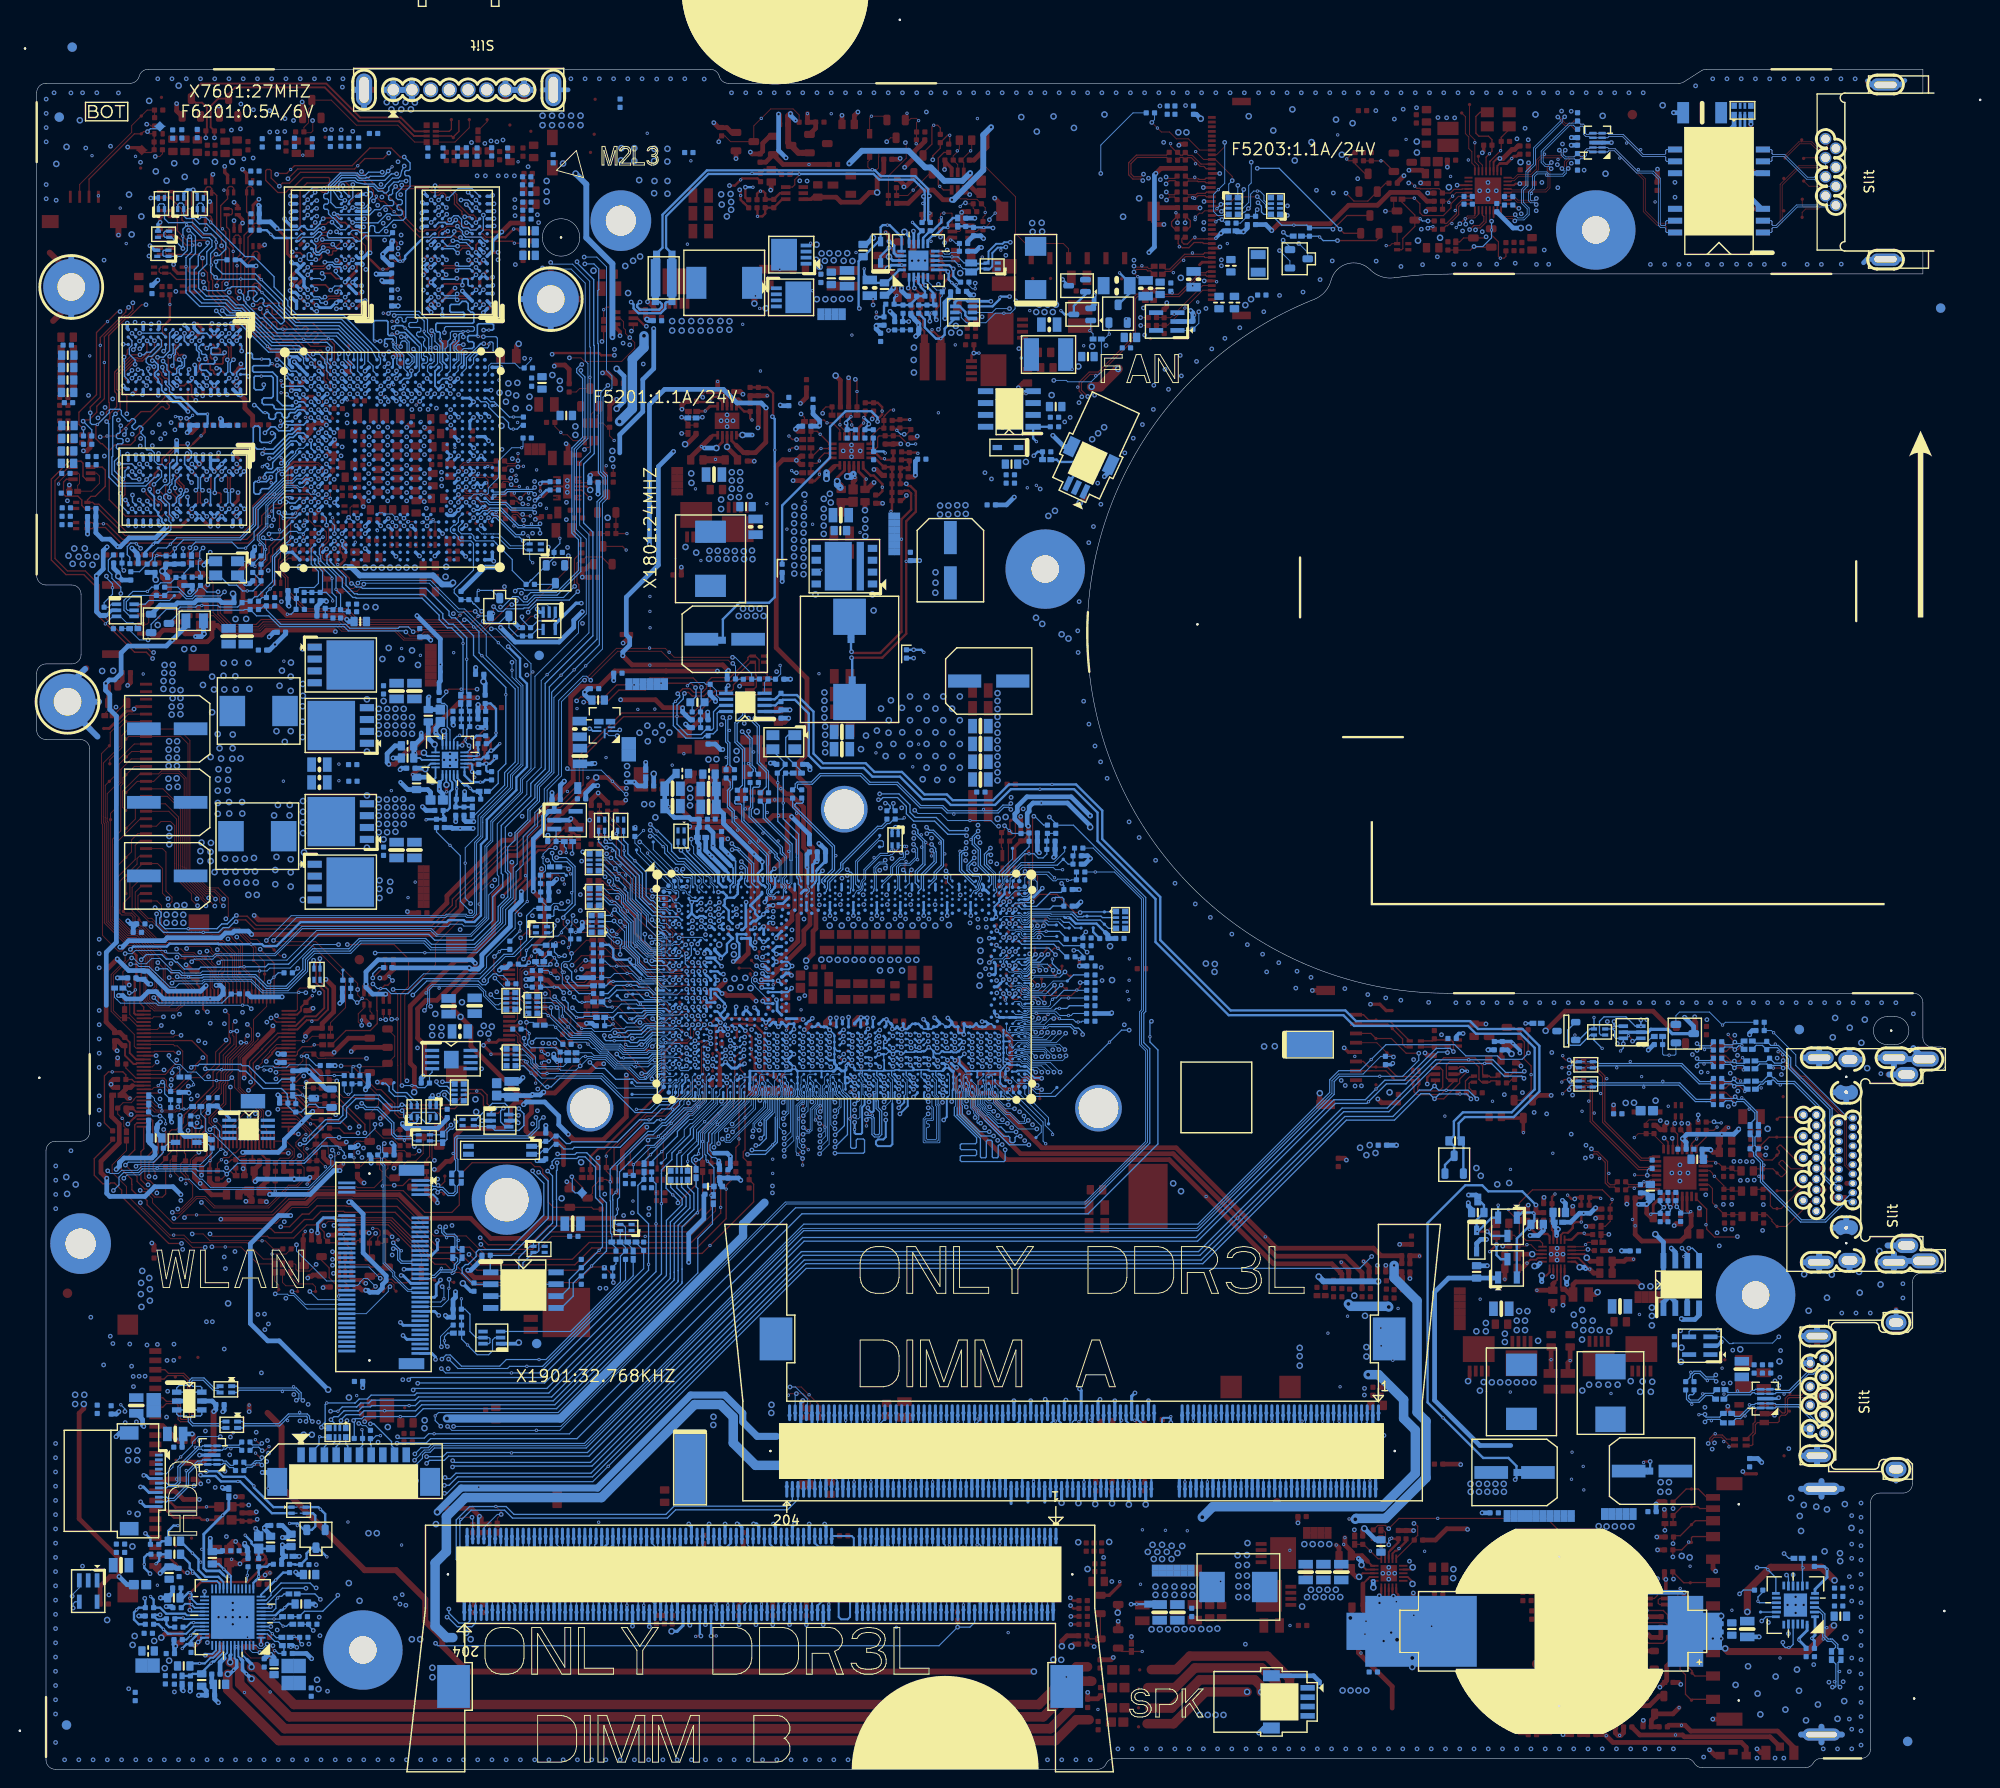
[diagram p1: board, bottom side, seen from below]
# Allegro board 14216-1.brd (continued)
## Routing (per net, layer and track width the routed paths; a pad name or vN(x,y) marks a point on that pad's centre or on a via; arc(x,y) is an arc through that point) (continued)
PCH_SPI_DQ3: length 8.5
  BOTTOM w0.14: v1(142.53,79.79) 142.6,79.79 142.8,79.59 R1814.1 R1812.2 142.53,80.48 142.03,80.99 139.46,80.99 139.25,81.2 137.2,81.2 CPU1.AF1
PCH_SPI_SI: length 7.9
  BOTTOM w0.089: 138.23,84.07 137.8,84.07 137.38,83.65 136.89,83.65 136.6,83.37 CPU1.AA2
  BOTTOM w0.14: 138.23,84.07 139.73,84.07 139.99,84.33 v1(142.53,84.33) 142.81,84.33 143.27,83.87 R1808.2
PCH_SPI_SO: length 10.8
  BOTTOM w0.089: CPU1.AA4 135.66,82.9 138.19,82.9
  BOTTOM w0.14: 138.19,82.9 138.69,83.41 142.13,83.41 142.99,82.55 143.33,82.55 R1809.2 143.16,81.59 v1(142.62,81.59)
PCH_THERMTRIP: length 10.5
  BOTTOM w0.089: 99.4,94.02 99,94.02 98.93,94.09 98.31,94.09 98.19,94.22
  BOTTOM w0.102: CPU1.D60 100.24,93.28 99.5,94.02 99.4,94.02 ; 98.19,94.22 98.03,94.38 98.03,95.51 97.74,95.79 96.15,95.79 95.46,95.1 95.16,95.1 94.98,95.28 94.04,95.28 v1(93.91,95.15) 93.56,95.15 93.5,95.21 R2018.2 92.95,95.22 R2027.1
PCH_VCCDSW_R: length 1.9
  TOP w0.254: v1(123.99,79.12) 123.82,79.29 C2114.1 R2110.2
PCH_WAKE#: length 21.1
  TOP w0.102: R1705.1 146.98,78.81 R1703.2 144.99,78.81 139.66,73.47 137.92,73.47 137.33,74.06 137.33,77.1 137.27,77.17 137.27,77.43 v1(136.91,77.78) 136.63,78.06 134.64,78.06 134.25,78.45 134.25,79.48 v2(134.03,79.69)
  BOTTOM w0.102: CPU1.AJ5 134.48,79.25 v2(134.03,79.69)
PCI_PLTRST#: length 64
  L3 w0.127: v2(133.45,80.67) 133.88,81.11 134.91,81.11 134.95,81.07 136.53,81.07 137.07,81.62 140,81.62 140.68,82.3 145.09,82.3 146.57,80.81 149.44,80.81 150.7,82.07 153.53,82.07 153.81,81.79 156.9,81.79 158.27,83.16 160.33,83.16 161.1,83.94 163.89,83.94 165.75,82.08 167.24,82.08 168.21,83.04 168.21,84.05 v2(168.23,84.07)
  BOTTOM w0.127: v2(133.45,80.67) 133.18,80.4 CPU1.AG7 ; R1713.2 151,92.16 151.78,91.38 151.78,88.74 153.28,87.24 154.2,87.24 156.8,84.64 162.87,84.64 164.48,83.03 166.28,83.03 166.82,83.57 v1(167.39,83.57) 167.75,83.57 168.23,84.06 168.23,84.07 v2(168.23,84.07)
PCI_PME#: length 1.2
  TOP w0.102: v2(135.46,81.49) 135.39,81.57 TP1501.1
  BOTTOM w0.102: v2(135.46,81.49) 135.16,81.79 CPU1.AD4
PCIE_CLK_XDP_N: length 6.7
  BOTTOM w0.102: CPU1.B35 116.58,94.75 116.58,97.2 114,99.78 TP9651.1
PCIE_CLK_XDP_P: length 6.7
  BOTTOM w0.102: CPU1.A35 116.38,95.2 116.38,97.12 114.1,99.39 113.74,99.39 113.62,99.27 113.62,98.82 113.71,98.74 TP9652.1
PCIE_PRX_LANTX_N4: length 127.7
  TOP w0.127: C3016.2 v2(55.35,165.73)
  L4 w0.114: v2(129.35,92.13) 129.22,92 129.11,92 128.97,92.14 128.97,93.1 128.84,93.23 128.84,93.23 127.01,95.06 125.03,95.06 124.41,95.67 124.41,96.22 122.42,98.22 112.46,98.22 111.93,97.68 107.95,97.68 107.22,98.41 107.22,100.28 102.23,105.27 102.23,116.38 103.43,117.58 103.43,130.47 99.12,134.78 99.12,138.29 82.01,155.41 78.49,155.41 72.49,161.4 70.22,161.4 66.1,165.52 55.56,165.52 v2(55.35,165.73)
  BOTTOM w0.127: v2(129.35,92.13) 129.35,92.03 129.48,91.89 129.49,91.89 129.57,91.82 CPU1.F13 ; v2(55.35,165.73) 55.95,165.73 v1(56.19,165.97)
PCIE_PRX_LANTX_P4: length 127.5
  TOP w0.127: v2(55.37,164.96) 55.26,164.84 C3014.2
  L4 w0.114: v2(129.32,91.48) 128.74,92.05 128.74,93 126.91,94.83 124.93,94.83 124.18,95.58 124.18,96.13 122.32,97.99 112.56,97.99 112.02,97.45 107.85,97.45 106.99,98.31 106.99,100.18 102,105.17 102,116.48 103.2,117.68 103.2,130.37 103.19,130.38 103.19,130.38 98.89,134.68 98.89,138.2 81.91,155.18 78.4,155.18 72.4,161.18 70.13,161.18 66.01,165.3 55.71,165.3 v2(55.37,164.96)
  BOTTOM w0.127: v1(54.82,165.13) 55.19,165.13 v2(55.37,164.96) ; v2(129.32,91.48) 129.44,91.48 CPU1.G13
PCIE_PRX_WLANTX_N3: length 60.6
  L4 w0.114: v2(160.43,58.07) 160.56,58.07 160.63,58.13 160.63,58.89 159.92,59.6 159.92,62.92 160.85,63.85 160.85,68 160.61,68.25 160.41,68.45 160.41,69.24 159.64,70.01 158.38,70.01 157.45,70.95 156.68,70.95 155.59,72.05 153.08,72.05 151.28,73.84 148.13,73.84 146.25,75.73 145.64,75.73 145.24,76.13 144.11,76.13 143.21,77.03 142.02,77.03 140.91,78.14 140.91,81.67 139.42,83.16 139.42,84.43 136.82,87.03 136.82,88.74 136.13,89.43 135.11,89.43 134.48,88.8 133.17,88.8 133,88.63 132.4,88.63 131.54,89.48 131.54,90.38 131.42,90.49 131.42,90.73 131.33,90.82 v2(131.2,90.82)
  BOTTOM w0.127: 159.22,56.62 159.22,56.02 159.21,56.01 159.21,55.71 159.08,55.58 158.76,55.58 R5808.2 ; 159.22,56.62 159.22,57 159.5,57.28 160.36,57.28 160.62,57.55 160.62,57.97 160.52,58.07 v2(160.43,58.07) ; 159.22,56.62 v1(159.07,56.62) ; CPU1.G11 130.76,91.22 130.88,91.22 131.2,90.9 v2(131.2,90.82)
PCIE_PRX_WLANTX_N3_R: length 5.9
  BOTTOM w0.127: WLAN1.43 162.07,52.52 161.96,52.63 161.57,52.63 160.99,53.22 159.73,53.22 ; R5808.1 158.92,54.53 158.92,54.28 159.28,53.92 159.28,53.54 159.6,53.22 159.73,53.22 ; 159.73,53.22 v1(159.73,53.08)
PCIE_PRX_WLANTX_P3: length 60.6
  L4 w0.114: v2(131.23,91.48) 131.65,91.06 131.65,90.59 131.77,90.47 131.77,89.58 132.49,88.86 132.9,88.86 133.08,89.03 134.39,89.03 135.02,89.66 136.22,89.66 137.05,88.83 137.05,87.12 139.64,84.53 139.64,83.25 141.14,81.76 141.14,78.23 142.12,77.26 143.31,77.26 144.21,76.36 145.34,76.36 145.74,75.96 146.34,75.96 148.23,74.07 151.38,74.07 153.18,72.27 155.68,72.27 156.78,71.18 157.54,71.18 158.48,70.24 159.73,70.24 160.63,69.34 160.63,68.55 160.71,68.47 161.08,68.1 161.08,63.76 160.15,62.83 160.15,59.7 160.86,58.99 160.86,58.28 v2(161.07,58.07)
  BOTTOM w0.127: 160.35,57.04 160.46,57.04 160.87,57.45 160.87,57.87 v2(161.07,58.07) ; 160.35,57.04 v1(160.35,56.91) ; 160.35,57.04 159.6,57.04 159.46,56.9 159.46,55.88 R5811.2 ; v2(131.23,91.48) 131.04,91.48 CPU1.F11
PCIE_PRX_WLANTX_P3_R: length 6
  BOTTOM w0.127: 160.9,53.46 161.09,53.46 161.67,52.87 161.91,52.87 162.06,53.02 WLAN1.41 ; 160.9,53.46 159.7,53.46 159.52,53.64 159.52,54.02 159.16,54.38 159.16,54.67 159.29,54.79 159.65,54.79 R5811.1 ; 160.9,53.46 v1(160.9,53.62)
PCIE_PTX_LANRX_N4: length 12
  BOTTOM w0.127: 122.79,102.44 119.08,98.73 119.08,96.35 120.2,95.24 120.2,94.94 119.89,94.63 CPU1.B29 ; 122.79,102.44 123.32,102.97 123.32,103.95 C1603.2 ; 122.79,102.44 v1(122.89,102.34)
PCIE_PTX_LANRX_N4_C: length 126
  TOP w0.127: v2(50.9,164.81) 50.86,164.81 50.45,165.23 49.85,165.23 49.37,165.71 49.37,166.2 49.53,166.36 LOM30.14
  L4 w0.114: v2(50.9,164.81) 50.88,164.79 50.88,164.5 52.29,163.09 66.08,163.09 69.37,159.8 70.79,159.8 74.5,156.09 75.71,156.09 77.88,153.92 81.39,153.92 88.11,147.2 97.63,137.68 97.63,134.16 101.73,130.06 101.73,118.05 98.71,115.03 98.71,104.07 99.57,103.2 99.8,103.2 v2(99.98,103.38)
  BOTTOM w0.127: 102.9,102.61 101.42,102.61 100.82,103.21 100.14,103.21 v2(99.98,103.38) ; 102.9,102.61 106.7,102.61 107.25,103.16 109.59,103.16 112.08,105.65 115.03,105.65 115.96,106.58 120.42,106.58 121.32,105.68 122.83,105.68 123.05,105.46 123.05,105.12 C1603.1 ; 102.9,102.61 v1(102.9,102.75)
PCIE_PTX_LANRX_P4: length 12
  BOTTOM w0.127: CPU1.A29 119.89,95.2 118.84,96.25 118.84,97.79 ; 118.84,97.79 118.84,98.83 123.08,103.07 123.08,103.26 122.92,103.41 122.32,103.41 122.19,103.54 122.19,103.83 122.32,103.96 C1604.2 ; 118.84,97.79 v1(118.7,97.79)
PCIE_PTX_LANRX_P4_C: length 125.9
  TOP w0.127: v2(50.26,164.78) 50.06,164.99 49.75,164.99 49.13,165.61 49.13,166.88
  L4 w0.114: v2(50.26,164.78) 50.27,164.78 52.2,162.86 65.99,162.86 69.28,159.57 70.69,159.57 74.4,155.86 75.62,155.86 77.78,153.69 81.3,153.69 97.4,137.58 97.4,134.06 101.41,130.05 101.5,129.96 101.5,118.15 98.48,115.13 98.48,103.97 99.48,102.98 99.75,102.98 v2(99.98,102.74)
  BOTTOM w0.127: v1(106.08,102.24) 106.08,102.37 ; 106.08,102.37 101.32,102.37 100.72,102.97 100.2,102.97 v2(99.98,102.74) ; 106.08,102.37 106.8,102.37 107.35,102.92 109.69,102.92 112.18,105.41 115.13,105.41 116.06,106.34 120.32,106.34 121.22,105.44 122.73,105.44 122.81,105.36 122.81,105.04 122.62,104.85 C1604.1
PCIE_PTX_WLANRX_N3: length 10.9
  BOTTOM w0.127: C1601.2 113.24,101.53 113.82,100.94 114.24,100.94 118.18,97.01 118.18,96.81 118.18,96.46 119.59,95.05 119.59,94.28 119.71,94.16 119.71,93.96 CPU1.C29
PCIE_PTX_WLANRX_N3_C: length 96.5
  TOP w0.127: v2(166.05,55.72) 165.4,55.72 v1(165.18,55.51)
  L4 w0.114: v2(113.4,103.41) 113.2,103.41 113.01,103.6 113.01,104.47 114.98,106.43 120.81,106.43 121.68,105.56 128.55,105.56 132.44,101.67 134.27,101.67 138.78,97.15 138.78,95.35 141.56,92.56 142.46,92.56 143.95,91.07 143.95,85.08 145.02,84 145.02,82.15 146.38,80.8 147.18,80.8 148.45,79.53 149.34,79.53 150.54,78.33 150.54,77.47 151.04,76.97 152.03,76.97 154.71,74.29 157.7,74.29 159.25,72.74 161.87,72.74 162.3,72.31 162.3,70.55 162.69,70.16 162.69,69.4 164.35,67.75 164.35,57.18 165.56,55.96 165.81,55.96 v2(166.05,55.72)
  BOTTOM w0.127: v2(113.4,103.41) 113.4,103.41 113.19,103.41 112.9,103.12 112.9,102.87 113.17,102.6 C1601.1 ; WLAN1.37 163.95,54.02 164.09,54.16 165.2,54.16 165.58,54.54 165.58,55.55 165.81,55.77 166,55.77 v2(166.05,55.72)
PCIE_PTX_WLANRX_P3: length 12
  BOTTOM w0.127: CPU1.B30 119.35,94.13 119.35,94.95 117.94,96.36 117.94,96.91 114.14,100.7 113.72,100.7 113.19,101.24 112.95,101.24 112.47,101.71 C1602.2 111.52,101.71 v1(111.38,101.85)
PCIE_PTX_WLANRX_P3_C: length 96.1
  TOP w0.127: v1(165.54,56.67) 165.74,56.67 v2(166.05,56.36)
  L4 w0.114: v2(166.05,56.36) 165.88,56.19 165.65,56.19 164.57,57.27 164.57,67.85 162.92,69.5 162.92,70.25 162.53,70.65 162.53,72.41 161.97,72.97 159.34,72.97 157.79,74.52 154.81,74.52 152.13,77.2 151.14,77.2 150.77,77.57 150.77,78.42 149.43,79.76 148.54,79.76 147.27,81.03 146.48,81.03 145.25,82.25 145.25,84.1 144.18,85.17 144.18,91.17 142.55,92.79 141.66,92.79 139.01,95.44 139.01,97.25 134.36,101.9 132.53,101.9 128.64,105.79 121.78,105.79 120.9,106.66 114.88,106.66 112.78,104.56 112.78,103.63 v2(112.55,103.4)
  BOTTOM w0.127: v2(166.05,56.36) 165.48,55.78 165.34,55.65 165.34,54.64 165.1,54.4 164.12,54.4 164,54.52 WLAN1.35 ; C1602.1 112.58,102.83 112.58,103.37 v2(112.55,103.4)
PCIE_RCOMP: length 3.5
  BOTTOM w0.305: CPU1.A27 121.19,95.17 121.19,96.8 120.83,97.16
  BOTTOM w0.508: v1(120.72,97.16) 120.83,97.16 120.83,97.2 120.68,97.35 120.68,98.18 R1601.2
PCIE_WAKE#: length 265.9
  TOP w0.127: LOM30.21 51.67,169.17 51.72,169.12 52.56,169.12 52.96,168.72 R3033.1 53.81,168.84 54.16,169.19 55.05,169.19 55.06,169.17 56.16,169.17 56.21,169.23 56.53,169.23 v1(56.77,169.47) 57.11,169.8 v2(57.41,169.8) ; v2(146.08,77.37) 146.5,77.79 R1705.2 ; KBC24.113 185.19,68.64 185.76,69.2 185.76,69.76 184.2,71.31 184.2,73.25 183.99,73.46 183.99,74.39 183.52,74.86 183.52,76 181.9,77.62 181.9,78.29 181.59,78.6 181.59,78.54 v2(181.64,78.54)
  L3 w0.127: v2(146.08,77.37) 146.88,77.37 149.25,75.01 150.83,75.01 151.07,75.25 154.55,75.25 154.87,75.57 161.6,75.57 162.81,76.78 163.65,76.78 165.67,78.8 169.68,78.8 170.8,78.8 172.21,80.2 174.1,80.2 175.36,80.2 176.27,81.12 179.07,81.12 180.73,79.46 180.73,79.33 181.52,78.54 v2(181.64,78.54)
  L4 w0.127: v2(57.41,169.8) 58.4,168.81 60.79,168.81 62.36,167.24 66.87,167.24 70.19,170.57 74.12,170.57 76.94,173.38 103.9,173.38 104.86,174.35 109.05,174.35 110.7,176 113.95,176 115.48,174.46 128.41,174.46 128.52,174.35 129.93,174.35 130.99,173.29 132.4,173.29 135.2,170.5 135.2,166.68 138.83,163.04 138.83,161.25 138.83,161.25 140.09,159.99 140.29,159.99 142.03,159.99 146.17,155.85 146.17,154.3 146.76,153.71 146.76,150.84 146.96,150.64 146.96,144.83 148.23,143.56 148.23,131.62 148.15,131.55 148.15,128.78 148.74,128.2 148.74,122.55 152.89,118.39 152.89,103.63 154.54,101.98 154.54,99.21 159.52,94.24 159.52,93.69 163.79,89.42 171.39,89.42 172.35,88.46 172.35,86.82 176.08,83.08 176.08,80.56 178.24,78.4 179.46,78.4 179.69,78.17 181.27,78.17 v2(181.64,78.54)
PD4403_A: length 3.8
  TOP w0.102: PD4404.A 115.08,176.75 v1(114.89,176.95) 113.64,176.95 PQ4409.B
PD4403_K: length 5.8
  TOP w0.102: PR4471.1 PR4468.2 113.93,173.23 114.1,173.05 114.1,172.6 114.13,172.57 114.13,171.42 114.31,171.23 v1(114.8,171.23) 115,171.23 115.28,171.51 115.28,172.07 115.08,172.26 PD4404.K
PECI: length 11.4
  TOP w0.14: R2429.1 196.08,68.34 196.95,69.21 196.95,74.22 196.52,74.65 v1(196.12,74.65) 194.97,74.65 194.66,74.34 C2422.1 194,73.84 193.75,73.59 KBC24.13
PEG_CLKREQ#: length 73.1
  TOP w0.127: RN2011.7 143.66,96.87 142.75,95.97 142.12,95.97 142.09,95.99 141.45,95.99 v1(141.18,95.72) 141.12,95.66 141.12,94.99 137.91,91.77 137.67,91.77 136.81,90.92 136.81,90.2 136.15,89.54 136.15,88.8 134.8,87.45 134.8,87.42 v2(134.69,87.31)
  L3 w0.127: v2(153.01,126.12) 152.79,126.33 152.15,126.33 150.21,124.39 150.21,111.35 149.58,110.72 149.58,106.49 148.55,105.47 148.55,102.39 143.59,97.44 143.59,97.41 143.03,96.85 142.48,96.85 142.46,96.87 142.01,96.87 139.33,94.19 139.33,93.1 138.69,92.46 138.51,92.46 137.01,90.96 137,90.96 136.97,90.93 136.77,90.93 135.31,90.93 135.04,90.65 135.04,90.29 135.92,89.4 135.92,88.59 134.69,87.37 v2(134.69,87.31)
  BOTTOM w0.127: R7305.1 148.83,126.84 Q7301.D 148.7,126.73 149.21,126.22 152,126.22 152.16,126.38 152.74,126.38 v2(153.01,126.12) ; v2(134.69,87.31) 134.81,87.19 134.81,86.22 CPU1.U5
PEX_TERMP: length 6.5
  BOTTOM w0.102: GPU1.AF25 155.84,149.68 155.84,149.9 155.84,149.91 155.84,150.23 155.57,150.5 153.04,150.5 152.53,150 R7301.1 152.04,150.09 151.36,150.78 v1(151.36,151)
PEXTSTCLK_OUT: length 5
  BOTTOM w0.14: GPU1.AF22 156.02,146.77 155.63,146.38 155.25,146.38 153.61,144.75 v1(153.18,144.75) R7307.1
PEXTSTCLK_OUT#: length 6.9
  BOTTOM w0.14: R7307.2 152.38,143.86 152.78,143.46 v1(153.21,143.46) 153.51,143.46 153.72,143.66 153.72,144.14 154.33,144.75 154.77,144.75 155.84,145.81 155.84,146.11 156.11,146.38 156.66,146.38 GPU1.AE22
PHASE1G: length 24.2
  TOP w0.254: v2(117.02,119.62) 116.89,119.49 113.94,119.49 111.68,121.76 v1(111.68,131.67) 111.68,133.8 110.65,134.83 110.65,136.56 110.94,136.86 111.36,136.86 111.54,136.68 PR4702.1
  BOTTOM w0.254: v2(117.02,119.62) 117.08,119.68 PG4701.1
PHASE_R_R: length 19.8
  TOP w0.254: v2(111.15,136.35) 111.15,136.26 111.62,135.79 PR4703.2
  L4 w0.254: v2(111.15,136.35) 110.9,136.1 110.9,120.36 v2(110.37,119.83)
  BOTTOM w0.254: v1(109.28,119.56) 109.55,119.83 v2(110.37,119.83) PR4704.1
PIRQA#: length 16.7
  TOP w0.102: v2(134.05,86.39) 134.38,86.39 v1(134.65,86.66) 135.05,87.06 136.29,87.06 136.55,87.31 136.55,87.67 136.41,87.81 136.41,89.45 137.07,90.11 137.07,90.83 137.76,91.52 137.99,91.52 141.38,94.91 141.38,95.21 141.89,95.71 142.94,95.71 143.45,96.22 RN2011.8
  BOTTOM w0.102: CPU1.U6 133.83,86.16 v2(134.05,86.39)
PIRQB#: length 13.3
  BOTTOM w0.102: RN1801.7 143.6,93.65 142.86,92.91 142.67,92.91 v1(142.67,92.91) 142.66,92.91 142.29,92.91 141.6,92.22 141.6,91.96 140.38,90.74 140.38,88.45 138.88,86.95 138.22,86.95 138.05,86.78 135.46,86.78 CPU1.P4
PIRQC#: length 14.9
  TOP w0.102: v2(134.77,88.26) 135.04,88.53 135.04,89.17 135.29,89.43 135.67,89.43 136.56,90.32 136.56,91 137.58,92.03 137.82,92.03 140.66,94.87 140.66,95.7 141.74,96.78 v1(141.79,96.78) 141.92,96.91 143.06,96.91 143.52,97.36 144.08,97.36 RN2011.6
  BOTTOM w0.102: v2(134.77,88.26) 134.8,88.26 135.16,87.9 CPU1.N4
PIRQD#: length 13.7
  BOTTOM w0.089: 138.71,87.65 138.59,87.52 137.39,87.52 137.33,87.58 136.75,87.58 CPU1.N2
  BOTTOM w0.102: 138.71,87.65 139.78,88.71 139.78,91.46 139.96,91.64 139.96,91.64 141.21,92.89 141.21,93.62 141.87,94.29 142.09,94.29 v1(142.46,94.65) 142.5,94.7 142.5,95.29 143.4,96.18 RN1505.5
PLT_RST#: length 333.3
  TOP w0.102: R3606.1 166.14,67.57 167.13,67.57 168,68.45 v2(168,69.04) ; R3016.1 59.01,167.17 Q3003.E 58.66,166.81 58.69,166.78 v2(59.9,166.78) ; v2(151.62,123.85) 151.62,124.27 147.32,128.57 v2(147.32,129.9) ; v2(174.3,54.05) 175.01,53.34 176.25,53.34 176.46,53.54 176.46,53.98 176.58,54.1 R5807.1 ; R5212.2 v2(86.08,154.55)
  L3 w0.102: v2(151.62,123.85) 151.62,120.05 152.92,118.75 152.92,112.25 151.01,110.34 151.01,102.74 148.64,100.37 148.64,98.69 v2(148.7,98.63) ; v2(169.74,37.02) 169.74,37.04 169.74,37.05 169.74,37.74 170.52,38.53 171.32,38.53 172.14,39.36 172.78,39.36 175.86,42.43 v2(180.15,42.43) ; v2(86.08,154.55) 84.39,156.24 84.39,156.32 84.36,156.32 84.36,158.86 78.24,164.98 78.24,168.82 76.69,170.37 76.55,170.52 65.5,170.52 64.64,169.65 62.77,169.65 v2(59.9,166.78)
  L4 w0.102: v2(59.9,166.78) 66.77,166.78 70.3,170.31 74.25,170.31 77.07,173.13 103.98,173.13 104.96,174.11 109.15,174.11 110.61,175.57 113.82,175.57 115.17,174.22 128.31,174.22 128.46,174.07 129.79,174.07 130.83,173.03 132.32,173.03 134.95,170.4 134.95,166.58 138.59,162.94 138.59,161.15 138.59,161.15 139.99,159.75 140.39,159.75 141.93,159.75 145.93,155.75 145.93,154.18 146.39,153.73 146.39,150.86 146.69,150.55 146.69,144.74 147.99,143.44 147.99,131.98 146.97,130.97 146.97,130.25 v2(147.32,129.9) ; v2(148.04,92.69) 148.04,92.18 149.5,90.73 149.5,90.04 151.95,87.59 152.43,87.59 153.56,86.45 153.56,85.26 154.77,84.06 155.33,84.06 158.05,81.33 159.18,81.33 159.87,80.64 159.87,78.55 160.6,77.82 162.32,77.82 162.78,78.29 164.04,78.29 168.91,73.42 169.3,73.42 171.72,70.99 171.72,69.92 172.01,69.63 172.01,67.81 v2(171.84,67.63) 171.84,66.76 171.74,66.65 171.74,65.25 172.83,64.16 172.83,57.97 172.3,57.43 172.3,56.27 174.3,54.27 v2(174.3,54.05) 174.16,53.91 174.16,52.28 174.43,52 174.43,50.46 179.91,44.98 179.91,42.67 v2(180.15,42.43)
  BOTTOM w0.102: v2(151.62,123.85) 151.62,123.86 150.83,124.65 149.6,124.65 149.37,124.42 U7301.2 ; v2(168,69.04) 168,68.59 168.96,67.63 v2(171.84,67.63) 173.13,67.63 175.6,65.16 182.46,65.16 185.35,68.05 185.84,68.05 186.11,68.32 186.11,69.63 186.63,70.15 R2416.2 ; R6502.1 168.49,36.29 168.99,36.79 169.36,36.79 169.52,36.94 169.66,36.94 v2(169.74,37.02) ; v2(148.04,92.69) 148.91,92.69 149.44,92.16 R1713.1 149.5,92.27 150.25,93.02 EC1703.1 R1715.1 150.3,93.93 C1701.1 R9602.2 150.24,95.71 149.76,96.19 149.76,96.71 150.03,96.97 v1(150.03,97.62) 150.03,97.96 149.43,98.56 148.78,98.56 v2(148.7,98.63)
PLT_RST#_DEBUG: length 3
  BOTTOM w0.127: v1(167.42,35.72) 167.88,35.72 168.2,35.4 R6502.2 168.49,34.75 168.41,34.68 DB1.7
PLT_RST#_EC: length 6.6
  TOP w0.102: v2(189.1,70.91) 189.44,70.56 191.43,70.56 192.06,71.19 KBC24.7
  BOTTOM w0.102: C2415.2 188.97,71.04 v2(189.1,70.91) 188.86,70.67 v1(188.45,70.67) 188.1,70.67 187.82,70.95 R2416.1
PLT_RST#_LAN: length 16.6
  TOP w0.127: RN3001.3 58.17,162.66 58.04,162.79 58.04,163.86 56.76,165.14 Q3003.C 56.76,166.37 58.13,167.74 R3016.2 58.02,168.17 v1(56.81,168.17) 56.22,167.58 56.22,166.61 55.92,166.31 53.71,166.31 52.89,167.13 52.89,167.57 52.09,168.37 LOM30.19
PLT_RST_NGFF#: length 9
  TOP w0.102: v2(174.98,51.15) AFTP5805.1 174.37,51.66 174.66,51.96 176.24,51.96 177.01,52.73 R5807.2
  BOTTOM w0.102: v2(174.98,51.15) 174.1,50.27 WLAN1.52
PM_CLKRUN#: length 74.5
  L3 w0.102: v2(134.66,85.41) 135.1,85.41 135.18,85.33 136.82,85.33 136.99,85.5 139.21,85.5 139.94,86.23 140.92,86.23 140.93,86.24 143.45,86.24 144.99,87.79 147.23,87.79 147.48,87.53 149.23,87.53 151.16,89.46 151.8,89.46 151.98,89.64 153.17,89.64 153.6,89.21 157.33,89.21 160.1,86.44 166.69,86.44 167.11,86.02 169.48,86.02 169.75,85.75 171.8,85.75 172.45,85.1 173.41,85.1 174.02,84.49 177.78,84.49 178.94,83.34 180.77,83.34 182.81,81.29 182.81,80.81 183.39,80.24 183.39,79.92 184.38,78.94 187.43,78.94 189.57,76.8 189.57,76.2 189.64,76.13 189.64,75.67 189.27,75.3 189.27,72.39 189.84,71.82 189.84,71.09 v2(191.01,69.93)
  BOTTOM w0.102: CPU1.V5 134.66,85.12 v2(134.66,85.41) ; R1709.1 192.21,70.39 R1714.1 191.78,69.93 v2(191.01,69.93) 190.83,69.93 190.41,69.5 v1(190.41,69.09)
PM_CLKRUN#_EC: length 4.4
  TOP w0.102: KBC24.8 192.01,71.59 191.42,70.99 v2(191,70.99)
  BOTTOM w0.102: v1(190.8,70.47) 190.8,70.79 v2(191,70.99) 191.6,71.59 191.6,71.81 191.89,72.1 R1709.2
PM_LAN_ENABLE: length 223.2
  TOP w0.127: KBC24.119 187.6,67.9 187.58,67.92 187.58,69.98 184.68,72.88 184.68,73.45 184.47,73.66 184.47,74.59 184,75.06 184,76.23 182.85,77.39 182.85,78.96 v2(182.78,79.02) ; v2(64.12,168.71) 63.27,167.86 61.79,167.86 Q3001.G 59.87,169.78 R3023.1
  L4 w0.127: v2(182.78,79.02) 182.69,79.02 182.63,79.08 180.38,79.08 180.33,79.04 179.71,79.04 179.56,78.88 178.44,78.88 176.56,80.76 176.56,83.48 173.31,86.74 173.31,88.19 171.59,89.9 164,89.9 160.21,93.69 160.21,94.52 155.23,99.5 155.23,102.26 153.69,103.8 153.69,116.91 154.02,117.24 154.02,118.81 149.7,123.13 149.7,129.84 149.01,130.53 149.01,143.92 147.67,145.26 147.67,148.88 147.87,149.09 147.87,153.88 146.79,154.96 146.79,155.91 145.17,157.53 145.17,160.64 144.76,161.05 144.76,172.01 142.12,174.66 128.58,174.66 128.43,174.81 115.5,174.81 114.05,176.26 110.6,176.26 108.95,174.6 104.75,174.6 103.85,173.7 83.43,173.7 82.85,174.29 81.7,174.29 81.05,173.64 76.79,173.64 73.97,170.82 70.05,170.82 67.29,168.06 64.77,168.06 v2(64.12,168.71)
  BOTTOM w0.127: v1(183.45,78.96) 183.28,78.96 183.24,79 182.9,79 182.89,79.02 v2(182.78,79.02)
PM_LAN_ENABLE_R: length 3.7
  TOP w0.127: R3022.2 62.24,172.17 C3015.2 61.41,172.17 v1(60.38,172.17) 60.14,172.17 Q3004.G
PM_PCH_PWROK: length 22.9
  BOTTOM w0.089: CPU1.AY7 132.9,72.37 132.9,71.58 133.56,70.93 133.58,70.93 134.11,70.4 134.55,70.4 134.59,70.36
  BOTTOM w0.127: 134.59,70.36 136.75,68.2 136.75,68.16 136.95,67.96 136.99,67.96 138.17,66.79 138.99,66.79 141.84,63.94 141.84,61.24 142.06,61.02 v1(142.06,59.97) 142.06,59.45 142.3,59.21 142.3,58.42 142.19,58.32 RN1703.3 141.51,58.32 141.21,58.01 141.21,56.67 R1706.2 140.97,56.26 140.38,55.67 R1707.1
PM_PWRBTN#: length 72.8
  TOP w0.102: KBC24.117 186.8,67.97 186.8,67.97 186.8,68.31 186.58,68.53 186.58,69.46 v2(186.95,69.83) 184.44,72.34 184.44,73.35 184.23,73.56 184.23,74.49 183.76,74.96 183.76,76.13 182.34,77.55 v2(182.34,77.81)
  L3 w0.102: v2(182.34,77.81) 182.37,77.84 182.37,78.82 181.88,79.31 181.48,79.31 181.23,79.56 181.23,79.66 179.28,81.61 176.06,81.61 175.15,80.7 173.1,80.7 172.85,80.94 164.48,80.94 162.72,82.7 161.61,82.7 159.56,80.65 159.56,78.64 158.84,77.93 155.03,77.93 153.45,79.51 150.78,79.51 150.22,78.95 145.65,78.95 144.3,80.29 141.34,80.29 140.56,79.51 137.72,79.51 136.3,78.09 134.5,78.09 133.79,78.8 v2(133.49,78.8)
  BOTTOM w0.102: R9603.1 187.07,69.94 v2(186.95,69.83) ; CPU1.AL7 133.37,78.49 133.49,78.6 v2(133.49,78.8) ; v2(182.34,77.81) 182.34,77.8 181.85,77.8 181.82,77.78 v1(181.77,77.78)
PM_RSMRST#: length 42
  BOTTOM w0.089: CPU1.AW6 133.45,72.82 133.45,72.16 133.39,72.09 133.39,71.6 133.71,71.28 133.73,71.28 134.21,70.8 134.27,70.8
  BOTTOM w0.127: Q1701.3 154.56,46.87 147.06,46.87 141.75,52.19 141.75,54.93 R1702.1 141.2,55.86 R1704.2 141.78,57.04 141.75,57.07 RN1703.4 142.23,57.67 142.55,57.99 142.55,60.94 142.58,60.96 142.58,61.41 v1(142.21,61.78) 142.09,61.89 142.09,64.63 138.81,67.92 138.25,67.92 137.25,68.92 136.84,68.92 134.96,70.8 134.27,70.8
PM_SLP_A#: length 1.3
  TOP w0.102: v2(134.7,78.7) 135.1,79.1 TP1704.1
  BOTTOM w0.102: CPU1.AL5 134.31,78.31 v2(134.7,78.7)
PM_SLP_LAN#: length 1.8
  TOP w0.127: TP1707.1 133.23,80.17 132.95,79.89 132.95,79.88 v2(132.76,79.69)
  BOTTOM w0.127: v2(132.76,79.69) 133.18,79.27 CPU1.AJ7
PM_SLP_S3#: length 460.1
  TOP w0.127: R3609.1 v2(39.25,23.47) 42.64,26.86 v1(54.3,26.86) 58.45,26.86 v2(59.55,25.76) 59.9,26.1 60.72,26.1 PR4910.2 ; v2(30.79,20.4) 30.79,18.62 31.13,18.29 Q3601.2 ; v2(180.29,87.78) 178.8,86.29 KBC24.64 ; PR4819.1 132.66,147.47 132.94,147.19 v2(132.94,146.86)
  L3 w0.127: v2(59.55,25.76) 60.23,25.08 60.23,23.7 57.98,21.45 57.98,18.06 62.8,13.24 73.61,13.24 74.48,14.1 76.92,14.1 77.32,13.71 86.6,13.71 86.79,13.51 87.46,13.51 87.9,13.95 91.53,13.95 93.13,12.36 97.18,12.36 97.46,12.08 99.43,12.08 101.09,10.42 151.64,10.42 161.22,20 164.56,20 175.37,30.81 v2(175.37,30.89) 175.37,31.56 176.86,33.05 176.86,36.42 179.18,38.73 181.79,38.73 183.26,37.26 192.34,37.26 192.46,37.38 193.35,37.38 193.53,37.2 v2(193.53,37.19) ; v2(151.9,125.4) 151.18,124.68 151.18,123.64 151.24,123.58 151.24,120.04 152.67,118.61 152.67,112.39 150.77,110.48 150.77,102.99 147.54,99.76 147.54,98.64 v2(146.92,98.02) 147.8,97.15 148.69,97.15 149.92,95.91 153.49,95.91 155.32,94.09 155.91,94.09 156.65,94.83 159.05,94.83 164.14,89.73 175.93,89.73 177.48,88.18 179.89,88.18 v2(180.29,87.78) 182.05,86.02 182.64,86.02 183.97,84.69 185.34,84.69 185.64,84.4 185.64,83.02 186.99,81.67 186.99,81.07 v2(187,81.06) ; v2(39.25,23.47) 39.25,22.94 39,22.69 33.08,22.69 v2(30.79,20.4) ; v2(145.88,150.37) 144.09,148.58 142.68,148.58 141.04,146.94 133.02,146.94 v2(132.94,146.86) ; v2(134.7,75.29) 136.53,73.46 138.67,73.46 138.69,73.48 146.29,73.48 149.03,70.74 150.38,70.74 150.42,70.7 150.43,70.7 150.63,70.49 v2(150.63,70.49)
  L4 w0.127: v2(175.37,30.89) 177.14,32.66 177.14,40.3 176.81,40.63 176.36,40.63 159.09,57.9 159.09,63.28 160.1,64.28 160.1,67.67 159.43,68.33 152.33,68.33 151.65,69.02 151.65,70.03 151.21,70.46 150.66,70.46 v2(150.63,70.49) ; v2(187,81.06) 186.32,80.37 186.32,79.74 185.74,79.16 185.74,76.07 187.92,73.89 188.15,73.89 189.77,72.27 189.77,69.93 189.24,69.4 189.24,68.22 189.51,67.95 189.51,64.8 190.19,64.12 190.19,62.47 189.96,62.24 189.96,61.04 190.24,60.76 190.24,59.43 190.54,59.13 190.54,55.8 188.46,53.72 188.46,48.38 190.56,46.29 190.56,45.17 191.24,44.48 191.24,42.39 192.51,41.12 192.51,38.54 193.53,37.52 v2(193.53,37.19)
  BOTTOM w0.127: CPU1.AT4 134.9,75.09 v2(134.7,75.29) ; v2(146.92,98.02) 146.85,98.09 PR5110.1 ; v2(151.9,125.4) 151.34,125.96 148.6,125.96 146.24,128.32 146.24,131.62 146.95,132.33 146.95,141.43 145.8,142.58 145.8,148.89 146.43,149.52 146.43,149.92 146.04,150.31 145.94,150.31 v2(145.88,150.37)
PM_SLP_S4#: length 277
  TOP w0.127: v2(189.01,76.69) 189.39,76.69 189.55,76.85 191.59,76.85 191.65,76.78 KBC24.21 ; v2(63.22,25.64) 63.22,25.35 63.19,25.32 PR4907.1
  L3 w0.127: v2(194.76,38.31) 192.08,40.99 184.5,40.99 182.5,38.98 179.07,38.98 176.61,36.52 176.61,33.25 174.8,31.44 174.8,30.6 164.45,20.26 161.11,20.26 152.05,11.2 100.67,11.2 99.25,12.61 93.23,12.61 91.63,14.21 87.79,14.21 87.35,13.77 86.9,13.77 86.7,13.96 77.42,13.96 77.03,14.36 74.37,14.36 73.51,13.49 62.92,13.49 58.47,17.95 58.47,21.17 62.28,24.98 62.56,24.98 v2(63.22,25.64) ; v2(133.4,79.71) 133.87,80.18 134.92,80.18 135.47,80.73 136.55,80.73 137.16,81.35 140.09,81.35 140.79,82.05 144.98,82.05 146.47,80.56 149.55,80.56 150.81,81.82 153.42,81.82 153.7,81.54 157,81.54 158.37,82.91 160.43,82.91 161.21,83.68 163.79,83.68 165.65,81.82 167.55,81.82 169.7,83.98 171,83.98 172.97,82.01 175.84,82.01 175.88,82.05 179.75,82.05 180.93,80.87 181.51,80.87 182.77,79.62 183.34,79.62 184.26,78.69 187.33,78.69 189.01,77.02 v2(189.01,76.69)
  L4 w0.127: v2(189.01,76.69) 189.06,76.69 189.38,76.37 189.4,76.37 189.66,76.11 189.66,75.62 189.97,75.31 190.76,75.31 191.02,75.05 191.02,75.04 192.18,73.88 192.18,64.99 193.55,63.62 193.55,62.83 194.41,61.96 194.41,54.09 194.59,53.91 194.91,53.59 194.91,38.46 v2(194.76,38.31)
  BOTTOM w0.127: v1(195.2,39.02) 194.76,38.59 v2(194.76,38.31) ; v2(133.4,79.71) 133.83,79.28 CPU1.AJ6
PM_SLP_S5#: length 1.4
  TOP w0.127: v2(134.65,76.61) 134.99,76.61 TP1703.1
  BOTTOM w0.127: v2(134.65,76.61) 134.4,76.36 CPU1.AP5
PM_SLP_SUS#: length 115.7
  TOP w0.102: KBC24.108 183.2,69 181.91,70.29 180.92,70.29 v2(180.8,70.17)
  L3 w0.102: v2(184.13,54.84) 183.83,54.54 175.8,54.54 175.39,54.54 173.99,53.14 173.99,51.38 173.24,50.63 171.58,50.63 170.13,49.17 164.85,49.17 v2(160.9,45.23) ; v2(138.05,75.91) 138.05,74.93 139.19,73.79 146.33,73.79 149.13,70.98 150.75,70.98 151.47,70.26 151.47,69.39 152.38,68.48 156.6,68.48 156.65,68.53 161.65,68.53 163.11,69.99 166.92,69.99 167.03,70.11 167.62,70.11 168.42,69.31 169.58,69.31 169.63,69.27 170.7,69.27 171.57,68.39 172.05,68.39 172.61,67.83 175.75,67.83 176.02,67.57 178.2,67.57 v2(180.8,70.17)
  L4 w0.102: v2(180.8,70.17) 180.8,69.91 181.32,69.39 181.32,63.88 182.73,62.46 182.73,59.61 184,58.34 184,54.97 v2(184.13,54.84)
  BOTTOM w0.089: CPU1.AP4 135.45,76.2 135.95,76.2 135.99,76.16 137.34,76.16 137.4,76.1 137.72,76.1
  BOTTOM w0.102: 137.72,76.1 137.87,76.1 v2(138.05,75.91) 138.36,75.91 138.7,75.58 142.1,75.58 143.11,76.59 143.92,76.59 144.48,77.14 144.74,77.14 v1(145.22,77.63) 145.42,77.83 146.79,77.83 R3802.1 ; v2(160.9,45.23) 161,45.33 161,46.31 159.76,47.55 R1729.2
PM_SUS_STAT#: length 46.3
  TOP w0.127: v2(135.48,79.98) 135.48,80.08 135.84,80.44 136.87,80.44 TP1702.1
  L3 w0.127: v2(135.48,79.98) 135.48,79.99 135.95,80.46 136.63,80.46 137.27,81.1 140.2,81.1 140.89,81.79 144.88,81.79 146.36,80.31 149.66,80.31 150.9,81.55 153.33,81.55 153.61,81.27 157.1,81.27 158.48,82.65 160.54,82.65 161.31,83.43 163.41,83.43 163.7,83.14 163.84,83 v2(163.96,82.88)
  BOTTOM w0.127: CPU1.AG4 135.16,80.3 v2(135.48,79.98) ; R1724.2 153.81,84.47 154.32,84.97 154.82,84.97 155,85.15 155.35,85.15 155.89,84.61 155.89,84.26 156.17,83.98 156.55,83.98 156.95,84.38 162.46,84.38 v2(163.96,82.88)
PM_SUSACK#: length 19.6
  TOP w0.127: v2(178.4,70.65) 178.39,70.66 178.38,70.66 178.25,70.79 KBC24.91
  L3 w0.127: v2(178.4,70.65) 178.4,70.42 177.69,69.71 174.38,69.71 173.21,70.89 170.25,70.89 170.25,70.89 v2(169.92,70.89)
  BOTTOM w0.127: v2(169.92,70.89) 169.92,70.89 169.88,70.84 169.27,70.84 169.04,70.61 167.75,70.61 166.23,69.09 166.23,67.96 165.78,67.5 164.85,67.5 ; v1(164.85,67.34) 164.85,67.5 ; 164.85,67.5 164.06,67.5 163.83,67.27 RN1702.2
PM_SUSACK#_R: length 37.4
  L3 w0.127: v2(159.35,69.32) 158.82,68.79 156.55,68.79 156.5,68.74 152.48,68.74 152.23,68.99 152.23,69.04 151.71,69.56 151.71,70.36 150.85,71.22 149.26,71.22 146.4,74.08 142.06,74.08 141.38,74.76 140.39,74.76 139.66,74.03 139.29,74.03 139.03,74.29 139.03,76.29 139.48,76.74 v2(139.48,77.58)
  BOTTOM w0.089: 137.68,78.59 136.72,78.59 136.46,78.84 CPU1.AK2
  BOTTOM w0.127: v2(159.35,69.32) 159.43,69.24 159.43,68.78 159.69,68.52 159.96,68.52 160.3,68.19 160.3,67.43 160.63,67.09 R1708.2 160.95,67.27 RN1702.3 ; v1(141.18,77.59) 140.97,77.38 139.92,77.38 139.73,77.58 v2(139.48,77.58) 139.45,77.6 139.28,77.6 138.29,78.59 137.68,78.59
PM_SUSWARN#: length 25.1
  TOP w0.127: v2(179.19,74.84) 178.83,75.21 178.38,75.21 178,75.58 KBC24.79
  L3 w0.127: v2(179.19,74.84) 179.19,72.33 176.83,69.97 174.49,69.97 173.13,71.33 169.74,71.33 169.7,71.29 v2(169.43,71.29)
  BOTTOM w0.127: v2(179.19,74.84) 179.7,74.84 179.7,74.85 v1(179.87,74.85) ; RN1702.1 163.93,67.92 164.09,67.76 165.67,67.76 165.98,68.07 165.98,69.2 167.65,70.86 168.91,70.86 169.34,71.29 v2(169.43,71.29)
PM_SUSWARN#_R: length 38.9
  L4 w0.127: v2(159.88,68.97) 159.73,68.82 156.49,68.82 156.03,69.28 156.03,70.86 155.37,71.52 152.86,71.52 151.07,73.31 149.84,73.31 v2(149.57,73.04)
  BOTTOM w0.089: CPU1.AV4 135.14,73.65 135.47,73.32 135.47,72.85 135.52,72.8 135.52,72.11 135.76,71.87
  BOTTOM w0.127: RN1702.4 160.82,67.92 R1708.1 160.77,68.08 v2(159.88,68.97) ; 135.76,71.87 136.51,71.12 137.54,71.12 138.37,70.3 140.18,70.3 143.85,73.97 148.23,73.97 149.16,73.04 v2(149.57,73.04) 149.83,73.04 v1(151.32,74.53) 152.09,75.3 RN1601.5
POL1_SDA: length 11.3
  TOP w0.14: v1(27.98,54.9) 27.45,55.43 v2(27.45,55.78) ; v2(29.41,60.16) 29.14,60.43 U5502.22
  L3 w0.127: v2(27.45,55.78) 27.79,56.12 27.79,56.18 29.55,57.94 29.55,60.02 v2(29.41,60.16)
  BOTTOM w0.14: R5508.2 29.67,60.42 v2(29.41,60.16) 29.41,59.77 R5509.1 ; v2(27.45,55.78) 27.05,55.78 26.35,55.07 U5504.5
POL2_SCL: length 10.8
  TOP w0.14: U5502.23 29.64,60.63 v2(30.12,60.15)
  L3 w0.127: v2(30.12,60.15) 29.94,59.97 29.94,57.78 28.18,56.02 v2(28.18,55.78)
  BOTTOM w0.14: v1(31.51,59.41) 31.41,59.51 R5515.1 30.5,59.77 v2(30.12,60.15) 30.51,60.55 R5516.2 ; v2(28.18,55.78) 28.18,55.77 27.62,55.21 U5504.6
PQ3802_1: length 8.2
  TOP w0.508: PR4202.1 126.2,172.03 PQ4202.B 124.35,171.78 v1(121.57,171.78) PR4209.2
PQ3809_D: length 4.4
  BOTTOM w0.254: v1(88.35,160.18) 87.26,159.08 PR4214.2 87.26,158.01 PQ4206.D
PQ4008_2: length 32.2
  TOP w0.254: v1(114.36,155.98) 114.36,155.92 114.36,155.92 v2(114.36,155.4) ; v2(138.97,154.46) 139.1,154.59 139.21,154.59 139.95,155.33 PQ4408.2
  L3 w0.254: v2(114.36,155.4) 113.88,154.92 113.88,154.3 115.06,153.12 137.81,153.12 138.97,154.28 v2(138.97,154.46)
  BOTTOM w0.254: v2(114.36,155.4) 114.29,155.47 PC4425.1 113.55,156.63 PR4437.2
PQ4008_6: length 2.9
  TOP w0.127: PQ4408.6 142.25,156.11 142.64,156.51 143.27,156.51 v1(143.54,156.24) PR4426.1
PQ4405_2: length 5.7
  TOP w0.102: PR4476.2 102.95,166.14 102.72,166.38 102.72,166.64 v1(102.72,166.65) 102.72,166.65 102.72,167.17 PR4475.2 103.6,168.05 104.63,168.05 104.68,168.1 105.36,168.1 105.66,168.4 PQ4410.2
PQ4405_3: length 5.9
  TOP w0.14: PR4466.1 107.14,173.07 107.74,172.47 107.74,169.6 v1(107.58,169.44) 107.2,169.06 PQ4410.3
PQ4405_5: length 3.9
  TOP w0.102: PC4434.1 105.49,173.46 v1(105.7,173.24) 105.7,173.13 106.14,172.69 PR4470.2 105.66,171.77 PQ4410.5
PQ4405_6: length 4.1
  TOP w0.102: PC4434.2 104.16,173.36 v1(104.28,173.24) 105.27,172.25 PR4473.1 105.01,171.95 PQ4410.6
PQ4406_D: length 5.2
  TOP w0.127: PR4465.2 107.53,175.7 107.8,175.98 v1(108.23,175.98) 108.42,175.79 108.42,173.96 109.37,173.01 PQ4414.D
PQ4406_G: length 5.6
  TOP w0.102: PQ4414.G 108.63,170.83 v1(110.43,169.04) 111.01,168.46 PC4433.2 112.21,168.48 PR4474.1
PQ4408_C: length 15.1
  TOP w0.102: PR4464.1 104.01,167.11 PR4475.1 104.73,167.57 v2(104.83,167.67) ; v2(113.26,174.22) 112.84,174.64 PQ4409.C
  L3 w0.102: v2(113.26,174.22) 112.27,174.22 110.01,171.96 108.8,171.96 104.83,168 v2(104.83,167.67)
  BOTTOM w0.102: v1(105.4,167.28) 105.01,167.67 v2(104.83,167.67)
PQ4408_E: length 3.8
  TOP w0.102: PQ4409.E 110.83,176.54 110.66,176.71 110.08,176.71 109.85,176.48 v1(109.85,176.48) 110.06,176.26 PR4467.1 110.06,174.42 PR4469.2
PR4601_1: length 2
  TOP w0.254: v1(62.09,14.47) 61.94,14.62 PR4906.1 61.05,14.69 PR4901.2
PR4605_2: length 2.7
  TOP w0.508: PC4919.1 PR4905.2 64.87,23.71 v1(65.17,24.01)
PROC_OPI_COMP: length 11.7
  BOTTOM w0.127: CPU1.AY15 128.49,71.48 131.95,68.02 131.95,67.04 132.16,66.83 132.16,66.28 131.9,66.01 131.79,66.01 131.73,65.95
  BOTTOM w0.508: 131.73,65.95 130.33,65.95 v1(129.98,65.6) 129.98,64.44 R602.1
PROC_OPI_COMP3: length 2
  TOP w0.254: v1(125.4,83.97) 124.97,84.41 v2(124.87,84.41) 124.74,84.27 R606.1
  BOTTOM w0.254: v2(124.87,84.41) 124.51,84.04 CPU1.Y22
PROCHOT_EC: length 25.5
  TOP w0.14: v2(186.16,74.98) 186.16,75.28 185.97,75.47 185.97,76.37 187.6,78 189.49,78 189.51,77.99 KBC24.24
  BOTTOM w0.14: v2(186.16,74.98) 186.06,74.88 v1(184.42,74.88) 182.61,74.88 182.46,74.73 181.82,74.73 179.96,72.87 178,72.87 177.39,72.27 177.39,71.9 177.32,71.84 R2442.1 177.32,71.01 176.67,70.36 R2438.1 175.89,70.36 175.06,71.18 174.36,71.18 174.02,70.85 Q2401.G
PROJECT_ID1: length 9
  TOP w0.102: v2(138.92,82.96) 139.68,82.96 v1(140.64,83.92) 142.88,86.16 R1510.2 143.77,85.31 R1511.1
  BOTTOM w0.102: v2(138.92,82.96) 138.87,82.96 138.53,82.62 CPU1.AC1
PROJECT_ID2: length 10.5
  TOP w0.102: v2(142.66,89.74) 143.6,90.68 R1514.1 R1513.2
  L3 w0.102: v2(138.54,89.1) 138.76,88.88 139.69,88.88 140.67,89.86 142.54,89.86 v2(142.66,89.74)
  BOTTOM w0.089: v2(138.54,89.1) 138.4,88.95 137.38,88.95 137.33,88.9 136.75,88.9 CPU1.L2
  BOTTOM w0.102: v2(142.66,89.74) 142.47,89.74 142.13,89.39 v1(142.13,89.38)
PS_ID: length 3.4
  TOP w0.508: v1(121.74,177.23) PR4205.1 120.86,176.31 PR4206.2 120.86,175.67 PQ4201.S
PS_ID_R: length 17.7
  TOP w0.102: PR4217.1 103.15,171.47 AFTP3802.1 102.68,171.54 99.47,168.33 99.47,164.39 98.41,163.33 94.37,163.33 93.8,162.76 DCIN1.4
PS_ID_R2: length 18
  TOP w0.508: PR4217.2 103.59,168.73 104.33,169.48 v2(104.33,170.86)
  BOTTOM w0.635: v2(104.33,170.86) 105.16,170.03 107.1,170.03 108.54,171.46 109.14,171.46 110.92,173.24 115.91,173.24 v2(117.26,171.89)
  vias: v1(119.19,177.22)
PS_S3CNTRL: length 4.8
  TOP w0.127: Q3601.6 30.58,17.64 30.72,17.77 30.72,18.14 30.56,18.29 Q3601.5 28.82,18.29 R3607.2 28.63,19.1 v1(28.37,19.36)
PSID_DISABLE#_R_C: length 6.9
  TOP w0.635: PQ4201.G 122.21,173.03 122.7,173.03 PQ4202.C 123.81,174.13 123.81,176.04 PR4203.2 123.81,176.06 123.81,176.97 v2(123.55,177.22)
  BOTTOM w0.508: v1(123.01,176.5) 123.55,177.04 v2(123.55,177.22)
PSID_EC: length 149.9
  TOP w0.102: v2(131.23,174.21) 131.22,174.21 131.22,174.54 PR4204.2 130.58,174.85 129.95,174.22 PD4203.3 127.48,175.91 v1(126.68,176.71) 125.66,177.73 123.27,177.73 122.63,177.08 PR4205.2 ; v2(180.53,78.62) 180.53,78.11 181.1,77.53 181.1,77.5 182.44,76.17 182.44,72.97 180.92,71.45 180.9,71.45 179.95,70.51 179.95,68.86 179.6,68.5 KBC24.99
  L4 w0.102: v2(180.53,78.62) 179.87,78.62 179.85,78.64 178.34,78.64 176.32,80.66 176.32,83.18 172.59,86.92 172.59,88.56 171.49,89.66 163.9,89.66 159.76,93.79 159.76,94.34 154.79,99.32 154.79,102.08 153.45,103.41 153.45,117.01 153.78,117.34 153.78,118.67 152.97,119.49 152.81,119.49 149.26,123.04 149.26,129.66 148.7,130.22 148.7,143.77 147.42,145.05 147.42,149.01 147.63,149.23 147.63,151.66 147,152.29 147,153.61 147,153.81 146.41,154.4 146.41,155.15 146.41,155.95 142.13,160.23 140.19,160.23 139.07,161.35 139.07,163.14 135.44,166.78 135.44,170.59 131.82,174.21 v2(131.23,174.21)
PSL_IN1#: length 3.8
  TOP w0.102: R2430.2 174.73,78.47 175.26,77.93 v1(175.67,77.93) 175.73,77.99 KBC24.73
PSL_IN2#: length 6.1
  TOP w0.102: v1(175.27,66.42) 174.81,66.42 R2427.2 R2425.1 174.64,67.8 174.82,67.98 174.82,68.33 176.48,69.99 KBC24.93
PSL_OUT#: length 14.6
  TOP w0.102: v2(180.58,75.14) 180.07,75.65 180.07,75.95 179.28,76.74 179.28,76.84 178.54,77.59 KBC24.74
  BOTTOM w0.102: v2(180.58,75.14) 180.08,75.14 179.95,75.28 178.9,75.28 178.72,75.09 177.49,75.09 177.17,75.41 175.02,75.41 173.88,74.26 v1(172.36,74.26) 172.36,74.26 R2432.1
PU4401_4: length 5.1
  TOP w0.254: PR4454.2 127.08,167.1 v1(127.08,166.23) 126.55,166.23 126.26,166.53 PC4424.2 PR4410.2 124.43,168.06 124.06,168.06
PU4401_5: length 4.8
  TOP w0.254: 124.06,168.71 124.67,168.71 PR4410.1 PC4424.1 126.26,168.69 126.49,168.93 v1(126.76,168.93) 126.85,168.93 127.13,168.65 PR4448.2
PU4401_6: length 3.8
  TOP w0.127: PR4446.2 123.26,171.07 122.77,171.07 122.61,170.92 v1(122.61,170.74) 122.61,170.64 123.1,170.16 123.1,169.6 123.33,169.36 124.06,169.36
PURE_HW_SHUTDOWN#: length 95
  TOP w0.102: Q2602.D 162.85,67.48 162.85,65.92 163.65,65.12 164.51,65.12 165.39,64.24 165.39,63.82 D3602.3 166.58,63.3 166.86,63.58 166.86,64.09 166.62,64.33 R2612.1 166.62,65.07 166.94,65.38 168.68,65.38 169.5,64.56 R2439.2 170.25,64.92 v1(170.25,65.45) 170.25,66.98 169.99,67.24 169.53,67.24 169.5,67.21 Q3602.C 168.55,67.24 Q2404.B 168.55,70.22 167.62,71.15 167.62,72.06 169.55,73.99 170.2,73.99 170.84,74.63 C2610.1 173.05,73.95 R2424.1 172.22,73.81 v2(172.1,73.68)
  L3 w0.102: v2(172.1,73.68) 171.2,74.58 171.2,76.29 173.9,78.99 178.94,78.99 179.57,79.62 v2(179.57,79.98)
  L4 w0.102: v2(179.57,79.98) 179.57,80.54 184.12,85.1 184.12,86.34 186.09,88.3 189.25,88.3 192.28,91.33 v2(192.28,120.89)
  BOTTOM w0.102: C7610.1 195.1,122.1 R7653.2 194.26,121.94 193.21,120.89 v2(192.28,120.89)
PWR_1D05V_BOOT: length 4.1
  TOP w0.305: 132.06,142.6 131.86,142.8 PU4806.10
  TOP w0.508: PR4820.1 134.22,140.44 v1(133.08,141.58) 132.06,142.6
PWR_1D05V_BOOT_R: length 2.4
  TOP w0.762: PC4822.2 130.56,140.18 131.54,140.18 v1(131.58,140.22) 131.62,140.18 132.89,140.18 PR4820.2
PWR_1D05V_CCM: length 2.7
  TOP w0.254: PU4806.5 129.07,145.9 128.51,145.34 PR4824.1 127.86,144.62 v1(127.67,144.43)
PWR_1D5V_EN: length 3.6
  BOTTOM w0.127: v1(147.55,98.13) 147.55,98.59 147.74,98.78 PR5110.2 PC5102.1 148.63,100.45 PU5101.3
PWR_1D05V_EN: length 3.6
  TOP w0.305: PC4821.1 130.34,147.31 PU4806.3
  TOP w0.508: PC4821.1 PR4819.2 v1(131.34,148.55)
PWR_1D05V_FB: length 5.5
  TOP w0.305: PU4806.4 129.84,146.4 129.56,146.69 129.09,146.69 128.6,146.2 PR4823.1
  TOP w0.508: v1(126.05,147.03) PR4822.2 PC4823.2 127.87,146.22 PR4823.1
PWR_1D05V_LGATE: length 8.5
  TOP w0.305: PU4806.6 128.71,142.8 v3(128.69,142.83)
  L4 w1.016: v3(127.93,136.3) 127.95,136.32 127.95,139.25 128.69,139.98 v3(128.69,142.83)
  BOTTOM w0.508: v3(128.69,142.83) v1(127.64,142.83)
PWR_1D05V_PHASE: length 15.8
  TOP w0.305: v3(130.34,141.56) PU4806.8
  TOP w0.508: v3(130.34,141.56) 130.34,141.51 129.22,140.39 PC4822.1
  L4 w1.016: v3(133.64,130.24) 133.64,130.71 131.97,132.38 131.97,139.32 130.34,140.96 v3(130.34,141.56)
  vias: v1(133.14,129.39) v3(127.62,129.53) v3(127.67,130.46) v3(128.52,129.54) v3(128.55,130.38) v3(129.51,130.41) v3(129.47,129.57) v3(130.4,130.41) v3(130.4,129.57) v3(131.34,130.43) v3(131.33,129.57) v3(132.22,130.43) v3(132.27,129.57)
PWR_1D05V_PWR: length 33.5
  TOP w0.254: v2(125.49,144.78) 125.41,144.86 125.41,147.29 126.04,147.92 PR4822.1 PC4823.1
  BOTTOM w0.254: PG4832.1 130.79,123.1 129.01,124.87 125.84,124.87 125.24,125.47 v1(125.24,141.22) 125.24,144.54 v2(125.49,144.78)
PWR_1D05V_PWRGD: length 2.5
  TOP w0.305: PR4821.1 133.57,145.37 132.7,145.37 v1(132.68,145.39) 132.17,145.9 PU4806.1
PWR_1D05V_SNUB:
  vias: v1(126.08,135.48)
PWR_1D05V_TRIP: length 3.7
  TOP w0.254: PU4806.2 130.84,146.39 131.37,146.92 131.78,146.92 v1(132.19,146.51) 132.24,146.45 132.29,146.45 132.39,146.36 133.51,146.36 PR4817.2
PWR_1D05V_UGATE: length 14.9
  TOP w0.305: PU4806.9 130.84,142.07 v3(131.48,141.43)
  L4 w1.016: v3(134.78,130.84) 134.78,131.18 133.12,132.85 133.12,139.79 v3(131.48,141.43)
  BOTTOM w0.508: v3(131.48,141.43) v1(132.77,141.43)
PWR_1D35V_DRVH: length 15.6
  TOP w0.203: v3(62.47,21.87) 61.98,21.39 PU4901.14
  L4 w1.016: v3(62.47,21.87) 68.94,21.87 71.29,24.22 v3(74.66,24.22)
  BOTTOM w0.508: v1(62.8,22.56) 62.77,22.53 62.76,22.53 62.48,22.25 62.48,22.17 62.47,22.15 v3(62.47,21.87)
PWR_1D35V_DRVL: length 9.9
  TOP w0.203: PU4901.11 61.1,19.56 v3(61.2,19.46)
  L4 w1.016: v3(61.2,19.46) 63.23,17.43 v3(68.82,17.43)
  BOTTOM w0.508: v1(61.21,20.12) 61.2,20.12 61.2,19.47 v3(61.2,19.46)
PWR_1D35V_EN: length 3.5
  TOP w0.127: PR4907.2 PC4906.1 62.23,24.08 v1(61.51,23.36) 60.68,22.54 PU4901.16
PWR_1D35V_MODE: length 2.8
  TOP w0.203: PU4901.19 59.14,23.1 58.85,23.4 58.68,23.4 v1(58.45,23.63)
  TOP w0.254: PR4908.2 57.7,24.38 v1(58.45,23.63)
PWR_1D35V_REFIN: length 5.4
  TOP w0.203: PU4901.8 59.54,18.46 59.56,18.44
  TOP w0.254: 59.56,18.44 59.56,17.87 60.22,17.21 PR4903.2 60.16,17.1 PC4902.1 PR4901.1 61.5,16.34 v1(61.98,15.85)
PWR_1D35V_SW: length 16.1
  TOP w0.203: v3(62.72,20.6) 62.34,20.98 PU4901.13
  TOP w0.508: PC4919.2 63.55,21.12 63.03,20.6 v3(62.72,20.6)
  L4 w1.016: v3(62.72,20.6) 69.47,20.6 71.8,22.94 v3(74.72,22.94)
  vias: v1(70.12,23.45) v3(74.72,21.87) v3(74.72,20.73) v3(74.71,19.59) v3(74.71,18.42) v3(75.65,21.84) v3(75.63,20.71) v3(75.63,19.57) v3(75.63,18.45) v3(75.72,22.91)
PWR_1D35V_TRIP: length 3.5
  TOP w0.203: PU4901.18 59.54,23.27 59.39,23.43
  TOP w0.254: 59.39,23.43 58.52,24.3 PR4902.1 59.42,24.67 v1(59.44,24.65)
PWR_1D35V_VBST: length 5.1
  TOP w0.203: 61.82,22.27 61.34,21.79 PU4901.15
  TOP w0.508: v1(64.24,24.8) 64.24,24.03 63.55,23.33 PR4905.1 62.41,22.86 61.82,22.27
PWR_1D35V_VDDQS: length 36.2
  TOP w0.203: 59.95,18.34 PU4901.9
  TOP w0.254: 59.95,18.34 60.26,18.03 60.31,18.03 v2(60.54,17.81)
  L3 w0.254: v2(87.11,17.67) 87.11,15 86.39,14.28 77.55,14.28 77.15,14.69 74.25,14.69 73.39,13.82 63.05,13.82 60.54,16.34 v2(60.54,17.81)
  BOTTOM w0.254: PG4907.1 v1(86.51,17.68) 87.1,17.68 v2(87.11,17.67)
PWR_1D35V_VREF: length 3.5
  TOP w0.203: PU4901.6 58.74,18.91 58.53,18.7
  TOP w0.254: 58.53,18.7 58.53,18.14 v1(58.73,17.94) 59.33,17.34 PR4903.1 59.27,17.1 PC4903.1
PWR_1D35V_VTTREF:
  vias: v1(56.87,16.49)
PWR_3D3V_CS2: length 3.4
  TOP w0.203: PU4503.5 40.27,56.69
  TOP w0.254: 40.27,56.69 39.98,56.69 39.29,57.38 v1(38.64,57.38) 38.49,57.24 PR4517.1
PWR_3D3V_DRVH2: length 16.7
  TOP w0.203: v3(39.12,53.74) 39.12,53.87 39.59,54.34 PU4503.10
  L4 w1.016: v3(39.12,53.74) 38.87,53.49 38.22,53.49 33.66,48.93 v3(33.66,41.55)
  BOTTOM w0.508: v3(39.12,53.74) 38.64,53.74 v1(38.48,53.59)
PWR_3D3V_DRVL2: length 9.4
  TOP w0.203: v3(40.52,52.56) 40.74,52.78 PU4503.11
  L4 w1.016: v3(40.52,52.56) 35.95,47.99 v3(35.95,46.89)
  BOTTOM w0.508: v1(40.48,51.9) 40.52,51.94 v3(40.52,52.56)
PWR_3D3V_EN2: length 2.6
  TOP w0.127: PU4503.6 38.71,55.94 v1(38.49,56.16) 38.24,56.41 PR4506.2
PWR_3D3V_FB2: length 5.5
  TOP w0.203: PU4503.4 41.14,57.19 40.89,57.43 40.37,57.43
  TOP w0.254: 40.37,57.43 39.86,57.94 PR4523.1 39.8,58.58 v1(38.95,58.58) 38.95,59.45 PR4512.2 PC4523.2
PWR_3D3V_FB2_R: length 2.1
  TOP w0.254: v1(36.87,61.11) 36.97,61.21 PR4535.2 38.11,61.15 PC4523.1
PWR_3D3V_LL2: length 19.5
  TOP w0.203: PU4503.8 38.62,55.14 38.36,54.89 v3(38.36,54.76)
  TOP w0.508: PC4535.2 37.98,54.38 v3(38.36,54.76)
  L4 w1.016: v3(38.36,54.76) 37.69,54.76 32.39,49.46 32.39,41.56 32.39,41.56 v3(32.39,41.52)
  vias: v1(35.77,40.23) v3(31.36,41.48) v3(31.5,40.41) v3(32.65,40.41) v3(35.06,41.17) v3(36.08,41.17) v3(37.09,41.17) v3(38.11,41.17) v3(38.84,40.54)
PWR_3D3V_SNUB: length 2.9
  TOP w0.508: PR4533.2 40.38,43.52 v1(40.14,43.76) PC4520.1
PWR_3D3V_VBST2: length 3.7
  TOP w0.203: 38.05,53.54 39.25,54.74 PU4503.9
  TOP w0.508: PR4528.2 37.62,53.11 v1(38.05,53.54) 38.05,53.54
PWR_3D3V_VBST2_1: length 3.6
  TOP w0.508: v1(33.36,54.6) 34.14,54.6 34.36,54.38 PC4535.1 PR4528.1
PWR_5V_CS1: length 3.9
  TOP w0.203: 42.57,57.31 42.34,57.07 PU4503.1
  TOP w0.254: PR4531.1 44.69,57.97 v1(44.51,57.79) 44.26,57.79 43.78,57.31 42.57,57.31
PWR_5V_DRVH1: length 18.8
  TOP w0.203: v3(43.95,53.87) 43.48,54.34 PU4503.16
  TOP w0.381: PU4501.4 50.89,41.72 v3(51.06,41.55)
  L4 w1.016: v3(51.06,41.55) 51.16,41.65 51.16,47.57 44.86,53.87 v3(43.95,53.87)
  BOTTOM w0.508: v1(43.36,54.17) 43.65,53.87 v3(43.95,53.87)
PWR_5V_DRVL1: length 9.2
  TOP w0.203: v3(43.19,52.85) 42.68,52.85 42.34,53.2 PU4503.15
  L4 w1.016: v3(43.19,52.85) 43.57,52.47 v3(43.57,45.87)
  BOTTOM w0.508: v1(43.16,52.19) 43.19,52.22 v3(43.19,52.85)
PWR_5V_EN1: length 6.4
  TOP w0.127: v1(46.74,59.92) 46.74,59.77 45.73,58.76 PR4504.2 45.57,57.35 44.83,56.6 43.39,56.6 43.09,56.3 PU4503.20
PWR_5V_EN1_R: length 15.5
  TOP w0.127: PR4507.2 36.38,58.12 35.86,58.64 PR4530.1 PR4501.2 35.86,60.46 35.66,60.66 v1(35.66,61) 36.68,62.03 44.17,62.03 45.57,60.62 PR4504.1
PWR_5V_FB1: length 5.1
  TOP w0.203: PU4503.2 41.94,57.58 42.08,57.73
  TOP w0.254: 42.08,57.73 PC4522.2 PR4527.2 PR4526.1 42.08,61.26 v1(41.76,61.58)
PWR_5V_FB1_R: length 2.5
  TOP w0.254: PR4525.2 43.8,58.12 43.52,57.84 v1(43.03,57.84) 42.97,57.9 PC4522.1
PWR_5V_LL1: length 24.1
  TOP w0.203: v3(44.2,55.14) PU4503.18
  TOP w0.508: v3(44.2,55.14) 45.55,55.14 PC4516.2
  L4 w1.016: v3(44.2,55.14) 45.39,55.14 52.43,48.1 52.43,41.13 51.59,40.28 49.97,40.28 49.79,40.46 v3(49.79,40.54)
  vias: v1(46.54,40.38) v3(44.08,41.42) v3(44.97,41.42) v3(45.85,41.42) v3(46.74,41.42) v3(47.63,41.42) v3(48.52,41.42) v3(49.39,41.45)
PWR_5V_SNUB: length 2.9
  TOP w0.508: PC4536.1 42.17,43.85 v1(42.18,43.85) 42.17,43.84 42.17,42.41 PR4529.2
PWR_5V_VBST1: length 3.2
  TOP w0.203: PU4503.17 43.59,54.74 43.78,54.55 44.39,54.55 v1(44.76,54.18)
  TOP w0.508: PR4524.1 45.32,53.62 v1(44.76,54.18)
PWR_5V_VBST1_1: length 2.4
  TOP w0.508: PC4516.1 PR4524.2 47.12,52.47 v1(47.13,52.47)
PWR_5V_VCLK: length 6.1
  TOP w0.102: PC4532.1 PC4514.1 46.13,57.17 45.71,56.76 PC4521.1 44.91,56 v1(44.76,56.16) 44.33,56.16 43.71,55.54 PU4503.19
PWR_5V_VO1: length 97.2
  TOP w0.203: PU4503.14 41.94,52.84 v2(42.04,52.73)
  TOP w0.508: PR4527.1 43.73,59.59 PR4525.1 v2(43.8,60.41)
  L3 w0.508: v2(42.04,52.73) 42.04,53.47 42.87,54.29 42.87,58.23 44.39,59.75 48.64,59.75 54.08,54.31 54.08,37.44 49.28,32.64 47.66,32.64 v2(46.02,31.01)
  BOTTOM w0.254: v2(46.02,31.01) 45.88,31.15 PG4532.2 45.88,32.47 46.74,33.33 49.44,33.33 v1(53.73,37.62) 55.39,39.28 55.39,58.47 51.35,62.51 49.54,62.51 48.9,61.87 45.26,61.87 v2(43.8,60.41)
PWR_CHG_ACDET: length 5.8
  TOP w0.254: v2(106.71,160.3) 106.84,160.43 107.17,160.43 107.35,160.61 PC4412.1 PR4431.1
  BOTTOM w0.254: PU4401.6 106.91,160.5 v2(106.71,160.3) 106.64,160.23 106.64,159.47 v1(106.29,159.12) 105.61,158.44 PR4407.2
PWR_CHG_ACN: length 7.5
  TOP w0.203: 109.71,154.6 109.71,155.07 109.81,155.17 110.04,155.17 110.54,155.67 PR4406.1 PC4402.2 110.54,157.41 PC4403.1 110.71,158.28 110.78,158.35 110.78,158.37 v2(110.95,158.55) ; 109.71,154.6 v1(109.88,154.6) ; 109.71,154.6 109.71,154.41 109.23,153.93 PG4403.2
  BOTTOM w0.203: PU4401.1 110.86,158.64 v2(110.95,158.55)
PWR_CHG_ACOK: length 63.1
  TOP w0.102: PQ4408.3 140.37,154.16 v2(140.57,153.95) ; PQ4402.2 103.63,164.6 103.45,164.79 PR4476.1 102.27,165.47 v2(102.27,165.87)
  L3 w0.102: v2(140.57,153.95) 140.57,153.8 139.58,152.81 114.27,152.81 v2(113.06,154.01)
  L4 w0.102: v2(102.27,165.87) 102.27,165.76 103.77,164.26 103.77,159.71 104.22,159.26 104.22,158.91 103.97,158.65 103.79,158.65 103.06,157.92 103.06,156.62 102.27,155.82 102.27,152.63 103.74,151.16 106.18,151.16 107.96,152.94 111.99,152.94 v2(113.06,154.01)
  BOTTOM w0.102: v2(113.06,154.01) 113.01,154.07 PR4436.1 112.4,154.07 PR4428.2 111.55,154.08 PR4419.2 ; v2(102.27,165.87) 102.27,165.96 v1(101.65,166.58)
PWR_CHG_ACP: length 8.3
  TOP w0.203: 108.41,153.88 108.21,153.88 107.47,153.14 PG4402.2 ; 108.41,153.88 108.71,153.88 109.38,154.54 109.38,155.39 PR4406.2 PC4402.1 109.66,157.54 PC4404.1 109.62,157.87 v2(110.29,158.55) ; 108.41,153.88 v1(108.41,154.1)
  BOTTOM w0.203: v2(110.29,158.55) 110.36,158.62 PU4401.2
PWR_CHG_AD_OFF: length 175.8
  TOP w0.102: KBC24.11 191.85,72.79 191.64,72.99 190.58,72.99 190.11,72.52 189.19,72.52 187.69,74.03 186.54,74.03 185.98,74.58 185.95,74.58 185.05,75.49 185.05,76.78 183.94,77.88 v2(183.94,78.06)
  L3 w0.102: v2(95.38,148.67) 96.91,150.19 107.61,150.19 110.12,152.71 110.57,152.71 111.8,151.48 141.09,151.48 141.4,151.79 142.18,151.79 v2(142.39,151.99)
  L4 w0.102: v2(183.94,78.06) 183.9,78.06 183.72,78.24 182.14,78.24 181.83,77.93 179.56,77.93 179.46,78.03 178.27,78.03 175.84,80.46 175.84,82.09 174.97,82.95 174.97,83.54 174.43,84.08 173.07,84.08 169.03,88.11 163.25,88.11 151.76,99.61 151.76,100.17 148,103.93 148,105.4 148.19,105.59 148.19,113.36 145.64,115.91 144.02,115.91 141.03,118.9 141.03,122.19 141.79,122.95 141.79,141.68 143.51,143.41 143.51,147.1 141.55,149.06 141.55,151.16 v2(142.39,151.99)
  BOTTOM w0.102: PQ4206.G 89.49,153.67 v1(89.44,153.62) 89.97,153.09 PR4210.1 90.29,149.61 91.38,148.52 93.89,148.52 94.04,148.67 v2(95.38,148.67)
PWR_CHG_AD_OFF_R: length 2.2
  BOTTOM w0.102: PQ4204.B 91.43,154.09 v1(91.52,154) 91.18,153.66 PR4210.2
PWR_CHG_BAT_SCL: length 3.9
  BOTTOM w0.127: PU4401.9 107.3,162 107.19,161.89 v1(106.29,161.89) 105.64,161.89 104.98,161.24 PG4407.1
PWR_CHG_BAT_SDA: length 4.1
  BOTTOM w0.127: PU4401.8 108.05,161.46 106,161.46 v1(105.49,160.95) 105.43,160.95 105.08,160.61 104.86,160.61 PG4408.1
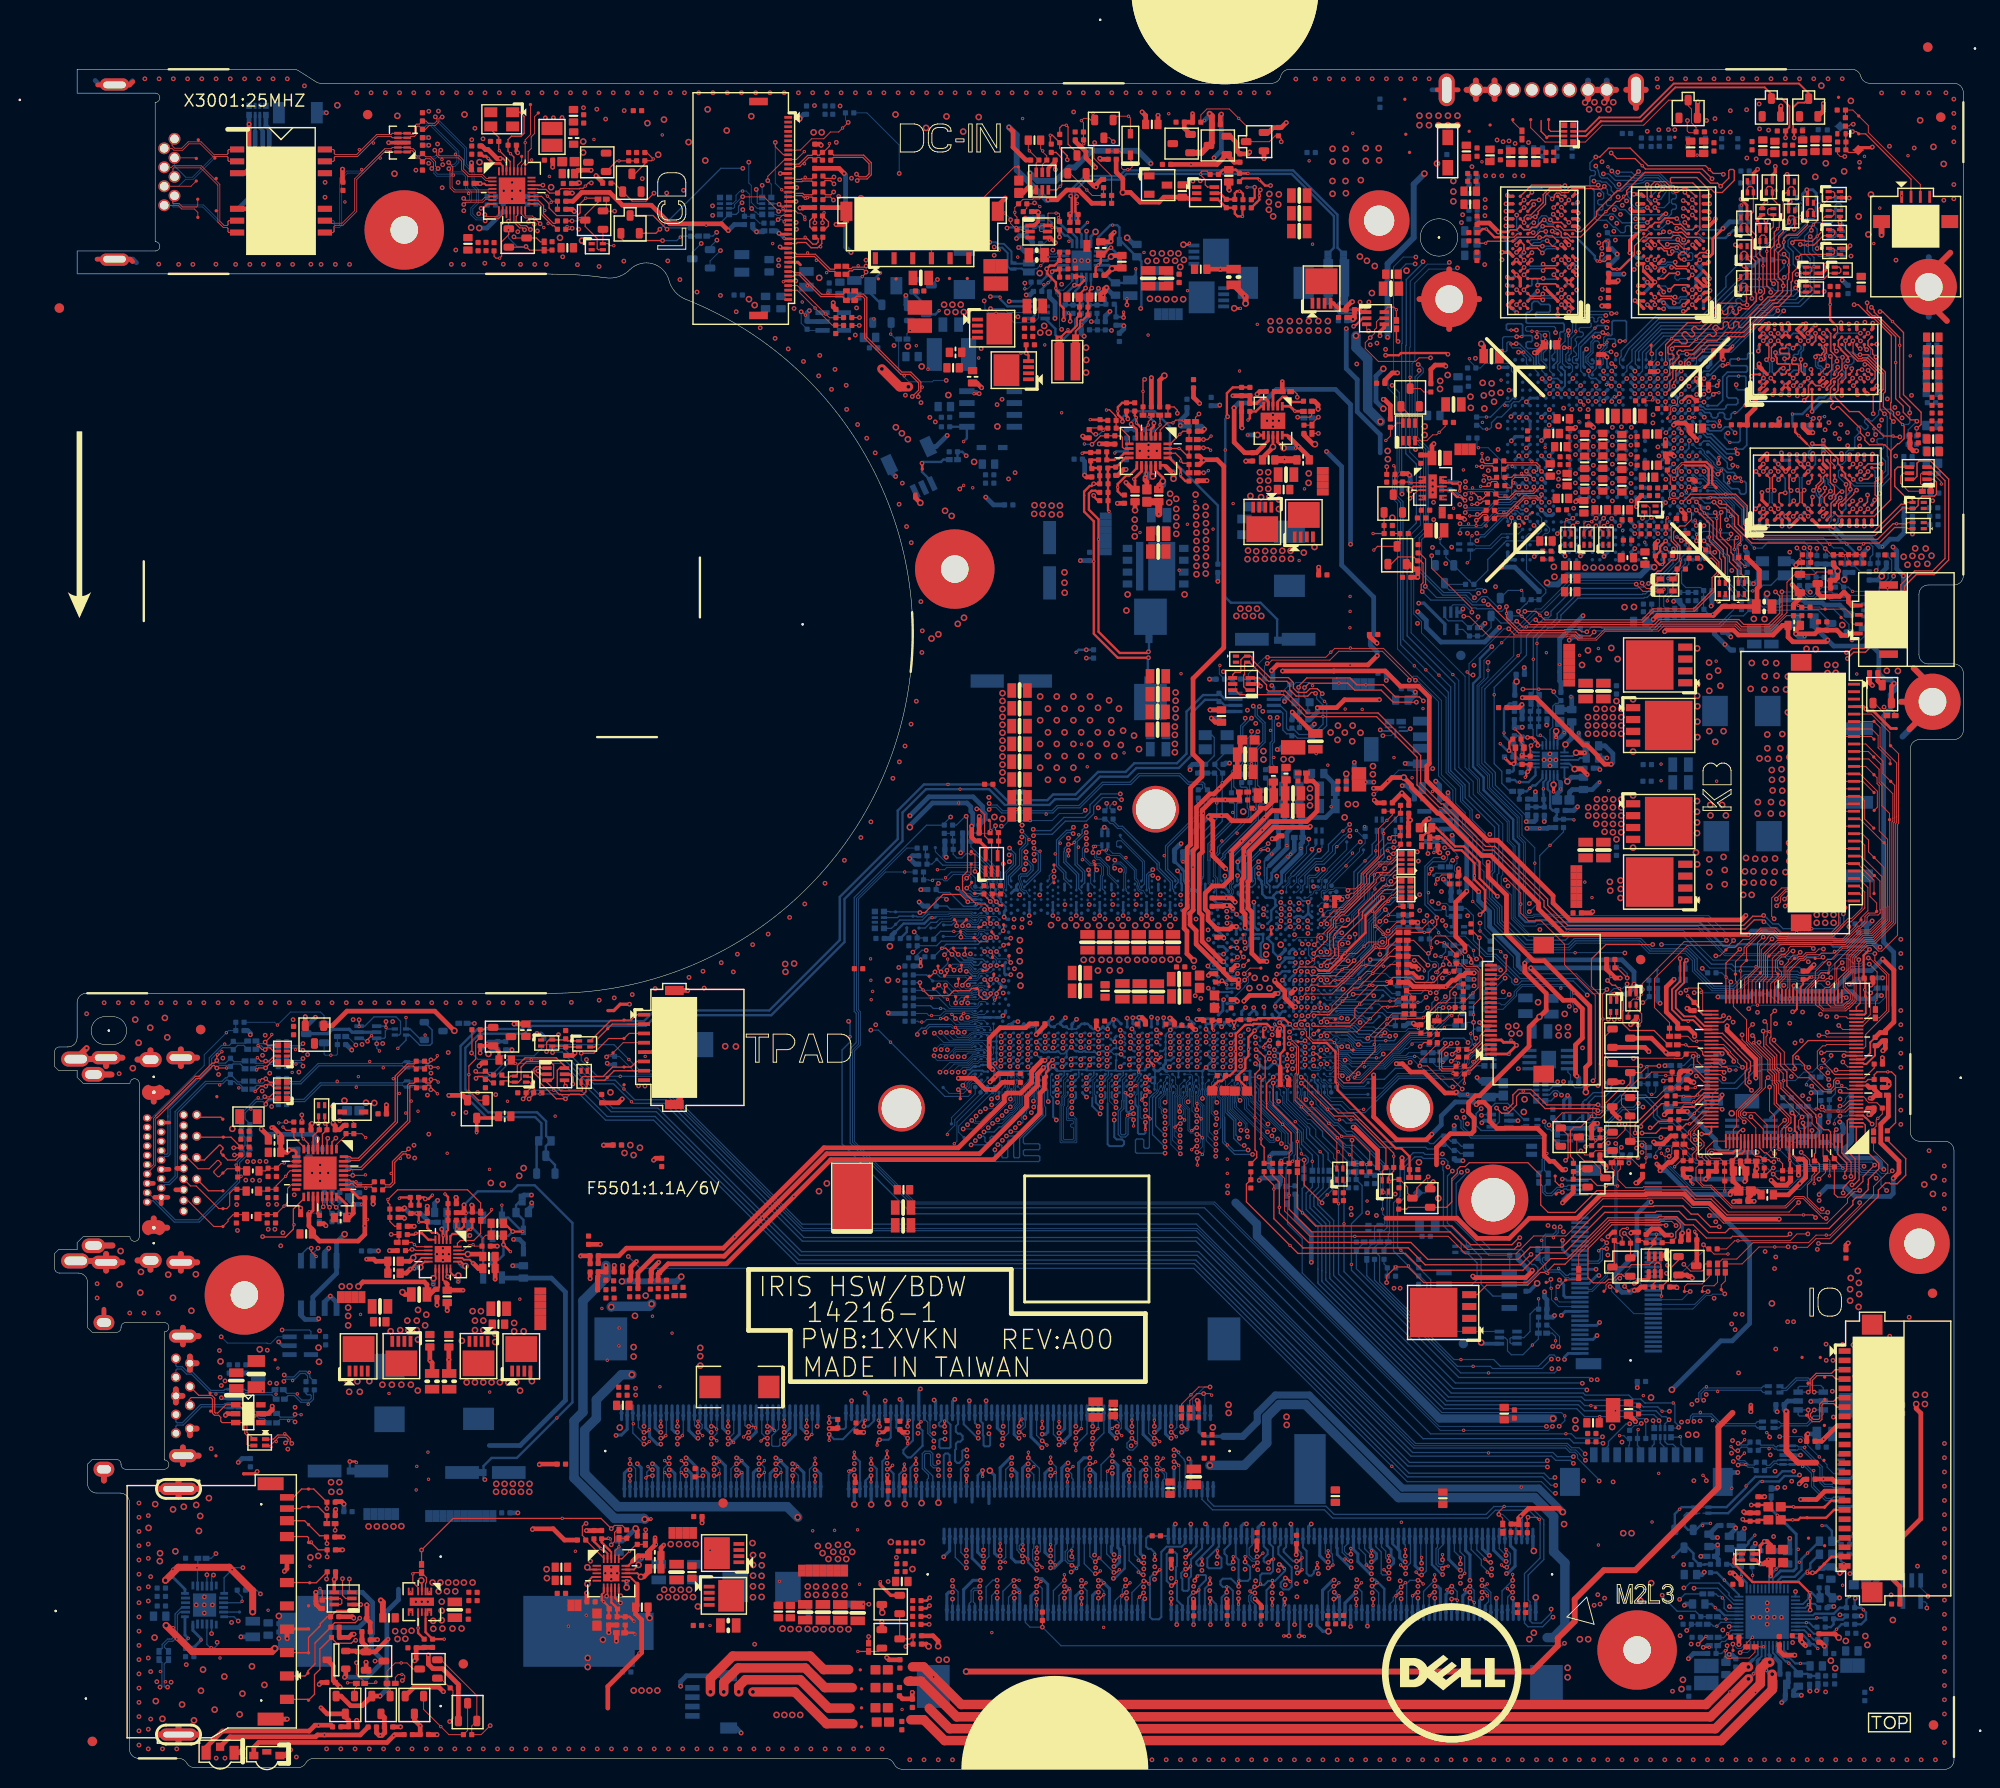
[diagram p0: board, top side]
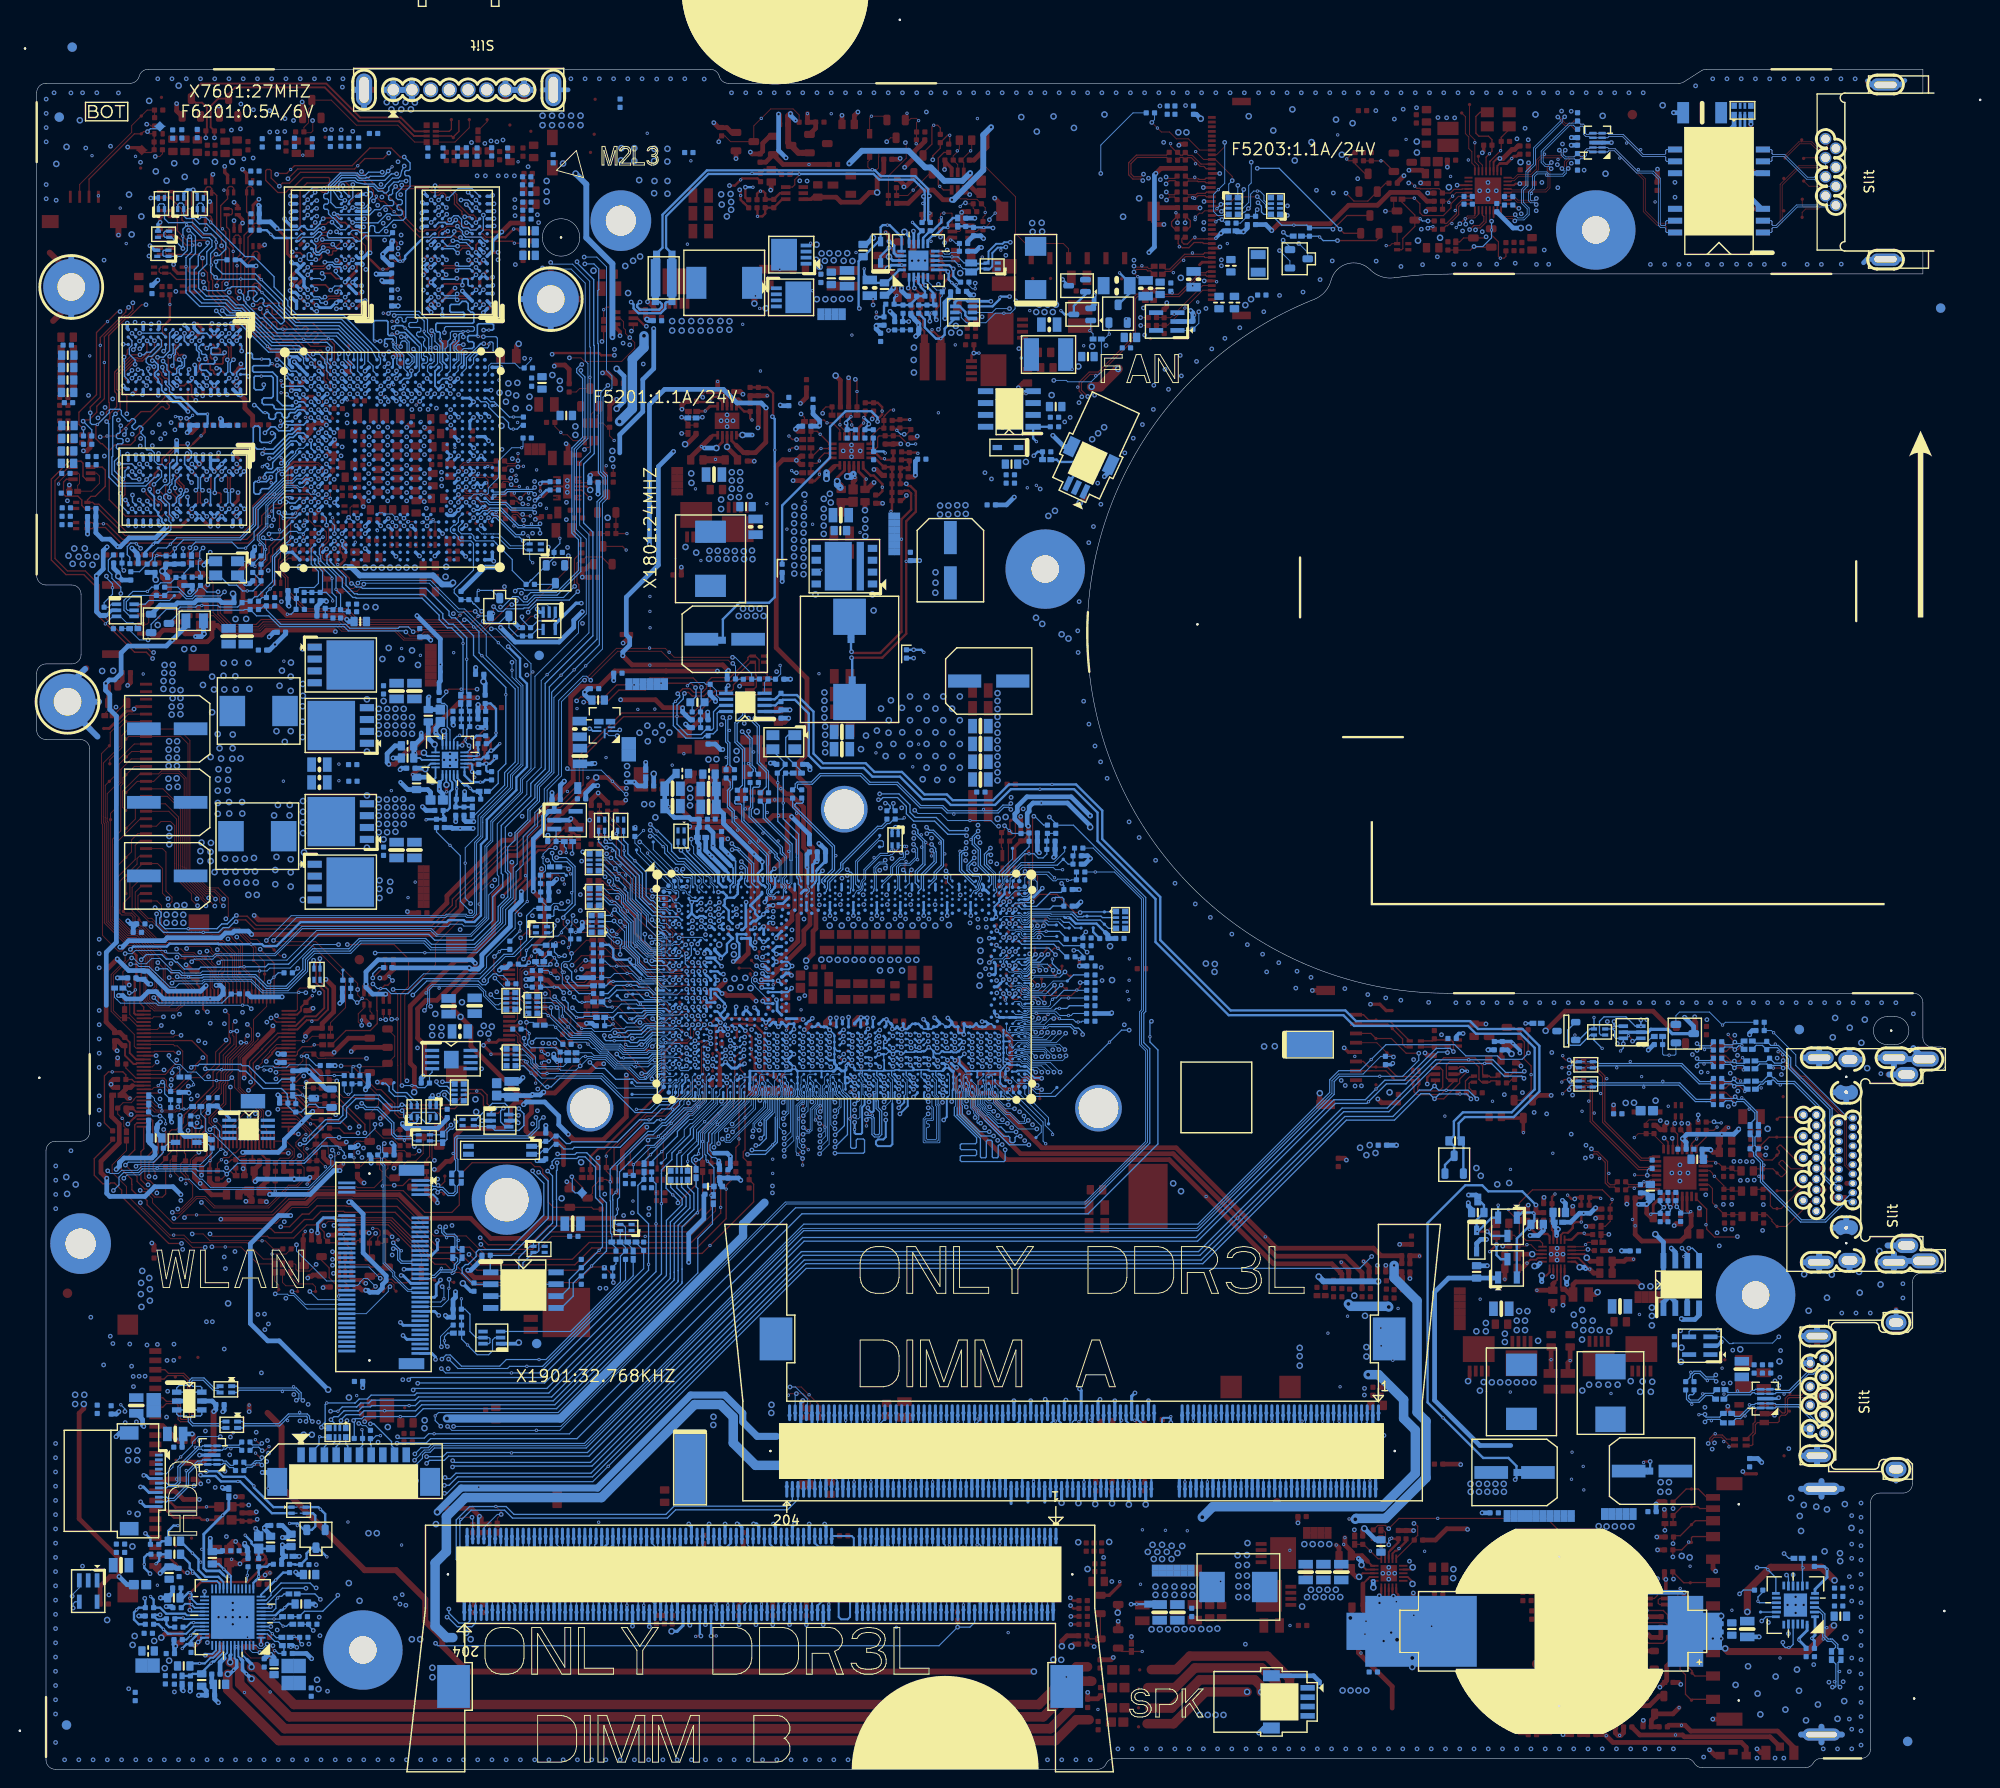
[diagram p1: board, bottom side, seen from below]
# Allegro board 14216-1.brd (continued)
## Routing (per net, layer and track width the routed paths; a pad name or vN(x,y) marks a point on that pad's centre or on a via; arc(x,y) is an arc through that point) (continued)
PWR_CHG_BTST: length 4.7
  TOP w0.508: v1(113.37,164.52) 113.01,164.17 v2(113.01,163.56) 112.96,163.5 PR4409.1
  BOTTOM w0.305: v2(113.01,163.56) 112.86,163.4 112.79,163.4 112.48,163.09 112.48,162.31 112.17,162 PU4401.17
PWR_CHG_BTST_R: length 5.9
  TOP w0.254: v2(113.01,162.87) 112.88,162.87 112.2,162.18 PR4409.2 111.92,161.29 v1(111.65,161.02) 111.37,160.75 PC4411.1
  BOTTOM w0.254: v2(113.01,162.87) 113.91,161.97 PD4401.K
PWR_CHG_CMPIN: length 7.8
  TOP w0.254: PR4413.1 109.98,159.78 v1(110.15,159.61) 110.15,159.36 109.64,158.86 v2(109.1,158.86)
  BOTTOM w0.254: PU4401.4 109.36,159.12 v2(109.1,158.86) 108.27,158.03 PR4414.2 108.27,156.93 PR4411.2 108.1,156.74 PR4427.2 PR4429.1
PWR_CHG_CMPIN_R: length 6.8
  BOTTOM w0.254: PQ4401.6 107.06,154.19 107.06,153.55 v1(107.47,153.14) 107.98,153.14 109.18,154.33 109.18,155.19 PR4429.2
PWR_CHG_CMPIN_RR: length 18.9
  TOP w0.254: v1(108.47,155.89) 108.64,155.72 v2(108.64,155)
  L3 w0.254: v2(108.64,155) 108.29,154.64 107.5,154.64 107.09,154.23 107.09,153.41 106.85,153.17 103.15,153.17 100.72,155.6 100.72,157.03 v2(100.11,157.64)
  BOTTOM w0.254: v2(100.11,157.64) 101.07,157.64 v1(101.15,157.56) 101.15,157.38 101.94,156.59 PQ4401.3 ; PR4427.1 108.64,155.54 v2(108.64,155)
PWR_CHG_CMPOUT: length 7.3
  BOTTOM w0.254: v1(112.18,157.77) 112.47,157.48 PR4437.1 112.38,156.74 PR4430.2 PR4438.1 110.68,156.85 110.05,157.47 PR4432.1 PR4414.1 109.16,158.2 109.61,158.65 109.61,158.79 109.86,159.04 PU4401.3
PWR_CHG_CSON_1: length 42.6
  TOP w0.254: v2(108.69,168.41) 108.82,168.28 108.82,166.64 PC4421.2 108.61,165.61 PC4423.1
  BOTTOM w0.254: 108.82,166.57 108.82,165.8 PR4420.2 ; 108.82,166.57 v1(108.64,166.57) ; 108.82,166.57 108.82,168.28 v2(108.69,168.41) 108.82,168.53 108.82,169.15 110.21,170.54 113.9,170.54 114.51,171.15 132.49,171.15 137.24,166.4 137.24,162.87 PG4410.1
PWR_CHG_CSOP_1: length 41.3
  TOP w0.254: v2(109.33,168.36) 109.2,168.23 109.2,166.72 PC4421.1 109.49,165.64 PC4420.1
  BOTTOM w0.254: 109.2,167.61 109.2,168.23 v2(109.33,168.36) 109.2,168.48 109.2,168.99 110.37,170.16 114.06,170.16 114.67,170.77 132.34,170.77 136.86,166.24 136.86,162.87 PG4409.1 ; 109.2,167.61 v1(109.4,167.61) ; 109.2,167.61 109.2,165.85 PR4421.2
PWR_CHG_HIDRV: length 18.9
  TOP w0.254: v3(126.19,156.39) 126.63,156.39 126.64,156.38 126.64,156.38 v1(126.85,156.38)
  TOP w0.508: v3(113.01,161.9) 113.14,162.03 PC4413.2
  L4 w1.016: v3(113.01,161.9) 113.02,161.91 114.76,161.91 116.86,159.81 120.83,159.81 120.85,159.83 122.15,159.83 125.58,156.39 v3(126.19,156.39)
  BOTTOM w0.305: PU4401.18 112.61,161.5 v3(113.01,161.9)
PWR_CHG_IFAULT: length 4.8
  BOTTOM w0.254: PU4401.11 108.86,163.67 108.36,164.16 108.07,164.16 107.2,165.03 v1(106.71,165.03) 106.71,165.52 106.18,166.05 PR4418.2
PWR_CHG_ILIM: length 4.8
  BOTTOM w0.102: PU4401.10 107.36,162.5 107.04,162.18 106.56,162.18 106.38,162.37 105.6,162.37 PR4423.1 PR4417.2 105.85,163.33 106.22,163.69 v1(106.43,163.69)
PWR_CHG_IOUT: length 13.6
  TOP w0.254: v2(107.94,155.15) 107.94,156.39 107.56,156.76 107.56,157.92 107.12,158.37 v1(107.12,158.54) 107.12,159.16 106.2,160.08 106.2,160.53 v2(106.13,160.61) 106.47,160.95 106.95,160.95 107.5,161.5 PC4422.1 PR4424.1
  BOTTOM w0.254: PU4401.7 106.57,161 106.18,160.61 v2(106.13,160.61) 106.13,159.82 105.49,159.19 PR4422.1 ; v2(107.94,155.15) 108.09,155.31 PR4411.1
PWR_CHG_LODRV: length 12.6
  TOP w0.254: v3(120.76,163.2) 121.25,163.2 v1(121.4,163.36)
  L4 w1.016: v3(120.76,163.2) 118.9,165.05 111.84,165.05 v3(111.36,164.57)
  BOTTOM w0.305: PU4401.15 110.86,164.07 v3(111.36,164.57)
PWR_CHG_PHASE: length 24.5
  TOP w0.508: v3(113.13,160.64) 112.4,159.91 PC4411.2
  TOP w0.635: v3(127.41,156.9) 127.41,157.6 v1(127.3,157.72) 127.31,157.72 PR4425.1 ; PC4413.1 113.2,160.71 v3(113.13,160.64)
  L4 w1.016: v3(113.13,160.64) 114.24,160.64 116.33,158.54 121.64,158.54 125.07,155.12 126.74,155.12 127.47,155.85 127.47,156.84 v3(127.41,156.9)
  BOTTOM w0.305: v3(113.13,160.64) 113.14,160.64 112.78,161 PU4401.19
PWR_CHG_REGN: length 21.7
  L4 w0.254: v2(116.19,156.37) 115.83,156.01 114.05,156.01 113.01,154.97 v2(110.9,154.97)
  BOTTOM w0.254: v2(110.9,154.97) 110.91,154.96 PR4428.1 111.51,155.01 PR4430.1 ; v2(116.19,156.37) 116.16,156.37 116.16,156.39 116.26,156.49 116.26,161.42 PC4407.1 115.76,161.9 114.13,163.53 PD4401.A 113.91,165.05 113.68,165.29 v1(113.18,165.29) 112.94,165.29 111.67,164.01 111.67,162.5 PU4401.16
PWR_CHG_SNUB: length 2.9
  TOP w0.508: PR4425.2 124.71,160.57 v1(124.7,160.56) PC4401.1
PWR_CHG_SRN: length 3.8
  BOTTOM w0.254: v1(107.41,166.09) 107.41,165.6 108.33,164.69 PR4420.1 109.36,163.92 PU4401.12
PWR_CHG_SRP: length 3
  BOTTOM w0.254: v1(110.5,165.58) 109.6,164.69 PR4421.1 109.86,164.3 PU4401.13
PWR_CHG_VCC: length 5.6
  BOTTOM w0.254: v1(115.66,160.61) 115.66,159.99 115.09,159.41 PR4408.2 114.76,159.11 PC4010.1 113.29,159.11 111.9,160.5 PU4401.20
PWR_DCBATOUT_1D05V:
  vias: v1(133.72,137.06) v3(134.15,137.69) v3(134.17,138.71)
PWR_DCBATOUT_3D3V:
  vias: v1(32.72,48.69) v3(31.39,49.42) v3(31.39,48.53) v3(31.39,47.52)
PWR_DCBATOUT_5V:
  vias: v1(49.77,50.32) v3(49.16,47.77) v3(49.16,46.89) v3(50.17,46.89)
PWR_DCBATOUT_VCCCORE:
  vias: v1(116.11,132.39) v3(115.55,133.76) v3(115.55,132.87) v3(115.55,131.98)
PWR_DCBATOUT_VGA_CORE1:
  vias: v1(163.7,94.97) v1(164.47,93.31) v3(166.38,94.99) v3(166.43,94.05) v3(167.52,95.15) v3(167.55,94.23) v3(167.52,93.27)
PWR_DCBATOUT_VGA_CORE2:
  vias: v1(163.14,119.24) v1(165.16,119.97) v3(163.41,118.21) v3(164.04,119.77) v3(165.18,118.84) v3(166.54,120.03) v3(167.22,118.84)
PWR_DEBUG: length 13.9
  BOTTOM w0.089: 94.26,91.23 94.34,91.31 95.77,91.31 95.87,91.4 95.98,91.4 95.98,91.41 98,91.41 98.22,91.19 98.74,91.19 98.91,91.36 99.61,91.36 99.69,91.29 100.73,91.29 CPU1.H59
  BOTTOM w0.254: 93.87,91.16 93.87,91.16 94.19,91.16 94.26,91.23 ; 93.87,91.16 93.67,91.16 93.6,91.09 93.6,91.08 93.04,90.53 90.82,90.53 89.87,89.59 ; 93.87,91.16 v1(93.87,91.16)
  BOTTOM w0.508: 89.87,89.59 89.58,89.29 R9604.1 88.76,88.93 R705.2
PWR_LEVEL: length 11.1
  TOP w0.127: v2(174.86,134.78) 175.11,134.52 175.11,133.78 174.43,133.09 173.88,133.09 173.21,132.42 173.21,131.63 173.87,130.97 173.87,129.5 v1(173.93,129.45) 173.93,128.82 R7605.2 173.58,127.86 D7601.A 173.13,126.14 D7602.A
  BOTTOM w0.127: v2(174.86,134.78) GPU1.D7
PWR_VCC_ALERT#: length 3.5
  TOP w0.14: PR4618.1 PR4601.2 121.19,140.56 120.38,141.38 v1(120.29,141.38) PU4601.19
PWR_VCC_BOOT: length 2.7
  TOP w0.305: v1(116.66,138.27) 116.78,138.39 PU4601.13
  TOP w0.508: PR4701.1 116.85,137.81 116.66,138 116.66,138.27 v1(116.66,138.27)
PWR_VCC_BOOT_RC: length 2.6
  TOP w0.762: PR4701.2 PC4706.1 v1(118.12,134.37)
PWR_VCC_COMP: length 4.1
  TOP w0.254: PU4601.6 115.78,143.39 v2(115.17,144)
  BOTTOM w0.254: PR4613.1 PC4610.1 115.58,143.56 115.17,143.97 v2(115.17,144) 115.21,144.03 115.21,144.19 v1(115.7,144.68)
PWR_VCC_COMP_RC: length 2.8
  BOTTOM w0.254: v1(113.42,140.9) 113.58,141.06 PC4611.1 114.69,141.09 PR4613.2
PWR_VCC_EN: length 4.1
  TOP w0.127: PU4601.1 118.28,143.36 119.03,144.12 v1(119.64,144.12) 119.94,144.42 120.59,144.42 120.76,144.25 PR4621.1
PWR_VCC_FB: length 5.1
  TOP w0.14: v1(112.53,145.5) 112.55,145.52 112.86,145.52 113.44,144.94 113.44,144.89 113.56,144.77 PR4606.1 113.56,143.56 PR4603.1 114.04,143.55 114.97,142.62 PU4601.7
PWR_VCC_FB_RC: length 1.9
  TOP w0.254: v1(110.79,144.47) PC4601.1 111.93,144.38 PR4606.2
PWR_VCC_IMON: length 4.1
  TOP w0.254: PU4601.3 117.28,143.43 117.61,143.77 v2(117.61,144.1)
  BOTTOM w0.254: v1(117.08,144.78) 117.61,144.25 v2(117.61,144.1) 117.49,143.98 PR4610.2 PC4609.2
PWR_VCC_ISUMN: length 3.6
  TOP w0.254: PU4601.9 114.43,140.88 113.84,140.29 v1(113.49,140.29) 113.37,140.16 PR4705.2 112.56,140.17 PR4706.2
PWR_VCC_ISUMP: length 7.4
  TOP w0.254: PU4601.10 114.56,140.38 113.57,139.39 PR4707.1 112.77,139.39 PC4708.1 112.67,138.48 PC4707.1 112.69,137.6 PR4708.1 112.7,136.68 PR4702.2 PR4703.1 112.69,134.76 v1(112.8,134.65)
PWR_VCC_LG: length 15.9
  TOP w0.305: 118.91,139.44 118.77,139.58 PU4601.16
  TOP w0.508: v3(119.7,138.14) 119.7,138.65 118.91,139.44
  L4 w1.016: v3(119.7,138.14) 120.99,136.85 120.99,125.86 v3(120.89,125.76)
  BOTTOM w0.711: v3(119.7,138.14) v1(119.7,138.8)
PWR_VCC_NTC: length 3
  TOP w0.254: PU4601.5 116.28,143.57 v1(115.73,144.11) 115.73,144.73 115.55,144.91 PR4615.2
PWR_VCC_NTC_R: length 27.1
  TOP w0.254: PR4615.1 PR4617.1 114.2,146.27 113.75,145.81 v1(113.75,145.38) 113.75,145.01 114.24,144.52 v2(114.24,144.27)
  BOTTOM w0.254: v2(114.24,144.27) 114.24,144.71 114.89,145.37 117.66,145.37 119.32,143.71 119.32,140.41 124.44,135.28 PR4622.1
PWR_VCC_PHASE: length 19.5
  TOP w0.305: v3(118.55,137.88) 118.55,138.25 117.78,139.03 PU4601.15
  TOP w0.508: v3(118.55,137.88) 118.12,137.44 PC4706.2
  L4 w1.016: v3(114.66,124.04) 114.8,124.04 118.24,127.48 118.24,137.54 118.55,137.85 118.55,137.91 v3(118.55,137.88)
  BOTTOM w0.711: v1(118.22,137.19) 118.55,137.53 v3(118.55,137.88)
PWR_VCC_POK: length 2.5
  TOP w0.127: PR4628.1 118.22,144.57 118.26,144.52 v1(118.26,143.92) 118.26,143.79 117.78,143.31 PU4601.2
PWR_VCC_PRGM1: length 3.8
  TOP w0.254: PU4601.17 119.25,140.38 120.46,139.17 v1(120.46,138.63) 120.46,138.4 120.97,137.89 PR4614.2
PWR_VCC_PRGM2: length 4.7
  TOP w0.254: PR4607.2 114.13,136.4 113.73,136.81 v1(113.73,137.24) 113.73,137.57 114.64,138.49 114.99,138.49 115.78,139.28 PU4601.11
PWR_VCC_SCLK: length 3.7
  TOP w0.14: PR4616.1 PR4620.1 120.7,143.23 v1(120.38,142.9) 119.35,141.88 PU4601.20
PWR_VCC_SDA: length 3.8
  TOP w0.14: PR4619.1 PR4630.1 121.23,139.8 120.72,139.8 v1(120.47,140.05) 120.47,140.32 119.91,140.88 PU4601.18
PWR_VCC_UG: length 15.8
  TOP w0.305: v3(117.48,138.39) 117.28,138.6 PU4601.14
  L4 w1.016: v3(117.48,138.39) 117.1,138.01 117.1,127.96 114.9,125.76 v3(114.79,125.76)
  BOTTOM w0.711: v3(117.48,138.39) 117.07,138.39 v1(116.82,138.64)
PWR_VCC_VRHOT#: length 2.5
  TOP w0.127: PR4624.1 117.33,144.58 117,144.25 v1(117,143.9) 116.78,143.67 PU4601.4
PWR_VGA_CORE_BOOT1: length 3
  BOTTOM w0.203: 161.09,105.64 160.78,105.95 PU8201.1
  BOTTOM w0.508: PR8210.1 160.74,104.4 161.12,104.78 v1(161.12,104.93) 161.12,105.61 161.09,105.64
PWR_VGA_CORE_BOOT1_1: length 4.5
  BOTTOM w0.508: PR8210.2 162.06,104.58 162.16,104.68 162.16,104.68 162.36,104.87 PC8211.1 164.5,104.87 v1(165.27,105.65)
PWR_VGA_CORE_BOOT2: length 3
  BOTTOM w0.203: PU8201.15 160.78,110.15 161.1,110.48
  BOTTOM w0.508: PR8211.1 161.02,111.92 161.49,111.44 v1(161.49,110.97) 161.49,110.87 161.1,110.48
PWR_VGA_CORE_BOOT2_1: length 2.7
  BOTTOM w0.508: PR8211.2 PC8216.1 162.3,114.72 v1(162.23,114.8)
PWR_VGA_CORE_EN: length 7.6
  BOTTOM w0.203: PU8201.3 159.98,105.87 159.73,105.62 159.73,105.47
  BOTTOM w0.254: 159.73,105.47 159.73,104.9 160,104.63 160,102.9 160.27,102.63 PC8225.2 160.71,102.14 160.59,102.01 PR8256.2 PR8260.2 162.48,101.69 v1(162.54,101.63)
PWR_VGA_CORE_LGATE1: length 17.1
  TOP w0.508: v3(162.62,107.07) 163.38,107.07 v1(163.97,106.47)
  L4 w1.016: v3(162.62,107.07) 164.09,105.6 167.51,105.6 v3(168.87,104.24) v3(168.87,98.65)
  BOTTOM w0.203: v3(162.62,107.07) 162.03,107.65 PU8201.19
  BOTTOM w0.508: PR8224.1 162.71,107.16 v3(162.62,107.07)
PWR_VGA_CORE_LGATE2: length 14.4
  TOP w0.508: v3(162.77,108.81) v1(163.68,108.81)
  L4 w1.016: v3(168.87,114.53) v3(168.87,108.94) 168.41,109.4 163.36,109.4 v3(162.77,108.81)
  BOTTOM w0.203: v3(162.77,108.81) 162.41,108.45 PU8201.17
PWR_VGA_CORE_PHASE1: length 22.9
  L4 w1.016: v3(175.6,98.14) 173.55,98.14 172.79,97.38 168.34,97.38 168.31,97.41 167.18,97.41 161.75,102.84 161.75,105.66 v3(161.84,105.74)
  BOTTOM w0.203: PU8201.20 161.53,106.13 161.84,105.82 v3(161.84,105.74)
  BOTTOM w0.508: v3(161.84,105.74) 162.29,106.2 PC8211.2
  vias: v1(177.81,105.77) v3(175.71,103.64) v3(175.71,102.5) v3(175.71,101.35) v3(175.71,100.21) v3(177.02,97.41) v3(177.02,96.01) v3(177.02,94.49) v3(177.12,103.22) v3(177.15,102.11) v3(178.39,103.22) v3(178.54,97.66) v3(178.67,96.26) v3(178.67,94.74) v3(178.8,102.11)
PWR_VGA_CORE_PHASE2: length 22.2
  L4 w1.016: v3(175.72,114.91) 173.42,114.91 171.98,116.34 166.33,116.34 162.57,112.58 162.57,110.64 v3(161.63,109.7)
  BOTTOM w0.203: PU8201.16 161.53,109.6 v3(161.63,109.7)
  BOTTOM w0.508: PC8216.2 162.3,111.26 162.29,111.25 162.29,110.37 v3(161.63,109.7)
  vias: v1(177.76,118.61) v3(175.75,113.79) v3(175.75,112.14) v3(175.75,110.49) v3(176.99,118.46) v3(177.02,116.96) v3(177.02,115.44) v3(177.02,111.12) v3(177.65,109.98) v3(177.96,117.61) v3(178.21,115.98) v3(178.54,111.12)
PWR_VGA_CORE_PSI: length 5.4
  BOTTOM w0.203: 159.27,105.65 159.58,105.96 PU8201.4
  BOTTOM w0.254: PR8257.2 PR8258.2 PR8259.1 159.37,103.39 159.3,103.45 PC8226.2 159.3,104.32 159.27,104.36 v1(159.27,104.95) 159.27,105.65
PWR_VGA_CORE_REFADJ: length 4.1
  BOTTOM w0.203: 158.43,106.76 PU8201.6
  BOTTOM w0.254: PR8222.1 156.21,105.9 156.45,105.67 v1(156.73,105.67) 157.69,105.67 158.43,106.4 158.43,106.76
PWR_VGA_CORE_REFIN: length 4.8
  TOP w0.254: PR8209.1 157.84,107.57 PC8204.1 157.86,107.05 v2(157.6,106.79) 157.44,106.63 157.44,106.3 v1(157.33,106.2)
  BOTTOM w0.203: 157.6,107.52 157.73,107.65 PU8201.7
  BOTTOM w0.254: PR8208.1 157.5,106.69 v2(157.6,106.79) 157.6,107.52
PWR_VGA_CORE_RGND: length 11.6
  TOP w0.14: v1(156.22,111.36) 156.89,110.7 PC8201.1 156.89,109.9 157.19,109.59 PC8223.2 157.19,108.64 PR8209.2 157.02,108.44 PC8204.2 157.86,109.49 v2(157.94,109.57)
  BOTTOM w0.14: PR8220.1 158.12,113.91 158.12,113.5 PR8213.1 157.88,113.26 PC8217.1 157.88,111.63 PC8219.2 158.04,111.45 158.17,111.31 158.17,110.53 158.32,110.38 158.32,109.95 v2(157.94,109.57) 157.79,109.42 157.79,109.23 158.17,108.85 PU8201.10
PWR_VGA_CORE_SS: length 3.6
  TOP w0.254: v2(158.68,109.6) 158.65,109.63 158.65,109.87 158.35,110.16 v1(158.35,110.18) 158.33,110.18 158.06,110.45 v2(157.57,110.45)
  BOTTOM w0.203: PU8201.11 v2(158.68,109.6)
  BOTTOM w0.254: PC8205.1 157.15,110.63 157.33,110.45 v2(157.57,110.45)
PWR_VGA_CORE_TON: length 2.7
  BOTTOM w0.203: PU8201.9 157.12,108.45 v1(156.95,108.61)
  BOTTOM w0.254: v1(156.95,108.61) 156.95,109.21 156.99,109.25 PR8201.2
PWR_VGA_CORE_TON_1: length 6.5
  BOTTOM w0.254: PC8202.2 156.17,113.65 156.22,113.7 PR8202.2 155.63,114.09 155.06,113.52 v1(155.06,110.94) 155.06,110.64 155.91,109.78 PR8201.1
PWR_VGA_CORE_UGATE1: length 26.9
  TOP w0.356: v3(160.36,105.38) v1(160.36,104.63)
  L4 w1.016: v3(175.72,93.06) v3(175.72,96.87) 174.07,96.87 173.31,96.11 167.81,96.11 167.79,96.14 166.66,96.14 160.36,102.44 v3(160.36,105.38)
  BOTTOM w0.203: v3(160.36,105.38) 160.38,105.4 PU8201.2
PWR_VGA_CORE_UGATE2: length 25.3
  TOP w0.356: v1(160.63,110.46) 160.63,110.46 160.63,110.47 160.64,110.47 v3(160.64,111.12)
  L4 w1.016: v3(175.72,119.99) v3(175.72,116.18) 173.95,116.18 172.51,117.61 165.81,117.61 161.3,113.11 161.3,112.06 161.3,111.78 v3(160.64,111.12)
  BOTTOM w0.203: PU8201.14 160.38,110.86 v3(160.64,111.12)
PWR_VGA_CORE_VID: length 4.2
  BOTTOM w0.203: PU8201.5 159.18,106.07 158.58,105.48
  BOTTOM w0.254: PC8203.2 156.7,104.26 156.87,104.43 PR8207.2 157.49,104.68 v1(157.83,105.02) 158.12,105.31 158.42,105.31 158.58,105.48
PWR_VGA_CORE_VREF: length 6.1
  TOP w0.254: v2(155.58,109.04) 155.63,109.1 155.63,109.91 PC8201.2
  BOTTOM w0.203: PU8201.8 157.42,108.05
  BOTTOM w0.254: v1(154.65,109.79) 155.34,109.1 155.53,109.1 v2(155.58,109.04) 155.69,109.04 156,108.73 PR8206.1 156.39,108.36 156.64,108.11 157.42,108.11 157.42,108.05
PWR_VGA_CORE_VSNS: length 5.5
  BOTTOM w0.14: 158.94,110.56 159.24,110.56 159.58,110.23 PU8201.12 ; 158.94,110.56 158.69,110.56 158.57,110.69 158.57,111.42 PC8219.1 158.77,111.63 PC8222.1 PR8212.2 158.73,113.29 158.73,113.98 PR8221.1 ; 158.94,110.56 v1(158.94,110.69)
PWR_VGA_SNUB1:
  vias: v1(171.86,105.82)
PWR_VGA_SNUB2:
  vias: v1(171.86,107.6)
Q402_1: length 2.8
  TOP w0.102: v1(59.82,163.09) 59.41,163.09 59.2,163.31 RN3001.4 58.65,164.83 Q3003.B
Q6204_G: length 20.2
  TOP w0.254: v2(55.43,73.36) 55.43,74.07 55.09,74.41 Q6204.5 ; Q6204.2 52.06,74.41 v2(51.71,74.76)
  L3 w0.254: v2(55.43,73.36) 54.03,74.76 v2(51.71,74.76) 50.63,75.84 50.63,79.89 50.17,80.34 45.42,80.34 44.92,79.84 v2(44.9,79.84)
  BOTTOM w0.254: v2(51.71,74.76) 51.16,74.76 v1(51.12,74.72) ; R6216.2 44.89,79.85 v2(44.9,79.84)
Q6205_Q: length 4
  TOP w0.381: R6211.2 47.32,69.71 Q6205.D 45.15,68.31 45.14,68.3 v1(45.14,68.15)
Q7601_G: length 9.3
  TOP w0.102: Q7601.5 197.8,138.74 197.49,138.43 197.49,137.64 198.32,136.81 199.8,136.81 R7624.1 199.82,137.42 199.62,137.62 199.62,138.61 199.74,138.74 Q7601.2 200.9,138.74 201.86,137.78 v1(201.86,137.58)
REFIN_VREF: length 6.4
  TOP w0.254: v1(155.22,108.2) 155.79,107.62 v2(156.1,107.62) 156.28,107.8 PC8223.1
  BOTTOM w0.254: PR8208.2 156.42,107.58 156.37,107.62 v2(156.1,107.62) ; PR8222.2 155.97,106.79 156.1,106.92 v2(156.1,107.62) ; v2(156.1,107.62) 156.09,107.63 155.69,107.63 155.11,108.2 PR8206.2
REGOUT:
  vias: v1(51.03,172.26)
RING2: length 3.5
  TOP w0.356: RN2901.3 182.05,22.4 v2(182.46,21.99)
  TOP w0.508: v1(183.6,20.68) R2906.2 183.01,22.13 182.88,21.99 v2(182.46,21.99)
RING2_R:
  vias: v1(186.65,22.17)
ROM_CS#: length 14.9
  TOP w0.127: v1(180.85,128.75) 180.13,129.47 R7626.1 180.13,130.6 180.08,130.65 180.08,131.08 180.39,131.38 180.39,132 179.28,133.1 v2(179.06,133.1)
  L4 w0.127: v2(174.05,138.13) 173.6,137.68 173.6,137.18 173.6,137.18 173.6,137.05 173.78,136.87 174.25,136.87 174.44,136.68 175.39,136.68 176.31,135.76 176.31,134.84 176.74,134.42 177.14,134.42 178.04,133.52 178.44,133.52 178.86,133.1 v2(179.06,133.1)
  BOTTOM w0.127: v2(174.05,138.13) GPU1.D12
ROM_SCLK: length 19.5
  TOP w0.127: R7614.1 R7608.2 187.88,130.68 v2(187.8,130.75)
  BOTTOM w0.127: GPU1.C12 175.43,138.53 175.83,138.13 176.35,138.13 176.8,137.68 177.67,137.68 180.51,134.84 180.51,132.92 180.94,132.49 180.94,131.62 v1(181.85,130.71) 182.66,130.71 183.32,131.37 187.19,131.37 v2(187.8,130.75)
ROM_SI: length 25.8
  TOP w0.127: R7638.2 R7639.2 R7640.2 R7616.2 R7618.1 190.08,130.01 v2(189.42,130.67)
  BOTTOM w0.127: GPU1.B12 176.12,138.46 176.38,138.46 176.91,137.93 177.78,137.93 180.8,134.91 180.8,133.16 182.36,131.6 188.5,131.6 v2(189.42,130.67) 189.47,130.63 R7655.1 R7642.1 190.85,129.89 190.89,129.93 v1(191.35,129.93) 191.55,129.72 R7619.2
ROM_SO: length 22.9
  BOTTOM w0.127: R7620.1 193.19,128.19 R7611.2 191.81,129.57 191.81,130.15 191.22,130.73 190.31,130.73 v1(189.9,131.14) 189.22,131.82 182.46,131.82 181.03,133.25 181.03,135.01 177.85,138.19 177.77,138.19 177.42,138.53 GPU1.A12
RREF: length 3.6
  BOTTOM w0.305: U3201.1 13.94,14.37 v1(14.28,14.03) 14,13.75 R3203.1
RRX: length 3.5
  TOP w0.102: U5502.28 v2(31.89,63.58) 33.19,63.58 v1(33.25,63.63)
  BOTTOM w0.102: R5505.1 31.7,64.32 31.89,64.13 31.89,63.59 v2(31.89,63.58)
RSET: length 3.5
  TOP w0.203: LOM30.31 47.93,171.62 47.66,171.89
  TOP w0.305: 47.66,171.89 46.92,171.89 v1(46.39,172.42) 46.15,172.67 45.87,172.67 45.66,172.88 R3032.2
RSMRST#_KBC: length 85.6
  TOP w0.127: KBC24.15 190.42,74.39 190.15,74.66 190.15,74.73 189.21,75.67 v2(189.21,75.93)
  L3 w0.127: v2(189.21,75.93) 189.21,75.62 189.03,75.44 189.03,72.15 189.57,71.61 189.57,70.03 188.6,69.07 188.6,66.15 189.34,65.41 189.34,60.8 188.96,60.42 188.41,60.42 187.01,59.02 187.01,56.09 185.22,54.3 175.49,54.3 174.23,53.04 174.23,51.28 173.34,50.38 171.68,50.38 170.23,48.93 164.96,48.93 161.4,45.37 161.4,44.47 v2(160.85,43.91)
  BOTTOM w0.127: R1702.2 141.2,52.37 149.71,43.86 v1(150.45,43.86) 153.95,43.86 154.66,43.16 158.75,43.16 159.95,44.36 160.4,44.36 v2(160.85,43.91)
RSVDA51: length 2
  TOP w0.102: v2(106.92,96.16) TP606.1
  BOTTOM w0.102: CPU1.A51 106.41,95.26 106.41,95.65 v2(106.92,96.16)
RSVDAU63: length 2.9
  TOP w0.102: TP602.1 97.82,72.55 v2(97.16,73.21)
  BOTTOM w0.102: v2(97.16,73.21) 97.33,73.37 97.33,73.5 98.24,74.41 CPU1.AU63
RSVDAV63: length 4.5
  BOTTOM w0.102: TP601.1 95.68,72.35 97.23,72.35 97.84,72.95 97.84,73.37 98.22,73.75 CPU1.AV63
RSVDB51: length 2
  TOP w0.102: v2(106.92,95.53) 106.92,95.53 TP607.1
  BOTTOM w0.102: v2(106.92,95.53) 106.76,95.37 106.76,94.97 CPU1.B51
RSVDC62: length 5.5
  TOP w0.102: v2(97.57,95.39) 98.03,95.84 98.03,96.88 TP604.1
  BOTTOM w0.102: CPU1.C62 99.01,93.7 98.75,93.44 98.25,93.44 97.98,93.71 97.6,93.71 97.17,94.14 97.17,94.98 v2(97.57,95.39)
RSVDC63: length 2
  TOP w0.102: v2(97.57,94.32) 98.1,94.85 TP603.1
  BOTTOM w0.102: v2(97.57,94.32) 97.87,94.03 97.98,94.03 98.24,93.77 CPU1.C63
RSVDL60: length 2.7
  TOP w0.102: v2(100.12,89.03) 99.67,88.58 98.91,88.58 98.47,89.02 TP608.1
  BOTTOM w0.102: CPU1.L60 100.44,88.72 v2(100.12,89.03)
RSVDN59: length 1.1
  TOP w0.102: TP704.1 101.63,88.33 v2(101.52,88.22)
  BOTTOM w0.102: v2(101.52,88.22) 101.24,87.94 CPU1.N59
RSVDN61: length 1.3
  TOP w0.102: TP705.1 100.32,87.33 v2(100.13,87.52)
  BOTTOM w0.102: v2(100.13,87.52) 100.13,87.72 99.9,87.94 CPU1.N61
RSVDP60: length 3
  TOP w0.102: TP702.1 102.11,86.53 v2(102.28,86.36)
  BOTTOM w0.102: v2(102.28,86.36) 102.22,86.36 101.83,86.75 100.89,86.75 100.53,87.12 CPU1.P60
RSVDP61: length 2.4
  TOP w0.102: TP703.1 100.79,86.03 v2(100.79,86.03)
  BOTTOM w0.102: CPU1.P61 100.12,86.78 100.57,86.78 100.75,86.6 100.75,86.07 v2(100.79,86.03)
RT8812_PVCC: length 5.4
  BOTTOM w0.203: PC8207.1 163.19,108.25 162.99,108.05 PU8201.18
  BOTTOM w0.508: PC8207.1 163.86,108.25 PR8223.2 163.06,110.36 v1(163.06,110.93)
RTC_AUX_S5: length 269.7
  TOP w0.254: 131.12,75.2 131.12,76.57 131.55,77 131.55,79.45 131.12,79.89 131.08,79.89 v2(131.05,79.92)
  TOP w0.508: R2428.2 185.7,62.94 185.3,62.54 184.16,62.54 v2(183.64,63.06) ; 142.43,58.98 150.03,58.98 152.18,56.83 155.62,56.83 157.77,58.98 162.9,58.98 165.41,61.5 170.2,61.5 170.27,61.57 174.35,61.57 175.34,60.58 177.05,60.58 178.74,58.89 v2(184.5,58.89) ; v2(30.54,8.79) 30.03,9.3 C2503.1 29.81,9.51 29.81,11.05 D2501.3 ; 131.12,75.2 C1121.1
  L3 w0.508: v2(30.54,8.79) 32.23,7.1 37.86,7.1 39.37,5.6 41.82,5.6 41.96,5.75 47.94,5.75 50.43,3.26 163.5,3.26 172.67,12.42 172.67,22.55 182.02,31.91 v2(184.06,31.91)
  L4 w0.508: v2(183.64,63.06) 183.64,59.74 v2(184.5,58.89) 184.69,58.69 184.69,55.68 185.12,55.25 185.12,48.92 184.77,48.57 184.77,40.57 186.82,38.52 186.82,37.53 188.19,36.16 188.19,34.15 186.69,32.65 184.93,32.65 184.2,31.93 184.06,31.93 v2(184.06,31.91)
  BOTTOM w0.305: v2(131.05,79.92) 131.43,80.29 CPU1.AG10
  vias: v1(140.41,60.82) v2(140.47,59.57)
RTC_DET#: length 267.7
  TOP w0.102: v2(183.47,35.57) 183.47,35.74 v1(183.17,36.04) ; Q2505.D v2(34.27,11.59)
  L3 w0.102: v2(134.66,82.56) 134.95,82.85 138.16,82.85 138.75,83.44 139.97,83.44 140.82,84.29 145.67,84.29 145.85,84.1 148.56,84.1 151.7,87.24 152.39,87.24 154.95,84.69 v2(155.18,84.69) ; v2(34.27,11.59) 36.87,11.59 37.78,10.67 45.99,10.67 51.48,5.19 71.15,5.19 71.47,5.52 76.65,5.52 76.95,5.21 162.55,5.21 165.36,8.02 165.36,15.26 166.66,16.55 166.66,19.81 178.22,31.38 178.22,35.82 179.27,36.87 181.42,36.87 182.68,35.61 183.43,35.61 v2(183.47,35.57)
  L4 w0.102: v2(155.18,84.69) 158.33,81.54 159.27,81.54 160.08,80.73 160.08,80.72 160.19,80.61 160.19,78.52 160.69,78.03 162.23,78.03 162.7,78.49 164.14,78.49 169.01,73.62 169.38,73.62 172.63,70.37 172.63,67.26 171.94,66.57 171.94,65.46 173.03,64.37 173.03,57.87 172.5,57.33 172.5,56.46 174.73,54.23 174.73,52.21 175.48,51.46 175.48,49.7 180.22,44.97 180.22,42.98 180.59,42.61 180.59,38.41 183.43,35.57 v2(183.47,35.57)
  BOTTOM w0.102: v2(155.18,84.69) 153.96,83.47 RN2012.5 ; v2(134.66,82.56) 134.48,82.38 CPU1.AD5
RTC_PWR: length 7.5
  TOP w0.508: Q2505.G 33.32,13.18 33.31,13.18 32.87,13.62 R2504.1 R2502.1 ; Q2505.G 34.31,12.57 v1(35.67,13.93) ; Q2505.G 32.3,12.57 32.21,12.66 D2501.2
RTC_RST#: length 26.1
  TOP w0.127: v2(146.95,63.43) 145.73,62.21 145.73,61.61 Q1901.D 144.74,61.66 144.74,62.31 143.91,63.14 EC1903.1 143.26,63.14 143.16,63.04 RN1901.3 142.69,63.47 143.26,64.04 C1901.1 v1(143.26,65.63) 143.26,65.95 138.95,70.25 137.32,70.25 133.48,74.09 v2(133.36,74.09)
  BOTTOM w0.127: CPU1.AU7 133.04,74.41 v2(133.36,74.09) ; G1901.2 146.59,61.7 146.9,62.01 146.9,63.38 v2(146.95,63.43)
RTC_X1: length 20.3
  BOTTOM w0.089: CPU1.AW5 134.86,72.74 134.86,72.3 135.41,71.75
  BOTTOM w0.14: 135.41,71.75 136.47,70.69 137.33,70.69 138.49,69.52 v1(138.69,69.52) 139.7,69.52 142.07,67.16 146.94,67.16 147.12,66.98 147.53,66.98 148.33,67.78 R1915.1 148.81,67.78 149.38,67.22 C1903.2 149.97,67.22 150.5,66.69 X1901.1
RTC_X2: length 20.1
  BOTTOM w0.14: CPU1.AY5 134.56,72.43 134.56,72.28 135.41,71.42 135.41,71.12 137.01,69.52 v1(137.45,69.52) 137.83,69.52 138.18,69.17 139.19,69.17 141.78,66.58 146.69,66.58 146.87,66.4 147.78,66.4 148.28,66.9 R1915.2 148.86,66.9 149.52,66.24 C1904.2 150.05,66.24 150.38,65.91 150.98,65.91 151.06,65.83 X1901.4
RTCRST_ON: length 66
  TOP w0.127: KBC24.120 188,68.32 188,68.33 v2(188,68.38) ; R1902.1 144.63,59.96 144.83,60.16 Q1901.G 148.91,60.16 149.47,60.72 149.47,63.24 150.06,63.83 150.06,64.2 150.36,64.51 150.91,64.51 151.33,64.93 157.61,64.93 158.99,63.56 158.99,60.41 159.78,59.61 162.66,59.61 164.99,61.94 170.01,61.94 170.09,62.02 174.54,62.02 175.52,61.04 177.22,61.04 178.92,59.34 187.09,59.34 v1(187.1,59.34) 188.1,59.34 v2(188.39,59.05)
  L4 w0.127: v2(188,68.38) 188,67.99 188.52,67.47 188.52,64.35 189.2,63.67 189.2,62.98 188.55,62.34 188.55,61.93 188.32,61.7 188.32,59.12 v2(188.39,59.05)
S5_ENABLE: length 45.5
  TOP w0.127: R3603.2 162.49,65.28 162.16,65.61 162.16,68.36 162.54,68.74 163.25,68.74 163.66,69.14 163.66,69.15 v1(164.43,69.92) 164.6,69.75 165.41,69.75 165.88,70.22 165.88,70.5 165.88,70.5 165.88,71.26 167.37,72.75 167.85,72.75 168.57,73.48 Q2403.D 169.72,74.58 170.43,75.29 v2(171.64,75.29) ; R2436.2 194.66,75.07 193.58,73.99 KBC24.14 190.57,73.99 190.32,73.74 190.32,73.11 189.98,72.77 189.41,72.77 187.21,74.97 187.21,75.39 v2(186.42,76.18)
  L3 w0.127: v2(186.42,76.18) 186.36,76.18 186.32,76.23 181.28,76.23 179.81,77.7 174.03,77.7 171.64,75.31 v2(171.64,75.29)
SA0_DIMA: length 8.2
  TOP w0.102: v2(123.6,40.92) 122.4,40.92 v1(121.57,40.09) 120.56,39.08 R1201.1
  BOTTOM w0.102: v2(123.6,40.92) 123.02,40.92 121.75,39.66 121.75,38.27 DM1.197
SA0_DIMB: length 5.6
  TOP w0.102: R1301.1 154.92,26.87 v2(154.5,27.28) 154.5,27.57 v1(155.07,28.14)
  BOTTOM w0.102: DM2.197 156.35,25.86 154.92,27.28 v2(154.5,27.28)
SA1_DIMA: length 5.7
  TOP w0.102: R1202.1 121.44,39.47 122.19,40.21 v2(122.92,40.21) 123.61,40.21 v1(123.78,40.05)
  BOTTOM w0.102: DM1.201 123.05,40.08 v2(122.92,40.21)
SA1_DIMB: length 4.2
  TOP w0.102: v1(158.84,26.75) 158.61,26.98 v2(157.63,26.98) 157.53,26.88 R1302.2
  BOTTOM w0.102: DM2.201 157.55,26.91 v2(157.63,26.98)
SATA3_PRX_HDDTX_N0: length 90.7
  TOP w0.127: v2(180.07,34.1) 179.78,34.1 v1(179.34,34.54)
  L4 w0.114: v2(180.07,34.1) 179.83,34.35 179.1,34.35 177.91,35.53 177.91,44.1 168.76,53.26 165.85,53.26 165.13,53.98 164.4,53.98 162.17,56.22 162.17,65.29 161.83,65.62 161.83,68.11 161.17,68.77 161.17,69.54 159.95,70.76 159.08,70.76 157.04,72.79 154.09,72.79 151.98,74.9 148.15,74.9 146.57,76.48 145.96,76.48 145.54,76.89 144.69,76.89 143.8,77.78 142.36,77.78 141.66,78.49 141.66,82.95 140.42,84.19 140.42,85.84 139.6,86.66 139.6,89.63 139.13,90.1 137.12,90.1 136.13,91.09 135.26,91.09 134.58,90.4 134.28,90.4 v2(134.03,90.15)
  BOTTOM w0.127: C5616.1 181.04,34.48 180.45,34.48 v2(180.07,34.1) ; CPU1.J5 134.32,89.86 v2(134.03,90.15)
SATA3_PRX_HDDTX_P0: length 90.6
  TOP w0.127: v1(180.8,35.28) 180.41,34.89 v2(180.11,34.89)
  L4 w0.114: v2(180.11,34.89) 179.79,34.58 179.19,34.58 178.14,35.63 178.14,44.2 168.85,53.49 165.94,53.49 165.22,54.21 164.5,54.21 162.39,56.31 162.39,65.38 162.06,65.72 162.06,68.2 161.4,68.87 161.4,69.64 160.04,70.99 159.17,70.99 157.14,73.02 154.18,73.02 152.08,75.13 148.24,75.13 146.67,76.71 146.05,76.71 145.64,77.12 144.79,77.12 143.89,78.01 142.45,78.01 141.89,78.58 141.89,83.04 140.65,84.28 140.65,85.93 139.83,86.75 139.83,89.72 139.22,90.33 137.22,90.33 136.23,91.32 135.17,91.32 134.48,90.63 134.24,90.63 134.21,90.66 134.21,90.66 v2(134.04,90.83)
  BOTTOM w0.127: v2(180.11,34.89) 180.09,34.89 180.26,34.72 181.14,34.72 181.38,34.96 C5615.1 ; v2(134.04,90.83) 134.36,90.51 CPU1.H5
SATA3_PTX_HDDRX_N0: length 104.4
  TOP w0.127: v2(180.11,33.37) 180.31,33.37 v1(180.78,33.84)
  L4 w0.114: v2(180.11,33.37) 180.46,33.02 180.84,33.02 181.13,33.32 181.13,34.58 178.67,37.04 178.67,44.43 169.07,54.03 166.18,54.03 162.94,57.27 162.94,65.57 162.59,65.92 162.59,68.44 161.93,69.1 161.93,69.86 160.26,71.53 159.4,71.53 157.39,73.54 154.4,73.54 152.04,75.91 150.91,75.91 149.79,77.02 148.26,77.02 146.1,79.18 144.92,79.18 143.48,80.62 143.48,83.28 142.25,84.51 142.25,87.38 141.21,88.43 141.21,90.22 139.17,92.26 137.5,92.26 136.7,93.06 136.7,96.16 135.98,96.88 134.76,96.88 134.61,96.73 129.01,96.73 v2(128.81,96.52)
  BOTTOM w0.127: v2(180.11,33.37) 180.11,33.13 180.2,33.04 180.8,33.04 181.27,32.57 181.84,32.57 182.04,32.77 C5603.2 ; v2(128.81,96.52) 128.52,96.52 128.39,96.4 128.39,95.39 128.46,95.32 128.46,94.8 128.1,94.44 CPU1.B15
SATA3_PTX_HDDRX_P0: length 104.3
  TOP w0.127: v1(180.94,32.62) 180.88,32.57 v2(180.11,32.57)
  L4 w0.114: v2(180.11,32.57) 180.34,32.8 180.93,32.8 181.36,33.23 181.36,34.68 178.9,37.14 178.9,44.53 169.17,54.26 166.28,54.26 163.17,57.36 163.17,65.67 162.82,66.02 162.82,68.53 162.16,69.19 162.16,69.96 160.36,71.76 159.49,71.76 157.48,73.77 154.5,73.77 152.13,76.13 151,76.13 149.89,77.25 148.35,77.25 146.19,79.4 145.02,79.4 143.7,80.72 143.7,83.38 142.48,84.6 142.48,87.48 141.44,88.52 141.44,90.31 139.26,92.49 137.59,92.49 136.93,93.15 136.93,96.26 136.08,97.11 134.67,97.11 134.51,96.96 129.01,96.96 v2(128.81,97.16)
  BOTTOM w0.127: C5602.2 181.69,32.33 181.17,32.33 180.7,32.8 180.34,32.8 v2(180.11,32.57) ; v2(128.81,97.16) 128.15,96.5 128.15,95.1 CPU1.A15
SATA_IREF: length 5.7
  BOTTOM w0.305: CPU1.A12 130.21,95.29 130.21,95.94 130.51,96.24
  BOTTOM w0.508: 130.51,96.24 131.93,97.67 v1(131.93,97.67) 131.93,97.67 132.62,98.36 R1904.1
SATA_LED: length 3.3
  TOP w0.508: Q6104.C 38.48,5.28 v1(39.11,4.66) EC6104.1 39.09,3.71 R6108.1
SATA_LED#: length 311.6
  TOP w0.102: R2405.1 176.11,62.82 176.41,62.52 177.23,62.52 179.46,60.29 185.14,60.29 186.16,61.31 187.14,61.31 188.92,59.52 189.59,59.52 v2(189.69,59.62) ; Q6105.S 41.33,11.72 45.16,7.89 Q6103.S 44.62,4.63 R6106.1 45.63,3.71 v2(46.59,4.68) ; R1905.2 143.61,92.36 142.62,91.37 142.38,91.37 v2(141.77,90.76)
  L3 w0.102: v2(46.59,4.68) 48.65,2.62 164.81,2.62 173.33,11.15 173.33,22.28 181.91,30.85 185.03,30.85 185.78,30.1 187.1,30.1 v2(187.36,30.36) ; v2(141.77,90.76) 142.15,90.38 142.61,90.38 143.02,90.78 143.72,90.78 144.42,91.48 146.22,91.48 146.57,91.83 147,91.83 147.03,91.8 148.16,91.8 148.36,91.59 148.89,91.59 150.21,92.92 153.29,92.92 153.87,92.33 156.4,92.33 157.38,93.31 158.37,93.31 163.46,88.22 169.65,88.22 170.43,87.44 176.28,87.44 177.58,86.15 179.87,86.15 181.02,84.99 182.04,84.99 185.1,81.93 185.1,80.39 v2(185.63,79.86)
  L4 w0.102: v2(185.63,79.86) 185.5,79.74 185.5,75.03 185.95,74.58 185.98,74.58 186.91,73.65 188.05,73.65 189.53,72.17 189.53,70.03 188.98,69.49 188.98,68.14 189.27,67.85 189.27,64.7 189.95,64.02 189.95,62.57 189.72,62.35 189.72,59.65 v2(189.69,59.62) 190.19,59.11 190.19,55.81 188.22,53.83 188.22,48.28 190.3,46.2 190.3,45.07 190.99,44.38 190.99,42.3 191.02,42.27 191.02,34.02 v2(187.36,30.36)
  BOTTOM w0.102: CPU1.U3 136.07,85.32 139,85.32 139.93,86.25 139.93,86.78 141.11,87.96 141.11,90.09 v1(141.24,90.22) 141.73,90.71 141.73,90.72 v2(141.77,90.76)
SATA_LED#_B: length 10.4
  TOP w0.102: Q6104.B 39.47,6.42 v1(41.31,4.57) 42.17,3.71 R6106.2 44.18,4.16 Q6103.D
SATA_LED#_R: length 226.5
  TOP w0.102: v2(42.26,5.11) 42.61,5.46 42.61,8.41 R6110.2 41.26,9.75 Q6105.G ; KBC24.95 176.27,69.19 175.39,68.31 v1(175.39,67.95) 175.61,67.95 176.46,67.1 176.46,66.73 176.2,66.47 175.63,65.89 175.63,65.37 R2405.2 176.1,64.89 175.59,64.37 175.59,63.05 176.32,62.32 177.15,62.32 179.37,60.09 185.23,60.09 186.25,61.11 187.05,61.11 187.75,60.41 187.75,60.41 188.47,59.69 188.47,59.69 189.18,58.98 v2(189.52,58.98)
  L3 w0.102: v2(42.26,5.11) 46.82,5.11 49.1,2.83 164.69,2.83 173.1,11.23 173.1,22.35 181.81,31.06 185.62,31.06 v2(185.83,30.84)
  L4 w0.102: v2(185.83,30.84) 186.04,31.04 187.35,31.04 190.79,34.49 190.79,42.19 190.79,42.19 190.79,44.27 190.1,44.96 190.1,44.96 190.08,44.99 190.08,45.17 190.1,45.19 190.1,46.12 188.02,48.2 188.02,53.92 189.59,55.49 189.59,58.9 v2(189.52,58.98)
SATA_LED_R: length 17.5
  TOP w0.508: HDLED1.1A 21.3,2.35 21.82,2.87 35.56,2.87 v1(36.28,3.6) 36.4,3.71 R6108.2
SATA_ODD_DA#: length 34
  TOP w0.127: v2(136.11,85.99) 136.36,86.24 136.63,86.24 137.36,86.98 137.36,88.01 137.31,88.06 137.31,88.51 139.92,91.12 139.92,91.78 142.3,94.16 143.34,94.16 143.63,94.45 RN2002.6
  L3 w0.127: v2(152.49,90.58) 151.65,90.58 151.42,90.35 150.75,90.35 149.38,88.98 144.17,88.98 142.86,87.67 140.52,87.67 139.96,87.11 138.86,87.11 138.74,86.99 137.6,86.99 136.61,85.99 v2(136.11,85.99)
  BOTTOM w0.127: CPU1.T3 135.81,86.29 v2(136.11,85.99) ; R5602.2 v1(152.49,89.74) v2(152.49,90.58)
SATA_ODD_DA#_C: length 5.5
  TOP w0.127: v2(155.22,87) 155.29,86.94 155.29,85.45 154.41,84.57 ODD1.17
  BOTTOM w0.127: R5602.1 154.47,87.76 v1(154.71,87.52) v2(155.22,87)
SATA_ODD_PRSNT#: length 36.3
  TOP w0.127: R5604.1 151.82,89.6 v2(152.42,89.01) 152.42,87.12 152.76,86.79 152.76,80.3 152.99,80.07 ODD1.8
  L3 w0.127: v2(142.37,92.02) 142.37,92.02 143.47,93.12 146.41,93.12 147.29,93.99 148.33,93.99 v2(148.37,93.96)
  L4 w0.127: v2(152.42,89.01) 152.14,89.01 150.69,90.45 150.69,91.87 148.61,93.96 v2(148.37,93.96)
  BOTTOM w0.127: RN1902.4 142.71,91.39 v1(142.68,91.42) 142.68,91.71 v2(142.37,92.02) 140.87,90.52 140.87,88.06 139.73,86.91 139.73,86.33 139.01,85.62 CPU1.U1
SATA_ODD_PWRGT: length 71.9
  TOP w0.127: v2(170.97,88.29) 170.96,88.28 165.95,88.28 164.41,86.74 164.41,83.79 165.26,82.95 165.26,75.5 165.25,75.49 165.25,73.32 v2(165.12,73.19)
  L3 w0.102: 140,91.25 138.74,90 137.55,90 136.81,89.26 136.81,87.61 136.1,86.91 134.47,86.91 133.98,87.4 v2(133.49,87.4)
  L3 w0.127: v2(170.97,88.29) 170.39,88.87 163.78,88.87 158.69,93.96 157.11,93.96 156.14,92.99 154.13,92.99 153.34,93.78 153.27,93.78 152.39,94.66 149.7,94.66 148.56,93.51 147.16,93.51 146.52,92.87 144.78,92.87 143.48,91.57 140.32,91.57 140,91.25
  BOTTOM w0.127: U5601.4 161.9,74.62 162.17,74.34 R5607.2 162.67,72.96 163.4,72.96 163.63,73.19 v1(164.05,73.19) v2(165.12,73.19) ; CPU1.N6 133.83,87.73 v2(133.49,87.4)
SATA_PRX_ODDTX_N1: length 31.3
  TOP w0.127: v2(149.41,75.8) 149.51,75.8 149.95,76.24 C5607.2
  L4 w0.114: v2(133.1,90.17) 133.51,90.58 133.51,91.15 134.77,92.41 136.03,92.41 136.93,91.51 138.81,91.51 140.41,89.9 140.41,87.65 141.37,86.69 141.37,84.33 142.73,82.97 142.73,80.06 144.38,78.41 145.7,78.41 148.32,75.8 v2(149.41,75.8)
  BOTTOM w0.127: v2(133.1,90.17) 132.91,90.17 CPU1.J8 ; v2(149.41,75.8) 149.99,75.8 v1(150.2,75.59)
SATA_PRX_ODDTX_P1: length 31.2
  TOP w0.127: v2(149.51,76.53) 150.05,77.07 C5608.2
  L4 w0.114: v2(149.51,76.53) 149,76.03 148.41,76.03 145.8,78.64 144.47,78.64 142.96,80.16 142.96,83.07 141.6,84.42 141.6,86.78 140.64,87.74 140.64,90 138.9,91.74 137.03,91.74 136.13,92.64 134.68,92.64 133.29,91.25 133.29,91 133.14,90.86 v2(133.07,90.86)
  BOTTOM w0.127: CPU1.H8 132.66,90.47 132.79,90.47 133.07,90.75 v2(133.07,90.86) ; v2(149.51,76.53) 149.87,76.53 v1(150.2,76.86)
SATA_PTX_ODDRX_N1: length 43.9
  TOP w0.127: v2(149.41,77.7) 148.98,77.27 148.87,77.27 148.38,76.78 148.38,75.67 ; 148.38,75.67 148.38,75.13 148.52,74.99 149.65,74.99 C5611.2 ; 148.38,75.67 v1(148.52,75.67)
  L4 w0.114: v2(149.41,77.7) 149.15,77.97 149.15,78.4 148.54,79.01 147.73,79.01 146.47,80.27 146.13,80.27 144.46,81.94 144.46,83.82 143.42,84.87 143.42,90.77 142.72,91.47 141.92,91.47 137.68,95.72 137.68,96.4 137.68,96.59 136.4,97.87 132.65,97.87 131.85,98.66 130.19,98.66 129.83,99.03 v2(129.83,99.09)
  BOTTOM w0.127: CPU1.A17 127.48,95.15 127.48,96.95 129.21,98.67 129.41,98.67 129.61,98.88 v2(129.83,99.09)
SATA_PTX_ODDRX_P1: length 44.4
  TOP w0.127: v2(148.78,77.73) 148.78,77.51 148.14,76.88 148.14,75.02 148.42,74.74 149.61,74.74 C5612.2 ; v2(129.8,98.43) v1(129.05,98.43)
  L4 w0.114: v2(129.8,98.43) 131.76,98.43 132.55,97.64 136.3,97.64 137.45,96.5 137.45,95.62 141.82,91.25 142.62,91.25 143.19,90.68 143.19,84.77 144.23,83.73 144.23,81.84 146.04,80.04 146.38,80.04 147.64,78.78 148.45,78.78 148.92,78.31 148.92,77.87 v2(148.78,77.73)
  BOTTOM w0.127: v2(129.8,98.43) 129.31,98.43 127.72,96.85 127.72,94.91 127.25,94.44 CPU1.B17
SATA_RCOMP: length 8.2
  BOTTOM w0.178: CPU1.C12 130,94.57 129.71,94.86 129.71,94.92 129.67,94.96 129.67,95.36 129.69,95.39 129.69,96.47 129.95,96.73
  BOTTOM w0.508: 129.95,96.73 131.84,98.61 v1(131.84,98.88) 131.84,100.26 R1906.1
SATA_RXN0_R: length 12
  BOTTOM w0.127: 183.42,34.46 182.52,34.46 182.27,34.2 C5616.2 ; 183.42,34.46 v1(183.42,34.32) ; 183.42,34.46 183.8,34.46 183.98,34.27 184.23,34.27 184.35,34.15 EU5602.4 EU5602.7 186.45,34.15 186.57,34.27 186.88,34.27 188.86,32.29 188.86,30.69 189.28,30.26 190.17,30.26 190.3,30.13 HDD1.8
SATA_RXN2_R: length 3.9
  TOP w0.127: C5607.1 151.57,76.74 151.65,76.74 152.73,77.81 152.73,78.42 152.88,78.57 ODD1.5
SATA_RXP0_R: length 12
  BOTTOM w0.127: 187.13,34.37 v1(187.23,34.47) ; 187.13,34.37 186.98,34.52 186.57,34.52 186.45,34.63 EU5602.6 EU5602.5 184.35,34.63 184.23,34.52 184.08,34.52 183.9,34.7 182.56,34.7 182.27,34.99 C5615.2 ; 187.13,34.37 189.1,32.39 189.1,30.79 189.38,30.5 190.17,30.5 190.3,30.63 HDD1.7
SATA_RXP2_R: length 4
  TOP w0.127: ODD1.6 153.04,79.07 152.49,78.52 152.49,77.91 152.03,77.46 ; 152.03,77.46 151.55,76.98 151.16,76.98 C5608.1 ; 152.03,77.46 v1(151.93,77.55)
SATA_TXN0_R: length 11.4
  BOTTOM w0.127: 188.09,31.88 188.19,31.78 188.19,30.36 189.56,29 190.17,29 190.3,29.13 HDD1.10 ; 188.09,31.88 v1(188.2,31.98) ; 188.09,31.88 186.98,32.99 186.57,32.99 186.45,33.11 EU5602.9 EU5602.2 184.35,33.11 184.23,32.99 183.92,32.99 183.46,32.53 183.19,32.53 182.93,32.8 C5603.1
SATA_TXN2_R: length 4.7
  TOP w0.127: 152,75.63 152.37,76 152.37,76.99 152.96,77.57 ODD1.3 ; 152,75.63 v1(151.9,75.73) ; 152,75.63 151.45,75.08 151,75.08 C5611.1
SATA_TXP0_R: length 11.4
  BOTTOM w0.127: 187.11,32.52 186.88,32.75 186.57,32.75 186.45,32.63 EU5602.10 EU5602.1 184.35,32.63 184.23,32.75 184.02,32.75 183.56,32.29 183.16,32.29 182.93,32.06 C5602.1 ; 187.11,32.52 187.95,31.68 187.95,30.26 189.46,28.76 190.17,28.76 190.3,28.63 HDD1.11 ; 187.11,32.52 v1(187,32.41)
SATA_TXP2_R: length 5.5
  TOP w0.127: ODD1.2 152.8,77.07 152.61,76.89 152.61,75.9 151.55,74.84 151.23,74.84 C5612.1 v1(150.82,73.45)
SD_CD#: length 17.9
  TOP w0.14: R3301.1 30,25.59 v2(30,25.58)
  L4 w0.127: v2(30,25.58) 30.02,25.58 30.02,22.97 29.14,22.1 20.66,22.1 v2(20.14,21.59)
  BOTTOM w0.14: U3201.13 18.13,20.52 v1(18.98,21.37) 19.2,21.59 v2(20.14,21.59)
SD_CD_R#: length 5.6
  TOP w0.14: CARD1.10 26.27,27.91 26.46,28.1 AFTP3304.1 28.19,28.1 EC3305.1 29.13,26.32 R3301.2
SD_CLK: length 25.2
  TOP w0.14: CARD1.5 27.27,19.99 AFTP3303.1 27.99,19.97 EC3201.1 29.16,20.44 v2(29.08,20.36)
  L4 w0.127: v2(22.01,18.78) 22.01,20.97 22.71,21.67 28.61,21.67 28.73,21.54 28.73,21.16 28.61,21.04 25.23,21.04 25.1,20.91 25.1,20.53 25.23,20.4 29.05,20.4 v2(29.08,20.36)
  BOTTOM w0.14: v2(22.01,18.78) 21.61,19.18 R3201.2
SD_CLK_5170: length 3.5
  BOTTOM w0.14: R3201.1 19.53,18.97 20.05,18.44 v1(20.05,17.99) 19.89,17.83 U3201.15
SD_CMD: length 24.7
  TOP w0.14: v2(31.99,17) 30.16,17 30.16,16.98 EC3304.1 29.15,16.34 28.42,15.61 28.42,15.38 28.28,15.24 28.28,15.23 27.16,14.11 AFTP3302.1 27.15,12.49 CARD1.2
  L4 w0.127: v2(19.64,15.88) 23.75,15.88 23.76,15.87 30.86,15.87 v2(31.99,17)
  BOTTOM w0.14: v2(19.64,15.88) 19.18,16.33 U3201.18
SD_D0: length 30.8
  TOP w0.14: CARD1.7 27.04,24.91 27.16,24.79 AFTP3306.1 27.28,24.17 27.52,24.17 28.21,23.49 EC3306.1 v2(29.15,22.74)
  L4 w0.127: v2(29.15,22.74) 28.38,23.51 28.38,24.53 28.25,24.66 23.88,24.66 23.76,24.53 23.76,24.15 23.88,24.02 27.61,24.02 27.74,23.89 27.74,23.51 27.61,23.39 19.58,23.39 v2(16.99,20.79)
  BOTTOM w0.14: v2(16.99,20.79) 16.79,20.59 U3201.11
SD_D1: length 30
  TOP w0.14: CARD1.8 26.74,26.61 AFTP3307.1 28.35,25 28.94,25 EC3301.1 29.08,24.21 v2(29.13,24.16)
  L4 w0.127: v2(29.13,24.16) 29.13,25.08 28.99,25.23 19.77,25.23 19.64,25.1 19.64,24.72 19.77,24.59 23.02,24.59 23.15,24.46 23.15,24.08 23.02,23.96 19.42,23.96 v2(16.28,20.82)
  BOTTOM w0.14: U3201.10 v2(16.28,20.82)
SD_D2: length 32.5
  TOP w0.14: CARD1.9 27.07,7.49 AFTP3308.1 27.8,8.04 27.8,10.13 28.38,10.7 28.38,12.89 EC3302.1 29.61,14.05 30.17,13.49 31.74,13.49 32.06,13.81 v2(32.21,13.81)
  L4 w0.127: v2(17.38,13.59) 17.67,13.88 18.45,13.88 19.19,14.62 31.11,14.62 31.92,13.81 v2(32.21,13.81)
  BOTTOM w0.14: U3201.21 16.28,13.37 16.62,13.03 v1(16.75,13.03) 17.13,13.03 17.38,13.29 v2(17.38,13.59)
SD_D3: length 30.9
  TOP w0.14: CARD1.1 26.79,9.99 AFTP3309.1 27.1,10.54 27.85,11.29 27.85,13.52 EC3303.1 29.55,15.28 29.96,15.69 32.15,15.69 v2(32.63,16.18)
  L4 w0.127: v2(32.63,16.18) 33.06,16.18 33.18,16.05 33.18,15.32 33.06,15.2 19.15,15.2 18.49,14.53 v2(16.79,14.53)
  BOTTOM w0.14: U3201.20 v2(16.79,14.53)
SD_WP: length 21.4
  TOP w0.14: CARD1.11 25.53,29.11 26.42,30 AFTP3305.1 27.72,30 EC3307.1 v2(29.13,27.91)
  L4 w0.127: v2(29.13,27.91) 27.03,25.81 19.34,25.81 17.25,23.73 v2(17.25,23.09)
  BOTTOM w0.14: v2(17.25,23.09) 16.75,22.59 R3202.1
SD_WP_5170: length 3
  BOTTOM w0.14: R3202.2 15.31,21.66 v1(15.22,21.57) 15.28,21.51 U3201.8
SDREFG: length 4.6
  BOTTOM w0.305: U3201.6 13.94,19.27 12.66,20.55 v1(12.66,21.42) 12.95,21.71 C3206.1
SLEEVE: length 3.4
  TOP w0.356: v2(182.91,24.39) 182.47,23.95 182.47,23.3 182.22,23.05 RN2901.4
  TOP w0.508: R2911.2 183.6,23.98 183.19,24.39 v2(182.91,24.39)
  vias: v1(183.35,22.48)
SLEEVE_R:
  vias: v1(186.53,23.55)
SM_DRAMRST#: length 15.5
  BOTTOM w0.089: 132.68,65.78 132.72,65.82 132.72,68.05 131.78,68.99 131.78,68.99 131.53,69.25 131.52,69.25 131.39,69.38 131.39,69.38 131.07,69.7 131.07,69.7 128.98,71.79 128.98,71.87 128.96,71.89 128.96,73.08 128.46,73.59 CPU1.AV15
  BOTTOM w0.127: R410.2 132.63,62.39 EU401.1 ; R404.1 131.74,61.5 EU401.1 ; EU401.1 131.74,64.4 v1(132.44,65.09) 132.6,65.25 132.6,65.69 132.68,65.78
SM_INTRUDER#: length 13.3
  TOP w0.102: R1901.2 140.7,66.13 139.06,67.77 137.7,67.77 v1(136.32,69.15) 134.47,71 v2(134.47,71.32)
  BOTTOM w0.089: 134.04,72.09 134.02,72.11 134.02,73.59 134.06,73.63 134.06,74.12 CPU1.AU6
  BOTTOM w0.102: v2(134.47,71.32) 134.47,71.66 134.04,72.09
SM_RCOMP_0: length 9.8
  TOP w0.508: R407.2 104.3,79.79 103.88,79.38 101.15,79.38 99.98,78.22 v1(99.98,77.52) 99.98,75.27 v2(100.34,74.92)
  BOTTOM w0.254: CPU1.AU60 100.55,74.71 v2(100.34,74.92)
SM_RCOMP_1: length 3.3
  TOP w0.508: R408.2 100.96,74.47 v1(100.61,74.11) v2(100.07,73.58)
  BOTTOM w0.178: v2(100.07,73.58) 100.26,73.76 100.54,73.76 CPU1.AV60
SM_RCOMP_2: length 10.1
  TOP w0.508: R409.2 101.38,73.53 100.64,72.78 v1(100.12,72.78) 99.57,72.78 98.39,73.97 v2(96.68,73.97)
  BOTTOM w0.203: v2(96.68,73.97) 96.72,74 97.44,74 98.23,74.79 99.27,74.79 99.38,74.68 CPU1.AU61
SMB_CLK: length 28.4
  TOP w0.14: v2(139.48,74.47) 139.48,74.46 139.16,74.15 139.16,74.15 v1(139.09,74.07)
  L3 w0.127: v2(152.62,70.72) 152.68,70.78 152.68,71.38 152.13,71.94 150.62,71.94 150.29,71.61 149.42,71.61 146.56,74.46 142.41,74.46 141.26,75.62 140.62,75.62 v2(139.48,74.47)
  BOTTOM w0.089: CPU1.AP2 136.75,75.59 137.51,75.59 137.67,75.43
  BOTTOM w0.14: v2(139.48,74.47) 138.94,74.47 138.12,75.3 137.8,75.3 137.67,75.43 ; v2(152.62,70.72) 152.07,70.17 152.07,68.92 152.61,68.38 155.17,68.38 Q1801.3 155.6,68.81 156.84,68.81 156.94,68.91 RN1811.3
SMB_DATA: length 31.4
  TOP w0.14: v2(142.32,78.85) 142.25,78.85 v1(141.88,78.48)
  L3 w0.127: v2(152.65,70) 153.06,70.41 153.06,71.54 152.28,72.32 150.47,72.32 150.13,71.99 149.58,71.99 146.72,74.85 142.57,74.85 141.32,76.09 141.32,77.59 142.32,78.59 v2(142.32,78.85)
  BOTTOM w0.14: v2(142.32,78.85) 141.22,78.85 140.99,79.08 139.55,79.08 139.04,79.59 137.14,79.59 CPU1.AH1 ; v2(152.65,70) 152.73,70.08 Q1801.6 153.69,70.87 154.11,71.29 155.44,71.29 157.17,69.56 RN1811.4
SMBC_THERM_NV: length 34.7
  TOP w0.14: v2(174.85,135.66) 174.85,135.77 175.18,136.1 v1(177.13,136.1) 179.66,136.1 180.69,135.07 180.69,133.62 180.69,133.29 181.92,132.06 194.75,132.06 197.71,135.02 198.15,135.02 198.21,134.96 RN7601.2 199.05,134.96 199.37,135.28 199.37,135.87 199.79,136.28 201.12,136.28 201.32,136.49 201.32,137.78 201.02,138.09 Q7601.1
  BOTTOM w0.14: GPU1.D9 174.46,136.05 v2(174.85,135.66)
SMBD_THERM_NV: length 35.9
  TOP w0.14: Q7601.4 197.19,139.39 196.87,139.07 196.87,137.32 197.93,136.26 198.39,136.26 198.77,135.87 RN7601.1 198.21,135.61 198.02,135.42 197.55,135.42 194.58,132.46 182.08,132.46 181.08,133.45 181.08,134.91 181.08,135.23 179.82,136.49 v1(178.78,136.49) 175.02,136.49 174.17,135.64 v2(174.05,135.64)
  BOTTOM w0.14: v2(174.05,135.64) 174.45,135.24 GPU1.D8
SML0_CLK: length 27.9
  L3 w0.127: v2(160.79,73.59) 160.79,73.74 160.59,73.94 152.91,73.94 152.36,74.49 151.4,74.49 151.16,74.25 148.93,74.25 146.67,76.51 145.24,76.51 144.09,77.66 143.24,77.66 v2(142.14,76.57)
  BOTTOM w0.14: v2(142.14,76.57) 141.73,76.15 141.41,76.15 v1(141.41,76.16) 141.41,76.15 138.74,76.15 138.35,76.55 137.19,76.55 CPU1.AN1 ; v2(160.79,73.59) 160.72,73.52 159.64,73.52 RN1807.5
SML0_DATA: length 30.2
  L3 w0.127: v2(161.42,73.61) 161.42,73.97 161.07,74.32 153.07,74.32 152.52,74.87 151.25,74.87 151,74.63 149.09,74.63 146.83,76.89 145.4,76.89 143.74,78.55 v2(143.47,78.55)
  BOTTOM w0.14: RN1807.6 159.88,72.71 160.14,72.96 160.28,73.11 161.09,73.11 161.37,73.39 161.37,73.56 v2(161.42,73.61) ; CPU1.AK1 138.32,78.87 139.15,78.04 139.69,78.04 139.94,77.79 140.66,77.79 140.86,77.99 v1(142.4,77.99) 142.83,77.99 142.84,77.99 143.29,77.99 143.47,78.17 v2(143.47,78.55)
SML1_CLK: length 204.8
  TOP w0.14: v2(182.84,91.4) 182.75,91.32 181.67,91.32 180.69,90.34 161.88,90.34 159.73,92.49 159.73,93.14 154.08,98.79 153.09,98.79 148.54,103.33 148.34,103.33 146.14,105.53 146.14,108.51 141.59,113.07 134.01,113.07 131.65,115.42 131.27,115.42 129.86,115.42 129.66,115.62 129.66,116.08 128.92,116.82 Q2601.3 ; Q7601.6 198.93,138.09 199.24,138.4 199.24,139.81 199.45,140.02 200.71,140.02 202.63,138.1 202.63,129.44 201.07,127.88 199.16,127.88 197.91,126.63 197.91,123.75 193.73,119.58 192.47,119.58 v2(191.8,118.9) ; v2(178.54,80.67) 178.26,80.39 KBC24.67
  L3 w0.127: v2(178.54,80.67) 178.53,80.66 176.35,80.66 175.43,79.74 172.76,79.74 171.33,78.31 166.05,78.31 163.94,76.19 163.13,76.19 161.88,74.94 161.88,73.31 161.68,73.11 161.42,73.11 160.57,72.25 v2(160.57,72.2) 160.56,72.2 160.52,72.25 160.45,72.25 159.14,73.56 151.75,73.56 151.44,73.87 148.77,73.87 146.51,76.13 145.72,76.13 145.27,75.67 v2(145.02,75.67)
  L4 w0.127: v2(191.53,92.23) 191.17,92.6 191.17,97.54 191.73,98.1 191.73,118.83 v2(191.8,118.9) ; v2(178.54,80.67) 178.72,80.85 178.72,80.94 179.56,81.78 181.96,84.18 181.96,90.53 v2(182.84,91.4)
  BOTTOM w0.089: CPU1.AU3 136.1,74.14 136.79,74.14 136.84,74.09 137.3,74.09 137.46,73.93
  BOTTOM w0.14: v2(182.84,91.4) 182.9,91.4 183.18,91.12 183.18,91.12 183.81,90.49 184.4,90.49 184.91,89.98 v1(187.99,89.98) 190.47,89.98 191.02,90.53 191.02,90.61 191.02,91.14 190.89,91.27 190.89,91.72 191.4,92.23 v2(191.53,92.23) ; 137.46,73.93 137.92,73.48 139.97,73.48 140.38,73.88 140.78,73.88 140.8,73.86 142.25,73.86 143.43,75.04 144.38,75.04 v2(145.02,75.67) ; RN1807.8 160.08,71.55 160.57,72.05 v2(160.57,72.2)
SML1_DATA: length 207.2
  TOP w0.14: KBC24.68 178.56,79.99 179,80.43 v2(179.13,80.43) ; Q2601.6 126.31,115.52 126.8,115.03 131.49,115.03 133.85,112.67 141.43,112.67 145.75,108.35 145.75,105.37 148.18,102.94 148.38,102.94 152.93,98.39 153.92,98.39 159.34,92.97 159.34,92.32 161.72,89.95 180.86,89.95 181.83,90.92 182.67,90.92 v2(182.86,90.72) ; Q7601.3 200.78,139.39 202.24,137.93 202.24,129.61 200.9,128.27 198.99,128.27 197.52,126.79 197.52,123.92 193.57,119.97 192.31,119.97 191.89,119.55 v2(191.69,119.55)
  L3 w0.127: v2(142.83,78.47) 141.7,77.33 141.7,76.38 142.12,75.97 143.72,75.97 144.46,75.23 145.36,75.23 145.88,75.75 146.35,75.75 148.62,73.48 151.24,73.48 151.55,73.18 158.47,73.18 159.89,71.76 160.78,71.76 161.2,72.17 v2(161.21,72.17) 161.21,72.35 161.58,72.72 161.84,72.72 162.26,73.15 162.26,74.79 163.29,75.81 164.09,75.81 166.21,77.93 171.49,77.93 171.59,78.03 171.61,78.03 172.93,79.36 175.59,79.36 176.51,80.28 178.01,80.28 178.14,80.15 178.85,80.15 v2(179.13,80.43)
  L4 w0.127: v2(191.37,91.56) 190.78,92.14 190.78,97.7 191.35,98.26 191.35,119.23 191.67,119.55 v2(191.69,119.55) ; v2(182.86,90.72) 182.34,90.2 182.34,84.02 179.94,81.62 179.13,80.81 v2(179.13,80.43)
  BOTTOM w0.089: 138.63,79.37 138.17,79.37 138.14,79.34 136.13,79.34 135.89,79.58 CPU1.AH3
  BOTTOM w0.14: v2(182.86,90.72) 183.02,90.72 183.65,90.1 184.23,90.1 184.75,89.58 v1(186.37,89.58) 186.75,89.58 187.66,89.58 188.15,89.58 188.15,89.58 190.63,89.58 191.41,90.37 191.41,91.51 v2(191.37,91.56) ; v2(142.83,78.47) 142.75,78.38 140.96,78.38 140.66,78.69 139.51,78.69 138.83,79.37 138.63,79.37 ; v2(161.21,72.17) 161.19,72.19 161.19,72.22 160.76,72.65 160.39,72.65 160.3,72.57 160.3,72.57 159.94,72.2 RN1807.7
SP_PLLVDD: length 1.1
  BOTTOM w0.305: v2(166.58,133.89) 166.59,133.89 166.97,133.51 GPU1.N6 ; v2(167.39,133.1) 167.39,133.11 GPU1.M6
  vias: v1(167.75,132.58)
SPI_CLK_R: length 82.9
  TOP w0.14: v2(169.82,68.11) 169.84,68.09 171.29,68.09 171.84,68.64 R2420.1
  L3 w0.127: v2(169.82,68.11) 169.72,68.11 169.27,68.56 168.69,68.56 168.35,68.22 166.78,68.22 166.73,68.27 163.02,68.27 160.68,65.92 160.66,65.92 159.57,64.83 151.34,64.83 151.01,64.5 149.08,64.5 v2(149.05,64.47)
  L4 w0.127: v2(147.43,84.74) 148.19,83.98 150.15,83.98 151.86,82.26 153.03,82.26 155.16,80.13 156.7,80.13 157.77,79.06 157.77,78.16 159.94,75.98 163.49,75.98 166.17,73.31 166.17,72.9 167.12,71.94 167.12,71.16 169.19,69.09 169.19,68.69 169.78,68.11 v2(169.82,68.11)
  BOTTOM w0.14: R1806.1 146.18,83.04 147.43,84.28 v2(147.43,84.74) ; v2(149.05,64.47) 149.05,65.05 148.72,65.38 146.41,65.38 146.24,65.55 145.52,65.55 144.41,64.44 144.41,61.19 143.67,60.46 143.67,55.91 v1(144.03,55.55) 145.89,53.69 EC2503.1 147.22,52.41 147.22,51.55 148.11,50.65 SPI25.6
SPI_CS0#_R: length 72.9
  TOP w0.14: R2419.1 172.66,69.52 172.5,69.37 171.61,69.37 170.9,68.66 v2(170.69,68.66)
  L3 w0.127: v2(150.5,63.91) 150.79,63.62 151.4,63.62 151.85,64.06 159.9,64.06 163.34,67.51 166.41,67.51 166.46,67.46 166.55,67.46 166.55,67.46 168.97,67.46 169.18,67.67 170,67.67 170.69,68.35 v2(170.69,68.66)
  L4 w0.127: v2(152.12,86.73) 152.9,85.95 152.9,84.07 155.7,81.27 157.17,81.27 158.91,79.54 158.91,78.63 160.34,77.2 162.58,77.2 163.04,77.67 163.64,77.67 167.31,74 167.31,73.37 168.27,72.42 168.27,71.63 170.53,69.37 170.53,68.83 v2(170.69,68.66)
  BOTTOM w0.14: R1807.1 149.73,88.24 151.21,88.24 v1(151.8,87.66) 151.8,87.05 v2(152.12,86.73) ; v2(150.5,63.91) 150.42,63.91 149.47,62.97 149.47,58.99 153.46,55 155.65,55 R2501.1 155.67,53.24 SPI25.1
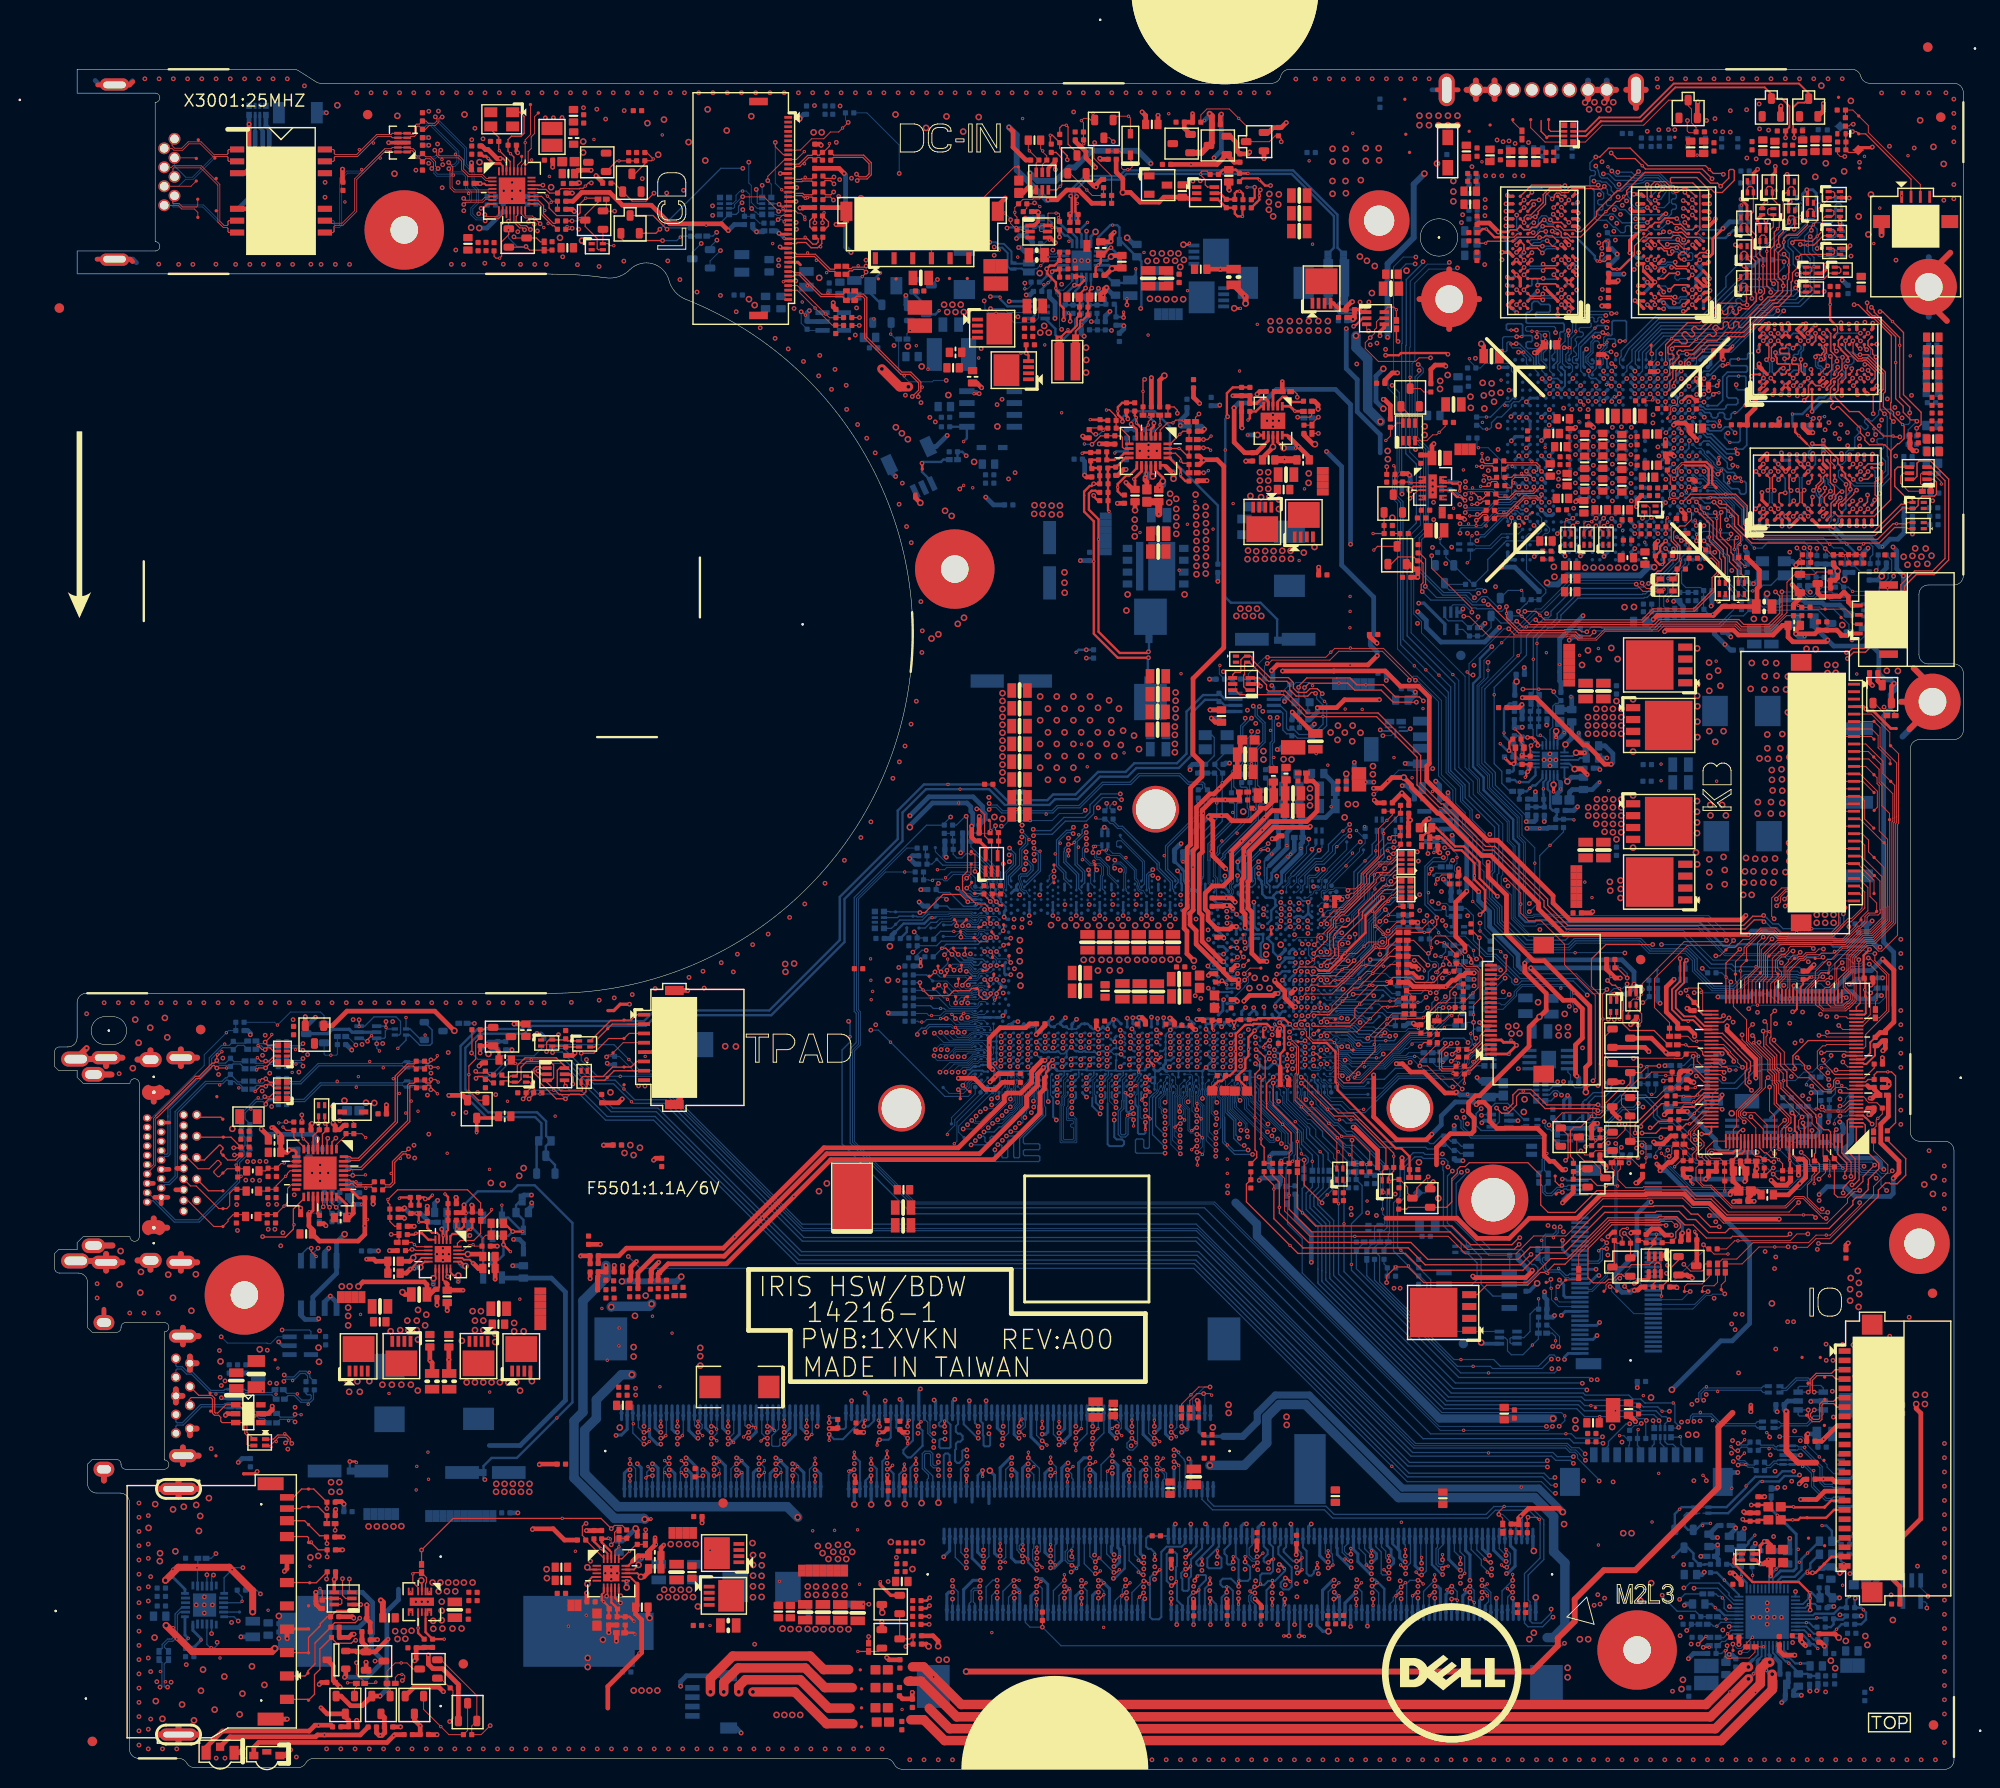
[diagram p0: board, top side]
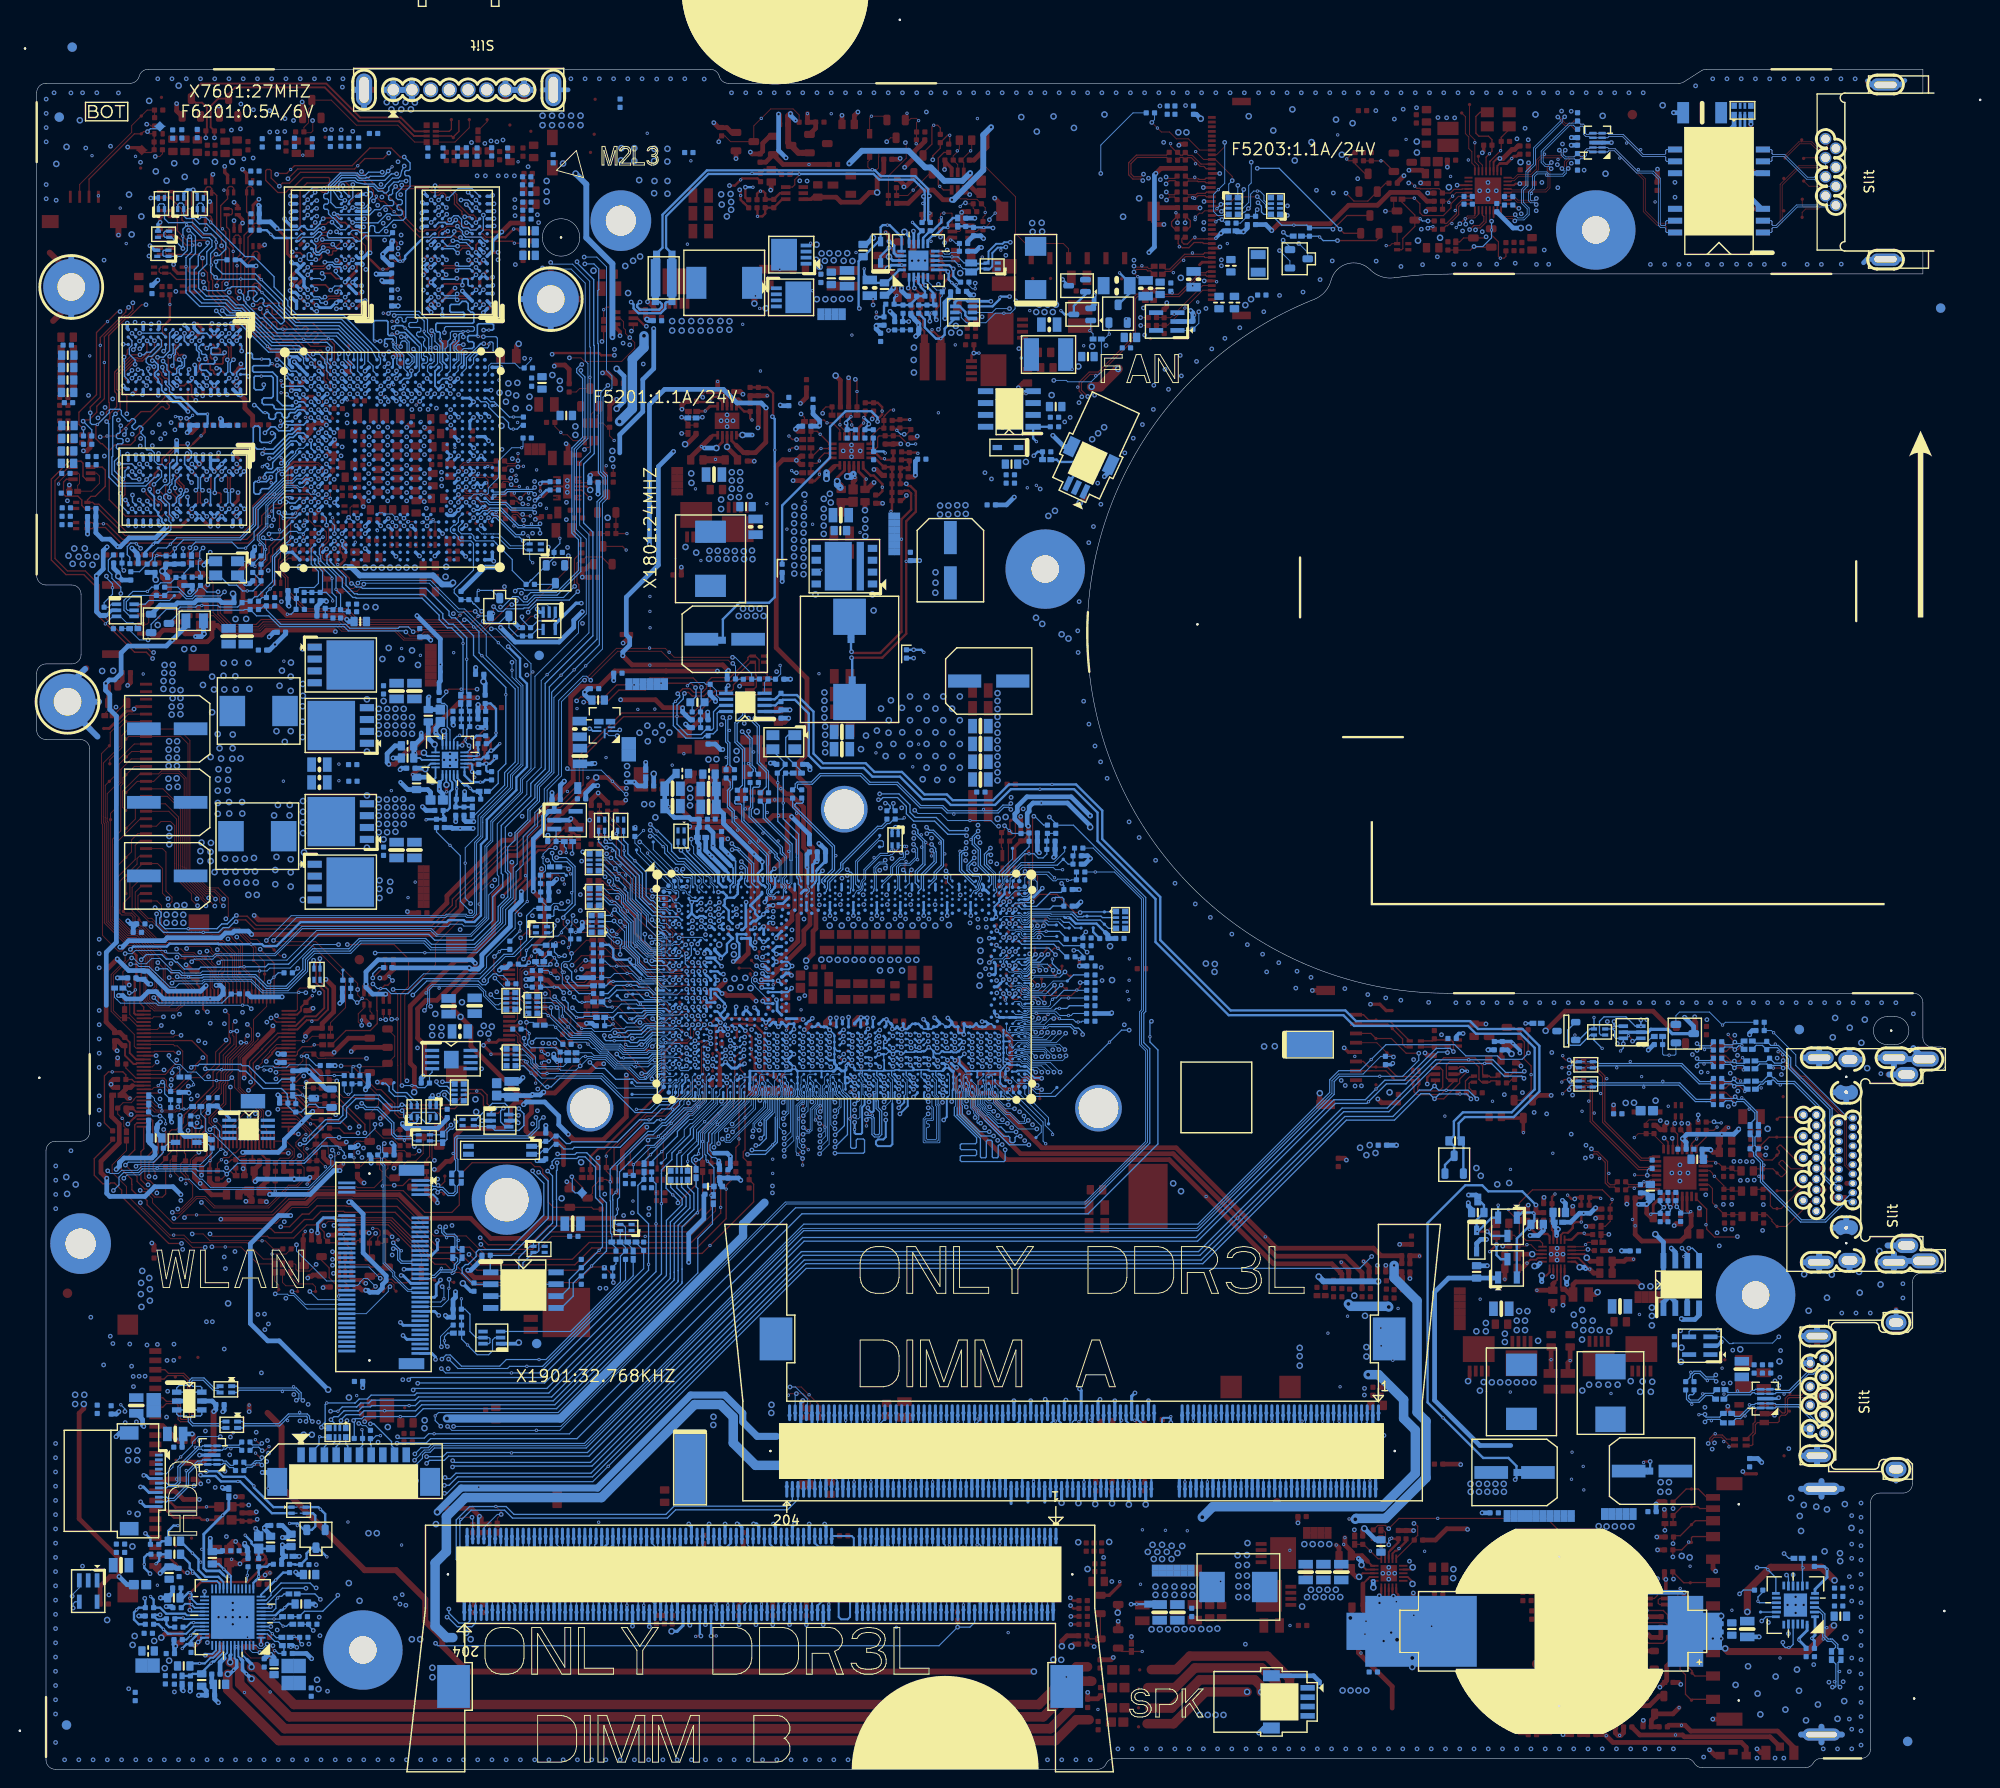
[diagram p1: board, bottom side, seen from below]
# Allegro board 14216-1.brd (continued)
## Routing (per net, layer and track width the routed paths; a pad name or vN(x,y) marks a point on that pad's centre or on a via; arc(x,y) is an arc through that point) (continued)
SPI_HOLD#: length 73.1
  L3 w0.127: v2(167.37,69.04) 166.79,69.63 163.28,69.63 161.63,67.97 149.54,67.97 147.99,66.43 147.99,65.71 148.52,65.18 v2(148.52,64.93)
  L4 w0.127: v2(167.37,69.04) 166.74,69.67 166.74,69.67 166.1,70.3 166.1,71.55 164.14,73.51 164.14,74.12 163.04,75.22 159.38,75.22 157.95,76.65 155.96,76.65 154.39,78.23 154.39,79.67 152.56,81.5 152.03,81.5 152.03,81.5 151.43,81.5 150.51,82.42 149.71,82.42 148.97,83.16 148.48,83.16 v2(147.82,82.49)
  BOTTOM w0.14: v2(148.52,64.93) 148.52,64.14 148.59,64.07 148.59,60.99 148.57,60.97 148.57,58.2 150.48,56.29 150.48,55.5 150.65,55.33 RN2501.2 152.18,54.2 152.18,52.43 151.67,51.92 SPI25.7 ; R1812.1 144.44,80.6 145.63,80.6 145.74,80.48 v1(146.44,80.48) 146.48,80.48 147.34,81.34 147.34,82.01 v2(147.82,82.49)
SPI_SI_R: length 85.1
  TOP w0.14: R2422.1 171.9,71.25 169.7,69.05 v2(169.7,68.81)
  L3 w0.127: v2(148.47,65.87) 148.47,66.32 149.74,67.59 161.81,67.59 162.86,68.65 166.89,68.65 166.93,68.6 168.19,68.6 168.53,68.94 169.43,68.94 169.56,68.81 v2(169.7,68.81)
  L4 w0.127: v2(147.63,86.02) 147.97,85.67 149,85.67 152.03,82.64 153.19,82.64 155.32,80.51 156.86,80.51 158.15,79.22 158.15,78.32 160.1,76.36 163.65,76.36 166.55,73.47 166.55,73.06 167.51,72.1 167.51,71.32 169.7,69.12 v2(169.7,68.81)
  BOTTOM w0.14: v2(147.63,86.02) 146.96,85.35 146.96,84.5 146.33,83.87 R1808.1 ; v2(148.47,65.87) 148.42,65.82 146.62,65.82 146.44,65.99 145.35,65.99 143.95,64.6 143.95,61.35 143.24,60.63 143.24,55.48 v1(144.84,53.88) 145.91,52.81 EC2501.1 146.04,52.81 146.8,52.05 146.8,50.65 148.06,49.38 SPI25.5
SPI_SO_R: length 79.7
  TOP w0.14: v2(169.09,68.12) 169.09,69.04 172.13,72.08 R2423.1
  L3 w0.127: v2(169.09,68.12) 168.81,67.84 166.62,67.84 166.57,67.89 163.18,67.89 159.74,64.44 151.52,64.44 v2(151.14,64.06)
  L4 w0.127: v2(146.72,82.66) 146.72,83.28 147.01,83.57 149.9,83.57 151.59,81.88 152.72,81.88 154.81,79.78 154.81,78.34 156.12,77.03 158.11,77.03 159.54,75.6 163.33,75.6 165.78,73.15 165.78,72.74 166.74,71.78 166.74,71 168.45,69.3 168.45,68.76 v2(169.09,68.12)
  BOTTOM w0.14: R1809.1 145.48,82.15 145.54,82.1 v1(145.85,82.1) 146.16,82.1 v2(146.72,82.66) ; SPI25.2 157.27,51.92 EC2502.1 157.63,52.06 158.66,53.09 158.66,53.11 158.68,53.11 158.68,53.67 158.33,54.03 158.05,54.03 157.18,54.89 157.18,55.35 156.9,55.63 153.64,55.63 149.94,59.33 149.94,62.71 151.14,63.91 v2(151.14,64.06)
SPI_WP#: length 77
  TOP w0.14: v2(149.23,86.17) 149.23,86.45 v1(148.8,86.87)
  L3 w0.127: v2(149.54,64.04) 150.41,63.16 151.51,63.16 152.03,63.68 160.1,63.68 161.12,64.7 163.84,64.7 164.9,65.77 166.05,65.77 166.53,65.28 168.16,65.28 168.2,65.33 168.92,65.33 168.94,65.31 168.95,65.31 169.21,65.05 169.58,65.05 169.86,65.32 169.86,65.99 v2(169.82,66.03)
  L4 w0.127: v2(169.82,66.03) 169.82,66.17 170.3,66.66 170.3,68.42 170.15,68.58 170.15,69.21 167.89,71.47 167.89,72.26 166.93,73.22 166.93,73.62 163.81,76.75 160.26,76.75 158.53,78.48 158.53,79.38 157.02,80.89 155.52,80.89 152.52,83.89 152.52,85.49 152.09,85.91 149.49,85.91 v2(149.23,86.17)
  BOTTOM w0.14: v2(149.23,86.17) 149.42,85.98 150.55,85.98 150.84,86.27 R1811.1 ; v2(149.54,64.04) 149.01,63.51 149.01,60.82 149,60.81 149,58.48 151.05,56.43 RN2501.1 151.43,55.98 152.61,54.8 152.61,51.92 153.88,50.65 SPI25.3
SRTC_RST#: length 16.1
  TOP w0.127: v2(133.36,73.45) v1(136.16,70.66) 136.89,69.92 138.92,69.92 142.43,66.42 C1902.1 142.04,64.01 RN1901.4
  BOTTOM w0.127: v2(133.36,73.45) 133.47,73.45 CPU1.AV6
STRAP0: length 7.5
  BOTTOM w0.127: R7621.1 173.22,125.98 172.53,125.28 v1(172.53,125.07) ; R7621.1 173.62,126.22 173.62,128.22 174.45,129.05 GPU1.D1 ; R7621.1 R7646.2 R7625.2
STRAP1: length 9
  BOTTOM w0.127: GPU1.D2 174.45,130.11 174.07,129.73 174.07,129.1 172.6,127.63 v1(172.6,127.46) 172.6,125.92 172.14,125.47 172.14,124.48 R7635.2 172.65,124.27 R7622.1 173.32,124.27 R7647.1
STRAP2: length 2.9
  TOP w0.127: v1(173.55,131.92) 173.63,131.92 v2(174.03,131.52) 174.04,131.51 174.64,131.51 R7637.1 174.86,131.28 R7606.2
  BOTTOM w0.127: v2(174.03,131.52) 173.68,131.87 GPU1.E4
STRAP3: length 9.8
  BOTTOM w0.127: GPU1.E3 173.96,130.71 173.96,130.06 173.81,129.91 173.81,129.36 172.17,127.72 172.17,126.38 172.17,126.38 v1(172.17,126.31) 172.16,126.29 172.16,126.25 171.69,125.78 R7615.2 171.69,124.11 171.48,123.91 R7609.1 R7650.1
STRAP4: length 10.5
  BOTTOM w0.127: GPU1.D3 174.83,130.69 174.83,129 174.06,128.23 174.06,126.95 174.51,126.5 176.09,126.5 R7654.1 176.41,126.16 R7632.1 176.41,124.2 R7634.2 176.97,123.64 v1(177.38,123.64)
STRAP_REF0_GND_N9: length 3.3
  TOP w0.127: v1(172.55,133.96) 172.38,133.8 R7607.2 172.38,132.3 v2(172.35,132.26)
  BOTTOM w0.127: v2(172.35,132.26) 172.33,132.28 172.33,132.83 172.32,132.84 172.32,133.14 GPU1.F6
SUS_CLK: length 28.2
  TOP w0.14: v2(166.13,84.43) 166.63,83.93 166.96,83.93 167.8,83.09 167.8,81.22 167.77,81.18 167.77,79.82 168.5,79.08 171.12,79.08 172.65,77.55 R2441.2
  L3 w0.127: v2(166.13,84.43) 166.13,84.54 165.37,85.3 158.6,85.3 156.99,83.68 152.04,83.68 v2(151.86,83.87)
  BOTTOM w0.14: v1(166.5,84.89) 166.5,84.81 v2(166.13,84.43) ; R1710.2 151.71,83.72 v2(151.86,83.87)
SUS_CLK_PCH: length 19.5
  L3 w0.102: 139.53,82.18 136.17,82.18 135.94,81.94 134.47,81.94 134.12,81.6 v2(134.02,81.6)
  L3 w0.127: 139.53,82.18 140.7,83.35 145.21,83.35 146.34,82.21 146.91,82.21 147.64,82.94 147.64,82.95 v2(147.81,83.13)
  BOTTOM w0.14: CPU1.AE6 134.02,81.32 v2(134.02,81.6) ; EC1701.2 R1710.1 v1(148.82,83.72) 148.41,83.72 147.82,83.13 v2(147.81,83.13)
SUSCLK_KBC: length 4.3
  TOP w0.14: R2441.1 v1(174.51,77.55) 174.58,77.55 174.78,77.35 175.78,77.35 176.31,76.81 176.31,76.53 176.46,76.38 KBC24.77
SYS_PEX_RST_MON#: length 47.8
  TOP w0.127: v2(156.42,122.89) 157.04,122.27 v1(157.46,122.27) 171.28,122.27 171.83,122.82 179.97,122.82 180.49,122.29 183.46,122.29 184.81,123.65 184.81,126.02 v2(184.79,126.04)
  BOTTOM w0.127: U7301.4 150.65,122.02 R7304.2 R7306.1 152.78,121.31 153.68,122.21 D7301.2 153.97,123.46 154.73,122.7 156.1,122.7 156.29,122.89 v2(156.42,122.89) ; v2(184.79,126.04) 184.81,126.02 185.98,126.02 R7629.2 187,126.39 187,126.19 187.64,125.55 188.1,125.55 189.09,126.54 R7313.1
SYS_PEX_RST_MON_GPU#: length 22.4
  L4 w0.127: v2(173.21,136.45) 172.82,136.06 172.82,135.42 173.92,134.31 175.83,134.31 176.24,133.9 176.98,133.9 179.43,131.46 179.43,131 180.03,130.4 181.08,130.4 181.66,130.98 186.14,130.98 v2(186.39,130.73)
  BOTTOM w0.127: v2(173.21,136.45) 173.61,136.05 GPU1.E9 ; v2(186.39,130.73) 186.75,130.37 186.75,129.5 v1(186.72,129.47) 186.9,129.29 186.9,128.38 186.67,128.15 R7629.1 R7643.1
SYS_PRES1#: length 1.6
  TOP w0.102: AFTP3901.1 156.01,176.36 R4301.2
SYS_PWROK: length 53.1
  TOP w0.127: v2(175.63,74.22) 175.78,74.22 176.41,73.59 KBC24.84
  L3 w0.127: v2(138.3,80.34) 138.48,80.52 140.31,80.52 140.96,81.17 144.81,81.17 146.16,79.82 149.86,79.82 151.1,81.07 153.13,81.07 153.41,80.79 158.33,80.79 158.63,81.09 159.65,81.09 161.51,82.95 162.82,82.95 164.58,81.19 169.02,81.19 v2(169.91,82.07)
  L4 w0.127: v2(175.63,74.22) 175.63,74.66 175.22,75.07 174.75,75.07 173.66,76.16 173.66,76.71 171.69,78.68 171.69,79.4 169.91,81.18 v2(169.91,82.07)
  BOTTOM w0.089: CPU1.AG2 136.61,80.37 136.9,80.08 137.34,80.08 137.44,79.98 137.94,79.98 v2(138.3,80.34)
  BOTTOM w0.127: v1(169.37,82.53) 169.83,82.07 v2(169.91,82.07) 169.98,82.07 170.6,82.69 R1717.1 EC1702.1 170.6,84.43 R9605.1
T_CRIT#: length 4.2
  BOTTOM w0.102: v1(124.66,118.16) 124.6,118.1 124.6,117.24 R2604.2 125.56,116.69 125.58,116.7 R2601.1 126.32,116.36 THM26.4
TD_IREF: length 5.8
  BOTTOM w0.102: CPU1.B12 129.47,94.62 129.47,94.82 129.43,94.86 129.43,95.61
  BOTTOM w0.178: 129.43,95.61 129.43,97.2 129.67,97.44
  BOTTOM w0.508: R603.2 130.93,99.5 130.93,98.7 v1(130.21,97.98) 129.67,97.44
TESTMODE: length 10.3
  BOTTOM w0.102: R7302.1 152.17,141.61 v1(152.31,141.46) 153.37,141.46 154.79,140.03 154.79,138.24 155.88,137.15 155.88,136.59 155.99,136.48 157.42,136.48 GPU1.AD9
THERM_SYS_SHDN#: length 90.2
  TOP w0.102: v2(166.07,83.48) 166.07,83.45 165.58,82.96 165.58,75.37 165.56,75.36 165.56,70.35 165.28,70.07 164.92,70.07 164.72,70.28 161.29,70.28 160.33,69.32 160.33,67.49 Q2602.S ; v2(145.58,116.57) 142.17,119.98 136.94,119.98 v1(136.54,119.57) 135.99,119.03 129.76,119.03 v2(129.75,119.03)
  BOTTOM w0.102: R2601.2 127.26,116.7 127.29,116.68 R2602.1 127.7,117.27 129.46,119.03 v2(129.75,119.03) ; v2(145.58,116.57) 145.76,116.57 148.05,114.28 148.05,106.34 149.59,104.8 149.59,103.28 150.6,102.27 150.6,100.97 151.71,99.86 v1(151.71,92.89) 153.01,91.59 153.01,90.01 156.06,86.96 156.06,85.83 156.74,85.15 162.81,85.15 164.48,83.48 v2(166.07,83.48)
THM_SML1_CLK: length 26.2
  TOP w0.14: v2(135.61,115.13) 135.08,115.67 134.29,115.67 133.9,115.27 132.98,115.27 132.53,115.73 132.53,116.32 132,116.85 130.02,116.85 128.11,118.77 128.11,119.01 127.96,119.16 RN2602.4 127.31,119.16 126.91,118.76 126.91,117.51 126.83,117.43 126.28,117.43 126.03,117.18 Q2601.4
  BOTTOM w0.14: THM26.8 131.21,113.23 131.4,113.04 131.4,111.25 131.81,110.84 132.16,110.84 C2608.1 132.7,110.63 132.96,110.37 134.75,110.37 136.09,111.72 136.09,114.08 v1(135.85,114.31) 135.41,114.76 135.41,114.92 v2(135.61,115.13)
THM_SML1_DATA: length 24.9
  TOP w0.14: v2(134.9,115.17) 134.79,115.27 134.46,115.27 134.06,114.88 132.82,114.88 132.13,115.57 132.13,116.16 131.83,116.46 129.86,116.46 127.81,118.51 RN2602.3 127.44,118.51 127.3,118.37 127.3,117.2 127.21,117.1 127.21,115.88 127.57,115.52 Q2601.1
  BOTTOM w0.14: v2(134.9,115.17) 135.01,115.05 135.01,114.59 135.69,113.91 v1(135.69,112.72) 135.69,111.88 134.58,110.77 133.12,110.77 132.44,111.45 C2609.1 132.15,111.23 131.97,111.23 131.79,111.42 131.79,113.2 131.12,113.88 THM26.7
TOUCH_PANEL_INTR#: length 256
  TOP w0.127: R2411.1 190.4,61.59 190.74,61.25 191.55,61.25 192.42,62.12 192.64,62.12 193.46,62.93 193.46,63.43 v2(194.71,64.68) ; R5205.2 v2(86.1,155.39)
  L3 w0.127: v2(86.1,155.39) 84.63,156.87 84.63,158.95 80.88,162.69 80.88,173.47 81.83,174.42 83.35,174.42 v2(83.62,174.15)
  L4 w0.127: v2(191.31,85.69) 191.22,85.59 191.22,81.93 193.02,80.12 193.02,74.71 193.35,74.38 193.35,66.32 194.67,65 194.67,64.71 v2(194.71,64.68) ; v2(145.55,161.14) 145.01,161.68 145.01,172.12 142.22,174.91 142.01,174.91 128.68,174.91 128.51,175.09 115.58,175.09 114.16,176.51 110.49,176.51 108.84,174.86 104.65,174.86 103.87,174.08 83.7,174.08 v2(83.62,174.15)
  BOTTOM w0.127: D2401.A 190.01,67.11 R2443.1 190.65,66.02 191.68,64.99 194.39,64.99 v2(194.71,64.68) ; v2(191.31,85.69) 190.24,85.69 189.83,85.28 188.99,85.28 188.69,84.98 186.58,84.98 186.49,85.07 180.78,85.07 179.54,83.83 177.51,83.83 175.72,85.62 175.72,86.77 174.66,87.84 174.43,87.84 174.43,87.84 170.85,87.84 170.84,87.84 170.78,87.84 169.7,88.93 162.58,88.93 161.96,88.31 157.35,88.31 154.83,90.83 154.83,92.35 153.79,93.38 153.79,95.83 154.06,96.1 154.06,100.83 150.9,104 150.9,105.35 149.36,106.89 149.36,115.86 v1(148.1,117.12) 144.25,120.96 144.25,135.68 143.62,136.32 143.62,138.26 144.11,138.75 144.11,152.59 144.17,152.65 144.17,158.29 144.06,158.39 144.06,160.62 144.58,161.14 v2(145.55,161.14)
TOUCH_PANEL_INTR_KBC#: length 3.6
  TOP w0.127: KBC24.124 189.6,66.33 190.36,65.56 190.36,65.4 R2411.2 190.4,65.31 191.31,64.4 v1(191.31,64.34)
TP_CL_CLK: length 4.6
  BOTTOM w0.127: 136.73,81.29 136.57,81.12 CPU1.AF2
  BOTTOM w0.14: TP1801.1 140.85,81.45 136.89,81.45 136.73,81.29
TP_CL_DATA: length 6
  BOTTOM w0.089: CPU1.AD2 136.75,82.15 137.56,82.15
  BOTTOM w0.14: TP1802.1 141.63,82.34 139.99,82.34 139.8,82.15 137.56,82.15
TP_CL_RST#: length 7.5
  BOTTOM w0.089: 138.13,80.77 137.94,80.77 137.88,80.82 137.51,80.82 137.34,80.66 136.16,80.66 136.07,80.75 135.49,80.75 135.39,80.85
  BOTTOM w0.127: 135.39,80.85 CPU1.AF4
  BOTTOM w0.14: 138.13,80.77 138.84,80.77 139.24,80.37 139.83,80.37 140.08,80.11 140.08,80.06 140.26,79.88 141.01,79.88 TP1803.1
TP_DC_TEST_A4: length 5.4
  BOTTOM w0.102: TP2202.1 138.23,98.45 136.14,96.37 136.14,96.17 135.38,95.4 135.38,95.24 CPU1.A4
TP_DC_TEST_A60: length 8.2
  BOTTOM w0.102: TP2203.1 94.22,98.23 95.38,97.06 98.89,97.06 100.39,95.56 CPU1.A60
TP_DC_TEST_A62: length 3.6
  TOP w0.102: TP2205.1 98.46,97.86 98.46,96.12 v2(98.46,96.11)
  BOTTOM w0.102: CPU1.A62 99.08,95.49 v2(98.46,96.11)
TP_DC_TEST_AV1: length 3.9
  BOTTOM w0.102: CPU1.AV1 137.23,73.77 137.89,73.11 140.13,73.11 TP2206.1
TP_DC_TEST_AW1: length 3.7
  BOTTOM w0.102: TP2207.1 137.91,72.25 CPU1.AW1
TP_DC_TEST_AW63: length 5
  BOTTOM w0.102: CPU1.AW63 98.49,72.3 95.94,69.75 TP2208.1
TP_DC_TEST_AY60: length 6.6
  BOTTOM w0.102: CPU1.AY60 100.31,72.46 96.72,68.86 96.72,68.19 TP2201.1
TP_DC_TEST_B2: length 5.2
  BOTTOM w0.102: CPU1.B2 136.61,94.7 140.02,98.11 TP2204.1
TP_HDA_DOCK_EN#: length 10.8
  BOTTOM w0.089: 131.77,71.65 131.78,71.66 131.78,72.82 CPU1.AW10
  BOTTOM w0.102: 131.77,71.65 131.77,71.42 134.07,69.11 134.28,69.11 134.92,68.48 134.92,67.73 136.82,65.83 136.82,65.45 TP1902.1
TP_LOCK#: length 203.4
  TOP w0.127: TPAD1.3 61.46,78.77 AFTP6242.1 59.26,78.23 57.69,76.65 v2(56.33,76.65)
  L3 w0.127: v2(191.28,45.48) 190.41,44.61 188.55,44.61 187.99,44.05 182.82,44.05 182.47,43.69 175.31,43.69 171.82,40.2 171.82,39.37 171.22,38.77 169.66,38.77 168.06,37.17 168.06,35.6 168.12,35.53 168.12,34.84 165.79,32.51 165.77,32.51 165.23,31.97 v2(165.23,30.87)
  L4 w0.127: v2(191.28,45.48) 191.28,46.28 188.97,48.6 188.97,53.51 189.19,53.73 191.05,55.59 191.05,56.68 191.56,57.18 191.56,58.83 190.75,59.64 190.75,61.01 190.49,61.27 190.49,62.06 190.7,62.26 190.7,64.47 190.02,65.15 190.02,67.92 190.16,68.07 190.16,68.67 190.53,69.04 190.53,70.42 190.28,70.67 190.28,72.76 v2(189.83,73.21)
  BOTTOM w0.127: v2(165.23,30.87) 165.23,30.98 162.93,33.29 162.93,33.65 162.64,33.94 162.1,33.94 161.65,34.4 145.4,34.4 122.14,57.66 79.98,57.66 65.38,72.25 65.38,73.61 64.81,74.18 v1(60.51,74.18) 58.05,74.18 56.33,75.9 v2(56.33,76.65) ; v2(189.83,73.21) 189.84,73.21 189.84,72.59 R2450.1
TP_LOCK#_C: length 13.1
  TOP w0.127: v2(189.64,78.9) 189.76,78.79 KBC24.26
  L3 w0.127: v2(190.74,73.56) 190.74,74.07 190.13,74.68 190.13,75.51 190.72,76.1 190.72,77.47 189.64,78.55 v2(189.64,78.9)
  BOTTOM w0.127: v1(191.19,73.19) 190.82,73.56 v2(190.74,73.56) 190.51,73.33 190.51,72.31 R2450.2 189.87,70.85 R2426.1
TP_M_A_DIMA_ODT0: length 1.2
  TOP w0.102: v2(117.86,76.56) 117.51,76.91 TP501.1
  BOTTOM w0.102: CPU1.AP32 118.2,76.22 v2(117.86,76.56)
TP_M_B_DIMB_ODT0: length 1.2
  TOP w0.102: v2(117.88,78.49) 118.13,78.74 TP503.1
  BOTTOM w0.102: v2(117.88,78.49) 118.21,78.17 CPU1.AL32
TP_ON#: length 230.1
  TOP w0.127: R6214.1 44.64,76.72 v2(44.6,76.68) ; KBC24.33 191.55,82.73 v2(191.68,82.61)
  L3 w0.127: v2(196.04,45.57) 195.65,45.97 188.61,45.97 187.17,44.53 182.62,44.53 182.27,44.17 181.36,44.17 174.84,44.17 171.34,40.67 171.34,39.57 171.02,39.26 169.24,39.26 167.57,37.58 167.57,36.19 165.17,33.79 163.78,33.79 v2(163.74,33.76)
  L4 w0.127: v2(196.04,45.57) 195.4,46.22 195.4,53.86 194.9,54.36 194.9,62.66 195.32,63.08 195.32,63.45 195.17,63.6 195.17,64.32 195.25,64.4 195.25,64.81 193.61,66.45 193.61,74.5 193.28,74.83 193.28,80.37 191.68,81.97 v2(191.68,82.61)
  BOTTOM w0.127: v2(163.74,33.76) 163.08,34.42 162.3,34.42 161.85,34.88 145.6,34.88 122.13,58.35 79.96,58.35 65.86,72.45 65.86,73.81 64.89,74.78 62.62,74.78 v1(61.43,75.98) 59.84,77.56 52.49,77.56 51.29,76.37 47.92,76.37 47.56,76 45.28,76 v2(44.6,76.68) ; v2(191.68,82.61) 191.1,82.02 184.37,82.02 183.41,82.99 R2453.1 183.36,83 R2452.1
TP_ON#_GATE: length 10.7
  TOP w0.127: Q6205.G 45.36,71.62 44.31,72.66 v1(44.31,74.36) 44.31,75.29 45.04,76.02 45.04,77.86 C6204.2 45.52,79.16 R6214.2 45.89,79.16 46.14,79.41 Q6203.G
TP_ON#_S: length 7.4
  TOP w0.381: v2(45.52,76.68) C6204.1 45.52,77.45 46.91,77.45 Q6203.S 47.53,76.82 R6213.1
  BOTTOM w0.381: R6217.2 47.41,77.9 R6215.2 46.45,77.9 v1(46.25,77.7) 45.52,76.97 v2(45.52,76.68)
TP_RESET: length 7.5
  TOP w0.102: R5212.1 84.38,154.57 C5214.1 83.19,154.57 v1(81.35,156.41) 79.45,158.32 LCD1.38
TP_RS: length 7.4
  TOP w0.102: LCD1.37 79.45,158.82 v1(82.5,155.77) 82.89,155.38 C5208.1 83.59,155.39 R5205.1
TP_V1.05S_APLLOPI: length 5.7
  TOP w0.102: v2(127.26,85.15) 127.88,85.76 TP2105.1
  BOTTOM w0.102: CPU1.AC20 127.31,83.75 127.31,83.83 127.61,84.12 127.61,84.13 127.72,84.23 127.72,84.69 v2(127.26,85.15)
TP_V1.05S_AXCK_DCB: length 1.4
  TOP w0.102: v2(126.5,87.91) 126.45,87.96 TP2104.1
  BOTTOM w0.102: CPU1.M20 126.35,88.07 v2(126.5,87.91)
TP_V1.05S_SSCF100: length 1.8
  TOP w0.102: TP2103.1 127.13,88.73 v2(127.34,88.52)
  BOTTOM w0.102: CPU1.K18 127.37,88.55 v2(127.34,88.52)
TP_V1.05S_SSCFF: length 2.9
  TOP w0.102: TP2101.1 127.72,86.54 v2(127.19,86.01)
  BOTTOM w0.102: CPU1.V21 126.02,85.22 126.4,85.6 126.78,85.6 v2(127.19,86.01)
TP_VCCAPLLOPI_VAL: length 2.5
  TOP w0.102: TP2102.1 127.86,85.03 v2(127.31,84.48)
  BOTTOM w0.102: v2(127.31,84.48) 126.93,84.1 126.04,84.1 CPU1.Y20
TP_VCCIO_OUT: length 4.1
  BOTTOM w0.102: TP701.1 99.8,97.44 101.21,96.03 CPU1.A59
TP_VDD: length 282.2
  L3 w0.381: v3(59.46,72.46) 59.46,71.9 63.41,67.95 63.41,59.82 58.06,54.47 58.06,52.46 57,51.4 57,29.37 55.32,27.69 55.32,19.01 58.15,16.18 58.93,16.18 62.56,12.55 74.05,12.55 v2(74.89,13.39) ; v2(189.75,69.27) 189.75,60.41 190.28,59.87 190.28,58.88 189.75,58.35 189.75,49.31 190.66,48.39 v2(198.41,48.39)
  L4 w0.381: v2(198.41,48.39) 198.41,41.15 197.56,40.3 197.56,15.87 195.68,13.99 195.68,11.78 192.28,8.38 190.48,8.38 189.34,7.24 185.83,7.24 185.36,7.71 178.42,7.71 175.78,10.36 173.79,10.36 173.6,10.16 163.68,10.16 161.48,12.37 160.41,12.37 159.37,13.42 159.37,14.95 158.98,15.33 156.97,15.33 154.46,12.82 102.3,12.82 99.92,15.2 95.66,15.2 93.92,16.94 93.32,16.94 91.57,15.2 88.42,15.2 88.06,14.84 86.8,14.84 85.35,13.39 v2(74.89,13.39)
  BOTTOM w0.381: v2(189.75,69.27) 189.86,69.38 R2426.2 ; v2(51.59,78.76) 52.05,78.76 52.32,78.49 C6201.1 ; R6203.2 59.26,75.43 v2(59.11,75.58)
  vias: v1(53.55,69.92) v2(56.89,75.97)
TP_WAKE_KBC#: length 5.2
  TOP w0.127: v1(188.24,62.69) 188.24,63.4 188.81,63.96 188.81,64.77 188.46,65.12 R2448.2 188.27,65.87 188.4,65.99 KBC24.121
TPAN_VDD:
  vias: v1(76.82,163.32) v2(77.45,161.57) v2(77.45,160.94)
TPAN_VDD_F:
  vias: v1(77.96,159.23)
TPCLK: length 199.8
  TOP w0.14: KBC24.72 178.27,78.39 179.7,76.95 179.7,76.92 181.03,75.59 181.03,74.93 180.86,74.76 180.86,73.36 v2(181.54,72.68) ; RN6202.1 54.89,77.97 EC6201.1 54.55,78.07 RN6201.4 52.88,78.07 52.63,77.81 v2(52.63,76.83)
  L3 w0.127: v2(162.48,33.47) 162.65,33.47 162.83,33.64 162.83,34.69 164.04,35.9 164.04,38.38 168.12,42.46 169.02,42.46 173.05,46.48 180.61,46.48 181.86,47.73 185.23,47.73 v2(185.4,47.91)
  L4 w0.127: v2(185.4,47.91) 185.4,48.23 185.69,48.52 185.69,54.77 186.61,55.69 186.61,57.54 186.19,57.96 186.19,59.14 185.31,60.02 185.31,66.4 184.26,67.45 184.26,67.77 184.26,70.73 182.3,72.69 181.54,72.69 v2(181.54,72.68)
  BOTTOM w0.14: v2(162.48,33.47) 160.74,33.47 160.3,33.91 145.27,33.91 122.26,56.93 80.16,56.93 65.41,71.67 62.06,71.67 v1(60.9,72.82) 59.96,73.76 57.86,73.76 54.46,77.17 52.97,77.17 v2(52.63,76.83)
TPCLK_C: length 6.9
  TOP w0.14: RN6202.4 57.3,77.97 59.49,80.16 60.87,80.16 AFTP6238.1 61.67,80.2 62.24,80.77 TPAD1.1
TPDATA: length 199.5
  TOP w0.14: KBC24.71 178.42,78.79 180.09,77.11 180.09,77.08 181.42,75.75 181.42,74.76 181.26,74.6 181.26,73.62 v2(181.31,73.56) ; v2(53.26,76.72) 53.26,76.84 53.24,76.87 RN6201.3 54.55,77.42 EC6202.1 54.69,77.32 RN6202.2
  L3 w0.127: v2(186.04,47.91) 185.48,47.35 182.02,47.35 180.77,46.1 173.2,46.1 169.18,42.08 168.28,42.08 164.43,38.22 164.43,35.74 163.21,34.53 163.21,33.48 v2(162.48,32.75)
  L4 w0.127: v2(186.04,47.91) 186.04,48.32 186.08,48.36 186.08,54.61 187,55.53 187,57.69 186.57,58.12 186.57,59.3 185.69,60.18 185.69,66.56 184.64,67.61 184.64,70.89 182.45,73.07 182.03,73.07 181.54,73.56 v2(181.31,73.56)
  BOTTOM w0.14: v2(162.48,32.75) 162.16,33.07 160.58,33.07 160.13,33.52 145.11,33.52 122.1,56.53 79.99,56.53 65.25,71.28 61.89,71.28 v1(61.71,71.46) 59.8,73.37 57.7,73.37 54.29,76.78 53.32,76.78 v2(53.26,76.72)
TPDATA_C: length 7.1
  TOP w0.14: RN6202.3 57.77,77.32 58.07,77.61 58.07,78.18 AFTP6236.1 59.66,79.77 TPAD1.2
TPS51216_PHS_SET:
  vias: v1(70.11,15.4)
USB3_PRX_CTX_N0: length 140.7
  L4 w0.114: v2(125.43,91.21) 125.41,91.21 124.68,91.93 124.68,92.26 123.44,93.51 121.74,93.51 120.97,94.29 108.74,94.29 104.09,89.65 101.99,89.65 100.82,88.47 97.06,88.47 96.56,87.98 94.47,87.98 93.43,86.94 92.24,86.94 90.68,85.37 88.55,85.37 73,69.81 46.02,69.81 39.82,63.61 37.39,63.61 35.51,61.73 29.25,61.73 28.07,60.55 28.07,57.53 26.65,56.12 26.65,55.48 25.51,54.33 25.51,41.78 24.94,41.21 24.94,37.95 v2(25.71,37.18)
  BOTTOM w0.127: v2(125.43,91.21) 125.47,91.16 CPU1.G20 ; 25.03,37.45 24.12,37.45 R3411.2 ; 25.03,37.45 v1(25.03,37.32) ; 25.03,37.45 25.44,37.45 v2(25.71,37.18)
USB3_PRX_CTX_N0_C: length 12.4
  BOTTOM w0.127: USB1.5 12.97,36.72 13.1,36.85 13.76,36.85 15.71,38.8 18.09,38.8 18.21,38.68 U3402.1 U3402.10 20.31,38.68 20.43,38.8 20.64,38.8 21.52,37.92 ; R3411.1 22.4,37.54 21.9,37.54 21.52,37.92 ; 21.52,37.92 v1(21.42,37.83)
USB3_PRX_CTX_P0: length 141.2
  L4 w0.114: v2(125.42,90.57) 125.19,90.57 124.99,90.77 124.99,91.3 124.46,91.84 124.46,92.17 123.34,93.28 121.65,93.28 120.87,94.06 108.83,94.06 104.19,89.42 102.09,89.42 100.91,88.24 97.15,88.24 96.65,87.75 94.56,87.75 93.52,86.71 92.34,86.71 90.77,85.14 88.65,85.14 73.09,69.59 46.12,69.59 39.91,63.38 37.49,63.38 35.61,61.5 29.34,61.5 28.29,60.45 28.29,57.44 26.88,56.02 26.88,55.38 25.74,54.24 25.74,41.68 25.17,41.12 25.17,38.05 25.34,37.88 25.61,37.88 v2(25.71,37.99)
  BOTTOM w0.127: v2(125.42,90.57) 125.61,90.77 125.83,90.77 125.94,90.66 CPU1.H20 ; R3410.2 24.15,37.7 25.6,37.7 25.71,37.81 v2(25.71,37.99) 26.34,37.99 v1(26.37,37.96)
USB3_PRX_CTX_P0_C: length 12.4
  BOTTOM w0.127: 20.86,38.92 22,37.78 22.54,37.78 R3410.1 ; 20.86,38.92 20.74,39.04 20.43,39.04 20.31,39.16 U3402.9 U3402.2 18.21,39.16 18.09,39.04 15.6,39.04 13.66,37.09 13.1,37.09 12.97,37.22 USB1.6 ; 20.86,38.92 v1(20.96,39.02)
USB3_PTX_CRX_N0: length 132.8
  L4 w0.114: v2(24.56,42.21) 24.41,42.07 24.13,42.07 23.53,42.67 23.53,53.09 26.13,55.69 26.13,56.33 27.51,57.71 27.51,60.72 29.37,62.59 35.64,62.59 37.19,64.14 39.49,64.14 45.68,70.34 72.76,70.34 88.72,86.29 90,86.29 91.65,87.94 92.9,87.94 94.53,89.57 97.96,89.57 98.43,90.04 98.43,90.12 99.43,91.12 100.83,91.12 101.51,91.8 103.94,91.8 104.4,92.26 105.96,92.26 108.52,94.81 115.06,94.81 116.3,96.05 117.1,96.05 v2(117.48,95.67)
  BOTTOM w0.127: 27.12,42.39 26.9,42.61 26.2,42.61 25.58,42 24.77,42 v2(24.56,42.21) ; 27.12,42.39 27.3,42.21 27.3,41.98 C3403.1 ; 27.12,42.39 v1(27.24,42.5) ; v2(117.48,95.67) 117.37,95.79 117.18,95.79 117.06,95.67 117.06,94.33 117.13,94.27 117.13,93.86 117.2,93.78 CPU1.C33
USB3_PTX_CRX_N0_C: length 13.1
  BOTTOM w0.127: v1(17.25,40.16) 17.25,40.32 ; 17.25,40.32 18.09,40.32 18.21,40.2 U3402.4 U3402.7 20.31,40.2 20.43,40.32 20.62,40.32 20.85,40.09 23.23,40.09 R3409.1 ; 17.25,40.32 16.62,40.32 14.64,42.3 14.11,42.3 13.56,42.85 13.1,42.85 12.97,42.72 USB1.8
USB3_PTX_CRX_N0_R: length 5
  BOTTOM w0.127: 27.12,39.29 27.37,39.29 27.69,39.6 27.69,40.52 C3403.2 ; 27.12,39.29 26.33,39.29 25.61,40.01 24.97,40.01 R3409.2 ; 27.12,39.29 v1(27.12,39.07)
USB3_PTX_CRX_P0: length 132.9
  L4 w0.114: v2(24.52,41.53) 24.5,41.53 24.19,41.84 24.03,41.84 23.3,42.57 23.3,53.19 25.9,55.79 25.9,56.43 27.28,57.8 27.28,60.82 29.28,62.82 35.54,62.82 37.1,64.37 39.4,64.37 45.59,70.56 72.67,70.56 88.62,86.52 89.91,86.52 91.55,88.17 92.8,88.17 94.44,89.8 97.87,89.8 98.2,90.13 98.2,90.21 99.34,91.35 100.74,91.35 101.42,92.03 103.84,92.03 104.3,92.48 105.87,92.48 108.43,95.04 114.97,95.04 116.21,96.28 117.46,96.28 v2(117.48,96.31)
  BOTTOM w0.127: v2(117.48,96.31) 117.2,96.03 117.08,96.03 116.82,95.77 CPU1.B34 ; 25.46,41.76 24.75,41.76 v2(24.52,41.53) ; 25.46,41.76 25.68,41.76 26.3,42.37 26.8,42.37 27.06,42.11 27.06,41.67 C3404.1 ; 25.46,41.76 v1(25.46,41.61)
USB3_PTX_CRX_P0_C: length 12.9
  BOTTOM w0.127: USB1.9 12.97,43.22 13.1,43.09 13.66,43.09 14.21,42.54 14.74,42.54 16.72,40.56 18.09,40.56 18.21,40.68 U3402.5 U3402.6 20.31,40.68 20.43,40.56 20.72,40.56 20.95,40.33 22.23,40.33 ; 22.23,40.33 v1(22.23,40.49) ; 22.23,40.33 23.26,40.33 R3408.1
USB3_PTX_CRX_P0_R: length 5
  BOTTOM w0.127: v1(25.97,40.19) 25.87,40.09 ; 25.87,40.09 25.71,40.25 24.84,40.25 R3408.2 ; 25.87,40.09 26.43,39.53 27.27,39.53 27.45,39.7 27.45,39.98 27.34,40.09 27.02,40.09 26.89,40.22 C3404.2
USB20_VCCA: length 10.4
  TOP w0.635: 188.45,32.82 186.52,32.82 185.27,34.07 185.27,38.27 v2(185.25,38.3)
  BOTTOM w0.508: v2(185.25,38.3) 185.03,38.51 C3406.1 185.42,39.42 EU3404.5
  vias: v3(193.43,34.12) v3(193.45,33.1) v3(194.39,34.12) v3(194.42,33.1)
USB30_VCCC: length 12.1
  TOP w0.508: v2(23.27,38.87) 23.27,38.49 22.85,38.07 EU3403.5
  TOP w0.635: USB1.1 14.47,44.18 ; USB1.1 14.47,42.76 ; USB1.1 15.18,43.47
  L3 w0.508: v2(23.27,38.87) 22.12,40.03 22.12,43.61 22.74,44.24 v2(22.74,44.87)
  BOTTOM w0.635: 14.47,44.18 USB1.1 15.18,43.47
  vias: v1(23.88,42.94) v2(17.63,44.83) v3(17.74,43.67) v3(21.94,44.95)
USB_CAMERA_EDP: length 6.3
  TOP w0.127: LCD1.31 79.2,161.82 79.31,161.93 81.29,161.93 81.59,161.62 ; 81.59,161.62 v1(81.49,161.52) ; 81.59,161.62 82.88,160.34 83.45,160.34 R5217.1
USB_CAMERA_EDP#: length 6.3
  TOP w0.127: 80.55,162.17 v1(80.55,162.31) ; 80.55,162.17 81.39,162.17 82.98,160.58 83.45,160.58 R5216.1 ; 80.55,162.17 79.39,162.17 79.24,162.32 LCD1.30
USB_COMP: length 2.6
  TOP w0.127: v2(131.04,79.28) 131,79.28 130.54,79.74 130.54,79.74 v1(130.51,79.76)
  TOP w0.508: v2(131.04,79.28) 130.92,79.15 R1602.1
  BOTTOM w0.305: CPU1.AJ11 130.73,78.96 v2(131.04,79.28) 131.36,78.96 CPU1.AJ10
USB_OC#0_1: length 315
  TOP w0.102: v2(148.54,81.54) 148.03,81.54 147.05,80.56 147.05,79.86 147.92,78.99 R3501.2
  L3 w0.102: v2(180.71,36.08) 179.25,36.08 178.63,35.46 178.63,31.18 167.06,19.62 167.06,16.38 165.77,15.09 165.77,7.85 162.7,4.78 76.75,4.78 76.43,5.11 71.66,5.11 71.33,4.78 51.2,4.78 45.85,10.14 37.57,10.14 37.26,10.44 31.95,10.44 30.77,11.62 23.34,11.62 22.05,12.91 22.05,15.07 20.61,16.51 20.61,17.83 18.47,19.97 18.47,24.53 18,25 18,35.45 16.89,36.56 16.89,45.37 v2(17.81,46.29)
  L4 w0.102: v2(148.54,81.54) 148.54,81.6 148.91,81.97 150.31,81.97 151.14,81.13 152.41,81.13 154,79.53 154,78.09 155.81,76.28 157.8,76.28 159.23,74.85 162.88,74.85 163.77,73.96 163.77,73.36 165.74,71.4 165.74,70.15 166.14,69.75 166.14,69.74 166.35,69.53 166.35,69.07 167.19,68.23 167.65,68.23 168.81,67.07 168.81,65.92 168.76,65.87 168.76,65.16 169.86,64.06 169.86,56.04 172.37,53.52 172.63,53.52 174.17,51.98 174.17,50.44 179.44,45.17 179.44,37.36 v2(180.71,36.08)
  BOTTOM w0.089: CPU1.AL3 136.06,77.84 137.34,77.84 137.47,77.97 138.06,77.97
  BOTTOM w0.102: v2(17.81,46.29) 18.48,45.62 22.7,45.62 22.71,45.61 22.73,45.61 22.75,45.6 22.76,45.6 22.8,45.56 23.1,45.56 23.83,46.29 U3504.3 ; 138.06,77.97 138.35,77.97 138.74,77.58 138.74,77.4 139.2,76.93 141.33,76.93 141.81,77.41 143.57,77.41 144.9,78.74 146.61,78.74 v1(147.33,79.46) 148.31,80.44 148.31,81.31 v2(148.54,81.54) 149.07,82.07 RN1809.7
USB_OC#2_3: length 135.6
  TOP w0.102: v1(176.35,31.47) 176.7,31.12 v2(176.7,30.89) ; v2(150.59,72.82) 149.54,73.87 148.29,73.87 146.87,75.29 v2(146.05,75.29) 146.05,75.77 147.92,77.64 R3501.1
  L3 w0.102: v2(200.4,18.53) 200.4,18.74 200.74,19.08 200.74,31.68 196.98,35.44 196.98,36.81 195.94,37.85 194.44,37.85 193.96,37.37 193.96,36.99 193.73,36.76 193.3,36.76 192.92,37.14 192.56,37.14 192.44,37.02 182.42,37.02 182.03,37.41 179.12,37.41 177.74,36.03 177.74,31.93 v2(176.7,30.89)
  L4 w0.102: v2(176.7,30.89) 177.38,31.57 177.38,40.46 176.95,40.89 176.44,40.89 159.33,58 159.33,63.18 160.34,64.18 160.34,67.77 159.53,68.57 156.35,68.57 155.79,69.14 155.79,70.76 155.27,71.28 152.76,71.28 151.19,72.85 150.62,72.85 v2(150.59,72.82)
  BOTTOM w0.102: CPU1.AT1 137.44,75.09 137.63,74.9 137.95,74.9 139.01,73.84 139.71,73.84 140.84,74.97 142.36,74.97 143.36,75.97 144.7,75.97 144.84,76.1 145.2,76.1 146.01,75.29 v2(146.05,75.29) 146.51,74.83 148.15,74.83 148.29,74.97 150.47,74.97 151.13,75.62 151.13,76 152.23,77.11 RN1601.8 ; U3505.3 199.64,19.43 200.4,18.67 v2(200.4,18.53)
USB_OC#4_5: length 24.4
  L3 w0.102: v2(148.78,82.71) 148.78,82.92 149.52,83.66 150.13,83.66 150.83,82.95 153.89,82.95 154.17,82.67 155.35,82.67 v2(155.62,82.93)
  BOTTOM w0.089: CPU1.AH2 136.75,79.91 137.26,79.91 137.37,79.8 139.22,79.8 139.35,79.66
  BOTTOM w0.102: 139.35,79.66 139.56,79.46 141.15,79.46 141.32,79.28 142.53,79.28 142.82,78.98 144.52,78.98 144.85,79.3 v1(145.88,79.3) 147.74,81.16 147.74,81.66 v2(148.78,82.71) ; RN2012.6 155.19,82.5 v2(155.62,82.93)
USB_OC#6_7: length 19.2
  BOTTOM w0.089: 137.43,73.31 137.29,73.44 136.6,73.44 136.59,73.45 136.27,73.45 135.94,73.78 CPU1.AV3
  BOTTOM w0.102: RN1601.7 151.87,76.45 151.33,75.91 151.33,75.54 150.28,74.49 v1(149.6,74.49) 143.69,74.49 142.12,72.92 137.82,72.92 137.43,73.31
USB_PN0: length 145.4
  TOP w0.127: v2(25.37,34.88) 25.2,35.05 25.2,35.41 24.84,35.78 24.62,35.78 ; 24.62,35.78 23.86,35.78 23.41,35.34 TR3404.1 ; 24.62,35.78 v1(24.62,35.92)
  L4 w0.114: v2(132.42,76.36) 132.42,76.57 132.31,76.68 131.76,76.68 131.42,77.02 131.42,79.03 131.47,79.08 131.47,80.13 130.85,80.75 127.18,80.75 126.59,81.35 124.59,81.35 124.53,81.41 124.1,81.84 120.22,81.84 119.92,82.14 99.36,82.14 98.27,83.23 91.84,83.23 90.78,82.17 88.21,82.17 74.51,68.47 46.2,68.47 40.3,62.57 37.79,62.57 26.54,51.32 26.54,36.72 25.24,35.42 25.24,35.01 v2(25.37,34.88)
  BOTTOM w0.127: v2(132.42,76.36) 132.7,76.36 132.81,76.47 CPU1.AN8
USB_PN0_C: length 12.2
  TOP w0.127: 16.63,40.03 15.41,40.03 USB1.2 ; 16.63,40.03 16.81,40.03 17.12,39.71 17.12,38.22 17.2,38.14 17.44,38.14 18.32,39.02 EU3403.1 19.67,39.02 20.35,38.34 20.35,37.2 20.57,36.98 20.57,36.07 TR3404.2 ; 16.63,40.03 AFTP3402.1
USB_PN1: length 77.9
  L4 w0.114: v2(133.77,76.04) 134.2,75.6 134.2,75.11 134.47,74.85 135.64,74.85 137.45,73.04 141.97,73.04 143.56,74.64 146.39,74.64 148.9,72.13 148.9,68.45 149.55,67.81 159.21,67.81 159.57,67.45 159.57,64.61 158.85,63.89 158.54,63.58 158.54,57.7 176.22,40.02 176.22,39.7 v2(176.42,39.5)
  BOTTOM w0.127: 177.91,40.58 v1(177.91,40.44) ; 177.91,40.58 182.55,40.58 182.8,40.33 TR3405.4 ; 177.91,40.58 176.52,40.58 176.14,40.2 176.14,39.68 176.32,39.5 v2(176.42,39.5) ; CPU1.AR7 133.7,76.04 v2(133.77,76.04)
USB_PN1_C: length 12.6
  TOP w0.127: CN6301.3 190.49,42.77 190.1,42.38 188.45,42.38 187.81,41.74 187.81,41.32 ; 187.81,41.32 187.81,40.57 v2(187.61,40.37) ; 187.81,41.32 AFTP6301.1
  BOTTOM w0.127: TR3405.3 184.8,40.55 185.29,40.55 186.39,41.65 187.49,41.65 187.64,41.5 187.64,41.12 187.51,40.99 186.67,40.99 186.53,40.85 EU3404.6 v2(187.61,40.37)
USB_PN2: length 76.9
  L4 w0.114: v2(174.71,37.23) 174.92,37.44 174.92,38.16 174.3,38.78 174.3,40.52 157.54,57.29 157.54,58.25 157.54,58.25 157.54,62.42 155.44,64.52 150.96,64.52 150.88,64.44 150.27,64.44 149.82,64.9 149.82,66.13 148.19,67.76 148.18,67.76 147.91,68.03 147.91,71.72 145.99,73.64 143.97,73.64 142.39,72.06 137.05,72.06 137.05,72.06 135.92,72.06 133.95,74.03 133.95,74.1 133.08,74.98 v2(132.44,74.98)
  BOTTOM w0.127: CPU1.AR8 132.81,75.21 132.58,74.98 v2(132.44,74.98) ; 176.06,38.04 175.25,38.04 175,37.79 175,37.53 v2(174.71,37.23) ; 176.06,38.04 177.27,38.04 178.3,37 181.95,37 182.17,37.22 TR3406.1 ; 176.06,38.04 v1(176.06,38.21)
USB_PN2_C: length 14.2
  TOP w0.127: 187.61,37.9 v2(187.61,38.47) ; 187.61,37.9 187.61,37.66 188.06,37.21 188.82,37.21 189.07,37.47 189.07,38.98 189.24,39.15 190.32,39.15 190.7,38.77 CN6301.7 ; 187.61,37.9 AFTP6303.1
  BOTTOM w0.127: v2(187.61,38.47) EU3404.4 186.53,37.96 186.67,37.82 187.61,37.82 187.74,37.69 187.74,37.31 187.43,37 184.71,37 184.49,37.22 TR3406.2
USB_PN3: length 1.1
  TOP w0.127: v2(131.85,76.04) 131.88,76.06 TP1601.1
  BOTTOM w0.127: CPU1.AR10 131.52,75.71 v2(131.85,76.04)
USB_PN4: length 137.9
  TOP w0.127: R5216.2 84.89,160.63 85.23,160.63 85.38,160.79 85.96,160.79 ; 85.96,160.79 86.69,160.79 v2(86.81,160.9) ; 85.96,160.79 v1(85.96,160.94)
  L3 w0.114: v2(128.48,77.73) 128.22,77.73 126.78,79.17 125.96,79.17 125.22,79.91 123.2,79.91 122.14,80.97 117.18,80.97 117.13,80.92 102.19,80.92 101.94,81.16 97.84,81.16 97.64,81.36 95.69,81.36 95.26,81.79 87.62,81.79 85.39,84.02 85.39,96.94 88.57,100.12 88.57,102.08 90.14,103.65 90.14,104.89 92.92,107.67 92.92,116.67 92.92,116.86 99.3,123.24 99.3,131.62 94.52,136.4 94.52,141.67 89.35,146.85 89.35,151.86 86.62,154.58 86.62,158.43 85.9,159.15 85.9,160.62 86.15,160.87 86.77,160.87 v2(86.81,160.9)
  BOTTOM w0.127: v2(128.48,77.73) 128.58,77.73 CPU1.AM15
USB_PN5: length 44.8
  TOP w0.127: v2(130,78.03) 129.88,78.03 129.32,77.47 129.32,77.28 v1(129.32,77.28)
  L3 w0.114: v2(149.98,69.78) 149.77,69.99 148.7,69.99 146.33,67.61 143.85,67.61 138.76,72.7 132.97,72.7 132.27,73.4 131.48,73.4 130.89,73.99 130.89,74.32 129.82,75.39 129.68,75.39 129.08,75.99 129.08,77.8 129.31,78.03 v2(130,78.03)
  BOTTOM w0.127: v2(130,78.03) 129.91,78.03 CPU1.AM13 ; v2(149.98,69.78) 150.07,69.78 150.46,69.39 150.46,68.65 151.55,67.56 159.14,67.56 159.25,67.45 159.25,65.41 159.14,65.29 159.14,64.08 R5801.2
USB_PN5_R: length 6.8
  TOP w0.127: v2(161.3,61.76) 160.82,61.76 AFTP5806.1
  BOTTOM w0.127: WLAN1.5 161.84,62.02 161.74,62.12 161.5,62.12 161.3,61.92 v2(161.3,61.76) 161.01,62.05 160.83,62.05 160.19,61.41 159.54,61.41 159.2,61.75 159.2,62.41 R5801.1
USB_PN6: length 140
  TOP w0.127: R5203.2 85.94,157.91 86.51,157.91 86.89,157.53 86.89,153.31 90.63,149.56 91.6,149.56 92.67,148.49 92.67,147.95 ; 92.67,147.95 92.67,147.52 92.39,147.24 v2(92.39,146.92) ; 92.67,147.95 v1(92.82,147.95)
  L3 w0.114: v2(92.39,146.92) 92.24,146.77 92.24,145.37 95.66,141.95 95.66,136.65 100.15,132.16 100.28,132.03 100.28,122.8 94.02,116.54 94.02,107.17 93.88,107.04 91.39,104.55 91.39,103.44 89.57,101.62 89.57,99.7 86.37,96.5 86.37,84.42 87.71,83.08 98.15,83.08 98.99,82.24 102.43,82.24 102.73,81.94 122.56,81.94 123.6,80.9 126.64,80.9 127.59,79.96 130.13,79.96 130.76,80.59 131.33,80.59 131.72,80.21 131.72,79.12 131.7,79.1 131.7,79.02 131.55,78.88 131.55,76.65 131.26,76.36 v2(130.5,76.36)
  BOTTOM w0.127: CPU1.AP11 130.83,76.03 v2(130.5,76.36)
USB_PN6_TPNL: length 7.6
  TOP w0.127: LCD1.34 78.97,160.32 79.1,160.19 79.75,160.19 82.06,157.88 82.73,157.88 ; R5203.1 84.33,157.88 82.73,157.88 ; 82.73,157.88 v1(82.73,158.04)
USB_PN7: length 172.8
  L4 w0.114: v2(12.08,8.8) 11.9,8.8 11.69,9.01 11.69,10.82 12.91,12.03 12.91,20.7 27.67,35.46 27.67,51.25 38.25,61.83 40.74,61.83 46.61,67.7 74.91,67.7 88.63,81.42 91.43,81.42 92.48,82.48 97.85,82.48 99.05,81.28 117.19,81.28 117.39,81.09 122.18,81.09 123.27,80 124.96,80 125.68,79.29 126.49,79.29 126.81,79.61 128.47,79.61 128.79,79.28 128.79,78.85 128.93,78.71 129.14,78.5 129.14,77.17 129.52,76.79 129.52,76.45 v2(129.95,76.03)
  BOTTOM w0.127: v2(12.08,8.8) 11.8,8.8 11.72,8.89 11.72,9.38 ; 11.72,9.38 11.72,11.27 R3204.1 ; 11.72,9.38 v1(11.87,9.38) ; v2(129.95,76.03) 129.86,76.03 CPU1.AR13
USB_PN7_R: length 6.1
  BOTTOM w0.127: 12.97,14.04 13.13,14.2 13.13,16.53 13.43,16.83 U3201.2 ; 12.97,14.04 v1(13.06,13.95) ; 12.97,14.04 12.63,13.7 12.18,13.7 11.74,13.26 11.74,13.07 11.74,13.06 R3204.2
USB_PP0: length 145.3
  TOP w0.127: TR3404.4 23.07,34.66 23.6,35.19 ; v2(24.69,34.94) 24.78,34.94 24.96,35.12 24.96,35.31 24.74,35.54 23.96,35.54 23.6,35.19 ; v1(23.71,35.08) 23.6,35.19
  L4 w0.114: v2(24.69,34.94) 24.81,34.94 25.01,35.14 25.01,35.52 26.31,36.82 26.31,51.41 37.7,62.8 40.2,62.8 46.1,68.7 74.42,68.7 88.12,82.4 90.69,82.4 91.74,83.46 98.36,83.46 99.45,82.37 120.02,82.37 120.32,82.07 124.2,82.07 124.69,81.58 126.68,81.58 127.28,80.98 130.94,80.98 131.7,80.23 131.7,78.98 131.65,78.93 131.65,77.12 131.86,76.91 132.18,76.91 v2(132.36,77.09)
  BOTTOM w0.127: v2(132.36,77.09) 132.6,77.33 CPU1.AM8
USB_PP0_C: length 12.1
  TOP w0.127: 16.88,38.34 AFTP3403.1 ; 16.88,38.34 16.88,38.12 17.1,37.9 17.54,37.9 17.77,37.67 17.77,37.27 17.92,37.11 EU3403.3 20.1,37.11 20.33,36.88 20.33,35.97 20.6,35.71 20.6,34.78 20.72,34.66 TR3404.3 ; 16.88,38.34 16.88,39.61 16.71,39.79 14.6,39.79 14.4,39.59 14.4,39.04 USB1.3
USB_PP1: length 77.8
  L4 w0.114: v2(133.77,75.39) 133.97,75.18 133.97,75.02 134.37,74.62 134.56,74.62 135.55,74.62 137.36,72.81 142.06,72.81 143.66,74.41 146.3,74.41 148.67,72.03 148.67,68.36 149.45,67.58 159.12,67.58 159.34,67.35 159.34,64.7 158.76,64.12 158.31,63.67 158.31,57.8 158.31,57.61 175.99,39.93 175.99,39.63 175.84,39.48 v2(175.72,39.48)
  BOTTOM w0.127: v2(175.72,39.48) 175.9,39.66 175.9,40.3 176.42,40.82 176.72,40.82 ; 176.72,40.82 182.61,40.82 182.8,41.01 TR3405.1 ; 176.72,40.82 v1(176.72,40.95) ; v2(133.77,75.39) 133.77,75.06 133.7,74.98 133.45,74.98 CPU1.AT7
USB_PP1_C: length 12.6
  TOP w0.127: 189.36,42.14 188.55,42.14 188.05,41.64 188.05,40.57 v2(188.25,40.37) ; 189.36,42.14 190.2,42.14 190.58,41.77 CN6301.4 ; 189.36,42.14 AFTP6302.1
  BOTTOM w0.127: TR3405.2 184.8,40.79 185.19,40.79 186.29,41.89 187.59,41.89 187.88,41.6 187.88,41.21 188,41.09 188.94,41.09 189.22,40.81 EU3404.1 v2(188.25,40.37)
USB_PP2: length 77
  L4 w0.114: v2(132.4,75.72) 132.91,75.21 133.17,75.21 134.18,74.2 134.18,74.12 136.01,72.29 137.14,72.29 142.3,72.29 143.87,73.87 146.08,73.87 148.13,71.82 148.13,68.13 148.27,67.99 148.28,67.99 150.05,66.22 150.05,65 150.37,64.67 150.79,64.67 150.86,64.75 155.53,64.75 157.77,62.51 157.77,58.02 157.77,58.02 157.77,57.38 174.53,40.62 174.53,38.87 175.15,38.26 175.15,37.47 v2(175.38,37.24)
  BOTTOM w0.127: TR3406.4 182.17,36.54 181.95,36.76 178.2,36.76 177.5,37.47 ; 177.5,37.47 v1(177.36,37.33) ; 177.5,37.47 177.17,37.8 175.35,37.8 175.25,37.69 175.25,37.37 v2(175.38,37.24) ; CPU1.AP8 132.5,75.72 v2(132.4,75.72)
USB_PP2_C: length 14.2
  TOP w0.127: 189.37,39.39 189.14,39.39 188.83,39.08 188.83,37.57 188.72,37.45 188.16,37.45 187.85,37.76 187.85,38.07 v2(188.26,38.47) ; 189.37,39.39 AFTP6304.1 ; 189.37,39.39 190.32,39.39 190.7,39.77 CN6301.6
  BOTTOM w0.127: v2(188.26,38.47) EU3404.3 189.22,38.03 189.01,37.82 188.16,37.82 187.98,37.64 187.98,37.21 187.53,36.76 184.71,36.76 184.49,36.54 TR3406.3
USB_PP3: length 1.1
  TOP w0.127: TP1602.1 131.88,75.31 v2(131.89,75.32)
  BOTTOM w0.127: CPU1.AT10 131.63,75.06 v2(131.89,75.32)
USB_PP4: length 138.2
  TOP w0.127: R5217.2 85.02,160.39 85.33,160.39 85.48,160.55 86.53,160.55 v2(86.81,160.27) 86.81,160.18 v1(86.39,159.77)
  L3 w0.114: v2(128.45,78.39) 128.45,78.29 128.27,78.11 128.16,78.11 126.87,79.4 126.05,79.4 125.31,80.14 123.29,80.14 122.24,81.2 117.08,81.2 117.03,81.15 102.28,81.15 102.04,81.39 97.93,81.39 97.74,81.59 95.79,81.59 95.36,82.02 87.72,82.02 85.62,84.11 85.62,96.84 88.8,100.02 88.8,101.98 90.37,103.55 90.37,104.8 93.15,107.58 93.15,116.76 99.4,123.01 99.53,123.15 99.53,131.72 94.75,136.5 94.75,141.77 89.58,146.94 89.58,151.95 86.85,154.68 86.85,158.52 86.13,159.24 86.13,160.52 86.24,160.64 86.45,160.64 86.81,160.28 v2(86.81,160.27)
  BOTTOM w0.127: v2(128.45,78.39) 128.86,78.39 128.97,78.28 CPU1.AL15
USB_PP5: length 44.3
  L3 w0.114: v2(150.79,69.78) 150.6,69.78 150.16,70.21 148.61,70.21 146.23,67.84 143.95,67.84 138.86,72.93 133.06,72.93 132.36,73.63 131.57,73.63 131.12,74.08 131.12,74.41 129.92,75.62 129.78,75.62 129.31,76.08 129.31,77.71 129.41,77.8 129.65,77.8 129.98,77.47 v2(129.98,77.39)
  BOTTOM w0.127: 159.49,65.92 159.49,67.55 159.24,67.8 151.65,67.8 150.7,68.75 150.7,69.69 v2(150.79,69.78) ; 159.49,65.92 159.49,65.31 159.38,65.19 159.38,64.14 R5802.2 ; 159.49,65.92 v1(159.65,65.92) ; CPU1.AN13 129.49,77.01 129.42,77.07 129.42,77.21 129.55,77.34 129.67,77.34 129.71,77.39 v2(129.98,77.39)
USB_PP5_R: length 6.9
  TOP w0.127: v2(161.25,62.5) 160.96,62.5 160.54,62.92 AFTP5807.1
  BOTTOM w0.127: R5802.1 159.44,62.48 159.44,61.85 159.64,61.65 160.09,61.65 160.73,62.29 161.04,62.29 v2(161.25,62.5) 161.35,62.4 161.78,62.4 161.91,62.52 WLAN1.3
USB_PP6: length 139.9
  TOP w0.127: R5204.2 85.59,157.48 85.77,157.66 86.41,157.66 86.65,157.43 86.65,153.21 90.53,149.32 90.89,149.32 ; 90.89,149.32 91.5,149.32 92.43,148.39 92.43,147.62 v2(91.75,146.94) ; 90.89,149.32 v1(90.89,149.16)
  L3 w0.114: v2(91.75,146.94) 92.01,146.68 92.01,145.27 95.43,141.85 95.43,136.55 100.05,131.93 100.05,122.9 93.79,116.64 93.79,107.27 91.16,104.64 91.16,103.53 89.34,101.71 89.34,99.8 86.14,96.59 86.14,84.33 86.99,83.48 87.62,82.85 98.06,82.85 98.89,82.01 102.34,82.01 102.64,81.72 122.46,81.72 123.5,80.67 126.55,80.67 127.49,79.73 130.22,79.73 130.36,79.87 130.85,80.36 131.24,80.36 131.49,80.11 131.49,79.21 131.47,79.19 131.47,79.12 131.46,79.11 131.32,78.97 131.32,76.75 131.17,76.59 130.85,76.59 130.5,76.94 v2(130.5,77.01)
  BOTTOM w0.127: CPU1.AN11 130.77,76.68 130.5,76.95 v2(130.5,77.01)
USB_PP6_TPNL: length 7.6
  TOP w0.127: LCD1.35 79.03,159.82 79.15,159.95 79.65,159.95 80.66,158.94 ; 80.66,158.94 81.96,157.64 84.3,157.64 R5204.1 ; 80.66,158.94 v1(80.52,158.79)
USB_PP7: length 172.4
  L4 w0.114: v2(129.95,76.69) 129.37,77.26 129.37,78.6 129.02,78.94 129.02,79.38 128.56,79.84 126.72,79.84 126.4,79.52 125.77,79.52 125.06,80.23 123.36,80.23 122.28,81.31 117.48,81.31 117.29,81.51 117.1,81.51 99.14,81.51 97.95,82.71 92.39,82.71 91.33,81.65 88.54,81.65 74.81,67.93 46.52,67.93 40.64,62.05 38.16,62.05 27.45,51.34 27.45,35.56 12.68,20.79 12.68,12.13 11.46,10.91 11.46,8.99 v2(11.27,8.8)
  BOTTOM w0.127: 11.47,10.47 11.47,11.43 R3205.1 ; 11.47,10.47 v1(11.31,10.47) ; 11.47,10.47 11.47,9 v2(11.27,8.8) ; CPU1.AP13 129.87,76.69 v2(129.95,76.69)
USB_PP7_R: length 6.6
  BOTTOM w0.127: 12.89,15.17 12.89,14.3 12.53,13.94 12.28,13.94 12.08,13.94 11.5,13.36 11.5,12.97 11.5,12.96 R3205.2 ; 12.89,15.17 12.89,16.63 13.59,17.33 U3201.3 ; 12.89,15.17 v1(12.68,15.17)
USB_PWR_EN#: length 307.2
  TOP w0.127: v2(175.29,76.33) 175.35,76.27 175.35,75.15 176.52,73.99 KBC24.83
  L3 w0.127: v2(24.33,47.03) 23.13,47.03 21.37,45.27 21.37,38.64 22.71,37.3 22.71,30.14 24.13,28.72 24.13,20.49 26.87,17.75 31.8,17.75 34.82,20.77 39.45,20.77 39.68,20.54 45.33,20.54 48.71,17.17 48.71,15.09 54.8,9 65.77,9 66.12,9.35 91.56,9.35 92.53,8.38 93,7.91 154.92,7.91 155.39,8.38 161.72,14.7 164.4,14.7 166.41,16.72 166.41,19.91 177.98,31.48 177.98,35.92 179.22,37.17 181.93,37.17 182.89,36.21 v2(186.15,36.21) 187.25,36.21 187.37,36.34 192.48,36.34 192.56,36.25 193.58,36.25 194.22,36.89 194.22,37.27 194.55,37.6 195.77,37.6 196.73,36.63 196.73,35.36 200.42,31.67 200.42,19.51 199.94,19.02 199.94,17.62 v2(200.29,17.27)
  L4 w0.127: v2(175.29,76.33) 175.41,76.22 175.69,76.22 176.92,74.99 176.92,73.9 176.92,73.29 177.83,72.38 177.83,70.41 179.04,69.21 179.04,67.3 179.48,66.87 179.48,65.01 178.84,64.37 178.84,62.26 178.82,62.25 178.82,59.73 181.33,57.22 181.33,53.95 183,52.28 183,49.22 183.25,48.97 183.25,44.62 183.67,44.2 183.67,40.72 186.15,38.24 v2(186.15,36.21)
  BOTTOM w0.127: U3504.4 27.41,46.87 27.26,47.03 v2(24.33,47.03) ; v1(175.88,76.33) v2(175.29,76.33) 174.3,75.33 R2412.1 ; v2(200.29,17.27) 200.29,17.73 200.08,17.94 U3505.4
VD1_EN#: length 3.6
  TOP w0.203: KBC24.66 176.33,80.79 175.91,81.21 175.91,81.58 R2449.2
  TOP w0.254: v1(174.71,82.81) 175.39,82.12 R2449.2
VD_IN1: length 93.2
  TOP w0.14: v2(183.93,65.01) 183.6,65.01 183.36,65.25 C2613.1 182.84,65.25 182.56,65.54 182.55,65.54 182.47,65.62 181.97,65.62 181.58,66 181.58,66.41 181.6,66.43 KBC24.104 ; v2(146.43,114.36) 146.01,114.79 143.43,114.79 142.14,116.08 v1(140.28,116.08) 139.33,116.08 138.59,116.82 137.17,116.82 137.16,116.82 133.96,116.82 133.08,115.94 v2(133.08,115.81)
  L4 w0.127: v2(146.43,114.36) 146.99,113.8 146.99,108.21 146.79,108.01 146.79,104.09 150.62,100.27 150.62,99.2 151.33,98.49 151.33,98.48 154.68,95.14 154.68,94.59 155.97,93.29 155.97,93.27 155.97,92.11 157.43,90.65 158.79,90.65 162.85,86.59 166.78,86.59 167.11,86.26 168.72,86.26 173.54,81.45 173.54,79.72 175.76,77.5 175.95,77.5 178.01,75.44 178.01,73.87 178.51,73.37 178.8,73.37 180.94,71.23 181.5,71.23 182.86,69.87 182.86,66.86 183.55,66.16 183.55,65.39 v2(183.93,65.01)
  BOTTOM w0.14: R2608.2 133.18,111.51 R2609.2 C2612.1 133.18,113.78 R2610.1 133.1,114.58 133.1,115.79 v2(133.08,115.81)
VD_IN1_C: length 88.6
  TOP w0.14: v2(133.72,115.79) 134.19,116.26 137.39,116.26 v1(137.4,116.26) 138.33,116.26 139.08,115.52 141.91,115.52 143.2,114.23 v2(145.68,114.23) ; v2(183.88,64.38) 183.82,64.38 182.98,63.54 R2611.1 182.86,63.91 182.9,63.95 C2613.2
  L4 w0.127: v2(183.88,64.38) 183.87,64.38 183.79,64.38 182.99,65.18 182.99,65.96 182.31,66.63 182.31,69.65 181.27,70.69 180.71,70.69 178.58,72.82 178.29,72.82 177.46,73.65 177.46,75.22 175.74,76.94 175.55,76.94 172.93,79.56 172.93,79.87 171.15,81.65 171.15,82.8 168.25,85.7 166.89,85.7 166.55,86.04 161.97,86.04 158.59,89.43 157.94,89.43 157.93,89.43 157.89,89.43 155.43,91.88 155.43,93.05 154.13,94.34 154.13,94.91 150.07,98.97 150.07,100.04 146.25,103.87 146.25,108.23 146.45,108.44 146.45,113.46 v2(145.68,114.23)
  BOTTOM w0.14: v2(133.72,115.79) 133.66,115.73 133.66,114.82 R2610.2 134.07,114.02 C2612.2
VD_OUT1#: length 131.5
  TOP w0.102: v2(129.72,118.37) 129.88,118.37 130.23,118.72 136.42,118.72 137.38,119.68 142.04,119.68 144.92,116.8 v2(144.92,116.57) ; v2(183.47,73.03) 183.47,70.48 184,69.96 KBC24.110 ; v2(186.58,60.68) 185.56,59.66 179.05,59.66 177.35,61.36 175.66,61.36 174.66,62.36 169.98,62.36 169.88,62.26 168.1,62.26 167.24,63.12 167.24,63.99 167.51,64.25 R2612.2
  L4 w0.102: 183.47,73.03 185.09,71.41 185.09,70.22 186.1,69.21 186.1,67.36 186.42,67.04 186.42,65.87 187.14,65.15 187.14,62.47 186.58,61.91 v2(186.58,60.68) ; 183.47,73.03 182.44,74.06 182.44,74.18 182.18,74.43 182.07,74.43 180.33,76.17 180.33,76.18 178.98,77.52 178.02,77.52 175.13,80.41 175.13,81.58 174.15,82.56 173.73,82.56 168.85,87.43 168.04,87.43 v2(167.99,87.38) ; 183.47,73.03 v2(183.47,73.03)
  BOTTOM w0.102: v2(167.99,87.38) 167.95,87.42 162.67,87.42 v1(162.67,87.41) 157.11,87.41 157.1,87.41 154.03,90.49 154.03,92.02 152.92,93.13 152.92,96.07 152.15,96.83 152.15,99.85 150.91,101.1 150.91,102.4 149.89,103.41 149.89,104.93 148.35,106.47 148.35,114.41 145.76,117 145.35,117 v2(144.92,116.57) ; v2(129.72,118.37) 129.43,118.09 R2607.2 129.4,116.68 R2602.2
VGA_CORE: length 24.6
  TOP w0.508: v2(162.73,135.69) 162.84,135.79 C7708.1 ; v2(148.83,150.19) 148.71,150.31 147.7,150.31 147.23,149.84 PR8317.1 ; C7711.1 169.29,135.87 169.29,135.2 v2(169.25,135.16)
  L3 w0.508: v2(148.83,150.19) 148.96,150.33 153.01,150.33 154.46,148.88 156.27,148.88 158.87,146.28 160.31,146.28 160.7,145.89 160.7,144.53 161.61,143.62 161.61,142.49 161.81,142.3
  BOTTOM w0.508: v2(179.32,121.21) 178.82,121.71 EC9755.1
  vias: v1(159.59,119.52) v2(162.71,142.63) v2(162.71,140.72) v2(162.71,138.69) v2(162.71,136.66) v2(164.62,142.63) v2(164.62,140.72) v2(164.62,138.69) v2(164.62,136.66) v2(166.65,142.63) v2(166.65,140.72) v2(166.65,138.69) v2(166.65,136.79) v2(167.63,143.69) v2(168.63,142.63) v2(168.63,140.72) v2(168.68,138.69) v2(168.68,136.66) v3(163.74,128.63) v3(164.64,128.63) v3(165.5,128.63) v3(166.39,128.63) v3(167.28,128.63) v3(167.95,124.4) v3(168.17,128.63) v3(169.06,128.63) v3(180.65,93.6) v3(180.84,96.11) v3(180.75,94.93) v3(180.95,97.55) v3(181.45,115.65) v3(181.57,118.42) v3(181.56,93.6) v3(181.75,96.11) v3(181.77,94.9) v3(181.94,97.47) v3(182.22,103.54) v3(182.2,102.31) v3(182.39,108.21) v3(182.79,94.93) v3(182.95,117.01) v3(182.9,115.58) v3(182.95,97.44) v3(182.93,96.09) v3(183.03,118.47) v3(183.22,110.76) v3(183.24,109.3) v3(183.27,108.17) v3(183.62,103.54) v3(183.6,102.31) v3(183.71,106.96) v3(183.72,105.91) v3(183.8,104.78) v3(183.87,94.92) v3(184.01,96.07) v3(184.12,115.58) v3(184.06,97.5) v3(184.18,118.4) v3(184.21,117.05) v3(184.47,108.19) v3(184.63,109.3) v3(184.75,107.05) v3(184.83,110.81) v3(184.8,105.96) v3(184.82,104.75) v3(184.82,103.44) v3(184.82,102.27) v3(185.23,115.58) v3(185.17,96.04) v3(185.43,116.96) v3(185.43,113.15) v3(185.59,108.35) v3(185.56,99.17) v3(185.6,98.21) v3(185.59,97.22) v3(186.41,116.07) v3(186.57,99.2) v3(186.68,98.28) v3(186.71,97.22)
VGA_CORE_DISCHG: length 3.6
  TOP w0.102: PR8317.2 146.48,147.42 146.11,147.79 PQ8307.D v1(145.02,149)
VGA_CORE_PSI: length 52.8
  TOP w0.127: v2(158.44,123.04) 158.7,122.78 169.9,122.78 171.08,123.96 175.44,123.96 177.58,126.1 177.58,127.5 178.06,127.98 178.06,129.23 177.11,130.17 177.11,130.84 v2(176.45,131.49)
  BOTTOM w0.127: PR8257.1 157.36,102.12 154.13,105.34 154.13,106.69 153,107.82 153,115.64 v1(156.57,119.2) 156.88,119.51 156.88,121.76 158.16,123.04 v2(158.44,123.04) ; v2(176.45,131.49) 176.47,131.49 176.47,131.51 176.11,131.87 GPU1.B4
VGA_CORE_VID: length 44.4
  TOP w0.14: v2(170.52,126.93) 170.74,127.15 170.74,127.48 171.53,128.27 171.84,128.27 173.01,129.45 173.42,129.45 173.62,129.64 173.62,130.82 172.95,131.49 172.95,132.94 v2(173.18,133.17)
  BOTTOM w0.14: v2(170.52,126.93) 170.39,126.93 170.01,126.55 169.49,126.55 169.35,126.4 162.54,126.4 160.08,123.95 160.08,123.53 159.81,123.25 159.4,123.25 157.46,121.31 157.46,119.26 154.01,115.8 v1(154.01,115.03) 154.01,107.63 154.82,106.82 154.82,105.54 155.68,104.68 PR8207.1 ; GPU1.E7 173.21,133.93 173.21,133.2 v2(173.18,133.17)
VGACORE_GND_SENSE_1: length 25.2
  BOTTOM w0.14: PR8220.2 158.19,115.22 v1(158.19,118.82) 158.19,121.13 159.64,122.57 160.09,122.57 160.75,123.23 160.75,123.7 162.8,125.76 169.85,125.76 169.92,125.83 170.21,125.83 171.11,126.73 171.11,127.59 172.75,129.24 GPU1.F1
VGACORE_VDD_SENSE_1: length 26.2
  BOTTOM w0.14: GPU1.F2 173.14,129.88 173.14,129.07 171.5,127.43 171.5,126.57 170.37,125.43 170.08,125.43 170.01,125.36 162.97,125.36 161.14,123.54 161.14,123.06 160.26,122.18 159.8,122.18 158.59,120.97 v1(158.59,120.51) 158.59,115.22 PR8221.2
VIDEO_CLK_XTAL_SS: length 23.6
  L4 w0.127: v2(193.07,130.69) 191.44,130.69 189.88,132.25 180.77,132.25 179.27,133.76 v2(178.86,133.76)
  BOTTOM w0.14: v2(178.86,133.76) 178.86,135.54 177.56,136.85 GPU1.A10 ; v2(193.07,130.69) 193.07,130.71 v1(193.53,131.17) 193.61,131.25 194.14,131.25 194.51,130.89 194.51,130.01 194.23,129.73 R7601.1
VIDEO_THERM_OVERT#: length 4.7
  BOTTOM w0.127: TP7606.1 189.99,125.11 192.19,125.11 192.59,124.71 Q7602.6
VR_SVID_ALERT#: length 92.2
  TOP w0.14: PR4618.2 v2(122.9,141.45) 123.42,141.45 v1(123.67,141.2)
  L3 w0.127: v2(93.24,87.66) 93.23,87.68 93.23,89.73 90.93,92.03 90.93,94.75 93.22,97.04 93.22,104.03 95.7,106.51 95.7,115.48 95.7,115.88 100.99,121.17 101.86,122.04 101.86,132.68 101.12,133.42 101.12,139.16 106.12,144.16 111.64,144.16 113.69,146.21 121.62,146.21 122.08,146.66 122.92,146.66 123.5,146.08 123.5,145.3 123.93,144.88 123.93,142.64 122.9,141.62 v2(122.9,141.45)
  BOTTOM w0.14: v2(93.24,87.66) 92.76,87.66 92.26,87.15 R703.2 92.99,86.86 R701.1
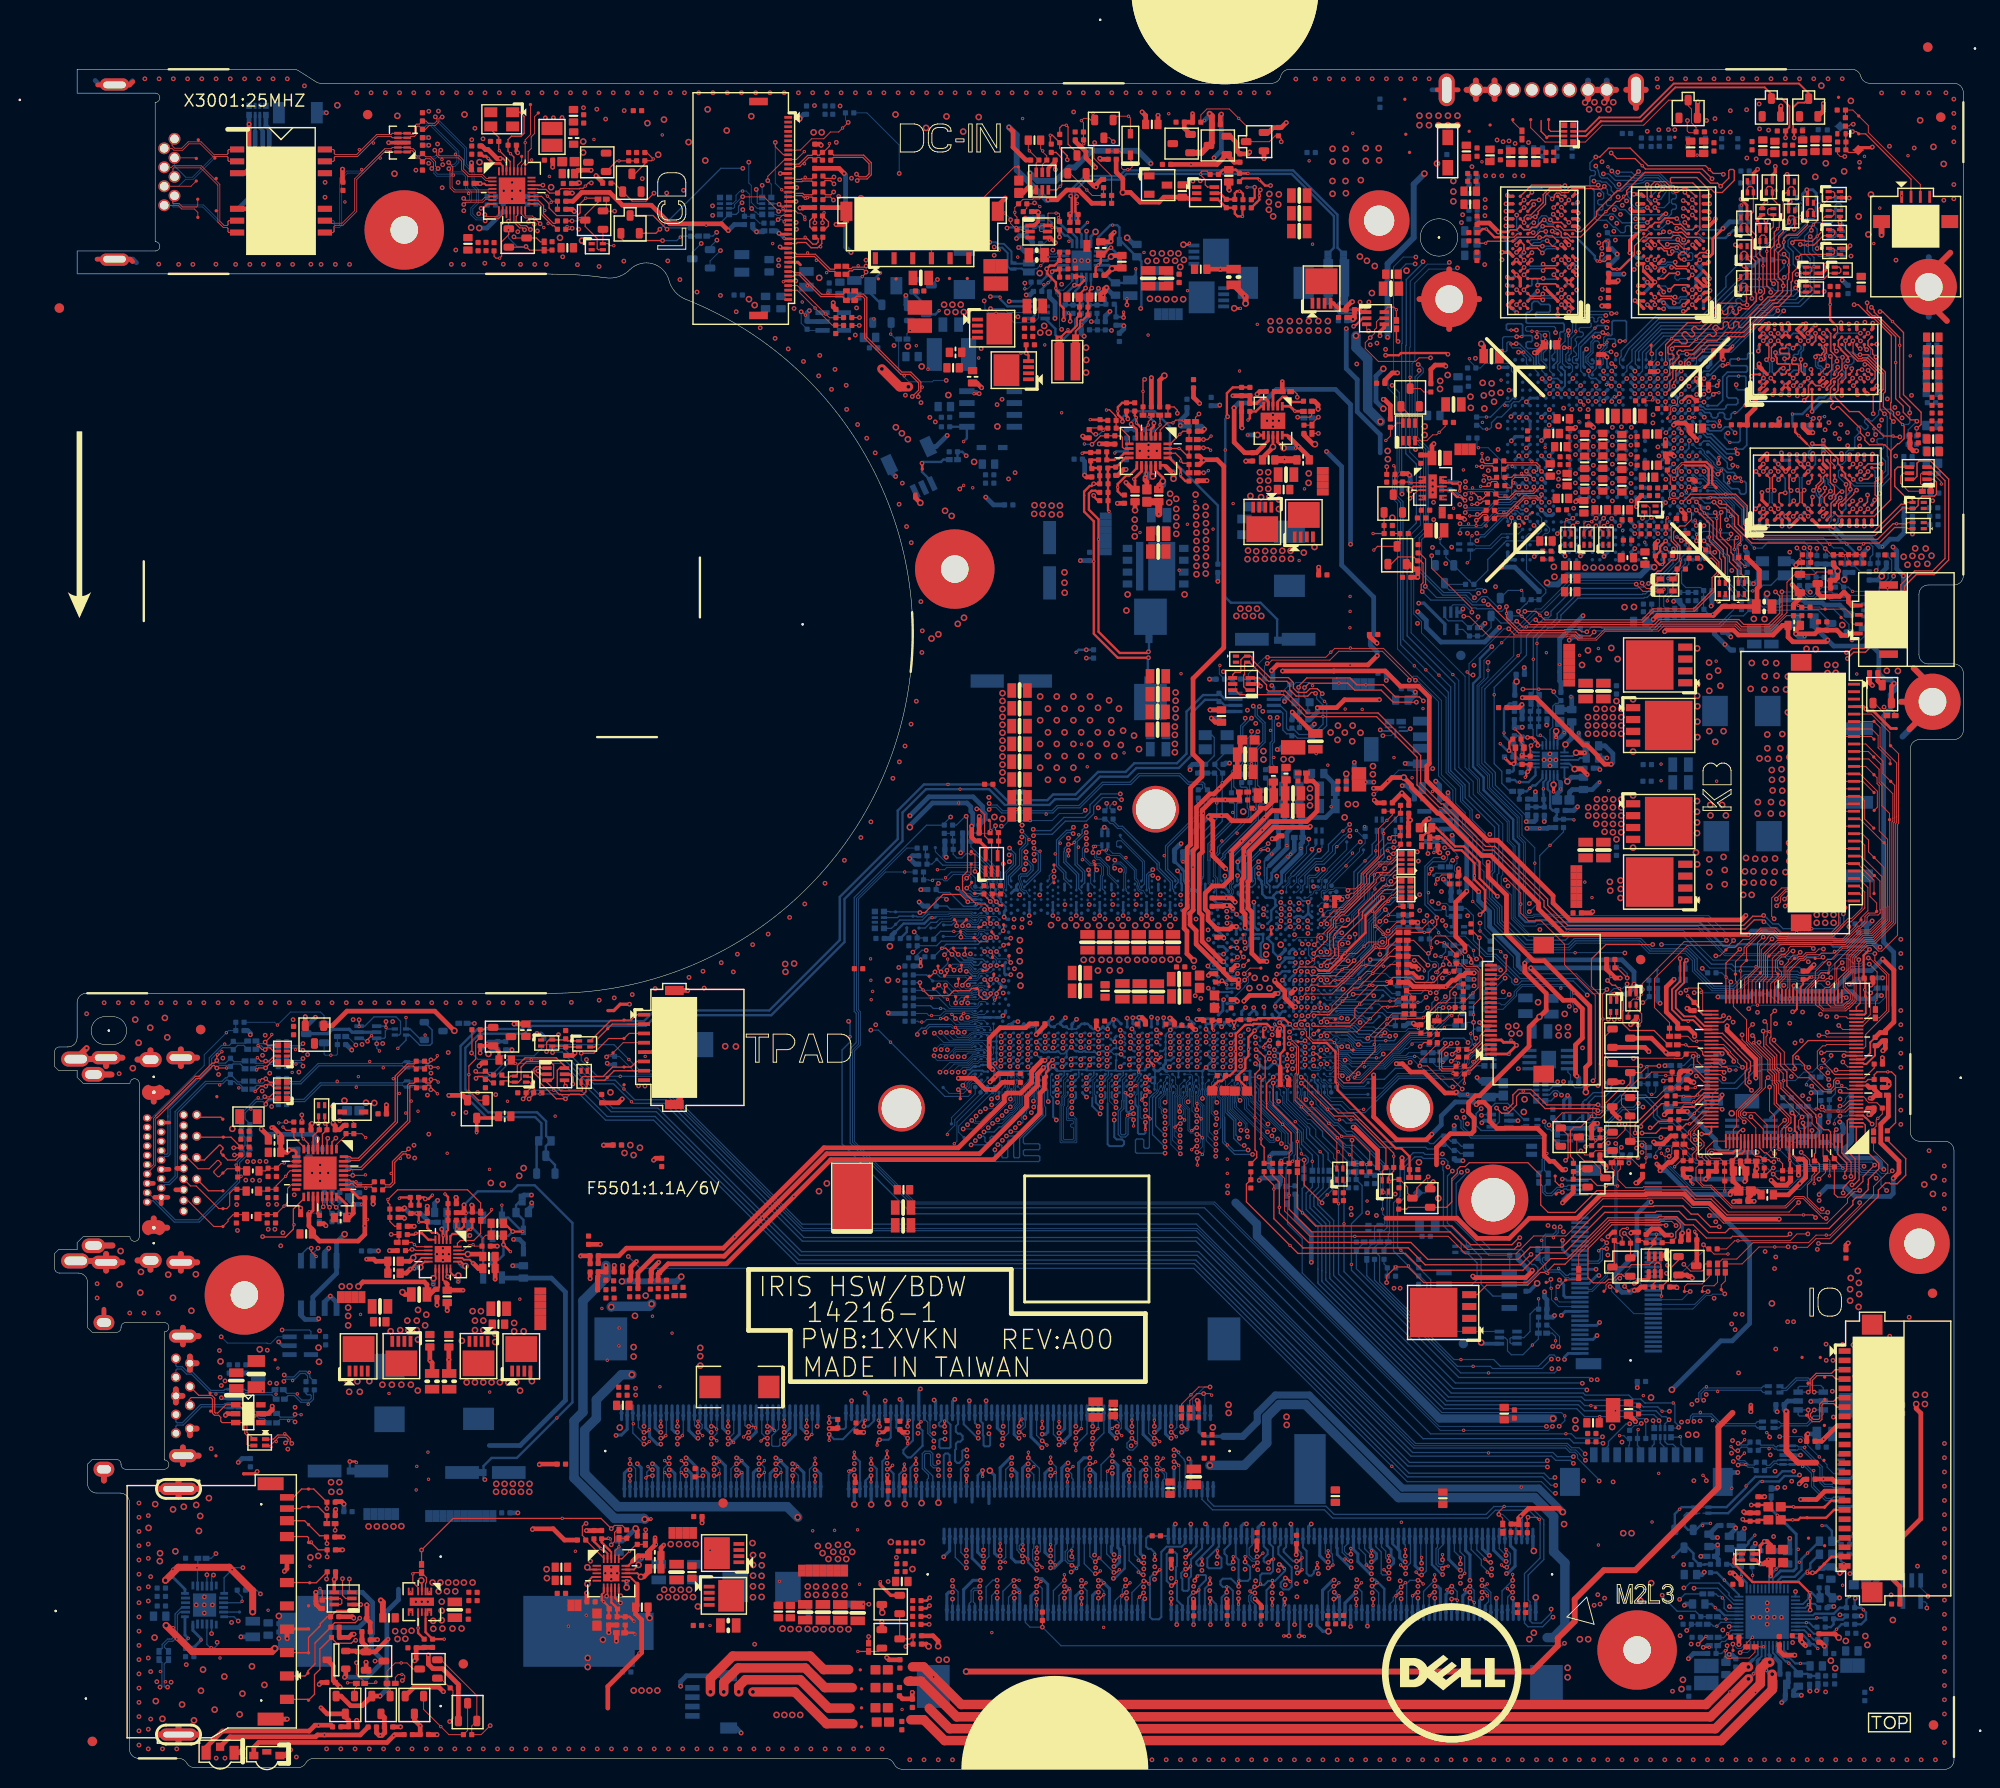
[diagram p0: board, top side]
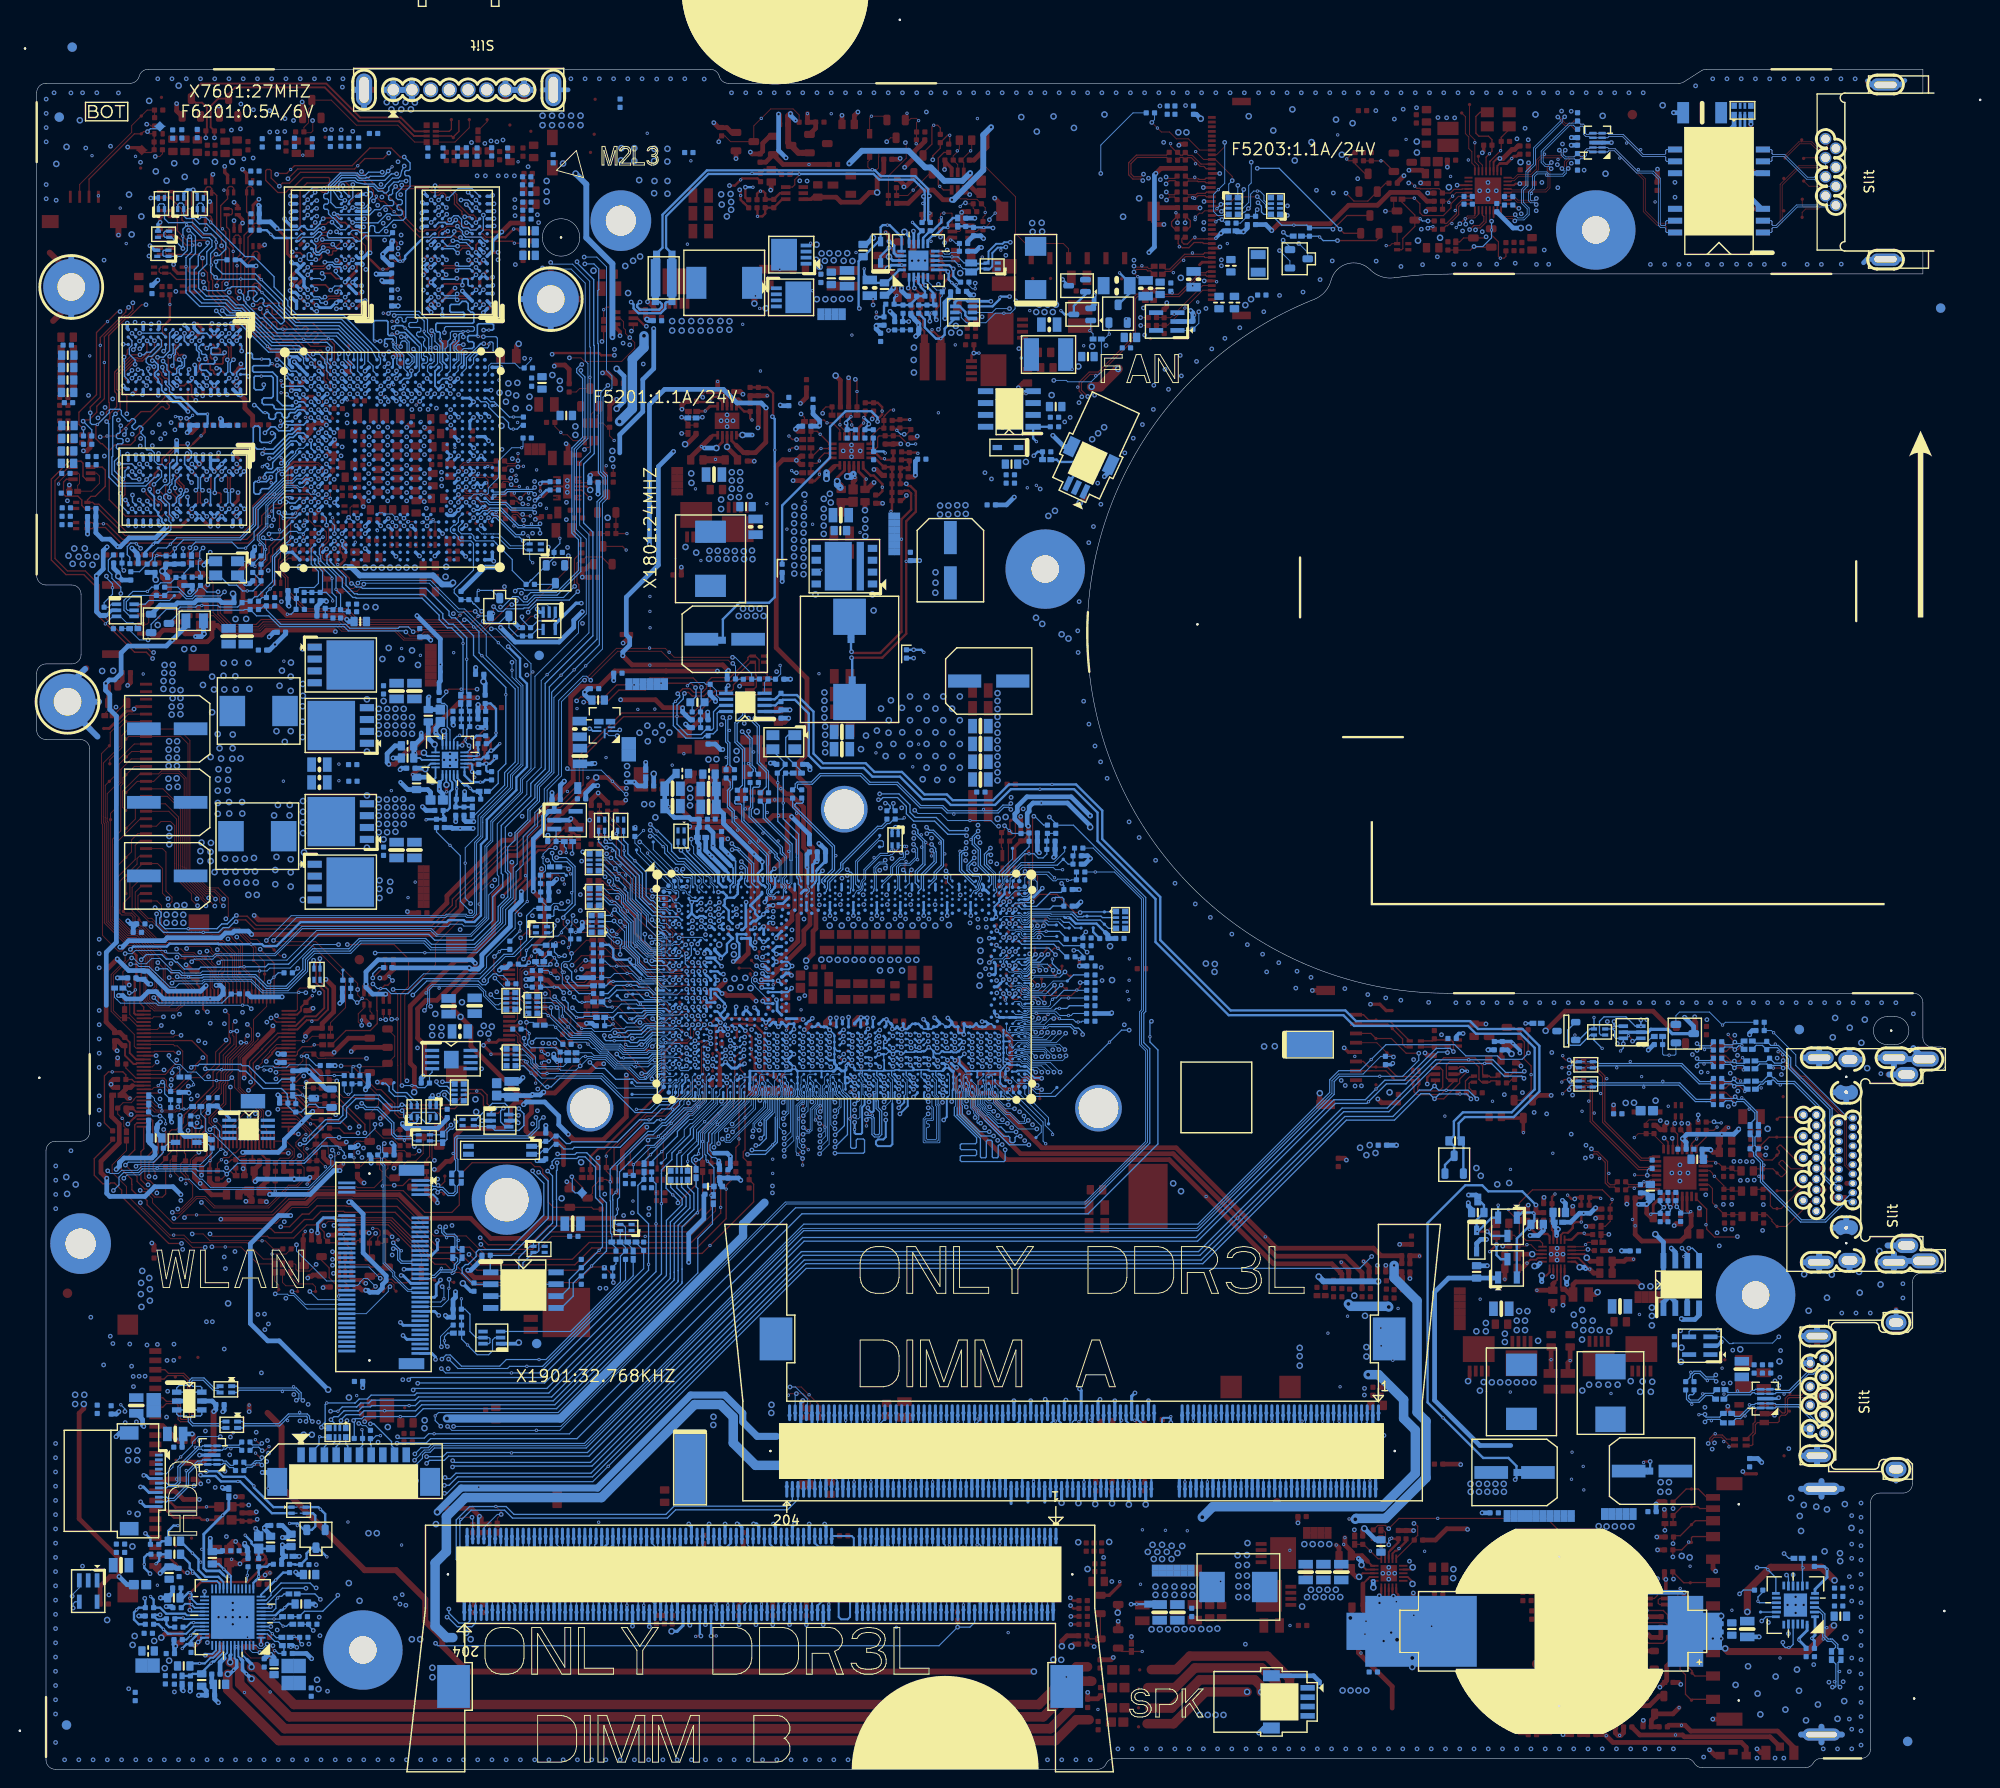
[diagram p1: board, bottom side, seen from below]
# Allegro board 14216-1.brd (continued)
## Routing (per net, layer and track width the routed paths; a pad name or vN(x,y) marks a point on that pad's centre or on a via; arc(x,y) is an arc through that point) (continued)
VRAM_ID1: length 16.1
  TOP w0.102: v2(138.31,93.43) 138.54,93.65 138.56,93.65 138.69,93.78 139,93.78 139.99,94.77 139.99,95.79 141.71,97.52 141.71,97.54 142.19,98.02 v1(142.19,100.16) 142.19,100.55 R2024.1 143.98,102.34 R2023.2
  BOTTOM w0.089: 136.51,93.48 136.6,93.48 136.66,93.55 138.19,93.55 v2(138.31,93.43)
  BOTTOM w0.102: CPU1.E4 135.51,92.74 135.94,92.74 136.16,92.96 136.16,93.14 136.51,93.48
VRAM_ID2: length 14.7
  TOP w0.102: R2034.1 R2033.2 143.11,102.15 v1(142.53,101.57) 141.65,100.69 141.65,97.78 141.49,97.62 141.49,97.59 139.78,95.89 139.78,94.87 139.15,94.24 138.58,94.24 138.36,94.02 v2(138.36,94.09)
  BOTTOM w0.089: CPU1.C3 135.94,93.91 136.07,93.91 136.34,94.18 136.77,94.18 136.94,94.35 138.11,94.35 138.36,94.09 v2(138.36,94.09)
VTT_CT_3VC_1: length 4.9
  TOP w0.203: U8301.10 149.3,136.92
  TOP w0.254: 149.3,136.92 150.03,136.19 150.49,136.19 150.71,135.97 150.74,135.97 v2(150.89,135.82)
  BOTTOM w0.254: v2(150.89,135.82) 150.74,135.97 150.64,135.97 v1(150.34,136.27) 149.67,136.94 C8305.1
VTT_CT_105VC_2: length 3.8
  TOP w0.203: U8301.12 149.44,137.72
  TOP w0.254: 149.44,137.72 149.53,137.62 v2(150.32,137.62) v1(150.32,136.83)
  BOTTOM w0.254: C8316.1 150.12,137.82 v2(150.32,137.62)
WHITE_LED_BAT: length 3.9
  TOP w0.508: Q6102.C 35.27,5.57 EC6103.1 35.31,4.5 35.31,3.92 35.03,3.63 v1(34.84,3.63) 34.71,3.63 34.43,3.92 R6107.2
WIFI_RF_EN: length 30.6
  TOP w0.102: KBC24.82 178.21,74.39 178.6,73.99 v2(178.6,73.91) ; v2(185.45,55.93) 185.43,55.91 v1(184.02,55.91) 182.34,55.91 180.53,54.1 R5805.1
  L4 w0.102: v2(185.45,55.93) 185.15,56.24 185.15,58.96 184.46,59.64 184.46,66.05 183.39,67.12 183.39,70.24 181.86,71.77 181.65,71.77 181.16,71.77 179.02,73.91 v2(178.6,73.91)
WLAN_DISABLE#1: length 11
  TOP w0.102: v2(178.68,50.89) 178.3,51.27 AFTP5803.1 178.3,51.84 178.73,52.28 R5805.2
  BOTTOM w0.102: v2(178.68,50.89) 178.64,50.85 177.36,50.85 177.22,50.71 176.7,50.71 175.26,49.27 WLAN1.56
WLAN_PLT_RST#: length 50.1
  L3 w0.102: v2(135.46,75.5) 137.27,77.3 137.27,77.53 137.75,78.01 140.09,78.01 140.29,77.8 140.67,77.8 142.14,79.28 143.53,79.28 144.99,77.82 147.76,77.82 148.51,77.07 150.48,77.07 150.77,77.36 150.77,78.05 151,78.28 151.35,78.28 153.55,76.08 160.43,76.08 162.72,78.37 v2(162.72,81.24)
  BOTTOM w0.102: v2(162.72,81.24) 162.48,81.48 162.48,81.84 162.36,81.95 162.36,83.1 ; v2(135.46,75.5) 135.46,75.22 135.47,75.21 135.47,74.96 135.29,74.78 134.49,74.78 CPU1.AT5 ; 162.36,83.1 v1(162.53,83.1) ; 162.36,83.1 162.36,83.54 161.89,84.02 156.93,84.02 156.15,83.24 156.15,82.85 155.14,81.83 154.78,81.83 154.61,82 RN2012.7
WLAN_WAKE: length 6.2
  TOP w0.102: v2(160.08,52.46) 159.75,52.13 TP5801.1
  BOTTOM w0.102: v2(160.08,52.46) 160.08,52.33 160.05,52.3 160.05,51.54 v1(160.1,51.49) 160.13,51.46 160.13,50.28 160.89,49.52 WLAN1.55
XCLK_BIASREF: length 5.1
  BOTTOM w0.102: 121.69,94.79 121.69,94.42 121.54,94.27 121.54,93.96 121.84,93.67 CPU1.C26
  BOTTOM w0.305: v1(121.78,96.57) 121.69,96.47 121.69,94.79
  BOTTOM w0.508: R1803.1 121.78,97.93 v1(121.78,96.57)
XDP_BPM0: length 5.1
  TOP w0.14: v2(96.49,90.29) 96.49,90.29 96.49,90.73 96.27,90.94 TP9612.1
  BOTTOM w0.089: v2(96.49,90.29) 96.89,89.89 97.37,89.89 97.57,89.69 98.71,89.69 98.89,89.87 99.48,89.87 99.52,89.83 100.15,89.83 CPU1.J60
XDP_BPM1: length 1.3
  TOP w0.14: TP9613.1 99.95,90.69 v2(100.13,90.52)
  BOTTOM w0.114: CPU1.H60 100.13,90.63 v2(100.13,90.52)
XDP_BPM2: length 7
  BOTTOM w0.089: 94.77,90.61 94.88,90.73 95.94,90.73 96.1,90.89 98,90.89 98.28,90.62 98.62,90.62 98.8,90.79 98.8,90.98 99,91.19 99.54,91.19 CPU1.H61
  BOTTOM w0.14: TP9614.1 94.21,90.05 94.5,90.34 94.77,90.61
XDP_BPM3: length 4.5
  BOTTOM w0.089: CPU1.H62 98.99,90.75 98.99,90.66 98.77,90.44 98.2,90.44 97.93,90.71 96.31,90.71 96.2,90.6
  BOTTOM w0.14: 96.2,90.6 95.98,90.38 TP9615.1
XDP_BPM4: length 1.2
  TOP w0.14: v2(101.48,89.77) 101.53,89.82 TP9616.1
  BOTTOM w0.14: CPU1.K59 101.15,89.44 v2(101.48,89.77)
XDP_BPM5: length 6.6
  BOTTOM w0.089: CPU1.H63 98.25,90.9 97.93,91.23 96.05,91.23 95.85,91.02 95,91.02 95,91.02 94.69,91.02 94.44,90.77 94.44,90.77
  BOTTOM w0.14: 94.44,90.77 94.33,90.66 93.74,90.66 93.13,90.05 TP9617.1
XDP_BPM6: length 1.3
  TOP w0.14: v2(100.77,89.04) 100.26,89.55 TP9618.1
  BOTTOM w0.14: CPU1.K60 100.44,89.37 v2(100.77,89.04)
XDP_BPM7: length 1.3
  TOP w0.14: TP9619.1 99.11,90.15 v2(99.48,90.52)
  BOTTOM w0.114: CPU1.J61 99.79,90.22 v2(99.48,90.52)
XDP_DBRESET#: length 42.2
  TOP w0.14: C9602.1 EC1706.1 167.15,85.8 v2(168.24,84.7)
  L3 w0.127: v2(168.24,84.7) 168.17,84.7 167.75,84.28 167.75,82.95 167.13,82.33 165.86,82.33 164,84.19 161,84.19 160.22,83.41 158.16,83.41 156.79,82.05 153.91,82.05 153.64,82.33 150.6,82.33 149.34,81.07 146.68,81.07 145.19,82.55 141.37,82.55 v2(141.12,82.8)
  BOTTOM w0.089: 137.37,82.37 137.34,82.33 136.06,82.33 CPU1.AC3
  BOTTOM w0.14: R1701.2 167.6,85.82 168.24,85.17 v2(168.24,84.7) ; 137.37,82.37 137.39,82.38 139.15,82.38 139.74,82.97 TP9653.1 140.96,82.97 v2(141.12,82.8)
XDP_PRDY#: length 3.1
  TOP w0.14: v2(97.13,90.29) 97.13,90.53 TP9602.1
  BOTTOM w0.089: v2(97.13,90.29) 97.22,90.29 97.64,89.87 98.63,89.87 98.92,90.15 CPU1.J62
XDP_PREQ#: length 3.1
  TOP w0.14: v2(96.95,89.08) 96.95,89.08 96.95,89.63 TP9601.1
  BOTTOM w0.089: v2(96.95,89.08) 97.1,88.94 98.83,88.94 99.14,89.24 CPU1.K62
XDP_PWR_DEBUG: length 1.4
  BOTTOM w0.254: TP9647.1 91.17,89.63 R9604.2
XDP_RST: length 2.1
  BOTTOM w0.14: TP9654.1 147.76,95.91 149.21,95.91 R9602.1
XDP_SMBCLK: length 4.4
  BOTTOM w0.14: TP9649.1 166.1,73.38 166.1,72.78 165.75,72.43 164.62,72.43 163.84,71.66 163.71,71.66 163.48,71.43 RN9601.3
XDP_SMBDAT: length 4.6
  BOTTOM w0.14: TP9646.1 167.17,73.43 166.87,73.43 166.49,73.05 166.49,72.62 165.91,72.04 164.78,72.04 164.13,71.39 RN9601.4
XDP_SYS_PWROK: length 1.1
  BOTTOM w0.14: R9605.2 171.45,85.53 TP9644.1
XDP_TCK_JTAGX: length 6.9
  BOTTOM w0.089: 95.26,81.33 95.33,81.26 98.19,81.26 98.29,81.16 CPU1.AE63
  BOTTOM w0.14: R1919.1 93.71,81.73 94,81.44 v1(94.78,81.44) 95.15,81.44 95.26,81.33
XDP_TCLK: length 2.7
  TOP w0.14: TP9650.1 99.37,93.75 R406.1 99.42,93.58 v2(100.11,92.89)
  BOTTOM w0.14: v2(100.11,92.89) 100.11,92.86 100.44,92.53 CPU1.E60
XDP_TDI: length 10.1
  BOTTOM w0.089: CPU1.F63 98.26,91.65 98.14,91.77 93.34,91.77 93.29,91.71
  BOTTOM w0.14: RN401.2 90.18,91.17 90.33,91.32 TP9623.1 92.2,91.32 92.27,91.25 92.83,91.25 93.29,91.71
XDP_TDO: length 11.3
  BOTTOM w0.089: CPU1.F62 98.92,91.65 98.63,91.36 98.29,91.36 98.07,91.58 98.05,91.58 95.7,91.58 95.65,91.53 93.58,91.53 93.58,91.53
  BOTTOM w0.14: 93.58,91.53 93.45,91.53 92.82,90.9 90.42,90.9 TP9624.1 89.54,90.02 RN401.4
XDP_TMS: length 12.4
  TOP w0.14: v2(92.57,91.7) 93.1,91.7 95.05,93.65 96.9,93.65 v2(97.69,92.86)
  BOTTOM w0.089: 98.22,92.77 98.78,92.77
  BOTTOM w0.14: RN401.1 89.34,91.82 89.38,91.78 TP9611.1 92.49,91.78 v2(92.57,91.7) ; CPU1.E61 99.5,92.72 99,92.72 98.95,92.77 98.78,92.77 ; v2(97.69,92.86) 97.78,92.77 98.22,92.77
XDP_TRST#: length 3.2
  TOP w0.14: EC402.1 R402.1 100.31,93.32 100.56,93.08 100.56,93.06 v2(100.75,92.86) 101.13,92.49 TP9621.1
  BOTTOM w0.14: CPU1.E59 101.04,92.44 100.75,92.72 v2(100.75,92.86)
XTAL24_IN: length 13.3
  BOTTOM w0.14: R1810.1 R1802.1 124.33,106.38 v1(124.33,103.43) 124.33,102.76 124.33,102.76 124.33,101.74 122.67,100.09 122.67,95.67 122.47,95.47 122.47,95.16 CPU1.A25
XTAL24_IN_R: length 5.6
  BOTTOM w0.14: R1810.2 122.37,106.81 C1801.2 124.06,108.5 124.06,110.44 123.81,110.7 X1801.1
XTAL24_OUT: length 16.7
  BOTTOM w0.14: CPU1.B25 122.71,94.75 122.71,95.27 122.86,95.41 122.86,95.53 122.9,95.57 122.9,97.61 122.92,97.62 122.92,99.48 123.26,99.82 123.26,99.82 124.91,101.47 v1(124.91,105.6) 124.91,106.58 R1802.2 124.94,106.63 124.12,107.45 C1802.2 124.12,107.71 125.44,109.02 X1801.3

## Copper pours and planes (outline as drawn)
3V3_AON_S0 on TOP: 177.91,124.87 177.78,125 177.78,126.39 177.88,126.5 178.98,126.5 179.05,126.57 179.05,128.44 179.18,128.57 179.6,128.57 179.8,128.36 179.8,126.54 179.86,126.49 180.99,126.49 181.08,126.39 181.08,125 180.96,124.87
3V3_AON_S0 on TOP: 182.95,123.64 182.84,123.75 182.84,126.08 183,126.24 183.36,126.24 184.34,125.25 184.34,123.71 184.27,123.64
3V3_AON_S0 on TOP: 172.11,136.94 172.05,137 172.05,137.29 171.86,137.48 171.86,137.48 171.79,137.55 170.95,137.55 170.75,137.75 170.75,138.71 170.85,138.81 172.11,138.81 172.67,138.25 172.67,136.97 172.65,136.94 ; 1 cut-out
3V3_AON_S0 on TOP: 199.18,132.42 199.63,132.87 199.63,135.84 199.7,135.92 201.6,135.92 201.78,135.74 201.78,131.6 201.38,131.2 197.99,131.2 197.31,130.52 196.49,130.52 196.4,130.61 196.4,131.86 196.96,132.42
3V3_AON_S0 on TOP: 159.5,123.21 155.74,126.97 149.39,126.97 147.87,128.49 147.87,129.88 147.12,130.64 147.12,131.16 148.06,132.11 148.06,134.27 148.19,134.4 149.71,134.4 149.95,134.16 149.95,132.08 150.93,131.1 152.69,131.1 153.16,131.57 155.9,131.57 158.74,134.42 159.39,134.42 159.64,134.67 159.64,136.85 159.77,136.98 160.98,136.98 161.2,136.76 161.2,133.97 160.76,133.53 160.76,133.11 159.5,131.84 159.5,127.4 159.25,127.16 159.25,126.26 160.26,125.25 163.96,125.25 164.42,125.71 173.67,125.71 174.18,126.22 174.18,129.8 174.33,129.95 176,129.95 176.13,129.82 176.13,129.37 176.27,129.22 176.27,129.22 177.08,129.22 177.09,129.22 177.19,129.22 177.48,128.93 177.48,128.01 177.12,127.65 177.12,126.23 175.27,124.38 170.91,124.38 169.96,123.42 163.73,123.42 163.52,123.21 ; 16 cut-outs
3V3_AON_S0 on BOTTOM: 146.92,128.17 146.41,128.68 146.41,131.2 146.57,131.35 147.81,131.35 148.19,130.97 148.19,128.4 147.99,128.2 147.99,128.17 ; 1 cut-out
3V3_AON_S0 on BOTTOM: 171.64,122.69 171.39,122.93 171.39,123.58 171.47,123.65 172.78,123.65 172.88,123.55 172.88,123.17 173.03,123.02 174.45,123.02 174.63,123.19 174.63,124.57 174.45,124.74 174.45,125.3 174.53,125.38 175.75,125.38 175.88,125.25 175.88,124.03 176.56,123.35 177.43,123.35 177.65,123.57 177.65,125.63 177.54,125.74 176.96,125.74 176.01,126.69 174.6,126.69 174.23,127.07 174.23,127.95 174.72,128.45 174.72,128.45 174.95,128.68 174.95,128.69 175.43,129.17 175.77,129.17 175.78,129.16 178.07,129.16 178.45,128.78 178.45,126.62 179.05,126.01 179.05,123.89 177.85,122.69 ; 7 cut-outs
3V3_AON_S0 on BOTTOM: 171.69,136.55 171.3,136.94 171.3,138.59 171.43,138.71 172.19,138.71 172.7,138.21 172.7,136.94 172.32,136.55
3V3_AON_S0 on BOTTOM: 159.75,134.52 159.24,135.03 159.24,135.28 160.26,136.3 160.38,136.3 160.64,136.05 160.64,135.03 160.13,134.52
5V_HDD_S0 on TOP: 189.14,36.57 189.14,36.86 189.97,37.69 189.97,37.93 190.05,38 190.51,38 190.6,37.91 190.6,37.43 189.67,36.5 189.21,36.5
5V_HDD_S0 on BOTTOM: 190.03,32.49 189.27,33.25 189.27,36.94 190.03,37.71 190.03,38.52 190.15,38.64 192.33,38.64 192.42,38.55 192.42,37.04 192.35,36.97 192.35,36.21 192.03,35.88 192.03,32.64 191.88,32.49 ; 4 cut-outs
5V_HDMI_CRT_S0 on TOP: 21.18,69 21.02,69.16 21.02,70.49 21.18,70.65 23.05,70.65 23.54,71.14 25.24,71.14 25.89,71.78 31.17,71.78 31.41,71.54 31.41,70.04 31.28,69.91 29.89,69.91 29.34,70.46 26.05,70.46 25.35,69.75 24.53,69.75 24.22,69.45 23.78,69
5V_HDMI_CRT_S0 on BOTTOM: 29.89,69.91 29.29,70.51 29.29,71.7 29.61,72.03 31.62,72.03 31.68,71.97 31.68,71.74 31.67,71.74 31.67,70.01 31.58,69.91 ; 1 cut-out
5V_HDMI_CRT_S0_R on TOP: 19.69,67.12 18.51,68.3 18.51,70.1 18.14,70.47 14.07,70.47 12.55,68.95 12.17,68.95 12.06,69.05 12.06,70.2 15.04,73.17 20.04,73.17 20.26,72.95 20.26,67.19 20.2,67.12 ; 2 cut-outs
5V_PWR on BOTTOM: 47.61,27.21 47.48,27.33 39.73,27.33 39.73,37.49 41,38.76 47.1,38.76 47.35,38.5 47.35,34.57 45.32,32.54 45.32,30.89 48.11,28.1 48.11,27.33 47.99,27.21 ; 1 cut-out
5V_S0 on TOP: 160.5,77.66 160.09,78.07 160.09,80.47 160.87,81.26 162.84,81.26 163.19,80.91 163.19,78 162.84,77.66
5V_S0 on TOP: 40.03,14.55 39.94,14.63 39.94,17.28 39.97,17.31 43.19,17.31 44.14,16.36 44.54,16.36 44.68,16.23 44.68,14.61 44.61,14.55 ; 1 cut-out
5V_S0 on TOP: 32.48,68.49 32.41,68.56 32.41,71.56 32.59,71.73 34.78,71.73 34.93,71.58 34.93,68.73 34.69,68.49 ; 2 cut-outs
5V_S0 on TOP: 197.78,38.59 197.56,38.82 197.56,46.32 193.5,50.38 193.5,54.23 193.09,54.64 192.46,55.27 192.46,57.66 196.91,62.11 197.45,62.11 199.44,64.1 201.55,64.1 201.74,63.91 201.74,60.83 200.56,59.65 198.13,59.65 196.09,57.61 196.09,54.86 198.2,52.75 198.2,51.38 200.27,49.31 201.46,48.13 201.46,48.13 201.89,47.71 201.89,38.94 201.53,38.59
5V_S0 on BOTTOM: 95.51,144.45 95.41,144.56 95.41,146.55 95.26,146.69 95.26,147.33 95.43,147.5 96.2,147.5 96.3,147.4 96.3,145.52 96.5,145.32 98.36,145.32 98.46,145.22 98.46,144.61 98.31,144.45 ; 1 cut-out
5V_S0 on BOTTOM: 75.14,155.73 73.67,157.21 73.34,157.21 73.27,157.28 73.27,158.04 73.33,158.1 74.6,158.1 75.82,156.87 76.56,156.87 76.69,156.75 76.69,155.99 76.44,155.73 ; 3 cut-outs
5V_S0 on BOTTOM: 41.21,78.49 40.95,78.75 40.95,80.07 42.47,81.59 62.09,81.59 63.39,82.89 71.16,82.89 88.29,100.02 88.29,102.41 88.29,102.41 88.29,103.23 93.51,108.45 93.51,121.17 93.51,121.18 93.51,121.67 93.71,121.87 95,121.87 95.1,121.77 95.1,108.27 89.67,102.84 89.67,99.81 83.49,93.63 83.49,92.71 72.59,81.81 63.83,81.81 62.65,80.63 43.83,80.63 43.57,80.36 43.57,78.78 43.27,78.49 ; 2 cut-outs
5V_S0 on BOTTOM: 32.17,68.49 31.96,68.7 31.96,69.25 31.95,69.25 31.95,71.71 32.07,71.84 34.76,71.84 34.94,71.66 34.94,68.73 34.7,68.49 ; 4 cut-outs
5V_S0 on BOTTOM: 197.57,61 197.13,61.44 197.13,63.76 195.07,65.82 193.02,65.82 192.69,66.16 192.69,72.45 189.61,75.53 180.44,75.53 179.8,76.17 179.41,76.17 178.55,77.03 177.34,77.03 177.03,76.72 175.06,76.72 174.15,75.82 174.15,75.8 171.95,75.8 171.93,75.82 171.51,75.82 171.22,75.53 168.97,75.53 167.33,73.89 163.26,73.89 162.78,74.38 162.78,74.51 162.78,74.51 162.78,75.34 162.64,75.48 161.16,75.48 161.09,75.54 161.09,76.41 161.16,76.47 163.03,76.47 163.03,76.47 163.41,76.47 163.88,76.94 163.88,77.52 163.59,77.82 159.73,77.82 159.33,78.22 159.33,81.23 159.41,81.3 163.17,81.3 164.03,82.16 172.32,82.16 172.9,82.74 176.79,82.74 177.33,82.21 180.51,82.21 180.93,81.79 194.16,81.79 194.81,82.44 196.8,82.44 197.05,82.19 197.05,67.77 199.03,65.79 201.15,65.79 201.47,65.47 201.47,61.28 201.19,61
5V_S0 on BOTTOM: 191.37,38.76 190.79,39.34 190.79,41.38 190.94,41.53 201.18,41.53 201.25,41.46 201.25,38.93 201.08,38.76 ; 4 cut-outs
5V_S0 on BOTTOM: 174.1,8.23 173.82,8.51 173.82,11.05 174.09,11.32 174.79,11.32 175.44,11.98 175.44,11.99 176.49,11.99 176.61,11.87 176.61,8.36 176.49,8.23 ; 2 cut-outs
5V_S0 on L3: 27.26,14.19 21.46,20 21.46,20.06 21.47,20.07 21.47,24.58 19.3,26.75 19.3,33.65 19.54,33.89 19.54,46.74 24.56,51.76 24.56,56 26.79,58.22 26.79,61.13 28.15,62.5 31.34,62.5 32.49,63.66 32.49,71.38 32.5,71.39 32.5,72.4 37.62,77.52 40.46,77.52 42.51,79.57 43,79.57 43.3,79.27 43.3,78.72 40.97,76.39 38.07,76.39 34.73,73.05 34.73,63.52 32.05,60.84 29,60.84 28.42,60.26 28.42,57.45 26.15,55.19 26.15,51.09 21.18,46.12 21.18,38.34 22,37.52 22,33.97 20.93,32.9 20.93,27.47 23.06,25.34 23.06,20.75 28.01,15.8 33.19,15.8 34.77,17.38 43.45,17.38 43.96,16.87 43.96,14.83 43.66,14.53 39.48,14.53 38.69,15.32 35.04,15.32 33.91,14.19
5V_S0 on L3: 94,141.15 94,135.26 98.92,130.33 98.92,126.61 95.09,122.78 95.09,120.26 94.74,119.91 93.46,119.91 93.17,120.2 93.17,132.09 91.24,134.02 91.24,139.17 86.69,143.72 86.69,147.94 81.05,153.57 77.32,153.57 73.9,157 73.9,157.64 74.28,158.02 75.59,158.02 78.35,155.26 84.65,155.26 88.89,151.02 88.89,146.25 ; 1 cut-out
5V_S0 on L4: 41.71,17.35 40.14,17.35 39.43,16.64 39.43,9.94 46.64,2.72 201.36,2.72 201.87,3.23 201.87,40.41 201.64,40.64 198.49,40.64 198.49,40.64 197.99,40.64 197.7,40.35 197.7,11.13 193.13,6.56 179.13,6.56 175.65,10.04 173.92,10.04 173.64,9.76 54.16,9.76 45.5,18.42 42.78,18.42
5V_S0 on L4: 103.99,141.38 111.74,141.38 115.04,138.08 115.04,137.44 114.79,137.19 114.15,137.19 111.36,139.98 103.11,139.98 97.14,145.95 96.25,145.95 95.36,146.84 95.36,147.22 95.61,147.48 97.9,147.48
5V_S5 on TOP: 51.76,2.72 45.74,8.74 45.74,18.45 45.63,18.56 41.02,18.56 40.1,18.56 39.97,18.69 39.97,23.64 41.53,25.2 50.28,25.2 51.24,24.24 51.24,11.8 54.12,8.92 65.29,8.92 67.06,7.14 78.87,7.14 80.14,5.87 80.14,3.46 79.41,2.72 64.73,2.72 64.72,2.72 ; 4 cut-outs
5V_S5 on BOTTOM: 34.14,18.7 33.21,19.64 27.87,19.64 26.81,20.69 26.81,24.42 27.19,24.79 30.16,24.79 30.49,24.46 38.21,24.46 38.84,25.1 38.84,26.62 39.17,26.95 47.53,26.95 47.8,26.68 47.8,19.8 46.69,18.7
5V_S5 on BOTTOM: 27.57,43.13 26.58,44.12 26.58,45.52 26.75,45.7 29.22,45.7 29.27,45.65 29.27,43.31 29.09,43.13 ; 1 cut-out
5V_S5 on BOTTOM: 86.72,13.21 87.48,13.98 92.26,13.98 93.29,15 97.91,15 99.88,13.03 163.2,13.03 164.36,11.87 164.36,10.36 167.93,6.79 186.8,6.79 187.71,7.7 194.09,7.7 195.25,8.85 195.25,16.94 197.04,18.72 198.99,18.72 199.18,18.54 199.18,17.04 199.63,16.59 199.63,6.41 195.79,2.57 63.64,2.57 61.25,4.96 61.25,15.02 61.98,15.75 74.91,15.75 77.45,13.21 ; 4 cut-outs
5V_S5 on L3: 28.4,22.33 26.56,22.33 26.21,22.69 26.21,29.08 25.63,29.65 25.63,36.33 26.21,36.91 26.21,38.96 26.21,38.96 26.21,40.81 26.25,40.85 26.25,46.31 26.5,46.57 28.96,46.57 29.08,46.45 29.08,29.47 28.71,29.1 28.71,22.64
+5V_AVDD on BOTTOM: 185.76,17.98 185.76,17.99 185.76,18.19 185.76,18.2 186.83,18.2 186.92,18.28 186.92,20.06 187.4,20.55 188.18,20.55 188.56,20.93 190.34,20.93 190.67,20.6 192.67,20.6 192.92,20.35 192.92,19.19 192.86,19.13 190.77,19.13 189.91,19.98 187.84,19.98 187.38,19.53 187.38,18.37 186.99,17.98 ; 4 cut-outs
+5V_PVDD on BOTTOM: 177.46,7.27 177.07,7.66 177.07,11.8 177.12,11.85 177.93,11.85 178.04,11.74 178.04,10.79 178.32,10.5 179.39,10.5 179.58,10.69 179.58,11.22 179.74,11.39 180.26,11.39 181.52,12.65 181.59,12.65 181.72,12.78 181.72,13.76 181.92,13.76 181.92,12.58 181.22,11.88 181.22,11.86 180.74,11.38 180.74,9.47 180.98,9.23 180.99,9.23 181.02,9.2 181.41,9.2 181.77,9.56 183.49,9.56 183.5,9.55 183.93,9.55 184.23,9.86 184.23,10.45 184.24,10.45 184.24,11.46 183.71,11.98 183.71,13.71 183.74,13.74 183.92,13.74 183.94,13.73 183.94,12.41 184.87,11.47 184.87,9.68 184.56,9.36 184.56,7.61 184.22,7.27 ; 5 cut-outs
+V1.05DX_MODPHY_PCH on TOP: 131.04,87.68 130.78,87.95 130.78,89.4 131.54,90.16 131.54,94.24 133.81,96.5 135.82,96.5 137.8,98.49 137.8,98.91 137.8,98.91 137.8,102.29 137.81,102.3 137.81,103.66 138.58,104.43 138.58,105.45 138.74,105.61 140.66,105.61 140.77,105.49 140.77,103.61 141.71,102.67 141.71,101.12 141.46,100.87 141.46,97.83 137.37,93.73 136.49,93.73 136.32,93.57 136.32,92.37 136.17,92.23 135.86,92.23 135.35,91.72 135.27,91.64 135.27,89.49 134.51,88.73 133.74,88.73 133.73,88.73 133.37,88.73 133.15,88.51 133.15,87.96 132.87,87.68 ; 2 cut-outs
+V1.05DX_MODPHY_PCH on BOTTOM: 131.03,87.89 130.83,88.09 130.83,88.48 131.96,89.61 134.3,89.61 134.45,89.47 134.45,89.29 134.29,89.13 132.77,89.13 132.64,89 132.42,89 132.29,88.88 132.29,88.13 132.18,88.01 131.49,88.01 131.36,87.89
+V1.05DX_MODPHY_PCH on L3: 130.8,87.91 130.71,88 130.71,88.64 129.58,89.77 129.58,94.02 130.75,95.2 130.75,95.2 131.12,95.58 131.12,96.37 133.92,99.17 134.32,99.17 135.59,100.44 135.59,101.25 138.13,103.79 140.19,103.79 140.44,103.53 140.44,102.16 139.78,101.5 138.39,101.5 138.18,101.3 138.18,98.84 136.38,97.04 136.33,97.04 136,96.71 134.15,96.71 131.02,93.57 131.02,89.94 131.14,89.82 134.22,89.82 134.35,89.69 134.35,89.06 133.97,88.68 133.2,88.68 132.92,88.39 132.92,88.04 132.79,87.91
+V1.05S_CORE_PCH on TOP: 128.93,86.91 128.84,87 128.84,87.01 128.6,87.25 128.6,87.25 128.38,87.48 128.38,90.43 128.13,90.68 128.13,94.79 128.25,94.91 128.25,97.83 128.5,98.08 130.2,98.08 132.54,100.42 134.41,100.42 134.81,100.81 134.81,101.68 135.5,102.37 135.5,105.83 132.73,108.6 132.73,110 132.92,110.19 135.45,110.19 137.57,108.07 137.57,98.5 135.83,96.75 133.8,96.75 131.41,94.36 131.41,90.05 131.29,89.93 131.11,89.93 130.64,89.46 130.64,87.66 130.63,87.65 130.63,87.07 130.47,86.91 ; 3 cut-outs
+V1.05S_CORE_PCH on L4: 131.85,85.36 131.85,88.51 130.69,89.67 130.07,89.67 129.41,90.34 128.1,90.34 127.37,91.06 126.42,91.06 125.53,90.17 124.9,90.17 124.21,89.49 124.21,88.9 123.81,88.5 123.81,83.11 124.78,82.14 125.64,82.14 126.06,82.56 126.06,83.85 126.5,84.28 127.59,84.28 127.59,84.84 127.77,85.02 129.73,85.02 130.05,84.71 130.05,84.41 130.18,84.28 130.27,84.28 130.38,84.17 130.65,84.17
+V3.3A_PSUS on BOTTOM: 125.31,80.95 125.25,81.01 125.25,81.56 125.36,81.67 125.58,81.67 125.69,81.77 126.55,81.77 126.88,82.1 126.88,82.35 126.98,82.45 127.26,82.45 127.41,82.3 127.41,81.94 127.24,81.77 126.96,81.77 126.28,81.09 126,81.09 125.86,80.95
+V3.3A_PSUS on L4: 130.91,84.09 136.29,84.09 136.38,84 136.38,83.6 139.3,80.67 139.3,79.53 140.1,78.73 140.1,77.96 142.02,76.04 143.53,76.04 143.8,75.77 143.8,75.39 143.55,75.15 140.9,75.15 140,76.04 140,76.04 138.67,77.37 138.67,80.42 136.25,82.83 130.69,82.83 130.59,82.94 130.59,83.77
GND on TOP: 116.47,99.68 114.83,101.32 114.83,104.24 116.6,106.01 117.62,106.01 118.14,106.53 118.14,117.69 118.58,118.13 120.63,118.13 121.08,117.67 121.08,101.17 119.59,99.68
GND on TOP: 168.59,143.43 167.89,144.13 167.4,144.13 166.79,143.52 166.48,143.52 166.41,143.59 166.41,145.52 166.41,145.73 166.5,145.83 168.71,145.83 168.89,145.65 168.89,143.9 168.94,143.86 168.94,143.54 168.82,143.43
GND on TOP: 89.28,19.47 88.94,19.81 88.94,23.4 89.16,23.62 92.14,23.62 92.14,23.61 92.18,23.56 92.18,22.69 92.01,22.52 90.6,22.52 90.38,22.3 90.38,19.7 90.14,19.47 ; 6 cut-outs
GND on TOP: 160.43,125.58 160.43,125.64 160.11,125.96 160.11,127.63 159.66,128.08 159.66,131.81 160.4,132.56 161,132.56 161.13,132.43 161.13,131.61 161.32,131.42 161.44,131.42 161.46,131.44 166.4,131.44 166.46,131.39 166.46,129.76 166.3,129.6 165.46,129.6 165.46,129.6 162.28,129.6 161.95,129.26 161.95,125.71 161.82,125.58 ; 9 cut-outs
GND on TOP: 137.91,104.65 137.78,104.78 137.78,106.68 137.97,106.87 138.42,106.87 138.59,106.71 138.59,106.13 138.44,105.98 138.44,104.79 138.3,104.65
GND on TOP: 19.31,59.96 19.2,60.08 19.2,61.44 19.25,61.5 19.74,61.5 20.03,61.2 22.26,61.2 22.6,61.54 23.93,61.54 24.11,61.73 24.11,62.62 25.23,63.73 26.4,63.73 26.4,63.72 26.4,62.98 26.33,62.91 25.29,62.91 24.73,62.35 24.73,60.78 23.91,59.96 ; 5 cut-outs
GND on TOP: 36.71,45.23 36.58,45.36 36.58,47.27 36.46,47.39 35.19,47.39 35.06,47.52 35.06,50.19 35.19,50.31 36.71,50.31 37.22,49.81 39.63,49.81 40.65,48.79 40.65,46.25 40.52,46.12 39.76,46.12 38.87,45.23 ; 2 cut-outs
GND on TOP: 109.91,164.83 110.14,165.05 110.7,165.05 110.88,164.88 110.88,163.25 110.87,163.24 110.02,163.24 109.91,163.35
GND on TOP: 81.83,57.13 81.31,57.64 81.31,62.92 83.23,64.83 90.38,64.83 90.7,64.5 90.7,57.39 90.45,57.13 ; 2 cut-outs
GND on TOP: 104.48,153.09 104.35,153.22 104.35,155.31 104.75,155.71 104.75,157.69 104.3,158.14 101.03,158.14 100.75,158.42 100.75,161.49 100.95,161.69 101.92,161.69 102.73,160.88 105.32,160.88 105.89,160.32 105.89,159.95 106.74,159.1 106.74,153.4 106.45,153.1 106.19,153.1 106.18,153.09 ; 4 cut-outs
GND on TOP: 100.75,101.33 100.18,101.91 100.18,102.35 100.33,102.5 100.33,103.61 100.16,103.78 99.82,103.78 99.69,103.91 99.69,104.19 100.18,104.68 100.18,105.57 100.95,106.33 100.95,115.6 101.6,116.25 102.88,116.25 102.88,101.4 102.81,101.33 ; 1 cut-out
GND on TOP: 127.72,105.97 127.68,106.01 127.68,109.2 127.9,109.42 129.27,109.42 129.52,109.17 129.52,107.97 128.68,107.14 128.68,106 128.66,105.97
GND on TOP: 62.21,49.94 62.08,50.07 62.08,50.7 62.21,50.83 62.59,50.83 62.97,51.21 62.97,51.46 63.23,51.72 64.75,51.72 64.88,51.59 64.88,51.34 64.75,51.21 64.5,51.21 63.23,49.94 ; 3 cut-outs
GND on TOP: 128.81,134.52 128.69,134.65 128.69,135.79 128.56,135.92 128.56,139.09 128.81,139.35 131.35,139.35 131.48,139.22 131.48,137.69 131.23,137.44 131.23,136.42 131.35,136.3 131.35,134.65 131.23,134.52 ; 2 cut-outs
GND on TOP: 163.15,98.52 162.9,98.78 162.9,100.81 163.47,101.38 163.47,103.95 163.48,103.96 163.48,104.73 165.16,106.41 166.2,106.41 167.01,107.22 167.01,108.16 166.43,108.74 165.41,108.74 164.19,109.96 163.91,109.96 163.02,110.84 163.02,115.29 163.15,115.42 167.09,115.42 168.49,114.02 169.5,114.02 169.63,113.89 169.63,110.84 169.5,110.72 168.1,110.72 167.75,110.36 167.75,108.77 168.21,108.31 169.32,108.31 169.6,108.03 169.6,104.96 169.5,104.86 168.59,104.86 168.38,104.65 168.38,103.87 168.49,103.76 169.55,103.76 169.63,103.69 169.63,100.56 169.5,100.43 168.36,100.43 167.85,99.92 167.85,98.91 167.47,98.52
GND on TOP: 159.09,107.11 159.02,107.18 159.02,108.9 159.09,108.96 160.87,108.96 160.93,108.91 160.93,107.15 160.89,107.11
GND on TOP: 185.67,89.66 185.56,89.77 185.56,91.88 185.7,92.01 186.87,92.01 186.87,92.01 187.49,92.01 187.91,92.42 187.91,93.84 189.57,95.5 189.57,100.82 189.84,101.09 190.3,101.09 190.41,100.98 190.41,98.67 190.15,98.42 190.15,94.35 190.15,94.35 190.15,94 189.54,93.39 189.54,92.51 189.95,92.1 190.37,92.1 190.66,91.81 190.66,90.11 190.22,89.66
GND on TOP: 121.52,168.48 120.96,169.04 118.42,169.04 118.3,169.17 118.3,170.11 118.37,170.18 122.64,170.18 122.84,169.98 122.84,168.64 122.69,168.48
GND on TOP: 64.55,167.27 64.55,168.84 64.29,169.09 63.91,169.09 63.69,168.86 63.69,168.57 63.18,168.06 62.43,168.06 62.31,168.18 62.31,170.52 62.49,170.69 67.85,170.69 71.01,167.53 71.01,166.08 70.78,165.85 65.97,165.85
GND on TOP: 14.87,16.35 14.79,16.42 14.79,18.81 14.82,18.83 17.21,18.83 17.26,18.78 17.26,16.44 17.17,16.35
GND on TOP: 164.9,52.64 164.21,53.32 164.21,55.02 164.43,55.24 164.85,55.24 164.89,55.2 165.9,55.2 166.05,55.36 166.37,55.36 166.43,55.29 166.43,54.85 166.35,54.77 166.12,54.77 165.92,54.57 165.92,53.11 165.45,52.64
GND on TOP: 99.19,94.3 98.97,94.52 98.97,95.14 99.17,95.35 100.1,95.35 100.36,95.61 100.36,96.68 100.73,97.04 101.22,97.04 101.6,97.42 102.25,97.42 102.39,97.28 102.39,97.02 102.19,96.81 101.81,96.81 101.51,96.52 101.51,94.41 101.4,94.3 ; 4 cut-outs
GND on TOP: 127.2,73.68 127.07,73.81 127.07,74.4 127.6,74.92 127.6,75.56 127.81,75.77 128.52,75.77 128.64,75.65 128.64,75.23 128.06,74.66 128.06,73.92 127.82,73.68 ; 1 cut-out
GND on TOP: 131.45,163.86 129.38,165.93 129.38,168.65 129.85,169.12 130.5,169.12 130.51,169.11 130.82,169.11 130.83,169.12 132.7,169.12 132.8,169.02 132.8,163.96 132.7,163.86
GND on TOP: 143.16,62.44 143.26,62.54 144.13,62.54 144.25,62.41 144.25,60.56 144.15,60.46 143.42,60.46 143.16,60.71 ; 1 cut-out
GND on TOP: outline of 839 points within 0.51,0.51 203.69,181.47 ; 115 cut-outs
GND on TOP: 44.97,45.23 44.84,45.36 44.84,46.5 44.33,47.01 43.06,47.01 42.68,46.63 42.68,46.25 42.55,46.12 41.92,46.12 41.66,46.38 41.66,47.65 44.2,50.19 47.25,50.19 47.38,50.06 47.38,47.14 47.51,47.01 47.51,45.49 47.25,45.23 ; 2 cut-outs
GND on TOP: 67.04,15.14 64.42,17.76 64.42,19.79 65.46,20.83 70.51,20.83 70.71,20.63 70.71,18.08 70.61,17.97 68.31,17.97 68.05,17.72 68.05,16.16 68.61,15.6 68.61,15.22 68.54,15.14 ; 3 cut-outs
GND on TOP: 152.97,89.18 152.97,85.07 153.08,84.95 154.51,84.95 154.98,85.42 154.98,86.27 154.66,86.6 154.66,89.98 152.78,91.86 150.97,91.86 150.88,91.77 150.88,90.38 151.1,90.17 151.97,90.17 ; 2 cut-outs
GND on TOP: 193.89,125.03 193.41,125.51 193.41,128.27 193.99,128.85 193.99,130.31 193.8,130.49 193.8,130.9 193.86,130.96 195.76,130.96 196.13,130.59 196.13,129.09 196.13,129.06 197.25,127.94 197.25,125.22 197.06,125.03 ; 2 cut-outs
GND on TOP: 101.59,30.43 101.01,31.01 101.01,38.09 101.27,38.35 119.72,38.35 120.06,38.01 122.47,38.01 123.21,37.27 123.21,33.02 122.95,32.76 122.95,31.68 122.82,31.55 121.26,31.55 120.14,30.43 ; 16 cut-outs
GND on TOP: outline of 139 points within 92.44,7.93 186.21,40.37 ; 30 cut-outs
GND on TOP: 120.02,159.75 119.79,159.97 116.21,159.97 116.01,160.18 116.01,162.49 116.29,162.77 121.01,162.77 121.22,162.56 121.22,161.21 121.36,161.07 122.21,161.07 122.33,160.94 122.33,160.2 122.16,160.02 121.21,160.02 120.94,159.75 ; 2 cut-outs
GND on TOP: 158.23,90.32 159.27,90.32 160.63,88.96 160.63,87.46 160.32,87.14 158.31,87.14 157.96,87.5 157.96,90.04
GND on TOP: 133.2,83.21 133.08,83.34 133.08,83.67 132.93,83.82 131.66,83.82 130.44,85.04 130.44,86.72 130.84,87.13 132.16,87.13 132.39,86.9 132.39,85.17 132.49,85.07 132.93,85.07 133.05,85.2 133.05,85.5 133.28,85.73 133.51,85.73 133.64,85.6 133.64,84.97 133.46,84.79 132.49,84.79 132.39,84.69 132.39,84.18 132.47,84.1 133.41,84.1 133.61,83.9 133.61,83.34 133.48,83.21
GND on TOP: 132.84,101.82 132.76,101.9 132.76,106.01 132.82,106.07 133.21,106.07 133.3,105.97 133.3,105.55 133.48,105.37 134.42,105.37 134.67,105.12 134.67,102.71 133.77,101.82
GND on TOP: outline of 105 points within 86.18,67.17 120.53,92.32 ; 12 cut-outs
GND on TOP: 52.49,18.56 52.26,18.79 52.26,22.03 52.36,22.13 53.94,22.13 54.06,22.01 54.06,18.68 53.94,18.56 ; 4 cut-outs
GND on TOP: 191.12,122.05 190.63,122.53 188.48,122.53 188.46,122.55 187.65,122.55 187.51,122.69 187.51,123.47 187.66,123.63 191.8,123.63 191.98,123.45 191.98,122.23 191.8,122.05 ; 5 cut-outs
GND on TOP: 84.58,152.34 83.22,153.7 83.22,153.99 83.32,154.09 85.78,154.09 86.06,153.81 86.06,152.53 85.87,152.34
GND on TOP: 19.29,62.63 19.17,62.74 19.17,63.57 19.28,63.69 20,63.69 20.24,63.45 22.24,63.45 22.66,63.87 23.93,63.87 24.89,64.83 25.12,64.83 25.24,64.7 25.24,64.33 23.54,62.63 ; 4 cut-outs
GND on TOP: 20.47,64.74 20.4,64.82 20.4,68.58 20.51,68.69 21.38,68.69 22.28,67.79 22.28,66.85 22.49,66.64 23.23,66.64 23.3,66.57 23.3,64.88 23.16,64.74 ; 5 cut-outs
GND on TOP: 62.09,30.5 61.95,30.64 61.95,31.61 61.73,31.82 61.19,31.82 61.06,31.96 61.06,38.57 61.05,38.57 61.05,39.66 60.85,39.86 60.85,41.02 61.01,41.18 61.9,41.18 66.22,45.5 72.91,45.5 73.26,45.14 73.26,40.42 73.25,40.41 73.25,33.24 73.1,33.08 72.67,33.08 72.61,33.02 72.61,32.4 72.68,32.33 73.08,32.33 73.23,32.18 73.23,31.94 73.09,31.8 72.63,31.8 72.51,31.68 72.51,31.02 71.99,30.5 ; 6 cut-outs
GND on TOP: 134.38,73.94 133.23,75.09 133.23,76.8 133.37,76.94 134.11,76.94 134.26,76.79 134.26,76.54 134.52,76.28 134.78,76.28 134.98,76.08 134.98,75.85 134.83,75.7 134.52,75.7 134.32,75.49 134.32,75.01 134.47,74.86 135.49,74.86 135.83,75.2 135.83,75.67 135.93,75.77 136.3,75.77 136.42,75.65 136.42,75.16 136.28,75.02 136.28,74.17 136.05,73.94
GND on TOP: 78.05,164.67 78.05,164.97 79.04,164.97 79.04,165.18 78.05,165.18 78.05,165.47 78.99,165.47 78.99,165.69 78.05,165.69 78.05,165.97 78.05,165.98 79.55,165.98 79.63,165.9 79.63,164.68 79.56,164.6 79.2,164.6 79.13,164.67
GND on TOP: 18.9,39.54 17.39,41.06 17.39,42.12 17.57,42.3 17.92,42.3 18.41,41.8 23.9,41.8 24.26,41.45 24.26,39.97 23.83,39.54
GND on TOP: 130.44,77.45 130.26,77.63 130.26,78.16 129.95,78.47 129.95,78.72 130.06,78.82 130.47,78.82 130.61,78.68 130.61,78.31 130.74,78.19 131.22,78.19 131.3,78.11 131.3,77.47 131.27,77.45
GND on TOP: 119.03,127.54 118.35,128.22 118.35,135.03 118.85,135.54 118.85,136.68 119.36,137.19 122.69,137.19 124.52,135.36 124.52,127.74 124.31,127.54
GND on TOP: 39.21,16.34 39.17,16.38 39.17,17.37 39.04,17.5 37.92,17.5 37.84,17.58 37.84,18.21 38,18.38 41.11,18.38 41.12,18.38 45.39,18.38 45.49,18.27 45.49,16.9 45.27,16.68 44.07,16.68 43.26,17.48 39.5,17.48 39.39,17.37 39.39,16.38 39.35,16.34 ; 5 cut-outs
GND on TOP: outline of 114 points within 161.33,130.42 170.99,143.51 ; 29 cut-outs
GND on TOP: 189.2,157.94 189.15,157.99 189.15,158.54 189.1,158.59 188.24,158.59 188.22,158.61 188.22,159.08 188.27,159.13 189.12,159.13 189.83,159.84 191.09,159.84 191.31,160.05 191.31,160.3 191.33,160.32 193.67,160.32 193.81,160.18 193.81,159.44 193.63,159.26 192.72,159.26 191.84,158.39 189.82,158.39 189.54,158.11 189.54,158.09 189.39,157.94 ; 3 cut-outs
GND on TOP: 171.07,130.47 170.96,130.58 170.96,131.38 170.33,132 170.33,133.51 170.43,133.61 171.11,133.61 171.26,133.76 171.26,133.76 171.26,134.07 171.15,134.19 171.15,134.19 170.92,134.42 170.92,135.39 170.95,135.41 171.82,135.41 172.2,135.03 172.2,133.81 171.9,133.51 171.9,131.46 171.53,131.08 171.53,130.97 171.53,130.97 171.53,130.6 171.4,130.47 ; 5 cut-outs
GND on TOP: 188.74,104.76 188.63,104.87 188.63,106.03 189,106.4 190.26,106.4 190.44,106.22 190.44,104.99 190.2,104.76
GND on TOP: 138.01,59.08 137.56,59.53 137.56,62.21 136.99,62.78 136.99,63.41 137.04,63.46 138.49,63.46 138.69,63.66 138.69,64.14 138.77,64.22 139.17,64.22 139.25,64.14 139.25,59.34 139,59.08 ; 3 cut-outs
GND on TOP: 126.37,101.91 126.19,102.09 126.19,102.52 126.98,103.31 127.19,103.31 127.34,103.46 127.34,103.99 127.39,104.04 128.05,104.04 128.2,104.2 128.2,104.98 128.28,105.06 129.19,105.06 129.27,104.98 129.27,103.48 129.17,103.38 128.61,103.38 128.38,103.15 128.38,102.65 127.64,101.91 ; 3 cut-outs
GND on TOP: 123.78,73.98 123.13,74.64 121.84,74.64 121.62,74.86 121.62,75.42 121.44,75.59 121.11,75.59 120.94,75.77 120.94,76.05 121.04,76.15 121.42,76.15 121.57,76.31 121.57,77.4 121.42,77.55 121.11,77.55 120.99,77.68 120.99,78.01 121.09,78.11 121.44,78.11 121.55,78.21 121.55,78.72 121.19,79.07 121.19,79.76 121.97,80.54 122.99,80.54 123.21,80.32 123.21,79.81 123.32,79.7 124.7,79.7 124.73,79.74 125.26,79.74 125.49,79.51 125.49,78.43 125.7,78.22 125.94,78.22 126.12,78.04 126.12,77.64 126,77.52 125.49,77.52 125.32,77.68 125.32,78.66 125.1,78.89 124.78,78.89 124.57,78.68 124.57,74.55 124.63,74.49 124.63,74.06 124.55,73.98 ; 4 cut-outs
GND on TOP: 145.65,63.89 145.5,64.03 145.5,66.09 146.29,66.88 146.87,66.88 147.79,67.79 147.79,68.1 147.51,68.38 147.05,68.38 146.48,67.81 143.71,67.81 143.71,67.85 141.64,69.92 141.64,74.57 142.18,75.12 145.55,75.12 148.5,72.17 151.04,72.17 151.14,72.06 151.14,71.91 149.59,70.36 149.59,69.6 149.82,69.37 151.24,69.37 151.42,69.19 151.42,68.54 151.32,68.43 149.66,68.43 149.65,68.42 149.12,68.42 147.38,66.68 147.38,66.15 146.44,65.21 146.44,64.33 146,63.89 ; 1 cut-out
GND on TOP: 127.79,61.96 127.71,62.04 127.71,62.41 127.81,62.51 128.39,62.51 128.51,62.63 128.51,63.28 128.63,63.4 129.14,63.4 129.27,63.28 129.27,62.77 129.27,62.76 129.27,62.13 129.11,61.96
GND on TOP: 188.77,107.11 188.61,107.27 188.61,110.13 188.84,110.36 188.84,110.38 190.22,110.38 190.42,110.19 190.42,107.3 190.24,107.11
GND on TOP: 47.01,70.9 46.93,70.97 46.93,72.08 46.64,72.37 45.77,72.37 45.55,72.16 45.13,72.16 44.98,72.3 44.98,72.65 45.57,73.24 46.34,73.24 46.61,72.96 49.52,72.96 49.78,72.7 49.79,72.7 49.82,72.67 49.82,72.24 49.67,72.1 49.67,71.48 49.78,71.37 51.61,71.37 51.86,71.62 51.86,72.59 51.95,72.68 52.28,72.68 52.37,72.59 52.37,71.24 52.02,70.9 ; 4 cut-outs
GND on TOP: 146.46,131.74 146.39,131.82 146.39,134.13 146.83,134.57 146.83,135.24 147.01,135.42 147.01,138.82 146.87,138.96 146.87,140.07 146.55,140.39 146.15,140.39 146.14,140.38 145.96,140.38 145.87,140.47 145.87,140.86 147.21,142.2 147.8,142.2 147.87,142.13 147.87,132.15 147.46,131.74 ; 5 cut-outs
GND on TOP: 188.58,120.19 188.75,120.02 188.75,118.46 187.94,117.65 185.73,117.65 185.68,117.69 185.68,119.89 185.99,120.19
GND on TOP: 188.13,112.07 187.95,112.25 187.95,117.38 189.02,118.45 189.02,119.9 189.13,120.01 190.91,120.01 191.15,119.77 191.15,112.45 190.77,112.07
GND on TOP: 77.11,13.71 76.83,13.98 76.83,16.6 76.9,16.66 79.87,16.66 79.88,16.67 86.59,16.67 86.68,16.58 86.68,14.56 85.83,13.71 ; 2 cut-outs
GND on TOP: 156.57,75.62 160.22,75.62 160.43,75.42 160.43,73.56 160.17,73.3 156.53,73.3 156.14,73.69 156.14,75.19
GND on TOP: 155.78,140.3 155.19,140.89 155.19,142.39 155.52,142.72 158.6,142.72 159.31,143.43 160.09,143.43 160.17,143.35 160.17,142.3 160.04,142.17 159.37,142.17 158.95,141.74 158.95,141.13 159.11,140.96 159.11,140.97 159.38,140.7 159.38,140.53 159.14,140.3 ; 3 cut-outs
GND on BOTTOM: 35.31,45.49 35.06,45.74 35.06,50.31 35.19,50.44 39.12,50.44 40.01,49.55 40.01,46.25 39.25,45.49
GND on BOTTOM: outline of 95 points within 161.04,7.24 180.33,35.65 ; 6 cut-outs
GND on BOTTOM: 124.95,36.73 124.7,36.99 124.7,40.99 123.89,41.79 64.19,41.79 62.6,43.38 57.65,43.38 57.44,43.6 57.44,49.78 59.25,51.59 67,51.59 68.48,53.07 122.07,53.07 128,47.15 128,42.14 128,37.24 127.49,36.73
GND on BOTTOM: 92.26,6.34 92.15,6.46 92.15,11.92 92.3,12.07 95.73,12.07 95.9,11.9 95.9,6.46 95.78,6.34
GND on BOTTOM: 164.49,135.52 164.36,135.64 164.36,135.77 170.71,142.12 170.71,142.63 170.59,142.76 170.08,142.76 163.22,135.9 163.09,135.9 162.84,136.15 162.84,136.28 170.27,143.71 170.73,143.71 171.09,143.35 171.09,137.68 168.93,135.52 168.55,135.52 168.43,135.64 168.43,135.9 170.71,138.18 170.71,138.44 170.33,138.82 170.2,138.82 167.03,135.64 166.65,135.64 166.52,135.77 166.52,136.02 170.84,140.34 170.84,140.47 170.46,140.85 170.2,140.85 164.87,135.52
GND on BOTTOM: outline of 88 points within 145.56,130.34 162.76,174.67 ; 39 cut-outs
GND on BOTTOM: 100.31,137.42 100.21,137.52 100.21,140.19 100.64,140.62 100.64,147.53 101.12,148.01 103.33,148.01 103.54,147.81 103.54,139.07 101.89,137.42 ; 5 cut-outs
GND on BOTTOM: 187.36,90.22 187.11,90.48 187.11,91.95 187.45,92.29 187.45,94.2 187.96,94.71 189.61,94.71 189.7,94.8 189.7,104.3 188.15,105.85 188.15,108.71 188.15,108.71 188.15,110.02 188.62,110.49 189.57,110.49 189.73,110.65 189.73,112.11 189.57,112.27 188.9,112.27 188.33,112.84 188.33,118.18 189.44,119.29 190.84,119.29 191.62,118.51 194.68,118.51 194.77,118.42 194.77,95.38 194.77,95.38 194.77,94.01 193.41,92.65 191.38,92.65 190.68,91.95 190.68,90.52 190.38,90.22
GND on BOTTOM: 139.06,56.12 138.93,56.24 138.93,57.96 139.94,58.96 140.57,58.96 140.95,59.34 140.95,62.89 141.08,63.02 141.33,63.02 141.46,62.89 141.46,60.99 141.71,60.74 141.71,59.08 140.95,58.32 140.95,57.69 140.7,57.43 139.94,57.43 139.47,56.97 139.47,56.19 139.4,56.12
GND on BOTTOM: 58.7,20.1 58.67,20.13 58.67,21.86 58.69,21.89 60.4,21.89 60.42,21.86 60.42,20.14 60.38,20.1
GND on BOTTOM: 17.56,41.05 17.38,41.23 17.38,42.37 17.71,42.7 22.88,42.7 23.26,42.32 23.26,41.29 23.13,41.15 17.97,41.15 17.86,41.05 ; 6 cut-outs
GND on BOTTOM: 120.38,127.54 120.25,127.66 120.25,131.6 120,131.86 118.6,131.86 118.35,132.11 118.35,136.43 118.73,136.81 122.28,136.81 123.81,135.28 123.81,127.66 123.68,127.54 ; 2 cut-outs
GND on BOTTOM: 100.21,101.41 100.09,101.53 100.09,102.2 100.21,102.32 101.7,102.32 101.78,102.24 101.78,101.47 101.71,101.41
GND on BOTTOM: 179.71,162.65 179.48,162.87 179.48,163.76 179.77,164.04 180.71,164.04 180.96,164.29 180.96,171.67 181.11,171.82 182.21,171.82 182.66,171.37 182.66,171.04 182.66,171.04 182.66,163.15 182.16,162.65 ; 9 cut-outs
GND on BOTTOM: 127.68,74.61 127.51,74.78 127.51,78.94 127.43,79.02 127.15,79.02 127.02,78.89 126.6,78.89 126.46,79.04 126.14,79.04 126.07,78.97 125.58,78.97 125.49,79.06 125.22,79.06 125.13,78.96 124.76,78.96 124.6,79.12 124.13,79.12 123.87,78.86 123.86,78.86 123.7,78.7 123.7,78.37 123.7,78.37 123.81,78.25 124.2,78.25 124.27,78.33 124.49,78.33 124.53,78.29 124.53,77.83 124.14,77.44 123.73,77.44 123.53,77.24 123.06,77.24 122.85,77.45 122.85,79.02 122.78,79.09 122.45,79.09 122.45,79.08 122.28,78.92 121.93,78.92 121.74,79.11 120.53,79.11 120.31,79.33 120.31,79.91 120.42,80.03 120.81,80.03 121.06,79.77 121.21,79.77 121.23,79.8 121.37,79.8 121.59,79.57 122.06,79.57 122.21,79.72 122.21,79.95 122,80.15 122,80.45 122.06,80.51 124.17,80.51 124.63,80.05 125.47,80.05 125.97,79.55 126.29,79.55 126.53,79.79 128.32,79.79 128.4,79.7 128.4,79.52 127.98,79.11 127.98,78.76 128.05,78.7 128.05,75.93 128.22,75.76 128.42,75.76 128.57,75.61 128.57,75.11 128.07,74.61
GND on BOTTOM: 118.45,108.47 118.36,108.56 118.36,112.12 118.44,112.2 119.04,112.2 119.16,112.32 119.16,115.88 119.31,116.03 120.34,116.03 120.44,115.94 120.44,109.02 119.89,108.47
GND on BOTTOM: 90.64,150.45 90.51,150.58 90.51,152.42 90.69,152.6 91.46,152.6 91.55,152.5 91.55,150.54 91.46,150.45
GND on BOTTOM: 145.75,54.27 145.65,54.37 145.65,54.46 143.85,56.27 143.85,60.35 144.58,61.09 144.58,64.22 145.66,65.3 146.16,65.3 146.39,65.07 146.39,64.29 146.41,64.27 146.41,63.58 145.78,62.95 145.78,61.78 145.77,61.76 145.88,61.65 145.88,60.71 146.54,60.05 146.55,60.05 146.55,56.84 146.31,56.6 146.31,54.31 146.27,54.27 ; 3 cut-outs
GND on BOTTOM: 45.35,45.36 44.33,46.38 44.33,49.93 44.58,50.19 47.38,50.19 47.51,50.06 47.51,47.9 47.76,47.65 47.76,45.74 47.38,45.36
GND on BOTTOM: 159,75.01 158.87,75.14 158.87,77.47 159.06,77.67 159.06,77.68 163.47,77.68 163.64,77.5 163.69,77.45 163.69,76.96 163.37,76.65 160.98,76.65 160.77,76.43 160.77,75.19 160.59,75.01
GND on BOTTOM: 27.23,29.21 26.97,29.47 26.97,32.62 27.14,32.79 30.61,32.79 30.87,32.53 30.87,29.49 30.59,29.21
GND on BOTTOM: 189.29,7.83 189.21,7.9 189.21,9.33 189.29,9.4 192.06,9.4 192.47,9.82 192.47,11.52 192.46,11.53 192.46,14.66 192.6,14.8 194.13,14.8 195.08,13.85 195.08,8.87 194.04,7.83 ; 8 cut-outs
GND on BOTTOM: 114.41,138.85 114.11,139.16 114.11,140.4 114.24,140.53 115.25,140.53 115.51,140.79 115.51,142.06 115.38,142.18 115.38,142.69 115.51,142.82 117.67,142.82 118.3,142.18 118.3,140.91 116.78,139.39 115.51,139.39 114.97,138.85 ; 6 cut-outs
GND on BOTTOM: 124.39,91.17 124.31,91.24 124.31,91.42 124.4,91.51 124.77,91.51 125.03,91.78 125.03,91.89 124.67,92.25 124.67,92.7 124.82,92.84 125.01,92.84 125.08,92.77 125.08,92.32 125.32,92.08 125.92,92.08 126.08,91.92 126.08,91.79 125.9,91.61 125.35,91.61 124.91,91.17
GND on BOTTOM: outline of 157 points within 102.16,90.73 123.93,94.92
GND on BOTTOM: 102.03,104.35 100.52,105.85 98.67,105.85 97.6,106.92 97.6,117.3 97.9,117.6 102.68,117.6 102.89,117.39 102.89,104.51 102.73,104.35 ; 1 cut-out
GND on BOTTOM: 130.77,100.11 130.66,100.23 130.66,100.56 131.31,101.22 131.31,101.92 131.38,101.99 131.9,101.99 132.26,102.35 132.26,105.55 132.51,105.8 135.83,105.8 135.95,105.69 135.95,102.44 135.8,102.29 133.08,102.29 132.7,101.91 132.7,101.58 132.55,101.43 132.02,101.43 131.2,100.61 131.2,100.21 131.1,100.11
GND on BOTTOM: 130.69,75.23 130.34,75.58 130.34,75.83 130.36,75.85 131.01,75.85 131.29,76.13 131.29,76.45 131.37,76.53 131.54,76.53 131.62,76.46 131.62,76.19 131.12,75.69 131.12,75.31 131.05,75.23
GND on BOTTOM: 69.64,166.01 69.56,166.09 69.56,167.58 69.71,167.74 71.46,167.74 71.48,167.72 71.48,166.13 71.36,166.01
GND on BOTTOM: 163.15,98.52 162.9,98.78 162.9,102.21 166.63,105.94 166.63,105.95 167.14,106.45 167.14,109.7 166.39,110.44 163.42,110.44 163.15,110.72 163.15,113.76 163.02,113.89 163.02,115.29 163.15,115.42 167.09,115.42 167.98,114.53 167.98,112.88 168.1,112.75 169.5,112.75 169.63,112.62 169.63,108.43 170.26,107.8 170.26,105.51 170.14,105.38 168.61,105.38 167.98,104.75 167.98,102.59 168.1,102.46 169.5,102.46 169.63,102.33 169.63,99.29 169.5,99.16 168.1,99.16 167.47,98.52 ; 4 cut-outs
GND on BOTTOM: 105.76,125.1 105.63,125.23 105.63,128.96 105.76,129.09 108.23,129.09 108.61,128.71 108.61,125.32 108.4,125.1
GND on BOTTOM: 157.95,6.64 157.83,6.76 157.83,11.03 157.94,11.14 157.94,11.15 162.07,11.15 162.21,11.01 162.21,6.94 161.9,6.64
GND on BOTTOM: 129.09,143.48 128.97,143.6 128.97,145.23 128.99,145.25 131.64,145.25 131.67,145.22 131.67,143.52 131.63,143.48
GND on BOTTOM: 130.45,78 130.16,78.29 129.9,78.29 129.76,78.15 129.1,78.15 128.79,78.46 128.79,79.02 128.87,79.1 129.71,79.1 130.05,78.76 131.45,78.76 131.71,78.51 131.71,78.23 131.48,78
GND on BOTTOM: 87.84,151.87 87.71,152 87.71,152.43 87.43,152.71 87.43,153.95 87.31,154.08 87.31,155.48 87.54,155.71 88.45,155.71 88.96,155.2 88.96,153.62 90.08,152.51 90.08,152.07 89.87,151.87 ; 3 cut-outs
GND on BOTTOM: 138.41,59.08 138.16,59.34 138.16,62.49 138.24,62.58 139.42,62.58 139.68,62.32 139.68,59.85 138.92,59.08 ; 1 cut-out
GND on BOTTOM: 193.77,21 193.42,21.34 193.42,24.89 192.92,25.4 192.92,27.56 193.25,27.89 194.34,27.89 194.35,27.89 195.03,27.89 195.17,27.75 195.17,21.28 194.88,21
GND on BOTTOM: 77.65,13.71 77.27,14.09 77.27,16.46 77.46,16.65 78.58,16.65 78.59,16.66 79.87,16.66 79.88,16.67 86.03,16.67 86.31,16.39 86.31,13.93 86.09,13.71 ; 2 cut-outs
GND on BOTTOM: 132.29,28.38 130.79,29.87 130.79,37.49 131.43,38.13 133.59,38.13 137.01,34.7 137.01,29.24 136.15,28.38
GND on BOTTOM: 40.64,54.26 40.63,54.26 40.63,56 40.66,56.02 42.41,56.02 42.41,56.02 42.41,54.26
GND on BOTTOM: 46.97,29.26 46.79,29.44 46.79,32.67 50.78,32.67 51.34,32.11 51.34,29.45 51.15,29.26
GND on BOTTOM: 197.47,139.37 196.76,140.09 196.76,141.46 197.42,142.12 199.37,142.12 199.5,141.99 199.5,141.08 199.35,140.92 198.99,140.92 198.94,140.97 198.31,140.97 198.13,140.8 198.13,139.58 197.92,139.37 ; 5 cut-outs
GND on BOTTOM: 63.92,17.89 63.74,18.07 63.74,20.6 63.86,20.73 69.07,20.73 69.2,20.6 69.2,18.14 68.94,17.89
GND on BOTTOM: 162.08,136.91 161.82,137.17 161.82,137.29 168.68,144.15 168.68,144.28 168.3,144.66 168.05,144.66 162.33,138.95 162.08,138.95 161.95,139.07 161.95,139.33 166.78,144.15 166.78,144.41 166.52,144.66 166.14,144.66 162.33,140.85 162.08,140.85 161.82,141.1 161.82,141.23 164.87,144.28 164.87,144.66 164.74,144.79 164.24,144.79 162.33,142.88 162.08,142.88 161.82,143.14 161.82,143.26 163.73,145.17 170.32,145.17 170.39,145.11 170.39,144.73 170.32,144.66 170.08,144.66 162.33,136.91
GND on BOTTOM: 77.62,61.3 66.25,72.67 66.25,73.93 65.15,75.03 62.71,75.03 59.79,77.95 52.94,77.95 52.93,77.96 52.93,78.8 53.34,79.21 63.47,79.21 64.26,80 81.41,80 83,78.42 83,62.48 81.81,61.3 ; 1 cut-out
GND on BOTTOM: 155.94,46.61 155.9,46.65 155.9,47.13 155.79,47.25 153.98,47.25 153.83,47.1 147.05,47.1 142.93,51.21 142.93,51.85 143.16,52.07 143.16,53.9 143.21,53.95 143.67,53.95 143.75,53.88 143.75,53.14 144.61,52.28 146.24,52.28 146.34,52.18 146.34,49.79 147.23,48.9 153.93,48.9 154.74,49.71 156.83,49.71 157.13,49.41 157.13,46.79 156.95,46.61 ; 2 cut-outs
GND on BOTTOM: 120.1,159.72 119.92,159.9 116.69,159.9 116.54,160.05 116.54,161.9 117.3,162.67 122.44,162.67 122.56,162.54 122.56,160.28 122,159.72 ; 4 cut-outs
GND on BOTTOM: 83.13,156.76 82.91,156.98 82.91,157.61 82.58,157.94 82.58,158.42 82.68,158.53 84.31,158.53 84.51,158.32 84.51,156.92 84.35,156.76 ; 3 cut-outs
GND on BOTTOM: 191.95,89.32 191.69,89.58 191.69,90.45 191.99,90.74 192.84,90.74 192.88,90.71 192.88,90.19 193.26,89.81 193.26,89.45 193.13,89.32 ; 2 cut-outs
GND on BOTTOM: 128.69,134.52 128.56,134.65 128.56,139.09 128.81,139.35 131.35,139.35 131.48,139.22 131.48,134.65 131.35,134.52 ; 1 cut-out
GND on BOTTOM: outline of 625 points within 0.51,0.51 203.69,181.46 ; 124 cut-outs
GND on BOTTOM: 173.8,139.63 173.02,140.41 173.02,140.74 173.09,140.81 173.29,140.81 174.23,139.88 175.46,139.88 175.94,140.36 176.15,140.36 176.26,140.25 176.26,140.06 175.82,139.63
GND on BOTTOM: 90.08,83.92 90,84 90,86.2 90.06,86.26 91.16,86.26 91.24,86.18 91.24,84.01 91.15,83.92 ; 3 cut-outs
GND on BOTTOM: 150.53,89.32 150.47,89.38 150.47,90.67 150.04,91.1 150.04,91.6 150.16,91.73 151.21,91.73 151.6,91.34 151.6,89.41 151.51,89.32 ; 1 cut-out
GND on BOTTOM: 126.14,120.1 125.96,120.28 125.96,124.43 126.14,124.62 128.79,124.62 130.01,123.39 130.01,120.22 129.88,120.1
GND on BOTTOM: 158.42,81.77 158.09,82.1 156.55,82.1 156.42,82.22 156.42,82.97 157.06,83.61 160.75,83.61 161.06,83.3 161.06,82.13 160.71,81.77
GND on BOTTOM: 181.07,121.51 180.78,121.8 180.78,123.51 180.98,123.72 184.44,123.72 184.66,123.49 184.66,121.62 184.55,121.51
GND on BOTTOM: 168.41,122.33 168.24,122.5 168.24,123.54 168.56,123.86 168.56,124.77 168.82,125.02 170.19,125.02 170.36,124.85 170.36,124.29 170.37,124.29 170.37,123.67 170.29,123.59 169.73,123.59 169.45,123.32 169.45,122.42 169.36,122.33 ; 1 cut-out
GND on L2VCC: outline of 141 points within 0.51,0.51 203.69,181.46 ; 3 cut-outs
GND on L2VCC: 123.87,91.41 123.87,93.67 126.17,93.67 126.66,93.17 126.66,92.44 125.63,91.41
GND on L3: 167.09,115.42 163.18,115.42 163.02,115.27 163.02,110.95 163.56,110.42 167.83,110.42 168.43,111.03 168.43,114.08
GND on L3: outline of 517 points within 0.51,0.51 203.69,181.47 ; 4 cut-outs
GND on L3: 109.71,83.6 109.96,83.34 112.39,83.34 112.39,83.35 118.9,83.35 121.23,85.68 121.23,86.63 121.67,87.07 122.15,87.07 122.43,86.79 122.43,83.75 122.75,83.43 123.47,83.43 123.65,83.6 123.65,88.03 123.38,88.29 109.84,88.29 109.71,88.17
GND on L3: 168.16,104.68 163.84,104.68 163.46,104.3 163.46,99.67 163.96,99.17 167.24,99.17 167.83,99.75 167.83,99.93 168.36,100.46 168.36,104.47
GND on L3: 40.52,74.77 36.99,74.77 35.01,72.79 35.01,64.88 35.22,64.67 39.21,64.67 44.28,69.74 44.28,70.41 44.01,70.67 41.23,70.67 38.25,67.7 38.25,65.35 38.1,65.2 37.13,65.2 36.73,65.59 36.73,67.84 40.45,71.56 47.31,71.56 47.62,71.88 47.62,72.35 47.16,72.81 41.21,72.81 40.7,72.31 40.05,72.31 39.71,72.66 39.71,74 39.95,74.24 40.46,74.24 40.58,74.37 40.58,74.71
GND on L4: 79.76,169.7 78.71,169.7 74.43,165.43 74.43,162.1 80.66,155.87 83.47,155.87 84.01,156.41 84.01,158.64 80.2,162.44 80.2,169.26
GND on L4: outline of 472 points within 0.64,0.51 203.69,181.47 ; 7 cut-outs
GND on L5GND: outline of 136 points within 0.51,0.51 203.69,181.46 ; 2 cut-outs
VCC1R05VIDEO_PEX_PLLVDD on TOP: 159.63,139.36 159.52,139.47 159.52,140.79 159.16,141.15 159.16,141.71 159.51,142.07 160.74,142.07 160.87,141.94 160.87,141.08 161.32,140.62 161.32,139.47 161.21,139.36 ; 3 cut-outs
VCC_CORE on TOP: 101.45,82.33 101.2,82.58 101.2,83.21 101.58,83.6 101.58,83.85 101.2,84.23 101.2,84.74 102.72,86.26 102.72,86.64 102.6,86.77 102.6,88.55 102.72,88.68 102.72,89.18 102.22,89.69 102.22,91.22 101.66,91.77 101.66,96.53 101.87,96.74 102.28,96.74 102.5,96.96 102.5,97.33 102.34,97.49 101.58,97.49 101.47,97.6 101.47,99.77 101.48,99.78 101.48,99.92 103.13,101.57 103.13,116.07 103.32,116.26 104.23,116.26 104.23,116.26 106.41,116.26 107.19,117.05 107.2,117.05 108.31,118.15 117.73,118.15 117.91,117.96 117.91,106.95 117.41,106.44 116.5,106.44 115.12,105.06 115.12,103.96 114.47,103.32 114.47,101.11 116.24,99.34 118.47,99.34 119.74,98.07 119.74,95.15 120.76,94.14 120.76,88.93 120.5,88.68 109.71,88.68 109.46,88.42 109.46,82.45 109.33,82.33
VCC_CORE on BOTTOM: 103.34,104.27 103.06,104.55 103.06,117.12 110.22,117.12 111.13,116.21 118.98,116.21 119.01,116.18 119.01,112.49 118.88,112.35 118.32,112.35 118.07,112.09 118.07,108.77 117.69,108.39 115.17,108.39 114.84,108.07 114.83,108.07 114.09,107.32 111.44,107.32 109.07,104.95 106.02,104.95 105.34,104.27 ; 1 cut-out
VCC_CORE on BOTTOM: outline of 170 points within 101.25,80.24 124.72,93.25
VCC_CORE on L2VCC: 101.66,82.9 101.39,83.17 101.39,87.74 100.52,88.61 96.45,88.61 95.8,89.26 95.8,100.53 96.58,101.31 97.72,101.31 98.09,101.68 98.09,104.47 98.85,105.23 98.85,114.63 100.39,116.17 118.77,116.17 119.04,115.9 119.04,106 120.19,104.85 120.19,101.71 118.14,99.66 111.41,99.66 110.41,98.66 110.41,97.74 110.77,97.38 111.95,97.38 112.33,97.76 123.49,97.76 123.49,88.61 109.88,88.61 109.39,88.12 109.39,83.17 109.12,82.9
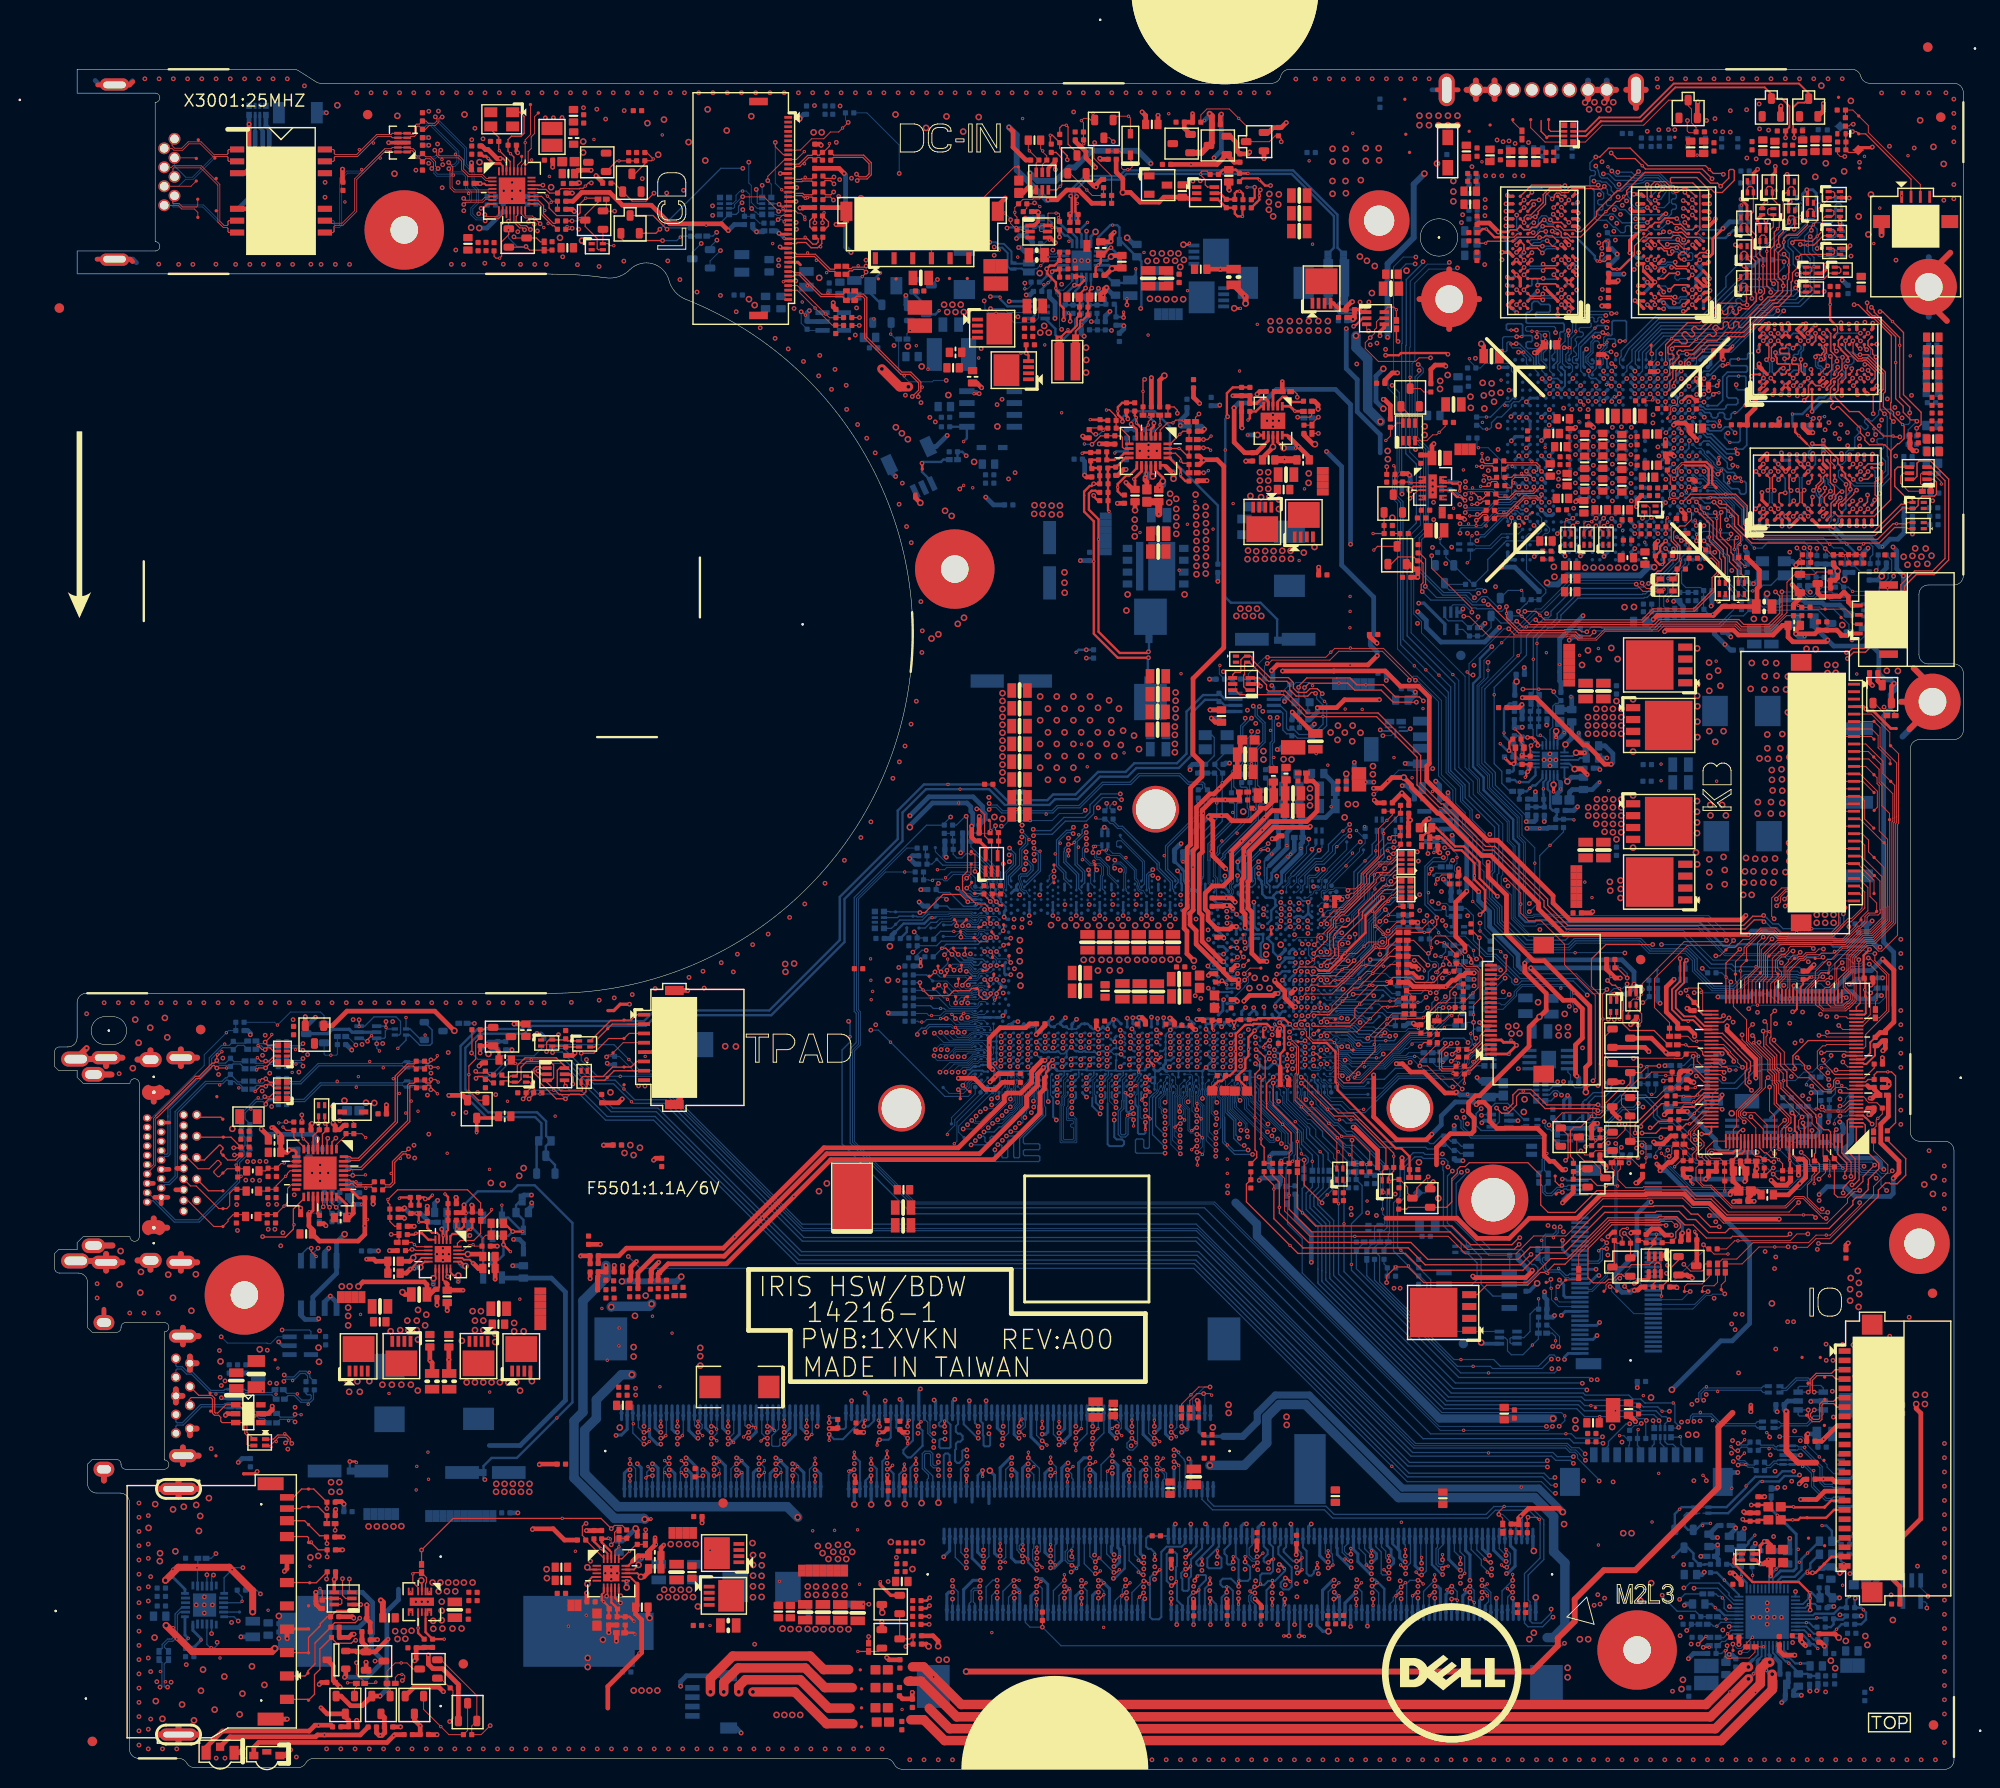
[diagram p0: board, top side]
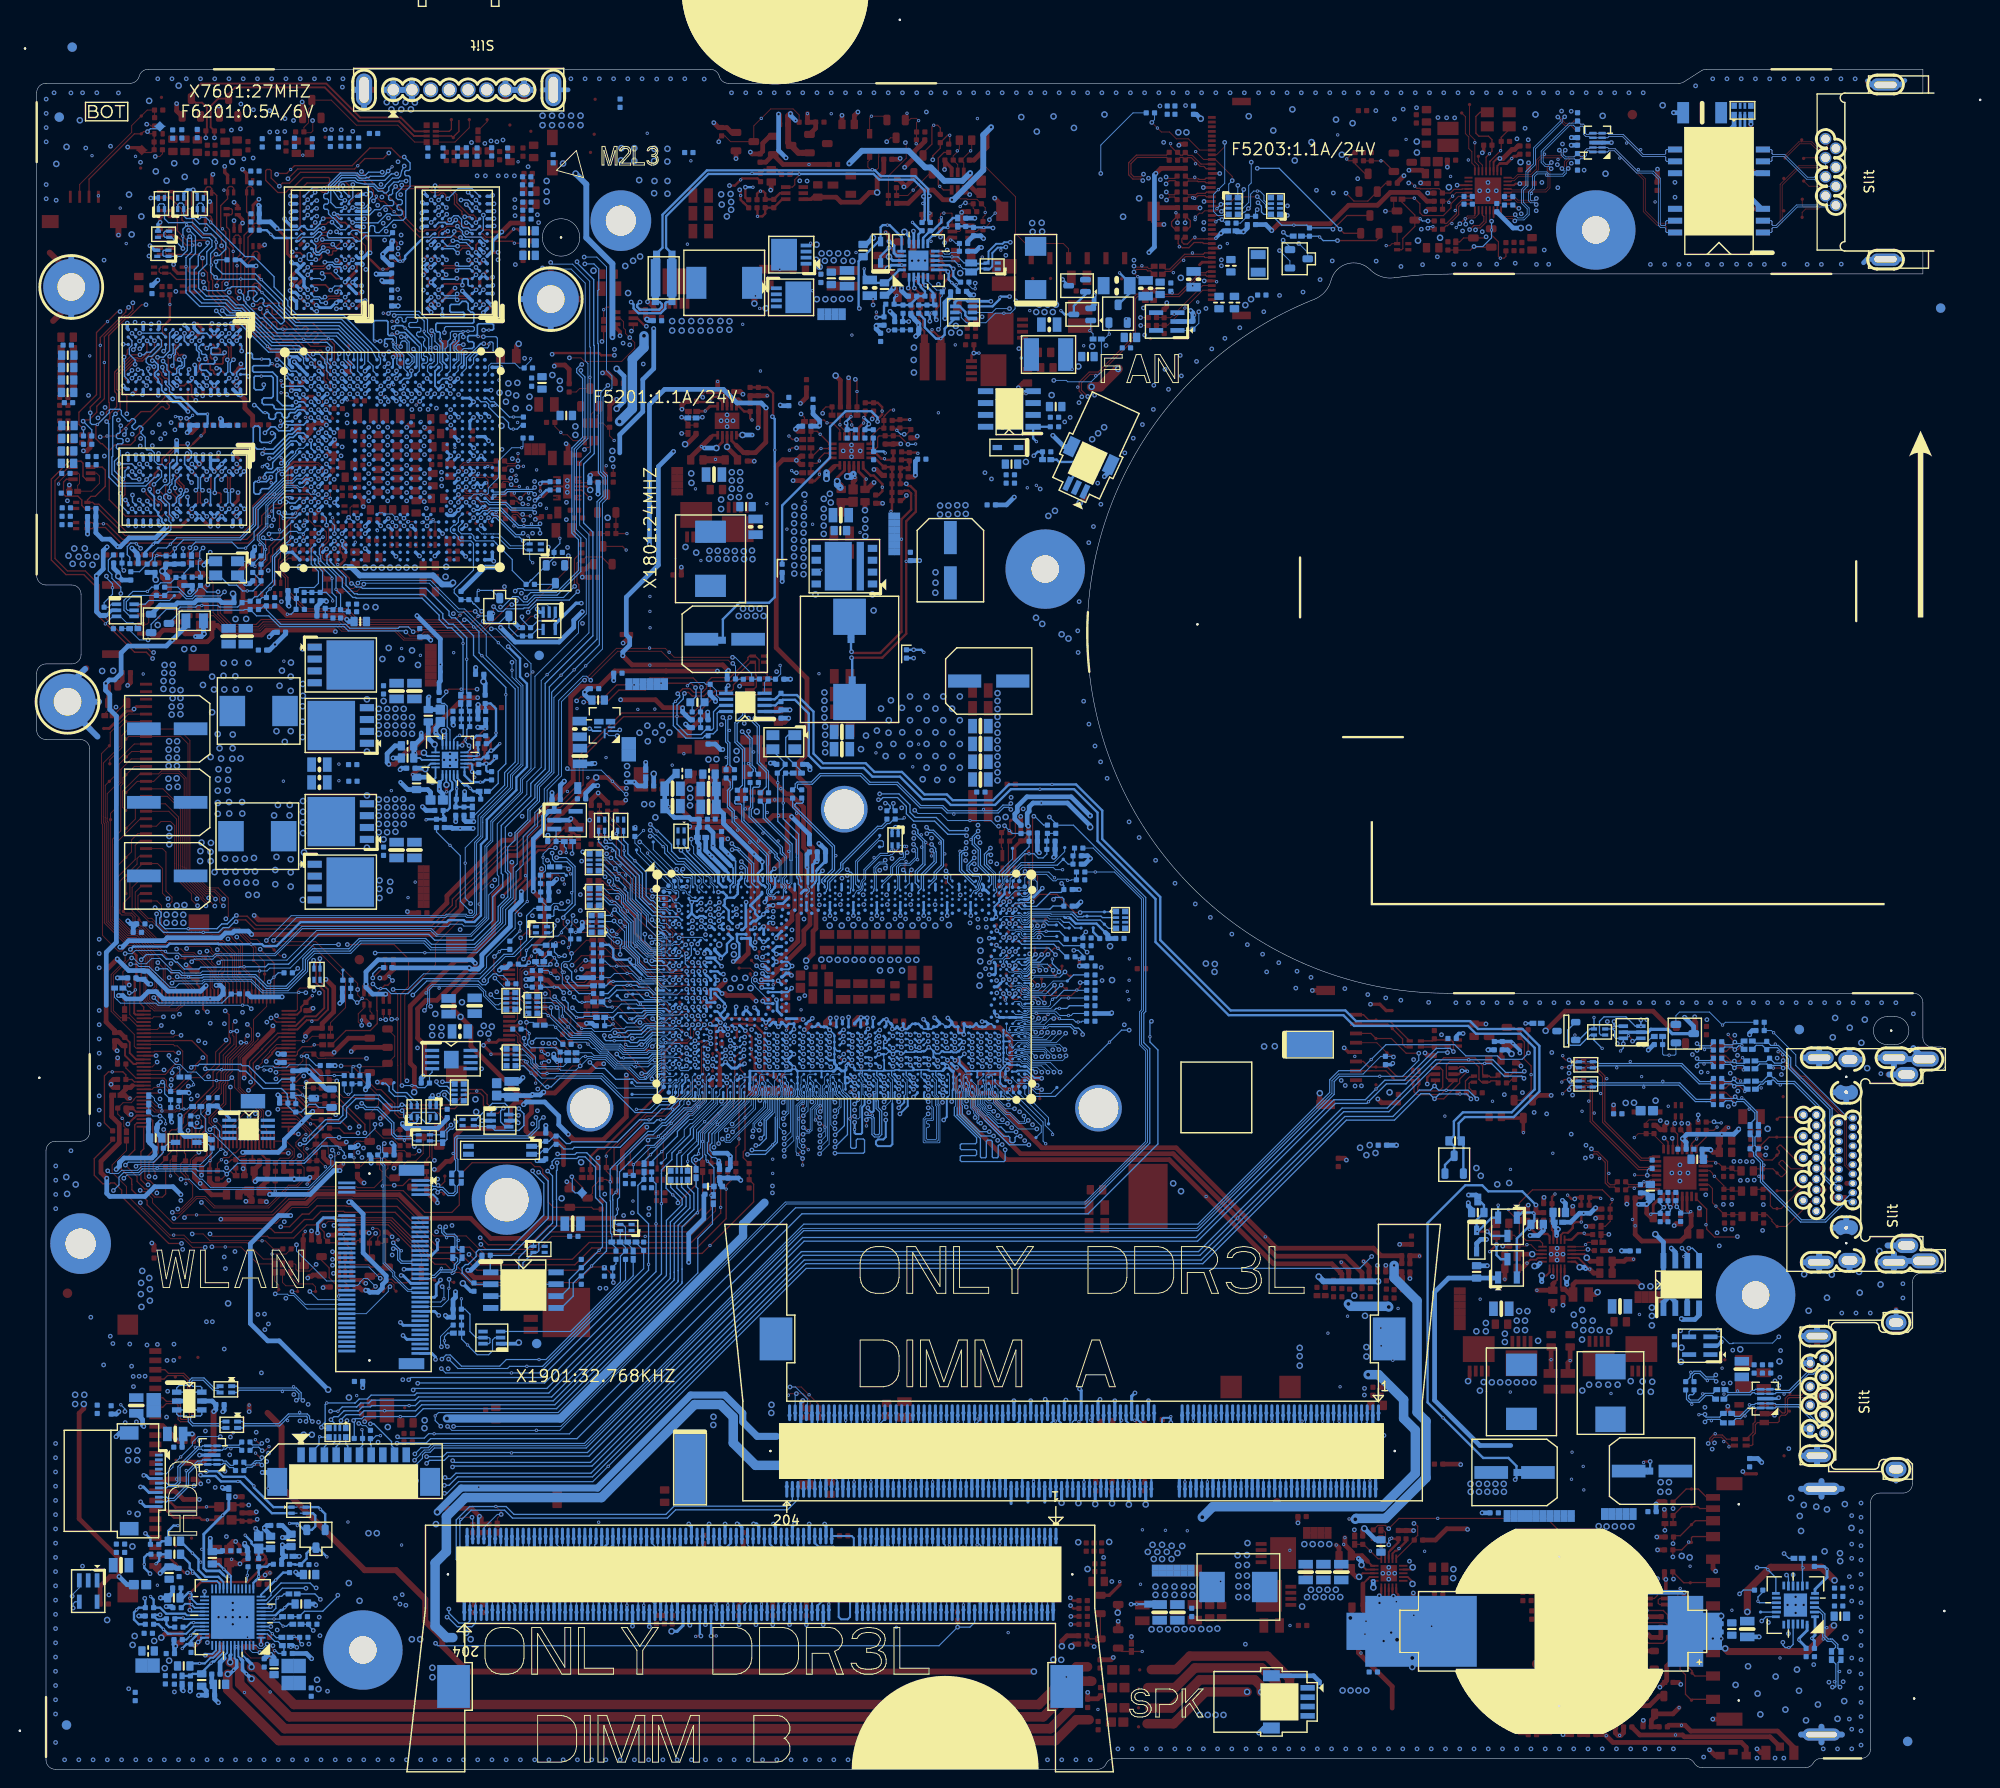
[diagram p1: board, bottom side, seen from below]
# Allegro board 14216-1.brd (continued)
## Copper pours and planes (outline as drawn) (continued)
VCC_CORE on L3: 103.11,83.34 102.34,84.1 101.45,84.1 101.2,84.36 101.2,87.66 100.44,88.42 96.2,88.42 93.02,91.6 93.02,92.96 92.39,93.59 92.39,94.24 92.69,94.54 94.25,94.54 94.78,94 94.78,93 95.1,92.69 95.66,92.69 95.98,93 95.98,96.47 95.52,96.93 95.52,100.59 96.42,101.49 96.42,101.5 97.59,101.5 97.92,101.83 97.92,104.68 98.53,105.29 98.53,114.39 101.26,117.12 118.85,117.12 119.37,116.61 119.37,106.75 120.75,105.37 120.75,101.69 118.66,99.6 111.49,99.6 110.98,99.09 110.98,98.07 111.36,97.69 111.87,97.69 112.25,98.07 122.56,98.07 122.79,97.85 122.79,91.08 123.68,90.19 123.68,89.06 123.3,88.68 109.71,88.68 109.46,88.42 109.46,83.55 109.25,83.34
VCC_CORE on L4: 118.85,117.12 107.12,117.12 104.94,114.94 104.94,106.51 106.26,105.19 110.8,105.19 114.33,108.72 119.18,108.72 119.35,108.88 119.35,116.63
VCC_CORE on L4: 108.08,93 123.58,93 123.96,92.62 123.96,88.94 123.58,88.56 109.59,88.56 109.46,88.42 109.46,83.11 109.18,82.83 101.4,82.83 101.22,83.01 101.22,86.78 102.24,87.8 102.88,87.8 102.88,87.81 103.19,87.81 106.48,91.1 107.07,91.1 107.32,91.35 107.32,92.24
VDD10 on TOP: 51.74,174.86 51.57,175.03 51.57,177.13 51.85,177.41 54.63,177.41 54.98,177.06 55.69,177.06 56.19,176.55 56.83,176.55 57.09,176.3 57.09,175.25 56.7,174.86 ; 4 cut-outs
VDD10 on BOTTOM: 45.06,166.91 44.86,167.11 44.86,169.23 45.32,169.69 45.32,171.05 45.73,171.46 46.96,172.69 51.35,172.69 53.47,170.56 53.48,170.56 53.48,167.55 53.19,167.26 51.24,167.26 51.17,167.34 51.17,170.15 50.89,170.43 46.99,170.43 46.53,169.97 46.53,167.1 46.34,166.91 ; 6 cut-outs
VDD10 on L4: 51.5,169.21 51.73,168.98 53.33,168.98 53.82,169.47 53.82,172.96 56.11,175.25 56.11,176.97 55.73,177.36 52.45,177.36 51.5,176.42
VDDREG on TOP: 54.8,169.39 54.8,169.4 53.7,169.4 53.25,169.84 50.61,169.84 50.56,169.9 50.56,170.03 50.59,170.07 51.62,170.07 52.66,171.11 53.48,171.11 53.72,171.35 53.72,171.38 53.72,171.61 53.72,171.61 53.72,172.58 53.87,172.73 54.75,172.73 54.89,172.59 54.89,169.48 ; 1 cut-out
0D675V_S0 on TOP: 55.29,10.62 53.97,11.95 53.97,17.12 54.19,17.35 56.37,17.35 56.37,13.47 57.51,12.32 57.51,10.77 57.36,10.62
0D675V_S0 on TOP: 157.16,13.49 157,13.64 157,25.33 157.28,25.61 158.78,25.61 159.09,25.3 159.09,13.78 158.8,13.49 ; 4 cut-outs
0D675V_S0 on TOP: 123.44,31.78 123.37,31.84 123.37,36.95 123.53,37.11 124.32,37.11 124.44,37 124.44,31.89 124.33,31.78 ; 6 cut-outs
0D675V_S0 on BOTTOM: 123.38,36.2 123.25,36.32 123.25,36.76 123.5,37.01 123.5,38.97 123.58,39.04 123.94,39.04 124.39,38.59 124.39,36.55 124.04,36.2
0D675V_S0 on BOTTOM: 123.83,29.11 123.78,29.16 123.78,30.86 122.99,31.65 122.99,32.85 123.2,33.05 127.06,33.05 127.26,32.85 127.26,29.76 126.61,29.11
0D675V_S0 on BOTTOM: 157.46,13.43 157.26,13.63 157.26,14.75 157.54,15.03 160.49,15.03 160.79,14.73 160.79,13.74 160.49,13.43
0D675V_S0 on L4: 56.81,10 56.63,10.18 56.63,12.18 56.9,12.45 66.35,12.45 66.78,12.88 86.55,12.88 88.55,14.88 99.79,14.88 102.17,12.5 154.6,12.5 157.11,15.01 158.85,15.01 159.05,14.81 159.05,12.15 156.9,10
1D05S_VCCST on TOP: 120.73,83.78 120.67,83.84 120.67,87.32 120.93,87.59 122.25,87.59 122.96,86.88 122.96,85.12 122.36,84.52 121.89,84.52 121.15,83.78 ; 3 cut-outs
1D05S_VCCST on BOTTOM: 121.93,80.83 121.32,81.44 121.32,81.46 121.07,81.71 121.07,86.66 121.35,86.94 122.61,86.94 123.07,86.48 123.07,83.34 123.2,83.21 123.5,83.21 123.51,83.21 123.54,83.21 123.77,82.97 124.31,82.97 124.32,82.98 124.53,82.98 124.67,82.84 124.67,81.29 124.25,80.87 124.08,80.87 124.04,80.83
1D05S_VCCST on BOTTOM: 88.28,79.78 86.5,81.56 86.5,91.81 86.51,91.82 86.51,92.81 89.19,95.48 92.25,95.48 92.36,95.38 92.36,94.87 92.06,94.57 90.2,94.57 88.08,92.45 88.08,91.06 88.05,91.03 87.29,91.03 87.27,91 87.27,90.33 87.3,90.31 88.05,90.31 88.15,90.21 88.15,88.72 88.47,88.4 90.8,88.4 90.96,88.56 90.96,89.13 91.12,89.29 91.64,89.29 91.67,89.26 91.67,86.54 91.66,86.53 89.81,86.53 89.73,86.46 89.73,83.88 89.91,83.7 91.24,83.7 91.33,83.61 91.33,81.55 91.24,81.46 89.06,81.46 88.78,81.18 88.78,80.75 89.16,80.37 91.14,80.37 91.24,80.27 91.24,79.86 91.17,79.78 ; 7 cut-outs
1D05S_VCCST on L3: 121.7,86.96 122.05,86.96 122.28,86.73 122.28,84.6 122.11,84.43 121.66,84.43 121.35,84.74 121.35,86.61
1D05V_HSIO on TOP: 138.83,106.07 138.74,106.16 138.74,107.15 138.83,107.24 139.08,107.24 139.69,107.86 141.36,107.86 141.58,107.64 141.58,106.16 141.49,106.07
1D05V_HSIO on BOTTOM: 132.68,106.02 132.53,106.17 132.53,107.48 134.35,109.31 142.64,109.31 144.2,110.86 145.13,110.86 145.3,111.03 146.79,111.03 146.97,110.85 146.97,108.64 146.72,108.39 144.7,108.39 142.46,106.15 140.31,106.15 139.66,106.79 139.66,107.79 139.21,108.24 138.28,108.24 137.81,107.77 135.37,107.77 134.85,107.25 134.85,106.18 134.69,106.02 ; 2 cut-outs
1D05V_PWR on BOTTOM: 134.55,116.31 134.29,116.57 131.47,116.57 131.26,116.77 131.26,123.08 130.16,124.18 130.16,127.74 130.27,127.86 137.84,127.86 140.59,125.1 140.59,119.32 141.92,117.99 141.92,116.44 141.79,116.31 ; 2 cut-outs
1D5V_PWR on BOTTOM: 145.82,102.14 145.74,102.22 145.74,102.99 145.91,103.16 145.91,104.83 145.95,104.87 147.56,104.87 147.76,104.67 147.76,102.32 147.58,102.14 ; 2 cut-outs
1D05V_S0 on TOP: 127.46,104.32 127.34,104.45 127.34,105.36 127.74,105.77 128.81,105.77 128.91,105.87 128.91,107.17 129.31,107.57 129.53,107.57 129.8,107.83 129.8,109.21 129.43,109.57 128.04,109.57 127.94,109.66 127.94,110.59 128.05,110.7 132.24,110.7 132.49,110.45 132.49,108.67 133.32,107.84 133.32,106.44 133.25,106.37 132.84,106.37 132.34,106.87 131.21,106.87 130.96,106.61 129.86,106.61 129.62,106.38 129.62,105.59 129.22,105.19 128.18,105.19 128.05,105.06 128.05,104.6 127.77,104.32 ; 5 cut-outs
1D05V_S0 on TOP: 145.4,138.6 144.17,139.83 142.54,139.83 142.54,139.83 142.38,139.83 142.15,140.06 142.15,141.36 142.29,141.5 144.72,141.5 145.98,140.24 146.29,140.24 146.73,139.8 146.73,138.04 146.68,138 145.53,138 145.4,138.13 ; 2 cut-outs
1D05V_S0 on TOP: 123.39,82.07 122.39,83.08 122.3,83.08 121.99,83.39 121.99,83.94 127.38,83.94 128.3,84.86 129.89,84.86 130.15,84.6 130.15,83.33 130.05,83.23 127.71,83.23 127.26,82.78 124.9,82.78 124.62,82.5 124.62,82.15 124.54,82.07 ; 1 cut-out
1D05V_S0 on BOTTOM: 127.26,79.94 127.11,80.09 127.11,80.52 127.23,80.65 127.23,81 127.14,81.1 127.14,81.52 127.49,81.87 127.49,83.95 127.72,84.18 127.87,84.18 127.85,84.2 127.85,84.75 128.12,85.03 129.98,85.03 130.31,84.71 130.31,81.44 130.03,81.16 130.03,80.22 129.75,79.94
1D05V_S0 on BOTTOM: 136.37,109.5 136.04,109.82 136.04,115.7 136.33,115.99 142.5,115.99 142.86,116.35 142.86,117.81 141.89,118.79 141.89,125.37 139.54,127.72 139.54,138.55 139.55,138.57 139.55,141.26 139.79,141.5 142.83,141.5 142.98,141.35 142.98,140.37 142.24,139.63 142.24,132.55 143.51,131.28 143.51,119.73 144.54,118.7 144.54,115.22 144.06,114.74 144.06,114.19 143.31,113.44 143.31,111.66 143.03,111.38 142.25,111.38 142,111.64 141.65,111.64 141.44,111.42 141.43,111.42 141.43,110.84 141.65,110.63 141.65,109.6 141.55,109.5
1D5V_S0 on BOTTOM: 145.27,105.2 144.72,105.75 143.95,105.75 143.9,105.8 143.9,106.52 143.99,106.61 146.24,106.61 146.77,106.08 146.77,105.34 146.63,105.2
1D05V_S0 on L2VCC: 124.9,83.02 123.87,84.06 123.87,91.03 125.79,91.03 127.05,92.28 127.05,93.33 126.32,94.05 123.87,94.05 123.87,103.2 127.3,106.63 127.3,109.04 127.95,109.69 132.39,109.69 134.81,112.11 140.87,112.11 141.14,111.84 141.14,104.25 138.97,102.07 137.57,102.07 136.57,101.07 136.57,98.28 135.79,97.5 133.89,97.5 130.47,94.09 130.47,89.87 132.13,88.22 132.13,83.93 131.22,83.02
1D05V_S0 on L3: 123.83,84.15 123.83,90.45 122.94,91.33 122.94,98.17 122.79,98.33 122.79,102.14 127.24,106.58 127.24,108.87 128.12,109.76 132.48,109.76 134.03,111.31 134.91,111.31 135.83,112.23 140.24,112.23 140.8,111.67 140.8,108.08 139.8,107.08 137.94,107.08 137.65,106.8 137.65,105.82 128.46,96.63 128.46,96.02 128.4,96.02 127.03,94.64 127.03,93.2 127.36,92.87 127.36,90.5 129.11,88.76 129.11,87.24 130.27,86.08 130.27,83.61 129.75,83.09 124.89,83.09
1D05V_S0 on L4: 136.38,82.33 131.93,82.33 131.6,82.66 130.69,82.66 130.47,82.87 130.47,83.79 129.95,84.31 129.95,84.59 129.74,84.79 127.95,84.79 127.8,84.64 127.8,84.24 127.07,83.51 127.05,83.51 127.05,82.58 127.56,82.07 131.38,82.07 131.63,81.82 131.63,81.61 132.32,80.93 134.73,80.93 135.36,80.29 136.25,80.29 136.38,80.17 136.38,75.59 137.01,74.96 139.69,74.96 140.78,73.88 141.08,73.88 141.34,74.13 141.34,74.44 138.67,77.12 137.52,77.12 137.4,77.25 137.4,81.31
1D05V_VGA_OUT2 on TOP: 148.19,137.95 148.06,138.08 148.06,140.8 148.39,141.13 152.13,141.13 152.25,141 152.25,140.16 151.62,139.53 151.62,139.2 150.38,137.95
1D05V_VGA_S0 on TOP: 149.61,141.46 149.33,141.74 149.33,144.64 149.81,145.11 149.81,148.54 150.93,149.66 156.95,149.66 159.4,147.22 159.4,146.46 160.7,145.16 161.24,145.16 161.4,144.99 161.4,143.82 161.18,143.59 159.28,143.59 159.16,143.47 159.16,143.47 158.56,142.87 155.3,142.87 154.78,142.34 154.68,142.25 154.17,141.73 153.9,141.46 ; 7 cut-outs
1D05V_VGA_S0 on TOP: 159.65,137.1 159.48,137.27 159.48,138.74 159.83,139.09 161.1,139.09 161.17,139.02 161.17,137.17 161.1,137.1 ; 2 cut-outs
1D05V_VGA_S0 on TOP: 169.76,128.35 169.53,128.58 169.53,128.86 169.2,129.19 168.56,129.19 168.51,129.24 168.51,130.15 168.59,130.23 169.22,130.23 169.68,129.77 170.57,129.77 171.51,128.83 171.51,128.5 171.36,128.35 ; 2 cut-outs
1D05V_VGA_S0 on BOTTOM: 160.05,136.66 159.79,136.92 159.79,139.33 160.55,140.09 160.55,141.1 159.79,141.87 159.79,142.63 159.66,142.76 159.66,145.17 159.79,145.3 159.79,146.06 158.81,147.04 155.29,147.04 153.43,145.17 152.51,145.17 152.5,145.18 151.71,145.18 151.59,145.06 151.59,144.63 151.32,144.35 147.84,144.35 147.51,144.69 147.51,147.12 147.58,147.19 148.6,147.19 148.97,147.56 148.97,148.28 149.15,148.46 151.56,148.46 152.2,149.1 155.12,149.1 155.12,149.09 156.47,149.09 156.62,149.23 156.62,149.41 156.34,149.69 156.16,149.69 155.85,149.99 155.85,150.93 156.05,151.13 157.13,151.13 157.5,150.76 157.5,149.99 158.9,148.6 158.9,148.34 158.77,148.22 158.77,147.96 158.9,147.84 159.28,147.84 159.41,147.96 159.66,147.96 159.79,147.84 159.79,147.58 159.66,147.45 159.66,147.2 159.92,146.95 160.04,146.95 160.17,147.07 160.55,147.07 160.68,146.95 160.68,146.18 161.44,145.42 161.44,144.28 161.19,144.03 161.19,136.91 160.93,136.66 ; 8 cut-outs
1D05V_VGA_S0 on L3: 153.65,148.98 154.1,148.53 156.12,148.53 158.76,145.89 160.2,145.89 160.37,145.72 160.37,144.33 161.14,143.56 161.14,133.36 160.02,132.24 160.02,126.8 159.84,126.61 159.32,126.61 159.13,126.8 159.13,133.91 159.41,134.18 159.41,139.15 158.39,140.16 158.39,141.06 157.54,141.92 156.86,141.92 156.55,141.6 154.94,141.6 154.77,141.77 149.91,141.77 149.13,142.55 149.13,147.81 150.29,148.98
1D35V_PWR on TOP: 77.17,17.09 77.08,17.19 77.08,17.2 77.08,20.9 77.3,21.11 86.17,21.11 86.77,20.52 86.77,17.23 86.64,17.09 84.74,17.09 84.73,17.09 ; 2 cut-outs
1D35V_PWR on BOTTOM: 56.74,21.11 56.49,21.35 56.49,22.35 56.49,22.36 56.49,22.86 57.23,23.6 60.74,23.6 60.89,23.45 60.89,23.02 60.74,22.86 58.03,22.86 57.69,22.52 57.69,21.24 57.56,21.11
1D35V_PWR on BOTTOM: 77.2,16.79 77.07,16.92 77.07,20.86 77.32,21.11 84.56,21.11 84.82,20.86 84.82,17.03 84.59,16.79 ; 2 cut-outs
1D35V_PWR on L3: 80.2,18.19 79.92,18.47 79.92,21.99 74.5,27.4 60.5,27.4 59.14,26.04 59.14,23.27 56.96,21.1 56.25,21.1 55.85,21.51 55.85,23.39 57.42,24.96 57.42,27.28 59.21,29.07 75.37,29.07 84.82,19.62 84.82,18.44 84.56,18.19
1D35V_S3 on TOP: 60.31,51.85 60.18,51.97 58.78,51.97 58.66,52.1 58.66,52.56 58.74,52.65 60.9,52.65 61.07,52.48 61.07,51.97 60.94,51.85
1D35V_S3 on TOP: outline of 91 points within 66.67,15.14 150.1,82.97 ; 49 cut-outs
1D35V_S3 on BOTTOM: 88.37,15.52 88.09,15.8 88.09,20.8 87.39,21.49 80.5,21.49 80.37,21.62 80.37,27.84 81.45,28.92 100,28.92 100.04,28.89 121.74,28.89 123.19,27.44 134.38,27.44 134.97,26.85 134.97,26.21 134.8,26.03 93.88,26.03 91.27,23.42 91.27,15.84 90.95,15.52
1D35V_VGA_S0 on TOP: 196.91,128.46 196.29,129.08 196.29,130.23 196.4,130.35 197.33,130.35 198.02,131.03 201.46,131.03 201.6,130.89 201.6,129.24 200.82,128.46 ; 1 cut-out
1D35V_VGA_S0 on TOP: 191.79,146.23 191.6,146.42 191.6,147.71 191.77,147.87 191.77,147.87 192.14,147.87 192.38,147.63 192.38,146.96 192.5,146.84 193.21,146.84 193.3,146.93 193.3,147.85 193.4,147.95 193.96,147.95 194.16,147.75 194.16,146.57 193.83,146.23
1D35V_VGA_S0 on TOP: 151.42,38.18 150.33,39.26 150.33,49.92 153.09,49.92 153.45,50.27 156.34,50.27 157.34,51.27 178.85,51.27 182.68,55.1 192.02,55.1 193.27,53.85 193.27,48.67 192.25,47.64 192.25,46.08 192.03,45.86 189.62,45.86 189,45.24 187.68,45.24 183.87,41.43 171.64,41.43 170.14,39.94 164.5,39.94 162.74,38.18 ; 2 cut-outs
1D35V_VGA_S0 on TOP: outline of 569 points within 151.71,139.09 201.31,176.03 ; 97 cut-outs
1D35V_VGA_S0 on TOP: 189.45,153.1 188.96,153.6 188.96,153.83 189.08,153.95 189.08,154.44 188.58,154.94 188.22,154.94 188.02,154.74 188.02,154.44 188.2,154.26 188.2,154 187.64,153.45 187.46,153.45 187.31,153.6 187.31,153.82 187.76,154.27 187.76,155.04 187.57,155.23 187.08,155.23 185.83,153.98 185.48,153.98 185.35,154.11 185.07,154.11 184.45,153.48 184.25,153.48 183.82,153.91 183.82,155.25 184.09,155.52 185.08,155.52 185.63,156.06 185.63,157.16 186.28,157.8 187.92,157.8 188.23,158.12 188.23,158.28 188.25,158.3 188.9,158.3 188.96,158.24 188.96,157.33 189.68,156.6 189.68,154.65 189.31,154.28 189.31,154 189.52,153.8 189.63,153.8 189.68,153.75 189.68,153.64 189.83,153.48 189.83,153.21 189.73,153.1
1D35V_VGA_S0 on TOP: outline of 211 points within 175.22,138.33 193.94,153.99 ; 9 cut-outs
1D35V_VGA_S0 on BOTTOM: 189.52,153.1 189.03,153.58 188.64,153.58 188.18,153.13 187.9,153.13 187.6,153.43 187.51,153.43 187.34,153.6 187.34,153.83 187.48,153.98 187.76,153.98 187.87,153.86 188.95,153.86 189.08,153.99 189.31,153.99 189.8,153.51 189.8,153.21 189.69,153.1
1D35V_VGA_S0 on BOTTOM: 175.45,156.21 175.39,156.27 175.39,156.44 175.88,156.93 175.88,157.32 175.74,157.46 175.74,157.68 175.88,157.81 175.88,158.09 175.78,158.2 175.78,158.55 175.93,158.7 175.93,159.47 177.32,160.86 177.32,161.6 177.12,161.8 176.31,161.8 176.16,161.95 176,161.95 175.88,162.08 175.88,163 175.42,163.45 175.42,163.63 175.52,163.73 175.67,163.73 176.13,163.28 177.35,163.28 178.33,162.3 178.33,158.89 177.25,157.81 176.64,157.81 176.12,157.29 176.12,156.41 175.93,156.21
1D35V_VGA_S0 on BOTTOM: 171.35,138.95 171.22,139.07 171.22,143.48 170.63,144.07 170.63,145.1 170.43,145.3 161.82,145.3 161.19,145.93 161.19,146.31 161.31,146.44 162.08,146.44 162.2,146.31 164.46,146.31 164.67,146.11 165.33,146.11 165.53,146.31 167.66,146.31 168.43,147.07 168.7,147.07 168.82,146.95 168.82,146.75 168.55,146.48 168.55,146.15 168.76,145.94 169.11,145.94 169.48,146.31 171.09,146.31 171.22,146.18 172.87,146.18 173,146.06 173,145.68 172.36,145.04 172.24,145.04 172.24,141.1 173,140.34 173,139.99 171.95,138.95
1D35V_VGA_S0 on BOTTOM: outline of 373 points within 151.89,128.18 201.94,174.9 ; 102 cut-outs
1D35V_VGA_S0 on BOTTOM: outline of 144 points within 157.74,156.14 175.01,163.78 ; 5 cut-outs
1D35V_VGA_S0 on L3: outline of 149 points within 151.91,48.85 202.97,175.47 ; 1 cut-out
1D35V_VGA_S0 on L4: 194.19,131.19 191.38,131.19 188.91,133.66 188.91,134.22 189.08,134.4 189.42,134.4 189.85,133.96 195.82,133.96 199.58,137.73 199.58,140.19 199.57,140.2 199.57,140.82 199.62,140.88 199.62,142.11 200.77,143.26 200.77,152.04 199.62,153.18 199.62,156.12 195.23,160.51 195.23,165.71 196.15,166.63 201.12,166.63 202.48,165.27 202.48,129.13 201.92,128.57 196.81,128.57 ; 1 cut-out
1D35V_VGA_S0 on L5GND: 191.96,49.12 191.43,49.64 191.43,52.53 194.74,55.83 194.74,64.62 191.82,67.55 191.82,75.8 190.42,77.2 190.42,87.58 192.96,90.12 192.96,126.82 197.29,131.16 202.93,131.16 202.93,128.04 200.45,128.04 198.84,127.38 198.18,125.77 198.18,119.32 198.84,117.71 200.45,117.05 202.93,117.05 202.93,111.5 199.53,111.5 197.92,110.84 197.26,109.23 197.26,68.23 197.92,66.62 199.53,65.96 201.93,65.96 201.93,49.12
3D3V_AUX_KBC on BOTTOM: 101.66,160.36 100.3,160.36 100.12,160.54 100.12,161.64 100.13,161.65 100.13,162.15 100.21,162.23 101.29,162.23 101.72,161.8 101.72,160.41
3D3V_AUX_KBC on BOTTOM: 173.23,83.48 173.13,83.58 173.13,84.76 173.19,84.82 175.28,84.82 175.47,84.63 175.47,83.71 175.24,83.48
3D3V_CAMERA_S0 on TOP: 81.69,159.2 80.21,160.67 79.46,160.67 78.94,161.19 78.05,161.19 78.05,161.43 78.1,161.48 78.12,161.48 79.68,161.48 79.69,161.47 80.75,161.47 82.17,160.05 82.17,159.41 81.95,159.2
3D3V_CAMERA_S0 on BOTTOM: 81.73,158.78 81.35,159.16 81.35,159.82 82.24,160.71 85.64,160.71 86.47,159.88 86.47,158.91 86.34,158.78 ; 4 cut-outs
3D3V_CARD_S0 on TOP: 23.76,15.88 23.6,16.03 23.6,17.76 23.91,18.06 27.18,18.06 27.6,17.65 28.66,17.65 28.94,17.36 28.94,16.22 28.6,15.88
3D3V_CARD_S0 on BOTTOM: 20.46,15.27 20.37,15.36 20.37,17.1 20.5,17.23 24.32,17.23 24.5,17.06 24.5,15.37 24.4,15.27 ; 4 cut-outs
3D3V_CARD_S0 on BOTTOM: 11.64,18.16 11.55,18.26 11.55,20.45 11.66,20.57 12.08,20.57 12.32,20.32 12.32,19.91 12.6,19.64 12.61,19.64 13.19,19.05 13.19,18.74 13.43,18.49 14.47,18.49 14.49,18.47 14.49,18.18 14.47,18.16 ; 3 cut-outs
3D3V_LAN_S5 on TOP: 43.92,163.14 43.67,163.4 43.67,165.2 43.87,165.41 45.55,165.41 45.8,165.16 46.97,165.16 47.4,165.59 47.68,165.59 48.21,166.11 48.21,167.28 48.25,167.32 48.41,167.32 48.47,167.26 48.47,166.02 47.74,165.29 47.74,164.27 47.3,163.83 47.3,163.2 47.24,163.14 ; 4 cut-outs
3D3V_LAN_S5 on TOP: 55.17,162.34 55.09,162.42 55.09,163.15 54.73,163.51 53.76,163.51 53.48,163.24 52.97,163.24 52.84,163.37 52.84,164.27 52.93,164.36 57.22,164.36 57.78,163.8 57.78,162.43 57.69,162.34 ; 2 cut-outs
3D3V_LAN_S5 on TOP: 55.27,171.58 55.21,171.64 55.21,172.59 55.3,172.68 55.9,172.68 56.24,173.02 56.24,174.54 56.36,174.66 57.95,174.66 57.95,174.66 58.17,174.66 58.27,174.56 58.27,171.66 58.2,171.58
3D3V_LAN_S5 on TOP: 47.33,170.59 47.11,170.81 45.27,170.81 45.05,171.04 45.05,172.18 45.24,172.37 45.71,172.37 45.9,172.18 45.9,171.74 46.04,171.6 47.56,171.6 47.69,171.47 47.69,170.68 47.6,170.59 ; 1 cut-out
3D3V_LAN_S5 on L3: 56.64,175.11 56.98,174.76 56.98,172.98 56.85,172.85 46.82,172.85 46.14,172.17 46.14,168.22 47.63,166.72 47.63,164.16 48.2,163.58 49.23,163.58 49.92,164.27 57.54,164.27 57.69,164.11 57.69,162.8 57.36,162.46 46.41,162.46 43.11,165.76 43.11,168.94 43.42,169.24 43.42,174.27 44.25,175.11
3D3V_PWR on BOTTOM: 31.76,27.33 31.63,27.45 31.63,30.63 32.01,31.01 32.01,38 32.9,38.88 38.34,38.88 38.96,38.27 38.96,28.11 38.34,27.49 32.19,27.49 32.02,27.33 ; 1 cut-out
3D3V_S0 on TOP: 95.02,138.43 91.83,141.62 91.12,141.62 89.63,143.11 89.63,143.97 89.87,144.22 92.44,144.22 96.44,140.22 97.78,140.22 98.09,140.54 99.05,140.54 99.31,140.28 99.31,138.94 98.8,138.43
3D3V_S0 on TOP: 36.19,12.69 35.98,12.9 35.98,17.15 36.14,17.31 38.55,17.31 38.59,17.27 38.59,15.73 38.59,15.73 38.59,13.67 38.09,13.17 38.09,12.86 37.91,12.69 ; 3 cut-outs
3D3V_S0 on TOP: 30.54,56.93 29.45,58.02 29.45,58.4 28.84,59.01 28.15,59.01 28.05,59.11 28.05,59.49 28.13,59.57 30.21,59.57 30.33,59.44 30.33,58.5 30.49,58.35 31.1,58.35 31.43,58.02 31.43,57.21 31.15,56.93
3D3V_S0 on TOP: 123.33,113.13 123.26,113.19 123.26,116.88 125.69,119.3 126.72,119.3 126.72,118.44 126.59,118.3 126.21,118.3 124.95,117.05 124.95,116.61 125.19,116.37 126.41,116.37 126.54,116.25 126.54,116.08 126.42,115.97 125.56,115.97 125.55,115.98 124.21,115.98 123.85,115.61 123.85,113.23 123.75,113.13
3D3V_S0 on TOP: 144.66,91.11 144.61,91.17 144.61,99.23 144.66,99.28 147.49,99.28 147.54,99.23 147.54,98.07 148.4,97.21 148.72,97.21 149.39,97.88 150.51,97.88 151.11,97.27 151.3,97.08 151.3,94.72 151.09,94.52 149.88,94.52 149.81,94.59 149.81,95.05 149.86,95.09 150.54,95.09 150.67,95.22 150.67,96.51 150.38,96.79 150.03,96.79 149.72,96.48 147.96,96.48 147.63,96.8 146.48,96.8 146.27,96.6 146.27,91.2 146.19,91.11 ; 5 cut-outs
3D3V_S0 on TOP: 144.73,130.76 144.4,131.09 144.4,132.54 144.22,132.71 142.91,132.71 142.75,132.87 142.75,133.74 142.75,133.74 142.75,135.08 143.39,135.72 144.65,135.72 145.58,136.64 146.8,136.64 146.84,136.6 146.84,135.46 146.54,135.16 146.54,134.52 146.26,134.24 146.26,130.89 146.13,130.76 ; 8 cut-outs
3D3V_S0 on TOP: 161.08,25.69 160.65,26.11 160.65,28.31 160.81,28.46 163.2,28.46 164.53,29.8 164.53,37.29 165.29,38.05 167.47,38.05 167.65,37.87 167.65,36.86 167.98,36.52 168.04,36.52 168.06,36.49 175.81,36.49 176.31,36 176.31,34.95 175.85,34.49 168.35,34.49 167.8,33.94 167.8,29.02 164.47,25.69 ; 4 cut-outs
3D3V_S0 on TOP: 60.98,65.41 60.5,65.88 60.5,67.54 63.49,70.52 67.44,70.52 76,79.09 76,85.02 77.7,86.72 79.28,86.72 79.52,86.49 79.52,77.84 69.12,67.44 65.71,67.44 63.67,65.41 ; 2 cut-outs
3D3V_S0 on BOTTOM: 60.76,65.32 60.41,65.67 60.41,66.94 60.69,67.22 62.82,67.22 62.98,67.06 62.98,65.59 62.7,65.32 ; 1 cut-out
3D3V_S0 on BOTTOM: 24.34,57.05 24.06,57.33 24.06,58.55 24.62,59.11 27.62,59.11 27.79,58.93 31.22,58.93 31.6,58.55 31.6,57.28 31.38,57.05 ; 3 cut-outs
3D3V_S0 on BOTTOM: 162.63,13.55 162.37,13.82 162.37,22.19 162.31,22.25 162.3,22.25 162.11,22.44 162.11,22.45 161.13,23.42 161.13,27.6 161.23,27.71 164.16,27.71 164.68,27.19 164.68,13.94 164.29,13.55
3D3V_S0 on BOTTOM: 11.69,15.04 11.56,15.17 11.56,17.86 11.69,17.99 14.49,17.99 14.49,17.98 14.49,17.7 14.47,17.67 13.44,17.67 12.67,16.91 12.67,15.96 12.35,15.64 12.35,15.27 12.12,15.04 ; 2 cut-outs
3D3V_S0 on BOTTOM: 174.48,34.7 174.23,34.95 174.23,36.22 174.5,36.5 176.08,36.5 176.31,36.27 176.31,32.88 175.57,32.88 175.52,32.93 175.52,34.57 175.39,34.7
3D3V_S0 on BOTTOM: 144.4,85.32 144.33,85.4 144.33,85.9 144.41,85.97 145.56,85.97 145.86,86.27 145.86,86.75 145.61,87.01 144.45,87.01 144.37,87.09 144.37,91.88 144.51,92.02 144.51,94.38 144.58,94.45 144.58,100.86 144.48,100.95 141.1,100.95 141.1,100.95 140.96,100.95 140.46,100.45 139.98,100.45 138.89,101.54 138.37,101.54 136.75,99.92 134.27,99.92 134.04,100.15 134.04,101.25 134.08,101.29 136.89,101.29 138.17,102.56 143.52,102.56 143.66,102.7 143.66,104.7 143.76,104.8 144.4,104.8 144.52,104.67 144.52,103.47 145.57,102.42 145.57,99.21 146.26,98.52 146.26,91.95 146.26,91.95 146.26,91.58 145.56,90.87 145.56,89.6 145.86,89.3 146.39,89.3 146.54,89.15 146.54,85.76 146.1,85.32 ; 5 cut-outs
3D3V_S0 on BOTTOM: 90.08,141.35 85.34,146.09 85.34,149.44 82.36,152.43 79.48,152.43 77.07,154.84 77.07,156.75 77.2,156.87 78.72,156.87 78.98,156.62 79.36,156.62 79.48,156.49 79.48,154.46 80.37,153.57 83.17,153.57 83.42,153.83 83.42,156.11 83.93,156.62 84.44,156.62 84.74,156.93 84.74,158.17 84.82,158.25 86.21,158.25 86.34,158.12 86.34,157.89 86.85,157.38 86.85,153.72 86.92,153.65 86.92,152.86 87.45,152.32 87.45,152.01 90.66,148.8 90.66,145.47 92.26,143.87 92.26,142.67 90.95,141.35 ; 4 cut-outs
3D3V_S0 on L3: 51.88,5.28 46.2,10.96 38.37,10.96 36.95,12.37 35.75,12.37 35.36,12.76 35.36,14.84 35.69,15.17 38.49,15.17 38.49,15.17 38.56,15.17 39.59,14.14 46.59,14.14 52.78,7.95 66.45,7.95 67.66,9.16 90.21,9.16 91.7,7.67 155.7,7.67 162.27,14.23 164.43,14.23 164.9,13.76 164.9,8.87 163.68,7.65 163.67,7.65 161.61,5.59 161.61,5.59 161.38,5.36 77.03,5.36 76.8,5.59 71.39,5.59 71.08,5.28
3D3V_S0 on L3: 48.55,74.51 48.55,79.84 48.78,80.07 49.49,80.07 49.85,79.7 49.85,75.65 57.72,67.79 62.55,67.79 62.98,67.35 62.98,65.65 62.68,65.35 57.71,65.35
3D3V_S0 on L3: 98.07,139.49 99.2,139.49 99.36,139.66 99.36,143.11 99.38,143.13 99.38,143.77 100.39,144.78 101.73,144.78 104.2,147.25 110.78,147.25 112.45,148.92 116.06,148.92 116.35,149.22 117.65,149.22 117.83,149.04 117.83,148.7 117.93,148.59 118.8,148.59 118.96,148.75 118.96,150.13 118.87,150.22 111.76,150.22 110.09,148.54 103.66,148.54 100.92,145.8 99.78,145.8 97.92,143.94 97.92,139.65
3D3V_S0 on L4: 33.76,21.11 33.76,15.4 35.67,13.49 38.21,13.49 38.97,14.25 38.97,16.67 37.95,17.68 37.95,19.97 38.84,20.86 46.08,20.86 46.34,21.11 46.34,25.68 45.83,26.19 38.84,26.19
3D3V_S0 on L4: 77.46,89.2 88.12,99.85 88.12,101.76 93.21,106.85 93.21,132.42 91.82,133.81 91.82,138.11 88.34,141.6 88.34,142.71 89.71,144.09 90.09,144.09 90.09,144.09 90.26,144.09 96.63,137.72 96.63,133.41 100.18,129.85 100.18,120.39 96.63,116.84 96.63,104.3 91.04,98.71 91.04,97.24 78.71,84.91 77.68,84.91 77.46,85.12 ; 1 cut-out
3D3V_S0 on L4: 61.83,62.26 59.67,62.26 59.29,62.64 59.29,66.96 59.52,67.18 62.69,67.18 62.97,66.9 62.97,63.4
3D3V_S5 on TOP: 192.82,172.15 192.95,172.28 193.51,172.28 196.7,169.09 197.7,169.09 197.83,168.96 197.83,167.75 197.74,167.67 196.51,167.67 192.82,171.35
3D3V_S5 on TOP: 33.97,18.6 32.54,20.02 32.54,26.12 32.82,26.4 38.13,26.4 38.42,26.1 38.42,21.47 38.01,21.05 38.01,20.79 38.11,20.68 38.11,19.98 38.11,19.98 38.11,19.93 38.59,19.45 38.59,18.6
3D3V_S5 on TOP: 94.48,133.53 94.27,133.74 94.27,135.15 90.62,138.8 90.62,138.8 90.55,138.88 90.55,139.8 87.87,142.48 87.87,146.89 81.84,152.92 79.51,152.92 72.95,159.48 72.95,164.46 71.52,165.89 71.52,167.51 67.97,171.05 65.34,171.05 65.06,171.33 65.06,173.05 64.58,173.54 62.81,173.54 62.65,173.38 62.65,172.77 62.51,172.63 58.57,172.63 58.47,172.73 58.47,175.74 58.79,176.05 61.23,176.05 62.38,177.21 62.38,177.83 62.51,177.96 65.98,177.96 66.5,177.45 66.5,177.45 73.01,170.93 73.01,166.77 74.51,165.27 74.51,159.86 80,154.37 82.34,154.37 89.29,147.42 89.29,143.13 92.01,140.41 92.01,139.51 95.01,136.52 95.59,136.52 96.94,135.16 96.94,133.82 96.65,133.53 ; 3 cut-outs
3D3V_S5 on TOP: 147.91,60.69 148.95,60.69 149.28,61.02 149.28,63.66 147.89,65.05 146.9,65.05 146.69,64.85 146.69,64.34 145.98,63.63 145.6,63.63 145.5,63.53 145.5,63.02 145.55,62.97 146.87,62.97 147.2,63.3 147.86,63.3 147.91,63.25 147.91,61.6 147.61,61.29 147.61,60.99
3D3V_S5 on TOP: 46.46,62.15 45.99,62.62 45.99,65.86 49.41,69.28 59.68,69.28 63.13,72.73 64.31,72.73 65.11,73.53 65.11,76.88 89.7,101.47 89.7,105.28 93.17,108.75 93.17,121.27 93.25,121.36 93.27,121.36 95.63,123.73 97.48,123.73 97.63,123.59 97.63,121.68 94.48,118.54 94.48,108.14 91.12,104.78 91.12,101.92 91.76,101.29 91.76,101.14 91.77,101.13 91.77,100.76 91.61,100.6 91.13,100.6 66.56,76.03 66.56,73.15 64.36,70.96 63.38,70.96 60.11,67.69 50.68,67.69 50.25,67.25 50.22,67.25 48.37,65.4 48.37,62.36 48.16,62.15
3D3V_S5 on TOP: 184.31,29.88 181.81,32.38 181.81,35.5 176.78,40.53 173.84,40.53 173.19,39.88 173.18,39.88 171.02,37.72 169.24,37.72 169.16,37.8 169.16,38.27 169.25,38.35 169.86,38.35 169.88,38.34 170.68,38.34 171.9,39.55 171.9,40.11 173.04,41.24 176.98,41.24 182.54,35.68 182.54,32.61 184.67,30.48 184.67,29.96 184.58,29.88
3D3V_S5 on BOTTOM: 96.33,121.92 95.97,122.28 95.97,122.87 96.77,123.67 99.09,123.67 100.66,125.25 100.66,130.66 97.87,133.45 95.09,133.45 94.79,133.75 94.79,134.75 95.11,135.07 98.85,135.07 102.07,131.84 102.07,123.82 100.17,121.92
3D3V_S5 on BOTTOM: 33.13,24.92 32.98,25.07 32.98,27.07 33.05,27.15 37.25,27.15 37.45,26.95 37.45,25.18 37.19,24.92
3D3V_S5 on BOTTOM: 148.09,52.56 147.71,52.94 147.71,53.65 146.71,54.65 146.71,56.58 146.74,56.62 146.74,58.78 146.69,58.83 146.69,61.24 147.2,61.75 148.29,61.75 148.29,57.13 149.18,56.24 150.05,56.24 150.05,55.48 150.15,55.48 150.26,55.36 150.25,55.35 151.9,53.7 151.9,52.66 151.8,52.56 ; 2 cut-outs
3D3V_S5 on BOTTOM: 181.88,67.98 181.56,68.3 181.56,72.07 182.13,72.65 187.27,72.65 187.98,71.93 187.98,71.64 187.8,71.46 184.66,71.46 182.8,69.6 182.8,69.1 182.93,68.96 184.32,68.96 184.32,68.03 184.26,67.98 ; 4 cut-outs
3D3V_S5 on L3: 46.49,63.15 48.93,63.15 49.23,62.84 49.23,61.64 48.83,61.23 46.68,61.23 46.26,61.65 46.26,62.92
3D3V_S5 on L3: 33.51,26.78 33,26.27 33,25.15 33.18,24.97 33.21,24.97 33.76,24.41 49.18,24.41 49.68,24.91 49.68,26.18 49.08,26.78
3D3V_S5 on L4: 136.25,86.93 138.48,84.7 138.48,82.73 139.98,81.23 139.98,79.71 139.94,79.66 139.55,79.66 139.43,79.79 139.43,80.75 139.43,80.85 136.58,83.7 136.58,84.66 136.35,84.88 133.2,84.88 132.95,84.62 132.95,84.35 132.82,84.23 132.49,84.23 132.06,84.66 132.06,86.84 132.16,86.93
3D3V_S5_PCH on TOP: 125.42,61.44 124.8,62.05 124.8,73.12 124.89,73.22 126.7,73.22 126.79,73.13 126.79,72.2 126.07,71.48 126.07,61.54 125.96,61.44
3D3V_S5_PCH on BOTTOM: 178.2,68.15 178.2,69.8 178.78,70.39 178.78,72.5 178.86,72.59 180.52,72.59 180.78,72.32 180.78,70.69 180.36,70.27 180.36,70.26 180.22,70.12 180.22,68.05 180.17,68 178.35,68
3D3V_S5_PCH on BOTTOM: 158.22,68.64 158.05,68.81 158.05,70.17 157.26,70.95 156.04,70.95 155.63,71.35 155.63,72.95 155.53,73.05 154.64,73.05 154.46,73.23 154.46,74.12 153.42,75.16 153.42,77.59 152.93,78.09 152.93,80.14 152.66,80.41 152.04,80.41 151.82,80.62 151.32,80.62 151.24,80.7 151.24,82.96 151.32,83.04 151.83,83.04 151.83,83.03 152.03,83.03 152.33,83.34 152.33,84.74 151.85,85.22 150.93,85.22 150.91,85.24 150.91,85.66 151.01,85.76 151.65,85.76 151.66,85.76 151.91,85.76 151.92,85.76 153.19,85.76 153.32,85.63 153.32,80.95 153.5,80.77 153.99,80.77 154.36,80.4 154.36,77.7 154.64,77.42 154.64,75.64 155.81,74.47 158.41,74.47 158.96,73.91 158.95,73.9 158.95,71.17 159.2,70.92 160.52,70.92 160.62,70.82 160.62,70.39 160.55,70.32 159.18,70.32 158.96,70.1 158.96,68.73 158.86,68.64 ; 1 cut-out
3D3V_S5_PCH on BOTTOM: 124.93,60.12 124.52,60.53 124.52,62.6 124.82,62.89 126.35,62.89 126.73,62.51 126.73,60.38 126.47,60.12
3D3V_VGA_OUT1 on TOP: 148.05,134.73 148.05,135.53 148.06,135.54 148.06,136.55 148.13,136.62 149.13,136.62 149.87,135.88 149.87,134.85 149.74,134.73
3D3V_VGA_S0 on TOP: 184.94,130.59 181.97,130.59 181.92,130.64 181.62,130.64 181.39,130.41 181.39,130.1 181.46,130.03 181.46,129.67 181.21,129.42 180.86,129.42 180.73,129.54 180.73,130.71 180.98,130.97 185.43,130.97 186.04,130.36 187.21,130.36 187.31,130.26 187.31,129.82 187.18,129.7 185.83,129.7
3D3V_VGA_S0 on TOP: 191.14,127.69 191.27,127.82 191.27,128.43 190.84,128.86 190.84,129.37 190.91,129.44 193.78,129.44 193.86,129.37 193.86,128.93 193,128.07 193,127.08 192.82,126.9 191.32,126.9 191.14,127.08
3D3V_VGA_S0 on TOP: 142.89,137.97 142.89,137.42 143.04,137.28 144.2,137.28 144.4,137.08 144.4,136.1 144.2,135.9 142.34,135.9 142.24,136 142.24,138.02 142.28,138.06 142.81,138.06
3D3V_VGA_S0 on TOP: 172.8,133.51 172.33,133.98 172.33,135.09 171.45,135.97 171.24,135.97 171.13,136.07 171.13,137.31 171.13,137.4 171.17,137.43 171.75,137.43 171.95,137.24 171.95,136.93 172.82,136.05 172.82,135.42 173.84,134.4 173.84,133.51 ; 3 cut-outs
3D3V_WLAN_S0 on TOP: 164.62,38.49 164.56,38.55 164.56,39.61 164.71,39.76 170.16,39.76 170.54,40.14 170.95,40.14 171.13,39.96 171.13,39.05 170.57,38.49 ; 4 cut-outs
3D3V_WLAN_S0 on BOTTOM: 170.2,39.41 169.73,39.88 169.73,45.37 169.81,45.45 171.76,45.45 176.64,50.32 178.42,50.32 179.1,51 179.1,54.16 172.02,61.25 172.02,61.75 171.68,62.08 169.81,62.08 169.79,62.1 169.79,62.89 169.78,62.91 169.78,63.14 169.96,63.33 170.31,63.68 170.31,65.97 170.38,66.04 170.82,66.04 170.91,65.95 170.91,64.36 171.49,63.79 172.11,63.79 172.76,63.14 172.76,63.13 174.84,61.05 176,61.05 180.96,56.09 180.96,50.58 179.03,48.65 179.03,47.48 171.27,39.72 171.27,39.55 171.13,39.41 ; 4 cut-outs
+0D675V_DDR_P on TOP: 54.51,17.75 54.36,17.9 54.36,22.78 55.2,23.63 57.22,23.63 58.4,22.45 58.4,22.44 58.53,22.31 58.53,21.8 58.43,21.7 57.55,21.7 57.53,21.71 57.53,21.9 57.72,22.09 57.72,22.43 57.48,22.67 57.07,22.67 56.41,22.02 56.41,21.35 56.65,21.11 57.49,21.11 57.51,21.09 58.35,21.09 58.38,21.06 58.38,20.91 58.35,20.88 57.49,20.88 57.46,20.86 57.13,20.86 56.5,20.22 56.5,17.94 56.31,17.75 ; 6 cut-outs
+1.05M_ASW on TOP: 131.93,80.34 131.55,80.71 130.72,80.71 130.52,80.51 128.2,80.51 128.06,80.65 122.29,80.65 122.09,80.85 120.42,80.85 120.22,81.05 120.22,83.43 120.26,83.47 121.06,83.47 121.54,82.99 122.25,82.99 123.34,81.89 127.54,81.89 127.54,81.97 128.05,82.48 131.15,82.48 132.52,81.1 133.03,81.1 133.06,81.07 133.06,80.44 132.96,80.34 ; 4 cut-outs
+1.05M_ASW on BOTTOM: 132.42,80.01 132.28,80.14 132.15,80.14 131.91,80.39 131.91,81.29 131.8,81.4 131.04,81.4 130.98,81.47 130.98,81.79 131.04,81.86 132.13,81.86 132.27,81.71 132.27,81.24 132.27,81.24 132.27,81.02 132.43,80.86 132.85,80.86 132.86,80.87 132.95,80.87 133.02,80.8 133.02,80.45 132.58,80.01
+1.05M_ASW on L3: 132,81.91 132.96,80.95 132.96,80.39 132.95,80.38 131.94,80.38 131.58,80.74 130.53,80.74 130.03,80.24 127.26,80.24 126.16,81.34 123.77,81.34 122.84,82.27 121.49,82.27 121.34,82.42 121.34,83.03 121.56,83.25 123.81,83.25 123.81,83.25 124.51,83.25 124.8,82.96 130.49,82.96 130.8,82.66 131.25,82.66
+DC_IN on TOP: 93.23,149.18 92.77,149.64 92.77,157.66 92.89,157.78 98.34,157.78 99.37,156.76 99.37,153.73 99.25,153.6 97.82,153.6 96.35,152.13 96.35,149.41 96.12,149.18 ; 4 cut-outs
+DC_IN on BOTTOM: 95.05,155.76 94.9,155.91 94.9,159.72 94.67,159.95 93.35,159.95 92.49,159.08 91.12,159.08 90.74,158.7 90.74,157.92 90.69,157.87 89.39,157.87 89.31,157.94 89.31,161.7 89.72,162.11 95.69,162.11 95.94,161.85 97.9,161.85 98.71,161.04 98.71,155.99 98.48,155.76
+DC_IN_C on TOP: 87.48,153.71 87.48,162.41 87.59,162.51 90.84,162.51 90.91,162.44 90.91,160.84 91.19,160.56 92.26,160.56 92.44,160.38 92.44,153.71 92.26,153.53 87.66,153.53 ; 2 cut-outs
+PWR_SRC_1D35V on TOP: 66,21.3 65.63,21.67 65.63,25.04 65.71,25.13 72.2,25.13 72.33,24.99 72.33,21.5 72.13,21.3 ; 2 cut-outs
+PWR_SRC_1D35V on BOTTOM: 63.86,21.11 63.74,21.24 63.74,24.29 64.12,24.67 68.92,24.67 69.21,24.37 69.21,21.22 69.11,21.11
AD+ on TOP: 105.52,161.22 105.37,161.37 105.37,163.02 105.42,163.07 106.79,163.07 107.04,162.82 107.04,161.42 106.84,161.22
AD+ on TOP: 99.83,147.96 99.6,148.19 99.6,156.62 100.68,157.7 103.42,157.7 103.69,157.43 104.4,157.43 104.52,157.32 104.52,155.77 104.12,155.38 104.12,153.19 103.99,153.06 103.79,153.06 103.39,152.66 103.39,148.14 103.21,147.96 ; 5 cut-outs
AD+ on BOTTOM: 114.38,156.44 114.18,156.65 114.18,158.09 114.31,158.22 115.73,158.22 115.83,158.12 115.83,156.57 115.7,156.44
AD+_TO_SYS on TOP: 103.64,147.88 103.56,147.96 103.56,150.3 103.64,150.37 104.88,150.37 105.01,150.5 105.01,150.98 104.48,151.52 104.48,152.66 104.63,152.81 107.8,152.81 108.08,152.53 108.08,148.62 107.35,147.88 ; 1 cut-out
AD_OFF_R on TOP: 96.63,149.13 96.5,149.25 96.5,152.1 97.87,153.47 99.27,153.47 99.32,153.43 99.32,149.4 99.04,149.13 ; 4 cut-outs
AUD_AGND on BOTTOM: 189.26,9.89 189.19,9.96 189.19,10.23 188.7,10.71 188.7,11.7 188.79,11.78 189.61,11.78 190.05,12.22 190.05,12.86 190.2,13.01 190.2,14.2 190.86,14.86 191.93,14.86 192.03,14.76 192.03,10.01 191.9,9.89 ; 9 cut-outs
AUD_AGND on L2VCC: 186.12,7.71 186.1,7.73 186.1,10.52 184.2,12.43 184.2,13.41 184.34,13.56 184.94,13.56 185.08,13.41 185.08,12.78 185.32,12.54 186.34,12.54 187.1,11.78 189.42,11.78 190.16,12.52 190.16,13.95 189.8,14.32 188.15,14.32 187.26,15.21 185.73,15.21 185.59,15.35 185.59,18.52 185.23,18.89 181.04,18.89 178.61,21.32 178.61,26.49 181.54,29.43 187.98,29.43 188.8,30.25 192.15,30.25 192.32,30.08 192.32,26.11 192.97,25.46 192.97,18.47 193.97,17.47 193.97,15.98 193.2,15.21 192.43,15.21 192.07,14.84 192.07,10.01 191.93,9.87 187.35,9.87 187.12,9.63 187.12,7.73 187.1,7.71
AUD_AGND on L5GND: 186.12,7.71 186.1,7.73 186.1,10.52 184.2,12.43 184.2,13.41 184.34,13.56 184.94,13.56 185.08,13.41 185.08,12.78 185.32,12.54 186.34,12.54 187.1,11.78 189.41,11.78 190.16,12.52 190.16,13.95 189.8,14.32 188.15,14.32 187.26,15.21 185.73,15.21 185.59,15.35 185.59,18.52 185.23,18.89 181.04,18.89 178.61,21.32 178.61,26.24 181.8,29.43 187.99,29.43 190.28,27.14 191.29,27.14 192.97,25.47 192.97,18.47 193.97,17.47 193.97,15.98 193.2,15.21 192.43,15.21 192.07,14.84 192.07,10.01 191.93,9.87 187.35,9.87 187.12,9.63 187.12,7.73 187.1,7.71
AUD_SPK_L+ on TOP: 88.86,6 88.73,6.13 88.73,6.99 88.83,7.09 93.73,7.09 94.19,6.63 94.19,6.14 94.05,6 ; 2 cut-outs
AUD_SPK_L+_C on TOP: 88.1,7.09 88.17,7.01 88.17,6.18 88.07,6.08 84.49,6.08 84.44,6.13 84.44,7.04 84.49,7.09
AUD_SPK_L+_C on BOTTOM: 69.04,6.15 68.81,6.38 67.44,6.38 67.39,6.43 67.39,7.01 67.41,7.04 69.27,7.04 69.37,6.94 71.12,6.94 72.8,8.62 73.43,8.62 73.66,8.39 73.66,7.85 71.96,6.15
AUD_SPK_L- on TOP: 88.93,4.55 88.91,4.58 88.91,5.72 89.06,5.87 91.75,5.87 91.83,5.8 91.83,4.98 91.65,4.81 90.08,4.81 89.82,4.55 ; 3 cut-outs
AUD_SPK_L-_C on TOP: 85.01,4.3 84.81,4.5 84.81,4.69 84.81,4.69 84.81,5.44 84.94,5.57 88.22,5.57 88.3,5.49 88.3,4.65 88.2,4.55 87.43,4.55 87.17,4.3
AUD_SPK_L-_C on BOTTOM: 67.44,5.21 67.36,5.29 67.36,6 67.39,6.02 71.96,6.02 74.57,8.64 74.95,8.64 75.23,8.36 75.23,7.88 72.57,5.21
AUD_SPK_R+ on TOP: 88.88,10.06 88.73,10.22 88.73,11.1 88.81,11.18 90.87,11.18 91.23,11.54 92.51,11.54 92.59,11.46 92.59,10.28 92.49,10.18 89.83,10.18 89.71,10.06 ; 2 cut-outs
AUD_SPK_R+_C on TOP: 84.82,10.14 84.68,10.28 84.68,11.03 84.81,11.16 88.1,11.16 88.17,11.08 88.17,10.24 88.07,10.14
AUD_SPK_R+_C on BOTTOM: 70,7.85 69.44,8.41 67.46,8.41 67.41,8.46 67.41,9.3 67.46,9.35 70.38,9.35 70.56,9.17 70.56,8.08 70.33,7.85
AUD_SPK_R- on TOP: 88.78,8.23 88.76,8.26 88.76,9.63 88.98,9.86 91.58,9.86 91.65,9.79 91.65,8.98 91.16,8.49 89.82,8.49 89.57,8.23 ; 3 cut-outs
AUD_SPK_R-_C on TOP: 84.82,8.23 84.68,8.37 84.68,9.12 84.81,9.25 88.1,9.25 88.17,9.17 88.17,8.34 88.07,8.23
AUD_SPK_R-_C on BOTTOM: 69.4,7.08 69.09,7.4 67.44,7.4 67.39,7.45 67.39,7.95 67.51,8.08 69.42,8.08 69.77,7.73 70.38,7.73 71.3,8.64 71.75,8.64 72.08,8.31 72.08,8.16 71,7.08
BT+ on TOP: 139.83,157.52 139.83,157.53 139.45,157.92 133.87,157.92 133.04,158.74 133.04,173.2 137.16,177.32 151.01,177.32 152.57,175.76 152.57,173.38 152.48,173.29 148.05,173.29 146.27,171.52 142.13,171.52 138.22,167.61 138.22,164.3 140.04,162.49 140.84,162.49 142.83,160.5 142.83,157.85 142.49,157.52 ; 5 cut-outs
BT+ on TOP: 163.49,177.1 163.15,177.43 163.15,180.24 163.41,180.5 167.45,180.5 167.56,180.4 167.56,177.38 167.27,177.1
BT+ on BOTTOM: 137.49,157.53 137.31,157.71 137.31,161.57 137.47,161.73 138.36,161.73 138.86,162.22 141.18,162.22 141.66,161.74 141.66,157.92 141.26,157.53
BT+ on BOTTOM: 136.54,167.88 134.52,169.91 134.52,173.88 138.91,178.27 149.62,178.27 150.17,178.82 162.46,178.82 162.87,179.23 162.87,181.01 163.06,181.21 167.21,181.21 168,180.42 168,175.13 167.7,174.83 151.91,174.83 149.57,172.49 147.45,172.49 144.66,169.71 140.81,169.71 138.99,167.88 ; 7 cut-outs
BT+ on L3: 136.37,161.33 135.8,161.89 135.8,176.24 136.35,176.79 141.29,176.79 145.79,172.29 145.79,162.7 143.62,160.53 137.17,160.53 137.17,160.55 136.39,161.33
BT+ on L4: 135.8,166.84 135.8,173.98 136.22,174.39 142.12,174.39 144.58,171.92 144.58,161.7 143.29,160.41 140.27,160.41 139.25,161.42 139.25,163.39
BT+ on L4: 167.76,180.73 167.76,177.61 167.32,177.17 153.88,177.17 153.88,177.16 152.25,175.54 145.59,175.54 145.25,175.88 145.25,177.52 145.6,177.87 149.78,177.87 150.56,178.64 162.46,178.64 162.95,179.13 162.95,180.97 163.12,181.15 167.34,181.15
BT+ on L5GND: 146.87,174.46 145.46,175.88 145.46,177.24 145.86,177.64 149.92,177.64 150.56,178.27 162.62,178.27 163.24,178.89 163.24,180.8 163.38,180.94 167.54,180.94 167.69,180.8 167.69,177.4 165.86,175.57 154.68,175.57 153.57,174.46
BT+_R on BOTTOM: 132.24,157.59 131.96,157.87 131.96,163.94 132.19,164.16 134.91,164.16 135.34,163.73 135.34,162.4 135.36,162.39 135.36,162.26 135.86,161.75 136.86,161.75 136.99,161.62 136.99,157.64 136.94,157.59
CBP on BOTTOM: 187.13,12.24 186.76,12.6 185.48,12.6 185.31,12.78 185.31,13.74 185.32,13.75 185.53,13.75 185.54,13.73 185.54,13.37 185.78,13.13 187.05,13.13 187.35,12.83 187.92,12.83 187.99,12.77 187.99,12.29 187.93,12.24
CHARGER_SRC on TOP: 116.24,156.85 116.01,157.08 116.01,159.19 116.06,159.24 119.87,159.24 120.07,159.44 121.25,159.44 121.44,159.26 121.44,157.05 121.24,156.85 ; 2 cut-outs
CHARGER_SRC on BOTTOM: 118.04,155.86 116.62,157.28 116.62,159.19 116.67,159.24 118.52,159.24 118.75,159.47 123.91,159.47 124.09,159.29 124.09,155.96 123.98,155.86 ; 4 cut-outs
CHG_AGND on TOP: 108.06,156.85 107.98,156.93 107.98,164.72 108.29,165.03 109.59,165.03 109.76,164.85 109.76,163.11 109.76,163.05 109.93,162.89 110.71,162.89 110.88,162.72 110.88,160.41 110.7,160.23 108.95,160.23 108.82,160.1 108.82,157.03 108.64,156.85 ; 8 cut-outs
CHG_AGND on L3: 111.55,157.86 112.03,158.35 112.03,158.66 112.28,158.91 112.79,158.91 113.01,158.69 113.01,158.4 113.01,158.39 113.01,158.01 111.79,156.79 104.41,156.79 103.94,156.32 102.18,156.32 101.77,156.72 101.77,157.62 102.34,158.2 102.34,162.64 103,163.3 105.09,163.3 106.17,162.22 110.56,162.22 110.84,161.94 110.84,161.23 110.75,161.14 104.15,161.14 103.41,160.4 103.41,157.87 103.74,157.53 104.12,157.53 104.44,157.86
DC_IN_D on TOP: 102.91,161.22 102.55,161.58 102.55,162.34 102.65,162.44 102.66,162.45 103.39,162.45 103.61,162.67 103.61,163.23 103.59,163.25 103.59,164.01 103.74,164.16 105.04,164.16 105.21,163.99 105.21,161.37 105.06,161.22
DCBATOUT on TOP: outline of 143 points within 49.33,25.48 162.77,157.57 ; 24 cut-outs
DCBATOUT on TOP: 30.26,50.65 30.18,50.73 30.18,52.23 30.41,52.46 33.15,52.46 33.26,52.35 33.26,50.7 33.21,50.65
DCBATOUT on BOTTOM: 30.54,51.11 30.31,51.34 30.31,52.61 31.88,54.18 31.88,57.8 37.88,63.8 39.18,63.8 40.47,65.1 47.22,65.1 47.23,65.1 50.35,65.1 50.59,64.86 50.59,63.39 50.29,63.09 48.79,63.09 48.5,63.38 40.67,63.38 39.85,62.56 38.38,62.56 33.28,57.46 33.28,51.36 33.03,51.11 ; 2 cut-outs
DCBATOUT on BOTTOM: 102.92,129.94 102.21,130.65 102.21,133.46 102.19,133.46 102.19,136.49 104.27,138.57 104.27,147.57 103.51,148.34 96.6,148.34 95.99,148.95 95.99,155.35 96.06,155.41 101.59,155.41 102.55,154.46 104.02,154.46 105.65,152.84 110.27,152.84 110.7,153.27 114.13,153.27 116.49,155.63 137.37,155.63 137.7,155.3 137.7,152.05 134.07,148.42 130.79,148.42 128.74,146.36 113.18,146.36 109.5,142.68 109.5,136.75 111.71,134.54 112.25,134.54 112.25,129.95 105.35,129.95 105.34,129.94 ; 14 cut-outs
DCBATOUT_LCD on TOP: 78.05,176.19 78.05,176.2 78.05,176.47 78.98,176.47 78.98,176.67 78.05,176.67 78.05,177.41 78.32,177.69 79.98,177.69 80.09,177.58 80.09,176.41 79.88,176.19
DCBATOUT_LCD on BOTTOM: 91.85,149.41 91.78,149.47 91.78,152.99 92.29,153.5 93.91,153.5 94.23,153.81 94.23,155.01 94.65,155.43 95.68,155.43 95.77,155.35 95.77,150.04 95.13,149.41 92.06,149.41 92.05,149.41 ; 4 cut-outs
DDR_VREF_S3 on TOP: 57.77,13.49 57.39,13.87 57.39,15.65 57.51,15.78 58.4,15.78 58.53,15.65 58.53,14.76 59.16,14.13 59.16,13.87 58.78,13.49
DDR_VREF_S3 on TOP: 58.56,49.05 58.35,49.26 58.35,50.66 58.66,50.97 58.66,51.54 58.74,51.62 59.2,51.62 59.29,51.53 59.29,50.22 59.9,49.61 59.9,49.28 59.67,49.05 ; 1 cut-out
DDR_VREF_S3 on TOP: 63.61,49.43 63.48,49.56 63.48,49.94 64.37,50.83 64.75,50.83 64.88,50.7 64.88,49.81 64.5,49.43 ; 1 cut-out
FAN_VCC1 on BOTTOM: 92.48,135.19 92.14,135.53 92.14,135.58 91.29,137.06 91.37,137.32 91.85,137.55 92.03,137.52 92.39,136.81 92.68,136.16 96.77,136.16 98.64,138.03 98.64,143.31 98.66,143.34 98.66,145.32 98.15,145.83 96.86,145.83 96.73,145.95 96.73,146.54 96.86,146.66 99.22,146.66 99.91,145.98 99.91,137.39 97.71,135.19 ; 7 cut-outs
FBA_PLL_AVDD on TOP: 161.73,144.05 161.65,144.12 161.65,145.06 161.74,145.15 164.01,145.15 164.01,145.15 164.09,145.15 165.21,146.27 165.21,146.6 165.35,146.74 166.13,146.74 166.25,146.62 166.25,145.65 166.25,144.45 165.86,144.07 165.37,144.07 165.36,144.06 164.7,144.06 164.46,144.3 163.36,144.3 163.13,144.06 161.91,144.06 161.9,144.05
GPU_PLL_VDD on TOP: 169.7,129.9 169.44,130.17 169.44,132.43 169.16,132.71 168.95,132.71 168.83,132.83 168.83,133.3 168.91,133.38 169.24,133.38 169.38,133.52 169.99,133.52 170.16,133.35 170.16,131.89 170.67,131.38 170.67,129.98 170.59,129.9 ; 1 cut-out
HDMI_PLL_GND on TOP: 24.45,71.48 24.37,71.56 24.37,78.29 24.84,78.76 28.4,78.76 28.82,78.34 28.82,77.32 28.54,77.04 27.69,77.04 26.68,78.06 25.89,78.06 25.71,77.88 25.71,71.91 25.28,71.48 ; 2 cut-outs
HSIO_OUT on BOTTOM: 143.75,111.43 143.52,111.66 143.52,113.39 143.98,113.85 146.9,113.85 147.15,113.59 147.15,111.79 146.79,111.43
JGND on TOP: 92.77,157.92 92.67,158.02 92.67,160.2 93.05,160.58 95.16,160.58 95.49,160.91 95.49,162.41 95.92,162.84 99.73,162.84 100.34,162.23 100.34,158.25 100.01,157.92 ; 1 cut-out
LCDVDD on BOTTOM: 81.39,155.6 81.26,155.73 81.26,156.34 81.06,156.54 79.84,156.54 79.41,156.98 79.41,158.96 79.59,159.14 81.11,159.14 81.59,158.65 82.15,158.65 82.4,158.4 82.4,157.92 82.79,157.54 82.79,156.69 83.04,156.44 83.04,156.06 83.04,156.06 83.04,155.73 82.91,155.6
LCDVDD_LCD on TOP: 78.05,173.7 78.05,173.96 78.06,173.97 78.89,173.97 78.92,174 78.92,174.14 78.9,174.17 78.06,174.17 78.05,174.17 78.05,174.48 79.01,174.48 79.01,174.68 78.05,174.68 78.05,174.98 79.01,174.98 79.01,175.18 78.05,175.18 78.05,175.44 78.07,175.46 78.81,175.46 78.82,175.46 78.97,175.46 79.44,175.93 82.25,175.93 82.43,175.75 82.43,174.99 82.18,174.73 80.92,174.73 79.89,173.7
LCDVDD_LCD on BOTTOM: 79.1,159.87 78.72,160.25 78.72,162.34 78.21,162.84 78.21,173.49 80.12,175.39 81.09,176.36 82.26,177.53 83.46,177.53 83.51,177.47 83.51,175.22 82.98,174.69 82.97,174.68 82.97,161.69 81.16,159.87 ; 2 cut-outs
LOM_TCT on TOP: 27.91,166.58 27.42,167.07 27.42,171.03 27.85,171.46 29.78,171.46 30.28,170.96 30.28,169.52 30.51,169.3 31.33,169.3 31.48,169.14 31.48,167.91 30.16,166.59 30.16,166.58 ; 2 cut-outs
LOM_TCT on BOTTOM: 27.78,166.71 27.42,167.07 27.42,171 27.57,171.15 29.65,171.15 29.65,166.71
M_A_B_DIMM_ODT on TOP: 91.37,15.12 91.29,15.2 91.29,17.58 90.99,17.89 89.95,17.89 89.8,18.04 89.8,18.9 89.97,19.08 91.78,19.08 92.12,18.74 92.12,15.28 91.96,15.12 ; 4 cut-outs
M_VREF_CA_DIMMA on TOP: 61.96,48.04 61.64,48.35 61.64,48.99 61.96,49.31 64.75,49.31 65.13,49.69 65.13,52.48 65.26,52.61 66.4,52.61 66.66,52.35 66.66,48.92 65.77,48.04 ; 9 cut-outs
M_VREF_CA_DIMMA on TOP: 89.23,23.96 89.08,24.11 89.08,24.69 89.25,24.87 93.02,24.87 93.2,24.68 93.2,24.05 93.11,23.96 ; 4 cut-outs
M_VREF_CA_DIMMA on L4: 99.82,32.4 100.36,32.4 100.58,32.18 100.58,31.66 98.61,29.69 97.73,29.69 97.46,29.96 97.46,30.17 98.89,31.6 99.4,31.6 99.62,31.82 99.62,32.19
M_VREF_CA_DIMMB on TOP: 61.39,41.73 61.21,41.9 61.21,42.59 66.77,48.15 66.77,50.75 67.01,50.99 67.85,50.99 68.04,50.81 68.04,47.75 62.01,41.73 ; 1 cut-out
M_VREF_CA_DIMMB on TOP: 136.1,14.4 135.92,14.58 135.92,15.69 136.04,15.81 136.04,15.85 138.05,15.85 138.16,15.74 138.16,14.66 137.9,14.4 ; 2 cut-outs
M_VREF_DQ_DIMMA on TOP: 58.99,36.17 58.22,36.94 58.22,44.42 59.54,45.75 59.54,48.7 60.05,49.2 60.05,49.74 59.51,50.28 59.51,51.64 59.6,51.72 61.58,51.72 61.83,51.46 61.83,49.69 61.45,49.31 61.45,44.23 60.8,43.58 60.8,36.31 60.66,36.17 ; 13 cut-outs
M_VREF_DQ_DIMMA on BOTTOM: 60.15,36.2 59.88,36.48 59.88,38.96 59.95,39.04 60.67,39.04 60.75,38.96 60.75,37.05 60.84,36.96 60.84,36.45 60.59,36.2
M_VREF_DQ_DIMMB on TOP: 90.95,19.64 90.71,19.88 90.71,22.18 90.75,22.21 92.01,22.21 92.22,22.01 92.22,19.97 91.88,19.64 ; 3 cut-outs
M_VREF_DQ_DIMMB on BOTTOM: 91.58,21 91.39,21.2 91.39,22.23 95.01,25.84 95.22,25.84 95.35,25.71 95.35,24.06 94.91,23.62 94.57,23.62 91.95,21
MCT on BOTTOM: 23.23,176.05 23.12,176.15 23.12,177.56 23.06,177.62 20.14,177.62 20.1,177.66 20.1,178.65 20.16,178.72 24.75,178.72 24.93,178.54 24.93,176.31 24.67,176.05
ODD_PWR_5V on TOP: 155.24,78.25 154.74,78.74 154.74,80.57 154.41,80.9 153.12,80.9 152.98,81.04 152.98,81.72 154.36,81.72 154.36,81.92 152.98,81.92 152.98,83.68 153.06,83.75 156.87,83.75 157.32,83.29 157.32,78.4 157.17,78.25 ; 4 cut-outs
ODD_PWR_5V on BOTTOM: 155.19,75.44 154.84,75.79 154.84,77.43 154.51,77.75 154.51,80.24 155.9,81.63 158.58,81.63 158.73,81.48 158.73,75.75 158.42,75.44
PBAT_PRES1# on TOP: 157.62,176.4 157.45,176.57 157.45,180.12 157.58,180.25 158.52,180.25 158.66,180.11 158.66,176.56 158.49,176.4
PBAT_SMBCLK1 on TOP: 159.74,176.32 159.63,176.44 159.63,176.66 161.44,178.47 161.44,180.14 161.55,180.25 162.53,180.25 162.65,180.13 162.65,178.64 160.33,176.32
PBAT_SMBDAT1 on TOP: 159.01,176.17 158.87,176.31 158.87,177.81 159.45,178.39 159.45,180.1 159.58,180.23 160.49,180.23 160.66,180.07 160.66,177.99 159.31,176.64 159.31,176.27 159.2,176.17
PS_ID_R2 on TOP: 116.42,168.13 116.29,168.25 116.29,171.71 117.58,173 117.58,174.45 118.73,175.59 118.73,177.14 118.92,177.34 120.17,177.34 120.3,177.2 120.3,173.67 118.85,172.22 118.85,171.61 117.81,170.57 117.81,168.33 117.61,168.13 ; 4 cut-outs
PWR_1D05V_LGATE on TOP: 127.67,134.52 127.54,134.65 127.54,136.55 127.67,136.68 128.31,136.68 128.43,136.55 128.43,134.52
PWR_1D05V_PHASE on TOP: 127.42,129.08 127.29,129.21 127.29,134.01 127.54,134.27 131.35,134.27 131.48,134.14 131.48,132.61 131.61,132.49 134.02,132.49 134.15,132.36 134.15,129.47 133.77,129.08
PWR_1D05V_PHASE on BOTTOM: 126.78,129.06 126.4,129.44 126.4,132.61 126.66,132.87 129.45,132.87 130.26,133.68 133.89,133.68 134,133.58 134,133.15 134.02,133.12 134.02,129.31 133.77,129.06
PWR_1D05V_SNUB on BOTTOM: 126.16,133.38 125.91,133.63 125.91,135.59 125.98,135.66 127.98,135.66 128.05,135.59 128.05,133.5 127.93,133.38 ; 1 cut-out
PWR_1D05V_UGATE on TOP: 134.53,130.46 134.4,130.58 134.4,132.36 134.53,132.49 135.04,132.49 135.16,132.36 135.16,130.58 135.04,130.46
PWR_1D35V_DRVH on TOP: 72.66,23.85 72.61,23.9 72.61,24.51 72.67,24.56 74.88,24.56 75,24.44 75,23.98 74.87,23.85
PWR_1D35V_DRVL on TOP: 68.56,17.05 68.43,17.17 68.43,17.68 68.56,17.81 70.47,17.81 70.59,17.68 70.59,17.17 70.47,17.05
PWR_1D35V_SW on TOP: 72.37,14.63 72.27,14.74 72.27,16.13 71.61,16.79 70.97,16.79 70.97,20.86 71.1,20.98 72.5,20.98 72.63,21.11 72.63,23.52 72.75,23.65 75.67,23.65 75.99,23.34 75.99,17.24 73.39,14.63
PWR_1D35V_SW on BOTTOM: 69.96,17.94 69.51,18.38 69.51,23.25 69.91,23.65 75.67,23.65 76,23.32 76,18.1 75.85,17.94
PWR_1D35V_VTTREF on TOP: 56.58,16.29 56.52,16.35 56.52,17.28 56.75,17.51 57.31,17.51 57.53,17.73 57.53,20.29 57.54,20.3 58.4,20.3 58.46,20.24 58.46,19.05 58.27,18.86 58.27,17.7 58.66,17.31 58.66,16.44 58.51,16.29 ; 1 cut-out
PWR_3D3V_DRVH2 on TOP: 33.41,41.17 33.28,41.3 33.28,43.08 33.41,43.2 33.92,43.2 34.04,43.08 34.04,41.3 33.92,41.17
PWR_3D3V_DRVL2 on TOP: 35.69,45.23 35.57,45.36 35.57,47.14 35.69,47.27 36.2,47.27 36.33,47.14 36.33,45.36 36.2,45.23
PWR_3D3V_LL2 on TOP: 31.3,40 31.12,40.18 31.12,43.08 31.25,43.2 33.03,43.2 33.03,41.04 33.15,40.92 34.3,40.92 34.68,41.3 34.68,44.85 34.81,44.98 39.12,44.98 39.25,44.85 39.25,41.46 39.32,41.4 41.01,41.4 41.21,41.19 41.21,40.22 40.99,40 35.38,40 34.91,39.53 32.59,39.53 32.11,40
PWR_3D3V_LL2 on BOTTOM: 31.3,40 31.12,40.18 31.12,44.6 31.5,44.98 39.12,44.98 39.25,44.85 39.25,40.76 38.49,40
PWR_5V_DRVH1 on TOP: 50.78,41.18 50.65,41.3 50.65,43.08 50.78,43.21 51.42,43.21 51.54,43.08 51.54,41.43 51.29,41.18
PWR_5V_DRVL1 on TOP: 43.31,45.23 43.19,45.36 43.19,46.25 43.31,46.38 44.58,46.38 44.58,45.36 44.46,45.23
